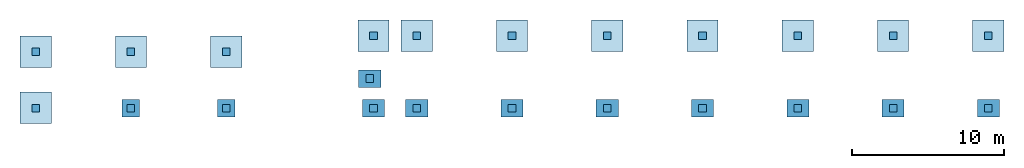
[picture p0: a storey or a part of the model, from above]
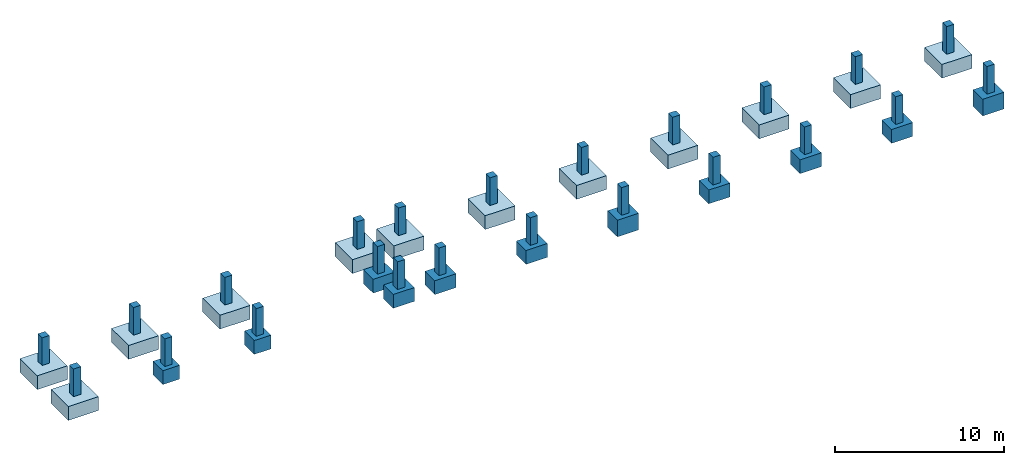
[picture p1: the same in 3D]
Properties of the parts of a building model (IFC2X3), part 1 of 25

# File
Description: ViewDefinition [CoordinationView_V2.0]
File name: SBW-VZ-II_STB_LP5_TWP.ifc
Time: 2026-07-09T14:06:45
Author: Karin Wasmer (STB)
Organization: STB Ingenieure
Written by: ODA SDAI 25.4
Authorization: wam

# IfcProject, 25693 25 - Vivantes Speiseverteilzentrum VZ II LP3
AllplanAttributes - Land: Deutschland; Leistungs-/Planungsphase: Entwurfsplanung; Bauherr: Vivantes Netzwerk für Gesundheit GmbH; Projektleiter: Hubig; Architekt: HPP Generalplanung GmbH; Statik: STB Ingenieure & Architekt PartGmbB; Projektvorlage: 0_STB Vorlage-Projekt Allplan 2022_Rev.09; Bauvorhaben: Speisenverteilzentrum VZ II; Bearbeiter: BIM Autor; Bauherr Anschrift: Aroser Allee 72-76, 13407 Berlin; Bauherr Straße: Aroser Allee 72-76; Bauherr Plz/Ort: 13407 Berlin; Architekt Anschrift: Neue Grünstraße 18, 10179 Berlin; Architekt Straße: Neue Grünstraße 18; Architekt Plz/Ort: 10179 Berlin; Bauvorhaben Straße: Seidelbastweg 145; Bauvorhaben Plz/Ort: 12357 Berlin; Projektnummer: 25693 25; Statiker Adresse: Karl-Liebknecht-Straße 11, 14482 Potsdam; Statiker Plz/Ort: 14482 Potsdam; Projektbeschreibung: Speiseverteilzentrum VZ II; Bauvorhaben Adresse: Seidelbastweg 145, 12357 Berlin; Homepage Statiker: www.stb-ingenieure.de

# IfcSite, TWP_Speiseverteilzentrum SBW VZ II
RefLatitude: 48, 8, 12, 480000; RefLongitude: 11, 34, 29, 161199
AllplanAttributes - Disziplin: Tragwerksplanung

# IfcBuildingStorey (5)
In: Speiseverteilzentrum SBW VZ II
Name | Elevation (m)
Geschossübergreifendes | -1.884
Grundleitungsebene | -1.884
EG_Technik_FFB | 0.6957
EG_Produktion_FFB | 1.7307
Wartung_FFB | 7.1307

# IfcBeam (2372)
Material: S235
AllplanAttributes - Gewerk: Stahlbauarbeiten; Material: S235; Attributset-Objekt: Beam
IFC_Pset_TWP - Material: Stahl; Kommentar: -; Phase erstellt: Neubau; statisch tragend: true
Pset_FM-Vivantes - FM_Klasse: -; FM_Bezeichnung: -; FM_AKS: -; FM_Anzahl: -; FM_Standort: -; FM_Hersteller: -; FM_Hersteller-Typ: -; FM_Seriennummer: -; FM_Baujahr: -; FM_Inbetriebnahme Datum: -; FM_Gewährleistungsende: -; FM_Gewährleistungsgeber: -; FM_Betriebsstatus: -; FM_Prüfpflicht: -; FM_Prüfintervall: -; FM_letzter Prüfungstermin: -; FM_Sammelobjekt: -; FM_rechn. Lebensdauer: -; FM_rechn. Lebensende: -; FM_technischer Zustand: -; FM_voraus. Lebensende: -; FM_Eigentümer: -; FM_Bemerkung: -; FM_Versorgungsbereich-Wirkbereich: -; FM_Zugänglichkeit: -
Name | In | Faktor | Bezeichnung = Name | Profilname | Mantelfläche/lfm | Ebene | Achsenstartpunkt (X) (m) | Achsenstartpunkt (Y) (m) | Achsenstartpunkt (Z) (m) | Achsenendpunkt (X) (m) | Achsenendpunkt (Y) (m) | Achsenendpunkt (Z) (m) | Objektdrehwinkel | Schwerpunkt X (m) | Schwerpunkt Y (m) | Allright_Bauteil_ID | Abrechnungsart | Positionsnummer | Außenbauteil | Reference | Drehwinkel = Slope (deg)
Rahmenriegel | EG_Technik_FFB | 1 | Rahmenriegel | HEA 300 | 1.763 | EG_Technik_FFB | 69.519 | 87.475 | 6.886 | 110.145 | 87.475 | 6.886 | 0 | 0.14 | 0.14 | 0103Tra0000000282 | m | AR01 | true | HA_UZV_HEA_300_STA_0,300_xxx
Rahmenriegel | EG_Technik_FFB | 1 | Rahmenriegel | HEA 300 | 1.763 | EG_Technik_FFB | 69.519 | 92.25 | 6.886 | 110.145 | 92.25 | 6.886 | 0 | 0.14 | 0.14 | 0103Tra0000001003 | m | AR01 | true | HA_UZV_HEA_300_STA_0,300_xxx
Zwischenriegel | EG_Technik_FFB | 1 | Zwischenriegel | HEA 100 | 0.582 | EG_Technik_FFB | 110 | 87.479 | 4.046 | 110 | 92.246 | 4.046 | 0 | 0.14 | 0.14 | 0103Tra0000001024 | m | AQV01.1 | true | HA_UZV_HEA_100_STA_0,100_xxx
Zwischenriegel | EG_Technik_FFB | 1 | Zwischenriegel | HEA 100 | 0.582 | EG_Technik_FFB | 103.75 | 87.479 | 4.046 | 103.75 | 92.246 | 4.046 | 0 | 0.14 | 0.14 | 0103Tra0000004011 | m | AQV01.1 | true | HA_UZV_HEA_100_STA_0,100_xxx
Zwischenriegel | EG_Technik_FFB | 1 | Zwischenriegel | HEA 100 | 0.582 | EG_Technik_FFB | 97.497 | 87.479 | 4.046 | 97.497 | 92.246 | 4.046 | 0 | 0.14 | 0.14 | 0103Tra0000004067 | m | AQV01.1 | true | HA_UZV_HEA_100_STA_0,100_xxx
Zwischenriegel | EG_Technik_FFB | 1 | Zwischenriegel | HEA 100 | 0.582 | EG_Technik_FFB | 91.247 | 87.479 | 4.046 | 91.247 | 92.246 | 4.046 | 0 | 0.14 | 0.14 | 0103Tra0000004109 | m | AQV01.1 | true | HA_UZV_HEA_100_STA_0,100_xxx
Zwischenriegel | EG_Technik_FFB | 1 | Zwischenriegel | HEA 100 | 0.582 | EG_Technik_FFB | 85.003 | 87.479 | 4.046 | 85.003 | 92.246 | 4.046 | 0 | 0.14 | 0.14 | 0103Tra0000004151 | m | AQV01.1 | true | HA_UZV_HEA_100_STA_0,100_xxx
Zwischenriegel | EG_Technik_FFB | 1 | Zwischenriegel | HEA 100 | 0.582 | EG_Technik_FFB | 78.75 | 87.479 | 4.046 | 78.75 | 92.246 | 4.046 | 0 | 0.14 | 0.14 | 0103Tra0000004193 | m | AQV01.1 | true | HA_UZV_HEA_100_STA_0,100_xxx
Zwischenriegel | EG_Technik_FFB | 1 | Zwischenriegel | HEA 100 | 0.582 | EG_Technik_FFB | 72.5 | 87.479 | 4.046 | 72.5 | 92.246 | 4.046 | 0 | 0.14 | 0.14 | 0103Tra0000004235 | m | AQV01.1 | true | HA_UZV_HEA_100_STA_0,100_xxx
Zwischenriegel | EG_Technik_FFB | 1 | Zwischenriegel | HEA 100 | 0.582 | EG_Technik_FFB | 69.664 | 87.479 | 4.046 | 69.664 | 92.246 | 4.046 | 0 | 0.14 | 0.14 | 0103Tra0000004277 | m | AQV01.2 | true | HA_UZV_HEA_100_STA_0,100_xxx
Rahmenriegel | EG_Technik_FFB | 1 | Rahmenriegel | HEA 200 | 1.167 | EG_Technik_FFB | 69.644 | 86.335 | 11.256 | 69.644 | 89.53 | 11.256 | 0 | 0.09 | 0.086 | 0103Tra0000002672 | m | AQV01.3 | true | HA_UZV_HEA_200_STA_0,200_xxx
Kragarm | EG_Technik_FFB | 1 | Kragarm | HEA 200 | 1.167 | EG_Technik_FFB | 72.5 | 86.725 | 6.936 | 72.5 | 87.295 | 6.936 | 0 | 0.09 | 0.086 | 0103Tra0000002187 | m | AT01.2 | true | HA_UZV_HEA_200_STA_0,200_xxx
Kragarm | EG_Technik_FFB | 1 | Kragarm | HEA 200 | 1.167 | EG_Technik_FFB | 78.75 | 86.725 | 6.936 | 78.75 | 87.295 | 6.936 | 0 | 0.09 | 0.086 | 0103Tra0000002197 | m | AT01.2 | true | HA_UZV_HEA_200_STA_0,200_xxx
Kragarm | EG_Technik_FFB | 1 | Kragarm | HEA 200 | 1.167 | EG_Technik_FFB | 85 | 86.725 | 6.936 | 85 | 87.295 | 6.936 | 0 | 0.09 | 0.086 | 0103Tra0000002202 | m | AT01.2 | true | HA_UZV_HEA_200_STA_0,200_xxx
Kragarm | EG_Technik_FFB | 1 | Kragarm | HEA 200 | 1.167 | EG_Technik_FFB | 91.25 | 86.725 | 6.936 | 91.25 | 87.295 | 6.936 | 0 | 0.09 | 0.086 | 0103Tra0000002207 | m | AT01.2 | true | HA_UZV_HEA_200_STA_0,200_xxx
Kragarm | EG_Technik_FFB | 1 | Kragarm | HEA 200 | 1.167 | EG_Technik_FFB | 97.5 | 86.725 | 6.936 | 97.5 | 87.295 | 6.936 | 0 | 0.09 | 0.086 | 0103Tra0000002212 | m | AT01.2 | true | HA_UZV_HEA_200_STA_0,200_xxx
Kragarm | EG_Technik_FFB | 1 | Kragarm | HEA 200 | 1.167 | EG_Technik_FFB | 103.75 | 86.725 | 6.936 | 103.75 | 87.295 | 6.936 | 0 | 0.09 | 0.086 | 0103Tra0000002217 | m | AT01.2 | true | HA_UZV_HEA_200_STA_0,200_xxx
Kragarm | EG_Technik_FFB | 1 | Kragarm | HEA 200 | 1.167 | EG_Technik_FFB | 110 | 86.725 | 6.936 | 110 | 87.295 | 6.936 | 0 | 0.09 | 0.086 | 0103Tra0000002222 | m | AT01.2 | true | HA_UZV_HEA_200_STA_0,200_xxx
Kragarm | EG_Technik_FFB | 1 | Kragarm | HEA 200 | 1.167 | EG_Technik_FFB | 69.664 | 86.725 | 6.936 | 69.664 | 87.295 | 6.936 | 0 | 0.09 | 0.086 | 0103Tra0000002227 | m | AT01.2 | true | HA_UZV_HEA_200_STA_0,200_xxx
Nebenträger | EG_Technik_FFB | 1 | Nebenträger | U 180 | 0.614476 | EG_Technik_FFB | 72.37 | 86.745 | 6.941 | 69.794 | 86.745 | 6.941 | 0 | 0.09 | 0.086 | 0103Tra0000002303 | m | AT01.1 | true | HA_UZV_U_180_STA_0,180_xxx
Nebenträger | EG_Technik_FFB | 1 | Nebenträger | U 180 | 0.614476 | EG_Technik_FFB | 78.62 | 86.745 | 6.941 | 72.63 | 86.745 | 6.941 | 0 | 0.09 | 0.086 | 0103Tra0000002313 | m | AT01.1 | true | HA_UZV_U_180_STA_0,180_xxx
Nebenträger | EG_Technik_FFB | 1 | Nebenträger | U 180 | 0.614476 | EG_Technik_FFB | 84.87 | 86.745 | 6.941 | 78.88 | 86.745 | 6.941 | 0 | 0.09 | 0.086 | 0103Tra0000002317 | m | AT01.1 | true | HA_UZV_U_180_STA_0,180_xxx
Nebenträger | EG_Technik_FFB | 1 | Nebenträger | U 180 | 0.614476 | EG_Technik_FFB | 91.12 | 86.745 | 6.941 | 85.13 | 86.745 | 6.941 | 0 | 0.09 | 0.086 | 0103Tra0000002320 | m | AT01.1 | true | HA_UZV_U_180_STA_0,180_xxx
Nebenträger | EG_Technik_FFB | 1 | Nebenträger | U 180 | 0.614476 | EG_Technik_FFB | 97.37 | 86.745 | 6.941 | 91.38 | 86.745 | 6.941 | 0 | 0.09 | 0.086 | 0103Tra0000002323 | m | AT01.1 | true | HA_UZV_U_180_STA_0,180_xxx
Nebenträger | EG_Technik_FFB | 1 | Nebenträger | U 180 | 0.614476 | EG_Technik_FFB | 103.62 | 86.745 | 6.941 | 97.63 | 86.745 | 6.941 | 0 | 0.09 | 0.086 | 0103Tra0000002326 | m | AT01.1 | true | HA_UZV_U_180_STA_0,180_xxx
Nebenträger | EG_Technik_FFB | 1 | Nebenträger | U 180 | 0.614476 | EG_Technik_FFB | 109.87 | 86.745 | 6.941 | 103.88 | 86.745 | 6.941 | 0 | 0.09 | 0.086 | 0103Tra0000002329 | m | AT01.1 | true | HA_UZV_U_180_STA_0,180_xxx
Nebenträger | EG_Technik_FFB | 1 | Nebenträger | HEA 200 | 1.167 | EG_Technik_FFB | 107.9 | 87.655 | 6.936 | 107.9 | 92.07 | 6.936 | 0 | 0.09 | 0.086 | 0103Tra0000001304 | m | AT01 | true | HA_UZV_HEA_200_STA_0,200_xxx
Nebenträger | EG_Technik_FFB | 1 | Nebenträger | HEA 200 | 1.167 | EG_Technik_FFB | 105.85 | 87.655 | 6.936 | 105.85 | 92.07 | 6.936 | 0 | 0.09 | 0.086 | 0103Tra0000000338 | m | AT01 | true | HA_UZV_HEA_200_STA_0,200_xxx
Nebenträger | EG_Technik_FFB | 1 | Nebenträger | HEA 200 | 1.167 | EG_Technik_FFB | 101.65 | 87.655 | 6.936 | 101.65 | 92.07 | 6.936 | 0 | 0.09 | 0.086 | 0103Tra0000002581 | m | AT01 | true | HA_UZV_HEA_200_STA_0,200_xxx
Nebenträger | EG_Technik_FFB | 1 | Nebenträger | HEA 200 | 1.167 | EG_Technik_FFB | 99.6 | 87.655 | 6.936 | 99.6 | 92.07 | 6.936 | 0 | 0.09 | 0.086 | 0103Tra0000002588 | m | AT01 | true | HA_UZV_HEA_200_STA_0,200_xxx
Nebenträger | EG_Technik_FFB | 1 | Nebenträger | HEA 200 | 1.167 | EG_Technik_FFB | 95.4 | 87.655 | 6.936 | 95.4 | 92.07 | 6.936 | 0 | 0.09 | 0.086 | 0103Tra0000002600 | m | AT01 | true | HA_UZV_HEA_200_STA_0,200_xxx
Nebenträger | EG_Technik_FFB | 1 | Nebenträger | HEA 200 | 1.167 | EG_Technik_FFB | 93.35 | 87.655 | 6.936 | 93.35 | 92.07 | 6.936 | 0 | 0.09 | 0.086 | 0103Tra0000002602 | m | AT01 | true | HA_UZV_HEA_200_STA_0,200_xxx
Nebenträger | EG_Technik_FFB | 1 | Nebenträger | HEA 200 | 1.167 | EG_Technik_FFB | 89.15 | 87.655 | 6.936 | 89.15 | 92.07 | 6.936 | 0 | 0.09 | 0.086 | 0103Tra0000002614 | m | AT01 | true | HA_UZV_HEA_200_STA_0,200_xxx
Nebenträger | EG_Technik_FFB | 1 | Nebenträger | HEA 200 | 1.167 | EG_Technik_FFB | 87.1 | 87.655 | 6.936 | 87.1 | 92.07 | 6.936 | 0 | 0.09 | 0.086 | 0103Tra0000002616 | m | AT01 | true | HA_UZV_HEA_200_STA_0,200_xxx
Nebenträger | EG_Technik_FFB | 1 | Nebenträger | HEA 200 | 1.167 | EG_Technik_FFB | 82.9 | 87.655 | 6.936 | 82.9 | 92.07 | 6.936 | 0 | 0.09 | 0.086 | 0103Tra0000002628 | m | AT01 | true | HA_UZV_HEA_200_STA_0,200_xxx
Nebenträger | EG_Technik_FFB | 1 | Nebenträger | HEA 200 | 1.167 | EG_Technik_FFB | 80.85 | 87.655 | 6.936 | 80.85 | 92.07 | 6.936 | 0 | 0.09 | 0.086 | 0103Tra0000002630 | m | AT01 | true | HA_UZV_HEA_200_STA_0,200_xxx
Nebenträger | EG_Technik_FFB | 1 | Nebenträger | HEA 200 | 1.167 | EG_Technik_FFB | 76.65 | 87.655 | 6.936 | 76.65 | 92.07 | 6.936 | 0 | 0.09 | 0.086 | 0103Tra0000002642 | m | AT01 | true | HA_UZV_HEA_200_STA_0,200_xxx
Nebenträger | EG_Technik_FFB | 1 | Nebenträger | HEA 200 | 1.167 | EG_Technik_FFB | 74.6 | 87.655 | 6.936 | 74.6 | 92.07 | 6.936 | 0 | 0.09 | 0.086 | 0103Tra0000002644 | m | AT01 | true | HA_UZV_HEA_200_STA_0,200_xxx
Nebenträger | EG_Technik_FFB | 1 | Nebenträger | HEA 200 | 1.167 | EG_Technik_FFB | 71.082 | 87.655 | 6.936 | 71.082 | 92.07 | 6.936 | 0 | 0.09 | 0.086 | 0103Tra0000002651 | m | AT01 | true | HA_UZV_HEA_200_STA_0,200_xxx
Nebenträger | EG_Technik_FFB | 1 | Nebenträger | HEA 200 | 1.167 | EG_Technik_FFB | 55.85 | 87.655 | 4.231 | 55.85 | 91.02 | 4.231 | 0 | 0.09 | 0.086 | 0103Tra0000001654 | m | AT02 | true | HA_UZV_HEA_200_STA_0,200_xxx
Nebenträger | EG_Technik_FFB | 1 | Nebenträger | HEA 200 | 1.167 | EG_Technik_FFB | 55.85 | 87.655 | 8.291 | 55.85 | 91.02 | 8.291 | 0 | 0.09 | 0.086 | 0103Tra0000001886 | m | AT02 | true | HA_UZV_HEA_200_STA_0,200_xxx
Nebenträger | EG_Technik_FFB | 1 | Nebenträger | HEA 200 | 1.167 | EG_Technik_FFB | 57.9 | 87.655 | 4.231 | 57.9 | 91.02 | 4.231 | 0 | 0.09 | 0.086 | 0103Tra0000002025 | m | AT02 | true | HA_UZV_HEA_200_STA_0,200_xxx
Nebenträger | EG_Technik_FFB | 1 | Nebenträger | HEA 200 | 1.167 | EG_Technik_FFB | 57.9 | 87.655 | 8.291 | 57.9 | 91.02 | 8.291 | 0 | 0.09 | 0.086 | 0103Tra0000002027 | m | AT02 | true | HA_UZV_HEA_200_STA_0,200_xxx
Nebenträger | EG_Technik_FFB | 1 | Nebenträger | HEA 200 | 1.167 | EG_Technik_FFB | 49.6 | 87.655 | 4.231 | 49.6 | 91.02 | 4.231 | 0 | 0.09 | 0.086 | 0103Tra0000002095 | m | AT02 | true | HA_UZV_HEA_200_STA_0,200_xxx
Nebenträger | EG_Technik_FFB | 1 | Nebenträger | HEA 200 | 1.167 | EG_Technik_FFB | 49.6 | 87.655 | 8.291 | 49.6 | 91.02 | 8.291 | 0 | 0.09 | 0.086 | 0103Tra0000002097 | m | AT02 | true | HA_UZV_HEA_200_STA_0,200_xxx
Nebenträger | EG_Technik_FFB | 1 | Nebenträger | HEA 200 | 1.167 | EG_Technik_FFB | 51.65 | 87.655 | 4.231 | 51.65 | 91.02 | 4.231 | 0 | 0.09 | 0.086 | 0103Tra0000002109 | m | AT02 | true | HA_UZV_HEA_200_STA_0,200_xxx
Nebenträger | EG_Technik_FFB | 1 | Nebenträger | HEA 200 | 1.167 | EG_Technik_FFB | 51.65 | 87.655 | 8.291 | 51.65 | 91.02 | 8.291 | 0 | 0.09 | 0.086 | 0103Tra0000002111 | m | AT02 | true | HA_UZV_HEA_200_STA_0,200_xxx
Kragarm | EG_Technik_FFB | 1 | Kragarm | HEA 200 | 1.167 | EG_Technik_FFB | 60 | 86.725 | 4.231 | 60 | 87.295 | 4.231 | 0 | 0.09 | 0.086 | 0103Tra0000002240 | m | AT01.2 | true | HA_UZV_HEA_200_STA_0,200_xxx
Kragarm | EG_Technik_FFB | 1 | Kragarm | HEA 200 | 1.167 | EG_Technik_FFB | 60 | 86.725 | 8.291 | 60 | 87.295 | 8.291 | 0 | 0.09 | 0.086 | 0103Tra0000002242 | m | AT01.2 | true | HA_UZV_HEA_200_STA_0,200_xxx
Kragarm | EG_Technik_FFB | 1 | Kragarm | HEA 200 | 1.167 | EG_Technik_FFB | 53.75 | 86.725 | 4.231 | 53.75 | 87.295 | 4.231 | 0 | 0.09 | 0.086 | 0103Tra0000002252 | m | AT01.2 | true | HA_UZV_HEA_200_STA_0,200_xxx
Kragarm | EG_Technik_FFB | 1 | Kragarm | HEA 200 | 1.167 | EG_Technik_FFB | 53.75 | 86.725 | 8.291 | 53.75 | 87.295 | 8.291 | 0 | 0.09 | 0.086 | 0103Tra0000002254 | m | AT01.2 | true | HA_UZV_HEA_200_STA_0,200_xxx
Kragarm | EG_Technik_FFB | 1 | Kragarm | HEA 200 | 1.167 | EG_Technik_FFB | 47.5 | 86.725 | 4.231 | 47.5 | 87.295 | 4.231 | 0 | 0.09 | 0.086 | 0103Tra0000002262 | m | AT01.2 | true | HA_UZV_HEA_200_STA_0,200_xxx
Kragarm | EG_Technik_FFB | 1 | Kragarm | HEA 200 | 1.167 | EG_Technik_FFB | 47.5 | 86.725 | 8.291 | 47.5 | 87.295 | 8.291 | 0 | 0.09 | 0.086 | 0103Tra0000002264 | m | AT01.2 | true | HA_UZV_HEA_200_STA_0,200_xxx
Nebenträger | EG_Technik_FFB | 1 | Nebenträger | U 180 | 0.614476 | EG_Technik_FFB | 53.62 | 86.745 | 8.296 | 47.63 | 86.745 | 8.296 | 0 | 0.09 | 0.086 | 0103Tra0000002335 | m | AT01.1 | true | HA_UZV_U_180_STA_0,180_xxx
Nebenträger | EG_Technik_FFB | 1 | Nebenträger | U 180 | 0.614476 | EG_Technik_FFB | 53.62 | 86.745 | 4.236 | 47.63 | 86.745 | 4.236 | 0 | 0.09 | 0.086 | 0103Tra0000002337 | m | AT01.1 | true | HA_UZV_U_180_STA_0,180_xxx
Nebenträger | EG_Technik_FFB | 1 | Nebenträger | U 180 | 0.614476 | EG_Technik_FFB | 59.87 | 86.745 | 8.296 | 53.88 | 86.745 | 8.296 | 0 | 0.09 | 0.086 | 0103Tra0000002351 | m | AT01.1 | true | HA_UZV_U_180_STA_0,180_xxx
Nebenträger | EG_Technik_FFB | 1 | Nebenträger | U 180 | 0.614476 | EG_Technik_FFB | 59.87 | 86.745 | 4.236 | 53.88 | 86.745 | 4.236 | 0 | 0.09 | 0.086 | 0103Tra0000002353 | m | AT01.1 | true | HA_UZV_U_180_STA_0,180_xxx
Rahmenriegel | EG_Technik_FFB | 1 | Rahmenriegel | HEA 300 | 1.763 | EG_Technik_FFB | 45.855 | 91.2 | 8.241 | 60.695 | 91.2 | 8.241 | 0 | 0.14 | 0.14 | 0103Tra0000001782 | m | AR02 | true | HA_UZV_HEA_300_STA_0,300_xxx
Rahmenriegel | EG_Technik_FFB | 1 | Rahmenriegel | HEA 300 | 1.763 | EG_Technik_FFB | 45.855 | 87.475 | 8.241 | 60.695 | 87.475 | 8.241 | 0 | 0.14 | 0.14 | 0103Tra0000001779 | m | AR02 | true | HA_UZV_HEA_300_STA_0,300_xxx
Rahmenriegel | EG_Technik_FFB | 1 | Rahmenriegel | HEA 300 | 1.763 | EG_Technik_FFB | 45.855 | 87.475 | 4.181 | 60.695 | 87.475 | 4.181 | 0 | 0.14 | 0.14 | 0103Tra0000001546 | m | AR02 | true | HA_UZV_HEA_300_STA_0,300_xxx
Rahmenriegel | EG_Technik_FFB | 1 | Rahmenriegel | HEA 300 | 1.763 | EG_Technik_FFB | 45.855 | 91.2 | 4.181 | 60.695 | 91.2 | 4.181 | 0 | 0.14 | 0.14 | 0103Tra0000001636 | m | AR02 | true | HA_UZV_HEA_300_STA_0,300_xxx
Rahmenriegel | EG_Technik_FFB | 1 | Rahmenriegel | HEA 200 | 1.167 | EG_Technik_FFB | 60 | 87.655 | 8.291 | 60 | 91.02 | 8.291 | 0 | 0.14 | 0.14 | 0103Tra0000001776 | m | AQV02.2 | true | HA_UZV_HEA_200_STA_0,200_xxx
Rahmenriegel | EG_Technik_FFB | 1 | Rahmenriegel | HEA 200 | 1.167 | EG_Technik_FFB | 60 | 87.655 | 4.181 | 60 | 91.02 | 4.181 | 0 | 0.14 | 0.14 | 0103Tra0000001632 | m | AQV02.1 | true | HA_UZV_HEA_200_STA_0,200_xxx
Rahmenriegel | EG_Technik_FFB | 1 | Rahmenriegel | HEA 200 | 1.167 | EG_Technik_FFB | 53.75 | 87.655 | 8.291 | 53.75 | 91.02 | 8.291 | 0 | 0.14 | 0.14 | 0103Tra0000004347 | m | AQV02.2 | true | HA_UZV_HEA_200_STA_0,200_xxx
Rahmenriegel | EG_Technik_FFB | 1 | Rahmenriegel | HEA 200 | 1.167 | EG_Technik_FFB | 53.75 | 87.655 | 4.181 | 53.75 | 91.02 | 4.181 | 0 | 0.14 | 0.14 | 0103Tra0000004361 | m | AQV02.1 | true | HA_UZV_HEA_200_STA_0,200_xxx
Rahmenriegel | EG_Technik_FFB | 1 | Rahmenriegel | HEA 200 | 1.167 | EG_Technik_FFB | 47.5 | 87.655 | 8.291 | 47.5 | 91.02 | 8.291 | 0 | 0.14 | 0.14 | 0103Tra0000004449 | m | AQV02.2 | true | HA_UZV_HEA_200_STA_0,200_xxx
Rahmenriegel | EG_Technik_FFB | 1 | Rahmenriegel | HEA 200 | 1.167 | EG_Technik_FFB | 47.5 | 87.655 | 4.181 | 47.5 | 91.02 | 4.181 | 0 | 0.14 | 0.14 | 0103Tra0000004451 | m | AQV02.1 | true | HA_UZV_HEA_200_STA_0,200_xxx
Nebenträger | EG_Technik_FFB | 1 | Nebenträger | HEA 200 | 1.167 | EG_Technik_FFB | 60.595 | 87.655 | 4.231 | 60.595 | 91.02 | 4.231 | 0 | 0.09 | 0.086 | 0103Tra0000004485 | m | AT02 | true | HA_UZV_HEA_200_STA_0,200_xxx
Nebenträger | EG_Technik_FFB | 1 | Nebenträger | HEA 200 | 1.167 | EG_Technik_FFB | 60.595 | 87.655 | 8.291 | 60.595 | 91.02 | 8.291 | 0 | 0.09 | 0.086 | 0103Tra0000004487 | m | AT02 | true | HA_UZV_HEA_200_STA_0,200_xxx
Kragarm | EG_Technik_FFB | 1 | Kragarm | HEA 200 | 1.167 | EG_Technik_FFB | 60.595 | 86.725 | 4.231 | 60.595 | 87.295 | 4.231 | 0 | 0.09 | 0.086 | 0103Tra0000002282 | m | AT01.2 | true | HA_UZV_HEA_200_STA_0,200_xxx
Kragarm | EG_Technik_FFB | 1 | Kragarm | HEA 200 | 1.167 | EG_Technik_FFB | 60.595 | 86.725 | 8.291 | 60.595 | 87.295 | 8.291 | 0 | 0.09 | 0.086 | 0103Tra0000002284 | m | AT01.2 | true | HA_UZV_HEA_200_STA_0,200_xxx
Nebenträger | EG_Technik_FFB | 1 | Nebenträger | HEA 200 | 1.167 | EG_Technik_FFB | 45.955 | 87.655 | 4.231 | 45.955 | 91.02 | 4.231 | 0 | 0.09 | 0.086 | 0103Tra0000004465 | m | AT02 | true | HA_UZV_HEA_200_STA_0,200_xxx
Nebenträger | EG_Technik_FFB | 1 | Nebenträger | HEA 200 | 1.167 | EG_Technik_FFB | 45.955 | 87.655 | 8.291 | 45.955 | 91.02 | 8.291 | 0 | 0.09 | 0.086 | 0103Tra0000004466 | m | AT02 | true | HA_UZV_HEA_200_STA_0,200_xxx
Kragarm | EG_Technik_FFB | 1 | Kragarm | HEA 200 | 1.167 | EG_Technik_FFB | 45.955 | 86.725 | 4.231 | 45.955 | 87.295 | 4.231 | 0 | 0.09 | 0.086 | 0103Tra0000002272 | m | AT01.2 | true | HA_UZV_HEA_200_STA_0,200_xxx
Kragarm | EG_Technik_FFB | 1 | Kragarm | HEA 200 | 1.167 | EG_Technik_FFB | 45.955 | 86.725 | 8.291 | 45.955 | 87.295 | 8.291 | 0 | 0.09 | 0.086 | 0103Tra0000002274 | m | AT01.2 | true | HA_UZV_HEA_200_STA_0,200_xxx
Nebenträger | EG_Technik_FFB | 1 | Nebenträger | U 180 | 0.614476 | EG_Technik_FFB | 47.37 | 86.745 | 8.296 | 46.085 | 86.745 | 8.296 | 0 | 0.09 | 0.086 | 0103Tra0000002290 | m | AT01.1 | true | HA_UZV_U_180_STA_0,180_xxx
Nebenträger | EG_Technik_FFB | 1 | Nebenträger | U 180 | 0.614476 | EG_Technik_FFB | 47.37 | 86.745 | 4.236 | 46.085 | 86.745 | 4.236 | 0 | 0.09 | 0.086 | 0103Tra0000002300 | m | AT01.1 | true | HA_UZV_U_180_STA_0,180_xxx
Nebenträger | EG_Technik_FFB | 1 | Nebenträger | U 180 | 0.614476 | EG_Technik_FFB | 60.465 | 86.745 | 8.296 | 60.13 | 86.745 | 8.296 | 0 | 0.09 | 0.086 | 0103Tra0000002341 | m | AT01.1 | true | HA_UZV_U_180_STA_0,180_xxx
Nebenträger | EG_Technik_FFB | 1 | Nebenträger | U 180 | 0.614476 | EG_Technik_FFB | 60.465 | 86.745 | 4.236 | 60.13 | 86.745 | 4.236 | 0 | 0.09 | 0.086 | 0103Tra0000002343 | m | AT01.1 | true | HA_UZV_U_180_STA_0,180_xxx
Rahmenriegel | EG_Technik_FFB | 1 | Rahmenriegel | HEA 200 | 1.167 | EG_Technik_FFB | 110 | 87.655 | 6.936 | 110 | 92.07 | 6.936 | 0 | 0.14 | 0.14 | 0103Tra0000001006 | m | AQV01.1 | true | HA_UZV_HEA_200_STA_0,200_xxx
Rahmenriegel | EG_Technik_FFB | 1 | Rahmenriegel | HEA 200 | 1.167 | EG_Technik_FFB | 103.75 | 87.655 | 6.936 | 103.75 | 92.07 | 6.936 | 0 | 0.14 | 0.14 | 0103Tra0000004012 | m | AQV01.1 | true | HA_UZV_HEA_200_STA_0,200_xxx
Rahmenriegel | EG_Technik_FFB | 1 | Rahmenriegel | HEA 200 | 1.167 | EG_Technik_FFB | 97.497 | 87.655 | 6.936 | 97.497 | 92.07 | 6.936 | 0 | 0.14 | 0.14 | 0103Tra0000004069 | m | AQV01.1 | true | HA_UZV_HEA_200_STA_0,200_xxx
Rahmenriegel | EG_Technik_FFB | 1 | Rahmenriegel | HEA 200 | 1.167 | EG_Technik_FFB | 91.247 | 87.655 | 6.936 | 91.247 | 92.07 | 6.936 | 0 | 0.14 | 0.14 | 0103Tra0000004111 | m | AQV01.1 | true | HA_UZV_HEA_200_STA_0,200_xxx
Rahmenriegel | EG_Technik_FFB | 1 | Rahmenriegel | HEA 200 | 1.167 | EG_Technik_FFB | 85.003 | 87.655 | 6.936 | 85.003 | 92.07 | 6.936 | 0 | 0.14 | 0.14 | 0103Tra0000004153 | m | AQV01.1 | true | HA_UZV_HEA_200_STA_0,200_xxx
Rahmenriegel | EG_Technik_FFB | 1 | Rahmenriegel | HEA 200 | 1.167 | EG_Technik_FFB | 78.75 | 87.655 | 6.936 | 78.75 | 92.07 | 6.936 | 0 | 0.14 | 0.14 | 0103Tra0000004195 | m | AQV01.1 | true | HA_UZV_HEA_200_STA_0,200_xxx
Rahmenriegel | EG_Technik_FFB | 1 | Rahmenriegel | HEA 200 | 1.167 | EG_Technik_FFB | 72.5 | 87.655 | 6.936 | 72.5 | 92.07 | 6.936 | 0 | 0.14 | 0.14 | 0103Tra0000004237 | m | AQV01.1 | true | HA_UZV_HEA_200_STA_0,200_xxx
Rahmenriegel | EG_Technik_FFB | 1 | Rahmenriegel | HEA 200 | 1.167 | EG_Technik_FFB | 69.664 | 87.655 | 6.936 | 69.664 | 92.07 | 6.936 | 0 | 0.14 | 0.14 | 0103Tra0000004279 | m | AQV01.2 | true | HA_UZV_HEA_200_STA_0,200_xxx
Nebenträger | EG_Technik_FFB | 1 | Nebenträger | U 120 | 0.438627 | Wartung_FFB | 60.645 | 86.276 | 10.807 | 62.405 | 86.276 | 10.807 | 90 | 0.06 | 0.057 | 0106Tra0000000654 | m | T110 | false | HI_UZV_HEA_STA_0,120_xxx | 0 | AllplanAttributes - Schema: B$; Startnummer: 1
Stahlträger | EG_Produktion_FFB | 1 | Stahlträger | HEM 360 | 1.98 | EG_Produktion_FFB | 9.964 | 30.535 | 6.543 | 9.964 | 10.658 | 6.543 | 0 | 0.15 | 0.32 | 0112Tra0000000523 | m | RA003 | false | HI_UZT_HEM_STA_0,360_xxx | 0
Fachwerkstütze | EG_Produktion_FFB | 1 | Fachwerkstütze | HEA 100 | 0.582 | EG_Produktion_FFB | 9.85 | 30.485 | 0.291 | 10.75 | 30.485 | 0.291 | 0 | 0.15 | 0.32 | 0112Tra0000002692 | m | RA004 | false | HI_UZT_HEA_STA_0,100_xxx | 0
Fachwerkstütze | EG_Produktion_FFB | 1 | Fachwerkstütze | HEA 100 | 0.582 | EG_Produktion_FFB | 9.85 | 10.708 | 0.291 | 10.75 | 10.708 | 0.291 | 0 | 0.15 | 0.32 | 0112Tra0000002805 | m | RA004 | false | HI_UZT_HEA_STA_0,100_xxx | 0
Fachwerkstütze | EG_Produktion_FFB | 1 | Fachwerkstütze | L 50 x 5 | 0.2 | EG_Produktion_FFB | 9.858 | 30.496 | 0.331 | 10.758 | 30.496 | 1.235 | 270 | 0.15 | 0.32 | 0112Tra0000002780 | m | RA004 | false | HI_UZT_L_STA_0,050_xxx | 0
Fachwerkstütze | EG_Produktion_FFB | 1 | Fachwerkstütze | L 50 x 5 | 0.2 | EG_Produktion_FFB | 9.858 | 10.719 | 0.331 | 10.758 | 10.719 | 1.235 | 270 | 0.15 | 0.32 | 0112Tra0000002820 | m | RA004 | false | HI_UZT_L_STA_0,050_xxx | 0
Fachwerkstütze | EG_Produktion_FFB | 1 | Fachwerkstütze | HEA 100 | 0.582 | EG_Produktion_FFB | 9.85 | 30.485 | 1.291 | 10.75 | 30.485 | 1.291 | 0 | 0.15 | 0.32 | 0112Tra0000002701 | m | RA004 | false | HI_UZT_HEA_STA_0,100_xxx | 0
Fachwerkstütze | EG_Produktion_FFB | 1 | Fachwerkstütze | HEA 100 | 0.582 | EG_Produktion_FFB | 9.85 | 10.708 | 1.291 | 10.75 | 10.708 | 1.291 | 0 | 0.15 | 0.32 | 0112Tra0000002803 | m | RA004 | false | HI_UZT_HEA_STA_0,100_xxx | 0
Fachwerkstütze | EG_Produktion_FFB | 1 | Fachwerkstütze | L 50 x 5 | 0.2 | EG_Produktion_FFB | 9.858 | 30.496 | 1.331 | 10.758 | 30.496 | 2.235 | 270 | 0.15 | 0.32 | 0112Tra0000002768 | m | RA004 | false | HI_UZT_L_STA_0,050_xxx | 0
Fachwerkstütze | EG_Produktion_FFB | 1 | Fachwerkstütze | L 50 x 5 | 0.2 | EG_Produktion_FFB | 9.858 | 10.719 | 1.331 | 10.758 | 10.719 | 2.235 | 270 | 0.15 | 0.32 | 0112Tra0000002818 | m | RA004 | false | HI_UZT_L_STA_0,050_xxx | 0
Fachwerkstütze | EG_Produktion_FFB | 1 | Fachwerkstütze | HEA 100 | 0.582 | EG_Produktion_FFB | 9.85 | 30.485 | 2.291 | 10.75 | 30.485 | 2.291 | 0 | 0.15 | 0.32 | 0112Tra0000002689 | m | RA004 | false | HI_UZT_HEA_STA_0,100_xxx | 0
Fachwerkstütze | EG_Produktion_FFB | 1 | Fachwerkstütze | HEA 100 | 0.582 | EG_Produktion_FFB | 9.85 | 10.708 | 2.291 | 10.75 | 10.708 | 2.291 | 0 | 0.15 | 0.32 | 0112Tra0000002801 | m | RA004 | false | HI_UZT_HEA_STA_0,100_xxx | 0
Fachwerkstütze | EG_Produktion_FFB | 1 | Fachwerkstütze | L 50 x 5 | 0.2 | EG_Produktion_FFB | 9.858 | 30.496 | 2.331 | 10.758 | 30.496 | 3.235 | 270 | 0.15 | 0.32 | 0112Tra0000002765 | m | RA004 | false | HI_UZT_L_STA_0,050_xxx | 0
Fachwerkstütze | EG_Produktion_FFB | 1 | Fachwerkstütze | L 50 x 5 | 0.2 | EG_Produktion_FFB | 9.858 | 10.719 | 2.331 | 10.758 | 10.719 | 3.235 | 270 | 0.15 | 0.32 | 0112Tra0000002816 | m | RA004 | false | HI_UZT_L_STA_0,050_xxx | 0
Fachwerkstütze | EG_Produktion_FFB | 1 | Fachwerkstütze | HEA 100 | 0.582 | EG_Produktion_FFB | 9.85 | 30.485 | 3.291 | 10.75 | 30.485 | 3.291 | 0 | 0.15 | 0.32 | 0112Tra0000002686 | m | RA004 | false | HI_UZT_HEA_STA_0,100_xxx | 0
Fachwerkstütze | EG_Produktion_FFB | 1 | Fachwerkstütze | HEA 100 | 0.582 | EG_Produktion_FFB | 9.85 | 10.708 | 3.291 | 10.75 | 10.708 | 3.291 | 0 | 0.15 | 0.32 | 0112Tra0000002799 | m | RA004 | false | HI_UZT_HEA_STA_0,100_xxx | 0
Fachwerkstütze | EG_Produktion_FFB | 1 | Fachwerkstütze | L 50 x 5 | 0.2 | EG_Produktion_FFB | 9.858 | 30.496 | 3.331 | 10.758 | 30.496 | 4.235 | 270 | 0.15 | 0.32 | 0112Tra0000002761 | m | RA004 | false | HI_UZT_L_STA_0,050_xxx | 0
Fachwerkstütze | EG_Produktion_FFB | 1 | Fachwerkstütze | L 50 x 5 | 0.2 | EG_Produktion_FFB | 9.858 | 10.719 | 3.331 | 10.758 | 10.719 | 4.235 | 270 | 0.15 | 0.32 | 0112Tra0000002814 | m | RA004 | false | HI_UZT_L_STA_0,050_xxx | 0
Fachwerkstütze | EG_Produktion_FFB | 1 | Fachwerkstütze | HEA 100 | 0.582 | EG_Produktion_FFB | 9.85 | 30.485 | 4.291 | 10.75 | 30.485 | 4.291 | 0 | 0.15 | 0.32 | 0112Tra0000002682 | m | RA004 | false | HI_UZT_HEA_STA_0,100_xxx | 0
Fachwerkstütze | EG_Produktion_FFB | 1 | Fachwerkstütze | HEA 100 | 0.582 | EG_Produktion_FFB | 9.85 | 10.708 | 4.291 | 10.75 | 10.708 | 4.291 | 0 | 0.15 | 0.32 | 0112Tra0000002797 | m | RA004 | false | HI_UZT_HEA_STA_0,100_xxx | 0
Fachwerkstütze | EG_Produktion_FFB | 1 | Fachwerkstütze | L 50 x 5 | 0.2 | EG_Produktion_FFB | 9.858 | 30.496 | 4.331 | 10.758 | 30.496 | 5.235 | 270 | 0.15 | 0.32 | 0112Tra0000002749 | m | RA004 | false | HI_UZT_L_STA_0,050_xxx | 0
Fachwerkstütze | EG_Produktion_FFB | 1 | Fachwerkstütze | L 50 x 5 | 0.2 | EG_Produktion_FFB | 9.858 | 10.719 | 4.331 | 10.758 | 10.719 | 5.235 | 270 | 0.15 | 0.32 | 0112Tra0000002812 | m | RA004 | false | HI_UZT_L_STA_0,050_xxx | 0
Fachwerkstütze | EG_Produktion_FFB | 1 | Fachwerkstütze | HEA 100 | 0.582 | EG_Produktion_FFB | 9.85 | 30.485 | 5.291 | 10.75 | 30.485 | 5.291 | 0 | 0.15 | 0.32 | 0112Tra0000002677 | m | RA004 | false | HI_UZT_HEA_STA_0,100_xxx | 0
Fachwerkstütze | EG_Produktion_FFB | 1 | Fachwerkstütze | HEA 100 | 0.582 | EG_Produktion_FFB | 9.85 | 10.708 | 5.291 | 10.75 | 10.708 | 5.291 | 0 | 0.15 | 0.32 | 0112Tra0000002795 | m | RA004 | false | HI_UZT_HEA_STA_0,100_xxx | 0
Fachwerkstütze | EG_Produktion_FFB | 1 | Fachwerkstütze | U 100 | 0.381241 | EG_Produktion_FFB | 9.838 | 30.485 | 6.328 | 10.788 | 30.485 | 5.328 | 90 | 0.15 | 0.32 | 0112Tra0000002734 | m | RA004 | false | HI_UZT_U_STA_0,100_xxx | 0
Fachwerkstütze | EG_Produktion_FFB | 1 | Fachwerkstütze | U 100 | 0.381241 | EG_Produktion_FFB | 9.838 | 10.708 | 6.328 | 10.788 | 10.708 | 5.328 | 90 | 0.15 | 0.32 | 0112Tra0000002788 | m | RA004 | false | HI_UZT_U_STA_0,100_xxx | 0
Obergurt | EG_Produktion_FFB | 1 | Obergurt | HEA 140 | 0.815 | EG_Produktion_FFB | 9.643 | 36.019 | 8.817 | 9.643 | 30.808 | 8.817 | 0 | 0.15 | 0.32 | 0112Tra0000003039 | m | FW001 | false | HI_UZT_HEA_STA_0,140_xxx | 0
Obergurt | EG_Produktion_FFB | 1 | Obergurt | HEA 140 | 0.815 | EG_Produktion_FFB | 9.643 | 41.194 | 8.817 | 9.643 | 36.031 | 8.817 | 0 | 0.15 | 0.32 | 0112Tra0000003027 | m | FW001 | false | HI_UZT_HEA_STA_0,140_xxx | 0
Obergurt | EG_Produktion_FFB | 1 | Obergurt | HEA 140 | 0.815 | EG_Produktion_FFB | 9.643 | 46.369 | 8.817 | 9.643 | 41.206 | 8.817 | 0 | 0.15 | 0.32 | 0112Tra0000003037 | m | FW001 | false | HI_UZT_HEA_STA_0,140_xxx | 0
Obergurt | EG_Produktion_FFB | 1 | Obergurt | HEA 140 | 0.815 | EG_Produktion_FFB | 9.643 | 51.597 | 8.817 | 9.643 | 46.381 | 8.817 | 0 | 0.15 | 0.32 | 0112Tra0000003043 | m | FW001 | false | HI_UZT_HEA_STA_0,140_xxx | 0
Obergurt | EG_Produktion_FFB | 1 | Obergurt | HEA 140 | 0.815 | EG_Produktion_FFB | 9.643 | 55.894 | 8.817 | 9.643 | 51.608 | 8.817 | 0 | 0.15 | 0.32 | 0112Tra0000003046 | m | FW001 | false | HI_UZT_HEA_STA_0,140_xxx | 0
Obergurt | EG_Produktion_FFB | 1 | Obergurt | HEA 140 | 0.815 | EG_Produktion_FFB | 9.643 | 60.994 | 8.817 | 9.643 | 55.906 | 8.817 | 0 | 0.15 | 0.32 | 0112Tra0000003052 | m | FW001 | false | HI_UZT_HEA_STA_0,140_xxx | 0
Obergurt | EG_Produktion_FFB | 1 | Obergurt | HEA 140 | 0.815 | EG_Produktion_FFB | 9.643 | 66.094 | 8.817 | 9.643 | 61.006 | 8.817 | 0 | 0.15 | 0.32 | 0112Tra0000003055 | m | FW001 | false | HI_UZT_HEA_STA_0,140_xxx | 0
Obergurt | EG_Produktion_FFB | 1 | Obergurt | HEA 140 | 0.815 | EG_Produktion_FFB | 9.643 | 70.397 | 8.817 | 9.643 | 66.106 | 8.817 | 0 | 0.15 | 0.32 | 0112Tra0000003058 | m | FW001 | false | HI_UZT_HEA_STA_0,140_xxx | 0
Diagonale | EG_Produktion_FFB | 1 | Diagonale | L 50 x 6 | 0.2 | EG_Produktion_FFB | 9.63 | 66.115 | 6.39 | 9.63 | 70.376 | 8.74 | 270 | 0.15 | 0.32 | 0112Tra0000003104 | m | FW001 | false | HI_UZT_L_STA_0,050_xxx | 0 | AllplanAttributes - Schema: B$; Startnummer: 1
Diagonale | EG_Produktion_FFB | 1 | Diagonale | L 50 x 6 | 0.2 | EG_Produktion_FFB | 9.63 | 61.019 | 6.39 | 9.63 | 66.078 | 8.74 | 270 | 0.15 | 0.32 | 0112Tra0000003096 | m | FW001 | false | HI_UZT_L_STA_0,050_xxx | 0 | AllplanAttributes - Schema: B$; Startnummer: 1
Diagonale | EG_Produktion_FFB | 1 | Diagonale | L 50 x 6 | 0.2 | EG_Produktion_FFB | 9.63 | 60.981 | 6.39 | 9.63 | 55.922 | 8.74 | 90 | 0.15 | 0.32 | 0112Tra0000003099 | m | FW001 | false | HI_UZT_L_STA_0,050_xxx | 0 | AllplanAttributes - Schema: B$; Startnummer: 1
Diagonale | EG_Produktion_FFB | 1 | Diagonale | L 50 x 6 | 0.2 | EG_Produktion_FFB | 9.63 | 55.885 | 6.39 | 9.63 | 51.628 | 8.74 | 90 | 0.15 | 0.32 | 0112Tra0000003107 | m | FW001 | false | HI_UZT_L_STA_0,050_xxx | 0 | AllplanAttributes - Schema: B$; Startnummer: 1
Diagonale | EG_Produktion_FFB | 1 | Diagonale | L 50 x 6 | 0.2 | EG_Produktion_FFB | 9.63 | 46.391 | 6.39 | 9.63 | 51.53 | 8.74 | 270 | 0.15 | 0.32 | 0112Tra0000003090 | m | FW001 | false | HI_UZT_L_STA_0,050_xxx | 0 | AllplanAttributes - Schema: B$; Startnummer: 1
Diagonale | EG_Produktion_FFB | 1 | Diagonale | L 50 x 6 | 0.2 | EG_Produktion_FFB | 9.63 | 41.219 | 6.39 | 9.63 | 46.358 | 8.74 | 270 | 0.15 | 0.32 | 0112Tra0000003082 | m | FW001 | false | HI_UZT_L_STA_0,050_xxx | 0 | AllplanAttributes - Schema: B$; Startnummer: 1
Diagonale | EG_Produktion_FFB | 1 | Diagonale | L 50 x 6 | 0.2 | EG_Produktion_FFB | 9.63 | 41.181 | 6.39 | 9.63 | 36.042 | 8.74 | 90 | 0.15 | 0.32 | 0112Tra0000003064 | m | FW001 | false | HI_UZT_L_STA_0,050_xxx | 0 | AllplanAttributes - Schema: B$; Startnummer: 1
Diagonale | EG_Produktion_FFB | 1 | Diagonale | L 50 x 6 | 0.2 | EG_Produktion_FFB | 9.63 | 36.009 | 6.39 | 9.63 | 30.87 | 8.74 | 90 | 0.15 | 0.32 | 0112Tra0000003093 | m | FW001 | false | HI_UZT_L_STA_0,050_xxx | 0 | AllplanAttributes - Schema: B$; Startnummer: 1
Stahlträger | Wartung_FFB | 1 | Stahlträger | HEA 500 | 2.156 | Wartung_FFB | 10.55 | 26.902 | 6.696 | 10.55 | 13.888 | 6.696 | 0 | 0.15 | 0.32 | 0121Tra0000013394 | m | T101a | false | HI_UZT_HEA_STA_0,500_xxx | 0
Stahlträger | Wartung_FFB | 1 | Stahlträger | HEA 500 | 2.156 | Wartung_FFB | 13.05 | 26.902 | 6.696 | 13.05 | 13.888 | 6.696 | 0 | 0.15 | 0.32 | 0121Tra0000013434 | m | T101a | false | HI_UZT_HEA_STA_0,500_xxx | 0
Stahlträger | Wartung_FFB | 1 | Stahlträger | HEA 650 | 2.453 | Wartung_FFB | 16.05 | 26.902 | 6.621 | 16.05 | 13.888 | 6.621 | 0 | 0.15 | 0.32 | 0121Tra0000015404 | m | T101&102 | false | HI_UZT_HEA_STA_0,650_xxx | 0
Stahlträger | Wartung_FFB | 1 | Stahlträger | HEA 650 | 2.453 | Wartung_FFB | 19.05 | 26.902 | 6.621 | 19.05 | 13.888 | 6.621 | 0 | 0.15 | 0.32 | 0121Tra0000013465 | m | T101&102 | false | HI_UZT_HEA_STA_0,650_xxx | 0
Stahlträger | Wartung_FFB | 1 | Stahlträger | HEA 550 | 2.255 | Wartung_FFB | 28.05 | 27.785 | 6.671 | 28.05 | 13.888 | 6.671 | 0 | 0.15 | 0.32 | 0121Tra0000013286 | m | T101b | false | HI_UZT_HEA_STA_0,550_xxx | 0
Stahlträger | Wartung_FFB | 1 | Stahlträger | HEA 550 | 2.255 | Wartung_FFB | 34.05 | 27.785 | 6.671 | 34.05 | 13.888 | 6.671 | 0 | 0.15 | 0.32 | 0121Tra0000013317 | m | T101b | false | HI_UZT_HEA_STA_0,550_xxx | 0
Stahlträger | Wartung_FFB | 1 | Stahlträger | HEA 550 | 2.255 | Wartung_FFB | 25.55 | 27.785 | 6.671 | 25.55 | 13.888 | 6.671 | 0 | 0.15 | 0.32 | 0121Tra0000013268 | m | T101b | false | HI_UZT_HEA_STA_0,550_xxx | 0
Stahlträger | Wartung_FFB | 1 | Stahlträger | HEA 550 | 2.255 | Wartung_FFB | 32.25 | 27.785 | 6.671 | 32.25 | 13.888 | 6.671 | 0 | 0.15 | 0.32 | 0121Tra0000013302 | m | T101b | false | HI_UZT_HEA_STA_0,550_xxx | 0
Stahlträger | Wartung_FFB | 1 | Stahlträger | HEA 550 | 2.255 | Wartung_FFB | 29.6 | 27.785 | 6.671 | 29.6 | 13.888 | 6.671 | 0 | 0.15 | 0.32 | 0121Tra0000014974 | m | T101b | false | HI_UZT_HEA_STA_0,550_xxx | 0
Stahlträger | Wartung_FFB | 1 | Stahlträger | HEA 550 | 2.255 | Wartung_FFB | 37.05 | 27.785 | 6.671 | 37.05 | 13.888 | 6.671 | 0 | 0.15 | 0.32 | 0121Tra0000015372 | m | T101b | false | HI_UZT_HEA_STA_0,550_xxx | 0
Stahlträger | Wartung_FFB | 1 | Stahlträger | HEA 550 | 2.255 | Wartung_FFB | 40.05 | 27.785 | 6.671 | 40.05 | 13.888 | 6.671 | 0 | 0.15 | 0.32 | 0121Tra0000015387 | m | T101b | false | HI_UZT_HEA_STA_0,550_xxx | 0
Stahlträger | Wartung_FFB | 1 | Stahlträger | HEA 550 | 2.255 | Wartung_FFB | 22.05 | 27.785 | 6.671 | 22.05 | 13.888 | 6.671 | 0 | 0.15 | 0.32 | 0121Tra0000019942 | m | T101b | false | HI_UZT_HEA_STA_0,550_xxx | 0
Stahlträger | Wartung_FFB | 1 | Stahlträger | HEA 650 | 2.453 | Wartung_FFB | 21.9 | 27.96 | 6.621 | 40.2 | 27.96 | 6.621 | 0 | 0.15 | 0.32 | 0121Tra0000011769 | m | T150 | false | HI_UZT_HEA_STA_0,650_xxx | 0
Stahlträger | Wartung_FFB | 1 | Stahlträger | HEA 340 | 1.841 | Wartung_FFB | 53.655 | 26.65 | 6.776 | 59.955 | 26.65 | 6.776 | 0 | 0.15 | 0.32 | 0121Tra0000011766 | m | T151 | false | HI_UZT_HEA_STA_0,340_xxx | 0
Stahlträger | Wartung_FFB | 1 | Stahlträger | HEA 450 | 2.057 | Wartung_FFB | 66.229 | 15.11 | 6.721 | 81.7 | 15.11 | 6.721 | 0 | 0.15 | 0.32 | 0121Tra0000011742 | m | T152 | false | HI_UZT_HEA_STA_0,450_xxx | 0
Stahlträger | Wartung_FFB | 1 | Stahlträger | HEA 650 | 2.453 | Wartung_FFB | 43.05 | 26.902 | 6.621 | 43.05 | 13.888 | 6.621 | 0 | 0.15 | 0.32 | 0121Tra0000019958 | m | T101&102 | false | HI_UZT_HEA_STA_0,650_xxx | 0
Stahlträger | Wartung_FFB | 1 | Stahlträger | HEA 650 | 2.453 | Wartung_FFB | 46.05 | 26.902 | 6.621 | 46.05 | 13.888 | 6.621 | 0 | 0.15 | 0.32 | 0121Tra0000019969 | m | T101&102 | false | HI_UZT_HEA_STA_0,650_xxx | 0
Stahlträger | Wartung_FFB | 1 | Stahlträger | HEA 650 | 2.453 | Wartung_FFB | 49.05 | 26.902 | 6.621 | 49.05 | 13.888 | 6.621 | 0 | 0.15 | 0.32 | 0121Tra0000019982 | m | T101&102 | false | HI_UZT_HEA_STA_0,650_xxx | 0
Stahlträger | Wartung_FFB | 1 | Stahlträger | HEA 650 | 2.453 | Wartung_FFB | 52.05 | 26.902 | 6.621 | 52.05 | 13.888 | 6.621 | 0 | 0.15 | 0.32 | 0121Tra0000019995 | m | T101&102 | false | HI_UZT_HEA_STA_0,650_xxx | 0
Stahlträger | Wartung_FFB | 1 | Stahlträger | HEA 650 | 2.453 | Wartung_FFB | 61.05 | 26.902 | 6.621 | 61.05 | 13.888 | 6.621 | 0 | 0.15 | 0.32 | 0121Tra0000020034 | m | T101&102 | false | HI_UZT_HEA_STA_0,650_xxx | 0
Stahlträger | Wartung_FFB | 1 | Stahlträger | HEA 650 | 2.453 | Wartung_FFB | 64.05 | 26.902 | 6.621 | 64.05 | 13.888 | 6.621 | 0 | 0.15 | 0.32 | 0121Tra0000020047 | m | T101&102 | false | HI_UZT_HEA_STA_0,650_xxx | 0
Stahlträger | Wartung_FFB | 1 | Stahlträger | HEA 550 | 2.255 | Wartung_FFB | 58.05 | 26.475 | 6.671 | 58.05 | 13.888 | 6.671 | 0 | 0.15 | 0.32 | 0121Tra0000013229 | m | T101c | false | HI_UZT_HEA_STA_0,550_xxx | 0
Stahlträger | Wartung_FFB | 1 | Stahlträger | HEA 550 | 2.255 | Wartung_FFB | 55.05 | 26.475 | 6.671 | 55.05 | 13.888 | 6.671 | 0 | 0.15 | 0.32 | 0121Tra0000013254 | m | T101c | false | HI_UZT_HEA_STA_0,550_xxx | 0
Stahlträger | Wartung_FFB | 1 | Stahlträger | HEA 500 | 2.156 | Wartung_FFB | 67.05 | 26.902 | 6.696 | 67.05 | 15.285 | 6.696 | 0 | 0.15 | 0.32 | 0121Tra0000013092 | m | T101d | false | HI_UZT_HEA_STA_0,500_xxx | 0
Stahlträger | Wartung_FFB | 1 | Stahlträger | HEA 500 | 2.156 | Wartung_FFB | 70.05 | 26.902 | 6.696 | 70.05 | 15.285 | 6.696 | 0 | 0.15 | 0.32 | 0121Tra0000013118 | m | T101d | false | HI_UZT_HEA_STA_0,500_xxx | 0
Stahlträger | Wartung_FFB | 1 | Stahlträger | HEA 500 | 2.156 | Wartung_FFB | 73.05 | 26.902 | 6.696 | 73.05 | 15.285 | 6.696 | 0 | 0.15 | 0.32 | 0121Tra0000013140 | m | T101e | false | HI_UZT_HEA_STA_0,500_xxx | 0
Stahlträger | Wartung_FFB | 1 | Stahlträger | HEA 500 | 2.156 | Wartung_FFB | 76.05 | 26.902 | 6.696 | 76.05 | 15.285 | 6.696 | 0 | 0.15 | 0.32 | 0121Tra0000013161 | m | T101e | false | HI_UZT_HEA_STA_0,500_xxx | 0
Stahlträger | Wartung_FFB | 1 | Stahlträger | HEA 500 | 2.156 | Wartung_FFB | 79.05 | 26.902 | 6.696 | 79.05 | 15.285 | 6.696 | 0 | 0.15 | 0.32 | 0121Tra0000013182 | m | T101e | false | HI_UZT_HEA_STA_0,500_xxx | 0
Stahlträger | Wartung_FFB | 1 | Stahlträger | HEA 500 | 2.156 | Wartung_FFB | 81.55 | 26.902 | 6.696 | 81.55 | 15.285 | 6.696 | 0 | 0.15 | 0.32 | 0121Tra0000020136 | m | T101e | false | HI_UZT_HEA_STA_0,500_xxx | 0
Stahlträger | Wartung_FFB | 1 | Stahlträger | HEA 650 | 2.453 | Wartung_FFB | 88.05 | 26.902 | 6.621 | 88.05 | 13.888 | 6.621 | 0 | 0.15 | 0.32 | 0121Tra0000020175 | m | T101&102 | false | HI_UZT_HEA_STA_0,650_xxx | 0
Stahlträger | Wartung_FFB | 1 | Stahlträger | HEA 650 | 2.453 | Wartung_FFB | 103.05 | 26.902 | 6.621 | 103.05 | 13.888 | 6.621 | 0 | 0.15 | 0.32 | 0121Tra0000020188 | m | T101&102 | false | HI_UZT_HEA_STA_0,650_xxx | 0
Stahlträger | Wartung_FFB | 1 | Stahlträger | HEA 650 | 2.453 | Wartung_FFB | 106.05 | 26.902 | 6.621 | 106.05 | 13.888 | 6.621 | 0 | 0.15 | 0.32 | 0121Tra0000020201 | m | T101&102 | false | HI_UZT_HEA_STA_0,650_xxx | 0
Stahlträger | Wartung_FFB | 1 | Stahlträger | HEA 650 | 2.453 | Wartung_FFB | 109.05 | 26.902 | 6.621 | 109.05 | 13.888 | 6.621 | 0 | 0.15 | 0.32 | 0121Tra0000020221 | m | T101&102 | false | HI_UZT_HEA_STA_0,650_xxx | 0
Stahlträger | Wartung_FFB | 1 | Stahlträger | HEA 650 | 2.453 | Wartung_FFB | 112.05 | 26.902 | 6.621 | 112.05 | 13.888 | 6.621 | 0 | 0.15 | 0.32 | 0121Tra0000020227 | m | T101&102 | false | HI_UZT_HEA_STA_0,650_xxx | 0
Stahlträger | Wartung_FFB | 1 | Stahlträger | HEA 650 | 2.453 | Wartung_FFB | 115.05 | 26.902 | 6.621 | 115.05 | 13.888 | 6.621 | 0 | 0.15 | 0.32 | 0121Tra0000020254 | m | T101&102 | false | HI_UZT_HEA_STA_0,650_xxx | 0
Stahlträger | Wartung_FFB | 1 | Stahlträger | HEA 650 | 2.453 | Wartung_FFB | 118.05 | 26.902 | 6.621 | 118.05 | 13.888 | 6.621 | 0 | 0.15 | 0.32 | 0121Tra0000020260 | m | T101&102 | false | HI_UZT_HEA_STA_0,650_xxx | 0
Stahlträger | Wartung_FFB | 1 | Stahlträger | HEA 650 | 2.453 | Wartung_FFB | 121.05 | 26.902 | 6.621 | 121.05 | 13.888 | 6.621 | 0 | 0.15 | 0.32 | 0121Tra0000020266 | m | T101&102 | false | HI_UZT_HEA_STA_0,650_xxx | 0
Stahlträger | Wartung_FFB | 1 | Stahlträger | HEA 650 | 2.453 | Wartung_FFB | 97.05 | 26.902 | 6.621 | 97.05 | 13.888 | 6.621 | 0 | 0.15 | 0.32 | 0121Tra0000020286 | m | T101&102 | false | HI_UZT_HEA_STA_0,650_xxx | 0
Stahlträger | Wartung_FFB | 1 | Stahlträger | HEA 650 | 2.453 | Wartung_FFB | 100.05 | 26.902 | 6.621 | 100.05 | 13.888 | 6.621 | 0 | 0.15 | 0.32 | 0121Tra0000020292 | m | T101&102 | false | HI_UZT_HEA_STA_0,650_xxx | 0
Stahlträger | Wartung_FFB | 1 | Stahlträger | HEA 650 | 2.453 | Wartung_FFB | 94.7 | 26.902 | 6.621 | 94.7 | 13.888 | 6.621 | 0 | 0.15 | 0.32 | 0121Tra0000020305 | m | T101&102 | false | HI_UZT_HEA_STA_0,650_xxx | 0
Stahlträger | Wartung_FFB | 1 | Stahlträger | HEA 650 | 2.453 | Wartung_FFB | 91.85 | 26.902 | 6.621 | 91.85 | 13.888 | 6.621 | 0 | 0.15 | 0.32 | 0121Tra0000020318 | m | T101&102 | false | HI_UZT_HEA_STA_0,650_xxx | 0
Stahlträger | Wartung_FFB | 1 | Stahlträger | HEA 650 | 2.453 | Wartung_FFB | 91.05 | 26.902 | 6.621 | 91.05 | 13.888 | 6.621 | 0 | 0.15 | 0.32 | 0121Tra0000020331 | m | T101&102 | false | HI_UZT_HEA_STA_0,650_xxx | 0
Stahlträger | Wartung_FFB | 1 | Stahlträger | HEA 650 | 2.453 | Wartung_FFB | 85.05 | 26.902 | 6.621 | 85.05 | 13.888 | 6.621 | 0 | 0.15 | 0.32 | 0121Tra0000020158 | m | T101f | false | HI_UZT_HEA_STA_0,650_xxx | 0
Stahlträger | Wartung_FFB | 1 | Stahlträger | HEA 400 | 1.958 | Wartung_FFB | 10.4 | 39.8 | 6.746 | 19.46 | 39.8 | 6.746 | 0 | 0.15 | 0.32 | 0121Tra0000013715 | m | T160 | false | HI_UZT_HEA_STA_0,400_xxx | 0
Stahlträger | Wartung_FFB | 1 | Stahlträger | HEA 300 | 1.763 | Wartung_FFB | 10.55 | 47.702 | 6.796 | 10.55 | 39.975 | 6.796 | 0 | 0.15 | 0.32 | 0121Tra0000014095 | m | T102a | false | HI_UZT_HEA_STA_0,300_xxx | 0
Stahlträger | Wartung_FFB | 1 | Stahlträger | HEA 300 | 1.763 | Wartung_FFB | 13.05 | 47.702 | 6.796 | 13.05 | 39.975 | 6.796 | 0 | 0.15 | 0.32 | 0121Tra0000020356 | m | T102a | false | HI_UZT_HEA_STA_0,300_xxx | 0
Stahlträger | Wartung_FFB | 1 | Stahlträger | HEA 360 | 1.88 | Wartung_FFB | 19.05 | 47.702 | 6.766 | 19.05 | 39.975 | 6.766 | 0 | 0.15 | 0.32 | 0121Tra0000014014 | m | T102b | false | HI_UZT_HEA_STA_0,360_xxx | 0
Stahlträger | Wartung_FFB | 1 | Stahlträger | HEA 360 | 1.88 | Wartung_FFB | 16.05 | 47.702 | 6.766 | 16.05 | 39.975 | 6.766 | 0 | 0.15 | 0.32 | 0121Tra0000014031 | m | T102b | false | HI_UZT_HEA_STA_0,360_xxx | 0
Stahlträger | Wartung_FFB | 1 | Stahlträger | HEA 650 | 2.453 | Wartung_FFB | 22.05 | 47.702 | 6.621 | 22.05 | 34.698 | 6.621 | 0 | 0.15 | 0.32 | 0121Tra0000020381 | m | T101&102 | false | HI_UZT_HEA_STA_0,650_xxx | 0
Stahlträger | Wartung_FFB | 1 | Stahlträger | HEA 650 | 2.453 | Wartung_FFB | 49.05 | 47.702 | 6.621 | 49.05 | 34.698 | 6.621 | 0 | 0.15 | 0.32 | 0121Tra0000020410 | m | T101&102 | false | HI_UZT_HEA_STA_0,650_xxx | 0
Stahlträger | Wartung_FFB | 1 | Stahlträger | HEA 650 | 2.453 | Wartung_FFB | 52.05 | 47.702 | 6.621 | 52.05 | 34.698 | 6.621 | 0 | 0.15 | 0.32 | 0121Tra0000020430 | m | T101&102 | false | HI_UZT_HEA_STA_0,650_xxx | 0
Stahlträger | Wartung_FFB | 1 | Stahlträger | HEA 650 | 2.453 | Wartung_FFB | 55.05 | 47.702 | 6.621 | 55.05 | 34.698 | 6.621 | 0 | 0.15 | 0.32 | 0121Tra0000020436 | m | T101&102 | false | HI_UZT_HEA_STA_0,650_xxx | 0
Stahlträger | Wartung_FFB | 1 | Stahlträger | HEA 650 | 2.453 | Wartung_FFB | 67.05 | 47.702 | 6.621 | 67.05 | 34.698 | 6.621 | 0 | 0.15 | 0.32 | 0121Tra0000020449 | m | T101&102 | false | HI_UZT_HEA_STA_0,650_xxx | 0
Stahlträger | Wartung_FFB | 1 | Stahlträger | HEA 500 | 2.156 | Wartung_FFB | 28.05 | 47.707 | 6.696 | 28.05 | 36.255 | 6.696 | 0 | 0.15 | 0.32 | 0121Tra0000013768 | m | T102c | false | HI_UZT_HEA_STA_0,500_xxx | 0
Stahlträger | Wartung_FFB | 1 | Stahlträger | HEA 500 | 2.156 | Wartung_FFB | 34.05 | 47.707 | 6.696 | 34.05 | 36.255 | 6.696 | 0 | 0.15 | 0.32 | 0121Tra0000013811 | m | T102c | false | HI_UZT_HEA_STA_0,500_xxx | 0
Stahlträger | Wartung_FFB | 1 | Stahlträger | HEA 500 | 2.156 | Wartung_FFB | 37.05 | 47.707 | 6.696 | 37.05 | 36.255 | 6.696 | 0 | 0.15 | 0.32 | 0121Tra0000013832 | m | T102c | false | HI_UZT_HEA_STA_0,500_xxx | 0
Stahlträger | Wartung_FFB | 1 | Stahlträger | HEA 500 | 2.156 | Wartung_FFB | 40.05 | 47.707 | 6.696 | 40.05 | 36.255 | 6.696 | 0 | 0.15 | 0.32 | 0121Tra0000013853 | m | T102c | false | HI_UZT_HEA_STA_0,500_xxx | 0
Stahlträger | Wartung_FFB | 1 | Stahlträger | HEA 500 | 2.156 | Wartung_FFB | 32.25 | 47.707 | 6.696 | 32.25 | 36.255 | 6.696 | 0 | 0.15 | 0.32 | 0121Tra0000013968 | m | T102c | false | HI_UZT_HEA_STA_0,500_xxx | 0
Stahlträger | Wartung_FFB | 1 | Stahlträger | HEA 500 | 2.156 | Wartung_FFB | 29.6 | 47.707 | 6.696 | 29.6 | 36.255 | 6.696 | 0 | 0.15 | 0.32 | 0121Tra0000013790 | m | T102c | false | HI_UZT_HEA_STA_0,500_xxx | 0
Stahlträger | Wartung_FFB | 1 | Stahlträger | HEA 500 | 2.156 | Wartung_FFB | 43.05 | 47.707 | 6.696 | 43.05 | 36.255 | 6.696 | 0 | 0.15 | 0.32 | 0121Tra0000015428 | m | T102c | false | HI_UZT_HEA_STA_0,500_xxx | 0
Stahlträger | Wartung_FFB | 1 | Stahlträger | HEA 600 | 2.354 | Wartung_FFB | 58.05 | 49.225 | 6.646 | 58.05 | 34.698 | 6.646 | 0 | 0.15 | 0.32 | 0121Tra0000014137 | m | T102d | false | HI_UZT_HEA_STA_0,600_xxx | 0
Stahlträger | Wartung_FFB | 1 | Stahlträger | HEA 600 | 2.354 | Wartung_FFB | 61.05 | 49.225 | 6.646 | 61.05 | 34.698 | 6.646 | 0 | 0.15 | 0.32 | 0121Tra0000014170 | m | T102d | false | HI_UZT_HEA_STA_0,600_xxx | 0
Stahlträger | Wartung_FFB | 1 | Stahlträger | HEA 600 | 2.354 | Wartung_FFB | 64.05 | 49.225 | 6.646 | 64.05 | 34.698 | 6.646 | 0 | 0.15 | 0.32 | 0121Tra0000014192 | m | T102d | false | HI_UZT_HEA_STA_0,600_xxx | 0
Stahlträger | Wartung_FFB | 1 | Stahlträger | HEA 500 | 2.156 | Wartung_FFB | 56.771 | 49.4 | 6.696 | 66.499 | 49.4 | 6.696 | 0 | 0.15 | 0.32 | 0121Tra0000011826 | m | T162 | false | HI_UZT_HEA_STA_0,500_xxx | 0
Stahlträger | Wartung_FFB | 1 | Stahlträger | HEA 450 | 2.057 | Wartung_FFB | 51.09 | 65.345 | 6.721 | 74.824 | 65.345 | 6.721 | 0 | 0.15 | 0.32 | 0121Tra0000014223 | m | T172 | false | HI_UZT_HEA_STA_0,450_xxx | 0
Stahlträger | Wartung_FFB | 1 | Stahlträger | HEA 280 | 1.644 | Wartung_FFB | 58.05 | 65.17 | 6.806 | 58.05 | 57.655 | 6.806 | 0 | 0.15 | 0.32 | 0121Tra0000014446 | m | T103g | false | HI_UZT_HEA_STA_0,280_xxx | 0
Stahlträger | Wartung_FFB | 1 | Stahlträger | HEA 280 | 1.644 | Wartung_FFB | 61.05 | 65.17 | 6.806 | 61.05 | 57.655 | 6.806 | 0 | 0.15 | 0.32 | 0121Tra0000020780 | m | T103g | false | HI_UZT_HEA_STA_0,280_xxx | 0
Stahlträger | Wartung_FFB | 1 | Stahlträger | HEA 280 | 1.644 | Wartung_FFB | 64.05 | 65.17 | 6.806 | 64.05 | 57.655 | 6.806 | 0 | 0.15 | 0.32 | 0121Tra0000020795 | m | T103h | false | HI_UZT_HEA_STA_0,280_xxx | 0
Stahlträger | Wartung_FFB | 1 | Stahlträger | HEA 450 | 2.057 | Wartung_FFB | 56.309 | 57.48 | 6.721 | 66.499 | 57.48 | 6.721 | 0 | 0.15 | 0.32 | 0121Tra0000014220 | m | T173 | false | HI_UZT_HEA_STA_0,450_xxx | 0
Stahlträger | Wartung_FFB | 1 | Stahlträger | HEA 300 | 1.763 | Wartung_FFB | 22.405 | 72.11 | 6.796 | 51.28 | 72.11 | 6.796 | 0 | 0.15 | 0.32 | 0121Tra0000014588 | m | T180 | false | HI_UZT_HEA_STA_0,300_xxx | 0
Stahlträger | Wartung_FFB | 1 | Stahlträger | HEA 320 | 1.802 | Wartung_FFB | 51.4 | 79.547 | 6.786 | 74.824 | 79.547 | 6.786 | 0 | 0.15 | 0.32 | 0121Tra0000014592 | m | T181 | false | HI_UZT_HEA_STA_0,320_xxx | 0
Stahlträger | Wartung_FFB | 1 | Stahlträger | HEA 320 | 1.802 | Wartung_FFB | 80.515 | 81.199 | 6.786 | 97.2 | 81.199 | 6.786 | 0 | 0.15 | 0.32 | 0121Tra0000014599 | m | T182 | false | HI_UZT_HEA_STA_0,320_xxx | 0
Stahlträger | Wartung_FFB | 1 | Stahlträger | HEA 500 | 2.156 | Wartung_FFB | 25.503 | 47.707 | 6.696 | 25.503 | 36.255 | 6.696 | 0 | 0.15 | 0.32 | 0121Tra0000013736 | m | T102c | false | HI_UZT_HEA_STA_0,500_xxx | 0
Stahlträger | Wartung_FFB | 1 | Stahlträger | HEA 650 | 2.453 | Wartung_FFB | 45.92 | 47.702 | 6.621 | 45.92 | 34.698 | 6.621 | 0 | 0.15 | 0.32 | 0121Tra0000020396 | m | T101&102 | false | HI_UZT_HEA_STA_0,650_xxx | 0
Stahlträger | Wartung_FFB | 1 | Stahlträger | HEA 240 | 1.405 | Wartung_FFB | 19.28 | 63.282 | 6.826 | 19.28 | 58.993 | 6.826 | 0 | 0.15 | 0.32 | 0121Tra0000020603 | m | T103b | false | HI_UZT_HEA_STA_0,240_xxx | 0
Stahlträger | Wartung_FFB | 1 | Stahlträger | HEA 340 | 1.841 | Wartung_FFB | 19.16 | 63.457 | 6.776 | 51.28 | 63.457 | 6.776 | 0 | 0.15 | 0.32 | 0121Tra0000014215 | m | T171 | false | HI_UZT_HEA_STA_0,340_xxx | 0
Stahlträger | Wartung_FFB | 1 | Stahlträger | HEA 400 | 1.958 | Wartung_FFB | 24.82 | 36.08 | 6.746 | 43.2 | 36.08 | 6.746 | 0 | 0.15 | 0.32 | 0121Tra0000011772 | m | T161 | false | HI_UZT_HEA_STA_0,400_xxx | 0
Stahlträger | Wartung_FFB | 1 | Stahlträger | HEA 320 | 1.802 | Wartung_FFB | 10.4 | 58.818 | 6.786 | 19.4 | 58.818 | 6.786 | 0 | 0.15 | 0.32 | 0121Tra0000020574 | m | T170 | false | HI_UZT_HEA_STA_0,320_xxx | 0
Stahlträger | Wartung_FFB | 1 | Stahlträger | HEA 400 | 1.958 | Wartung_FFB | 10.55 | 81.893 | 6.746 | 10.55 | 85.7 | 6.746 | 0 | 0.15 | 0.32 | 0121Tra0000015051 | m | T104a | false | HI_UZT_HEA_STA_0,400_xxx | 0
Stahlträger | Wartung_FFB | 1 | Stahlträger | HEA 400 | 1.958 | Wartung_FFB | 13.05 | 81.893 | 6.746 | 13.05 | 85.7 | 6.746 | 0 | 0.15 | 0.32 | 0121Tra0000015053 | m | T104a | false | HI_UZT_HEA_STA_0,400_xxx | 0
Stahlträger | Wartung_FFB | 1 | Stahlträger | HEA 400 | 1.958 | Wartung_FFB | 16.05 | 81.893 | 6.746 | 16.05 | 85.7 | 6.746 | 0 | 0.15 | 0.32 | 0121Tra0000015055 | m | T104a | false | HI_UZT_HEA_STA_0,400_xxx | 0
Stahlträger | Wartung_FFB | 1 | Stahlträger | HEA 400 | 1.958 | Wartung_FFB | 22.05 | 81.893 | 6.746 | 22.05 | 85.7 | 6.746 | 0 | 0.15 | 0.32 | 0121Tra0000020939 | m | T104a | false | HI_UZT_HEA_STA_0,400_xxx | 0
Stahlträger | Wartung_FFB | 1 | Stahlträger | HEA 400 | 1.958 | Wartung_FFB | 19.28 | 81.893 | 6.746 | 19.28 | 85.7 | 6.746 | 0 | 0.15 | 0.32 | 0121Tra0000020931 | m | T104a | false | HI_UZT_HEA_STA_0,400_xxx | 0
Stahlträger | Wartung_FFB | 1 | Stahlträger | HEA 450 | 2.057 | Wartung_FFB | 25.05 | 72.285 | 6.721 | 25.05 | 85.7 | 6.721 | 0 | 0.15 | 0.32 | 0121Tra0000014802 | m | T104b | false | HI_UZT_HEA_STA_0,450_xxx | 0
Stahlträger | Wartung_FFB | 1 | Stahlträger | HEA 450 | 2.057 | Wartung_FFB | 28.05 | 72.285 | 6.721 | 28.05 | 85.7 | 6.721 | 0 | 0.15 | 0.32 | 0121Tra0000014814 | m | T104b | false | HI_UZT_HEA_STA_0,450_xxx | 0
Stahlträger | Wartung_FFB | 1 | Stahlträger | HEA 450 | 2.057 | Wartung_FFB | 31.05 | 72.285 | 6.721 | 31.05 | 85.7 | 6.721 | 0 | 0.15 | 0.32 | 0121Tra0000014826 | m | T104b | false | HI_UZT_HEA_STA_0,450_xxx | 0
Stahlträger | Wartung_FFB | 1 | Stahlträger | HEA 450 | 2.057 | Wartung_FFB | 34.05 | 72.285 | 6.721 | 34.05 | 85.7 | 6.721 | 0 | 0.15 | 0.32 | 0121Tra0000014838 | m | T104b | false | HI_UZT_HEA_STA_0,450_xxx | 0
Stahlträger | Wartung_FFB | 1 | Stahlträger | HEA 450 | 2.057 | Wartung_FFB | 37.05 | 72.285 | 6.721 | 37.05 | 85.7 | 6.721 | 0 | 0.15 | 0.32 | 0121Tra0000014850 | m | T104b | false | HI_UZT_HEA_STA_0,450_xxx | 0
Stahlträger | Wartung_FFB | 1 | Stahlträger | HEA 450 | 2.057 | Wartung_FFB | 40.05 | 72.285 | 6.721 | 40.05 | 85.7 | 6.721 | 0 | 0.15 | 0.32 | 0121Tra0000014862 | m | T104b | false | HI_UZT_HEA_STA_0,450_xxx | 0
Stahlträger | Wartung_FFB | 1 | Stahlträger | HEA 450 | 2.057 | Wartung_FFB | 43.05 | 72.285 | 6.721 | 43.05 | 85.7 | 6.721 | 0 | 0.15 | 0.32 | 0121Tra0000014874 | m | T104b | false | HI_UZT_HEA_STA_0,450_xxx | 0
Stahlträger | Wartung_FFB | 1 | Stahlträger | HEA 450 | 2.057 | Wartung_FFB | 46.05 | 72.285 | 6.721 | 46.05 | 85.7 | 6.721 | 0 | 0.15 | 0.32 | 0121Tra0000014886 | m | T104b | false | HI_UZT_HEA_STA_0,450_xxx | 0
Stahlträger | Wartung_FFB | 1 | Stahlträger | HEA 450 | 2.057 | Wartung_FFB | 49.05 | 72.285 | 6.721 | 49.05 | 85.7 | 6.721 | 0 | 0.15 | 0.32 | 0121Tra0000014898 | m | T104b | false | HI_UZT_HEA_STA_0,450_xxx | 0
Stahlträger | Wartung_FFB | 1 | Stahlträger | HEA 280 | 1.644 | Wartung_FFB | 61.05 | 85.7 | 6.806 | 61.05 | 79.722 | 6.806 | 0 | 0.15 | 0.32 | 0121Tra0000021002 | m | T104c | false | HI_UZT_HEA_STA_0,280_xxx | 0
Stahlträger | Wartung_FFB | 1 | Stahlträger | HEA 280 | 1.644 | Wartung_FFB | 64.05 | 85.7 | 6.806 | 64.05 | 79.722 | 6.806 | 0 | 0.15 | 0.32 | 0121Tra0000021012 | m | T104c | false | HI_UZT_HEA_STA_0,280_xxx | 0
Stahlträger | Wartung_FFB | 1 | Stahlträger | HEA 280 | 1.644 | Wartung_FFB | 67.05 | 85.7 | 6.806 | 67.05 | 79.722 | 6.806 | 0 | 0.15 | 0.32 | 0121Tra0000021020 | m | T104c | false | HI_UZT_HEA_STA_0,280_xxx | 0
Stahlträger | Wartung_FFB | 1 | Stahlträger | HEA 280 | 1.644 | Wartung_FFB | 70.05 | 85.7 | 6.806 | 70.05 | 79.722 | 6.806 | 0 | 0.15 | 0.32 | 0121Tra0000021028 | m | T104c | false | HI_UZT_HEA_STA_0,280_xxx | 0
Stahlträger | Wartung_FFB | 1 | Stahlträger | HEA 280 | 1.644 | Wartung_FFB | 73.05 | 85.7 | 6.806 | 73.05 | 79.722 | 6.806 | 0 | 0.15 | 0.32 | 0121Tra0000021036 | m | T104c | false | HI_UZT_HEA_STA_0,280_xxx | 0
Stahlträger | Wartung_FFB | 1 | Stahlträger | HEA 280 | 1.644 | Wartung_FFB | 52.05 | 85.7 | 6.806 | 52.05 | 79.722 | 6.806 | 0 | 0.15 | 0.32 | 0121Tra0000021060 | m | T104c | false | HI_UZT_HEA_STA_0,280_xxx | 0
Stahlträger | Wartung_FFB | 1 | Stahlträger | HEA 280 | 1.644 | Wartung_FFB | 55.05 | 85.7 | 6.806 | 55.05 | 79.722 | 6.806 | 0 | 0.15 | 0.32 | 0121Tra0000021064 | m | T104c | false | HI_UZT_HEA_STA_0,280_xxx | 0
Stahlträger | Wartung_FFB | 1 | Stahlträger | HEA 280 | 1.644 | Wartung_FFB | 58.05 | 85.7 | 6.806 | 58.05 | 79.722 | 6.806 | 0 | 0.15 | 0.32 | 0121Tra0000021068 | m | T104c | false | HI_UZT_HEA_STA_0,280_xxx | 0
Stahlträger | Wartung_FFB | 1 | Stahlträger | HEA 500 | 2.156 | Wartung_FFB | 79.05 | 85.7 | 6.696 | 79.05 | 81.893 | 6.696 | 0 | 0.15 | 0.32 | 0121Tra0000015121 | m | T104d | false | HI_UZT_HEA_STA_0,500_xxx | 0
Stahlträger | Wartung_FFB | 1 | Stahlträger | HEA 500 | 2.156 | Wartung_FFB | 76.05 | 85.7 | 6.696 | 76.05 | 81.893 | 6.696 | 0 | 0.15 | 0.32 | 0121Tra0000015123 | m | T104d | false | HI_UZT_HEA_STA_0,500_xxx | 0
Stahlträger | Wartung_FFB | 1 | Stahlträger | HEA 360 | 1.88 | Wartung_FFB | 84.35 | 85.7 | 6.766 | 84.35 | 81.374 | 6.766 | 0 | 0.15 | 0.32 | 0121Tra0000021081 | m | T104e | false | HI_UZT_HEA_STA_0,360_xxx | 0
Stahlträger | Wartung_FFB | 1 | Stahlträger | HEA 360 | 1.88 | Wartung_FFB | 86.75 | 85.7 | 6.766 | 86.75 | 81.374 | 6.766 | 0 | 0.15 | 0.32 | 0121Tra0000021100 | m | T104e | false | HI_UZT_HEA_STA_0,360_xxx | 0
Stahlträger | Wartung_FFB | 1 | Stahlträger | HEA 360 | 1.88 | Wartung_FFB | 89.5 | 85.7 | 6.766 | 89.5 | 81.374 | 6.766 | 0 | 0.15 | 0.32 | 0121Tra0000021108 | m | T104e | false | HI_UZT_HEA_STA_0,360_xxx | 0
Stahlträger | Wartung_FFB | 1 | Stahlträger | HEA 360 | 1.88 | Wartung_FFB | 91.9 | 85.7 | 6.766 | 91.9 | 81.374 | 6.766 | 0 | 0.15 | 0.32 | 0121Tra0000021116 | m | T104e | false | HI_UZT_HEA_STA_0,360_xxx | 0
Stahlträger | Wartung_FFB | 1 | Stahlträger | HEA 320 | 1.802 | Wartung_FFB | 94.05 | 81.374 | 6.786 | 94.05 | 85.7 | 6.786 | 0 | 0.15 | 0.32 | 0121Tra0000021121 | m | T104f | false | HI_UZT_HEA_STA_0,320_xxx | 0
Stahlträger | Wartung_FFB | 1 | Stahlträger | HEA 320 | 1.802 | Wartung_FFB | 97.05 | 81.374 | 6.786 | 97.05 | 85.7 | 6.786 | 0 | 0.15 | 0.32 | 0121Tra0000021130 | m | T104f | false | HI_UZT_HEA_STA_0,320_xxx | 0
Stahlträger | Wartung_FFB | 1 | Stahlträger | HEA 450 | 2.057 | Wartung_FFB | 103.05 | 81.893 | 6.721 | 103.05 | 85.7 | 6.721 | 0 | 0.15 | 0.32 | 0121Tra0000021150 | m | T104 | false | HI_UZT_HEA_STA_0,450_xxx | 0
Stahlträger | Wartung_FFB | 1 | Stahlträger | HEA 450 | 2.057 | Wartung_FFB | 106.05 | 81.893 | 6.721 | 106.05 | 85.7 | 6.721 | 0 | 0.15 | 0.32 | 0121Tra0000021163 | m | T104 | false | HI_UZT_HEA_STA_0,450_xxx | 0
Stahlträger | Wartung_FFB | 1 | Stahlträger | HEA 450 | 2.057 | Wartung_FFB | 109.05 | 81.893 | 6.721 | 109.05 | 85.7 | 6.721 | 0 | 0.15 | 0.32 | 0121Tra0000021171 | m | T104 | false | HI_UZT_HEA_STA_0,450_xxx | 0
Stahlträger | Wartung_FFB | 1 | Stahlträger | HEA 450 | 2.057 | Wartung_FFB | 112.05 | 81.893 | 6.721 | 112.05 | 85.7 | 6.721 | 0 | 0.15 | 0.32 | 0121Tra0000021179 | m | T104 | false | HI_UZT_HEA_STA_0,450_xxx | 0
Stahlträger | Wartung_FFB | 1 | Stahlträger | HEA 450 | 2.057 | Wartung_FFB | 115.05 | 81.893 | 6.721 | 115.05 | 85.7 | 6.721 | 0 | 0.15 | 0.32 | 0121Tra0000021187 | m | T104 | false | HI_UZT_HEA_STA_0,450_xxx | 0
Stahlträger | Wartung_FFB | 1 | Stahlträger | HEA 450 | 2.057 | Wartung_FFB | 118.05 | 81.893 | 6.721 | 118.05 | 85.7 | 6.721 | 0 | 0.15 | 0.32 | 0121Tra0000021195 | m | T104 | false | HI_UZT_HEA_STA_0,450_xxx | 0
Stahlträger | Wartung_FFB | 1 | Stahlträger | HEA 450 | 2.057 | Wartung_FFB | 120.75 | 81.893 | 6.721 | 120.75 | 85.7 | 6.721 | 0 | 0.15 | 0.32 | 0121Tra0000021203 | m | T104 | false | HI_UZT_HEA_STA_0,450_xxx | 0
Stahlträger | Wartung_FFB | 1 | Stahlträger | HEA 360 | 1.88 | Wartung_FFB | 82.18 | 85.7 | 6.766 | 82.18 | 81.374 | 6.766 | 0 | 0.15 | 0.32 | 0121Tra0000021092 | m | T104e | false | HI_UZT_HEA_STA_0,360_xxx | 0
Stahlträger | Wartung_FFB | 1 | Stahlträger | HEA 500 | 2.156 | Wartung_FFB | 99.82 | 85.7 | 6.696 | 99.82 | 81.893 | 6.696 | 0 | 0.15 | 0.32 | 0121Tra0000021146 | m | T104d | false | HI_UZT_HEA_STA_0,500_xxx | 0
Stahlträger | Wartung_FFB | 1 | Stahlträger | HEA 400 | 1.958 | Wartung_FFB | 10.55 | 70.752 | 6.746 | 10.55 | 81.843 | 6.746 | 0 | 0.15 | 0.32 | 0121Tra0000014604 | m | T104a | false | HI_UZT_HEA_STA_0,400_xxx | 0
Stahlträger | Wartung_FFB | 1 | Stahlträger | HEA 400 | 1.958 | Wartung_FFB | 13.05 | 70.752 | 6.746 | 13.05 | 81.843 | 6.746 | 0 | 0.15 | 0.32 | 0121Tra0000014607 | m | T104a | false | HI_UZT_HEA_STA_0,400_xxx | 0
Stahlträger | Wartung_FFB | 1 | Stahlträger | HEA 400 | 1.958 | Wartung_FFB | 16.05 | 70.752 | 6.746 | 16.05 | 81.843 | 6.746 | 0 | 0.15 | 0.32 | 0121Tra0000014610 | m | T104a | false | HI_UZT_HEA_STA_0,400_xxx | 0
Stahlträger | Wartung_FFB | 1 | Stahlträger | HEA 400 | 1.958 | Wartung_FFB | 22.05 | 70.752 | 6.746 | 22.05 | 81.843 | 6.746 | 0 | 0.15 | 0.32 | 0121Tra0000020937 | m | T104a | false | HI_UZT_HEA_STA_0,400_xxx | 0
Stahlträger | Wartung_FFB | 1 | Stahlträger | HEA 450 | 2.057 | Wartung_FFB | 25.05 | 70.752 | 6.721 | 25.05 | 71.935 | 6.721 | 0 | 0.15 | 0.32 | 0121Tra0000014785 | m | T104b | false | HI_UZT_HEA_STA_0,450_xxx | 0
Stahlträger | Wartung_FFB | 1 | Stahlträger | HEA 450 | 2.057 | Wartung_FFB | 28.05 | 70.752 | 6.721 | 28.05 | 71.935 | 6.721 | 0 | 0.15 | 0.32 | 0121Tra0000014806 | m | T104b | false | HI_UZT_HEA_STA_0,450_xxx | 0
Stahlträger | Wartung_FFB | 1 | Stahlträger | HEA 450 | 2.057 | Wartung_FFB | 31.05 | 70.752 | 6.721 | 31.05 | 71.935 | 6.721 | 0 | 0.15 | 0.32 | 0121Tra0000014824 | m | T104b | false | HI_UZT_HEA_STA_0,450_xxx | 0
Stahlträger | Wartung_FFB | 1 | Stahlträger | HEA 450 | 2.057 | Wartung_FFB | 34.05 | 70.752 | 6.721 | 34.05 | 71.935 | 6.721 | 0 | 0.15 | 0.32 | 0121Tra0000014836 | m | T104b | false | HI_UZT_HEA_STA_0,450_xxx | 0
Stahlträger | Wartung_FFB | 1 | Stahlträger | HEA 450 | 2.057 | Wartung_FFB | 37.05 | 70.752 | 6.721 | 37.05 | 71.935 | 6.721 | 0 | 0.15 | 0.32 | 0121Tra0000014848 | m | T104b | false | HI_UZT_HEA_STA_0,450_xxx | 0
Stahlträger | Wartung_FFB | 1 | Stahlträger | HEA 450 | 2.057 | Wartung_FFB | 40.05 | 70.752 | 6.721 | 40.05 | 71.935 | 6.721 | 0 | 0.15 | 0.32 | 0121Tra0000014860 | m | T104b | false | HI_UZT_HEA_STA_0,450_xxx | 0
Stahlträger | Wartung_FFB | 1 | Stahlträger | HEA 450 | 2.057 | Wartung_FFB | 43.05 | 70.752 | 6.721 | 43.05 | 71.935 | 6.721 | 0 | 0.15 | 0.32 | 0121Tra0000014872 | m | T104b | false | HI_UZT_HEA_STA_0,450_xxx | 0
Stahlträger | Wartung_FFB | 1 | Stahlträger | HEA 450 | 2.057 | Wartung_FFB | 46.05 | 70.752 | 6.721 | 46.05 | 71.935 | 6.721 | 0 | 0.15 | 0.32 | 0121Tra0000014884 | m | T104b | false | HI_UZT_HEA_STA_0,450_xxx | 0
Stahlträger | Wartung_FFB | 1 | Stahlträger | HEA 450 | 2.057 | Wartung_FFB | 49.05 | 70.752 | 6.721 | 49.05 | 71.935 | 6.721 | 0 | 0.15 | 0.32 | 0121Tra0000014896 | m | T104b | false | HI_UZT_HEA_STA_0,450_xxx | 0
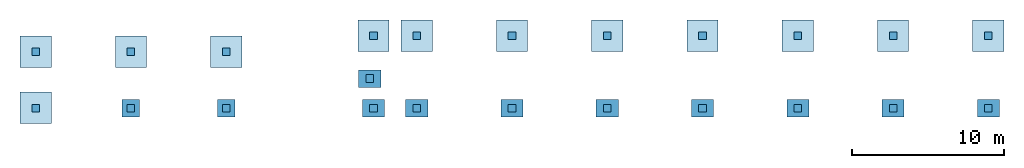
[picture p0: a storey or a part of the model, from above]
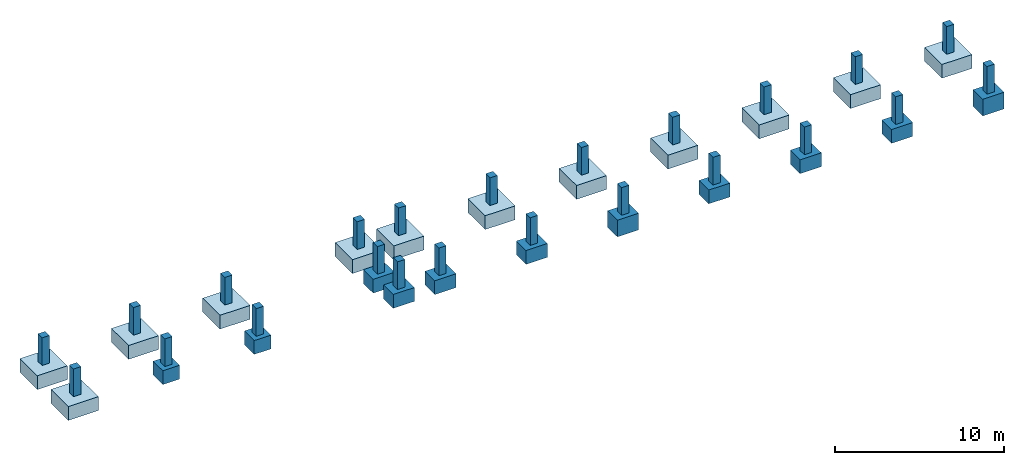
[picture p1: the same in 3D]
Properties of the parts of a building model (IFC2X3), part 2 of 25

# IfcBeam (2372)
Name | In | Faktor | Bezeichnung = Name | Profilname | Mantelfläche/lfm | Ebene | Achsenstartpunkt (X) (m) | Achsenstartpunkt (Y) (m) | Achsenstartpunkt (Z) (m) | Achsenendpunkt (X) (m) | Achsenendpunkt (Y) (m) | Achsenendpunkt (Z) (m) | Objektdrehwinkel | Schwerpunkt X (m) | Schwerpunkt Y (m) | Allright_Bauteil_ID | Abrechnungsart | Positionsnummer | Außenbauteil | Reference | Drehwinkel = Slope (deg)
Stahlträger | Wartung_FFB | 1 | Stahlträger | HEA 280 | 1.644 | Wartung_FFB | 61.05 | 79.372 | 6.806 | 61.05 | 70.752 | 6.806 | 0 | 0.15 | 0.32 | 0121Tra0000020996 | m | T104c | false | HI_UZT_HEA_STA_0,280_xxx | 0
Stahlträger | Wartung_FFB | 1 | Stahlträger | HEA 280 | 1.644 | Wartung_FFB | 64.05 | 79.372 | 6.806 | 64.05 | 70.752 | 6.806 | 0 | 0.15 | 0.32 | 0121Tra0000021010 | m | T104c | false | HI_UZT_HEA_STA_0,280_xxx | 0
Stahlträger | Wartung_FFB | 1 | Stahlträger | HEA 280 | 1.644 | Wartung_FFB | 67.05 | 79.372 | 6.806 | 67.05 | 70.752 | 6.806 | 0 | 0.15 | 0.32 | 0121Tra0000021018 | m | T104c | false | HI_UZT_HEA_STA_0,280_xxx | 0
Stahlträger | Wartung_FFB | 1 | Stahlträger | HEA 280 | 1.644 | Wartung_FFB | 70.05 | 79.372 | 6.806 | 70.05 | 70.752 | 6.806 | 0 | 0.15 | 0.32 | 0121Tra0000021026 | m | T104c | false | HI_UZT_HEA_STA_0,280_xxx | 0
Stahlträger | Wartung_FFB | 1 | Stahlträger | HEA 280 | 1.644 | Wartung_FFB | 73.05 | 79.372 | 6.806 | 73.05 | 70.752 | 6.806 | 0 | 0.15 | 0.32 | 0121Tra0000021034 | m | T104c | false | HI_UZT_HEA_STA_0,280_xxx | 0
Stahlträger | Wartung_FFB | 1 | Stahlträger | HEA 280 | 1.644 | Wartung_FFB | 52.05 | 79.372 | 6.806 | 52.05 | 70.752 | 6.806 | 0 | 0.15 | 0.32 | 0121Tra0000021058 | m | T104c | false | HI_UZT_HEA_STA_0,280_xxx | 0
Stahlträger | Wartung_FFB | 1 | Stahlträger | HEA 280 | 1.644 | Wartung_FFB | 55.05 | 79.372 | 6.806 | 55.05 | 70.752 | 6.806 | 0 | 0.15 | 0.32 | 0121Tra0000021062 | m | T104c | false | HI_UZT_HEA_STA_0,280_xxx | 0
Stahlträger | Wartung_FFB | 1 | Stahlträger | HEA 280 | 1.644 | Wartung_FFB | 58.05 | 79.372 | 6.806 | 58.05 | 70.752 | 6.806 | 0 | 0.15 | 0.32 | 0121Tra0000021066 | m | T104c | false | HI_UZT_HEA_STA_0,280_xxx | 0
Stahlträger | Wartung_FFB | 1 | Stahlträger | HEA 500 | 2.156 | Wartung_FFB | 79.05 | 81.843 | 6.696 | 79.05 | 70.752 | 6.696 | 0 | 0.15 | 0.32 | 0121Tra0000014909 | m | T104d | false | HI_UZT_HEA_STA_0,500_xxx | 0
Stahlträger | Wartung_FFB | 1 | Stahlträger | HEA 500 | 2.156 | Wartung_FFB | 76.05 | 81.843 | 6.696 | 76.05 | 70.752 | 6.696 | 0 | 0.15 | 0.32 | 0121Tra0000014912 | m | T104d | false | HI_UZT_HEA_STA_0,500_xxx | 0
Stahlträger | Wartung_FFB | 1 | Stahlträger | HEA 360 | 1.88 | Wartung_FFB | 84.35 | 81.024 | 6.766 | 84.35 | 70.752 | 6.766 | 0 | 0.15 | 0.32 | 0121Tra0000021086 | m | T104e | false | HI_UZT_HEA_STA_0,360_xxx | 0
Stahlträger | Wartung_FFB | 1 | Stahlträger | HEA 360 | 1.88 | Wartung_FFB | 86.75 | 81.024 | 6.766 | 86.75 | 70.752 | 6.766 | 0 | 0.15 | 0.32 | 0121Tra0000021102 | m | T104e | false | HI_UZT_HEA_STA_0,360_xxx | 0
Stahlträger | Wartung_FFB | 1 | Stahlträger | HEA 360 | 1.88 | Wartung_FFB | 89.5 | 81.024 | 6.766 | 89.5 | 70.752 | 6.766 | 0 | 0.15 | 0.32 | 0121Tra0000021110 | m | T104e | false | HI_UZT_HEA_STA_0,360_xxx | 0
Stahlträger | Wartung_FFB | 1 | Stahlträger | HEA 360 | 1.88 | Wartung_FFB | 91.9 | 81.024 | 6.766 | 91.9 | 70.752 | 6.766 | 0 | 0.15 | 0.32 | 0121Tra0000021118 | m | T104e | false | HI_UZT_HEA_STA_0,360_xxx | 0
Stahlträger | Wartung_FFB | 1 | Stahlträger | HEA 320 | 1.802 | Wartung_FFB | 94.05 | 70.752 | 6.786 | 94.05 | 81.024 | 6.786 | 0 | 0.15 | 0.32 | 0121Tra0000021126 | m | T104f | false | HI_UZT_HEA_STA_0,320_xxx | 0
Stahlträger | Wartung_FFB | 1 | Stahlträger | HEA 320 | 1.802 | Wartung_FFB | 97.05 | 70.752 | 6.786 | 97.05 | 81.024 | 6.786 | 0 | 0.15 | 0.32 | 0121Tra0000021133 | m | T104f | false | HI_UZT_HEA_STA_0,320_xxx | 0
Stahlträger | Wartung_FFB | 1 | Stahlträger | HEA 450 | 2.057 | Wartung_FFB | 103.05 | 70.752 | 6.721 | 103.05 | 81.843 | 6.721 | 0 | 0.15 | 0.32 | 0121Tra0000021157 | m | T104 | false | HI_UZT_HEA_STA_0,450_xxx | 0
Stahlträger | Wartung_FFB | 1 | Stahlträger | HEA 450 | 2.057 | Wartung_FFB | 106.05 | 70.752 | 6.721 | 106.05 | 81.843 | 6.721 | 0 | 0.15 | 0.32 | 0121Tra0000021165 | m | T104 | false | HI_UZT_HEA_STA_0,450_xxx | 0
Stahlträger | Wartung_FFB | 1 | Stahlträger | HEA 450 | 2.057 | Wartung_FFB | 109.05 | 70.752 | 6.721 | 109.05 | 81.843 | 6.721 | 0 | 0.15 | 0.32 | 0121Tra0000021173 | m | T104 | false | HI_UZT_HEA_STA_0,450_xxx | 0
Stahlträger | Wartung_FFB | 1 | Stahlträger | HEA 450 | 2.057 | Wartung_FFB | 112.05 | 70.752 | 6.721 | 112.05 | 81.843 | 6.721 | 0 | 0.15 | 0.32 | 0121Tra0000021181 | m | T104 | false | HI_UZT_HEA_STA_0,450_xxx | 0
Stahlträger | Wartung_FFB | 1 | Stahlträger | HEA 450 | 2.057 | Wartung_FFB | 115.05 | 70.752 | 6.721 | 115.05 | 81.843 | 6.721 | 0 | 0.15 | 0.32 | 0121Tra0000021189 | m | T104 | false | HI_UZT_HEA_STA_0,450_xxx | 0
Stahlträger | Wartung_FFB | 1 | Stahlträger | HEA 450 | 2.057 | Wartung_FFB | 118.05 | 70.752 | 6.721 | 118.05 | 81.843 | 6.721 | 0 | 0.15 | 0.32 | 0121Tra0000021197 | m | T104 | false | HI_UZT_HEA_STA_0,450_xxx | 0
Stahlträger | Wartung_FFB | 1 | Stahlträger | HEA 450 | 2.057 | Wartung_FFB | 120.75 | 70.752 | 6.721 | 120.75 | 81.843 | 6.721 | 0 | 0.15 | 0.32 | 0121Tra0000021205 | m | T104 | false | HI_UZT_HEA_STA_0,450_xxx | 0
Stahlträger | Wartung_FFB | 1 | Stahlträger | HEA 400 | 1.958 | Wartung_FFB | 19.28 | 70.752 | 6.746 | 19.28 | 81.843 | 6.746 | 0 | 0.15 | 0.32 | 0121Tra0000020929 | m | T104a | false | HI_UZT_HEA_STA_0,400_xxx | 0
Stahlträger | Wartung_FFB | 1 | Stahlträger | HEA 360 | 1.88 | Wartung_FFB | 82.18 | 81.024 | 6.766 | 82.18 | 70.752 | 6.766 | 0 | 0.15 | 0.32 | 0121Tra0000021094 | m | T104e | false | HI_UZT_HEA_STA_0,360_xxx | 0
Stahlträger | Wartung_FFB | 1 | Stahlträger | HEA 500 | 2.156 | Wartung_FFB | 99.82 | 81.843 | 6.696 | 99.82 | 70.752 | 6.696 | 0 | 0.15 | 0.32 | 0121Tra0000021144 | m | T104d | false | HI_UZT_HEA_STA_0,500_xxx | 0
Stahlträger | Wartung_FFB | 1 | Stahlträger | HEA 300 | 1.763 | Wartung_FFB | 13.05 | 70.052 | 6.796 | 13.05 | 58.993 | 6.796 | 0 | 0.15 | 0.32 | 0121Tra0000014237 | m | T103a | false | HI_UZT_HEA_STA_0,300_xxx | 0
Stahlträger | Wartung_FFB | 1 | Stahlträger | HEA 300 | 1.763 | Wartung_FFB | 10.55 | 70.052 | 6.796 | 10.55 | 58.993 | 6.796 | 0 | 0.15 | 0.32 | 0121Tra0000014247 | m | T103a | false | HI_UZT_HEA_STA_0,300_xxx | 0
Stahlträger | Wartung_FFB | 1 | Stahlträger | HEA 300 | 1.763 | Wartung_FFB | 16.05 | 70.052 | 6.796 | 16.05 | 58.993 | 6.796 | 0 | 0.15 | 0.32 | 0121Tra0000020591 | m | T103a | false | HI_UZT_HEA_STA_0,300_xxx | 0
Stahlträger | Wartung_FFB | 1 | Stahlträger | HEA 360 | 1.88 | Wartung_FFB | 22.05 | 70.052 | 6.766 | 22.05 | 63.632 | 6.766 | 0 | 0.15 | 0.32 | 0121Tra0000020615 | m | T103c | false | HI_UZT_HEA_STA_0,360_xxx | 0
Stahlträger | Wartung_FFB | 1 | Stahlträger | HEA 360 | 1.88 | Wartung_FFB | 32.25 | 70.052 | 6.766 | 32.25 | 63.632 | 6.766 | 0 | 0.15 | 0.32 | 0121Tra0000020657 | m | T103c | false | HI_UZT_HEA_STA_0,360_xxx | 0
Stahlträger | Wartung_FFB | 1 | Stahlträger | HEA 360 | 1.88 | Wartung_FFB | 34.05 | 70.052 | 6.766 | 34.05 | 63.632 | 6.766 | 0 | 0.15 | 0.32 | 0121Tra0000020665 | m | T103c | false | HI_UZT_HEA_STA_0,360_xxx | 0
Stahlträger | Wartung_FFB | 1 | Stahlträger | HEA 360 | 1.88 | Wartung_FFB | 37.05 | 70.052 | 6.766 | 37.05 | 63.632 | 6.766 | 0 | 0.15 | 0.32 | 0121Tra0000020673 | m | T103c | false | HI_UZT_HEA_STA_0,360_xxx | 0
Stahlträger | Wartung_FFB | 1 | Stahlträger | HEA 360 | 1.88 | Wartung_FFB | 40.05 | 70.052 | 6.766 | 40.05 | 63.632 | 6.766 | 0 | 0.15 | 0.32 | 0121Tra0000020685 | m | T103c | false | HI_UZT_HEA_STA_0,360_xxx | 0
Stahlträger | Wartung_FFB | 1 | Stahlträger | HEA 360 | 1.88 | Wartung_FFB | 43.05 | 70.052 | 6.766 | 43.05 | 63.632 | 6.766 | 0 | 0.15 | 0.32 | 0121Tra0000020689 | m | T103c | false | HI_UZT_HEA_STA_0,360_xxx | 0
Stahlträger | Wartung_FFB | 1 | Stahlträger | HEA 360 | 1.88 | Wartung_FFB | 28.05 | 70.052 | 6.766 | 28.05 | 63.632 | 6.766 | 0 | 0.15 | 0.32 | 0121Tra0000020641 | m | T103d | false | HI_UZT_HEA_STA_0,360_xxx | 0
Stahlträger | Wartung_FFB | 1 | Stahlträger | HEA 360 | 1.88 | Wartung_FFB | 29.6 | 70.052 | 6.766 | 29.6 | 63.632 | 6.766 | 0 | 0.15 | 0.32 | 0121Tra0000020649 | m | T103d | false | HI_UZT_HEA_STA_0,360_xxx | 0
Stahlträger | Wartung_FFB | 1 | Stahlträger | HEA 400 | 1.958 | Wartung_FFB | 49.05 | 63.632 | 6.746 | 49.05 | 70.052 | 6.746 | 0 | 0.15 | 0.32 | 0121Tra0000020708 | m | T103e | false | HI_UZT_HEA_STA_0,400_xxx | 0
Stahlträger | Wartung_FFB | 1 | Stahlträger | HEA 450 | 2.057 | Wartung_FFB | 52.05 | 65.52 | 6.721 | 52.05 | 70.052 | 6.721 | 0 | 0.15 | 0.32 | 0121Tra0000020720 | m | T103f | false | HI_UZT_HEA_STA_0,450_xxx | 0
Stahlträger | Wartung_FFB | 1 | Stahlträger | HEA 450 | 2.057 | Wartung_FFB | 55.05 | 65.52 | 6.721 | 55.05 | 70.052 | 6.721 | 0 | 0.15 | 0.32 | 0121Tra0000020727 | m | T103f | false | HI_UZT_HEA_STA_0,450_xxx | 0
Stahlträger | Wartung_FFB | 1 | Stahlträger | HEA 450 | 2.057 | Wartung_FFB | 67.05 | 65.52 | 6.721 | 67.05 | 70.052 | 6.721 | 0 | 0.15 | 0.32 | 0121Tra0000020743 | m | T103f | false | HI_UZT_HEA_STA_0,450_xxx | 0
Stahlträger | Wartung_FFB | 1 | Stahlträger | HEA 450 | 2.057 | Wartung_FFB | 70.05 | 65.52 | 6.721 | 70.05 | 70.052 | 6.721 | 0 | 0.15 | 0.32 | 0121Tra0000020747 | m | T103f | false | HI_UZT_HEA_STA_0,450_xxx | 0
Stahlträger | Wartung_FFB | 1 | Stahlträger | HEA 450 | 2.057 | Wartung_FFB | 73.05 | 65.52 | 6.721 | 73.05 | 70.052 | 6.721 | 0 | 0.15 | 0.32 | 0121Tra0000020755 | m | T103f | false | HI_UZT_HEA_STA_0,450_xxx | 0
Stahlträger | Wartung_FFB | 1 | Stahlträger | HEA 280 | 1.644 | Wartung_FFB | 58.05 | 70.052 | 6.806 | 58.05 | 65.52 | 6.806 | 0 | 0.15 | 0.32 | 0121Tra0000020772 | m | T103g | false | HI_UZT_HEA_STA_0,280_xxx | 0
Stahlträger | Wartung_FFB | 1 | Stahlträger | HEA 280 | 1.644 | Wartung_FFB | 61.05 | 70.052 | 6.806 | 61.05 | 65.52 | 6.806 | 0 | 0.15 | 0.32 | 0121Tra0000020786 | m | T103g | false | HI_UZT_HEA_STA_0,280_xxx | 0
Stahlträger | Wartung_FFB | 1 | Stahlträger | HEA 280 | 1.644 | Wartung_FFB | 64.05 | 70.052 | 6.806 | 64.05 | 65.52 | 6.806 | 0 | 0.15 | 0.32 | 0121Tra0000020799 | m | T103h | false | HI_UZT_HEA_STA_0,280_xxx | 0
Stahlträger | Wartung_FFB | 1 | Stahlträger | HEA 650 | 2.453 | Wartung_FFB | 81.55 | 70.052 | 6.621 | 81.55 | 66.235 | 6.621 | 0 | 0.15 | 0.32 | 0121Tra0000014546 | m | T103i | false | HI_UZT_HEA_STA_0,650_xxx | 0
Stahlträger | Wartung_FFB | 1 | Stahlträger | HEA 650 | 2.453 | Wartung_FFB | 84.35 | 70.052 | 6.621 | 84.35 | 66.235 | 6.621 | 0 | 0.15 | 0.32 | 0121Tra0000014555 | m | T103i | false | HI_UZT_HEA_STA_0,650_xxx | 0
Stahlträger | Wartung_FFB | 1 | Stahlträger | HEA 650 | 2.453 | Wartung_FFB | 91.9 | 70.052 | 6.621 | 91.9 | 66.235 | 6.621 | 0 | 0.15 | 0.32 | 0121Tra0000015001 | m | T103i | false | HI_UZT_HEA_STA_0,650_xxx | 0
Stahlträger | Wartung_FFB | 1 | Stahlträger | HEA 650 | 2.453 | Wartung_FFB | 86.75 | 70.052 | 6.621 | 86.75 | 66.235 | 6.621 | 0 | 0.15 | 0.32 | 0121Tra0000014552 | m | T103i | false | HI_UZT_HEA_STA_0,650_xxx | 0
Stahlträger | Wartung_FFB | 1 | Stahlträger | HEA 650 | 2.453 | Wartung_FFB | 89.5 | 70.052 | 6.621 | 89.5 | 66.235 | 6.621 | 0 | 0.15 | 0.32 | 0121Tra0000014549 | m | T103i | false | HI_UZT_HEA_STA_0,650_xxx | 0
Stahlträger | Wartung_FFB | 1 | Stahlträger | HEA 550 | 2.255 | Wartung_FFB | 94.7 | 70.052 | 6.671 | 94.7 | 66.235 | 6.671 | 0 | 0.15 | 0.32 | 0121Tra0000015467 | m | T103 | false | HI_UZT_HEA_STA_0,550_xxx | 0
Stahlträger | Wartung_FFB | 1 | Stahlträger | HEA 600 | 2.354 | Wartung_FFB | 97.05 | 70.052 | 6.646 | 97.05 | 66.235 | 6.646 | 0 | 0.15 | 0.32 | 0121Tra0000015563 | m | T103j | false | HI_UZT_HEA_STA_0,600_xxx | 0
Stahlträger | Wartung_FFB | 1 | Stahlträger | HEA 550 | 2.255 | Wartung_FFB | 103.05 | 70.052 | 6.671 | 103.05 | 66.235 | 6.671 | 0 | 0.15 | 0.32 | 0121Tra0000015482 | m | T103 | false | HI_UZT_HEA_STA_0,550_xxx | 0
Stahlträger | Wartung_FFB | 1 | Stahlträger | HEA 550 | 2.255 | Wartung_FFB | 106.05 | 70.052 | 6.671 | 106.05 | 66.235 | 6.671 | 0 | 0.15 | 0.32 | 0121Tra0000015494 | m | T103 | false | HI_UZT_HEA_STA_0,550_xxx | 0
Stahlträger | Wartung_FFB | 1 | Stahlträger | HEA 550 | 2.255 | Wartung_FFB | 109.05 | 70.052 | 6.671 | 109.05 | 66.235 | 6.671 | 0 | 0.15 | 0.32 | 0121Tra0000015506 | m | T103 | false | HI_UZT_HEA_STA_0,550_xxx | 0
Stahlträger | Wartung_FFB | 1 | Stahlträger | HEA 550 | 2.255 | Wartung_FFB | 112.05 | 70.052 | 6.671 | 112.05 | 66.235 | 6.671 | 0 | 0.15 | 0.32 | 0121Tra0000015518 | m | T103 | false | HI_UZT_HEA_STA_0,550_xxx | 0
Stahlträger | Wartung_FFB | 1 | Stahlträger | HEA 550 | 2.255 | Wartung_FFB | 115.05 | 70.052 | 6.671 | 115.05 | 66.235 | 6.671 | 0 | 0.15 | 0.32 | 0121Tra0000015530 | m | T103 | false | HI_UZT_HEA_STA_0,550_xxx | 0
Stahlträger | Wartung_FFB | 1 | Stahlträger | HEA 550 | 2.255 | Wartung_FFB | 118.05 | 70.052 | 6.671 | 118.05 | 66.235 | 6.671 | 0 | 0.15 | 0.32 | 0121Tra0000015542 | m | T103 | false | HI_UZT_HEA_STA_0,550_xxx | 0
Stahlträger | Wartung_FFB | 1 | Stahlträger | HEA 550 | 2.255 | Wartung_FFB | 120.75 | 70.052 | 6.671 | 120.75 | 66.235 | 6.671 | 0 | 0.15 | 0.32 | 0121Tra0000015554 | m | T103 | false | HI_UZT_HEA_STA_0,550_xxx | 0
Stahlträger | Wartung_FFB | 1 | Stahlträger | HEA 550 | 2.255 | Wartung_FFB | 76.05 | 70.052 | 6.671 | 76.05 | 66.235 | 6.671 | 0 | 0.15 | 0.32 | 0121Tra0000020903 | m | T103 | false | HI_UZT_HEA_STA_0,550_xxx | 0
Stahlträger | Wartung_FFB | 1 | Stahlträger | HEA 550 | 2.255 | Wartung_FFB | 79.05 | 70.052 | 6.671 | 79.05 | 66.235 | 6.671 | 0 | 0.15 | 0.32 | 0121Tra0000020905 | m | T103 | false | HI_UZT_HEA_STA_0,550_xxx | 0
Stahlträger | Wartung_FFB | 1 | Stahlträger | HEA 360 | 1.88 | Wartung_FFB | 25.503 | 70.052 | 6.766 | 25.503 | 63.632 | 6.766 | 0 | 0.15 | 0.32 | 0121Tra0000020632 | m | T103d | false | HI_UZT_HEA_STA_0,360_xxx | 0
Stahlträger | Wartung_FFB | 1 | Stahlträger | HEA 400 | 1.958 | Wartung_FFB | 45.92 | 63.632 | 6.746 | 45.92 | 70.052 | 6.746 | 0 | 0.15 | 0.32 | 0121Tra0000020701 | m | T103e | false | HI_UZT_HEA_STA_0,400_xxx | 0
Stahlträger | Wartung_FFB | 1 | Stahlträger | HEA 240 | 1.405 | Wartung_FFB | 19.28 | 70.052 | 6.826 | 19.28 | 63.632 | 6.826 | 0 | 0.15 | 0.32 | 0121Tra0000020611 | m | T103b | false | HI_UZT_HEA_STA_0,240_xxx | 0
Stahlträger | Wartung_FFB | 1 | Stahlträger | HEA 600 | 2.354 | Wartung_FFB | 99.82 | 70.052 | 6.646 | 99.82 | 66.235 | 6.646 | 0 | 0.15 | 0.32 | 0121Tra0000015580 | m | T103j | false | HI_UZT_HEA_STA_0,600_xxx | 0
Stahlträger | Wartung_FFB | 1 | Stahlträger | HEA 300 | 1.763 | Wartung_FFB | 13.05 | 58.643 | 6.796 | 13.05 | 52.15 | 6.796 | 0 | 0.15 | 0.32 | 0121Tra0000014230 | m | T103a | false | HI_UZT_HEA_STA_0,300_xxx | 0
Stahlträger | Wartung_FFB | 1 | Stahlträger | HEA 300 | 1.763 | Wartung_FFB | 10.55 | 58.643 | 6.796 | 10.55 | 52.15 | 6.796 | 0 | 0.15 | 0.32 | 0121Tra0000014243 | m | T103a | false | HI_UZT_HEA_STA_0,300_xxx | 0
Stahlträger | Wartung_FFB | 1 | Stahlträger | HEA 300 | 1.763 | Wartung_FFB | 16.05 | 58.643 | 6.796 | 16.05 | 52.15 | 6.796 | 0 | 0.15 | 0.32 | 0121Tra0000020589 | m | T103a | false | HI_UZT_HEA_STA_0,300_xxx | 0
Stahlträger | Wartung_FFB | 1 | Stahlträger | HEA 240 | 1.405 | Wartung_FFB | 19.05 | 58.643 | 6.826 | 19.05 | 52.15 | 6.826 | 0 | 0.15 | 0.32 | 0121Tra0000014285 | m | T103b | false | HI_UZT_HEA_STA_0,240_xxx | 0
Stahlträger | Wartung_FFB | 1 | Stahlträger | HEA 360 | 1.88 | Wartung_FFB | 22.05 | 63.282 | 6.766 | 22.05 | 52.15 | 6.766 | 0 | 0.15 | 0.32 | 0121Tra0000020626 | m | T103c | false | HI_UZT_HEA_STA_0,360_xxx | 0
Stahlträger | Wartung_FFB | 1 | Stahlträger | HEA 360 | 1.88 | Wartung_FFB | 32.25 | 63.282 | 6.766 | 32.25 | 52.15 | 6.766 | 0 | 0.15 | 0.32 | 0121Tra0000020659 | m | T103c | false | HI_UZT_HEA_STA_0,360_xxx | 0
Stahlträger | Wartung_FFB | 1 | Stahlträger | HEA 360 | 1.88 | Wartung_FFB | 34.05 | 63.282 | 6.766 | 34.05 | 52.15 | 6.766 | 0 | 0.15 | 0.32 | 0121Tra0000020667 | m | T103c | false | HI_UZT_HEA_STA_0,360_xxx | 0
Stahlträger | Wartung_FFB | 1 | Stahlträger | HEA 360 | 1.88 | Wartung_FFB | 37.05 | 63.282 | 6.766 | 37.05 | 52.15 | 6.766 | 0 | 0.15 | 0.32 | 0121Tra0000020675 | m | T103c | false | HI_UZT_HEA_STA_0,360_xxx | 0
Stahlträger | Wartung_FFB | 1 | Stahlträger | HEA 360 | 1.88 | Wartung_FFB | 40.05 | 63.282 | 6.766 | 40.05 | 52.15 | 6.766 | 0 | 0.15 | 0.32 | 0121Tra0000020687 | m | T103c | false | HI_UZT_HEA_STA_0,360_xxx | 0
Stahlträger | Wartung_FFB | 1 | Stahlträger | HEA 360 | 1.88 | Wartung_FFB | 43.05 | 63.282 | 6.766 | 43.05 | 52.15 | 6.766 | 0 | 0.15 | 0.32 | 0121Tra0000020691 | m | T103c | false | HI_UZT_HEA_STA_0,360_xxx | 0
Stahlträger | Wartung_FFB | 1 | Stahlträger | HEA 360 | 1.88 | Wartung_FFB | 28.05 | 63.282 | 6.766 | 28.05 | 52.15 | 6.766 | 0 | 0.15 | 0.32 | 0121Tra0000020643 | m | T103d | false | HI_UZT_HEA_STA_0,360_xxx | 0
Stahlträger | Wartung_FFB | 1 | Stahlträger | HEA 360 | 1.88 | Wartung_FFB | 29.6 | 63.282 | 6.766 | 29.6 | 52.15 | 6.766 | 0 | 0.15 | 0.32 | 0121Tra0000020651 | m | T103d | false | HI_UZT_HEA_STA_0,360_xxx | 0
Stahlträger | Wartung_FFB | 1 | Stahlträger | HEA 400 | 1.958 | Wartung_FFB | 49.05 | 52.15 | 6.746 | 49.05 | 63.282 | 6.746 | 0 | 0.15 | 0.32 | 0121Tra0000020705 | m | T103e | false | HI_UZT_HEA_STA_0,400_xxx | 0
Stahlträger | Wartung_FFB | 1 | Stahlträger | HEA 450 | 2.057 | Wartung_FFB | 52.05 | 52.15 | 6.721 | 52.05 | 65.17 | 6.721 | 0 | 0.15 | 0.32 | 0121Tra0000020715 | m | T103f | false | HI_UZT_HEA_STA_0,450_xxx | 0
Stahlträger | Wartung_FFB | 1 | Stahlträger | HEA 450 | 2.057 | Wartung_FFB | 55.05 | 52.15 | 6.721 | 55.05 | 65.17 | 6.721 | 0 | 0.15 | 0.32 | 0121Tra0000020724 | m | T103f | false | HI_UZT_HEA_STA_0,450_xxx | 0
Stahlträger | Wartung_FFB | 1 | Stahlträger | HEA 450 | 2.057 | Wartung_FFB | 67.05 | 52.15 | 6.721 | 67.05 | 65.17 | 6.721 | 0 | 0.15 | 0.32 | 0121Tra0000020741 | m | T103f | false | HI_UZT_HEA_STA_0,450_xxx | 0
Stahlträger | Wartung_FFB | 1 | Stahlträger | HEA 450 | 2.057 | Wartung_FFB | 70.05 | 52.15 | 6.721 | 70.05 | 65.17 | 6.721 | 0 | 0.15 | 0.32 | 0121Tra0000020745 | m | T103f | false | HI_UZT_HEA_STA_0,450_xxx | 0
Stahlträger | Wartung_FFB | 1 | Stahlträger | HEA 450 | 2.057 | Wartung_FFB | 73.05 | 52.15 | 6.721 | 73.05 | 65.17 | 6.721 | 0 | 0.15 | 0.32 | 0121Tra0000020753 | m | T103f | false | HI_UZT_HEA_STA_0,450_xxx | 0
Stahlträger | Wartung_FFB | 1 | Stahlträger | HEA 280 | 1.644 | Wartung_FFB | 58.05 | 57.305 | 6.806 | 58.05 | 52.15 | 6.806 | 0 | 0.15 | 0.32 | 0121Tra0000020768 | m | T103g | false | HI_UZT_HEA_STA_0,280_xxx | 0
Stahlträger | Wartung_FFB | 1 | Stahlträger | HEA 280 | 1.644 | Wartung_FFB | 61.05 | 57.305 | 6.806 | 61.05 | 52.15 | 6.806 | 0 | 0.15 | 0.32 | 0121Tra0000020783 | m | T103g | false | HI_UZT_HEA_STA_0,280_xxx | 0
Stahlträger | Wartung_FFB | 1 | Stahlträger | HEA 280 | 1.644 | Wartung_FFB | 64.05 | 57.305 | 6.806 | 64.05 | 52.15 | 6.806 | 0 | 0.15 | 0.32 | 0121Tra0000020797 | m | T103h | false | HI_UZT_HEA_STA_0,280_xxx | 0
Stahlträger | Wartung_FFB | 1 | Stahlträger | HEA 650 | 2.453 | Wartung_FFB | 81.55 | 66.185 | 6.621 | 81.55 | 52.15 | 6.621 | 0 | 0.15 | 0.32 | 0121Tra0000015286 | m | T103i | false | HI_UZT_HEA_STA_0,650_xxx | 0
Stahlträger | Wartung_FFB | 1 | Stahlträger | HEA 650 | 2.453 | Wartung_FFB | 84.35 | 66.185 | 6.621 | 84.35 | 52.15 | 6.621 | 0 | 0.15 | 0.32 | 0121Tra0000015290 | m | T103i | false | HI_UZT_HEA_STA_0,650_xxx | 0
Stahlträger | Wartung_FFB | 1 | Stahlträger | HEA 650 | 2.453 | Wartung_FFB | 91.9 | 66.185 | 6.621 | 91.9 | 52.15 | 6.621 | 0 | 0.15 | 0.32 | 0121Tra0000015292 | m | T103i | false | HI_UZT_HEA_STA_0,650_xxx | 0
Stahlträger | Wartung_FFB | 1 | Stahlträger | HEA 650 | 2.453 | Wartung_FFB | 86.75 | 66.185 | 6.621 | 86.75 | 52.15 | 6.621 | 0 | 0.15 | 0.32 | 0121Tra0000015294 | m | T103i | false | HI_UZT_HEA_STA_0,650_xxx | 0
Stahlträger | Wartung_FFB | 1 | Stahlträger | HEA 650 | 2.453 | Wartung_FFB | 89.5 | 66.185 | 6.621 | 89.5 | 52.15 | 6.621 | 0 | 0.15 | 0.32 | 0121Tra0000015296 | m | T103i | false | HI_UZT_HEA_STA_0,650_xxx | 0
Stahlträger | Wartung_FFB | 1 | Stahlträger | HEA 550 | 2.255 | Wartung_FFB | 94.7 | 66.185 | 6.671 | 94.7 | 52.15 | 6.671 | 0 | 0.15 | 0.32 | 0121Tra0000015459 | m | T103 | false | HI_UZT_HEA_STA_0,550_xxx | 0
Stahlträger | Wartung_FFB | 1 | Stahlträger | HEA 600 | 2.354 | Wartung_FFB | 97.05 | 66.185 | 6.646 | 97.05 | 52.15 | 6.646 | 0 | 0.15 | 0.32 | 0121Tra0000015561 | m | T103j | false | HI_UZT_HEA_STA_0,600_xxx | 0
Stahlträger | Wartung_FFB | 1 | Stahlträger | HEA 550 | 2.255 | Wartung_FFB | 103.05 | 66.185 | 6.671 | 103.05 | 52.15 | 6.671 | 0 | 0.15 | 0.32 | 0121Tra0000015480 | m | T103 | false | HI_UZT_HEA_STA_0,550_xxx | 0
Stahlträger | Wartung_FFB | 1 | Stahlträger | HEA 550 | 2.255 | Wartung_FFB | 106.05 | 66.185 | 6.671 | 106.05 | 52.15 | 6.671 | 0 | 0.15 | 0.32 | 0121Tra0000015492 | m | T103 | false | HI_UZT_HEA_STA_0,550_xxx | 0
Stahlträger | Wartung_FFB | 1 | Stahlträger | HEA 550 | 2.255 | Wartung_FFB | 109.05 | 66.185 | 6.671 | 109.05 | 52.15 | 6.671 | 0 | 0.15 | 0.32 | 0121Tra0000015504 | m | T103 | false | HI_UZT_HEA_STA_0,550_xxx | 0
Stahlträger | Wartung_FFB | 1 | Stahlträger | HEA 550 | 2.255 | Wartung_FFB | 112.05 | 66.185 | 6.671 | 112.05 | 52.15 | 6.671 | 0 | 0.15 | 0.32 | 0121Tra0000015516 | m | T103 | false | HI_UZT_HEA_STA_0,550_xxx | 0
Stahlträger | Wartung_FFB | 1 | Stahlträger | HEA 550 | 2.255 | Wartung_FFB | 115.05 | 66.185 | 6.671 | 115.05 | 52.15 | 6.671 | 0 | 0.15 | 0.32 | 0121Tra0000015528 | m | T103 | false | HI_UZT_HEA_STA_0,550_xxx | 0
Stahlträger | Wartung_FFB | 1 | Stahlträger | HEA 550 | 2.255 | Wartung_FFB | 118.05 | 66.185 | 6.671 | 118.05 | 52.15 | 6.671 | 0 | 0.15 | 0.32 | 0121Tra0000015540 | m | T103 | false | HI_UZT_HEA_STA_0,550_xxx | 0
Stahlträger | Wartung_FFB | 1 | Stahlträger | HEA 550 | 2.255 | Wartung_FFB | 120.75 | 66.185 | 6.671 | 120.75 | 52.15 | 6.671 | 0 | 0.15 | 0.32 | 0121Tra0000015552 | m | T103 | false | HI_UZT_HEA_STA_0,550_xxx | 0
Stahlträger | Wartung_FFB | 1 | Stahlträger | HEA 550 | 2.255 | Wartung_FFB | 76.05 | 66.185 | 6.671 | 76.05 | 52.15 | 6.671 | 0 | 0.15 | 0.32 | 0121Tra0000020899 | m | T103 | false | HI_UZT_HEA_STA_0,550_xxx | 0
Stahlträger | Wartung_FFB | 1 | Stahlträger | HEA 550 | 2.255 | Wartung_FFB | 79.05 | 66.185 | 6.671 | 79.05 | 52.15 | 6.671 | 0 | 0.15 | 0.32 | 0121Tra0000020901 | m | T103 | false | HI_UZT_HEA_STA_0,550_xxx | 0
Stahlträger | Wartung_FFB | 1 | Stahlträger | HEA 360 | 1.88 | Wartung_FFB | 25.503 | 63.282 | 6.766 | 25.503 | 52.15 | 6.766 | 0 | 0.15 | 0.32 | 0121Tra0000020635 | m | T103d | false | HI_UZT_HEA_STA_0,360_xxx | 0
Stahlträger | Wartung_FFB | 1 | Stahlträger | HEA 400 | 1.958 | Wartung_FFB | 45.92 | 52.15 | 6.746 | 45.92 | 63.282 | 6.746 | 0 | 0.15 | 0.32 | 0121Tra0000020694 | m | T103e | false | HI_UZT_HEA_STA_0,400_xxx | 0
Stahlträger | Wartung_FFB | 1 | Stahlträger | HEA 600 | 2.354 | Wartung_FFB | 99.82 | 66.185 | 6.646 | 99.82 | 52.15 | 6.646 | 0 | 0.15 | 0.32 | 0121Tra0000015577 | m | T103j | false | HI_UZT_HEA_STA_0,600_xxx | 0
Stahlträger | Wartung_FFB | 1 | Stahlträger | HEA 300 | 1.763 | Wartung_FFB | 10.55 | 51.05 | 6.796 | 10.55 | 47.752 | 6.796 | 0 | 0.15 | 0.32 | 0121Tra0000014102 | m | T102a | false | HI_UZT_HEA_STA_0,300_xxx | 0
Stahlträger | Wartung_FFB | 1 | Stahlträger | HEA 300 | 1.763 | Wartung_FFB | 13.05 | 51.05 | 6.796 | 13.05 | 47.752 | 6.796 | 0 | 0.15 | 0.32 | 0121Tra0000020359 | m | T102a | false | HI_UZT_HEA_STA_0,300_xxx | 0
Stahlträger | Wartung_FFB | 1 | Stahlträger | HEA 360 | 1.88 | Wartung_FFB | 19.05 | 51.05 | 6.766 | 19.05 | 47.752 | 6.766 | 0 | 0.15 | 0.32 | 0121Tra0000014017 | m | T102b | false | HI_UZT_HEA_STA_0,360_xxx | 0
Stahlträger | Wartung_FFB | 1 | Stahlträger | HEA 360 | 1.88 | Wartung_FFB | 16.05 | 51.05 | 6.766 | 16.05 | 47.752 | 6.766 | 0 | 0.15 | 0.32 | 0121Tra0000014028 | m | T102b | false | HI_UZT_HEA_STA_0,360_xxx | 0
Stahlträger | Wartung_FFB | 1 | Stahlträger | HEA 650 | 2.453 | Wartung_FFB | 22.05 | 51.05 | 6.621 | 22.05 | 47.752 | 6.621 | 0 | 0.15 | 0.32 | 0121Tra0000020383 | m | T101&102 | false | HI_UZT_HEA_STA_0,650_xxx | 0
Stahlträger | Wartung_FFB | 1 | Stahlträger | HEA 650 | 2.453 | Wartung_FFB | 49.05 | 51.05 | 6.621 | 49.05 | 47.752 | 6.621 | 0 | 0.15 | 0.32 | 0121Tra0000020412 | m | T101&102 | false | HI_UZT_HEA_STA_0,650_xxx | 0
Stahlträger | Wartung_FFB | 1 | Stahlträger | HEA 650 | 2.453 | Wartung_FFB | 52.05 | 51.05 | 6.621 | 52.05 | 47.752 | 6.621 | 0 | 0.15 | 0.32 | 0121Tra0000020432 | m | T101&102 | false | HI_UZT_HEA_STA_0,650_xxx | 0
Stahlträger | Wartung_FFB | 1 | Stahlträger | HEA 650 | 2.453 | Wartung_FFB | 55.05 | 51.05 | 6.621 | 55.05 | 47.752 | 6.621 | 0 | 0.15 | 0.32 | 0121Tra0000020438 | m | T101&102 | false | HI_UZT_HEA_STA_0,650_xxx | 0
Stahlträger | Wartung_FFB | 1 | Stahlträger | HEA 650 | 2.453 | Wartung_FFB | 67.05 | 51.05 | 6.621 | 67.05 | 47.752 | 6.621 | 0 | 0.15 | 0.32 | 0121Tra0000020451 | m | T101&102 | false | HI_UZT_HEA_STA_0,650_xxx | 0
Stahlträger | Wartung_FFB | 1 | Stahlträger | HEA 500 | 2.156 | Wartung_FFB | 28.05 | 51.05 | 6.696 | 28.05 | 47.757 | 6.696 | 0 | 0.15 | 0.32 | 0121Tra0000013764 | m | T102c | false | HI_UZT_HEA_STA_0,500_xxx | 0
Stahlträger | Wartung_FFB | 1 | Stahlträger | HEA 500 | 2.156 | Wartung_FFB | 34.05 | 51.05 | 6.696 | 34.05 | 47.757 | 6.696 | 0 | 0.15 | 0.32 | 0121Tra0000013807 | m | T102c | false | HI_UZT_HEA_STA_0,500_xxx | 0
Stahlträger | Wartung_FFB | 1 | Stahlträger | HEA 500 | 2.156 | Wartung_FFB | 37.05 | 51.05 | 6.696 | 37.05 | 47.757 | 6.696 | 0 | 0.15 | 0.32 | 0121Tra0000013828 | m | T102c | false | HI_UZT_HEA_STA_0,500_xxx | 0
Stahlträger | Wartung_FFB | 1 | Stahlträger | HEA 500 | 2.156 | Wartung_FFB | 40.05 | 51.05 | 6.696 | 40.05 | 47.757 | 6.696 | 0 | 0.15 | 0.32 | 0121Tra0000013849 | m | T102c | false | HI_UZT_HEA_STA_0,500_xxx | 0
Stahlträger | Wartung_FFB | 1 | Stahlträger | HEA 500 | 2.156 | Wartung_FFB | 32.25 | 51.05 | 6.696 | 32.25 | 47.757 | 6.696 | 0 | 0.15 | 0.32 | 0121Tra0000013964 | m | T102c | false | HI_UZT_HEA_STA_0,500_xxx | 0
Stahlträger | Wartung_FFB | 1 | Stahlträger | HEA 500 | 2.156 | Wartung_FFB | 29.6 | 51.05 | 6.696 | 29.6 | 47.757 | 6.696 | 0 | 0.15 | 0.32 | 0121Tra0000013786 | m | T102c | false | HI_UZT_HEA_STA_0,500_xxx | 0
Stahlträger | Wartung_FFB | 1 | Stahlträger | HEA 500 | 2.156 | Wartung_FFB | 43.05 | 51.05 | 6.696 | 43.05 | 47.757 | 6.696 | 0 | 0.15 | 0.32 | 0121Tra0000015426 | m | T102c | false | HI_UZT_HEA_STA_0,500_xxx | 0
Stahlträger | Wartung_FFB | 1 | Stahlträger | HEA 600 | 2.354 | Wartung_FFB | 58.05 | 51.05 | 6.646 | 58.05 | 49.575 | 6.646 | 0 | 0.15 | 0.32 | 0121Tra0000014110 | m | T102d | false | HI_UZT_HEA_STA_0,600_xxx | 0
Stahlträger | Wartung_FFB | 1 | Stahlträger | HEA 600 | 2.354 | Wartung_FFB | 61.05 | 51.05 | 6.646 | 61.05 | 49.575 | 6.646 | 0 | 0.15 | 0.32 | 0121Tra0000014156 | m | T102d | false | HI_UZT_HEA_STA_0,600_xxx | 0
Stahlträger | Wartung_FFB | 1 | Stahlträger | HEA 600 | 2.354 | Wartung_FFB | 64.05 | 51.05 | 6.646 | 64.05 | 49.575 | 6.646 | 0 | 0.15 | 0.32 | 0121Tra0000014190 | m | T102d | false | HI_UZT_HEA_STA_0,600_xxx | 0
Stahlträger | Wartung_FFB | 1 | Stahlträger | HEA 500 | 2.156 | Wartung_FFB | 25.503 | 51.05 | 6.696 | 25.503 | 47.757 | 6.696 | 0 | 0.15 | 0.32 | 0121Tra0000013732 | m | T102c | false | HI_UZT_HEA_STA_0,500_xxx | 0
Stahlträger | Wartung_FFB | 1 | Stahlträger | HEA 650 | 2.453 | Wartung_FFB | 45.92 | 51.05 | 6.621 | 45.92 | 47.752 | 6.621 | 0 | 0.15 | 0.32 | 0121Tra0000020399 | m | T101&102 | false | HI_UZT_HEA_STA_0,650_xxx | 0
Stahlträger | Wartung_FFB | 1 | Stahlträger | HEA 300 | 1.763 | Wartung_FFB | 10.55 | 39.625 | 6.796 | 10.55 | 31.35 | 6.796 | 0 | 0.15 | 0.32 | 0121Tra0000014093 | m | T102a | false | HI_UZT_HEA_STA_0,300_xxx | 0
Stahlträger | Wartung_FFB | 1 | Stahlträger | HEA 360 | 1.88 | Wartung_FFB | 19.05 | 39.625 | 6.766 | 19.05 | 31.35 | 6.766 | 0 | 0.15 | 0.32 | 0121Tra0000013986 | m | T102b | false | HI_UZT_HEA_STA_0,360_xxx | 0
Stahlträger | Wartung_FFB | 1 | Stahlträger | HEA 360 | 1.88 | Wartung_FFB | 16.05 | 39.625 | 6.766 | 16.05 | 31.35 | 6.766 | 0 | 0.15 | 0.32 | 0121Tra0000014034 | m | T102b | false | HI_UZT_HEA_STA_0,360_xxx | 0
Stahlträger | Wartung_FFB | 1 | Stahlträger | HEA 300 | 1.763 | Wartung_FFB | 13.05 | 39.625 | 6.796 | 13.05 | 31.35 | 6.796 | 0 | 0.15 | 0.32 | 0121Tra0000020353 | m | T102a | false | HI_UZT_HEA_STA_0,300_xxx | 0
Stahlträger | Wartung_FFB | 1 | Stahlträger | HEA 650 | 2.453 | Wartung_FFB | 22.05 | 34.648 | 6.621 | 22.05 | 31.35 | 6.621 | 0 | 0.15 | 0.32 | 0121Tra0000020379 | m | T101&102 | false | HI_UZT_HEA_STA_0,650_xxx | 0
Stahlträger | Wartung_FFB | 1 | Stahlträger | HEA 650 | 2.453 | Wartung_FFB | 49.05 | 34.648 | 6.621 | 49.05 | 31.35 | 6.621 | 0 | 0.15 | 0.32 | 0121Tra0000020408 | m | T101&102 | false | HI_UZT_HEA_STA_0,650_xxx | 0
Stahlträger | Wartung_FFB | 1 | Stahlträger | HEA 650 | 2.453 | Wartung_FFB | 52.05 | 34.648 | 6.621 | 52.05 | 31.35 | 6.621 | 0 | 0.15 | 0.32 | 0121Tra0000020428 | m | T101&102 | false | HI_UZT_HEA_STA_0,650_xxx | 0
Stahlträger | Wartung_FFB | 1 | Stahlträger | HEA 650 | 2.453 | Wartung_FFB | 55.05 | 34.648 | 6.621 | 55.05 | 31.35 | 6.621 | 0 | 0.15 | 0.32 | 0121Tra0000020434 | m | T101&102 | false | HI_UZT_HEA_STA_0,650_xxx | 0
Stahlträger | Wartung_FFB | 1 | Stahlträger | HEA 650 | 2.453 | Wartung_FFB | 67.05 | 34.648 | 6.621 | 67.05 | 31.35 | 6.621 | 0 | 0.15 | 0.32 | 0121Tra0000020447 | m | T101&102 | false | HI_UZT_HEA_STA_0,650_xxx | 0
Stahlträger | Wartung_FFB | 1 | Stahlträger | HEA 500 | 2.156 | Wartung_FFB | 28.05 | 35.905 | 6.696 | 28.05 | 31.35 | 6.696 | 0 | 0.15 | 0.32 | 0121Tra0000013766 | m | T102c | false | HI_UZT_HEA_STA_0,500_xxx | 0
Stahlträger | Wartung_FFB | 1 | Stahlträger | HEA 500 | 2.156 | Wartung_FFB | 34.05 | 35.905 | 6.696 | 34.05 | 31.35 | 6.696 | 0 | 0.15 | 0.32 | 0121Tra0000013809 | m | T102c | false | HI_UZT_HEA_STA_0,500_xxx | 0
Stahlträger | Wartung_FFB | 1 | Stahlträger | HEA 500 | 2.156 | Wartung_FFB | 37.05 | 35.905 | 6.696 | 37.05 | 31.35 | 6.696 | 0 | 0.15 | 0.32 | 0121Tra0000013830 | m | T102c | false | HI_UZT_HEA_STA_0,500_xxx | 0
Stahlträger | Wartung_FFB | 1 | Stahlträger | HEA 500 | 2.156 | Wartung_FFB | 40.05 | 35.905 | 6.696 | 40.05 | 31.35 | 6.696 | 0 | 0.15 | 0.32 | 0121Tra0000013851 | m | T102c | false | HI_UZT_HEA_STA_0,500_xxx | 0
Stahlträger | Wartung_FFB | 1 | Stahlträger | HEA 500 | 2.156 | Wartung_FFB | 32.25 | 35.905 | 6.696 | 32.25 | 31.35 | 6.696 | 0 | 0.15 | 0.32 | 0121Tra0000013966 | m | T102c | false | HI_UZT_HEA_STA_0,500_xxx | 0
Stahlträger | Wartung_FFB | 1 | Stahlträger | HEA 500 | 2.156 | Wartung_FFB | 29.6 | 35.905 | 6.696 | 29.6 | 31.35 | 6.696 | 0 | 0.15 | 0.32 | 0121Tra0000013788 | m | T102c | false | HI_UZT_HEA_STA_0,500_xxx | 0
Stahlträger | Wartung_FFB | 1 | Stahlträger | HEA 500 | 2.156 | Wartung_FFB | 43.05 | 35.905 | 6.696 | 43.05 | 31.35 | 6.696 | 0 | 0.15 | 0.32 | 0121Tra0000015427 | m | T102c | false | HI_UZT_HEA_STA_0,500_xxx | 0
Stahlträger | Wartung_FFB | 1 | Stahlträger | HEA 600 | 2.354 | Wartung_FFB | 58.05 | 34.648 | 6.646 | 58.05 | 31.35 | 6.646 | 0 | 0.15 | 0.32 | 0121Tra0000014139 | m | T102d | false | HI_UZT_HEA_STA_0,600_xxx | 0
Stahlträger | Wartung_FFB | 1 | Stahlträger | HEA 600 | 2.354 | Wartung_FFB | 61.05 | 34.648 | 6.646 | 61.05 | 31.35 | 6.646 | 0 | 0.15 | 0.32 | 0121Tra0000014173 | m | T102d | false | HI_UZT_HEA_STA_0,600_xxx | 0
Stahlträger | Wartung_FFB | 1 | Stahlträger | HEA 600 | 2.354 | Wartung_FFB | 64.05 | 34.648 | 6.646 | 64.05 | 31.35 | 6.646 | 0 | 0.15 | 0.32 | 0121Tra0000014194 | m | T102d | false | HI_UZT_HEA_STA_0,600_xxx | 0
Stahlträger | Wartung_FFB | 1 | Stahlträger | HEA 500 | 2.156 | Wartung_FFB | 25.503 | 35.905 | 6.696 | 25.503 | 31.35 | 6.696 | 0 | 0.15 | 0.32 | 0121Tra0000013734 | m | T102c | false | HI_UZT_HEA_STA_0,500_xxx | 0
Stahlträger | Wartung_FFB | 1 | Stahlträger | HEA 650 | 2.453 | Wartung_FFB | 45.92 | 34.648 | 6.621 | 45.92 | 31.35 | 6.621 | 0 | 0.15 | 0.32 | 0121Tra0000020394 | m | T101&102 | false | HI_UZT_HEA_STA_0,650_xxx | 0
Stahlträger | Wartung_FFB | 1 | Stahlträger | HEA 500 | 2.156 | Wartung_FFB | 10.55 | 30.25 | 6.696 | 10.55 | 26.952 | 6.696 | 0 | 0.15 | 0.32 | 0121Tra0000013396 | m | T101a | false | HI_UZT_HEA_STA_0,500_xxx | 0
Stahlträger | Wartung_FFB | 1 | Stahlträger | HEA 500 | 2.156 | Wartung_FFB | 13.05 | 30.25 | 6.696 | 13.05 | 26.952 | 6.696 | 0 | 0.15 | 0.32 | 0121Tra0000013422 | m | T101a | false | HI_UZT_HEA_STA_0,500_xxx | 0
Stahlträger | Wartung_FFB | 1 | Stahlträger | HEA 650 | 2.453 | Wartung_FFB | 16.05 | 30.25 | 6.621 | 16.05 | 26.952 | 6.621 | 0 | 0.15 | 0.32 | 0121Tra0000015405 | m | T101&102 | false | HI_UZT_HEA_STA_0,650_xxx | 0
Stahlträger | Wartung_FFB | 1 | Stahlträger | HEA 650 | 2.453 | Wartung_FFB | 19.05 | 30.25 | 6.621 | 19.05 | 26.952 | 6.621 | 0 | 0.15 | 0.32 | 0121Tra0000013468 | m | T101&102 | false | HI_UZT_HEA_STA_0,650_xxx | 0
Stahlträger | Wartung_FFB | 1 | Stahlträger | HEA 550 | 2.255 | Wartung_FFB | 28.05 | 30.25 | 6.671 | 28.05 | 28.135 | 6.671 | 0 | 0.15 | 0.32 | 0121Tra0000013289 | m | T101b | false | HI_UZT_HEA_STA_0,550_xxx | 0
Stahlträger | Wartung_FFB | 1 | Stahlträger | HEA 550 | 2.255 | Wartung_FFB | 34.05 | 30.25 | 6.671 | 34.05 | 28.135 | 6.671 | 0 | 0.15 | 0.32 | 0121Tra0000013319 | m | T101b | false | HI_UZT_HEA_STA_0,550_xxx | 0
Stahlträger | Wartung_FFB | 1 | Stahlträger | HEA 550 | 2.255 | Wartung_FFB | 25.55 | 30.25 | 6.671 | 25.55 | 28.135 | 6.671 | 0 | 0.15 | 0.32 | 0121Tra0000013273 | m | T101b | false | HI_UZT_HEA_STA_0,550_xxx | 0
Stahlträger | Wartung_FFB | 1 | Stahlträger | HEA 550 | 2.255 | Wartung_FFB | 32.25 | 30.25 | 6.671 | 32.25 | 28.135 | 6.671 | 0 | 0.15 | 0.32 | 0121Tra0000013304 | m | T101b | false | HI_UZT_HEA_STA_0,550_xxx | 0
Stahlträger | Wartung_FFB | 1 | Stahlträger | HEA 550 | 2.255 | Wartung_FFB | 29.6 | 30.25 | 6.671 | 29.6 | 28.135 | 6.671 | 0 | 0.15 | 0.32 | 0121Tra0000014976 | m | T101b | false | HI_UZT_HEA_STA_0,550_xxx | 0
Stahlträger | Wartung_FFB | 1 | Stahlträger | HEA 550 | 2.255 | Wartung_FFB | 37.05 | 30.25 | 6.671 | 37.05 | 28.135 | 6.671 | 0 | 0.15 | 0.32 | 0121Tra0000015373 | m | T101b | false | HI_UZT_HEA_STA_0,550_xxx | 0
Stahlträger | Wartung_FFB | 1 | Stahlträger | HEA 550 | 2.255 | Wartung_FFB | 40.05 | 30.25 | 6.671 | 40.05 | 28.135 | 6.671 | 0 | 0.15 | 0.32 | 0121Tra0000015389 | m | T101b | false | HI_UZT_HEA_STA_0,550_xxx | 0
Stahlträger | Wartung_FFB | 1 | Stahlträger | HEA 550 | 2.255 | Wartung_FFB | 22.05 | 30.25 | 6.671 | 22.05 | 28.135 | 6.671 | 0 | 0.15 | 0.32 | 0121Tra0000019945 | m | T101b | false | HI_UZT_HEA_STA_0,550_xxx | 0
Stahlträger | Wartung_FFB | 1 | Stahlträger | HEA 650 | 2.453 | Wartung_FFB | 43.05 | 30.25 | 6.621 | 43.05 | 26.952 | 6.621 | 0 | 0.15 | 0.32 | 0121Tra0000019959 | m | T101&102 | false | HI_UZT_HEA_STA_0,650_xxx | 0
Stahlträger | Wartung_FFB | 1 | Stahlträger | HEA 650 | 2.453 | Wartung_FFB | 46.05 | 30.25 | 6.621 | 46.05 | 26.952 | 6.621 | 0 | 0.15 | 0.32 | 0121Tra0000019971 | m | T101&102 | false | HI_UZT_HEA_STA_0,650_xxx | 0
Stahlträger | Wartung_FFB | 1 | Stahlträger | HEA 650 | 2.453 | Wartung_FFB | 49.05 | 30.25 | 6.621 | 49.05 | 26.952 | 6.621 | 0 | 0.15 | 0.32 | 0121Tra0000019984 | m | T101&102 | false | HI_UZT_HEA_STA_0,650_xxx | 0
Stahlträger | Wartung_FFB | 1 | Stahlträger | HEA 650 | 2.453 | Wartung_FFB | 52.05 | 30.25 | 6.621 | 52.05 | 26.952 | 6.621 | 0 | 0.15 | 0.32 | 0121Tra0000019997 | m | T101&102 | false | HI_UZT_HEA_STA_0,650_xxx | 0
Stahlträger | Wartung_FFB | 1 | Stahlträger | HEA 650 | 2.453 | Wartung_FFB | 61.05 | 30.25 | 6.621 | 61.05 | 26.952 | 6.621 | 0 | 0.15 | 0.32 | 0121Tra0000020036 | m | T101&102 | false | HI_UZT_HEA_STA_0,650_xxx | 0
Stahlträger | Wartung_FFB | 1 | Stahlträger | HEA 650 | 2.453 | Wartung_FFB | 64.05 | 30.25 | 6.621 | 64.05 | 26.952 | 6.621 | 0 | 0.15 | 0.32 | 0121Tra0000020049 | m | T101&102 | false | HI_UZT_HEA_STA_0,650_xxx | 0
Stahlträger | Wartung_FFB | 1 | Stahlträger | HEA 550 | 2.255 | Wartung_FFB | 58.05 | 30.25 | 6.671 | 58.05 | 26.825 | 6.671 | 0 | 0.15 | 0.32 | 0121Tra0000010079 | m | T101c | false | HI_UZT_HEA_STA_0,550_xxx | 0
Stahlträger | Wartung_FFB | 1 | Stahlträger | HEA 550 | 2.255 | Wartung_FFB | 55.05 | 30.25 | 6.671 | 55.05 | 26.825 | 6.671 | 0 | 0.15 | 0.32 | 0121Tra0000013249 | m | T101c | false | HI_UZT_HEA_STA_0,550_xxx | 0
Stahlträger | Wartung_FFB | 1 | Stahlträger | HEA 500 | 2.156 | Wartung_FFB | 67.05 | 30.25 | 6.696 | 67.05 | 26.952 | 6.696 | 0 | 0.15 | 0.32 | 0121Tra0000013096 | m | T101d | false | HI_UZT_HEA_STA_0,500_xxx | 0
Stahlträger | Wartung_FFB | 1 | Stahlträger | HEA 500 | 2.156 | Wartung_FFB | 70.05 | 30.25 | 6.696 | 70.05 | 26.952 | 6.696 | 0 | 0.15 | 0.32 | 0121Tra0000013121 | m | T101d | false | HI_UZT_HEA_STA_0,500_xxx | 0
Stahlträger | Wartung_FFB | 1 | Stahlträger | HEA 500 | 2.156 | Wartung_FFB | 73.05 | 30.25 | 6.696 | 73.05 | 26.952 | 6.696 | 0 | 0.15 | 0.32 | 0121Tra0000013142 | m | T101e | false | HI_UZT_HEA_STA_0,500_xxx | 0
Stahlträger | Wartung_FFB | 1 | Stahlträger | HEA 500 | 2.156 | Wartung_FFB | 76.05 | 30.25 | 6.696 | 76.05 | 26.952 | 6.696 | 0 | 0.15 | 0.32 | 0121Tra0000013163 | m | T101e | false | HI_UZT_HEA_STA_0,500_xxx | 0
Stahlträger | Wartung_FFB | 1 | Stahlträger | HEA 500 | 2.156 | Wartung_FFB | 79.05 | 30.25 | 6.696 | 79.05 | 26.952 | 6.696 | 0 | 0.15 | 0.32 | 0121Tra0000013184 | m | T101e | false | HI_UZT_HEA_STA_0,500_xxx | 0
Stahlträger | Wartung_FFB | 1 | Stahlträger | HEA 500 | 2.156 | Wartung_FFB | 81.55 | 30.25 | 6.696 | 81.55 | 26.952 | 6.696 | 0 | 0.15 | 0.32 | 0121Tra0000020128 | m | T101e | false | HI_UZT_HEA_STA_0,500_xxx | 0
Stahlträger | Wartung_FFB | 1 | Stahlträger | HEA 650 | 2.453 | Wartung_FFB | 88.05 | 30.25 | 6.621 | 88.05 | 26.952 | 6.621 | 0 | 0.15 | 0.32 | 0121Tra0000020177 | m | T101&102 | false | HI_UZT_HEA_STA_0,650_xxx | 0
Stahlträger | Wartung_FFB | 1 | Stahlträger | HEA 650 | 2.453 | Wartung_FFB | 103.05 | 30.25 | 6.621 | 103.05 | 26.952 | 6.621 | 0 | 0.15 | 0.32 | 0121Tra0000020190 | m | T101&102 | false | HI_UZT_HEA_STA_0,650_xxx | 0
Stahlträger | Wartung_FFB | 1 | Stahlträger | HEA 650 | 2.453 | Wartung_FFB | 106.05 | 30.25 | 6.621 | 106.05 | 26.952 | 6.621 | 0 | 0.15 | 0.32 | 0121Tra0000020203 | m | T101&102 | false | HI_UZT_HEA_STA_0,650_xxx | 0
Stahlträger | Wartung_FFB | 1 | Stahlträger | HEA 650 | 2.453 | Wartung_FFB | 109.05 | 30.25 | 6.621 | 109.05 | 26.952 | 6.621 | 0 | 0.15 | 0.32 | 0121Tra0000020223 | m | T101&102 | false | HI_UZT_HEA_STA_0,650_xxx | 0
Stahlträger | Wartung_FFB | 1 | Stahlträger | HEA 650 | 2.453 | Wartung_FFB | 112.05 | 30.25 | 6.621 | 112.05 | 26.952 | 6.621 | 0 | 0.15 | 0.32 | 0121Tra0000020229 | m | T101&102 | false | HI_UZT_HEA_STA_0,650_xxx | 0
Stahlträger | Wartung_FFB | 1 | Stahlträger | HEA 650 | 2.453 | Wartung_FFB | 115.05 | 30.25 | 6.621 | 115.05 | 26.952 | 6.621 | 0 | 0.15 | 0.32 | 0121Tra0000020256 | m | T101&102 | false | HI_UZT_HEA_STA_0,650_xxx | 0
Stahlträger | Wartung_FFB | 1 | Stahlträger | HEA 650 | 2.453 | Wartung_FFB | 118.05 | 30.25 | 6.621 | 118.05 | 26.952 | 6.621 | 0 | 0.15 | 0.32 | 0121Tra0000020262 | m | T101&102 | false | HI_UZT_HEA_STA_0,650_xxx | 0
Stahlträger | Wartung_FFB | 1 | Stahlträger | HEA 650 | 2.453 | Wartung_FFB | 121.05 | 30.25 | 6.621 | 121.05 | 26.952 | 6.621 | 0 | 0.15 | 0.32 | 0121Tra0000020268 | m | T101&102 | false | HI_UZT_HEA_STA_0,650_xxx | 0
Stahlträger | Wartung_FFB | 1 | Stahlträger | HEA 650 | 2.453 | Wartung_FFB | 97.05 | 30.25 | 6.621 | 97.05 | 26.952 | 6.621 | 0 | 0.15 | 0.32 | 0121Tra0000020288 | m | T101&102 | false | HI_UZT_HEA_STA_0,650_xxx | 0
Stahlträger | Wartung_FFB | 1 | Stahlträger | HEA 650 | 2.453 | Wartung_FFB | 100.05 | 30.25 | 6.621 | 100.05 | 26.952 | 6.621 | 0 | 0.15 | 0.32 | 0121Tra0000020294 | m | T101&102 | false | HI_UZT_HEA_STA_0,650_xxx | 0
Stahlträger | Wartung_FFB | 1 | Stahlträger | HEA 650 | 2.453 | Wartung_FFB | 94.7 | 30.25 | 6.621 | 94.7 | 26.952 | 6.621 | 0 | 0.15 | 0.32 | 0121Tra0000020307 | m | T101&102 | false | HI_UZT_HEA_STA_0,650_xxx | 0
Stahlträger | Wartung_FFB | 1 | Stahlträger | HEA 650 | 2.453 | Wartung_FFB | 91.85 | 30.25 | 6.621 | 91.85 | 26.952 | 6.621 | 0 | 0.15 | 0.32 | 0121Tra0000020320 | m | T101&102 | false | HI_UZT_HEA_STA_0,650_xxx | 0
Stahlträger | Wartung_FFB | 1 | Stahlträger | HEA 650 | 2.453 | Wartung_FFB | 91.05 | 30.25 | 6.621 | 91.05 | 26.952 | 6.621 | 0 | 0.15 | 0.32 | 0121Tra0000020333 | m | T101&102 | false | HI_UZT_HEA_STA_0,650_xxx | 0
Stahlträger | Wartung_FFB | 1 | Stahlträger | HEA 650 | 2.453 | Wartung_FFB | 85.05 | 30.25 | 6.621 | 85.05 | 26.952 | 6.621 | 0 | 0.15 | 0.32 | 0121Tra0000020160 | m | T101f | false | HI_UZT_HEA_STA_0,650_xxx | 0
Stahlträger | Wartung_FFB | 1 | Stahlträger | HEA 500 | 2.156 | Wartung_FFB | 10.55 | 13.838 | 6.696 | 10.55 | 10.54 | 6.696 | 0 | 0.15 | 0.32 | 0121Tra0000013411 | m | T101a | false | HI_UZT_HEA_STA_0,500_xxx | 0
Stahlträger | Wartung_FFB | 1 | Stahlträger | HEA 500 | 2.156 | Wartung_FFB | 13.05 | 13.838 | 6.696 | 13.05 | 10.54 | 6.696 | 0 | 0.15 | 0.32 | 0121Tra0000013431 | m | T101a | false | HI_UZT_HEA_STA_0,500_xxx | 0
Stahlträger | Wartung_FFB | 1 | Stahlträger | HEA 650 | 2.453 | Wartung_FFB | 16.05 | 13.838 | 6.621 | 16.05 | 10.54 | 6.621 | 0 | 0.15 | 0.32 | 0121Tra0000015403 | m | T101&102 | false | HI_UZT_HEA_STA_0,650_xxx | 0
Stahlträger | Wartung_FFB | 1 | Stahlträger | HEA 650 | 2.453 | Wartung_FFB | 19.05 | 13.838 | 6.621 | 19.05 | 10.54 | 6.621 | 0 | 0.15 | 0.32 | 0121Tra0000013462 | m | T101&102 | false | HI_UZT_HEA_STA_0,650_xxx | 0
Stahlträger | Wartung_FFB | 1 | Stahlträger | HEA 550 | 2.255 | Wartung_FFB | 28.05 | 13.838 | 6.671 | 28.05 | 10.54 | 6.671 | 0 | 0.15 | 0.32 | 0121Tra0000013283 | m | T101b | false | HI_UZT_HEA_STA_0,550_xxx | 0
Stahlträger | Wartung_FFB | 1 | Stahlträger | HEA 550 | 2.255 | Wartung_FFB | 34.05 | 13.838 | 6.671 | 34.05 | 10.54 | 6.671 | 0 | 0.15 | 0.32 | 0121Tra0000013315 | m | T101b | false | HI_UZT_HEA_STA_0,550_xxx | 0
Stahlträger | Wartung_FFB | 1 | Stahlträger | HEA 550 | 2.255 | Wartung_FFB | 25.55 | 13.838 | 6.671 | 25.55 | 10.54 | 6.671 | 0 | 0.15 | 0.32 | 0121Tra0000013266 | m | T101b | false | HI_UZT_HEA_STA_0,550_xxx | 0
Stahlträger | Wartung_FFB | 1 | Stahlträger | HEA 550 | 2.255 | Wartung_FFB | 32.25 | 13.838 | 6.671 | 32.25 | 10.54 | 6.671 | 0 | 0.15 | 0.32 | 0121Tra0000013300 | m | T101b | false | HI_UZT_HEA_STA_0,550_xxx | 0
Stahlträger | Wartung_FFB | 1 | Stahlträger | HEA 550 | 2.255 | Wartung_FFB | 29.6 | 13.838 | 6.671 | 29.6 | 10.54 | 6.671 | 0 | 0.15 | 0.32 | 0121Tra0000014972 | m | T101b | false | HI_UZT_HEA_STA_0,550_xxx | 0
Stahlträger | Wartung_FFB | 1 | Stahlträger | HEA 550 | 2.255 | Wartung_FFB | 37.05 | 13.838 | 6.671 | 37.05 | 10.54 | 6.671 | 0 | 0.15 | 0.32 | 0121Tra0000015371 | m | T101b | false | HI_UZT_HEA_STA_0,550_xxx | 0
Stahlträger | Wartung_FFB | 1 | Stahlträger | HEA 550 | 2.255 | Wartung_FFB | 40.05 | 13.838 | 6.671 | 40.05 | 10.54 | 6.671 | 0 | 0.15 | 0.32 | 0121Tra0000015385 | m | T101b | false | HI_UZT_HEA_STA_0,550_xxx | 0
Stahlträger | Wartung_FFB | 1 | Stahlträger | HEA 550 | 2.255 | Wartung_FFB | 22.05 | 13.838 | 6.671 | 22.05 | 10.54 | 6.671 | 0 | 0.15 | 0.32 | 0121Tra0000019935 | m | T101b | false | HI_UZT_HEA_STA_0,550_xxx | 0
Stahlträger | Wartung_FFB | 1 | Stahlträger | HEA 650 | 2.453 | Wartung_FFB | 43.05 | 13.838 | 6.621 | 43.05 | 10.54 | 6.621 | 0 | 0.15 | 0.32 | 0121Tra0000019957 | m | T101&102 | false | HI_UZT_HEA_STA_0,650_xxx | 0
Stahlträger | Wartung_FFB | 1 | Stahlträger | HEA 650 | 2.453 | Wartung_FFB | 46.05 | 13.838 | 6.621 | 46.05 | 10.54 | 6.621 | 0 | 0.15 | 0.32 | 0121Tra0000019967 | m | T101&102 | false | HI_UZT_HEA_STA_0,650_xxx | 0
Stahlträger | Wartung_FFB | 1 | Stahlträger | HEA 650 | 2.453 | Wartung_FFB | 49.05 | 13.838 | 6.621 | 49.05 | 10.54 | 6.621 | 0 | 0.15 | 0.32 | 0121Tra0000019980 | m | T101&102 | false | HI_UZT_HEA_STA_0,650_xxx | 0
Stahlträger | Wartung_FFB | 1 | Stahlträger | HEA 650 | 2.453 | Wartung_FFB | 52.05 | 13.838 | 6.621 | 52.05 | 10.54 | 6.621 | 0 | 0.15 | 0.32 | 0121Tra0000019993 | m | T101&102 | false | HI_UZT_HEA_STA_0,650_xxx | 0
Stahlträger | Wartung_FFB | 1 | Stahlträger | HEA 650 | 2.453 | Wartung_FFB | 61.05 | 13.838 | 6.621 | 61.05 | 10.54 | 6.621 | 0 | 0.15 | 0.32 | 0121Tra0000020032 | m | T101&102 | false | HI_UZT_HEA_STA_0,650_xxx | 0
Stahlträger | Wartung_FFB | 1 | Stahlträger | HEA 650 | 2.453 | Wartung_FFB | 64.05 | 13.838 | 6.621 | 64.05 | 10.54 | 6.621 | 0 | 0.15 | 0.32 | 0121Tra0000020045 | m | T101&102 | false | HI_UZT_HEA_STA_0,650_xxx | 0
Stahlträger | Wartung_FFB | 1 | Stahlträger | HEA 550 | 2.255 | Wartung_FFB | 58.05 | 13.838 | 6.671 | 58.05 | 10.54 | 6.671 | 0 | 0.15 | 0.32 | 0121Tra0000013231 | m | T101c | false | HI_UZT_HEA_STA_0,550_xxx | 0
Stahlträger | Wartung_FFB | 1 | Stahlträger | HEA 550 | 2.255 | Wartung_FFB | 55.05 | 13.838 | 6.671 | 55.05 | 10.54 | 6.671 | 0 | 0.15 | 0.32 | 0121Tra0000013251 | m | T101c | false | HI_UZT_HEA_STA_0,550_xxx | 0
Stahlträger | Wartung_FFB | 1 | Stahlträger | HEA 500 | 2.156 | Wartung_FFB | 67.05 | 14.935 | 6.696 | 67.05 | 10.54 | 6.696 | 0 | 0.15 | 0.32 | 0121Tra0000010695 | m | T101d | false | HI_UZT_HEA_STA_0,500_xxx | 0
Stahlträger | Wartung_FFB | 1 | Stahlträger | HEA 500 | 2.156 | Wartung_FFB | 70.05 | 14.935 | 6.696 | 70.05 | 10.54 | 6.696 | 0 | 0.15 | 0.32 | 0121Tra0000013102 | m | T101d | false | HI_UZT_HEA_STA_0,500_xxx | 0
Stahlträger | Wartung_FFB | 1 | Stahlträger | HEA 500 | 2.156 | Wartung_FFB | 73.05 | 14.935 | 6.696 | 73.05 | 10.54 | 6.696 | 0 | 0.15 | 0.32 | 0121Tra0000013138 | m | T101e | false | HI_UZT_HEA_STA_0,500_xxx | 0
Stahlträger | Wartung_FFB | 1 | Stahlträger | HEA 500 | 2.156 | Wartung_FFB | 76.05 | 14.935 | 6.696 | 76.05 | 10.54 | 6.696 | 0 | 0.15 | 0.32 | 0121Tra0000013159 | m | T101e | false | HI_UZT_HEA_STA_0,500_xxx | 0
Stahlträger | Wartung_FFB | 1 | Stahlträger | HEA 500 | 2.156 | Wartung_FFB | 79.05 | 14.935 | 6.696 | 79.05 | 10.54 | 6.696 | 0 | 0.15 | 0.32 | 0121Tra0000013180 | m | T101e | false | HI_UZT_HEA_STA_0,500_xxx | 0
Stahlträger | Wartung_FFB | 1 | Stahlträger | HEA 500 | 2.156 | Wartung_FFB | 81.55 | 14.935 | 6.696 | 81.55 | 10.54 | 6.696 | 0 | 0.15 | 0.32 | 0121Tra0000020133 | m | T101e | false | HI_UZT_HEA_STA_0,500_xxx | 0
Stahlträger | Wartung_FFB | 1 | Stahlträger | HEA 650 | 2.453 | Wartung_FFB | 88.05 | 13.838 | 6.621 | 88.05 | 10.54 | 6.621 | 0 | 0.15 | 0.32 | 0121Tra0000020173 | m | T101&102 | false | HI_UZT_HEA_STA_0,650_xxx | 0
Stahlträger | Wartung_FFB | 1 | Stahlträger | HEA 650 | 2.453 | Wartung_FFB | 103.05 | 13.838 | 6.621 | 103.05 | 10.54 | 6.621 | 0 | 0.15 | 0.32 | 0121Tra0000020186 | m | T101&102 | false | HI_UZT_HEA_STA_0,650_xxx | 0
Stahlträger | Wartung_FFB | 1 | Stahlträger | HEA 650 | 2.453 | Wartung_FFB | 106.05 | 13.838 | 6.621 | 106.05 | 10.54 | 6.621 | 0 | 0.15 | 0.32 | 0121Tra0000020199 | m | T101&102 | false | HI_UZT_HEA_STA_0,650_xxx | 0
Stahlträger | Wartung_FFB | 1 | Stahlträger | HEA 650 | 2.453 | Wartung_FFB | 109.05 | 13.838 | 6.621 | 109.05 | 10.54 | 6.621 | 0 | 0.15 | 0.32 | 0121Tra0000020219 | m | T101&102 | false | HI_UZT_HEA_STA_0,650_xxx | 0
Stahlträger | Wartung_FFB | 1 | Stahlträger | HEA 650 | 2.453 | Wartung_FFB | 112.05 | 13.838 | 6.621 | 112.05 | 10.54 | 6.621 | 0 | 0.15 | 0.32 | 0121Tra0000020225 | m | T101&102 | false | HI_UZT_HEA_STA_0,650_xxx | 0
Stahlträger | Wartung_FFB | 1 | Stahlträger | HEA 650 | 2.453 | Wartung_FFB | 115.05 | 13.838 | 6.621 | 115.05 | 10.54 | 6.621 | 0 | 0.15 | 0.32 | 0121Tra0000020252 | m | T101&102 | false | HI_UZT_HEA_STA_0,650_xxx | 0
Stahlträger | Wartung_FFB | 1 | Stahlträger | HEA 650 | 2.453 | Wartung_FFB | 118.05 | 13.838 | 6.621 | 118.05 | 10.54 | 6.621 | 0 | 0.15 | 0.32 | 0121Tra0000020258 | m | T101&102 | false | HI_UZT_HEA_STA_0,650_xxx | 0
Stahlträger | Wartung_FFB | 1 | Stahlträger | HEA 650 | 2.453 | Wartung_FFB | 121.05 | 13.838 | 6.621 | 121.05 | 10.54 | 6.621 | 0 | 0.15 | 0.32 | 0121Tra0000020264 | m | T101&102 | false | HI_UZT_HEA_STA_0,650_xxx | 0
Stahlträger | Wartung_FFB | 1 | Stahlträger | HEA 650 | 2.453 | Wartung_FFB | 97.05 | 13.838 | 6.621 | 97.05 | 10.54 | 6.621 | 0 | 0.15 | 0.32 | 0121Tra0000020284 | m | T101&102 | false | HI_UZT_HEA_STA_0,650_xxx | 0
Stahlträger | Wartung_FFB | 1 | Stahlträger | HEA 650 | 2.453 | Wartung_FFB | 100.05 | 13.838 | 6.621 | 100.05 | 10.54 | 6.621 | 0 | 0.15 | 0.32 | 0121Tra0000020290 | m | T101&102 | false | HI_UZT_HEA_STA_0,650_xxx | 0
Stahlträger | Wartung_FFB | 1 | Stahlträger | HEA 650 | 2.453 | Wartung_FFB | 94.7 | 13.838 | 6.621 | 94.7 | 10.54 | 6.621 | 0 | 0.15 | 0.32 | 0121Tra0000020303 | m | T101&102 | false | HI_UZT_HEA_STA_0,650_xxx | 0
Stahlträger | Wartung_FFB | 1 | Stahlträger | HEA 650 | 2.453 | Wartung_FFB | 91.85 | 13.838 | 6.621 | 91.85 | 10.54 | 6.621 | 0 | 0.15 | 0.32 | 0121Tra0000020316 | m | T101&102 | false | HI_UZT_HEA_STA_0,650_xxx | 0
Stahlträger | Wartung_FFB | 1 | Stahlträger | HEA 650 | 2.453 | Wartung_FFB | 91.05 | 13.838 | 6.621 | 91.05 | 10.54 | 6.621 | 0 | 0.15 | 0.32 | 0121Tra0000020329 | m | T101&102 | false | HI_UZT_HEA_STA_0,650_xxx | 0
Stahlträger | Wartung_FFB | 1 | Stahlträger | HEA 650 | 2.453 | Wartung_FFB | 85.05 | 13.838 | 6.621 | 85.05 | 10.54 | 6.621 | 0 | 0.15 | 0.32 | 0121Tra0000020156 | m | T101f | false | HI_UZT_HEA_STA_0,650_xxx | 0
Nebenträger | Wartung_FFB | 1 | Nebenträger | HEA 120 | 0.698 | Wartung_FFB | 64.06 | 84.226 | 6.998 | 67.04 | 84.226 | 6.998 | 0 | 0.06 | 0.057 | 0122Tra0000003564 | m | T110 | false | HI_UZV_HEA_STA_0,120_xxx | 0
Nebenträger | Wartung_FFB | 1 | Nebenträger | HEA 120 | 0.698 | Wartung_FFB | 67.06 | 84.226 | 6.998 | 70.04 | 84.226 | 6.998 | 0 | 0.06 | 0.057 | 0122Tra0000008269 | m | T110 | false | HI_UZV_HEA_STA_0,120_xxx | 0
Nebenträger | Wartung_FFB | 1 | Nebenträger | HEA 120 | 0.698 | Wartung_FFB | 70.06 | 84.226 | 6.998 | 73.04 | 84.226 | 6.998 | 0 | 0.06 | 0.057 | 0122Tra0000008273 | m | T110 | false | HI_UZV_HEA_STA_0,120_xxx | 0
Nebenträger | Wartung_FFB | 1 | Nebenträger | HEA 120 | 0.698 | Wartung_FFB | 73.06 | 84.226 | 6.998 | 76.04 | 84.226 | 6.998 | 0 | 0.06 | 0.057 | 0122Tra0000008276 | m | T110 | false | HI_UZV_HEA_STA_0,120_xxx | 0
Nebenträger | Wartung_FFB | 1 | Nebenträger | HEA 120 | 0.698 | Wartung_FFB | 76.06 | 84.226 | 6.998 | 79.04 | 84.226 | 6.998 | 0 | 0.06 | 0.057 | 0122Tra0000008279 | m | T110 | false | HI_UZV_HEA_STA_0,120_xxx | 0
Nebenträger | Wartung_FFB | 1 | Nebenträger | HEA 120 | 0.698 | Wartung_FFB | 94.06 | 84.226 | 6.998 | 97.04 | 84.226 | 6.998 | 0 | 0.06 | 0.057 | 0122Tra0000008297 | m | T110 | false | HI_UZV_HEA_STA_0,120_xxx | 0
Nebenträger | Wartung_FFB | 1 | Nebenträger | HEA 120 | 0.698 | Wartung_FFB | 103.06 | 84.226 | 6.998 | 106.04 | 84.226 | 6.998 | 0 | 0.06 | 0.057 | 0122Tra0000008306 | m | T110 | false | HI_UZV_HEA_STA_0,120_xxx | 0
Nebenträger | Wartung_FFB | 1 | Nebenträger | HEA 120 | 0.698 | Wartung_FFB | 106.06 | 84.226 | 6.998 | 109.04 | 84.226 | 6.998 | 0 | 0.06 | 0.057 | 0122Tra0000008309 | m | T110 | false | HI_UZV_HEA_STA_0,120_xxx | 0
Nebenträger | Wartung_FFB | 1 | Nebenträger | HEA 120 | 0.698 | Wartung_FFB | 109.06 | 84.226 | 6.998 | 112.04 | 84.226 | 6.998 | 0 | 0.06 | 0.057 | 0122Tra0000008312 | m | T110 | false | HI_UZV_HEA_STA_0,120_xxx | 0
Nebenträger | Wartung_FFB | 1 | Nebenträger | HEA 120 | 0.698 | Wartung_FFB | 112.06 | 84.226 | 6.998 | 115.04 | 84.226 | 6.998 | 0 | 0.06 | 0.057 | 0122Tra0000008315 | m | T110 | false | HI_UZV_HEA_STA_0,120_xxx | 0
Nebenträger | Wartung_FFB | 1 | Nebenträger | HEA 120 | 0.698 | Wartung_FFB | 115.06 | 84.226 | 6.998 | 118.04 | 84.226 | 6.998 | 0 | 0.06 | 0.057 | 0122Tra0000008318 | m | T110 | false | HI_UZV_HEA_STA_0,120_xxx | 0
Nebenträger | Wartung_FFB | 1 | Nebenträger | HEA 120 | 0.698 | Wartung_FFB | 13.06 | 84.226 | 6.998 | 16.04 | 84.226 | 6.998 | 0 | 0.06 | 0.057 | 0122Tra0000008349 | m | T110 | false | HI_UZV_HEA_STA_0,120_xxx | 0
Nebenträger | Wartung_FFB | 1 | Nebenträger | HEA 120 | 0.698 | Wartung_FFB | 22.06 | 84.226 | 6.998 | 25.04 | 84.226 | 6.998 | 0 | 0.06 | 0.057 | 0122Tra0000008355 | m | T110 | false | HI_UZV_HEA_STA_0,120_xxx | 0
Nebenträger | Wartung_FFB | 1 | Nebenträger | HEA 120 | 0.698 | Wartung_FFB | 25.06 | 84.226 | 6.998 | 28.04 | 84.226 | 6.998 | 0 | 0.06 | 0.057 | 0122Tra0000008357 | m | T110 | false | HI_UZV_HEA_STA_0,120_xxx | 0
Nebenträger | Wartung_FFB | 1 | Nebenträger | HEA 120 | 0.698 | Wartung_FFB | 28.06 | 84.226 | 6.998 | 31.04 | 84.226 | 6.998 | 0 | 0.06 | 0.057 | 0122Tra0000008359 | m | T110 | false | HI_UZV_HEA_STA_0,120_xxx | 0
Nebenträger | Wartung_FFB | 1 | Nebenträger | HEA 120 | 0.698 | Wartung_FFB | 31.06 | 84.226 | 6.998 | 34.04 | 84.226 | 6.998 | 0 | 0.06 | 0.057 | 0122Tra0000008361 | m | T110 | false | HI_UZV_HEA_STA_0,120_xxx | 0
Nebenträger | Wartung_FFB | 1 | Nebenträger | HEA 120 | 0.698 | Wartung_FFB | 34.06 | 84.226 | 6.998 | 37.04 | 84.226 | 6.998 | 0 | 0.06 | 0.057 | 0122Tra0000008363 | m | T110 | false | HI_UZV_HEA_STA_0,120_xxx | 0
Nebenträger | Wartung_FFB | 1 | Nebenträger | HEA 120 | 0.698 | Wartung_FFB | 37.06 | 84.226 | 6.998 | 40.04 | 84.226 | 6.998 | 0 | 0.06 | 0.057 | 0122Tra0000008365 | m | T110 | false | HI_UZV_HEA_STA_0,120_xxx | 0
Nebenträger | Wartung_FFB | 1 | Nebenträger | HEA 120 | 0.698 | Wartung_FFB | 40.06 | 84.226 | 6.998 | 43.04 | 84.226 | 6.998 | 0 | 0.06 | 0.057 | 0122Tra0000008367 | m | T110 | false | HI_UZV_HEA_STA_0,120_xxx | 0
Nebenträger | Wartung_FFB | 1 | Nebenträger | HEA 120 | 0.698 | Wartung_FFB | 43.06 | 84.226 | 6.998 | 46.04 | 84.226 | 6.998 | 0 | 0.06 | 0.057 | 0122Tra0000008369 | m | T110 | false | HI_UZV_HEA_STA_0,120_xxx | 0
Nebenträger | Wartung_FFB | 1 | Nebenträger | HEA 120 | 0.698 | Wartung_FFB | 46.06 | 84.226 | 6.998 | 49.04 | 84.226 | 6.998 | 0 | 0.06 | 0.057 | 0122Tra0000008371 | m | T110 | false | HI_UZV_HEA_STA_0,120_xxx | 0
Nebenträger | Wartung_FFB | 1 | Nebenträger | HEA 120 | 0.698 | Wartung_FFB | 49.06 | 84.226 | 6.998 | 52.04 | 84.226 | 6.998 | 0 | 0.06 | 0.057 | 0122Tra0000008373 | m | T110 | false | HI_UZV_HEA_STA_0,120_xxx | 0
Nebenträger | Wartung_FFB | 1 | Nebenträger | HEA 120 | 0.698 | Wartung_FFB | 52.06 | 84.226 | 6.998 | 55.04 | 84.226 | 6.998 | 0 | 0.06 | 0.057 | 0122Tra0000008375 | m | T110 | false | HI_UZV_HEA_STA_0,120_xxx | 0
Nebenträger | Wartung_FFB | 1 | Nebenträger | HEA 120 | 0.698 | Wartung_FFB | 55.06 | 84.226 | 6.998 | 58.04 | 84.226 | 6.998 | 0 | 0.06 | 0.057 | 0122Tra0000008377 | m | T110 | false | HI_UZV_HEA_STA_0,120_xxx | 0
Nebenträger | Wartung_FFB | 1 | Nebenträger | HEA 120 | 0.698 | Wartung_FFB | 58.06 | 84.226 | 6.998 | 61.04 | 84.226 | 6.998 | 0 | 0.06 | 0.057 | 0122Tra0000008379 | m | T110 | false | HI_UZV_HEA_STA_0,120_xxx | 0
Nebenträger | Wartung_FFB | 1 | Nebenträger | HEA 120 | 0.698 | Wartung_FFB | 61.06 | 84.226 | 6.998 | 64.04 | 84.226 | 6.998 | 0 | 0.06 | 0.057 | 0122Tra0000008381 | m | T110 | false | HI_UZV_HEA_STA_0,120_xxx | 0
Nebenträger | Wartung_FFB | 1 | Nebenträger | HEA 120 | 0.698 | Wartung_FFB | 10.56 | 84.226 | 6.998 | 13.04 | 84.226 | 6.998 | 0 | 0.06 | 0.057 | 0122Tra0000008329 | m | T110 | false | HI_UZV_HEA_STA_0,120_xxx | 0
Nebenträger | Wartung_FFB | 1 | Nebenträger | HEA 120 | 0.698 | Wartung_FFB | 64.06 | 82.726 | 6.998 | 67.04 | 82.726 | 6.998 | 0 | 0.06 | 0.057 | 0122Tra0000008384 | m | T110 | false | HI_UZV_HEA_STA_0,120_xxx | 0
Nebenträger | Wartung_FFB | 1 | Nebenträger | HEA 120 | 0.698 | Wartung_FFB | 67.06 | 82.726 | 6.998 | 70.04 | 82.726 | 6.998 | 0 | 0.06 | 0.057 | 0122Tra0000008405 | m | T110 | false | HI_UZV_HEA_STA_0,120_xxx | 0
Nebenträger | Wartung_FFB | 1 | Nebenträger | HEA 120 | 0.698 | Wartung_FFB | 70.06 | 82.726 | 6.998 | 73.04 | 82.726 | 6.998 | 0 | 0.06 | 0.057 | 0122Tra0000008407 | m | T110 | false | HI_UZV_HEA_STA_0,120_xxx | 0
Nebenträger | Wartung_FFB | 1 | Nebenträger | HEA 120 | 0.698 | Wartung_FFB | 73.06 | 82.726 | 6.998 | 76.04 | 82.726 | 6.998 | 0 | 0.06 | 0.057 | 0122Tra0000008409 | m | T110 | false | HI_UZV_HEA_STA_0,120_xxx | 0
Nebenträger | Wartung_FFB | 1 | Nebenträger | HEA 120 | 0.698 | Wartung_FFB | 76.06 | 82.726 | 6.998 | 79.04 | 82.726 | 6.998 | 0 | 0.06 | 0.057 | 0122Tra0000008411 | m | T110 | false | HI_UZV_HEA_STA_0,120_xxx | 0
Nebenträger | Wartung_FFB | 1 | Nebenträger | HEA 120 | 0.698 | Wartung_FFB | 94.06 | 82.726 | 6.998 | 97.04 | 82.726 | 6.998 | 0 | 0.06 | 0.057 | 0122Tra0000008423 | m | T110 | false | HI_UZV_HEA_STA_0,120_xxx | 0
Nebenträger | Wartung_FFB | 1 | Nebenträger | HEA 120 | 0.698 | Wartung_FFB | 103.06 | 82.726 | 6.998 | 106.04 | 82.726 | 6.998 | 0 | 0.06 | 0.057 | 0122Tra0000008429 | m | T110 | false | HI_UZV_HEA_STA_0,120_xxx | 0
Nebenträger | Wartung_FFB | 1 | Nebenträger | HEA 120 | 0.698 | Wartung_FFB | 106.06 | 82.726 | 6.998 | 109.04 | 82.726 | 6.998 | 0 | 0.06 | 0.057 | 0122Tra0000008431 | m | T110 | false | HI_UZV_HEA_STA_0,120_xxx | 0
Nebenträger | Wartung_FFB | 1 | Nebenträger | HEA 120 | 0.698 | Wartung_FFB | 109.06 | 82.726 | 6.998 | 112.04 | 82.726 | 6.998 | 0 | 0.06 | 0.057 | 0122Tra0000008433 | m | T110 | false | HI_UZV_HEA_STA_0,120_xxx | 0
Nebenträger | Wartung_FFB | 1 | Nebenträger | HEA 120 | 0.698 | Wartung_FFB | 112.06 | 82.726 | 6.998 | 115.04 | 82.726 | 6.998 | 0 | 0.06 | 0.057 | 0122Tra0000008435 | m | T110 | false | HI_UZV_HEA_STA_0,120_xxx | 0
Nebenträger | Wartung_FFB | 1 | Nebenträger | HEA 120 | 0.698 | Wartung_FFB | 115.06 | 82.726 | 6.998 | 118.04 | 82.726 | 6.998 | 0 | 0.06 | 0.057 | 0122Tra0000008437 | m | T110 | false | HI_UZV_HEA_STA_0,120_xxx | 0
Nebenträger | Wartung_FFB | 1 | Nebenträger | HEA 120 | 0.698 | Wartung_FFB | 13.06 | 82.726 | 6.998 | 16.04 | 82.726 | 6.998 | 0 | 0.06 | 0.057 | 0122Tra0000008458 | m | T110 | false | HI_UZV_HEA_STA_0,120_xxx | 0
Nebenträger | Wartung_FFB | 1 | Nebenträger | HEA 120 | 0.698 | Wartung_FFB | 22.06 | 82.726 | 6.998 | 25.04 | 82.726 | 6.998 | 0 | 0.06 | 0.057 | 0122Tra0000008464 | m | T110 | false | HI_UZV_HEA_STA_0,120_xxx | 0
Nebenträger | Wartung_FFB | 1 | Nebenträger | HEA 120 | 0.698 | Wartung_FFB | 25.06 | 82.726 | 6.998 | 28.04 | 82.726 | 6.998 | 0 | 0.06 | 0.057 | 0122Tra0000008466 | m | T110 | false | HI_UZV_HEA_STA_0,120_xxx | 0
Nebenträger | Wartung_FFB | 1 | Nebenträger | HEA 120 | 0.698 | Wartung_FFB | 28.06 | 82.726 | 6.998 | 31.04 | 82.726 | 6.998 | 0 | 0.06 | 0.057 | 0122Tra0000008468 | m | T110 | false | HI_UZV_HEA_STA_0,120_xxx | 0
Nebenträger | Wartung_FFB | 1 | Nebenträger | HEA 120 | 0.698 | Wartung_FFB | 31.06 | 82.726 | 6.998 | 34.04 | 82.726 | 6.998 | 0 | 0.06 | 0.057 | 0122Tra0000008470 | m | T110 | false | HI_UZV_HEA_STA_0,120_xxx | 0
Nebenträger | Wartung_FFB | 1 | Nebenträger | HEA 120 | 0.698 | Wartung_FFB | 34.06 | 82.726 | 6.998 | 37.04 | 82.726 | 6.998 | 0 | 0.06 | 0.057 | 0122Tra0000008472 | m | T110 | false | HI_UZV_HEA_STA_0,120_xxx | 0
Nebenträger | Wartung_FFB | 1 | Nebenträger | HEA 120 | 0.698 | Wartung_FFB | 37.06 | 82.726 | 6.998 | 40.04 | 82.726 | 6.998 | 0 | 0.06 | 0.057 | 0122Tra0000008474 | m | T110 | false | HI_UZV_HEA_STA_0,120_xxx | 0
Nebenträger | Wartung_FFB | 1 | Nebenträger | HEA 120 | 0.698 | Wartung_FFB | 40.06 | 82.726 | 6.998 | 43.04 | 82.726 | 6.998 | 0 | 0.06 | 0.057 | 0122Tra0000008476 | m | T110 | false | HI_UZV_HEA_STA_0,120_xxx | 0
Nebenträger | Wartung_FFB | 1 | Nebenträger | HEA 120 | 0.698 | Wartung_FFB | 43.06 | 82.726 | 6.998 | 46.04 | 82.726 | 6.998 | 0 | 0.06 | 0.057 | 0122Tra0000008478 | m | T110 | false | HI_UZV_HEA_STA_0,120_xxx | 0
Nebenträger | Wartung_FFB | 1 | Nebenträger | HEA 120 | 0.698 | Wartung_FFB | 46.06 | 82.726 | 6.998 | 49.04 | 82.726 | 6.998 | 0 | 0.06 | 0.057 | 0122Tra0000008480 | m | T110 | false | HI_UZV_HEA_STA_0,120_xxx | 0
Nebenträger | Wartung_FFB | 1 | Nebenträger | HEA 120 | 0.698 | Wartung_FFB | 49.06 | 82.726 | 6.998 | 52.04 | 82.726 | 6.998 | 0 | 0.06 | 0.057 | 0122Tra0000008482 | m | T110 | false | HI_UZV_HEA_STA_0,120_xxx | 0
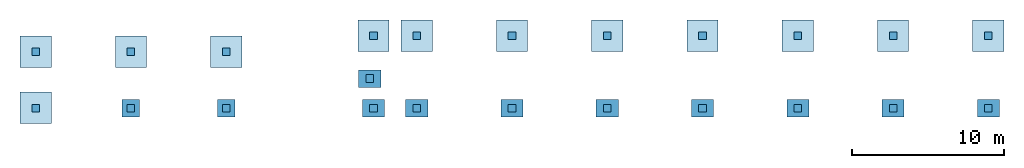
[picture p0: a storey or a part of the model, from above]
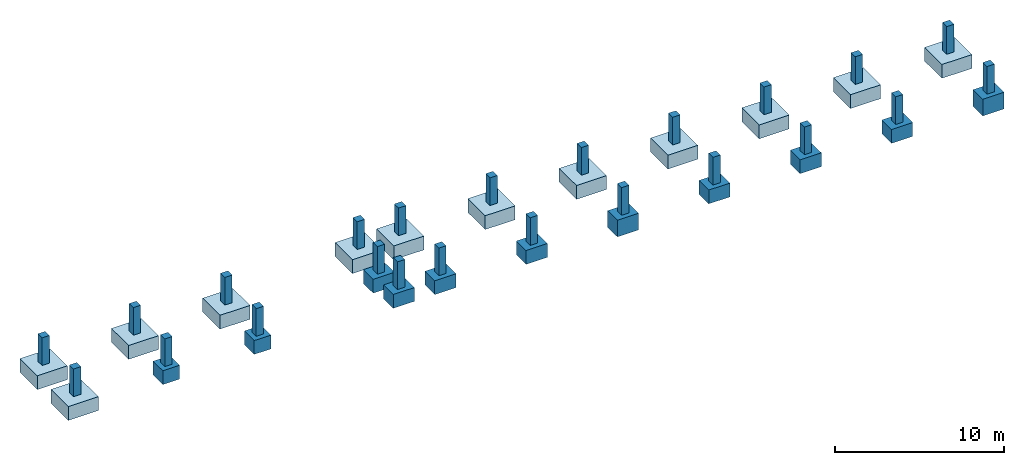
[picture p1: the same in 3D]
Properties of the parts of a building model (IFC2X3), part 3 of 25

# IfcBeam (2372)
Name | In | Faktor | Bezeichnung = Name | Profilname | Mantelfläche/lfm | Ebene | Achsenstartpunkt (X) (m) | Achsenstartpunkt (Y) (m) | Achsenstartpunkt (Z) (m) | Achsenendpunkt (X) (m) | Achsenendpunkt (Y) (m) | Achsenendpunkt (Z) (m) | Objektdrehwinkel | Schwerpunkt X (m) | Schwerpunkt Y (m) | Allright_Bauteil_ID | Abrechnungsart | Positionsnummer | Außenbauteil | Reference | Drehwinkel = Slope (deg)
Nebenträger | Wartung_FFB | 1 | Nebenträger | HEA 120 | 0.698 | Wartung_FFB | 52.06 | 82.726 | 6.998 | 55.04 | 82.726 | 6.998 | 0 | 0.06 | 0.057 | 0122Tra0000008484 | m | T110 | false | HI_UZV_HEA_STA_0,120_xxx | 0
Nebenträger | Wartung_FFB | 1 | Nebenträger | HEA 120 | 0.698 | Wartung_FFB | 55.06 | 82.726 | 6.998 | 58.04 | 82.726 | 6.998 | 0 | 0.06 | 0.057 | 0122Tra0000008486 | m | T110 | false | HI_UZV_HEA_STA_0,120_xxx | 0
Nebenträger | Wartung_FFB | 1 | Nebenträger | HEA 120 | 0.698 | Wartung_FFB | 58.06 | 82.726 | 6.998 | 61.04 | 82.726 | 6.998 | 0 | 0.06 | 0.057 | 0122Tra0000008488 | m | T110 | false | HI_UZV_HEA_STA_0,120_xxx | 0
Nebenträger | Wartung_FFB | 1 | Nebenträger | HEA 120 | 0.698 | Wartung_FFB | 61.06 | 82.726 | 6.998 | 64.04 | 82.726 | 6.998 | 0 | 0.06 | 0.057 | 0122Tra0000008490 | m | T110 | false | HI_UZV_HEA_STA_0,120_xxx | 0
Nebenträger | Wartung_FFB | 1 | Nebenträger | HEA 120 | 0.698 | Wartung_FFB | 10.56 | 82.726 | 6.998 | 13.04 | 82.726 | 6.998 | 0 | 0.06 | 0.057 | 0122Tra0000008493 | m | T110 | false | HI_UZV_HEA_STA_0,120_xxx | 0
Nebenträger | Wartung_FFB | 1 | Nebenträger | HEA 120 | 0.698 | Wartung_FFB | 64.06 | 81.226 | 6.998 | 67.04 | 81.226 | 6.998 | 0 | 0.06 | 0.057 | 0122Tra0000008532 | m | T110 | false | HI_UZV_HEA_STA_0,120_xxx | 0
Nebenträger | Wartung_FFB | 1 | Nebenträger | HEA 120 | 0.698 | Wartung_FFB | 67.06 | 81.226 | 6.998 | 70.04 | 81.226 | 6.998 | 0 | 0.06 | 0.057 | 0122Tra0000008534 | m | T110 | false | HI_UZV_HEA_STA_0,120_xxx | 0
Nebenträger | Wartung_FFB | 1 | Nebenträger | HEA 120 | 0.698 | Wartung_FFB | 70.06 | 81.226 | 6.998 | 73.04 | 81.226 | 6.998 | 0 | 0.06 | 0.057 | 0122Tra0000008536 | m | T110 | false | HI_UZV_HEA_STA_0,120_xxx | 0
Nebenträger | Wartung_FFB | 1 | Nebenträger | HEA 120 | 0.698 | Wartung_FFB | 73.06 | 81.226 | 6.998 | 76.04 | 81.226 | 6.998 | 0 | 0.06 | 0.057 | 0122Tra0000008538 | m | T110 | false | HI_UZV_HEA_STA_0,120_xxx | 0
Nebenträger | Wartung_FFB | 1 | Nebenträger | HEA 120 | 0.698 | Wartung_FFB | 76.06 | 81.226 | 6.998 | 79.04 | 81.226 | 6.998 | 0 | 0.06 | 0.057 | 0122Tra0000008540 | m | T110 | false | HI_UZV_HEA_STA_0,120_xxx | 0
Nebenträger | Wartung_FFB | 1 | Nebenträger | HEA 120 | 0.698 | Wartung_FFB | 94.06 | 81.226 | 6.998 | 97.04 | 81.226 | 6.998 | 0 | 0.06 | 0.057 | 0122Tra0000008552 | m | T110 | false | HI_UZV_HEA_STA_0,120_xxx | 0
Nebenträger | Wartung_FFB | 1 | Nebenträger | HEA 120 | 0.698 | Wartung_FFB | 103.06 | 81.226 | 6.998 | 106.04 | 81.226 | 6.998 | 0 | 0.06 | 0.057 | 0122Tra0000008558 | m | T110 | false | HI_UZV_HEA_STA_0,120_xxx | 0
Nebenträger | Wartung_FFB | 1 | Nebenträger | HEA 120 | 0.698 | Wartung_FFB | 106.06 | 81.226 | 6.998 | 109.04 | 81.226 | 6.998 | 0 | 0.06 | 0.057 | 0122Tra0000008560 | m | T110 | false | HI_UZV_HEA_STA_0,120_xxx | 0
Nebenträger | Wartung_FFB | 1 | Nebenträger | HEA 120 | 0.698 | Wartung_FFB | 109.06 | 81.226 | 6.998 | 112.04 | 81.226 | 6.998 | 0 | 0.06 | 0.057 | 0122Tra0000008562 | m | T110 | false | HI_UZV_HEA_STA_0,120_xxx | 0
Nebenträger | Wartung_FFB | 1 | Nebenträger | HEA 120 | 0.698 | Wartung_FFB | 112.06 | 81.226 | 6.998 | 115.04 | 81.226 | 6.998 | 0 | 0.06 | 0.057 | 0122Tra0000008564 | m | T110 | false | HI_UZV_HEA_STA_0,120_xxx | 0
Nebenträger | Wartung_FFB | 1 | Nebenträger | HEA 120 | 0.698 | Wartung_FFB | 115.06 | 81.226 | 6.998 | 118.04 | 81.226 | 6.998 | 0 | 0.06 | 0.057 | 0122Tra0000008566 | m | T110 | false | HI_UZV_HEA_STA_0,120_xxx | 0
Nebenträger | Wartung_FFB | 1 | Nebenträger | HEA 120 | 0.698 | Wartung_FFB | 13.06 | 81.226 | 6.998 | 16.04 | 81.226 | 6.998 | 0 | 0.06 | 0.057 | 0122Tra0000008570 | m | T110 | false | HI_UZV_HEA_STA_0,120_xxx | 0
Nebenträger | Wartung_FFB | 1 | Nebenträger | HEA 120 | 0.698 | Wartung_FFB | 22.06 | 81.226 | 6.998 | 25.04 | 81.226 | 6.998 | 0 | 0.06 | 0.057 | 0122Tra0000008576 | m | T110 | false | HI_UZV_HEA_STA_0,120_xxx | 0
Nebenträger | Wartung_FFB | 1 | Nebenträger | HEA 120 | 0.698 | Wartung_FFB | 25.06 | 81.226 | 6.998 | 28.04 | 81.226 | 6.998 | 0 | 0.06 | 0.057 | 0122Tra0000008578 | m | T110 | false | HI_UZV_HEA_STA_0,120_xxx | 0
Nebenträger | Wartung_FFB | 1 | Nebenträger | HEA 120 | 0.698 | Wartung_FFB | 28.06 | 81.226 | 6.998 | 31.04 | 81.226 | 6.998 | 0 | 0.06 | 0.057 | 0122Tra0000008580 | m | T110 | false | HI_UZV_HEA_STA_0,120_xxx | 0
Nebenträger | Wartung_FFB | 1 | Nebenträger | HEA 120 | 0.698 | Wartung_FFB | 31.06 | 81.226 | 6.998 | 34.04 | 81.226 | 6.998 | 0 | 0.06 | 0.057 | 0122Tra0000008582 | m | T110 | false | HI_UZV_HEA_STA_0,120_xxx | 0
Nebenträger | Wartung_FFB | 1 | Nebenträger | HEA 120 | 0.698 | Wartung_FFB | 34.06 | 81.226 | 6.998 | 37.04 | 81.226 | 6.998 | 0 | 0.06 | 0.057 | 0122Tra0000008584 | m | T110 | false | HI_UZV_HEA_STA_0,120_xxx | 0
Nebenträger | Wartung_FFB | 1 | Nebenträger | HEA 120 | 0.698 | Wartung_FFB | 37.06 | 81.226 | 6.998 | 40.04 | 81.226 | 6.998 | 0 | 0.06 | 0.057 | 0122Tra0000008586 | m | T110 | false | HI_UZV_HEA_STA_0,120_xxx | 0
Nebenträger | Wartung_FFB | 1 | Nebenträger | HEA 120 | 0.698 | Wartung_FFB | 40.06 | 81.226 | 6.998 | 43.04 | 81.226 | 6.998 | 0 | 0.06 | 0.057 | 0122Tra0000008588 | m | T110 | false | HI_UZV_HEA_STA_0,120_xxx | 0
Nebenträger | Wartung_FFB | 1 | Nebenträger | HEA 120 | 0.698 | Wartung_FFB | 43.06 | 81.226 | 6.998 | 46.04 | 81.226 | 6.998 | 0 | 0.06 | 0.057 | 0122Tra0000008590 | m | T110 | false | HI_UZV_HEA_STA_0,120_xxx | 0
Nebenträger | Wartung_FFB | 1 | Nebenträger | HEA 120 | 0.698 | Wartung_FFB | 46.06 | 81.226 | 6.998 | 49.04 | 81.226 | 6.998 | 0 | 0.06 | 0.057 | 0122Tra0000008592 | m | T110 | false | HI_UZV_HEA_STA_0,120_xxx | 0
Nebenträger | Wartung_FFB | 1 | Nebenträger | HEA 120 | 0.698 | Wartung_FFB | 49.06 | 81.226 | 6.998 | 52.04 | 81.226 | 6.998 | 0 | 0.06 | 0.057 | 0122Tra0000008594 | m | T110 | false | HI_UZV_HEA_STA_0,120_xxx | 0
Nebenträger | Wartung_FFB | 1 | Nebenträger | HEA 120 | 0.698 | Wartung_FFB | 52.06 | 81.226 | 6.998 | 55.04 | 81.226 | 6.998 | 0 | 0.06 | 0.057 | 0122Tra0000008596 | m | T110 | false | HI_UZV_HEA_STA_0,120_xxx | 0
Nebenträger | Wartung_FFB | 1 | Nebenträger | HEA 120 | 0.698 | Wartung_FFB | 55.06 | 81.226 | 6.998 | 58.04 | 81.226 | 6.998 | 0 | 0.06 | 0.057 | 0122Tra0000008598 | m | T110 | false | HI_UZV_HEA_STA_0,120_xxx | 0
Nebenträger | Wartung_FFB | 1 | Nebenträger | HEA 120 | 0.698 | Wartung_FFB | 58.06 | 81.226 | 6.998 | 61.04 | 81.226 | 6.998 | 0 | 0.06 | 0.057 | 0122Tra0000008600 | m | T110 | false | HI_UZV_HEA_STA_0,120_xxx | 0
Nebenträger | Wartung_FFB | 1 | Nebenträger | HEA 120 | 0.698 | Wartung_FFB | 61.06 | 81.226 | 6.998 | 64.04 | 81.226 | 6.998 | 0 | 0.06 | 0.057 | 0122Tra0000008602 | m | T110 | false | HI_UZV_HEA_STA_0,120_xxx | 0
Nebenträger | Wartung_FFB | 1 | Nebenträger | HEA 120 | 0.698 | Wartung_FFB | 10.56 | 81.226 | 6.998 | 13.04 | 81.226 | 6.998 | 0 | 0.06 | 0.057 | 0122Tra0000008604 | m | T110 | false | HI_UZV_HEA_STA_0,120_xxx | 0
Nebenträger | Wartung_FFB | 1 | Nebenträger | HEA 120 | 0.698 | Wartung_FFB | 64.06 | 79.726 | 6.998 | 67.04 | 79.726 | 6.998 | 0 | 0.06 | 0.057 | 0122Tra0000008643 | m | T110 | false | HI_UZV_HEA_STA_0,120_xxx | 0
Nebenträger | Wartung_FFB | 1 | Nebenträger | HEA 120 | 0.698 | Wartung_FFB | 67.06 | 79.726 | 6.998 | 70.04 | 79.726 | 6.998 | 0 | 0.06 | 0.057 | 0122Tra0000008645 | m | T110 | false | HI_UZV_HEA_STA_0,120_xxx | 0
Nebenträger | Wartung_FFB | 1 | Nebenträger | HEA 120 | 0.698 | Wartung_FFB | 70.06 | 79.726 | 6.998 | 73.04 | 79.726 | 6.998 | 0 | 0.06 | 0.057 | 0122Tra0000008647 | m | T110 | false | HI_UZV_HEA_STA_0,120_xxx | 0
Nebenträger | Wartung_FFB | 1 | Nebenträger | HEA 120 | 0.698 | Wartung_FFB | 73.06 | 79.726 | 6.998 | 76.04 | 79.726 | 6.998 | 0 | 0.06 | 0.057 | 0122Tra0000008649 | m | T110 | false | HI_UZV_HEA_STA_0,120_xxx | 0
Nebenträger | Wartung_FFB | 1 | Nebenträger | HEA 120 | 0.698 | Wartung_FFB | 76.06 | 79.726 | 6.998 | 79.04 | 79.726 | 6.998 | 0 | 0.06 | 0.057 | 0122Tra0000008651 | m | T110 | false | HI_UZV_HEA_STA_0,120_xxx | 0
Nebenträger | Wartung_FFB | 1 | Nebenträger | HEA 120 | 0.698 | Wartung_FFB | 94.06 | 79.726 | 6.998 | 97.04 | 79.726 | 6.998 | 0 | 0.06 | 0.057 | 0122Tra0000008663 | m | T110 | false | HI_UZV_HEA_STA_0,120_xxx | 0
Nebenträger | Wartung_FFB | 1 | Nebenträger | HEA 120 | 0.698 | Wartung_FFB | 103.06 | 79.726 | 6.998 | 106.04 | 79.726 | 6.998 | 0 | 0.06 | 0.057 | 0122Tra0000008669 | m | T110 | false | HI_UZV_HEA_STA_0,120_xxx | 0
Nebenträger | Wartung_FFB | 1 | Nebenträger | HEA 120 | 0.698 | Wartung_FFB | 106.06 | 79.726 | 6.998 | 109.04 | 79.726 | 6.998 | 0 | 0.06 | 0.057 | 0122Tra0000008671 | m | T110 | false | HI_UZV_HEA_STA_0,120_xxx | 0
Nebenträger | Wartung_FFB | 1 | Nebenträger | HEA 120 | 0.698 | Wartung_FFB | 109.06 | 79.726 | 6.998 | 112.04 | 79.726 | 6.998 | 0 | 0.06 | 0.057 | 0122Tra0000008673 | m | T110 | false | HI_UZV_HEA_STA_0,120_xxx | 0
Nebenträger | Wartung_FFB | 1 | Nebenträger | HEA 120 | 0.698 | Wartung_FFB | 112.06 | 79.726 | 6.998 | 115.04 | 79.726 | 6.998 | 0 | 0.06 | 0.057 | 0122Tra0000008675 | m | T110 | false | HI_UZV_HEA_STA_0,120_xxx | 0
Nebenträger | Wartung_FFB | 1 | Nebenträger | HEA 120 | 0.698 | Wartung_FFB | 115.06 | 79.726 | 6.998 | 118.04 | 79.726 | 6.998 | 0 | 0.06 | 0.057 | 0122Tra0000008677 | m | T110 | false | HI_UZV_HEA_STA_0,120_xxx | 0
Nebenträger | Wartung_FFB | 1 | Nebenträger | HEA 120 | 0.698 | Wartung_FFB | 13.06 | 79.726 | 6.998 | 16.04 | 79.726 | 6.998 | 0 | 0.06 | 0.057 | 0122Tra0000008681 | m | T110 | false | HI_UZV_HEA_STA_0,120_xxx | 0
Nebenträger | Wartung_FFB | 1 | Nebenträger | HEA 120 | 0.698 | Wartung_FFB | 22.06 | 79.726 | 6.998 | 25.04 | 79.726 | 6.998 | 0 | 0.06 | 0.057 | 0122Tra0000008687 | m | T110 | false | HI_UZV_HEA_STA_0,120_xxx | 0
Nebenträger | Wartung_FFB | 1 | Nebenträger | HEA 120 | 0.698 | Wartung_FFB | 25.06 | 79.726 | 6.998 | 28.04 | 79.726 | 6.998 | 0 | 0.06 | 0.057 | 0122Tra0000008689 | m | T110 | false | HI_UZV_HEA_STA_0,120_xxx | 0
Nebenträger | Wartung_FFB | 1 | Nebenträger | HEA 120 | 0.698 | Wartung_FFB | 28.06 | 79.726 | 6.998 | 31.04 | 79.726 | 6.998 | 0 | 0.06 | 0.057 | 0122Tra0000008691 | m | T110 | false | HI_UZV_HEA_STA_0,120_xxx | 0
Nebenträger | Wartung_FFB | 1 | Nebenträger | HEA 120 | 0.698 | Wartung_FFB | 31.06 | 79.726 | 6.998 | 34.04 | 79.726 | 6.998 | 0 | 0.06 | 0.057 | 0122Tra0000008693 | m | T110 | false | HI_UZV_HEA_STA_0,120_xxx | 0
Nebenträger | Wartung_FFB | 1 | Nebenträger | HEA 120 | 0.698 | Wartung_FFB | 34.06 | 79.726 | 6.998 | 37.04 | 79.726 | 6.998 | 0 | 0.06 | 0.057 | 0122Tra0000008695 | m | T110 | false | HI_UZV_HEA_STA_0,120_xxx | 0
Nebenträger | Wartung_FFB | 1 | Nebenträger | HEA 120 | 0.698 | Wartung_FFB | 37.06 | 79.726 | 6.998 | 40.04 | 79.726 | 6.998 | 0 | 0.06 | 0.057 | 0122Tra0000008697 | m | T110 | false | HI_UZV_HEA_STA_0,120_xxx | 0
Nebenträger | Wartung_FFB | 1 | Nebenträger | HEA 120 | 0.698 | Wartung_FFB | 40.06 | 79.726 | 6.998 | 43.04 | 79.726 | 6.998 | 0 | 0.06 | 0.057 | 0122Tra0000008699 | m | T110 | false | HI_UZV_HEA_STA_0,120_xxx | 0
Nebenträger | Wartung_FFB | 1 | Nebenträger | HEA 120 | 0.698 | Wartung_FFB | 43.06 | 79.726 | 6.998 | 46.04 | 79.726 | 6.998 | 0 | 0.06 | 0.057 | 0122Tra0000008701 | m | T110 | false | HI_UZV_HEA_STA_0,120_xxx | 0
Nebenträger | Wartung_FFB | 1 | Nebenträger | HEA 120 | 0.698 | Wartung_FFB | 46.06 | 79.726 | 6.998 | 49.04 | 79.726 | 6.998 | 0 | 0.06 | 0.057 | 0122Tra0000008703 | m | T110 | false | HI_UZV_HEA_STA_0,120_xxx | 0
Nebenträger | Wartung_FFB | 1 | Nebenträger | HEA 120 | 0.698 | Wartung_FFB | 49.06 | 79.726 | 6.998 | 52.04 | 79.726 | 6.998 | 0 | 0.06 | 0.057 | 0122Tra0000008705 | m | T110 | false | HI_UZV_HEA_STA_0,120_xxx | 0
Nebenträger | Wartung_FFB | 1 | Nebenträger | HEA 120 | 0.698 | Wartung_FFB | 52.06 | 79.726 | 6.998 | 55.04 | 79.726 | 6.998 | 0 | 0.06 | 0.057 | 0122Tra0000008707 | m | T110 | false | HI_UZV_HEA_STA_0,120_xxx | 0
Nebenträger | Wartung_FFB | 1 | Nebenträger | HEA 120 | 0.698 | Wartung_FFB | 55.06 | 79.726 | 6.998 | 58.04 | 79.726 | 6.998 | 0 | 0.06 | 0.057 | 0122Tra0000008709 | m | T110 | false | HI_UZV_HEA_STA_0,120_xxx | 0
Nebenträger | Wartung_FFB | 1 | Nebenträger | HEA 120 | 0.698 | Wartung_FFB | 58.06 | 79.726 | 6.998 | 61.04 | 79.726 | 6.998 | 0 | 0.06 | 0.057 | 0122Tra0000008711 | m | T110 | false | HI_UZV_HEA_STA_0,120_xxx | 0
Nebenträger | Wartung_FFB | 1 | Nebenträger | HEA 120 | 0.698 | Wartung_FFB | 61.06 | 79.726 | 6.998 | 64.04 | 79.726 | 6.998 | 0 | 0.06 | 0.057 | 0122Tra0000008713 | m | T110 | false | HI_UZV_HEA_STA_0,120_xxx | 0
Nebenträger | Wartung_FFB | 1 | Nebenträger | HEA 120 | 0.698 | Wartung_FFB | 10.56 | 79.726 | 6.998 | 13.04 | 79.726 | 6.998 | 0 | 0.06 | 0.057 | 0122Tra0000008715 | m | T110 | false | HI_UZV_HEA_STA_0,120_xxx | 0
Nebenträger | Wartung_FFB | 1 | Nebenträger | HEA 120 | 0.698 | Wartung_FFB | 64.06 | 78.226 | 6.998 | 67.04 | 78.226 | 6.998 | 0 | 0.06 | 0.057 | 0122Tra0000008754 | m | T110 | false | HI_UZV_HEA_STA_0,120_xxx | 0
Nebenträger | Wartung_FFB | 1 | Nebenträger | HEA 120 | 0.698 | Wartung_FFB | 67.06 | 78.226 | 6.998 | 70.04 | 78.226 | 6.998 | 0 | 0.06 | 0.057 | 0122Tra0000008756 | m | T110 | false | HI_UZV_HEA_STA_0,120_xxx | 0
Nebenträger | Wartung_FFB | 1 | Nebenträger | HEA 120 | 0.698 | Wartung_FFB | 70.06 | 78.226 | 6.998 | 73.04 | 78.226 | 6.998 | 0 | 0.06 | 0.057 | 0122Tra0000008758 | m | T110 | false | HI_UZV_HEA_STA_0,120_xxx | 0
Nebenträger | Wartung_FFB | 1 | Nebenträger | HEA 120 | 0.698 | Wartung_FFB | 73.06 | 78.226 | 6.998 | 76.04 | 78.226 | 6.998 | 0 | 0.06 | 0.057 | 0122Tra0000008760 | m | T110 | false | HI_UZV_HEA_STA_0,120_xxx | 0
Nebenträger | Wartung_FFB | 1 | Nebenträger | HEA 120 | 0.698 | Wartung_FFB | 76.06 | 78.226 | 6.998 | 79.04 | 78.226 | 6.998 | 0 | 0.06 | 0.057 | 0122Tra0000008762 | m | T110 | false | HI_UZV_HEA_STA_0,120_xxx | 0
Nebenträger | Wartung_FFB | 1 | Nebenträger | HEA 120 | 0.698 | Wartung_FFB | 94.06 | 78.226 | 6.998 | 97.04 | 78.226 | 6.998 | 0 | 0.06 | 0.057 | 0122Tra0000008774 | m | T110 | false | HI_UZV_HEA_STA_0,120_xxx | 0
Nebenträger | Wartung_FFB | 1 | Nebenträger | HEA 120 | 0.698 | Wartung_FFB | 103.06 | 78.226 | 6.998 | 106.04 | 78.226 | 6.998 | 0 | 0.06 | 0.057 | 0122Tra0000008780 | m | T110 | false | HI_UZV_HEA_STA_0,120_xxx | 0
Nebenträger | Wartung_FFB | 1 | Nebenträger | HEA 120 | 0.698 | Wartung_FFB | 106.06 | 78.226 | 6.998 | 109.04 | 78.226 | 6.998 | 0 | 0.06 | 0.057 | 0122Tra0000008782 | m | T110 | false | HI_UZV_HEA_STA_0,120_xxx | 0
Nebenträger | Wartung_FFB | 1 | Nebenträger | HEA 120 | 0.698 | Wartung_FFB | 109.06 | 78.226 | 6.998 | 112.04 | 78.226 | 6.998 | 0 | 0.06 | 0.057 | 0122Tra0000008784 | m | T110 | false | HI_UZV_HEA_STA_0,120_xxx | 0
Nebenträger | Wartung_FFB | 1 | Nebenträger | HEA 120 | 0.698 | Wartung_FFB | 112.06 | 78.226 | 6.998 | 115.04 | 78.226 | 6.998 | 0 | 0.06 | 0.057 | 0122Tra0000008786 | m | T110 | false | HI_UZV_HEA_STA_0,120_xxx | 0
Nebenträger | Wartung_FFB | 1 | Nebenträger | HEA 120 | 0.698 | Wartung_FFB | 115.06 | 78.226 | 6.998 | 118.04 | 78.226 | 6.998 | 0 | 0.06 | 0.057 | 0122Tra0000008788 | m | T110 | false | HI_UZV_HEA_STA_0,120_xxx | 0
Nebenträger | Wartung_FFB | 1 | Nebenträger | HEA 120 | 0.698 | Wartung_FFB | 13.06 | 78.226 | 6.998 | 16.04 | 78.226 | 6.998 | 0 | 0.06 | 0.057 | 0122Tra0000008792 | m | T110 | false | HI_UZV_HEA_STA_0,120_xxx | 0
Nebenträger | Wartung_FFB | 1 | Nebenträger | HEA 120 | 0.698 | Wartung_FFB | 22.06 | 78.226 | 6.998 | 25.04 | 78.226 | 6.998 | 0 | 0.06 | 0.057 | 0122Tra0000008798 | m | T110 | false | HI_UZV_HEA_STA_0,120_xxx | 0
Nebenträger | Wartung_FFB | 1 | Nebenträger | HEA 120 | 0.698 | Wartung_FFB | 25.06 | 78.226 | 6.998 | 28.04 | 78.226 | 6.998 | 0 | 0.06 | 0.057 | 0122Tra0000008800 | m | T110 | false | HI_UZV_HEA_STA_0,120_xxx | 0
Nebenträger | Wartung_FFB | 1 | Nebenträger | HEA 120 | 0.698 | Wartung_FFB | 28.06 | 78.226 | 6.998 | 31.04 | 78.226 | 6.998 | 0 | 0.06 | 0.057 | 0122Tra0000008802 | m | T110 | false | HI_UZV_HEA_STA_0,120_xxx | 0
Nebenträger | Wartung_FFB | 1 | Nebenträger | HEA 120 | 0.698 | Wartung_FFB | 31.06 | 78.226 | 6.998 | 34.04 | 78.226 | 6.998 | 0 | 0.06 | 0.057 | 0122Tra0000008804 | m | T110 | false | HI_UZV_HEA_STA_0,120_xxx | 0
Nebenträger | Wartung_FFB | 1 | Nebenträger | HEA 120 | 0.698 | Wartung_FFB | 34.06 | 78.226 | 6.998 | 37.04 | 78.226 | 6.998 | 0 | 0.06 | 0.057 | 0122Tra0000008806 | m | T110 | false | HI_UZV_HEA_STA_0,120_xxx | 0
Nebenträger | Wartung_FFB | 1 | Nebenträger | HEA 120 | 0.698 | Wartung_FFB | 37.06 | 78.226 | 6.998 | 40.04 | 78.226 | 6.998 | 0 | 0.06 | 0.057 | 0122Tra0000008808 | m | T110 | false | HI_UZV_HEA_STA_0,120_xxx | 0
Nebenträger | Wartung_FFB | 1 | Nebenträger | HEA 120 | 0.698 | Wartung_FFB | 40.06 | 78.226 | 6.998 | 43.04 | 78.226 | 6.998 | 0 | 0.06 | 0.057 | 0122Tra0000008810 | m | T110 | false | HI_UZV_HEA_STA_0,120_xxx | 0
Nebenträger | Wartung_FFB | 1 | Nebenträger | HEA 120 | 0.698 | Wartung_FFB | 43.06 | 78.226 | 6.998 | 46.04 | 78.226 | 6.998 | 0 | 0.06 | 0.057 | 0122Tra0000008812 | m | T110 | false | HI_UZV_HEA_STA_0,120_xxx | 0
Nebenträger | Wartung_FFB | 1 | Nebenträger | HEA 120 | 0.698 | Wartung_FFB | 46.06 | 78.226 | 6.998 | 49.04 | 78.226 | 6.998 | 0 | 0.06 | 0.057 | 0122Tra0000008814 | m | T110 | false | HI_UZV_HEA_STA_0,120_xxx | 0
Nebenträger | Wartung_FFB | 1 | Nebenträger | HEA 120 | 0.698 | Wartung_FFB | 49.06 | 78.226 | 6.998 | 52.04 | 78.226 | 6.998 | 0 | 0.06 | 0.057 | 0122Tra0000008816 | m | T110 | false | HI_UZV_HEA_STA_0,120_xxx | 0
Nebenträger | Wartung_FFB | 1 | Nebenträger | HEA 120 | 0.698 | Wartung_FFB | 52.06 | 78.226 | 6.998 | 55.04 | 78.226 | 6.998 | 0 | 0.06 | 0.057 | 0122Tra0000008818 | m | T110 | false | HI_UZV_HEA_STA_0,120_xxx | 0
Nebenträger | Wartung_FFB | 1 | Nebenträger | HEA 120 | 0.698 | Wartung_FFB | 55.06 | 78.226 | 6.998 | 58.04 | 78.226 | 6.998 | 0 | 0.06 | 0.057 | 0122Tra0000008820 | m | T110 | false | HI_UZV_HEA_STA_0,120_xxx | 0
Nebenträger | Wartung_FFB | 1 | Nebenträger | HEA 120 | 0.698 | Wartung_FFB | 58.06 | 78.226 | 6.998 | 61.04 | 78.226 | 6.998 | 0 | 0.06 | 0.057 | 0122Tra0000008822 | m | T110 | false | HI_UZV_HEA_STA_0,120_xxx | 0
Nebenträger | Wartung_FFB | 1 | Nebenträger | HEA 120 | 0.698 | Wartung_FFB | 61.06 | 78.226 | 6.998 | 64.04 | 78.226 | 6.998 | 0 | 0.06 | 0.057 | 0122Tra0000008824 | m | T110 | false | HI_UZV_HEA_STA_0,120_xxx | 0
Nebenträger | Wartung_FFB | 1 | Nebenträger | HEA 120 | 0.698 | Wartung_FFB | 10.56 | 78.226 | 6.998 | 13.04 | 78.226 | 6.998 | 0 | 0.06 | 0.057 | 0122Tra0000008826 | m | T110 | false | HI_UZV_HEA_STA_0,120_xxx | 0
Nebenträger | Wartung_FFB | 1 | Nebenträger | HEA 120 | 0.698 | Wartung_FFB | 64.06 | 76.726 | 6.998 | 67.04 | 76.726 | 6.998 | 0 | 0.06 | 0.057 | 0122Tra0000008865 | m | T110 | false | HI_UZV_HEA_STA_0,120_xxx | 0
Nebenträger | Wartung_FFB | 1 | Nebenträger | HEA 120 | 0.698 | Wartung_FFB | 67.06 | 76.726 | 6.998 | 70.04 | 76.726 | 6.998 | 0 | 0.06 | 0.057 | 0122Tra0000008867 | m | T110 | false | HI_UZV_HEA_STA_0,120_xxx | 0
Nebenträger | Wartung_FFB | 1 | Nebenträger | HEA 120 | 0.698 | Wartung_FFB | 70.06 | 76.726 | 6.998 | 73.04 | 76.726 | 6.998 | 0 | 0.06 | 0.057 | 0122Tra0000008869 | m | T110 | false | HI_UZV_HEA_STA_0,120_xxx | 0
Nebenträger | Wartung_FFB | 1 | Nebenträger | HEA 120 | 0.698 | Wartung_FFB | 73.06 | 76.726 | 6.998 | 76.04 | 76.726 | 6.998 | 0 | 0.06 | 0.057 | 0122Tra0000008871 | m | T110 | false | HI_UZV_HEA_STA_0,120_xxx | 0
Nebenträger | Wartung_FFB | 1 | Nebenträger | HEA 120 | 0.698 | Wartung_FFB | 76.06 | 76.726 | 6.998 | 79.04 | 76.726 | 6.998 | 0 | 0.06 | 0.057 | 0122Tra0000008873 | m | T110 | false | HI_UZV_HEA_STA_0,120_xxx | 0
Nebenträger | Wartung_FFB | 1 | Nebenträger | HEA 120 | 0.698 | Wartung_FFB | 94.06 | 76.726 | 6.998 | 97.04 | 76.726 | 6.998 | 0 | 0.06 | 0.057 | 0122Tra0000008885 | m | T110 | false | HI_UZV_HEA_STA_0,120_xxx | 0
Nebenträger | Wartung_FFB | 1 | Nebenträger | HEA 120 | 0.698 | Wartung_FFB | 103.06 | 76.726 | 6.998 | 106.04 | 76.726 | 6.998 | 0 | 0.06 | 0.057 | 0122Tra0000008891 | m | T110 | false | HI_UZV_HEA_STA_0,120_xxx | 0
Nebenträger | Wartung_FFB | 1 | Nebenträger | HEA 120 | 0.698 | Wartung_FFB | 106.06 | 76.726 | 6.998 | 109.04 | 76.726 | 6.998 | 0 | 0.06 | 0.057 | 0122Tra0000008893 | m | T110 | false | HI_UZV_HEA_STA_0,120_xxx | 0
Nebenträger | Wartung_FFB | 1 | Nebenträger | HEA 120 | 0.698 | Wartung_FFB | 109.06 | 76.726 | 6.998 | 112.04 | 76.726 | 6.998 | 0 | 0.06 | 0.057 | 0122Tra0000008895 | m | T110 | false | HI_UZV_HEA_STA_0,120_xxx | 0
Nebenträger | Wartung_FFB | 1 | Nebenträger | HEA 120 | 0.698 | Wartung_FFB | 112.06 | 76.726 | 6.998 | 115.04 | 76.726 | 6.998 | 0 | 0.06 | 0.057 | 0122Tra0000008897 | m | T110 | false | HI_UZV_HEA_STA_0,120_xxx | 0
Nebenträger | Wartung_FFB | 1 | Nebenträger | HEA 120 | 0.698 | Wartung_FFB | 115.06 | 76.726 | 6.998 | 118.04 | 76.726 | 6.998 | 0 | 0.06 | 0.057 | 0122Tra0000008899 | m | T110 | false | HI_UZV_HEA_STA_0,120_xxx | 0
Nebenträger | Wartung_FFB | 1 | Nebenträger | HEA 120 | 0.698 | Wartung_FFB | 13.06 | 76.726 | 6.998 | 16.04 | 76.726 | 6.998 | 0 | 0.06 | 0.057 | 0122Tra0000008903 | m | T110 | false | HI_UZV_HEA_STA_0,120_xxx | 0
Nebenträger | Wartung_FFB | 1 | Nebenträger | HEA 120 | 0.698 | Wartung_FFB | 22.06 | 76.726 | 6.998 | 25.04 | 76.726 | 6.998 | 0 | 0.06 | 0.057 | 0122Tra0000008909 | m | T110 | false | HI_UZV_HEA_STA_0,120_xxx | 0
Nebenträger | Wartung_FFB | 1 | Nebenträger | HEA 120 | 0.698 | Wartung_FFB | 25.06 | 76.726 | 6.998 | 28.04 | 76.726 | 6.998 | 0 | 0.06 | 0.057 | 0122Tra0000008911 | m | T110 | false | HI_UZV_HEA_STA_0,120_xxx | 0
Nebenträger | Wartung_FFB | 1 | Nebenträger | HEA 120 | 0.698 | Wartung_FFB | 28.06 | 76.726 | 6.998 | 31.04 | 76.726 | 6.998 | 0 | 0.06 | 0.057 | 0122Tra0000008913 | m | T110 | false | HI_UZV_HEA_STA_0,120_xxx | 0
Nebenträger | Wartung_FFB | 1 | Nebenträger | HEA 120 | 0.698 | Wartung_FFB | 31.06 | 76.726 | 6.998 | 34.04 | 76.726 | 6.998 | 0 | 0.06 | 0.057 | 0122Tra0000008915 | m | T110 | false | HI_UZV_HEA_STA_0,120_xxx | 0
Nebenträger | Wartung_FFB | 1 | Nebenträger | HEA 120 | 0.698 | Wartung_FFB | 34.06 | 76.726 | 6.998 | 37.04 | 76.726 | 6.998 | 0 | 0.06 | 0.057 | 0122Tra0000008917 | m | T110 | false | HI_UZV_HEA_STA_0,120_xxx | 0
Nebenträger | Wartung_FFB | 1 | Nebenträger | HEA 120 | 0.698 | Wartung_FFB | 37.06 | 76.726 | 6.998 | 40.04 | 76.726 | 6.998 | 0 | 0.06 | 0.057 | 0122Tra0000008919 | m | T110 | false | HI_UZV_HEA_STA_0,120_xxx | 0
Nebenträger | Wartung_FFB | 1 | Nebenträger | HEA 120 | 0.698 | Wartung_FFB | 40.06 | 76.726 | 6.998 | 43.04 | 76.726 | 6.998 | 0 | 0.06 | 0.057 | 0122Tra0000008921 | m | T110 | false | HI_UZV_HEA_STA_0,120_xxx | 0
Nebenträger | Wartung_FFB | 1 | Nebenträger | HEA 120 | 0.698 | Wartung_FFB | 43.06 | 76.726 | 6.998 | 46.04 | 76.726 | 6.998 | 0 | 0.06 | 0.057 | 0122Tra0000008923 | m | T110 | false | HI_UZV_HEA_STA_0,120_xxx | 0
Nebenträger | Wartung_FFB | 1 | Nebenträger | HEA 120 | 0.698 | Wartung_FFB | 46.06 | 76.726 | 6.998 | 49.04 | 76.726 | 6.998 | 0 | 0.06 | 0.057 | 0122Tra0000008925 | m | T110 | false | HI_UZV_HEA_STA_0,120_xxx | 0
Nebenträger | Wartung_FFB | 1 | Nebenträger | HEA 120 | 0.698 | Wartung_FFB | 49.06 | 76.726 | 6.998 | 52.04 | 76.726 | 6.998 | 0 | 0.06 | 0.057 | 0122Tra0000008927 | m | T110 | false | HI_UZV_HEA_STA_0,120_xxx | 0
Nebenträger | Wartung_FFB | 1 | Nebenträger | HEA 120 | 0.698 | Wartung_FFB | 52.06 | 76.726 | 6.998 | 55.04 | 76.726 | 6.998 | 0 | 0.06 | 0.057 | 0122Tra0000008929 | m | T110 | false | HI_UZV_HEA_STA_0,120_xxx | 0
Nebenträger | Wartung_FFB | 1 | Nebenträger | HEA 120 | 0.698 | Wartung_FFB | 55.06 | 76.726 | 6.998 | 58.04 | 76.726 | 6.998 | 0 | 0.06 | 0.057 | 0122Tra0000008931 | m | T110 | false | HI_UZV_HEA_STA_0,120_xxx | 0
Nebenträger | Wartung_FFB | 1 | Nebenträger | HEA 120 | 0.698 | Wartung_FFB | 58.06 | 76.726 | 6.998 | 61.04 | 76.726 | 6.998 | 0 | 0.06 | 0.057 | 0122Tra0000008933 | m | T110 | false | HI_UZV_HEA_STA_0,120_xxx | 0
Nebenträger | Wartung_FFB | 1 | Nebenträger | HEA 120 | 0.698 | Wartung_FFB | 61.06 | 76.726 | 6.998 | 64.04 | 76.726 | 6.998 | 0 | 0.06 | 0.057 | 0122Tra0000008935 | m | T110 | false | HI_UZV_HEA_STA_0,120_xxx | 0
Nebenträger | Wartung_FFB | 1 | Nebenträger | HEA 120 | 0.698 | Wartung_FFB | 10.56 | 76.726 | 6.998 | 13.04 | 76.726 | 6.998 | 0 | 0.06 | 0.057 | 0122Tra0000008937 | m | T110 | false | HI_UZV_HEA_STA_0,120_xxx | 0
Nebenträger | Wartung_FFB | 1 | Nebenträger | HEA 120 | 0.698 | Wartung_FFB | 64.06 | 75.226 | 6.998 | 67.04 | 75.226 | 6.998 | 0 | 0.06 | 0.057 | 0122Tra0000008976 | m | T110 | false | HI_UZV_HEA_STA_0,120_xxx | 0
Nebenträger | Wartung_FFB | 1 | Nebenträger | HEA 120 | 0.698 | Wartung_FFB | 67.06 | 75.226 | 6.998 | 70.04 | 75.226 | 6.998 | 0 | 0.06 | 0.057 | 0122Tra0000008978 | m | T110 | false | HI_UZV_HEA_STA_0,120_xxx | 0
Nebenträger | Wartung_FFB | 1 | Nebenträger | HEA 120 | 0.698 | Wartung_FFB | 70.06 | 75.226 | 6.998 | 73.04 | 75.226 | 6.998 | 0 | 0.06 | 0.057 | 0122Tra0000008980 | m | T110 | false | HI_UZV_HEA_STA_0,120_xxx | 0
Nebenträger | Wartung_FFB | 1 | Nebenträger | HEA 120 | 0.698 | Wartung_FFB | 73.06 | 75.226 | 6.998 | 76.04 | 75.226 | 6.998 | 0 | 0.06 | 0.057 | 0122Tra0000008982 | m | T110 | false | HI_UZV_HEA_STA_0,120_xxx | 0
Nebenträger | Wartung_FFB | 1 | Nebenträger | HEA 120 | 0.698 | Wartung_FFB | 76.06 | 75.226 | 6.998 | 79.04 | 75.226 | 6.998 | 0 | 0.06 | 0.057 | 0122Tra0000008984 | m | T110 | false | HI_UZV_HEA_STA_0,120_xxx | 0
Nebenträger | Wartung_FFB | 1 | Nebenträger | HEA 120 | 0.698 | Wartung_FFB | 94.06 | 75.226 | 6.998 | 97.04 | 75.226 | 6.998 | 0 | 0.06 | 0.057 | 0122Tra0000008996 | m | T110 | false | HI_UZV_HEA_STA_0,120_xxx | 0
Nebenträger | Wartung_FFB | 1 | Nebenträger | HEA 120 | 0.698 | Wartung_FFB | 103.06 | 75.226 | 6.998 | 106.04 | 75.226 | 6.998 | 0 | 0.06 | 0.057 | 0122Tra0000009002 | m | T110 | false | HI_UZV_HEA_STA_0,120_xxx | 0
Nebenträger | Wartung_FFB | 1 | Nebenträger | HEA 120 | 0.698 | Wartung_FFB | 106.06 | 75.226 | 6.998 | 109.04 | 75.226 | 6.998 | 0 | 0.06 | 0.057 | 0122Tra0000009004 | m | T110 | false | HI_UZV_HEA_STA_0,120_xxx | 0
Nebenträger | Wartung_FFB | 1 | Nebenträger | HEA 120 | 0.698 | Wartung_FFB | 109.06 | 75.226 | 6.998 | 112.04 | 75.226 | 6.998 | 0 | 0.06 | 0.057 | 0122Tra0000009006 | m | T110 | false | HI_UZV_HEA_STA_0,120_xxx | 0
Nebenträger | Wartung_FFB | 1 | Nebenträger | HEA 120 | 0.698 | Wartung_FFB | 112.06 | 75.226 | 6.998 | 115.04 | 75.226 | 6.998 | 0 | 0.06 | 0.057 | 0122Tra0000009008 | m | T110 | false | HI_UZV_HEA_STA_0,120_xxx | 0
Nebenträger | Wartung_FFB | 1 | Nebenträger | HEA 120 | 0.698 | Wartung_FFB | 115.06 | 75.226 | 6.998 | 118.04 | 75.226 | 6.998 | 0 | 0.06 | 0.057 | 0122Tra0000009010 | m | T110 | false | HI_UZV_HEA_STA_0,120_xxx | 0
Nebenträger | Wartung_FFB | 1 | Nebenträger | HEA 120 | 0.698 | Wartung_FFB | 13.06 | 75.226 | 6.998 | 16.04 | 75.226 | 6.998 | 0 | 0.06 | 0.057 | 0122Tra0000009014 | m | T110 | false | HI_UZV_HEA_STA_0,120_xxx | 0
Nebenträger | Wartung_FFB | 1 | Nebenträger | HEA 120 | 0.698 | Wartung_FFB | 22.06 | 75.226 | 6.998 | 25.04 | 75.226 | 6.998 | 0 | 0.06 | 0.057 | 0122Tra0000009020 | m | T110 | false | HI_UZV_HEA_STA_0,120_xxx | 0
Nebenträger | Wartung_FFB | 1 | Nebenträger | HEA 120 | 0.698 | Wartung_FFB | 25.06 | 75.226 | 6.998 | 28.04 | 75.226 | 6.998 | 0 | 0.06 | 0.057 | 0122Tra0000009022 | m | T110 | false | HI_UZV_HEA_STA_0,120_xxx | 0
Nebenträger | Wartung_FFB | 1 | Nebenträger | HEA 120 | 0.698 | Wartung_FFB | 28.06 | 75.226 | 6.998 | 31.04 | 75.226 | 6.998 | 0 | 0.06 | 0.057 | 0122Tra0000009024 | m | T110 | false | HI_UZV_HEA_STA_0,120_xxx | 0
Nebenträger | Wartung_FFB | 1 | Nebenträger | HEA 120 | 0.698 | Wartung_FFB | 31.06 | 75.226 | 6.998 | 34.04 | 75.226 | 6.998 | 0 | 0.06 | 0.057 | 0122Tra0000009026 | m | T110 | false | HI_UZV_HEA_STA_0,120_xxx | 0
Nebenträger | Wartung_FFB | 1 | Nebenträger | HEA 120 | 0.698 | Wartung_FFB | 34.06 | 75.226 | 6.998 | 37.04 | 75.226 | 6.998 | 0 | 0.06 | 0.057 | 0122Tra0000009028 | m | T110 | false | HI_UZV_HEA_STA_0,120_xxx | 0
Nebenträger | Wartung_FFB | 1 | Nebenträger | HEA 120 | 0.698 | Wartung_FFB | 37.06 | 75.226 | 6.998 | 40.04 | 75.226 | 6.998 | 0 | 0.06 | 0.057 | 0122Tra0000009030 | m | T110 | false | HI_UZV_HEA_STA_0,120_xxx | 0
Nebenträger | Wartung_FFB | 1 | Nebenträger | HEA 120 | 0.698 | Wartung_FFB | 40.06 | 75.226 | 6.998 | 43.04 | 75.226 | 6.998 | 0 | 0.06 | 0.057 | 0122Tra0000009032 | m | T110 | false | HI_UZV_HEA_STA_0,120_xxx | 0
Nebenträger | Wartung_FFB | 1 | Nebenträger | HEA 120 | 0.698 | Wartung_FFB | 43.06 | 75.226 | 6.998 | 46.04 | 75.226 | 6.998 | 0 | 0.06 | 0.057 | 0122Tra0000009034 | m | T110 | false | HI_UZV_HEA_STA_0,120_xxx | 0
Nebenträger | Wartung_FFB | 1 | Nebenträger | HEA 120 | 0.698 | Wartung_FFB | 46.06 | 75.226 | 6.998 | 49.04 | 75.226 | 6.998 | 0 | 0.06 | 0.057 | 0122Tra0000009036 | m | T110 | false | HI_UZV_HEA_STA_0,120_xxx | 0
Nebenträger | Wartung_FFB | 1 | Nebenträger | HEA 120 | 0.698 | Wartung_FFB | 49.06 | 75.226 | 6.998 | 52.04 | 75.226 | 6.998 | 0 | 0.06 | 0.057 | 0122Tra0000009038 | m | T110 | false | HI_UZV_HEA_STA_0,120_xxx | 0
Nebenträger | Wartung_FFB | 1 | Nebenträger | HEA 120 | 0.698 | Wartung_FFB | 52.06 | 75.226 | 6.998 | 55.04 | 75.226 | 6.998 | 0 | 0.06 | 0.057 | 0122Tra0000009040 | m | T110 | false | HI_UZV_HEA_STA_0,120_xxx | 0
Nebenträger | Wartung_FFB | 1 | Nebenträger | HEA 120 | 0.698 | Wartung_FFB | 55.06 | 75.226 | 6.998 | 58.04 | 75.226 | 6.998 | 0 | 0.06 | 0.057 | 0122Tra0000009042 | m | T110 | false | HI_UZV_HEA_STA_0,120_xxx | 0
Nebenträger | Wartung_FFB | 1 | Nebenträger | HEA 120 | 0.698 | Wartung_FFB | 58.06 | 75.226 | 6.998 | 61.04 | 75.226 | 6.998 | 0 | 0.06 | 0.057 | 0122Tra0000009044 | m | T110 | false | HI_UZV_HEA_STA_0,120_xxx | 0
Nebenträger | Wartung_FFB | 1 | Nebenträger | HEA 120 | 0.698 | Wartung_FFB | 61.06 | 75.226 | 6.998 | 64.04 | 75.226 | 6.998 | 0 | 0.06 | 0.057 | 0122Tra0000009046 | m | T110 | false | HI_UZV_HEA_STA_0,120_xxx | 0
Nebenträger | Wartung_FFB | 1 | Nebenträger | HEA 120 | 0.698 | Wartung_FFB | 10.56 | 75.226 | 6.998 | 13.04 | 75.226 | 6.998 | 0 | 0.06 | 0.057 | 0122Tra0000009048 | m | T110 | false | HI_UZV_HEA_STA_0,120_xxx | 0
Nebenträger | Wartung_FFB | 1 | Nebenträger | HEA 120 | 0.698 | Wartung_FFB | 64.06 | 73.726 | 6.998 | 67.04 | 73.726 | 6.998 | 0 | 0.06 | 0.057 | 0122Tra0000009087 | m | T110 | false | HI_UZV_HEA_STA_0,120_xxx | 0
Nebenträger | Wartung_FFB | 1 | Nebenträger | HEA 120 | 0.698 | Wartung_FFB | 67.06 | 73.726 | 6.998 | 70.04 | 73.726 | 6.998 | 0 | 0.06 | 0.057 | 0122Tra0000009089 | m | T110 | false | HI_UZV_HEA_STA_0,120_xxx | 0
Nebenträger | Wartung_FFB | 1 | Nebenträger | HEA 120 | 0.698 | Wartung_FFB | 70.06 | 73.726 | 6.998 | 73.04 | 73.726 | 6.998 | 0 | 0.06 | 0.057 | 0122Tra0000009091 | m | T110 | false | HI_UZV_HEA_STA_0,120_xxx | 0
Nebenträger | Wartung_FFB | 1 | Nebenträger | HEA 120 | 0.698 | Wartung_FFB | 73.06 | 73.726 | 6.998 | 76.04 | 73.726 | 6.998 | 0 | 0.06 | 0.057 | 0122Tra0000009093 | m | T110 | false | HI_UZV_HEA_STA_0,120_xxx | 0
Nebenträger | Wartung_FFB | 1 | Nebenträger | HEA 120 | 0.698 | Wartung_FFB | 76.06 | 73.726 | 6.998 | 79.04 | 73.726 | 6.998 | 0 | 0.06 | 0.057 | 0122Tra0000009095 | m | T110 | false | HI_UZV_HEA_STA_0,120_xxx | 0
Nebenträger | Wartung_FFB | 1 | Nebenträger | HEA 120 | 0.698 | Wartung_FFB | 94.06 | 73.726 | 6.998 | 97.04 | 73.726 | 6.998 | 0 | 0.06 | 0.057 | 0122Tra0000009107 | m | T110 | false | HI_UZV_HEA_STA_0,120_xxx | 0
Nebenträger | Wartung_FFB | 1 | Nebenträger | HEA 120 | 0.698 | Wartung_FFB | 103.06 | 73.726 | 6.998 | 106.04 | 73.726 | 6.998 | 0 | 0.06 | 0.057 | 0122Tra0000009113 | m | T110 | false | HI_UZV_HEA_STA_0,120_xxx | 0
Nebenträger | Wartung_FFB | 1 | Nebenträger | HEA 120 | 0.698 | Wartung_FFB | 106.06 | 73.726 | 6.998 | 109.04 | 73.726 | 6.998 | 0 | 0.06 | 0.057 | 0122Tra0000009115 | m | T110 | false | HI_UZV_HEA_STA_0,120_xxx | 0
Nebenträger | Wartung_FFB | 1 | Nebenträger | HEA 120 | 0.698 | Wartung_FFB | 109.06 | 73.726 | 6.998 | 112.04 | 73.726 | 6.998 | 0 | 0.06 | 0.057 | 0122Tra0000009117 | m | T110 | false | HI_UZV_HEA_STA_0,120_xxx | 0
Nebenträger | Wartung_FFB | 1 | Nebenträger | HEA 120 | 0.698 | Wartung_FFB | 112.06 | 73.726 | 6.998 | 115.04 | 73.726 | 6.998 | 0 | 0.06 | 0.057 | 0122Tra0000009119 | m | T110 | false | HI_UZV_HEA_STA_0,120_xxx | 0
Nebenträger | Wartung_FFB | 1 | Nebenträger | HEA 120 | 0.698 | Wartung_FFB | 115.06 | 73.726 | 6.998 | 118.04 | 73.726 | 6.998 | 0 | 0.06 | 0.057 | 0122Tra0000009121 | m | T110 | false | HI_UZV_HEA_STA_0,120_xxx | 0
Nebenträger | Wartung_FFB | 1 | Nebenträger | HEA 120 | 0.698 | Wartung_FFB | 13.06 | 73.726 | 6.998 | 16.04 | 73.726 | 6.998 | 0 | 0.06 | 0.057 | 0122Tra0000009125 | m | T110 | false | HI_UZV_HEA_STA_0,120_xxx | 0
Nebenträger | Wartung_FFB | 1 | Nebenträger | HEA 120 | 0.698 | Wartung_FFB | 22.06 | 73.726 | 6.998 | 25.04 | 73.726 | 6.998 | 0 | 0.06 | 0.057 | 0122Tra0000009131 | m | T110 | false | HI_UZV_HEA_STA_0,120_xxx | 0
Nebenträger | Wartung_FFB | 1 | Nebenträger | HEA 120 | 0.698 | Wartung_FFB | 25.06 | 73.726 | 6.998 | 28.04 | 73.726 | 6.998 | 0 | 0.06 | 0.057 | 0122Tra0000009133 | m | T110 | false | HI_UZV_HEA_STA_0,120_xxx | 0
Nebenträger | Wartung_FFB | 1 | Nebenträger | HEA 120 | 0.698 | Wartung_FFB | 28.06 | 73.726 | 6.998 | 31.04 | 73.726 | 6.998 | 0 | 0.06 | 0.057 | 0122Tra0000009135 | m | T110 | false | HI_UZV_HEA_STA_0,120_xxx | 0
Nebenträger | Wartung_FFB | 1 | Nebenträger | HEA 120 | 0.698 | Wartung_FFB | 31.06 | 73.726 | 6.998 | 34.04 | 73.726 | 6.998 | 0 | 0.06 | 0.057 | 0122Tra0000009137 | m | T110 | false | HI_UZV_HEA_STA_0,120_xxx | 0
Nebenträger | Wartung_FFB | 1 | Nebenträger | HEA 120 | 0.698 | Wartung_FFB | 34.06 | 73.726 | 6.998 | 37.04 | 73.726 | 6.998 | 0 | 0.06 | 0.057 | 0122Tra0000009139 | m | T110 | false | HI_UZV_HEA_STA_0,120_xxx | 0
Nebenträger | Wartung_FFB | 1 | Nebenträger | HEA 120 | 0.698 | Wartung_FFB | 37.06 | 73.726 | 6.998 | 40.04 | 73.726 | 6.998 | 0 | 0.06 | 0.057 | 0122Tra0000009141 | m | T110 | false | HI_UZV_HEA_STA_0,120_xxx | 0
Nebenträger | Wartung_FFB | 1 | Nebenträger | HEA 120 | 0.698 | Wartung_FFB | 40.06 | 73.726 | 6.998 | 43.04 | 73.726 | 6.998 | 0 | 0.06 | 0.057 | 0122Tra0000009143 | m | T110 | false | HI_UZV_HEA_STA_0,120_xxx | 0
Nebenträger | Wartung_FFB | 1 | Nebenträger | HEA 120 | 0.698 | Wartung_FFB | 43.06 | 73.726 | 6.998 | 46.04 | 73.726 | 6.998 | 0 | 0.06 | 0.057 | 0122Tra0000009145 | m | T110 | false | HI_UZV_HEA_STA_0,120_xxx | 0
Nebenträger | Wartung_FFB | 1 | Nebenträger | HEA 120 | 0.698 | Wartung_FFB | 46.06 | 73.726 | 6.998 | 49.04 | 73.726 | 6.998 | 0 | 0.06 | 0.057 | 0122Tra0000009147 | m | T110 | false | HI_UZV_HEA_STA_0,120_xxx | 0
Nebenträger | Wartung_FFB | 1 | Nebenträger | HEA 120 | 0.698 | Wartung_FFB | 49.06 | 73.726 | 6.998 | 52.04 | 73.726 | 6.998 | 0 | 0.06 | 0.057 | 0122Tra0000009149 | m | T110 | false | HI_UZV_HEA_STA_0,120_xxx | 0
Nebenträger | Wartung_FFB | 1 | Nebenträger | HEA 120 | 0.698 | Wartung_FFB | 52.06 | 73.726 | 6.998 | 55.04 | 73.726 | 6.998 | 0 | 0.06 | 0.057 | 0122Tra0000009151 | m | T110 | false | HI_UZV_HEA_STA_0,120_xxx | 0
Nebenträger | Wartung_FFB | 1 | Nebenträger | HEA 120 | 0.698 | Wartung_FFB | 55.06 | 73.726 | 6.998 | 58.04 | 73.726 | 6.998 | 0 | 0.06 | 0.057 | 0122Tra0000009153 | m | T110 | false | HI_UZV_HEA_STA_0,120_xxx | 0
Nebenträger | Wartung_FFB | 1 | Nebenträger | HEA 120 | 0.698 | Wartung_FFB | 58.06 | 73.726 | 6.998 | 61.04 | 73.726 | 6.998 | 0 | 0.06 | 0.057 | 0122Tra0000009155 | m | T110 | false | HI_UZV_HEA_STA_0,120_xxx | 0
Nebenträger | Wartung_FFB | 1 | Nebenträger | HEA 120 | 0.698 | Wartung_FFB | 61.06 | 73.726 | 6.998 | 64.04 | 73.726 | 6.998 | 0 | 0.06 | 0.057 | 0122Tra0000009157 | m | T110 | false | HI_UZV_HEA_STA_0,120_xxx | 0
Nebenträger | Wartung_FFB | 1 | Nebenträger | HEA 120 | 0.698 | Wartung_FFB | 10.56 | 73.726 | 6.998 | 13.04 | 73.726 | 6.998 | 0 | 0.06 | 0.057 | 0122Tra0000009159 | m | T110 | false | HI_UZV_HEA_STA_0,120_xxx | 0
Nebenträger | Wartung_FFB | 1 | Nebenträger | HEA 120 | 0.698 | Wartung_FFB | 64.06 | 72.226 | 6.998 | 67.04 | 72.226 | 6.998 | 0 | 0.06 | 0.057 | 0122Tra0000009198 | m | T110 | false | HI_UZV_HEA_STA_0,120_xxx | 0
Nebenträger | Wartung_FFB | 1 | Nebenträger | HEA 120 | 0.698 | Wartung_FFB | 67.06 | 72.226 | 6.998 | 70.04 | 72.226 | 6.998 | 0 | 0.06 | 0.057 | 0122Tra0000009200 | m | T110 | false | HI_UZV_HEA_STA_0,120_xxx | 0
Nebenträger | Wartung_FFB | 1 | Nebenträger | HEA 120 | 0.698 | Wartung_FFB | 70.06 | 72.226 | 6.998 | 73.04 | 72.226 | 6.998 | 0 | 0.06 | 0.057 | 0122Tra0000009202 | m | T110 | false | HI_UZV_HEA_STA_0,120_xxx | 0
Nebenträger | Wartung_FFB | 1 | Nebenträger | HEA 120 | 0.698 | Wartung_FFB | 73.06 | 72.226 | 6.998 | 76.04 | 72.226 | 6.998 | 0 | 0.06 | 0.057 | 0122Tra0000009204 | m | T110 | false | HI_UZV_HEA_STA_0,120_xxx | 0
Nebenträger | Wartung_FFB | 1 | Nebenträger | HEA 120 | 0.698 | Wartung_FFB | 76.06 | 72.226 | 6.998 | 79.04 | 72.226 | 6.998 | 0 | 0.06 | 0.057 | 0122Tra0000009206 | m | T110 | false | HI_UZV_HEA_STA_0,120_xxx | 0
Nebenträger | Wartung_FFB | 1 | Nebenträger | HEA 120 | 0.698 | Wartung_FFB | 94.06 | 72.226 | 6.998 | 97.04 | 72.226 | 6.998 | 0 | 0.06 | 0.057 | 0122Tra0000009218 | m | T110 | false | HI_UZV_HEA_STA_0,120_xxx | 0
Nebenträger | Wartung_FFB | 1 | Nebenträger | HEA 120 | 0.698 | Wartung_FFB | 103.06 | 72.226 | 6.998 | 106.04 | 72.226 | 6.998 | 0 | 0.06 | 0.057 | 0122Tra0000009224 | m | T110 | false | HI_UZV_HEA_STA_0,120_xxx | 0
Nebenträger | Wartung_FFB | 1 | Nebenträger | HEA 120 | 0.698 | Wartung_FFB | 106.06 | 72.226 | 6.998 | 109.04 | 72.226 | 6.998 | 0 | 0.06 | 0.057 | 0122Tra0000009226 | m | T110 | false | HI_UZV_HEA_STA_0,120_xxx | 0
Nebenträger | Wartung_FFB | 1 | Nebenträger | HEA 120 | 0.698 | Wartung_FFB | 109.06 | 72.226 | 6.998 | 112.04 | 72.226 | 6.998 | 0 | 0.06 | 0.057 | 0122Tra0000009228 | m | T110 | false | HI_UZV_HEA_STA_0,120_xxx | 0
Nebenträger | Wartung_FFB | 1 | Nebenträger | HEA 120 | 0.698 | Wartung_FFB | 112.06 | 72.226 | 6.998 | 115.04 | 72.226 | 6.998 | 0 | 0.06 | 0.057 | 0122Tra0000009230 | m | T110 | false | HI_UZV_HEA_STA_0,120_xxx | 0
Nebenträger | Wartung_FFB | 1 | Nebenträger | HEA 120 | 0.698 | Wartung_FFB | 115.06 | 72.226 | 6.998 | 118.04 | 72.226 | 6.998 | 0 | 0.06 | 0.057 | 0122Tra0000009232 | m | T110 | false | HI_UZV_HEA_STA_0,120_xxx | 0
Nebenträger | Wartung_FFB | 1 | Nebenträger | HEA 120 | 0.698 | Wartung_FFB | 13.06 | 72.226 | 6.998 | 16.04 | 72.226 | 6.998 | 0 | 0.06 | 0.057 | 0122Tra0000009236 | m | T110 | false | HI_UZV_HEA_STA_0,120_xxx | 0
Nebenträger | Wartung_FFB | 1 | Nebenträger | HEA 120 | 0.698 | Wartung_FFB | 22.06 | 72.226 | 6.998 | 25.04 | 72.226 | 6.998 | 0 | 0.06 | 0.057 | 0122Tra0000009242 | m | T110 | false | HI_UZV_HEA_STA_0,120_xxx | 0
Nebenträger | Wartung_FFB | 1 | Nebenträger | HEA 120 | 0.698 | Wartung_FFB | 25.06 | 72.226 | 6.998 | 28.04 | 72.226 | 6.998 | 0 | 0.06 | 0.057 | 0122Tra0000009244 | m | T110 | false | HI_UZV_HEA_STA_0,120_xxx | 0
Nebenträger | Wartung_FFB | 1 | Nebenträger | HEA 120 | 0.698 | Wartung_FFB | 28.06 | 72.226 | 6.998 | 31.04 | 72.226 | 6.998 | 0 | 0.06 | 0.057 | 0122Tra0000009246 | m | T110 | false | HI_UZV_HEA_STA_0,120_xxx | 0
Nebenträger | Wartung_FFB | 1 | Nebenträger | HEA 120 | 0.698 | Wartung_FFB | 31.06 | 72.226 | 6.998 | 34.04 | 72.226 | 6.998 | 0 | 0.06 | 0.057 | 0122Tra0000009248 | m | T110 | false | HI_UZV_HEA_STA_0,120_xxx | 0
Nebenträger | Wartung_FFB | 1 | Nebenträger | HEA 120 | 0.698 | Wartung_FFB | 34.06 | 72.226 | 6.998 | 37.04 | 72.226 | 6.998 | 0 | 0.06 | 0.057 | 0122Tra0000009250 | m | T110 | false | HI_UZV_HEA_STA_0,120_xxx | 0
Nebenträger | Wartung_FFB | 1 | Nebenträger | HEA 120 | 0.698 | Wartung_FFB | 37.06 | 72.226 | 6.998 | 40.04 | 72.226 | 6.998 | 0 | 0.06 | 0.057 | 0122Tra0000009252 | m | T110 | false | HI_UZV_HEA_STA_0,120_xxx | 0
Nebenträger | Wartung_FFB | 1 | Nebenträger | HEA 120 | 0.698 | Wartung_FFB | 40.06 | 72.226 | 6.998 | 43.04 | 72.226 | 6.998 | 0 | 0.06 | 0.057 | 0122Tra0000009254 | m | T110 | false | HI_UZV_HEA_STA_0,120_xxx | 0
Nebenträger | Wartung_FFB | 1 | Nebenträger | HEA 120 | 0.698 | Wartung_FFB | 43.06 | 72.226 | 6.998 | 46.04 | 72.226 | 6.998 | 0 | 0.06 | 0.057 | 0122Tra0000009256 | m | T110 | false | HI_UZV_HEA_STA_0,120_xxx | 0
Nebenträger | Wartung_FFB | 1 | Nebenträger | HEA 120 | 0.698 | Wartung_FFB | 46.06 | 72.226 | 6.998 | 49.04 | 72.226 | 6.998 | 0 | 0.06 | 0.057 | 0122Tra0000009258 | m | T110 | false | HI_UZV_HEA_STA_0,120_xxx | 0
Nebenträger | Wartung_FFB | 1 | Nebenträger | HEA 120 | 0.698 | Wartung_FFB | 49.06 | 72.226 | 6.998 | 52.04 | 72.226 | 6.998 | 0 | 0.06 | 0.057 | 0122Tra0000009260 | m | T110 | false | HI_UZV_HEA_STA_0,120_xxx | 0
Nebenträger | Wartung_FFB | 1 | Nebenträger | HEA 120 | 0.698 | Wartung_FFB | 52.06 | 72.226 | 6.998 | 55.04 | 72.226 | 6.998 | 0 | 0.06 | 0.057 | 0122Tra0000009262 | m | T110 | false | HI_UZV_HEA_STA_0,120_xxx | 0
Nebenträger | Wartung_FFB | 1 | Nebenträger | HEA 120 | 0.698 | Wartung_FFB | 55.06 | 72.226 | 6.998 | 58.04 | 72.226 | 6.998 | 0 | 0.06 | 0.057 | 0122Tra0000009264 | m | T110 | false | HI_UZV_HEA_STA_0,120_xxx | 0
Nebenträger | Wartung_FFB | 1 | Nebenträger | HEA 120 | 0.698 | Wartung_FFB | 58.06 | 72.226 | 6.998 | 61.04 | 72.226 | 6.998 | 0 | 0.06 | 0.057 | 0122Tra0000009266 | m | T110 | false | HI_UZV_HEA_STA_0,120_xxx | 0
Nebenträger | Wartung_FFB | 1 | Nebenträger | HEA 120 | 0.698 | Wartung_FFB | 61.06 | 72.226 | 6.998 | 64.04 | 72.226 | 6.998 | 0 | 0.06 | 0.057 | 0122Tra0000009268 | m | T110 | false | HI_UZV_HEA_STA_0,120_xxx | 0
Nebenträger | Wartung_FFB | 1 | Nebenträger | HEA 120 | 0.698 | Wartung_FFB | 10.56 | 72.226 | 6.998 | 13.04 | 72.226 | 6.998 | 0 | 0.06 | 0.057 | 0122Tra0000009270 | m | T110 | false | HI_UZV_HEA_STA_0,120_xxx | 0
Nebenträger | Wartung_FFB | 1 | Nebenträger | HEA 120 | 0.698 | Wartung_FFB | 64.06 | 68.601 | 6.998 | 67.04 | 68.601 | 6.998 | 0 | 0.06 | 0.057 | 0122Tra0000009272 | m | T110 | false | HI_UZV_HEA_STA_0,120_xxx | 0
Nebenträger | Wartung_FFB | 1 | Nebenträger | HEA 120 | 0.698 | Wartung_FFB | 67.06 | 68.601 | 6.998 | 70.04 | 68.601 | 6.998 | 0 | 0.06 | 0.057 | 0122Tra0000009293 | m | T110 | false | HI_UZV_HEA_STA_0,120_xxx | 0
Nebenträger | Wartung_FFB | 1 | Nebenträger | HEA 120 | 0.698 | Wartung_FFB | 70.06 | 68.601 | 6.998 | 73.04 | 68.601 | 6.998 | 0 | 0.06 | 0.057 | 0122Tra0000009295 | m | T110 | false | HI_UZV_HEA_STA_0,120_xxx | 0
Nebenträger | Wartung_FFB | 1 | Nebenträger | HEA 120 | 0.698 | Wartung_FFB | 73.06 | 68.601 | 6.998 | 76.04 | 68.601 | 6.998 | 0 | 0.06 | 0.057 | 0122Tra0000009297 | m | T110 | false | HI_UZV_HEA_STA_0,120_xxx | 0
Nebenträger | Wartung_FFB | 1 | Nebenträger | HEA 120 | 0.698 | Wartung_FFB | 76.06 | 68.601 | 6.998 | 79.04 | 68.601 | 6.998 | 0 | 0.06 | 0.057 | 0122Tra0000009299 | m | T110 | false | HI_UZV_HEA_STA_0,120_xxx | 0
Nebenträger | Wartung_FFB | 1 | Nebenträger | HEA 120 | 0.698 | Wartung_FFB | 103.06 | 68.601 | 6.998 | 106.04 | 68.601 | 6.998 | 0 | 0.06 | 0.057 | 0122Tra0000009317 | m | T110 | false | HI_UZV_HEA_STA_0,120_xxx | 0
Nebenträger | Wartung_FFB | 1 | Nebenträger | HEA 120 | 0.698 | Wartung_FFB | 106.06 | 68.601 | 6.998 | 109.04 | 68.601 | 6.998 | 0 | 0.06 | 0.057 | 0122Tra0000009319 | m | T110 | false | HI_UZV_HEA_STA_0,120_xxx | 0
Nebenträger | Wartung_FFB | 1 | Nebenträger | HEA 120 | 0.698 | Wartung_FFB | 109.06 | 68.601 | 6.998 | 112.04 | 68.601 | 6.998 | 0 | 0.06 | 0.057 | 0122Tra0000009321 | m | T110 | false | HI_UZV_HEA_STA_0,120_xxx | 0
Nebenträger | Wartung_FFB | 1 | Nebenträger | HEA 120 | 0.698 | Wartung_FFB | 112.06 | 68.601 | 6.998 | 115.04 | 68.601 | 6.998 | 0 | 0.06 | 0.057 | 0122Tra0000009323 | m | T110 | false | HI_UZV_HEA_STA_0,120_xxx | 0
Nebenträger | Wartung_FFB | 1 | Nebenträger | HEA 120 | 0.698 | Wartung_FFB | 115.06 | 68.601 | 6.998 | 118.04 | 68.601 | 6.998 | 0 | 0.06 | 0.057 | 0122Tra0000009325 | m | T110 | false | HI_UZV_HEA_STA_0,120_xxx | 0
Nebenträger | Wartung_FFB | 1 | Nebenträger | HEA 120 | 0.698 | Wartung_FFB | 13.06 | 68.601 | 6.998 | 16.04 | 68.601 | 6.998 | 0 | 0.06 | 0.057 | 0122Tra0000009346 | m | T110 | false | HI_UZV_HEA_STA_0,120_xxx | 0
Nebenträger | Wartung_FFB | 1 | Nebenträger | HEA 120 | 0.698 | Wartung_FFB | 34.06 | 68.601 | 6.998 | 37.04 | 68.601 | 6.998 | 0 | 0.06 | 0.057 | 0122Tra0000009360 | m | T110 | false | HI_UZV_HEA_STA_0,120_xxx | 0
Nebenträger | Wartung_FFB | 1 | Nebenträger | HEA 120 | 0.698 | Wartung_FFB | 37.06 | 68.601 | 6.998 | 40.04 | 68.601 | 6.998 | 0 | 0.06 | 0.057 | 0122Tra0000009362 | m | T110 | false | HI_UZV_HEA_STA_0,120_xxx | 0
Nebenträger | Wartung_FFB | 1 | Nebenträger | HEA 120 | 0.698 | Wartung_FFB | 40.06 | 68.601 | 6.998 | 43.04 | 68.601 | 6.998 | 0 | 0.06 | 0.057 | 0122Tra0000009364 | m | T110 | false | HI_UZV_HEA_STA_0,120_xxx | 0
Nebenträger | Wartung_FFB | 1 | Nebenträger | HEA 120 | 0.698 | Wartung_FFB | 49.06 | 68.601 | 6.998 | 52.04 | 68.601 | 6.998 | 0 | 0.06 | 0.057 | 0122Tra0000009370 | m | T110 | false | HI_UZV_HEA_STA_0,120_xxx | 0
Nebenträger | Wartung_FFB | 1 | Nebenträger | HEA 120 | 0.698 | Wartung_FFB | 52.06 | 68.601 | 6.998 | 55.04 | 68.601 | 6.998 | 0 | 0.06 | 0.057 | 0122Tra0000009372 | m | T110 | false | HI_UZV_HEA_STA_0,120_xxx | 0
Nebenträger | Wartung_FFB | 1 | Nebenträger | HEA 120 | 0.698 | Wartung_FFB | 55.06 | 68.601 | 6.998 | 58.04 | 68.601 | 6.998 | 0 | 0.06 | 0.057 | 0122Tra0000009374 | m | T110 | false | HI_UZV_HEA_STA_0,120_xxx | 0
Nebenträger | Wartung_FFB | 1 | Nebenträger | HEA 120 | 0.698 | Wartung_FFB | 58.06 | 68.601 | 6.998 | 61.04 | 68.601 | 6.998 | 0 | 0.06 | 0.057 | 0122Tra0000009376 | m | T110 | false | HI_UZV_HEA_STA_0,120_xxx | 0
Nebenträger | Wartung_FFB | 1 | Nebenträger | HEA 120 | 0.698 | Wartung_FFB | 61.06 | 68.601 | 6.998 | 64.04 | 68.601 | 6.998 | 0 | 0.06 | 0.057 | 0122Tra0000009378 | m | T110 | false | HI_UZV_HEA_STA_0,120_xxx | 0
Nebenträger | Wartung_FFB | 1 | Nebenträger | HEA 120 | 0.698 | Wartung_FFB | 10.56 | 68.601 | 6.998 | 13.04 | 68.601 | 6.998 | 0 | 0.06 | 0.057 | 0122Tra0000009381 | m | T110 | false | HI_UZV_HEA_STA_0,120_xxx | 0
Nebenträger | Wartung_FFB | 1 | Nebenträger | HEA 120 | 0.698 | Wartung_FFB | 64.06 | 67.101 | 6.998 | 67.04 | 67.101 | 6.998 | 0 | 0.06 | 0.057 | 0122Tra0000009420 | m | T110 | false | HI_UZV_HEA_STA_0,120_xxx | 0
Nebenträger | Wartung_FFB | 1 | Nebenträger | HEA 120 | 0.698 | Wartung_FFB | 67.06 | 67.101 | 6.998 | 70.04 | 67.101 | 6.998 | 0 | 0.06 | 0.057 | 0122Tra0000009422 | m | T110 | false | HI_UZV_HEA_STA_0,120_xxx | 0
Nebenträger | Wartung_FFB | 1 | Nebenträger | HEA 120 | 0.698 | Wartung_FFB | 70.06 | 67.101 | 6.998 | 73.04 | 67.101 | 6.998 | 0 | 0.06 | 0.057 | 0122Tra0000009424 | m | T110 | false | HI_UZV_HEA_STA_0,120_xxx | 0
Nebenträger | Wartung_FFB | 1 | Nebenträger | HEA 120 | 0.698 | Wartung_FFB | 73.06 | 67.101 | 6.998 | 76.04 | 67.101 | 6.998 | 0 | 0.06 | 0.057 | 0122Tra0000009426 | m | T110 | false | HI_UZV_HEA_STA_0,120_xxx | 0
Nebenträger | Wartung_FFB | 1 | Nebenträger | HEA 120 | 0.698 | Wartung_FFB | 76.06 | 67.101 | 6.998 | 79.04 | 67.101 | 6.998 | 0 | 0.06 | 0.057 | 0122Tra0000009428 | m | T110 | false | HI_UZV_HEA_STA_0,120_xxx | 0
Nebenträger | Wartung_FFB | 1 | Nebenträger | HEA 120 | 0.698 | Wartung_FFB | 103.06 | 67.101 | 6.998 | 106.04 | 67.101 | 6.998 | 0 | 0.06 | 0.057 | 0122Tra0000009446 | m | T110 | false | HI_UZV_HEA_STA_0,120_xxx | 0
Nebenträger | Wartung_FFB | 1 | Nebenträger | HEA 120 | 0.698 | Wartung_FFB | 106.06 | 67.101 | 6.998 | 109.04 | 67.101 | 6.998 | 0 | 0.06 | 0.057 | 0122Tra0000009448 | m | T110 | false | HI_UZV_HEA_STA_0,120_xxx | 0
Nebenträger | Wartung_FFB | 1 | Nebenträger | HEA 120 | 0.698 | Wartung_FFB | 109.06 | 67.101 | 6.998 | 112.04 | 67.101 | 6.998 | 0 | 0.06 | 0.057 | 0122Tra0000009450 | m | T110 | false | HI_UZV_HEA_STA_0,120_xxx | 0
Nebenträger | Wartung_FFB | 1 | Nebenträger | HEA 120 | 0.698 | Wartung_FFB | 112.06 | 67.101 | 6.998 | 115.04 | 67.101 | 6.998 | 0 | 0.06 | 0.057 | 0122Tra0000009452 | m | T110 | false | HI_UZV_HEA_STA_0,120_xxx | 0
Nebenträger | Wartung_FFB | 1 | Nebenträger | HEA 120 | 0.698 | Wartung_FFB | 115.06 | 67.101 | 6.998 | 118.04 | 67.101 | 6.998 | 0 | 0.06 | 0.057 | 0122Tra0000009454 | m | T110 | false | HI_UZV_HEA_STA_0,120_xxx | 0
Nebenträger | Wartung_FFB | 1 | Nebenträger | HEA 120 | 0.698 | Wartung_FFB | 13.06 | 67.101 | 6.998 | 16.04 | 67.101 | 6.998 | 0 | 0.06 | 0.057 | 0122Tra0000009458 | m | T110 | false | HI_UZV_HEA_STA_0,120_xxx | 0
Nebenträger | Wartung_FFB | 1 | Nebenträger | HEA 120 | 0.698 | Wartung_FFB | 34.06 | 67.101 | 6.998 | 37.04 | 67.101 | 6.998 | 0 | 0.06 | 0.057 | 0122Tra0000009472 | m | T110 | false | HI_UZV_HEA_STA_0,120_xxx | 0
Nebenträger | Wartung_FFB | 1 | Nebenträger | HEA 120 | 0.698 | Wartung_FFB | 37.06 | 67.101 | 6.998 | 40.04 | 67.101 | 6.998 | 0 | 0.06 | 0.057 | 0122Tra0000009474 | m | T110 | false | HI_UZV_HEA_STA_0,120_xxx | 0
Nebenträger | Wartung_FFB | 1 | Nebenträger | HEA 120 | 0.698 | Wartung_FFB | 40.06 | 67.101 | 6.998 | 43.04 | 67.101 | 6.998 | 0 | 0.06 | 0.057 | 0122Tra0000009476 | m | T110 | false | HI_UZV_HEA_STA_0,120_xxx | 0
Nebenträger | Wartung_FFB | 1 | Nebenträger | HEA 120 | 0.698 | Wartung_FFB | 49.06 | 67.101 | 6.998 | 52.04 | 67.101 | 6.998 | 0 | 0.06 | 0.057 | 0122Tra0000009482 | m | T110 | false | HI_UZV_HEA_STA_0,120_xxx | 0
Nebenträger | Wartung_FFB | 1 | Nebenträger | HEA 120 | 0.698 | Wartung_FFB | 52.06 | 67.101 | 6.998 | 55.04 | 67.101 | 6.998 | 0 | 0.06 | 0.057 | 0122Tra0000009484 | m | T110 | false | HI_UZV_HEA_STA_0,120_xxx | 0
Nebenträger | Wartung_FFB | 1 | Nebenträger | HEA 120 | 0.698 | Wartung_FFB | 55.06 | 67.101 | 6.998 | 58.04 | 67.101 | 6.998 | 0 | 0.06 | 0.057 | 0122Tra0000009486 | m | T110 | false | HI_UZV_HEA_STA_0,120_xxx | 0
Nebenträger | Wartung_FFB | 1 | Nebenträger | HEA 120 | 0.698 | Wartung_FFB | 58.06 | 67.101 | 6.998 | 61.04 | 67.101 | 6.998 | 0 | 0.06 | 0.057 | 0122Tra0000009488 | m | T110 | false | HI_UZV_HEA_STA_0,120_xxx | 0
Nebenträger | Wartung_FFB | 1 | Nebenträger | HEA 120 | 0.698 | Wartung_FFB | 61.06 | 67.101 | 6.998 | 64.04 | 67.101 | 6.998 | 0 | 0.06 | 0.057 | 0122Tra0000009490 | m | T110 | false | HI_UZV_HEA_STA_0,120_xxx | 0
Nebenträger | Wartung_FFB | 1 | Nebenträger | HEA 120 | 0.698 | Wartung_FFB | 10.56 | 67.101 | 6.998 | 13.04 | 67.101 | 6.998 | 0 | 0.06 | 0.057 | 0122Tra0000009492 | m | T110 | false | HI_UZV_HEA_STA_0,120_xxx | 0
Nebenträger | Wartung_FFB | 1 | Nebenträger | HEA 120 | 0.698 | Wartung_FFB | 64.06 | 65.601 | 6.998 | 67.04 | 65.601 | 6.998 | 0 | 0.06 | 0.057 | 0122Tra0000009531 | m | T110 | false | HI_UZV_HEA_STA_0,120_xxx | 0
Nebenträger | Wartung_FFB | 1 | Nebenträger | HEA 120 | 0.698 | Wartung_FFB | 67.06 | 65.601 | 6.998 | 70.04 | 65.601 | 6.998 | 0 | 0.06 | 0.057 | 0122Tra0000009533 | m | T110 | false | HI_UZV_HEA_STA_0,120_xxx | 0
Nebenträger | Wartung_FFB | 1 | Nebenträger | HEA 120 | 0.698 | Wartung_FFB | 70.06 | 65.601 | 6.998 | 73.04 | 65.601 | 6.998 | 0 | 0.06 | 0.057 | 0122Tra0000009535 | m | T110 | false | HI_UZV_HEA_STA_0,120_xxx | 0
Nebenträger | Wartung_FFB | 1 | Nebenträger | HEA 120 | 0.698 | Wartung_FFB | 73.06 | 65.601 | 6.998 | 76.04 | 65.601 | 6.998 | 0 | 0.06 | 0.057 | 0122Tra0000009537 | m | T110 | false | HI_UZV_HEA_STA_0,120_xxx | 0
Nebenträger | Wartung_FFB | 1 | Nebenträger | HEA 120 | 0.698 | Wartung_FFB | 76.06 | 65.601 | 6.998 | 79.04 | 65.601 | 6.998 | 0 | 0.06 | 0.057 | 0122Tra0000009539 | m | T110 | false | HI_UZV_HEA_STA_0,120_xxx | 0
Nebenträger | Wartung_FFB | 1 | Nebenträger | HEA 120 | 0.698 | Wartung_FFB | 103.06 | 65.601 | 6.998 | 106.04 | 65.601 | 6.998 | 0 | 0.06 | 0.057 | 0122Tra0000009557 | m | T110 | false | HI_UZV_HEA_STA_0,120_xxx | 0
Nebenträger | Wartung_FFB | 1 | Nebenträger | HEA 120 | 0.698 | Wartung_FFB | 106.06 | 65.601 | 6.998 | 109.04 | 65.601 | 6.998 | 0 | 0.06 | 0.057 | 0122Tra0000009559 | m | T110 | false | HI_UZV_HEA_STA_0,120_xxx | 0
Nebenträger | Wartung_FFB | 1 | Nebenträger | HEA 120 | 0.698 | Wartung_FFB | 109.06 | 65.601 | 6.998 | 112.04 | 65.601 | 6.998 | 0 | 0.06 | 0.057 | 0122Tra0000009561 | m | T110 | false | HI_UZV_HEA_STA_0,120_xxx | 0
Nebenträger | Wartung_FFB | 1 | Nebenträger | HEA 120 | 0.698 | Wartung_FFB | 112.06 | 65.601 | 6.998 | 115.04 | 65.601 | 6.998 | 0 | 0.06 | 0.057 | 0122Tra0000009563 | m | T110 | false | HI_UZV_HEA_STA_0,120_xxx | 0
Nebenträger | Wartung_FFB | 1 | Nebenträger | HEA 120 | 0.698 | Wartung_FFB | 115.06 | 65.601 | 6.998 | 118.04 | 65.601 | 6.998 | 0 | 0.06 | 0.057 | 0122Tra0000009565 | m | T110 | false | HI_UZV_HEA_STA_0,120_xxx | 0
Nebenträger | Wartung_FFB | 1 | Nebenträger | HEA 120 | 0.698 | Wartung_FFB | 13.06 | 65.601 | 6.998 | 16.04 | 65.601 | 6.998 | 0 | 0.06 | 0.057 | 0122Tra0000009569 | m | T110 | false | HI_UZV_HEA_STA_0,120_xxx | 0
Nebenträger | Wartung_FFB | 1 | Nebenträger | HEA 120 | 0.698 | Wartung_FFB | 34.06 | 65.601 | 6.998 | 37.04 | 65.601 | 6.998 | 0 | 0.06 | 0.057 | 0122Tra0000009583 | m | T110 | false | HI_UZV_HEA_STA_0,120_xxx | 0
Nebenträger | Wartung_FFB | 1 | Nebenträger | HEA 120 | 0.698 | Wartung_FFB | 37.06 | 65.601 | 6.998 | 40.04 | 65.601 | 6.998 | 0 | 0.06 | 0.057 | 0122Tra0000009585 | m | T110 | false | HI_UZV_HEA_STA_0,120_xxx | 0
Nebenträger | Wartung_FFB | 1 | Nebenträger | HEA 120 | 0.698 | Wartung_FFB | 40.06 | 65.601 | 6.998 | 43.04 | 65.601 | 6.998 | 0 | 0.06 | 0.057 | 0122Tra0000009587 | m | T110 | false | HI_UZV_HEA_STA_0,120_xxx | 0
Nebenträger | Wartung_FFB | 1 | Nebenträger | HEA 120 | 0.698 | Wartung_FFB | 49.06 | 65.601 | 6.998 | 52.04 | 65.601 | 6.998 | 0 | 0.06 | 0.057 | 0122Tra0000009593 | m | T110 | false | HI_UZV_HEA_STA_0,120_xxx | 0
Nebenträger | Wartung_FFB | 1 | Nebenträger | HEA 120 | 0.698 | Wartung_FFB | 52.06 | 65.601 | 6.998 | 55.04 | 65.601 | 6.998 | 0 | 0.06 | 0.057 | 0122Tra0000009595 | m | T110 | false | HI_UZV_HEA_STA_0,120_xxx | 0
Nebenträger | Wartung_FFB | 1 | Nebenträger | HEA 120 | 0.698 | Wartung_FFB | 55.06 | 65.601 | 6.998 | 58.04 | 65.601 | 6.998 | 0 | 0.06 | 0.057 | 0122Tra0000009597 | m | T110 | false | HI_UZV_HEA_STA_0,120_xxx | 0
Nebenträger | Wartung_FFB | 1 | Nebenträger | HEA 120 | 0.698 | Wartung_FFB | 58.06 | 65.601 | 6.998 | 61.04 | 65.601 | 6.998 | 0 | 0.06 | 0.057 | 0122Tra0000009599 | m | T110 | false | HI_UZV_HEA_STA_0,120_xxx | 0
Nebenträger | Wartung_FFB | 1 | Nebenträger | HEA 120 | 0.698 | Wartung_FFB | 61.06 | 65.601 | 6.998 | 64.04 | 65.601 | 6.998 | 0 | 0.06 | 0.057 | 0122Tra0000009601 | m | T110 | false | HI_UZV_HEA_STA_0,120_xxx | 0
Nebenträger | Wartung_FFB | 1 | Nebenträger | HEA 120 | 0.698 | Wartung_FFB | 10.56 | 65.601 | 6.998 | 13.04 | 65.601 | 6.998 | 0 | 0.06 | 0.057 | 0122Tra0000009603 | m | T110 | false | HI_UZV_HEA_STA_0,120_xxx | 0
Nebenträger | Wartung_FFB | 1 | Nebenträger | HEA 120 | 0.698 | Wartung_FFB | 64.06 | 64.101 | 6.998 | 67.04 | 64.101 | 6.998 | 0 | 0.06 | 0.057 | 0122Tra0000009642 | m | T110 | false | HI_UZV_HEA_STA_0,120_xxx | 0
Nebenträger | Wartung_FFB | 1 | Nebenträger | HEA 120 | 0.698 | Wartung_FFB | 67.06 | 64.101 | 6.998 | 70.04 | 64.101 | 6.998 | 0 | 0.06 | 0.057 | 0122Tra0000009644 | m | T110 | false | HI_UZV_HEA_STA_0,120_xxx | 0
Nebenträger | Wartung_FFB | 1 | Nebenträger | HEA 120 | 0.698 | Wartung_FFB | 70.06 | 64.101 | 6.998 | 73.04 | 64.101 | 6.998 | 0 | 0.06 | 0.057 | 0122Tra0000009646 | m | T110 | false | HI_UZV_HEA_STA_0,120_xxx | 0
Nebenträger | Wartung_FFB | 1 | Nebenträger | HEA 120 | 0.698 | Wartung_FFB | 73.06 | 64.101 | 6.998 | 76.04 | 64.101 | 6.998 | 0 | 0.06 | 0.057 | 0122Tra0000009648 | m | T110 | false | HI_UZV_HEA_STA_0,120_xxx | 0
Nebenträger | Wartung_FFB | 1 | Nebenträger | HEA 120 | 0.698 | Wartung_FFB | 76.06 | 64.101 | 6.998 | 79.04 | 64.101 | 6.998 | 0 | 0.06 | 0.057 | 0122Tra0000009650 | m | T110 | false | HI_UZV_HEA_STA_0,120_xxx | 0
Nebenträger | Wartung_FFB | 1 | Nebenträger | HEA 120 | 0.698 | Wartung_FFB | 103.06 | 64.101 | 6.998 | 106.04 | 64.101 | 6.998 | 0 | 0.06 | 0.057 | 0122Tra0000009668 | m | T110 | false | HI_UZV_HEA_STA_0,120_xxx | 0
Nebenträger | Wartung_FFB | 1 | Nebenträger | HEA 120 | 0.698 | Wartung_FFB | 106.06 | 64.101 | 6.998 | 109.04 | 64.101 | 6.998 | 0 | 0.06 | 0.057 | 0122Tra0000009670 | m | T110 | false | HI_UZV_HEA_STA_0,120_xxx | 0
Nebenträger | Wartung_FFB | 1 | Nebenträger | HEA 120 | 0.698 | Wartung_FFB | 109.06 | 64.101 | 6.998 | 112.04 | 64.101 | 6.998 | 0 | 0.06 | 0.057 | 0122Tra0000009672 | m | T110 | false | HI_UZV_HEA_STA_0,120_xxx | 0
Nebenträger | Wartung_FFB | 1 | Nebenträger | HEA 120 | 0.698 | Wartung_FFB | 112.06 | 64.101 | 6.998 | 115.04 | 64.101 | 6.998 | 0 | 0.06 | 0.057 | 0122Tra0000009674 | m | T110 | false | HI_UZV_HEA_STA_0,120_xxx | 0
Nebenträger | Wartung_FFB | 1 | Nebenträger | HEA 120 | 0.698 | Wartung_FFB | 115.06 | 64.101 | 6.998 | 118.04 | 64.101 | 6.998 | 0 | 0.06 | 0.057 | 0122Tra0000009676 | m | T110 | false | HI_UZV_HEA_STA_0,120_xxx | 0
Nebenträger | Wartung_FFB | 1 | Nebenträger | HEA 120 | 0.698 | Wartung_FFB | 13.06 | 64.101 | 6.998 | 16.04 | 64.101 | 6.998 | 0 | 0.06 | 0.057 | 0122Tra0000009680 | m | T110 | false | HI_UZV_HEA_STA_0,120_xxx | 0
Nebenträger | Wartung_FFB | 1 | Nebenträger | HEA 120 | 0.698 | Wartung_FFB | 34.06 | 64.101 | 6.998 | 37.04 | 64.101 | 6.998 | 0 | 0.06 | 0.057 | 0122Tra0000009694 | m | T110 | false | HI_UZV_HEA_STA_0,120_xxx | 0
Nebenträger | Wartung_FFB | 1 | Nebenträger | HEA 120 | 0.698 | Wartung_FFB | 37.06 | 64.101 | 6.998 | 40.04 | 64.101 | 6.998 | 0 | 0.06 | 0.057 | 0122Tra0000009696 | m | T110 | false | HI_UZV_HEA_STA_0,120_xxx | 0
Nebenträger | Wartung_FFB | 1 | Nebenträger | HEA 120 | 0.698 | Wartung_FFB | 40.06 | 64.101 | 6.998 | 43.04 | 64.101 | 6.998 | 0 | 0.06 | 0.057 | 0122Tra0000009698 | m | T110 | false | HI_UZV_HEA_STA_0,120_xxx | 0
Nebenträger | Wartung_FFB | 1 | Nebenträger | HEA 120 | 0.698 | Wartung_FFB | 49.06 | 64.101 | 6.998 | 52.04 | 64.101 | 6.998 | 0 | 0.06 | 0.057 | 0122Tra0000009704 | m | T110 | false | HI_UZV_HEA_STA_0,120_xxx | 0
Nebenträger | Wartung_FFB | 1 | Nebenträger | HEA 120 | 0.698 | Wartung_FFB | 52.06 | 64.101 | 6.998 | 55.04 | 64.101 | 6.998 | 0 | 0.06 | 0.057 | 0122Tra0000009706 | m | T110 | false | HI_UZV_HEA_STA_0,120_xxx | 0
Nebenträger | Wartung_FFB | 1 | Nebenträger | HEA 120 | 0.698 | Wartung_FFB | 55.06 | 64.101 | 6.998 | 58.04 | 64.101 | 6.998 | 0 | 0.06 | 0.057 | 0122Tra0000009708 | m | T110 | false | HI_UZV_HEA_STA_0,120_xxx | 0
Nebenträger | Wartung_FFB | 1 | Nebenträger | HEA 120 | 0.698 | Wartung_FFB | 58.06 | 64.101 | 6.998 | 61.04 | 64.101 | 6.998 | 0 | 0.06 | 0.057 | 0122Tra0000009710 | m | T110 | false | HI_UZV_HEA_STA_0,120_xxx | 0
Nebenträger | Wartung_FFB | 1 | Nebenträger | HEA 120 | 0.698 | Wartung_FFB | 61.06 | 64.101 | 6.998 | 64.04 | 64.101 | 6.998 | 0 | 0.06 | 0.057 | 0122Tra0000009712 | m | T110 | false | HI_UZV_HEA_STA_0,120_xxx | 0
Nebenträger | Wartung_FFB | 1 | Nebenträger | HEA 120 | 0.698 | Wartung_FFB | 10.56 | 64.101 | 6.998 | 13.04 | 64.101 | 6.998 | 0 | 0.06 | 0.057 | 0122Tra0000009714 | m | T110 | false | HI_UZV_HEA_STA_0,120_xxx | 0
Nebenträger | Wartung_FFB | 1 | Nebenträger | HEA 120 | 0.698 | Wartung_FFB | 64.06 | 62.601 | 6.998 | 67.04 | 62.601 | 6.998 | 0 | 0.06 | 0.057 | 0122Tra0000009753 | m | T110 | false | HI_UZV_HEA_STA_0,120_xxx | 0
Nebenträger | Wartung_FFB | 1 | Nebenträger | HEA 120 | 0.698 | Wartung_FFB | 67.06 | 62.601 | 6.998 | 70.04 | 62.601 | 6.998 | 0 | 0.06 | 0.057 | 0122Tra0000009755 | m | T110 | false | HI_UZV_HEA_STA_0,120_xxx | 0
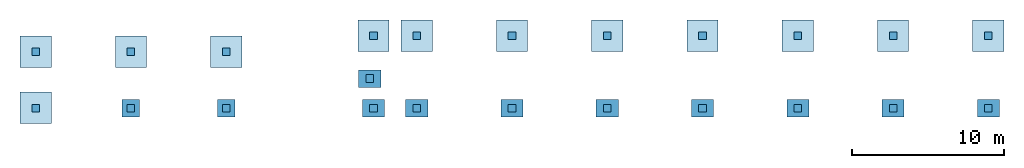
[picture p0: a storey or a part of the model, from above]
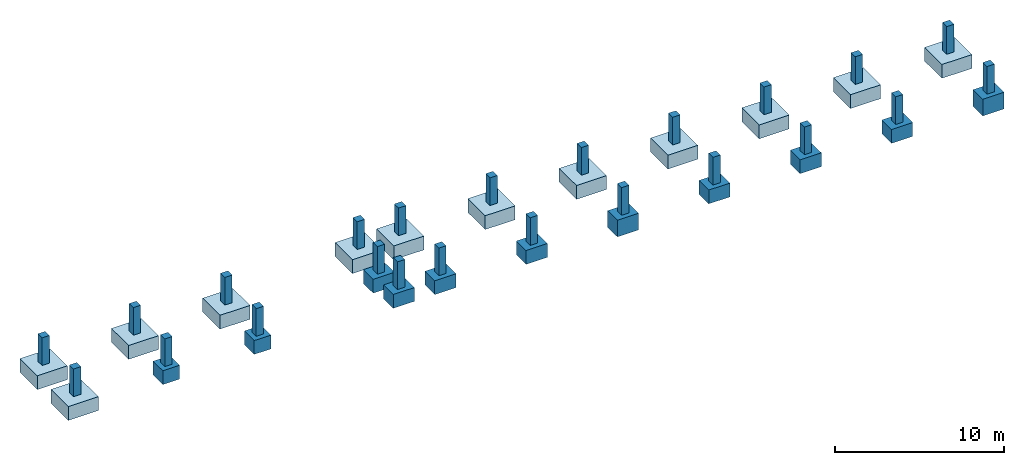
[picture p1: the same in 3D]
Properties of the parts of a building model (IFC2X3), part 4 of 25

# IfcBeam (2372)
Name | In | Faktor | Bezeichnung = Name | Profilname | Mantelfläche/lfm | Ebene | Achsenstartpunkt (X) (m) | Achsenstartpunkt (Y) (m) | Achsenstartpunkt (Z) (m) | Achsenendpunkt (X) (m) | Achsenendpunkt (Y) (m) | Achsenendpunkt (Z) (m) | Objektdrehwinkel | Schwerpunkt X (m) | Schwerpunkt Y (m) | Allright_Bauteil_ID | Abrechnungsart | Positionsnummer | Außenbauteil | Reference | Drehwinkel = Slope (deg)
Nebenträger | Wartung_FFB | 1 | Nebenträger | HEA 120 | 0.698 | Wartung_FFB | 70.06 | 62.601 | 6.998 | 73.04 | 62.601 | 6.998 | 0 | 0.06 | 0.057 | 0122Tra0000009757 | m | T110 | false | HI_UZV_HEA_STA_0,120_xxx | 0
Nebenträger | Wartung_FFB | 1 | Nebenträger | HEA 120 | 0.698 | Wartung_FFB | 73.06 | 62.601 | 6.998 | 76.04 | 62.601 | 6.998 | 0 | 0.06 | 0.057 | 0122Tra0000009759 | m | T110 | false | HI_UZV_HEA_STA_0,120_xxx | 0
Nebenträger | Wartung_FFB | 1 | Nebenträger | HEA 120 | 0.698 | Wartung_FFB | 76.06 | 62.601 | 6.998 | 79.04 | 62.601 | 6.998 | 0 | 0.06 | 0.057 | 0122Tra0000009761 | m | T110 | false | HI_UZV_HEA_STA_0,120_xxx | 0
Nebenträger | Wartung_FFB | 1 | Nebenträger | HEA 120 | 0.698 | Wartung_FFB | 103.06 | 62.601 | 6.998 | 106.04 | 62.601 | 6.998 | 0 | 0.06 | 0.057 | 0122Tra0000009779 | m | T110 | false | HI_UZV_HEA_STA_0,120_xxx | 0
Nebenträger | Wartung_FFB | 1 | Nebenträger | HEA 120 | 0.698 | Wartung_FFB | 106.06 | 62.601 | 6.998 | 109.04 | 62.601 | 6.998 | 0 | 0.06 | 0.057 | 0122Tra0000009781 | m | T110 | false | HI_UZV_HEA_STA_0,120_xxx | 0
Nebenträger | Wartung_FFB | 1 | Nebenträger | HEA 120 | 0.698 | Wartung_FFB | 109.06 | 62.601 | 6.998 | 112.04 | 62.601 | 6.998 | 0 | 0.06 | 0.057 | 0122Tra0000009783 | m | T110 | false | HI_UZV_HEA_STA_0,120_xxx | 0
Nebenträger | Wartung_FFB | 1 | Nebenträger | HEA 120 | 0.698 | Wartung_FFB | 112.06 | 62.601 | 6.998 | 115.04 | 62.601 | 6.998 | 0 | 0.06 | 0.057 | 0122Tra0000009785 | m | T110 | false | HI_UZV_HEA_STA_0,120_xxx | 0
Nebenträger | Wartung_FFB | 1 | Nebenträger | HEA 120 | 0.698 | Wartung_FFB | 115.06 | 62.601 | 6.998 | 118.04 | 62.601 | 6.998 | 0 | 0.06 | 0.057 | 0122Tra0000009787 | m | T110 | false | HI_UZV_HEA_STA_0,120_xxx | 0
Nebenträger | Wartung_FFB | 1 | Nebenträger | HEA 120 | 0.698 | Wartung_FFB | 13.06 | 62.601 | 6.998 | 16.04 | 62.601 | 6.998 | 0 | 0.06 | 0.057 | 0122Tra0000009791 | m | T110 | false | HI_UZV_HEA_STA_0,120_xxx | 0
Nebenträger | Wartung_FFB | 1 | Nebenträger | HEA 120 | 0.698 | Wartung_FFB | 34.06 | 62.601 | 6.998 | 37.04 | 62.601 | 6.998 | 0 | 0.06 | 0.057 | 0122Tra0000009805 | m | T110 | false | HI_UZV_HEA_STA_0,120_xxx | 0
Nebenträger | Wartung_FFB | 1 | Nebenträger | HEA 120 | 0.698 | Wartung_FFB | 37.06 | 62.601 | 6.998 | 40.04 | 62.601 | 6.998 | 0 | 0.06 | 0.057 | 0122Tra0000009807 | m | T110 | false | HI_UZV_HEA_STA_0,120_xxx | 0
Nebenträger | Wartung_FFB | 1 | Nebenträger | HEA 120 | 0.698 | Wartung_FFB | 40.06 | 62.601 | 6.998 | 43.04 | 62.601 | 6.998 | 0 | 0.06 | 0.057 | 0122Tra0000009809 | m | T110 | false | HI_UZV_HEA_STA_0,120_xxx | 0
Nebenträger | Wartung_FFB | 1 | Nebenträger | HEA 120 | 0.698 | Wartung_FFB | 49.06 | 62.601 | 6.998 | 52.04 | 62.601 | 6.998 | 0 | 0.06 | 0.057 | 0122Tra0000009815 | m | T110 | false | HI_UZV_HEA_STA_0,120_xxx | 0
Nebenträger | Wartung_FFB | 1 | Nebenträger | HEA 120 | 0.698 | Wartung_FFB | 52.06 | 62.601 | 6.998 | 55.04 | 62.601 | 6.998 | 0 | 0.06 | 0.057 | 0122Tra0000009817 | m | T110 | false | HI_UZV_HEA_STA_0,120_xxx | 0
Nebenträger | Wartung_FFB | 1 | Nebenträger | HEA 120 | 0.698 | Wartung_FFB | 55.06 | 62.601 | 6.998 | 58.04 | 62.601 | 6.998 | 0 | 0.06 | 0.057 | 0122Tra0000009819 | m | T110 | false | HI_UZV_HEA_STA_0,120_xxx | 0
Nebenträger | Wartung_FFB | 1 | Nebenträger | HEA 120 | 0.698 | Wartung_FFB | 58.06 | 62.601 | 6.998 | 61.04 | 62.601 | 6.998 | 0 | 0.06 | 0.057 | 0122Tra0000009821 | m | T110 | false | HI_UZV_HEA_STA_0,120_xxx | 0
Nebenträger | Wartung_FFB | 1 | Nebenträger | HEA 120 | 0.698 | Wartung_FFB | 61.06 | 62.601 | 6.998 | 64.04 | 62.601 | 6.998 | 0 | 0.06 | 0.057 | 0122Tra0000009823 | m | T110 | false | HI_UZV_HEA_STA_0,120_xxx | 0
Nebenträger | Wartung_FFB | 1 | Nebenträger | HEA 120 | 0.698 | Wartung_FFB | 10.56 | 62.601 | 6.998 | 13.04 | 62.601 | 6.998 | 0 | 0.06 | 0.057 | 0122Tra0000009825 | m | T110 | false | HI_UZV_HEA_STA_0,120_xxx | 0
Nebenträger | Wartung_FFB | 1 | Nebenträger | HEA 120 | 0.698 | Wartung_FFB | 64.06 | 61.101 | 6.998 | 67.04 | 61.101 | 6.998 | 0 | 0.06 | 0.057 | 0122Tra0000009864 | m | T110 | false | HI_UZV_HEA_STA_0,120_xxx | 0
Nebenträger | Wartung_FFB | 1 | Nebenträger | HEA 120 | 0.698 | Wartung_FFB | 67.06 | 61.101 | 6.998 | 70.04 | 61.101 | 6.998 | 0 | 0.06 | 0.057 | 0122Tra0000009866 | m | T110 | false | HI_UZV_HEA_STA_0,120_xxx | 0
Nebenträger | Wartung_FFB | 1 | Nebenträger | HEA 120 | 0.698 | Wartung_FFB | 70.06 | 61.101 | 6.998 | 73.04 | 61.101 | 6.998 | 0 | 0.06 | 0.057 | 0122Tra0000009868 | m | T110 | false | HI_UZV_HEA_STA_0,120_xxx | 0
Nebenträger | Wartung_FFB | 1 | Nebenträger | HEA 120 | 0.698 | Wartung_FFB | 73.06 | 61.101 | 6.998 | 76.04 | 61.101 | 6.998 | 0 | 0.06 | 0.057 | 0122Tra0000009870 | m | T110 | false | HI_UZV_HEA_STA_0,120_xxx | 0
Nebenträger | Wartung_FFB | 1 | Nebenträger | HEA 120 | 0.698 | Wartung_FFB | 76.06 | 61.101 | 6.998 | 79.04 | 61.101 | 6.998 | 0 | 0.06 | 0.057 | 0122Tra0000009872 | m | T110 | false | HI_UZV_HEA_STA_0,120_xxx | 0
Nebenträger | Wartung_FFB | 1 | Nebenträger | HEA 120 | 0.698 | Wartung_FFB | 103.06 | 61.101 | 6.998 | 106.04 | 61.101 | 6.998 | 0 | 0.06 | 0.057 | 0122Tra0000009890 | m | T110 | false | HI_UZV_HEA_STA_0,120_xxx | 0
Nebenträger | Wartung_FFB | 1 | Nebenträger | HEA 120 | 0.698 | Wartung_FFB | 106.06 | 61.101 | 6.998 | 109.04 | 61.101 | 6.998 | 0 | 0.06 | 0.057 | 0122Tra0000009892 | m | T110 | false | HI_UZV_HEA_STA_0,120_xxx | 0
Nebenträger | Wartung_FFB | 1 | Nebenträger | HEA 120 | 0.698 | Wartung_FFB | 109.06 | 61.101 | 6.998 | 112.04 | 61.101 | 6.998 | 0 | 0.06 | 0.057 | 0122Tra0000009894 | m | T110 | false | HI_UZV_HEA_STA_0,120_xxx | 0
Nebenträger | Wartung_FFB | 1 | Nebenträger | HEA 120 | 0.698 | Wartung_FFB | 112.06 | 61.101 | 6.998 | 115.04 | 61.101 | 6.998 | 0 | 0.06 | 0.057 | 0122Tra0000009896 | m | T110 | false | HI_UZV_HEA_STA_0,120_xxx | 0
Nebenträger | Wartung_FFB | 1 | Nebenträger | HEA 120 | 0.698 | Wartung_FFB | 115.06 | 61.101 | 6.998 | 118.04 | 61.101 | 6.998 | 0 | 0.06 | 0.057 | 0122Tra0000009898 | m | T110 | false | HI_UZV_HEA_STA_0,120_xxx | 0
Nebenträger | Wartung_FFB | 1 | Nebenträger | HEA 120 | 0.698 | Wartung_FFB | 13.06 | 61.101 | 6.998 | 16.04 | 61.101 | 6.998 | 0 | 0.06 | 0.057 | 0122Tra0000009902 | m | T110 | false | HI_UZV_HEA_STA_0,120_xxx | 0
Nebenträger | Wartung_FFB | 1 | Nebenträger | HEA 120 | 0.698 | Wartung_FFB | 34.06 | 61.101 | 6.998 | 37.04 | 61.101 | 6.998 | 0 | 0.06 | 0.057 | 0122Tra0000009916 | m | T110 | false | HI_UZV_HEA_STA_0,120_xxx | 0
Nebenträger | Wartung_FFB | 1 | Nebenträger | HEA 120 | 0.698 | Wartung_FFB | 37.06 | 61.101 | 6.998 | 40.04 | 61.101 | 6.998 | 0 | 0.06 | 0.057 | 0122Tra0000009918 | m | T110 | false | HI_UZV_HEA_STA_0,120_xxx | 0
Nebenträger | Wartung_FFB | 1 | Nebenträger | HEA 120 | 0.698 | Wartung_FFB | 40.06 | 61.101 | 6.998 | 43.04 | 61.101 | 6.998 | 0 | 0.06 | 0.057 | 0122Tra0000009920 | m | T110 | false | HI_UZV_HEA_STA_0,120_xxx | 0
Nebenträger | Wartung_FFB | 1 | Nebenträger | HEA 120 | 0.698 | Wartung_FFB | 49.06 | 61.101 | 6.998 | 52.04 | 61.101 | 6.998 | 0 | 0.06 | 0.057 | 0122Tra0000009926 | m | T110 | false | HI_UZV_HEA_STA_0,120_xxx | 0
Nebenträger | Wartung_FFB | 1 | Nebenträger | HEA 120 | 0.698 | Wartung_FFB | 52.06 | 61.101 | 6.998 | 55.04 | 61.101 | 6.998 | 0 | 0.06 | 0.057 | 0122Tra0000009928 | m | T110 | false | HI_UZV_HEA_STA_0,120_xxx | 0
Nebenträger | Wartung_FFB | 1 | Nebenträger | HEA 120 | 0.698 | Wartung_FFB | 55.06 | 61.101 | 6.998 | 58.04 | 61.101 | 6.998 | 0 | 0.06 | 0.057 | 0122Tra0000009930 | m | T110 | false | HI_UZV_HEA_STA_0,120_xxx | 0
Nebenträger | Wartung_FFB | 1 | Nebenträger | HEA 120 | 0.698 | Wartung_FFB | 58.06 | 61.101 | 6.998 | 61.04 | 61.101 | 6.998 | 0 | 0.06 | 0.057 | 0122Tra0000009932 | m | T110 | false | HI_UZV_HEA_STA_0,120_xxx | 0
Nebenträger | Wartung_FFB | 1 | Nebenträger | HEA 120 | 0.698 | Wartung_FFB | 61.06 | 61.101 | 6.998 | 64.04 | 61.101 | 6.998 | 0 | 0.06 | 0.057 | 0122Tra0000009934 | m | T110 | false | HI_UZV_HEA_STA_0,120_xxx | 0
Nebenträger | Wartung_FFB | 1 | Nebenträger | HEA 120 | 0.698 | Wartung_FFB | 10.56 | 61.101 | 6.998 | 13.04 | 61.101 | 6.998 | 0 | 0.06 | 0.057 | 0122Tra0000009936 | m | T110 | false | HI_UZV_HEA_STA_0,120_xxx | 0
Nebenträger | Wartung_FFB | 1 | Nebenträger | HEA 120 | 0.698 | Wartung_FFB | 64.06 | 59.601 | 6.998 | 67.04 | 59.601 | 6.998 | 0 | 0.06 | 0.057 | 0122Tra0000009975 | m | T110 | false | HI_UZV_HEA_STA_0,120_xxx | 0
Nebenträger | Wartung_FFB | 1 | Nebenträger | HEA 120 | 0.698 | Wartung_FFB | 67.06 | 59.601 | 6.998 | 70.04 | 59.601 | 6.998 | 0 | 0.06 | 0.057 | 0122Tra0000009977 | m | T110 | false | HI_UZV_HEA_STA_0,120_xxx | 0
Nebenträger | Wartung_FFB | 1 | Nebenträger | HEA 120 | 0.698 | Wartung_FFB | 70.06 | 59.601 | 6.998 | 73.04 | 59.601 | 6.998 | 0 | 0.06 | 0.057 | 0122Tra0000009979 | m | T110 | false | HI_UZV_HEA_STA_0,120_xxx | 0
Nebenträger | Wartung_FFB | 1 | Nebenträger | HEA 120 | 0.698 | Wartung_FFB | 73.06 | 59.601 | 6.998 | 76.04 | 59.601 | 6.998 | 0 | 0.06 | 0.057 | 0122Tra0000009981 | m | T110 | false | HI_UZV_HEA_STA_0,120_xxx | 0
Nebenträger | Wartung_FFB | 1 | Nebenträger | HEA 120 | 0.698 | Wartung_FFB | 76.06 | 59.601 | 6.998 | 79.04 | 59.601 | 6.998 | 0 | 0.06 | 0.057 | 0122Tra0000009983 | m | T110 | false | HI_UZV_HEA_STA_0,120_xxx | 0
Nebenträger | Wartung_FFB | 1 | Nebenträger | HEA 120 | 0.698 | Wartung_FFB | 103.06 | 59.601 | 6.998 | 106.04 | 59.601 | 6.998 | 0 | 0.06 | 0.057 | 0122Tra0000010001 | m | T110 | false | HI_UZV_HEA_STA_0,120_xxx | 0
Nebenträger | Wartung_FFB | 1 | Nebenträger | HEA 120 | 0.698 | Wartung_FFB | 106.06 | 59.601 | 6.998 | 109.04 | 59.601 | 6.998 | 0 | 0.06 | 0.057 | 0122Tra0000010003 | m | T110 | false | HI_UZV_HEA_STA_0,120_xxx | 0
Nebenträger | Wartung_FFB | 1 | Nebenträger | HEA 120 | 0.698 | Wartung_FFB | 109.06 | 59.601 | 6.998 | 112.04 | 59.601 | 6.998 | 0 | 0.06 | 0.057 | 0122Tra0000010005 | m | T110 | false | HI_UZV_HEA_STA_0,120_xxx | 0
Nebenträger | Wartung_FFB | 1 | Nebenträger | HEA 120 | 0.698 | Wartung_FFB | 112.06 | 59.601 | 6.998 | 115.04 | 59.601 | 6.998 | 0 | 0.06 | 0.057 | 0122Tra0000010007 | m | T110 | false | HI_UZV_HEA_STA_0,120_xxx | 0
Nebenträger | Wartung_FFB | 1 | Nebenträger | HEA 120 | 0.698 | Wartung_FFB | 115.06 | 59.601 | 6.998 | 118.04 | 59.601 | 6.998 | 0 | 0.06 | 0.057 | 0122Tra0000010009 | m | T110 | false | HI_UZV_HEA_STA_0,120_xxx | 0
Nebenträger | Wartung_FFB | 1 | Nebenträger | HEA 120 | 0.698 | Wartung_FFB | 13.06 | 59.601 | 6.998 | 16.04 | 59.601 | 6.998 | 0 | 0.06 | 0.057 | 0122Tra0000010013 | m | T110 | false | HI_UZV_HEA_STA_0,120_xxx | 0
Nebenträger | Wartung_FFB | 1 | Nebenträger | HEA 120 | 0.698 | Wartung_FFB | 34.06 | 59.601 | 6.998 | 37.04 | 59.601 | 6.998 | 0 | 0.06 | 0.057 | 0122Tra0000010027 | m | T110 | false | HI_UZV_HEA_STA_0,120_xxx | 0
Nebenträger | Wartung_FFB | 1 | Nebenträger | HEA 120 | 0.698 | Wartung_FFB | 37.06 | 59.601 | 6.998 | 40.04 | 59.601 | 6.998 | 0 | 0.06 | 0.057 | 0122Tra0000010029 | m | T110 | false | HI_UZV_HEA_STA_0,120_xxx | 0
Nebenträger | Wartung_FFB | 1 | Nebenträger | HEA 120 | 0.698 | Wartung_FFB | 40.06 | 59.601 | 6.998 | 43.04 | 59.601 | 6.998 | 0 | 0.06 | 0.057 | 0122Tra0000010031 | m | T110 | false | HI_UZV_HEA_STA_0,120_xxx | 0
Nebenträger | Wartung_FFB | 1 | Nebenträger | HEA 120 | 0.698 | Wartung_FFB | 49.06 | 59.601 | 6.998 | 52.04 | 59.601 | 6.998 | 0 | 0.06 | 0.057 | 0122Tra0000010037 | m | T110 | false | HI_UZV_HEA_STA_0,120_xxx | 0
Nebenträger | Wartung_FFB | 1 | Nebenträger | HEA 120 | 0.698 | Wartung_FFB | 52.06 | 59.601 | 6.998 | 55.04 | 59.601 | 6.998 | 0 | 0.06 | 0.057 | 0122Tra0000010039 | m | T110 | false | HI_UZV_HEA_STA_0,120_xxx | 0
Nebenträger | Wartung_FFB | 1 | Nebenträger | HEA 120 | 0.698 | Wartung_FFB | 55.06 | 59.601 | 6.998 | 58.04 | 59.601 | 6.998 | 0 | 0.06 | 0.057 | 0122Tra0000010041 | m | T110 | false | HI_UZV_HEA_STA_0,120_xxx | 0
Nebenträger | Wartung_FFB | 1 | Nebenträger | HEA 120 | 0.698 | Wartung_FFB | 58.06 | 59.601 | 6.998 | 61.04 | 59.601 | 6.998 | 0 | 0.06 | 0.057 | 0122Tra0000010043 | m | T110 | false | HI_UZV_HEA_STA_0,120_xxx | 0
Nebenträger | Wartung_FFB | 1 | Nebenträger | HEA 120 | 0.698 | Wartung_FFB | 61.06 | 59.601 | 6.998 | 64.04 | 59.601 | 6.998 | 0 | 0.06 | 0.057 | 0122Tra0000010045 | m | T110 | false | HI_UZV_HEA_STA_0,120_xxx | 0
Nebenträger | Wartung_FFB | 1 | Nebenträger | HEA 120 | 0.698 | Wartung_FFB | 10.56 | 59.601 | 6.998 | 13.04 | 59.601 | 6.998 | 0 | 0.06 | 0.057 | 0122Tra0000010047 | m | T110 | false | HI_UZV_HEA_STA_0,120_xxx | 0
Nebenträger | Wartung_FFB | 1 | Nebenträger | HEA 120 | 0.698 | Wartung_FFB | 64.06 | 58.101 | 6.998 | 67.04 | 58.101 | 6.998 | 0 | 0.06 | 0.057 | 0122Tra0000010086 | m | T110 | false | HI_UZV_HEA_STA_0,120_xxx | 0
Nebenträger | Wartung_FFB | 1 | Nebenträger | HEA 120 | 0.698 | Wartung_FFB | 67.06 | 58.101 | 6.998 | 70.04 | 58.101 | 6.998 | 0 | 0.06 | 0.057 | 0122Tra0000010088 | m | T110 | false | HI_UZV_HEA_STA_0,120_xxx | 0
Nebenträger | Wartung_FFB | 1 | Nebenträger | HEA 120 | 0.698 | Wartung_FFB | 70.06 | 58.101 | 6.998 | 73.04 | 58.101 | 6.998 | 0 | 0.06 | 0.057 | 0122Tra0000010090 | m | T110 | false | HI_UZV_HEA_STA_0,120_xxx | 0
Nebenträger | Wartung_FFB | 1 | Nebenträger | HEA 120 | 0.698 | Wartung_FFB | 73.06 | 58.101 | 6.998 | 76.04 | 58.101 | 6.998 | 0 | 0.06 | 0.057 | 0122Tra0000010092 | m | T110 | false | HI_UZV_HEA_STA_0,120_xxx | 0
Nebenträger | Wartung_FFB | 1 | Nebenträger | HEA 120 | 0.698 | Wartung_FFB | 76.06 | 58.101 | 6.998 | 79.04 | 58.101 | 6.998 | 0 | 0.06 | 0.057 | 0122Tra0000010094 | m | T110 | false | HI_UZV_HEA_STA_0,120_xxx | 0
Nebenträger | Wartung_FFB | 1 | Nebenträger | HEA 120 | 0.698 | Wartung_FFB | 103.06 | 58.101 | 6.998 | 106.04 | 58.101 | 6.998 | 0 | 0.06 | 0.057 | 0122Tra0000010112 | m | T110 | false | HI_UZV_HEA_STA_0,120_xxx | 0
Nebenträger | Wartung_FFB | 1 | Nebenträger | HEA 120 | 0.698 | Wartung_FFB | 106.06 | 58.101 | 6.998 | 109.04 | 58.101 | 6.998 | 0 | 0.06 | 0.057 | 0122Tra0000010114 | m | T110 | false | HI_UZV_HEA_STA_0,120_xxx | 0
Nebenträger | Wartung_FFB | 1 | Nebenträger | HEA 120 | 0.698 | Wartung_FFB | 109.06 | 58.101 | 6.998 | 112.04 | 58.101 | 6.998 | 0 | 0.06 | 0.057 | 0122Tra0000010116 | m | T110 | false | HI_UZV_HEA_STA_0,120_xxx | 0
Nebenträger | Wartung_FFB | 1 | Nebenträger | HEA 120 | 0.698 | Wartung_FFB | 112.06 | 58.101 | 6.998 | 115.04 | 58.101 | 6.998 | 0 | 0.06 | 0.057 | 0122Tra0000010118 | m | T110 | false | HI_UZV_HEA_STA_0,120_xxx | 0
Nebenträger | Wartung_FFB | 1 | Nebenträger | HEA 120 | 0.698 | Wartung_FFB | 115.06 | 58.101 | 6.998 | 118.04 | 58.101 | 6.998 | 0 | 0.06 | 0.057 | 0122Tra0000010120 | m | T110 | false | HI_UZV_HEA_STA_0,120_xxx | 0
Nebenträger | Wartung_FFB | 1 | Nebenträger | HEA 120 | 0.698 | Wartung_FFB | 13.06 | 58.101 | 6.998 | 16.04 | 58.101 | 6.998 | 0 | 0.06 | 0.057 | 0122Tra0000010124 | m | T110 | false | HI_UZV_HEA_STA_0,120_xxx | 0
Nebenträger | Wartung_FFB | 1 | Nebenträger | HEA 120 | 0.698 | Wartung_FFB | 16.06 | 58.101 | 6.998 | 19.04 | 58.101 | 6.998 | 0 | 0.06 | 0.057 | 0122Tra0000010126 | m | T110 | false | HI_UZV_HEA_STA_0,120_xxx | 0
Nebenträger | Wartung_FFB | 1 | Nebenträger | HEA 120 | 0.698 | Wartung_FFB | 19.06 | 58.101 | 6.998 | 22.04 | 58.101 | 6.998 | 0 | 0.06 | 0.057 | 0122Tra0000010128 | m | T110 | false | HI_UZV_HEA_STA_0,120_xxx | 0
Nebenträger | Wartung_FFB | 1 | Nebenträger | HEA 120 | 0.698 | Wartung_FFB | 34.06 | 58.101 | 6.998 | 37.04 | 58.101 | 6.998 | 0 | 0.06 | 0.057 | 0122Tra0000010138 | m | T110 | false | HI_UZV_HEA_STA_0,120_xxx | 0
Nebenträger | Wartung_FFB | 1 | Nebenträger | HEA 120 | 0.698 | Wartung_FFB | 37.06 | 58.101 | 6.998 | 40.04 | 58.101 | 6.998 | 0 | 0.06 | 0.057 | 0122Tra0000010140 | m | T110 | false | HI_UZV_HEA_STA_0,120_xxx | 0
Nebenträger | Wartung_FFB | 1 | Nebenträger | HEA 120 | 0.698 | Wartung_FFB | 40.06 | 58.101 | 6.998 | 43.04 | 58.101 | 6.998 | 0 | 0.06 | 0.057 | 0122Tra0000010142 | m | T110 | false | HI_UZV_HEA_STA_0,120_xxx | 0
Nebenträger | Wartung_FFB | 1 | Nebenträger | HEA 120 | 0.698 | Wartung_FFB | 49.06 | 58.101 | 6.998 | 52.04 | 58.101 | 6.998 | 0 | 0.06 | 0.057 | 0122Tra0000010148 | m | T110 | false | HI_UZV_HEA_STA_0,120_xxx | 0
Nebenträger | Wartung_FFB | 1 | Nebenträger | HEA 120 | 0.698 | Wartung_FFB | 52.06 | 58.101 | 6.998 | 55.04 | 58.101 | 6.998 | 0 | 0.06 | 0.057 | 0122Tra0000010150 | m | T110 | false | HI_UZV_HEA_STA_0,120_xxx | 0
Nebenträger | Wartung_FFB | 1 | Nebenträger | HEA 120 | 0.698 | Wartung_FFB | 55.06 | 58.101 | 6.998 | 58.04 | 58.101 | 6.998 | 0 | 0.06 | 0.057 | 0122Tra0000010152 | m | T110 | false | HI_UZV_HEA_STA_0,120_xxx | 0
Nebenträger | Wartung_FFB | 1 | Nebenträger | HEA 120 | 0.698 | Wartung_FFB | 58.06 | 58.101 | 6.998 | 61.04 | 58.101 | 6.998 | 0 | 0.06 | 0.057 | 0122Tra0000010154 | m | T110 | false | HI_UZV_HEA_STA_0,120_xxx | 0
Nebenträger | Wartung_FFB | 1 | Nebenträger | HEA 120 | 0.698 | Wartung_FFB | 61.06 | 58.101 | 6.998 | 64.04 | 58.101 | 6.998 | 0 | 0.06 | 0.057 | 0122Tra0000010156 | m | T110 | false | HI_UZV_HEA_STA_0,120_xxx | 0
Nebenträger | Wartung_FFB | 1 | Nebenträger | HEA 120 | 0.698 | Wartung_FFB | 10.56 | 58.101 | 6.998 | 13.04 | 58.101 | 6.998 | 0 | 0.06 | 0.057 | 0122Tra0000010158 | m | T110 | false | HI_UZV_HEA_STA_0,120_xxx | 0
Nebenträger | Wartung_FFB | 1 | Nebenträger | HEA 120 | 0.698 | Wartung_FFB | 64.06 | 56.601 | 6.998 | 67.04 | 56.601 | 6.998 | 0 | 0.06 | 0.057 | 0122Tra0000010197 | m | T110 | false | HI_UZV_HEA_STA_0,120_xxx | 0
Nebenträger | Wartung_FFB | 1 | Nebenträger | HEA 120 | 0.698 | Wartung_FFB | 67.06 | 56.601 | 6.998 | 70.04 | 56.601 | 6.998 | 0 | 0.06 | 0.057 | 0122Tra0000010199 | m | T110 | false | HI_UZV_HEA_STA_0,120_xxx | 0
Nebenträger | Wartung_FFB | 1 | Nebenträger | HEA 120 | 0.698 | Wartung_FFB | 70.06 | 56.601 | 6.998 | 73.04 | 56.601 | 6.998 | 0 | 0.06 | 0.057 | 0122Tra0000010201 | m | T110 | false | HI_UZV_HEA_STA_0,120_xxx | 0
Nebenträger | Wartung_FFB | 1 | Nebenträger | HEA 120 | 0.698 | Wartung_FFB | 73.06 | 56.601 | 6.998 | 76.04 | 56.601 | 6.998 | 0 | 0.06 | 0.057 | 0122Tra0000010203 | m | T110 | false | HI_UZV_HEA_STA_0,120_xxx | 0
Nebenträger | Wartung_FFB | 1 | Nebenträger | HEA 120 | 0.698 | Wartung_FFB | 76.06 | 56.601 | 6.998 | 79.04 | 56.601 | 6.998 | 0 | 0.06 | 0.057 | 0122Tra0000010205 | m | T110 | false | HI_UZV_HEA_STA_0,120_xxx | 0
Nebenträger | Wartung_FFB | 1 | Nebenträger | HEA 120 | 0.698 | Wartung_FFB | 103.06 | 56.601 | 6.998 | 106.04 | 56.601 | 6.998 | 0 | 0.06 | 0.057 | 0122Tra0000010223 | m | T110 | false | HI_UZV_HEA_STA_0,120_xxx | 0
Nebenträger | Wartung_FFB | 1 | Nebenträger | HEA 120 | 0.698 | Wartung_FFB | 106.06 | 56.601 | 6.998 | 109.04 | 56.601 | 6.998 | 0 | 0.06 | 0.057 | 0122Tra0000010225 | m | T110 | false | HI_UZV_HEA_STA_0,120_xxx | 0
Nebenträger | Wartung_FFB | 1 | Nebenträger | HEA 120 | 0.698 | Wartung_FFB | 109.06 | 56.601 | 6.998 | 112.04 | 56.601 | 6.998 | 0 | 0.06 | 0.057 | 0122Tra0000010227 | m | T110 | false | HI_UZV_HEA_STA_0,120_xxx | 0
Nebenträger | Wartung_FFB | 1 | Nebenträger | HEA 120 | 0.698 | Wartung_FFB | 112.06 | 56.601 | 6.998 | 115.04 | 56.601 | 6.998 | 0 | 0.06 | 0.057 | 0122Tra0000010229 | m | T110 | false | HI_UZV_HEA_STA_0,120_xxx | 0
Nebenträger | Wartung_FFB | 1 | Nebenträger | HEA 120 | 0.698 | Wartung_FFB | 115.06 | 56.601 | 6.998 | 118.04 | 56.601 | 6.998 | 0 | 0.06 | 0.057 | 0122Tra0000010231 | m | T110 | false | HI_UZV_HEA_STA_0,120_xxx | 0
Nebenträger | Wartung_FFB | 1 | Nebenträger | HEA 120 | 0.698 | Wartung_FFB | 13.06 | 56.601 | 6.998 | 16.04 | 56.601 | 6.998 | 0 | 0.06 | 0.057 | 0122Tra0000010235 | m | T110 | false | HI_UZV_HEA_STA_0,120_xxx | 0
Nebenträger | Wartung_FFB | 1 | Nebenträger | HEA 120 | 0.698 | Wartung_FFB | 16.06 | 56.601 | 6.998 | 19.04 | 56.601 | 6.998 | 0 | 0.06 | 0.057 | 0122Tra0000010237 | m | T110 | false | HI_UZV_HEA_STA_0,120_xxx | 0
Nebenträger | Wartung_FFB | 1 | Nebenträger | HEA 120 | 0.698 | Wartung_FFB | 19.06 | 56.601 | 6.998 | 22.04 | 56.601 | 6.998 | 0 | 0.06 | 0.057 | 0122Tra0000010239 | m | T110 | false | HI_UZV_HEA_STA_0,120_xxx | 0
Nebenträger | Wartung_FFB | 1 | Nebenträger | HEA 120 | 0.698 | Wartung_FFB | 34.06 | 56.601 | 6.998 | 37.04 | 56.601 | 6.998 | 0 | 0.06 | 0.057 | 0122Tra0000010249 | m | T110 | false | HI_UZV_HEA_STA_0,120_xxx | 0
Nebenträger | Wartung_FFB | 1 | Nebenträger | HEA 120 | 0.698 | Wartung_FFB | 37.06 | 56.601 | 6.998 | 40.04 | 56.601 | 6.998 | 0 | 0.06 | 0.057 | 0122Tra0000010251 | m | T110 | false | HI_UZV_HEA_STA_0,120_xxx | 0
Nebenträger | Wartung_FFB | 1 | Nebenträger | HEA 120 | 0.698 | Wartung_FFB | 40.06 | 56.601 | 6.998 | 43.04 | 56.601 | 6.998 | 0 | 0.06 | 0.057 | 0122Tra0000010253 | m | T110 | false | HI_UZV_HEA_STA_0,120_xxx | 0
Nebenträger | Wartung_FFB | 1 | Nebenträger | HEA 120 | 0.698 | Wartung_FFB | 49.06 | 56.601 | 6.998 | 52.04 | 56.601 | 6.998 | 0 | 0.06 | 0.057 | 0122Tra0000010259 | m | T110 | false | HI_UZV_HEA_STA_0,120_xxx | 0
Nebenträger | Wartung_FFB | 1 | Nebenträger | HEA 120 | 0.698 | Wartung_FFB | 52.06 | 56.601 | 6.998 | 55.04 | 56.601 | 6.998 | 0 | 0.06 | 0.057 | 0122Tra0000010261 | m | T110 | false | HI_UZV_HEA_STA_0,120_xxx | 0
Nebenträger | Wartung_FFB | 1 | Nebenträger | HEA 120 | 0.698 | Wartung_FFB | 55.06 | 56.601 | 6.998 | 58.04 | 56.601 | 6.998 | 0 | 0.06 | 0.057 | 0122Tra0000010263 | m | T110 | false | HI_UZV_HEA_STA_0,120_xxx | 0
Nebenträger | Wartung_FFB | 1 | Nebenträger | HEA 120 | 0.698 | Wartung_FFB | 58.06 | 56.601 | 6.998 | 61.04 | 56.601 | 6.998 | 0 | 0.06 | 0.057 | 0122Tra0000010265 | m | T110 | false | HI_UZV_HEA_STA_0,120_xxx | 0
Nebenträger | Wartung_FFB | 1 | Nebenträger | HEA 120 | 0.698 | Wartung_FFB | 61.06 | 56.601 | 6.998 | 64.04 | 56.601 | 6.998 | 0 | 0.06 | 0.057 | 0122Tra0000010267 | m | T110 | false | HI_UZV_HEA_STA_0,120_xxx | 0
Nebenträger | Wartung_FFB | 1 | Nebenträger | HEA 120 | 0.698 | Wartung_FFB | 10.56 | 56.601 | 6.998 | 13.04 | 56.601 | 6.998 | 0 | 0.06 | 0.057 | 0122Tra0000010269 | m | T110 | false | HI_UZV_HEA_STA_0,120_xxx | 0
Nebenträger | Wartung_FFB | 1 | Nebenträger | HEA 120 | 0.698 | Wartung_FFB | 64.06 | 55.101 | 6.998 | 67.04 | 55.101 | 6.998 | 0 | 0.06 | 0.057 | 0122Tra0000010345 | m | T110 | false | HI_UZV_HEA_STA_0,120_xxx | 0
Nebenträger | Wartung_FFB | 1 | Nebenträger | HEA 120 | 0.698 | Wartung_FFB | 67.06 | 55.101 | 6.998 | 70.04 | 55.101 | 6.998 | 0 | 0.06 | 0.057 | 0122Tra0000010347 | m | T110 | false | HI_UZV_HEA_STA_0,120_xxx | 0
Nebenträger | Wartung_FFB | 1 | Nebenträger | HEA 120 | 0.698 | Wartung_FFB | 70.06 | 55.101 | 6.998 | 73.04 | 55.101 | 6.998 | 0 | 0.06 | 0.057 | 0122Tra0000010349 | m | T110 | false | HI_UZV_HEA_STA_0,120_xxx | 0
Nebenträger | Wartung_FFB | 1 | Nebenträger | HEA 120 | 0.698 | Wartung_FFB | 73.06 | 55.101 | 6.998 | 76.04 | 55.101 | 6.998 | 0 | 0.06 | 0.057 | 0122Tra0000010351 | m | T110 | false | HI_UZV_HEA_STA_0,120_xxx | 0
Nebenträger | Wartung_FFB | 1 | Nebenträger | HEA 120 | 0.698 | Wartung_FFB | 76.06 | 55.101 | 6.998 | 79.04 | 55.101 | 6.998 | 0 | 0.06 | 0.057 | 0122Tra0000010353 | m | T110 | false | HI_UZV_HEA_STA_0,120_xxx | 0
Nebenträger | Wartung_FFB | 1 | Nebenträger | HEA 120 | 0.698 | Wartung_FFB | 103.06 | 55.101 | 6.998 | 106.04 | 55.101 | 6.998 | 0 | 0.06 | 0.057 | 0122Tra0000010371 | m | T110 | false | HI_UZV_HEA_STA_0,120_xxx | 0
Nebenträger | Wartung_FFB | 1 | Nebenträger | HEA 120 | 0.698 | Wartung_FFB | 106.06 | 55.101 | 6.998 | 109.04 | 55.101 | 6.998 | 0 | 0.06 | 0.057 | 0122Tra0000010373 | m | T110 | false | HI_UZV_HEA_STA_0,120_xxx | 0
Nebenträger | Wartung_FFB | 1 | Nebenträger | HEA 120 | 0.698 | Wartung_FFB | 109.06 | 55.101 | 6.998 | 112.04 | 55.101 | 6.998 | 0 | 0.06 | 0.057 | 0122Tra0000010375 | m | T110 | false | HI_UZV_HEA_STA_0,120_xxx | 0
Nebenträger | Wartung_FFB | 1 | Nebenträger | HEA 120 | 0.698 | Wartung_FFB | 112.06 | 55.101 | 6.998 | 115.04 | 55.101 | 6.998 | 0 | 0.06 | 0.057 | 0122Tra0000010377 | m | T110 | false | HI_UZV_HEA_STA_0,120_xxx | 0
Nebenträger | Wartung_FFB | 1 | Nebenträger | HEA 120 | 0.698 | Wartung_FFB | 115.06 | 55.101 | 6.998 | 118.04 | 55.101 | 6.998 | 0 | 0.06 | 0.057 | 0122Tra0000010379 | m | T110 | false | HI_UZV_HEA_STA_0,120_xxx | 0
Nebenträger | Wartung_FFB | 1 | Nebenträger | HEA 120 | 0.698 | Wartung_FFB | 13.06 | 55.101 | 6.998 | 16.04 | 55.101 | 6.998 | 0 | 0.06 | 0.057 | 0122Tra0000010383 | m | T110 | false | HI_UZV_HEA_STA_0,120_xxx | 0
Nebenträger | Wartung_FFB | 1 | Nebenträger | HEA 120 | 0.698 | Wartung_FFB | 16.06 | 55.101 | 6.998 | 19.04 | 55.101 | 6.998 | 0 | 0.06 | 0.057 | 0122Tra0000010385 | m | T110 | false | HI_UZV_HEA_STA_0,120_xxx | 0
Nebenträger | Wartung_FFB | 1 | Nebenträger | HEA 120 | 0.698 | Wartung_FFB | 19.06 | 55.101 | 6.998 | 22.04 | 55.101 | 6.998 | 0 | 0.06 | 0.057 | 0122Tra0000010387 | m | T110 | false | HI_UZV_HEA_STA_0,120_xxx | 0
Nebenträger | Wartung_FFB | 1 | Nebenträger | HEA 120 | 0.698 | Wartung_FFB | 34.06 | 55.101 | 6.998 | 37.04 | 55.101 | 6.998 | 0 | 0.06 | 0.057 | 0122Tra0000010397 | m | T110 | false | HI_UZV_HEA_STA_0,120_xxx | 0
Nebenträger | Wartung_FFB | 1 | Nebenträger | HEA 120 | 0.698 | Wartung_FFB | 37.06 | 55.101 | 6.998 | 40.04 | 55.101 | 6.998 | 0 | 0.06 | 0.057 | 0122Tra0000010399 | m | T110 | false | HI_UZV_HEA_STA_0,120_xxx | 0
Nebenträger | Wartung_FFB | 1 | Nebenträger | HEA 120 | 0.698 | Wartung_FFB | 40.06 | 55.101 | 6.998 | 43.04 | 55.101 | 6.998 | 0 | 0.06 | 0.057 | 0122Tra0000010401 | m | T110 | false | HI_UZV_HEA_STA_0,120_xxx | 0
Nebenträger | Wartung_FFB | 1 | Nebenträger | HEA 120 | 0.698 | Wartung_FFB | 49.06 | 55.101 | 6.998 | 52.04 | 55.101 | 6.998 | 0 | 0.06 | 0.057 | 0122Tra0000010407 | m | T110 | false | HI_UZV_HEA_STA_0,120_xxx | 0
Nebenträger | Wartung_FFB | 1 | Nebenträger | HEA 120 | 0.698 | Wartung_FFB | 52.06 | 55.101 | 6.998 | 55.04 | 55.101 | 6.998 | 0 | 0.06 | 0.057 | 0122Tra0000010409 | m | T110 | false | HI_UZV_HEA_STA_0,120_xxx | 0
Nebenträger | Wartung_FFB | 1 | Nebenträger | HEA 120 | 0.698 | Wartung_FFB | 55.06 | 55.101 | 6.998 | 58.04 | 55.101 | 6.998 | 0 | 0.06 | 0.057 | 0122Tra0000010411 | m | T110 | false | HI_UZV_HEA_STA_0,120_xxx | 0
Nebenträger | Wartung_FFB | 1 | Nebenträger | HEA 120 | 0.698 | Wartung_FFB | 58.06 | 55.101 | 6.998 | 61.04 | 55.101 | 6.998 | 0 | 0.06 | 0.057 | 0122Tra0000010413 | m | T110 | false | HI_UZV_HEA_STA_0,120_xxx | 0
Nebenträger | Wartung_FFB | 1 | Nebenträger | HEA 120 | 0.698 | Wartung_FFB | 61.06 | 55.101 | 6.998 | 64.04 | 55.101 | 6.998 | 0 | 0.06 | 0.057 | 0122Tra0000010415 | m | T110 | false | HI_UZV_HEA_STA_0,120_xxx | 0
Nebenträger | Wartung_FFB | 1 | Nebenträger | HEA 120 | 0.698 | Wartung_FFB | 10.56 | 55.101 | 6.998 | 13.04 | 55.101 | 6.998 | 0 | 0.06 | 0.057 | 0122Tra0000010417 | m | T110 | false | HI_UZV_HEA_STA_0,120_xxx | 0
Nebenträger | Wartung_FFB | 1 | Nebenträger | HEA 120 | 0.698 | Wartung_FFB | 64.06 | 53.601 | 6.998 | 67.04 | 53.601 | 6.998 | 0 | 0.06 | 0.057 | 0122Tra0000010419 | m | T110 | false | HI_UZV_HEA_STA_0,120_xxx | 0
Nebenträger | Wartung_FFB | 1 | Nebenträger | HEA 120 | 0.698 | Wartung_FFB | 67.06 | 53.601 | 6.998 | 70.04 | 53.601 | 6.998 | 0 | 0.06 | 0.057 | 0122Tra0000010421 | m | T110 | false | HI_UZV_HEA_STA_0,120_xxx | 0
Nebenträger | Wartung_FFB | 1 | Nebenträger | HEA 120 | 0.698 | Wartung_FFB | 70.06 | 53.601 | 6.998 | 73.04 | 53.601 | 6.998 | 0 | 0.06 | 0.057 | 0122Tra0000010423 | m | T110 | false | HI_UZV_HEA_STA_0,120_xxx | 0
Nebenträger | Wartung_FFB | 1 | Nebenträger | HEA 120 | 0.698 | Wartung_FFB | 73.06 | 53.601 | 6.998 | 76.04 | 53.601 | 6.998 | 0 | 0.06 | 0.057 | 0122Tra0000010425 | m | T110 | false | HI_UZV_HEA_STA_0,120_xxx | 0
Nebenträger | Wartung_FFB | 1 | Nebenträger | HEA 120 | 0.698 | Wartung_FFB | 76.06 | 53.601 | 6.998 | 79.04 | 53.601 | 6.998 | 0 | 0.06 | 0.057 | 0122Tra0000010427 | m | T110 | false | HI_UZV_HEA_STA_0,120_xxx | 0
Nebenträger | Wartung_FFB | 1 | Nebenträger | HEA 120 | 0.698 | Wartung_FFB | 103.06 | 53.601 | 6.998 | 106.04 | 53.601 | 6.998 | 0 | 0.06 | 0.057 | 0122Tra0000010445 | m | T110 | false | HI_UZV_HEA_STA_0,120_xxx | 0
Nebenträger | Wartung_FFB | 1 | Nebenträger | HEA 120 | 0.698 | Wartung_FFB | 106.06 | 53.601 | 6.998 | 109.04 | 53.601 | 6.998 | 0 | 0.06 | 0.057 | 0122Tra0000010447 | m | T110 | false | HI_UZV_HEA_STA_0,120_xxx | 0
Nebenträger | Wartung_FFB | 1 | Nebenträger | HEA 120 | 0.698 | Wartung_FFB | 109.06 | 53.601 | 6.998 | 112.04 | 53.601 | 6.998 | 0 | 0.06 | 0.057 | 0122Tra0000010449 | m | T110 | false | HI_UZV_HEA_STA_0,120_xxx | 0
Nebenträger | Wartung_FFB | 1 | Nebenträger | HEA 120 | 0.698 | Wartung_FFB | 112.06 | 53.601 | 6.998 | 115.04 | 53.601 | 6.998 | 0 | 0.06 | 0.057 | 0122Tra0000010451 | m | T110 | false | HI_UZV_HEA_STA_0,120_xxx | 0
Nebenträger | Wartung_FFB | 1 | Nebenträger | HEA 120 | 0.698 | Wartung_FFB | 115.06 | 53.601 | 6.998 | 118.04 | 53.601 | 6.998 | 0 | 0.06 | 0.057 | 0122Tra0000010453 | m | T110 | false | HI_UZV_HEA_STA_0,120_xxx | 0
Nebenträger | Wartung_FFB | 1 | Nebenträger | HEA 120 | 0.698 | Wartung_FFB | 13.06 | 53.601 | 6.998 | 16.04 | 53.601 | 6.998 | 0 | 0.06 | 0.057 | 0122Tra0000010457 | m | T110 | false | HI_UZV_HEA_STA_0,120_xxx | 0
Nebenträger | Wartung_FFB | 1 | Nebenträger | HEA 120 | 0.698 | Wartung_FFB | 16.06 | 53.601 | 6.998 | 19.04 | 53.601 | 6.998 | 0 | 0.06 | 0.057 | 0122Tra0000010459 | m | T110 | false | HI_UZV_HEA_STA_0,120_xxx | 0
Nebenträger | Wartung_FFB | 1 | Nebenträger | HEA 120 | 0.698 | Wartung_FFB | 19.06 | 53.601 | 6.998 | 22.04 | 53.601 | 6.998 | 0 | 0.06 | 0.057 | 0122Tra0000010461 | m | T110 | false | HI_UZV_HEA_STA_0,120_xxx | 0
Nebenträger | Wartung_FFB | 1 | Nebenträger | HEA 120 | 0.698 | Wartung_FFB | 34.06 | 53.601 | 6.998 | 37.04 | 53.601 | 6.998 | 0 | 0.06 | 0.057 | 0122Tra0000010471 | m | T110 | false | HI_UZV_HEA_STA_0,120_xxx | 0
Nebenträger | Wartung_FFB | 1 | Nebenträger | HEA 120 | 0.698 | Wartung_FFB | 37.06 | 53.601 | 6.998 | 40.04 | 53.601 | 6.998 | 0 | 0.06 | 0.057 | 0122Tra0000010473 | m | T110 | false | HI_UZV_HEA_STA_0,120_xxx | 0
Nebenträger | Wartung_FFB | 1 | Nebenträger | HEA 120 | 0.698 | Wartung_FFB | 40.06 | 53.601 | 6.998 | 43.04 | 53.601 | 6.998 | 0 | 0.06 | 0.057 | 0122Tra0000010475 | m | T110 | false | HI_UZV_HEA_STA_0,120_xxx | 0
Nebenträger | Wartung_FFB | 1 | Nebenträger | HEA 120 | 0.698 | Wartung_FFB | 49.06 | 53.601 | 6.998 | 52.04 | 53.601 | 6.998 | 0 | 0.06 | 0.057 | 0122Tra0000010481 | m | T110 | false | HI_UZV_HEA_STA_0,120_xxx | 0
Nebenträger | Wartung_FFB | 1 | Nebenträger | HEA 120 | 0.698 | Wartung_FFB | 52.06 | 53.601 | 6.998 | 55.04 | 53.601 | 6.998 | 0 | 0.06 | 0.057 | 0122Tra0000010483 | m | T110 | false | HI_UZV_HEA_STA_0,120_xxx | 0
Nebenträger | Wartung_FFB | 1 | Nebenträger | HEA 120 | 0.698 | Wartung_FFB | 55.06 | 53.601 | 6.998 | 58.04 | 53.601 | 6.998 | 0 | 0.06 | 0.057 | 0122Tra0000010485 | m | T110 | false | HI_UZV_HEA_STA_0,120_xxx | 0
Nebenträger | Wartung_FFB | 1 | Nebenträger | HEA 120 | 0.698 | Wartung_FFB | 58.06 | 53.601 | 6.998 | 61.04 | 53.601 | 6.998 | 0 | 0.06 | 0.057 | 0122Tra0000010487 | m | T110 | false | HI_UZV_HEA_STA_0,120_xxx | 0
Nebenträger | Wartung_FFB | 1 | Nebenträger | HEA 120 | 0.698 | Wartung_FFB | 61.06 | 53.601 | 6.998 | 64.04 | 53.601 | 6.998 | 0 | 0.06 | 0.057 | 0122Tra0000010489 | m | T110 | false | HI_UZV_HEA_STA_0,120_xxx | 0
Nebenträger | Wartung_FFB | 1 | Nebenträger | HEA 120 | 0.698 | Wartung_FFB | 10.56 | 53.601 | 6.998 | 13.04 | 53.601 | 6.998 | 0 | 0.06 | 0.057 | 0122Tra0000010491 | m | T110 | false | HI_UZV_HEA_STA_0,120_xxx | 0
Nebenträger | Wartung_FFB | 1 | Nebenträger | HEA 120 | 0.698 | Wartung_FFB | 64.06 | 49.45 | 6.998 | 67.04 | 49.45 | 6.998 | 0 | 0.06 | 0.057 | 0122Tra0000010826 | m | T110 | false | HI_UZV_HEA_STA_0,120_xxx | 0
Nebenträger | Wartung_FFB | 1 | Nebenträger | HEA 120 | 0.698 | Wartung_FFB | 13.06 | 49.45 | 6.998 | 16.04 | 49.45 | 6.998 | 0 | 0.06 | 0.057 | 0122Tra0000010864 | m | T110 | false | HI_UZV_HEA_STA_0,120_xxx | 0
Nebenträger | Wartung_FFB | 1 | Nebenträger | HEA 120 | 0.698 | Wartung_FFB | 16.06 | 49.45 | 6.998 | 19.04 | 49.45 | 6.998 | 0 | 0.06 | 0.057 | 0122Tra0000010866 | m | T110 | false | HI_UZV_HEA_STA_0,120_xxx | 0
Nebenträger | Wartung_FFB | 1 | Nebenträger | HEA 120 | 0.698 | Wartung_FFB | 19.06 | 49.45 | 6.998 | 22.04 | 49.45 | 6.998 | 0 | 0.06 | 0.057 | 0122Tra0000010868 | m | T110 | false | HI_UZV_HEA_STA_0,120_xxx | 0
Nebenträger | Wartung_FFB | 1 | Nebenträger | HEA 120 | 0.698 | Wartung_FFB | 34.06 | 49.45 | 6.998 | 37.04 | 49.45 | 6.998 | 0 | 0.06 | 0.057 | 0122Tra0000010878 | m | T110 | false | HI_UZV_HEA_STA_0,120_xxx | 0
Nebenträger | Wartung_FFB | 1 | Nebenträger | HEA 120 | 0.698 | Wartung_FFB | 37.06 | 49.45 | 6.998 | 40.04 | 49.45 | 6.998 | 0 | 0.06 | 0.057 | 0122Tra0000010880 | m | T110 | false | HI_UZV_HEA_STA_0,120_xxx | 0
Nebenträger | Wartung_FFB | 1 | Nebenträger | HEA 120 | 0.698 | Wartung_FFB | 40.06 | 49.45 | 6.998 | 43.04 | 49.45 | 6.998 | 0 | 0.06 | 0.057 | 0122Tra0000010882 | m | T110 | false | HI_UZV_HEA_STA_0,120_xxx | 0
Nebenträger | Wartung_FFB | 1 | Nebenträger | HEA 120 | 0.698 | Wartung_FFB | 49.06 | 49.45 | 6.998 | 52.04 | 49.45 | 6.998 | 0 | 0.06 | 0.057 | 0122Tra0000010888 | m | T110 | false | HI_UZV_HEA_STA_0,120_xxx | 0
Nebenträger | Wartung_FFB | 1 | Nebenträger | HEA 120 | 0.698 | Wartung_FFB | 52.06 | 49.45 | 6.998 | 55.04 | 49.45 | 6.998 | 0 | 0.06 | 0.057 | 0122Tra0000010890 | m | T110 | false | HI_UZV_HEA_STA_0,120_xxx | 0
Nebenträger | Wartung_FFB | 1 | Nebenträger | HEA 120 | 0.698 | Wartung_FFB | 55.06 | 49.45 | 6.998 | 58.04 | 49.45 | 6.998 | 0 | 0.06 | 0.057 | 0122Tra0000010892 | m | T110 | false | HI_UZV_HEA_STA_0,120_xxx | 0
Nebenträger | Wartung_FFB | 1 | Nebenträger | HEA 120 | 0.698 | Wartung_FFB | 58.06 | 49.45 | 6.998 | 61.04 | 49.45 | 6.998 | 0 | 0.06 | 0.057 | 0122Tra0000010894 | m | T110 | false | HI_UZV_HEA_STA_0,120_xxx | 0
Nebenträger | Wartung_FFB | 1 | Nebenträger | HEA 120 | 0.698 | Wartung_FFB | 61.06 | 49.45 | 6.998 | 64.04 | 49.45 | 6.998 | 0 | 0.06 | 0.057 | 0122Tra0000010896 | m | T110 | false | HI_UZV_HEA_STA_0,120_xxx | 0
Nebenträger | Wartung_FFB | 1 | Nebenträger | HEA 120 | 0.698 | Wartung_FFB | 10.56 | 49.45 | 6.998 | 13.04 | 49.45 | 6.998 | 0 | 0.06 | 0.057 | 0122Tra0000010898 | m | T110 | false | HI_UZV_HEA_STA_0,120_xxx | 0
Nebenträger | Wartung_FFB | 1 | Nebenträger | HEA 120 | 0.698 | Wartung_FFB | 64.06 | 47.95 | 6.998 | 67.04 | 47.95 | 6.998 | 0 | 0.06 | 0.057 | 0122Tra0000010900 | m | T110 | false | HI_UZV_HEA_STA_0,120_xxx | 0
Nebenträger | Wartung_FFB | 1 | Nebenträger | HEA 120 | 0.698 | Wartung_FFB | 13.06 | 47.95 | 6.998 | 16.04 | 47.95 | 6.998 | 0 | 0.06 | 0.057 | 0122Tra0000010938 | m | T110 | false | HI_UZV_HEA_STA_0,120_xxx | 0
Nebenträger | Wartung_FFB | 1 | Nebenträger | HEA 120 | 0.698 | Wartung_FFB | 16.06 | 47.95 | 6.998 | 19.04 | 47.95 | 6.998 | 0 | 0.06 | 0.057 | 0122Tra0000010940 | m | T110 | false | HI_UZV_HEA_STA_0,120_xxx | 0
Nebenträger | Wartung_FFB | 1 | Nebenträger | HEA 120 | 0.698 | Wartung_FFB | 19.06 | 47.95 | 6.998 | 22.04 | 47.95 | 6.998 | 0 | 0.06 | 0.057 | 0122Tra0000010942 | m | T110 | false | HI_UZV_HEA_STA_0,120_xxx | 0
Nebenträger | Wartung_FFB | 1 | Nebenträger | HEA 120 | 0.698 | Wartung_FFB | 34.06 | 47.95 | 6.998 | 37.04 | 47.95 | 6.998 | 0 | 0.06 | 0.057 | 0122Tra0000010952 | m | T110 | false | HI_UZV_HEA_STA_0,120_xxx | 0
Nebenträger | Wartung_FFB | 1 | Nebenträger | HEA 120 | 0.698 | Wartung_FFB | 37.06 | 47.95 | 6.998 | 40.04 | 47.95 | 6.998 | 0 | 0.06 | 0.057 | 0122Tra0000010954 | m | T110 | false | HI_UZV_HEA_STA_0,120_xxx | 0
Nebenträger | Wartung_FFB | 1 | Nebenträger | HEA 120 | 0.698 | Wartung_FFB | 40.06 | 47.95 | 6.998 | 43.04 | 47.95 | 6.998 | 0 | 0.06 | 0.057 | 0122Tra0000010956 | m | T110 | false | HI_UZV_HEA_STA_0,120_xxx | 0
Nebenträger | Wartung_FFB | 1 | Nebenträger | HEA 120 | 0.698 | Wartung_FFB | 49.06 | 47.95 | 6.998 | 52.04 | 47.95 | 6.998 | 0 | 0.06 | 0.057 | 0122Tra0000010962 | m | T110 | false | HI_UZV_HEA_STA_0,120_xxx | 0
Nebenträger | Wartung_FFB | 1 | Nebenträger | HEA 120 | 0.698 | Wartung_FFB | 52.06 | 47.95 | 6.998 | 55.04 | 47.95 | 6.998 | 0 | 0.06 | 0.057 | 0122Tra0000010964 | m | T110 | false | HI_UZV_HEA_STA_0,120_xxx | 0
Nebenträger | Wartung_FFB | 1 | Nebenträger | HEA 120 | 0.698 | Wartung_FFB | 55.06 | 47.95 | 6.998 | 58.04 | 47.95 | 6.998 | 0 | 0.06 | 0.057 | 0122Tra0000010966 | m | T110 | false | HI_UZV_HEA_STA_0,120_xxx | 0
Nebenträger | Wartung_FFB | 1 | Nebenträger | HEA 120 | 0.698 | Wartung_FFB | 58.06 | 47.95 | 6.998 | 61.04 | 47.95 | 6.998 | 0 | 0.06 | 0.057 | 0122Tra0000010968 | m | T110 | false | HI_UZV_HEA_STA_0,120_xxx | 0
Nebenträger | Wartung_FFB | 1 | Nebenträger | HEA 120 | 0.698 | Wartung_FFB | 61.06 | 47.95 | 6.998 | 64.04 | 47.95 | 6.998 | 0 | 0.06 | 0.057 | 0122Tra0000010970 | m | T110 | false | HI_UZV_HEA_STA_0,120_xxx | 0
Nebenträger | Wartung_FFB | 1 | Nebenträger | HEA 120 | 0.698 | Wartung_FFB | 10.56 | 47.95 | 6.998 | 13.04 | 47.95 | 6.998 | 0 | 0.06 | 0.057 | 0122Tra0000010972 | m | T110 | false | HI_UZV_HEA_STA_0,120_xxx | 0
Nebenträger | Wartung_FFB | 1 | Nebenträger | HEA 120 | 0.698 | Wartung_FFB | 64.06 | 46.45 | 6.998 | 67.04 | 46.45 | 6.998 | 0 | 0.06 | 0.057 | 0122Tra0000010974 | m | T110 | false | HI_UZV_HEA_STA_0,120_xxx | 0
Nebenträger | Wartung_FFB | 1 | Nebenträger | HEA 120 | 0.698 | Wartung_FFB | 13.06 | 46.45 | 6.998 | 16.04 | 46.45 | 6.998 | 0 | 0.06 | 0.057 | 0122Tra0000011012 | m | T110 | false | HI_UZV_HEA_STA_0,120_xxx | 0
Nebenträger | Wartung_FFB | 1 | Nebenträger | HEA 120 | 0.698 | Wartung_FFB | 16.06 | 46.45 | 6.998 | 19.04 | 46.45 | 6.998 | 0 | 0.06 | 0.057 | 0122Tra0000011014 | m | T110 | false | HI_UZV_HEA_STA_0,120_xxx | 0
Nebenträger | Wartung_FFB | 1 | Nebenträger | HEA 120 | 0.698 | Wartung_FFB | 19.06 | 46.45 | 6.998 | 22.04 | 46.45 | 6.998 | 0 | 0.06 | 0.057 | 0122Tra0000011016 | m | T110 | false | HI_UZV_HEA_STA_0,120_xxx | 0
Nebenträger | Wartung_FFB | 1 | Nebenträger | HEA 120 | 0.698 | Wartung_FFB | 34.06 | 46.45 | 6.998 | 37.04 | 46.45 | 6.998 | 0 | 0.06 | 0.057 | 0122Tra0000011026 | m | T110 | false | HI_UZV_HEA_STA_0,120_xxx | 0
Nebenträger | Wartung_FFB | 1 | Nebenträger | HEA 120 | 0.698 | Wartung_FFB | 37.06 | 46.45 | 6.998 | 40.04 | 46.45 | 6.998 | 0 | 0.06 | 0.057 | 0122Tra0000011028 | m | T110 | false | HI_UZV_HEA_STA_0,120_xxx | 0
Nebenträger | Wartung_FFB | 1 | Nebenträger | HEA 120 | 0.698 | Wartung_FFB | 40.06 | 46.45 | 6.998 | 43.04 | 46.45 | 6.998 | 0 | 0.06 | 0.057 | 0122Tra0000011030 | m | T110 | false | HI_UZV_HEA_STA_0,120_xxx | 0
Nebenträger | Wartung_FFB | 1 | Nebenträger | HEA 120 | 0.698 | Wartung_FFB | 49.06 | 46.45 | 6.998 | 52.04 | 46.45 | 6.998 | 0 | 0.06 | 0.057 | 0122Tra0000011036 | m | T110 | false | HI_UZV_HEA_STA_0,120_xxx | 0
Nebenträger | Wartung_FFB | 1 | Nebenträger | HEA 120 | 0.698 | Wartung_FFB | 52.06 | 46.45 | 6.998 | 55.04 | 46.45 | 6.998 | 0 | 0.06 | 0.057 | 0122Tra0000011038 | m | T110 | false | HI_UZV_HEA_STA_0,120_xxx | 0
Nebenträger | Wartung_FFB | 1 | Nebenträger | HEA 120 | 0.698 | Wartung_FFB | 55.06 | 46.45 | 6.998 | 58.04 | 46.45 | 6.998 | 0 | 0.06 | 0.057 | 0122Tra0000011040 | m | T110 | false | HI_UZV_HEA_STA_0,120_xxx | 0
Nebenträger | Wartung_FFB | 1 | Nebenträger | HEA 120 | 0.698 | Wartung_FFB | 58.06 | 46.45 | 6.998 | 61.04 | 46.45 | 6.998 | 0 | 0.06 | 0.057 | 0122Tra0000011042 | m | T110 | false | HI_UZV_HEA_STA_0,120_xxx | 0
Nebenträger | Wartung_FFB | 1 | Nebenträger | HEA 120 | 0.698 | Wartung_FFB | 61.06 | 46.45 | 6.998 | 64.04 | 46.45 | 6.998 | 0 | 0.06 | 0.057 | 0122Tra0000011044 | m | T110 | false | HI_UZV_HEA_STA_0,120_xxx | 0
Nebenträger | Wartung_FFB | 1 | Nebenträger | HEA 120 | 0.698 | Wartung_FFB | 10.56 | 46.45 | 6.998 | 13.04 | 46.45 | 6.998 | 0 | 0.06 | 0.057 | 0122Tra0000011046 | m | T110 | false | HI_UZV_HEA_STA_0,120_xxx | 0
Nebenträger | Wartung_FFB | 1 | Nebenträger | HEA 120 | 0.698 | Wartung_FFB | 64.06 | 44.95 | 6.998 | 67.04 | 44.95 | 6.998 | 0 | 0.06 | 0.057 | 0122Tra0000011048 | m | T110 | false | HI_UZV_HEA_STA_0,120_xxx | 0
Nebenträger | Wartung_FFB | 1 | Nebenträger | HEA 120 | 0.698 | Wartung_FFB | 13.06 | 44.95 | 6.998 | 16.04 | 44.95 | 6.998 | 0 | 0.06 | 0.057 | 0122Tra0000011086 | m | T110 | false | HI_UZV_HEA_STA_0,120_xxx | 0
Nebenträger | Wartung_FFB | 1 | Nebenträger | HEA 120 | 0.698 | Wartung_FFB | 16.06 | 44.95 | 6.998 | 19.04 | 44.95 | 6.998 | 0 | 0.06 | 0.057 | 0122Tra0000011088 | m | T110 | false | HI_UZV_HEA_STA_0,120_xxx | 0
Nebenträger | Wartung_FFB | 1 | Nebenträger | HEA 120 | 0.698 | Wartung_FFB | 19.06 | 44.95 | 6.998 | 22.04 | 44.95 | 6.998 | 0 | 0.06 | 0.057 | 0122Tra0000011090 | m | T110 | false | HI_UZV_HEA_STA_0,120_xxx | 0
Nebenträger | Wartung_FFB | 1 | Nebenträger | HEA 120 | 0.698 | Wartung_FFB | 34.06 | 44.95 | 6.998 | 37.04 | 44.95 | 6.998 | 0 | 0.06 | 0.057 | 0122Tra0000011100 | m | T110 | false | HI_UZV_HEA_STA_0,120_xxx | 0
Nebenträger | Wartung_FFB | 1 | Nebenträger | HEA 120 | 0.698 | Wartung_FFB | 37.06 | 44.95 | 6.998 | 40.04 | 44.95 | 6.998 | 0 | 0.06 | 0.057 | 0122Tra0000011102 | m | T110 | false | HI_UZV_HEA_STA_0,120_xxx | 0
Nebenträger | Wartung_FFB | 1 | Nebenträger | HEA 120 | 0.698 | Wartung_FFB | 40.06 | 44.95 | 6.998 | 43.04 | 44.95 | 6.998 | 0 | 0.06 | 0.057 | 0122Tra0000011104 | m | T110 | false | HI_UZV_HEA_STA_0,120_xxx | 0
Nebenträger | Wartung_FFB | 1 | Nebenträger | HEA 120 | 0.698 | Wartung_FFB | 49.06 | 44.95 | 6.998 | 52.04 | 44.95 | 6.998 | 0 | 0.06 | 0.057 | 0122Tra0000011110 | m | T110 | false | HI_UZV_HEA_STA_0,120_xxx | 0
Nebenträger | Wartung_FFB | 1 | Nebenträger | HEA 120 | 0.698 | Wartung_FFB | 52.06 | 44.95 | 6.998 | 55.04 | 44.95 | 6.998 | 0 | 0.06 | 0.057 | 0122Tra0000011112 | m | T110 | false | HI_UZV_HEA_STA_0,120_xxx | 0
Nebenträger | Wartung_FFB | 1 | Nebenträger | HEA 120 | 0.698 | Wartung_FFB | 55.06 | 44.95 | 6.998 | 58.04 | 44.95 | 6.998 | 0 | 0.06 | 0.057 | 0122Tra0000011114 | m | T110 | false | HI_UZV_HEA_STA_0,120_xxx | 0
Nebenträger | Wartung_FFB | 1 | Nebenträger | HEA 120 | 0.698 | Wartung_FFB | 58.06 | 44.95 | 6.998 | 61.04 | 44.95 | 6.998 | 0 | 0.06 | 0.057 | 0122Tra0000011116 | m | T110 | false | HI_UZV_HEA_STA_0,120_xxx | 0
Nebenträger | Wartung_FFB | 1 | Nebenträger | HEA 120 | 0.698 | Wartung_FFB | 61.06 | 44.95 | 6.998 | 64.04 | 44.95 | 6.998 | 0 | 0.06 | 0.057 | 0122Tra0000011118 | m | T110 | false | HI_UZV_HEA_STA_0,120_xxx | 0
Nebenträger | Wartung_FFB | 1 | Nebenträger | HEA 120 | 0.698 | Wartung_FFB | 10.56 | 44.95 | 6.998 | 13.04 | 44.95 | 6.998 | 0 | 0.06 | 0.057 | 0122Tra0000011120 | m | T110 | false | HI_UZV_HEA_STA_0,120_xxx | 0
Nebenträger | Wartung_FFB | 1 | Nebenträger | HEA 120 | 0.698 | Wartung_FFB | 64.06 | 43.45 | 6.998 | 67.04 | 43.45 | 6.998 | 0 | 0.06 | 0.057 | 0122Tra0000011122 | m | T110 | false | HI_UZV_HEA_STA_0,120_xxx | 0
Nebenträger | Wartung_FFB | 1 | Nebenträger | HEA 120 | 0.698 | Wartung_FFB | 13.06 | 43.45 | 6.998 | 16.04 | 43.45 | 6.998 | 0 | 0.06 | 0.057 | 0122Tra0000011160 | m | T110 | false | HI_UZV_HEA_STA_0,120_xxx | 0
Nebenträger | Wartung_FFB | 1 | Nebenträger | HEA 120 | 0.698 | Wartung_FFB | 16.06 | 43.45 | 6.998 | 19.04 | 43.45 | 6.998 | 0 | 0.06 | 0.057 | 0122Tra0000011162 | m | T110 | false | HI_UZV_HEA_STA_0,120_xxx | 0
Nebenträger | Wartung_FFB | 1 | Nebenträger | HEA 120 | 0.698 | Wartung_FFB | 19.06 | 43.45 | 6.998 | 22.04 | 43.45 | 6.998 | 0 | 0.06 | 0.057 | 0122Tra0000011164 | m | T110 | false | HI_UZV_HEA_STA_0,120_xxx | 0
Nebenträger | Wartung_FFB | 1 | Nebenträger | HEA 120 | 0.698 | Wartung_FFB | 34.06 | 43.45 | 6.998 | 37.04 | 43.45 | 6.998 | 0 | 0.06 | 0.057 | 0122Tra0000011174 | m | T110 | false | HI_UZV_HEA_STA_0,120_xxx | 0
Nebenträger | Wartung_FFB | 1 | Nebenträger | HEA 120 | 0.698 | Wartung_FFB | 37.06 | 43.45 | 6.998 | 40.04 | 43.45 | 6.998 | 0 | 0.06 | 0.057 | 0122Tra0000011176 | m | T110 | false | HI_UZV_HEA_STA_0,120_xxx | 0
Nebenträger | Wartung_FFB | 1 | Nebenträger | HEA 120 | 0.698 | Wartung_FFB | 40.06 | 43.45 | 6.998 | 43.04 | 43.45 | 6.998 | 0 | 0.06 | 0.057 | 0122Tra0000011178 | m | T110 | false | HI_UZV_HEA_STA_0,120_xxx | 0
Nebenträger | Wartung_FFB | 1 | Nebenträger | HEA 120 | 0.698 | Wartung_FFB | 49.06 | 43.45 | 6.998 | 52.04 | 43.45 | 6.998 | 0 | 0.06 | 0.057 | 0122Tra0000011184 | m | T110 | false | HI_UZV_HEA_STA_0,120_xxx | 0
Nebenträger | Wartung_FFB | 1 | Nebenträger | HEA 120 | 0.698 | Wartung_FFB | 52.06 | 43.45 | 6.998 | 55.04 | 43.45 | 6.998 | 0 | 0.06 | 0.057 | 0122Tra0000011186 | m | T110 | false | HI_UZV_HEA_STA_0,120_xxx | 0
Nebenträger | Wartung_FFB | 1 | Nebenträger | HEA 120 | 0.698 | Wartung_FFB | 55.06 | 43.45 | 6.998 | 58.04 | 43.45 | 6.998 | 0 | 0.06 | 0.057 | 0122Tra0000011188 | m | T110 | false | HI_UZV_HEA_STA_0,120_xxx | 0
Nebenträger | Wartung_FFB | 1 | Nebenträger | HEA 120 | 0.698 | Wartung_FFB | 58.06 | 43.45 | 6.998 | 61.04 | 43.45 | 6.998 | 0 | 0.06 | 0.057 | 0122Tra0000011190 | m | T110 | false | HI_UZV_HEA_STA_0,120_xxx | 0
Nebenträger | Wartung_FFB | 1 | Nebenträger | HEA 120 | 0.698 | Wartung_FFB | 61.06 | 43.45 | 6.998 | 64.04 | 43.45 | 6.998 | 0 | 0.06 | 0.057 | 0122Tra0000011192 | m | T110 | false | HI_UZV_HEA_STA_0,120_xxx | 0
Nebenträger | Wartung_FFB | 1 | Nebenträger | HEA 120 | 0.698 | Wartung_FFB | 10.56 | 43.45 | 6.998 | 13.04 | 43.45 | 6.998 | 0 | 0.06 | 0.057 | 0122Tra0000011194 | m | T110 | false | HI_UZV_HEA_STA_0,120_xxx | 0
Nebenträger | Wartung_FFB | 1 | Nebenträger | HEA 120 | 0.698 | Wartung_FFB | 64.06 | 41.95 | 6.998 | 67.04 | 41.95 | 6.998 | 0 | 0.06 | 0.057 | 0122Tra0000011196 | m | T110 | false | HI_UZV_HEA_STA_0,120_xxx | 0
Nebenträger | Wartung_FFB | 1 | Nebenträger | HEA 120 | 0.698 | Wartung_FFB | 13.06 | 41.95 | 6.998 | 16.04 | 41.95 | 6.998 | 0 | 0.06 | 0.057 | 0122Tra0000011234 | m | T110 | false | HI_UZV_HEA_STA_0,120_xxx | 0
Nebenträger | Wartung_FFB | 1 | Nebenträger | HEA 120 | 0.698 | Wartung_FFB | 16.06 | 41.95 | 6.998 | 19.04 | 41.95 | 6.998 | 0 | 0.06 | 0.057 | 0122Tra0000011236 | m | T110 | false | HI_UZV_HEA_STA_0,120_xxx | 0
Nebenträger | Wartung_FFB | 1 | Nebenträger | HEA 120 | 0.698 | Wartung_FFB | 19.06 | 41.95 | 6.998 | 22.04 | 41.95 | 6.998 | 0 | 0.06 | 0.057 | 0122Tra0000011238 | m | T110 | false | HI_UZV_HEA_STA_0,120_xxx | 0
Nebenträger | Wartung_FFB | 1 | Nebenträger | HEA 120 | 0.698 | Wartung_FFB | 34.06 | 41.95 | 6.998 | 37.04 | 41.95 | 6.998 | 0 | 0.06 | 0.057 | 0122Tra0000011248 | m | T110 | false | HI_UZV_HEA_STA_0,120_xxx | 0
Nebenträger | Wartung_FFB | 1 | Nebenträger | HEA 120 | 0.698 | Wartung_FFB | 37.06 | 41.95 | 6.998 | 40.04 | 41.95 | 6.998 | 0 | 0.06 | 0.057 | 0122Tra0000011250 | m | T110 | false | HI_UZV_HEA_STA_0,120_xxx | 0
Nebenträger | Wartung_FFB | 1 | Nebenträger | HEA 120 | 0.698 | Wartung_FFB | 40.06 | 41.95 | 6.998 | 43.04 | 41.95 | 6.998 | 0 | 0.06 | 0.057 | 0122Tra0000011252 | m | T110 | false | HI_UZV_HEA_STA_0,120_xxx | 0
Nebenträger | Wartung_FFB | 1 | Nebenträger | HEA 120 | 0.698 | Wartung_FFB | 49.06 | 41.95 | 6.998 | 52.04 | 41.95 | 6.998 | 0 | 0.06 | 0.057 | 0122Tra0000011258 | m | T110 | false | HI_UZV_HEA_STA_0,120_xxx | 0
Nebenträger | Wartung_FFB | 1 | Nebenträger | HEA 120 | 0.698 | Wartung_FFB | 52.06 | 41.95 | 6.998 | 55.04 | 41.95 | 6.998 | 0 | 0.06 | 0.057 | 0122Tra0000011260 | m | T110 | false | HI_UZV_HEA_STA_0,120_xxx | 0
Nebenträger | Wartung_FFB | 1 | Nebenträger | HEA 120 | 0.698 | Wartung_FFB | 55.06 | 41.95 | 6.998 | 58.04 | 41.95 | 6.998 | 0 | 0.06 | 0.057 | 0122Tra0000011262 | m | T110 | false | HI_UZV_HEA_STA_0,120_xxx | 0
Nebenträger | Wartung_FFB | 1 | Nebenträger | HEA 120 | 0.698 | Wartung_FFB | 58.06 | 41.95 | 6.998 | 61.04 | 41.95 | 6.998 | 0 | 0.06 | 0.057 | 0122Tra0000011264 | m | T110 | false | HI_UZV_HEA_STA_0,120_xxx | 0
Nebenträger | Wartung_FFB | 1 | Nebenträger | HEA 120 | 0.698 | Wartung_FFB | 61.06 | 41.95 | 6.998 | 64.04 | 41.95 | 6.998 | 0 | 0.06 | 0.057 | 0122Tra0000011266 | m | T110 | false | HI_UZV_HEA_STA_0,120_xxx | 0
Nebenträger | Wartung_FFB | 1 | Nebenträger | HEA 120 | 0.698 | Wartung_FFB | 10.56 | 41.95 | 6.998 | 13.04 | 41.95 | 6.998 | 0 | 0.06 | 0.057 | 0122Tra0000011268 | m | T110 | false | HI_UZV_HEA_STA_0,120_xxx | 0
Nebenträger | Wartung_FFB | 1 | Nebenträger | HEA 120 | 0.698 | Wartung_FFB | 64.06 | 40.45 | 6.998 | 67.04 | 40.45 | 6.998 | 0 | 0.06 | 0.057 | 0122Tra0000011270 | m | T110 | false | HI_UZV_HEA_STA_0,120_xxx | 0
Nebenträger | Wartung_FFB | 1 | Nebenträger | HEA 120 | 0.698 | Wartung_FFB | 13.06 | 40.45 | 6.998 | 16.04 | 40.45 | 6.998 | 0 | 0.06 | 0.057 | 0122Tra0000011308 | m | T110 | false | HI_UZV_HEA_STA_0,120_xxx | 0
Nebenträger | Wartung_FFB | 1 | Nebenträger | HEA 120 | 0.698 | Wartung_FFB | 16.06 | 40.45 | 6.998 | 19.04 | 40.45 | 6.998 | 0 | 0.06 | 0.057 | 0122Tra0000011310 | m | T110 | false | HI_UZV_HEA_STA_0,120_xxx | 0
Nebenträger | Wartung_FFB | 1 | Nebenträger | HEA 120 | 0.698 | Wartung_FFB | 19.06 | 40.45 | 6.998 | 22.04 | 40.45 | 6.998 | 0 | 0.06 | 0.057 | 0122Tra0000011312 | m | T110 | false | HI_UZV_HEA_STA_0,120_xxx | 0
Nebenträger | Wartung_FFB | 1 | Nebenträger | HEA 120 | 0.698 | Wartung_FFB | 34.06 | 40.45 | 6.998 | 37.04 | 40.45 | 6.998 | 0 | 0.06 | 0.057 | 0122Tra0000011322 | m | T110 | false | HI_UZV_HEA_STA_0,120_xxx | 0
Nebenträger | Wartung_FFB | 1 | Nebenträger | HEA 120 | 0.698 | Wartung_FFB | 37.06 | 40.45 | 6.998 | 40.04 | 40.45 | 6.998 | 0 | 0.06 | 0.057 | 0122Tra0000011324 | m | T110 | false | HI_UZV_HEA_STA_0,120_xxx | 0
Nebenträger | Wartung_FFB | 1 | Nebenträger | HEA 120 | 0.698 | Wartung_FFB | 40.06 | 40.45 | 6.998 | 43.04 | 40.45 | 6.998 | 0 | 0.06 | 0.057 | 0122Tra0000011326 | m | T110 | false | HI_UZV_HEA_STA_0,120_xxx | 0
Nebenträger | Wartung_FFB | 1 | Nebenträger | HEA 120 | 0.698 | Wartung_FFB | 49.06 | 40.45 | 6.998 | 52.04 | 40.45 | 6.998 | 0 | 0.06 | 0.057 | 0122Tra0000011332 | m | T110 | false | HI_UZV_HEA_STA_0,120_xxx | 0
Nebenträger | Wartung_FFB | 1 | Nebenträger | HEA 120 | 0.698 | Wartung_FFB | 52.06 | 40.45 | 6.998 | 55.04 | 40.45 | 6.998 | 0 | 0.06 | 0.057 | 0122Tra0000011334 | m | T110 | false | HI_UZV_HEA_STA_0,120_xxx | 0
Nebenträger | Wartung_FFB | 1 | Nebenträger | HEA 120 | 0.698 | Wartung_FFB | 55.06 | 40.45 | 6.998 | 58.04 | 40.45 | 6.998 | 0 | 0.06 | 0.057 | 0122Tra0000011336 | m | T110 | false | HI_UZV_HEA_STA_0,120_xxx | 0
Nebenträger | Wartung_FFB | 1 | Nebenträger | HEA 120 | 0.698 | Wartung_FFB | 58.06 | 40.45 | 6.998 | 61.04 | 40.45 | 6.998 | 0 | 0.06 | 0.057 | 0122Tra0000011338 | m | T110 | false | HI_UZV_HEA_STA_0,120_xxx | 0
Nebenträger | Wartung_FFB | 1 | Nebenträger | HEA 120 | 0.698 | Wartung_FFB | 61.06 | 40.45 | 6.998 | 64.04 | 40.45 | 6.998 | 0 | 0.06 | 0.057 | 0122Tra0000011340 | m | T110 | false | HI_UZV_HEA_STA_0,120_xxx | 0
Nebenträger | Wartung_FFB | 1 | Nebenträger | HEA 120 | 0.698 | Wartung_FFB | 10.56 | 40.45 | 6.998 | 13.04 | 40.45 | 6.998 | 0 | 0.06 | 0.057 | 0122Tra0000011342 | m | T110 | false | HI_UZV_HEA_STA_0,120_xxx | 0
Nebenträger | Wartung_FFB | 1 | Nebenträger | HEA 120 | 0.698 | Wartung_FFB | 64.06 | 38.95 | 6.998 | 67.04 | 38.95 | 6.998 | 0 | 0.06 | 0.057 | 0122Tra0000011344 | m | T110 | false | HI_UZV_HEA_STA_0,120_xxx | 0
Nebenträger | Wartung_FFB | 1 | Nebenträger | HEA 120 | 0.698 | Wartung_FFB | 13.06 | 38.95 | 6.998 | 16.04 | 38.95 | 6.998 | 0 | 0.06 | 0.057 | 0122Tra0000011382 | m | T110 | false | HI_UZV_HEA_STA_0,120_xxx | 0
Nebenträger | Wartung_FFB | 1 | Nebenträger | HEA 120 | 0.698 | Wartung_FFB | 16.06 | 38.95 | 6.998 | 19.04 | 38.95 | 6.998 | 0 | 0.06 | 0.057 | 0122Tra0000011384 | m | T110 | false | HI_UZV_HEA_STA_0,120_xxx | 0
Nebenträger | Wartung_FFB | 1 | Nebenträger | HEA 120 | 0.698 | Wartung_FFB | 19.06 | 38.95 | 6.998 | 22.04 | 38.95 | 6.998 | 0 | 0.06 | 0.057 | 0122Tra0000011386 | m | T110 | false | HI_UZV_HEA_STA_0,120_xxx | 0
Nebenträger | Wartung_FFB | 1 | Nebenträger | HEA 120 | 0.698 | Wartung_FFB | 34.06 | 38.95 | 6.998 | 37.04 | 38.95 | 6.998 | 0 | 0.06 | 0.057 | 0122Tra0000011396 | m | T110 | false | HI_UZV_HEA_STA_0,120_xxx | 0
Nebenträger | Wartung_FFB | 1 | Nebenträger | HEA 120 | 0.698 | Wartung_FFB | 37.06 | 38.95 | 6.998 | 40.04 | 38.95 | 6.998 | 0 | 0.06 | 0.057 | 0122Tra0000011398 | m | T110 | false | HI_UZV_HEA_STA_0,120_xxx | 0
Nebenträger | Wartung_FFB | 1 | Nebenträger | HEA 120 | 0.698 | Wartung_FFB | 40.06 | 38.95 | 6.998 | 43.04 | 38.95 | 6.998 | 0 | 0.06 | 0.057 | 0122Tra0000011400 | m | T110 | false | HI_UZV_HEA_STA_0,120_xxx | 0
Nebenträger | Wartung_FFB | 1 | Nebenträger | HEA 120 | 0.698 | Wartung_FFB | 49.06 | 38.95 | 6.998 | 52.04 | 38.95 | 6.998 | 0 | 0.06 | 0.057 | 0122Tra0000011406 | m | T110 | false | HI_UZV_HEA_STA_0,120_xxx | 0
Nebenträger | Wartung_FFB | 1 | Nebenträger | HEA 120 | 0.698 | Wartung_FFB | 52.06 | 38.95 | 6.998 | 55.04 | 38.95 | 6.998 | 0 | 0.06 | 0.057 | 0122Tra0000011408 | m | T110 | false | HI_UZV_HEA_STA_0,120_xxx | 0
Nebenträger | Wartung_FFB | 1 | Nebenträger | HEA 120 | 0.698 | Wartung_FFB | 55.06 | 38.95 | 6.998 | 58.04 | 38.95 | 6.998 | 0 | 0.06 | 0.057 | 0122Tra0000011410 | m | T110 | false | HI_UZV_HEA_STA_0,120_xxx | 0
Nebenträger | Wartung_FFB | 1 | Nebenträger | HEA 120 | 0.698 | Wartung_FFB | 58.06 | 38.95 | 6.998 | 61.04 | 38.95 | 6.998 | 0 | 0.06 | 0.057 | 0122Tra0000011412 | m | T110 | false | HI_UZV_HEA_STA_0,120_xxx | 0
Nebenträger | Wartung_FFB | 1 | Nebenträger | HEA 120 | 0.698 | Wartung_FFB | 61.06 | 38.95 | 6.998 | 64.04 | 38.95 | 6.998 | 0 | 0.06 | 0.057 | 0122Tra0000011414 | m | T110 | false | HI_UZV_HEA_STA_0,120_xxx | 0
Nebenträger | Wartung_FFB | 1 | Nebenträger | HEA 120 | 0.698 | Wartung_FFB | 10.56 | 38.95 | 6.998 | 13.04 | 38.95 | 6.998 | 0 | 0.06 | 0.057 | 0122Tra0000011416 | m | T110 | false | HI_UZV_HEA_STA_0,120_xxx | 0
Nebenträger | Wartung_FFB | 1 | Nebenträger | HEA 120 | 0.698 | Wartung_FFB | 64.06 | 37.45 | 6.998 | 67.04 | 37.45 | 6.998 | 0 | 0.06 | 0.057 | 0122Tra0000011418 | m | T110 | false | HI_UZV_HEA_STA_0,120_xxx | 0
Nebenträger | Wartung_FFB | 1 | Nebenträger | HEA 120 | 0.698 | Wartung_FFB | 13.06 | 37.45 | 6.998 | 16.04 | 37.45 | 6.998 | 0 | 0.06 | 0.057 | 0122Tra0000011456 | m | T110 | false | HI_UZV_HEA_STA_0,120_xxx | 0
Nebenträger | Wartung_FFB | 1 | Nebenträger | HEA 120 | 0.698 | Wartung_FFB | 16.06 | 37.45 | 6.998 | 19.04 | 37.45 | 6.998 | 0 | 0.06 | 0.057 | 0122Tra0000011458 | m | T110 | false | HI_UZV_HEA_STA_0,120_xxx | 0
Nebenträger | Wartung_FFB | 1 | Nebenträger | HEA 120 | 0.698 | Wartung_FFB | 19.06 | 37.45 | 6.998 | 22.04 | 37.45 | 6.998 | 0 | 0.06 | 0.057 | 0122Tra0000011460 | m | T110 | false | HI_UZV_HEA_STA_0,120_xxx | 0
Nebenträger | Wartung_FFB | 1 | Nebenträger | HEA 120 | 0.698 | Wartung_FFB | 34.06 | 37.45 | 6.998 | 37.04 | 37.45 | 6.998 | 0 | 0.06 | 0.057 | 0122Tra0000011470 | m | T110 | false | HI_UZV_HEA_STA_0,120_xxx | 0
Nebenträger | Wartung_FFB | 1 | Nebenträger | HEA 120 | 0.698 | Wartung_FFB | 37.06 | 37.45 | 6.998 | 40.04 | 37.45 | 6.998 | 0 | 0.06 | 0.057 | 0122Tra0000011472 | m | T110 | false | HI_UZV_HEA_STA_0,120_xxx | 0
Nebenträger | Wartung_FFB | 1 | Nebenträger | HEA 120 | 0.698 | Wartung_FFB | 40.06 | 37.45 | 6.998 | 43.04 | 37.45 | 6.998 | 0 | 0.06 | 0.057 | 0122Tra0000011474 | m | T110 | false | HI_UZV_HEA_STA_0,120_xxx | 0
Nebenträger | Wartung_FFB | 1 | Nebenträger | HEA 120 | 0.698 | Wartung_FFB | 49.06 | 37.45 | 6.998 | 52.04 | 37.45 | 6.998 | 0 | 0.06 | 0.057 | 0122Tra0000011480 | m | T110 | false | HI_UZV_HEA_STA_0,120_xxx | 0
Nebenträger | Wartung_FFB | 1 | Nebenträger | HEA 120 | 0.698 | Wartung_FFB | 52.06 | 37.45 | 6.998 | 55.04 | 37.45 | 6.998 | 0 | 0.06 | 0.057 | 0122Tra0000011482 | m | T110 | false | HI_UZV_HEA_STA_0,120_xxx | 0
Nebenträger | Wartung_FFB | 1 | Nebenträger | HEA 120 | 0.698 | Wartung_FFB | 55.06 | 37.45 | 6.998 | 58.04 | 37.45 | 6.998 | 0 | 0.06 | 0.057 | 0122Tra0000011484 | m | T110 | false | HI_UZV_HEA_STA_0,120_xxx | 0
Nebenträger | Wartung_FFB | 1 | Nebenträger | HEA 120 | 0.698 | Wartung_FFB | 58.06 | 37.45 | 6.998 | 61.04 | 37.45 | 6.998 | 0 | 0.06 | 0.057 | 0122Tra0000011486 | m | T110 | false | HI_UZV_HEA_STA_0,120_xxx | 0
Nebenträger | Wartung_FFB | 1 | Nebenträger | HEA 120 | 0.698 | Wartung_FFB | 61.06 | 37.45 | 6.998 | 64.04 | 37.45 | 6.998 | 0 | 0.06 | 0.057 | 0122Tra0000011488 | m | T110 | false | HI_UZV_HEA_STA_0,120_xxx | 0
Nebenträger | Wartung_FFB | 1 | Nebenträger | HEA 120 | 0.698 | Wartung_FFB | 10.56 | 37.45 | 6.998 | 13.04 | 37.45 | 6.998 | 0 | 0.06 | 0.057 | 0122Tra0000011490 | m | T110 | false | HI_UZV_HEA_STA_0,120_xxx | 0
Nebenträger | Wartung_FFB | 1 | Nebenträger | HEA 120 | 0.698 | Wartung_FFB | 64.06 | 35.95 | 6.998 | 67.04 | 35.95 | 6.998 | 0 | 0.06 | 0.057 | 0122Tra0000011566 | m | T110 | false | HI_UZV_HEA_STA_0,120_xxx | 0
Nebenträger | Wartung_FFB | 1 | Nebenträger | HEA 120 | 0.698 | Wartung_FFB | 13.06 | 35.95 | 6.998 | 16.04 | 35.95 | 6.998 | 0 | 0.06 | 0.057 | 0122Tra0000011604 | m | T110 | false | HI_UZV_HEA_STA_0,120_xxx | 0
Nebenträger | Wartung_FFB | 1 | Nebenträger | HEA 120 | 0.698 | Wartung_FFB | 16.06 | 35.95 | 6.998 | 19.04 | 35.95 | 6.998 | 0 | 0.06 | 0.057 | 0122Tra0000011606 | m | T110 | false | HI_UZV_HEA_STA_0,120_xxx | 0
Nebenträger | Wartung_FFB | 1 | Nebenträger | HEA 120 | 0.698 | Wartung_FFB | 19.06 | 35.95 | 6.998 | 22.04 | 35.95 | 6.998 | 0 | 0.06 | 0.057 | 0122Tra0000011608 | m | T110 | false | HI_UZV_HEA_STA_0,120_xxx | 0
Nebenträger | Wartung_FFB | 1 | Nebenträger | HEA 120 | 0.698 | Wartung_FFB | 34.06 | 35.95 | 6.998 | 37.04 | 35.95 | 6.998 | 0 | 0.06 | 0.057 | 0122Tra0000011618 | m | T110 | false | HI_UZV_HEA_STA_0,120_xxx | 0
Nebenträger | Wartung_FFB | 1 | Nebenträger | HEA 120 | 0.698 | Wartung_FFB | 37.06 | 35.95 | 6.998 | 40.04 | 35.95 | 6.998 | 0 | 0.06 | 0.057 | 0122Tra0000011620 | m | T110 | false | HI_UZV_HEA_STA_0,120_xxx | 0
Nebenträger | Wartung_FFB | 1 | Nebenträger | HEA 120 | 0.698 | Wartung_FFB | 40.06 | 35.95 | 6.998 | 43.04 | 35.95 | 6.998 | 0 | 0.06 | 0.057 | 0122Tra0000011622 | m | T110 | false | HI_UZV_HEA_STA_0,120_xxx | 0
Nebenträger | Wartung_FFB | 1 | Nebenträger | HEA 120 | 0.698 | Wartung_FFB | 49.06 | 35.95 | 6.998 | 52.04 | 35.95 | 6.998 | 0 | 0.06 | 0.057 | 0122Tra0000011628 | m | T110 | false | HI_UZV_HEA_STA_0,120_xxx | 0
Nebenträger | Wartung_FFB | 1 | Nebenträger | HEA 120 | 0.698 | Wartung_FFB | 52.06 | 35.95 | 6.998 | 55.04 | 35.95 | 6.998 | 0 | 0.06 | 0.057 | 0122Tra0000011630 | m | T110 | false | HI_UZV_HEA_STA_0,120_xxx | 0
Nebenträger | Wartung_FFB | 1 | Nebenträger | HEA 120 | 0.698 | Wartung_FFB | 55.06 | 35.95 | 6.998 | 58.04 | 35.95 | 6.998 | 0 | 0.06 | 0.057 | 0122Tra0000011632 | m | T110 | false | HI_UZV_HEA_STA_0,120_xxx | 0
Nebenträger | Wartung_FFB | 1 | Nebenträger | HEA 120 | 0.698 | Wartung_FFB | 58.06 | 35.95 | 6.998 | 61.04 | 35.95 | 6.998 | 0 | 0.06 | 0.057 | 0122Tra0000011634 | m | T110 | false | HI_UZV_HEA_STA_0,120_xxx | 0
Nebenträger | Wartung_FFB | 1 | Nebenträger | HEA 120 | 0.698 | Wartung_FFB | 61.06 | 35.95 | 6.998 | 64.04 | 35.95 | 6.998 | 0 | 0.06 | 0.057 | 0122Tra0000011636 | m | T110 | false | HI_UZV_HEA_STA_0,120_xxx | 0
Nebenträger | Wartung_FFB | 1 | Nebenträger | HEA 120 | 0.698 | Wartung_FFB | 10.56 | 35.95 | 6.998 | 13.04 | 35.95 | 6.998 | 0 | 0.06 | 0.057 | 0122Tra0000011638 | m | T110 | false | HI_UZV_HEA_STA_0,120_xxx | 0
Nebenträger | Wartung_FFB | 1 | Nebenträger | HEA 120 | 0.698 | Wartung_FFB | 64.06 | 34.45 | 6.998 | 67.04 | 34.45 | 6.998 | 0 | 0.06 | 0.057 | 0122Tra0000011640 | m | T110 | false | HI_UZV_HEA_STA_0,120_xxx | 0
Nebenträger | Wartung_FFB | 1 | Nebenträger | HEA 120 | 0.698 | Wartung_FFB | 13.06 | 34.45 | 6.998 | 16.04 | 34.45 | 6.998 | 0 | 0.06 | 0.057 | 0122Tra0000011678 | m | T110 | false | HI_UZV_HEA_STA_0,120_xxx | 0
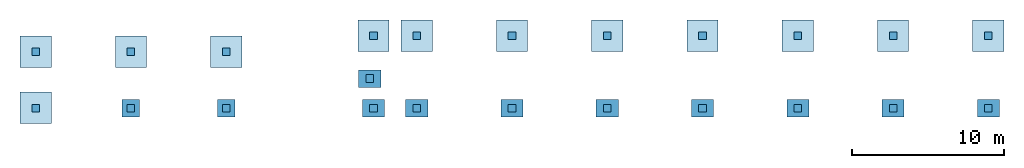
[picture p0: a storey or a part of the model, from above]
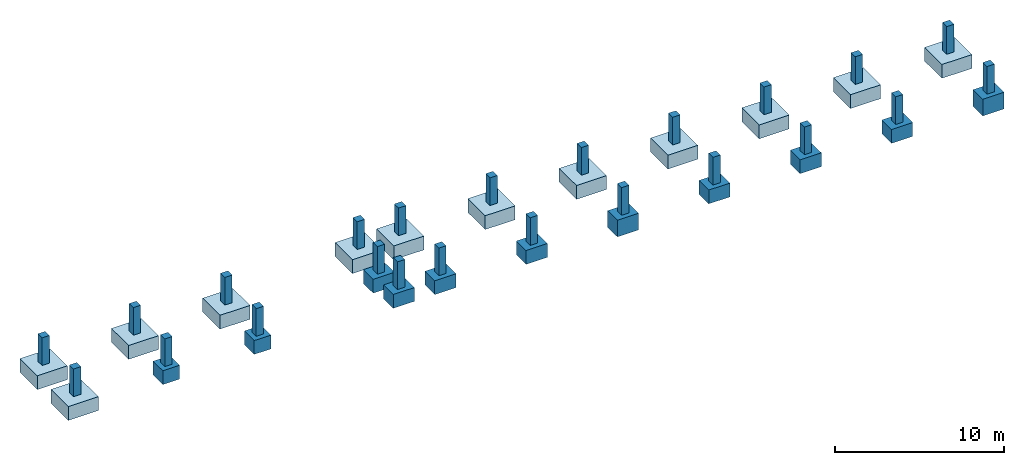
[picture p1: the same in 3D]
Properties of the parts of a building model (IFC2X3), part 5 of 25

# IfcBeam (2372)
Name | In | Faktor | Bezeichnung = Name | Profilname | Mantelfläche/lfm | Ebene | Achsenstartpunkt (X) (m) | Achsenstartpunkt (Y) (m) | Achsenstartpunkt (Z) (m) | Achsenendpunkt (X) (m) | Achsenendpunkt (Y) (m) | Achsenendpunkt (Z) (m) | Objektdrehwinkel | Schwerpunkt X (m) | Schwerpunkt Y (m) | Allright_Bauteil_ID | Abrechnungsart | Positionsnummer | Außenbauteil | Reference | Drehwinkel = Slope (deg)
Nebenträger | Wartung_FFB | 1 | Nebenträger | HEA 120 | 0.698 | Wartung_FFB | 16.06 | 34.45 | 6.998 | 19.04 | 34.45 | 6.998 | 0 | 0.06 | 0.057 | 0122Tra0000011680 | m | T110 | false | HI_UZV_HEA_STA_0,120_xxx | 0
Nebenträger | Wartung_FFB | 1 | Nebenträger | HEA 120 | 0.698 | Wartung_FFB | 19.06 | 34.45 | 6.998 | 22.04 | 34.45 | 6.998 | 0 | 0.06 | 0.057 | 0122Tra0000011682 | m | T110 | false | HI_UZV_HEA_STA_0,120_xxx | 0
Nebenträger | Wartung_FFB | 1 | Nebenträger | HEA 120 | 0.698 | Wartung_FFB | 34.06 | 34.45 | 6.998 | 37.04 | 34.45 | 6.998 | 0 | 0.06 | 0.057 | 0122Tra0000011692 | m | T110 | false | HI_UZV_HEA_STA_0,120_xxx | 0
Nebenträger | Wartung_FFB | 1 | Nebenträger | HEA 120 | 0.698 | Wartung_FFB | 37.06 | 34.45 | 6.998 | 40.04 | 34.45 | 6.998 | 0 | 0.06 | 0.057 | 0122Tra0000011694 | m | T110 | false | HI_UZV_HEA_STA_0,120_xxx | 0
Nebenträger | Wartung_FFB | 1 | Nebenträger | HEA 120 | 0.698 | Wartung_FFB | 40.06 | 34.45 | 6.998 | 43.04 | 34.45 | 6.998 | 0 | 0.06 | 0.057 | 0122Tra0000011696 | m | T110 | false | HI_UZV_HEA_STA_0,120_xxx | 0
Nebenträger | Wartung_FFB | 1 | Nebenträger | HEA 120 | 0.698 | Wartung_FFB | 49.06 | 34.45 | 6.998 | 52.04 | 34.45 | 6.998 | 0 | 0.06 | 0.057 | 0122Tra0000011702 | m | T110 | false | HI_UZV_HEA_STA_0,120_xxx | 0
Nebenträger | Wartung_FFB | 1 | Nebenträger | HEA 120 | 0.698 | Wartung_FFB | 52.06 | 34.45 | 6.998 | 55.04 | 34.45 | 6.998 | 0 | 0.06 | 0.057 | 0122Tra0000011704 | m | T110 | false | HI_UZV_HEA_STA_0,120_xxx | 0
Nebenträger | Wartung_FFB | 1 | Nebenträger | HEA 120 | 0.698 | Wartung_FFB | 55.06 | 34.45 | 6.998 | 58.04 | 34.45 | 6.998 | 0 | 0.06 | 0.057 | 0122Tra0000011706 | m | T110 | false | HI_UZV_HEA_STA_0,120_xxx | 0
Nebenträger | Wartung_FFB | 1 | Nebenträger | HEA 120 | 0.698 | Wartung_FFB | 58.06 | 34.45 | 6.998 | 61.04 | 34.45 | 6.998 | 0 | 0.06 | 0.057 | 0122Tra0000011708 | m | T110 | false | HI_UZV_HEA_STA_0,120_xxx | 0
Nebenträger | Wartung_FFB | 1 | Nebenträger | HEA 120 | 0.698 | Wartung_FFB | 61.06 | 34.45 | 6.998 | 64.04 | 34.45 | 6.998 | 0 | 0.06 | 0.057 | 0122Tra0000011710 | m | T110 | false | HI_UZV_HEA_STA_0,120_xxx | 0
Nebenträger | Wartung_FFB | 1 | Nebenträger | HEA 120 | 0.698 | Wartung_FFB | 10.56 | 34.45 | 6.998 | 13.04 | 34.45 | 6.998 | 0 | 0.06 | 0.057 | 0122Tra0000011712 | m | T110 | false | HI_UZV_HEA_STA_0,120_xxx | 0
Nebenträger | Wartung_FFB | 1 | Nebenträger | HEA 120 | 0.698 | Wartung_FFB | 64.06 | 32.95 | 6.998 | 67.04 | 32.95 | 6.998 | 0 | 0.06 | 0.057 | 0122Tra0000011751 | m | T110 | false | HI_UZV_HEA_STA_0,120_xxx | 0
Nebenträger | Wartung_FFB | 1 | Nebenträger | HEA 120 | 0.698 | Wartung_FFB | 13.06 | 32.95 | 6.998 | 16.04 | 32.95 | 6.998 | 0 | 0.06 | 0.057 | 0122Tra0000011789 | m | T110 | false | HI_UZV_HEA_STA_0,120_xxx | 0
Nebenträger | Wartung_FFB | 1 | Nebenträger | HEA 120 | 0.698 | Wartung_FFB | 16.06 | 32.95 | 6.998 | 19.04 | 32.95 | 6.998 | 0 | 0.06 | 0.057 | 0122Tra0000011791 | m | T110 | false | HI_UZV_HEA_STA_0,120_xxx | 0
Nebenträger | Wartung_FFB | 1 | Nebenträger | HEA 120 | 0.698 | Wartung_FFB | 19.06 | 32.95 | 6.998 | 22.04 | 32.95 | 6.998 | 0 | 0.06 | 0.057 | 0122Tra0000011793 | m | T110 | false | HI_UZV_HEA_STA_0,120_xxx | 0
Nebenträger | Wartung_FFB | 1 | Nebenträger | HEA 120 | 0.698 | Wartung_FFB | 34.06 | 32.95 | 6.998 | 37.04 | 32.95 | 6.998 | 0 | 0.06 | 0.057 | 0122Tra0000011803 | m | T110 | false | HI_UZV_HEA_STA_0,120_xxx | 0
Nebenträger | Wartung_FFB | 1 | Nebenträger | HEA 120 | 0.698 | Wartung_FFB | 37.06 | 32.95 | 6.998 | 40.04 | 32.95 | 6.998 | 0 | 0.06 | 0.057 | 0122Tra0000011805 | m | T110 | false | HI_UZV_HEA_STA_0,120_xxx | 0
Nebenträger | Wartung_FFB | 1 | Nebenträger | HEA 120 | 0.698 | Wartung_FFB | 40.06 | 32.95 | 6.998 | 43.04 | 32.95 | 6.998 | 0 | 0.06 | 0.057 | 0122Tra0000011807 | m | T110 | false | HI_UZV_HEA_STA_0,120_xxx | 0
Nebenträger | Wartung_FFB | 1 | Nebenträger | HEA 120 | 0.698 | Wartung_FFB | 49.06 | 32.95 | 6.998 | 52.04 | 32.95 | 6.998 | 0 | 0.06 | 0.057 | 0122Tra0000011813 | m | T110 | false | HI_UZV_HEA_STA_0,120_xxx | 0
Nebenträger | Wartung_FFB | 1 | Nebenträger | HEA 120 | 0.698 | Wartung_FFB | 52.06 | 32.95 | 6.998 | 55.04 | 32.95 | 6.998 | 0 | 0.06 | 0.057 | 0122Tra0000011815 | m | T110 | false | HI_UZV_HEA_STA_0,120_xxx | 0
Nebenträger | Wartung_FFB | 1 | Nebenträger | HEA 120 | 0.698 | Wartung_FFB | 55.06 | 32.95 | 6.998 | 58.04 | 32.95 | 6.998 | 0 | 0.06 | 0.057 | 0122Tra0000011817 | m | T110 | false | HI_UZV_HEA_STA_0,120_xxx | 0
Nebenträger | Wartung_FFB | 1 | Nebenträger | HEA 120 | 0.698 | Wartung_FFB | 58.06 | 32.95 | 6.998 | 61.04 | 32.95 | 6.998 | 0 | 0.06 | 0.057 | 0122Tra0000011819 | m | T110 | false | HI_UZV_HEA_STA_0,120_xxx | 0
Nebenträger | Wartung_FFB | 1 | Nebenträger | HEA 120 | 0.698 | Wartung_FFB | 61.06 | 32.95 | 6.998 | 64.04 | 32.95 | 6.998 | 0 | 0.06 | 0.057 | 0122Tra0000011821 | m | T110 | false | HI_UZV_HEA_STA_0,120_xxx | 0
Nebenträger | Wartung_FFB | 1 | Nebenträger | HEA 120 | 0.698 | Wartung_FFB | 10.56 | 32.95 | 6.998 | 13.04 | 32.95 | 6.998 | 0 | 0.06 | 0.057 | 0122Tra0000011823 | m | T110 | false | HI_UZV_HEA_STA_0,120_xxx | 0
Nebenträger | Wartung_FFB | 1 | Nebenträger | HEA 120 | 0.698 | Wartung_FFB | 64.06 | 28.645 | 6.998 | 67.04 | 28.645 | 6.998 | 0 | 0.06 | 0.057 | 0122Tra0000012232 | m | T110 | false | HI_UZV_HEA_STA_0,120_xxx | 0
Nebenträger | Wartung_FFB | 1 | Nebenträger | HEA 120 | 0.698 | Wartung_FFB | 67.06 | 28.645 | 6.998 | 70.04 | 28.645 | 6.998 | 0 | 0.06 | 0.057 | 0122Tra0000012234 | m | T110 | false | HI_UZV_HEA_STA_0,120_xxx | 0
Nebenträger | Wartung_FFB | 1 | Nebenträger | HEA 120 | 0.698 | Wartung_FFB | 70.06 | 28.645 | 6.998 | 73.04 | 28.645 | 6.998 | 0 | 0.06 | 0.057 | 0122Tra0000012236 | m | T110 | false | HI_UZV_HEA_STA_0,120_xxx | 0
Nebenträger | Wartung_FFB | 1 | Nebenträger | HEA 120 | 0.698 | Wartung_FFB | 73.06 | 28.645 | 6.998 | 76.04 | 28.645 | 6.998 | 0 | 0.06 | 0.057 | 0122Tra0000012238 | m | T110 | false | HI_UZV_HEA_STA_0,120_xxx | 0
Nebenträger | Wartung_FFB | 1 | Nebenträger | HEA 120 | 0.698 | Wartung_FFB | 76.06 | 28.645 | 6.998 | 79.04 | 28.645 | 6.998 | 0 | 0.06 | 0.057 | 0122Tra0000012240 | m | T110 | false | HI_UZV_HEA_STA_0,120_xxx | 0
Nebenträger | Wartung_FFB | 1 | Nebenträger | HEA 120 | 0.698 | Wartung_FFB | 85.06 | 28.645 | 6.998 | 88.04 | 28.645 | 6.998 | 0 | 0.06 | 0.057 | 0122Tra0000012246 | m | T110 | false | HI_UZV_HEA_STA_0,120_xxx | 0
Nebenträger | Wartung_FFB | 1 | Nebenträger | HEA 120 | 0.698 | Wartung_FFB | 88.06 | 28.645 | 6.998 | 91.04 | 28.645 | 6.998 | 0 | 0.06 | 0.057 | 0122Tra0000012248 | m | T110 | false | HI_UZV_HEA_STA_0,120_xxx | 0
Nebenträger | Wartung_FFB | 1 | Nebenträger | HEA 120 | 0.698 | Wartung_FFB | 97.06 | 28.645 | 6.998 | 100.04 | 28.645 | 6.998 | 0 | 0.06 | 0.057 | 0122Tra0000012254 | m | T110 | false | HI_UZV_HEA_STA_0,120_xxx | 0
Nebenträger | Wartung_FFB | 1 | Nebenträger | HEA 120 | 0.698 | Wartung_FFB | 100.06 | 28.645 | 6.998 | 103.04 | 28.645 | 6.998 | 0 | 0.06 | 0.057 | 0122Tra0000012256 | m | T110 | false | HI_UZV_HEA_STA_0,120_xxx | 0
Nebenträger | Wartung_FFB | 1 | Nebenträger | HEA 120 | 0.698 | Wartung_FFB | 103.06 | 28.645 | 6.998 | 106.04 | 28.645 | 6.998 | 0 | 0.06 | 0.057 | 0122Tra0000012258 | m | T110 | false | HI_UZV_HEA_STA_0,120_xxx | 0
Nebenträger | Wartung_FFB | 1 | Nebenträger | HEA 120 | 0.698 | Wartung_FFB | 106.06 | 28.645 | 6.998 | 109.04 | 28.645 | 6.998 | 0 | 0.06 | 0.057 | 0122Tra0000012260 | m | T110 | false | HI_UZV_HEA_STA_0,120_xxx | 0
Nebenträger | Wartung_FFB | 1 | Nebenträger | HEA 120 | 0.698 | Wartung_FFB | 109.06 | 28.645 | 6.998 | 112.04 | 28.645 | 6.998 | 0 | 0.06 | 0.057 | 0122Tra0000012262 | m | T110 | false | HI_UZV_HEA_STA_0,120_xxx | 0
Nebenträger | Wartung_FFB | 1 | Nebenträger | HEA 120 | 0.698 | Wartung_FFB | 112.06 | 28.645 | 6.998 | 115.04 | 28.645 | 6.998 | 0 | 0.06 | 0.057 | 0122Tra0000012264 | m | T110 | false | HI_UZV_HEA_STA_0,120_xxx | 0
Nebenträger | Wartung_FFB | 1 | Nebenträger | HEA 120 | 0.698 | Wartung_FFB | 115.06 | 28.645 | 6.998 | 118.04 | 28.645 | 6.998 | 0 | 0.06 | 0.057 | 0122Tra0000012266 | m | T110 | false | HI_UZV_HEA_STA_0,120_xxx | 0
Nebenträger | Wartung_FFB | 1 | Nebenträger | HEA 120 | 0.698 | Wartung_FFB | 118.06 | 28.645 | 6.998 | 121.04 | 28.645 | 6.998 | 0 | 0.06 | 0.057 | 0122Tra0000012268 | m | T110 | false | HI_UZV_HEA_STA_0,120_xxx | 0
Nebenträger | Wartung_FFB | 1 | Nebenträger | HEA 120 | 0.698 | Wartung_FFB | 13.06 | 28.645 | 6.998 | 16.04 | 28.645 | 6.998 | 0 | 0.06 | 0.057 | 0122Tra0000012270 | m | T110 | false | HI_UZV_HEA_STA_0,120_xxx | 0
Nebenträger | Wartung_FFB | 1 | Nebenträger | HEA 120 | 0.698 | Wartung_FFB | 16.06 | 28.645 | 6.998 | 19.04 | 28.645 | 6.998 | 0 | 0.06 | 0.057 | 0122Tra0000012272 | m | T110 | false | HI_UZV_HEA_STA_0,120_xxx | 0
Nebenträger | Wartung_FFB | 1 | Nebenträger | HEA 120 | 0.698 | Wartung_FFB | 19.06 | 28.645 | 6.998 | 22.04 | 28.645 | 6.998 | 0 | 0.06 | 0.057 | 0122Tra0000012274 | m | T110 | false | HI_UZV_HEA_STA_0,120_xxx | 0
Nebenträger | Wartung_FFB | 1 | Nebenträger | HEA 120 | 0.698 | Wartung_FFB | 34.06 | 28.645 | 6.998 | 37.04 | 28.645 | 6.998 | 0 | 0.06 | 0.057 | 0122Tra0000012284 | m | T110 | false | HI_UZV_HEA_STA_0,120_xxx | 0
Nebenträger | Wartung_FFB | 1 | Nebenträger | HEA 120 | 0.698 | Wartung_FFB | 37.06 | 28.645 | 6.998 | 40.04 | 28.645 | 6.998 | 0 | 0.06 | 0.057 | 0122Tra0000012286 | m | T110 | false | HI_UZV_HEA_STA_0,120_xxx | 0
Nebenträger | Wartung_FFB | 1 | Nebenträger | HEA 120 | 0.698 | Wartung_FFB | 40.06 | 28.645 | 6.998 | 43.04 | 28.645 | 6.998 | 0 | 0.06 | 0.057 | 0122Tra0000012288 | m | T110 | false | HI_UZV_HEA_STA_0,120_xxx | 0
Nebenträger | Wartung_FFB | 1 | Nebenträger | HEA 120 | 0.698 | Wartung_FFB | 43.06 | 28.645 | 6.998 | 46.04 | 28.645 | 6.998 | 0 | 0.06 | 0.057 | 0122Tra0000012290 | m | T110 | false | HI_UZV_HEA_STA_0,120_xxx | 0
Nebenträger | Wartung_FFB | 1 | Nebenträger | HEA 120 | 0.698 | Wartung_FFB | 46.06 | 28.645 | 6.998 | 49.04 | 28.645 | 6.998 | 0 | 0.06 | 0.057 | 0122Tra0000012292 | m | T110 | false | HI_UZV_HEA_STA_0,120_xxx | 0
Nebenträger | Wartung_FFB | 1 | Nebenträger | HEA 120 | 0.698 | Wartung_FFB | 49.06 | 28.645 | 6.998 | 52.04 | 28.645 | 6.998 | 0 | 0.06 | 0.057 | 0122Tra0000012294 | m | T110 | false | HI_UZV_HEA_STA_0,120_xxx | 0
Nebenträger | Wartung_FFB | 1 | Nebenträger | HEA 120 | 0.698 | Wartung_FFB | 52.06 | 28.645 | 6.998 | 55.04 | 28.645 | 6.998 | 0 | 0.06 | 0.057 | 0122Tra0000012296 | m | T110 | false | HI_UZV_HEA_STA_0,120_xxx | 0
Nebenträger | Wartung_FFB | 1 | Nebenträger | HEA 120 | 0.698 | Wartung_FFB | 55.06 | 28.645 | 6.998 | 58.04 | 28.645 | 6.998 | 0 | 0.06 | 0.057 | 0122Tra0000012298 | m | T110 | false | HI_UZV_HEA_STA_0,120_xxx | 0
Nebenträger | Wartung_FFB | 1 | Nebenträger | HEA 120 | 0.698 | Wartung_FFB | 58.06 | 28.645 | 6.998 | 61.04 | 28.645 | 6.998 | 0 | 0.06 | 0.057 | 0122Tra0000012300 | m | T110 | false | HI_UZV_HEA_STA_0,120_xxx | 0
Nebenträger | Wartung_FFB | 1 | Nebenträger | HEA 120 | 0.698 | Wartung_FFB | 61.06 | 28.645 | 6.998 | 64.04 | 28.645 | 6.998 | 0 | 0.06 | 0.057 | 0122Tra0000012302 | m | T110 | false | HI_UZV_HEA_STA_0,120_xxx | 0
Nebenträger | Wartung_FFB | 1 | Nebenträger | HEA 120 | 0.698 | Wartung_FFB | 10.56 | 28.645 | 6.998 | 13.04 | 28.645 | 6.998 | 0 | 0.06 | 0.057 | 0122Tra0000012304 | m | T110 | false | HI_UZV_HEA_STA_0,120_xxx | 0
Nebenträger | Wartung_FFB | 1 | Nebenträger | HEA 120 | 0.698 | Wartung_FFB | 64.06 | 27.145 | 6.998 | 67.04 | 27.145 | 6.998 | 0 | 0.06 | 0.057 | 0122Tra0000012306 | m | T110 | false | HI_UZV_HEA_STA_0,120_xxx | 0
Nebenträger | Wartung_FFB | 1 | Nebenträger | HEA 120 | 0.698 | Wartung_FFB | 67.06 | 27.145 | 6.998 | 70.04 | 27.145 | 6.998 | 0 | 0.06 | 0.057 | 0122Tra0000012308 | m | T110 | false | HI_UZV_HEA_STA_0,120_xxx | 0
Nebenträger | Wartung_FFB | 1 | Nebenträger | HEA 120 | 0.698 | Wartung_FFB | 70.06 | 27.145 | 6.998 | 73.04 | 27.145 | 6.998 | 0 | 0.06 | 0.057 | 0122Tra0000012310 | m | T110 | false | HI_UZV_HEA_STA_0,120_xxx | 0
Nebenträger | Wartung_FFB | 1 | Nebenträger | HEA 120 | 0.698 | Wartung_FFB | 73.06 | 27.145 | 6.998 | 76.04 | 27.145 | 6.998 | 0 | 0.06 | 0.057 | 0122Tra0000012312 | m | T110 | false | HI_UZV_HEA_STA_0,120_xxx | 0
Nebenträger | Wartung_FFB | 1 | Nebenträger | HEA 120 | 0.698 | Wartung_FFB | 76.06 | 27.145 | 6.998 | 79.04 | 27.145 | 6.998 | 0 | 0.06 | 0.057 | 0122Tra0000012314 | m | T110 | false | HI_UZV_HEA_STA_0,120_xxx | 0
Nebenträger | Wartung_FFB | 1 | Nebenträger | HEA 120 | 0.698 | Wartung_FFB | 85.06 | 27.145 | 6.998 | 88.04 | 27.145 | 6.998 | 0 | 0.06 | 0.057 | 0122Tra0000012320 | m | T110 | false | HI_UZV_HEA_STA_0,120_xxx | 0
Nebenträger | Wartung_FFB | 1 | Nebenträger | HEA 120 | 0.698 | Wartung_FFB | 88.06 | 27.145 | 6.998 | 91.04 | 27.145 | 6.998 | 0 | 0.06 | 0.057 | 0122Tra0000012322 | m | T110 | false | HI_UZV_HEA_STA_0,120_xxx | 0
Nebenträger | Wartung_FFB | 1 | Nebenträger | HEA 120 | 0.698 | Wartung_FFB | 97.06 | 27.145 | 6.998 | 100.04 | 27.145 | 6.998 | 0 | 0.06 | 0.057 | 0122Tra0000012328 | m | T110 | false | HI_UZV_HEA_STA_0,120_xxx | 0
Nebenträger | Wartung_FFB | 1 | Nebenträger | HEA 120 | 0.698 | Wartung_FFB | 100.06 | 27.145 | 6.998 | 103.04 | 27.145 | 6.998 | 0 | 0.06 | 0.057 | 0122Tra0000012330 | m | T110 | false | HI_UZV_HEA_STA_0,120_xxx | 0
Nebenträger | Wartung_FFB | 1 | Nebenträger | HEA 120 | 0.698 | Wartung_FFB | 103.06 | 27.145 | 6.998 | 106.04 | 27.145 | 6.998 | 0 | 0.06 | 0.057 | 0122Tra0000012332 | m | T110 | false | HI_UZV_HEA_STA_0,120_xxx | 0
Nebenträger | Wartung_FFB | 1 | Nebenträger | HEA 120 | 0.698 | Wartung_FFB | 106.06 | 27.145 | 6.998 | 109.04 | 27.145 | 6.998 | 0 | 0.06 | 0.057 | 0122Tra0000012334 | m | T110 | false | HI_UZV_HEA_STA_0,120_xxx | 0
Nebenträger | Wartung_FFB | 1 | Nebenträger | HEA 120 | 0.698 | Wartung_FFB | 109.06 | 27.145 | 6.998 | 112.04 | 27.145 | 6.998 | 0 | 0.06 | 0.057 | 0122Tra0000012336 | m | T110 | false | HI_UZV_HEA_STA_0,120_xxx | 0
Nebenträger | Wartung_FFB | 1 | Nebenträger | HEA 120 | 0.698 | Wartung_FFB | 112.06 | 27.145 | 6.998 | 115.04 | 27.145 | 6.998 | 0 | 0.06 | 0.057 | 0122Tra0000012338 | m | T110 | false | HI_UZV_HEA_STA_0,120_xxx | 0
Nebenträger | Wartung_FFB | 1 | Nebenträger | HEA 120 | 0.698 | Wartung_FFB | 115.06 | 27.145 | 6.998 | 118.04 | 27.145 | 6.998 | 0 | 0.06 | 0.057 | 0122Tra0000012340 | m | T110 | false | HI_UZV_HEA_STA_0,120_xxx | 0
Nebenträger | Wartung_FFB | 1 | Nebenträger | HEA 120 | 0.698 | Wartung_FFB | 118.06 | 27.145 | 6.998 | 121.04 | 27.145 | 6.998 | 0 | 0.06 | 0.057 | 0122Tra0000012342 | m | T110 | false | HI_UZV_HEA_STA_0,120_xxx | 0
Nebenträger | Wartung_FFB | 1 | Nebenträger | HEA 120 | 0.698 | Wartung_FFB | 13.06 | 27.145 | 6.998 | 16.04 | 27.145 | 6.998 | 0 | 0.06 | 0.057 | 0122Tra0000012344 | m | T110 | false | HI_UZV_HEA_STA_0,120_xxx | 0
Nebenträger | Wartung_FFB | 1 | Nebenträger | HEA 120 | 0.698 | Wartung_FFB | 16.06 | 27.145 | 6.998 | 19.04 | 27.145 | 6.998 | 0 | 0.06 | 0.057 | 0122Tra0000012346 | m | T110 | false | HI_UZV_HEA_STA_0,120_xxx | 0
Nebenträger | Wartung_FFB | 1 | Nebenträger | HEA 120 | 0.698 | Wartung_FFB | 19.06 | 27.145 | 6.998 | 22.04 | 27.145 | 6.998 | 0 | 0.06 | 0.057 | 0122Tra0000012348 | m | T110 | false | HI_UZV_HEA_STA_0,120_xxx | 0
Nebenträger | Wartung_FFB | 1 | Nebenträger | HEA 120 | 0.698 | Wartung_FFB | 34.06 | 27.145 | 6.998 | 37.04 | 27.145 | 6.998 | 0 | 0.06 | 0.057 | 0122Tra0000012358 | m | T110 | false | HI_UZV_HEA_STA_0,120_xxx | 0
Nebenträger | Wartung_FFB | 1 | Nebenträger | HEA 120 | 0.698 | Wartung_FFB | 37.06 | 27.145 | 6.998 | 40.04 | 27.145 | 6.998 | 0 | 0.06 | 0.057 | 0122Tra0000012360 | m | T110 | false | HI_UZV_HEA_STA_0,120_xxx | 0
Nebenträger | Wartung_FFB | 1 | Nebenträger | HEA 120 | 0.698 | Wartung_FFB | 40.06 | 27.145 | 6.998 | 43.04 | 27.145 | 6.998 | 0 | 0.06 | 0.057 | 0122Tra0000012362 | m | T110 | false | HI_UZV_HEA_STA_0,120_xxx | 0
Nebenträger | Wartung_FFB | 1 | Nebenträger | HEA 120 | 0.698 | Wartung_FFB | 43.06 | 27.145 | 6.998 | 46.04 | 27.145 | 6.998 | 0 | 0.06 | 0.057 | 0122Tra0000012364 | m | T110 | false | HI_UZV_HEA_STA_0,120_xxx | 0
Nebenträger | Wartung_FFB | 1 | Nebenträger | HEA 120 | 0.698 | Wartung_FFB | 46.06 | 27.145 | 6.998 | 49.04 | 27.145 | 6.998 | 0 | 0.06 | 0.057 | 0122Tra0000012366 | m | T110 | false | HI_UZV_HEA_STA_0,120_xxx | 0
Nebenträger | Wartung_FFB | 1 | Nebenträger | HEA 120 | 0.698 | Wartung_FFB | 49.06 | 27.145 | 6.998 | 52.04 | 27.145 | 6.998 | 0 | 0.06 | 0.057 | 0122Tra0000012368 | m | T110 | false | HI_UZV_HEA_STA_0,120_xxx | 0
Nebenträger | Wartung_FFB | 1 | Nebenträger | HEA 120 | 0.698 | Wartung_FFB | 52.06 | 27.145 | 6.998 | 55.04 | 27.145 | 6.998 | 0 | 0.06 | 0.057 | 0122Tra0000012370 | m | T110 | false | HI_UZV_HEA_STA_0,120_xxx | 0
Nebenträger | Wartung_FFB | 1 | Nebenträger | HEA 120 | 0.698 | Wartung_FFB | 55.06 | 27.145 | 6.998 | 58.04 | 27.145 | 6.998 | 0 | 0.06 | 0.057 | 0122Tra0000012372 | m | T110 | false | HI_UZV_HEA_STA_0,120_xxx | 0
Nebenträger | Wartung_FFB | 1 | Nebenträger | HEA 120 | 0.698 | Wartung_FFB | 58.06 | 27.145 | 6.998 | 61.04 | 27.145 | 6.998 | 0 | 0.06 | 0.057 | 0122Tra0000012374 | m | T110 | false | HI_UZV_HEA_STA_0,120_xxx | 0
Nebenträger | Wartung_FFB | 1 | Nebenträger | HEA 120 | 0.698 | Wartung_FFB | 61.06 | 27.145 | 6.998 | 64.04 | 27.145 | 6.998 | 0 | 0.06 | 0.057 | 0122Tra0000012376 | m | T110 | false | HI_UZV_HEA_STA_0,120_xxx | 0
Nebenträger | Wartung_FFB | 1 | Nebenträger | HEA 120 | 0.698 | Wartung_FFB | 10.56 | 27.145 | 6.998 | 13.04 | 27.145 | 6.998 | 0 | 0.06 | 0.057 | 0122Tra0000012378 | m | T110 | false | HI_UZV_HEA_STA_0,120_xxx | 0
Nebenträger | Wartung_FFB | 1 | Nebenträger | HEA 120 | 0.698 | Wartung_FFB | 64.06 | 25.645 | 6.998 | 67.04 | 25.645 | 6.998 | 0 | 0.06 | 0.057 | 0122Tra0000012380 | m | T110 | false | HI_UZV_HEA_STA_0,120_xxx | 0
Nebenträger | Wartung_FFB | 1 | Nebenträger | HEA 120 | 0.698 | Wartung_FFB | 67.06 | 25.645 | 6.998 | 70.04 | 25.645 | 6.998 | 0 | 0.06 | 0.057 | 0122Tra0000012382 | m | T110 | false | HI_UZV_HEA_STA_0,120_xxx | 0
Nebenträger | Wartung_FFB | 1 | Nebenträger | HEA 120 | 0.698 | Wartung_FFB | 70.06 | 25.645 | 6.998 | 73.04 | 25.645 | 6.998 | 0 | 0.06 | 0.057 | 0122Tra0000012384 | m | T110 | false | HI_UZV_HEA_STA_0,120_xxx | 0
Nebenträger | Wartung_FFB | 1 | Nebenträger | HEA 120 | 0.698 | Wartung_FFB | 73.06 | 25.645 | 6.998 | 76.04 | 25.645 | 6.998 | 0 | 0.06 | 0.057 | 0122Tra0000012386 | m | T110 | false | HI_UZV_HEA_STA_0,120_xxx | 0
Nebenträger | Wartung_FFB | 1 | Nebenträger | HEA 120 | 0.698 | Wartung_FFB | 76.06 | 25.645 | 6.998 | 79.04 | 25.645 | 6.998 | 0 | 0.06 | 0.057 | 0122Tra0000012388 | m | T110 | false | HI_UZV_HEA_STA_0,120_xxx | 0
Nebenträger | Wartung_FFB | 1 | Nebenträger | HEA 120 | 0.698 | Wartung_FFB | 85.06 | 25.645 | 6.998 | 88.04 | 25.645 | 6.998 | 0 | 0.06 | 0.057 | 0122Tra0000012394 | m | T110 | false | HI_UZV_HEA_STA_0,120_xxx | 0
Nebenträger | Wartung_FFB | 1 | Nebenträger | HEA 120 | 0.698 | Wartung_FFB | 88.06 | 25.645 | 6.998 | 91.04 | 25.645 | 6.998 | 0 | 0.06 | 0.057 | 0122Tra0000012396 | m | T110 | false | HI_UZV_HEA_STA_0,120_xxx | 0
Nebenträger | Wartung_FFB | 1 | Nebenträger | HEA 120 | 0.698 | Wartung_FFB | 97.06 | 25.645 | 6.998 | 100.04 | 25.645 | 6.998 | 0 | 0.06 | 0.057 | 0122Tra0000012402 | m | T110 | false | HI_UZV_HEA_STA_0,120_xxx | 0
Nebenträger | Wartung_FFB | 1 | Nebenträger | HEA 120 | 0.698 | Wartung_FFB | 100.06 | 25.645 | 6.998 | 103.04 | 25.645 | 6.998 | 0 | 0.06 | 0.057 | 0122Tra0000012404 | m | T110 | false | HI_UZV_HEA_STA_0,120_xxx | 0
Nebenträger | Wartung_FFB | 1 | Nebenträger | HEA 120 | 0.698 | Wartung_FFB | 103.06 | 25.645 | 6.998 | 106.04 | 25.645 | 6.998 | 0 | 0.06 | 0.057 | 0122Tra0000012406 | m | T110 | false | HI_UZV_HEA_STA_0,120_xxx | 0
Nebenträger | Wartung_FFB | 1 | Nebenträger | HEA 120 | 0.698 | Wartung_FFB | 106.06 | 25.645 | 6.998 | 109.04 | 25.645 | 6.998 | 0 | 0.06 | 0.057 | 0122Tra0000012408 | m | T110 | false | HI_UZV_HEA_STA_0,120_xxx | 0
Nebenträger | Wartung_FFB | 1 | Nebenträger | HEA 120 | 0.698 | Wartung_FFB | 109.06 | 25.645 | 6.998 | 112.04 | 25.645 | 6.998 | 0 | 0.06 | 0.057 | 0122Tra0000012410 | m | T110 | false | HI_UZV_HEA_STA_0,120_xxx | 0
Nebenträger | Wartung_FFB | 1 | Nebenträger | HEA 120 | 0.698 | Wartung_FFB | 112.06 | 25.645 | 6.998 | 115.04 | 25.645 | 6.998 | 0 | 0.06 | 0.057 | 0122Tra0000012412 | m | T110 | false | HI_UZV_HEA_STA_0,120_xxx | 0
Nebenträger | Wartung_FFB | 1 | Nebenträger | HEA 120 | 0.698 | Wartung_FFB | 115.06 | 25.645 | 6.998 | 118.04 | 25.645 | 6.998 | 0 | 0.06 | 0.057 | 0122Tra0000012414 | m | T110 | false | HI_UZV_HEA_STA_0,120_xxx | 0
Nebenträger | Wartung_FFB | 1 | Nebenträger | HEA 120 | 0.698 | Wartung_FFB | 118.06 | 25.645 | 6.998 | 121.04 | 25.645 | 6.998 | 0 | 0.06 | 0.057 | 0122Tra0000012416 | m | T110 | false | HI_UZV_HEA_STA_0,120_xxx | 0
Nebenträger | Wartung_FFB | 1 | Nebenträger | HEA 120 | 0.698 | Wartung_FFB | 13.06 | 25.645 | 6.998 | 16.04 | 25.645 | 6.998 | 0 | 0.06 | 0.057 | 0122Tra0000012418 | m | T110 | false | HI_UZV_HEA_STA_0,120_xxx | 0
Nebenträger | Wartung_FFB | 1 | Nebenträger | HEA 120 | 0.698 | Wartung_FFB | 16.06 | 25.645 | 6.998 | 19.04 | 25.645 | 6.998 | 0 | 0.06 | 0.057 | 0122Tra0000012420 | m | T110 | false | HI_UZV_HEA_STA_0,120_xxx | 0
Nebenträger | Wartung_FFB | 1 | Nebenträger | HEA 120 | 0.698 | Wartung_FFB | 19.06 | 25.645 | 6.998 | 22.04 | 25.645 | 6.998 | 0 | 0.06 | 0.057 | 0122Tra0000012422 | m | T110 | false | HI_UZV_HEA_STA_0,120_xxx | 0
Nebenträger | Wartung_FFB | 1 | Nebenträger | HEA 120 | 0.698 | Wartung_FFB | 34.06 | 25.645 | 6.998 | 37.04 | 25.645 | 6.998 | 0 | 0.06 | 0.057 | 0122Tra0000012432 | m | T110 | false | HI_UZV_HEA_STA_0,120_xxx | 0
Nebenträger | Wartung_FFB | 1 | Nebenträger | HEA 120 | 0.698 | Wartung_FFB | 37.06 | 25.645 | 6.998 | 40.04 | 25.645 | 6.998 | 0 | 0.06 | 0.057 | 0122Tra0000012434 | m | T110 | false | HI_UZV_HEA_STA_0,120_xxx | 0
Nebenträger | Wartung_FFB | 1 | Nebenträger | HEA 120 | 0.698 | Wartung_FFB | 40.06 | 25.645 | 6.998 | 43.04 | 25.645 | 6.998 | 0 | 0.06 | 0.057 | 0122Tra0000012436 | m | T110 | false | HI_UZV_HEA_STA_0,120_xxx | 0
Nebenträger | Wartung_FFB | 1 | Nebenträger | HEA 120 | 0.698 | Wartung_FFB | 43.06 | 25.645 | 6.998 | 46.04 | 25.645 | 6.998 | 0 | 0.06 | 0.057 | 0122Tra0000012438 | m | T110 | false | HI_UZV_HEA_STA_0,120_xxx | 0
Nebenträger | Wartung_FFB | 1 | Nebenträger | HEA 120 | 0.698 | Wartung_FFB | 46.06 | 25.645 | 6.998 | 49.04 | 25.645 | 6.998 | 0 | 0.06 | 0.057 | 0122Tra0000012440 | m | T110 | false | HI_UZV_HEA_STA_0,120_xxx | 0
Nebenträger | Wartung_FFB | 1 | Nebenträger | HEA 120 | 0.698 | Wartung_FFB | 49.06 | 25.645 | 6.998 | 52.04 | 25.645 | 6.998 | 0 | 0.06 | 0.057 | 0122Tra0000012442 | m | T110 | false | HI_UZV_HEA_STA_0,120_xxx | 0
Nebenträger | Wartung_FFB | 1 | Nebenträger | HEA 120 | 0.698 | Wartung_FFB | 52.06 | 25.645 | 6.998 | 55.04 | 25.645 | 6.998 | 0 | 0.06 | 0.057 | 0122Tra0000012444 | m | T110 | false | HI_UZV_HEA_STA_0,120_xxx | 0
Nebenträger | Wartung_FFB | 1 | Nebenträger | HEA 120 | 0.698 | Wartung_FFB | 55.06 | 25.645 | 6.998 | 58.04 | 25.645 | 6.998 | 0 | 0.06 | 0.057 | 0122Tra0000012446 | m | T110 | false | HI_UZV_HEA_STA_0,120_xxx | 0
Nebenträger | Wartung_FFB | 1 | Nebenträger | HEA 120 | 0.698 | Wartung_FFB | 58.06 | 25.645 | 6.998 | 61.04 | 25.645 | 6.998 | 0 | 0.06 | 0.057 | 0122Tra0000012448 | m | T110 | false | HI_UZV_HEA_STA_0,120_xxx | 0
Nebenträger | Wartung_FFB | 1 | Nebenträger | HEA 120 | 0.698 | Wartung_FFB | 61.06 | 25.645 | 6.998 | 64.04 | 25.645 | 6.998 | 0 | 0.06 | 0.057 | 0122Tra0000012450 | m | T110 | false | HI_UZV_HEA_STA_0,120_xxx | 0
Nebenträger | Wartung_FFB | 1 | Nebenträger | HEA 120 | 0.698 | Wartung_FFB | 10.56 | 25.645 | 6.998 | 13.04 | 25.645 | 6.998 | 0 | 0.06 | 0.057 | 0122Tra0000012452 | m | T110 | false | HI_UZV_HEA_STA_0,120_xxx | 0
Nebenträger | Wartung_FFB | 1 | Nebenträger | HEA 120 | 0.698 | Wartung_FFB | 64.06 | 24.145 | 6.998 | 67.04 | 24.145 | 6.998 | 0 | 0.06 | 0.057 | 0122Tra0000012454 | m | T110 | false | HI_UZV_HEA_STA_0,120_xxx | 0
Nebenträger | Wartung_FFB | 1 | Nebenträger | HEA 120 | 0.698 | Wartung_FFB | 67.06 | 24.145 | 6.998 | 70.04 | 24.145 | 6.998 | 0 | 0.06 | 0.057 | 0122Tra0000012456 | m | T110 | false | HI_UZV_HEA_STA_0,120_xxx | 0
Nebenträger | Wartung_FFB | 1 | Nebenträger | HEA 120 | 0.698 | Wartung_FFB | 70.06 | 24.145 | 6.998 | 73.04 | 24.145 | 6.998 | 0 | 0.06 | 0.057 | 0122Tra0000012458 | m | T110 | false | HI_UZV_HEA_STA_0,120_xxx | 0
Nebenträger | Wartung_FFB | 1 | Nebenträger | HEA 120 | 0.698 | Wartung_FFB | 73.06 | 24.145 | 6.998 | 76.04 | 24.145 | 6.998 | 0 | 0.06 | 0.057 | 0122Tra0000012460 | m | T110 | false | HI_UZV_HEA_STA_0,120_xxx | 0
Nebenträger | Wartung_FFB | 1 | Nebenträger | HEA 120 | 0.698 | Wartung_FFB | 76.06 | 24.145 | 6.998 | 79.04 | 24.145 | 6.998 | 0 | 0.06 | 0.057 | 0122Tra0000012462 | m | T110 | false | HI_UZV_HEA_STA_0,120_xxx | 0
Nebenträger | Wartung_FFB | 1 | Nebenträger | HEA 120 | 0.698 | Wartung_FFB | 85.06 | 24.145 | 6.998 | 88.04 | 24.145 | 6.998 | 0 | 0.06 | 0.057 | 0122Tra0000012468 | m | T110 | false | HI_UZV_HEA_STA_0,120_xxx | 0
Nebenträger | Wartung_FFB | 1 | Nebenträger | HEA 120 | 0.698 | Wartung_FFB | 88.06 | 24.145 | 6.998 | 91.04 | 24.145 | 6.998 | 0 | 0.06 | 0.057 | 0122Tra0000012470 | m | T110 | false | HI_UZV_HEA_STA_0,120_xxx | 0
Nebenträger | Wartung_FFB | 1 | Nebenträger | HEA 120 | 0.698 | Wartung_FFB | 97.06 | 24.145 | 6.998 | 100.04 | 24.145 | 6.998 | 0 | 0.06 | 0.057 | 0122Tra0000012476 | m | T110 | false | HI_UZV_HEA_STA_0,120_xxx | 0
Nebenträger | Wartung_FFB | 1 | Nebenträger | HEA 120 | 0.698 | Wartung_FFB | 100.06 | 24.145 | 6.998 | 103.04 | 24.145 | 6.998 | 0 | 0.06 | 0.057 | 0122Tra0000012478 | m | T110 | false | HI_UZV_HEA_STA_0,120_xxx | 0
Nebenträger | Wartung_FFB | 1 | Nebenträger | HEA 120 | 0.698 | Wartung_FFB | 103.06 | 24.145 | 6.998 | 106.04 | 24.145 | 6.998 | 0 | 0.06 | 0.057 | 0122Tra0000012480 | m | T110 | false | HI_UZV_HEA_STA_0,120_xxx | 0
Nebenträger | Wartung_FFB | 1 | Nebenträger | HEA 120 | 0.698 | Wartung_FFB | 106.06 | 24.145 | 6.998 | 109.04 | 24.145 | 6.998 | 0 | 0.06 | 0.057 | 0122Tra0000012482 | m | T110 | false | HI_UZV_HEA_STA_0,120_xxx | 0
Nebenträger | Wartung_FFB | 1 | Nebenträger | HEA 120 | 0.698 | Wartung_FFB | 109.06 | 24.145 | 6.998 | 112.04 | 24.145 | 6.998 | 0 | 0.06 | 0.057 | 0122Tra0000012484 | m | T110 | false | HI_UZV_HEA_STA_0,120_xxx | 0
Nebenträger | Wartung_FFB | 1 | Nebenträger | HEA 120 | 0.698 | Wartung_FFB | 112.06 | 24.145 | 6.998 | 115.04 | 24.145 | 6.998 | 0 | 0.06 | 0.057 | 0122Tra0000012486 | m | T110 | false | HI_UZV_HEA_STA_0,120_xxx | 0
Nebenträger | Wartung_FFB | 1 | Nebenträger | HEA 120 | 0.698 | Wartung_FFB | 115.06 | 24.145 | 6.998 | 118.04 | 24.145 | 6.998 | 0 | 0.06 | 0.057 | 0122Tra0000012488 | m | T110 | false | HI_UZV_HEA_STA_0,120_xxx | 0
Nebenträger | Wartung_FFB | 1 | Nebenträger | HEA 120 | 0.698 | Wartung_FFB | 118.06 | 24.145 | 6.998 | 121.04 | 24.145 | 6.998 | 0 | 0.06 | 0.057 | 0122Tra0000012490 | m | T110 | false | HI_UZV_HEA_STA_0,120_xxx | 0
Nebenträger | Wartung_FFB | 1 | Nebenträger | HEA 120 | 0.698 | Wartung_FFB | 13.06 | 24.145 | 6.998 | 16.04 | 24.145 | 6.998 | 0 | 0.06 | 0.057 | 0122Tra0000012492 | m | T110 | false | HI_UZV_HEA_STA_0,120_xxx | 0
Nebenträger | Wartung_FFB | 1 | Nebenträger | HEA 120 | 0.698 | Wartung_FFB | 16.06 | 24.145 | 6.998 | 19.04 | 24.145 | 6.998 | 0 | 0.06 | 0.057 | 0122Tra0000012494 | m | T110 | false | HI_UZV_HEA_STA_0,120_xxx | 0
Nebenträger | Wartung_FFB | 1 | Nebenträger | HEA 120 | 0.698 | Wartung_FFB | 19.06 | 24.145 | 6.998 | 22.04 | 24.145 | 6.998 | 0 | 0.06 | 0.057 | 0122Tra0000012496 | m | T110 | false | HI_UZV_HEA_STA_0,120_xxx | 0
Nebenträger | Wartung_FFB | 1 | Nebenträger | HEA 120 | 0.698 | Wartung_FFB | 34.06 | 24.145 | 6.998 | 37.04 | 24.145 | 6.998 | 0 | 0.06 | 0.057 | 0122Tra0000012506 | m | T110 | false | HI_UZV_HEA_STA_0,120_xxx | 0
Nebenträger | Wartung_FFB | 1 | Nebenträger | HEA 120 | 0.698 | Wartung_FFB | 37.06 | 24.145 | 6.998 | 40.04 | 24.145 | 6.998 | 0 | 0.06 | 0.057 | 0122Tra0000012508 | m | T110 | false | HI_UZV_HEA_STA_0,120_xxx | 0
Nebenträger | Wartung_FFB | 1 | Nebenträger | HEA 120 | 0.698 | Wartung_FFB | 40.06 | 24.145 | 6.998 | 43.04 | 24.145 | 6.998 | 0 | 0.06 | 0.057 | 0122Tra0000012510 | m | T110 | false | HI_UZV_HEA_STA_0,120_xxx | 0
Nebenträger | Wartung_FFB | 1 | Nebenträger | HEA 120 | 0.698 | Wartung_FFB | 43.06 | 24.145 | 6.998 | 46.04 | 24.145 | 6.998 | 0 | 0.06 | 0.057 | 0122Tra0000012512 | m | T110 | false | HI_UZV_HEA_STA_0,120_xxx | 0
Nebenträger | Wartung_FFB | 1 | Nebenträger | HEA 120 | 0.698 | Wartung_FFB | 46.06 | 24.145 | 6.998 | 49.04 | 24.145 | 6.998 | 0 | 0.06 | 0.057 | 0122Tra0000012514 | m | T110 | false | HI_UZV_HEA_STA_0,120_xxx | 0
Nebenträger | Wartung_FFB | 1 | Nebenträger | HEA 120 | 0.698 | Wartung_FFB | 49.06 | 24.145 | 6.998 | 52.04 | 24.145 | 6.998 | 0 | 0.06 | 0.057 | 0122Tra0000012516 | m | T110 | false | HI_UZV_HEA_STA_0,120_xxx | 0
Nebenträger | Wartung_FFB | 1 | Nebenträger | HEA 120 | 0.698 | Wartung_FFB | 52.06 | 24.145 | 6.998 | 55.04 | 24.145 | 6.998 | 0 | 0.06 | 0.057 | 0122Tra0000012518 | m | T110 | false | HI_UZV_HEA_STA_0,120_xxx | 0
Nebenträger | Wartung_FFB | 1 | Nebenträger | HEA 120 | 0.698 | Wartung_FFB | 55.06 | 24.145 | 6.998 | 58.04 | 24.145 | 6.998 | 0 | 0.06 | 0.057 | 0122Tra0000012520 | m | T110 | false | HI_UZV_HEA_STA_0,120_xxx | 0
Nebenträger | Wartung_FFB | 1 | Nebenträger | HEA 120 | 0.698 | Wartung_FFB | 58.06 | 24.145 | 6.998 | 61.04 | 24.145 | 6.998 | 0 | 0.06 | 0.057 | 0122Tra0000012522 | m | T110 | false | HI_UZV_HEA_STA_0,120_xxx | 0
Nebenträger | Wartung_FFB | 1 | Nebenträger | HEA 120 | 0.698 | Wartung_FFB | 61.06 | 24.145 | 6.998 | 64.04 | 24.145 | 6.998 | 0 | 0.06 | 0.057 | 0122Tra0000012524 | m | T110 | false | HI_UZV_HEA_STA_0,120_xxx | 0
Nebenträger | Wartung_FFB | 1 | Nebenträger | HEA 120 | 0.698 | Wartung_FFB | 10.56 | 24.145 | 6.998 | 13.04 | 24.145 | 6.998 | 0 | 0.06 | 0.057 | 0122Tra0000012526 | m | T110 | false | HI_UZV_HEA_STA_0,120_xxx | 0
Nebenträger | Wartung_FFB | 1 | Nebenträger | HEA 120 | 0.698 | Wartung_FFB | 64.06 | 22.645 | 6.998 | 67.04 | 22.645 | 6.998 | 0 | 0.06 | 0.057 | 0122Tra0000012528 | m | T110 | false | HI_UZV_HEA_STA_0,120_xxx | 0
Nebenträger | Wartung_FFB | 1 | Nebenträger | HEA 120 | 0.698 | Wartung_FFB | 67.06 | 22.645 | 6.998 | 70.04 | 22.645 | 6.998 | 0 | 0.06 | 0.057 | 0122Tra0000012530 | m | T110 | false | HI_UZV_HEA_STA_0,120_xxx | 0
Nebenträger | Wartung_FFB | 1 | Nebenträger | HEA 120 | 0.698 | Wartung_FFB | 70.06 | 22.645 | 6.998 | 73.04 | 22.645 | 6.998 | 0 | 0.06 | 0.057 | 0122Tra0000012532 | m | T110 | false | HI_UZV_HEA_STA_0,120_xxx | 0
Nebenträger | Wartung_FFB | 1 | Nebenträger | HEA 120 | 0.698 | Wartung_FFB | 73.06 | 22.645 | 6.998 | 76.04 | 22.645 | 6.998 | 0 | 0.06 | 0.057 | 0122Tra0000012534 | m | T110 | false | HI_UZV_HEA_STA_0,120_xxx | 0
Nebenträger | Wartung_FFB | 1 | Nebenträger | HEA 120 | 0.698 | Wartung_FFB | 76.06 | 22.645 | 6.998 | 79.04 | 22.645 | 6.998 | 0 | 0.06 | 0.057 | 0122Tra0000012536 | m | T110 | false | HI_UZV_HEA_STA_0,120_xxx | 0
Nebenträger | Wartung_FFB | 1 | Nebenträger | HEA 120 | 0.698 | Wartung_FFB | 85.06 | 22.645 | 6.998 | 88.04 | 22.645 | 6.998 | 0 | 0.06 | 0.057 | 0122Tra0000012542 | m | T110 | false | HI_UZV_HEA_STA_0,120_xxx | 0
Nebenträger | Wartung_FFB | 1 | Nebenträger | HEA 120 | 0.698 | Wartung_FFB | 88.06 | 22.645 | 6.998 | 91.04 | 22.645 | 6.998 | 0 | 0.06 | 0.057 | 0122Tra0000012544 | m | T110 | false | HI_UZV_HEA_STA_0,120_xxx | 0
Nebenträger | Wartung_FFB | 1 | Nebenträger | HEA 120 | 0.698 | Wartung_FFB | 97.06 | 22.645 | 6.998 | 100.04 | 22.645 | 6.998 | 0 | 0.06 | 0.057 | 0122Tra0000012550 | m | T110 | false | HI_UZV_HEA_STA_0,120_xxx | 0
Nebenträger | Wartung_FFB | 1 | Nebenträger | HEA 120 | 0.698 | Wartung_FFB | 100.06 | 22.645 | 6.998 | 103.04 | 22.645 | 6.998 | 0 | 0.06 | 0.057 | 0122Tra0000012552 | m | T110 | false | HI_UZV_HEA_STA_0,120_xxx | 0
Nebenträger | Wartung_FFB | 1 | Nebenträger | HEA 120 | 0.698 | Wartung_FFB | 103.06 | 22.645 | 6.998 | 106.04 | 22.645 | 6.998 | 0 | 0.06 | 0.057 | 0122Tra0000012554 | m | T110 | false | HI_UZV_HEA_STA_0,120_xxx | 0
Nebenträger | Wartung_FFB | 1 | Nebenträger | HEA 120 | 0.698 | Wartung_FFB | 106.06 | 22.645 | 6.998 | 109.04 | 22.645 | 6.998 | 0 | 0.06 | 0.057 | 0122Tra0000012556 | m | T110 | false | HI_UZV_HEA_STA_0,120_xxx | 0
Nebenträger | Wartung_FFB | 1 | Nebenträger | HEA 120 | 0.698 | Wartung_FFB | 109.06 | 22.645 | 6.998 | 112.04 | 22.645 | 6.998 | 0 | 0.06 | 0.057 | 0122Tra0000012558 | m | T110 | false | HI_UZV_HEA_STA_0,120_xxx | 0
Nebenträger | Wartung_FFB | 1 | Nebenträger | HEA 120 | 0.698 | Wartung_FFB | 112.06 | 22.645 | 6.998 | 115.04 | 22.645 | 6.998 | 0 | 0.06 | 0.057 | 0122Tra0000012560 | m | T110 | false | HI_UZV_HEA_STA_0,120_xxx | 0
Nebenträger | Wartung_FFB | 1 | Nebenträger | HEA 120 | 0.698 | Wartung_FFB | 115.06 | 22.645 | 6.998 | 118.04 | 22.645 | 6.998 | 0 | 0.06 | 0.057 | 0122Tra0000012562 | m | T110 | false | HI_UZV_HEA_STA_0,120_xxx | 0
Nebenträger | Wartung_FFB | 1 | Nebenträger | HEA 120 | 0.698 | Wartung_FFB | 118.06 | 22.645 | 6.998 | 121.04 | 22.645 | 6.998 | 0 | 0.06 | 0.057 | 0122Tra0000012564 | m | T110 | false | HI_UZV_HEA_STA_0,120_xxx | 0
Nebenträger | Wartung_FFB | 1 | Nebenträger | HEA 120 | 0.698 | Wartung_FFB | 13.06 | 22.645 | 6.998 | 16.04 | 22.645 | 6.998 | 0 | 0.06 | 0.057 | 0122Tra0000012566 | m | T110 | false | HI_UZV_HEA_STA_0,120_xxx | 0
Nebenträger | Wartung_FFB | 1 | Nebenträger | HEA 120 | 0.698 | Wartung_FFB | 16.06 | 22.645 | 6.998 | 19.04 | 22.645 | 6.998 | 0 | 0.06 | 0.057 | 0122Tra0000012568 | m | T110 | false | HI_UZV_HEA_STA_0,120_xxx | 0
Nebenträger | Wartung_FFB | 1 | Nebenträger | HEA 120 | 0.698 | Wartung_FFB | 19.06 | 22.645 | 6.998 | 22.04 | 22.645 | 6.998 | 0 | 0.06 | 0.057 | 0122Tra0000012570 | m | T110 | false | HI_UZV_HEA_STA_0,120_xxx | 0
Nebenträger | Wartung_FFB | 1 | Nebenträger | HEA 120 | 0.698 | Wartung_FFB | 34.06 | 22.645 | 6.998 | 37.04 | 22.645 | 6.998 | 0 | 0.06 | 0.057 | 0122Tra0000012580 | m | T110 | false | HI_UZV_HEA_STA_0,120_xxx | 0
Nebenträger | Wartung_FFB | 1 | Nebenträger | HEA 120 | 0.698 | Wartung_FFB | 37.06 | 22.645 | 6.998 | 40.04 | 22.645 | 6.998 | 0 | 0.06 | 0.057 | 0122Tra0000012582 | m | T110 | false | HI_UZV_HEA_STA_0,120_xxx | 0
Nebenträger | Wartung_FFB | 1 | Nebenträger | HEA 120 | 0.698 | Wartung_FFB | 40.06 | 22.645 | 6.998 | 43.04 | 22.645 | 6.998 | 0 | 0.06 | 0.057 | 0122Tra0000012584 | m | T110 | false | HI_UZV_HEA_STA_0,120_xxx | 0
Nebenträger | Wartung_FFB | 1 | Nebenträger | HEA 120 | 0.698 | Wartung_FFB | 43.06 | 22.645 | 6.998 | 46.04 | 22.645 | 6.998 | 0 | 0.06 | 0.057 | 0122Tra0000012586 | m | T110 | false | HI_UZV_HEA_STA_0,120_xxx | 0
Nebenträger | Wartung_FFB | 1 | Nebenträger | HEA 120 | 0.698 | Wartung_FFB | 46.06 | 22.645 | 6.998 | 49.04 | 22.645 | 6.998 | 0 | 0.06 | 0.057 | 0122Tra0000012588 | m | T110 | false | HI_UZV_HEA_STA_0,120_xxx | 0
Nebenträger | Wartung_FFB | 1 | Nebenträger | HEA 120 | 0.698 | Wartung_FFB | 49.06 | 22.645 | 6.998 | 52.04 | 22.645 | 6.998 | 0 | 0.06 | 0.057 | 0122Tra0000012590 | m | T110 | false | HI_UZV_HEA_STA_0,120_xxx | 0
Nebenträger | Wartung_FFB | 1 | Nebenträger | HEA 120 | 0.698 | Wartung_FFB | 52.06 | 22.645 | 6.998 | 55.04 | 22.645 | 6.998 | 0 | 0.06 | 0.057 | 0122Tra0000012592 | m | T110 | false | HI_UZV_HEA_STA_0,120_xxx | 0
Nebenträger | Wartung_FFB | 1 | Nebenträger | HEA 120 | 0.698 | Wartung_FFB | 55.06 | 22.645 | 6.998 | 58.04 | 22.645 | 6.998 | 0 | 0.06 | 0.057 | 0122Tra0000012594 | m | T110 | false | HI_UZV_HEA_STA_0,120_xxx | 0
Nebenträger | Wartung_FFB | 1 | Nebenträger | HEA 120 | 0.698 | Wartung_FFB | 58.06 | 22.645 | 6.998 | 61.04 | 22.645 | 6.998 | 0 | 0.06 | 0.057 | 0122Tra0000012596 | m | T110 | false | HI_UZV_HEA_STA_0,120_xxx | 0
Nebenträger | Wartung_FFB | 1 | Nebenträger | HEA 120 | 0.698 | Wartung_FFB | 61.06 | 22.645 | 6.998 | 64.04 | 22.645 | 6.998 | 0 | 0.06 | 0.057 | 0122Tra0000012598 | m | T110 | false | HI_UZV_HEA_STA_0,120_xxx | 0
Nebenträger | Wartung_FFB | 1 | Nebenträger | HEA 120 | 0.698 | Wartung_FFB | 10.56 | 22.645 | 6.998 | 13.04 | 22.645 | 6.998 | 0 | 0.06 | 0.057 | 0122Tra0000012600 | m | T110 | false | HI_UZV_HEA_STA_0,120_xxx | 0
Nebenträger | Wartung_FFB | 1 | Nebenträger | HEA 120 | 0.698 | Wartung_FFB | 64.06 | 21.145 | 6.998 | 67.04 | 21.145 | 6.998 | 0 | 0.06 | 0.057 | 0122Tra0000012602 | m | T110 | false | HI_UZV_HEA_STA_0,120_xxx | 0
Nebenträger | Wartung_FFB | 1 | Nebenträger | HEA 120 | 0.698 | Wartung_FFB | 67.06 | 21.145 | 6.998 | 70.04 | 21.145 | 6.998 | 0 | 0.06 | 0.057 | 0122Tra0000012604 | m | T110 | false | HI_UZV_HEA_STA_0,120_xxx | 0
Nebenträger | Wartung_FFB | 1 | Nebenträger | HEA 120 | 0.698 | Wartung_FFB | 70.06 | 21.145 | 6.998 | 73.04 | 21.145 | 6.998 | 0 | 0.06 | 0.057 | 0122Tra0000012606 | m | T110 | false | HI_UZV_HEA_STA_0,120_xxx | 0
Nebenträger | Wartung_FFB | 1 | Nebenträger | HEA 120 | 0.698 | Wartung_FFB | 73.06 | 21.145 | 6.998 | 76.04 | 21.145 | 6.998 | 0 | 0.06 | 0.057 | 0122Tra0000012608 | m | T110 | false | HI_UZV_HEA_STA_0,120_xxx | 0
Nebenträger | Wartung_FFB | 1 | Nebenträger | HEA 120 | 0.698 | Wartung_FFB | 76.06 | 21.145 | 6.998 | 79.04 | 21.145 | 6.998 | 0 | 0.06 | 0.057 | 0122Tra0000012610 | m | T110 | false | HI_UZV_HEA_STA_0,120_xxx | 0
Nebenträger | Wartung_FFB | 1 | Nebenträger | HEA 120 | 0.698 | Wartung_FFB | 85.06 | 21.145 | 6.998 | 88.04 | 21.145 | 6.998 | 0 | 0.06 | 0.057 | 0122Tra0000012616 | m | T110 | false | HI_UZV_HEA_STA_0,120_xxx | 0
Nebenträger | Wartung_FFB | 1 | Nebenträger | HEA 120 | 0.698 | Wartung_FFB | 88.06 | 21.145 | 6.998 | 91.04 | 21.145 | 6.998 | 0 | 0.06 | 0.057 | 0122Tra0000012618 | m | T110 | false | HI_UZV_HEA_STA_0,120_xxx | 0
Nebenträger | Wartung_FFB | 1 | Nebenträger | HEA 120 | 0.698 | Wartung_FFB | 97.06 | 21.145 | 6.998 | 100.04 | 21.145 | 6.998 | 0 | 0.06 | 0.057 | 0122Tra0000012624 | m | T110 | false | HI_UZV_HEA_STA_0,120_xxx | 0
Nebenträger | Wartung_FFB | 1 | Nebenträger | HEA 120 | 0.698 | Wartung_FFB | 100.06 | 21.145 | 6.998 | 103.04 | 21.145 | 6.998 | 0 | 0.06 | 0.057 | 0122Tra0000012626 | m | T110 | false | HI_UZV_HEA_STA_0,120_xxx | 0
Nebenträger | Wartung_FFB | 1 | Nebenträger | HEA 120 | 0.698 | Wartung_FFB | 103.06 | 21.145 | 6.998 | 106.04 | 21.145 | 6.998 | 0 | 0.06 | 0.057 | 0122Tra0000012628 | m | T110 | false | HI_UZV_HEA_STA_0,120_xxx | 0
Nebenträger | Wartung_FFB | 1 | Nebenträger | HEA 120 | 0.698 | Wartung_FFB | 106.06 | 21.145 | 6.998 | 109.04 | 21.145 | 6.998 | 0 | 0.06 | 0.057 | 0122Tra0000012630 | m | T110 | false | HI_UZV_HEA_STA_0,120_xxx | 0
Nebenträger | Wartung_FFB | 1 | Nebenträger | HEA 120 | 0.698 | Wartung_FFB | 109.06 | 21.145 | 6.998 | 112.04 | 21.145 | 6.998 | 0 | 0.06 | 0.057 | 0122Tra0000012632 | m | T110 | false | HI_UZV_HEA_STA_0,120_xxx | 0
Nebenträger | Wartung_FFB | 1 | Nebenträger | HEA 120 | 0.698 | Wartung_FFB | 112.06 | 21.145 | 6.998 | 115.04 | 21.145 | 6.998 | 0 | 0.06 | 0.057 | 0122Tra0000012634 | m | T110 | false | HI_UZV_HEA_STA_0,120_xxx | 0
Nebenträger | Wartung_FFB | 1 | Nebenträger | HEA 120 | 0.698 | Wartung_FFB | 115.06 | 21.145 | 6.998 | 118.04 | 21.145 | 6.998 | 0 | 0.06 | 0.057 | 0122Tra0000012636 | m | T110 | false | HI_UZV_HEA_STA_0,120_xxx | 0
Nebenträger | Wartung_FFB | 1 | Nebenträger | HEA 120 | 0.698 | Wartung_FFB | 118.06 | 21.145 | 6.998 | 121.04 | 21.145 | 6.998 | 0 | 0.06 | 0.057 | 0122Tra0000012638 | m | T110 | false | HI_UZV_HEA_STA_0,120_xxx | 0
Nebenträger | Wartung_FFB | 1 | Nebenträger | HEA 120 | 0.698 | Wartung_FFB | 13.06 | 21.145 | 6.998 | 16.04 | 21.145 | 6.998 | 0 | 0.06 | 0.057 | 0122Tra0000012640 | m | T110 | false | HI_UZV_HEA_STA_0,120_xxx | 0
Nebenträger | Wartung_FFB | 1 | Nebenträger | HEA 120 | 0.698 | Wartung_FFB | 16.06 | 21.145 | 6.998 | 19.04 | 21.145 | 6.998 | 0 | 0.06 | 0.057 | 0122Tra0000012642 | m | T110 | false | HI_UZV_HEA_STA_0,120_xxx | 0
Nebenträger | Wartung_FFB | 1 | Nebenträger | HEA 120 | 0.698 | Wartung_FFB | 19.06 | 21.145 | 6.998 | 22.04 | 21.145 | 6.998 | 0 | 0.06 | 0.057 | 0122Tra0000012644 | m | T110 | false | HI_UZV_HEA_STA_0,120_xxx | 0
Nebenträger | Wartung_FFB | 1 | Nebenträger | HEA 120 | 0.698 | Wartung_FFB | 34.06 | 21.145 | 6.998 | 37.04 | 21.145 | 6.998 | 0 | 0.06 | 0.057 | 0122Tra0000012654 | m | T110 | false | HI_UZV_HEA_STA_0,120_xxx | 0
Nebenträger | Wartung_FFB | 1 | Nebenträger | HEA 120 | 0.698 | Wartung_FFB | 37.06 | 21.145 | 6.998 | 40.04 | 21.145 | 6.998 | 0 | 0.06 | 0.057 | 0122Tra0000012656 | m | T110 | false | HI_UZV_HEA_STA_0,120_xxx | 0
Nebenträger | Wartung_FFB | 1 | Nebenträger | HEA 120 | 0.698 | Wartung_FFB | 40.06 | 21.145 | 6.998 | 43.04 | 21.145 | 6.998 | 0 | 0.06 | 0.057 | 0122Tra0000012658 | m | T110 | false | HI_UZV_HEA_STA_0,120_xxx | 0
Nebenträger | Wartung_FFB | 1 | Nebenträger | HEA 120 | 0.698 | Wartung_FFB | 43.06 | 21.145 | 6.998 | 46.04 | 21.145 | 6.998 | 0 | 0.06 | 0.057 | 0122Tra0000012660 | m | T110 | false | HI_UZV_HEA_STA_0,120_xxx | 0
Nebenträger | Wartung_FFB | 1 | Nebenträger | HEA 120 | 0.698 | Wartung_FFB | 46.06 | 21.145 | 6.998 | 49.04 | 21.145 | 6.998 | 0 | 0.06 | 0.057 | 0122Tra0000012662 | m | T110 | false | HI_UZV_HEA_STA_0,120_xxx | 0
Nebenträger | Wartung_FFB | 1 | Nebenträger | HEA 120 | 0.698 | Wartung_FFB | 49.06 | 21.145 | 6.998 | 52.04 | 21.145 | 6.998 | 0 | 0.06 | 0.057 | 0122Tra0000012664 | m | T110 | false | HI_UZV_HEA_STA_0,120_xxx | 0
Nebenträger | Wartung_FFB | 1 | Nebenträger | HEA 120 | 0.698 | Wartung_FFB | 52.06 | 21.145 | 6.998 | 55.04 | 21.145 | 6.998 | 0 | 0.06 | 0.057 | 0122Tra0000012666 | m | T110 | false | HI_UZV_HEA_STA_0,120_xxx | 0
Nebenträger | Wartung_FFB | 1 | Nebenträger | HEA 120 | 0.698 | Wartung_FFB | 55.06 | 21.145 | 6.998 | 58.04 | 21.145 | 6.998 | 0 | 0.06 | 0.057 | 0122Tra0000012668 | m | T110 | false | HI_UZV_HEA_STA_0,120_xxx | 0
Nebenträger | Wartung_FFB | 1 | Nebenträger | HEA 120 | 0.698 | Wartung_FFB | 58.06 | 21.145 | 6.998 | 61.04 | 21.145 | 6.998 | 0 | 0.06 | 0.057 | 0122Tra0000012670 | m | T110 | false | HI_UZV_HEA_STA_0,120_xxx | 0
Nebenträger | Wartung_FFB | 1 | Nebenträger | HEA 120 | 0.698 | Wartung_FFB | 61.06 | 21.145 | 6.998 | 64.04 | 21.145 | 6.998 | 0 | 0.06 | 0.057 | 0122Tra0000012672 | m | T110 | false | HI_UZV_HEA_STA_0,120_xxx | 0
Nebenträger | Wartung_FFB | 1 | Nebenträger | HEA 120 | 0.698 | Wartung_FFB | 10.56 | 21.145 | 6.998 | 13.04 | 21.145 | 6.998 | 0 | 0.06 | 0.057 | 0122Tra0000012674 | m | T110 | false | HI_UZV_HEA_STA_0,120_xxx | 0
Nebenträger | Wartung_FFB | 1 | Nebenträger | HEA 120 | 0.698 | Wartung_FFB | 64.06 | 19.645 | 6.998 | 67.04 | 19.645 | 6.998 | 0 | 0.06 | 0.057 | 0122Tra0000012676 | m | T110 | false | HI_UZV_HEA_STA_0,120_xxx | 0
Nebenträger | Wartung_FFB | 1 | Nebenträger | HEA 120 | 0.698 | Wartung_FFB | 67.06 | 19.645 | 6.998 | 70.04 | 19.645 | 6.998 | 0 | 0.06 | 0.057 | 0122Tra0000012678 | m | T110 | false | HI_UZV_HEA_STA_0,120_xxx | 0
Nebenträger | Wartung_FFB | 1 | Nebenträger | HEA 120 | 0.698 | Wartung_FFB | 70.06 | 19.645 | 6.998 | 73.04 | 19.645 | 6.998 | 0 | 0.06 | 0.057 | 0122Tra0000012680 | m | T110 | false | HI_UZV_HEA_STA_0,120_xxx | 0
Nebenträger | Wartung_FFB | 1 | Nebenträger | HEA 120 | 0.698 | Wartung_FFB | 73.06 | 19.645 | 6.998 | 76.04 | 19.645 | 6.998 | 0 | 0.06 | 0.057 | 0122Tra0000012682 | m | T110 | false | HI_UZV_HEA_STA_0,120_xxx | 0
Nebenträger | Wartung_FFB | 1 | Nebenträger | HEA 120 | 0.698 | Wartung_FFB | 76.06 | 19.645 | 6.998 | 79.04 | 19.645 | 6.998 | 0 | 0.06 | 0.057 | 0122Tra0000012684 | m | T110 | false | HI_UZV_HEA_STA_0,120_xxx | 0
Nebenträger | Wartung_FFB | 1 | Nebenträger | HEA 120 | 0.698 | Wartung_FFB | 85.06 | 19.645 | 6.998 | 88.04 | 19.645 | 6.998 | 0 | 0.06 | 0.057 | 0122Tra0000012690 | m | T110 | false | HI_UZV_HEA_STA_0,120_xxx | 0
Nebenträger | Wartung_FFB | 1 | Nebenträger | HEA 120 | 0.698 | Wartung_FFB | 88.06 | 19.645 | 6.998 | 91.04 | 19.645 | 6.998 | 0 | 0.06 | 0.057 | 0122Tra0000012692 | m | T110 | false | HI_UZV_HEA_STA_0,120_xxx | 0
Nebenträger | Wartung_FFB | 1 | Nebenträger | HEA 120 | 0.698 | Wartung_FFB | 97.06 | 19.645 | 6.998 | 100.04 | 19.645 | 6.998 | 0 | 0.06 | 0.057 | 0122Tra0000012698 | m | T110 | false | HI_UZV_HEA_STA_0,120_xxx | 0
Nebenträger | Wartung_FFB | 1 | Nebenträger | HEA 120 | 0.698 | Wartung_FFB | 100.06 | 19.645 | 6.998 | 103.04 | 19.645 | 6.998 | 0 | 0.06 | 0.057 | 0122Tra0000012700 | m | T110 | false | HI_UZV_HEA_STA_0,120_xxx | 0
Nebenträger | Wartung_FFB | 1 | Nebenträger | HEA 120 | 0.698 | Wartung_FFB | 103.06 | 19.645 | 6.998 | 106.04 | 19.645 | 6.998 | 0 | 0.06 | 0.057 | 0122Tra0000012702 | m | T110 | false | HI_UZV_HEA_STA_0,120_xxx | 0
Nebenträger | Wartung_FFB | 1 | Nebenträger | HEA 120 | 0.698 | Wartung_FFB | 106.06 | 19.645 | 6.998 | 109.04 | 19.645 | 6.998 | 0 | 0.06 | 0.057 | 0122Tra0000012704 | m | T110 | false | HI_UZV_HEA_STA_0,120_xxx | 0
Nebenträger | Wartung_FFB | 1 | Nebenträger | HEA 120 | 0.698 | Wartung_FFB | 109.06 | 19.645 | 6.998 | 112.04 | 19.645 | 6.998 | 0 | 0.06 | 0.057 | 0122Tra0000012706 | m | T110 | false | HI_UZV_HEA_STA_0,120_xxx | 0
Nebenträger | Wartung_FFB | 1 | Nebenträger | HEA 120 | 0.698 | Wartung_FFB | 112.06 | 19.645 | 6.998 | 115.04 | 19.645 | 6.998 | 0 | 0.06 | 0.057 | 0122Tra0000012708 | m | T110 | false | HI_UZV_HEA_STA_0,120_xxx | 0
Nebenträger | Wartung_FFB | 1 | Nebenträger | HEA 120 | 0.698 | Wartung_FFB | 115.06 | 19.645 | 6.998 | 118.04 | 19.645 | 6.998 | 0 | 0.06 | 0.057 | 0122Tra0000012710 | m | T110 | false | HI_UZV_HEA_STA_0,120_xxx | 0
Nebenträger | Wartung_FFB | 1 | Nebenträger | HEA 120 | 0.698 | Wartung_FFB | 118.06 | 19.645 | 6.998 | 121.04 | 19.645 | 6.998 | 0 | 0.06 | 0.057 | 0122Tra0000012712 | m | T110 | false | HI_UZV_HEA_STA_0,120_xxx | 0
Nebenträger | Wartung_FFB | 1 | Nebenträger | HEA 120 | 0.698 | Wartung_FFB | 13.06 | 19.645 | 6.998 | 16.04 | 19.645 | 6.998 | 0 | 0.06 | 0.057 | 0122Tra0000012714 | m | T110 | false | HI_UZV_HEA_STA_0,120_xxx | 0
Nebenträger | Wartung_FFB | 1 | Nebenträger | HEA 120 | 0.698 | Wartung_FFB | 16.06 | 19.645 | 6.998 | 19.04 | 19.645 | 6.998 | 0 | 0.06 | 0.057 | 0122Tra0000012716 | m | T110 | false | HI_UZV_HEA_STA_0,120_xxx | 0
Nebenträger | Wartung_FFB | 1 | Nebenträger | HEA 120 | 0.698 | Wartung_FFB | 19.06 | 19.645 | 6.998 | 22.04 | 19.645 | 6.998 | 0 | 0.06 | 0.057 | 0122Tra0000012718 | m | T110 | false | HI_UZV_HEA_STA_0,120_xxx | 0
Nebenträger | Wartung_FFB | 1 | Nebenträger | HEA 120 | 0.698 | Wartung_FFB | 34.06 | 19.645 | 6.998 | 37.04 | 19.645 | 6.998 | 0 | 0.06 | 0.057 | 0122Tra0000012728 | m | T110 | false | HI_UZV_HEA_STA_0,120_xxx | 0
Nebenträger | Wartung_FFB | 1 | Nebenträger | HEA 120 | 0.698 | Wartung_FFB | 37.06 | 19.645 | 6.998 | 40.04 | 19.645 | 6.998 | 0 | 0.06 | 0.057 | 0122Tra0000012730 | m | T110 | false | HI_UZV_HEA_STA_0,120_xxx | 0
Nebenträger | Wartung_FFB | 1 | Nebenträger | HEA 120 | 0.698 | Wartung_FFB | 40.06 | 19.645 | 6.998 | 43.04 | 19.645 | 6.998 | 0 | 0.06 | 0.057 | 0122Tra0000012732 | m | T110 | false | HI_UZV_HEA_STA_0,120_xxx | 0
Nebenträger | Wartung_FFB | 1 | Nebenträger | HEA 120 | 0.698 | Wartung_FFB | 43.06 | 19.645 | 6.998 | 46.04 | 19.645 | 6.998 | 0 | 0.06 | 0.057 | 0122Tra0000012734 | m | T110 | false | HI_UZV_HEA_STA_0,120_xxx | 0
Nebenträger | Wartung_FFB | 1 | Nebenträger | HEA 120 | 0.698 | Wartung_FFB | 46.06 | 19.645 | 6.998 | 49.04 | 19.645 | 6.998 | 0 | 0.06 | 0.057 | 0122Tra0000012736 | m | T110 | false | HI_UZV_HEA_STA_0,120_xxx | 0
Nebenträger | Wartung_FFB | 1 | Nebenträger | HEA 120 | 0.698 | Wartung_FFB | 49.06 | 19.645 | 6.998 | 52.04 | 19.645 | 6.998 | 0 | 0.06 | 0.057 | 0122Tra0000012738 | m | T110 | false | HI_UZV_HEA_STA_0,120_xxx | 0
Nebenträger | Wartung_FFB | 1 | Nebenträger | HEA 120 | 0.698 | Wartung_FFB | 52.06 | 19.645 | 6.998 | 55.04 | 19.645 | 6.998 | 0 | 0.06 | 0.057 | 0122Tra0000012740 | m | T110 | false | HI_UZV_HEA_STA_0,120_xxx | 0
Nebenträger | Wartung_FFB | 1 | Nebenträger | HEA 120 | 0.698 | Wartung_FFB | 55.06 | 19.645 | 6.998 | 58.04 | 19.645 | 6.998 | 0 | 0.06 | 0.057 | 0122Tra0000012742 | m | T110 | false | HI_UZV_HEA_STA_0,120_xxx | 0
Nebenträger | Wartung_FFB | 1 | Nebenträger | HEA 120 | 0.698 | Wartung_FFB | 58.06 | 19.645 | 6.998 | 61.04 | 19.645 | 6.998 | 0 | 0.06 | 0.057 | 0122Tra0000012744 | m | T110 | false | HI_UZV_HEA_STA_0,120_xxx | 0
Nebenträger | Wartung_FFB | 1 | Nebenträger | HEA 120 | 0.698 | Wartung_FFB | 61.06 | 19.645 | 6.998 | 64.04 | 19.645 | 6.998 | 0 | 0.06 | 0.057 | 0122Tra0000012746 | m | T110 | false | HI_UZV_HEA_STA_0,120_xxx | 0
Nebenträger | Wartung_FFB | 1 | Nebenträger | HEA 120 | 0.698 | Wartung_FFB | 10.56 | 19.645 | 6.998 | 13.04 | 19.645 | 6.998 | 0 | 0.06 | 0.057 | 0122Tra0000012748 | m | T110 | false | HI_UZV_HEA_STA_0,120_xxx | 0
Nebenträger | Wartung_FFB | 1 | Nebenträger | HEA 120 | 0.698 | Wartung_FFB | 64.06 | 18.145 | 6.998 | 67.04 | 18.145 | 6.998 | 0 | 0.06 | 0.057 | 0122Tra0000012750 | m | T110 | false | HI_UZV_HEA_STA_0,120_xxx | 0
Nebenträger | Wartung_FFB | 1 | Nebenträger | HEA 120 | 0.698 | Wartung_FFB | 67.06 | 18.145 | 6.998 | 70.04 | 18.145 | 6.998 | 0 | 0.06 | 0.057 | 0122Tra0000012752 | m | T110 | false | HI_UZV_HEA_STA_0,120_xxx | 0
Nebenträger | Wartung_FFB | 1 | Nebenträger | HEA 120 | 0.698 | Wartung_FFB | 70.06 | 18.145 | 6.998 | 73.04 | 18.145 | 6.998 | 0 | 0.06 | 0.057 | 0122Tra0000012754 | m | T110 | false | HI_UZV_HEA_STA_0,120_xxx | 0
Nebenträger | Wartung_FFB | 1 | Nebenträger | HEA 120 | 0.698 | Wartung_FFB | 73.06 | 18.145 | 6.998 | 76.04 | 18.145 | 6.998 | 0 | 0.06 | 0.057 | 0122Tra0000012756 | m | T110 | false | HI_UZV_HEA_STA_0,120_xxx | 0
Nebenträger | Wartung_FFB | 1 | Nebenträger | HEA 120 | 0.698 | Wartung_FFB | 76.06 | 18.145 | 6.998 | 79.04 | 18.145 | 6.998 | 0 | 0.06 | 0.057 | 0122Tra0000012758 | m | T110 | false | HI_UZV_HEA_STA_0,120_xxx | 0
Nebenträger | Wartung_FFB | 1 | Nebenträger | HEA 120 | 0.698 | Wartung_FFB | 85.06 | 18.145 | 6.998 | 88.04 | 18.145 | 6.998 | 0 | 0.06 | 0.057 | 0122Tra0000012764 | m | T110 | false | HI_UZV_HEA_STA_0,120_xxx | 0
Nebenträger | Wartung_FFB | 1 | Nebenträger | HEA 120 | 0.698 | Wartung_FFB | 88.06 | 18.145 | 6.998 | 91.04 | 18.145 | 6.998 | 0 | 0.06 | 0.057 | 0122Tra0000012766 | m | T110 | false | HI_UZV_HEA_STA_0,120_xxx | 0
Nebenträger | Wartung_FFB | 1 | Nebenträger | HEA 120 | 0.698 | Wartung_FFB | 97.06 | 18.145 | 6.998 | 100.04 | 18.145 | 6.998 | 0 | 0.06 | 0.057 | 0122Tra0000012772 | m | T110 | false | HI_UZV_HEA_STA_0,120_xxx | 0
Nebenträger | Wartung_FFB | 1 | Nebenträger | HEA 120 | 0.698 | Wartung_FFB | 100.06 | 18.145 | 6.998 | 103.04 | 18.145 | 6.998 | 0 | 0.06 | 0.057 | 0122Tra0000012774 | m | T110 | false | HI_UZV_HEA_STA_0,120_xxx | 0
Nebenträger | Wartung_FFB | 1 | Nebenträger | HEA 120 | 0.698 | Wartung_FFB | 103.06 | 18.145 | 6.998 | 106.04 | 18.145 | 6.998 | 0 | 0.06 | 0.057 | 0122Tra0000012776 | m | T110 | false | HI_UZV_HEA_STA_0,120_xxx | 0
Nebenträger | Wartung_FFB | 1 | Nebenträger | HEA 120 | 0.698 | Wartung_FFB | 106.06 | 18.145 | 6.998 | 109.04 | 18.145 | 6.998 | 0 | 0.06 | 0.057 | 0122Tra0000012778 | m | T110 | false | HI_UZV_HEA_STA_0,120_xxx | 0
Nebenträger | Wartung_FFB | 1 | Nebenträger | HEA 120 | 0.698 | Wartung_FFB | 109.06 | 18.145 | 6.998 | 112.04 | 18.145 | 6.998 | 0 | 0.06 | 0.057 | 0122Tra0000012780 | m | T110 | false | HI_UZV_HEA_STA_0,120_xxx | 0
Nebenträger | Wartung_FFB | 1 | Nebenträger | HEA 120 | 0.698 | Wartung_FFB | 112.06 | 18.145 | 6.998 | 115.04 | 18.145 | 6.998 | 0 | 0.06 | 0.057 | 0122Tra0000012782 | m | T110 | false | HI_UZV_HEA_STA_0,120_xxx | 0
Nebenträger | Wartung_FFB | 1 | Nebenträger | HEA 120 | 0.698 | Wartung_FFB | 115.06 | 18.145 | 6.998 | 118.04 | 18.145 | 6.998 | 0 | 0.06 | 0.057 | 0122Tra0000012784 | m | T110 | false | HI_UZV_HEA_STA_0,120_xxx | 0
Nebenträger | Wartung_FFB | 1 | Nebenträger | HEA 120 | 0.698 | Wartung_FFB | 118.06 | 18.145 | 6.998 | 121.04 | 18.145 | 6.998 | 0 | 0.06 | 0.057 | 0122Tra0000012786 | m | T110 | false | HI_UZV_HEA_STA_0,120_xxx | 0
Nebenträger | Wartung_FFB | 1 | Nebenträger | HEA 120 | 0.698 | Wartung_FFB | 13.06 | 18.145 | 6.998 | 16.04 | 18.145 | 6.998 | 0 | 0.06 | 0.057 | 0122Tra0000012788 | m | T110 | false | HI_UZV_HEA_STA_0,120_xxx | 0
Nebenträger | Wartung_FFB | 1 | Nebenträger | HEA 120 | 0.698 | Wartung_FFB | 16.06 | 18.145 | 6.998 | 19.04 | 18.145 | 6.998 | 0 | 0.06 | 0.057 | 0122Tra0000012790 | m | T110 | false | HI_UZV_HEA_STA_0,120_xxx | 0
Nebenträger | Wartung_FFB | 1 | Nebenträger | HEA 120 | 0.698 | Wartung_FFB | 19.06 | 18.145 | 6.998 | 22.04 | 18.145 | 6.998 | 0 | 0.06 | 0.057 | 0122Tra0000012792 | m | T110 | false | HI_UZV_HEA_STA_0,120_xxx | 0
Nebenträger | Wartung_FFB | 1 | Nebenträger | HEA 120 | 0.698 | Wartung_FFB | 34.06 | 18.145 | 6.998 | 37.04 | 18.145 | 6.998 | 0 | 0.06 | 0.057 | 0122Tra0000012802 | m | T110 | false | HI_UZV_HEA_STA_0,120_xxx | 0
Nebenträger | Wartung_FFB | 1 | Nebenträger | HEA 120 | 0.698 | Wartung_FFB | 37.06 | 18.145 | 6.998 | 40.04 | 18.145 | 6.998 | 0 | 0.06 | 0.057 | 0122Tra0000012804 | m | T110 | false | HI_UZV_HEA_STA_0,120_xxx | 0
Nebenträger | Wartung_FFB | 1 | Nebenträger | HEA 120 | 0.698 | Wartung_FFB | 40.06 | 18.145 | 6.998 | 43.04 | 18.145 | 6.998 | 0 | 0.06 | 0.057 | 0122Tra0000012806 | m | T110 | false | HI_UZV_HEA_STA_0,120_xxx | 0
Nebenträger | Wartung_FFB | 1 | Nebenträger | HEA 120 | 0.698 | Wartung_FFB | 43.06 | 18.145 | 6.998 | 46.04 | 18.145 | 6.998 | 0 | 0.06 | 0.057 | 0122Tra0000012808 | m | T110 | false | HI_UZV_HEA_STA_0,120_xxx | 0
Nebenträger | Wartung_FFB | 1 | Nebenträger | HEA 120 | 0.698 | Wartung_FFB | 46.06 | 18.145 | 6.998 | 49.04 | 18.145 | 6.998 | 0 | 0.06 | 0.057 | 0122Tra0000012810 | m | T110 | false | HI_UZV_HEA_STA_0,120_xxx | 0
Nebenträger | Wartung_FFB | 1 | Nebenträger | HEA 120 | 0.698 | Wartung_FFB | 49.06 | 18.145 | 6.998 | 52.04 | 18.145 | 6.998 | 0 | 0.06 | 0.057 | 0122Tra0000012812 | m | T110 | false | HI_UZV_HEA_STA_0,120_xxx | 0
Nebenträger | Wartung_FFB | 1 | Nebenträger | HEA 120 | 0.698 | Wartung_FFB | 52.06 | 18.145 | 6.998 | 55.04 | 18.145 | 6.998 | 0 | 0.06 | 0.057 | 0122Tra0000012814 | m | T110 | false | HI_UZV_HEA_STA_0,120_xxx | 0
Nebenträger | Wartung_FFB | 1 | Nebenträger | HEA 120 | 0.698 | Wartung_FFB | 55.06 | 18.145 | 6.998 | 58.04 | 18.145 | 6.998 | 0 | 0.06 | 0.057 | 0122Tra0000012816 | m | T110 | false | HI_UZV_HEA_STA_0,120_xxx | 0
Nebenträger | Wartung_FFB | 1 | Nebenträger | HEA 120 | 0.698 | Wartung_FFB | 58.06 | 18.145 | 6.998 | 61.04 | 18.145 | 6.998 | 0 | 0.06 | 0.057 | 0122Tra0000012818 | m | T110 | false | HI_UZV_HEA_STA_0,120_xxx | 0
Nebenträger | Wartung_FFB | 1 | Nebenträger | HEA 120 | 0.698 | Wartung_FFB | 61.06 | 18.145 | 6.998 | 64.04 | 18.145 | 6.998 | 0 | 0.06 | 0.057 | 0122Tra0000012820 | m | T110 | false | HI_UZV_HEA_STA_0,120_xxx | 0
Nebenträger | Wartung_FFB | 1 | Nebenträger | HEA 120 | 0.698 | Wartung_FFB | 10.56 | 18.145 | 6.998 | 13.04 | 18.145 | 6.998 | 0 | 0.06 | 0.057 | 0122Tra0000012822 | m | T110 | false | HI_UZV_HEA_STA_0,120_xxx | 0
Nebenträger | Wartung_FFB | 1 | Nebenträger | HEA 120 | 0.698 | Wartung_FFB | 64.06 | 16.645 | 6.998 | 67.04 | 16.645 | 6.998 | 0 | 0.06 | 0.057 | 0122Tra0000012824 | m | T110 | false | HI_UZV_HEA_STA_0,120_xxx | 0
Nebenträger | Wartung_FFB | 1 | Nebenträger | HEA 120 | 0.698 | Wartung_FFB | 67.06 | 16.645 | 6.998 | 70.04 | 16.645 | 6.998 | 0 | 0.06 | 0.057 | 0122Tra0000012826 | m | T110 | false | HI_UZV_HEA_STA_0,120_xxx | 0
Nebenträger | Wartung_FFB | 1 | Nebenträger | HEA 120 | 0.698 | Wartung_FFB | 70.06 | 16.645 | 6.998 | 73.04 | 16.645 | 6.998 | 0 | 0.06 | 0.057 | 0122Tra0000012828 | m | T110 | false | HI_UZV_HEA_STA_0,120_xxx | 0
Nebenträger | Wartung_FFB | 1 | Nebenträger | HEA 120 | 0.698 | Wartung_FFB | 73.06 | 16.645 | 6.998 | 76.04 | 16.645 | 6.998 | 0 | 0.06 | 0.057 | 0122Tra0000012830 | m | T110 | false | HI_UZV_HEA_STA_0,120_xxx | 0
Nebenträger | Wartung_FFB | 1 | Nebenträger | HEA 120 | 0.698 | Wartung_FFB | 76.06 | 16.645 | 6.998 | 79.04 | 16.645 | 6.998 | 0 | 0.06 | 0.057 | 0122Tra0000012832 | m | T110 | false | HI_UZV_HEA_STA_0,120_xxx | 0
Nebenträger | Wartung_FFB | 1 | Nebenträger | HEA 120 | 0.698 | Wartung_FFB | 85.06 | 16.645 | 6.998 | 88.04 | 16.645 | 6.998 | 0 | 0.06 | 0.057 | 0122Tra0000012838 | m | T110 | false | HI_UZV_HEA_STA_0,120_xxx | 0
Nebenträger | Wartung_FFB | 1 | Nebenträger | HEA 120 | 0.698 | Wartung_FFB | 88.06 | 16.645 | 6.998 | 91.04 | 16.645 | 6.998 | 0 | 0.06 | 0.057 | 0122Tra0000012840 | m | T110 | false | HI_UZV_HEA_STA_0,120_xxx | 0
Nebenträger | Wartung_FFB | 1 | Nebenträger | HEA 120 | 0.698 | Wartung_FFB | 97.06 | 16.645 | 6.998 | 100.04 | 16.645 | 6.998 | 0 | 0.06 | 0.057 | 0122Tra0000012846 | m | T110 | false | HI_UZV_HEA_STA_0,120_xxx | 0
Nebenträger | Wartung_FFB | 1 | Nebenträger | HEA 120 | 0.698 | Wartung_FFB | 100.06 | 16.645 | 6.998 | 103.04 | 16.645 | 6.998 | 0 | 0.06 | 0.057 | 0122Tra0000012848 | m | T110 | false | HI_UZV_HEA_STA_0,120_xxx | 0
Nebenträger | Wartung_FFB | 1 | Nebenträger | HEA 120 | 0.698 | Wartung_FFB | 103.06 | 16.645 | 6.998 | 106.04 | 16.645 | 6.998 | 0 | 0.06 | 0.057 | 0122Tra0000012850 | m | T110 | false | HI_UZV_HEA_STA_0,120_xxx | 0
Nebenträger | Wartung_FFB | 1 | Nebenträger | HEA 120 | 0.698 | Wartung_FFB | 106.06 | 16.645 | 6.998 | 109.04 | 16.645 | 6.998 | 0 | 0.06 | 0.057 | 0122Tra0000012852 | m | T110 | false | HI_UZV_HEA_STA_0,120_xxx | 0
Nebenträger | Wartung_FFB | 1 | Nebenträger | HEA 120 | 0.698 | Wartung_FFB | 109.06 | 16.645 | 6.998 | 112.04 | 16.645 | 6.998 | 0 | 0.06 | 0.057 | 0122Tra0000012854 | m | T110 | false | HI_UZV_HEA_STA_0,120_xxx | 0
Nebenträger | Wartung_FFB | 1 | Nebenträger | HEA 120 | 0.698 | Wartung_FFB | 112.06 | 16.645 | 6.998 | 115.04 | 16.645 | 6.998 | 0 | 0.06 | 0.057 | 0122Tra0000012856 | m | T110 | false | HI_UZV_HEA_STA_0,120_xxx | 0
Nebenträger | Wartung_FFB | 1 | Nebenträger | HEA 120 | 0.698 | Wartung_FFB | 115.06 | 16.645 | 6.998 | 118.04 | 16.645 | 6.998 | 0 | 0.06 | 0.057 | 0122Tra0000012858 | m | T110 | false | HI_UZV_HEA_STA_0,120_xxx | 0
Nebenträger | Wartung_FFB | 1 | Nebenträger | HEA 120 | 0.698 | Wartung_FFB | 118.06 | 16.645 | 6.998 | 121.04 | 16.645 | 6.998 | 0 | 0.06 | 0.057 | 0122Tra0000012860 | m | T110 | false | HI_UZV_HEA_STA_0,120_xxx | 0
Nebenträger | Wartung_FFB | 1 | Nebenträger | HEA 120 | 0.698 | Wartung_FFB | 13.06 | 16.645 | 6.998 | 16.04 | 16.645 | 6.998 | 0 | 0.06 | 0.057 | 0122Tra0000012862 | m | T110 | false | HI_UZV_HEA_STA_0,120_xxx | 0
Nebenträger | Wartung_FFB | 1 | Nebenträger | HEA 120 | 0.698 | Wartung_FFB | 16.06 | 16.645 | 6.998 | 19.04 | 16.645 | 6.998 | 0 | 0.06 | 0.057 | 0122Tra0000012864 | m | T110 | false | HI_UZV_HEA_STA_0,120_xxx | 0
Nebenträger | Wartung_FFB | 1 | Nebenträger | HEA 120 | 0.698 | Wartung_FFB | 19.06 | 16.645 | 6.998 | 22.04 | 16.645 | 6.998 | 0 | 0.06 | 0.057 | 0122Tra0000012866 | m | T110 | false | HI_UZV_HEA_STA_0,120_xxx | 0
Nebenträger | Wartung_FFB | 1 | Nebenträger | HEA 120 | 0.698 | Wartung_FFB | 34.06 | 16.645 | 6.998 | 37.04 | 16.645 | 6.998 | 0 | 0.06 | 0.057 | 0122Tra0000012876 | m | T110 | false | HI_UZV_HEA_STA_0,120_xxx | 0
Nebenträger | Wartung_FFB | 1 | Nebenträger | HEA 120 | 0.698 | Wartung_FFB | 37.06 | 16.645 | 6.998 | 40.04 | 16.645 | 6.998 | 0 | 0.06 | 0.057 | 0122Tra0000012878 | m | T110 | false | HI_UZV_HEA_STA_0,120_xxx | 0
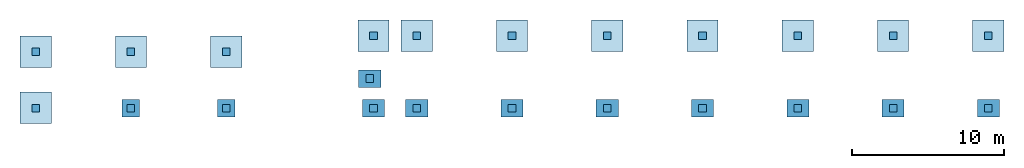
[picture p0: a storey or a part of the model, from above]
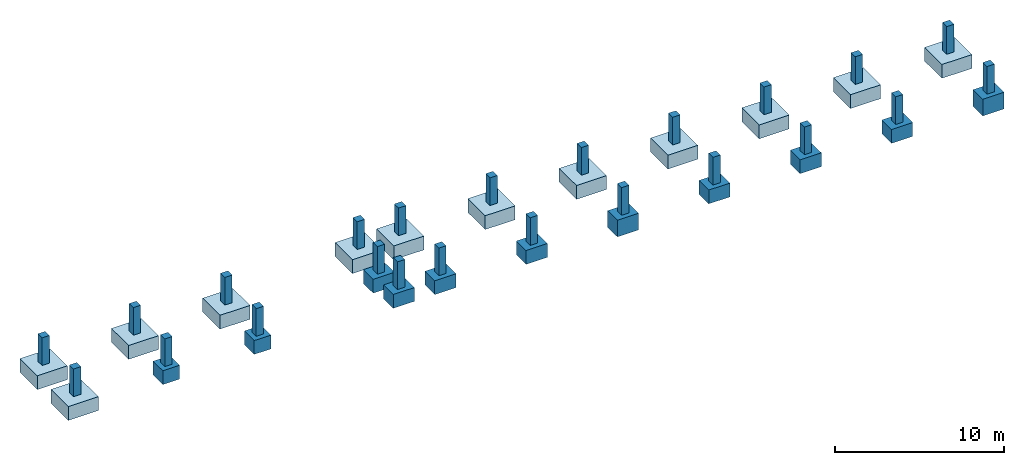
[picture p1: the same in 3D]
Properties of the parts of a building model (IFC2X3), part 6 of 25

# IfcBeam (2372)
Name | In | Faktor | Bezeichnung = Name | Profilname | Mantelfläche/lfm | Ebene | Achsenstartpunkt (X) (m) | Achsenstartpunkt (Y) (m) | Achsenstartpunkt (Z) (m) | Achsenendpunkt (X) (m) | Achsenendpunkt (Y) (m) | Achsenendpunkt (Z) (m) | Objektdrehwinkel | Schwerpunkt X (m) | Schwerpunkt Y (m) | Allright_Bauteil_ID | Abrechnungsart | Positionsnummer | Außenbauteil | Reference | Drehwinkel = Slope (deg)
Nebenträger | Wartung_FFB | 1 | Nebenträger | HEA 120 | 0.698 | Wartung_FFB | 40.06 | 16.645 | 6.998 | 43.04 | 16.645 | 6.998 | 0 | 0.06 | 0.057 | 0122Tra0000012880 | m | T110 | false | HI_UZV_HEA_STA_0,120_xxx | 0
Nebenträger | Wartung_FFB | 1 | Nebenträger | HEA 120 | 0.698 | Wartung_FFB | 43.06 | 16.645 | 6.998 | 46.04 | 16.645 | 6.998 | 0 | 0.06 | 0.057 | 0122Tra0000012882 | m | T110 | false | HI_UZV_HEA_STA_0,120_xxx | 0
Nebenträger | Wartung_FFB | 1 | Nebenträger | HEA 120 | 0.698 | Wartung_FFB | 46.06 | 16.645 | 6.998 | 49.04 | 16.645 | 6.998 | 0 | 0.06 | 0.057 | 0122Tra0000012884 | m | T110 | false | HI_UZV_HEA_STA_0,120_xxx | 0
Nebenträger | Wartung_FFB | 1 | Nebenträger | HEA 120 | 0.698 | Wartung_FFB | 49.06 | 16.645 | 6.998 | 52.04 | 16.645 | 6.998 | 0 | 0.06 | 0.057 | 0122Tra0000012886 | m | T110 | false | HI_UZV_HEA_STA_0,120_xxx | 0
Nebenträger | Wartung_FFB | 1 | Nebenträger | HEA 120 | 0.698 | Wartung_FFB | 52.06 | 16.645 | 6.998 | 55.04 | 16.645 | 6.998 | 0 | 0.06 | 0.057 | 0122Tra0000012888 | m | T110 | false | HI_UZV_HEA_STA_0,120_xxx | 0
Nebenträger | Wartung_FFB | 1 | Nebenträger | HEA 120 | 0.698 | Wartung_FFB | 55.06 | 16.645 | 6.998 | 58.04 | 16.645 | 6.998 | 0 | 0.06 | 0.057 | 0122Tra0000012890 | m | T110 | false | HI_UZV_HEA_STA_0,120_xxx | 0
Nebenträger | Wartung_FFB | 1 | Nebenträger | HEA 120 | 0.698 | Wartung_FFB | 58.06 | 16.645 | 6.998 | 61.04 | 16.645 | 6.998 | 0 | 0.06 | 0.057 | 0122Tra0000012892 | m | T110 | false | HI_UZV_HEA_STA_0,120_xxx | 0
Nebenträger | Wartung_FFB | 1 | Nebenträger | HEA 120 | 0.698 | Wartung_FFB | 61.06 | 16.645 | 6.998 | 64.04 | 16.645 | 6.998 | 0 | 0.06 | 0.057 | 0122Tra0000012894 | m | T110 | false | HI_UZV_HEA_STA_0,120_xxx | 0
Nebenträger | Wartung_FFB | 1 | Nebenträger | HEA 120 | 0.698 | Wartung_FFB | 10.56 | 16.645 | 6.998 | 13.04 | 16.645 | 6.998 | 0 | 0.06 | 0.057 | 0122Tra0000012896 | m | T110 | false | HI_UZV_HEA_STA_0,120_xxx | 0
Nebenträger | Wartung_FFB | 1 | Nebenträger | HEA 120 | 0.698 | Wartung_FFB | 64.06 | 15.145 | 6.998 | 67.04 | 15.145 | 6.998 | 0 | 0.06 | 0.057 | 0122Tra0000012898 | m | T110 | false | HI_UZV_HEA_STA_0,120_xxx | 0
Nebenträger | Wartung_FFB | 1 | Nebenträger | HEA 120 | 0.698 | Wartung_FFB | 67.06 | 15.145 | 6.998 | 70.04 | 15.145 | 6.998 | 0 | 0.06 | 0.057 | 0122Tra0000012900 | m | T110 | false | HI_UZV_HEA_STA_0,120_xxx | 0
Nebenträger | Wartung_FFB | 1 | Nebenträger | HEA 120 | 0.698 | Wartung_FFB | 70.06 | 15.145 | 6.998 | 73.04 | 15.145 | 6.998 | 0 | 0.06 | 0.057 | 0122Tra0000012902 | m | T110 | false | HI_UZV_HEA_STA_0,120_xxx | 0
Nebenträger | Wartung_FFB | 1 | Nebenträger | HEA 120 | 0.698 | Wartung_FFB | 73.06 | 15.145 | 6.998 | 76.04 | 15.145 | 6.998 | 0 | 0.06 | 0.057 | 0122Tra0000012904 | m | T110 | false | HI_UZV_HEA_STA_0,120_xxx | 0
Nebenträger | Wartung_FFB | 1 | Nebenträger | HEA 120 | 0.698 | Wartung_FFB | 76.06 | 15.145 | 6.998 | 79.04 | 15.145 | 6.998 | 0 | 0.06 | 0.057 | 0122Tra0000012906 | m | T110 | false | HI_UZV_HEA_STA_0,120_xxx | 0
Nebenträger | Wartung_FFB | 1 | Nebenträger | HEA 120 | 0.698 | Wartung_FFB | 85.06 | 15.145 | 6.998 | 88.04 | 15.145 | 6.998 | 0 | 0.06 | 0.057 | 0122Tra0000012912 | m | T110 | false | HI_UZV_HEA_STA_0,120_xxx | 0
Nebenträger | Wartung_FFB | 1 | Nebenträger | HEA 120 | 0.698 | Wartung_FFB | 88.06 | 15.145 | 6.998 | 91.04 | 15.145 | 6.998 | 0 | 0.06 | 0.057 | 0122Tra0000012914 | m | T110 | false | HI_UZV_HEA_STA_0,120_xxx | 0
Nebenträger | Wartung_FFB | 1 | Nebenträger | HEA 120 | 0.698 | Wartung_FFB | 97.06 | 15.145 | 6.998 | 100.04 | 15.145 | 6.998 | 0 | 0.06 | 0.057 | 0122Tra0000012920 | m | T110 | false | HI_UZV_HEA_STA_0,120_xxx | 0
Nebenträger | Wartung_FFB | 1 | Nebenträger | HEA 120 | 0.698 | Wartung_FFB | 100.06 | 15.145 | 6.998 | 103.04 | 15.145 | 6.998 | 0 | 0.06 | 0.057 | 0122Tra0000012922 | m | T110 | false | HI_UZV_HEA_STA_0,120_xxx | 0
Nebenträger | Wartung_FFB | 1 | Nebenträger | HEA 120 | 0.698 | Wartung_FFB | 103.06 | 15.145 | 6.998 | 106.04 | 15.145 | 6.998 | 0 | 0.06 | 0.057 | 0122Tra0000012924 | m | T110 | false | HI_UZV_HEA_STA_0,120_xxx | 0
Nebenträger | Wartung_FFB | 1 | Nebenträger | HEA 120 | 0.698 | Wartung_FFB | 106.06 | 15.145 | 6.998 | 109.04 | 15.145 | 6.998 | 0 | 0.06 | 0.057 | 0122Tra0000012926 | m | T110 | false | HI_UZV_HEA_STA_0,120_xxx | 0
Nebenträger | Wartung_FFB | 1 | Nebenträger | HEA 120 | 0.698 | Wartung_FFB | 109.06 | 15.145 | 6.998 | 112.04 | 15.145 | 6.998 | 0 | 0.06 | 0.057 | 0122Tra0000012928 | m | T110 | false | HI_UZV_HEA_STA_0,120_xxx | 0
Nebenträger | Wartung_FFB | 1 | Nebenträger | HEA 120 | 0.698 | Wartung_FFB | 112.06 | 15.145 | 6.998 | 115.04 | 15.145 | 6.998 | 0 | 0.06 | 0.057 | 0122Tra0000012930 | m | T110 | false | HI_UZV_HEA_STA_0,120_xxx | 0
Nebenträger | Wartung_FFB | 1 | Nebenträger | HEA 120 | 0.698 | Wartung_FFB | 115.06 | 15.145 | 6.998 | 118.04 | 15.145 | 6.998 | 0 | 0.06 | 0.057 | 0122Tra0000012932 | m | T110 | false | HI_UZV_HEA_STA_0,120_xxx | 0
Nebenträger | Wartung_FFB | 1 | Nebenträger | HEA 120 | 0.698 | Wartung_FFB | 118.06 | 15.145 | 6.998 | 121.04 | 15.145 | 6.998 | 0 | 0.06 | 0.057 | 0122Tra0000012934 | m | T110 | false | HI_UZV_HEA_STA_0,120_xxx | 0
Nebenträger | Wartung_FFB | 1 | Nebenträger | HEA 120 | 0.698 | Wartung_FFB | 13.06 | 15.145 | 6.998 | 16.04 | 15.145 | 6.998 | 0 | 0.06 | 0.057 | 0122Tra0000012936 | m | T110 | false | HI_UZV_HEA_STA_0,120_xxx | 0
Nebenträger | Wartung_FFB | 1 | Nebenträger | HEA 120 | 0.698 | Wartung_FFB | 16.06 | 15.145 | 6.998 | 19.04 | 15.145 | 6.998 | 0 | 0.06 | 0.057 | 0122Tra0000012938 | m | T110 | false | HI_UZV_HEA_STA_0,120_xxx | 0
Nebenträger | Wartung_FFB | 1 | Nebenträger | HEA 120 | 0.698 | Wartung_FFB | 19.06 | 15.145 | 6.998 | 22.04 | 15.145 | 6.998 | 0 | 0.06 | 0.057 | 0122Tra0000012940 | m | T110 | false | HI_UZV_HEA_STA_0,120_xxx | 0
Nebenträger | Wartung_FFB | 1 | Nebenträger | HEA 120 | 0.698 | Wartung_FFB | 34.06 | 15.145 | 6.998 | 37.04 | 15.145 | 6.998 | 0 | 0.06 | 0.057 | 0122Tra0000012950 | m | T110 | false | HI_UZV_HEA_STA_0,120_xxx | 0
Nebenträger | Wartung_FFB | 1 | Nebenträger | HEA 120 | 0.698 | Wartung_FFB | 37.06 | 15.145 | 6.998 | 40.04 | 15.145 | 6.998 | 0 | 0.06 | 0.057 | 0122Tra0000012952 | m | T110 | false | HI_UZV_HEA_STA_0,120_xxx | 0
Nebenträger | Wartung_FFB | 1 | Nebenträger | HEA 120 | 0.698 | Wartung_FFB | 40.06 | 15.145 | 6.998 | 43.04 | 15.145 | 6.998 | 0 | 0.06 | 0.057 | 0122Tra0000012954 | m | T110 | false | HI_UZV_HEA_STA_0,120_xxx | 0
Nebenträger | Wartung_FFB | 1 | Nebenträger | HEA 120 | 0.698 | Wartung_FFB | 43.06 | 15.145 | 6.998 | 46.04 | 15.145 | 6.998 | 0 | 0.06 | 0.057 | 0122Tra0000012956 | m | T110 | false | HI_UZV_HEA_STA_0,120_xxx | 0
Nebenträger | Wartung_FFB | 1 | Nebenträger | HEA 120 | 0.698 | Wartung_FFB | 46.06 | 15.145 | 6.998 | 49.04 | 15.145 | 6.998 | 0 | 0.06 | 0.057 | 0122Tra0000012958 | m | T110 | false | HI_UZV_HEA_STA_0,120_xxx | 0
Nebenträger | Wartung_FFB | 1 | Nebenträger | HEA 120 | 0.698 | Wartung_FFB | 49.06 | 15.145 | 6.998 | 52.04 | 15.145 | 6.998 | 0 | 0.06 | 0.057 | 0122Tra0000012960 | m | T110 | false | HI_UZV_HEA_STA_0,120_xxx | 0
Nebenträger | Wartung_FFB | 1 | Nebenträger | HEA 120 | 0.698 | Wartung_FFB | 52.06 | 15.145 | 6.998 | 55.04 | 15.145 | 6.998 | 0 | 0.06 | 0.057 | 0122Tra0000012962 | m | T110 | false | HI_UZV_HEA_STA_0,120_xxx | 0
Nebenträger | Wartung_FFB | 1 | Nebenträger | HEA 120 | 0.698 | Wartung_FFB | 55.06 | 15.145 | 6.998 | 58.04 | 15.145 | 6.998 | 0 | 0.06 | 0.057 | 0122Tra0000012964 | m | T110 | false | HI_UZV_HEA_STA_0,120_xxx | 0
Nebenträger | Wartung_FFB | 1 | Nebenträger | HEA 120 | 0.698 | Wartung_FFB | 58.06 | 15.145 | 6.998 | 61.04 | 15.145 | 6.998 | 0 | 0.06 | 0.057 | 0122Tra0000012966 | m | T110 | false | HI_UZV_HEA_STA_0,120_xxx | 0
Nebenträger | Wartung_FFB | 1 | Nebenträger | HEA 120 | 0.698 | Wartung_FFB | 61.06 | 15.145 | 6.998 | 64.04 | 15.145 | 6.998 | 0 | 0.06 | 0.057 | 0122Tra0000012968 | m | T110 | false | HI_UZV_HEA_STA_0,120_xxx | 0
Nebenträger | Wartung_FFB | 1 | Nebenträger | HEA 120 | 0.698 | Wartung_FFB | 10.56 | 15.145 | 6.998 | 13.04 | 15.145 | 6.998 | 0 | 0.06 | 0.057 | 0122Tra0000012970 | m | T110 | false | HI_UZV_HEA_STA_0,120_xxx | 0
Nebenträger | Wartung_FFB | 1 | Nebenträger | HEA 120 | 0.698 | Wartung_FFB | 64.06 | 13.645 | 6.998 | 67.04 | 13.645 | 6.998 | 0 | 0.06 | 0.057 | 0122Tra0000012972 | m | T110 | false | HI_UZV_HEA_STA_0,120_xxx | 0
Nebenträger | Wartung_FFB | 1 | Nebenträger | HEA 120 | 0.698 | Wartung_FFB | 67.06 | 13.645 | 6.998 | 70.04 | 13.645 | 6.998 | 0 | 0.06 | 0.057 | 0122Tra0000012974 | m | T110 | false | HI_UZV_HEA_STA_0,120_xxx | 0
Nebenträger | Wartung_FFB | 1 | Nebenträger | HEA 120 | 0.698 | Wartung_FFB | 70.06 | 13.645 | 6.998 | 73.04 | 13.645 | 6.998 | 0 | 0.06 | 0.057 | 0122Tra0000012976 | m | T110 | false | HI_UZV_HEA_STA_0,120_xxx | 0
Nebenträger | Wartung_FFB | 1 | Nebenträger | HEA 120 | 0.698 | Wartung_FFB | 73.06 | 13.645 | 6.998 | 76.04 | 13.645 | 6.998 | 0 | 0.06 | 0.057 | 0122Tra0000012978 | m | T110 | false | HI_UZV_HEA_STA_0,120_xxx | 0
Nebenträger | Wartung_FFB | 1 | Nebenträger | HEA 120 | 0.698 | Wartung_FFB | 76.06 | 13.645 | 6.998 | 79.04 | 13.645 | 6.998 | 0 | 0.06 | 0.057 | 0122Tra0000012980 | m | T110 | false | HI_UZV_HEA_STA_0,120_xxx | 0
Nebenträger | Wartung_FFB | 1 | Nebenträger | HEA 120 | 0.698 | Wartung_FFB | 85.06 | 13.645 | 6.998 | 88.04 | 13.645 | 6.998 | 0 | 0.06 | 0.057 | 0122Tra0000012986 | m | T110 | false | HI_UZV_HEA_STA_0,120_xxx | 0
Nebenträger | Wartung_FFB | 1 | Nebenträger | HEA 120 | 0.698 | Wartung_FFB | 88.06 | 13.645 | 6.998 | 91.04 | 13.645 | 6.998 | 0 | 0.06 | 0.057 | 0122Tra0000012988 | m | T110 | false | HI_UZV_HEA_STA_0,120_xxx | 0
Nebenträger | Wartung_FFB | 1 | Nebenträger | HEA 120 | 0.698 | Wartung_FFB | 97.06 | 13.645 | 6.998 | 100.04 | 13.645 | 6.998 | 0 | 0.06 | 0.057 | 0122Tra0000012994 | m | T110 | false | HI_UZV_HEA_STA_0,120_xxx | 0
Nebenträger | Wartung_FFB | 1 | Nebenträger | HEA 120 | 0.698 | Wartung_FFB | 100.06 | 13.645 | 6.998 | 103.04 | 13.645 | 6.998 | 0 | 0.06 | 0.057 | 0122Tra0000012996 | m | T110 | false | HI_UZV_HEA_STA_0,120_xxx | 0
Nebenträger | Wartung_FFB | 1 | Nebenträger | HEA 120 | 0.698 | Wartung_FFB | 103.06 | 13.645 | 6.998 | 106.04 | 13.645 | 6.998 | 0 | 0.06 | 0.057 | 0122Tra0000012998 | m | T110 | false | HI_UZV_HEA_STA_0,120_xxx | 0
Nebenträger | Wartung_FFB | 1 | Nebenträger | HEA 120 | 0.698 | Wartung_FFB | 106.06 | 13.645 | 6.998 | 109.04 | 13.645 | 6.998 | 0 | 0.06 | 0.057 | 0122Tra0000013000 | m | T110 | false | HI_UZV_HEA_STA_0,120_xxx | 0
Nebenträger | Wartung_FFB | 1 | Nebenträger | HEA 120 | 0.698 | Wartung_FFB | 109.06 | 13.645 | 6.998 | 112.04 | 13.645 | 6.998 | 0 | 0.06 | 0.057 | 0122Tra0000013002 | m | T110 | false | HI_UZV_HEA_STA_0,120_xxx | 0
Nebenträger | Wartung_FFB | 1 | Nebenträger | HEA 120 | 0.698 | Wartung_FFB | 112.06 | 13.645 | 6.998 | 115.04 | 13.645 | 6.998 | 0 | 0.06 | 0.057 | 0122Tra0000013004 | m | T110 | false | HI_UZV_HEA_STA_0,120_xxx | 0
Nebenträger | Wartung_FFB | 1 | Nebenträger | HEA 120 | 0.698 | Wartung_FFB | 115.06 | 13.645 | 6.998 | 118.04 | 13.645 | 6.998 | 0 | 0.06 | 0.057 | 0122Tra0000013006 | m | T110 | false | HI_UZV_HEA_STA_0,120_xxx | 0
Nebenträger | Wartung_FFB | 1 | Nebenträger | HEA 120 | 0.698 | Wartung_FFB | 118.06 | 13.645 | 6.998 | 121.04 | 13.645 | 6.998 | 0 | 0.06 | 0.057 | 0122Tra0000013008 | m | T110 | false | HI_UZV_HEA_STA_0,120_xxx | 0
Nebenträger | Wartung_FFB | 1 | Nebenträger | HEA 120 | 0.698 | Wartung_FFB | 13.06 | 13.645 | 6.998 | 16.04 | 13.645 | 6.998 | 0 | 0.06 | 0.057 | 0122Tra0000013010 | m | T110 | false | HI_UZV_HEA_STA_0,120_xxx | 0
Nebenträger | Wartung_FFB | 1 | Nebenträger | HEA 120 | 0.698 | Wartung_FFB | 16.06 | 13.645 | 6.998 | 19.04 | 13.645 | 6.998 | 0 | 0.06 | 0.057 | 0122Tra0000013012 | m | T110 | false | HI_UZV_HEA_STA_0,120_xxx | 0
Nebenträger | Wartung_FFB | 1 | Nebenträger | HEA 120 | 0.698 | Wartung_FFB | 19.06 | 13.645 | 6.998 | 22.04 | 13.645 | 6.998 | 0 | 0.06 | 0.057 | 0122Tra0000013014 | m | T110 | false | HI_UZV_HEA_STA_0,120_xxx | 0
Nebenträger | Wartung_FFB | 1 | Nebenträger | HEA 120 | 0.698 | Wartung_FFB | 34.06 | 13.645 | 6.998 | 37.04 | 13.645 | 6.998 | 0 | 0.06 | 0.057 | 0122Tra0000013024 | m | T110 | false | HI_UZV_HEA_STA_0,120_xxx | 0
Nebenträger | Wartung_FFB | 1 | Nebenträger | HEA 120 | 0.698 | Wartung_FFB | 37.06 | 13.645 | 6.998 | 40.04 | 13.645 | 6.998 | 0 | 0.06 | 0.057 | 0122Tra0000013026 | m | T110 | false | HI_UZV_HEA_STA_0,120_xxx | 0
Nebenträger | Wartung_FFB | 1 | Nebenträger | HEA 120 | 0.698 | Wartung_FFB | 40.06 | 13.645 | 6.998 | 43.04 | 13.645 | 6.998 | 0 | 0.06 | 0.057 | 0122Tra0000013028 | m | T110 | false | HI_UZV_HEA_STA_0,120_xxx | 0
Nebenträger | Wartung_FFB | 1 | Nebenträger | HEA 120 | 0.698 | Wartung_FFB | 43.06 | 13.645 | 6.998 | 46.04 | 13.645 | 6.998 | 0 | 0.06 | 0.057 | 0122Tra0000013030 | m | T110 | false | HI_UZV_HEA_STA_0,120_xxx | 0
Nebenträger | Wartung_FFB | 1 | Nebenträger | HEA 120 | 0.698 | Wartung_FFB | 46.06 | 13.645 | 6.998 | 49.04 | 13.645 | 6.998 | 0 | 0.06 | 0.057 | 0122Tra0000013032 | m | T110 | false | HI_UZV_HEA_STA_0,120_xxx | 0
Nebenträger | Wartung_FFB | 1 | Nebenträger | HEA 120 | 0.698 | Wartung_FFB | 49.06 | 13.645 | 6.998 | 52.04 | 13.645 | 6.998 | 0 | 0.06 | 0.057 | 0122Tra0000013034 | m | T110 | false | HI_UZV_HEA_STA_0,120_xxx | 0
Nebenträger | Wartung_FFB | 1 | Nebenträger | HEA 120 | 0.698 | Wartung_FFB | 52.06 | 13.645 | 6.998 | 55.04 | 13.645 | 6.998 | 0 | 0.06 | 0.057 | 0122Tra0000013036 | m | T110 | false | HI_UZV_HEA_STA_0,120_xxx | 0
Nebenträger | Wartung_FFB | 1 | Nebenträger | HEA 120 | 0.698 | Wartung_FFB | 55.06 | 13.645 | 6.998 | 58.04 | 13.645 | 6.998 | 0 | 0.06 | 0.057 | 0122Tra0000013038 | m | T110 | false | HI_UZV_HEA_STA_0,120_xxx | 0
Nebenträger | Wartung_FFB | 1 | Nebenträger | HEA 120 | 0.698 | Wartung_FFB | 58.06 | 13.645 | 6.998 | 61.04 | 13.645 | 6.998 | 0 | 0.06 | 0.057 | 0122Tra0000013040 | m | T110 | false | HI_UZV_HEA_STA_0,120_xxx | 0
Nebenträger | Wartung_FFB | 1 | Nebenträger | HEA 120 | 0.698 | Wartung_FFB | 61.06 | 13.645 | 6.998 | 64.04 | 13.645 | 6.998 | 0 | 0.06 | 0.057 | 0122Tra0000013042 | m | T110 | false | HI_UZV_HEA_STA_0,120_xxx | 0
Nebenträger | Wartung_FFB | 1 | Nebenträger | HEA 120 | 0.698 | Wartung_FFB | 10.56 | 13.645 | 6.998 | 13.04 | 13.645 | 6.998 | 0 | 0.06 | 0.057 | 0122Tra0000013044 | m | T110 | false | HI_UZV_HEA_STA_0,120_xxx | 0
Nebenträger | Wartung_FFB | 1 | Nebenträger | HEA 120 | 0.698 | Wartung_FFB | 64.06 | 12.145 | 6.998 | 67.04 | 12.145 | 6.998 | 0 | 0.06 | 0.057 | 0122Tra0000013083 | m | T110 | false | HI_UZV_HEA_STA_0,120_xxx | 0
Nebenträger | Wartung_FFB | 1 | Nebenträger | HEA 120 | 0.698 | Wartung_FFB | 67.06 | 12.145 | 6.998 | 70.04 | 12.145 | 6.998 | 0 | 0.06 | 0.057 | 0122Tra0000013085 | m | T110 | false | HI_UZV_HEA_STA_0,120_xxx | 0
Nebenträger | Wartung_FFB | 1 | Nebenträger | HEA 120 | 0.698 | Wartung_FFB | 70.06 | 12.145 | 6.998 | 73.04 | 12.145 | 6.998 | 0 | 0.06 | 0.057 | 0122Tra0000013087 | m | T110 | false | HI_UZV_HEA_STA_0,120_xxx | 0
Nebenträger | Wartung_FFB | 1 | Nebenträger | HEA 120 | 0.698 | Wartung_FFB | 73.06 | 12.145 | 6.998 | 76.04 | 12.145 | 6.998 | 0 | 0.06 | 0.057 | 0122Tra0000013089 | m | T110 | false | HI_UZV_HEA_STA_0,120_xxx | 0
Nebenträger | Wartung_FFB | 1 | Nebenträger | HEA 120 | 0.698 | Wartung_FFB | 76.06 | 12.145 | 6.998 | 79.04 | 12.145 | 6.998 | 0 | 0.06 | 0.057 | 0122Tra0000013091 | m | T110 | false | HI_UZV_HEA_STA_0,120_xxx | 0
Nebenträger | Wartung_FFB | 1 | Nebenträger | HEA 120 | 0.698 | Wartung_FFB | 85.06 | 12.145 | 6.998 | 88.04 | 12.145 | 6.998 | 0 | 0.06 | 0.057 | 0122Tra0000013097 | m | T110 | false | HI_UZV_HEA_STA_0,120_xxx | 0
Nebenträger | Wartung_FFB | 1 | Nebenträger | HEA 120 | 0.698 | Wartung_FFB | 88.06 | 12.145 | 6.998 | 91.04 | 12.145 | 6.998 | 0 | 0.06 | 0.057 | 0122Tra0000013099 | m | T110 | false | HI_UZV_HEA_STA_0,120_xxx | 0
Nebenträger | Wartung_FFB | 1 | Nebenträger | HEA 120 | 0.698 | Wartung_FFB | 97.06 | 12.145 | 6.998 | 100.04 | 12.145 | 6.998 | 0 | 0.06 | 0.057 | 0122Tra0000013105 | m | T110 | false | HI_UZV_HEA_STA_0,120_xxx | 0
Nebenträger | Wartung_FFB | 1 | Nebenträger | HEA 120 | 0.698 | Wartung_FFB | 100.06 | 12.145 | 6.998 | 103.04 | 12.145 | 6.998 | 0 | 0.06 | 0.057 | 0122Tra0000013107 | m | T110 | false | HI_UZV_HEA_STA_0,120_xxx | 0
Nebenträger | Wartung_FFB | 1 | Nebenträger | HEA 120 | 0.698 | Wartung_FFB | 103.06 | 12.145 | 6.998 | 106.04 | 12.145 | 6.998 | 0 | 0.06 | 0.057 | 0122Tra0000013109 | m | T110 | false | HI_UZV_HEA_STA_0,120_xxx | 0
Nebenträger | Wartung_FFB | 1 | Nebenträger | HEA 120 | 0.698 | Wartung_FFB | 106.06 | 12.145 | 6.998 | 109.04 | 12.145 | 6.998 | 0 | 0.06 | 0.057 | 0122Tra0000013111 | m | T110 | false | HI_UZV_HEA_STA_0,120_xxx | 0
Nebenträger | Wartung_FFB | 1 | Nebenträger | HEA 120 | 0.698 | Wartung_FFB | 109.06 | 12.145 | 6.998 | 112.04 | 12.145 | 6.998 | 0 | 0.06 | 0.057 | 0122Tra0000013113 | m | T110 | false | HI_UZV_HEA_STA_0,120_xxx | 0
Nebenträger | Wartung_FFB | 1 | Nebenträger | HEA 120 | 0.698 | Wartung_FFB | 112.06 | 12.145 | 6.998 | 115.04 | 12.145 | 6.998 | 0 | 0.06 | 0.057 | 0122Tra0000013115 | m | T110 | false | HI_UZV_HEA_STA_0,120_xxx | 0
Nebenträger | Wartung_FFB | 1 | Nebenträger | HEA 120 | 0.698 | Wartung_FFB | 115.06 | 12.145 | 6.998 | 118.04 | 12.145 | 6.998 | 0 | 0.06 | 0.057 | 0122Tra0000013117 | m | T110 | false | HI_UZV_HEA_STA_0,120_xxx | 0
Nebenträger | Wartung_FFB | 1 | Nebenträger | HEA 120 | 0.698 | Wartung_FFB | 118.06 | 12.145 | 6.998 | 121.04 | 12.145 | 6.998 | 0 | 0.06 | 0.057 | 0122Tra0000013119 | m | T110 | false | HI_UZV_HEA_STA_0,120_xxx | 0
Nebenträger | Wartung_FFB | 1 | Nebenträger | HEA 120 | 0.698 | Wartung_FFB | 13.06 | 12.145 | 6.998 | 16.04 | 12.145 | 6.998 | 0 | 0.06 | 0.057 | 0122Tra0000013121 | m | T110 | false | HI_UZV_HEA_STA_0,120_xxx | 0
Nebenträger | Wartung_FFB | 1 | Nebenträger | HEA 120 | 0.698 | Wartung_FFB | 16.06 | 12.145 | 6.998 | 19.04 | 12.145 | 6.998 | 0 | 0.06 | 0.057 | 0122Tra0000013123 | m | T110 | false | HI_UZV_HEA_STA_0,120_xxx | 0
Nebenträger | Wartung_FFB | 1 | Nebenträger | HEA 120 | 0.698 | Wartung_FFB | 19.06 | 12.145 | 6.998 | 22.04 | 12.145 | 6.998 | 0 | 0.06 | 0.057 | 0122Tra0000013125 | m | T110 | false | HI_UZV_HEA_STA_0,120_xxx | 0
Nebenträger | Wartung_FFB | 1 | Nebenträger | HEA 120 | 0.698 | Wartung_FFB | 34.06 | 12.145 | 6.998 | 37.04 | 12.145 | 6.998 | 0 | 0.06 | 0.057 | 0122Tra0000013135 | m | T110 | false | HI_UZV_HEA_STA_0,120_xxx | 0
Nebenträger | Wartung_FFB | 1 | Nebenträger | HEA 120 | 0.698 | Wartung_FFB | 37.06 | 12.145 | 6.998 | 40.04 | 12.145 | 6.998 | 0 | 0.06 | 0.057 | 0122Tra0000013137 | m | T110 | false | HI_UZV_HEA_STA_0,120_xxx | 0
Nebenträger | Wartung_FFB | 1 | Nebenträger | HEA 120 | 0.698 | Wartung_FFB | 40.06 | 12.145 | 6.998 | 43.04 | 12.145 | 6.998 | 0 | 0.06 | 0.057 | 0122Tra0000013139 | m | T110 | false | HI_UZV_HEA_STA_0,120_xxx | 0
Nebenträger | Wartung_FFB | 1 | Nebenträger | HEA 120 | 0.698 | Wartung_FFB | 43.06 | 12.145 | 6.998 | 46.04 | 12.145 | 6.998 | 0 | 0.06 | 0.057 | 0122Tra0000013141 | m | T110 | false | HI_UZV_HEA_STA_0,120_xxx | 0
Nebenträger | Wartung_FFB | 1 | Nebenträger | HEA 120 | 0.698 | Wartung_FFB | 46.06 | 12.145 | 6.998 | 49.04 | 12.145 | 6.998 | 0 | 0.06 | 0.057 | 0122Tra0000013143 | m | T110 | false | HI_UZV_HEA_STA_0,120_xxx | 0
Nebenträger | Wartung_FFB | 1 | Nebenträger | HEA 120 | 0.698 | Wartung_FFB | 49.06 | 12.145 | 6.998 | 52.04 | 12.145 | 6.998 | 0 | 0.06 | 0.057 | 0122Tra0000013145 | m | T110 | false | HI_UZV_HEA_STA_0,120_xxx | 0
Nebenträger | Wartung_FFB | 1 | Nebenträger | HEA 120 | 0.698 | Wartung_FFB | 52.06 | 12.145 | 6.998 | 55.04 | 12.145 | 6.998 | 0 | 0.06 | 0.057 | 0122Tra0000013147 | m | T110 | false | HI_UZV_HEA_STA_0,120_xxx | 0
Nebenträger | Wartung_FFB | 1 | Nebenträger | HEA 120 | 0.698 | Wartung_FFB | 55.06 | 12.145 | 6.998 | 58.04 | 12.145 | 6.998 | 0 | 0.06 | 0.057 | 0122Tra0000013149 | m | T110 | false | HI_UZV_HEA_STA_0,120_xxx | 0
Nebenträger | Wartung_FFB | 1 | Nebenträger | HEA 120 | 0.698 | Wartung_FFB | 58.06 | 12.145 | 6.998 | 61.04 | 12.145 | 6.998 | 0 | 0.06 | 0.057 | 0122Tra0000013151 | m | T110 | false | HI_UZV_HEA_STA_0,120_xxx | 0
Nebenträger | Wartung_FFB | 1 | Nebenträger | HEA 120 | 0.698 | Wartung_FFB | 61.06 | 12.145 | 6.998 | 64.04 | 12.145 | 6.998 | 0 | 0.06 | 0.057 | 0122Tra0000013153 | m | T110 | false | HI_UZV_HEA_STA_0,120_xxx | 0
Nebenträger | Wartung_FFB | 1 | Nebenträger | HEA 120 | 0.698 | Wartung_FFB | 10.56 | 12.145 | 6.998 | 13.04 | 12.145 | 6.998 | 0 | 0.06 | 0.057 | 0122Tra0000013155 | m | T110 | false | HI_UZV_HEA_STA_0,120_xxx | 0
Nebenträger | Wartung_FFB | 1 | Nebenträger | HEA 120 | 0.698 | Wartung_FFB | 22.06 | 28.645 | 6.998 | 25.546 | 28.645 | 6.998 | 0 | 0.06 | 0.057 | 0122Tra0000012276 | m | T110 | false | HI_UZV_HEA_STA_0,120_xxx | 0
Nebenträger | Wartung_FFB | 1 | Nebenträger | HEA 120 | 0.698 | Wartung_FFB | 25.566 | 28.645 | 6.998 | 28.04 | 28.645 | 6.998 | 0 | 0.06 | 0.057 | 0122Tra0000012278 | m | T110 | false | HI_UZV_HEA_STA_0,120_xxx | 0
Nebenträger | Wartung_FFB | 1 | Nebenträger | HEA 120 | 0.698 | Wartung_FFB | 22.06 | 27.145 | 6.998 | 25.546 | 27.145 | 6.998 | 0 | 0.06 | 0.057 | 0122Tra0000012350 | m | T110 | false | HI_UZV_HEA_STA_0,120_xxx | 0
Nebenträger | Wartung_FFB | 1 | Nebenträger | HEA 120 | 0.698 | Wartung_FFB | 25.566 | 27.145 | 6.998 | 28.04 | 27.145 | 6.998 | 0 | 0.06 | 0.057 | 0122Tra0000012352 | m | T110 | false | HI_UZV_HEA_STA_0,120_xxx | 0
Nebenträger | Wartung_FFB | 1 | Nebenträger | HEA 120 | 0.698 | Wartung_FFB | 22.06 | 25.645 | 6.998 | 25.546 | 25.645 | 6.998 | 0 | 0.06 | 0.057 | 0122Tra0000012424 | m | T110 | false | HI_UZV_HEA_STA_0,120_xxx | 0
Nebenträger | Wartung_FFB | 1 | Nebenträger | HEA 120 | 0.698 | Wartung_FFB | 25.566 | 25.645 | 6.998 | 28.04 | 25.645 | 6.998 | 0 | 0.06 | 0.057 | 0122Tra0000012426 | m | T110 | false | HI_UZV_HEA_STA_0,120_xxx | 0
Nebenträger | Wartung_FFB | 1 | Nebenträger | HEA 120 | 0.698 | Wartung_FFB | 22.06 | 24.145 | 6.998 | 25.546 | 24.145 | 6.998 | 0 | 0.06 | 0.057 | 0122Tra0000012498 | m | T110 | false | HI_UZV_HEA_STA_0,120_xxx | 0
Nebenträger | Wartung_FFB | 1 | Nebenträger | HEA 120 | 0.698 | Wartung_FFB | 25.566 | 24.145 | 6.998 | 28.04 | 24.145 | 6.998 | 0 | 0.06 | 0.057 | 0122Tra0000012500 | m | T110 | false | HI_UZV_HEA_STA_0,120_xxx | 0
Nebenträger | Wartung_FFB | 1 | Nebenträger | HEA 120 | 0.698 | Wartung_FFB | 22.06 | 22.645 | 6.998 | 25.546 | 22.645 | 6.998 | 0 | 0.06 | 0.057 | 0122Tra0000012572 | m | T110 | false | HI_UZV_HEA_STA_0,120_xxx | 0
Nebenträger | Wartung_FFB | 1 | Nebenträger | HEA 120 | 0.698 | Wartung_FFB | 25.566 | 22.645 | 6.998 | 28.04 | 22.645 | 6.998 | 0 | 0.06 | 0.057 | 0122Tra0000012574 | m | T110 | false | HI_UZV_HEA_STA_0,120_xxx | 0
Nebenträger | Wartung_FFB | 1 | Nebenträger | HEA 120 | 0.698 | Wartung_FFB | 22.06 | 21.145 | 6.998 | 25.546 | 21.145 | 6.998 | 0 | 0.06 | 0.057 | 0122Tra0000012646 | m | T110 | false | HI_UZV_HEA_STA_0,120_xxx | 0
Nebenträger | Wartung_FFB | 1 | Nebenträger | HEA 120 | 0.698 | Wartung_FFB | 25.566 | 21.145 | 6.998 | 28.04 | 21.145 | 6.998 | 0 | 0.06 | 0.057 | 0122Tra0000012648 | m | T110 | false | HI_UZV_HEA_STA_0,120_xxx | 0
Nebenträger | Wartung_FFB | 1 | Nebenträger | HEA 120 | 0.698 | Wartung_FFB | 22.06 | 19.645 | 6.998 | 25.546 | 19.645 | 6.998 | 0 | 0.06 | 0.057 | 0122Tra0000012720 | m | T110 | false | HI_UZV_HEA_STA_0,120_xxx | 0
Nebenträger | Wartung_FFB | 1 | Nebenträger | HEA 120 | 0.698 | Wartung_FFB | 25.566 | 19.645 | 6.998 | 28.04 | 19.645 | 6.998 | 0 | 0.06 | 0.057 | 0122Tra0000012722 | m | T110 | false | HI_UZV_HEA_STA_0,120_xxx | 0
Nebenträger | Wartung_FFB | 1 | Nebenträger | HEA 120 | 0.698 | Wartung_FFB | 22.06 | 18.145 | 6.998 | 25.546 | 18.145 | 6.998 | 0 | 0.06 | 0.057 | 0122Tra0000012794 | m | T110 | false | HI_UZV_HEA_STA_0,120_xxx | 0
Nebenträger | Wartung_FFB | 1 | Nebenträger | HEA 120 | 0.698 | Wartung_FFB | 25.566 | 18.145 | 6.998 | 28.04 | 18.145 | 6.998 | 0 | 0.06 | 0.057 | 0122Tra0000012796 | m | T110 | false | HI_UZV_HEA_STA_0,120_xxx | 0
Nebenträger | Wartung_FFB | 1 | Nebenträger | HEA 120 | 0.698 | Wartung_FFB | 22.06 | 16.645 | 6.998 | 25.546 | 16.645 | 6.998 | 0 | 0.06 | 0.057 | 0122Tra0000012868 | m | T110 | false | HI_UZV_HEA_STA_0,120_xxx | 0
Nebenträger | Wartung_FFB | 1 | Nebenträger | HEA 120 | 0.698 | Wartung_FFB | 25.566 | 16.645 | 6.998 | 28.04 | 16.645 | 6.998 | 0 | 0.06 | 0.057 | 0122Tra0000012870 | m | T110 | false | HI_UZV_HEA_STA_0,120_xxx | 0
Nebenträger | Wartung_FFB | 1 | Nebenträger | HEA 120 | 0.698 | Wartung_FFB | 22.06 | 15.145 | 6.998 | 25.546 | 15.145 | 6.998 | 0 | 0.06 | 0.057 | 0122Tra0000012942 | m | T110 | false | HI_UZV_HEA_STA_0,120_xxx | 0
Nebenträger | Wartung_FFB | 1 | Nebenträger | HEA 120 | 0.698 | Wartung_FFB | 25.566 | 15.145 | 6.998 | 28.04 | 15.145 | 6.998 | 0 | 0.06 | 0.057 | 0122Tra0000012944 | m | T110 | false | HI_UZV_HEA_STA_0,120_xxx | 0
Nebenträger | Wartung_FFB | 1 | Nebenträger | HEA 120 | 0.698 | Wartung_FFB | 22.06 | 13.645 | 6.998 | 25.546 | 13.645 | 6.998 | 0 | 0.06 | 0.057 | 0122Tra0000013016 | m | T110 | false | HI_UZV_HEA_STA_0,120_xxx | 0
Nebenträger | Wartung_FFB | 1 | Nebenträger | HEA 120 | 0.698 | Wartung_FFB | 25.566 | 13.645 | 6.998 | 28.04 | 13.645 | 6.998 | 0 | 0.06 | 0.057 | 0122Tra0000013018 | m | T110 | false | HI_UZV_HEA_STA_0,120_xxx | 0
Nebenträger | Wartung_FFB | 1 | Nebenträger | HEA 120 | 0.698 | Wartung_FFB | 22.06 | 12.145 | 6.998 | 25.546 | 12.145 | 6.998 | 0 | 0.06 | 0.057 | 0122Tra0000013127 | m | T110 | false | HI_UZV_HEA_STA_0,120_xxx | 0
Nebenträger | Wartung_FFB | 1 | Nebenträger | HEA 120 | 0.698 | Wartung_FFB | 25.566 | 12.145 | 6.998 | 28.04 | 12.145 | 6.998 | 0 | 0.06 | 0.057 | 0122Tra0000013129 | m | T110 | false | HI_UZV_HEA_STA_0,120_xxx | 0
Nebenträger | Wartung_FFB | 1 | Nebenträger | HEA 120 | 0.698 | Wartung_FFB | 28.06 | 28.645 | 6.998 | 29.59 | 28.645 | 6.998 | 0 | 0.06 | 0.057 | 0122Tra0000012280 | m | T110 | false | HI_UZV_HEA_STA_0,120_xxx | 0
Nebenträger | Wartung_FFB | 1 | Nebenträger | HEA 120 | 0.698 | Wartung_FFB | 28.06 | 27.145 | 6.998 | 29.59 | 27.145 | 6.998 | 0 | 0.06 | 0.057 | 0122Tra0000012354 | m | T110 | false | HI_UZV_HEA_STA_0,120_xxx | 0
Nebenträger | Wartung_FFB | 1 | Nebenträger | HEA 120 | 0.698 | Wartung_FFB | 28.06 | 25.645 | 6.998 | 29.59 | 25.645 | 6.998 | 0 | 0.06 | 0.057 | 0122Tra0000012428 | m | T110 | false | HI_UZV_HEA_STA_0,120_xxx | 0
Nebenträger | Wartung_FFB | 1 | Nebenträger | HEA 120 | 0.698 | Wartung_FFB | 28.06 | 24.145 | 6.998 | 29.59 | 24.145 | 6.998 | 0 | 0.06 | 0.057 | 0122Tra0000012502 | m | T110 | false | HI_UZV_HEA_STA_0,120_xxx | 0
Nebenträger | Wartung_FFB | 1 | Nebenträger | HEA 120 | 0.698 | Wartung_FFB | 28.06 | 22.645 | 6.998 | 29.59 | 22.645 | 6.998 | 0 | 0.06 | 0.057 | 0122Tra0000012576 | m | T110 | false | HI_UZV_HEA_STA_0,120_xxx | 0
Nebenträger | Wartung_FFB | 1 | Nebenträger | HEA 120 | 0.698 | Wartung_FFB | 28.06 | 21.145 | 6.998 | 29.59 | 21.145 | 6.998 | 0 | 0.06 | 0.057 | 0122Tra0000012650 | m | T110 | false | HI_UZV_HEA_STA_0,120_xxx | 0
Nebenträger | Wartung_FFB | 1 | Nebenträger | HEA 120 | 0.698 | Wartung_FFB | 28.06 | 19.645 | 6.998 | 29.59 | 19.645 | 6.998 | 0 | 0.06 | 0.057 | 0122Tra0000012724 | m | T110 | false | HI_UZV_HEA_STA_0,120_xxx | 0
Nebenträger | Wartung_FFB | 1 | Nebenträger | HEA 120 | 0.698 | Wartung_FFB | 28.06 | 18.145 | 6.998 | 29.59 | 18.145 | 6.998 | 0 | 0.06 | 0.057 | 0122Tra0000012798 | m | T110 | false | HI_UZV_HEA_STA_0,120_xxx | 0
Nebenträger | Wartung_FFB | 1 | Nebenträger | HEA 120 | 0.698 | Wartung_FFB | 28.06 | 16.645 | 6.998 | 29.59 | 16.645 | 6.998 | 0 | 0.06 | 0.057 | 0122Tra0000012872 | m | T110 | false | HI_UZV_HEA_STA_0,120_xxx | 0
Nebenträger | Wartung_FFB | 1 | Nebenträger | HEA 120 | 0.698 | Wartung_FFB | 28.06 | 15.145 | 6.998 | 29.59 | 15.145 | 6.998 | 0 | 0.06 | 0.057 | 0122Tra0000012946 | m | T110 | false | HI_UZV_HEA_STA_0,120_xxx | 0
Nebenträger | Wartung_FFB | 1 | Nebenträger | HEA 120 | 0.698 | Wartung_FFB | 28.06 | 13.645 | 6.998 | 29.59 | 13.645 | 6.998 | 0 | 0.06 | 0.057 | 0122Tra0000013020 | m | T110 | false | HI_UZV_HEA_STA_0,120_xxx | 0
Nebenträger | Wartung_FFB | 1 | Nebenträger | HEA 120 | 0.698 | Wartung_FFB | 28.06 | 12.145 | 6.998 | 29.59 | 12.145 | 6.998 | 0 | 0.06 | 0.057 | 0122Tra0000013131 | m | T110 | false | HI_UZV_HEA_STA_0,120_xxx | 0
Nebenträger | Wartung_FFB | 1 | Nebenträger | HEA 120 | 0.698 | Wartung_FFB | 29.61 | 28.645 | 6.998 | 32.24 | 28.645 | 6.998 | 0 | 0.06 | 0.057 | 0122Tra0000012282 | m | T110 | false | HI_UZV_HEA_STA_0,120_xxx | 0
Nebenträger | Wartung_FFB | 1 | Nebenträger | HEA 120 | 0.698 | Wartung_FFB | 29.61 | 27.145 | 6.998 | 32.24 | 27.145 | 6.998 | 0 | 0.06 | 0.057 | 0122Tra0000012356 | m | T110 | false | HI_UZV_HEA_STA_0,120_xxx | 0
Nebenträger | Wartung_FFB | 1 | Nebenträger | HEA 120 | 0.698 | Wartung_FFB | 29.61 | 25.645 | 6.998 | 32.24 | 25.645 | 6.998 | 0 | 0.06 | 0.057 | 0122Tra0000012430 | m | T110 | false | HI_UZV_HEA_STA_0,120_xxx | 0
Nebenträger | Wartung_FFB | 1 | Nebenträger | HEA 120 | 0.698 | Wartung_FFB | 29.61 | 24.145 | 6.998 | 32.24 | 24.145 | 6.998 | 0 | 0.06 | 0.057 | 0122Tra0000012504 | m | T110 | false | HI_UZV_HEA_STA_0,120_xxx | 0
Nebenträger | Wartung_FFB | 1 | Nebenträger | HEA 120 | 0.698 | Wartung_FFB | 29.61 | 22.645 | 6.998 | 32.24 | 22.645 | 6.998 | 0 | 0.06 | 0.057 | 0122Tra0000012578 | m | T110 | false | HI_UZV_HEA_STA_0,120_xxx | 0
Nebenträger | Wartung_FFB | 1 | Nebenträger | HEA 120 | 0.698 | Wartung_FFB | 29.61 | 21.145 | 6.998 | 32.24 | 21.145 | 6.998 | 0 | 0.06 | 0.057 | 0122Tra0000012652 | m | T110 | false | HI_UZV_HEA_STA_0,120_xxx | 0
Nebenträger | Wartung_FFB | 1 | Nebenträger | HEA 120 | 0.698 | Wartung_FFB | 29.61 | 19.645 | 6.998 | 32.24 | 19.645 | 6.998 | 0 | 0.06 | 0.057 | 0122Tra0000012726 | m | T110 | false | HI_UZV_HEA_STA_0,120_xxx | 0
Nebenträger | Wartung_FFB | 1 | Nebenträger | HEA 120 | 0.698 | Wartung_FFB | 29.61 | 18.145 | 6.998 | 32.24 | 18.145 | 6.998 | 0 | 0.06 | 0.057 | 0122Tra0000012800 | m | T110 | false | HI_UZV_HEA_STA_0,120_xxx | 0
Nebenträger | Wartung_FFB | 1 | Nebenträger | HEA 120 | 0.698 | Wartung_FFB | 29.61 | 16.645 | 6.998 | 32.24 | 16.645 | 6.998 | 0 | 0.06 | 0.057 | 0122Tra0000012874 | m | T110 | false | HI_UZV_HEA_STA_0,120_xxx | 0
Nebenträger | Wartung_FFB | 1 | Nebenträger | HEA 120 | 0.698 | Wartung_FFB | 29.61 | 15.145 | 6.998 | 32.24 | 15.145 | 6.998 | 0 | 0.06 | 0.057 | 0122Tra0000012948 | m | T110 | false | HI_UZV_HEA_STA_0,120_xxx | 0
Nebenträger | Wartung_FFB | 1 | Nebenträger | HEA 120 | 0.698 | Wartung_FFB | 29.61 | 13.645 | 6.998 | 32.24 | 13.645 | 6.998 | 0 | 0.06 | 0.057 | 0122Tra0000013022 | m | T110 | false | HI_UZV_HEA_STA_0,120_xxx | 0
Nebenträger | Wartung_FFB | 1 | Nebenträger | HEA 120 | 0.698 | Wartung_FFB | 29.61 | 12.145 | 6.998 | 32.24 | 12.145 | 6.998 | 0 | 0.06 | 0.057 | 0122Tra0000013133 | m | T110 | false | HI_UZV_HEA_STA_0,120_xxx | 0
Nebenträger | Wartung_FFB | 1 | Nebenträger | HEA 120 | 0.698 | Wartung_FFB | 32.26 | 27.145 | 6.998 | 34.04 | 27.145 | 6.998 | 0 | 0.06 | 0.057 | 0122Tra0000013292 | m | T110 | false | HI_UZV_HEA_STA_0,120_xxx | 0
Nebenträger | Wartung_FFB | 1 | Nebenträger | HEA 120 | 0.698 | Wartung_FFB | 32.26 | 25.645 | 6.998 | 34.04 | 25.645 | 6.998 | 0 | 0.06 | 0.057 | 0122Tra0000013294 | m | T110 | false | HI_UZV_HEA_STA_0,120_xxx | 0
Nebenträger | Wartung_FFB | 1 | Nebenträger | HEA 120 | 0.698 | Wartung_FFB | 32.26 | 24.145 | 6.998 | 34.04 | 24.145 | 6.998 | 0 | 0.06 | 0.057 | 0122Tra0000013296 | m | T110 | false | HI_UZV_HEA_STA_0,120_xxx | 0
Nebenträger | Wartung_FFB | 1 | Nebenträger | HEA 120 | 0.698 | Wartung_FFB | 32.26 | 22.645 | 6.998 | 34.04 | 22.645 | 6.998 | 0 | 0.06 | 0.057 | 0122Tra0000013298 | m | T110 | false | HI_UZV_HEA_STA_0,120_xxx | 0
Nebenträger | Wartung_FFB | 1 | Nebenträger | HEA 120 | 0.698 | Wartung_FFB | 32.26 | 21.145 | 6.998 | 34.04 | 21.145 | 6.998 | 0 | 0.06 | 0.057 | 0122Tra0000013300 | m | T110 | false | HI_UZV_HEA_STA_0,120_xxx | 0
Nebenträger | Wartung_FFB | 1 | Nebenträger | HEA 120 | 0.698 | Wartung_FFB | 32.26 | 19.645 | 6.998 | 34.04 | 19.645 | 6.998 | 0 | 0.06 | 0.057 | 0122Tra0000013302 | m | T110 | false | HI_UZV_HEA_STA_0,120_xxx | 0
Nebenträger | Wartung_FFB | 1 | Nebenträger | HEA 120 | 0.698 | Wartung_FFB | 32.26 | 18.145 | 6.998 | 34.04 | 18.145 | 6.998 | 0 | 0.06 | 0.057 | 0122Tra0000013304 | m | T110 | false | HI_UZV_HEA_STA_0,120_xxx | 0
Nebenträger | Wartung_FFB | 1 | Nebenträger | HEA 120 | 0.698 | Wartung_FFB | 32.26 | 16.645 | 6.998 | 34.04 | 16.645 | 6.998 | 0 | 0.06 | 0.057 | 0122Tra0000013306 | m | T110 | false | HI_UZV_HEA_STA_0,120_xxx | 0
Nebenträger | Wartung_FFB | 1 | Nebenträger | HEA 120 | 0.698 | Wartung_FFB | 32.26 | 15.145 | 6.998 | 34.04 | 15.145 | 6.998 | 0 | 0.06 | 0.057 | 0122Tra0000013308 | m | T110 | false | HI_UZV_HEA_STA_0,120_xxx | 0
Nebenträger | Wartung_FFB | 1 | Nebenträger | HEA 120 | 0.698 | Wartung_FFB | 32.26 | 13.645 | 6.998 | 34.04 | 13.645 | 6.998 | 0 | 0.06 | 0.057 | 0122Tra0000013310 | m | T110 | false | HI_UZV_HEA_STA_0,120_xxx | 0
Nebenträger | Wartung_FFB | 1 | Nebenträger | HEA 120 | 0.698 | Wartung_FFB | 32.26 | 12.145 | 6.998 | 34.04 | 12.145 | 6.998 | 0 | 0.06 | 0.057 | 0122Tra0000013312 | m | T110 | false | HI_UZV_HEA_STA_0,120_xxx | 0
Nebenträger | Wartung_FFB | 1 | Nebenträger | HEA 120 | 0.698 | Wartung_FFB | 32.26 | 28.645 | 6.998 | 34.04 | 28.645 | 6.998 | 0 | 0.06 | 0.057 | 0122Tra0000013290 | m | T110 | false | HI_UZV_HEA_STA_0,120_xxx | 0
Nebenträger | Wartung_FFB | 1 | Nebenträger | HEA 120 | 0.698 | Wartung_FFB | 79.06 | 28.645 | 6.998 | 81.54 | 28.645 | 6.998 | 0 | 0.06 | 0.057 | 0122Tra0000012242 | m | T110 | false | HI_UZV_HEA_STA_0,120_xxx | 0
Nebenträger | Wartung_FFB | 1 | Nebenträger | HEA 120 | 0.698 | Wartung_FFB | 81.56 | 28.645 | 6.998 | 85.04 | 28.645 | 6.998 | 0 | 0.06 | 0.057 | 0122Tra0000012244 | m | T110 | false | HI_UZV_HEA_STA_0,120_xxx | 0
Nebenträger | Wartung_FFB | 1 | Nebenträger | HEA 120 | 0.698 | Wartung_FFB | 79.06 | 27.145 | 6.998 | 81.54 | 27.145 | 6.998 | 0 | 0.06 | 0.057 | 0122Tra0000012316 | m | T110 | false | HI_UZV_HEA_STA_0,120_xxx | 0
Nebenträger | Wartung_FFB | 1 | Nebenträger | HEA 120 | 0.698 | Wartung_FFB | 81.56 | 27.145 | 6.998 | 85.04 | 27.145 | 6.998 | 0 | 0.06 | 0.057 | 0122Tra0000012318 | m | T110 | false | HI_UZV_HEA_STA_0,120_xxx | 0
Nebenträger | Wartung_FFB | 1 | Nebenträger | HEA 120 | 0.698 | Wartung_FFB | 79.06 | 25.645 | 6.998 | 81.54 | 25.645 | 6.998 | 0 | 0.06 | 0.057 | 0122Tra0000012390 | m | T110 | false | HI_UZV_HEA_STA_0,120_xxx | 0
Nebenträger | Wartung_FFB | 1 | Nebenträger | HEA 120 | 0.698 | Wartung_FFB | 81.56 | 25.645 | 6.998 | 85.04 | 25.645 | 6.998 | 0 | 0.06 | 0.057 | 0122Tra0000012392 | m | T110 | false | HI_UZV_HEA_STA_0,120_xxx | 0
Nebenträger | Wartung_FFB | 1 | Nebenträger | HEA 120 | 0.698 | Wartung_FFB | 79.06 | 24.145 | 6.998 | 81.54 | 24.145 | 6.998 | 0 | 0.06 | 0.057 | 0122Tra0000012464 | m | T110 | false | HI_UZV_HEA_STA_0,120_xxx | 0
Nebenträger | Wartung_FFB | 1 | Nebenträger | HEA 120 | 0.698 | Wartung_FFB | 81.56 | 24.145 | 6.998 | 85.04 | 24.145 | 6.998 | 0 | 0.06 | 0.057 | 0122Tra0000012466 | m | T110 | false | HI_UZV_HEA_STA_0,120_xxx | 0
Nebenträger | Wartung_FFB | 1 | Nebenträger | HEA 120 | 0.698 | Wartung_FFB | 79.06 | 22.645 | 6.998 | 81.54 | 22.645 | 6.998 | 0 | 0.06 | 0.057 | 0122Tra0000012538 | m | T110 | false | HI_UZV_HEA_STA_0,120_xxx | 0
Nebenträger | Wartung_FFB | 1 | Nebenträger | HEA 120 | 0.698 | Wartung_FFB | 81.56 | 22.645 | 6.998 | 85.04 | 22.645 | 6.998 | 0 | 0.06 | 0.057 | 0122Tra0000012540 | m | T110 | false | HI_UZV_HEA_STA_0,120_xxx | 0
Nebenträger | Wartung_FFB | 1 | Nebenträger | HEA 120 | 0.698 | Wartung_FFB | 79.06 | 21.145 | 6.998 | 81.54 | 21.145 | 6.998 | 0 | 0.06 | 0.057 | 0122Tra0000012612 | m | T110 | false | HI_UZV_HEA_STA_0,120_xxx | 0
Nebenträger | Wartung_FFB | 1 | Nebenträger | HEA 120 | 0.698 | Wartung_FFB | 81.56 | 21.145 | 6.998 | 85.04 | 21.145 | 6.998 | 0 | 0.06 | 0.057 | 0122Tra0000012614 | m | T110 | false | HI_UZV_HEA_STA_0,120_xxx | 0
Nebenträger | Wartung_FFB | 1 | Nebenträger | HEA 120 | 0.698 | Wartung_FFB | 79.06 | 19.645 | 6.998 | 81.54 | 19.645 | 6.998 | 0 | 0.06 | 0.057 | 0122Tra0000012686 | m | T110 | false | HI_UZV_HEA_STA_0,120_xxx | 0
Nebenträger | Wartung_FFB | 1 | Nebenträger | HEA 120 | 0.698 | Wartung_FFB | 81.56 | 19.645 | 6.998 | 85.04 | 19.645 | 6.998 | 0 | 0.06 | 0.057 | 0122Tra0000012688 | m | T110 | false | HI_UZV_HEA_STA_0,120_xxx | 0
Nebenträger | Wartung_FFB | 1 | Nebenträger | HEA 120 | 0.698 | Wartung_FFB | 79.06 | 18.145 | 6.998 | 81.54 | 18.145 | 6.998 | 0 | 0.06 | 0.057 | 0122Tra0000012760 | m | T110 | false | HI_UZV_HEA_STA_0,120_xxx | 0
Nebenträger | Wartung_FFB | 1 | Nebenträger | HEA 120 | 0.698 | Wartung_FFB | 81.56 | 18.145 | 6.998 | 85.04 | 18.145 | 6.998 | 0 | 0.06 | 0.057 | 0122Tra0000012762 | m | T110 | false | HI_UZV_HEA_STA_0,120_xxx | 0
Nebenträger | Wartung_FFB | 1 | Nebenträger | HEA 120 | 0.698 | Wartung_FFB | 79.06 | 16.645 | 6.998 | 81.54 | 16.645 | 6.998 | 0 | 0.06 | 0.057 | 0122Tra0000012834 | m | T110 | false | HI_UZV_HEA_STA_0,120_xxx | 0
Nebenträger | Wartung_FFB | 1 | Nebenträger | HEA 120 | 0.698 | Wartung_FFB | 81.56 | 16.645 | 6.998 | 85.04 | 16.645 | 6.998 | 0 | 0.06 | 0.057 | 0122Tra0000012836 | m | T110 | false | HI_UZV_HEA_STA_0,120_xxx | 0
Nebenträger | Wartung_FFB | 1 | Nebenträger | HEA 120 | 0.698 | Wartung_FFB | 79.06 | 15.145 | 6.998 | 81.54 | 15.145 | 6.998 | 0 | 0.06 | 0.057 | 0122Tra0000012908 | m | T110 | false | HI_UZV_HEA_STA_0,120_xxx | 0
Nebenträger | Wartung_FFB | 1 | Nebenträger | HEA 120 | 0.698 | Wartung_FFB | 81.56 | 15.145 | 6.998 | 85.04 | 15.145 | 6.998 | 0 | 0.06 | 0.057 | 0122Tra0000012910 | m | T110 | false | HI_UZV_HEA_STA_0,120_xxx | 0
Nebenträger | Wartung_FFB | 1 | Nebenträger | HEA 120 | 0.698 | Wartung_FFB | 79.06 | 13.645 | 6.998 | 81.54 | 13.645 | 6.998 | 0 | 0.06 | 0.057 | 0122Tra0000012982 | m | T110 | false | HI_UZV_HEA_STA_0,120_xxx | 0
Nebenträger | Wartung_FFB | 1 | Nebenträger | HEA 120 | 0.698 | Wartung_FFB | 81.56 | 13.645 | 6.998 | 85.04 | 13.645 | 6.998 | 0 | 0.06 | 0.057 | 0122Tra0000012984 | m | T110 | false | HI_UZV_HEA_STA_0,120_xxx | 0
Nebenträger | Wartung_FFB | 1 | Nebenträger | HEA 120 | 0.698 | Wartung_FFB | 79.06 | 12.145 | 6.998 | 81.54 | 12.145 | 6.998 | 0 | 0.06 | 0.057 | 0122Tra0000013093 | m | T110 | false | HI_UZV_HEA_STA_0,120_xxx | 0
Nebenträger | Wartung_FFB | 1 | Nebenträger | HEA 120 | 0.698 | Wartung_FFB | 81.56 | 12.145 | 6.998 | 85.04 | 12.145 | 6.998 | 0 | 0.06 | 0.057 | 0122Tra0000013095 | m | T110 | false | HI_UZV_HEA_STA_0,120_xxx | 0
Nebenträger | Wartung_FFB | 1 | Nebenträger | HEA 120 | 0.698 | Wartung_FFB | 94.71 | 28.645 | 6.998 | 97.04 | 28.645 | 6.998 | 0 | 0.06 | 0.057 | 0122Tra0000012252 | m | T110 | false | HI_UZV_HEA_STA_0,120_xxx | 0
Nebenträger | Wartung_FFB | 1 | Nebenträger | HEA 120 | 0.698 | Wartung_FFB | 94.71 | 27.145 | 6.998 | 97.04 | 27.145 | 6.998 | 0 | 0.06 | 0.057 | 0122Tra0000012326 | m | T110 | false | HI_UZV_HEA_STA_0,120_xxx | 0
Nebenträger | Wartung_FFB | 1 | Nebenträger | HEA 120 | 0.698 | Wartung_FFB | 94.71 | 25.645 | 6.998 | 97.04 | 25.645 | 6.998 | 0 | 0.06 | 0.057 | 0122Tra0000012400 | m | T110 | false | HI_UZV_HEA_STA_0,120_xxx | 0
Nebenträger | Wartung_FFB | 1 | Nebenträger | HEA 120 | 0.698 | Wartung_FFB | 94.71 | 24.145 | 6.998 | 97.04 | 24.145 | 6.998 | 0 | 0.06 | 0.057 | 0122Tra0000012474 | m | T110 | false | HI_UZV_HEA_STA_0,120_xxx | 0
Nebenträger | Wartung_FFB | 1 | Nebenträger | HEA 120 | 0.698 | Wartung_FFB | 94.71 | 22.645 | 6.998 | 97.04 | 22.645 | 6.998 | 0 | 0.06 | 0.057 | 0122Tra0000012548 | m | T110 | false | HI_UZV_HEA_STA_0,120_xxx | 0
Nebenträger | Wartung_FFB | 1 | Nebenträger | HEA 120 | 0.698 | Wartung_FFB | 94.71 | 21.145 | 6.998 | 97.04 | 21.145 | 6.998 | 0 | 0.06 | 0.057 | 0122Tra0000012622 | m | T110 | false | HI_UZV_HEA_STA_0,120_xxx | 0
Nebenträger | Wartung_FFB | 1 | Nebenträger | HEA 120 | 0.698 | Wartung_FFB | 94.71 | 19.645 | 6.998 | 97.04 | 19.645 | 6.998 | 0 | 0.06 | 0.057 | 0122Tra0000012696 | m | T110 | false | HI_UZV_HEA_STA_0,120_xxx | 0
Nebenträger | Wartung_FFB | 1 | Nebenträger | HEA 120 | 0.698 | Wartung_FFB | 94.71 | 18.145 | 6.998 | 97.04 | 18.145 | 6.998 | 0 | 0.06 | 0.057 | 0122Tra0000012770 | m | T110 | false | HI_UZV_HEA_STA_0,120_xxx | 0
Nebenträger | Wartung_FFB | 1 | Nebenträger | HEA 120 | 0.698 | Wartung_FFB | 94.71 | 16.645 | 6.998 | 97.04 | 16.645 | 6.998 | 0 | 0.06 | 0.057 | 0122Tra0000012844 | m | T110 | false | HI_UZV_HEA_STA_0,120_xxx | 0
Nebenträger | Wartung_FFB | 1 | Nebenträger | HEA 120 | 0.698 | Wartung_FFB | 94.71 | 15.145 | 6.998 | 97.04 | 15.145 | 6.998 | 0 | 0.06 | 0.057 | 0122Tra0000012918 | m | T110 | false | HI_UZV_HEA_STA_0,120_xxx | 0
Nebenträger | Wartung_FFB | 1 | Nebenträger | HEA 120 | 0.698 | Wartung_FFB | 94.71 | 13.645 | 6.998 | 97.04 | 13.645 | 6.998 | 0 | 0.06 | 0.057 | 0122Tra0000012992 | m | T110 | false | HI_UZV_HEA_STA_0,120_xxx | 0
Nebenträger | Wartung_FFB | 1 | Nebenträger | HEA 120 | 0.698 | Wartung_FFB | 94.71 | 12.145 | 6.998 | 97.04 | 12.145 | 6.998 | 0 | 0.06 | 0.057 | 0122Tra0000013103 | m | T110 | false | HI_UZV_HEA_STA_0,120_xxx | 0
Nebenträger | Wartung_FFB | 1 | Nebenträger | HEA 120 | 0.698 | Wartung_FFB | 32.26 | 49.45 | 6.998 | 34.04 | 49.45 | 6.998 | 0 | 0.06 | 0.057 | 0122Tra0000010876 | m | T110 | false | HI_UZV_HEA_STA_0,120_xxx | 0
Nebenträger | Wartung_FFB | 1 | Nebenträger | HEA 120 | 0.698 | Wartung_FFB | 32.26 | 47.95 | 6.998 | 34.04 | 47.95 | 6.998 | 0 | 0.06 | 0.057 | 0122Tra0000010950 | m | T110 | false | HI_UZV_HEA_STA_0,120_xxx | 0
Nebenträger | Wartung_FFB | 1 | Nebenträger | HEA 120 | 0.698 | Wartung_FFB | 32.26 | 46.45 | 6.998 | 34.04 | 46.45 | 6.998 | 0 | 0.06 | 0.057 | 0122Tra0000011024 | m | T110 | false | HI_UZV_HEA_STA_0,120_xxx | 0
Nebenträger | Wartung_FFB | 1 | Nebenträger | HEA 120 | 0.698 | Wartung_FFB | 32.26 | 44.95 | 6.998 | 34.04 | 44.95 | 6.998 | 0 | 0.06 | 0.057 | 0122Tra0000011098 | m | T110 | false | HI_UZV_HEA_STA_0,120_xxx | 0
Nebenträger | Wartung_FFB | 1 | Nebenträger | HEA 120 | 0.698 | Wartung_FFB | 32.26 | 43.45 | 6.998 | 34.04 | 43.45 | 6.998 | 0 | 0.06 | 0.057 | 0122Tra0000011172 | m | T110 | false | HI_UZV_HEA_STA_0,120_xxx | 0
Nebenträger | Wartung_FFB | 1 | Nebenträger | HEA 120 | 0.698 | Wartung_FFB | 32.26 | 41.95 | 6.998 | 34.04 | 41.95 | 6.998 | 0 | 0.06 | 0.057 | 0122Tra0000011246 | m | T110 | false | HI_UZV_HEA_STA_0,120_xxx | 0
Nebenträger | Wartung_FFB | 1 | Nebenträger | HEA 120 | 0.698 | Wartung_FFB | 32.26 | 40.45 | 6.998 | 34.04 | 40.45 | 6.998 | 0 | 0.06 | 0.057 | 0122Tra0000011320 | m | T110 | false | HI_UZV_HEA_STA_0,120_xxx | 0
Nebenträger | Wartung_FFB | 1 | Nebenträger | HEA 120 | 0.698 | Wartung_FFB | 32.26 | 38.95 | 6.998 | 34.04 | 38.95 | 6.998 | 0 | 0.06 | 0.057 | 0122Tra0000011394 | m | T110 | false | HI_UZV_HEA_STA_0,120_xxx | 0
Nebenträger | Wartung_FFB | 1 | Nebenträger | HEA 120 | 0.698 | Wartung_FFB | 32.26 | 37.45 | 6.998 | 34.04 | 37.45 | 6.998 | 0 | 0.06 | 0.057 | 0122Tra0000011468 | m | T110 | false | HI_UZV_HEA_STA_0,120_xxx | 0
Nebenträger | Wartung_FFB | 1 | Nebenträger | HEA 120 | 0.698 | Wartung_FFB | 28.06 | 49.45 | 6.998 | 29.59 | 49.45 | 6.998 | 0 | 0.06 | 0.057 | 0122Tra0000010874 | m | T110 | false | HI_UZV_HEA_STA_0,120_xxx | 0
Nebenträger | Wartung_FFB | 1 | Nebenträger | HEA 120 | 0.698 | Wartung_FFB | 28.06 | 47.95 | 6.998 | 29.59 | 47.95 | 6.998 | 0 | 0.06 | 0.057 | 0122Tra0000010948 | m | T110 | false | HI_UZV_HEA_STA_0,120_xxx | 0
Nebenträger | Wartung_FFB | 1 | Nebenträger | HEA 120 | 0.698 | Wartung_FFB | 28.06 | 46.45 | 6.998 | 29.59 | 46.45 | 6.998 | 0 | 0.06 | 0.057 | 0122Tra0000011022 | m | T110 | false | HI_UZV_HEA_STA_0,120_xxx | 0
Nebenträger | Wartung_FFB | 1 | Nebenträger | HEA 120 | 0.698 | Wartung_FFB | 28.06 | 44.95 | 6.998 | 29.59 | 44.95 | 6.998 | 0 | 0.06 | 0.057 | 0122Tra0000011096 | m | T110 | false | HI_UZV_HEA_STA_0,120_xxx | 0
Nebenträger | Wartung_FFB | 1 | Nebenträger | HEA 120 | 0.698 | Wartung_FFB | 28.06 | 43.45 | 6.998 | 29.59 | 43.45 | 6.998 | 0 | 0.06 | 0.057 | 0122Tra0000011170 | m | T110 | false | HI_UZV_HEA_STA_0,120_xxx | 0
Nebenträger | Wartung_FFB | 1 | Nebenträger | HEA 120 | 0.698 | Wartung_FFB | 28.06 | 41.95 | 6.998 | 29.59 | 41.95 | 6.998 | 0 | 0.06 | 0.057 | 0122Tra0000011244 | m | T110 | false | HI_UZV_HEA_STA_0,120_xxx | 0
Nebenträger | Wartung_FFB | 1 | Nebenträger | HEA 120 | 0.698 | Wartung_FFB | 28.06 | 40.45 | 6.998 | 29.59 | 40.45 | 6.998 | 0 | 0.06 | 0.057 | 0122Tra0000011318 | m | T110 | false | HI_UZV_HEA_STA_0,120_xxx | 0
Nebenträger | Wartung_FFB | 1 | Nebenträger | HEA 120 | 0.698 | Wartung_FFB | 28.06 | 38.95 | 6.998 | 29.59 | 38.95 | 6.998 | 0 | 0.06 | 0.057 | 0122Tra0000011392 | m | T110 | false | HI_UZV_HEA_STA_0,120_xxx | 0
Nebenträger | Wartung_FFB | 1 | Nebenträger | HEA 120 | 0.698 | Wartung_FFB | 28.06 | 37.45 | 6.998 | 29.59 | 37.45 | 6.998 | 0 | 0.06 | 0.057 | 0122Tra0000011466 | m | T110 | false | HI_UZV_HEA_STA_0,120_xxx | 0
Nebenträger | Wartung_FFB | 1 | Nebenträger | HEA 120 | 0.698 | Wartung_FFB | 29.61 | 49.45 | 6.998 | 32.24 | 49.45 | 6.998 | 0 | 0.06 | 0.057 | 0122Tra0000013497 | m | T110 | false | HI_UZV_HEA_STA_0,120_xxx | 0
Nebenträger | Wartung_FFB | 1 | Nebenträger | HEA 120 | 0.698 | Wartung_FFB | 29.61 | 47.95 | 6.998 | 32.24 | 47.95 | 6.998 | 0 | 0.06 | 0.057 | 0122Tra0000013499 | m | T110 | false | HI_UZV_HEA_STA_0,120_xxx | 0
Nebenträger | Wartung_FFB | 1 | Nebenträger | HEA 120 | 0.698 | Wartung_FFB | 29.61 | 46.45 | 6.998 | 32.24 | 46.45 | 6.998 | 0 | 0.06 | 0.057 | 0122Tra0000013501 | m | T110 | false | HI_UZV_HEA_STA_0,120_xxx | 0
Nebenträger | Wartung_FFB | 1 | Nebenträger | HEA 120 | 0.698 | Wartung_FFB | 29.61 | 44.95 | 6.998 | 32.24 | 44.95 | 6.998 | 0 | 0.06 | 0.057 | 0122Tra0000013503 | m | T110 | false | HI_UZV_HEA_STA_0,120_xxx | 0
Nebenträger | Wartung_FFB | 1 | Nebenträger | HEA 120 | 0.698 | Wartung_FFB | 29.61 | 43.45 | 6.998 | 32.24 | 43.45 | 6.998 | 0 | 0.06 | 0.057 | 0122Tra0000013505 | m | T110 | false | HI_UZV_HEA_STA_0,120_xxx | 0
Nebenträger | Wartung_FFB | 1 | Nebenträger | HEA 120 | 0.698 | Wartung_FFB | 29.61 | 41.95 | 6.998 | 32.24 | 41.95 | 6.998 | 0 | 0.06 | 0.057 | 0122Tra0000013507 | m | T110 | false | HI_UZV_HEA_STA_0,120_xxx | 0
Nebenträger | Wartung_FFB | 1 | Nebenträger | HEA 120 | 0.698 | Wartung_FFB | 29.61 | 40.45 | 6.998 | 32.24 | 40.45 | 6.998 | 0 | 0.06 | 0.057 | 0122Tra0000013509 | m | T110 | false | HI_UZV_HEA_STA_0,120_xxx | 0
Nebenträger | Wartung_FFB | 1 | Nebenträger | HEA 120 | 0.698 | Wartung_FFB | 29.61 | 38.95 | 6.998 | 32.24 | 38.95 | 6.998 | 0 | 0.06 | 0.057 | 0122Tra0000013511 | m | T110 | false | HI_UZV_HEA_STA_0,120_xxx | 0
Nebenträger | Wartung_FFB | 1 | Nebenträger | HEA 120 | 0.698 | Wartung_FFB | 29.61 | 37.45 | 6.998 | 32.24 | 37.45 | 6.998 | 0 | 0.06 | 0.057 | 0122Tra0000013513 | m | T110 | false | HI_UZV_HEA_STA_0,120_xxx | 0
Nebenträger | Wartung_FFB | 1 | Nebenträger | HEA 120 | 0.698 | Wartung_FFB | 22.06 | 68.601 | 6.998 | 25.54 | 68.601 | 6.998 | 0 | 0.06 | 0.057 | 0122Tra0000009352 | m | T110 | false | HI_UZV_HEA_STA_0,120_xxx | 0
Nebenträger | Wartung_FFB | 1 | Nebenträger | HEA 120 | 0.698 | Wartung_FFB | 25.56 | 68.601 | 6.998 | 28.04 | 68.601 | 6.998 | 0 | 0.06 | 0.057 | 0122Tra0000009354 | m | T110 | false | HI_UZV_HEA_STA_0,120_xxx | 0
Nebenträger | Wartung_FFB | 1 | Nebenträger | HEA 120 | 0.698 | Wartung_FFB | 22.06 | 67.101 | 6.998 | 25.54 | 67.101 | 6.998 | 0 | 0.06 | 0.057 | 0122Tra0000009464 | m | T110 | false | HI_UZV_HEA_STA_0,120_xxx | 0
Nebenträger | Wartung_FFB | 1 | Nebenträger | HEA 120 | 0.698 | Wartung_FFB | 25.56 | 67.101 | 6.998 | 28.04 | 67.101 | 6.998 | 0 | 0.06 | 0.057 | 0122Tra0000009466 | m | T110 | false | HI_UZV_HEA_STA_0,120_xxx | 0
Nebenträger | Wartung_FFB | 1 | Nebenträger | HEA 120 | 0.698 | Wartung_FFB | 22.06 | 65.601 | 6.998 | 25.54 | 65.601 | 6.998 | 0 | 0.06 | 0.057 | 0122Tra0000009575 | m | T110 | false | HI_UZV_HEA_STA_0,120_xxx | 0
Nebenträger | Wartung_FFB | 1 | Nebenträger | HEA 120 | 0.698 | Wartung_FFB | 25.56 | 65.601 | 6.998 | 28.04 | 65.601 | 6.998 | 0 | 0.06 | 0.057 | 0122Tra0000009577 | m | T110 | false | HI_UZV_HEA_STA_0,120_xxx | 0
Nebenträger | Wartung_FFB | 1 | Nebenträger | HEA 120 | 0.698 | Wartung_FFB | 22.06 | 64.101 | 6.998 | 25.54 | 64.101 | 6.998 | 0 | 0.06 | 0.057 | 0122Tra0000009686 | m | T110 | false | HI_UZV_HEA_STA_0,120_xxx | 0
Nebenträger | Wartung_FFB | 1 | Nebenträger | HEA 120 | 0.698 | Wartung_FFB | 25.56 | 64.101 | 6.998 | 28.04 | 64.101 | 6.998 | 0 | 0.06 | 0.057 | 0122Tra0000009688 | m | T110 | false | HI_UZV_HEA_STA_0,120_xxx | 0
Nebenträger | Wartung_FFB | 1 | Nebenträger | HEA 120 | 0.698 | Wartung_FFB | 22.06 | 62.601 | 6.998 | 25.54 | 62.601 | 6.998 | 0 | 0.06 | 0.057 | 0122Tra0000009797 | m | T110 | false | HI_UZV_HEA_STA_0,120_xxx | 0
Nebenträger | Wartung_FFB | 1 | Nebenträger | HEA 120 | 0.698 | Wartung_FFB | 25.56 | 62.601 | 6.998 | 28.04 | 62.601 | 6.998 | 0 | 0.06 | 0.057 | 0122Tra0000009799 | m | T110 | false | HI_UZV_HEA_STA_0,120_xxx | 0
Nebenträger | Wartung_FFB | 1 | Nebenträger | HEA 120 | 0.698 | Wartung_FFB | 22.06 | 61.101 | 6.998 | 25.54 | 61.101 | 6.998 | 0 | 0.06 | 0.057 | 0122Tra0000009908 | m | T110 | false | HI_UZV_HEA_STA_0,120_xxx | 0
Nebenträger | Wartung_FFB | 1 | Nebenträger | HEA 120 | 0.698 | Wartung_FFB | 25.56 | 61.101 | 6.998 | 28.04 | 61.101 | 6.998 | 0 | 0.06 | 0.057 | 0122Tra0000009910 | m | T110 | false | HI_UZV_HEA_STA_0,120_xxx | 0
Nebenträger | Wartung_FFB | 1 | Nebenträger | HEA 120 | 0.698 | Wartung_FFB | 22.06 | 59.601 | 6.998 | 25.54 | 59.601 | 6.998 | 0 | 0.06 | 0.057 | 0122Tra0000010019 | m | T110 | false | HI_UZV_HEA_STA_0,120_xxx | 0
Nebenträger | Wartung_FFB | 1 | Nebenträger | HEA 120 | 0.698 | Wartung_FFB | 25.56 | 59.601 | 6.998 | 28.04 | 59.601 | 6.998 | 0 | 0.06 | 0.057 | 0122Tra0000010021 | m | T110 | false | HI_UZV_HEA_STA_0,120_xxx | 0
Nebenträger | Wartung_FFB | 1 | Nebenträger | HEA 120 | 0.698 | Wartung_FFB | 22.06 | 58.101 | 6.998 | 25.54 | 58.101 | 6.998 | 0 | 0.06 | 0.057 | 0122Tra0000010130 | m | T110 | false | HI_UZV_HEA_STA_0,120_xxx | 0
Nebenträger | Wartung_FFB | 1 | Nebenträger | HEA 120 | 0.698 | Wartung_FFB | 25.56 | 58.101 | 6.998 | 28.04 | 58.101 | 6.998 | 0 | 0.06 | 0.057 | 0122Tra0000010132 | m | T110 | false | HI_UZV_HEA_STA_0,120_xxx | 0
Nebenträger | Wartung_FFB | 1 | Nebenträger | HEA 120 | 0.698 | Wartung_FFB | 22.06 | 56.601 | 6.998 | 25.54 | 56.601 | 6.998 | 0 | 0.06 | 0.057 | 0122Tra0000010241 | m | T110 | false | HI_UZV_HEA_STA_0,120_xxx | 0
Nebenträger | Wartung_FFB | 1 | Nebenträger | HEA 120 | 0.698 | Wartung_FFB | 25.56 | 56.601 | 6.998 | 28.04 | 56.601 | 6.998 | 0 | 0.06 | 0.057 | 0122Tra0000010243 | m | T110 | false | HI_UZV_HEA_STA_0,120_xxx | 0
Nebenträger | Wartung_FFB | 1 | Nebenträger | HEA 120 | 0.698 | Wartung_FFB | 22.06 | 55.101 | 6.998 | 25.54 | 55.101 | 6.998 | 0 | 0.06 | 0.057 | 0122Tra0000010389 | m | T110 | false | HI_UZV_HEA_STA_0,120_xxx | 0
Nebenträger | Wartung_FFB | 1 | Nebenträger | HEA 120 | 0.698 | Wartung_FFB | 25.56 | 55.101 | 6.998 | 28.04 | 55.101 | 6.998 | 0 | 0.06 | 0.057 | 0122Tra0000010391 | m | T110 | false | HI_UZV_HEA_STA_0,120_xxx | 0
Nebenträger | Wartung_FFB | 1 | Nebenträger | HEA 120 | 0.698 | Wartung_FFB | 22.06 | 53.601 | 6.998 | 25.54 | 53.601 | 6.998 | 0 | 0.06 | 0.057 | 0122Tra0000010463 | m | T110 | false | HI_UZV_HEA_STA_0,120_xxx | 0
Nebenträger | Wartung_FFB | 1 | Nebenträger | HEA 120 | 0.698 | Wartung_FFB | 25.56 | 53.601 | 6.998 | 28.04 | 53.601 | 6.998 | 0 | 0.06 | 0.057 | 0122Tra0000010465 | m | T110 | false | HI_UZV_HEA_STA_0,120_xxx | 0
Nebenträger | Wartung_FFB | 1 | Nebenträger | HEA 120 | 0.698 | Wartung_FFB | 28.06 | 68.601 | 6.998 | 29.59 | 68.601 | 6.998 | 0 | 0.06 | 0.057 | 0122Tra0000009356 | m | T110 | false | HI_UZV_HEA_STA_0,120_xxx | 0
Nebenträger | Wartung_FFB | 1 | Nebenträger | HEA 120 | 0.698 | Wartung_FFB | 28.06 | 67.101 | 6.998 | 29.59 | 67.101 | 6.998 | 0 | 0.06 | 0.057 | 0122Tra0000009468 | m | T110 | false | HI_UZV_HEA_STA_0,120_xxx | 0
Nebenträger | Wartung_FFB | 1 | Nebenträger | HEA 120 | 0.698 | Wartung_FFB | 28.06 | 65.601 | 6.998 | 29.59 | 65.601 | 6.998 | 0 | 0.06 | 0.057 | 0122Tra0000009579 | m | T110 | false | HI_UZV_HEA_STA_0,120_xxx | 0
Nebenträger | Wartung_FFB | 1 | Nebenträger | HEA 120 | 0.698 | Wartung_FFB | 28.06 | 64.101 | 6.998 | 29.59 | 64.101 | 6.998 | 0 | 0.06 | 0.057 | 0122Tra0000009690 | m | T110 | false | HI_UZV_HEA_STA_0,120_xxx | 0
Nebenträger | Wartung_FFB | 1 | Nebenträger | HEA 120 | 0.698 | Wartung_FFB | 28.06 | 62.601 | 6.998 | 29.59 | 62.601 | 6.998 | 0 | 0.06 | 0.057 | 0122Tra0000009801 | m | T110 | false | HI_UZV_HEA_STA_0,120_xxx | 0
Nebenträger | Wartung_FFB | 1 | Nebenträger | HEA 120 | 0.698 | Wartung_FFB | 28.06 | 61.101 | 6.998 | 29.59 | 61.101 | 6.998 | 0 | 0.06 | 0.057 | 0122Tra0000009912 | m | T110 | false | HI_UZV_HEA_STA_0,120_xxx | 0
Nebenträger | Wartung_FFB | 1 | Nebenträger | HEA 120 | 0.698 | Wartung_FFB | 28.06 | 59.601 | 6.998 | 29.59 | 59.601 | 6.998 | 0 | 0.06 | 0.057 | 0122Tra0000010023 | m | T110 | false | HI_UZV_HEA_STA_0,120_xxx | 0
Nebenträger | Wartung_FFB | 1 | Nebenträger | HEA 120 | 0.698 | Wartung_FFB | 28.06 | 58.101 | 6.998 | 29.59 | 58.101 | 6.998 | 0 | 0.06 | 0.057 | 0122Tra0000010134 | m | T110 | false | HI_UZV_HEA_STA_0,120_xxx | 0
Nebenträger | Wartung_FFB | 1 | Nebenträger | HEA 120 | 0.698 | Wartung_FFB | 28.06 | 56.601 | 6.998 | 29.59 | 56.601 | 6.998 | 0 | 0.06 | 0.057 | 0122Tra0000010245 | m | T110 | false | HI_UZV_HEA_STA_0,120_xxx | 0
Nebenträger | Wartung_FFB | 1 | Nebenträger | HEA 120 | 0.698 | Wartung_FFB | 28.06 | 55.101 | 6.998 | 29.59 | 55.101 | 6.998 | 0 | 0.06 | 0.057 | 0122Tra0000010393 | m | T110 | false | HI_UZV_HEA_STA_0,120_xxx | 0
Nebenträger | Wartung_FFB | 1 | Nebenträger | HEA 120 | 0.698 | Wartung_FFB | 28.06 | 53.601 | 6.998 | 29.59 | 53.601 | 6.998 | 0 | 0.06 | 0.057 | 0122Tra0000010467 | m | T110 | false | HI_UZV_HEA_STA_0,120_xxx | 0
Nebenträger | Wartung_FFB | 1 | Nebenträger | HEA 120 | 0.698 | Wartung_FFB | 29.61 | 68.601 | 6.998 | 32.24 | 68.601 | 6.998 | 0 | 0.06 | 0.057 | 0122Tra0000009358 | m | T110 | false | HI_UZV_HEA_STA_0,120_xxx | 0
Nebenträger | Wartung_FFB | 1 | Nebenträger | HEA 120 | 0.698 | Wartung_FFB | 29.61 | 67.101 | 6.998 | 32.24 | 67.101 | 6.998 | 0 | 0.06 | 0.057 | 0122Tra0000009470 | m | T110 | false | HI_UZV_HEA_STA_0,120_xxx | 0
Nebenträger | Wartung_FFB | 1 | Nebenträger | HEA 120 | 0.698 | Wartung_FFB | 29.61 | 65.601 | 6.998 | 32.24 | 65.601 | 6.998 | 0 | 0.06 | 0.057 | 0122Tra0000009581 | m | T110 | false | HI_UZV_HEA_STA_0,120_xxx | 0
Nebenträger | Wartung_FFB | 1 | Nebenträger | HEA 120 | 0.698 | Wartung_FFB | 29.61 | 64.101 | 6.998 | 32.24 | 64.101 | 6.998 | 0 | 0.06 | 0.057 | 0122Tra0000009692 | m | T110 | false | HI_UZV_HEA_STA_0,120_xxx | 0
Nebenträger | Wartung_FFB | 1 | Nebenträger | HEA 120 | 0.698 | Wartung_FFB | 29.61 | 62.601 | 6.998 | 32.24 | 62.601 | 6.998 | 0 | 0.06 | 0.057 | 0122Tra0000009803 | m | T110 | false | HI_UZV_HEA_STA_0,120_xxx | 0
Nebenträger | Wartung_FFB | 1 | Nebenträger | HEA 120 | 0.698 | Wartung_FFB | 29.61 | 61.101 | 6.998 | 32.24 | 61.101 | 6.998 | 0 | 0.06 | 0.057 | 0122Tra0000009914 | m | T110 | false | HI_UZV_HEA_STA_0,120_xxx | 0
Nebenträger | Wartung_FFB | 1 | Nebenträger | HEA 120 | 0.698 | Wartung_FFB | 29.61 | 59.601 | 6.998 | 32.24 | 59.601 | 6.998 | 0 | 0.06 | 0.057 | 0122Tra0000010025 | m | T110 | false | HI_UZV_HEA_STA_0,120_xxx | 0
Nebenträger | Wartung_FFB | 1 | Nebenträger | HEA 120 | 0.698 | Wartung_FFB | 29.61 | 58.101 | 6.998 | 32.24 | 58.101 | 6.998 | 0 | 0.06 | 0.057 | 0122Tra0000010136 | m | T110 | false | HI_UZV_HEA_STA_0,120_xxx | 0
Nebenträger | Wartung_FFB | 1 | Nebenträger | HEA 120 | 0.698 | Wartung_FFB | 29.61 | 56.601 | 6.998 | 32.24 | 56.601 | 6.998 | 0 | 0.06 | 0.057 | 0122Tra0000010247 | m | T110 | false | HI_UZV_HEA_STA_0,120_xxx | 0
Nebenträger | Wartung_FFB | 1 | Nebenträger | HEA 120 | 0.698 | Wartung_FFB | 29.61 | 55.101 | 6.998 | 32.24 | 55.101 | 6.998 | 0 | 0.06 | 0.057 | 0122Tra0000010395 | m | T110 | false | HI_UZV_HEA_STA_0,120_xxx | 0
Nebenträger | Wartung_FFB | 1 | Nebenträger | HEA 120 | 0.698 | Wartung_FFB | 29.61 | 53.601 | 6.998 | 32.24 | 53.601 | 6.998 | 0 | 0.06 | 0.057 | 0122Tra0000010469 | m | T110 | false | HI_UZV_HEA_STA_0,120_xxx | 0
Nebenträger | Wartung_FFB | 1 | Nebenträger | HEA 120 | 0.698 | Wartung_FFB | 32.26 | 68.601 | 6.998 | 34.04 | 68.601 | 6.998 | 0 | 0.06 | 0.057 | 0122Tra0000013690 | m | T110 | false | HI_UZV_HEA_STA_0,120_xxx | 0
Nebenträger | Wartung_FFB | 1 | Nebenträger | HEA 120 | 0.698 | Wartung_FFB | 32.26 | 67.101 | 6.998 | 34.04 | 67.101 | 6.998 | 0 | 0.06 | 0.057 | 0122Tra0000013692 | m | T110 | false | HI_UZV_HEA_STA_0,120_xxx | 0
Nebenträger | Wartung_FFB | 1 | Nebenträger | HEA 120 | 0.698 | Wartung_FFB | 32.26 | 65.601 | 6.998 | 34.04 | 65.601 | 6.998 | 0 | 0.06 | 0.057 | 0122Tra0000013694 | m | T110 | false | HI_UZV_HEA_STA_0,120_xxx | 0
Nebenträger | Wartung_FFB | 1 | Nebenträger | HEA 120 | 0.698 | Wartung_FFB | 32.26 | 64.101 | 6.998 | 34.04 | 64.101 | 6.998 | 0 | 0.06 | 0.057 | 0122Tra0000013696 | m | T110 | false | HI_UZV_HEA_STA_0,120_xxx | 0
Nebenträger | Wartung_FFB | 1 | Nebenträger | HEA 120 | 0.698 | Wartung_FFB | 32.26 | 62.601 | 6.998 | 34.04 | 62.601 | 6.998 | 0 | 0.06 | 0.057 | 0122Tra0000013698 | m | T110 | false | HI_UZV_HEA_STA_0,120_xxx | 0
Nebenträger | Wartung_FFB | 1 | Nebenträger | HEA 120 | 0.698 | Wartung_FFB | 32.26 | 61.101 | 6.998 | 34.04 | 61.101 | 6.998 | 0 | 0.06 | 0.057 | 0122Tra0000013700 | m | T110 | false | HI_UZV_HEA_STA_0,120_xxx | 0
Nebenträger | Wartung_FFB | 1 | Nebenträger | HEA 120 | 0.698 | Wartung_FFB | 32.26 | 59.601 | 6.998 | 34.04 | 59.601 | 6.998 | 0 | 0.06 | 0.057 | 0122Tra0000013702 | m | T110 | false | HI_UZV_HEA_STA_0,120_xxx | 0
Nebenträger | Wartung_FFB | 1 | Nebenträger | HEA 120 | 0.698 | Wartung_FFB | 32.26 | 58.101 | 6.998 | 34.04 | 58.101 | 6.998 | 0 | 0.06 | 0.057 | 0122Tra0000013704 | m | T110 | false | HI_UZV_HEA_STA_0,120_xxx | 0
Nebenträger | Wartung_FFB | 1 | Nebenträger | HEA 120 | 0.698 | Wartung_FFB | 32.26 | 56.601 | 6.998 | 34.04 | 56.601 | 6.998 | 0 | 0.06 | 0.057 | 0122Tra0000013706 | m | T110 | false | HI_UZV_HEA_STA_0,120_xxx | 0
Nebenträger | Wartung_FFB | 1 | Nebenträger | HEA 120 | 0.698 | Wartung_FFB | 32.26 | 55.101 | 6.998 | 34.04 | 55.101 | 6.998 | 0 | 0.06 | 0.057 | 0122Tra0000013708 | m | T110 | false | HI_UZV_HEA_STA_0,120_xxx | 0
Nebenträger | Wartung_FFB | 1 | Nebenträger | HEA 120 | 0.698 | Wartung_FFB | 32.26 | 53.601 | 6.998 | 34.04 | 53.601 | 6.998 | 0 | 0.06 | 0.057 | 0122Tra0000013710 | m | T110 | false | HI_UZV_HEA_STA_0,120_xxx | 0
Nebenträger | Wartung_FFB | 1 | Nebenträger | HEA 120 | 0.698 | Wartung_FFB | 79.06 | 68.601 | 6.998 | 81.54 | 68.601 | 6.998 | 0 | 0.06 | 0.057 | 0122Tra0000009301 | m | T110 | false | HI_UZV_HEA_STA_0,120_xxx | 0
Nebenträger | Wartung_FFB | 1 | Nebenträger | HEA 120 | 0.698 | Wartung_FFB | 79.06 | 67.101 | 6.998 | 81.54 | 67.101 | 6.998 | 0 | 0.06 | 0.057 | 0122Tra0000009430 | m | T110 | false | HI_UZV_HEA_STA_0,120_xxx | 0
Nebenträger | Wartung_FFB | 1 | Nebenträger | HEA 120 | 0.698 | Wartung_FFB | 79.06 | 65.601 | 6.998 | 81.54 | 65.601 | 6.998 | 0 | 0.06 | 0.057 | 0122Tra0000009541 | m | T110 | false | HI_UZV_HEA_STA_0,120_xxx | 0
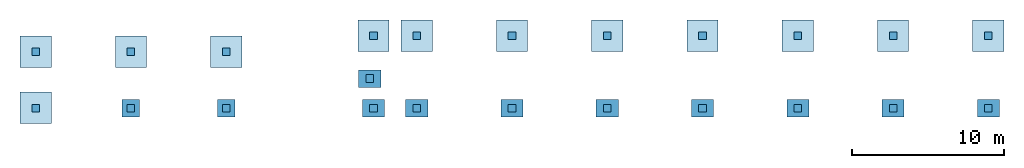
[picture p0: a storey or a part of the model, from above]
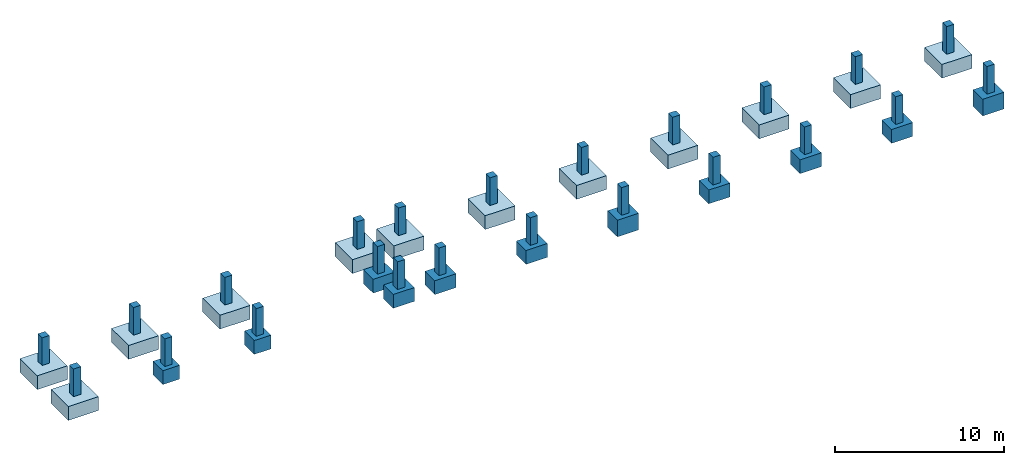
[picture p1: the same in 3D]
Properties of the parts of a building model (IFC2X3), part 7 of 25

# IfcBeam (2372)
Name | In | Faktor | Bezeichnung = Name | Profilname | Mantelfläche/lfm | Ebene | Achsenstartpunkt (X) (m) | Achsenstartpunkt (Y) (m) | Achsenstartpunkt (Z) (m) | Achsenendpunkt (X) (m) | Achsenendpunkt (Y) (m) | Achsenendpunkt (Z) (m) | Objektdrehwinkel | Schwerpunkt X (m) | Schwerpunkt Y (m) | Allright_Bauteil_ID | Abrechnungsart | Positionsnummer | Außenbauteil | Reference | Drehwinkel = Slope (deg)
Nebenträger | Wartung_FFB | 1 | Nebenträger | HEA 120 | 0.698 | Wartung_FFB | 79.06 | 64.101 | 6.998 | 81.54 | 64.101 | 6.998 | 0 | 0.06 | 0.057 | 0122Tra0000009652 | m | T110 | false | HI_UZV_HEA_STA_0,120_xxx | 0
Nebenträger | Wartung_FFB | 1 | Nebenträger | HEA 120 | 0.698 | Wartung_FFB | 79.06 | 62.601 | 6.998 | 81.54 | 62.601 | 6.998 | 0 | 0.06 | 0.057 | 0122Tra0000009763 | m | T110 | false | HI_UZV_HEA_STA_0,120_xxx | 0
Nebenträger | Wartung_FFB | 1 | Nebenträger | HEA 120 | 0.698 | Wartung_FFB | 79.06 | 61.101 | 6.998 | 81.54 | 61.101 | 6.998 | 0 | 0.06 | 0.057 | 0122Tra0000009874 | m | T110 | false | HI_UZV_HEA_STA_0,120_xxx | 0
Nebenträger | Wartung_FFB | 1 | Nebenträger | HEA 120 | 0.698 | Wartung_FFB | 79.06 | 59.601 | 6.998 | 81.54 | 59.601 | 6.998 | 0 | 0.06 | 0.057 | 0122Tra0000009985 | m | T110 | false | HI_UZV_HEA_STA_0,120_xxx | 0
Nebenträger | Wartung_FFB | 1 | Nebenträger | HEA 120 | 0.698 | Wartung_FFB | 79.06 | 58.101 | 6.998 | 81.54 | 58.101 | 6.998 | 0 | 0.06 | 0.057 | 0122Tra0000010096 | m | T110 | false | HI_UZV_HEA_STA_0,120_xxx | 0
Nebenträger | Wartung_FFB | 1 | Nebenträger | HEA 120 | 0.698 | Wartung_FFB | 79.06 | 56.601 | 6.998 | 81.54 | 56.601 | 6.998 | 0 | 0.06 | 0.057 | 0122Tra0000010207 | m | T110 | false | HI_UZV_HEA_STA_0,120_xxx | 0
Nebenträger | Wartung_FFB | 1 | Nebenträger | HEA 120 | 0.698 | Wartung_FFB | 79.06 | 55.101 | 6.998 | 81.54 | 55.101 | 6.998 | 0 | 0.06 | 0.057 | 0122Tra0000010355 | m | T110 | false | HI_UZV_HEA_STA_0,120_xxx | 0
Nebenträger | Wartung_FFB | 1 | Nebenträger | HEA 120 | 0.698 | Wartung_FFB | 79.06 | 53.601 | 6.998 | 81.54 | 53.601 | 6.998 | 0 | 0.06 | 0.057 | 0122Tra0000010429 | m | T110 | false | HI_UZV_HEA_STA_0,120_xxx | 0
Nebenträger | Wartung_FFB | 1 | Nebenträger | HEA 120 | 0.698 | Wartung_FFB | 81.56 | 68.601 | 6.998 | 84.34 | 68.601 | 6.998 | 0 | 0.06 | 0.057 | 0122Tra0000009303 | m | T110 | false | HI_UZV_HEA_STA_0,120_xxx | 0
Nebenträger | Wartung_FFB | 1 | Nebenträger | HEA 120 | 0.698 | Wartung_FFB | 81.56 | 67.101 | 6.998 | 84.34 | 67.101 | 6.998 | 0 | 0.06 | 0.057 | 0122Tra0000009432 | m | T110 | false | HI_UZV_HEA_STA_0,120_xxx | 0
Nebenträger | Wartung_FFB | 1 | Nebenträger | HEA 120 | 0.698 | Wartung_FFB | 81.56 | 65.601 | 6.998 | 84.34 | 65.601 | 6.998 | 0 | 0.06 | 0.057 | 0122Tra0000009543 | m | T110 | false | HI_UZV_HEA_STA_0,120_xxx | 0
Nebenträger | Wartung_FFB | 1 | Nebenträger | HEA 120 | 0.698 | Wartung_FFB | 81.56 | 64.101 | 6.998 | 84.34 | 64.101 | 6.998 | 0 | 0.06 | 0.057 | 0122Tra0000009654 | m | T110 | false | HI_UZV_HEA_STA_0,120_xxx | 0
Nebenträger | Wartung_FFB | 1 | Nebenträger | HEA 120 | 0.698 | Wartung_FFB | 81.56 | 62.601 | 6.998 | 84.34 | 62.601 | 6.998 | 0 | 0.06 | 0.057 | 0122Tra0000009765 | m | T110 | false | HI_UZV_HEA_STA_0,120_xxx | 0
Nebenträger | Wartung_FFB | 1 | Nebenträger | HEA 120 | 0.698 | Wartung_FFB | 81.56 | 61.101 | 6.998 | 84.34 | 61.101 | 6.998 | 0 | 0.06 | 0.057 | 0122Tra0000009876 | m | T110 | false | HI_UZV_HEA_STA_0,120_xxx | 0
Nebenträger | Wartung_FFB | 1 | Nebenträger | HEA 120 | 0.698 | Wartung_FFB | 81.56 | 59.601 | 6.998 | 84.34 | 59.601 | 6.998 | 0 | 0.06 | 0.057 | 0122Tra0000009987 | m | T110 | false | HI_UZV_HEA_STA_0,120_xxx | 0
Nebenträger | Wartung_FFB | 1 | Nebenträger | HEA 120 | 0.698 | Wartung_FFB | 81.56 | 58.101 | 6.998 | 84.34 | 58.101 | 6.998 | 0 | 0.06 | 0.057 | 0122Tra0000010098 | m | T110 | false | HI_UZV_HEA_STA_0,120_xxx | 0
Nebenträger | Wartung_FFB | 1 | Nebenträger | HEA 120 | 0.698 | Wartung_FFB | 81.56 | 56.601 | 6.998 | 84.34 | 56.601 | 6.998 | 0 | 0.06 | 0.057 | 0122Tra0000010209 | m | T110 | false | HI_UZV_HEA_STA_0,120_xxx | 0
Nebenträger | Wartung_FFB | 1 | Nebenträger | HEA 120 | 0.698 | Wartung_FFB | 81.56 | 55.101 | 6.998 | 84.34 | 55.101 | 6.998 | 0 | 0.06 | 0.057 | 0122Tra0000010357 | m | T110 | false | HI_UZV_HEA_STA_0,120_xxx | 0
Nebenträger | Wartung_FFB | 1 | Nebenträger | HEA 120 | 0.698 | Wartung_FFB | 81.56 | 53.601 | 6.998 | 84.34 | 53.601 | 6.998 | 0 | 0.06 | 0.057 | 0122Tra0000010431 | m | T110 | false | HI_UZV_HEA_STA_0,120_xxx | 0
Nebenträger | Wartung_FFB | 1 | Nebenträger | HEA 120 | 0.698 | Wartung_FFB | 84.36 | 68.601 | 6.998 | 86.74 | 68.601 | 6.998 | 0 | 0.06 | 0.057 | 0122Tra0000009305 | m | T110 | false | HI_UZV_HEA_STA_0,120_xxx | 0
Nebenträger | Wartung_FFB | 1 | Nebenträger | HEA 120 | 0.698 | Wartung_FFB | 84.36 | 67.101 | 6.998 | 86.74 | 67.101 | 6.998 | 0 | 0.06 | 0.057 | 0122Tra0000009434 | m | T110 | false | HI_UZV_HEA_STA_0,120_xxx | 0
Nebenträger | Wartung_FFB | 1 | Nebenträger | HEA 120 | 0.698 | Wartung_FFB | 84.36 | 65.601 | 6.998 | 86.74 | 65.601 | 6.998 | 0 | 0.06 | 0.057 | 0122Tra0000009545 | m | T110 | false | HI_UZV_HEA_STA_0,120_xxx | 0
Nebenträger | Wartung_FFB | 1 | Nebenträger | HEA 120 | 0.698 | Wartung_FFB | 84.36 | 64.101 | 6.998 | 86.74 | 64.101 | 6.998 | 0 | 0.06 | 0.057 | 0122Tra0000009656 | m | T110 | false | HI_UZV_HEA_STA_0,120_xxx | 0
Nebenträger | Wartung_FFB | 1 | Nebenträger | HEA 120 | 0.698 | Wartung_FFB | 84.36 | 62.601 | 6.998 | 86.74 | 62.601 | 6.998 | 0 | 0.06 | 0.057 | 0122Tra0000009767 | m | T110 | false | HI_UZV_HEA_STA_0,120_xxx | 0
Nebenträger | Wartung_FFB | 1 | Nebenträger | HEA 120 | 0.698 | Wartung_FFB | 84.36 | 61.101 | 6.998 | 86.74 | 61.101 | 6.998 | 0 | 0.06 | 0.057 | 0122Tra0000009878 | m | T110 | false | HI_UZV_HEA_STA_0,120_xxx | 0
Nebenträger | Wartung_FFB | 1 | Nebenträger | HEA 120 | 0.698 | Wartung_FFB | 84.36 | 59.601 | 6.998 | 86.74 | 59.601 | 6.998 | 0 | 0.06 | 0.057 | 0122Tra0000009989 | m | T110 | false | HI_UZV_HEA_STA_0,120_xxx | 0
Nebenträger | Wartung_FFB | 1 | Nebenträger | HEA 120 | 0.698 | Wartung_FFB | 84.36 | 58.101 | 6.998 | 86.74 | 58.101 | 6.998 | 0 | 0.06 | 0.057 | 0122Tra0000010100 | m | T110 | false | HI_UZV_HEA_STA_0,120_xxx | 0
Nebenträger | Wartung_FFB | 1 | Nebenträger | HEA 120 | 0.698 | Wartung_FFB | 84.36 | 56.601 | 6.998 | 86.74 | 56.601 | 6.998 | 0 | 0.06 | 0.057 | 0122Tra0000010211 | m | T110 | false | HI_UZV_HEA_STA_0,120_xxx | 0
Nebenträger | Wartung_FFB | 1 | Nebenträger | HEA 120 | 0.698 | Wartung_FFB | 84.36 | 55.101 | 6.998 | 86.74 | 55.101 | 6.998 | 0 | 0.06 | 0.057 | 0122Tra0000010359 | m | T110 | false | HI_UZV_HEA_STA_0,120_xxx | 0
Nebenträger | Wartung_FFB | 1 | Nebenträger | HEA 120 | 0.698 | Wartung_FFB | 84.36 | 53.601 | 6.998 | 86.74 | 53.601 | 6.998 | 0 | 0.06 | 0.057 | 0122Tra0000010433 | m | T110 | false | HI_UZV_HEA_STA_0,120_xxx | 0
Nebenträger | Wartung_FFB | 1 | Nebenträger | HEA 120 | 0.698 | Wartung_FFB | 86.76 | 68.601 | 6.998 | 89.49 | 68.601 | 6.998 | 0 | 0.06 | 0.057 | 0122Tra0000009307 | m | T110 | false | HI_UZV_HEA_STA_0,120_xxx | 0
Nebenträger | Wartung_FFB | 1 | Nebenträger | HEA 120 | 0.698 | Wartung_FFB | 86.76 | 67.101 | 6.998 | 89.49 | 67.101 | 6.998 | 0 | 0.06 | 0.057 | 0122Tra0000009436 | m | T110 | false | HI_UZV_HEA_STA_0,120_xxx | 0
Nebenträger | Wartung_FFB | 1 | Nebenträger | HEA 120 | 0.698 | Wartung_FFB | 86.76 | 65.601 | 6.998 | 89.49 | 65.601 | 6.998 | 0 | 0.06 | 0.057 | 0122Tra0000009547 | m | T110 | false | HI_UZV_HEA_STA_0,120_xxx | 0
Nebenträger | Wartung_FFB | 1 | Nebenträger | HEA 120 | 0.698 | Wartung_FFB | 86.76 | 64.101 | 6.998 | 89.49 | 64.101 | 6.998 | 0 | 0.06 | 0.057 | 0122Tra0000009658 | m | T110 | false | HI_UZV_HEA_STA_0,120_xxx | 0
Nebenträger | Wartung_FFB | 1 | Nebenträger | HEA 120 | 0.698 | Wartung_FFB | 86.76 | 62.601 | 6.998 | 89.49 | 62.601 | 6.998 | 0 | 0.06 | 0.057 | 0122Tra0000009769 | m | T110 | false | HI_UZV_HEA_STA_0,120_xxx | 0
Nebenträger | Wartung_FFB | 1 | Nebenträger | HEA 120 | 0.698 | Wartung_FFB | 86.76 | 61.101 | 6.998 | 89.49 | 61.101 | 6.998 | 0 | 0.06 | 0.057 | 0122Tra0000009880 | m | T110 | false | HI_UZV_HEA_STA_0,120_xxx | 0
Nebenträger | Wartung_FFB | 1 | Nebenträger | HEA 120 | 0.698 | Wartung_FFB | 86.76 | 59.601 | 6.998 | 89.49 | 59.601 | 6.998 | 0 | 0.06 | 0.057 | 0122Tra0000009991 | m | T110 | false | HI_UZV_HEA_STA_0,120_xxx | 0
Nebenträger | Wartung_FFB | 1 | Nebenträger | HEA 120 | 0.698 | Wartung_FFB | 86.76 | 58.101 | 6.998 | 89.49 | 58.101 | 6.998 | 0 | 0.06 | 0.057 | 0122Tra0000010102 | m | T110 | false | HI_UZV_HEA_STA_0,120_xxx | 0
Nebenträger | Wartung_FFB | 1 | Nebenträger | HEA 120 | 0.698 | Wartung_FFB | 86.76 | 56.601 | 6.998 | 89.49 | 56.601 | 6.998 | 0 | 0.06 | 0.057 | 0122Tra0000010213 | m | T110 | false | HI_UZV_HEA_STA_0,120_xxx | 0
Nebenträger | Wartung_FFB | 1 | Nebenträger | HEA 120 | 0.698 | Wartung_FFB | 86.76 | 55.101 | 6.998 | 89.49 | 55.101 | 6.998 | 0 | 0.06 | 0.057 | 0122Tra0000010361 | m | T110 | false | HI_UZV_HEA_STA_0,120_xxx | 0
Nebenträger | Wartung_FFB | 1 | Nebenträger | HEA 120 | 0.698 | Wartung_FFB | 86.76 | 53.601 | 6.998 | 89.49 | 53.601 | 6.998 | 0 | 0.06 | 0.057 | 0122Tra0000010435 | m | T110 | false | HI_UZV_HEA_STA_0,120_xxx | 0
Nebenträger | Wartung_FFB | 1 | Nebenträger | HEA 120 | 0.698 | Wartung_FFB | 89.51 | 68.601 | 6.998 | 91.89 | 68.601 | 6.998 | 0 | 0.06 | 0.057 | 0122Tra0000009309 | m | T110 | false | HI_UZV_HEA_STA_0,120_xxx | 0
Nebenträger | Wartung_FFB | 1 | Nebenträger | HEA 120 | 0.698 | Wartung_FFB | 89.51 | 67.101 | 6.998 | 91.89 | 67.101 | 6.998 | 0 | 0.06 | 0.057 | 0122Tra0000009438 | m | T110 | false | HI_UZV_HEA_STA_0,120_xxx | 0
Nebenträger | Wartung_FFB | 1 | Nebenträger | HEA 120 | 0.698 | Wartung_FFB | 89.51 | 65.601 | 6.998 | 91.89 | 65.601 | 6.998 | 0 | 0.06 | 0.057 | 0122Tra0000009549 | m | T110 | false | HI_UZV_HEA_STA_0,120_xxx | 0
Nebenträger | Wartung_FFB | 1 | Nebenträger | HEA 120 | 0.698 | Wartung_FFB | 89.51 | 64.101 | 6.998 | 91.89 | 64.101 | 6.998 | 0 | 0.06 | 0.057 | 0122Tra0000009660 | m | T110 | false | HI_UZV_HEA_STA_0,120_xxx | 0
Nebenträger | Wartung_FFB | 1 | Nebenträger | HEA 120 | 0.698 | Wartung_FFB | 89.51 | 62.601 | 6.998 | 91.89 | 62.601 | 6.998 | 0 | 0.06 | 0.057 | 0122Tra0000009771 | m | T110 | false | HI_UZV_HEA_STA_0,120_xxx | 0
Nebenträger | Wartung_FFB | 1 | Nebenträger | HEA 120 | 0.698 | Wartung_FFB | 89.51 | 61.101 | 6.998 | 91.89 | 61.101 | 6.998 | 0 | 0.06 | 0.057 | 0122Tra0000009882 | m | T110 | false | HI_UZV_HEA_STA_0,120_xxx | 0
Nebenträger | Wartung_FFB | 1 | Nebenträger | HEA 120 | 0.698 | Wartung_FFB | 89.51 | 59.601 | 6.998 | 91.89 | 59.601 | 6.998 | 0 | 0.06 | 0.057 | 0122Tra0000009993 | m | T110 | false | HI_UZV_HEA_STA_0,120_xxx | 0
Nebenträger | Wartung_FFB | 1 | Nebenträger | HEA 120 | 0.698 | Wartung_FFB | 89.51 | 58.101 | 6.998 | 91.89 | 58.101 | 6.998 | 0 | 0.06 | 0.057 | 0122Tra0000010104 | m | T110 | false | HI_UZV_HEA_STA_0,120_xxx | 0
Nebenträger | Wartung_FFB | 1 | Nebenträger | HEA 120 | 0.698 | Wartung_FFB | 89.51 | 56.601 | 6.998 | 91.89 | 56.601 | 6.998 | 0 | 0.06 | 0.057 | 0122Tra0000010215 | m | T110 | false | HI_UZV_HEA_STA_0,120_xxx | 0
Nebenträger | Wartung_FFB | 1 | Nebenträger | HEA 120 | 0.698 | Wartung_FFB | 89.51 | 55.101 | 6.998 | 91.89 | 55.101 | 6.998 | 0 | 0.06 | 0.057 | 0122Tra0000010363 | m | T110 | false | HI_UZV_HEA_STA_0,120_xxx | 0
Nebenträger | Wartung_FFB | 1 | Nebenträger | HEA 120 | 0.698 | Wartung_FFB | 89.51 | 53.601 | 6.998 | 91.89 | 53.601 | 6.998 | 0 | 0.06 | 0.057 | 0122Tra0000010437 | m | T110 | false | HI_UZV_HEA_STA_0,120_xxx | 0
Nebenträger | Wartung_FFB | 1 | Nebenträger | HEA 120 | 0.698 | Wartung_FFB | 94.71 | 68.601 | 6.998 | 97.04 | 68.601 | 6.998 | 0 | 0.06 | 0.057 | 0122Tra0000009311 | m | T110 | false | HI_UZV_HEA_STA_0,120_xxx | 0
Nebenträger | Wartung_FFB | 1 | Nebenträger | HEA 120 | 0.698 | Wartung_FFB | 94.71 | 67.101 | 6.998 | 97.04 | 67.101 | 6.998 | 0 | 0.06 | 0.057 | 0122Tra0000009440 | m | T110 | false | HI_UZV_HEA_STA_0,120_xxx | 0
Nebenträger | Wartung_FFB | 1 | Nebenträger | HEA 120 | 0.698 | Wartung_FFB | 94.71 | 65.601 | 6.998 | 97.04 | 65.601 | 6.998 | 0 | 0.06 | 0.057 | 0122Tra0000009551 | m | T110 | false | HI_UZV_HEA_STA_0,120_xxx | 0
Nebenträger | Wartung_FFB | 1 | Nebenträger | HEA 120 | 0.698 | Wartung_FFB | 94.71 | 64.101 | 6.998 | 97.04 | 64.101 | 6.998 | 0 | 0.06 | 0.057 | 0122Tra0000009662 | m | T110 | false | HI_UZV_HEA_STA_0,120_xxx | 0
Nebenträger | Wartung_FFB | 1 | Nebenträger | HEA 120 | 0.698 | Wartung_FFB | 94.71 | 62.601 | 6.998 | 97.04 | 62.601 | 6.998 | 0 | 0.06 | 0.057 | 0122Tra0000009773 | m | T110 | false | HI_UZV_HEA_STA_0,120_xxx | 0
Nebenträger | Wartung_FFB | 1 | Nebenträger | HEA 120 | 0.698 | Wartung_FFB | 94.71 | 61.101 | 6.998 | 97.04 | 61.101 | 6.998 | 0 | 0.06 | 0.057 | 0122Tra0000009884 | m | T110 | false | HI_UZV_HEA_STA_0,120_xxx | 0
Nebenträger | Wartung_FFB | 1 | Nebenträger | HEA 120 | 0.698 | Wartung_FFB | 94.71 | 59.601 | 6.998 | 97.04 | 59.601 | 6.998 | 0 | 0.06 | 0.057 | 0122Tra0000009995 | m | T110 | false | HI_UZV_HEA_STA_0,120_xxx | 0
Nebenträger | Wartung_FFB | 1 | Nebenträger | HEA 120 | 0.698 | Wartung_FFB | 94.71 | 58.101 | 6.998 | 97.04 | 58.101 | 6.998 | 0 | 0.06 | 0.057 | 0122Tra0000010106 | m | T110 | false | HI_UZV_HEA_STA_0,120_xxx | 0
Nebenträger | Wartung_FFB | 1 | Nebenträger | HEA 120 | 0.698 | Wartung_FFB | 94.71 | 56.601 | 6.998 | 97.04 | 56.601 | 6.998 | 0 | 0.06 | 0.057 | 0122Tra0000010217 | m | T110 | false | HI_UZV_HEA_STA_0,120_xxx | 0
Nebenträger | Wartung_FFB | 1 | Nebenträger | HEA 120 | 0.698 | Wartung_FFB | 94.71 | 55.101 | 6.998 | 97.04 | 55.101 | 6.998 | 0 | 0.06 | 0.057 | 0122Tra0000010365 | m | T110 | false | HI_UZV_HEA_STA_0,120_xxx | 0
Nebenträger | Wartung_FFB | 1 | Nebenträger | HEA 120 | 0.698 | Wartung_FFB | 94.71 | 53.601 | 6.998 | 97.04 | 53.601 | 6.998 | 0 | 0.06 | 0.057 | 0122Tra0000010439 | m | T110 | false | HI_UZV_HEA_STA_0,120_xxx | 0
Nebenträger | Wartung_FFB | 1 | Nebenträger | HEA 120 | 0.698 | Wartung_FFB | 91.91 | 68.601 | 6.998 | 94.69 | 68.601 | 6.998 | 0 | 0.06 | 0.057 | 0122Tra0000013965 | m | T110 | false | HI_UZV_HEA_STA_0,120_xxx | 0
Nebenträger | Wartung_FFB | 1 | Nebenträger | HEA 120 | 0.698 | Wartung_FFB | 91.91 | 67.101 | 6.998 | 94.69 | 67.101 | 6.998 | 0 | 0.06 | 0.057 | 0122Tra0000013967 | m | T110 | false | HI_UZV_HEA_STA_0,120_xxx | 0
Nebenträger | Wartung_FFB | 1 | Nebenträger | HEA 120 | 0.698 | Wartung_FFB | 91.91 | 65.601 | 6.998 | 94.69 | 65.601 | 6.998 | 0 | 0.06 | 0.057 | 0122Tra0000013969 | m | T110 | false | HI_UZV_HEA_STA_0,120_xxx | 0
Nebenträger | Wartung_FFB | 1 | Nebenträger | HEA 120 | 0.698 | Wartung_FFB | 91.91 | 64.101 | 6.998 | 94.69 | 64.101 | 6.998 | 0 | 0.06 | 0.057 | 0122Tra0000013971 | m | T110 | false | HI_UZV_HEA_STA_0,120_xxx | 0
Nebenträger | Wartung_FFB | 1 | Nebenträger | HEA 120 | 0.698 | Wartung_FFB | 91.91 | 62.601 | 6.998 | 94.69 | 62.601 | 6.998 | 0 | 0.06 | 0.057 | 0122Tra0000013973 | m | T110 | false | HI_UZV_HEA_STA_0,120_xxx | 0
Nebenträger | Wartung_FFB | 1 | Nebenträger | HEA 120 | 0.698 | Wartung_FFB | 91.91 | 61.101 | 6.998 | 94.69 | 61.101 | 6.998 | 0 | 0.06 | 0.057 | 0122Tra0000013975 | m | T110 | false | HI_UZV_HEA_STA_0,120_xxx | 0
Nebenträger | Wartung_FFB | 1 | Nebenträger | HEA 120 | 0.698 | Wartung_FFB | 91.91 | 59.601 | 6.998 | 94.69 | 59.601 | 6.998 | 0 | 0.06 | 0.057 | 0122Tra0000013977 | m | T110 | false | HI_UZV_HEA_STA_0,120_xxx | 0
Nebenträger | Wartung_FFB | 1 | Nebenträger | HEA 120 | 0.698 | Wartung_FFB | 91.91 | 58.101 | 6.998 | 94.69 | 58.101 | 6.998 | 0 | 0.06 | 0.057 | 0122Tra0000013979 | m | T110 | false | HI_UZV_HEA_STA_0,120_xxx | 0
Nebenträger | Wartung_FFB | 1 | Nebenträger | HEA 120 | 0.698 | Wartung_FFB | 91.91 | 56.601 | 6.998 | 94.69 | 56.601 | 6.998 | 0 | 0.06 | 0.057 | 0122Tra0000013981 | m | T110 | false | HI_UZV_HEA_STA_0,120_xxx | 0
Nebenträger | Wartung_FFB | 1 | Nebenträger | HEA 120 | 0.698 | Wartung_FFB | 91.91 | 55.101 | 6.998 | 94.69 | 55.101 | 6.998 | 0 | 0.06 | 0.057 | 0122Tra0000013983 | m | T110 | false | HI_UZV_HEA_STA_0,120_xxx | 0
Nebenträger | Wartung_FFB | 1 | Nebenträger | HEA 120 | 0.698 | Wartung_FFB | 91.91 | 53.601 | 6.998 | 94.69 | 53.601 | 6.998 | 0 | 0.06 | 0.057 | 0122Tra0000013985 | m | T110 | false | HI_UZV_HEA_STA_0,120_xxx | 0
Nebenträger | Wartung_FFB | 1 | Nebenträger | HEA 120 | 0.698 | Wartung_FFB | 91.91 | 84.226 | 6.998 | 94.04 | 84.226 | 6.998 | 0 | 0.06 | 0.057 | 0122Tra0000008294 | m | T110 | false | HI_UZV_HEA_STA_0,120_xxx | 0
Nebenträger | Wartung_FFB | 1 | Nebenträger | HEA 120 | 0.698 | Wartung_FFB | 91.91 | 82.726 | 6.998 | 94.04 | 82.726 | 6.998 | 0 | 0.06 | 0.057 | 0122Tra0000008421 | m | T110 | false | HI_UZV_HEA_STA_0,120_xxx | 0
Nebenträger | Wartung_FFB | 1 | Nebenträger | HEA 120 | 0.698 | Wartung_FFB | 91.91 | 81.226 | 6.998 | 94.04 | 81.226 | 6.998 | 0 | 0.06 | 0.057 | 0122Tra0000008550 | m | T110 | false | HI_UZV_HEA_STA_0,120_xxx | 0
Nebenträger | Wartung_FFB | 1 | Nebenträger | HEA 120 | 0.698 | Wartung_FFB | 91.91 | 79.726 | 6.998 | 94.04 | 79.726 | 6.998 | 0 | 0.06 | 0.057 | 0122Tra0000008661 | m | T110 | false | HI_UZV_HEA_STA_0,120_xxx | 0
Nebenträger | Wartung_FFB | 1 | Nebenträger | HEA 120 | 0.698 | Wartung_FFB | 91.91 | 78.226 | 6.998 | 94.04 | 78.226 | 6.998 | 0 | 0.06 | 0.057 | 0122Tra0000008772 | m | T110 | false | HI_UZV_HEA_STA_0,120_xxx | 0
Nebenträger | Wartung_FFB | 1 | Nebenträger | HEA 120 | 0.698 | Wartung_FFB | 91.91 | 76.726 | 6.998 | 94.04 | 76.726 | 6.998 | 0 | 0.06 | 0.057 | 0122Tra0000008883 | m | T110 | false | HI_UZV_HEA_STA_0,120_xxx | 0
Nebenträger | Wartung_FFB | 1 | Nebenträger | HEA 120 | 0.698 | Wartung_FFB | 91.91 | 75.226 | 6.998 | 94.04 | 75.226 | 6.998 | 0 | 0.06 | 0.057 | 0122Tra0000008994 | m | T110 | false | HI_UZV_HEA_STA_0,120_xxx | 0
Nebenträger | Wartung_FFB | 1 | Nebenträger | HEA 120 | 0.698 | Wartung_FFB | 91.91 | 73.726 | 6.998 | 94.04 | 73.726 | 6.998 | 0 | 0.06 | 0.057 | 0122Tra0000009105 | m | T110 | false | HI_UZV_HEA_STA_0,120_xxx | 0
Nebenträger | Wartung_FFB | 1 | Nebenträger | HEA 120 | 0.698 | Wartung_FFB | 91.91 | 72.226 | 6.998 | 94.04 | 72.226 | 6.998 | 0 | 0.06 | 0.057 | 0122Tra0000009216 | m | T110 | false | HI_UZV_HEA_STA_0,120_xxx | 0
Nebenträger | Wartung_FFB | 1 | Nebenträger | HEA 120 | 0.698 | Wartung_FFB | 89.51 | 84.226 | 6.998 | 91.89 | 84.226 | 6.998 | 0 | 0.06 | 0.057 | 0122Tra0000008291 | m | T110 | false | HI_UZV_HEA_STA_0,120_xxx | 0
Nebenträger | Wartung_FFB | 1 | Nebenträger | HEA 120 | 0.698 | Wartung_FFB | 89.51 | 82.726 | 6.998 | 91.89 | 82.726 | 6.998 | 0 | 0.06 | 0.057 | 0122Tra0000008419 | m | T110 | false | HI_UZV_HEA_STA_0,120_xxx | 0
Nebenträger | Wartung_FFB | 1 | Nebenträger | HEA 120 | 0.698 | Wartung_FFB | 89.51 | 81.226 | 6.998 | 91.89 | 81.226 | 6.998 | 0 | 0.06 | 0.057 | 0122Tra0000008548 | m | T110 | false | HI_UZV_HEA_STA_0,120_xxx | 0
Nebenträger | Wartung_FFB | 1 | Nebenträger | HEA 120 | 0.698 | Wartung_FFB | 89.51 | 79.726 | 6.998 | 91.89 | 79.726 | 6.998 | 0 | 0.06 | 0.057 | 0122Tra0000008659 | m | T110 | false | HI_UZV_HEA_STA_0,120_xxx | 0
Nebenträger | Wartung_FFB | 1 | Nebenträger | HEA 120 | 0.698 | Wartung_FFB | 89.51 | 78.226 | 6.998 | 91.89 | 78.226 | 6.998 | 0 | 0.06 | 0.057 | 0122Tra0000008770 | m | T110 | false | HI_UZV_HEA_STA_0,120_xxx | 0
Nebenträger | Wartung_FFB | 1 | Nebenträger | HEA 120 | 0.698 | Wartung_FFB | 89.51 | 76.726 | 6.998 | 91.89 | 76.726 | 6.998 | 0 | 0.06 | 0.057 | 0122Tra0000008881 | m | T110 | false | HI_UZV_HEA_STA_0,120_xxx | 0
Nebenträger | Wartung_FFB | 1 | Nebenträger | HEA 120 | 0.698 | Wartung_FFB | 89.51 | 75.226 | 6.998 | 91.89 | 75.226 | 6.998 | 0 | 0.06 | 0.057 | 0122Tra0000008992 | m | T110 | false | HI_UZV_HEA_STA_0,120_xxx | 0
Nebenträger | Wartung_FFB | 1 | Nebenträger | HEA 120 | 0.698 | Wartung_FFB | 89.51 | 73.726 | 6.998 | 91.89 | 73.726 | 6.998 | 0 | 0.06 | 0.057 | 0122Tra0000009103 | m | T110 | false | HI_UZV_HEA_STA_0,120_xxx | 0
Nebenträger | Wartung_FFB | 1 | Nebenträger | HEA 120 | 0.698 | Wartung_FFB | 89.51 | 72.226 | 6.998 | 91.89 | 72.226 | 6.998 | 0 | 0.06 | 0.057 | 0122Tra0000009214 | m | T110 | false | HI_UZV_HEA_STA_0,120_xxx | 0
Nebenträger | Wartung_FFB | 1 | Nebenträger | HEA 120 | 0.698 | Wartung_FFB | 86.76 | 84.226 | 6.998 | 89.49 | 84.226 | 6.998 | 0 | 0.06 | 0.057 | 0122Tra0000008288 | m | T110 | false | HI_UZV_HEA_STA_0,120_xxx | 0
Nebenträger | Wartung_FFB | 1 | Nebenträger | HEA 120 | 0.698 | Wartung_FFB | 86.76 | 82.726 | 6.998 | 89.49 | 82.726 | 6.998 | 0 | 0.06 | 0.057 | 0122Tra0000008417 | m | T110 | false | HI_UZV_HEA_STA_0,120_xxx | 0
Nebenträger | Wartung_FFB | 1 | Nebenträger | HEA 120 | 0.698 | Wartung_FFB | 86.76 | 81.226 | 6.998 | 89.49 | 81.226 | 6.998 | 0 | 0.06 | 0.057 | 0122Tra0000008546 | m | T110 | false | HI_UZV_HEA_STA_0,120_xxx | 0
Nebenträger | Wartung_FFB | 1 | Nebenträger | HEA 120 | 0.698 | Wartung_FFB | 86.76 | 79.726 | 6.998 | 89.49 | 79.726 | 6.998 | 0 | 0.06 | 0.057 | 0122Tra0000008657 | m | T110 | false | HI_UZV_HEA_STA_0,120_xxx | 0
Nebenträger | Wartung_FFB | 1 | Nebenträger | HEA 120 | 0.698 | Wartung_FFB | 86.76 | 78.226 | 6.998 | 89.49 | 78.226 | 6.998 | 0 | 0.06 | 0.057 | 0122Tra0000008768 | m | T110 | false | HI_UZV_HEA_STA_0,120_xxx | 0
Nebenträger | Wartung_FFB | 1 | Nebenträger | HEA 120 | 0.698 | Wartung_FFB | 86.76 | 76.726 | 6.998 | 89.49 | 76.726 | 6.998 | 0 | 0.06 | 0.057 | 0122Tra0000008879 | m | T110 | false | HI_UZV_HEA_STA_0,120_xxx | 0
Nebenträger | Wartung_FFB | 1 | Nebenträger | HEA 120 | 0.698 | Wartung_FFB | 86.76 | 75.226 | 6.998 | 89.49 | 75.226 | 6.998 | 0 | 0.06 | 0.057 | 0122Tra0000008990 | m | T110 | false | HI_UZV_HEA_STA_0,120_xxx | 0
Nebenträger | Wartung_FFB | 1 | Nebenträger | HEA 120 | 0.698 | Wartung_FFB | 86.76 | 73.726 | 6.998 | 89.49 | 73.726 | 6.998 | 0 | 0.06 | 0.057 | 0122Tra0000009101 | m | T110 | false | HI_UZV_HEA_STA_0,120_xxx | 0
Nebenträger | Wartung_FFB | 1 | Nebenträger | HEA 120 | 0.698 | Wartung_FFB | 86.76 | 72.226 | 6.998 | 89.49 | 72.226 | 6.998 | 0 | 0.06 | 0.057 | 0122Tra0000009212 | m | T110 | false | HI_UZV_HEA_STA_0,120_xxx | 0
Nebenträger | Wartung_FFB | 1 | Nebenträger | HEA 120 | 0.698 | Wartung_FFB | 84.36 | 84.226 | 6.998 | 86.74 | 84.226 | 6.998 | 0 | 0.06 | 0.057 | 0122Tra0000014126 | m | T110 | false | HI_UZV_HEA_STA_0,120_xxx | 0
Nebenträger | Wartung_FFB | 1 | Nebenträger | HEA 120 | 0.698 | Wartung_FFB | 84.36 | 82.726 | 6.998 | 86.74 | 82.726 | 6.998 | 0 | 0.06 | 0.057 | 0122Tra0000014128 | m | T110 | false | HI_UZV_HEA_STA_0,120_xxx | 0
Nebenträger | Wartung_FFB | 1 | Nebenträger | HEA 120 | 0.698 | Wartung_FFB | 84.36 | 81.226 | 6.998 | 86.74 | 81.226 | 6.998 | 0 | 0.06 | 0.057 | 0122Tra0000014130 | m | T110 | false | HI_UZV_HEA_STA_0,120_xxx | 0
Nebenträger | Wartung_FFB | 1 | Nebenträger | HEA 120 | 0.698 | Wartung_FFB | 84.36 | 79.726 | 6.998 | 86.74 | 79.726 | 6.998 | 0 | 0.06 | 0.057 | 0122Tra0000014132 | m | T110 | false | HI_UZV_HEA_STA_0,120_xxx | 0
Nebenträger | Wartung_FFB | 1 | Nebenträger | HEA 120 | 0.698 | Wartung_FFB | 84.36 | 78.226 | 6.998 | 86.74 | 78.226 | 6.998 | 0 | 0.06 | 0.057 | 0122Tra0000014134 | m | T110 | false | HI_UZV_HEA_STA_0,120_xxx | 0
Nebenträger | Wartung_FFB | 1 | Nebenträger | HEA 120 | 0.698 | Wartung_FFB | 84.36 | 76.726 | 6.998 | 86.74 | 76.726 | 6.998 | 0 | 0.06 | 0.057 | 0122Tra0000014136 | m | T110 | false | HI_UZV_HEA_STA_0,120_xxx | 0
Nebenträger | Wartung_FFB | 1 | Nebenträger | HEA 120 | 0.698 | Wartung_FFB | 84.36 | 75.226 | 6.998 | 86.74 | 75.226 | 6.998 | 0 | 0.06 | 0.057 | 0122Tra0000014138 | m | T110 | false | HI_UZV_HEA_STA_0,120_xxx | 0
Nebenträger | Wartung_FFB | 1 | Nebenträger | HEA 120 | 0.698 | Wartung_FFB | 84.36 | 73.726 | 6.998 | 86.74 | 73.726 | 6.998 | 0 | 0.06 | 0.057 | 0122Tra0000014140 | m | T110 | false | HI_UZV_HEA_STA_0,120_xxx | 0
Nebenträger | Wartung_FFB | 1 | Nebenträger | HEA 120 | 0.698 | Wartung_FFB | 84.36 | 72.226 | 6.998 | 86.74 | 72.226 | 6.998 | 0 | 0.06 | 0.057 | 0122Tra0000014142 | m | T110 | false | HI_UZV_HEA_STA_0,120_xxx | 0
Nebenträger | Wartung_FFB | 1 | Nebenträger | HEA 120 | 0.698 | Wartung_FFB | 118.06 | 84.226 | 6.998 | 120.75 | 84.226 | 6.998 | 0 | 0.06 | 0.057 | 0122Tra0000008321 | m | T110 | false | HI_UZV_HEA_STA_0,120_xxx | 0
Nebenträger | Wartung_FFB | 1 | Nebenträger | HEA 120 | 0.698 | Wartung_FFB | 118.06 | 82.726 | 6.998 | 120.75 | 82.726 | 6.998 | 0 | 0.06 | 0.057 | 0122Tra0000008439 | m | T110 | false | HI_UZV_HEA_STA_0,120_xxx | 0
Nebenträger | Wartung_FFB | 1 | Nebenträger | HEA 120 | 0.698 | Wartung_FFB | 118.06 | 81.226 | 6.998 | 120.75 | 81.226 | 6.998 | 0 | 0.06 | 0.057 | 0122Tra0000008568 | m | T110 | false | HI_UZV_HEA_STA_0,120_xxx | 0
Nebenträger | Wartung_FFB | 1 | Nebenträger | HEA 120 | 0.698 | Wartung_FFB | 118.06 | 79.726 | 6.998 | 120.75 | 79.726 | 6.998 | 0 | 0.06 | 0.057 | 0122Tra0000008679 | m | T110 | false | HI_UZV_HEA_STA_0,120_xxx | 0
Nebenträger | Wartung_FFB | 1 | Nebenträger | HEA 120 | 0.698 | Wartung_FFB | 118.06 | 78.226 | 6.998 | 120.75 | 78.226 | 6.998 | 0 | 0.06 | 0.057 | 0122Tra0000008790 | m | T110 | false | HI_UZV_HEA_STA_0,120_xxx | 0
Nebenträger | Wartung_FFB | 1 | Nebenträger | HEA 120 | 0.698 | Wartung_FFB | 118.06 | 76.726 | 6.998 | 120.75 | 76.726 | 6.998 | 0 | 0.06 | 0.057 | 0122Tra0000008901 | m | T110 | false | HI_UZV_HEA_STA_0,120_xxx | 0
Nebenträger | Wartung_FFB | 1 | Nebenträger | HEA 120 | 0.698 | Wartung_FFB | 118.06 | 75.226 | 6.998 | 120.75 | 75.226 | 6.998 | 0 | 0.06 | 0.057 | 0122Tra0000009012 | m | T110 | false | HI_UZV_HEA_STA_0,120_xxx | 0
Nebenträger | Wartung_FFB | 1 | Nebenträger | HEA 120 | 0.698 | Wartung_FFB | 118.06 | 73.726 | 6.998 | 120.75 | 73.726 | 6.998 | 0 | 0.06 | 0.057 | 0122Tra0000009123 | m | T110 | false | HI_UZV_HEA_STA_0,120_xxx | 0
Nebenträger | Wartung_FFB | 1 | Nebenträger | HEA 120 | 0.698 | Wartung_FFB | 118.06 | 72.226 | 6.998 | 120.75 | 72.226 | 6.998 | 0 | 0.06 | 0.057 | 0122Tra0000009234 | m | T110 | false | HI_UZV_HEA_STA_0,120_xxx | 0
Nebenträger | Wartung_FFB | 1 | Nebenträger | HEA 120 | 0.698 | Wartung_FFB | 118.06 | 68.601 | 6.998 | 120.75 | 68.601 | 6.998 | 0 | 0.06 | 0.057 | 0122Tra0000009327 | m | T110 | false | HI_UZV_HEA_STA_0,120_xxx | 0
Nebenträger | Wartung_FFB | 1 | Nebenträger | HEA 120 | 0.698 | Wartung_FFB | 118.06 | 67.101 | 6.998 | 120.75 | 67.101 | 6.998 | 0 | 0.06 | 0.057 | 0122Tra0000009456 | m | T110 | false | HI_UZV_HEA_STA_0,120_xxx | 0
Nebenträger | Wartung_FFB | 1 | Nebenträger | HEA 120 | 0.698 | Wartung_FFB | 118.06 | 65.601 | 6.998 | 120.75 | 65.601 | 6.998 | 0 | 0.06 | 0.057 | 0122Tra0000009567 | m | T110 | false | HI_UZV_HEA_STA_0,120_xxx | 0
Nebenträger | Wartung_FFB | 1 | Nebenträger | HEA 120 | 0.698 | Wartung_FFB | 118.06 | 64.101 | 6.998 | 120.75 | 64.101 | 6.998 | 0 | 0.06 | 0.057 | 0122Tra0000009678 | m | T110 | false | HI_UZV_HEA_STA_0,120_xxx | 0
Nebenträger | Wartung_FFB | 1 | Nebenträger | HEA 120 | 0.698 | Wartung_FFB | 118.06 | 62.601 | 6.998 | 120.75 | 62.601 | 6.998 | 0 | 0.06 | 0.057 | 0122Tra0000009789 | m | T110 | false | HI_UZV_HEA_STA_0,120_xxx | 0
Nebenträger | Wartung_FFB | 1 | Nebenträger | HEA 120 | 0.698 | Wartung_FFB | 118.06 | 61.101 | 6.998 | 120.75 | 61.101 | 6.998 | 0 | 0.06 | 0.057 | 0122Tra0000009900 | m | T110 | false | HI_UZV_HEA_STA_0,120_xxx | 0
Nebenträger | Wartung_FFB | 1 | Nebenträger | HEA 120 | 0.698 | Wartung_FFB | 118.06 | 59.601 | 6.998 | 120.75 | 59.601 | 6.998 | 0 | 0.06 | 0.057 | 0122Tra0000010011 | m | T110 | false | HI_UZV_HEA_STA_0,120_xxx | 0
Nebenträger | Wartung_FFB | 1 | Nebenträger | HEA 120 | 0.698 | Wartung_FFB | 118.06 | 58.101 | 6.998 | 120.75 | 58.101 | 6.998 | 0 | 0.06 | 0.057 | 0122Tra0000010122 | m | T110 | false | HI_UZV_HEA_STA_0,120_xxx | 0
Nebenträger | Wartung_FFB | 1 | Nebenträger | HEA 120 | 0.698 | Wartung_FFB | 118.06 | 56.601 | 6.998 | 120.75 | 56.601 | 6.998 | 0 | 0.06 | 0.057 | 0122Tra0000010233 | m | T110 | false | HI_UZV_HEA_STA_0,120_xxx | 0
Nebenträger | Wartung_FFB | 1 | Nebenträger | HEA 120 | 0.698 | Wartung_FFB | 118.06 | 55.101 | 6.998 | 120.75 | 55.101 | 6.998 | 0 | 0.06 | 0.057 | 0122Tra0000010381 | m | T110 | false | HI_UZV_HEA_STA_0,120_xxx | 0
Nebenträger | Wartung_FFB | 1 | Nebenträger | HEA 120 | 0.698 | Wartung_FFB | 118.06 | 53.601 | 6.998 | 120.75 | 53.601 | 6.998 | 0 | 0.06 | 0.057 | 0122Tra0000010455 | m | T110 | false | HI_UZV_HEA_STA_0,120_xxx | 0
Nebenträger | Wartung_FFB | 1 | Nebenträger | HEA 120 | 0.698 | Wartung_FFB | 16.06 | 84.226 | 6.998 | 19.27 | 84.226 | 6.998 | 0 | 0.06 | 0.057 | 0122Tra0000008351 | m | T110 | false | HI_UZV_HEA_STA_0,120_xxx | 0
Nebenträger | Wartung_FFB | 1 | Nebenträger | HEA 120 | 0.698 | Wartung_FFB | 19.29 | 84.226 | 6.998 | 22.04 | 84.226 | 6.998 | 0 | 0.06 | 0.057 | 0122Tra0000008353 | m | T110 | false | HI_UZV_HEA_STA_0,120_xxx | 0
Nebenträger | Wartung_FFB | 1 | Nebenträger | HEA 120 | 0.698 | Wartung_FFB | 16.06 | 82.726 | 6.998 | 19.27 | 82.726 | 6.998 | 0 | 0.06 | 0.057 | 0122Tra0000008460 | m | T110 | false | HI_UZV_HEA_STA_0,120_xxx | 0
Nebenträger | Wartung_FFB | 1 | Nebenträger | HEA 120 | 0.698 | Wartung_FFB | 19.29 | 82.726 | 6.998 | 22.04 | 82.726 | 6.998 | 0 | 0.06 | 0.057 | 0122Tra0000008462 | m | T110 | false | HI_UZV_HEA_STA_0,120_xxx | 0
Nebenträger | Wartung_FFB | 1 | Nebenträger | HEA 120 | 0.698 | Wartung_FFB | 16.06 | 81.226 | 6.998 | 19.27 | 81.226 | 6.998 | 0 | 0.06 | 0.057 | 0122Tra0000008572 | m | T110 | false | HI_UZV_HEA_STA_0,120_xxx | 0
Nebenträger | Wartung_FFB | 1 | Nebenträger | HEA 120 | 0.698 | Wartung_FFB | 19.29 | 81.226 | 6.998 | 22.04 | 81.226 | 6.998 | 0 | 0.06 | 0.057 | 0122Tra0000008574 | m | T110 | false | HI_UZV_HEA_STA_0,120_xxx | 0
Nebenträger | Wartung_FFB | 1 | Nebenträger | HEA 120 | 0.698 | Wartung_FFB | 16.06 | 79.726 | 6.998 | 19.27 | 79.726 | 6.998 | 0 | 0.06 | 0.057 | 0122Tra0000008683 | m | T110 | false | HI_UZV_HEA_STA_0,120_xxx | 0
Nebenträger | Wartung_FFB | 1 | Nebenträger | HEA 120 | 0.698 | Wartung_FFB | 19.29 | 79.726 | 6.998 | 22.04 | 79.726 | 6.998 | 0 | 0.06 | 0.057 | 0122Tra0000008685 | m | T110 | false | HI_UZV_HEA_STA_0,120_xxx | 0
Nebenträger | Wartung_FFB | 1 | Nebenträger | HEA 120 | 0.698 | Wartung_FFB | 16.06 | 78.226 | 6.998 | 19.27 | 78.226 | 6.998 | 0 | 0.06 | 0.057 | 0122Tra0000008794 | m | T110 | false | HI_UZV_HEA_STA_0,120_xxx | 0
Nebenträger | Wartung_FFB | 1 | Nebenträger | HEA 120 | 0.698 | Wartung_FFB | 19.29 | 78.226 | 6.998 | 22.04 | 78.226 | 6.998 | 0 | 0.06 | 0.057 | 0122Tra0000008796 | m | T110 | false | HI_UZV_HEA_STA_0,120_xxx | 0
Nebenträger | Wartung_FFB | 1 | Nebenträger | HEA 120 | 0.698 | Wartung_FFB | 16.06 | 76.726 | 6.998 | 19.27 | 76.726 | 6.998 | 0 | 0.06 | 0.057 | 0122Tra0000008905 | m | T110 | false | HI_UZV_HEA_STA_0,120_xxx | 0
Nebenträger | Wartung_FFB | 1 | Nebenträger | HEA 120 | 0.698 | Wartung_FFB | 19.29 | 76.726 | 6.998 | 22.04 | 76.726 | 6.998 | 0 | 0.06 | 0.057 | 0122Tra0000008907 | m | T110 | false | HI_UZV_HEA_STA_0,120_xxx | 0
Nebenträger | Wartung_FFB | 1 | Nebenträger | HEA 120 | 0.698 | Wartung_FFB | 16.06 | 75.226 | 6.998 | 19.27 | 75.226 | 6.998 | 0 | 0.06 | 0.057 | 0122Tra0000009016 | m | T110 | false | HI_UZV_HEA_STA_0,120_xxx | 0
Nebenträger | Wartung_FFB | 1 | Nebenträger | HEA 120 | 0.698 | Wartung_FFB | 19.29 | 75.226 | 6.998 | 22.04 | 75.226 | 6.998 | 0 | 0.06 | 0.057 | 0122Tra0000009018 | m | T110 | false | HI_UZV_HEA_STA_0,120_xxx | 0
Nebenträger | Wartung_FFB | 1 | Nebenträger | HEA 120 | 0.698 | Wartung_FFB | 16.06 | 73.726 | 6.998 | 19.27 | 73.726 | 6.998 | 0 | 0.06 | 0.057 | 0122Tra0000009127 | m | T110 | false | HI_UZV_HEA_STA_0,120_xxx | 0
Nebenträger | Wartung_FFB | 1 | Nebenträger | HEA 120 | 0.698 | Wartung_FFB | 19.29 | 73.726 | 6.998 | 22.04 | 73.726 | 6.998 | 0 | 0.06 | 0.057 | 0122Tra0000009129 | m | T110 | false | HI_UZV_HEA_STA_0,120_xxx | 0
Nebenträger | Wartung_FFB | 1 | Nebenträger | HEA 120 | 0.698 | Wartung_FFB | 16.06 | 72.226 | 6.998 | 19.27 | 72.226 | 6.998 | 0 | 0.06 | 0.057 | 0122Tra0000009238 | m | T110 | false | HI_UZV_HEA_STA_0,120_xxx | 0
Nebenträger | Wartung_FFB | 1 | Nebenträger | HEA 120 | 0.698 | Wartung_FFB | 19.29 | 72.226 | 6.998 | 22.04 | 72.226 | 6.998 | 0 | 0.06 | 0.057 | 0122Tra0000009240 | m | T110 | false | HI_UZV_HEA_STA_0,120_xxx | 0
Nebenträger | Wartung_FFB | 1 | Nebenträger | HEA 120 | 0.698 | Wartung_FFB | 79.06 | 84.226 | 6.998 | 82.17 | 84.226 | 6.998 | 0 | 0.06 | 0.057 | 0122Tra0000008282 | m | T110 | false | HI_UZV_HEA_STA_0,120_xxx | 0
Nebenträger | Wartung_FFB | 1 | Nebenträger | HEA 120 | 0.698 | Wartung_FFB | 79.06 | 82.726 | 6.998 | 82.17 | 82.726 | 6.998 | 0 | 0.06 | 0.057 | 0122Tra0000008413 | m | T110 | false | HI_UZV_HEA_STA_0,120_xxx | 0
Nebenträger | Wartung_FFB | 1 | Nebenträger | HEA 120 | 0.698 | Wartung_FFB | 79.06 | 81.226 | 6.998 | 82.17 | 81.226 | 6.998 | 0 | 0.06 | 0.057 | 0122Tra0000008542 | m | T110 | false | HI_UZV_HEA_STA_0,120_xxx | 0
Nebenträger | Wartung_FFB | 1 | Nebenträger | HEA 120 | 0.698 | Wartung_FFB | 79.06 | 79.726 | 6.998 | 82.17 | 79.726 | 6.998 | 0 | 0.06 | 0.057 | 0122Tra0000008653 | m | T110 | false | HI_UZV_HEA_STA_0,120_xxx | 0
Nebenträger | Wartung_FFB | 1 | Nebenträger | HEA 120 | 0.698 | Wartung_FFB | 79.06 | 78.226 | 6.998 | 82.17 | 78.226 | 6.998 | 0 | 0.06 | 0.057 | 0122Tra0000008764 | m | T110 | false | HI_UZV_HEA_STA_0,120_xxx | 0
Nebenträger | Wartung_FFB | 1 | Nebenträger | HEA 120 | 0.698 | Wartung_FFB | 79.06 | 76.726 | 6.998 | 82.17 | 76.726 | 6.998 | 0 | 0.06 | 0.057 | 0122Tra0000008875 | m | T110 | false | HI_UZV_HEA_STA_0,120_xxx | 0
Nebenträger | Wartung_FFB | 1 | Nebenträger | HEA 120 | 0.698 | Wartung_FFB | 79.06 | 75.226 | 6.998 | 82.17 | 75.226 | 6.998 | 0 | 0.06 | 0.057 | 0122Tra0000008986 | m | T110 | false | HI_UZV_HEA_STA_0,120_xxx | 0
Nebenträger | Wartung_FFB | 1 | Nebenträger | HEA 120 | 0.698 | Wartung_FFB | 79.06 | 73.726 | 6.998 | 82.17 | 73.726 | 6.998 | 0 | 0.06 | 0.057 | 0122Tra0000009097 | m | T110 | false | HI_UZV_HEA_STA_0,120_xxx | 0
Nebenträger | Wartung_FFB | 1 | Nebenträger | HEA 120 | 0.698 | Wartung_FFB | 79.06 | 72.226 | 6.998 | 82.17 | 72.226 | 6.998 | 0 | 0.06 | 0.057 | 0122Tra0000009208 | m | T110 | false | HI_UZV_HEA_STA_0,120_xxx | 0
Nebenträger | Wartung_FFB | 1 | Nebenträger | HEA 120 | 0.698 | Wartung_FFB | 82.19 | 84.226 | 6.998 | 84.34 | 84.226 | 6.998 | 0 | 0.06 | 0.057 | 0122Tra0000008285 | m | T110 | false | HI_UZV_HEA_STA_0,120_xxx | 0
Nebenträger | Wartung_FFB | 1 | Nebenträger | HEA 120 | 0.698 | Wartung_FFB | 82.19 | 82.726 | 6.998 | 84.34 | 82.726 | 6.998 | 0 | 0.06 | 0.057 | 0122Tra0000008415 | m | T110 | false | HI_UZV_HEA_STA_0,120_xxx | 0
Nebenträger | Wartung_FFB | 1 | Nebenträger | HEA 120 | 0.698 | Wartung_FFB | 82.19 | 81.226 | 6.998 | 84.34 | 81.226 | 6.998 | 0 | 0.06 | 0.057 | 0122Tra0000008544 | m | T110 | false | HI_UZV_HEA_STA_0,120_xxx | 0
Nebenträger | Wartung_FFB | 1 | Nebenträger | HEA 120 | 0.698 | Wartung_FFB | 82.19 | 79.726 | 6.998 | 84.34 | 79.726 | 6.998 | 0 | 0.06 | 0.057 | 0122Tra0000008655 | m | T110 | false | HI_UZV_HEA_STA_0,120_xxx | 0
Nebenträger | Wartung_FFB | 1 | Nebenträger | HEA 120 | 0.698 | Wartung_FFB | 82.19 | 78.226 | 6.998 | 84.34 | 78.226 | 6.998 | 0 | 0.06 | 0.057 | 0122Tra0000008766 | m | T110 | false | HI_UZV_HEA_STA_0,120_xxx | 0
Nebenträger | Wartung_FFB | 1 | Nebenträger | HEA 120 | 0.698 | Wartung_FFB | 82.19 | 76.726 | 6.998 | 84.34 | 76.726 | 6.998 | 0 | 0.06 | 0.057 | 0122Tra0000008877 | m | T110 | false | HI_UZV_HEA_STA_0,120_xxx | 0
Nebenträger | Wartung_FFB | 1 | Nebenträger | HEA 120 | 0.698 | Wartung_FFB | 82.19 | 75.226 | 6.998 | 84.34 | 75.226 | 6.998 | 0 | 0.06 | 0.057 | 0122Tra0000008988 | m | T110 | false | HI_UZV_HEA_STA_0,120_xxx | 0
Nebenträger | Wartung_FFB | 1 | Nebenträger | HEA 120 | 0.698 | Wartung_FFB | 82.19 | 73.726 | 6.998 | 84.34 | 73.726 | 6.998 | 0 | 0.06 | 0.057 | 0122Tra0000009099 | m | T110 | false | HI_UZV_HEA_STA_0,120_xxx | 0
Nebenträger | Wartung_FFB | 1 | Nebenträger | HEA 120 | 0.698 | Wartung_FFB | 82.19 | 72.226 | 6.998 | 84.34 | 72.226 | 6.998 | 0 | 0.06 | 0.057 | 0122Tra0000009210 | m | T110 | false | HI_UZV_HEA_STA_0,120_xxx | 0
Nebenträger | Wartung_FFB | 1 | Nebenträger | HEA 120 | 0.698 | Wartung_FFB | 97.06 | 84.226 | 6.998 | 99.81 | 84.226 | 6.998 | 0 | 0.06 | 0.057 | 0122Tra0000008300 | m | T110 | false | HI_UZV_HEA_STA_0,120_xxx | 0
Nebenträger | Wartung_FFB | 1 | Nebenträger | HEA 120 | 0.698 | Wartung_FFB | 99.83 | 84.226 | 6.998 | 103.04 | 84.226 | 6.998 | 0 | 0.06 | 0.057 | 0122Tra0000008303 | m | T110 | false | HI_UZV_HEA_STA_0,120_xxx | 0
Nebenträger | Wartung_FFB | 1 | Nebenträger | HEA 120 | 0.698 | Wartung_FFB | 97.06 | 82.726 | 6.998 | 99.81 | 82.726 | 6.998 | 0 | 0.06 | 0.057 | 0122Tra0000008425 | m | T110 | false | HI_UZV_HEA_STA_0,120_xxx | 0
Nebenträger | Wartung_FFB | 1 | Nebenträger | HEA 120 | 0.698 | Wartung_FFB | 99.83 | 82.726 | 6.998 | 103.04 | 82.726 | 6.998 | 0 | 0.06 | 0.057 | 0122Tra0000008427 | m | T110 | false | HI_UZV_HEA_STA_0,120_xxx | 0
Nebenträger | Wartung_FFB | 1 | Nebenträger | HEA 120 | 0.698 | Wartung_FFB | 97.06 | 81.226 | 6.998 | 99.81 | 81.226 | 6.998 | 0 | 0.06 | 0.057 | 0122Tra0000008554 | m | T110 | false | HI_UZV_HEA_STA_0,120_xxx | 0
Nebenträger | Wartung_FFB | 1 | Nebenträger | HEA 120 | 0.698 | Wartung_FFB | 99.83 | 81.226 | 6.998 | 103.04 | 81.226 | 6.998 | 0 | 0.06 | 0.057 | 0122Tra0000008556 | m | T110 | false | HI_UZV_HEA_STA_0,120_xxx | 0
Nebenträger | Wartung_FFB | 1 | Nebenträger | HEA 120 | 0.698 | Wartung_FFB | 97.06 | 79.726 | 6.998 | 99.81 | 79.726 | 6.998 | 0 | 0.06 | 0.057 | 0122Tra0000008665 | m | T110 | false | HI_UZV_HEA_STA_0,120_xxx | 0
Nebenträger | Wartung_FFB | 1 | Nebenträger | HEA 120 | 0.698 | Wartung_FFB | 99.83 | 79.726 | 6.998 | 103.04 | 79.726 | 6.998 | 0 | 0.06 | 0.057 | 0122Tra0000008667 | m | T110 | false | HI_UZV_HEA_STA_0,120_xxx | 0
Nebenträger | Wartung_FFB | 1 | Nebenträger | HEA 120 | 0.698 | Wartung_FFB | 97.06 | 78.226 | 6.998 | 99.81 | 78.226 | 6.998 | 0 | 0.06 | 0.057 | 0122Tra0000008776 | m | T110 | false | HI_UZV_HEA_STA_0,120_xxx | 0
Nebenträger | Wartung_FFB | 1 | Nebenträger | HEA 120 | 0.698 | Wartung_FFB | 99.83 | 78.226 | 6.998 | 103.04 | 78.226 | 6.998 | 0 | 0.06 | 0.057 | 0122Tra0000008778 | m | T110 | false | HI_UZV_HEA_STA_0,120_xxx | 0
Nebenträger | Wartung_FFB | 1 | Nebenträger | HEA 120 | 0.698 | Wartung_FFB | 97.06 | 76.726 | 6.998 | 99.81 | 76.726 | 6.998 | 0 | 0.06 | 0.057 | 0122Tra0000008887 | m | T110 | false | HI_UZV_HEA_STA_0,120_xxx | 0
Nebenträger | Wartung_FFB | 1 | Nebenträger | HEA 120 | 0.698 | Wartung_FFB | 99.83 | 76.726 | 6.998 | 103.04 | 76.726 | 6.998 | 0 | 0.06 | 0.057 | 0122Tra0000008889 | m | T110 | false | HI_UZV_HEA_STA_0,120_xxx | 0
Nebenträger | Wartung_FFB | 1 | Nebenträger | HEA 120 | 0.698 | Wartung_FFB | 97.06 | 75.226 | 6.998 | 99.81 | 75.226 | 6.998 | 0 | 0.06 | 0.057 | 0122Tra0000008998 | m | T110 | false | HI_UZV_HEA_STA_0,120_xxx | 0
Nebenträger | Wartung_FFB | 1 | Nebenträger | HEA 120 | 0.698 | Wartung_FFB | 99.83 | 75.226 | 6.998 | 103.04 | 75.226 | 6.998 | 0 | 0.06 | 0.057 | 0122Tra0000009000 | m | T110 | false | HI_UZV_HEA_STA_0,120_xxx | 0
Nebenträger | Wartung_FFB | 1 | Nebenträger | HEA 120 | 0.698 | Wartung_FFB | 97.06 | 73.726 | 6.998 | 99.81 | 73.726 | 6.998 | 0 | 0.06 | 0.057 | 0122Tra0000009109 | m | T110 | false | HI_UZV_HEA_STA_0,120_xxx | 0
Nebenträger | Wartung_FFB | 1 | Nebenträger | HEA 120 | 0.698 | Wartung_FFB | 99.83 | 73.726 | 6.998 | 103.04 | 73.726 | 6.998 | 0 | 0.06 | 0.057 | 0122Tra0000009111 | m | T110 | false | HI_UZV_HEA_STA_0,120_xxx | 0
Nebenträger | Wartung_FFB | 1 | Nebenträger | HEA 120 | 0.698 | Wartung_FFB | 97.06 | 72.226 | 6.998 | 99.81 | 72.226 | 6.998 | 0 | 0.06 | 0.057 | 0122Tra0000009220 | m | T110 | false | HI_UZV_HEA_STA_0,120_xxx | 0
Nebenträger | Wartung_FFB | 1 | Nebenträger | HEA 120 | 0.698 | Wartung_FFB | 99.83 | 72.226 | 6.998 | 103.04 | 72.226 | 6.998 | 0 | 0.06 | 0.057 | 0122Tra0000009222 | m | T110 | false | HI_UZV_HEA_STA_0,120_xxx | 0
Nebenträger | Wartung_FFB | 1 | Nebenträger | HEA 120 | 0.698 | Wartung_FFB | 97.06 | 68.601 | 6.998 | 99.81 | 68.601 | 6.998 | 0 | 0.06 | 0.057 | 0122Tra0000009313 | m | T110 | false | HI_UZV_HEA_STA_0,120_xxx | 0
Nebenträger | Wartung_FFB | 1 | Nebenträger | HEA 120 | 0.698 | Wartung_FFB | 99.83 | 68.601 | 6.998 | 103.04 | 68.601 | 6.998 | 0 | 0.06 | 0.057 | 0122Tra0000009315 | m | T110 | false | HI_UZV_HEA_STA_0,120_xxx | 0
Nebenträger | Wartung_FFB | 1 | Nebenträger | HEA 120 | 0.698 | Wartung_FFB | 97.06 | 67.101 | 6.998 | 99.81 | 67.101 | 6.998 | 0 | 0.06 | 0.057 | 0122Tra0000009442 | m | T110 | false | HI_UZV_HEA_STA_0,120_xxx | 0
Nebenträger | Wartung_FFB | 1 | Nebenträger | HEA 120 | 0.698 | Wartung_FFB | 99.83 | 67.101 | 6.998 | 103.04 | 67.101 | 6.998 | 0 | 0.06 | 0.057 | 0122Tra0000009444 | m | T110 | false | HI_UZV_HEA_STA_0,120_xxx | 0
Nebenträger | Wartung_FFB | 1 | Nebenträger | HEA 120 | 0.698 | Wartung_FFB | 97.06 | 65.601 | 6.998 | 99.81 | 65.601 | 6.998 | 0 | 0.06 | 0.057 | 0122Tra0000009553 | m | T110 | false | HI_UZV_HEA_STA_0,120_xxx | 0
Nebenträger | Wartung_FFB | 1 | Nebenträger | HEA 120 | 0.698 | Wartung_FFB | 99.83 | 65.601 | 6.998 | 103.04 | 65.601 | 6.998 | 0 | 0.06 | 0.057 | 0122Tra0000009555 | m | T110 | false | HI_UZV_HEA_STA_0,120_xxx | 0
Nebenträger | Wartung_FFB | 1 | Nebenträger | HEA 120 | 0.698 | Wartung_FFB | 97.06 | 64.101 | 6.998 | 99.81 | 64.101 | 6.998 | 0 | 0.06 | 0.057 | 0122Tra0000009664 | m | T110 | false | HI_UZV_HEA_STA_0,120_xxx | 0
Nebenträger | Wartung_FFB | 1 | Nebenträger | HEA 120 | 0.698 | Wartung_FFB | 99.83 | 64.101 | 6.998 | 103.04 | 64.101 | 6.998 | 0 | 0.06 | 0.057 | 0122Tra0000009666 | m | T110 | false | HI_UZV_HEA_STA_0,120_xxx | 0
Nebenträger | Wartung_FFB | 1 | Nebenträger | HEA 120 | 0.698 | Wartung_FFB | 97.06 | 62.601 | 6.998 | 99.81 | 62.601 | 6.998 | 0 | 0.06 | 0.057 | 0122Tra0000009775 | m | T110 | false | HI_UZV_HEA_STA_0,120_xxx | 0
Nebenträger | Wartung_FFB | 1 | Nebenträger | HEA 120 | 0.698 | Wartung_FFB | 99.83 | 62.601 | 6.998 | 103.04 | 62.601 | 6.998 | 0 | 0.06 | 0.057 | 0122Tra0000009777 | m | T110 | false | HI_UZV_HEA_STA_0,120_xxx | 0
Nebenträger | Wartung_FFB | 1 | Nebenträger | HEA 120 | 0.698 | Wartung_FFB | 97.06 | 61.101 | 6.998 | 99.81 | 61.101 | 6.998 | 0 | 0.06 | 0.057 | 0122Tra0000009886 | m | T110 | false | HI_UZV_HEA_STA_0,120_xxx | 0
Nebenträger | Wartung_FFB | 1 | Nebenträger | HEA 120 | 0.698 | Wartung_FFB | 99.83 | 61.101 | 6.998 | 103.04 | 61.101 | 6.998 | 0 | 0.06 | 0.057 | 0122Tra0000009888 | m | T110 | false | HI_UZV_HEA_STA_0,120_xxx | 0
Nebenträger | Wartung_FFB | 1 | Nebenträger | HEA 120 | 0.698 | Wartung_FFB | 97.06 | 59.601 | 6.998 | 99.81 | 59.601 | 6.998 | 0 | 0.06 | 0.057 | 0122Tra0000009997 | m | T110 | false | HI_UZV_HEA_STA_0,120_xxx | 0
Nebenträger | Wartung_FFB | 1 | Nebenträger | HEA 120 | 0.698 | Wartung_FFB | 99.83 | 59.601 | 6.998 | 103.04 | 59.601 | 6.998 | 0 | 0.06 | 0.057 | 0122Tra0000009999 | m | T110 | false | HI_UZV_HEA_STA_0,120_xxx | 0
Nebenträger | Wartung_FFB | 1 | Nebenträger | HEA 120 | 0.698 | Wartung_FFB | 97.06 | 58.101 | 6.998 | 99.81 | 58.101 | 6.998 | 0 | 0.06 | 0.057 | 0122Tra0000010108 | m | T110 | false | HI_UZV_HEA_STA_0,120_xxx | 0
Nebenträger | Wartung_FFB | 1 | Nebenträger | HEA 120 | 0.698 | Wartung_FFB | 99.83 | 58.101 | 6.998 | 103.04 | 58.101 | 6.998 | 0 | 0.06 | 0.057 | 0122Tra0000010110 | m | T110 | false | HI_UZV_HEA_STA_0,120_xxx | 0
Nebenträger | Wartung_FFB | 1 | Nebenträger | HEA 120 | 0.698 | Wartung_FFB | 97.06 | 56.601 | 6.998 | 99.81 | 56.601 | 6.998 | 0 | 0.06 | 0.057 | 0122Tra0000010219 | m | T110 | false | HI_UZV_HEA_STA_0,120_xxx | 0
Nebenträger | Wartung_FFB | 1 | Nebenträger | HEA 120 | 0.698 | Wartung_FFB | 99.83 | 56.601 | 6.998 | 103.04 | 56.601 | 6.998 | 0 | 0.06 | 0.057 | 0122Tra0000010221 | m | T110 | false | HI_UZV_HEA_STA_0,120_xxx | 0
Nebenträger | Wartung_FFB | 1 | Nebenträger | HEA 120 | 0.698 | Wartung_FFB | 97.06 | 55.101 | 6.998 | 99.81 | 55.101 | 6.998 | 0 | 0.06 | 0.057 | 0122Tra0000010367 | m | T110 | false | HI_UZV_HEA_STA_0,120_xxx | 0
Nebenträger | Wartung_FFB | 1 | Nebenträger | HEA 120 | 0.698 | Wartung_FFB | 99.83 | 55.101 | 6.998 | 103.04 | 55.101 | 6.998 | 0 | 0.06 | 0.057 | 0122Tra0000010369 | m | T110 | false | HI_UZV_HEA_STA_0,120_xxx | 0
Nebenträger | Wartung_FFB | 1 | Nebenträger | HEA 120 | 0.698 | Wartung_FFB | 97.06 | 53.601 | 6.998 | 99.81 | 53.601 | 6.998 | 0 | 0.06 | 0.057 | 0122Tra0000010441 | m | T110 | false | HI_UZV_HEA_STA_0,120_xxx | 0
Nebenträger | Wartung_FFB | 1 | Nebenträger | HEA 120 | 0.698 | Wartung_FFB | 99.83 | 53.601 | 6.998 | 103.04 | 53.601 | 6.998 | 0 | 0.06 | 0.057 | 0122Tra0000010443 | m | T110 | false | HI_UZV_HEA_STA_0,120_xxx | 0
Nebenträger | Wartung_FFB | 1 | Nebenträger | HEA 120 | 0.698 | Wartung_FFB | 16.06 | 68.601 | 6.998 | 19.27 | 68.601 | 6.998 | 0 | 0.06 | 0.057 | 0122Tra0000009348 | m | T110 | false | HI_UZV_HEA_STA_0,120_xxx | 0
Nebenträger | Wartung_FFB | 1 | Nebenträger | HEA 120 | 0.698 | Wartung_FFB | 19.29 | 68.601 | 6.998 | 22.04 | 68.601 | 6.998 | 0 | 0.06 | 0.057 | 0122Tra0000009350 | m | T110 | false | HI_UZV_HEA_STA_0,120_xxx | 0
Nebenträger | Wartung_FFB | 1 | Nebenträger | HEA 120 | 0.698 | Wartung_FFB | 16.06 | 67.101 | 6.998 | 19.27 | 67.101 | 6.998 | 0 | 0.06 | 0.057 | 0122Tra0000009460 | m | T110 | false | HI_UZV_HEA_STA_0,120_xxx | 0
Nebenträger | Wartung_FFB | 1 | Nebenträger | HEA 120 | 0.698 | Wartung_FFB | 19.29 | 67.101 | 6.998 | 22.04 | 67.101 | 6.998 | 0 | 0.06 | 0.057 | 0122Tra0000009462 | m | T110 | false | HI_UZV_HEA_STA_0,120_xxx | 0
Nebenträger | Wartung_FFB | 1 | Nebenträger | HEA 120 | 0.698 | Wartung_FFB | 16.06 | 65.601 | 6.998 | 19.27 | 65.601 | 6.998 | 0 | 0.06 | 0.057 | 0122Tra0000009571 | m | T110 | false | HI_UZV_HEA_STA_0,120_xxx | 0
Nebenträger | Wartung_FFB | 1 | Nebenträger | HEA 120 | 0.698 | Wartung_FFB | 19.29 | 65.601 | 6.998 | 22.04 | 65.601 | 6.998 | 0 | 0.06 | 0.057 | 0122Tra0000009573 | m | T110 | false | HI_UZV_HEA_STA_0,120_xxx | 0
Nebenträger | Wartung_FFB | 1 | Nebenträger | HEA 120 | 0.698 | Wartung_FFB | 16.06 | 64.101 | 6.998 | 19.27 | 64.101 | 6.998 | 0 | 0.06 | 0.057 | 0122Tra0000009682 | m | T110 | false | HI_UZV_HEA_STA_0,120_xxx | 0
Nebenträger | Wartung_FFB | 1 | Nebenträger | HEA 120 | 0.698 | Wartung_FFB | 19.29 | 64.101 | 6.998 | 22.04 | 64.101 | 6.998 | 0 | 0.06 | 0.057 | 0122Tra0000009684 | m | T110 | false | HI_UZV_HEA_STA_0,120_xxx | 0
Nebenträger | Wartung_FFB | 1 | Nebenträger | HEA 120 | 0.698 | Wartung_FFB | 16.06 | 62.601 | 6.998 | 19.27 | 62.601 | 6.998 | 0 | 0.06 | 0.057 | 0122Tra0000009793 | m | T110 | false | HI_UZV_HEA_STA_0,120_xxx | 0
Nebenträger | Wartung_FFB | 1 | Nebenträger | HEA 120 | 0.698 | Wartung_FFB | 19.29 | 62.601 | 6.998 | 22.04 | 62.601 | 6.998 | 0 | 0.06 | 0.057 | 0122Tra0000009795 | m | T110 | false | HI_UZV_HEA_STA_0,120_xxx | 0
Nebenträger | Wartung_FFB | 1 | Nebenträger | HEA 120 | 0.698 | Wartung_FFB | 16.06 | 61.101 | 6.998 | 19.27 | 61.101 | 6.998 | 0 | 0.06 | 0.057 | 0122Tra0000009904 | m | T110 | false | HI_UZV_HEA_STA_0,120_xxx | 0
Nebenträger | Wartung_FFB | 1 | Nebenträger | HEA 120 | 0.698 | Wartung_FFB | 19.29 | 61.101 | 6.998 | 22.04 | 61.101 | 6.998 | 0 | 0.06 | 0.057 | 0122Tra0000009906 | m | T110 | false | HI_UZV_HEA_STA_0,120_xxx | 0
Nebenträger | Wartung_FFB | 1 | Nebenträger | HEA 120 | 0.698 | Wartung_FFB | 16.06 | 59.601 | 6.998 | 19.27 | 59.601 | 6.998 | 0 | 0.06 | 0.057 | 0122Tra0000010015 | m | T110 | false | HI_UZV_HEA_STA_0,120_xxx | 0
Nebenträger | Wartung_FFB | 1 | Nebenträger | HEA 120 | 0.698 | Wartung_FFB | 19.29 | 59.601 | 6.998 | 22.04 | 59.601 | 6.998 | 0 | 0.06 | 0.057 | 0122Tra0000010017 | m | T110 | false | HI_UZV_HEA_STA_0,120_xxx | 0
Nebenträger | Wartung_FFB | 1 | Nebenträger | HEA 120 | 0.698 | Wartung_FFB | 22.06 | 49.45 | 6.998 | 25.493 | 49.45 | 6.998 | 0 | 0.06 | 0.057 | 0122Tra0000010870 | m | T110 | false | HI_UZV_HEA_STA_0,120_xxx | 0
Nebenträger | Wartung_FFB | 1 | Nebenträger | HEA 120 | 0.698 | Wartung_FFB | 25.513 | 49.45 | 6.998 | 28.04 | 49.45 | 6.998 | 0 | 0.06 | 0.057 | 0122Tra0000010872 | m | T110 | false | HI_UZV_HEA_STA_0,120_xxx | 0
Nebenträger | Wartung_FFB | 1 | Nebenträger | HEA 120 | 0.698 | Wartung_FFB | 22.06 | 47.95 | 6.998 | 25.493 | 47.95 | 6.998 | 0 | 0.06 | 0.057 | 0122Tra0000010944 | m | T110 | false | HI_UZV_HEA_STA_0,120_xxx | 0
Nebenträger | Wartung_FFB | 1 | Nebenträger | HEA 120 | 0.698 | Wartung_FFB | 25.513 | 47.95 | 6.998 | 28.04 | 47.95 | 6.998 | 0 | 0.06 | 0.057 | 0122Tra0000010946 | m | T110 | false | HI_UZV_HEA_STA_0,120_xxx | 0
Nebenträger | Wartung_FFB | 1 | Nebenträger | HEA 120 | 0.698 | Wartung_FFB | 22.06 | 46.45 | 6.998 | 25.493 | 46.45 | 6.998 | 0 | 0.06 | 0.057 | 0122Tra0000011018 | m | T110 | false | HI_UZV_HEA_STA_0,120_xxx | 0
Nebenträger | Wartung_FFB | 1 | Nebenträger | HEA 120 | 0.698 | Wartung_FFB | 25.513 | 46.45 | 6.998 | 28.04 | 46.45 | 6.998 | 0 | 0.06 | 0.057 | 0122Tra0000011020 | m | T110 | false | HI_UZV_HEA_STA_0,120_xxx | 0
Nebenträger | Wartung_FFB | 1 | Nebenträger | HEA 120 | 0.698 | Wartung_FFB | 22.06 | 44.95 | 6.998 | 25.493 | 44.95 | 6.998 | 0 | 0.06 | 0.057 | 0122Tra0000011092 | m | T110 | false | HI_UZV_HEA_STA_0,120_xxx | 0
Nebenträger | Wartung_FFB | 1 | Nebenträger | HEA 120 | 0.698 | Wartung_FFB | 25.513 | 44.95 | 6.998 | 28.04 | 44.95 | 6.998 | 0 | 0.06 | 0.057 | 0122Tra0000011094 | m | T110 | false | HI_UZV_HEA_STA_0,120_xxx | 0
Nebenträger | Wartung_FFB | 1 | Nebenträger | HEA 120 | 0.698 | Wartung_FFB | 22.06 | 43.45 | 6.998 | 25.493 | 43.45 | 6.998 | 0 | 0.06 | 0.057 | 0122Tra0000011166 | m | T110 | false | HI_UZV_HEA_STA_0,120_xxx | 0
Nebenträger | Wartung_FFB | 1 | Nebenträger | HEA 120 | 0.698 | Wartung_FFB | 25.513 | 43.45 | 6.998 | 28.04 | 43.45 | 6.998 | 0 | 0.06 | 0.057 | 0122Tra0000011168 | m | T110 | false | HI_UZV_HEA_STA_0,120_xxx | 0
Nebenträger | Wartung_FFB | 1 | Nebenträger | HEA 120 | 0.698 | Wartung_FFB | 22.06 | 41.95 | 6.998 | 25.493 | 41.95 | 6.998 | 0 | 0.06 | 0.057 | 0122Tra0000011240 | m | T110 | false | HI_UZV_HEA_STA_0,120_xxx | 0
Nebenträger | Wartung_FFB | 1 | Nebenträger | HEA 120 | 0.698 | Wartung_FFB | 25.513 | 41.95 | 6.998 | 28.04 | 41.95 | 6.998 | 0 | 0.06 | 0.057 | 0122Tra0000011242 | m | T110 | false | HI_UZV_HEA_STA_0,120_xxx | 0
Nebenträger | Wartung_FFB | 1 | Nebenträger | HEA 120 | 0.698 | Wartung_FFB | 22.06 | 40.45 | 6.998 | 25.493 | 40.45 | 6.998 | 0 | 0.06 | 0.057 | 0122Tra0000011314 | m | T110 | false | HI_UZV_HEA_STA_0,120_xxx | 0
Nebenträger | Wartung_FFB | 1 | Nebenträger | HEA 120 | 0.698 | Wartung_FFB | 25.513 | 40.45 | 6.998 | 28.04 | 40.45 | 6.998 | 0 | 0.06 | 0.057 | 0122Tra0000011316 | m | T110 | false | HI_UZV_HEA_STA_0,120_xxx | 0
Nebenträger | Wartung_FFB | 1 | Nebenträger | HEA 120 | 0.698 | Wartung_FFB | 22.06 | 38.95 | 6.998 | 25.493 | 38.95 | 6.998 | 0 | 0.06 | 0.057 | 0122Tra0000011388 | m | T110 | false | HI_UZV_HEA_STA_0,120_xxx | 0
Nebenträger | Wartung_FFB | 1 | Nebenträger | HEA 120 | 0.698 | Wartung_FFB | 25.513 | 38.95 | 6.998 | 28.04 | 38.95 | 6.998 | 0 | 0.06 | 0.057 | 0122Tra0000011390 | m | T110 | false | HI_UZV_HEA_STA_0,120_xxx | 0
Nebenträger | Wartung_FFB | 1 | Nebenträger | HEA 120 | 0.698 | Wartung_FFB | 22.06 | 37.45 | 6.998 | 25.493 | 37.45 | 6.998 | 0 | 0.06 | 0.057 | 0122Tra0000011462 | m | T110 | false | HI_UZV_HEA_STA_0,120_xxx | 0
Nebenträger | Wartung_FFB | 1 | Nebenträger | HEA 120 | 0.698 | Wartung_FFB | 25.513 | 37.45 | 6.998 | 28.04 | 37.45 | 6.998 | 0 | 0.06 | 0.057 | 0122Tra0000011464 | m | T110 | false | HI_UZV_HEA_STA_0,120_xxx | 0
Nebenträger | Wartung_FFB | 1 | Nebenträger | HEA 120 | 0.698 | Wartung_FFB | 22.06 | 35.95 | 6.998 | 25.493 | 35.95 | 6.998 | 0 | 0.06 | 0.057 | 0122Tra0000011610 | m | T110 | false | HI_UZV_HEA_STA_0,120_xxx | 0
Nebenträger | Wartung_FFB | 1 | Nebenträger | HEA 120 | 0.698 | Wartung_FFB | 25.513 | 35.95 | 6.998 | 28.04 | 35.95 | 6.998 | 0 | 0.06 | 0.057 | 0122Tra0000011612 | m | T110 | false | HI_UZV_HEA_STA_0,120_xxx | 0
Nebenträger | Wartung_FFB | 1 | Nebenträger | HEA 120 | 0.698 | Wartung_FFB | 22.06 | 34.45 | 6.998 | 25.493 | 34.45 | 6.998 | 0 | 0.06 | 0.057 | 0122Tra0000011684 | m | T110 | false | HI_UZV_HEA_STA_0,120_xxx | 0
Nebenträger | Wartung_FFB | 1 | Nebenträger | HEA 120 | 0.698 | Wartung_FFB | 25.513 | 34.45 | 6.998 | 28.04 | 34.45 | 6.998 | 0 | 0.06 | 0.057 | 0122Tra0000011686 | m | T110 | false | HI_UZV_HEA_STA_0,120_xxx | 0
Nebenträger | Wartung_FFB | 1 | Nebenträger | HEA 120 | 0.698 | Wartung_FFB | 22.06 | 32.95 | 6.998 | 25.493 | 32.95 | 6.998 | 0 | 0.06 | 0.057 | 0122Tra0000011795 | m | T110 | false | HI_UZV_HEA_STA_0,120_xxx | 0
Nebenträger | Wartung_FFB | 1 | Nebenträger | HEA 120 | 0.698 | Wartung_FFB | 25.513 | 32.95 | 6.998 | 28.04 | 32.95 | 6.998 | 0 | 0.06 | 0.057 | 0122Tra0000011797 | m | T110 | false | HI_UZV_HEA_STA_0,120_xxx | 0
Nebenträger | Wartung_FFB | 1 | Nebenträger | HEA 120 | 0.698 | Wartung_FFB | 32.26 | 35.95 | 6.998 | 34.04 | 35.95 | 6.998 | 0 | 0.06 | 0.057 | 0122Tra0000011616 | m | T110 | false | HI_UZV_HEA_STA_0,120_xxx | 0
Nebenträger | Wartung_FFB | 1 | Nebenträger | HEA 120 | 0.698 | Wartung_FFB | 32.26 | 34.45 | 6.998 | 34.04 | 34.45 | 6.998 | 0 | 0.06 | 0.057 | 0122Tra0000011690 | m | T110 | false | HI_UZV_HEA_STA_0,120_xxx | 0
Nebenträger | Wartung_FFB | 1 | Nebenträger | HEA 120 | 0.698 | Wartung_FFB | 32.26 | 32.95 | 6.998 | 34.04 | 32.95 | 6.998 | 0 | 0.06 | 0.057 | 0122Tra0000011801 | m | T110 | false | HI_UZV_HEA_STA_0,120_xxx | 0
Nebenträger | Wartung_FFB | 1 | Nebenträger | HEA 120 | 0.698 | Wartung_FFB | 29.61 | 35.95 | 6.998 | 32.24 | 35.95 | 6.998 | 0 | 0.06 | 0.057 | 0122Tra0000011614 | m | T110 | false | HI_UZV_HEA_STA_0,120_xxx | 0
Nebenträger | Wartung_FFB | 1 | Nebenträger | HEA 120 | 0.698 | Wartung_FFB | 29.61 | 34.45 | 6.998 | 32.24 | 34.45 | 6.998 | 0 | 0.06 | 0.057 | 0122Tra0000011688 | m | T110 | false | HI_UZV_HEA_STA_0,120_xxx | 0
Nebenträger | Wartung_FFB | 1 | Nebenträger | HEA 120 | 0.698 | Wartung_FFB | 29.61 | 32.95 | 6.998 | 32.24 | 32.95 | 6.998 | 0 | 0.06 | 0.057 | 0122Tra0000011799 | m | T110 | false | HI_UZV_HEA_STA_0,120_xxx | 0
Nebenträger | Wartung_FFB | 1 | Nebenträger | HEA 120 | 0.698 | Wartung_FFB | 28.06 | 35.95 | 6.998 | 29.59 | 35.95 | 6.998 | 0 | 0.06 | 0.057 | 0122Tra0000020306 | m | T110 | false | HI_UZV_HEA_STA_0,120_xxx | 0
Nebenträger | Wartung_FFB | 1 | Nebenträger | HEA 120 | 0.698 | Wartung_FFB | 28.06 | 34.45 | 6.998 | 29.59 | 34.45 | 6.998 | 0 | 0.06 | 0.057 | 0122Tra0000020308 | m | T110 | false | HI_UZV_HEA_STA_0,120_xxx | 0
Nebenträger | Wartung_FFB | 1 | Nebenträger | HEA 120 | 0.698 | Wartung_FFB | 28.06 | 32.95 | 6.998 | 29.59 | 32.95 | 6.998 | 0 | 0.06 | 0.057 | 0122Tra0000020311 | m | T110 | false | HI_UZV_HEA_STA_0,120_xxx | 0
Nebenträger | Wartung_FFB | 1 | Nebenträger | HEA 120 | 0.698 | Wartung_FFB | 43.06 | 49.45 | 6.998 | 45.91 | 49.45 | 6.998 | 0 | 0.06 | 0.057 | 0122Tra0000010884 | m | T110 | false | HI_UZV_HEA_STA_0,120_xxx | 0
Nebenträger | Wartung_FFB | 1 | Nebenträger | HEA 120 | 0.698 | Wartung_FFB | 45.93 | 49.45 | 6.998 | 49.04 | 49.45 | 6.998 | 0 | 0.06 | 0.057 | 0122Tra0000010886 | m | T110 | false | HI_UZV_HEA_STA_0,120_xxx | 0
Nebenträger | Wartung_FFB | 1 | Nebenträger | HEA 120 | 0.698 | Wartung_FFB | 43.06 | 47.95 | 6.998 | 45.91 | 47.95 | 6.998 | 0 | 0.06 | 0.057 | 0122Tra0000010958 | m | T110 | false | HI_UZV_HEA_STA_0,120_xxx | 0
Nebenträger | Wartung_FFB | 1 | Nebenträger | HEA 120 | 0.698 | Wartung_FFB | 45.93 | 47.95 | 6.998 | 49.04 | 47.95 | 6.998 | 0 | 0.06 | 0.057 | 0122Tra0000010960 | m | T110 | false | HI_UZV_HEA_STA_0,120_xxx | 0
Nebenträger | Wartung_FFB | 1 | Nebenträger | HEA 120 | 0.698 | Wartung_FFB | 43.06 | 46.45 | 6.998 | 45.91 | 46.45 | 6.998 | 0 | 0.06 | 0.057 | 0122Tra0000011032 | m | T110 | false | HI_UZV_HEA_STA_0,120_xxx | 0
Nebenträger | Wartung_FFB | 1 | Nebenträger | HEA 120 | 0.698 | Wartung_FFB | 45.93 | 46.45 | 6.998 | 49.04 | 46.45 | 6.998 | 0 | 0.06 | 0.057 | 0122Tra0000011034 | m | T110 | false | HI_UZV_HEA_STA_0,120_xxx | 0
Nebenträger | Wartung_FFB | 1 | Nebenträger | HEA 120 | 0.698 | Wartung_FFB | 43.06 | 44.95 | 6.998 | 45.91 | 44.95 | 6.998 | 0 | 0.06 | 0.057 | 0122Tra0000011106 | m | T110 | false | HI_UZV_HEA_STA_0,120_xxx | 0
Nebenträger | Wartung_FFB | 1 | Nebenträger | HEA 120 | 0.698 | Wartung_FFB | 45.93 | 44.95 | 6.998 | 49.04 | 44.95 | 6.998 | 0 | 0.06 | 0.057 | 0122Tra0000011108 | m | T110 | false | HI_UZV_HEA_STA_0,120_xxx | 0
Nebenträger | Wartung_FFB | 1 | Nebenträger | HEA 120 | 0.698 | Wartung_FFB | 43.06 | 43.45 | 6.998 | 45.91 | 43.45 | 6.998 | 0 | 0.06 | 0.057 | 0122Tra0000011180 | m | T110 | false | HI_UZV_HEA_STA_0,120_xxx | 0
Nebenträger | Wartung_FFB | 1 | Nebenträger | HEA 120 | 0.698 | Wartung_FFB | 45.93 | 43.45 | 6.998 | 49.04 | 43.45 | 6.998 | 0 | 0.06 | 0.057 | 0122Tra0000011182 | m | T110 | false | HI_UZV_HEA_STA_0,120_xxx | 0
Nebenträger | Wartung_FFB | 1 | Nebenträger | HEA 120 | 0.698 | Wartung_FFB | 43.06 | 41.95 | 6.998 | 45.91 | 41.95 | 6.998 | 0 | 0.06 | 0.057 | 0122Tra0000011254 | m | T110 | false | HI_UZV_HEA_STA_0,120_xxx | 0
Nebenträger | Wartung_FFB | 1 | Nebenträger | HEA 120 | 0.698 | Wartung_FFB | 45.93 | 41.95 | 6.998 | 49.04 | 41.95 | 6.998 | 0 | 0.06 | 0.057 | 0122Tra0000011256 | m | T110 | false | HI_UZV_HEA_STA_0,120_xxx | 0
Nebenträger | Wartung_FFB | 1 | Nebenträger | HEA 120 | 0.698 | Wartung_FFB | 43.06 | 40.45 | 6.998 | 45.91 | 40.45 | 6.998 | 0 | 0.06 | 0.057 | 0122Tra0000011328 | m | T110 | false | HI_UZV_HEA_STA_0,120_xxx | 0
Nebenträger | Wartung_FFB | 1 | Nebenträger | HEA 120 | 0.698 | Wartung_FFB | 45.93 | 40.45 | 6.998 | 49.04 | 40.45 | 6.998 | 0 | 0.06 | 0.057 | 0122Tra0000011330 | m | T110 | false | HI_UZV_HEA_STA_0,120_xxx | 0
Nebenträger | Wartung_FFB | 1 | Nebenträger | HEA 120 | 0.698 | Wartung_FFB | 43.06 | 38.95 | 6.998 | 45.91 | 38.95 | 6.998 | 0 | 0.06 | 0.057 | 0122Tra0000011402 | m | T110 | false | HI_UZV_HEA_STA_0,120_xxx | 0
Nebenträger | Wartung_FFB | 1 | Nebenträger | HEA 120 | 0.698 | Wartung_FFB | 45.93 | 38.95 | 6.998 | 49.04 | 38.95 | 6.998 | 0 | 0.06 | 0.057 | 0122Tra0000011404 | m | T110 | false | HI_UZV_HEA_STA_0,120_xxx | 0
Nebenträger | Wartung_FFB | 1 | Nebenträger | HEA 120 | 0.698 | Wartung_FFB | 43.06 | 37.45 | 6.998 | 45.91 | 37.45 | 6.998 | 0 | 0.06 | 0.057 | 0122Tra0000011476 | m | T110 | false | HI_UZV_HEA_STA_0,120_xxx | 0
Nebenträger | Wartung_FFB | 1 | Nebenträger | HEA 120 | 0.698 | Wartung_FFB | 45.93 | 37.45 | 6.998 | 49.04 | 37.45 | 6.998 | 0 | 0.06 | 0.057 | 0122Tra0000011478 | m | T110 | false | HI_UZV_HEA_STA_0,120_xxx | 0
Nebenträger | Wartung_FFB | 1 | Nebenträger | HEA 120 | 0.698 | Wartung_FFB | 43.06 | 35.95 | 6.998 | 45.91 | 35.95 | 6.998 | 0 | 0.06 | 0.057 | 0122Tra0000011624 | m | T110 | false | HI_UZV_HEA_STA_0,120_xxx | 0
Nebenträger | Wartung_FFB | 1 | Nebenträger | HEA 120 | 0.698 | Wartung_FFB | 45.93 | 35.95 | 6.998 | 49.04 | 35.95 | 6.998 | 0 | 0.06 | 0.057 | 0122Tra0000011626 | m | T110 | false | HI_UZV_HEA_STA_0,120_xxx | 0
Nebenträger | Wartung_FFB | 1 | Nebenträger | HEA 120 | 0.698 | Wartung_FFB | 43.06 | 34.45 | 6.998 | 45.91 | 34.45 | 6.998 | 0 | 0.06 | 0.057 | 0122Tra0000011698 | m | T110 | false | HI_UZV_HEA_STA_0,120_xxx | 0
Nebenträger | Wartung_FFB | 1 | Nebenträger | HEA 120 | 0.698 | Wartung_FFB | 45.93 | 34.45 | 6.998 | 49.04 | 34.45 | 6.998 | 0 | 0.06 | 0.057 | 0122Tra0000011700 | m | T110 | false | HI_UZV_HEA_STA_0,120_xxx | 0
Nebenträger | Wartung_FFB | 1 | Nebenträger | HEA 120 | 0.698 | Wartung_FFB | 43.06 | 32.95 | 6.998 | 45.91 | 32.95 | 6.998 | 0 | 0.06 | 0.057 | 0122Tra0000011809 | m | T110 | false | HI_UZV_HEA_STA_0,120_xxx | 0
Nebenträger | Wartung_FFB | 1 | Nebenträger | HEA 120 | 0.698 | Wartung_FFB | 45.93 | 32.95 | 6.998 | 49.04 | 32.95 | 6.998 | 0 | 0.06 | 0.057 | 0122Tra0000011811 | m | T110 | false | HI_UZV_HEA_STA_0,120_xxx | 0
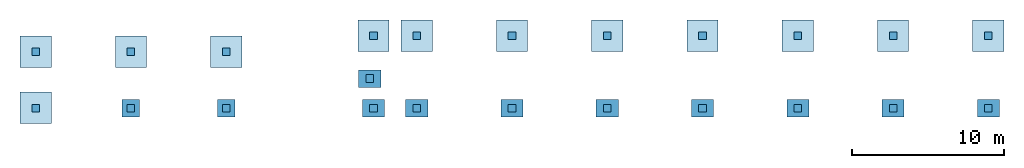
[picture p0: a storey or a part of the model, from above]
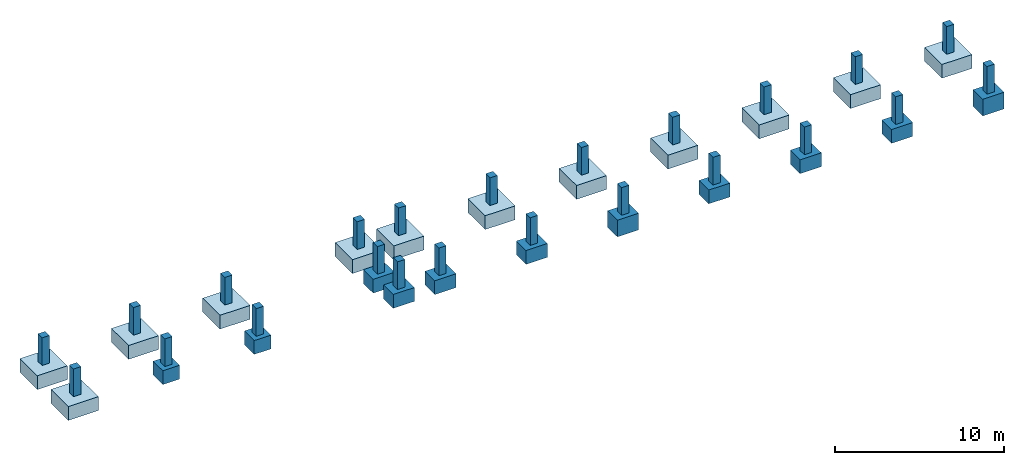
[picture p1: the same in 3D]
Properties of the parts of a building model (IFC2X3), part 8 of 25

# IfcBeam (2372)
Name | In | Faktor | Bezeichnung = Name | Profilname | Mantelfläche/lfm | Ebene | Achsenstartpunkt (X) (m) | Achsenstartpunkt (Y) (m) | Achsenstartpunkt (Z) (m) | Achsenendpunkt (X) (m) | Achsenendpunkt (Y) (m) | Achsenendpunkt (Z) (m) | Objektdrehwinkel | Schwerpunkt X (m) | Schwerpunkt Y (m) | Allright_Bauteil_ID | Abrechnungsart | Positionsnummer | Außenbauteil | Reference | Drehwinkel = Slope (deg)
Nebenträger | Wartung_FFB | 1 | Nebenträger | HEA 120 | 0.698 | Wartung_FFB | 91.06 | 28.645 | 6.998 | 91.84 | 28.645 | 6.998 | 0 | 0.06 | 0.057 | 0122Tra0000012250 | m | T110 | false | HI_UZV_HEA_STA_0,120_xxx | 0
Nebenträger | Wartung_FFB | 1 | Nebenträger | HEA 120 | 0.698 | Wartung_FFB | 91.06 | 27.145 | 6.998 | 91.84 | 27.145 | 6.998 | 0 | 0.06 | 0.057 | 0122Tra0000012324 | m | T110 | false | HI_UZV_HEA_STA_0,120_xxx | 0
Nebenträger | Wartung_FFB | 1 | Nebenträger | HEA 120 | 0.698 | Wartung_FFB | 91.06 | 25.645 | 6.998 | 91.84 | 25.645 | 6.998 | 0 | 0.06 | 0.057 | 0122Tra0000012398 | m | T110 | false | HI_UZV_HEA_STA_0,120_xxx | 0
Nebenträger | Wartung_FFB | 1 | Nebenträger | HEA 120 | 0.698 | Wartung_FFB | 91.06 | 24.145 | 6.998 | 91.84 | 24.145 | 6.998 | 0 | 0.06 | 0.057 | 0122Tra0000012472 | m | T110 | false | HI_UZV_HEA_STA_0,120_xxx | 0
Nebenträger | Wartung_FFB | 1 | Nebenträger | HEA 120 | 0.698 | Wartung_FFB | 91.06 | 22.645 | 6.998 | 91.84 | 22.645 | 6.998 | 0 | 0.06 | 0.057 | 0122Tra0000012546 | m | T110 | false | HI_UZV_HEA_STA_0,120_xxx | 0
Nebenträger | Wartung_FFB | 1 | Nebenträger | HEA 120 | 0.698 | Wartung_FFB | 91.06 | 21.145 | 6.998 | 91.84 | 21.145 | 6.998 | 0 | 0.06 | 0.057 | 0122Tra0000012620 | m | T110 | false | HI_UZV_HEA_STA_0,120_xxx | 0
Nebenträger | Wartung_FFB | 1 | Nebenträger | HEA 120 | 0.698 | Wartung_FFB | 91.06 | 19.645 | 6.998 | 91.84 | 19.645 | 6.998 | 0 | 0.06 | 0.057 | 0122Tra0000012694 | m | T110 | false | HI_UZV_HEA_STA_0,120_xxx | 0
Nebenträger | Wartung_FFB | 1 | Nebenträger | HEA 120 | 0.698 | Wartung_FFB | 91.06 | 18.145 | 6.998 | 91.84 | 18.145 | 6.998 | 0 | 0.06 | 0.057 | 0122Tra0000012768 | m | T110 | false | HI_UZV_HEA_STA_0,120_xxx | 0
Nebenträger | Wartung_FFB | 1 | Nebenträger | HEA 120 | 0.698 | Wartung_FFB | 91.06 | 16.645 | 6.998 | 91.84 | 16.645 | 6.998 | 0 | 0.06 | 0.057 | 0122Tra0000012842 | m | T110 | false | HI_UZV_HEA_STA_0,120_xxx | 0
Nebenträger | Wartung_FFB | 1 | Nebenträger | HEA 120 | 0.698 | Wartung_FFB | 91.06 | 15.145 | 6.998 | 91.84 | 15.145 | 6.998 | 0 | 0.06 | 0.057 | 0122Tra0000012916 | m | T110 | false | HI_UZV_HEA_STA_0,120_xxx | 0
Nebenträger | Wartung_FFB | 1 | Nebenträger | HEA 120 | 0.698 | Wartung_FFB | 91.06 | 13.645 | 6.998 | 91.84 | 13.645 | 6.998 | 0 | 0.06 | 0.057 | 0122Tra0000012990 | m | T110 | false | HI_UZV_HEA_STA_0,120_xxx | 0
Nebenträger | Wartung_FFB | 1 | Nebenträger | HEA 120 | 0.698 | Wartung_FFB | 91.06 | 12.145 | 6.998 | 91.84 | 12.145 | 6.998 | 0 | 0.06 | 0.057 | 0122Tra0000013101 | m | T110 | false | HI_UZV_HEA_STA_0,120_xxx | 0
Nebenträger | Wartung_FFB | 1 | Nebenträger | HEA 120 | 0.698 | Wartung_FFB | 91.86 | 28.645 | 6.998 | 94.693 | 28.645 | 6.998 | 0 | 0.06 | 0.057 | 0122Tra0000020397 | m | T110 | false | HI_UZV_HEA_STA_0,120_xxx | 0
Nebenträger | Wartung_FFB | 1 | Nebenträger | HEA 120 | 0.698 | Wartung_FFB | 91.86 | 27.145 | 6.998 | 94.693 | 27.145 | 6.998 | 0 | 0.06 | 0.057 | 0122Tra0000020399 | m | T110 | false | HI_UZV_HEA_STA_0,120_xxx | 0
Nebenträger | Wartung_FFB | 1 | Nebenträger | HEA 120 | 0.698 | Wartung_FFB | 91.86 | 25.645 | 6.998 | 94.693 | 25.645 | 6.998 | 0 | 0.06 | 0.057 | 0122Tra0000020401 | m | T110 | false | HI_UZV_HEA_STA_0,120_xxx | 0
Nebenträger | Wartung_FFB | 1 | Nebenträger | HEA 120 | 0.698 | Wartung_FFB | 91.86 | 24.145 | 6.998 | 94.693 | 24.145 | 6.998 | 0 | 0.06 | 0.057 | 0122Tra0000020403 | m | T110 | false | HI_UZV_HEA_STA_0,120_xxx | 0
Nebenträger | Wartung_FFB | 1 | Nebenträger | HEA 120 | 0.698 | Wartung_FFB | 91.86 | 22.645 | 6.998 | 94.693 | 22.645 | 6.998 | 0 | 0.06 | 0.057 | 0122Tra0000020405 | m | T110 | false | HI_UZV_HEA_STA_0,120_xxx | 0
Nebenträger | Wartung_FFB | 1 | Nebenträger | HEA 120 | 0.698 | Wartung_FFB | 91.86 | 21.145 | 6.998 | 94.693 | 21.145 | 6.998 | 0 | 0.06 | 0.057 | 0122Tra0000020407 | m | T110 | false | HI_UZV_HEA_STA_0,120_xxx | 0
Nebenträger | Wartung_FFB | 1 | Nebenträger | HEA 120 | 0.698 | Wartung_FFB | 91.86 | 19.645 | 6.998 | 94.693 | 19.645 | 6.998 | 0 | 0.06 | 0.057 | 0122Tra0000020409 | m | T110 | false | HI_UZV_HEA_STA_0,120_xxx | 0
Nebenträger | Wartung_FFB | 1 | Nebenträger | HEA 120 | 0.698 | Wartung_FFB | 91.86 | 18.145 | 6.998 | 94.693 | 18.145 | 6.998 | 0 | 0.06 | 0.057 | 0122Tra0000020411 | m | T110 | false | HI_UZV_HEA_STA_0,120_xxx | 0
Nebenträger | Wartung_FFB | 1 | Nebenträger | HEA 120 | 0.698 | Wartung_FFB | 91.86 | 16.645 | 6.998 | 94.693 | 16.645 | 6.998 | 0 | 0.06 | 0.057 | 0122Tra0000020413 | m | T110 | false | HI_UZV_HEA_STA_0,120_xxx | 0
Nebenträger | Wartung_FFB | 1 | Nebenträger | HEA 120 | 0.698 | Wartung_FFB | 91.86 | 15.145 | 6.998 | 94.693 | 15.145 | 6.998 | 0 | 0.06 | 0.057 | 0122Tra0000020415 | m | T110 | false | HI_UZV_HEA_STA_0,120_xxx | 0
Nebenträger | Wartung_FFB | 1 | Nebenträger | HEA 120 | 0.698 | Wartung_FFB | 91.86 | 13.645 | 6.998 | 94.693 | 13.645 | 6.998 | 0 | 0.06 | 0.057 | 0122Tra0000020417 | m | T110 | false | HI_UZV_HEA_STA_0,120_xxx | 0
Nebenträger | Wartung_FFB | 1 | Nebenträger | HEA 120 | 0.698 | Wartung_FFB | 91.86 | 12.145 | 6.998 | 94.693 | 12.145 | 6.998 | 0 | 0.06 | 0.057 | 0122Tra0000020419 | m | T110 | false | HI_UZV_HEA_STA_0,120_xxx | 0
Kreuzverband | Wartung_FFB | 1 | Kreuzverband | L 80 x 8 | 0.32 | Wartung_FFB | 10.537 | 82.843 | 6.964 | 13.039 | 84.144 | 6.964 | 0 | 0.06 | 0.057 | 0122Tra0000020454 | m | - | false | HI_UZV_L_STA_0,080_xxx | 0
Kreuzverband | Wartung_FFB | 1 | Kreuzverband | L 80 x 8 | 0.32 | Wartung_FFB | 10.537 | 82.609 | 6.964 | 13.039 | 81.309 | 6.964 | 0 | 0.06 | 0.057 | 0122Tra0000020458 | m | - | false | HI_UZV_L_STA_0,080_xxx | 0
Kreuzverband | Wartung_FFB | 1 | Kreuzverband | L 80 x 8 | 0.32 | Wartung_FFB | 10.537 | 79.843 | 6.964 | 13.039 | 81.144 | 6.964 | 0 | 0.06 | 0.057 | 0122Tra0000020462 | m | - | false | HI_UZV_L_STA_0,080_xxx | 0
Kreuzverband | Wartung_FFB | 1 | Kreuzverband | L 80 x 8 | 0.32 | Wartung_FFB | 10.537 | 79.609 | 6.964 | 13.039 | 78.309 | 6.964 | 0 | 0.06 | 0.057 | 0122Tra0000020465 | m | - | false | HI_UZV_L_STA_0,080_xxx | 0
Kreuzverband | Wartung_FFB | 1 | Kreuzverband | L 80 x 8 | 0.32 | Wartung_FFB | 10.537 | 76.843 | 6.964 | 13.039 | 78.144 | 6.964 | 0 | 0.06 | 0.057 | 0122Tra0000020469 | m | - | false | HI_UZV_L_STA_0,080_xxx | 0
Kreuzverband | Wartung_FFB | 1 | Kreuzverband | L 80 x 8 | 0.32 | Wartung_FFB | 10.537 | 76.609 | 6.964 | 13.039 | 75.309 | 6.964 | 0 | 0.06 | 0.057 | 0122Tra0000020471 | m | - | false | HI_UZV_L_STA_0,080_xxx | 0
Kreuzverband | Wartung_FFB | 1 | Kreuzverband | L 80 x 8 | 0.32 | Wartung_FFB | 10.537 | 73.843 | 6.964 | 13.039 | 75.144 | 6.964 | 0 | 0.06 | 0.057 | 0122Tra0000020475 | m | - | false | HI_UZV_L_STA_0,080_xxx | 0
Kreuzverband | Wartung_FFB | 1 | Kreuzverband | L 80 x 8 | 0.32 | Wartung_FFB | 10.537 | 67.218 | 6.964 | 13.039 | 68.519 | 6.964 | 0 | 0.06 | 0.057 | 0122Tra0000020483 | m | - | false | HI_UZV_L_STA_0,080_xxx | 0
Kreuzverband | Wartung_FFB | 1 | Kreuzverband | L 80 x 8 | 0.32 | Wartung_FFB | 10.537 | 66.984 | 6.964 | 13.039 | 65.684 | 6.964 | 0 | 0.06 | 0.057 | 0122Tra0000020486 | m | - | false | HI_UZV_L_STA_0,080_xxx | 0
Kreuzverband | Wartung_FFB | 1 | Kreuzverband | L 80 x 8 | 0.32 | Wartung_FFB | 10.537 | 64.218 | 6.964 | 13.039 | 65.519 | 6.964 | 0 | 0.06 | 0.057 | 0122Tra0000020490 | m | - | false | HI_UZV_L_STA_0,080_xxx | 0
Kreuzverband | Wartung_FFB | 1 | Kreuzverband | L 80 x 8 | 0.32 | Wartung_FFB | 10.537 | 63.984 | 6.964 | 13.039 | 62.684 | 6.964 | 0 | 0.06 | 0.057 | 0122Tra0000020492 | m | - | false | HI_UZV_L_STA_0,080_xxx | 0
Kreuzverband | Wartung_FFB | 1 | Kreuzverband | L 80 x 8 | 0.32 | Wartung_FFB | 10.537 | 61.218 | 6.964 | 13.039 | 62.519 | 6.964 | 0 | 0.06 | 0.057 | 0122Tra0000020496 | m | - | false | HI_UZV_L_STA_0,080_xxx | 0
Kreuzverband | Wartung_FFB | 1 | Kreuzverband | L 80 x 8 | 0.32 | Wartung_FFB | 10.537 | 60.984 | 6.964 | 13.039 | 59.684 | 6.964 | 0 | 0.06 | 0.057 | 0122Tra0000020498 | m | - | false | HI_UZV_L_STA_0,080_xxx | 0
Kreuzverband | Wartung_FFB | 1 | Kreuzverband | L 80 x 8 | 0.32 | Wartung_FFB | 10.537 | 58.218 | 6.964 | 13.039 | 59.519 | 6.964 | 0 | 0.06 | 0.057 | 0122Tra0000020501 | m | - | false | HI_UZV_L_STA_0,080_xxx | 0
Kreuzverband | Wartung_FFB | 1 | Kreuzverband | L 80 x 8 | 0.32 | Wartung_FFB | 10.537 | 57.984 | 6.964 | 13.039 | 56.684 | 6.964 | 0 | 0.06 | 0.057 | 0122Tra0000020505 | m | - | false | HI_UZV_L_STA_0,080_xxx | 0
Kreuzverband | Wartung_FFB | 1 | Kreuzverband | L 80 x 8 | 0.32 | Wartung_FFB | 10.537 | 55.218 | 6.964 | 13.039 | 56.519 | 6.964 | 0 | 0.06 | 0.057 | 0122Tra0000020507 | m | - | false | HI_UZV_L_STA_0,080_xxx | 0
Kreuzverband | Wartung_FFB | 1 | Kreuzverband | L 80 x 8 | 0.32 | Wartung_FFB | 10.537 | 48.067 | 6.964 | 13.039 | 49.368 | 6.964 | 0 | 0.06 | 0.057 | 0122Tra0000020513 | m | - | false | HI_UZV_L_STA_0,080_xxx | 0
Kreuzverband | Wartung_FFB | 1 | Kreuzverband | L 80 x 8 | 0.32 | Wartung_FFB | 10.537 | 47.833 | 6.964 | 13.039 | 46.532 | 6.964 | 0 | 0.06 | 0.057 | 0122Tra0000020517 | m | - | false | HI_UZV_L_STA_0,080_xxx | 0
Kreuzverband | Wartung_FFB | 1 | Kreuzverband | L 80 x 8 | 0.32 | Wartung_FFB | 10.537 | 45.067 | 6.964 | 13.039 | 46.368 | 6.964 | 0 | 0.06 | 0.057 | 0122Tra0000020519 | m | - | false | HI_UZV_L_STA_0,080_xxx | 0
Kreuzverband | Wartung_FFB | 1 | Kreuzverband | L 80 x 8 | 0.32 | Wartung_FFB | 10.537 | 44.833 | 6.964 | 13.039 | 43.532 | 6.964 | 0 | 0.06 | 0.057 | 0122Tra0000020523 | m | - | false | HI_UZV_L_STA_0,080_xxx | 0
Kreuzverband | Wartung_FFB | 1 | Kreuzverband | L 80 x 8 | 0.32 | Wartung_FFB | 10.537 | 42.067 | 6.964 | 13.039 | 43.368 | 6.964 | 0 | 0.06 | 0.057 | 0122Tra0000020525 | m | - | false | HI_UZV_L_STA_0,080_xxx | 0
Kreuzverband | Wartung_FFB | 1 | Kreuzverband | L 80 x 8 | 0.32 | Wartung_FFB | 10.537 | 41.833 | 6.964 | 13.039 | 40.532 | 6.964 | 0 | 0.06 | 0.057 | 0122Tra0000020529 | m | - | false | HI_UZV_L_STA_0,080_xxx | 0
Kreuzverband | Wartung_FFB | 1 | Kreuzverband | L 80 x 8 | 0.32 | Wartung_FFB | 10.537 | 39.067 | 6.964 | 13.039 | 40.368 | 6.964 | 0 | 0.06 | 0.057 | 0122Tra0000020531 | m | - | false | HI_UZV_L_STA_0,080_xxx | 0
Kreuzverband | Wartung_FFB | 1 | Kreuzverband | L 80 x 8 | 0.32 | Wartung_FFB | 10.537 | 38.833 | 6.964 | 13.039 | 37.532 | 6.964 | 0 | 0.06 | 0.057 | 0122Tra0000020535 | m | - | false | HI_UZV_L_STA_0,080_xxx | 0
Kreuzverband | Wartung_FFB | 1 | Kreuzverband | L 80 x 8 | 0.32 | Wartung_FFB | 10.537 | 36.067 | 6.964 | 13.039 | 37.368 | 6.964 | 0 | 0.06 | 0.057 | 0122Tra0000020537 | m | - | false | HI_UZV_L_STA_0,080_xxx | 0
Kreuzverband | Wartung_FFB | 1 | Kreuzverband | L 80 x 8 | 0.32 | Wartung_FFB | 10.537 | 35.833 | 6.964 | 13.039 | 34.532 | 6.964 | 0 | 0.06 | 0.057 | 0122Tra0000020541 | m | - | false | HI_UZV_L_STA_0,080_xxx | 0
Kreuzverband | Wartung_FFB | 1 | Kreuzverband | L 80 x 8 | 0.32 | Wartung_FFB | 10.537 | 27.262 | 6.964 | 13.039 | 28.563 | 6.964 | 0 | 0.06 | 0.057 | 0122Tra0000020549 | m | - | false | HI_UZV_L_STA_0,080_xxx | 0
Kreuzverband | Wartung_FFB | 1 | Kreuzverband | L 80 x 8 | 0.32 | Wartung_FFB | 10.537 | 27.028 | 6.964 | 13.039 | 25.727 | 6.964 | 0 | 0.06 | 0.057 | 0122Tra0000020553 | m | - | false | HI_UZV_L_STA_0,080_xxx | 0
Kreuzverband | Wartung_FFB | 1 | Kreuzverband | L 80 x 8 | 0.32 | Wartung_FFB | 10.537 | 24.262 | 6.964 | 13.039 | 25.563 | 6.964 | 0 | 0.06 | 0.057 | 0122Tra0000020555 | m | - | false | HI_UZV_L_STA_0,080_xxx | 0
Kreuzverband | Wartung_FFB | 1 | Kreuzverband | L 80 x 8 | 0.32 | Wartung_FFB | 10.537 | 24.028 | 6.964 | 13.039 | 22.727 | 6.964 | 0 | 0.06 | 0.057 | 0122Tra0000020559 | m | - | false | HI_UZV_L_STA_0,080_xxx | 0
Kreuzverband | Wartung_FFB | 1 | Kreuzverband | L 80 x 8 | 0.32 | Wartung_FFB | 10.537 | 21.262 | 6.964 | 13.039 | 22.563 | 6.964 | 0 | 0.06 | 0.057 | 0122Tra0000020561 | m | - | false | HI_UZV_L_STA_0,080_xxx | 0
Kreuzverband | Wartung_FFB | 1 | Kreuzverband | L 80 x 8 | 0.32 | Wartung_FFB | 10.537 | 21.028 | 6.964 | 13.039 | 19.727 | 6.964 | 0 | 0.06 | 0.057 | 0122Tra0000020565 | m | - | false | HI_UZV_L_STA_0,080_xxx | 0
Kreuzverband | Wartung_FFB | 1 | Kreuzverband | L 80 x 8 | 0.32 | Wartung_FFB | 10.537 | 18.262 | 6.964 | 13.039 | 19.563 | 6.964 | 0 | 0.06 | 0.057 | 0122Tra0000020567 | m | - | false | HI_UZV_L_STA_0,080_xxx | 0
Kreuzverband | Wartung_FFB | 1 | Kreuzverband | L 80 x 8 | 0.32 | Wartung_FFB | 10.537 | 18.028 | 6.964 | 13.039 | 16.727 | 6.964 | 0 | 0.06 | 0.057 | 0122Tra0000020571 | m | - | false | HI_UZV_L_STA_0,080_xxx | 0
Kreuzverband | Wartung_FFB | 1 | Kreuzverband | L 80 x 8 | 0.32 | Wartung_FFB | 10.537 | 15.262 | 6.964 | 13.039 | 16.563 | 6.964 | 0 | 0.06 | 0.057 | 0122Tra0000020573 | m | - | false | HI_UZV_L_STA_0,080_xxx | 0
Kreuzverband | Wartung_FFB | 1 | Kreuzverband | L 80 x 8 | 0.32 | Wartung_FFB | 10.537 | 15.028 | 6.964 | 13.039 | 13.727 | 6.964 | 0 | 0.06 | 0.057 | 0122Tra0000020577 | m | - | false | HI_UZV_L_STA_0,080_xxx | 0
Kreuzverband | Wartung_FFB | 1 | Kreuzverband | L 80 x 8 | 0.32 | Wartung_FFB | 46.041 | 15.027 | 6.964 | 49.043 | 13.732 | 6.964 | 0 | 0.06 | 0.057 | 0122Tra0000020582 | m | - | false | HI_UZV_L_STA_0,080_xxx | 0
Kreuzverband | Wartung_FFB | 1 | Kreuzverband | L 80 x 8 | 0.32 | Wartung_FFB | 46.041 | 15.263 | 6.964 | 49.043 | 16.558 | 6.964 | 0 | 0.06 | 0.057 | 0122Tra0000020586 | m | - | false | HI_UZV_L_STA_0,080_xxx | 0
Kreuzverband | Wartung_FFB | 1 | Kreuzverband | L 80 x 8 | 0.32 | Wartung_FFB | 46.041 | 18.027 | 6.964 | 49.043 | 16.732 | 6.964 | 0 | 0.06 | 0.057 | 0122Tra0000020590 | m | - | false | HI_UZV_L_STA_0,080_xxx | 0
Kreuzverband | Wartung_FFB | 1 | Kreuzverband | L 80 x 8 | 0.32 | Wartung_FFB | 46.041 | 18.263 | 6.964 | 49.043 | 19.558 | 6.964 | 0 | 0.06 | 0.057 | 0122Tra0000020593 | m | - | false | HI_UZV_L_STA_0,080_xxx | 0
Kreuzverband | Wartung_FFB | 1 | Kreuzverband | L 80 x 8 | 0.32 | Wartung_FFB | 46.041 | 21.027 | 6.964 | 49.043 | 19.732 | 6.964 | 0 | 0.06 | 0.057 | 0122Tra0000020596 | m | - | false | HI_UZV_L_STA_0,080_xxx | 0
Kreuzverband | Wartung_FFB | 1 | Kreuzverband | L 80 x 8 | 0.32 | Wartung_FFB | 46.041 | 21.263 | 6.964 | 49.043 | 22.558 | 6.964 | 0 | 0.06 | 0.057 | 0122Tra0000020600 | m | - | false | HI_UZV_L_STA_0,080_xxx | 0
Kreuzverband | Wartung_FFB | 1 | Kreuzverband | L 80 x 8 | 0.32 | Wartung_FFB | 46.041 | 24.027 | 6.964 | 49.043 | 22.732 | 6.964 | 0 | 0.06 | 0.057 | 0122Tra0000020602 | m | - | false | HI_UZV_L_STA_0,080_xxx | 0
Kreuzverband | Wartung_FFB | 1 | Kreuzverband | L 80 x 8 | 0.32 | Wartung_FFB | 46.041 | 24.263 | 6.964 | 49.043 | 25.558 | 6.964 | 0 | 0.06 | 0.057 | 0122Tra0000020606 | m | - | false | HI_UZV_L_STA_0,080_xxx | 0
Kreuzverband | Wartung_FFB | 1 | Kreuzverband | L 80 x 8 | 0.32 | Wartung_FFB | 46.041 | 27.027 | 6.964 | 49.043 | 25.732 | 6.964 | 0 | 0.06 | 0.057 | 0122Tra0000020608 | m | - | false | HI_UZV_L_STA_0,080_xxx | 0
Kreuzverband | Wartung_FFB | 1 | Kreuzverband | L 80 x 8 | 0.32 | Wartung_FFB | 46.041 | 27.263 | 6.964 | 49.043 | 28.558 | 6.964 | 0 | 0.06 | 0.057 | 0122Tra0000020612 | m | - | false | HI_UZV_L_STA_0,080_xxx | 0
Kreuzverband | Wartung_FFB | 1 | Kreuzverband | L 80 x 8 | 0.32 | Wartung_FFB | 45.976 | 36.068 | 6.964 | 48.978 | 37.363 | 6.964 | 0 | 0.06 | 0.057 | 0122Tra0000020618 | m | - | false | HI_UZV_L_STA_0,080_xxx | 0
Kreuzverband | Wartung_FFB | 1 | Kreuzverband | L 80 x 8 | 0.32 | Wartung_FFB | 45.976 | 38.832 | 6.964 | 48.978 | 37.537 | 6.964 | 0 | 0.06 | 0.057 | 0122Tra0000020620 | m | - | false | HI_UZV_L_STA_0,080_xxx | 0
Kreuzverband | Wartung_FFB | 1 | Kreuzverband | L 80 x 8 | 0.32 | Wartung_FFB | 45.976 | 39.068 | 6.964 | 48.978 | 40.363 | 6.964 | 0 | 0.06 | 0.057 | 0122Tra0000020624 | m | - | false | HI_UZV_L_STA_0,080_xxx | 0
Kreuzverband | Wartung_FFB | 1 | Kreuzverband | L 80 x 8 | 0.32 | Wartung_FFB | 45.976 | 41.832 | 6.964 | 48.978 | 40.537 | 6.964 | 0 | 0.06 | 0.057 | 0122Tra0000020626 | m | - | false | HI_UZV_L_STA_0,080_xxx | 0
Kreuzverband | Wartung_FFB | 1 | Kreuzverband | L 80 x 8 | 0.32 | Wartung_FFB | 45.976 | 42.068 | 6.964 | 48.978 | 43.363 | 6.964 | 0 | 0.06 | 0.057 | 0122Tra0000020630 | m | - | false | HI_UZV_L_STA_0,080_xxx | 0
Kreuzverband | Wartung_FFB | 1 | Kreuzverband | L 80 x 8 | 0.32 | Wartung_FFB | 45.976 | 44.832 | 6.964 | 48.978 | 43.537 | 6.964 | 0 | 0.06 | 0.057 | 0122Tra0000020632 | m | - | false | HI_UZV_L_STA_0,080_xxx | 0
Kreuzverband | Wartung_FFB | 1 | Kreuzverband | L 80 x 8 | 0.32 | Wartung_FFB | 45.976 | 45.068 | 6.964 | 48.978 | 46.363 | 6.964 | 0 | 0.06 | 0.057 | 0122Tra0000020636 | m | - | false | HI_UZV_L_STA_0,080_xxx | 0
Kreuzverband | Wartung_FFB | 1 | Kreuzverband | L 80 x 8 | 0.32 | Wartung_FFB | 45.976 | 47.832 | 6.964 | 48.978 | 46.537 | 6.964 | 0 | 0.06 | 0.057 | 0122Tra0000020638 | m | - | false | HI_UZV_L_STA_0,080_xxx | 0
Kreuzverband | Wartung_FFB | 1 | Kreuzverband | L 80 x 8 | 0.32 | Wartung_FFB | 45.976 | 48.068 | 6.964 | 48.978 | 49.363 | 6.964 | 0 | 0.06 | 0.057 | 0122Tra0000020642 | m | - | false | HI_UZV_L_STA_0,080_xxx | 0
Kreuzverband | Wartung_FFB | 1 | Kreuzverband | L 80 x 8 | 0.32 | Wartung_FFB | 84.336 | 67.217 | 6.964 | 86.739 | 68.514 | 6.964 | 0 | 0.06 | 0.057 | 0122Tra0000020831 | m | - | false | HI_UZV_L_STA_0,080_xxx | 0
Kreuzverband | Wartung_FFB | 1 | Kreuzverband | L 80 x 8 | 0.32 | Wartung_FFB | 84.336 | 66.985 | 6.964 | 86.739 | 65.689 | 6.964 | 0 | 0.06 | 0.057 | 0122Tra0000020837 | m | - | false | HI_UZV_L_STA_0,080_xxx | 0
Kreuzverband | Wartung_FFB | 1 | Kreuzverband | L 80 x 8 | 0.32 | Wartung_FFB | 84.336 | 64.217 | 6.964 | 86.739 | 65.514 | 6.964 | 0 | 0.06 | 0.057 | 0122Tra0000020843 | m | - | false | HI_UZV_L_STA_0,080_xxx | 0
Kreuzverband | Wartung_FFB | 1 | Kreuzverband | L 80 x 8 | 0.32 | Wartung_FFB | 84.336 | 63.985 | 6.964 | 86.739 | 62.689 | 6.964 | 0 | 0.06 | 0.057 | 0122Tra0000020853 | m | - | false | HI_UZV_L_STA_0,080_xxx | 0
Kreuzverband | Wartung_FFB | 1 | Kreuzverband | L 80 x 8 | 0.32 | Wartung_FFB | 84.336 | 61.217 | 6.964 | 86.739 | 62.514 | 6.964 | 0 | 0.06 | 0.057 | 0122Tra0000020859 | m | - | false | HI_UZV_L_STA_0,080_xxx | 0
Kreuzverband | Wartung_FFB | 1 | Kreuzverband | L 80 x 8 | 0.32 | Wartung_FFB | 84.336 | 60.985 | 6.964 | 86.739 | 59.689 | 6.964 | 0 | 0.06 | 0.057 | 0122Tra0000020861 | m | - | false | HI_UZV_L_STA_0,080_xxx | 0
Kreuzverband | Wartung_FFB | 1 | Kreuzverband | L 80 x 8 | 0.32 | Wartung_FFB | 84.336 | 58.217 | 6.964 | 86.739 | 59.514 | 6.964 | 0 | 0.06 | 0.057 | 0122Tra0000020867 | m | - | false | HI_UZV_L_STA_0,080_xxx | 0
Kreuzverband | Wartung_FFB | 1 | Kreuzverband | L 80 x 8 | 0.32 | Wartung_FFB | 84.336 | 57.985 | 6.964 | 86.739 | 56.689 | 6.964 | 0 | 0.06 | 0.057 | 0122Tra0000020877 | m | - | false | HI_UZV_L_STA_0,080_xxx | 0
Kreuzverband | Wartung_FFB | 1 | Kreuzverband | L 80 x 8 | 0.32 | Wartung_FFB | 84.336 | 55.217 | 6.964 | 86.739 | 56.514 | 6.964 | 0 | 0.06 | 0.057 | 0122Tra0000020883 | m | - | false | HI_UZV_L_STA_0,080_xxx | 0
Kreuzverband | Wartung_FFB | 1 | Kreuzverband | L 80 x 8 | 0.32 | Wartung_FFB | 46.041 | 73.845 | 6.964 | 49.043 | 75.139 | 6.964 | 0 | 0.06 | 0.057 | 0122Tra0000020678 | m | - | false | HI_UZV_L_STA_0,080_xxx | 0
Kreuzverband | Wartung_FFB | 1 | Kreuzverband | L 80 x 8 | 0.32 | Wartung_FFB | 46.041 | 76.608 | 6.964 | 49.043 | 75.313 | 6.964 | 0 | 0.06 | 0.057 | 0122Tra0000020680 | m | - | false | HI_UZV_L_STA_0,080_xxx | 0
Kreuzverband | Wartung_FFB | 1 | Kreuzverband | L 80 x 8 | 0.32 | Wartung_FFB | 46.041 | 76.845 | 6.964 | 49.043 | 78.139 | 6.964 | 0 | 0.06 | 0.057 | 0122Tra0000020684 | m | - | false | HI_UZV_L_STA_0,080_xxx | 0
Kreuzverband | Wartung_FFB | 1 | Kreuzverband | L 80 x 8 | 0.32 | Wartung_FFB | 46.041 | 79.608 | 6.964 | 49.043 | 78.313 | 6.964 | 0 | 0.06 | 0.057 | 0122Tra0000020686 | m | - | false | HI_UZV_L_STA_0,080_xxx | 0
Kreuzverband | Wartung_FFB | 1 | Kreuzverband | L 80 x 8 | 0.32 | Wartung_FFB | 46.041 | 79.845 | 6.964 | 49.043 | 81.139 | 6.964 | 0 | 0.06 | 0.057 | 0122Tra0000020690 | m | - | false | HI_UZV_L_STA_0,080_xxx | 0
Kreuzverband | Wartung_FFB | 1 | Kreuzverband | L 80 x 8 | 0.32 | Wartung_FFB | 46.041 | 82.608 | 6.964 | 49.043 | 81.313 | 6.964 | 0 | 0.06 | 0.057 | 0122Tra0000020692 | m | - | false | HI_UZV_L_STA_0,080_xxx | 0
Kreuzverband | Wartung_FFB | 1 | Kreuzverband | L 80 x 8 | 0.32 | Wartung_FFB | 46.041 | 82.845 | 6.964 | 49.043 | 84.139 | 6.964 | 0 | 0.06 | 0.057 | 0122Tra0000020696 | m | - | false | HI_UZV_L_STA_0,080_xxx | 0
Kreuzverband | Wartung_FFB | 1 | Kreuzverband | L 80 x 8 | 0.32 | Wartung_FFB | 84.336 | 82.842 | 6.964 | 86.739 | 84.139 | 6.964 | 0 | 0.06 | 0.057 | 0122Tra0000020782 | m | - | false | HI_UZV_L_STA_0,080_xxx | 0
Kreuzverband | Wartung_FFB | 1 | Kreuzverband | L 80 x 8 | 0.32 | Wartung_FFB | 84.336 | 82.61 | 6.964 | 86.739 | 81.314 | 6.964 | 0 | 0.06 | 0.057 | 0122Tra0000020786 | m | - | false | HI_UZV_L_STA_0,080_xxx | 0
Kreuzverband | Wartung_FFB | 1 | Kreuzverband | L 80 x 8 | 0.32 | Wartung_FFB | 84.336 | 79.842 | 6.964 | 86.739 | 81.139 | 6.964 | 0 | 0.06 | 0.057 | 0122Tra0000020795 | m | - | false | HI_UZV_L_STA_0,080_xxx | 0
Kreuzverband | Wartung_FFB | 1 | Kreuzverband | L 80 x 8 | 0.32 | Wartung_FFB | 84.336 | 79.61 | 6.964 | 86.739 | 78.314 | 6.964 | 0 | 0.06 | 0.057 | 0122Tra0000020801 | m | - | false | HI_UZV_L_STA_0,080_xxx | 0
Kreuzverband | Wartung_FFB | 1 | Kreuzverband | L 80 x 8 | 0.32 | Wartung_FFB | 84.336 | 76.842 | 6.964 | 86.739 | 78.139 | 6.964 | 0 | 0.06 | 0.057 | 0122Tra0000020807 | m | - | false | HI_UZV_L_STA_0,080_xxx | 0
Kreuzverband | Wartung_FFB | 1 | Kreuzverband | L 80 x 8 | 0.32 | Wartung_FFB | 84.336 | 76.61 | 6.964 | 86.739 | 75.314 | 6.964 | 0 | 0.06 | 0.057 | 0122Tra0000020813 | m | - | false | HI_UZV_L_STA_0,080_xxx | 0
Kreuzverband | Wartung_FFB | 1 | Kreuzverband | L 80 x 8 | 0.32 | Wartung_FFB | 84.336 | 73.842 | 6.964 | 86.739 | 75.139 | 6.964 | 0 | 0.06 | 0.057 | 0122Tra0000020819 | m | - | false | HI_UZV_L_STA_0,080_xxx | 0
Kreuzverband | Wartung_FFB | 1 | Kreuzverband | L 80 x 8 | 0.32 | Wartung_FFB | 118.039 | 67.219 | 6.964 | 120.725 | 68.513 | 6.964 | 0 | 0.06 | 0.057 | 0122Tra0000020828 | m | - | false | HI_UZV_L_STA_0,080_xxx | 0
Kreuzverband | Wartung_FFB | 1 | Kreuzverband | L 80 x 8 | 0.32 | Wartung_FFB | 118.039 | 66.984 | 6.964 | 120.725 | 65.689 | 6.964 | 0 | 0.06 | 0.057 | 0122Tra0000020839 | m | - | false | HI_UZV_L_STA_0,080_xxx | 0
Kreuzverband | Wartung_FFB | 1 | Kreuzverband | L 80 x 8 | 0.32 | Wartung_FFB | 118.039 | 64.219 | 6.964 | 120.725 | 65.513 | 6.964 | 0 | 0.06 | 0.057 | 0122Tra0000020841 | m | - | false | HI_UZV_L_STA_0,080_xxx | 0
Kreuzverband | Wartung_FFB | 1 | Kreuzverband | L 80 x 8 | 0.32 | Wartung_FFB | 118.039 | 63.984 | 6.964 | 120.725 | 62.689 | 6.964 | 0 | 0.06 | 0.057 | 0122Tra0000020855 | m | - | false | HI_UZV_L_STA_0,080_xxx | 0
Kreuzverband | Wartung_FFB | 1 | Kreuzverband | L 80 x 8 | 0.32 | Wartung_FFB | 118.039 | 61.219 | 6.964 | 120.725 | 62.513 | 6.964 | 0 | 0.06 | 0.057 | 0122Tra0000020857 | m | - | false | HI_UZV_L_STA_0,080_xxx | 0
Kreuzverband | Wartung_FFB | 1 | Kreuzverband | L 80 x 8 | 0.32 | Wartung_FFB | 118.039 | 60.984 | 6.964 | 120.725 | 59.689 | 6.964 | 0 | 0.06 | 0.057 | 0122Tra0000020863 | m | - | false | HI_UZV_L_STA_0,080_xxx | 0
Kreuzverband | Wartung_FFB | 1 | Kreuzverband | L 80 x 8 | 0.32 | Wartung_FFB | 118.039 | 58.219 | 6.964 | 120.725 | 59.513 | 6.964 | 0 | 0.06 | 0.057 | 0122Tra0000020865 | m | - | false | HI_UZV_L_STA_0,080_xxx | 0
Kreuzverband | Wartung_FFB | 1 | Kreuzverband | L 80 x 8 | 0.32 | Wartung_FFB | 118.039 | 57.984 | 6.964 | 120.725 | 56.689 | 6.964 | 0 | 0.06 | 0.057 | 0122Tra0000020879 | m | - | false | HI_UZV_L_STA_0,080_xxx | 0
Kreuzverband | Wartung_FFB | 1 | Kreuzverband | L 80 x 8 | 0.32 | Wartung_FFB | 118.039 | 55.219 | 6.964 | 120.725 | 56.513 | 6.964 | 0 | 0.06 | 0.057 | 0122Tra0000020881 | m | - | false | HI_UZV_L_STA_0,080_xxx | 0
Kreuzverband | Wartung_FFB | 1 | Kreuzverband | L 80 x 8 | 0.32 | Wartung_FFB | 118.039 | 82.844 | 6.964 | 120.725 | 84.138 | 6.964 | 0 | 0.06 | 0.057 | 0122Tra0000020778 | m | - | false | HI_UZV_L_STA_0,080_xxx | 0
Kreuzverband | Wartung_FFB | 1 | Kreuzverband | L 80 x 8 | 0.32 | Wartung_FFB | 118.039 | 82.609 | 6.964 | 120.725 | 81.314 | 6.964 | 0 | 0.06 | 0.057 | 0122Tra0000020789 | m | - | false | HI_UZV_L_STA_0,080_xxx | 0
Kreuzverband | Wartung_FFB | 1 | Kreuzverband | L 80 x 8 | 0.32 | Wartung_FFB | 118.039 | 79.844 | 6.964 | 120.725 | 81.138 | 6.964 | 0 | 0.06 | 0.057 | 0122Tra0000020792 | m | - | false | HI_UZV_L_STA_0,080_xxx | 0
Kreuzverband | Wartung_FFB | 1 | Kreuzverband | L 80 x 8 | 0.32 | Wartung_FFB | 118.039 | 79.609 | 6.964 | 120.725 | 78.314 | 6.964 | 0 | 0.06 | 0.057 | 0122Tra0000020803 | m | - | false | HI_UZV_L_STA_0,080_xxx | 0
Kreuzverband | Wartung_FFB | 1 | Kreuzverband | L 80 x 8 | 0.32 | Wartung_FFB | 118.039 | 76.844 | 6.964 | 120.725 | 78.138 | 6.964 | 0 | 0.06 | 0.057 | 0122Tra0000020805 | m | - | false | HI_UZV_L_STA_0,080_xxx | 0
Kreuzverband | Wartung_FFB | 1 | Kreuzverband | L 80 x 8 | 0.32 | Wartung_FFB | 118.039 | 76.609 | 6.964 | 120.725 | 75.314 | 6.964 | 0 | 0.06 | 0.057 | 0122Tra0000020815 | m | - | false | HI_UZV_L_STA_0,080_xxx | 0
Kreuzverband | Wartung_FFB | 1 | Kreuzverband | L 80 x 8 | 0.32 | Wartung_FFB | 118.039 | 73.844 | 6.964 | 120.725 | 75.138 | 6.964 | 0 | 0.06 | 0.057 | 0122Tra0000020817 | m | - | false | HI_UZV_L_STA_0,080_xxx | 0
Kreuzverband | Wartung_FFB | 1 | Kreuzverband | L 80 x 8 | 0.32 | Wartung_FFB | 85.041 | 27.263 | 6.964 | 88.043 | 28.558 | 6.964 | 0 | 0.06 | 0.057 | 0122Tra0000020702 | m | - | false | HI_UZV_L_STA_0,080_xxx | 0
Kreuzverband | Wartung_FFB | 1 | Kreuzverband | L 80 x 8 | 0.32 | Wartung_FFB | 85.041 | 24.263 | 6.964 | 88.043 | 25.558 | 6.964 | 0 | 0.06 | 0.057 | 0122Tra0000020708 | m | - | false | HI_UZV_L_STA_0,080_xxx | 0
Kreuzverband | Wartung_FFB | 1 | Kreuzverband | L 80 x 8 | 0.32 | Wartung_FFB | 85.041 | 27.027 | 6.964 | 88.043 | 25.732 | 6.964 | 0 | 0.06 | 0.057 | 0122Tra0000020710 | m | - | false | HI_UZV_L_STA_0,080_xxx | 0
Kreuzverband | Wartung_FFB | 1 | Kreuzverband | L 80 x 8 | 0.32 | Wartung_FFB | 85.041 | 21.263 | 6.964 | 88.043 | 22.558 | 6.964 | 0 | 0.06 | 0.057 | 0122Tra0000020714 | m | - | false | HI_UZV_L_STA_0,080_xxx | 0
Kreuzverband | Wartung_FFB | 1 | Kreuzverband | L 80 x 8 | 0.32 | Wartung_FFB | 85.041 | 24.027 | 6.964 | 88.043 | 22.732 | 6.964 | 0 | 0.06 | 0.057 | 0122Tra0000020716 | m | - | false | HI_UZV_L_STA_0,080_xxx | 0
Kreuzverband | Wartung_FFB | 1 | Kreuzverband | L 80 x 8 | 0.32 | Wartung_FFB | 85.041 | 18.263 | 6.964 | 88.043 | 19.558 | 6.964 | 0 | 0.06 | 0.057 | 0122Tra0000020720 | m | - | false | HI_UZV_L_STA_0,080_xxx | 0
Kreuzverband | Wartung_FFB | 1 | Kreuzverband | L 80 x 8 | 0.32 | Wartung_FFB | 85.041 | 21.027 | 6.964 | 88.043 | 19.732 | 6.964 | 0 | 0.06 | 0.057 | 0122Tra0000020722 | m | - | false | HI_UZV_L_STA_0,080_xxx | 0
Kreuzverband | Wartung_FFB | 1 | Kreuzverband | L 80 x 8 | 0.32 | Wartung_FFB | 85.041 | 15.263 | 6.964 | 88.043 | 16.558 | 6.964 | 0 | 0.06 | 0.057 | 0122Tra0000020726 | m | - | false | HI_UZV_L_STA_0,080_xxx | 0
Kreuzverband | Wartung_FFB | 1 | Kreuzverband | L 80 x 8 | 0.32 | Wartung_FFB | 85.041 | 18.027 | 6.964 | 88.043 | 16.732 | 6.964 | 0 | 0.06 | 0.057 | 0122Tra0000020728 | m | - | false | HI_UZV_L_STA_0,080_xxx | 0
Kreuzverband | Wartung_FFB | 1 | Kreuzverband | L 80 x 8 | 0.32 | Wartung_FFB | 85.041 | 15.027 | 6.964 | 88.043 | 13.732 | 6.964 | 0 | 0.06 | 0.057 | 0122Tra0000020734 | m | - | false | HI_UZV_L_STA_0,080_xxx | 0
Kreuzverband | Wartung_FFB | 1 | Kreuzverband | L 80 x 8 | 0.32 | Wartung_FFB | 118.041 | 27.263 | 6.964 | 121.043 | 28.558 | 6.964 | 0 | 0.06 | 0.057 | 0122Tra0000020738 | m | - | false | HI_UZV_L_STA_0,080_xxx | 0
Kreuzverband | Wartung_FFB | 1 | Kreuzverband | L 80 x 8 | 0.32 | Wartung_FFB | 118.041 | 24.263 | 6.964 | 121.043 | 25.558 | 6.964 | 0 | 0.06 | 0.057 | 0122Tra0000020744 | m | - | false | HI_UZV_L_STA_0,080_xxx | 0
Kreuzverband | Wartung_FFB | 1 | Kreuzverband | L 80 x 8 | 0.32 | Wartung_FFB | 118.041 | 27.027 | 6.964 | 121.043 | 25.732 | 6.964 | 0 | 0.06 | 0.057 | 0122Tra0000020746 | m | - | false | HI_UZV_L_STA_0,080_xxx | 0
Kreuzverband | Wartung_FFB | 1 | Kreuzverband | L 80 x 8 | 0.32 | Wartung_FFB | 118.041 | 21.263 | 6.964 | 121.043 | 22.558 | 6.964 | 0 | 0.06 | 0.057 | 0122Tra0000020750 | m | - | false | HI_UZV_L_STA_0,080_xxx | 0
Kreuzverband | Wartung_FFB | 1 | Kreuzverband | L 80 x 8 | 0.32 | Wartung_FFB | 118.041 | 24.027 | 6.964 | 121.043 | 22.732 | 6.964 | 0 | 0.06 | 0.057 | 0122Tra0000020752 | m | - | false | HI_UZV_L_STA_0,080_xxx | 0
Kreuzverband | Wartung_FFB | 1 | Kreuzverband | L 80 x 8 | 0.32 | Wartung_FFB | 118.041 | 18.263 | 6.964 | 121.043 | 19.558 | 6.964 | 0 | 0.06 | 0.057 | 0122Tra0000020756 | m | - | false | HI_UZV_L_STA_0,080_xxx | 0
Kreuzverband | Wartung_FFB | 1 | Kreuzverband | L 80 x 8 | 0.32 | Wartung_FFB | 118.041 | 21.027 | 6.964 | 121.043 | 19.732 | 6.964 | 0 | 0.06 | 0.057 | 0122Tra0000020758 | m | - | false | HI_UZV_L_STA_0,080_xxx | 0
Kreuzverband | Wartung_FFB | 1 | Kreuzverband | L 80 x 8 | 0.32 | Wartung_FFB | 118.041 | 15.263 | 6.964 | 121.043 | 16.558 | 6.964 | 0 | 0.06 | 0.057 | 0122Tra0000020762 | m | - | false | HI_UZV_L_STA_0,080_xxx | 0
Kreuzverband | Wartung_FFB | 1 | Kreuzverband | L 80 x 8 | 0.32 | Wartung_FFB | 118.041 | 18.027 | 6.964 | 121.043 | 16.732 | 6.964 | 0 | 0.06 | 0.057 | 0122Tra0000020764 | m | - | false | HI_UZV_L_STA_0,080_xxx | 0
Kreuzverband | Wartung_FFB | 1 | Kreuzverband | L 80 x 8 | 0.32 | Wartung_FFB | 118.041 | 15.027 | 6.964 | 121.043 | 13.732 | 6.964 | 0 | 0.06 | 0.057 | 0122Tra0000020767 | m | - | false | HI_UZV_L_STA_0,080_xxx | 0
Kreuzverband | Wartung_FFB | 1 | Kreuzverband | L 80 x 8 | 0.32 | Wartung_FFB | 10.537 | 73.609 | 6.964 | 13.039 | 72.309 | 6.964 | 0 | 0.06 | 0.057 | 0122Tra0000020895 | m | - | false | HI_UZV_L_STA_0,080_xxx | 0
Kreuzverband | Wartung_FFB | 1 | Kreuzverband | L 80 x 8 | 0.32 | Wartung_FFB | 10.537 | 54.984 | 6.964 | 13.039 | 53.684 | 6.964 | 0 | 0.06 | 0.057 | 0122Tra0000020903 | m | - | false | HI_UZV_L_STA_0,080_xxx | 0
Kreuzverband | Wartung_FFB | 1 | Kreuzverband | L 80 x 8 | 0.32 | Wartung_FFB | 10.537 | 33.067 | 6.964 | 13.039 | 34.368 | 6.964 | 0 | 0.06 | 0.057 | 0122Tra0000020907 | m | - | false | HI_UZV_L_STA_0,080_xxx | 0
Kreuzverband | Wartung_FFB | 1 | Kreuzverband | L 80 x 8 | 0.32 | Wartung_FFB | 10.537 | 12.262 | 6.964 | 13.039 | 13.563 | 6.964 | 0 | 0.06 | 0.057 | 0122Tra0000020921 | m | - | false | HI_UZV_L_STA_0,080_xxx | 0
Kreuzverband | Wartung_FFB | 1 | Kreuzverband | L 80 x 8 | 0.32 | Wartung_FFB | 46.041 | 12.263 | 6.964 | 49.043 | 13.558 | 6.964 | 0 | 0.06 | 0.057 | 0122Tra0000020927 | m | - | false | HI_UZV_L_STA_0,080_xxx | 0
Kreuzverband | Wartung_FFB | 1 | Kreuzverband | L 80 x 8 | 0.32 | Wartung_FFB | 45.976 | 33.068 | 6.964 | 48.978 | 34.363 | 6.964 | 0 | 0.06 | 0.057 | 0122Tra0000020929 | m | - | false | HI_UZV_L_STA_0,080_xxx | 0
Kreuzverband | Wartung_FFB | 1 | Kreuzverband | L 80 x 8 | 0.32 | Wartung_FFB | 45.976 | 35.832 | 6.964 | 48.978 | 34.537 | 6.964 | 0 | 0.06 | 0.057 | 0122Tra0000020931 | m | - | false | HI_UZV_L_STA_0,080_xxx | 0
Kreuzverband | Wartung_FFB | 1 | Kreuzverband | L 80 x 8 | 0.32 | Wartung_FFB | 84.336 | 54.985 | 6.964 | 86.739 | 53.689 | 6.964 | 0 | 0.06 | 0.057 | 0122Tra0000020937 | m | - | false | HI_UZV_L_STA_0,080_xxx | 0
Kreuzverband | Wartung_FFB | 1 | Kreuzverband | L 80 x 8 | 0.32 | Wartung_FFB | 46.041 | 73.608 | 6.964 | 49.043 | 72.313 | 6.964 | 0 | 0.06 | 0.057 | 0122Tra0000020945 | m | - | false | HI_UZV_L_STA_0,080_xxx | 0
Kreuzverband | Wartung_FFB | 1 | Kreuzverband | L 80 x 8 | 0.32 | Wartung_FFB | 84.336 | 73.61 | 6.964 | 86.739 | 72.314 | 6.964 | 0 | 0.06 | 0.057 | 0122Tra0000020949 | m | - | false | HI_UZV_L_STA_0,080_xxx | 0
Kreuzverband | Wartung_FFB | 1 | Kreuzverband | L 80 x 8 | 0.32 | Wartung_FFB | 118.039 | 54.984 | 6.964 | 120.725 | 53.689 | 6.964 | 0 | 0.06 | 0.057 | 0122Tra0000020955 | m | - | false | HI_UZV_L_STA_0,080_xxx | 0
Kreuzverband | Wartung_FFB | 1 | Kreuzverband | L 80 x 8 | 0.32 | Wartung_FFB | 118.039 | 73.609 | 6.964 | 120.725 | 72.314 | 6.964 | 0 | 0.06 | 0.057 | 0122Tra0000020961 | m | - | false | HI_UZV_L_STA_0,080_xxx | 0
Kreuzverband | Wartung_FFB | 1 | Kreuzverband | L 80 x 8 | 0.32 | Wartung_FFB | 85.041 | 12.263 | 6.964 | 88.043 | 13.558 | 6.964 | 0 | 0.06 | 0.057 | 0122Tra0000020969 | m | - | false | HI_UZV_L_STA_0,080_xxx | 0
Kreuzverband | Wartung_FFB | 1 | Kreuzverband | L 80 x 8 | 0.32 | Wartung_FFB | 118.041 | 12.263 | 6.964 | 121.043 | 13.558 | 6.964 | 0 | 0.06 | 0.057 | 0122Tra0000020973 | m | - | false | HI_UZV_L_STA_0,080_xxx | 0
Nebenträger | Wartung_FFB | 1 | Nebenträger | HEA 120 | 0.698 | Wartung_FFB | 43.06 | 68.601 | 6.998 | 45.91 | 68.601 | 6.998 | 0 | 0.06 | 0.057 | 0122Tra0000009366 | m | T110 | false | HI_UZV_HEA_STA_0,120_xxx | 0
Nebenträger | Wartung_FFB | 1 | Nebenträger | HEA 120 | 0.698 | Wartung_FFB | 45.93 | 68.601 | 6.998 | 49.04 | 68.601 | 6.998 | 0 | 0.06 | 0.057 | 0122Tra0000009368 | m | T110 | false | HI_UZV_HEA_STA_0,120_xxx | 0
Nebenträger | Wartung_FFB | 1 | Nebenträger | HEA 120 | 0.698 | Wartung_FFB | 43.06 | 67.101 | 6.998 | 45.91 | 67.101 | 6.998 | 0 | 0.06 | 0.057 | 0122Tra0000009478 | m | T110 | false | HI_UZV_HEA_STA_0,120_xxx | 0
Nebenträger | Wartung_FFB | 1 | Nebenträger | HEA 120 | 0.698 | Wartung_FFB | 45.93 | 67.101 | 6.998 | 49.04 | 67.101 | 6.998 | 0 | 0.06 | 0.057 | 0122Tra0000009480 | m | T110 | false | HI_UZV_HEA_STA_0,120_xxx | 0
Nebenträger | Wartung_FFB | 1 | Nebenträger | HEA 120 | 0.698 | Wartung_FFB | 43.06 | 65.601 | 6.998 | 45.91 | 65.601 | 6.998 | 0 | 0.06 | 0.057 | 0122Tra0000009589 | m | T110 | false | HI_UZV_HEA_STA_0,120_xxx | 0
Nebenträger | Wartung_FFB | 1 | Nebenträger | HEA 120 | 0.698 | Wartung_FFB | 45.93 | 65.601 | 6.998 | 49.04 | 65.601 | 6.998 | 0 | 0.06 | 0.057 | 0122Tra0000009591 | m | T110 | false | HI_UZV_HEA_STA_0,120_xxx | 0
Nebenträger | Wartung_FFB | 1 | Nebenträger | HEA 120 | 0.698 | Wartung_FFB | 43.06 | 64.101 | 6.998 | 45.91 | 64.101 | 6.998 | 0 | 0.06 | 0.057 | 0122Tra0000009700 | m | T110 | false | HI_UZV_HEA_STA_0,120_xxx | 0
Nebenträger | Wartung_FFB | 1 | Nebenträger | HEA 120 | 0.698 | Wartung_FFB | 45.93 | 64.101 | 6.998 | 49.04 | 64.101 | 6.998 | 0 | 0.06 | 0.057 | 0122Tra0000009702 | m | T110 | false | HI_UZV_HEA_STA_0,120_xxx | 0
Nebenträger | Wartung_FFB | 1 | Nebenträger | HEA 120 | 0.698 | Wartung_FFB | 43.06 | 62.601 | 6.998 | 45.91 | 62.601 | 6.998 | 0 | 0.06 | 0.057 | 0122Tra0000009811 | m | T110 | false | HI_UZV_HEA_STA_0,120_xxx | 0
Nebenträger | Wartung_FFB | 1 | Nebenträger | HEA 120 | 0.698 | Wartung_FFB | 45.93 | 62.601 | 6.998 | 49.04 | 62.601 | 6.998 | 0 | 0.06 | 0.057 | 0122Tra0000009813 | m | T110 | false | HI_UZV_HEA_STA_0,120_xxx | 0
Nebenträger | Wartung_FFB | 1 | Nebenträger | HEA 120 | 0.698 | Wartung_FFB | 43.06 | 61.101 | 6.998 | 45.91 | 61.101 | 6.998 | 0 | 0.06 | 0.057 | 0122Tra0000009922 | m | T110 | false | HI_UZV_HEA_STA_0,120_xxx | 0
Nebenträger | Wartung_FFB | 1 | Nebenträger | HEA 120 | 0.698 | Wartung_FFB | 45.93 | 61.101 | 6.998 | 49.04 | 61.101 | 6.998 | 0 | 0.06 | 0.057 | 0122Tra0000009924 | m | T110 | false | HI_UZV_HEA_STA_0,120_xxx | 0
Nebenträger | Wartung_FFB | 1 | Nebenträger | HEA 120 | 0.698 | Wartung_FFB | 43.06 | 59.601 | 6.998 | 45.91 | 59.601 | 6.998 | 0 | 0.06 | 0.057 | 0122Tra0000010033 | m | T110 | false | HI_UZV_HEA_STA_0,120_xxx | 0
Nebenträger | Wartung_FFB | 1 | Nebenträger | HEA 120 | 0.698 | Wartung_FFB | 45.93 | 59.601 | 6.998 | 49.04 | 59.601 | 6.998 | 0 | 0.06 | 0.057 | 0122Tra0000010035 | m | T110 | false | HI_UZV_HEA_STA_0,120_xxx | 0
Nebenträger | Wartung_FFB | 1 | Nebenträger | HEA 120 | 0.698 | Wartung_FFB | 43.06 | 58.101 | 6.998 | 45.91 | 58.101 | 6.998 | 0 | 0.06 | 0.057 | 0122Tra0000010144 | m | T110 | false | HI_UZV_HEA_STA_0,120_xxx | 0
Nebenträger | Wartung_FFB | 1 | Nebenträger | HEA 120 | 0.698 | Wartung_FFB | 45.93 | 58.101 | 6.998 | 49.04 | 58.101 | 6.998 | 0 | 0.06 | 0.057 | 0122Tra0000010146 | m | T110 | false | HI_UZV_HEA_STA_0,120_xxx | 0
Nebenträger | Wartung_FFB | 1 | Nebenträger | HEA 120 | 0.698 | Wartung_FFB | 43.06 | 56.601 | 6.998 | 45.91 | 56.601 | 6.998 | 0 | 0.06 | 0.057 | 0122Tra0000010255 | m | T110 | false | HI_UZV_HEA_STA_0,120_xxx | 0
Nebenträger | Wartung_FFB | 1 | Nebenträger | HEA 120 | 0.698 | Wartung_FFB | 45.93 | 56.601 | 6.998 | 49.04 | 56.601 | 6.998 | 0 | 0.06 | 0.057 | 0122Tra0000010257 | m | T110 | false | HI_UZV_HEA_STA_0,120_xxx | 0
Nebenträger | Wartung_FFB | 1 | Nebenträger | HEA 120 | 0.698 | Wartung_FFB | 43.06 | 55.101 | 6.998 | 45.91 | 55.101 | 6.998 | 0 | 0.06 | 0.057 | 0122Tra0000010403 | m | T110 | false | HI_UZV_HEA_STA_0,120_xxx | 0
Nebenträger | Wartung_FFB | 1 | Nebenträger | HEA 120 | 0.698 | Wartung_FFB | 45.93 | 55.101 | 6.998 | 49.04 | 55.101 | 6.998 | 0 | 0.06 | 0.057 | 0122Tra0000010405 | m | T110 | false | HI_UZV_HEA_STA_0,120_xxx | 0
Nebenträger | Wartung_FFB | 1 | Nebenträger | HEA 120 | 0.698 | Wartung_FFB | 43.06 | 53.601 | 6.998 | 45.91 | 53.601 | 6.998 | 0 | 0.06 | 0.057 | 0122Tra0000010477 | m | T110 | false | HI_UZV_HEA_STA_0,120_xxx | 0
Nebenträger | Wartung_FFB | 1 | Nebenträger | HEA 120 | 0.698 | Wartung_FFB | 45.93 | 53.601 | 6.998 | 49.04 | 53.601 | 6.998 | 0 | 0.06 | 0.057 | 0122Tra0000010479 | m | T110 | false | HI_UZV_HEA_STA_0,120_xxx | 0
Kreuzverband | Wartung_FFB | 1 | Kreuzverband | L 80 x 8 | 0.32 | Wartung_FFB | 45.917 | 67.229 | 6.964 | 49.043 | 68.514 | 6.964 | 0 | 0.06 | 0.057 | 0122Tra0000020672 | m | - | false | HI_UZV_L_STA_0,080_xxx | 0
Kreuzverband | Wartung_FFB | 1 | Kreuzverband | L 80 x 8 | 0.32 | Wartung_FFB | 45.917 | 66.973 | 6.964 | 49.043 | 65.688 | 6.964 | 0 | 0.06 | 0.057 | 0122Tra0000021038 | m | - | false | HI_UZV_L_STA_0,080_xxx | 0
Kreuzverband | Wartung_FFB | 1 | Kreuzverband | L 80 x 8 | 0.32 | Wartung_FFB | 45.917 | 64.229 | 6.964 | 49.043 | 65.514 | 6.964 | 0 | 0.06 | 0.057 | 0122Tra0000021043 | m | - | false | HI_UZV_L_STA_0,080_xxx | 0
Kreuzverband | Wartung_FFB | 1 | Kreuzverband | L 80 x 8 | 0.32 | Wartung_FFB | 45.917 | 63.973 | 6.964 | 49.043 | 62.688 | 6.964 | 0 | 0.06 | 0.057 | 0122Tra0000021046 | m | - | false | HI_UZV_L_STA_0,080_xxx | 0
Kreuzverband | Wartung_FFB | 1 | Kreuzverband | L 80 x 8 | 0.32 | Wartung_FFB | 45.917 | 61.229 | 6.964 | 49.043 | 62.514 | 6.964 | 0 | 0.06 | 0.057 | 0122Tra0000021050 | m | - | false | HI_UZV_L_STA_0,080_xxx | 0
Kreuzverband | Wartung_FFB | 1 | Kreuzverband | L 80 x 8 | 0.32 | Wartung_FFB | 45.917 | 60.973 | 6.964 | 49.043 | 59.688 | 6.964 | 0 | 0.06 | 0.057 | 0122Tra0000021052 | m | - | false | HI_UZV_L_STA_0,080_xxx | 0
Kreuzverband | Wartung_FFB | 1 | Kreuzverband | L 80 x 8 | 0.32 | Wartung_FFB | 45.917 | 58.229 | 6.964 | 49.043 | 59.514 | 6.964 | 0 | 0.06 | 0.057 | 0122Tra0000021056 | m | - | false | HI_UZV_L_STA_0,080_xxx | 0
Kreuzverband | Wartung_FFB | 1 | Kreuzverband | L 80 x 8 | 0.32 | Wartung_FFB | 45.917 | 57.973 | 6.964 | 49.043 | 56.688 | 6.964 | 0 | 0.06 | 0.057 | 0122Tra0000021058 | m | - | false | HI_UZV_L_STA_0,080_xxx | 0
Kreuzverband | Wartung_FFB | 1 | Kreuzverband | L 80 x 8 | 0.32 | Wartung_FFB | 45.917 | 55.229 | 6.964 | 49.043 | 56.514 | 6.964 | 0 | 0.06 | 0.057 | 0122Tra0000021062 | m | - | false | HI_UZV_L_STA_0,080_xxx | 0
Kreuzverband | Wartung_FFB | 1 | Kreuzverband | L 80 x 8 | 0.32 | Wartung_FFB | 45.917 | 54.973 | 6.964 | 49.043 | 53.688 | 6.964 | 0 | 0.06 | 0.057 | 0122Tra0000021064 | m | - | false | HI_UZV_L_STA_0,080_xxx | 0
Kreuzverband | Wartung_FFB | 1 | Kreuzverband | L 80 x 8 | 0.32 | Wartung_FFB | 10.488 | 69.694 | 6.964 | 13.036 | 68.688 | 6.964 | 0 | 0.06 | 0.057 | 0122Tra0000020480 | m | - | false | HI_UZV_L_STA_0,080_xxx | 0
Kreuzverband | Wartung_FFB | 1 | Kreuzverband | L 80 x 8 | 0.32 | Wartung_FFB | 10.513 | 52.506 | 6.964 | 13.037 | 53.518 | 6.964 | 0 | 0.06 | 0.057 | 0122Tra0000020905 | m | - | false | HI_UZV_L_STA_0,080_xxx | 0
Kreuzverband | Wartung_FFB | 1 | Kreuzverband | L 80 x 8 | 0.32 | Wartung_FFB | 10.523 | 85.342 | 6.964 | 13.037 | 84.313 | 6.964 | 0 | 0.06 | 0.057 | 0122Tra0000020447 | m | - | false | HI_UZV_L_STA_0,080_xxx | 0
Kreuzverband | Wartung_FFB | 1 | Kreuzverband | L 80 x 8 | 0.32 | Wartung_FFB | 10.543 | 71.109 | 6.964 | 13.037 | 72.143 | 6.964 | 0 | 0.06 | 0.057 | 0122Tra0000020897 | m | - | false | HI_UZV_L_STA_0,080_xxx | 0
Kreuzverband | Wartung_FFB | 1 | Kreuzverband | L 80 x 8 | 0.32 | Wartung_FFB | 10.504 | 50.695 | 6.964 | 13.038 | 49.533 | 6.964 | 0 | 0.06 | 0.057 | 0122Tra0000020511 | m | - | false | HI_UZV_L_STA_0,080_xxx | 0
Kreuzverband | Wartung_FFB | 1 | Kreuzverband | L 80 x 8 | 0.32 | Wartung_FFB | 10.539 | 32.832 | 6.964 | 13.044 | 31.674 | 6.964 | 0 | 0.06 | 0.057 | 0122Tra0000020909 | m | - | false | HI_UZV_L_STA_0,080_xxx | 0
Kreuzverband | Wartung_FFB | 1 | Kreuzverband | L 80 x 8 | 0.32 | Wartung_FFB | 10.547 | 29.894 | 6.964 | 13.038 | 28.728 | 6.964 | 0 | 0.06 | 0.057 | 0122Tra0000020547 | m | - | false | HI_UZV_L_STA_0,080_xxx | 0
Kreuzverband | Wartung_FFB | 1 | Kreuzverband | L 80 x 8 | 0.32 | Wartung_FFB | 10.539 | 12.027 | 6.964 | 13.043 | 10.866 | 6.964 | 0 | 0.06 | 0.057 | 0122Tra0000020923 | m | - | false | HI_UZV_L_STA_0,080_xxx | 0
Kreuzverband | Wartung_FFB | 1 | Kreuzverband | L 80 x 8 | 0.32 | Wartung_FFB | 46.03 | 85.342 | 6.964 | 49.042 | 84.314 | 6.964 | 0 | 0.06 | 0.057 | 0122Tra0000020698 | m | - | false | HI_UZV_L_STA_0,080_xxx | 0
Kreuzverband | Wartung_FFB | 1 | Kreuzverband | L 80 x 8 | 0.32 | Wartung_FFB | 46.038 | 71.109 | 6.964 | 49.042 | 72.139 | 6.964 | 0 | 0.06 | 0.057 | 0122Tra0000020943 | m | - | false | HI_UZV_L_STA_0,080_xxx | 0
Kreuzverband | Wartung_FFB | 1 | Kreuzverband | L 80 x 8 | 0.32 | Wartung_FFB | 45.898 | 69.694 | 6.964 | 49.041 | 68.689 | 6.964 | 0 | 0.06 | 0.057 | 0122Tra0000020674 | m | - | false | HI_UZV_L_STA_0,080_xxx | 0
Kreuzverband | Wartung_FFB | 1 | Kreuzverband | L 80 x 8 | 0.32 | Wartung_FFB | 45.93 | 52.506 | 6.964 | 49.041 | 53.513 | 6.964 | 0 | 0.06 | 0.057 | 0122Tra0000021068 | m | - | false | HI_UZV_L_STA_0,080_xxx | 0
Kreuzverband | Wartung_FFB | 1 | Kreuzverband | L 80 x 8 | 0.32 | Wartung_FFB | 45.907 | 50.691 | 6.964 | 48.977 | 49.537 | 6.964 | 0 | 0.06 | 0.057 | 0122Tra0000020644 | m | - | false | HI_UZV_L_STA_0,080_xxx | 0
Kreuzverband | Wartung_FFB | 1 | Kreuzverband | L 80 x 8 | 0.32 | Wartung_FFB | 45.978 | 32.831 | 6.964 | 49.07 | 31.676 | 6.964 | 0 | 0.06 | 0.057 | 0122Tra0000021079 | m | - | false | HI_UZV_L_STA_0,080_xxx | 0
Kreuzverband | Wartung_FFB | 1 | Kreuzverband | L 80 x 8 | 0.32 | Wartung_FFB | 46.028 | 29.892 | 6.964 | 49.043 | 28.732 | 6.964 | 0 | 0.06 | 0.057 | 0122Tra0000020614 | m | - | false | HI_UZV_L_STA_0,080_xxx | 0
Kreuzverband | Wartung_FFB | 1 | Kreuzverband | L 80 x 8 | 0.32 | Wartung_FFB | 46.043 | 12.026 | 6.964 | 49.057 | 10.865 | 6.964 | 0 | 0.06 | 0.057 | 0122Tra0000020925 | m | - | false | HI_UZV_L_STA_0,080_xxx | 0
Kreuzverband | Wartung_FFB | 1 | Kreuzverband | L 80 x 8 | 0.32 | Wartung_FFB | 84.349 | 85.343 | 6.964 | 86.737 | 84.315 | 6.964 | 0 | 0.06 | 0.057 | 0122Tra0000020770 | m | - | false | HI_UZV_L_STA_0,080_xxx | 0
Kreuzverband | Wartung_FFB | 1 | Kreuzverband | L 80 x 8 | 0.32 | Wartung_FFB | 84.338 | 71.109 | 6.964 | 86.737 | 72.138 | 6.964 | 0 | 0.06 | 0.057 | 0122Tra0000020951 | m | - | false | HI_UZV_L_STA_0,080_xxx | 0
Kreuzverband | Wartung_FFB | 1 | Kreuzverband | L 80 x 8 | 0.32 | Wartung_FFB | 84.339 | 69.696 | 6.964 | 86.737 | 68.69 | 6.964 | 0 | 0.06 | 0.057 | 0122Tra0000020822 | m | - | false | HI_UZV_L_STA_0,080_xxx | 0
Kreuzverband | Wartung_FFB | 1 | Kreuzverband | L 80 x 8 | 0.32 | Wartung_FFB | 84.343 | 52.504 | 6.964 | 86.737 | 53.513 | 6.964 | 0 | 0.06 | 0.057 | 0122Tra0000020939 | m | - | false | HI_UZV_L_STA_0,080_xxx | 0
Kreuzverband | Wartung_FFB | 1 | Kreuzverband | L 80 x 8 | 0.32 | Wartung_FFB | 118.035 | 85.342 | 6.964 | 120.723 | 84.315 | 6.964 | 0 | 0.06 | 0.057 | 0122Tra0000020773 | m | - | false | HI_UZV_L_STA_0,080_xxx | 0
Kreuzverband | Wartung_FFB | 1 | Kreuzverband | L 80 x 8 | 0.32 | Wartung_FFB | 118.042 | 71.107 | 6.964 | 120.723 | 72.137 | 6.964 | 0 | 0.06 | 0.057 | 0122Tra0000020963 | m | - | false | HI_UZV_L_STA_0,080_xxx | 0
Kreuzverband | Wartung_FFB | 1 | Kreuzverband | L 80 x 8 | 0.32 | Wartung_FFB | 118.044 | 69.697 | 6.964 | 120.723 | 68.69 | 6.964 | 0 | 0.06 | 0.057 | 0122Tra0000020825 | m | - | false | HI_UZV_L_STA_0,080_xxx | 0
Kreuzverband | Wartung_FFB | 1 | Kreuzverband | L 80 x 8 | 0.32 | Wartung_FFB | 118.044 | 52.505 | 6.964 | 120.723 | 53.512 | 6.964 | 0 | 0.06 | 0.057 | 0122Tra0000020957 | m | - | false | HI_UZV_L_STA_0,080_xxx | 0
Kreuzverband | Wartung_FFB | 1 | Kreuzverband | L 80 x 8 | 0.32 | Wartung_FFB | 85.036 | 29.892 | 6.964 | 88.043 | 28.732 | 6.964 | 0 | 0.06 | 0.057 | 0122Tra0000020704 | m | - | false | HI_UZV_L_STA_0,080_xxx | 0
Kreuzverband | Wartung_FFB | 1 | Kreuzverband | L 80 x 8 | 0.32 | Wartung_FFB | 85.043 | 12.026 | 6.964 | 88.065 | 10.865 | 6.964 | 0 | 0.06 | 0.057 | 0122Tra0000020971 | m | - | false | HI_UZV_L_STA_0,080_xxx | 0
Kreuzverband | Wartung_FFB | 1 | Kreuzverband | L 80 x 8 | 0.32 | Wartung_FFB | 118.023 | 29.894 | 6.964 | 121.043 | 28.732 | 6.964 | 0 | 0.06 | 0.057 | 0122Tra0000020740 | m | - | false | HI_UZV_L_STA_0,080_xxx | 0
Kreuzverband | Wartung_FFB | 1 | Kreuzverband | L 80 x 8 | 0.32 | Wartung_FFB | 118.043 | 12.026 | 6.964 | 121.065 | 10.863 | 6.964 | 0 | 0.06 | 0.057 | 0122Tra0000020975 | m | - | false | HI_UZV_L_STA_0,080_xxx | 0
RWA-Wechsel | Wartung_FFB |  | RWA-Wechsel |  | 0.3998 | Wartung_FFB |  |  |  |  |  |  |  |  |  | 0123ErE0000000161 | kg | T105 | true | HA_UZV_IPE_STA_0,100_xxx | AllplanAttributes - Querschnittsfläche: 0.001 m2; Charakteristischer Wert der Eigenlast: 0.081
RWA-Wechsel | Wartung_FFB |  | RWA-Wechsel |  | 0.3998 | Wartung_FFB |  |  |  |  |  |  |  |  |  | 0123ErE0000000170 | kg | T105 | true | HA_UZV_IPE_STA_0,100_xxx | AllplanAttributes - Querschnittsfläche: 0.001 m2; Charakteristischer Wert der Eigenlast: 0.081
RWA-Wechsel | Wartung_FFB |  | RWA-Wechsel |  | 0.3998 | Wartung_FFB |  |  |  |  |  |  |  |  |  | 0123ErE0000000171 | kg | T105 | true | HA_UZV_IPE_STA_0,100_xxx | AllplanAttributes - Querschnittsfläche: 0.001 m2; Charakteristischer Wert der Eigenlast: 0.081
RWA-Wechsel | Wartung_FFB |  | RWA-Wechsel |  | 0.3998 | Wartung_FFB |  |  |  |  |  |  |  |  |  | 0123ErE0000000172 | kg | T105 | true | HA_UZV_IPE_STA_0,100_xxx | AllplanAttributes - Querschnittsfläche: 0.001 m2; Charakteristischer Wert der Eigenlast: 0.081
RWA-Wechsel | Wartung_FFB |  | RWA-Wechsel |  | 0.3998 | Wartung_FFB |  |  |  |  |  |  |  |  |  | 0123ErE0000000183 | kg | T105 | true | HA_UZV_IPE_STA_0,100_xxx | AllplanAttributes - Querschnittsfläche: 0.001 m2; Charakteristischer Wert der Eigenlast: 0.081
RWA-Wechsel | Wartung_FFB |  | RWA-Wechsel |  | 0.3998 | Wartung_FFB |  |  |  |  |  |  |  |  |  | 0123ErE0000000184 | kg | T105 | true | HA_UZV_IPE_STA_0,100_xxx | AllplanAttributes - Querschnittsfläche: 0.001 m2; Charakteristischer Wert der Eigenlast: 0.081
RWA-Wechsel | Wartung_FFB |  | RWA-Wechsel |  | 0.3998 | Wartung_FFB |  |  |  |  |  |  |  |  |  | 0123ErE0000000185 | kg | T105 | true | HA_UZV_IPE_STA_0,100_xxx | AllplanAttributes - Querschnittsfläche: 0.001 m2; Charakteristischer Wert der Eigenlast: 0.081
RWA-Wechsel | Wartung_FFB |  | RWA-Wechsel |  | 0.3998 | Wartung_FFB |  |  |  |  |  |  |  |  |  | 0123ErE0000000186 | kg | T105 | true | HA_UZV_IPE_STA_0,100_xxx | AllplanAttributes - Querschnittsfläche: 0.001 m2; Charakteristischer Wert der Eigenlast: 0.081
RWA-Wechsel | Wartung_FFB |  | RWA-Wechsel |  | 0.3998 | Wartung_FFB |  |  |  |  |  |  |  |  |  | 0123ErE0000000193 | kg | T105 | true | HA_UZV_IPE_STA_0,100_xxx | AllplanAttributes - Querschnittsfläche: 0.001 m2; Charakteristischer Wert der Eigenlast: 0.081
RWA-Wechsel | Wartung_FFB |  | RWA-Wechsel |  | 0.3998 | Wartung_FFB |  |  |  |  |  |  |  |  |  | 0123ErE0000000194 | kg | T105 | true | HA_UZV_IPE_STA_0,100_xxx | AllplanAttributes - Querschnittsfläche: 0.001 m2; Charakteristischer Wert der Eigenlast: 0.081
RWA-Wechsel | Wartung_FFB |  | RWA-Wechsel |  | 0.3998 | Wartung_FFB |  |  |  |  |  |  |  |  |  | 0123ErE0000000195 | kg | T105 | true | HA_UZV_IPE_STA_0,100_xxx | AllplanAttributes - Querschnittsfläche: 0.001 m2; Charakteristischer Wert der Eigenlast: 0.081
RWA-Wechsel | Wartung_FFB |  | RWA-Wechsel |  | 0.3998 | Wartung_FFB |  |  |  |  |  |  |  |  |  | 0123ErE0000000196 | kg | T105 | true | HA_UZV_IPE_STA_0,100_xxx | AllplanAttributes - Querschnittsfläche: 0.001 m2; Charakteristischer Wert der Eigenlast: 0.081
RWA-Wechsel | Wartung_FFB |  | RWA-Wechsel |  | 0.3998 | Wartung_FFB |  |  |  |  |  |  |  |  |  | 0123ErE0000000203 | kg | T105 | true | HA_UZV_IPE_STA_0,100_xxx | AllplanAttributes - Querschnittsfläche: 0.001 m2; Charakteristischer Wert der Eigenlast: 0.081
RWA-Wechsel | Wartung_FFB |  | RWA-Wechsel |  | 0.3998 | Wartung_FFB |  |  |  |  |  |  |  |  |  | 0123ErE0000000204 | kg | T105 | true | HA_UZV_IPE_STA_0,100_xxx | AllplanAttributes - Querschnittsfläche: 0.001 m2; Charakteristischer Wert der Eigenlast: 0.081
RWA-Wechsel | Wartung_FFB |  | RWA-Wechsel |  | 0.3998 | Wartung_FFB |  |  |  |  |  |  |  |  |  | 0123ErE0000000205 | kg | T105 | true | HA_UZV_IPE_STA_0,100_xxx | AllplanAttributes - Querschnittsfläche: 0.001 m2; Charakteristischer Wert der Eigenlast: 0.081
RWA-Wechsel | Wartung_FFB |  | RWA-Wechsel |  | 0.3998 | Wartung_FFB |  |  |  |  |  |  |  |  |  | 0123ErE0000000206 | kg | T105 | true | HA_UZV_IPE_STA_0,100_xxx | AllplanAttributes - Querschnittsfläche: 0.001 m2; Charakteristischer Wert der Eigenlast: 0.081
RWA-Wechsel | Wartung_FFB |  | RWA-Wechsel |  | 0.3998 | Wartung_FFB |  |  |  |  |  |  |  |  |  | 0123ErE0000000213 | kg | T105 | true | HA_UZV_IPE_STA_0,100_xxx | AllplanAttributes - Querschnittsfläche: 0.001 m2; Charakteristischer Wert der Eigenlast: 0.081
RWA-Wechsel | Wartung_FFB |  | RWA-Wechsel |  | 0.3998 | Wartung_FFB |  |  |  |  |  |  |  |  |  | 0123ErE0000000214 | kg | T105 | true | HA_UZV_IPE_STA_0,100_xxx | AllplanAttributes - Querschnittsfläche: 0.001 m2; Charakteristischer Wert der Eigenlast: 0.081
RWA-Wechsel | Wartung_FFB |  | RWA-Wechsel |  | 0.3998 | Wartung_FFB |  |  |  |  |  |  |  |  |  | 0123ErE0000000215 | kg | T105 | true | HA_UZV_IPE_STA_0,100_xxx | AllplanAttributes - Querschnittsfläche: 0.001 m2; Charakteristischer Wert der Eigenlast: 0.081
RWA-Wechsel | Wartung_FFB |  | RWA-Wechsel |  | 0.3998 | Wartung_FFB |  |  |  |  |  |  |  |  |  | 0123ErE0000000216 | kg | T105 | true | HA_UZV_IPE_STA_0,100_xxx | AllplanAttributes - Querschnittsfläche: 0.001 m2; Charakteristischer Wert der Eigenlast: 0.081
RWA-Wechsel | Wartung_FFB |  | RWA-Wechsel |  | 0.3998 | Wartung_FFB |  |  |  |  |  |  |  |  |  | 0123ErE0000000223 | kg | T105 | true | HA_UZV_IPE_STA_0,100_xxx | AllplanAttributes - Querschnittsfläche: 0.001 m2; Charakteristischer Wert der Eigenlast: 0.081
RWA-Wechsel | Wartung_FFB |  | RWA-Wechsel |  | 0.3998 | Wartung_FFB |  |  |  |  |  |  |  |  |  | 0123ErE0000000224 | kg | T105 | true | HA_UZV_IPE_STA_0,100_xxx | AllplanAttributes - Querschnittsfläche: 0.001 m2; Charakteristischer Wert der Eigenlast: 0.081
RWA-Wechsel | Wartung_FFB |  | RWA-Wechsel |  | 0.3998 | Wartung_FFB |  |  |  |  |  |  |  |  |  | 0123ErE0000000225 | kg | T105 | true | HA_UZV_IPE_STA_0,100_xxx | AllplanAttributes - Querschnittsfläche: 0.001 m2; Charakteristischer Wert der Eigenlast: 0.081
RWA-Wechsel | Wartung_FFB |  | RWA-Wechsel |  | 0.3998 | Wartung_FFB |  |  |  |  |  |  |  |  |  | 0123ErE0000000226 | kg | T105 | true | HA_UZV_IPE_STA_0,100_xxx | AllplanAttributes - Querschnittsfläche: 0.001 m2; Charakteristischer Wert der Eigenlast: 0.081
RWA-Wechsel | Wartung_FFB |  | RWA-Wechsel |  | 0.3998 | Wartung_FFB |  |  |  |  |  |  |  |  |  | 0123ErE0000000480 | kg | T105 | true | HA_UZV_IPE_STA_0,100_xxx | AllplanAttributes - Querschnittsfläche: 0.001 m2; Charakteristischer Wert der Eigenlast: 0.081
RWA-Wechsel | Wartung_FFB |  | RWA-Wechsel |  | 0.3998 | Wartung_FFB |  |  |  |  |  |  |  |  |  | 0123ErE0000000484 | kg | T105 | true | HA_UZV_IPE_STA_0,100_xxx | AllplanAttributes - Querschnittsfläche: 0.001 m2; Charakteristischer Wert der Eigenlast: 0.081
RWA-Wechsel | Wartung_FFB |  | RWA-Wechsel |  | 0.3998 | Wartung_FFB |  |  |  |  |  |  |  |  |  | 0123ErE0000000485 | kg | T105 | true | HA_UZV_IPE_STA_0,100_xxx | AllplanAttributes - Querschnittsfläche: 0.001 m2; Charakteristischer Wert der Eigenlast: 0.081
RWA-Wechsel | Wartung_FFB |  | RWA-Wechsel |  | 0.3998 | Wartung_FFB |  |  |  |  |  |  |  |  |  | 0123ErE0000000486 | kg | T105 | true | HA_UZV_IPE_STA_0,100_xxx | AllplanAttributes - Querschnittsfläche: 0.001 m2; Charakteristischer Wert der Eigenlast: 0.081
RWA-Wechsel | Wartung_FFB |  | RWA-Wechsel |  | 0.3998 | Wartung_FFB |  |  |  |  |  |  |  |  |  | 0123ErE0000000487 | kg | T105 | true | HA_UZV_IPE_STA_0,100_xxx | AllplanAttributes - Querschnittsfläche: 0.001 m2; Charakteristischer Wert der Eigenlast: 0.081
RWA-Wechsel | Wartung_FFB |  | RWA-Wechsel |  | 0.3998 | Wartung_FFB |  |  |  |  |  |  |  |  |  | 0123ErE0000000488 | kg | T105 | true | HA_UZV_IPE_STA_0,100_xxx | AllplanAttributes - Querschnittsfläche: 0.001 m2; Charakteristischer Wert der Eigenlast: 0.081
RWA-Wechsel | Wartung_FFB |  | RWA-Wechsel |  | 0.3998 | Wartung_FFB |  |  |  |  |  |  |  |  |  | 0123ErE0000000489 | kg | T105 | true | HA_UZV_IPE_STA_0,100_xxx | AllplanAttributes - Querschnittsfläche: 0.001 m2; Charakteristischer Wert der Eigenlast: 0.081
RWA-Wechsel | Wartung_FFB |  | RWA-Wechsel |  | 0.3998 | Wartung_FFB |  |  |  |  |  |  |  |  |  | 0123ErE0000000490 | kg | T105 | true | HA_UZV_IPE_STA_0,100_xxx | AllplanAttributes - Querschnittsfläche: 0.001 m2; Charakteristischer Wert der Eigenlast: 0.081
RWA-Wechsel | Wartung_FFB |  | RWA-Wechsel |  | 0.3998 | Wartung_FFB |  |  |  |  |  |  |  |  |  | 0123ErE0000000491 | kg | T105 | true | HA_UZV_IPE_STA_0,100_xxx | AllplanAttributes - Querschnittsfläche: 0.001 m2; Charakteristischer Wert der Eigenlast: 0.081
RWA-Wechsel | Wartung_FFB |  | RWA-Wechsel |  | 0.3998 | Wartung_FFB |  |  |  |  |  |  |  |  |  | 0123ErE0000000492 | kg | T105 | true | HA_UZV_IPE_STA_0,100_xxx | AllplanAttributes - Querschnittsfläche: 0.001 m2; Charakteristischer Wert der Eigenlast: 0.081
RWA-Wechsel | Wartung_FFB |  | RWA-Wechsel |  | 0.3998 | Wartung_FFB |  |  |  |  |  |  |  |  |  | 0123ErE0000000493 | kg | T105 | true | HA_UZV_IPE_STA_0,100_xxx | AllplanAttributes - Querschnittsfläche: 0.001 m2; Charakteristischer Wert der Eigenlast: 0.081
RWA-Wechsel | Wartung_FFB |  | RWA-Wechsel |  | 0.3998 | Wartung_FFB |  |  |  |  |  |  |  |  |  | 0123ErE0000000494 | kg | T105 | true | HA_UZV_IPE_STA_0,100_xxx | AllplanAttributes - Querschnittsfläche: 0.001 m2; Charakteristischer Wert der Eigenlast: 0.081
RWA-Wechsel | Wartung_FFB |  | RWA-Wechsel |  | 0.3998 | Wartung_FFB |  |  |  |  |  |  |  |  |  | 0123ErE0000000495 | kg | T105 | true | HA_UZV_IPE_STA_0,100_xxx | AllplanAttributes - Querschnittsfläche: 0.001 m2; Charakteristischer Wert der Eigenlast: 0.081
RWA-Wechsel | Wartung_FFB |  | RWA-Wechsel |  | 0.3998 | Wartung_FFB |  |  |  |  |  |  |  |  |  | 0123ErE0000000496 | kg | T105 | true | HA_UZV_IPE_STA_0,100_xxx | AllplanAttributes - Querschnittsfläche: 0.001 m2; Charakteristischer Wert der Eigenlast: 0.081
RWA-Wechsel | Wartung_FFB |  | RWA-Wechsel |  | 0.3998 | Wartung_FFB |  |  |  |  |  |  |  |  |  | 0123ErE0000000497 | kg | T105 | true | HA_UZV_IPE_STA_0,100_xxx | AllplanAttributes - Querschnittsfläche: 0.001 m2; Charakteristischer Wert der Eigenlast: 0.081
RWA-Wechsel | Wartung_FFB |  | RWA-Wechsel |  | 0.3998 | Wartung_FFB |  |  |  |  |  |  |  |  |  | 0123ErE0000000498 | kg | T105 | true | HA_UZV_IPE_STA_0,100_xxx | AllplanAttributes - Querschnittsfläche: 0.001 m2; Charakteristischer Wert der Eigenlast: 0.081
RWA-Wechsel | Wartung_FFB |  | RWA-Wechsel |  | 0.3998 | Wartung_FFB |  |  |  |  |  |  |  |  |  | 0123ErE0000000499 | kg | T105 | true | HA_UZV_IPE_STA_0,100_xxx | AllplanAttributes - Querschnittsfläche: 0.001 m2; Charakteristischer Wert der Eigenlast: 0.081
RWA-Wechsel | Wartung_FFB |  | RWA-Wechsel |  | 0.3998 | Wartung_FFB |  |  |  |  |  |  |  |  |  | 0123ErE0000000500 | kg | T105 | true | HA_UZV_IPE_STA_0,100_xxx | AllplanAttributes - Querschnittsfläche: 0.001 m2; Charakteristischer Wert der Eigenlast: 0.081
RWA-Wechsel | Wartung_FFB |  | RWA-Wechsel |  | 0.3998 | Wartung_FFB |  |  |  |  |  |  |  |  |  | 0123ErE0000000501 | kg | T105 | true | HA_UZV_IPE_STA_0,100_xxx | AllplanAttributes - Querschnittsfläche: 0.001 m2; Charakteristischer Wert der Eigenlast: 0.081
RWA-Wechsel | Wartung_FFB |  | RWA-Wechsel |  | 0.3998 | Wartung_FFB |  |  |  |  |  |  |  |  |  | 0123ErE0000000502 | kg | T105 | true | HA_UZV_IPE_STA_0,100_xxx | AllplanAttributes - Querschnittsfläche: 0.001 m2; Charakteristischer Wert der Eigenlast: 0.081
RWA-Wechsel | Wartung_FFB |  | RWA-Wechsel |  | 0.3998 | Wartung_FFB |  |  |  |  |  |  |  |  |  | 0123ErE0000000503 | kg | T105 | true | HA_UZV_IPE_STA_0,100_xxx | AllplanAttributes - Querschnittsfläche: 0.001 m2; Charakteristischer Wert der Eigenlast: 0.081
RWA-Wechsel | Wartung_FFB |  | RWA-Wechsel |  | 0.3998 | Wartung_FFB |  |  |  |  |  |  |  |  |  | 0123ErE0000000504 | kg | T105 | true | HA_UZV_IPE_STA_0,100_xxx | AllplanAttributes - Querschnittsfläche: 0.001 m2; Charakteristischer Wert der Eigenlast: 0.081
RWA-Wechsel | Wartung_FFB |  | RWA-Wechsel |  | 0.3998 | Wartung_FFB |  |  |  |  |  |  |  |  |  | 0123ErE0000000505 | kg | T105 | true | HA_UZV_IPE_STA_0,100_xxx | AllplanAttributes - Querschnittsfläche: 0.001 m2; Charakteristischer Wert der Eigenlast: 0.081
RWA-Wechsel | Wartung_FFB |  | RWA-Wechsel |  | 0.3998 | Wartung_FFB |  |  |  |  |  |  |  |  |  | 0123ErE0000000506 | kg | T105 | true | HA_UZV_IPE_STA_0,100_xxx | AllplanAttributes - Querschnittsfläche: 0.001 m2; Charakteristischer Wert der Eigenlast: 0.081
RWA-Wechsel | Wartung_FFB |  | RWA-Wechsel |  | 0.3998 | Wartung_FFB |  |  |  |  |  |  |  |  |  | 0123ErE0000000546 | kg | T105 | true | HA_UZV_IPE_STA_0,100_xxx | AllplanAttributes - Querschnittsfläche: 0.001 m2; Charakteristischer Wert der Eigenlast: 0.081
RWA-Wechsel | Wartung_FFB |  | RWA-Wechsel |  | 0.3998 | Wartung_FFB |  |  |  |  |  |  |  |  |  | 0123ErE0000000547 | kg | T105 | true | HA_UZV_IPE_STA_0,100_xxx | AllplanAttributes - Querschnittsfläche: 0.001 m2; Charakteristischer Wert der Eigenlast: 0.081
RWA-Wechsel | Wartung_FFB |  | RWA-Wechsel |  | 0.3998 | Wartung_FFB |  |  |  |  |  |  |  |  |  | 0123ErE0000000548 | kg | T105 | true | HA_UZV_IPE_STA_0,100_xxx | AllplanAttributes - Querschnittsfläche: 0.001 m2; Charakteristischer Wert der Eigenlast: 0.081
RWA-Wechsel | Wartung_FFB |  | RWA-Wechsel |  | 0.3998 | Wartung_FFB |  |  |  |  |  |  |  |  |  | 0123ErE0000000549 | kg | T105 | true | HA_UZV_IPE_STA_0,100_xxx | AllplanAttributes - Querschnittsfläche: 0.001 m2; Charakteristischer Wert der Eigenlast: 0.081
RWA-Wechsel | Wartung_FFB |  | RWA-Wechsel |  | 0.3998 | Wartung_FFB |  |  |  |  |  |  |  |  |  | 0123ErE0000000550 | kg | T105 | true | HA_UZV_IPE_STA_0,100_xxx | AllplanAttributes - Querschnittsfläche: 0.001 m2; Charakteristischer Wert der Eigenlast: 0.081
RWA-Wechsel | Wartung_FFB |  | RWA-Wechsel |  | 0.3998 | Wartung_FFB |  |  |  |  |  |  |  |  |  | 0123ErE0000000551 | kg | T105 | true | HA_UZV_IPE_STA_0,100_xxx | AllplanAttributes - Querschnittsfläche: 0.001 m2; Charakteristischer Wert der Eigenlast: 0.081
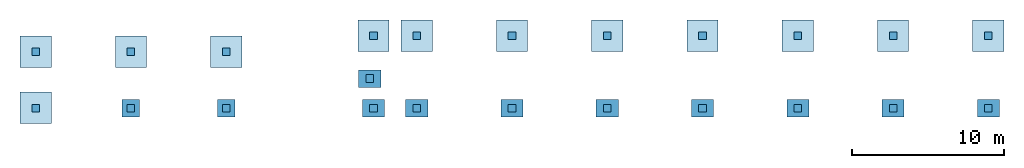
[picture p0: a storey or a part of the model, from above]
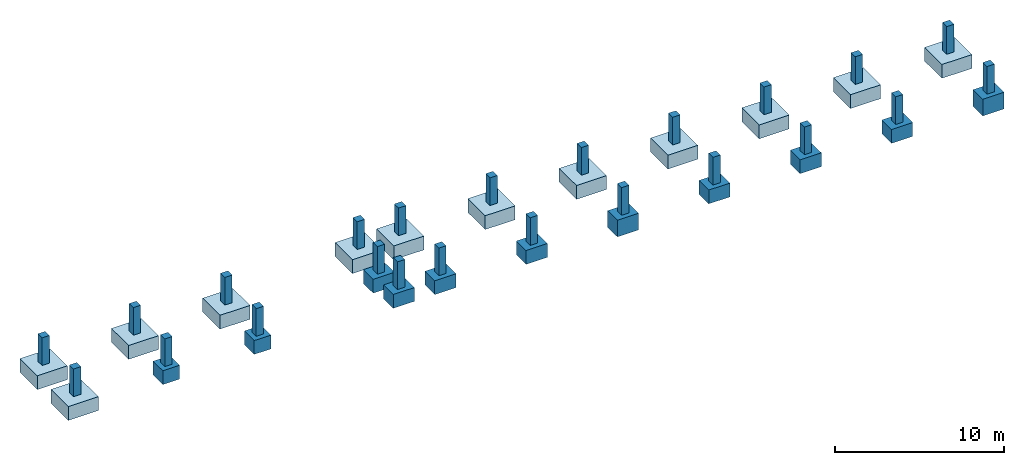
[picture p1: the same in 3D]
Properties of the parts of a building model (IFC2X3), part 9 of 25

# IfcBeam (2372)
Name | In | Faktor | Bezeichnung = Name | Profilname | Mantelfläche/lfm | Ebene | Achsenstartpunkt (X) (m) | Achsenstartpunkt (Y) (m) | Achsenstartpunkt (Z) (m) | Achsenendpunkt (X) (m) | Achsenendpunkt (Y) (m) | Achsenendpunkt (Z) (m) | Objektdrehwinkel | Schwerpunkt X (m) | Schwerpunkt Y (m) | Allright_Bauteil_ID | Abrechnungsart | Positionsnummer | Außenbauteil | Reference | Drehwinkel = Slope (deg)
RWA-Wechsel | Wartung_FFB |  | RWA-Wechsel |  | 0.3998 | Wartung_FFB |  |  |  |  |  |  |  |  |  | 0123ErE0000000552 | kg | T105 | true | HA_UZV_IPE_STA_0,100_xxx | AllplanAttributes - Querschnittsfläche: 0.001 m2; Charakteristischer Wert der Eigenlast: 0.081
RWA-Wechsel | Wartung_FFB |  | RWA-Wechsel |  | 0.3998 | Wartung_FFB |  |  |  |  |  |  |  |  |  | 0123ErE0000000553 | kg | T105 | true | HA_UZV_IPE_STA_0,100_xxx | AllplanAttributes - Querschnittsfläche: 0.001 m2; Charakteristischer Wert der Eigenlast: 0.081
RWA-Wechsel | Wartung_FFB |  | RWA-Wechsel |  | 0.3998 | Wartung_FFB |  |  |  |  |  |  |  |  |  | 0123ErE0000000554 | kg | T105 | true | HA_UZV_IPE_STA_0,100_xxx | AllplanAttributes - Querschnittsfläche: 0.001 m2; Charakteristischer Wert der Eigenlast: 0.081
RWA-Wechsel | Wartung_FFB |  | RWA-Wechsel |  | 0.3998 | Wartung_FFB |  |  |  |  |  |  |  |  |  | 0123ErE0000000555 | kg | T105 | true | HA_UZV_IPE_STA_0,100_xxx | AllplanAttributes - Querschnittsfläche: 0.001 m2; Charakteristischer Wert der Eigenlast: 0.081
RWA-Wechsel | Wartung_FFB |  | RWA-Wechsel |  | 0.3998 | Wartung_FFB |  |  |  |  |  |  |  |  |  | 0123ErE0000000556 | kg | T105 | true | HA_UZV_IPE_STA_0,100_xxx | AllplanAttributes - Querschnittsfläche: 0.001 m2; Charakteristischer Wert der Eigenlast: 0.081
RWA-Wechsel | Wartung_FFB |  | RWA-Wechsel |  | 0.3998 | Wartung_FFB |  |  |  |  |  |  |  |  |  | 0123ErE0000000557 | kg | T105 | true | HA_UZV_IPE_STA_0,100_xxx | AllplanAttributes - Querschnittsfläche: 0.001 m2; Charakteristischer Wert der Eigenlast: 0.081
RWA-Wechsel | Wartung_FFB |  | RWA-Wechsel |  | 0.3998 | Wartung_FFB |  |  |  |  |  |  |  |  |  | 0123ErE0000000558 | kg | T105 | true | HA_UZV_IPE_STA_0,100_xxx | AllplanAttributes - Querschnittsfläche: 0.001 m2; Charakteristischer Wert der Eigenlast: 0.081
RWA-Wechsel | Wartung_FFB |  | RWA-Wechsel |  | 0.3998 | Wartung_FFB |  |  |  |  |  |  |  |  |  | 0123ErE0000000559 | kg | T105 | true | HA_UZV_IPE_STA_0,100_xxx | AllplanAttributes - Querschnittsfläche: 0.001 m2; Charakteristischer Wert der Eigenlast: 0.081
RWA-Wechsel | Wartung_FFB |  | RWA-Wechsel |  | 0.3998 | Wartung_FFB |  |  |  |  |  |  |  |  |  | 0123ErE0000000560 | kg | T105 | true | HA_UZV_IPE_STA_0,100_xxx | AllplanAttributes - Querschnittsfläche: 0.001 m2; Charakteristischer Wert der Eigenlast: 0.081
RWA-Wechsel | Wartung_FFB |  | RWA-Wechsel |  | 0.3998 | Wartung_FFB |  |  |  |  |  |  |  |  |  | 0123ErE0000000561 | kg | T105 | true | HA_UZV_IPE_STA_0,100_xxx | AllplanAttributes - Querschnittsfläche: 0.001 m2; Charakteristischer Wert der Eigenlast: 0.081
RWA-Wechsel | Wartung_FFB |  | RWA-Wechsel |  | 0.3998 | Wartung_FFB |  |  |  |  |  |  |  |  |  | 0123ErE0000000562 | kg | T105 | true | HA_UZV_IPE_STA_0,100_xxx | AllplanAttributes - Querschnittsfläche: 0.001 m2; Charakteristischer Wert der Eigenlast: 0.081
RWA-Wechsel | Wartung_FFB |  | RWA-Wechsel |  | 0.3998 | Wartung_FFB |  |  |  |  |  |  |  |  |  | 0123ErE0000000563 | kg | T105 | true | HA_UZV_IPE_STA_0,100_xxx | AllplanAttributes - Querschnittsfläche: 0.001 m2; Charakteristischer Wert der Eigenlast: 0.081
RWA-Wechsel | Wartung_FFB |  | RWA-Wechsel |  | 0.3998 | Wartung_FFB |  |  |  |  |  |  |  |  |  | 0123ErE0000000564 | kg | T105 | true | HA_UZV_IPE_STA_0,100_xxx | AllplanAttributes - Querschnittsfläche: 0.001 m2; Charakteristischer Wert der Eigenlast: 0.081
RWA-Wechsel | Wartung_FFB |  | RWA-Wechsel |  | 0.3998 | Wartung_FFB |  |  |  |  |  |  |  |  |  | 0123ErE0000000565 | kg | T105 | true | HA_UZV_IPE_STA_0,100_xxx | AllplanAttributes - Querschnittsfläche: 0.001 m2; Charakteristischer Wert der Eigenlast: 0.081
RWA-Wechsel | Wartung_FFB |  | RWA-Wechsel |  | 0.3998 | Wartung_FFB |  |  |  |  |  |  |  |  |  | 0123ErE0000000566 | kg | T105 | true | HA_UZV_IPE_STA_0,100_xxx | AllplanAttributes - Querschnittsfläche: 0.001 m2; Charakteristischer Wert der Eigenlast: 0.081
RWA-Wechsel | Wartung_FFB |  | RWA-Wechsel |  | 0.3998 | Wartung_FFB |  |  |  |  |  |  |  |  |  | 0123ErE0000000567 | kg | T105 | true | HA_UZV_IPE_STA_0,100_xxx | AllplanAttributes - Querschnittsfläche: 0.001 m2; Charakteristischer Wert der Eigenlast: 0.081
RWA-Wechsel | Wartung_FFB |  | RWA-Wechsel |  | 0.3998 | Wartung_FFB |  |  |  |  |  |  |  |  |  | 0123ErE0000000568 | kg | T105 | true | HA_UZV_IPE_STA_0,100_xxx | AllplanAttributes - Querschnittsfläche: 0.001 m2; Charakteristischer Wert der Eigenlast: 0.081
RWA-Wechsel | Wartung_FFB |  | RWA-Wechsel |  | 0.3998 | Wartung_FFB |  |  |  |  |  |  |  |  |  | 0123ErE0000000569 | kg | T105 | true | HA_UZV_IPE_STA_0,100_xxx | AllplanAttributes - Querschnittsfläche: 0.001 m2; Charakteristischer Wert der Eigenlast: 0.081
RWA-Wechsel | Wartung_FFB |  | RWA-Wechsel |  | 0.3998 | Wartung_FFB |  |  |  |  |  |  |  |  |  | 0123ErE0000000572 | kg | T105 | true | HA_UZV_IPE_STA_0,100_xxx | AllplanAttributes - Querschnittsfläche: 0.001 m2; Charakteristischer Wert der Eigenlast: 0.081
RWA-Wechsel | Wartung_FFB |  | RWA-Wechsel |  | 0.3998 | Wartung_FFB |  |  |  |  |  |  |  |  |  | 0123ErE0000000575 | kg | T105 | true | HA_UZV_IPE_STA_0,100_xxx | AllplanAttributes - Querschnittsfläche: 0.001 m2; Charakteristischer Wert der Eigenlast: 0.081
RWA-Wechsel | Wartung_FFB |  | RWA-Wechsel |  | 0.3998 | Wartung_FFB |  |  |  |  |  |  |  |  |  | 0123ErE0000000576 | kg | T105 | true | HA_UZV_IPE_STA_0,100_xxx | AllplanAttributes - Querschnittsfläche: 0.001 m2; Charakteristischer Wert der Eigenlast: 0.081
RWA-Wechsel | Wartung_FFB |  | RWA-Wechsel |  | 0.3998 | Wartung_FFB |  |  |  |  |  |  |  |  |  | 0123ErE0000000577 | kg | T105 | true | HA_UZV_IPE_STA_0,100_xxx | AllplanAttributes - Querschnittsfläche: 0.001 m2; Charakteristischer Wert der Eigenlast: 0.081
RWA-Wechsel | Wartung_FFB |  | RWA-Wechsel |  | 0.3998 | Wartung_FFB |  |  |  |  |  |  |  |  |  | 0123ErE0000000578 | kg | T105 | true | HA_UZV_IPE_STA_0,100_xxx | AllplanAttributes - Querschnittsfläche: 0.001 m2; Charakteristischer Wert der Eigenlast: 0.081
RWA-Wechsel | Wartung_FFB |  | RWA-Wechsel |  | 0.3998 | Wartung_FFB |  |  |  |  |  |  |  |  |  | 0123ErE0000000579 | kg | T105 | true | HA_UZV_IPE_STA_0,100_xxx | AllplanAttributes - Querschnittsfläche: 0.001 m2; Charakteristischer Wert der Eigenlast: 0.081
RWA-Wechsel | Wartung_FFB |  | RWA-Wechsel |  | 0.3998 | Wartung_FFB |  |  |  |  |  |  |  |  |  | 0123ErE0000000580 | kg | T105 | true | HA_UZV_IPE_STA_0,100_xxx | AllplanAttributes - Querschnittsfläche: 0.001 m2; Charakteristischer Wert der Eigenlast: 0.081
RWA-Wechsel | Wartung_FFB |  | RWA-Wechsel |  | 0.3998 | Wartung_FFB |  |  |  |  |  |  |  |  |  | 0123ErE0000000581 | kg | T105 | true | HA_UZV_IPE_STA_0,100_xxx | AllplanAttributes - Querschnittsfläche: 0.001 m2; Charakteristischer Wert der Eigenlast: 0.081
RWA-Wechsel | Wartung_FFB |  | RWA-Wechsel |  | 0.3998 | Wartung_FFB |  |  |  |  |  |  |  |  |  | 0123ErE0000000582 | kg | T105 | true | HA_UZV_IPE_STA_0,100_xxx | AllplanAttributes - Querschnittsfläche: 0.001 m2; Charakteristischer Wert der Eigenlast: 0.081
RWA-Wechsel | Wartung_FFB |  | RWA-Wechsel |  | 0.3998 | Wartung_FFB |  |  |  |  |  |  |  |  |  | 0123ErE0000000583 | kg | T105 | true | HA_UZV_IPE_STA_0,100_xxx | AllplanAttributes - Querschnittsfläche: 0.001 m2; Charakteristischer Wert der Eigenlast: 0.081
RWA-Wechsel | Wartung_FFB |  | RWA-Wechsel |  | 0.3998 | Wartung_FFB |  |  |  |  |  |  |  |  |  | 0123ErE0000000584 | kg | T105 | true | HA_UZV_IPE_STA_0,100_xxx | AllplanAttributes - Querschnittsfläche: 0.001 m2; Charakteristischer Wert der Eigenlast: 0.081
RWA-Wechsel | Wartung_FFB |  | RWA-Wechsel |  | 0.3998 | Wartung_FFB |  |  |  |  |  |  |  |  |  | 0123ErE0000000585 | kg | T105 | true | HA_UZV_IPE_STA_0,100_xxx | AllplanAttributes - Querschnittsfläche: 0.001 m2; Charakteristischer Wert der Eigenlast: 0.081
RWA-Wechsel | Wartung_FFB |  | RWA-Wechsel |  | 0.3998 | Wartung_FFB |  |  |  |  |  |  |  |  |  | 0123ErE0000000586 | kg | T105 | true | HA_UZV_IPE_STA_0,100_xxx | AllplanAttributes - Querschnittsfläche: 0.001 m2; Charakteristischer Wert der Eigenlast: 0.081
RWA-Wechsel | Wartung_FFB |  | RWA-Wechsel |  | 0.3998 | Wartung_FFB |  |  |  |  |  |  |  |  |  | 0123ErE0000000587 | kg | T105 | true | HA_UZV_IPE_STA_0,100_xxx | AllplanAttributes - Querschnittsfläche: 0.001 m2; Charakteristischer Wert der Eigenlast: 0.081
RWA-Wechsel | Wartung_FFB |  | RWA-Wechsel |  | 0.3998 | Wartung_FFB |  |  |  |  |  |  |  |  |  | 0123ErE0000000588 | kg | T105 | true | HA_UZV_IPE_STA_0,100_xxx | AllplanAttributes - Querschnittsfläche: 0.001 m2; Charakteristischer Wert der Eigenlast: 0.081
RWA-Wechsel | Wartung_FFB |  | RWA-Wechsel |  | 0.3998 | Wartung_FFB |  |  |  |  |  |  |  |  |  | 0123ErE0000000589 | kg | T105 | true | HA_UZV_IPE_STA_0,100_xxx | AllplanAttributes - Querschnittsfläche: 0.001 m2; Charakteristischer Wert der Eigenlast: 0.081
RWA-Wechsel | Wartung_FFB |  | RWA-Wechsel |  | 0.3998 | Wartung_FFB |  |  |  |  |  |  |  |  |  | 0123ErE0000000590 | kg | T105 | true | HA_UZV_IPE_STA_0,100_xxx | AllplanAttributes - Querschnittsfläche: 0.001 m2; Charakteristischer Wert der Eigenlast: 0.081
RWA-Wechsel | Wartung_FFB |  | RWA-Wechsel |  | 0.3998 | Wartung_FFB |  |  |  |  |  |  |  |  |  | 0123ErE0000000591 | kg | T105 | true | HA_UZV_IPE_STA_0,100_xxx | AllplanAttributes - Querschnittsfläche: 0.001 m2; Charakteristischer Wert der Eigenlast: 0.081
RWA-Wechsel | Wartung_FFB |  | RWA-Wechsel |  | 0.3998 | Wartung_FFB |  |  |  |  |  |  |  |  |  | 0123ErE0000000592 | kg | T105 | true | HA_UZV_IPE_STA_0,100_xxx | AllplanAttributes - Querschnittsfläche: 0.001 m2; Charakteristischer Wert der Eigenlast: 0.081
RWA-Wechsel | Wartung_FFB |  | RWA-Wechsel |  | 0.3998 | Wartung_FFB |  |  |  |  |  |  |  |  |  | 0123ErE0000000593 | kg | T105 | true | HA_UZV_IPE_STA_0,100_xxx | AllplanAttributes - Querschnittsfläche: 0.001 m2; Charakteristischer Wert der Eigenlast: 0.081
RWA-Wechsel | Wartung_FFB |  | RWA-Wechsel |  | 0.3998 | Wartung_FFB |  |  |  |  |  |  |  |  |  | 0123ErE0000000594 | kg | T105 | true | HA_UZV_IPE_STA_0,100_xxx | AllplanAttributes - Querschnittsfläche: 0.001 m2; Charakteristischer Wert der Eigenlast: 0.081
RWA-Wechsel | Wartung_FFB |  | RWA-Wechsel |  | 0.3998 | Wartung_FFB |  |  |  |  |  |  |  |  |  | 0123ErE0000000595 | kg | T105 | true | HA_UZV_IPE_STA_0,100_xxx | AllplanAttributes - Querschnittsfläche: 0.001 m2; Charakteristischer Wert der Eigenlast: 0.081
RWA-Wechsel | Wartung_FFB |  | RWA-Wechsel |  | 0.3998 | Wartung_FFB |  |  |  |  |  |  |  |  |  | 0123ErE0000000596 | kg | T105 | true | HA_UZV_IPE_STA_0,100_xxx | AllplanAttributes - Querschnittsfläche: 0.001 m2; Charakteristischer Wert der Eigenlast: 0.081
RWA-Wechsel | Wartung_FFB |  | RWA-Wechsel |  | 0.3998 | Wartung_FFB |  |  |  |  |  |  |  |  |  | 0123ErE0000000597 | kg | T105 | true | HA_UZV_IPE_STA_0,100_xxx | AllplanAttributes - Querschnittsfläche: 0.001 m2; Charakteristischer Wert der Eigenlast: 0.081
RWA-Wechsel | Wartung_FFB |  | RWA-Wechsel |  | 0.3998 | Wartung_FFB |  |  |  |  |  |  |  |  |  | 0123ErE0000000088 | kg | T105 | true | HA_UZV_IPE_STA_0,100_xxx | AllplanAttributes - Querschnittsfläche: 0.001 m2; Charakteristischer Wert der Eigenlast: 0.081
RWA-Wechsel | Wartung_FFB |  | RWA-Wechsel |  | 0.3998 | Wartung_FFB |  |  |  |  |  |  |  |  |  | 0123ErE0000000089 | kg | T105 | true | HA_UZV_IPE_STA_0,100_xxx | AllplanAttributes - Querschnittsfläche: 0.001 m2; Charakteristischer Wert der Eigenlast: 0.081
RWA-Wechsel | Wartung_FFB |  | RWA-Wechsel |  | 0.3998 | Wartung_FFB |  |  |  |  |  |  |  |  |  | 0123ErE0000000090 | kg | T105 | true | HA_UZV_IPE_STA_0,100_xxx | AllplanAttributes - Querschnittsfläche: 0.001 m2; Charakteristischer Wert der Eigenlast: 0.081
RWA-Wechsel | Wartung_FFB |  | RWA-Wechsel |  | 0.3998 | Wartung_FFB |  |  |  |  |  |  |  |  |  | 0123ErE0000000177 | kg | T105 | true | HA_UZV_IPE_STA_0,100_xxx | AllplanAttributes - Querschnittsfläche: 0.001 m2; Charakteristischer Wert der Eigenlast: 0.081
RWA-Wechsel | Wartung_FFB |  | RWA-Wechsel |  | 0.3998 | Wartung_FFB |  |  |  |  |  |  |  |  |  | 0123ErE0000000178 | kg | T105 | true | HA_UZV_IPE_STA_0,100_xxx | AllplanAttributes - Querschnittsfläche: 0.001 m2; Charakteristischer Wert der Eigenlast: 0.081
RWA-Wechsel | Wartung_FFB |  | RWA-Wechsel |  | 0.3998 | Wartung_FFB |  |  |  |  |  |  |  |  |  | 0123ErE0000000179 | kg | T105 | true | HA_UZV_IPE_STA_0,100_xxx | AllplanAttributes - Querschnittsfläche: 0.001 m2; Charakteristischer Wert der Eigenlast: 0.081
RWA-Wechsel | Wartung_FFB |  | RWA-Wechsel |  | 0.3998 | Wartung_FFB |  |  |  |  |  |  |  |  |  | 0123ErE0000000187 | kg | T105 | true | HA_UZV_IPE_STA_0,100_xxx | AllplanAttributes - Querschnittsfläche: 0.001 m2; Charakteristischer Wert der Eigenlast: 0.081
RWA-Wechsel | Wartung_FFB |  | RWA-Wechsel |  | 0.3998 | Wartung_FFB |  |  |  |  |  |  |  |  |  | 0123ErE0000000188 | kg | T105 | true | HA_UZV_IPE_STA_0,100_xxx | AllplanAttributes - Querschnittsfläche: 0.001 m2; Charakteristischer Wert der Eigenlast: 0.081
RWA-Wechsel | Wartung_FFB |  | RWA-Wechsel |  | 0.3998 | Wartung_FFB |  |  |  |  |  |  |  |  |  | 0123ErE0000000189 | kg | T105 | true | HA_UZV_IPE_STA_0,100_xxx | AllplanAttributes - Querschnittsfläche: 0.001 m2; Charakteristischer Wert der Eigenlast: 0.081
RWA-Wechsel | Wartung_FFB |  | RWA-Wechsel |  | 0.3998 | Wartung_FFB |  |  |  |  |  |  |  |  |  | 0123ErE0000000197 | kg | T105 | true | HA_UZV_IPE_STA_0,100_xxx | AllplanAttributes - Querschnittsfläche: 0.001 m2; Charakteristischer Wert der Eigenlast: 0.081
RWA-Wechsel | Wartung_FFB |  | RWA-Wechsel |  | 0.3998 | Wartung_FFB |  |  |  |  |  |  |  |  |  | 0123ErE0000000198 | kg | T105 | true | HA_UZV_IPE_STA_0,100_xxx | AllplanAttributes - Querschnittsfläche: 0.001 m2; Charakteristischer Wert der Eigenlast: 0.081
RWA-Wechsel | Wartung_FFB |  | RWA-Wechsel |  | 0.3998 | Wartung_FFB |  |  |  |  |  |  |  |  |  | 0123ErE0000000199 | kg | T105 | true | HA_UZV_IPE_STA_0,100_xxx | AllplanAttributes - Querschnittsfläche: 0.001 m2; Charakteristischer Wert der Eigenlast: 0.081
RWA-Wechsel | Wartung_FFB |  | RWA-Wechsel |  | 0.3998 | Wartung_FFB |  |  |  |  |  |  |  |  |  | 0123ErE0000000207 | kg | T105 | true | HA_UZV_IPE_STA_0,100_xxx | AllplanAttributes - Querschnittsfläche: 0.001 m2; Charakteristischer Wert der Eigenlast: 0.081
RWA-Wechsel | Wartung_FFB |  | RWA-Wechsel |  | 0.3998 | Wartung_FFB |  |  |  |  |  |  |  |  |  | 0123ErE0000000208 | kg | T105 | true | HA_UZV_IPE_STA_0,100_xxx | AllplanAttributes - Querschnittsfläche: 0.001 m2; Charakteristischer Wert der Eigenlast: 0.081
RWA-Wechsel | Wartung_FFB |  | RWA-Wechsel |  | 0.3998 | Wartung_FFB |  |  |  |  |  |  |  |  |  | 0123ErE0000000209 | kg | T105 | true | HA_UZV_IPE_STA_0,100_xxx | AllplanAttributes - Querschnittsfläche: 0.001 m2; Charakteristischer Wert der Eigenlast: 0.081
RWA-Wechsel | Wartung_FFB |  | RWA-Wechsel |  | 0.3998 | Wartung_FFB |  |  |  |  |  |  |  |  |  | 0123ErE0000000217 | kg | T105 | true | HA_UZV_IPE_STA_0,100_xxx | AllplanAttributes - Querschnittsfläche: 0.001 m2; Charakteristischer Wert der Eigenlast: 0.081
RWA-Wechsel | Wartung_FFB |  | RWA-Wechsel |  | 0.3998 | Wartung_FFB |  |  |  |  |  |  |  |  |  | 0123ErE0000000218 | kg | T105 | true | HA_UZV_IPE_STA_0,100_xxx | AllplanAttributes - Querschnittsfläche: 0.001 m2; Charakteristischer Wert der Eigenlast: 0.081
RWA-Wechsel | Wartung_FFB |  | RWA-Wechsel |  | 0.3998 | Wartung_FFB |  |  |  |  |  |  |  |  |  | 0123ErE0000000219 | kg | T105 | true | HA_UZV_IPE_STA_0,100_xxx | AllplanAttributes - Querschnittsfläche: 0.001 m2; Charakteristischer Wert der Eigenlast: 0.081
RWA-Wechsel | Wartung_FFB |  | RWA-Wechsel |  | 0.3998 | Wartung_FFB |  |  |  |  |  |  |  |  |  | 0123ErE0000000084 | kg | T105 | true | HA_UZV_IPE_STA_0,100_xxx | AllplanAttributes - Querschnittsfläche: 0.001 m2; Charakteristischer Wert der Eigenlast: 0.081
RWA-Wechsel | Wartung_FFB |  | RWA-Wechsel |  | 0.3998 | Wartung_FFB |  |  |  |  |  |  |  |  |  | 0123ErE0000000085 | kg | T105 | true | HA_UZV_IPE_STA_0,100_xxx | AllplanAttributes - Querschnittsfläche: 0.001 m2; Charakteristischer Wert der Eigenlast: 0.081
RWA-Wechsel | Wartung_FFB |  | RWA-Wechsel |  | 0.3998 | Wartung_FFB |  |  |  |  |  |  |  |  |  | 0123ErE0000000086 | kg | T105 | true | HA_UZV_IPE_STA_0,100_xxx | AllplanAttributes - Querschnittsfläche: 0.001 m2; Charakteristischer Wert der Eigenlast: 0.081
RWA-Wechsel | Wartung_FFB |  | RWA-Wechsel |  | 0.3998 | Wartung_FFB |  |  |  |  |  |  |  |  |  | 0123ErE0000000180 | kg | T105 | true | HA_UZV_IPE_STA_0,100_xxx | AllplanAttributes - Querschnittsfläche: 0.001 m2; Charakteristischer Wert der Eigenlast: 0.081
RWA-Wechsel | Wartung_FFB |  | RWA-Wechsel |  | 0.3998 | Wartung_FFB |  |  |  |  |  |  |  |  |  | 0123ErE0000000181 | kg | T105 | true | HA_UZV_IPE_STA_0,100_xxx | AllplanAttributes - Querschnittsfläche: 0.001 m2; Charakteristischer Wert der Eigenlast: 0.081
RWA-Wechsel | Wartung_FFB |  | RWA-Wechsel |  | 0.3998 | Wartung_FFB |  |  |  |  |  |  |  |  |  | 0123ErE0000000182 | kg | T105 | true | HA_UZV_IPE_STA_0,100_xxx | AllplanAttributes - Querschnittsfläche: 0.001 m2; Charakteristischer Wert der Eigenlast: 0.081
RWA-Wechsel | Wartung_FFB |  | RWA-Wechsel |  | 0.3998 | Wartung_FFB |  |  |  |  |  |  |  |  |  | 0123ErE0000000190 | kg | T105 | true | HA_UZV_IPE_STA_0,100_xxx | AllplanAttributes - Querschnittsfläche: 0.001 m2; Charakteristischer Wert der Eigenlast: 0.081
RWA-Wechsel | Wartung_FFB |  | RWA-Wechsel |  | 0.3998 | Wartung_FFB |  |  |  |  |  |  |  |  |  | 0123ErE0000000191 | kg | T105 | true | HA_UZV_IPE_STA_0,100_xxx | AllplanAttributes - Querschnittsfläche: 0.001 m2; Charakteristischer Wert der Eigenlast: 0.081
RWA-Wechsel | Wartung_FFB |  | RWA-Wechsel |  | 0.3998 | Wartung_FFB |  |  |  |  |  |  |  |  |  | 0123ErE0000000192 | kg | T105 | true | HA_UZV_IPE_STA_0,100_xxx | AllplanAttributes - Querschnittsfläche: 0.001 m2; Charakteristischer Wert der Eigenlast: 0.081
RWA-Wechsel | Wartung_FFB |  | RWA-Wechsel |  | 0.3998 | Wartung_FFB |  |  |  |  |  |  |  |  |  | 0123ErE0000000200 | kg | T105 | true | HA_UZV_IPE_STA_0,100_xxx | AllplanAttributes - Querschnittsfläche: 0.001 m2; Charakteristischer Wert der Eigenlast: 0.081
RWA-Wechsel | Wartung_FFB |  | RWA-Wechsel |  | 0.3998 | Wartung_FFB |  |  |  |  |  |  |  |  |  | 0123ErE0000000201 | kg | T105 | true | HA_UZV_IPE_STA_0,100_xxx | AllplanAttributes - Querschnittsfläche: 0.001 m2; Charakteristischer Wert der Eigenlast: 0.081
RWA-Wechsel | Wartung_FFB |  | RWA-Wechsel |  | 0.3998 | Wartung_FFB |  |  |  |  |  |  |  |  |  | 0123ErE0000000202 | kg | T105 | true | HA_UZV_IPE_STA_0,100_xxx | AllplanAttributes - Querschnittsfläche: 0.001 m2; Charakteristischer Wert der Eigenlast: 0.081
RWA-Wechsel | Wartung_FFB |  | RWA-Wechsel |  | 0.3998 | Wartung_FFB |  |  |  |  |  |  |  |  |  | 0123ErE0000000210 | kg | T105 | true | HA_UZV_IPE_STA_0,100_xxx | AllplanAttributes - Querschnittsfläche: 0.001 m2; Charakteristischer Wert der Eigenlast: 0.081
RWA-Wechsel | Wartung_FFB |  | RWA-Wechsel |  | 0.3998 | Wartung_FFB |  |  |  |  |  |  |  |  |  | 0123ErE0000000211 | kg | T105 | true | HA_UZV_IPE_STA_0,100_xxx | AllplanAttributes - Querschnittsfläche: 0.001 m2; Charakteristischer Wert der Eigenlast: 0.081
RWA-Wechsel | Wartung_FFB |  | RWA-Wechsel |  | 0.3998 | Wartung_FFB |  |  |  |  |  |  |  |  |  | 0123ErE0000000212 | kg | T105 | true | HA_UZV_IPE_STA_0,100_xxx | AllplanAttributes - Querschnittsfläche: 0.001 m2; Charakteristischer Wert der Eigenlast: 0.081
RWA-Wechsel | Wartung_FFB |  | RWA-Wechsel |  | 0.3998 | Wartung_FFB |  |  |  |  |  |  |  |  |  | 0123ErE0000000220 | kg | T105 | true | HA_UZV_IPE_STA_0,100_xxx | AllplanAttributes - Querschnittsfläche: 0.001 m2; Charakteristischer Wert der Eigenlast: 0.081
RWA-Wechsel | Wartung_FFB |  | RWA-Wechsel |  | 0.3998 | Wartung_FFB |  |  |  |  |  |  |  |  |  | 0123ErE0000000221 | kg | T105 | true | HA_UZV_IPE_STA_0,100_xxx | AllplanAttributes - Querschnittsfläche: 0.001 m2; Charakteristischer Wert der Eigenlast: 0.081
RWA-Wechsel | Wartung_FFB |  | RWA-Wechsel |  | 0.3998 | Wartung_FFB |  |  |  |  |  |  |  |  |  | 0123ErE0000000222 | kg | T105 | true | HA_UZV_IPE_STA_0,100_xxx | AllplanAttributes - Querschnittsfläche: 0.001 m2; Charakteristischer Wert der Eigenlast: 0.081
RWA-Wechsel | Wartung_FFB |  | RWA-Wechsel |  | 0.3998 | Wartung_FFB |  |  |  |  |  |  |  |  |  | 0123ErE0000000228 | kg | T105 | true | HA_UZV_IPE_STA_0,100_xxx | AllplanAttributes - Querschnittsfläche: 0.001 m2; Charakteristischer Wert der Eigenlast: 0.081
RWA-Wechsel | Wartung_FFB |  | RWA-Wechsel |  | 0.3998 | Wartung_FFB |  |  |  |  |  |  |  |  |  | 0123ErE0000000229 | kg | T105 | true | HA_UZV_IPE_STA_0,100_xxx | AllplanAttributes - Querschnittsfläche: 0.001 m2; Charakteristischer Wert der Eigenlast: 0.081
RWA-Wechsel | Wartung_FFB |  | RWA-Wechsel |  | 0.3998 | Wartung_FFB |  |  |  |  |  |  |  |  |  | 0123ErE0000000230 | kg | T105 | true | HA_UZV_IPE_STA_0,100_xxx | AllplanAttributes - Querschnittsfläche: 0.001 m2; Charakteristischer Wert der Eigenlast: 0.081
RWA-Wechsel | Wartung_FFB |  | RWA-Wechsel |  | 0.3998 | Wartung_FFB |  |  |  |  |  |  |  |  |  | 0123ErE0000000238 | kg | T105 | true | HA_UZV_IPE_STA_0,100_xxx | AllplanAttributes - Querschnittsfläche: 0.001 m2; Charakteristischer Wert der Eigenlast: 0.081
RWA-Wechsel | Wartung_FFB |  | RWA-Wechsel |  | 0.3998 | Wartung_FFB |  |  |  |  |  |  |  |  |  | 0123ErE0000000239 | kg | T105 | true | HA_UZV_IPE_STA_0,100_xxx | AllplanAttributes - Querschnittsfläche: 0.001 m2; Charakteristischer Wert der Eigenlast: 0.081
RWA-Wechsel | Wartung_FFB |  | RWA-Wechsel |  | 0.3998 | Wartung_FFB |  |  |  |  |  |  |  |  |  | 0123ErE0000000240 | kg | T105 | true | HA_UZV_IPE_STA_0,100_xxx | AllplanAttributes - Querschnittsfläche: 0.001 m2; Charakteristischer Wert der Eigenlast: 0.081
RWA-Wechsel | Wartung_FFB |  | RWA-Wechsel |  | 0.3998 | Wartung_FFB |  |  |  |  |  |  |  |  |  | 0123ErE0000000248 | kg | T105 | true | HA_UZV_IPE_STA_0,100_xxx | AllplanAttributes - Querschnittsfläche: 0.001 m2; Charakteristischer Wert der Eigenlast: 0.081
RWA-Wechsel | Wartung_FFB |  | RWA-Wechsel |  | 0.3998 | Wartung_FFB |  |  |  |  |  |  |  |  |  | 0123ErE0000000249 | kg | T105 | true | HA_UZV_IPE_STA_0,100_xxx | AllplanAttributes - Querschnittsfläche: 0.001 m2; Charakteristischer Wert der Eigenlast: 0.081
RWA-Wechsel | Wartung_FFB |  | RWA-Wechsel |  | 0.3998 | Wartung_FFB |  |  |  |  |  |  |  |  |  | 0123ErE0000000250 | kg | T105 | true | HA_UZV_IPE_STA_0,100_xxx | AllplanAttributes - Querschnittsfläche: 0.001 m2; Charakteristischer Wert der Eigenlast: 0.081
RWA-Wechsel | Wartung_FFB |  | RWA-Wechsel |  | 0.3998 | Wartung_FFB |  |  |  |  |  |  |  |  |  | 0123ErE0000000258 | kg | T105 | true | HA_UZV_IPE_STA_0,100_xxx | AllplanAttributes - Querschnittsfläche: 0.001 m2; Charakteristischer Wert der Eigenlast: 0.081
RWA-Wechsel | Wartung_FFB |  | RWA-Wechsel |  | 0.3998 | Wartung_FFB |  |  |  |  |  |  |  |  |  | 0123ErE0000000259 | kg | T105 | true | HA_UZV_IPE_STA_0,100_xxx | AllplanAttributes - Querschnittsfläche: 0.001 m2; Charakteristischer Wert der Eigenlast: 0.081
RWA-Wechsel | Wartung_FFB |  | RWA-Wechsel |  | 0.3998 | Wartung_FFB |  |  |  |  |  |  |  |  |  | 0123ErE0000000260 | kg | T105 | true | HA_UZV_IPE_STA_0,100_xxx | AllplanAttributes - Querschnittsfläche: 0.001 m2; Charakteristischer Wert der Eigenlast: 0.081
RWA-Wechsel | Wartung_FFB |  | RWA-Wechsel |  | 0.3998 | Wartung_FFB |  |  |  |  |  |  |  |  |  | 0123ErE0000000268 | kg | T105 | true | HA_UZV_IPE_STA_0,100_xxx | AllplanAttributes - Querschnittsfläche: 0.001 m2; Charakteristischer Wert der Eigenlast: 0.081
RWA-Wechsel | Wartung_FFB |  | RWA-Wechsel |  | 0.3998 | Wartung_FFB |  |  |  |  |  |  |  |  |  | 0123ErE0000000269 | kg | T105 | true | HA_UZV_IPE_STA_0,100_xxx | AllplanAttributes - Querschnittsfläche: 0.001 m2; Charakteristischer Wert der Eigenlast: 0.081
RWA-Wechsel | Wartung_FFB |  | RWA-Wechsel |  | 0.3998 | Wartung_FFB |  |  |  |  |  |  |  |  |  | 0123ErE0000000270 | kg | T105 | true | HA_UZV_IPE_STA_0,100_xxx | AllplanAttributes - Querschnittsfläche: 0.001 m2; Charakteristischer Wert der Eigenlast: 0.081
RWA-Wechsel | Wartung_FFB |  | RWA-Wechsel |  | 0.3998 | Wartung_FFB |  |  |  |  |  |  |  |  |  | 0123ErE0000000278 | kg | T105 | true | HA_UZV_IPE_STA_0,100_xxx | AllplanAttributes - Querschnittsfläche: 0.001 m2; Charakteristischer Wert der Eigenlast: 0.081
RWA-Wechsel | Wartung_FFB |  | RWA-Wechsel |  | 0.3998 | Wartung_FFB |  |  |  |  |  |  |  |  |  | 0123ErE0000000279 | kg | T105 | true | HA_UZV_IPE_STA_0,100_xxx | AllplanAttributes - Querschnittsfläche: 0.001 m2; Charakteristischer Wert der Eigenlast: 0.081
RWA-Wechsel | Wartung_FFB |  | RWA-Wechsel |  | 0.3998 | Wartung_FFB |  |  |  |  |  |  |  |  |  | 0123ErE0000000280 | kg | T105 | true | HA_UZV_IPE_STA_0,100_xxx | AllplanAttributes - Querschnittsfläche: 0.001 m2; Charakteristischer Wert der Eigenlast: 0.081
RWA-Wechsel | Wartung_FFB |  | RWA-Wechsel |  | 0.3998 | Wartung_FFB |  |  |  |  |  |  |  |  |  | 0123ErE0000000231 | kg | T105 | true | HA_UZV_IPE_STA_0,100_xxx | AllplanAttributes - Querschnittsfläche: 0.001 m2; Charakteristischer Wert der Eigenlast: 0.081
RWA-Wechsel | Wartung_FFB |  | RWA-Wechsel |  | 0.3998 | Wartung_FFB |  |  |  |  |  |  |  |  |  | 0123ErE0000000232 | kg | T105 | true | HA_UZV_IPE_STA_0,100_xxx | AllplanAttributes - Querschnittsfläche: 0.001 m2; Charakteristischer Wert der Eigenlast: 0.081
RWA-Wechsel | Wartung_FFB |  | RWA-Wechsel |  | 0.3998 | Wartung_FFB |  |  |  |  |  |  |  |  |  | 0123ErE0000000233 | kg | T105 | true | HA_UZV_IPE_STA_0,100_xxx | AllplanAttributes - Querschnittsfläche: 0.001 m2; Charakteristischer Wert der Eigenlast: 0.081
RWA-Wechsel | Wartung_FFB |  | RWA-Wechsel |  | 0.3998 | Wartung_FFB |  |  |  |  |  |  |  |  |  | 0123ErE0000000241 | kg | T105 | true | HA_UZV_IPE_STA_0,100_xxx | AllplanAttributes - Querschnittsfläche: 0.001 m2; Charakteristischer Wert der Eigenlast: 0.081
RWA-Wechsel | Wartung_FFB |  | RWA-Wechsel |  | 0.3998 | Wartung_FFB |  |  |  |  |  |  |  |  |  | 0123ErE0000000242 | kg | T105 | true | HA_UZV_IPE_STA_0,100_xxx | AllplanAttributes - Querschnittsfläche: 0.001 m2; Charakteristischer Wert der Eigenlast: 0.081
RWA-Wechsel | Wartung_FFB |  | RWA-Wechsel |  | 0.3998 | Wartung_FFB |  |  |  |  |  |  |  |  |  | 0123ErE0000000243 | kg | T105 | true | HA_UZV_IPE_STA_0,100_xxx | AllplanAttributes - Querschnittsfläche: 0.001 m2; Charakteristischer Wert der Eigenlast: 0.081
RWA-Wechsel | Wartung_FFB |  | RWA-Wechsel |  | 0.3998 | Wartung_FFB |  |  |  |  |  |  |  |  |  | 0123ErE0000000251 | kg | T105 | true | HA_UZV_IPE_STA_0,100_xxx | AllplanAttributes - Querschnittsfläche: 0.001 m2; Charakteristischer Wert der Eigenlast: 0.081
RWA-Wechsel | Wartung_FFB |  | RWA-Wechsel |  | 0.3998 | Wartung_FFB |  |  |  |  |  |  |  |  |  | 0123ErE0000000252 | kg | T105 | true | HA_UZV_IPE_STA_0,100_xxx | AllplanAttributes - Querschnittsfläche: 0.001 m2; Charakteristischer Wert der Eigenlast: 0.081
RWA-Wechsel | Wartung_FFB |  | RWA-Wechsel |  | 0.3998 | Wartung_FFB |  |  |  |  |  |  |  |  |  | 0123ErE0000000253 | kg | T105 | true | HA_UZV_IPE_STA_0,100_xxx | AllplanAttributes - Querschnittsfläche: 0.001 m2; Charakteristischer Wert der Eigenlast: 0.081
RWA-Wechsel | Wartung_FFB |  | RWA-Wechsel |  | 0.3998 | Wartung_FFB |  |  |  |  |  |  |  |  |  | 0123ErE0000000261 | kg | T105 | true | HA_UZV_IPE_STA_0,100_xxx | AllplanAttributes - Querschnittsfläche: 0.001 m2; Charakteristischer Wert der Eigenlast: 0.081
RWA-Wechsel | Wartung_FFB |  | RWA-Wechsel |  | 0.3998 | Wartung_FFB |  |  |  |  |  |  |  |  |  | 0123ErE0000000262 | kg | T105 | true | HA_UZV_IPE_STA_0,100_xxx | AllplanAttributes - Querschnittsfläche: 0.001 m2; Charakteristischer Wert der Eigenlast: 0.081
RWA-Wechsel | Wartung_FFB |  | RWA-Wechsel |  | 0.3998 | Wartung_FFB |  |  |  |  |  |  |  |  |  | 0123ErE0000000263 | kg | T105 | true | HA_UZV_IPE_STA_0,100_xxx | AllplanAttributes - Querschnittsfläche: 0.001 m2; Charakteristischer Wert der Eigenlast: 0.081
RWA-Wechsel | Wartung_FFB |  | RWA-Wechsel |  | 0.3998 | Wartung_FFB |  |  |  |  |  |  |  |  |  | 0123ErE0000000271 | kg | T105 | true | HA_UZV_IPE_STA_0,100_xxx | AllplanAttributes - Querschnittsfläche: 0.001 m2; Charakteristischer Wert der Eigenlast: 0.081
RWA-Wechsel | Wartung_FFB |  | RWA-Wechsel |  | 0.3998 | Wartung_FFB |  |  |  |  |  |  |  |  |  | 0123ErE0000000272 | kg | T105 | true | HA_UZV_IPE_STA_0,100_xxx | AllplanAttributes - Querschnittsfläche: 0.001 m2; Charakteristischer Wert der Eigenlast: 0.081
RWA-Wechsel | Wartung_FFB |  | RWA-Wechsel |  | 0.3998 | Wartung_FFB |  |  |  |  |  |  |  |  |  | 0123ErE0000000273 | kg | T105 | true | HA_UZV_IPE_STA_0,100_xxx | AllplanAttributes - Querschnittsfläche: 0.001 m2; Charakteristischer Wert der Eigenlast: 0.081
RWA-Wechsel | Wartung_FFB |  | RWA-Wechsel |  | 0.3998 | Wartung_FFB |  |  |  |  |  |  |  |  |  | 0123ErE0000000281 | kg | T105 | true | HA_UZV_IPE_STA_0,100_xxx | AllplanAttributes - Querschnittsfläche: 0.001 m2; Charakteristischer Wert der Eigenlast: 0.081
RWA-Wechsel | Wartung_FFB |  | RWA-Wechsel |  | 0.3998 | Wartung_FFB |  |  |  |  |  |  |  |  |  | 0123ErE0000000282 | kg | T105 | true | HA_UZV_IPE_STA_0,100_xxx | AllplanAttributes - Querschnittsfläche: 0.001 m2; Charakteristischer Wert der Eigenlast: 0.081
RWA-Wechsel | Wartung_FFB |  | RWA-Wechsel |  | 0.3998 | Wartung_FFB |  |  |  |  |  |  |  |  |  | 0123ErE0000000283 | kg | T105 | true | HA_UZV_IPE_STA_0,100_xxx | AllplanAttributes - Querschnittsfläche: 0.001 m2; Charakteristischer Wert der Eigenlast: 0.081
RWA-Wechsel | Wartung_FFB |  | RWA-Wechsel |  | 0.3998 | Wartung_FFB |  |  |  |  |  |  |  |  |  | 0123ErE0000000509 | kg | T105 | true | HA_UZV_IPE_STA_0,100_xxx | AllplanAttributes - Querschnittsfläche: 0.001 m2; Charakteristischer Wert der Eigenlast: 0.081
RWA-Wechsel | Wartung_FFB |  | RWA-Wechsel |  | 0.3998 | Wartung_FFB |  |  |  |  |  |  |  |  |  | 0123ErE0000000510 | kg | T105 | true | HA_UZV_IPE_STA_0,100_xxx | AllplanAttributes - Querschnittsfläche: 0.001 m2; Charakteristischer Wert der Eigenlast: 0.081
RWA-Wechsel | Wartung_FFB |  | RWA-Wechsel |  | 0.3998 | Wartung_FFB |  |  |  |  |  |  |  |  |  | 0123ErE0000000511 | kg | T105 | true | HA_UZV_IPE_STA_0,100_xxx | AllplanAttributes - Querschnittsfläche: 0.001 m2; Charakteristischer Wert der Eigenlast: 0.081
RWA-Wechsel | Wartung_FFB |  | RWA-Wechsel |  | 0.3998 | Wartung_FFB |  |  |  |  |  |  |  |  |  | 0123ErE0000000515 | kg | T105 | true | HA_UZV_IPE_STA_0,100_xxx | AllplanAttributes - Querschnittsfläche: 0.001 m2; Charakteristischer Wert der Eigenlast: 0.081
RWA-Wechsel | Wartung_FFB |  | RWA-Wechsel |  | 0.3998 | Wartung_FFB |  |  |  |  |  |  |  |  |  | 0123ErE0000000516 | kg | T105 | true | HA_UZV_IPE_STA_0,100_xxx | AllplanAttributes - Querschnittsfläche: 0.001 m2; Charakteristischer Wert der Eigenlast: 0.081
RWA-Wechsel | Wartung_FFB |  | RWA-Wechsel |  | 0.3998 | Wartung_FFB |  |  |  |  |  |  |  |  |  | 0123ErE0000000517 | kg | T105 | true | HA_UZV_IPE_STA_0,100_xxx | AllplanAttributes - Querschnittsfläche: 0.001 m2; Charakteristischer Wert der Eigenlast: 0.081
RWA-Wechsel | Wartung_FFB |  | RWA-Wechsel |  | 0.3998 | Wartung_FFB |  |  |  |  |  |  |  |  |  | 0123ErE0000000521 | kg | T105 | true | HA_UZV_IPE_STA_0,100_xxx | AllplanAttributes - Querschnittsfläche: 0.001 m2; Charakteristischer Wert der Eigenlast: 0.081
RWA-Wechsel | Wartung_FFB |  | RWA-Wechsel |  | 0.3998 | Wartung_FFB |  |  |  |  |  |  |  |  |  | 0123ErE0000000522 | kg | T105 | true | HA_UZV_IPE_STA_0,100_xxx | AllplanAttributes - Querschnittsfläche: 0.001 m2; Charakteristischer Wert der Eigenlast: 0.081
RWA-Wechsel | Wartung_FFB |  | RWA-Wechsel |  | 0.3998 | Wartung_FFB |  |  |  |  |  |  |  |  |  | 0123ErE0000000523 | kg | T105 | true | HA_UZV_IPE_STA_0,100_xxx | AllplanAttributes - Querschnittsfläche: 0.001 m2; Charakteristischer Wert der Eigenlast: 0.081
RWA-Wechsel | Wartung_FFB |  | RWA-Wechsel |  | 0.3998 | Wartung_FFB |  |  |  |  |  |  |  |  |  | 0123ErE0000000527 | kg | T105 | true | HA_UZV_IPE_STA_0,100_xxx | AllplanAttributes - Querschnittsfläche: 0.001 m2; Charakteristischer Wert der Eigenlast: 0.081
RWA-Wechsel | Wartung_FFB |  | RWA-Wechsel |  | 0.3998 | Wartung_FFB |  |  |  |  |  |  |  |  |  | 0123ErE0000000528 | kg | T105 | true | HA_UZV_IPE_STA_0,100_xxx | AllplanAttributes - Querschnittsfläche: 0.001 m2; Charakteristischer Wert der Eigenlast: 0.081
RWA-Wechsel | Wartung_FFB |  | RWA-Wechsel |  | 0.3998 | Wartung_FFB |  |  |  |  |  |  |  |  |  | 0123ErE0000000529 | kg | T105 | true | HA_UZV_IPE_STA_0,100_xxx | AllplanAttributes - Querschnittsfläche: 0.001 m2; Charakteristischer Wert der Eigenlast: 0.081
RWA-Wechsel | Wartung_FFB |  | RWA-Wechsel |  | 0.3998 | Wartung_FFB |  |  |  |  |  |  |  |  |  | 0123ErE0000000533 | kg | T105 | true | HA_UZV_IPE_STA_0,100_xxx | AllplanAttributes - Querschnittsfläche: 0.001 m2; Charakteristischer Wert der Eigenlast: 0.081
RWA-Wechsel | Wartung_FFB |  | RWA-Wechsel |  | 0.3998 | Wartung_FFB |  |  |  |  |  |  |  |  |  | 0123ErE0000000534 | kg | T105 | true | HA_UZV_IPE_STA_0,100_xxx | AllplanAttributes - Querschnittsfläche: 0.001 m2; Charakteristischer Wert der Eigenlast: 0.081
RWA-Wechsel | Wartung_FFB |  | RWA-Wechsel |  | 0.3998 | Wartung_FFB |  |  |  |  |  |  |  |  |  | 0123ErE0000000535 | kg | T105 | true | HA_UZV_IPE_STA_0,100_xxx | AllplanAttributes - Querschnittsfläche: 0.001 m2; Charakteristischer Wert der Eigenlast: 0.081
RWA-Wechsel | Wartung_FFB |  | RWA-Wechsel |  | 0.3998 | Wartung_FFB |  |  |  |  |  |  |  |  |  | 0123ErE0000000539 | kg | T105 | true | HA_UZV_IPE_STA_0,100_xxx | AllplanAttributes - Querschnittsfläche: 0.001 m2; Charakteristischer Wert der Eigenlast: 0.081
RWA-Wechsel | Wartung_FFB |  | RWA-Wechsel |  | 0.3998 | Wartung_FFB |  |  |  |  |  |  |  |  |  | 0123ErE0000000540 | kg | T105 | true | HA_UZV_IPE_STA_0,100_xxx | AllplanAttributes - Querschnittsfläche: 0.001 m2; Charakteristischer Wert der Eigenlast: 0.081
RWA-Wechsel | Wartung_FFB |  | RWA-Wechsel |  | 0.3998 | Wartung_FFB |  |  |  |  |  |  |  |  |  | 0123ErE0000000541 | kg | T105 | true | HA_UZV_IPE_STA_0,100_xxx | AllplanAttributes - Querschnittsfläche: 0.001 m2; Charakteristischer Wert der Eigenlast: 0.081
RWA-Wechsel | Wartung_FFB |  | RWA-Wechsel |  | 0.3998 | Wartung_FFB |  |  |  |  |  |  |  |  |  | 0123ErE0000000512 | kg | T105 | true | HA_UZV_IPE_STA_0,100_xxx | AllplanAttributes - Querschnittsfläche: 0.001 m2; Charakteristischer Wert der Eigenlast: 0.081
RWA-Wechsel | Wartung_FFB |  | RWA-Wechsel |  | 0.3998 | Wartung_FFB |  |  |  |  |  |  |  |  |  | 0123ErE0000000513 | kg | T105 | true | HA_UZV_IPE_STA_0,100_xxx | AllplanAttributes - Querschnittsfläche: 0.001 m2; Charakteristischer Wert der Eigenlast: 0.081
RWA-Wechsel | Wartung_FFB |  | RWA-Wechsel |  | 0.3998 | Wartung_FFB |  |  |  |  |  |  |  |  |  | 0123ErE0000000514 | kg | T105 | true | HA_UZV_IPE_STA_0,100_xxx | AllplanAttributes - Querschnittsfläche: 0.001 m2; Charakteristischer Wert der Eigenlast: 0.081
RWA-Wechsel | Wartung_FFB |  | RWA-Wechsel |  | 0.3998 | Wartung_FFB |  |  |  |  |  |  |  |  |  | 0123ErE0000000518 | kg | T105 | true | HA_UZV_IPE_STA_0,100_xxx | AllplanAttributes - Querschnittsfläche: 0.001 m2; Charakteristischer Wert der Eigenlast: 0.081
RWA-Wechsel | Wartung_FFB |  | RWA-Wechsel |  | 0.3998 | Wartung_FFB |  |  |  |  |  |  |  |  |  | 0123ErE0000000519 | kg | T105 | true | HA_UZV_IPE_STA_0,100_xxx | AllplanAttributes - Querschnittsfläche: 0.001 m2; Charakteristischer Wert der Eigenlast: 0.081
RWA-Wechsel | Wartung_FFB |  | RWA-Wechsel |  | 0.3998 | Wartung_FFB |  |  |  |  |  |  |  |  |  | 0123ErE0000000520 | kg | T105 | true | HA_UZV_IPE_STA_0,100_xxx | AllplanAttributes - Querschnittsfläche: 0.001 m2; Charakteristischer Wert der Eigenlast: 0.081
RWA-Wechsel | Wartung_FFB |  | RWA-Wechsel |  | 0.3998 | Wartung_FFB |  |  |  |  |  |  |  |  |  | 0123ErE0000000524 | kg | T105 | true | HA_UZV_IPE_STA_0,100_xxx | AllplanAttributes - Querschnittsfläche: 0.001 m2; Charakteristischer Wert der Eigenlast: 0.081
RWA-Wechsel | Wartung_FFB |  | RWA-Wechsel |  | 0.3998 | Wartung_FFB |  |  |  |  |  |  |  |  |  | 0123ErE0000000525 | kg | T105 | true | HA_UZV_IPE_STA_0,100_xxx | AllplanAttributes - Querschnittsfläche: 0.001 m2; Charakteristischer Wert der Eigenlast: 0.081
RWA-Wechsel | Wartung_FFB |  | RWA-Wechsel |  | 0.3998 | Wartung_FFB |  |  |  |  |  |  |  |  |  | 0123ErE0000000526 | kg | T105 | true | HA_UZV_IPE_STA_0,100_xxx | AllplanAttributes - Querschnittsfläche: 0.001 m2; Charakteristischer Wert der Eigenlast: 0.081
RWA-Wechsel | Wartung_FFB |  | RWA-Wechsel |  | 0.3998 | Wartung_FFB |  |  |  |  |  |  |  |  |  | 0123ErE0000000530 | kg | T105 | true | HA_UZV_IPE_STA_0,100_xxx | AllplanAttributes - Querschnittsfläche: 0.001 m2; Charakteristischer Wert der Eigenlast: 0.081
RWA-Wechsel | Wartung_FFB |  | RWA-Wechsel |  | 0.3998 | Wartung_FFB |  |  |  |  |  |  |  |  |  | 0123ErE0000000531 | kg | T105 | true | HA_UZV_IPE_STA_0,100_xxx | AllplanAttributes - Querschnittsfläche: 0.001 m2; Charakteristischer Wert der Eigenlast: 0.081
RWA-Wechsel | Wartung_FFB |  | RWA-Wechsel |  | 0.3998 | Wartung_FFB |  |  |  |  |  |  |  |  |  | 0123ErE0000000532 | kg | T105 | true | HA_UZV_IPE_STA_0,100_xxx | AllplanAttributes - Querschnittsfläche: 0.001 m2; Charakteristischer Wert der Eigenlast: 0.081
RWA-Wechsel | Wartung_FFB |  | RWA-Wechsel |  | 0.3998 | Wartung_FFB |  |  |  |  |  |  |  |  |  | 0123ErE0000000536 | kg | T105 | true | HA_UZV_IPE_STA_0,100_xxx | AllplanAttributes - Querschnittsfläche: 0.001 m2; Charakteristischer Wert der Eigenlast: 0.081
RWA-Wechsel | Wartung_FFB |  | RWA-Wechsel |  | 0.3998 | Wartung_FFB |  |  |  |  |  |  |  |  |  | 0123ErE0000000537 | kg | T105 | true | HA_UZV_IPE_STA_0,100_xxx | AllplanAttributes - Querschnittsfläche: 0.001 m2; Charakteristischer Wert der Eigenlast: 0.081
RWA-Wechsel | Wartung_FFB |  | RWA-Wechsel |  | 0.3998 | Wartung_FFB |  |  |  |  |  |  |  |  |  | 0123ErE0000000538 | kg | T105 | true | HA_UZV_IPE_STA_0,100_xxx | AllplanAttributes - Querschnittsfläche: 0.001 m2; Charakteristischer Wert der Eigenlast: 0.081
RWA-Wechsel | Wartung_FFB |  | RWA-Wechsel |  | 0.3998 | Wartung_FFB |  |  |  |  |  |  |  |  |  | 0123ErE0000000542 | kg | T105 | true | HA_UZV_IPE_STA_0,100_xxx | AllplanAttributes - Querschnittsfläche: 0.001 m2; Charakteristischer Wert der Eigenlast: 0.081
RWA-Wechsel | Wartung_FFB |  | RWA-Wechsel |  | 0.3998 | Wartung_FFB |  |  |  |  |  |  |  |  |  | 0123ErE0000000543 | kg | T105 | true | HA_UZV_IPE_STA_0,100_xxx | AllplanAttributes - Querschnittsfläche: 0.001 m2; Charakteristischer Wert der Eigenlast: 0.081
RWA-Wechsel | Wartung_FFB |  | RWA-Wechsel |  | 0.3998 | Wartung_FFB |  |  |  |  |  |  |  |  |  | 0123ErE0000000544 | kg | T105 | true | HA_UZV_IPE_STA_0,100_xxx | AllplanAttributes - Querschnittsfläche: 0.001 m2; Charakteristischer Wert der Eigenlast: 0.081
RWA-Wechsel | Wartung_FFB |  | RWA-Wechsel |  | 0.3998 | Wartung_FFB |  |  |  |  |  |  |  |  |  | 0123ErE0000000354 | kg | T105 | true | HA_UZV_IPE_STA_0,100_xxx | AllplanAttributes - Querschnittsfläche: 0.001 m2; Charakteristischer Wert der Eigenlast: 0.081
RWA-Wechsel | Wartung_FFB |  | RWA-Wechsel |  | 0.3998 | Wartung_FFB |  |  |  |  |  |  |  |  |  | 0123ErE0000000355 | kg | T105 | true | HA_UZV_IPE_STA_0,100_xxx | AllplanAttributes - Querschnittsfläche: 0.001 m2; Charakteristischer Wert der Eigenlast: 0.081
RWA-Wechsel | Wartung_FFB |  | RWA-Wechsel |  | 0.3998 | Wartung_FFB |  |  |  |  |  |  |  |  |  | 0123ErE0000000356 | kg | T105 | true | HA_UZV_IPE_STA_0,100_xxx | AllplanAttributes - Querschnittsfläche: 0.001 m2; Charakteristischer Wert der Eigenlast: 0.081
RWA-Wechsel | Wartung_FFB |  | RWA-Wechsel |  | 0.3998 | Wartung_FFB |  |  |  |  |  |  |  |  |  | 0123ErE0000000364 | kg | T105 | true | HA_UZV_IPE_STA_0,100_xxx | AllplanAttributes - Querschnittsfläche: 0.001 m2; Charakteristischer Wert der Eigenlast: 0.081
RWA-Wechsel | Wartung_FFB |  | RWA-Wechsel |  | 0.3998 | Wartung_FFB |  |  |  |  |  |  |  |  |  | 0123ErE0000000365 | kg | T105 | true | HA_UZV_IPE_STA_0,100_xxx | AllplanAttributes - Querschnittsfläche: 0.001 m2; Charakteristischer Wert der Eigenlast: 0.081
RWA-Wechsel | Wartung_FFB |  | RWA-Wechsel |  | 0.3998 | Wartung_FFB |  |  |  |  |  |  |  |  |  | 0123ErE0000000366 | kg | T105 | true | HA_UZV_IPE_STA_0,100_xxx | AllplanAttributes - Querschnittsfläche: 0.001 m2; Charakteristischer Wert der Eigenlast: 0.081
RWA-Wechsel | Wartung_FFB |  | RWA-Wechsel |  | 0.3998 | Wartung_FFB |  |  |  |  |  |  |  |  |  | 0123ErE0000000374 | kg | T105 | true | HA_UZV_IPE_STA_0,100_xxx | AllplanAttributes - Querschnittsfläche: 0.001 m2; Charakteristischer Wert der Eigenlast: 0.081
RWA-Wechsel | Wartung_FFB |  | RWA-Wechsel |  | 0.3998 | Wartung_FFB |  |  |  |  |  |  |  |  |  | 0123ErE0000000375 | kg | T105 | true | HA_UZV_IPE_STA_0,100_xxx | AllplanAttributes - Querschnittsfläche: 0.001 m2; Charakteristischer Wert der Eigenlast: 0.081
RWA-Wechsel | Wartung_FFB |  | RWA-Wechsel |  | 0.3998 | Wartung_FFB |  |  |  |  |  |  |  |  |  | 0123ErE0000000376 | kg | T105 | true | HA_UZV_IPE_STA_0,100_xxx | AllplanAttributes - Querschnittsfläche: 0.001 m2; Charakteristischer Wert der Eigenlast: 0.081
RWA-Wechsel | Wartung_FFB |  | RWA-Wechsel |  | 0.3998 | Wartung_FFB |  |  |  |  |  |  |  |  |  | 0123ErE0000000384 | kg | T105 | true | HA_UZV_IPE_STA_0,100_xxx | AllplanAttributes - Querschnittsfläche: 0.001 m2; Charakteristischer Wert der Eigenlast: 0.081
RWA-Wechsel | Wartung_FFB |  | RWA-Wechsel |  | 0.3998 | Wartung_FFB |  |  |  |  |  |  |  |  |  | 0123ErE0000000385 | kg | T105 | true | HA_UZV_IPE_STA_0,100_xxx | AllplanAttributes - Querschnittsfläche: 0.001 m2; Charakteristischer Wert der Eigenlast: 0.081
RWA-Wechsel | Wartung_FFB |  | RWA-Wechsel |  | 0.3998 | Wartung_FFB |  |  |  |  |  |  |  |  |  | 0123ErE0000000386 | kg | T105 | true | HA_UZV_IPE_STA_0,100_xxx | AllplanAttributes - Querschnittsfläche: 0.001 m2; Charakteristischer Wert der Eigenlast: 0.081
RWA-Wechsel | Wartung_FFB |  | RWA-Wechsel |  | 0.3998 | Wartung_FFB |  |  |  |  |  |  |  |  |  | 0123ErE0000000394 | kg | T105 | true | HA_UZV_IPE_STA_0,100_xxx | AllplanAttributes - Querschnittsfläche: 0.001 m2; Charakteristischer Wert der Eigenlast: 0.081
RWA-Wechsel | Wartung_FFB |  | RWA-Wechsel |  | 0.3998 | Wartung_FFB |  |  |  |  |  |  |  |  |  | 0123ErE0000000395 | kg | T105 | true | HA_UZV_IPE_STA_0,100_xxx | AllplanAttributes - Querschnittsfläche: 0.001 m2; Charakteristischer Wert der Eigenlast: 0.081
RWA-Wechsel | Wartung_FFB |  | RWA-Wechsel |  | 0.3998 | Wartung_FFB |  |  |  |  |  |  |  |  |  | 0123ErE0000000396 | kg | T105 | true | HA_UZV_IPE_STA_0,100_xxx | AllplanAttributes - Querschnittsfläche: 0.001 m2; Charakteristischer Wert der Eigenlast: 0.081
RWA-Wechsel | Wartung_FFB |  | RWA-Wechsel |  | 0.3998 | Wartung_FFB |  |  |  |  |  |  |  |  |  | 0123ErE0000000404 | kg | T105 | true | HA_UZV_IPE_STA_0,100_xxx | AllplanAttributes - Querschnittsfläche: 0.001 m2; Charakteristischer Wert der Eigenlast: 0.081
RWA-Wechsel | Wartung_FFB |  | RWA-Wechsel |  | 0.3998 | Wartung_FFB |  |  |  |  |  |  |  |  |  | 0123ErE0000000405 | kg | T105 | true | HA_UZV_IPE_STA_0,100_xxx | AllplanAttributes - Querschnittsfläche: 0.001 m2; Charakteristischer Wert der Eigenlast: 0.081
RWA-Wechsel | Wartung_FFB |  | RWA-Wechsel |  | 0.3998 | Wartung_FFB |  |  |  |  |  |  |  |  |  | 0123ErE0000000406 | kg | T105 | true | HA_UZV_IPE_STA_0,100_xxx | AllplanAttributes - Querschnittsfläche: 0.001 m2; Charakteristischer Wert der Eigenlast: 0.081
RWA-Wechsel | Wartung_FFB |  | RWA-Wechsel |  | 0.3998 | Wartung_FFB |  |  |  |  |  |  |  |  |  | 0123ErE0000000357 | kg | T105 | true | HA_UZV_IPE_STA_0,100_xxx | AllplanAttributes - Querschnittsfläche: 0.001 m2; Charakteristischer Wert der Eigenlast: 0.081
RWA-Wechsel | Wartung_FFB |  | RWA-Wechsel |  | 0.3998 | Wartung_FFB |  |  |  |  |  |  |  |  |  | 0123ErE0000000358 | kg | T105 | true | HA_UZV_IPE_STA_0,100_xxx | AllplanAttributes - Querschnittsfläche: 0.001 m2; Charakteristischer Wert der Eigenlast: 0.081
RWA-Wechsel | Wartung_FFB |  | RWA-Wechsel |  | 0.3998 | Wartung_FFB |  |  |  |  |  |  |  |  |  | 0123ErE0000000359 | kg | T105 | true | HA_UZV_IPE_STA_0,100_xxx | AllplanAttributes - Querschnittsfläche: 0.001 m2; Charakteristischer Wert der Eigenlast: 0.081
RWA-Wechsel | Wartung_FFB |  | RWA-Wechsel |  | 0.3998 | Wartung_FFB |  |  |  |  |  |  |  |  |  | 0123ErE0000000367 | kg | T105 | true | HA_UZV_IPE_STA_0,100_xxx | AllplanAttributes - Querschnittsfläche: 0.001 m2; Charakteristischer Wert der Eigenlast: 0.081
RWA-Wechsel | Wartung_FFB |  | RWA-Wechsel |  | 0.3998 | Wartung_FFB |  |  |  |  |  |  |  |  |  | 0123ErE0000000368 | kg | T105 | true | HA_UZV_IPE_STA_0,100_xxx | AllplanAttributes - Querschnittsfläche: 0.001 m2; Charakteristischer Wert der Eigenlast: 0.081
RWA-Wechsel | Wartung_FFB |  | RWA-Wechsel |  | 0.3998 | Wartung_FFB |  |  |  |  |  |  |  |  |  | 0123ErE0000000369 | kg | T105 | true | HA_UZV_IPE_STA_0,100_xxx | AllplanAttributes - Querschnittsfläche: 0.001 m2; Charakteristischer Wert der Eigenlast: 0.081
RWA-Wechsel | Wartung_FFB |  | RWA-Wechsel |  | 0.3998 | Wartung_FFB |  |  |  |  |  |  |  |  |  | 0123ErE0000000377 | kg | T105 | true | HA_UZV_IPE_STA_0,100_xxx | AllplanAttributes - Querschnittsfläche: 0.001 m2; Charakteristischer Wert der Eigenlast: 0.081
RWA-Wechsel | Wartung_FFB |  | RWA-Wechsel |  | 0.3998 | Wartung_FFB |  |  |  |  |  |  |  |  |  | 0123ErE0000000378 | kg | T105 | true | HA_UZV_IPE_STA_0,100_xxx | AllplanAttributes - Querschnittsfläche: 0.001 m2; Charakteristischer Wert der Eigenlast: 0.081
RWA-Wechsel | Wartung_FFB |  | RWA-Wechsel |  | 0.3998 | Wartung_FFB |  |  |  |  |  |  |  |  |  | 0123ErE0000000379 | kg | T105 | true | HA_UZV_IPE_STA_0,100_xxx | AllplanAttributes - Querschnittsfläche: 0.001 m2; Charakteristischer Wert der Eigenlast: 0.081
RWA-Wechsel | Wartung_FFB |  | RWA-Wechsel |  | 0.3998 | Wartung_FFB |  |  |  |  |  |  |  |  |  | 0123ErE0000000387 | kg | T105 | true | HA_UZV_IPE_STA_0,100_xxx | AllplanAttributes - Querschnittsfläche: 0.001 m2; Charakteristischer Wert der Eigenlast: 0.081
RWA-Wechsel | Wartung_FFB |  | RWA-Wechsel |  | 0.3998 | Wartung_FFB |  |  |  |  |  |  |  |  |  | 0123ErE0000000388 | kg | T105 | true | HA_UZV_IPE_STA_0,100_xxx | AllplanAttributes - Querschnittsfläche: 0.001 m2; Charakteristischer Wert der Eigenlast: 0.081
RWA-Wechsel | Wartung_FFB |  | RWA-Wechsel |  | 0.3998 | Wartung_FFB |  |  |  |  |  |  |  |  |  | 0123ErE0000000389 | kg | T105 | true | HA_UZV_IPE_STA_0,100_xxx | AllplanAttributes - Querschnittsfläche: 0.001 m2; Charakteristischer Wert der Eigenlast: 0.081
RWA-Wechsel | Wartung_FFB |  | RWA-Wechsel |  | 0.3998 | Wartung_FFB |  |  |  |  |  |  |  |  |  | 0123ErE0000000397 | kg | T105 | true | HA_UZV_IPE_STA_0,100_xxx | AllplanAttributes - Querschnittsfläche: 0.001 m2; Charakteristischer Wert der Eigenlast: 0.081
RWA-Wechsel | Wartung_FFB |  | RWA-Wechsel |  | 0.3998 | Wartung_FFB |  |  |  |  |  |  |  |  |  | 0123ErE0000000398 | kg | T105 | true | HA_UZV_IPE_STA_0,100_xxx | AllplanAttributes - Querschnittsfläche: 0.001 m2; Charakteristischer Wert der Eigenlast: 0.081
RWA-Wechsel | Wartung_FFB |  | RWA-Wechsel |  | 0.3998 | Wartung_FFB |  |  |  |  |  |  |  |  |  | 0123ErE0000000399 | kg | T105 | true | HA_UZV_IPE_STA_0,100_xxx | AllplanAttributes - Querschnittsfläche: 0.001 m2; Charakteristischer Wert der Eigenlast: 0.081
RWA-Wechsel | Wartung_FFB |  | RWA-Wechsel |  | 0.3998 | Wartung_FFB |  |  |  |  |  |  |  |  |  | 0123ErE0000000407 | kg | T105 | true | HA_UZV_IPE_STA_0,100_xxx | AllplanAttributes - Querschnittsfläche: 0.001 m2; Charakteristischer Wert der Eigenlast: 0.081
RWA-Wechsel | Wartung_FFB |  | RWA-Wechsel |  | 0.3998 | Wartung_FFB |  |  |  |  |  |  |  |  |  | 0123ErE0000000408 | kg | T105 | true | HA_UZV_IPE_STA_0,100_xxx | AllplanAttributes - Querschnittsfläche: 0.001 m2; Charakteristischer Wert der Eigenlast: 0.081
RWA-Wechsel | Wartung_FFB |  | RWA-Wechsel |  | 0.3998 | Wartung_FFB |  |  |  |  |  |  |  |  |  | 0123ErE0000000409 | kg | T105 | true | HA_UZV_IPE_STA_0,100_xxx | AllplanAttributes - Querschnittsfläche: 0.001 m2; Charakteristischer Wert der Eigenlast: 0.081

# IfcBeam: BEAM (9)
In: EG_Produktion_FFB
Material: S235
AllplanAttributes - 2D Interaktion: yes; Gewerk: Stahlbauarbeiten; Stahlgüte der Querschnittsreihe: S235; Material: S235; Profilname: HEA 200; Mantelfläche/lfm: 1.525; Ebene: EG_Produktion_FFB; Attributset-Objekt: Beam; Abrechnungsart: m³
BeamCommon - Drehwinkel: 0
IFC_Pset_TWP - Material: Stahl; Kommentar: -; Phase erstellt: Neubau; statisch tragend: true; Außenbauteil: true
Pset_BeamCommon - Slope: 0 deg; Reference: HA_UZT_HEA_STA_0,200_xxx
Pset_FM-Vivantes - FM_Klasse: -; FM_Bezeichnung: -; FM_AKS: -; FM_Anzahl: -; FM_Standort: -; FM_Hersteller: -; FM_Hersteller-Typ: -; FM_Seriennummer: -; FM_Baujahr: -; FM_Inbetriebnahme Datum: -; FM_Gewährleistungsende: -; FM_Gewährleistungsgeber: -; FM_Betriebsstatus: -; FM_Prüfpflicht: -; FM_Prüfintervall: -; FM_letzter Prüfungstermin: -; FM_Sammelobjekt: -; FM_rechn. Lebensdauer: -; FM_rechn. Lebensende: -; FM_technischer Zustand: -; FM_voraus. Lebensende: -; FM_Eigentümer: -; FM_Bemerkung: -; FM_Versorgungsbereich-Wirkbereich: -; FM_Zugänglichkeit: -
Name | Bezeichnung = Name | Statische Position - Benutzereingabe = Positionsnummer | Allright_Bauteil_ID
Nebenträger | Nebenträger | AT03 | 0112Unz0000001473
Nebenträger | Nebenträger | AT03 | 0112Unz0000001469 | AllplanAttributes - Codetext: n.a.
Nebenträger | Nebenträger | AT03 | 0112Unz0000001497
Nebenträger | Nebenträger | AT03 | 0112Unz0000001481
Nebenträger | Nebenträger | AT03 | 0112Unz0000001485
Nebenträger | Nebenträger | AT03 | 0112Unz0000001493
Nebenträger | Nebenträger | AT03 | 0112Unz0000001477
Rahmenriegel | Rahmenriegel | AR03 | 0112Unz0000001489
Rahmenriegel | Rahmenriegel | AR04 | 0112Unz0000001465

# IfcBuildingElementProxy
In: TWP_Speiseverteilzentrum SBW VZ II
AllplanAttributes - GFZ - max: 0; Objekttyp_SVZ: IfcSite; Attributset-Objekt: Liegenschaft; Allright_Bauteil_ID: 0003ErE0000000009; Abrechnungsart: m³
IFC_Pset_TWP - Phase erstellt: Neubau; Name: Koordinationskörper; Außenbauteil: false
Pset_BuildingElementProxyCommon - Reference: Koordinationskörper

# IfcColumn (470)
AllplanAttributes - Gewerk: Stahlbauarbeiten
IFC_Pset_TWP - Material: Stahl; Kommentar: -; Phase erstellt: Neubau; statisch tragend: true
Pset_FM-Vivantes - FM_Klasse: -; FM_Bezeichnung: -; FM_AKS: -; FM_Anzahl: -; FM_Standort: -; FM_Hersteller: -; FM_Hersteller-Typ: -; FM_Seriennummer: -; FM_Baujahr: -; FM_Inbetriebnahme Datum: -; FM_Gewährleistungsende: -; FM_Gewährleistungsgeber: -; FM_Betriebsstatus: -; FM_Prüfpflicht: -; FM_Prüfintervall: -; FM_letzter Prüfungstermin: -; FM_Sammelobjekt: -; FM_rechn. Lebensdauer: -; FM_rechn. Lebensende: -; FM_technischer Zustand: -; FM_voraus. Lebensende: -; FM_Eigentümer: -; FM_Bemerkung: -; FM_Versorgungsbereich-Wirkbereich: -; FM_Zugänglichkeit: -
Name | In | Material = AllplanAttributes, Material | Codetext | Kurztext | Faktor | Bezeichnung = Name | Profilname | Mantelfläche/lfm | Ebene | Achsenstartpunkt (X) (m) = Achsenendpunkt (X) (m) | Achsenstartpunkt (Y) (m) = Achsenendpunkt (Y) (m) | Achsenstartpunkt (Z) (m) | Achsenendpunkt (Z) (m) | Objektdrehwinkel | Attributset-Objekt | Schwerpunkt X (m) | Schwerpunkt Y (m) | Allright_Bauteil_ID | Abrechnungsart | Positionsnummer | Außenbauteil | Reference
Rahmenstiel | EG_Technik_FFB | S235 | SB-STUETZE\ | Stahlprofilstütze HEA 300 | 1 | Rahmenstiel | HEA 300 | 1.763 | EG_Technik_FFB | 110 | 92.25 | 1.361 | 6.726 | 270 | Column | 0.12 | 0.12 | 0103Tra0000001004 | m | AQV01.1 | true | HA_STV_HEA_300_STA_0,300_xxx
Rahmenstiel | EG_Technik_FFB | S235 | SB-STUETZE\ | Stahlprofilstütze HEA 300 | 1 | Rahmenstiel | HEA 300 | 1.763 | EG_Technik_FFB | 110 | 87.475 | 1.361 | 6.726 | 270 | Column | 0.12 | 0.12 | 0103Tra0000000376 | m | AQV01.1 | true | HA_STV_HEA_300_STA_0,300_xxx
Rahmenstiel | EG_Technik_FFB | S235 | SB-STUETZE\ | Stahlprofilstütze HEA 300 | 1 | Rahmenstiel | HEA 300 | 1.763 | EG_Technik_FFB | 103.75 | 92.25 | 1.361 | 6.726 | 270 | Column | 0.12 | 0.12 | 0103Tra0000003999 | m | AQV01.1 | true | HA_STV_HEA_300_STA_0,300_xxx
Rahmenstiel | EG_Technik_FFB | S235 | SB-STUETZE\ | Stahlprofilstütze HEA 300 | 1 | Rahmenstiel | HEA 300 | 1.763 | EG_Technik_FFB | 103.75 | 87.475 | 1.361 | 6.726 | 270 | Column | 0.12 | 0.12 | 0103Tra0000004000 | m | AQV01.1 | true | HA_STV_HEA_300_STA_0,300_xxx
Rahmenstiel | EG_Technik_FFB | S235 | SB-STUETZE\ | Stahlprofilstütze HEA 300 | 1 | Rahmenstiel | HEA 300 | 1.763 | EG_Technik_FFB | 97.497 | 92.25 | 1.361 | 6.726 | 270 | Column | 0.12 | 0.12 | 0103Tra0000004063 | m | AQV01.1 | true | HA_STV_HEA_300_STA_0,300_xxx
Rahmenstiel | EG_Technik_FFB | S235 | SB-STUETZE\ | Stahlprofilstütze HEA 300 | 1 | Rahmenstiel | HEA 300 | 1.763 | EG_Technik_FFB | 97.497 | 87.475 | 1.361 | 6.726 | 270 | Column | 0.12 | 0.12 | 0103Tra0000004065 | m | AQV01.1 | true | HA_STV_HEA_300_STA_0,300_xxx
Rahmenstiel | EG_Technik_FFB | S235 | SB-STUETZE\ | Stahlprofilstütze HEA 300 | 1 | Rahmenstiel | HEA 300 | 1.763 | EG_Technik_FFB | 91.247 | 92.25 | 1.361 | 6.726 | 270 | Column | 0.12 | 0.12 | 0103Tra0000004105 | m | AQV01.1 | true | HA_STV_HEA_300_STA_0,300_xxx
Rahmenstiel | EG_Technik_FFB | S235 | SB-STUETZE\ | Stahlprofilstütze HEA 300 | 1 | Rahmenstiel | HEA 300 | 1.763 | EG_Technik_FFB | 91.247 | 87.475 | 1.361 | 6.726 | 270 | Column | 0.12 | 0.12 | 0103Tra0000004107 | m | AQV01.1 | true | HA_STV_HEA_300_STA_0,300_xxx
Rahmenstiel | EG_Technik_FFB | S235 | SB-STUETZE\ | Stahlprofilstütze HEA 300 | 1 | Rahmenstiel | HEA 300 | 1.763 | EG_Technik_FFB | 85.003 | 92.25 | 1.361 | 6.726 | 270 | Column | 0.12 | 0.12 | 0103Tra0000004147 | m | AQV01.1 | true | HA_STV_HEA_300_STA_0,300_xxx
Rahmenstiel | EG_Technik_FFB | S235 | SB-STUETZE\ | Stahlprofilstütze HEA 300 | 1 | Rahmenstiel | HEA 300 | 1.763 | EG_Technik_FFB | 85.003 | 87.475 | 1.361 | 6.726 | 270 | Column | 0.12 | 0.12 | 0103Tra0000004149 | m | AQV01.1 | true | HA_STV_HEA_300_STA_0,300_xxx
Rahmenstiel | EG_Technik_FFB | S235 | SB-STUETZE\ | Stahlprofilstütze HEA 300 | 1 | Rahmenstiel | HEA 300 | 1.763 | EG_Technik_FFB | 78.75 | 92.25 | 1.361 | 6.726 | 270 | Column | 0.12 | 0.12 | 0103Tra0000004189 | m | AQV01.1 | true | HA_STV_HEA_300_STA_0,300_xxx
Rahmenstiel | EG_Technik_FFB | S235 | SB-STUETZE\ | Stahlprofilstütze HEA 300 | 1 | Rahmenstiel | HEA 300 | 1.763 | EG_Technik_FFB | 78.75 | 87.475 | 1.361 | 6.726 | 270 | Column | 0.12 | 0.12 | 0103Tra0000004191 | m | AQV01.1 | true | HA_STV_HEA_300_STA_0,300_xxx
Rahmenstiel | EG_Technik_FFB | S235 | SB-STUETZE\ | Stahlprofilstütze HEA 300 | 1 | Rahmenstiel | HEA 300 | 1.763 | EG_Technik_FFB | 72.5 | 92.25 | 1.361 | 6.726 | 270 | Column | 0.12 | 0.12 | 0103Tra0000004231 | m | AQV01.1 | true | HA_STV_HEA_300_STA_0,300_xxx
Rahmenstiel | EG_Technik_FFB | S235 | SB-STUETZE\ | Stahlprofilstütze HEA 300 | 1 | Rahmenstiel | HEA 300 | 1.763 | EG_Technik_FFB | 72.5 | 87.475 | 1.361 | 6.726 | 270 | Column | 0.12 | 0.12 | 0103Tra0000004233 | m | AQV01.1 | true | HA_STV_HEA_300_STA_0,300_xxx
Rahmenstiel | EG_Technik_FFB | S235 | SB-STUETZE\ | Stahlprofilstütze HEA 300 | 1 | Rahmenstiel | HEA 300 | 1.763 | EG_Technik_FFB | 69.664 | 92.25 | 1.361 | 6.726 | 270 | Column | 0.12 | 0.12 | 0103Tra0000004273 | m | AQV01.2 | true | HA_STV_HEA_300_STA_0,300_xxx
Rahmenstiel | EG_Technik_FFB | S235 | SB-STUETZE\ | Stahlprofilstütze HEA 300 | 1 | Rahmenstiel | HEA 300 | 1.763 | EG_Technik_FFB | 69.664 | 87.475 | 1.361 | 6.726 | 270 | Column | 0.12 | 0.12 | 0103Tra0000004275 | m | AQV01.2 | true | HA_STV_HEA_300_STA_0,300_xxx
Rahmenstiel | EG_Technik_FFB | S235 | SB-STUETZE\ | Stahlprofilstütze HEA 200 | 1 | Rahmenstiel | HEA 200 | 1.167 | EG_Technik_FFB | 69.644 | 89.435 | 7.046 | 11.161 | 180 | Column | 0.12 | 0.12 | 0103Tra0000002154 | m | AQV01.3 | true | HA_STV_HEA_200_STA_0,200_xxx | AllplanAttributes - Schema: C$; Startnummer: 1
Rahmenstiel | EG_Technik_FFB | S235 | SB-STUETZE\ | Stahlprofilstütze HEA 200 | 1 | Rahmenstiel | HEA 200 | 1.167 | EG_Technik_FFB | 69.644 | 87.475 | 7.046 | 11.161 | 180 | Column | 0.12 | 0.12 | 0103Tra0000002130 | m | AQV01.3 | true | HA_STV_HEA_200_STA_0,200_xxx | AllplanAttributes - Schema: C$; Startnummer: 1
Rahmenstiel | EG_Technik_FFB | S235 | SB-STUETZE\ | Stahlprofilstütze HEA 200 | 1 | Rahmenstiel | HEA 200 | 1.167 | EG_Technik_FFB | 69.419 | 89.435 | 1.36 | 1.432 | 180 | Column | 0.12 | 0.12 | 0103Tra0000002159 | m | ATL01 | true | HA_STV_HEA_200_STA_0,200_xxx | AllplanAttributes - Schema: C$; Startnummer: 1
Rahmenstiel | EG_Technik_FFB | S235 | SB-STUETZE\ | Stahlprofilstütze HEA 300 | 1 | Rahmenstiel | HEA 300 | 1.763 | EG_Technik_FFB | 60 | 87.475 | 1.361 | 4.021 | 270 | Column | 0.12 | 0.12 | 0103Tra0000001628 | m | AQV02.1 | true | HA_STV_HEA_300_STA_0,300_xxx | AllplanAttributes - Schema: C$; Startnummer: 1
Rahmenstiel | EG_Technik_FFB | S235 | SB-STUETZE\ | Stahlprofilstütze HEA 300 | 1 | Rahmenstiel | HEA 300 | 1.763 | EG_Technik_FFB | 60 | 91.2 | 1.361 | 4.021 | 270 | Column | 0.12 | 0.12 | 0103Tra0000001630 | m | AQV02.1 | true | HA_STV_HEA_300_STA_0,300_xxx | AllplanAttributes - Schema: C$; Startnummer: 1
Rahmenstiel | EG_Technik_FFB | S235 | SB-STUETZE\ | Stahlprofilstütze HEA 300 | 1 | Rahmenstiel | HEA 300 | 1.763 | EG_Technik_FFB | 60 | 91.2 | 4.341 | 8.081 | 270 | Column | 0.12 | 0.12 | 0103Tra0000001774 | m | AQV02.2 | true | HA_STV_HEA_300_STA_0,300_xxx | AllplanAttributes - Schema: C$; Startnummer: 1
Rahmenstiel | EG_Technik_FFB | S235 | SB-STUETZE\ | Stahlprofilstütze HEA 300 | 1 | Rahmenstiel | HEA 300 | 1.763 | EG_Technik_FFB | 60 | 87.475 | 4.341 | 8.081 | 270 | Column | 0.12 | 0.12 | 0103Tra0000001863 | m | AQV02.2 | true | HA_STV_HEA_300_STA_0,300_xxx | AllplanAttributes - Schema: C$; Startnummer: 1
Rahmenstiel | EG_Technik_FFB | S235 | SB-STUETZE\ | Stahlprofilstütze HEA 300 | 1 | Rahmenstiel | HEA 300 | 1.763 | EG_Technik_FFB | 53.75 | 87.475 | 1.361 | 4.021 | 270 | Column | 0.12 | 0.12 | 0103Tra0000004367 | m | AQV02.1 | true | HA_STV_HEA_300_STA_0,300_xxx | AllplanAttributes - Schema: C$; Startnummer: 1
Rahmenstiel | EG_Technik_FFB | S235 | SB-STUETZE\ | Stahlprofilstütze HEA 300 | 1 | Rahmenstiel | HEA 300 | 1.763 | EG_Technik_FFB | 53.75 | 91.2 | 1.361 | 4.021 | 270 | Column | 0.12 | 0.12 | 0103Tra0000004368 | m | AQV02.1 | true | HA_STV_HEA_300_STA_0,300_xxx | AllplanAttributes - Schema: C$; Startnummer: 1
Rahmenstiel | EG_Technik_FFB | S235 | SB-STUETZE\ | Stahlprofilstütze HEA 300 | 1 | Rahmenstiel | HEA 300 | 1.763 | EG_Technik_FFB | 53.75 | 91.2 | 4.341 | 8.081 | 270 | Column | 0.12 | 0.12 | 0103Tra0000004382 | m | AQV02.2 | true | HA_STV_HEA_300_STA_0,300_xxx | AllplanAttributes - Schema: C$; Startnummer: 1
Rahmenstiel | EG_Technik_FFB | S235 | SB-STUETZE\ | Stahlprofilstütze HEA 300 | 1 | Rahmenstiel | HEA 300 | 1.763 | EG_Technik_FFB | 53.75 | 87.475 | 4.341 | 8.081 | 270 | Column | 0.12 | 0.12 | 0103Tra0000004383 | m | AQV02.2 | true | HA_STV_HEA_300_STA_0,300_xxx | AllplanAttributes - Schema: C$; Startnummer: 1
Rahmenstiel | EG_Technik_FFB | S235 | SB-STUETZE\ | Stahlprofilstütze HEA 300 | 1 | Rahmenstiel | HEA 300 | 1.763 | EG_Technik_FFB | 47.5 | 87.475 | 1.361 | 4.021 | 270 | Column | 0.12 | 0.12 | 0103Tra0000004453 | m | AQV02.1 | true | HA_STV_HEA_300_STA_0,300_xxx | AllplanAttributes - Schema: C$; Startnummer: 1
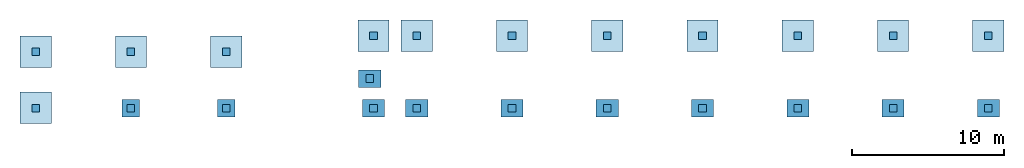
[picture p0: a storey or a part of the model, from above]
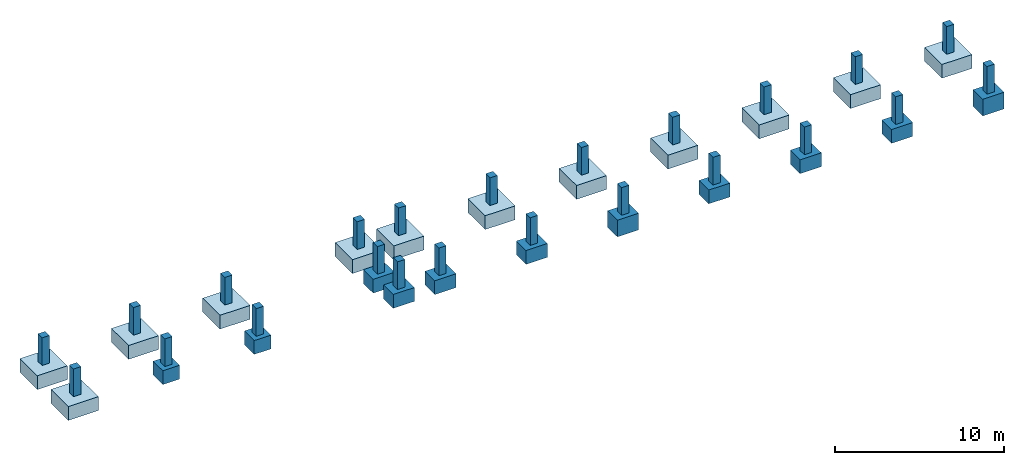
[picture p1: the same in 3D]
Properties of the parts of a building model (IFC2X3), part 10 of 25

# IfcColumn (470)
Name | In | Material = AllplanAttributes, Material | Codetext | Kurztext | Faktor | Bezeichnung = Name | Profilname | Mantelfläche/lfm | Ebene | Achsenstartpunkt (X) (m) = Achsenendpunkt (X) (m) | Achsenstartpunkt (Y) (m) = Achsenendpunkt (Y) (m) | Achsenstartpunkt (Z) (m) | Achsenendpunkt (Z) (m) | Objektdrehwinkel | Attributset-Objekt | Schwerpunkt X (m) | Schwerpunkt Y (m) | Allright_Bauteil_ID | Abrechnungsart | Positionsnummer | Außenbauteil | Reference
Rahmenstiel | EG_Technik_FFB | S235 | SB-STUETZE\ | Stahlprofilstütze HEA 300 | 1 | Rahmenstiel | HEA 300 | 1.763 | EG_Technik_FFB | 47.5 | 91.2 | 1.361 | 4.021 | 270 | Column | 0.12 | 0.12 | 0103Tra0000004455 | m | AQV02.1 | true | HA_STV_HEA_300_STA_0,300_xxx | AllplanAttributes - Schema: C$; Startnummer: 1
Rahmenstiel | EG_Technik_FFB | S235 | SB-STUETZE\ | Stahlprofilstütze HEA 300 | 1 | Rahmenstiel | HEA 300 | 1.763 | EG_Technik_FFB | 47.5 | 91.2 | 4.341 | 8.081 | 270 | Column | 0.12 | 0.12 | 0103Tra0000004457 | m | AQV02.2 | true | HA_STV_HEA_300_STA_0,300_xxx | AllplanAttributes - Schema: C$; Startnummer: 1
Rahmenstiel | EG_Technik_FFB | S235 | SB-STUETZE\ | Stahlprofilstütze HEA 300 | 1 | Rahmenstiel | HEA 300 | 1.763 | EG_Technik_FFB | 47.5 | 87.475 | 4.341 | 8.081 | 270 | Column | 0.12 | 0.12 | 0103Tra0000004459 | m | AQV02.2 | true | HA_STV_HEA_300_STA_0,300_xxx | AllplanAttributes - Schema: C$; Startnummer: 1
Stahlstütze | EG_Technik_FFB | Stahl |  | Stahlprofilstütze |  | Stahlstütze | HEA 140 |  | EG_Technik_FFB |  |  |  |  |  |  |  |  | 0106St 0000000631 | m | - | false | HI_STT_HEA_140_STA_0,140_xxx | AllplanAttributes - 2D Interaktion: yes; Dateiname: C:\ProgramData\Nemetschek\Allplan\2025\Etc\Library\Engineering\Steel sections\2D profiles angular idealiz\HEA\HEA 140.sym; Folgenname: HEA 140; Position: -; IFC_Pset_TWP - Herstellung: -
Stahlstütze | EG_Technik_FFB | Stahl |  | Stahlprofilstütze |  | Stahlstütze | HEA 140 |  | EG_Technik_FFB |  |  |  |  |  |  |  |  | 0106St 0000000646 | m | - | false | HI_STT_HEA_140_STA_0,140_xxx | AllplanAttributes - 2D Interaktion: yes; Dateiname: C:\ProgramData\Nemetschek\Allplan\2025\Etc\Library\Engineering\Steel sections\2D profiles angular idealiz\HEA\HEA 140.sym; Folgenname: HEA 140; Position: -; IFC_Pset_TWP - Herstellung: -
Stahlstütze | EG_Produktion_FFB | S235 |  | Stahlprofilstütze |  | Stahlstütze | HEA 200 |  | EG_Produktion_FFB |  |  |  |  |  |  |  |  | 0112St 0000000066 | m | S000 | false | HI_STT_HEA_STA_0,200_xxx | AllplanAttributes - 2D Interaktion: yes; Position: S000; IFC_Pset_TWP - Herstellung: -
Stahlstütze | EG_Produktion_FFB | S235 |  | Stahlprofilstütze |  | Stahlstütze | HEA 260 |  | EG_Produktion_FFB |  |  |  |  |  |  |  |  | 0112St 0000000036 | m | S005 | false | HI_STT_HEA_STA_0,260_xxx | AllplanAttributes - 2D Interaktion: yes; Position: S005; IFC_Pset_TWP - Herstellung: -
Stahlstütze | EG_Produktion_FFB | S235 |  | Stahlprofilstütze |  | Stahlstütze | HEA 220 |  | EG_Produktion_FFB |  |  |  |  |  |  |  |  | 0112St 0000000037 | m | S001 | false | HI_STT_HEA_STA_0,220_xxx | AllplanAttributes - 2D Interaktion: yes; Position: S001; IFC_Pset_TWP - Herstellung: -
Stahlstütze | EG_Produktion_FFB | S235 |  | Stahlprofilstütze |  | Stahlstütze | HEA 200 |  | EG_Produktion_FFB |  |  |  |  |  |  |  |  | 0112St 0000000095 | m | S000 | false | HI_STT_HEA_STA_0,200_xxx | AllplanAttributes - 2D Interaktion: yes; Position: S000; IFC_Pset_TWP - Herstellung: -
Stahlstütze | EG_Produktion_FFB | S235 |  | Stahlprofilstütze |  | Stahlstütze | HEA 200 |  | EG_Produktion_FFB |  |  |  |  |  |  |  |  | 0112St 0000000096 | m | S000 | false | HI_STT_HEA_STA_0,200_xxx | AllplanAttributes - 2D Interaktion: yes; Position: S000; IFC_Pset_TWP - Herstellung: -
Stahlstütze | EG_Produktion_FFB | S235 |  | Stahlprofilstütze |  | Stahlstütze | HEA 200 |  | EG_Produktion_FFB |  |  |  |  |  |  |  |  | 0112St 0000002067 | m | S000 | false | HI_STT_HEA_STA_0,200_xxx | AllplanAttributes - 2D Interaktion: yes; Position: S000; IFC_Pset_TWP - Herstellung: -
Stahlstütze | EG_Produktion_FFB | S235 |  | Stahlprofilstütze |  | Stahlstütze | HEA 200 |  | EG_Produktion_FFB |  |  |  |  |  |  |  |  | 0112St 0000000159 | m | S000 | false | HI_STT_HEA_STA_0,200_xxx | AllplanAttributes - 2D Interaktion: yes; Position: S000; IFC_Pset_TWP - Herstellung: -
Stahlstütze | EG_Produktion_FFB | S235 |  | Stahlprofilstütze |  | Stahlstütze | HEA 220 |  | EG_Produktion_FFB |  |  |  |  |  |  |  |  | 0112St 0000002126 | m | S001 | false | HI_STT_HEA_STA_0,220_xxx | AllplanAttributes - 2D Interaktion: yes; Position: S001; IFC_Pset_TWP - Herstellung: -
Stahlstütze | EG_Produktion_FFB | S235 |  | Stahlprofilstütze |  | Stahlstütze | HEA 220 |  | EG_Produktion_FFB |  |  |  |  |  |  |  |  | 0112St 0000002129 | m | S001 | false | HI_STT_HEA_STA_0,220_xxx | AllplanAttributes - 2D Interaktion: yes; Position: S001; IFC_Pset_TWP - Herstellung: -
Stahlstütze | EG_Produktion_FFB | S235 |  | Stahlprofilstütze |  | Stahlstütze | HEA 240 |  | EG_Produktion_FFB |  |  |  |  |  |  |  |  | 0112St 0000002132 | m | S003 | false | HI_STT_HEA_STA_0,240_xxx | AllplanAttributes - 2D Interaktion: yes; Position: S003; IFC_Pset_TWP - Herstellung: -
Stahlstütze | EG_Produktion_FFB | S235 |  | Stahlprofilstütze |  | Stahlstütze | HEA 200 |  | EG_Produktion_FFB |  |  |  |  |  |  |  |  | 0112St 0000002143 | m | S000 | false | HI_STT_HEA_STA_0,200_xxx | AllplanAttributes - 2D Interaktion: yes; Position: S000; IFC_Pset_TWP - Herstellung: -
Stahlstütze | EG_Produktion_FFB | S235 |  | Stahlprofilstütze |  | Stahlstütze | HEA 200 |  | EG_Produktion_FFB |  |  |  |  |  |  |  |  | 0112St 0000000169 | m | S000 | false | HI_STT_HEA_STA_0,200_xxx | AllplanAttributes - 2D Interaktion: yes; Position: S000; IFC_Pset_TWP - Herstellung: -
Stahlstütze | EG_Produktion_FFB | S235 |  | Stahlprofilstütze |  | Stahlstütze | HEA 240 |  | EG_Produktion_FFB |  |  |  |  |  |  |  |  | 0112St 0000000168 | m | S003 | false | HI_STT_HEA_STA_0,240_xxx | AllplanAttributes - 2D Interaktion: yes; Position: S003; IFC_Pset_TWP - Herstellung: -
Stahlstütze | EG_Produktion_FFB | S235 |  | Stahlprofilstütze |  | Stahlstütze | HEA 200 |  | EG_Produktion_FFB |  |  |  |  |  |  |  |  | 0112St 0000002147 | m | S000 | false | HI_STT_HEA_STA_0,200_xxx | AllplanAttributes - 2D Interaktion: yes; Position: S000; IFC_Pset_TWP - Herstellung: -
Stahlstütze | EG_Produktion_FFB | S235 |  | Stahlprofilstütze |  | Stahlstütze | HEA 200 |  | EG_Produktion_FFB |  |  |  |  |  |  |  |  | 0112St 0000000160 | m | S000 | false | HI_STT_HEA_STA_0,200_xxx | AllplanAttributes - 2D Interaktion: yes; Position: S000; IFC_Pset_TWP - Herstellung: -
Stahlstütze | EG_Produktion_FFB | S235 |  | Stahlprofilstütze |  | Stahlstütze | HEA 200 |  | EG_Produktion_FFB |  |  |  |  |  |  |  |  | 0112St 0000002064 | m | S000 | false | HI_STT_HEA_STA_0,200_xxx | AllplanAttributes - 2D Interaktion: yes; Position: S000; IFC_Pset_TWP - Herstellung: -
Stahlstütze | EG_Produktion_FFB | S235 |  | Stahlprofilstütze |  | Stahlstütze | HEA 200 |  | EG_Produktion_FFB |  |  |  |  |  |  |  |  | 0112St 0000000193 | m | S000 | false | HI_STT_HEA_STA_0,200_xxx | AllplanAttributes - 2D Interaktion: yes; Position: S000; IFC_Pset_TWP - Herstellung: -
Stahlstütze | EG_Produktion_FFB | S235 |  | Stahlprofilstütze |  | Stahlstütze | HEA 220 |  | EG_Produktion_FFB |  |  |  |  |  |  |  |  | 0112St 0000002164 | m | S001 | false | HI_STT_HEA_STA_0,220_xxx | AllplanAttributes - 2D Interaktion: yes; Position: S001; IFC_Pset_TWP - Herstellung: -
Stahlstütze | EG_Produktion_FFB | S235 |  | Stahlprofilstütze |  | Stahlstütze | HEA 220 |  | EG_Produktion_FFB |  |  |  |  |  |  |  |  | 0112St 0000002163 | m | S001 | false | HI_STT_HEA_STA_0,220_xxx | AllplanAttributes - 2D Interaktion: yes; Position: S001; IFC_Pset_TWP - Herstellung: -
Stahlstütze | EG_Produktion_FFB | S235 |  | Stahlprofilstütze |  | Stahlstütze | HEA 200 |  | EG_Produktion_FFB |  |  |  |  |  |  |  |  | 0112St 0000000192 | m | S000 | false | HI_STT_HEA_STA_0,200_xxx | AllplanAttributes - 2D Interaktion: yes; Position: S000; IFC_Pset_TWP - Herstellung: -
Stahlstütze | EG_Produktion_FFB | S235 |  | Stahlprofilstütze |  | Stahlstütze | HEA 200 |  | EG_Produktion_FFB |  |  |  |  |  |  |  |  | 0112St 0000000191 | m | S000 | false | HI_STT_HEA_STA_0,200_xxx | AllplanAttributes - 2D Interaktion: yes; Position: S000; IFC_Pset_TWP - Herstellung: -
Stahlstütze | EG_Produktion_FFB | S235 |  | Stahlprofilstütze |  | Stahlstütze | HEA 200 |  | EG_Produktion_FFB |  |  |  |  |  |  |  |  | 0112St 0000000161 | m | S000 | false | HI_STT_HEA_STA_0,200_xxx | AllplanAttributes - 2D Interaktion: yes; Position: S000; IFC_Pset_TWP - Herstellung: -
Stahlstütze | EG_Produktion_FFB | S235 |  | Stahlprofilstütze |  | Stahlstütze | HEA 200 |  | EG_Produktion_FFB |  |  |  |  |  |  |  |  | 0112St 0000000162 | m | S000 | false | HI_STT_HEA_STA_0,200_xxx | AllplanAttributes - 2D Interaktion: yes; Position: S000; IFC_Pset_TWP - Herstellung: -
Stahlstütze | EG_Produktion_FFB | S235 |  | Stahlprofilstütze |  | Stahlstütze | HEA 320 |  | EG_Produktion_FFB |  |  |  |  |  |  |  |  | 0112St 0000000144 | m | S002 | false | HI_STT_HEA_STA_0,320_xxx | AllplanAttributes - 2D Interaktion: yes; Position: S002; IFC_Pset_TWP - Herstellung: -
Stahlstütze | EG_Produktion_FFB | S235 |  | Stahlprofilstütze |  | Stahlstütze | HEA 320 |  | EG_Produktion_FFB |  |  |  |  |  |  |  |  | 0112St 0000002172 | m | S002 | false | HI_STT_HEA_STA_0,320_xxx | AllplanAttributes - 2D Interaktion: yes; Position: S002; IFC_Pset_TWP - Herstellung: -
Stahlstütze | EG_Produktion_FFB | S235 |  | Stahlprofilstütze |  | Stahlstütze | HEA 200 |  | EG_Produktion_FFB |  |  |  |  |  |  |  |  | 0112St 0000002146 | m | S000 | false | HI_STT_HEA_STA_0,200_xxx | AllplanAttributes - 2D Interaktion: yes; Position: S000; IFC_Pset_TWP - Herstellung: -
Stahlstütze | EG_Produktion_FFB | S235 |  | Stahlprofilstütze |  | Stahlstütze | HEA 320 |  | EG_Produktion_FFB |  |  |  |  |  |  |  |  | 0112St 0000000065 | m | S002 | false | HI_STT_HEA_STA_0,320_xxx | AllplanAttributes - 2D Interaktion: yes; Position: S002; IFC_Pset_TWP - Herstellung: -
Stahlstütze | EG_Produktion_FFB | S235 |  | Stahlprofilstütze |  | Stahlstütze | HEA 320 |  | EG_Produktion_FFB |  |  |  |  |  |  |  |  | 0112St 0000000052 | m | S002 | false | HI_STT_HEA_STA_0,320_xxx | AllplanAttributes - 2D Interaktion: yes; Position: S002; IFC_Pset_TWP - Herstellung: -
Stahlstütze | EG_Produktion_FFB | S235 |  | Stahlprofilstütze |  | Stahlstütze | HEA 320 |  | EG_Produktion_FFB |  |  |  |  |  |  |  |  | 0112St 0000000180 | m | S002 | false | HI_STT_HEA_STA_0,320_xxx | AllplanAttributes - 2D Interaktion: yes; Position: S002; IFC_Pset_TWP - Herstellung: -
Stahlstütze | EG_Produktion_FFB | S235 |  | Stahlprofilstütze |  | Stahlstütze | HEA 220 |  | EG_Produktion_FFB |  |  |  |  |  |  |  |  | 0112St 0000000227 | m | S001 | false | HI_STT_HEA_STA_0,220_xxx | AllplanAttributes - 2D Interaktion: yes; Position: S001; IFC_Pset_TWP - Herstellung: -
Stahlstütze | EG_Produktion_FFB | S235 |  | Stahlprofilstütze |  | Stahlstütze | HEA 220 |  | EG_Produktion_FFB |  |  |  |  |  |  |  |  | 0112St 0000002152 | m | S001 | false | HI_STT_HEA_STA_0,220_xxx | AllplanAttributes - 2D Interaktion: yes; Position: S001; IFC_Pset_TWP - Herstellung: -
Stahlstütze | EG_Produktion_FFB | S235 |  | Stahlprofilstütze |  | Stahlstütze | HEA 240 |  | EG_Produktion_FFB |  |  |  |  |  |  |  |  | 0112St 0000002155 | m | S003 | false | HI_STT_HEA_STA_0,240_xxx | AllplanAttributes - 2D Interaktion: yes; Position: S003; IFC_Pset_TWP - Herstellung: -
Stahlstütze | EG_Produktion_FFB | S235 |  | Stahlprofilstütze |  | Stahlstütze | HEA 200 |  | EG_Produktion_FFB |  |  |  |  |  |  |  |  | 0112St 0000002158 | m | S000 | false | HI_STT_HEA_STA_0,200_xxx | AllplanAttributes - 2D Interaktion: yes; Position: S000; IFC_Pset_TWP - Herstellung: -
Stahlstütze | EG_Produktion_FFB | S235 |  | Stahlprofilstütze |  | Stahlstütze | HEA 320 |  | EG_Produktion_FFB |  |  |  |  |  |  |  |  | 0112St 0000002093 | m | S002 | false | HI_STT_HEA_STA_0,320_xxx | AllplanAttributes - 2D Interaktion: yes; Position: S002; IFC_Pset_TWP - Herstellung: -
Stahlstütze | EG_Produktion_FFB | S235 |  | Stahlprofilstütze |  | Stahlstütze | HEA 320 |  | EG_Produktion_FFB |  |  |  |  |  |  |  |  | 0112St 0000002173 | m | S002 | false | HI_STT_HEA_STA_0,320_xxx | AllplanAttributes - 2D Interaktion: yes; Position: S002; IFC_Pset_TWP - Herstellung: -
Stahlstütze | EG_Produktion_FFB | S235 |  | Stahlprofilstütze |  | Stahlstütze | HEA 220 |  | EG_Produktion_FFB |  |  |  |  |  |  |  |  | 0112St 0000000157 | m | S001 | false | HI_STT_HEA_STA_0,220_xxx | AllplanAttributes - 2D Interaktion: yes; Position: S001; IFC_Pset_TWP - Herstellung: -
Stahlstütze | EG_Produktion_FFB | S235 |  | Stahlprofilstütze |  | Stahlstütze | HEA 220 |  | EG_Produktion_FFB |  |  |  |  |  |  |  |  | 0112St 0000000158 | m | S001 | false | HI_STT_HEA_STA_0,220_xxx | AllplanAttributes - 2D Interaktion: yes; Position: S001; IFC_Pset_TWP - Herstellung: -
Stahlstütze | EG_Produktion_FFB | S235 |  | Stahlprofilstütze |  | Stahlstütze | HEA 280 |  | EG_Produktion_FFB |  |  |  |  |  |  |  |  | 0112St 0000002010 | m | S007 | false | HI_STT_HEA_STA_0,280_xxx | AllplanAttributes - 2D Interaktion: yes; Dateiname: C:\ProgramData\Nemetschek\Allplan\2025\Etc\Library\Engineering\Steel sections\2D profiles angular idealiz\HEA\HEA 280.sym; Folgenname: HEA 280; Position: S007; IFC_Pset_TWP - Herstellung: -
Stahlstütze | EG_Produktion_FFB | S235 |  | Stahlprofilstütze |  | Stahlstütze | HEA 200 |  | EG_Produktion_FFB |  |  |  |  |  |  |  |  | 0112St 0000000194 | m | S000 | false | HI_STT_HEA_STA_0,200_xxx | AllplanAttributes - 2D Interaktion: yes; Position: S000; IFC_Pset_TWP - Herstellung: -
Stahlstütze | EG_Produktion_FFB | S235 |  | Stahlprofilstütze |  | Stahlstütze | HEA 240 |  | EG_Produktion_FFB |  |  |  |  |  |  |  |  | 0112St 0000000196 | m | S003 | false | HI_STT_HEA_STA_0,240_xxx | AllplanAttributes - 2D Interaktion: yes; Position: S003; IFC_Pset_TWP - Herstellung: -
Stahlstütze | EG_Produktion_FFB | S235 |  | Stahlprofilstütze |  | Stahlstütze | HEA 320 |  | EG_Produktion_FFB |  |  |  |  |  |  |  |  | 0112St 0000000183 | m | S002 | false | HI_STT_HEA_STA_0,320_xxx | AllplanAttributes - 2D Interaktion: yes; Position: S002; IFC_Pset_TWP - Herstellung: -
Stahlstütze | EG_Produktion_FFB | S235 |  | Stahlprofilstütze |  | Stahlstütze | HEA 320 |  | EG_Produktion_FFB |  |  |  |  |  |  |  |  | 0112St 0000000184 | m | S002 | false | HI_STT_HEA_STA_0,320_xxx | AllplanAttributes - 2D Interaktion: yes; Position: S002; IFC_Pset_TWP - Herstellung: -
Stahlstütze | EG_Produktion_FFB | S235 |  | Stahlprofilstütze |  | Stahlstütze | HEA 320 |  | EG_Produktion_FFB |  |  |  |  |  |  |  |  | 0112St 0000000186 | m | S002 | false | HI_STT_HEA_STA_0,320_xxx | AllplanAttributes - 2D Interaktion: yes; Position: S002; IFC_Pset_TWP - Herstellung: -
Stahlstütze | EG_Produktion_FFB | S235 |  | Stahlprofilstütze |  | Stahlstütze | HEA 320 |  | EG_Produktion_FFB |  |  |  |  |  |  |  |  | 0112St 0000000187 | m | S002 | false | HI_STT_HEA_STA_0,320_xxx | AllplanAttributes - 2D Interaktion: yes; Position: S002; IFC_Pset_TWP - Herstellung: -
Stahlstütze | EG_Produktion_FFB | S235 |  | Stahlprofilstütze |  | Stahlstütze | HEA 320 |  | EG_Produktion_FFB |  |  |  |  |  |  |  |  | 0112St 0000000235 | m | S002 | false | HI_STT_HEA_STA_0,320_xxx | AllplanAttributes - 2D Interaktion: yes; Position: S002; IFC_Pset_TWP - Herstellung: -
Stahlstütze | EG_Produktion_FFB | S235 |  | Stahlprofilstütze |  | Stahlstütze | HEA 320 |  | EG_Produktion_FFB |  |  |  |  |  |  |  |  | 0112St 0000000236 | m | S002 | false | HI_STT_HEA_STA_0,320_xxx | AllplanAttributes - 2D Interaktion: yes; Position: S002; IFC_Pset_TWP - Herstellung: -
Stahlstütze | EG_Produktion_FFB | S235 |  | Stahlprofilstütze |  | Stahlstütze | HEA 320 |  | EG_Produktion_FFB |  |  |  |  |  |  |  |  | 0112St 0000000185 | m | S002 | false | HI_STT_HEA_STA_0,320_xxx | AllplanAttributes - 2D Interaktion: yes; Position: S002; IFC_Pset_TWP - Herstellung: -
Stahlstütze | EG_Produktion_FFB | S235 |  | Stahlprofilstütze |  | Stahlstütze | HEA 320 |  | EG_Produktion_FFB |  |  |  |  |  |  |  |  | 0112St 0000002169 | m | S002 | false | HI_STT_HEA_STA_0,320_xxx | AllplanAttributes - 2D Interaktion: yes; Position: S002; IFC_Pset_TWP - Herstellung: -
Stahlstütze | EG_Produktion_FFB | S235 |  | Stahlprofilstütze |  | Stahlstütze | HEA 220 |  | EG_Produktion_FFB |  |  |  |  |  |  |  |  | 0112St 0000000009 | m | S001 | false | HI_STT_HEA_STA_0,220_xxx | AllplanAttributes - 2D Interaktion: yes; Position: S001; IFC_Pset_TWP - Herstellung: -
Stahlstütze | EG_Produktion_FFB | S235 |  | Stahlprofilstütze |  | Stahlstütze | HEA 220 |  | EG_Produktion_FFB |  |  |  |  |  |  |  |  | 0112St 0000000002 | m | S001 | false | HI_STT_HEA_STA_0,220_xxx | AllplanAttributes - 2D Interaktion: yes; Position: S001; IFC_Pset_TWP - Herstellung: -
Stahlstütze | EG_Produktion_FFB | S235 |  | Stahlprofilstütze |  | Stahlstütze | HEA 200 |  | EG_Produktion_FFB |  |  |  |  |  |  |  |  | 0112St 0000001998 | m | S000 | false | HI_STT_HEA_STA_0,200_xxx | AllplanAttributes - 2D Interaktion: yes; Position: S000; IFC_Pset_TWP - Herstellung: -
Stahlstütze | EG_Produktion_FFB | S235 |  | Stahlprofilstütze |  | Stahlstütze | HEA 220 |  | EG_Produktion_FFB |  |  |  |  |  |  |  |  | 0112St 0000002002 | m | S001 | false | HI_STT_HEA_STA_0,220_xxx | AllplanAttributes - 2D Interaktion: yes; Position: S001; IFC_Pset_TWP - Herstellung: -
Stahlstütze | EG_Produktion_FFB | S235 |  | Stahlprofilstütze |  | Stahlstütze | HEA 220 |  | EG_Produktion_FFB |  |  |  |  |  |  |  |  | 0112St 0000000010 | m | S001 | false | HI_STT_HEA_STA_0,220_xxx | AllplanAttributes - 2D Interaktion: yes; Position: S001; IFC_Pset_TWP - Herstellung: -
Stahlstütze | EG_Produktion_FFB | S235 |  | Stahlprofilstütze |  | Stahlstütze | HEA 220 |  | EG_Produktion_FFB |  |  |  |  |  |  |  |  | 0112St 0000000023 | m | S001 | false | HI_STT_HEA_STA_0,220_xxx | AllplanAttributes - 2D Interaktion: yes; Position: S001; IFC_Pset_TWP - Herstellung: -
Stahlstütze | EG_Produktion_FFB | S235 |  | Stahlprofilstütze |  | Stahlstütze | HEA 220 |  | EG_Produktion_FFB |  |  |  |  |  |  |  |  | 0112St 0000000024 | m | S001 | false | HI_STT_HEA_STA_0,220_xxx | AllplanAttributes - 2D Interaktion: yes; Position: S001; IFC_Pset_TWP - Herstellung: -
Stahlstütze | EG_Produktion_FFB | S235 |  | Stahlprofilstütze |  | Stahlstütze | HEA 220 |  | EG_Produktion_FFB |  |  |  |  |  |  |  |  | 0112St 0000000025 | m | S001 | false | HI_STT_HEA_STA_0,220_xxx | AllplanAttributes - 2D Interaktion: yes; Position: S001; IFC_Pset_TWP - Herstellung: -
Stahlstütze | EG_Produktion_FFB | S235 |  | Stahlprofilstütze |  | Stahlstütze | HEA 240 |  | EG_Produktion_FFB |  |  |  |  |  |  |  |  | 0112St 0000000051 | m | S003 | false | HI_STT_HEA_STA_0,240_xxx | AllplanAttributes - 2D Interaktion: yes; Position: S003; IFC_Pset_TWP - Herstellung: -
Stahlstütze | EG_Produktion_FFB | S235 |  | Stahlprofilstütze |  | Stahlstütze | HEA 220 |  | EG_Produktion_FFB |  |  |  |  |  |  |  |  | 0112St 0000000028 | m | S001 | false | HI_STT_HEA_STA_0,220_xxx | AllplanAttributes - 2D Interaktion: yes; Position: S001; IFC_Pset_TWP - Herstellung: -
Stahlstütze | EG_Produktion_FFB | S235 |  | Stahlprofilstütze |  | Stahlstütze | HEA 220 |  | EG_Produktion_FFB |  |  |  |  |  |  |  |  | 0112St 0000000029 | m | S001 | false | HI_STT_HEA_STA_0,220_xxx | AllplanAttributes - 2D Interaktion: yes; Position: S001; IFC_Pset_TWP - Herstellung: -
Stahlstütze | EG_Produktion_FFB | S235 |  | Stahlprofilstütze |  | Stahlstütze | HEA 220 |  | EG_Produktion_FFB |  |  |  |  |  |  |  |  | 0112St 0000002003 | m | S001 | false | HI_STT_HEA_STA_0,220_xxx | AllplanAttributes - 2D Interaktion: yes; Position: S001; IFC_Pset_TWP - Herstellung: -
Stahlstütze | EG_Produktion_FFB | S235 |  | Stahlprofilstütze |  | Stahlstütze | HEA 220 |  | EG_Produktion_FFB |  |  |  |  |  |  |  |  | 0112St 0000000027 | m | S001 | false | HI_STT_HEA_STA_0,220_xxx | AllplanAttributes - 2D Interaktion: yes; Position: S001; IFC_Pset_TWP - Herstellung: -
Stahlstütze | EG_Produktion_FFB | S235 |  | Stahlprofilstütze |  | Stahlstütze | HEA 200 |  | EG_Produktion_FFB |  |  |  |  |  |  |  |  | 0112St 0000002006 | m | S000 | false | HI_STT_HEA_STA_0,200_xxx | AllplanAttributes - 2D Interaktion: yes; Position: S000; IFC_Pset_TWP - Herstellung: -
Stahlstütze | EG_Produktion_FFB | S235 |  | Stahlprofilstütze |  | Stahlstütze | HEA 200 |  | EG_Produktion_FFB |  |  |  |  |  |  |  |  | 0112St 0000002053 | m | S000 | false | HI_STT_HEA_STA_0,200_xxx | AllplanAttributes - 2D Interaktion: yes; Position: S000; IFC_Pset_TWP - Herstellung: -
Stahlstütze | EG_Produktion_FFB | S235 |  | Stahlprofilstütze |  | Stahlstütze | HEA 220 |  | EG_Produktion_FFB |  |  |  |  |  |  |  |  | 0112St 0000002048 | m | S001 | false | HI_STT_HEA_STA_0,220_xxx | AllplanAttributes - 2D Interaktion: yes; Position: S001; IFC_Pset_TWP - Herstellung: -
Stahlstütze | EG_Produktion_FFB | S235 |  | Stahlprofilstütze |  | Stahlstütze | HEA 220 |  | EG_Produktion_FFB |  |  |  |  |  |  |  |  | 0112St 0000002047 | m | S001 | false | HI_STT_HEA_STA_0,220_xxx | AllplanAttributes - 2D Interaktion: yes; Position: S001; IFC_Pset_TWP - Herstellung: -
Stahlstütze | EG_Produktion_FFB | S235 |  | Stahlprofilstütze |  | Stahlstütze | HEA 240 |  | EG_Produktion_FFB |  |  |  |  |  |  |  |  | 0112St 0000002044 | m | S003 | false | HI_STT_HEA_STA_0,240_xxx | AllplanAttributes - 2D Interaktion: yes; Position: S003; IFC_Pset_TWP - Herstellung: -
Stahlstütze | EG_Produktion_FFB | S235 |  | Stahlprofilstütze |  | Stahlstütze | HEA 240 |  | EG_Produktion_FFB |  |  |  |  |  |  |  |  | 0112St 0000002041 | m | S003 | false | HI_STT_HEA_STA_0,240_xxx | AllplanAttributes - 2D Interaktion: yes; Position: S003; IFC_Pset_TWP - Herstellung: -
Stahlstütze | EG_Produktion_FFB | S235 |  | Stahlprofilstütze |  | Stahlstütze | HEA 220 |  | EG_Produktion_FFB |  |  |  |  |  |  |  |  | 0112St 0000002038 | m | S001 | false | HI_STT_HEA_STA_0,220_xxx | AllplanAttributes - 2D Interaktion: yes; Position: S001; IFC_Pset_TWP - Herstellung: -
Stahlstütze | EG_Produktion_FFB | S235 |  | Stahlprofilstütze |  | Stahlstütze | HEA 200 |  | EG_Produktion_FFB |  |  |  |  |  |  |  |  | 0112St 0000002114 | m | S000 | false | HI_STT_HEA_STA_0,200_xxx | AllplanAttributes - 2D Interaktion: yes; Position: S000; IFC_Pset_TWP - Herstellung: -
Stahlstütze | EG_Produktion_FFB | S235 |  | Stahlprofilstütze |  | Stahlstütze | HEA 200 |  | EG_Produktion_FFB |  |  |  |  |  |  |  |  | 0112St 0000002123 | m | S000 | false | HI_STT_HEA_STA_0,200_xxx | AllplanAttributes - 2D Interaktion: yes; Position: S000; IFC_Pset_TWP - Herstellung: -
Stahlstütze | EG_Produktion_FFB | S235 |  | Stahlprofilstütze |  | Stahlstütze | HEA 220 |  | EG_Produktion_FFB |  |  |  |  |  |  |  |  | 0112St 0000002113 | m | S001 | false | HI_STT_HEA_STA_0,220_xxx | AllplanAttributes - 2D Interaktion: yes; Position: S001; IFC_Pset_TWP - Herstellung: -
Stahlstütze | EG_Produktion_FFB | S235 |  | Stahlprofilstütze |  | Stahlstütze | HEA 240 |  | EG_Produktion_FFB |  |  |  |  |  |  |  |  | 0112St 0000002112 | m | S003 | false | HI_STT_HEA_STA_0,240_xxx | AllplanAttributes - 2D Interaktion: yes; Position: S003; IFC_Pset_TWP - Herstellung: -
Stahlstütze | EG_Produktion_FFB | S235 |  | Stahlprofilstütze |  | Stahlstütze | HEA 260 |  | EG_Produktion_FFB |  |  |  |  |  |  |  |  | 0112St 0000002102 | m | S005 | false | HI_STT_HEA_STA_0,260_xxx | AllplanAttributes - 2D Interaktion: yes; Position: S005; IFC_Pset_TWP - Herstellung: -
Stahlstütze | EG_Produktion_FFB | S235 |  | Stahlprofilstütze |  | Stahlstütze | HEA 220 |  | EG_Produktion_FFB |  |  |  |  |  |  |  |  | 0112St 0000002100 | m | S001 | false | HI_STT_HEA_STA_0,220_xxx | AllplanAttributes - 2D Interaktion: yes; Position: S001; IFC_Pset_TWP - Herstellung: -
Stahlstütze | EG_Produktion_FFB | S235 |  | Stahlprofilstütze |  | Stahlstütze | HEA 200 |  | EG_Produktion_FFB |  |  |  |  |  |  |  |  | 0112St 0000002101 | m | S000 | false | HI_STT_HEA_STA_0,200_xxx | AllplanAttributes - 2D Interaktion: yes; Position: S000; IFC_Pset_TWP - Herstellung: -
Stahlstütze | EG_Produktion_FFB | S235 |  | Stahlprofilstütze |  | Stahlstütze | HEA 200 |  | EG_Produktion_FFB |  |  |  |  |  |  |  |  | 0112St 0000000224 | m | S000 | false | HI_STT_HEA_STA_0,200_xxx | AllplanAttributes - 2D Interaktion: yes; Position: S000; IFC_Pset_TWP - Herstellung: -
Stahlstütze | EG_Produktion_FFB | S235 |  | Stahlprofilstütze |  | Stahlstütze | HEA 200 |  | EG_Produktion_FFB |  |  |  |  |  |  |  |  | 0112St 0000000223 | m | S000 | false | HI_STT_HEA_STA_0,200_xxx | AllplanAttributes - 2D Interaktion: yes; Position: S000; IFC_Pset_TWP - Herstellung: -
Stahlstütze | EG_Produktion_FFB | S235 |  | Stahlprofilstütze |  | Stahlstütze | HEA 200 |  | EG_Produktion_FFB |  |  |  |  |  |  |  |  | 0112St 0000000222 | m | S000 | false | HI_STT_HEA_STA_0,200_xxx | AllplanAttributes - 2D Interaktion: yes; Position: S000; IFC_Pset_TWP - Herstellung: -
Stahlstütze | EG_Produktion_FFB | S235 |  | Stahlprofilstütze |  | Stahlstütze | HEA 200 |  | EG_Produktion_FFB |  |  |  |  |  |  |  |  | 0112St 0000000221 | m | S000 | false | HI_STT_HEA_STA_0,200_xxx | AllplanAttributes - 2D Interaktion: yes; Position: S000; IFC_Pset_TWP - Herstellung: -
Stahlstütze | EG_Produktion_FFB | S235 |  | Stahlprofilstütze |  | Stahlstütze | HEA 200 |  | EG_Produktion_FFB |  |  |  |  |  |  |  |  | 0112St 0000000232 | m | S000 | false | HI_STT_HEA_STA_0,200_xxx | AllplanAttributes - 2D Interaktion: yes; Position: S000; IFC_Pset_TWP - Herstellung: -
Stahlstütze | EG_Produktion_FFB | S235 |  | Stahlprofilstütze |  | Stahlstütze | HEA 200 |  | EG_Produktion_FFB |  |  |  |  |  |  |  |  | 0112St 0000000231 | m | S000 | false | HI_STT_HEA_STA_0,200_xxx | AllplanAttributes - 2D Interaktion: yes; Position: S000; IFC_Pset_TWP - Herstellung: -
Stahlstütze | EG_Produktion_FFB | S235 |  | Stahlprofilstütze |  | Stahlstütze | HEA 200 |  | EG_Produktion_FFB |  |  |  |  |  |  |  |  | 0112St 0000000230 | m | S000 | false | HI_STT_HEA_STA_0,200_xxx | AllplanAttributes - 2D Interaktion: yes; Position: S000; IFC_Pset_TWP - Herstellung: -
Stahlstütze | EG_Produktion_FFB | S235 |  | Stahlprofilstütze |  | Stahlstütze | HEA 200 |  | EG_Produktion_FFB |  |  |  |  |  |  |  |  | 0112St 0000000229 | m | S000 | false | HI_STT_HEA_STA_0,200_xxx | AllplanAttributes - 2D Interaktion: yes; Position: S000; IFC_Pset_TWP - Herstellung: -
Stahlstütze | EG_Produktion_FFB | S235 |  | Stahlprofilstütze |  | Stahlstütze | HEA 200 |  | EG_Produktion_FFB |  |  |  |  |  |  |  |  | 0112St 0000000228 | m | S000 | false | HI_STT_HEA_STA_0,200_xxx | AllplanAttributes - 2D Interaktion: yes; Position: S000; IFC_Pset_TWP - Herstellung: -
Stahlstütze | EG_Produktion_FFB | S235 |  | Stahlprofilstütze |  | Stahlstütze | HEA 320 |  | EG_Produktion_FFB |  |  |  |  |  |  |  |  | 0112St 0000000074 | m | S002 | false | HI_STT_HEA_STA_0,320_xxx | AllplanAttributes - 2D Interaktion: yes; Position: S002; IFC_Pset_TWP - Herstellung: -
Stahlstütze | EG_Produktion_FFB | S235 |  | Stahlprofilstütze |  | Stahlstütze | HEA 320 |  | EG_Produktion_FFB |  |  |  |  |  |  |  |  | 0112St 0000000071 | m | S002 | false | HI_STT_HEA_STA_0,320_xxx | AllplanAttributes - 2D Interaktion: yes; Position: S002; IFC_Pset_TWP - Herstellung: -
Stahlstütze | EG_Produktion_FFB | S235 |  | Stahlprofilstütze |  | Stahlstütze | HEA 320 |  | EG_Produktion_FFB |  |  |  |  |  |  |  |  | 0112St 0000000073 | m | S002 | false | HI_STT_HEA_STA_0,320_xxx | AllplanAttributes - 2D Interaktion: yes; Position: S002; IFC_Pset_TWP - Herstellung: -
Stahlstütze | EG_Produktion_FFB | S235 |  | Stahlprofilstütze |  | Stahlstütze | HEA 320 |  | EG_Produktion_FFB |  |  |  |  |  |  |  |  | 0112St 0000000075 | m | S002 | false | HI_STT_HEA_STA_0,320_xxx | AllplanAttributes - 2D Interaktion: yes; Position: S002; IFC_Pset_TWP - Herstellung: -
Stahlstütze | EG_Produktion_FFB | S235 |  | Stahlprofilstütze |  | Stahlstütze | HEA 320 |  | EG_Produktion_FFB |  |  |  |  |  |  |  |  | 0112St 0000000145 | m | S002 | false | HI_STT_HEA_STA_0,320_xxx | AllplanAttributes - 2D Interaktion: yes; Position: S002; IFC_Pset_TWP - Herstellung: -
Stahlstütze | EG_Produktion_FFB | S235 |  | Stahlprofilstütze |  | Stahlstütze | HEA 220 |  | EG_Produktion_FFB |  |  |  |  |  |  |  |  | 0112St 0000003990 | m | S001 | false | HI_STT_HEA_STA_0,220_xxx | AllplanAttributes - 2D Interaktion: yes; Position: S001; IFC_Pset_TWP - Herstellung: -
Stahlstütze | EG_Produktion_FFB | S235 |  | Stahlprofilstütze |  | Stahlstütze | HEA 220 |  | EG_Produktion_FFB |  |  |  |  |  |  |  |  | 0112St 0000003993 | m | S001 | false | HI_STT_HEA_STA_0,220_xxx | AllplanAttributes - 2D Interaktion: yes; Position: S001; IFC_Pset_TWP - Herstellung: -
Stahlstütze | EG_Produktion_FFB | S235 |  | Stahlprofilstütze |  | Stahlstütze | HEA 220 |  | EG_Produktion_FFB |  |  |  |  |  |  |  |  | 0112St 0000003994 | m | S001 | false | HI_STT_HEA_STA_0,220_xxx | AllplanAttributes - 2D Interaktion: yes; Position: S001; IFC_Pset_TWP - Herstellung: -
Stahlstütze | EG_Produktion_FFB | S235 |  | Stahlprofilstütze |  | Stahlstütze | HEA 220 |  | EG_Produktion_FFB |  |  |  |  |  |  |  |  | 0112St 0000004002 | m | S001 | false | HI_STT_HEA_STA_0,220_xxx | AllplanAttributes - 2D Interaktion: yes; Position: S001; IFC_Pset_TWP - Herstellung: -
Stahlstütze | EG_Produktion_FFB | S235 |  | Stahlprofilstütze |  | Stahlstütze | HEA 220 |  | EG_Produktion_FFB |  |  |  |  |  |  |  |  | 0112St 0000004003 | m | S001 | false | HI_STT_HEA_STA_0,220_xxx | AllplanAttributes - 2D Interaktion: yes; Position: S001; IFC_Pset_TWP - Herstellung: -
Stahlstütze | EG_Produktion_FFB | S235 |  | Stahlprofilstütze |  | Stahlstütze | HEA 240 |  | EG_Produktion_FFB |  |  |  |  |  |  |  |  | 0112St 0000004007 | m | S003 | false | HI_STT_HEA_STA_0,240_xxx | AllplanAttributes - 2D Interaktion: yes; Position: S003; IFC_Pset_TWP - Herstellung: -
Stahlkonsole | EG_Produktion_FFB | S235 |  | Stahlkonsole |  | Stahlkonsole | HEA 300 | 1.717 | EG_Produktion_FFB |  |  |  |  |  |  |  |  | 0112Kop0000003940 | St | K101 | false | HI_STT_PRO_STA_0,300_xxx | AllplanAttributes - 2D Interaktion: yes; Position: K101; Querschnittsfläche: 0.011 m2; Charakteristischer Wert der Eigenlast: 0.883; IFC_Pset_TWP - Herstellung: -
Stahlkonsole | EG_Produktion_FFB | S235 |  | Stahlkonsole |  | Stahlkonsole | HEA 300 | 1.717 | EG_Produktion_FFB |  |  |  |  |  |  |  |  | 0112Kop0000003932 | St | K101 | false | HI_STT_PRO_STA_0,300_xxx | AllplanAttributes - 2D Interaktion: yes; Position: K101; Querschnittsfläche: 0.011 m2; Charakteristischer Wert der Eigenlast: 0.883; IFC_Pset_TWP - Herstellung: -
Stahlkonsole | EG_Produktion_FFB | S235 |  | Stahlkonsole |  | Stahlkonsole | HEA 300 | 1.717 | EG_Produktion_FFB |  |  |  |  |  |  |  |  | 0112Kop0000003941 | St | K101 | false | HI_STT_PRO_STA_0,300_xxx | AllplanAttributes - 2D Interaktion: yes; Position: K101; Querschnittsfläche: 0.011 m2; Charakteristischer Wert der Eigenlast: 0.883; IFC_Pset_TWP - Herstellung: -
Stahlkonsole | EG_Produktion_FFB | S235 |  | Stahlkonsole |  | Stahlkonsole | HEA 300 | 1.717 | EG_Produktion_FFB |  |  |  |  |  |  |  |  | 0112Kop0000003942 | St | K101 | false | HI_STT_PRO_STA_0,300_xxx | AllplanAttributes - 2D Interaktion: yes; Position: K101; Querschnittsfläche: 0.011 m2; Charakteristischer Wert der Eigenlast: 0.883; IFC_Pset_TWP - Herstellung: -
Stahlkonsole | EG_Produktion_FFB | S235 |  | Stahlkonsole |  | Stahlkonsole | HEA 300 | 1.717 | EG_Produktion_FFB |  |  |  |  |  |  |  |  | 0112Kop0000003943 | St | K101 | false | HI_STT_PRO_STA_0,300_xxx | AllplanAttributes - 2D Interaktion: yes; Position: K101; Querschnittsfläche: 0.011 m2; Charakteristischer Wert der Eigenlast: 0.883; IFC_Pset_TWP - Herstellung: -
Stahlkonsole | EG_Produktion_FFB | S235 |  | Stahlkonsole |  | Stahlkonsole | HEA 300 | 1.717 | EG_Produktion_FFB |  |  |  |  |  |  |  |  | 0112Kop0000003945 | St | K101 | false | HI_STT_PRO_STA_0,300_xxx | AllplanAttributes - 2D Interaktion: yes; Position: K101; Querschnittsfläche: 0.011 m2; Charakteristischer Wert der Eigenlast: 0.883; IFC_Pset_TWP - Herstellung: -
Stahlkonsole | EG_Produktion_FFB | S235 |  | Stahlkonsole |  | Stahlkonsole | HEA 300 | 1.717 | EG_Produktion_FFB |  |  |  |  |  |  |  |  | 0112Kop0000003944 | St | K101 | false | HI_STT_PRO_STA_0,300_xxx | AllplanAttributes - 2D Interaktion: yes; Position: K101; Querschnittsfläche: 0.011 m2; Charakteristischer Wert der Eigenlast: 0.883; IFC_Pset_TWP - Herstellung: -
Stahlkonsole | EG_Produktion_FFB | S235 |  | Stahlkonsole |  | Stahlkonsole | HEA 300 | 1.717 | EG_Produktion_FFB |  |  |  |  |  |  |  |  | 0112Kop0000003933 | St | K101 | false | HI_STT_PRO_STA_0,300_xxx | AllplanAttributes - 2D Interaktion: yes; Position: K101; Querschnittsfläche: 0.011 m2; Charakteristischer Wert der Eigenlast: 0.883; IFC_Pset_TWP - Herstellung: -
Stahlkonsole | EG_Produktion_FFB | S235 |  | Stahlkonsole |  | Stahlkonsole | HEA 300 | 1.717 | EG_Produktion_FFB |  |  |  |  |  |  |  |  | 0112Kop0000003934 | St | K101 | false | HI_STT_PRO_STA_0,300_xxx | AllplanAttributes - 2D Interaktion: yes; Position: K101; Querschnittsfläche: 0.011 m2; Charakteristischer Wert der Eigenlast: 0.883; IFC_Pset_TWP - Herstellung: -
Stahlkonsole | EG_Produktion_FFB | S235 |  | Stahlkonsole |  | Stahlkonsole | HEA 300 | 1.717 | EG_Produktion_FFB |  |  |  |  |  |  |  |  | 0112Kop0000003935 | St | K101 | false | HI_STT_PRO_STA_0,300_xxx | AllplanAttributes - 2D Interaktion: yes; Position: K101; Querschnittsfläche: 0.011 m2; Charakteristischer Wert der Eigenlast: 0.883; IFC_Pset_TWP - Herstellung: -
Stahlkonsole | EG_Produktion_FFB | S235 |  | Stahlkonsole |  | Stahlkonsole | HEA 300 | 1.717 | EG_Produktion_FFB |  |  |  |  |  |  |  |  | 0112Kop0000003936 | St | K101 | false | HI_STT_PRO_STA_0,300_xxx | AllplanAttributes - 2D Interaktion: yes; Position: K101; Querschnittsfläche: 0.011 m2; Charakteristischer Wert der Eigenlast: 0.883; IFC_Pset_TWP - Herstellung: -
Stahlkonsole | EG_Produktion_FFB | S235 |  | Stahlkonsole |  | Stahlkonsole | HEA 300 | 1.717 | EG_Produktion_FFB |  |  |  |  |  |  |  |  | 0112Kop0000003937 | St | K101 | false | HI_STT_PRO_STA_0,300_xxx | AllplanAttributes - 2D Interaktion: yes; Position: K101; Querschnittsfläche: 0.011 m2; Charakteristischer Wert der Eigenlast: 0.883; IFC_Pset_TWP - Herstellung: -
Stahlkonsole | EG_Produktion_FFB | S235 |  | Stahlkonsole |  | Stahlkonsole | HEA 300 | 1.717 | EG_Produktion_FFB |  |  |  |  |  |  |  |  | 0112Kop0000003939 | St | K101 | false | HI_STT_PRO_STA_0,300_xxx | AllplanAttributes - 2D Interaktion: yes; Position: K101; Querschnittsfläche: 0.011 m2; Charakteristischer Wert der Eigenlast: 0.883; IFC_Pset_TWP - Herstellung: -
Stahlkonsole | EG_Produktion_FFB | S235 |  | Stahlkonsole |  | Stahlkonsole | HEA 300 | 1.717 | EG_Produktion_FFB |  |  |  |  |  |  |  |  | 0112Kop0000003938 | St | K101 | false | HI_STT_PRO_STA_0,300_xxx | AllplanAttributes - 2D Interaktion: yes; Position: K101; Querschnittsfläche: 0.011 m2; Charakteristischer Wert der Eigenlast: 0.883; IFC_Pset_TWP - Herstellung: -
Stahlkonsole | EG_Produktion_FFB | S235 |  | Stahlkonsole |  | Stahlkonsole | HEA 300 | 1.717 | EG_Produktion_FFB |  |  |  |  |  |  |  |  | 0112Kop0000003946 | St | K101 | false | HI_STT_PRO_STA_0,300_xxx | AllplanAttributes - 2D Interaktion: yes; Position: K101; Querschnittsfläche: 0.011 m2; Charakteristischer Wert der Eigenlast: 0.883; IFC_Pset_TWP - Herstellung: -
Stahlkonsole | EG_Produktion_FFB | S235 |  | Stahlkonsole |  | Stahlkonsole | HEA 300 | 1.717 | EG_Produktion_FFB |  |  |  |  |  |  |  |  | 0112Kop0000003948 | St | K101 | false | HI_STT_PRO_STA_0,300_xxx | AllplanAttributes - 2D Interaktion: yes; Position: K101; Querschnittsfläche: 0.011 m2; Charakteristischer Wert der Eigenlast: 0.883; IFC_Pset_TWP - Herstellung: -
Stahlkonsole | EG_Produktion_FFB | S235 |  | Stahlkonsole |  | Stahlkonsole | HEA 300 | 1.717 | EG_Produktion_FFB |  |  |  |  |  |  |  |  | 0112Kop0000003949 | St | K101 | false | HI_STT_PRO_STA_0,300_xxx | AllplanAttributes - 2D Interaktion: yes; Position: K101; Querschnittsfläche: 0.011 m2; Charakteristischer Wert der Eigenlast: 0.883; IFC_Pset_TWP - Herstellung: -
Stahlkonsole | EG_Produktion_FFB | S235 |  | Stahlkonsole |  | Stahlkonsole | HEA 300 | 1.717 | EG_Produktion_FFB |  |  |  |  |  |  |  |  | 0112Kop0000003950 | St | K101 | false | HI_STT_PRO_STA_0,300_xxx | AllplanAttributes - 2D Interaktion: yes; Position: K101; Querschnittsfläche: 0.011 m2; Charakteristischer Wert der Eigenlast: 0.883; IFC_Pset_TWP - Herstellung: -
Stahlkonsole | EG_Produktion_FFB | S235 |  | Stahlkonsole |  | Stahlkonsole | HEA 300 | 1.717 | EG_Produktion_FFB |  |  |  |  |  |  |  |  | 0112Kop0000003947 | St | K101 | false | HI_STT_PRO_STA_0,300_xxx | AllplanAttributes - 2D Interaktion: yes; Position: K101; Querschnittsfläche: 0.011 m2; Charakteristischer Wert der Eigenlast: 0.883; IFC_Pset_TWP - Herstellung: -
Stahlkonsole | EG_Produktion_FFB | S235 |  | Stahlkonsole |  | Stahlkonsole | HEA 300 | 1.717 | EG_Produktion_FFB |  |  |  |  |  |  |  |  | 0112Kop0000003951 | St | K101 | false | HI_STT_PRO_STA_0,300_xxx | AllplanAttributes - 2D Interaktion: yes; Position: K101; Querschnittsfläche: 0.011 m2; Charakteristischer Wert der Eigenlast: 0.883; IFC_Pset_TWP - Herstellung: -
Stahlkonsole | EG_Produktion_FFB | S235 |  | Stahlkonsole |  | Stahlkonsole | HEA 300 | 1.717 | EG_Produktion_FFB |  |  |  |  |  |  |  |  | 0112Kop0000003953 | St | K101 | false | HI_STT_PRO_STA_0,300_xxx | AllplanAttributes - 2D Interaktion: yes; Position: K101; Querschnittsfläche: 0.011 m2; Charakteristischer Wert der Eigenlast: 0.883; IFC_Pset_TWP - Herstellung: -
Stahlkonsole | EG_Produktion_FFB | S235 |  | Stahlkonsole |  | Stahlkonsole | HEA 300 | 1.717 | EG_Produktion_FFB |  |  |  |  |  |  |  |  | 0112Kop0000003954 | St | K101 | false | HI_STT_PRO_STA_0,300_xxx | AllplanAttributes - 2D Interaktion: yes; Position: K101; Querschnittsfläche: 0.011 m2; Charakteristischer Wert der Eigenlast: 0.883; IFC_Pset_TWP - Herstellung: -
Stahlkonsole | EG_Produktion_FFB | S235 |  | Stahlkonsole |  | Stahlkonsole | HEA 300 | 1.717 | EG_Produktion_FFB |  |  |  |  |  |  |  |  | 0112Kop0000003955 | St | K101 | false | HI_STT_PRO_STA_0,300_xxx | AllplanAttributes - 2D Interaktion: yes; Position: K101; Querschnittsfläche: 0.011 m2; Charakteristischer Wert der Eigenlast: 0.883; IFC_Pset_TWP - Herstellung: -
Stahlkonsole | EG_Produktion_FFB | S235 |  | Stahlkonsole |  | Stahlkonsole | HEA 300 | 1.717 | EG_Produktion_FFB |  |  |  |  |  |  |  |  | 0112Kop0000003952 | St | K101 | false | HI_STT_PRO_STA_0,300_xxx | AllplanAttributes - 2D Interaktion: yes; Position: K101; Querschnittsfläche: 0.011 m2; Charakteristischer Wert der Eigenlast: 0.883; IFC_Pset_TWP - Herstellung: -
Stahlkonsole | EG_Produktion_FFB | S235 |  | Stahlkonsole |  | Stahlkonsole | HEA 300 | 1.717 | EG_Produktion_FFB |  |  |  |  |  |  |  |  | 0112Kop0000003972 | St | K101 | false | HI_STT_PRO_STA_0,300_xxx | AllplanAttributes - 2D Interaktion: yes; Position: K101; Querschnittsfläche: 0.011 m2; Charakteristischer Wert der Eigenlast: 0.883; IFC_Pset_TWP - Herstellung: -
Stahlkonsole | EG_Produktion_FFB | S235 |  | Stahlkonsole |  | Stahlkonsole | HEA 300 | 1.717 | EG_Produktion_FFB |  |  |  |  |  |  |  |  | 0112Kop0000003973 | St | K101 | false | HI_STT_PRO_STA_0,300_xxx | AllplanAttributes - 2D Interaktion: yes; Position: K101; Querschnittsfläche: 0.011 m2; Charakteristischer Wert der Eigenlast: 0.883; IFC_Pset_TWP - Herstellung: -
Stahlkonsole | EG_Produktion_FFB | S235 |  | Stahlkonsole |  | Stahlkonsole | HEA 300 | 1.717 | EG_Produktion_FFB |  |  |  |  |  |  |  |  | 0112Kop0000003974 | St | K101 | false | HI_STT_PRO_STA_0,300_xxx | AllplanAttributes - 2D Interaktion: yes; Position: K101; Querschnittsfläche: 0.011 m2; Charakteristischer Wert der Eigenlast: 0.883; IFC_Pset_TWP - Herstellung: -
Stahlkonsole | EG_Produktion_FFB | S235 |  | Stahlkonsole |  | Stahlkonsole | HEA 300 | 1.717 | EG_Produktion_FFB |  |  |  |  |  |  |  |  | 0112Kop0000003981 | St | K101 | false | HI_STT_PRO_STA_0,300_xxx | AllplanAttributes - 2D Interaktion: yes; Position: K101; Querschnittsfläche: 0.011 m2; Charakteristischer Wert der Eigenlast: 0.883; IFC_Pset_TWP - Herstellung: -
Stahlkonsole | EG_Produktion_FFB | S235 |  | Stahlkonsole |  | Stahlkonsole | HEA 300 | 1.717 | EG_Produktion_FFB |  |  |  |  |  |  |  |  | 0112Kop0000003982 | St | K101 | false | HI_STT_PRO_STA_0,300_xxx | AllplanAttributes - 2D Interaktion: yes; Position: K101; Querschnittsfläche: 0.011 m2; Charakteristischer Wert der Eigenlast: 0.883; IFC_Pset_TWP - Herstellung: -
Stahlkonsole | EG_Produktion_FFB | S235 |  | Stahlkonsole |  | Stahlkonsole | HEA 300 | 1.717 | EG_Produktion_FFB |  |  |  |  |  |  |  |  | 0112Kop0000003983 | St | K101 | false | HI_STT_PRO_STA_0,300_xxx | AllplanAttributes - 2D Interaktion: yes; Position: K101; Querschnittsfläche: 0.011 m2; Charakteristischer Wert der Eigenlast: 0.883; IFC_Pset_TWP - Herstellung: -
Stahlkonsole | EG_Produktion_FFB | S235 |  | Stahlkonsole |  | Stahlkonsole | HEA 300 | 1.717 | EG_Produktion_FFB |  |  |  |  |  |  |  |  | 0112Kop0000003971 | St | K101 | false | HI_STT_PRO_STA_0,300_xxx | AllplanAttributes - 2D Interaktion: yes; Position: K101; Querschnittsfläche: 0.011 m2; Charakteristischer Wert der Eigenlast: 0.883; IFC_Pset_TWP - Herstellung: -
Stahlkonsole | EG_Produktion_FFB | S235 |  | Stahlkonsole |  | Stahlkonsole | HEA 300 | 1.717 | EG_Produktion_FFB |  |  |  |  |  |  |  |  | 0112Kop0000003979 | St | K101 | false | HI_STT_PRO_STA_0,300_xxx | AllplanAttributes - 2D Interaktion: yes; Position: K101; Querschnittsfläche: 0.011 m2; Charakteristischer Wert der Eigenlast: 0.883; IFC_Pset_TWP - Herstellung: -
Stahlkonsole | EG_Produktion_FFB | S235 |  | Stahlkonsole |  | Stahlkonsole | HEA 300 | 1.717 | EG_Produktion_FFB |  |  |  |  |  |  |  |  | 0112Kop0000003980 | St | K101 | false | HI_STT_PRO_STA_0,300_xxx | AllplanAttributes - 2D Interaktion: yes; Position: K101; Querschnittsfläche: 0.011 m2; Charakteristischer Wert der Eigenlast: 0.883; IFC_Pset_TWP - Herstellung: -
Stahlkonsole | EG_Produktion_FFB | S235 |  | Stahlkonsole |  | Stahlkonsole | HEA 300 | 1.717 | EG_Produktion_FFB |  |  |  |  |  |  |  |  | 0112Kop0000003970 | St | K101 | false | HI_STT_PRO_STA_0,300_xxx | AllplanAttributes - 2D Interaktion: yes; Position: K101; Querschnittsfläche: 0.011 m2; Charakteristischer Wert der Eigenlast: 0.883; IFC_Pset_TWP - Herstellung: -
Stahlkonsole | EG_Produktion_FFB | S235 |  | Stahlkonsole |  | Stahlkonsole | HEA 300 | 1.717 | EG_Produktion_FFB |  |  |  |  |  |  |  |  | 0112Kop0000003988 | St | K101 | false | HI_STT_PRO_STA_0,300_xxx | AllplanAttributes - 2D Interaktion: yes; Position: K101; Querschnittsfläche: 0.011 m2; Charakteristischer Wert der Eigenlast: 0.883; IFC_Pset_TWP - Herstellung: -
Stahlkonsole | EG_Produktion_FFB | S235 |  | Stahlkonsole |  | Stahlkonsole | HEA 300 | 1.717 | EG_Produktion_FFB |  |  |  |  |  |  |  |  | 0112Kop0000003989 | St | K101 | false | HI_STT_PRO_STA_0,300_xxx | AllplanAttributes - 2D Interaktion: yes; Position: K101; Querschnittsfläche: 0.011 m2; Charakteristischer Wert der Eigenlast: 0.883; IFC_Pset_TWP - Herstellung: -
Stahlkonsole | EG_Produktion_FFB | S235 |  | Stahlkonsole |  | Stahlkonsole | HEA 300 | 1.717 | EG_Produktion_FFB |  |  |  |  |  |  |  |  | 0112Kop0000003984 | St | K101 | false | HI_STT_PRO_STA_0,300_xxx | AllplanAttributes - 2D Interaktion: yes; Position: K101; Querschnittsfläche: 0.011 m2; Charakteristischer Wert der Eigenlast: 0.883; IFC_Pset_TWP - Herstellung: -
Stahlkonsole | EG_Produktion_FFB | S235 |  | Stahlkonsole |  | Stahlkonsole | HEA 300 | 1.717 | EG_Produktion_FFB |  |  |  |  |  |  |  |  | 0112Kop0000003985 | St | K101 | false | HI_STT_PRO_STA_0,300_xxx | AllplanAttributes - 2D Interaktion: yes; Position: K101; Querschnittsfläche: 0.011 m2; Charakteristischer Wert der Eigenlast: 0.883; IFC_Pset_TWP - Herstellung: -
Stahlkonsole | EG_Produktion_FFB | S235 |  | Stahlkonsole |  | Stahlkonsole | HEA 300 | 1.717 | EG_Produktion_FFB |  |  |  |  |  |  |  |  | 0112Kop0000003986 | St | K101 | false | HI_STT_PRO_STA_0,300_xxx | AllplanAttributes - 2D Interaktion: yes; Position: K101; Querschnittsfläche: 0.011 m2; Charakteristischer Wert der Eigenlast: 0.883; IFC_Pset_TWP - Herstellung: -
Stahlkonsole | EG_Produktion_FFB | S235 |  | Stahlkonsole |  | Stahlkonsole | HEA 300 | 1.717 | EG_Produktion_FFB |  |  |  |  |  |  |  |  | 0112Kop0000003987 | St | K101 | false | HI_STT_PRO_STA_0,300_xxx | AllplanAttributes - 2D Interaktion: yes; Position: K101; Querschnittsfläche: 0.011 m2; Charakteristischer Wert der Eigenlast: 0.883; IFC_Pset_TWP - Herstellung: -
Stahlkonsole | EG_Produktion_FFB | S235 |  | Stahlkonsole |  | Stahlkonsole | HEA 300 | 1.717 | EG_Produktion_FFB |  |  |  |  |  |  |  |  | 0112Kop0000003975 | St | K101 | false | HI_STT_PRO_STA_0,300_xxx | AllplanAttributes - 2D Interaktion: yes; Position: K101; Querschnittsfläche: 0.011 m2; Charakteristischer Wert der Eigenlast: 0.883; IFC_Pset_TWP - Herstellung: -
Stahlkonsole | EG_Produktion_FFB | S235 |  | Stahlkonsole |  | Stahlkonsole | HEA 300 | 1.717 | EG_Produktion_FFB |  |  |  |  |  |  |  |  | 0112Kop0000003976 | St | K101 | false | HI_STT_PRO_STA_0,300_xxx | AllplanAttributes - 2D Interaktion: yes; Position: K101; Querschnittsfläche: 0.011 m2; Charakteristischer Wert der Eigenlast: 0.883; IFC_Pset_TWP - Herstellung: -
Stahlkonsole | EG_Produktion_FFB | S235 |  | Stahlkonsole |  | Stahlkonsole | HEA 300 | 1.717 | EG_Produktion_FFB |  |  |  |  |  |  |  |  | 0112Kop0000003977 | St | K101 | false | HI_STT_PRO_STA_0,300_xxx | AllplanAttributes - 2D Interaktion: yes; Position: K101; Querschnittsfläche: 0.011 m2; Charakteristischer Wert der Eigenlast: 0.883; IFC_Pset_TWP - Herstellung: -
Stahlkonsole | EG_Produktion_FFB | S235 |  | Stahlkonsole |  | Stahlkonsole | HEA 300 | 1.717 | EG_Produktion_FFB |  |  |  |  |  |  |  |  | 0112Kop0000003978 | St | K101 | false | HI_STT_PRO_STA_0,300_xxx | AllplanAttributes - 2D Interaktion: yes; Position: K101; Querschnittsfläche: 0.011 m2; Charakteristischer Wert der Eigenlast: 0.883; IFC_Pset_TWP - Herstellung: -
Rahmenstiel | EG_Produktion_FFB | S235 |  | Stahlprofilstütze |  | Rahmenstiel | HEA 200 |  | EG_Produktion_FFB |  |  |  |  |  |  |  |  | 0112St 0000001372 | m | AR04 | true | HA_STT_HEA_STA_0,200_xxx | AllplanAttributes - 2D Interaktion: yes; IFC_Pset_TWP - Herstellung: -
Rahmenstiel | EG_Produktion_FFB | S235 |  | Stahlprofilstütze |  | Rahmenstiel | HEA 200 |  | EG_Produktion_FFB |  |  |  |  |  |  |  |  | 0112St 0000001389 | m | AR04 | true | HA_STT_HEA_STA_0,200_xxx | AllplanAttributes - 2D Interaktion: yes; IFC_Pset_TWP - Herstellung: -
Rahmenstiel | EG_Produktion_FFB | S235 |  | Stahlprofilstütze |  | Rahmenstiel | HEA 200 |  | EG_Produktion_FFB |  |  |  |  |  |  |  |  | 0112St 0000001395 | m | AR03 | true | HA_STT_HEA_STA_0,200_xxx | AllplanAttributes - 2D Interaktion: yes; IFC_Pset_TWP - Herstellung: -
Rahmenstiel | EG_Produktion_FFB | S235 |  | Stahlprofilstütze |  | Rahmenstiel | HEA 200 |  | EG_Produktion_FFB |  |  |  |  |  |  |  |  | 0112St 0000001392 | m | AR03 | true | HA_STT_HEA_STA_0,200_xxx | AllplanAttributes - 2D Interaktion: yes; IFC_Pset_TWP - Herstellung: -
Rahmenstiel | EG_Produktion_FFB | S235 |  | Stahlprofilstütze |  | Rahmenstiel | HEA 200 |  | EG_Produktion_FFB |  |  |  |  |  |  |  |  | 0112St 0000001398 | m | AR03 | true | HA_STT_HEA_STA_0,200_xxx | AllplanAttributes - 2D Interaktion: yes; IFC_Pset_TWP - Herstellung: -
Rahmenstiel | EG_Produktion_FFB | S235 |  | Stahlprofilstütze |  | Rahmenstiel | HEA 200 |  | EG_Produktion_FFB |  |  |  |  |  |  |  |  | 0112St 0000004751 | m | AR03 | true | HA_STT_HEA_STA_0,200_xxx | AllplanAttributes - 2D Interaktion: yes; IFC_Pset_TWP - Herstellung: -
Fachwerkstütze | EG_Produktion_FFB | S235 |  | Stahlprofilstütze |  | Fachwerkstütze | U 100 |  | EG_Produktion_FFB |  |  |  |  |  |  |  |  | 0112St 0000001320 | m | RA004 | false | HI_STT_U_STA_0,100_xxx | AllplanAttributes - 2D Interaktion: yes; Dateiname: C:\ProgramData\Nemetschek\Allplan\2025\Etc\Library\Engineering\Steel sections\2D profiles angular idealiz\U\U 100.sym; Folgenname: U 100
Fachwerkstütze | EG_Produktion_FFB | S235 |  | Stahlprofilstütze |  | Fachwerkstütze | U 100 |  | EG_Produktion_FFB |  |  |  |  |  |  |  |  | 0112St 0000002786 | m | RA004 | false | HI_STT_U_STA_0,100_xxx | AllplanAttributes - 2D Interaktion: yes; Dateiname: C:\ProgramData\Nemetschek\Allplan\2025\Etc\Library\Engineering\Steel sections\2D profiles angular idealiz\U\U 100.sym; Folgenname: U 100
Fachwerkstütze | EG_Produktion_FFB | S235 |  | Stahlprofilstütze |  | Fachwerkstütze | U 100 |  | EG_Produktion_FFB |  |  |  |  |  |  |  |  | 0112St 0000002648 | m | RA004 | false | HI_STT_U_STA_0,100_xxx | AllplanAttributes - 2D Interaktion: yes; Dateiname: C:\ProgramData\Nemetschek\Allplan\2025\Etc\Library\Engineering\Steel sections\2D profiles angular idealiz\U\U 100.sym; Folgenname: U 100
Fachwerkstütze | EG_Produktion_FFB | S235 |  | Stahlprofilstütze |  | Fachwerkstütze | U 100 |  | EG_Produktion_FFB |  |  |  |  |  |  |  |  | 0112St 0000002787 | m | RA004 | false | HI_STT_U_STA_0,100_xxx | AllplanAttributes - 2D Interaktion: yes; Dateiname: C:\ProgramData\Nemetschek\Allplan\2025\Etc\Library\Engineering\Steel sections\2D profiles angular idealiz\U\U 100.sym; Folgenname: U 100
Stahlstütze | EG_Produktion_FFB | S235 |  | Stahlprofilstütze |  | Stahlstütze | HEA 320 |  | EG_Produktion_FFB |  |  |  |  |  |  |  |  | 0112St 0000002016 | m | S002 | false | HI_STT_HEA_STA_0,320_xxx | AllplanAttributes - 2D Interaktion: yes; Position: S002; IFC_Pset_TWP - Herstellung: -
Stahlstütze | EG_Produktion_FFB | S235 |  | Stahlprofilstütze |  | Stahlstütze | HEA 320 |  | EG_Produktion_FFB |  |  |  |  |  |  |  |  | 0112St 0000002027 | m | S002 | false | HI_STT_HEA_STA_0,320_xxx | AllplanAttributes - 2D Interaktion: yes; Position: S002; IFC_Pset_TWP - Herstellung: -
Stahlstütze | EG_Produktion_FFB | S235 |  | Stahlprofilstütze |  | Stahlstütze | HEA 320 |  | EG_Produktion_FFB |  |  |  |  |  |  |  |  | 0112St 0000000072 | m | S002 | false | HI_STT_HEA_STA_0,320_xxx | AllplanAttributes - 2D Interaktion: yes; Position: S002; IFC_Pset_TWP - Herstellung: -
Stahlstütze | EG_Produktion_FFB | S235 |  | Stahlprofilstütze |  | Stahlstütze | HEA 280 |  | EG_Produktion_FFB |  |  |  |  |  |  |  |  | 0112St 0000003999 | m | S007 | false | HI_STT_HEA_STA_0,280_xxx | AllplanAttributes - 2D Interaktion: yes; Dateiname: C:\ProgramData\Nemetschek\Allplan\2025\Etc\Library\Engineering\Steel sections\2D profiles angular idealiz\HEA\HEA 280.sym; Folgenname: HEA 280; Position: S007; IFC_Pset_TWP - Herstellung: -
Stahlstütze | EG_Produktion_FFB | S235 |  | Stahlprofilstütze |  | Stahlstütze | HEA 220 |  | EG_Produktion_FFB |  |  |  |  |  |  |  |  | 0112St 0000004006 | m | S001 | false | HI_STT_HEA_STA_0,220_xxx | AllplanAttributes - 2D Interaktion: yes; Position: S001; IFC_Pset_TWP - Herstellung: -
Stahlstütze | EG_Produktion_FFB | S235 |  | Stahlprofilstütze |  | Stahlstütze | HEA 220 |  | EG_Produktion_FFB |  |  |  |  |  |  |  |  | 0112St 0000004766 | m | S001 | false | HI_STT_HEA_STA_0,220_xxx | AllplanAttributes - 2D Interaktion: yes; Position: S001; IFC_Pset_TWP - Herstellung: -
Stahlstütze | EG_Produktion_FFB | S235 |  | Stahlprofilstütze |  | Stahlstütze | HEA 320 |  | EG_Produktion_FFB |  |  |  |  |  |  |  |  | 0112St 0000000181 | m | S002 | false | HI_STT_HEA_STA_0,320_xxx | AllplanAttributes - 2D Interaktion: yes; Position: S002; IFC_Pset_TWP - Herstellung: -
Stahlstütze | EG_Produktion_FFB | S235 |  | Stahlprofilstütze |  | Stahlstütze | HEA 320 |  | EG_Produktion_FFB |  |  |  |  |  |  |  |  | 0112St 0000000182 | m | S002 | false | HI_STT_HEA_STA_0,320_xxx | AllplanAttributes - 2D Interaktion: yes; Position: S002; IFC_Pset_TWP - Herstellung: -
Verbindungsstück | Wartung_FFB | S235 | SB-STUETZE\ | Stahlprofilstütze | 1 | Verbindungsstück | HEA 100 | 0.582 | Wartung_FFB | 67.05 | 10.69 | 6.956 | 7.225 | 0 | Column | 0.05 | 0.048 | 0121Tra0000009775 | m | S101 | false | HI_STV_HEA_STA_0,100
Verbindungsstück | Wartung_FFB | S235 | SB-STUETZE\ | Stahlprofilstütze | 1 | Verbindungsstück | HEA 100 | 0.582 | Wartung_FFB | 67.05 | 30.1 | 6.956 | 7.225 | 0 | Column | 0.05 | 0.048 | 0121Tra0000009777 | m | S101 | false | HI_STV_HEA_STA_0,100
Verbindungsstück | Wartung_FFB | S235 | SB-STUETZE\ | Stahlprofilstütze | 1 | Verbindungsstück | HEA 100 | 0.582 | Wartung_FFB | 70.05 | 10.69 | 6.956 | 7.225 | 0 | Column | 0.05 | 0.048 | 0121Tra0000009790 | m | S101 | false | HI_STV_HEA_STA_0,100
Verbindungsstück | Wartung_FFB | S235 | SB-STUETZE\ | Stahlprofilstütze | 1 | Verbindungsstück | HEA 100 | 0.582 | Wartung_FFB | 73.05 | 10.69 | 6.956 | 7.225 | 0 | Column | 0.05 | 0.048 | 0121Tra0000009805 | m | S101 | false | HI_STV_HEA_STA_0,100
Verbindungsstück | Wartung_FFB | S235 | SB-STUETZE\ | Stahlprofilstütze | 1 | Verbindungsstück | HEA 100 | 0.582 | Wartung_FFB | 76.05 | 10.69 | 6.956 | 7.225 | 0 | Column | 0.05 | 0.048 | 0121Tra0000009820 | m | S101 | false | HI_STV_HEA_STA_0,100
Verbindungsstück | Wartung_FFB | S235 | SB-STUETZE\ | Stahlprofilstütze | 1 | Verbindungsstück | HEA 100 | 0.582 | Wartung_FFB | 79.05 | 10.69 | 6.956 | 7.225 | 0 | Column | 0.05 | 0.048 | 0121Tra0000009835 | m | S101 | false | HI_STV_HEA_STA_0,100
Verbindungsstück | Wartung_FFB | S235 | SB-STUETZE\ | Stahlprofilstütze | 1 | Verbindungsstück | HEA 100 | 0.582 | Wartung_FFB | 70.05 | 30.1 | 6.956 | 7.225 | 0 | Column | 0.05 | 0.048 | 0121Tra0000009792 | m | S101 | false | HI_STV_HEA_STA_0,100
Verbindungsstück | Wartung_FFB | S235 | SB-STUETZE\ | Stahlprofilstütze | 1 | Verbindungsstück | HEA 100 | 0.582 | Wartung_FFB | 73.05 | 30.1 | 6.956 | 7.225 | 0 | Column | 0.05 | 0.048 | 0121Tra0000009807 | m | S101 | false | HI_STV_HEA_STA_0,100
Verbindungsstück | Wartung_FFB | S235 | SB-STUETZE\ | Stahlprofilstütze | 1 | Verbindungsstück | HEA 100 | 0.582 | Wartung_FFB | 76.05 | 30.1 | 6.956 | 7.225 | 0 | Column | 0.05 | 0.048 | 0121Tra0000009822 | m | S101 | false | HI_STV_HEA_STA_0,100
Verbindungsstück | Wartung_FFB | S235 | SB-STUETZE\ | Stahlprofilstütze | 1 | Verbindungsstück | HEA 100 | 0.582 | Wartung_FFB | 79.05 | 30.1 | 6.956 | 7.225 | 0 | Column | 0.05 | 0.048 | 0121Tra0000009837 | m | S101 | false | HI_STV_HEA_STA_0,100
Verbindungsstück | Wartung_FFB | S235 | SB-STUETZE\ | Stahlprofilstütze | 1 | Verbindungsstück | HEA 100 | 0.582 | Wartung_FFB | 81.55 | 10.69 | 6.956 | 7.225 | 0 | Column | 0.05 | 0.048 | 0121Tra0000009850 | m | S101 | false | HI_STV_HEA_STA_0,100
Verbindungsstück | Wartung_FFB | S235 | SB-STUETZE\ | Stahlprofilstütze | 1 | Verbindungsstück | HEA 100 | 0.582 | Wartung_FFB | 81.55 | 30.1 | 6.956 | 7.225 | 0 | Column | 0.05 | 0.048 | 0121Tra0000009852 | m | S101 | false | HI_STV_HEA_STA_0,100
Verbindungsstück | Wartung_FFB | S235 | SB-STUETZE\ | Stahlprofilstütze | 1 | Verbindungsstück | HEA 100 | 0.582 | Wartung_FFB | 58.05 | 10.69 | 6.956 | 7.225 | 0 | Column | 0.05 | 0.048 | 0121Tra0000009520 | m | S101 | false | HI_STV_HEA_STA_0,100
Verbindungsstück | Wartung_FFB | S235 | SB-STUETZE\ | Stahlprofilstütze | 1 | Verbindungsstück | HEA 100 | 0.582 | Wartung_FFB | 55.05 | 10.69 | 6.956 | 7.225 | 0 | Column | 0.05 | 0.048 | 0121Tra0000009535 | m | S101 | false | HI_STV_HEA_STA_0,100
Verbindungsstück | Wartung_FFB | S235 | SB-STUETZE\ | Stahlprofilstütze | 1 | Verbindungsstück | HEA 100 | 0.582 | Wartung_FFB | 58.05 | 30.1 | 6.956 | 7.225 | 0 | Column | 0.05 | 0.048 | 0121Tra0000009522 | m | S101 | false | HI_STV_HEA_STA_0,100
Verbindungsstück | Wartung_FFB | S235 | SB-STUETZE\ | Stahlprofilstütze | 1 | Verbindungsstück | HEA 100 | 0.582 | Wartung_FFB | 55.05 | 30.1 | 6.956 | 7.225 | 0 | Column | 0.05 | 0.048 | 0121Tra0000009537 | m | S101 | false | HI_STV_HEA_STA_0,100
Verbindungsstück | Wartung_FFB | S235 | SB-STUETZE\ | Stahlprofilstütze | 1 | Verbindungsstück | HEA 100 | 0.582 | Wartung_FFB | 34.05 | 10.69 | 6.956 | 7.225 | 0 | Column | 0.05 | 0.048 | 0121Tra0000009640 | m | S101 | false | HI_STV_HEA_STA_0,100
Verbindungsstück | Wartung_FFB | S235 | SB-STUETZE\ | Stahlprofilstütze | 1 | Verbindungsstück | HEA 100 | 0.582 | Wartung_FFB | 28.05 | 10.69 | 6.956 | 7.225 | 0 | Column | 0.05 | 0.048 | 0121Tra0000009670 | m | S101 | false | HI_STV_HEA_STA_0,100
Verbindungsstück | Wartung_FFB | S235 | SB-STUETZE\ | Stahlprofilstütze | 1 | Verbindungsstück | HEA 100 | 0.582 | Wartung_FFB | 34.05 | 30.1 | 6.956 | 7.225 | 0 | Column | 0.05 | 0.048 | 0121Tra0000009642 | m | S101 | false | HI_STV_HEA_STA_0,100
Verbindungsstück | Wartung_FFB | S235 | SB-STUETZE\ | Stahlprofilstütze | 1 | Verbindungsstück | HEA 100 | 0.582 | Wartung_FFB | 28.05 | 30.1 | 6.956 | 7.225 | 0 | Column | 0.05 | 0.048 | 0121Tra0000009672 | m | S101 | false | HI_STV_HEA_STA_0,100
Verbindungsstück | Wartung_FFB | S235 | SB-STUETZE\ | Stahlprofilstütze | 1 | Verbindungsstück | HEA 100 | 0.582 | Wartung_FFB | 37.05 | 10.69 | 6.956 | 7.225 | 0 | Column | 0.05 | 0.048 | 0121Tra0000009625 | m | S101 | false | HI_STV_HEA_STA_0,100
Verbindungsstück | Wartung_FFB | S235 | SB-STUETZE\ | Stahlprofilstütze | 1 | Verbindungsstück | HEA 100 | 0.582 | Wartung_FFB | 37.05 | 30.1 | 6.956 | 7.225 | 0 | Column | 0.05 | 0.048 | 0121Tra0000009627 | m | S101 | false | HI_STV_HEA_STA_0,100
Verbindungsstück | Wartung_FFB | S235 | SB-STUETZE\ | Stahlprofilstütze | 1 | Verbindungsstück | HEA 100 | 0.582 | Wartung_FFB | 40.05 | 10.69 | 6.956 | 7.225 | 0 | Column | 0.05 | 0.048 | 0121Tra0000009610 | m | S101 | false | HI_STV_HEA_STA_0,100
Verbindungsstück | Wartung_FFB | S235 | SB-STUETZE\ | Stahlprofilstütze | 1 | Verbindungsstück | HEA 100 | 0.582 | Wartung_FFB | 40.05 | 30.1 | 6.956 | 7.225 | 0 | Column | 0.05 | 0.048 | 0121Tra0000009612 | m | S101 | false | HI_STV_HEA_STA_0,100
Verbindungsstück | Wartung_FFB | S235 | SB-STUETZE\ | Stahlprofilstütze | 1 | Verbindungsstück | HEA 100 | 0.582 | Wartung_FFB | 52.05 | 10.69 | 6.956 | 7.225 | 0 | Column | 0.05 | 0.048 | 0121Tra0000009550 | m | S101 | false | HI_STV_HEA_STA_0,100
Verbindungsstück | Wartung_FFB | S235 | SB-STUETZE\ | Stahlprofilstütze | 1 | Verbindungsstück | HEA 100 | 0.582 | Wartung_FFB | 49.05 | 10.69 | 6.956 | 7.225 | 0 | Column | 0.05 | 0.048 | 0121Tra0000009565 | m | S101 | false | HI_STV_HEA_STA_0,100
Verbindungsstück | Wartung_FFB | S235 | SB-STUETZE\ | Stahlprofilstütze | 1 | Verbindungsstück | HEA 100 | 0.582 | Wartung_FFB | 46.05 | 10.69 | 6.956 | 7.225 | 0 | Column | 0.05 | 0.048 | 0121Tra0000009580 | m | S101 | false | HI_STV_HEA_STA_0,100
Verbindungsstück | Wartung_FFB | S235 | SB-STUETZE\ | Stahlprofilstütze | 1 | Verbindungsstück | HEA 100 | 0.582 | Wartung_FFB | 43.05 | 10.69 | 6.956 | 7.225 | 0 | Column | 0.05 | 0.048 | 0121Tra0000009595 | m | S101 | false | HI_STV_HEA_STA_0,100
Verbindungsstück | Wartung_FFB | S235 | SB-STUETZE\ | Stahlprofilstütze | 1 | Verbindungsstück | HEA 100 | 0.582 | Wartung_FFB | 52.05 | 30.1 | 6.956 | 7.225 | 0 | Column | 0.05 | 0.048 | 0121Tra0000009552 | m | S101 | false | HI_STV_HEA_STA_0,100
Verbindungsstück | Wartung_FFB | S235 | SB-STUETZE\ | Stahlprofilstütze | 1 | Verbindungsstück | HEA 100 | 0.582 | Wartung_FFB | 49.05 | 30.1 | 6.956 | 7.225 | 0 | Column | 0.05 | 0.048 | 0121Tra0000009567 | m | S101 | false | HI_STV_HEA_STA_0,100
Verbindungsstück | Wartung_FFB | S235 | SB-STUETZE\ | Stahlprofilstütze | 1 | Verbindungsstück | HEA 100 | 0.582 | Wartung_FFB | 46.05 | 30.1 | 6.956 | 7.225 | 0 | Column | 0.05 | 0.048 | 0121Tra0000009582 | m | S101 | false | HI_STV_HEA_STA_0,100
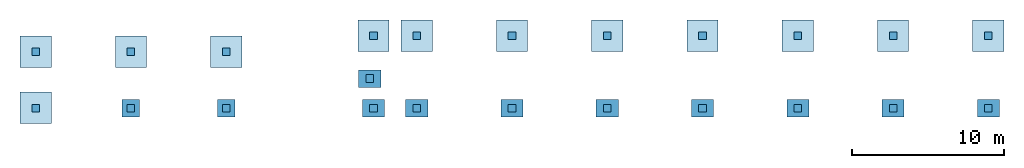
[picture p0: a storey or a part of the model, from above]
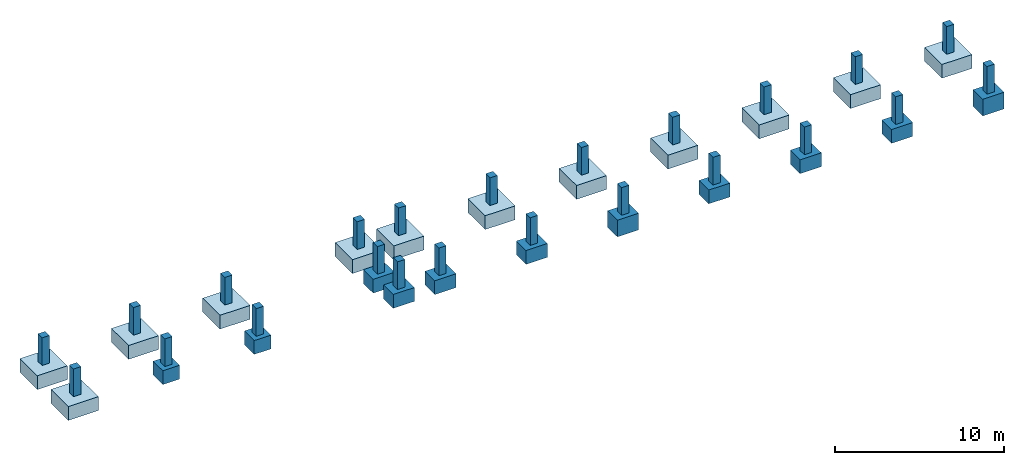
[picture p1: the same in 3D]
Properties of the parts of a building model (IFC2X3), part 11 of 25

# IfcColumn (470)
Name | In | Material = AllplanAttributes, Material | Codetext | Kurztext | Faktor | Bezeichnung = Name | Profilname | Mantelfläche/lfm | Ebene | Achsenstartpunkt (X) (m) = Achsenendpunkt (X) (m) | Achsenstartpunkt (Y) (m) = Achsenendpunkt (Y) (m) | Achsenstartpunkt (Z) (m) | Achsenendpunkt (Z) (m) | Objektdrehwinkel | Attributset-Objekt | Schwerpunkt X (m) | Schwerpunkt Y (m) | Allright_Bauteil_ID | Abrechnungsart | Positionsnummer | Außenbauteil | Reference
Verbindungsstück | Wartung_FFB | S235 | SB-STUETZE\ | Stahlprofilstütze | 1 | Verbindungsstück | HEA 100 | 0.582 | Wartung_FFB | 43.05 | 30.1 | 6.956 | 7.225 | 0 | Column | 0.05 | 0.048 | 0121Tra0000009597 | m | S101 | false | HI_STV_HEA_STA_0,100
Verbindungsstück | Wartung_FFB | S235 | SB-STUETZE\ | Stahlprofilstütze | 1 | Verbindungsstück | HEA 100 | 0.582 | Wartung_FFB | 64.05 | 10.69 | 6.956 | 7.225 | 0 | Column | 0.05 | 0.048 | 0121Tra0000006170 | m | S101 | false | HI_STV_HEA_STA_0,100
Verbindungsstück | Wartung_FFB | S235 | SB-STUETZE\ | Stahlprofilstütze | 1 | Verbindungsstück | HEA 100 | 0.582 | Wartung_FFB | 61.05 | 10.69 | 6.956 | 7.225 | 0 | Column | 0.05 | 0.048 | 0121Tra0000009500 | m | S101 | false | HI_STV_HEA_STA_0,100
Verbindungsstück | Wartung_FFB | S235 | SB-STUETZE\ | Stahlprofilstütze | 1 | Verbindungsstück | HEA 100 | 0.582 | Wartung_FFB | 64.05 | 30.1 | 6.956 | 7.225 | 0 | Column | 0.05 | 0.048 | 0121Tra0000009488 | m | S101 | false | HI_STV_HEA_STA_0,100
Verbindungsstück | Wartung_FFB | S235 | SB-STUETZE\ | Stahlprofilstütze | 1 | Verbindungsstück | HEA 100 | 0.582 | Wartung_FFB | 61.05 | 30.1 | 6.956 | 7.225 | 0 | Column | 0.05 | 0.048 | 0121Tra0000009504 | m | S101 | false | HI_STV_HEA_STA_0,100
Verbindungsstück | Wartung_FFB | S235 | SB-STUETZE\ | Stahlprofilstütze | 1 | Verbindungsstück | HEA 100 | 0.582 | Wartung_FFB | 22.05 | 10.69 | 6.956 | 7.225 | 0 | Column | 0.05 | 0.048 | 0121Tra0000009700 | m | S101 | false | HI_STV_HEA_STA_0,100
Verbindungsstück | Wartung_FFB | S235 | SB-STUETZE\ | Stahlprofilstütze | 1 | Verbindungsstück | HEA 100 | 0.582 | Wartung_FFB | 10.55 | 10.69 | 6.956 | 7.225 | 0 | Column | 0.05 | 0.048 | 0121Tra0000009715 | m | S101 | false | HI_STV_HEA_STA_0,100
Verbindungsstück | Wartung_FFB | S235 | SB-STUETZE\ | Stahlprofilstütze | 1 | Verbindungsstück | HEA 100 | 0.582 | Wartung_FFB | 13.05 | 10.69 | 6.956 | 7.225 | 0 | Column | 0.05 | 0.048 | 0121Tra0000009730 | m | S101 | false | HI_STV_HEA_STA_0,100
Verbindungsstück | Wartung_FFB | S235 | SB-STUETZE\ | Stahlprofilstütze | 1 | Verbindungsstück | HEA 100 | 0.582 | Wartung_FFB | 16.05 | 10.69 | 6.956 | 7.225 | 0 | Column | 0.05 | 0.048 | 0121Tra0000009745 | m | S101 | false | HI_STV_HEA_STA_0,100
Verbindungsstück | Wartung_FFB | S235 | SB-STUETZE\ | Stahlprofilstütze | 1 | Verbindungsstück | HEA 100 | 0.582 | Wartung_FFB | 19.05 | 10.69 | 6.956 | 7.225 | 0 | Column | 0.05 | 0.048 | 0121Tra0000009760 | m | S101 | false | HI_STV_HEA_STA_0,100
Verbindungsstück | Wartung_FFB | S235 | SB-STUETZE\ | Stahlprofilstütze | 1 | Verbindungsstück | HEA 100 | 0.582 | Wartung_FFB | 22.05 | 30.1 | 6.956 | 7.225 | 0 | Column | 0.05 | 0.048 | 0121Tra0000009702 | m | S101 | false | HI_STV_HEA_STA_0,100
Verbindungsstück | Wartung_FFB | S235 | SB-STUETZE\ | Stahlprofilstütze | 1 | Verbindungsstück | HEA 100 | 0.582 | Wartung_FFB | 10.55 | 30.1 | 6.956 | 7.225 | 0 | Column | 0.05 | 0.048 | 0121Tra0000009717 | m | S101 | false | HI_STV_HEA_STA_0,100
Verbindungsstück | Wartung_FFB | S235 | SB-STUETZE\ | Stahlprofilstütze | 1 | Verbindungsstück | HEA 100 | 0.582 | Wartung_FFB | 13.05 | 30.1 | 6.956 | 7.225 | 0 | Column | 0.05 | 0.048 | 0121Tra0000009732 | m | S101 | false | HI_STV_HEA_STA_0,100
Verbindungsstück | Wartung_FFB | S235 | SB-STUETZE\ | Stahlprofilstütze | 1 | Verbindungsstück | HEA 100 | 0.582 | Wartung_FFB | 16.05 | 30.1 | 6.956 | 7.225 | 0 | Column | 0.05 | 0.048 | 0121Tra0000009747 | m | S101 | false | HI_STV_HEA_STA_0,100
Verbindungsstück | Wartung_FFB | S235 | SB-STUETZE\ | Stahlprofilstütze | 1 | Verbindungsstück | HEA 100 | 0.582 | Wartung_FFB | 19.05 | 30.1 | 6.956 | 7.225 | 0 | Column | 0.05 | 0.048 | 0121Tra0000009762 | m | S101 | false | HI_STV_HEA_STA_0,100
Verbindungsstück | Wartung_FFB | S235 | SB-STUETZE\ | Stahlprofilstütze | 1 | Verbindungsstück | HEA 100 | 0.582 | Wartung_FFB | 85.05 | 10.69 | 6.956 | 7.225 | 0 | Column | 0.05 | 0.048 | 0121Tra0000009865 | m | S101 | false | HI_STV_HEA_STA_0,100
Verbindungsstück | Wartung_FFB | S235 | SB-STUETZE\ | Stahlprofilstütze | 1 | Verbindungsstück | HEA 100 | 0.582 | Wartung_FFB | 88.05 | 10.69 | 6.956 | 7.225 | 0 | Column | 0.05 | 0.048 | 0121Tra0000009880 | m | S101 | false | HI_STV_HEA_STA_0,100
Verbindungsstück | Wartung_FFB | S235 | SB-STUETZE\ | Stahlprofilstütze | 1 | Verbindungsstück | HEA 100 | 0.582 | Wartung_FFB | 91.05 | 10.69 | 6.956 | 7.225 | 0 | Column | 0.05 | 0.048 | 0121Tra0000009895 | m | S101 | false | HI_STV_HEA_STA_0,100
Verbindungsstück | Wartung_FFB | S235 | SB-STUETZE\ | Stahlprofilstütze | 1 | Verbindungsstück | HEA 100 | 0.582 | Wartung_FFB | 97.05 | 10.69 | 6.956 | 7.225 | 0 | Column | 0.05 | 0.048 | 0121Tra0000009925 | m | S101 | false | HI_STV_HEA_STA_0,100
Verbindungsstück | Wartung_FFB | S235 | SB-STUETZE\ | Stahlprofilstütze | 1 | Verbindungsstück | HEA 100 | 0.582 | Wartung_FFB | 100.05 | 10.69 | 6.956 | 7.225 | 0 | Column | 0.05 | 0.048 | 0121Tra0000009940 | m | S101 | false | HI_STV_HEA_STA_0,100
Verbindungsstück | Wartung_FFB | S235 | SB-STUETZE\ | Stahlprofilstütze | 1 | Verbindungsstück | HEA 100 | 0.582 | Wartung_FFB | 103.05 | 10.69 | 6.956 | 7.225 | 0 | Column | 0.05 | 0.048 | 0121Tra0000009955 | m | S101 | false | HI_STV_HEA_STA_0,100
Verbindungsstück | Wartung_FFB | S235 | SB-STUETZE\ | Stahlprofilstütze | 1 | Verbindungsstück | HEA 100 | 0.582 | Wartung_FFB | 106.05 | 10.69 | 6.956 | 7.225 | 0 | Column | 0.05 | 0.048 | 0121Tra0000009970 | m | S101 | false | HI_STV_HEA_STA_0,100
Verbindungsstück | Wartung_FFB | S235 | SB-STUETZE\ | Stahlprofilstütze | 1 | Verbindungsstück | HEA 100 | 0.582 | Wartung_FFB | 109.05 | 10.69 | 6.956 | 7.225 | 0 | Column | 0.05 | 0.048 | 0121Tra0000009985 | m | S101 | false | HI_STV_HEA_STA_0,100
Verbindungsstück | Wartung_FFB | S235 | SB-STUETZE\ | Stahlprofilstütze | 1 | Verbindungsstück | HEA 100 | 0.582 | Wartung_FFB | 112.05 | 10.69 | 6.956 | 7.225 | 0 | Column | 0.05 | 0.048 | 0121Tra0000010000 | m | S101 | false | HI_STV_HEA_STA_0,100
Verbindungsstück | Wartung_FFB | S235 | SB-STUETZE\ | Stahlprofilstütze | 1 | Verbindungsstück | HEA 100 | 0.582 | Wartung_FFB | 115.05 | 10.69 | 6.956 | 7.225 | 0 | Column | 0.05 | 0.048 | 0121Tra0000010015 | m | S101 | false | HI_STV_HEA_STA_0,100
Verbindungsstück | Wartung_FFB | S235 | SB-STUETZE\ | Stahlprofilstütze | 1 | Verbindungsstück | HEA 100 | 0.582 | Wartung_FFB | 118.05 | 10.69 | 6.956 | 7.225 | 0 | Column | 0.05 | 0.048 | 0121Tra0000010030 | m | S101 | false | HI_STV_HEA_STA_0,100
Verbindungsstück | Wartung_FFB | S235 | SB-STUETZE\ | Stahlprofilstütze | 1 | Verbindungsstück | HEA 100 | 0.582 | Wartung_FFB | 121.05 | 10.69 | 6.956 | 7.225 | 0 | Column | 0.05 | 0.048 | 0121Tra0000010045 | m | S101 | false | HI_STV_HEA_STA_0,100
Verbindungsstück | Wartung_FFB | S235 | SB-STUETZE\ | Stahlprofilstütze | 1 | Verbindungsstück | HEA 100 | 0.582 | Wartung_FFB | 85.05 | 30.1 | 6.956 | 7.225 | 0 | Column | 0.05 | 0.048 | 0121Tra0000009867 | m | S101 | false | HI_STV_HEA_STA_0,100
Verbindungsstück | Wartung_FFB | S235 | SB-STUETZE\ | Stahlprofilstütze | 1 | Verbindungsstück | HEA 100 | 0.582 | Wartung_FFB | 88.05 | 30.1 | 6.956 | 7.225 | 0 | Column | 0.05 | 0.048 | 0121Tra0000009882 | m | S101 | false | HI_STV_HEA_STA_0,100
Verbindungsstück | Wartung_FFB | S235 | SB-STUETZE\ | Stahlprofilstütze | 1 | Verbindungsstück | HEA 100 | 0.582 | Wartung_FFB | 91.05 | 30.1 | 6.956 | 7.225 | 0 | Column | 0.05 | 0.048 | 0121Tra0000009897 | m | S101 | false | HI_STV_HEA_STA_0,100
Verbindungsstück | Wartung_FFB | S235 | SB-STUETZE\ | Stahlprofilstütze | 1 | Verbindungsstück | HEA 100 | 0.582 | Wartung_FFB | 97.05 | 30.1 | 6.956 | 7.225 | 0 | Column | 0.05 | 0.048 | 0121Tra0000009927 | m | S101 | false | HI_STV_HEA_STA_0,100
Verbindungsstück | Wartung_FFB | S235 | SB-STUETZE\ | Stahlprofilstütze | 1 | Verbindungsstück | HEA 100 | 0.582 | Wartung_FFB | 100.05 | 30.1 | 6.956 | 7.225 | 0 | Column | 0.05 | 0.048 | 0121Tra0000009942 | m | S101 | false | HI_STV_HEA_STA_0,100
Verbindungsstück | Wartung_FFB | S235 | SB-STUETZE\ | Stahlprofilstütze | 1 | Verbindungsstück | HEA 100 | 0.582 | Wartung_FFB | 103.05 | 30.1 | 6.956 | 7.225 | 0 | Column | 0.05 | 0.048 | 0121Tra0000009957 | m | S101 | false | HI_STV_HEA_STA_0,100
Verbindungsstück | Wartung_FFB | S235 | SB-STUETZE\ | Stahlprofilstütze | 1 | Verbindungsstück | HEA 100 | 0.582 | Wartung_FFB | 106.05 | 30.1 | 6.956 | 7.225 | 0 | Column | 0.05 | 0.048 | 0121Tra0000009972 | m | S101 | false | HI_STV_HEA_STA_0,100
Verbindungsstück | Wartung_FFB | S235 | SB-STUETZE\ | Stahlprofilstütze | 1 | Verbindungsstück | HEA 100 | 0.582 | Wartung_FFB | 109.05 | 30.1 | 6.956 | 7.225 | 0 | Column | 0.05 | 0.048 | 0121Tra0000009987 | m | S101 | false | HI_STV_HEA_STA_0,100
Verbindungsstück | Wartung_FFB | S235 | SB-STUETZE\ | Stahlprofilstütze | 1 | Verbindungsstück | HEA 100 | 0.582 | Wartung_FFB | 112.05 | 30.1 | 6.956 | 7.225 | 0 | Column | 0.05 | 0.048 | 0121Tra0000010002 | m | S101 | false | HI_STV_HEA_STA_0,100
Verbindungsstück | Wartung_FFB | S235 | SB-STUETZE\ | Stahlprofilstütze | 1 | Verbindungsstück | HEA 100 | 0.582 | Wartung_FFB | 115.05 | 30.1 | 6.956 | 7.225 | 0 | Column | 0.05 | 0.048 | 0121Tra0000010017 | m | S101 | false | HI_STV_HEA_STA_0,100
Verbindungsstück | Wartung_FFB | S235 | SB-STUETZE\ | Stahlprofilstütze | 1 | Verbindungsstück | HEA 100 | 0.582 | Wartung_FFB | 118.05 | 30.1 | 6.956 | 7.225 | 0 | Column | 0.05 | 0.048 | 0121Tra0000010032 | m | S101 | false | HI_STV_HEA_STA_0,100
Verbindungsstück | Wartung_FFB | S235 | SB-STUETZE\ | Stahlprofilstütze | 1 | Verbindungsstück | HEA 100 | 0.582 | Wartung_FFB | 121.05 | 30.1 | 6.956 | 7.225 | 0 | Column | 0.05 | 0.048 | 0121Tra0000010047 | m | S101 | false | HI_STV_HEA_STA_0,100
Verbindungsstück | Wartung_FFB | S235 | SB-STUETZE\ | Stahlprofilstütze | 1 | Verbindungsstück | HEA 100 | 0.582 | Wartung_FFB | 94.7 | 10.69 | 6.956 | 7.225 | 0 | Column | 0.05 | 0.048 | 0121Tra0000009910 | m | S101 | false | HI_STV_HEA_STA_0,100
Verbindungsstück | Wartung_FFB | S235 | SB-STUETZE\ | Stahlprofilstütze | 1 | Verbindungsstück | HEA 100 | 0.582 | Wartung_FFB | 94.7 | 30.1 | 6.956 | 7.225 | 0 | Column | 0.05 | 0.048 | 0121Tra0000009912 | m | S101 | false | HI_STV_HEA_STA_0,100
Verbindungsstück | Wartung_FFB | S235 | SB-STUETZE\ | Stahlprofilstütze | 1 | Verbindungsstück | HEA 100 | 0.582 | Wartung_FFB | 64.05 | 31.5 | 6.956 | 7.225 | 0 | Column | 0.05 | 0.048 | 0121Tra0000009492 | m | S101 | false | HI_STV_HEA_STA_0,100
Verbindungsstück | Wartung_FFB | S235 | SB-STUETZE\ | Stahlprofilstütze | 1 | Verbindungsstück | HEA 100 | 0.582 | Wartung_FFB | 61.05 | 31.5 | 6.956 | 7.225 | 0 | Column | 0.05 | 0.048 | 0121Tra0000009507 | m | S101 | false | HI_STV_HEA_STA_0,100
Verbindungsstück | Wartung_FFB | S235 | SB-STUETZE\ | Stahlprofilstütze | 1 | Verbindungsstück | HEA 100 | 0.582 | Wartung_FFB | 58.05 | 31.5 | 6.956 | 7.225 | 0 | Column | 0.05 | 0.048 | 0121Tra0000009524 | m | S101 | false | HI_STV_HEA_STA_0,100
Verbindungsstück | Wartung_FFB | S235 | SB-STUETZE\ | Stahlprofilstütze | 1 | Verbindungsstück | HEA 100 | 0.582 | Wartung_FFB | 55.05 | 31.5 | 6.956 | 7.225 | 0 | Column | 0.05 | 0.048 | 0121Tra0000009539 | m | S101 | false | HI_STV_HEA_STA_0,100
Verbindungsstück | Wartung_FFB | S235 | SB-STUETZE\ | Stahlprofilstütze | 1 | Verbindungsstück | HEA 100 | 0.582 | Wartung_FFB | 52.05 | 31.5 | 6.956 | 7.225 | 0 | Column | 0.05 | 0.048 | 0121Tra0000009554 | m | S101 | false | HI_STV_HEA_STA_0,100
Verbindungsstück | Wartung_FFB | S235 | SB-STUETZE\ | Stahlprofilstütze | 1 | Verbindungsstück | HEA 100 | 0.582 | Wartung_FFB | 49.05 | 31.5 | 6.956 | 7.225 | 0 | Column | 0.05 | 0.048 | 0121Tra0000009569 | m | S101 | false | HI_STV_HEA_STA_0,100
Verbindungsstück | Wartung_FFB | S235 | SB-STUETZE\ | Stahlprofilstütze | 1 | Verbindungsstück | HEA 100 | 0.582 | Wartung_FFB | 43.05 | 31.5 | 6.956 | 7.225 | 0 | Column | 0.05 | 0.048 | 0121Tra0000009599 | m | S101 | false | HI_STV_HEA_STA_0,100
Verbindungsstück | Wartung_FFB | S235 | SB-STUETZE\ | Stahlprofilstütze | 1 | Verbindungsstück | HEA 100 | 0.582 | Wartung_FFB | 40.05 | 31.5 | 6.956 | 7.225 | 0 | Column | 0.05 | 0.048 | 0121Tra0000009614 | m | S101 | false | HI_STV_HEA_STA_0,100
Verbindungsstück | Wartung_FFB | S235 | SB-STUETZE\ | Stahlprofilstütze | 1 | Verbindungsstück | HEA 100 | 0.582 | Wartung_FFB | 37.05 | 31.5 | 6.956 | 7.225 | 0 | Column | 0.05 | 0.048 | 0121Tra0000009629 | m | S101 | false | HI_STV_HEA_STA_0,100
Verbindungsstück | Wartung_FFB | S235 | SB-STUETZE\ | Stahlprofilstütze | 1 | Verbindungsstück | HEA 100 | 0.582 | Wartung_FFB | 34.05 | 31.5 | 6.956 | 7.225 | 0 | Column | 0.05 | 0.048 | 0121Tra0000009644 | m | S101 | false | HI_STV_HEA_STA_0,100
Verbindungsstück | Wartung_FFB | S235 | SB-STUETZE\ | Stahlprofilstütze | 1 | Verbindungsstück | HEA 100 | 0.582 | Wartung_FFB | 28.05 | 31.5 | 6.956 | 7.225 | 0 | Column | 0.05 | 0.048 | 0121Tra0000009674 | m | S101 | false | HI_STV_HEA_STA_0,100
Verbindungsstück | Wartung_FFB | S235 | SB-STUETZE\ | Stahlprofilstütze | 1 | Verbindungsstück | HEA 100 | 0.582 | Wartung_FFB | 22.05 | 31.5 | 6.956 | 7.225 | 0 | Column | 0.05 | 0.048 | 0121Tra0000009704 | m | S101 | false | HI_STV_HEA_STA_0,100
Verbindungsstück | Wartung_FFB | S235 | SB-STUETZE\ | Stahlprofilstütze | 1 | Verbindungsstück | HEA 100 | 0.582 | Wartung_FFB | 10.55 | 31.5 | 6.956 | 7.225 | 0 | Column | 0.05 | 0.048 | 0121Tra0000009719 | m | S101 | false | HI_STV_HEA_STA_0,100
Verbindungsstück | Wartung_FFB | S235 | SB-STUETZE\ | Stahlprofilstütze | 1 | Verbindungsstück | HEA 100 | 0.582 | Wartung_FFB | 13.05 | 31.5 | 6.956 | 7.225 | 0 | Column | 0.05 | 0.048 | 0121Tra0000009734 | m | S101 | false | HI_STV_HEA_STA_0,100
Verbindungsstück | Wartung_FFB | S235 | SB-STUETZE\ | Stahlprofilstütze | 1 | Verbindungsstück | HEA 100 | 0.582 | Wartung_FFB | 16.05 | 31.5 | 6.956 | 7.225 | 0 | Column | 0.05 | 0.048 | 0121Tra0000009749 | m | S101 | false | HI_STV_HEA_STA_0,100
Verbindungsstück | Wartung_FFB | S235 | SB-STUETZE\ | Stahlprofilstütze | 1 | Verbindungsstück | HEA 100 | 0.582 | Wartung_FFB | 19.05 | 31.5 | 6.956 | 7.225 | 0 | Column | 0.05 | 0.048 | 0121Tra0000009764 | m | S101 | false | HI_STV_HEA_STA_0,100
Verbindungsstück | Wartung_FFB | S235 | SB-STUETZE\ | Stahlprofilstütze | 1 | Verbindungsstück | HEA 100 | 0.582 | Wartung_FFB | 67.05 | 31.5 | 6.956 | 7.225 | 0 | Column | 0.05 | 0.048 | 0121Tra0000009779 | m | S101 | false | HI_STV_HEA_STA_0,100
Verbindungsstück | Wartung_FFB | S235 | SB-STUETZE\ | Stahlprofilstütze | 1 | Verbindungsstück | HEA 100 | 0.582 | Wartung_FFB | 64.05 | 50.9 | 6.956 | 7.225 | 0 | Column | 0.05 | 0.048 | 0121Tra0000009495 | m | S101 | false | HI_STV_HEA_STA_0,100
Verbindungsstück | Wartung_FFB | S235 | SB-STUETZE\ | Stahlprofilstütze | 1 | Verbindungsstück | HEA 100 | 0.582 | Wartung_FFB | 61.05 | 50.9 | 6.956 | 7.225 | 0 | Column | 0.05 | 0.048 | 0121Tra0000009510 | m | S101 | false | HI_STV_HEA_STA_0,100
Verbindungsstück | Wartung_FFB | S235 | SB-STUETZE\ | Stahlprofilstütze | 1 | Verbindungsstück | HEA 100 | 0.582 | Wartung_FFB | 61.05 | 52.3 | 6.956 | 7.225 | 0 | Column | 0.05 | 0.048 | 0121Tra0000009513 | m | S101 | false | HI_STV_HEA_STA_0,100
Verbindungsstück | Wartung_FFB | S235 | SB-STUETZE\ | Stahlprofilstütze | 1 | Verbindungsstück | HEA 100 | 0.582 | Wartung_FFB | 58.05 | 50.9 | 6.956 | 7.225 | 0 | Column | 0.05 | 0.048 | 0121Tra0000009526 | m | S101 | false | HI_STV_HEA_STA_0,100
Verbindungsstück | Wartung_FFB | S235 | SB-STUETZE\ | Stahlprofilstütze | 1 | Verbindungsstück | HEA 100 | 0.582 | Wartung_FFB | 58.05 | 52.3 | 6.956 | 7.225 | 0 | Column | 0.05 | 0.048 | 0121Tra0000009528 | m | S101 | false | HI_STV_HEA_STA_0,100
Verbindungsstück | Wartung_FFB | S235 | SB-STUETZE\ | Stahlprofilstütze | 1 | Verbindungsstück | HEA 100 | 0.582 | Wartung_FFB | 55.05 | 50.9 | 6.956 | 7.225 | 0 | Column | 0.05 | 0.048 | 0121Tra0000009541 | m | S101 | false | HI_STV_HEA_STA_0,100
Verbindungsstück | Wartung_FFB | S235 | SB-STUETZE\ | Stahlprofilstütze | 1 | Verbindungsstück | HEA 100 | 0.582 | Wartung_FFB | 55.05 | 52.3 | 6.956 | 7.225 | 0 | Column | 0.05 | 0.048 | 0121Tra0000009543 | m | S101 | false | HI_STV_HEA_STA_0,100
Verbindungsstück | Wartung_FFB | S235 | SB-STUETZE\ | Stahlprofilstütze | 1 | Verbindungsstück | HEA 100 | 0.582 | Wartung_FFB | 52.05 | 50.9 | 6.956 | 7.225 | 0 | Column | 0.05 | 0.048 | 0121Tra0000009556 | m | S101 | false | HI_STV_HEA_STA_0,100
Verbindungsstück | Wartung_FFB | S235 | SB-STUETZE\ | Stahlprofilstütze | 1 | Verbindungsstück | HEA 100 | 0.582 | Wartung_FFB | 52.05 | 52.3 | 6.956 | 7.225 | 0 | Column | 0.05 | 0.048 | 0121Tra0000009558 | m | S101 | false | HI_STV_HEA_STA_0,100
Verbindungsstück | Wartung_FFB | S235 | SB-STUETZE\ | Stahlprofilstütze | 1 | Verbindungsstück | HEA 100 | 0.582 | Wartung_FFB | 49.05 | 50.9 | 6.956 | 7.225 | 0 | Column | 0.05 | 0.048 | 0121Tra0000009571 | m | S101 | false | HI_STV_HEA_STA_0,100
Verbindungsstück | Wartung_FFB | S235 | SB-STUETZE\ | Stahlprofilstütze | 1 | Verbindungsstück | HEA 100 | 0.582 | Wartung_FFB | 49.05 | 52.3 | 6.956 | 7.225 | 0 | Column | 0.05 | 0.048 | 0121Tra0000009573 | m | S101 | false | HI_STV_HEA_STA_0,100
Verbindungsstück | Wartung_FFB | S235 | SB-STUETZE\ | Stahlprofilstütze | 1 | Verbindungsstück | HEA 100 | 0.582 | Wartung_FFB | 43.05 | 50.9 | 6.956 | 7.225 | 0 | Column | 0.05 | 0.048 | 0121Tra0000009601 | m | S101 | false | HI_STV_HEA_STA_0,100
Verbindungsstück | Wartung_FFB | S235 | SB-STUETZE\ | Stahlprofilstütze | 1 | Verbindungsstück | HEA 100 | 0.582 | Wartung_FFB | 43.05 | 52.3 | 6.956 | 7.225 | 0 | Column | 0.05 | 0.048 | 0121Tra0000009603 | m | S101 | false | HI_STV_HEA_STA_0,100
Verbindungsstück | Wartung_FFB | S235 | SB-STUETZE\ | Stahlprofilstütze | 1 | Verbindungsstück | HEA 100 | 0.582 | Wartung_FFB | 40.05 | 50.9 | 6.956 | 7.225 | 0 | Column | 0.05 | 0.048 | 0121Tra0000009616 | m | S101 | false | HI_STV_HEA_STA_0,100
Verbindungsstück | Wartung_FFB | S235 | SB-STUETZE\ | Stahlprofilstütze | 1 | Verbindungsstück | HEA 100 | 0.582 | Wartung_FFB | 40.05 | 52.3 | 6.956 | 7.225 | 0 | Column | 0.05 | 0.048 | 0121Tra0000009618 | m | S101 | false | HI_STV_HEA_STA_0,100
Verbindungsstück | Wartung_FFB | S235 | SB-STUETZE\ | Stahlprofilstütze | 1 | Verbindungsstück | HEA 100 | 0.582 | Wartung_FFB | 37.05 | 50.9 | 6.956 | 7.225 | 0 | Column | 0.05 | 0.048 | 0121Tra0000009631 | m | S101 | false | HI_STV_HEA_STA_0,100
Verbindungsstück | Wartung_FFB | S235 | SB-STUETZE\ | Stahlprofilstütze | 1 | Verbindungsstück | HEA 100 | 0.582 | Wartung_FFB | 37.05 | 52.3 | 6.956 | 7.225 | 0 | Column | 0.05 | 0.048 | 0121Tra0000009633 | m | S101 | false | HI_STV_HEA_STA_0,100
Verbindungsstück | Wartung_FFB | S235 | SB-STUETZE\ | Stahlprofilstütze | 1 | Verbindungsstück | HEA 100 | 0.582 | Wartung_FFB | 34.05 | 50.9 | 6.956 | 7.225 | 0 | Column | 0.05 | 0.048 | 0121Tra0000009646 | m | S101 | false | HI_STV_HEA_STA_0,100
Verbindungsstück | Wartung_FFB | S235 | SB-STUETZE\ | Stahlprofilstütze | 1 | Verbindungsstück | HEA 100 | 0.582 | Wartung_FFB | 34.05 | 52.3 | 6.956 | 7.225 | 0 | Column | 0.05 | 0.048 | 0121Tra0000009648 | m | S101 | false | HI_STV_HEA_STA_0,100
Verbindungsstück | Wartung_FFB | S235 | SB-STUETZE\ | Stahlprofilstütze | 1 | Verbindungsstück | HEA 100 | 0.582 | Wartung_FFB | 28.05 | 50.9 | 6.956 | 7.225 | 0 | Column | 0.05 | 0.048 | 0121Tra0000009676 | m | S101 | false | HI_STV_HEA_STA_0,100
Verbindungsstück | Wartung_FFB | S235 | SB-STUETZE\ | Stahlprofilstütze | 1 | Verbindungsstück | HEA 100 | 0.582 | Wartung_FFB | 28.05 | 52.3 | 6.956 | 7.225 | 0 | Column | 0.05 | 0.048 | 0121Tra0000009678 | m | S101 | false | HI_STV_HEA_STA_0,100
Verbindungsstück | Wartung_FFB | S235 | SB-STUETZE\ | Stahlprofilstütze | 1 | Verbindungsstück | HEA 100 | 0.582 | Wartung_FFB | 22.05 | 50.9 | 6.956 | 7.225 | 0 | Column | 0.05 | 0.048 | 0121Tra0000009706 | m | S101 | false | HI_STV_HEA_STA_0,100
Verbindungsstück | Wartung_FFB | S235 | SB-STUETZE\ | Stahlprofilstütze | 1 | Verbindungsstück | HEA 100 | 0.582 | Wartung_FFB | 22.05 | 52.3 | 6.956 | 7.225 | 0 | Column | 0.05 | 0.048 | 0121Tra0000009708 | m | S101 | false | HI_STV_HEA_STA_0,100
Verbindungsstück | Wartung_FFB | S235 | SB-STUETZE\ | Stahlprofilstütze | 1 | Verbindungsstück | HEA 100 | 0.582 | Wartung_FFB | 10.55 | 50.9 | 6.956 | 7.225 | 0 | Column | 0.05 | 0.048 | 0121Tra0000009721 | m | S101 | false | HI_STV_HEA_STA_0,100
Verbindungsstück | Wartung_FFB | S235 | SB-STUETZE\ | Stahlprofilstütze | 1 | Verbindungsstück | HEA 100 | 0.582 | Wartung_FFB | 10.55 | 52.3 | 6.956 | 7.225 | 0 | Column | 0.05 | 0.048 | 0121Tra0000009723 | m | S101 | false | HI_STV_HEA_STA_0,100
Verbindungsstück | Wartung_FFB | S235 | SB-STUETZE\ | Stahlprofilstütze | 1 | Verbindungsstück | HEA 100 | 0.582 | Wartung_FFB | 13.05 | 50.9 | 6.956 | 7.225 | 0 | Column | 0.05 | 0.048 | 0121Tra0000009736 | m | S101 | false | HI_STV_HEA_STA_0,100
Verbindungsstück | Wartung_FFB | S235 | SB-STUETZE\ | Stahlprofilstütze | 1 | Verbindungsstück | HEA 100 | 0.582 | Wartung_FFB | 13.05 | 52.3 | 6.956 | 7.225 | 0 | Column | 0.05 | 0.048 | 0121Tra0000009738 | m | S101 | false | HI_STV_HEA_STA_0,100
Verbindungsstück | Wartung_FFB | S235 | SB-STUETZE\ | Stahlprofilstütze | 1 | Verbindungsstück | HEA 100 | 0.582 | Wartung_FFB | 16.05 | 50.9 | 6.956 | 7.225 | 0 | Column | 0.05 | 0.048 | 0121Tra0000009751 | m | S101 | false | HI_STV_HEA_STA_0,100
Verbindungsstück | Wartung_FFB | S235 | SB-STUETZE\ | Stahlprofilstütze | 1 | Verbindungsstück | HEA 100 | 0.582 | Wartung_FFB | 16.05 | 52.3 | 6.956 | 7.225 | 0 | Column | 0.05 | 0.048 | 0121Tra0000009753 | m | S101 | false | HI_STV_HEA_STA_0,100
Verbindungsstück | Wartung_FFB | S235 | SB-STUETZE\ | Stahlprofilstütze | 1 | Verbindungsstück | HEA 100 | 0.582 | Wartung_FFB | 19.05 | 50.9 | 6.956 | 7.225 | 0 | Column | 0.05 | 0.048 | 0121Tra0000009766 | m | S101 | false | HI_STV_HEA_STA_0,100
Verbindungsstück | Wartung_FFB | S235 | SB-STUETZE\ | Stahlprofilstütze | 1 | Verbindungsstück | HEA 100 | 0.582 | Wartung_FFB | 19.05 | 52.3 | 6.956 | 7.225 | 0 | Column | 0.05 | 0.048 | 0121Tra0000009768 | m | S101 | false | HI_STV_HEA_STA_0,100
Verbindungsstück | Wartung_FFB | S235 | SB-STUETZE\ | Stahlprofilstütze | 1 | Verbindungsstück | HEA 100 | 0.582 | Wartung_FFB | 67.05 | 50.9 | 6.956 | 7.225 | 0 | Column | 0.05 | 0.048 | 0121Tra0000009781 | m | S101 | false | HI_STV_HEA_STA_0,100
Verbindungsstück | Wartung_FFB | S235 | SB-STUETZE\ | Stahlprofilstütze | 1 | Verbindungsstück | HEA 100 | 0.582 | Wartung_FFB | 67.05 | 52.3 | 6.956 | 7.225 | 0 | Column | 0.05 | 0.048 | 0121Tra0000009783 | m | S101 | false | HI_STV_HEA_STA_0,100
Verbindungsstück | Wartung_FFB | S235 | SB-STUETZE\ | Stahlprofilstütze | 1 | Verbindungsstück | HEA 100 | 0.582 | Wartung_FFB | 70.05 | 52.3 | 6.956 | 7.225 | 0 | Column | 0.05 | 0.048 | 0121Tra0000009798 | m | S101 | false | HI_STV_HEA_STA_0,100
Verbindungsstück | Wartung_FFB | S235 | SB-STUETZE\ | Stahlprofilstütze | 1 | Verbindungsstück | HEA 100 | 0.582 | Wartung_FFB | 73.05 | 52.3 | 6.956 | 7.225 | 0 | Column | 0.05 | 0.048 | 0121Tra0000009813 | m | S101 | false | HI_STV_HEA_STA_0,100
Verbindungsstück | Wartung_FFB | S235 | SB-STUETZE\ | Stahlprofilstütze | 1 | Verbindungsstück | HEA 100 | 0.582 | Wartung_FFB | 76.05 | 52.3 | 6.956 | 7.225 | 0 | Column | 0.05 | 0.048 | 0121Tra0000009828 | m | S101 | false | HI_STV_HEA_STA_0,100
Verbindungsstück | Wartung_FFB | S235 | SB-STUETZE\ | Stahlprofilstütze | 1 | Verbindungsstück | HEA 100 | 0.582 | Wartung_FFB | 79.05 | 52.3 | 6.956 | 7.225 | 0 | Column | 0.05 | 0.048 | 0121Tra0000009843 | m | S101 | false | HI_STV_HEA_STA_0,100
Verbindungsstück | Wartung_FFB | S235 | SB-STUETZE\ | Stahlprofilstütze | 1 | Verbindungsstück | HEA 100 | 0.582 | Wartung_FFB | 97.05 | 52.3 | 6.956 | 7.225 | 0 | Column | 0.05 | 0.048 | 0121Tra0000009933 | m | S101 | false | HI_STV_HEA_STA_0,100
Verbindungsstück | Wartung_FFB | S235 | SB-STUETZE\ | Stahlprofilstütze | 1 | Verbindungsstück | HEA 100 | 0.582 | Wartung_FFB | 103.05 | 52.3 | 6.956 | 7.225 | 0 | Column | 0.05 | 0.048 | 0121Tra0000009963 | m | S101 | false | HI_STV_HEA_STA_0,100
Verbindungsstück | Wartung_FFB | S235 | SB-STUETZE\ | Stahlprofilstütze | 1 | Verbindungsstück | HEA 100 | 0.582 | Wartung_FFB | 106.05 | 52.3 | 6.956 | 7.225 | 0 | Column | 0.05 | 0.048 | 0121Tra0000009978 | m | S101 | false | HI_STV_HEA_STA_0,100
Verbindungsstück | Wartung_FFB | S235 | SB-STUETZE\ | Stahlprofilstütze | 1 | Verbindungsstück | HEA 100 | 0.582 | Wartung_FFB | 109.05 | 52.3 | 6.956 | 7.225 | 0 | Column | 0.05 | 0.048 | 0121Tra0000009993 | m | S101 | false | HI_STV_HEA_STA_0,100
Verbindungsstück | Wartung_FFB | S235 | SB-STUETZE\ | Stahlprofilstütze | 1 | Verbindungsstück | HEA 100 | 0.582 | Wartung_FFB | 112.05 | 52.3 | 6.956 | 7.225 | 0 | Column | 0.05 | 0.048 | 0121Tra0000010008 | m | S101 | false | HI_STV_HEA_STA_0,100
Verbindungsstück | Wartung_FFB | S235 | SB-STUETZE\ | Stahlprofilstütze | 1 | Verbindungsstück | HEA 100 | 0.582 | Wartung_FFB | 115.05 | 52.3 | 6.956 | 7.225 | 0 | Column | 0.05 | 0.048 | 0121Tra0000010023 | m | S101 | false | HI_STV_HEA_STA_0,100
Verbindungsstück | Wartung_FFB | S235 | SB-STUETZE\ | Stahlprofilstütze | 1 | Verbindungsstück | HEA 100 | 0.582 | Wartung_FFB | 118.05 | 52.3 | 6.956 | 7.225 | 0 | Column | 0.05 | 0.048 | 0121Tra0000010038 | m | S101 | false | HI_STV_HEA_STA_0,100
Verbindungsstück | Wartung_FFB | S235 | SB-STUETZE\ | Stahlprofilstütze | 1 | Verbindungsstück | HEA 100 | 0.582 | Wartung_FFB | 64.05 | 52.3 | 6.956 | 7.225 | 0 | Column | 0.05 | 0.048 | 0121Tra0000009498 | m | S101 | false | HI_STV_HEA_STA_0,100
Verbindungsstück | Wartung_FFB | S235 | SB-STUETZE\ | Stahlprofilstütze | 1 | Verbindungsstück | HEA 100 | 0.582 | Wartung_FFB | 32.25 | 31.5 | 6.956 | 7.225 | 0 | Column | 0.05 | 0.048 | 0121Tra0000013960 | m | S101 | false | HI_STV_HEA_STA_0,100
Verbindungsstück | Wartung_FFB | S235 | SB-STUETZE\ | Stahlprofilstütze | 1 | Verbindungsstück | HEA 100 | 0.582 | Wartung_FFB | 32.25 | 50.9 | 6.956 | 7.225 | 0 | Column | 0.05 | 0.048 | 0121Tra0000013962 | m | S101 | false | HI_STV_HEA_STA_0,100
Verbindungsstück | Wartung_FFB | S235 | SB-STUETZE\ | Stahlprofilstütze | 1 | Verbindungsstück | HEA 100 | 0.582 | Wartung_FFB | 22.05 | 69.902 | 6.956 | 7.525 | 0 | Column | 0.05 | 0.048 | 0121Tra0000004931 | m | S101 | false | HI_STV_HEA_STA_0,100
Verbindungsstück | Wartung_FFB | S235 | SB-STUETZE\ | Stahlprofilstütze | 1 | Verbindungsstück | HEA 100 | 0.582 | Wartung_FFB | 16.05 | 69.902 | 6.956 | 7.525 | 0 | Column | 0.05 | 0.048 | 0121Tra0000011385 | m | S101 | false | HI_STV_HEA_STA_0,100
Verbindungsstück | Wartung_FFB | S235 | SB-STUETZE\ | Stahlprofilstütze | 1 | Verbindungsstück | HEA 100 | 0.582 | Wartung_FFB | 13.05 | 69.902 | 6.956 | 7.525 | 0 | Column | 0.05 | 0.048 | 0121Tra0000011388 | m | S101 | false | HI_STV_HEA_STA_0,100
Verbindungsstück | Wartung_FFB | S235 | SB-STUETZE\ | Stahlprofilstütze | 1 | Verbindungsstück | HEA 100 | 0.582 | Wartung_FFB | 10.55 | 69.902 | 6.956 | 7.525 | 0 | Column | 0.05 | 0.048 | 0121Tra0000011391 | m | S101 | false | HI_STV_HEA_STA_0,100
Verbindungsstück | Wartung_FFB | S235 | SB-STUETZE\ | Stahlprofilstütze | 1 | Verbindungsstück | HEA 100 | 0.582 | Wartung_FFB | 22.05 | 70.902 | 6.956 | 7.525 | 0 | Column | 0.05 | 0.048 | 0121Tra0000011405 | m | S101 | false | HI_STV_HEA_STA_0,100
Verbindungsstück | Wartung_FFB | S235 | SB-STUETZE\ | Stahlprofilstütze | 1 | Verbindungsstück | HEA 100 | 0.582 | Wartung_FFB | 16.05 | 70.902 | 6.956 | 7.525 | 0 | Column | 0.05 | 0.048 | 0121Tra0000011412 | m | S101 | false | HI_STV_HEA_STA_0,100
Verbindungsstück | Wartung_FFB | S235 | SB-STUETZE\ | Stahlprofilstütze | 1 | Verbindungsstück | HEA 100 | 0.582 | Wartung_FFB | 13.05 | 70.902 | 6.956 | 7.525 | 0 | Column | 0.05 | 0.048 | 0121Tra0000011415 | m | S101 | false | HI_STV_HEA_STA_0,100
Verbindungsstück | Wartung_FFB | S235 | SB-STUETZE\ | Stahlprofilstütze | 1 | Verbindungsstück | HEA 100 | 0.582 | Wartung_FFB | 10.55 | 70.902 | 6.956 | 7.525 | 0 | Column | 0.05 | 0.048 | 0121Tra0000011418 | m | S101 | false | HI_STV_HEA_STA_0,100
Verbindungsstück | Wartung_FFB | S235 | SB-STUETZE\ | Stahlprofilstütze | 1 | Verbindungsstück | HEA 100 | 0.582 | Wartung_FFB | 64.05 | 70.902 | 6.956 | 7.895 | 0 | Column | 0.05 | 0.048 | 0121Tra0000011491 | m | S101 | false | HI_STV_HEA_STA_0,100
Verbindungsstück | Wartung_FFB | S235 | SB-STUETZE\ | Stahlprofilstütze | 1 | Verbindungsstück | HEA 100 | 0.582 | Wartung_FFB | 61.05 | 70.902 | 6.956 | 7.895 | 0 | Column | 0.05 | 0.048 | 0121Tra0000011493 | m | S101 | false | HI_STV_HEA_STA_0,100
Verbindungsstück | Wartung_FFB | S235 | SB-STUETZE\ | Stahlprofilstütze | 1 | Verbindungsstück | HEA 100 | 0.582 | Wartung_FFB | 58.05 | 70.902 | 6.956 | 7.895 | 0 | Column | 0.05 | 0.048 | 0121Tra0000011495 | m | S101 | false | HI_STV_HEA_STA_0,100
Verbindungsstück | Wartung_FFB | S235 | SB-STUETZE\ | Stahlprofilstütze | 1 | Verbindungsstück | HEA 100 | 0.582 | Wartung_FFB | 55.05 | 70.902 | 6.956 | 7.895 | 0 | Column | 0.05 | 0.048 | 0121Tra0000011497 | m | S101 | false | HI_STV_HEA_STA_0,100
Verbindungsstück | Wartung_FFB | S235 | SB-STUETZE\ | Stahlprofilstütze | 1 | Verbindungsstück | HEA 100 | 0.582 | Wartung_FFB | 52.05 | 70.902 | 6.956 | 7.895 | 0 | Column | 0.05 | 0.048 | 0121Tra0000011499 | m | S101 | false | HI_STV_HEA_STA_0,100
Verbindungsstück | Wartung_FFB | S235 | SB-STUETZE\ | Stahlprofilstütze | 1 | Verbindungsstück | HEA 100 | 0.582 | Wartung_FFB | 49.05 | 70.902 | 6.956 | 7.895 | 0 | Column | 0.05 | 0.048 | 0121Tra0000011529 | m | S101 | false | HI_STV_HEA_STA_0,100
Verbindungsstück | Wartung_FFB | S235 | SB-STUETZE\ | Stahlprofilstütze | 1 | Verbindungsstück | HEA 100 | 0.582 | Wartung_FFB | 46.05 | 70.902 | 6.956 | 7.895 | 0 | Column | 0.05 | 0.048 | 0121Tra0000011532 | m | S101 | false | HI_STV_HEA_STA_0,100
Verbindungsstück | Wartung_FFB | S235 | SB-STUETZE\ | Stahlprofilstütze | 1 | Verbindungsstück | HEA 100 | 0.582 | Wartung_FFB | 43.05 | 70.902 | 6.956 | 7.895 | 0 | Column | 0.05 | 0.048 | 0121Tra0000011535 | m | S101 | false | HI_STV_HEA_STA_0,100
Verbindungsstück | Wartung_FFB | S235 | SB-STUETZE\ | Stahlprofilstütze | 1 | Verbindungsstück | HEA 100 | 0.582 | Wartung_FFB | 40.05 | 70.902 | 6.956 | 7.895 | 0 | Column | 0.05 | 0.048 | 0121Tra0000011538 | m | S101 | false | HI_STV_HEA_STA_0,100
Verbindungsstück | Wartung_FFB | S235 | SB-STUETZE\ | Stahlprofilstütze | 1 | Verbindungsstück | HEA 100 | 0.582 | Wartung_FFB | 37.05 | 70.902 | 6.956 | 7.895 | 0 | Column | 0.05 | 0.048 | 0121Tra0000011541 | m | S101 | false | HI_STV_HEA_STA_0,100
Verbindungsstück | Wartung_FFB | S235 | SB-STUETZE\ | Stahlprofilstütze | 1 | Verbindungsstück | HEA 100 | 0.582 | Wartung_FFB | 34.05 | 70.902 | 6.956 | 7.895 | 0 | Column | 0.05 | 0.048 | 0121Tra0000011544 | m | S101 | false | HI_STV_HEA_STA_0,100
Verbindungsstück | Wartung_FFB | S235 | SB-STUETZE\ | Stahlprofilstütze | 1 | Verbindungsstück | HEA 100 | 0.582 | Wartung_FFB | 31.05 | 70.902 | 6.956 | 7.895 | 0 | Column | 0.05 | 0.048 | 0121Tra0000011547 | m | S101 | false | HI_STV_HEA_STA_0,100
Verbindungsstück | Wartung_FFB | S235 | SB-STUETZE\ | Stahlprofilstütze | 1 | Verbindungsstück | HEA 100 | 0.582 | Wartung_FFB | 28.05 | 70.902 | 6.956 | 7.895 | 0 | Column | 0.05 | 0.048 | 0121Tra0000011550 | m | S101 | false | HI_STV_HEA_STA_0,100
Verbindungsstück | Wartung_FFB | S235 | SB-STUETZE\ | Stahlprofilstütze | 1 | Verbindungsstück | HEA 100 | 0.582 | Wartung_FFB | 25.05 | 70.902 | 6.956 | 7.895 | 0 | Column | 0.05 | 0.048 | 0121Tra0000011553 | m | S101 | false | HI_STV_HEA_STA_0,100
Verbindungsstück | Wartung_FFB | S235 | SB-STUETZE\ | Stahlprofilstütze | 1 | Verbindungsstück | HEA 100 | 0.582 | Wartung_FFB | 64.05 | 69.902 | 6.956 | 7.895 | 0 | Column | 0.05 | 0.048 | 0121Tra0000011578 | m | S101 | false | HI_STV_HEA_STA_0,100
Verbindungsstück | Wartung_FFB | S235 | SB-STUETZE\ | Stahlprofilstütze | 1 | Verbindungsstück | HEA 100 | 0.582 | Wartung_FFB | 61.05 | 69.902 | 6.956 | 7.895 | 0 | Column | 0.05 | 0.048 | 0121Tra0000011580 | m | S101 | false | HI_STV_HEA_STA_0,100
Verbindungsstück | Wartung_FFB | S235 | SB-STUETZE\ | Stahlprofilstütze | 1 | Verbindungsstück | HEA 100 | 0.582 | Wartung_FFB | 58.05 | 69.902 | 6.956 | 7.895 | 0 | Column | 0.05 | 0.048 | 0121Tra0000011582 | m | S101 | false | HI_STV_HEA_STA_0,100
Verbindungsstück | Wartung_FFB | S235 | SB-STUETZE\ | Stahlprofilstütze | 1 | Verbindungsstück | HEA 100 | 0.582 | Wartung_FFB | 55.05 | 69.902 | 6.956 | 7.895 | 0 | Column | 0.05 | 0.048 | 0121Tra0000011584 | m | S101 | false | HI_STV_HEA_STA_0,100
Verbindungsstück | Wartung_FFB | S235 | SB-STUETZE\ | Stahlprofilstütze | 1 | Verbindungsstück | HEA 100 | 0.582 | Wartung_FFB | 52.05 | 69.902 | 6.956 | 7.895 | 0 | Column | 0.05 | 0.048 | 0121Tra0000011586 | m | S101 | false | HI_STV_HEA_STA_0,100
Verbindungsstück | Wartung_FFB | S235 | SB-STUETZE\ | Stahlprofilstütze | 1 | Verbindungsstück | HEA 100 | 0.582 | Wartung_FFB | 49.05 | 69.902 | 6.956 | 7.895 | 0 | Column | 0.05 | 0.048 | 0121Tra0000011606 | m | S101 | false | HI_STV_HEA_STA_0,100
Verbindungsstück | Wartung_FFB | S235 | SB-STUETZE\ | Stahlprofilstütze | 1 | Verbindungsstück | HEA 100 | 0.582 | Wartung_FFB | 43.05 | 69.902 | 6.956 | 7.895 | 0 | Column | 0.05 | 0.048 | 0121Tra0000011610 | m | S101 | false | HI_STV_HEA_STA_0,100
Verbindungsstück | Wartung_FFB | S235 | SB-STUETZE\ | Stahlprofilstütze | 1 | Verbindungsstück | HEA 100 | 0.582 | Wartung_FFB | 40.05 | 69.902 | 6.956 | 7.895 | 0 | Column | 0.05 | 0.048 | 0121Tra0000011612 | m | S101 | false | HI_STV_HEA_STA_0,100
Verbindungsstück | Wartung_FFB | S235 | SB-STUETZE\ | Stahlprofilstütze | 1 | Verbindungsstück | HEA 100 | 0.582 | Wartung_FFB | 37.05 | 69.902 | 6.956 | 7.895 | 0 | Column | 0.05 | 0.048 | 0121Tra0000011614 | m | S101 | false | HI_STV_HEA_STA_0,100
Verbindungsstück | Wartung_FFB | S235 | SB-STUETZE\ | Stahlprofilstütze | 1 | Verbindungsstück | HEA 100 | 0.582 | Wartung_FFB | 34.05 | 69.902 | 6.956 | 7.895 | 0 | Column | 0.05 | 0.048 | 0121Tra0000011616 | m | S101 | false | HI_STV_HEA_STA_0,100
Verbindungsstück | Wartung_FFB | S235 | SB-STUETZE\ | Stahlprofilstütze | 1 | Verbindungsstück | HEA 100 | 0.582 | Wartung_FFB | 28.05 | 69.902 | 6.956 | 7.895 | 0 | Column | 0.05 | 0.048 | 0121Tra0000011620 | m | S101 | false | HI_STV_HEA_STA_0,100
Verbindungsstück | Wartung_FFB | S235 | SB-STUETZE\ | Stahlprofilstütze | 1 | Verbindungsstück | HEA 100 | 0.582 | Wartung_FFB | 67.05 | 70.902 | 6.956 | 7.085 | 0 | Column | 0.05 | 0.048 | 0121Tra0000011363 | m | S101 | false | HI_STV_HEA_STA_0,100
Verbindungsstück | Wartung_FFB | S235 | SB-STUETZE\ | Stahlprofilstütze | 1 | Verbindungsstück | HEA 100 | 0.582 | Wartung_FFB | 70.05 | 70.902 | 6.956 | 7.085 | 0 | Column | 0.05 | 0.048 | 0121Tra0000011366 | m | S101 | false | HI_STV_HEA_STA_0,100
Verbindungsstück | Wartung_FFB | S235 | SB-STUETZE\ | Stahlprofilstütze | 1 | Verbindungsstück | HEA 100 | 0.582 | Wartung_FFB | 73.05 | 70.902 | 6.956 | 7.085 | 0 | Column | 0.05 | 0.048 | 0121Tra0000011369 | m | S101 | false | HI_STV_HEA_STA_0,100
Verbindungsstück | Wartung_FFB | S235 | SB-STUETZE\ | Stahlprofilstütze | 1 | Verbindungsstück | HEA 100 | 0.582 | Wartung_FFB | 76.05 | 70.902 | 6.956 | 7.085 | 0 | Column | 0.05 | 0.048 | 0121Tra0000011372 | m | S101 | false | HI_STV_HEA_STA_0,100
Verbindungsstück | Wartung_FFB | S235 | SB-STUETZE\ | Stahlprofilstütze | 1 | Verbindungsstück | HEA 100 | 0.582 | Wartung_FFB | 79.05 | 70.902 | 6.956 | 7.085 | 0 | Column | 0.05 | 0.048 | 0121Tra0000011375 | m | S101 | false | HI_STV_HEA_STA_0,100
Verbindungsstück | Wartung_FFB | S235 | SB-STUETZE\ | Stahlprofilstütze | 1 | Verbindungsstück | HEA 100 | 0.582 | Wartung_FFB | 67.05 | 69.902 | 6.956 | 7.085 | 0 | Column | 0.05 | 0.048 | 0121Tra0000005188 | m | S101 | false | HI_STV_HEA_STA_0,100
Verbindungsstück | Wartung_FFB | S235 | SB-STUETZE\ | Stahlprofilstütze | 1 | Verbindungsstück | HEA 100 | 0.582 | Wartung_FFB | 70.05 | 69.902 | 6.956 | 7.085 | 0 | Column | 0.05 | 0.048 | 0121Tra0000005178 | m | S101 | false | HI_STV_HEA_STA_0,100
Verbindungsstück | Wartung_FFB | S235 | SB-STUETZE\ | Stahlprofilstütze | 1 | Verbindungsstück | HEA 100 | 0.582 | Wartung_FFB | 73.05 | 69.902 | 6.956 | 7.085 | 0 | Column | 0.05 | 0.048 | 0121Tra0000005168 | m | S101 | false | HI_STV_HEA_STA_0,100
Verbindungsstück | Wartung_FFB | S235 | SB-STUETZE\ | Stahlprofilstütze | 1 | Verbindungsstück | HEA 100 | 0.582 | Wartung_FFB | 76.05 | 69.902 | 6.956 | 7.085 | 0 | Column | 0.05 | 0.048 | 0121Tra0000005158 | m | S101 | false | HI_STV_HEA_STA_0,100
Verbindungsstück | Wartung_FFB | S235 | SB-STUETZE\ | Stahlprofilstütze | 1 | Verbindungsstück | HEA 100 | 0.582 | Wartung_FFB | 79.05 | 69.902 | 6.956 | 7.085 | 0 | Column | 0.05 | 0.048 | 0121Tra0000005145 | m | S101 | false | HI_STV_HEA_STA_0,100
Verbindungsstück | Wartung_FFB | S235 | SB-STUETZE\ | Stahlprofilstütze | 1 | Verbindungsstück | HEA 100 | 0.582 | Wartung_FFB | 94.05 | 70.902 | 6.956 | 7.895 | 0 | Column | 0.05 | 0.048 | 0121Tra0000011511 | m | S101 | false | HI_STV_HEA_STA_0,100
Verbindungsstück | Wartung_FFB | S235 | SB-STUETZE\ | Stahlprofilstütze | 1 | Verbindungsstück | HEA 100 | 0.582 | Wartung_FFB | 97.05 | 70.902 | 6.956 | 7.895 | 0 | Column | 0.05 | 0.048 | 0121Tra0000011514 | m | S101 | false | HI_STV_HEA_STA_0,100
Verbindungsstück | Wartung_FFB | S235 | SB-STUETZE\ | Stahlprofilstütze | 1 | Verbindungsstück | HEA 100 | 0.582 | Wartung_FFB | 103.05 | 70.902 | 6.956 | 7.895 | 0 | Column | 0.05 | 0.048 | 0121Tra0000011520 | m | S101 | false | HI_STV_HEA_STA_0,100
Verbindungsstück | Wartung_FFB | S235 | SB-STUETZE\ | Stahlprofilstütze | 1 | Verbindungsstück | HEA 100 | 0.582 | Wartung_FFB | 106.05 | 70.902 | 6.956 | 7.895 | 0 | Column | 0.05 | 0.048 | 0121Tra0000011523 | m | S101 | false | HI_STV_HEA_STA_0,100
Verbindungsstück | Wartung_FFB | S235 | SB-STUETZE\ | Stahlprofilstütze | 1 | Verbindungsstück | HEA 100 | 0.582 | Wartung_FFB | 109.05 | 70.902 | 6.956 | 7.895 | 0 | Column | 0.05 | 0.048 | 0121Tra0000011526 | m | S101 | false | HI_STV_HEA_STA_0,100
Verbindungsstück | Wartung_FFB | S235 | SB-STUETZE\ | Stahlprofilstütze | 1 | Verbindungsstück | HEA 100 | 0.582 | Wartung_FFB | 97.05 | 69.902 | 6.956 | 7.895 | 0 | Column | 0.05 | 0.048 | 0121Tra0000011596 | m | S101 | false | HI_STV_HEA_STA_0,100
Verbindungsstück | Wartung_FFB | S235 | SB-STUETZE\ | Stahlprofilstütze | 1 | Verbindungsstück | HEA 100 | 0.582 | Wartung_FFB | 103.05 | 69.902 | 6.956 | 7.895 | 0 | Column | 0.05 | 0.048 | 0121Tra0000011600 | m | S101 | false | HI_STV_HEA_STA_0,100
Verbindungsstück | Wartung_FFB | S235 | SB-STUETZE\ | Stahlprofilstütze | 1 | Verbindungsstück | HEA 100 | 0.582 | Wartung_FFB | 106.05 | 69.902 | 6.956 | 7.895 | 0 | Column | 0.05 | 0.048 | 0121Tra0000011602 | m | S101 | false | HI_STV_HEA_STA_0,100
Verbindungsstück | Wartung_FFB | S235 | SB-STUETZE\ | Stahlprofilstütze | 1 | Verbindungsstück | HEA 100 | 0.582 | Wartung_FFB | 109.05 | 69.902 | 6.956 | 7.895 | 0 | Column | 0.05 | 0.048 | 0121Tra0000011604 | m | S101 | false | HI_STV_HEA_STA_0,100
Verbindungsstück | Wartung_FFB | S235 | SB-STUETZE\ | Stahlprofilstütze | 1 | Verbindungsstück | HEA 100 | 0.582 | Wartung_FFB | 112.05 | 69.902 | 6.956 | 7.525 | 0 | Column | 0.05 | 0.048 | 0121Tra0000011394 | m | S101 | false | HI_STV_HEA_STA_0,100
Verbindungsstück | Wartung_FFB | S235 | SB-STUETZE\ | Stahlprofilstütze | 1 | Verbindungsstück | HEA 100 | 0.582 | Wartung_FFB | 115.05 | 69.902 | 6.956 | 7.525 | 0 | Column | 0.05 | 0.048 | 0121Tra0000011397 | m | S101 | false | HI_STV_HEA_STA_0,100
Verbindungsstück | Wartung_FFB | S235 | SB-STUETZE\ | Stahlprofilstütze | 1 | Verbindungsstück | HEA 100 | 0.582 | Wartung_FFB | 118.05 | 69.902 | 6.956 | 7.525 | 0 | Column | 0.05 | 0.048 | 0121Tra0000011400 | m | S101 | false | HI_STV_HEA_STA_0,100
Verbindungsstück | Wartung_FFB | S235 | SB-STUETZE\ | Stahlprofilstütze | 1 | Verbindungsstück | HEA 100 | 0.582 | Wartung_FFB | 112.05 | 70.902 | 6.956 | 7.525 | 0 | Column | 0.05 | 0.048 | 0121Tra0000011421 | m | S101 | false | HI_STV_HEA_STA_0,100
Verbindungsstück | Wartung_FFB | S235 | SB-STUETZE\ | Stahlprofilstütze | 1 | Verbindungsstück | HEA 100 | 0.582 | Wartung_FFB | 115.05 | 70.902 | 6.956 | 7.525 | 0 | Column | 0.05 | 0.048 | 0121Tra0000011424 | m | S101 | false | HI_STV_HEA_STA_0,100
Verbindungsstück | Wartung_FFB | S235 | SB-STUETZE\ | Stahlprofilstütze | 1 | Verbindungsstück | HEA 100 | 0.582 | Wartung_FFB | 118.05 | 70.902 | 6.956 | 7.525 | 0 | Column | 0.05 | 0.048 | 0121Tra0000011427 | m | S101 | false | HI_STV_HEA_STA_0,100
Verbindungsstück | Wartung_FFB | S235 | SB-STUETZE\ | Stahlprofilstütze | 1 | Verbindungsstück | HEA 100 | 0.582 | Wartung_FFB | 22.05 | 85.55 | 6.956 | 7.525 | 0 | Column | 0.05 | 0.048 | 0121Tra0000005541 | m | S101 | false | HI_STV_HEA_STA_0,100
Verbindungsstück | Wartung_FFB | S235 | SB-STUETZE\ | Stahlprofilstütze | 1 | Verbindungsstück | HEA 100 | 0.582 | Wartung_FFB | 16.05 | 85.55 | 6.956 | 7.525 | 0 | Column | 0.05 | 0.048 | 0121Tra0000011650 | m | S101 | false | HI_STV_HEA_STA_0,100
Verbindungsstück | Wartung_FFB | S235 | SB-STUETZE\ | Stahlprofilstütze | 1 | Verbindungsstück | HEA 100 | 0.582 | Wartung_FFB | 13.05 | 85.55 | 6.956 | 7.525 | 0 | Column | 0.05 | 0.048 | 0121Tra0000011653 | m | S101 | false | HI_STV_HEA_STA_0,100
Verbindungsstück | Wartung_FFB | S235 | SB-STUETZE\ | Stahlprofilstütze | 1 | Verbindungsstück | HEA 100 | 0.582 | Wartung_FFB | 10.55 | 85.55 | 6.956 | 7.525 | 0 | Column | 0.05 | 0.048 | 0121Tra0000011656 | m | S101 | false | HI_STV_HEA_STA_0,100
Verbindungsstück | Wartung_FFB | S235 | SB-STUETZE\ | Stahlprofilstütze | 1 | Verbindungsstück | HEA 100 | 0.582 | Wartung_FFB | 58.05 | 85.55 | 6.956 | 7.895 | 0 | Column | 0.05 | 0.048 | 0121Tra0000005396 | m | S101 | false | HI_STV_HEA_STA_0,100
Verbindungsstück | Wartung_FFB | S235 | SB-STUETZE\ | Stahlprofilstütze | 1 | Verbindungsstück | HEA 100 | 0.582 | Wartung_FFB | 55.05 | 85.55 | 6.956 | 7.895 | 0 | Column | 0.05 | 0.048 | 0121Tra0000011672 | m | S101 | false | HI_STV_HEA_STA_0,100
Verbindungsstück | Wartung_FFB | S235 | SB-STUETZE\ | Stahlprofilstütze | 1 | Verbindungsstück | HEA 100 | 0.582 | Wartung_FFB | 52.05 | 85.55 | 6.956 | 7.895 | 0 | Column | 0.05 | 0.048 | 0121Tra0000011676 | m | S101 | false | HI_STV_HEA_STA_0,100
Verbindungsstück | Wartung_FFB | S235 | SB-STUETZE\ | Stahlprofilstütze | 1 | Verbindungsstück | HEA 100 | 0.582 | Wartung_FFB | 49.05 | 85.55 | 6.956 | 7.895 | 0 | Column | 0.05 | 0.048 | 0121Tra0000011679 | m | S101 | false | HI_STV_HEA_STA_0,100
Verbindungsstück | Wartung_FFB | S235 | SB-STUETZE\ | Stahlprofilstütze | 1 | Verbindungsstück | HEA 100 | 0.582 | Wartung_FFB | 46.05 | 85.55 | 6.956 | 7.895 | 0 | Column | 0.05 | 0.048 | 0121Tra0000011682 | m | S101 | false | HI_STV_HEA_STA_0,100
Verbindungsstück | Wartung_FFB | S235 | SB-STUETZE\ | Stahlprofilstütze | 1 | Verbindungsstück | HEA 100 | 0.582 | Wartung_FFB | 43.05 | 85.55 | 6.956 | 7.895 | 0 | Column | 0.05 | 0.048 | 0121Tra0000011685 | m | S101 | false | HI_STV_HEA_STA_0,100
Verbindungsstück | Wartung_FFB | S235 | SB-STUETZE\ | Stahlprofilstütze | 1 | Verbindungsstück | HEA 100 | 0.582 | Wartung_FFB | 40.05 | 85.55 | 6.956 | 7.895 | 0 | Column | 0.05 | 0.048 | 0121Tra0000011688 | m | S101 | false | HI_STV_HEA_STA_0,100
Verbindungsstück | Wartung_FFB | S235 | SB-STUETZE\ | Stahlprofilstütze | 1 | Verbindungsstück | HEA 100 | 0.582 | Wartung_FFB | 37.05 | 85.55 | 6.956 | 7.895 | 0 | Column | 0.05 | 0.048 | 0121Tra0000011691 | m | S101 | false | HI_STV_HEA_STA_0,100
Verbindungsstück | Wartung_FFB | S235 | SB-STUETZE\ | Stahlprofilstütze | 1 | Verbindungsstück | HEA 100 | 0.582 | Wartung_FFB | 34.05 | 85.55 | 6.956 | 7.895 | 0 | Column | 0.05 | 0.048 | 0121Tra0000011694 | m | S101 | false | HI_STV_HEA_STA_0,100
Verbindungsstück | Wartung_FFB | S235 | SB-STUETZE\ | Stahlprofilstütze | 1 | Verbindungsstück | HEA 100 | 0.582 | Wartung_FFB | 31.05 | 85.55 | 6.956 | 7.895 | 0 | Column | 0.05 | 0.048 | 0121Tra0000011697 | m | S101 | false | HI_STV_HEA_STA_0,100
Verbindungsstück | Wartung_FFB | S235 | SB-STUETZE\ | Stahlprofilstütze | 1 | Verbindungsstück | HEA 100 | 0.582 | Wartung_FFB | 28.05 | 85.55 | 6.956 | 7.895 | 0 | Column | 0.05 | 0.048 | 0121Tra0000011700 | m | S101 | false | HI_STV_HEA_STA_0,100
Verbindungsstück | Wartung_FFB | S235 | SB-STUETZE\ | Stahlprofilstütze | 1 | Verbindungsstück | HEA 100 | 0.582 | Wartung_FFB | 25.05 | 85.55 | 6.956 | 7.895 | 0 | Column | 0.05 | 0.048 | 0121Tra0000011703 | m | S101 | false | HI_STV_HEA_STA_0,100
Verbindungsstück | Wartung_FFB | S235 | SB-STUETZE\ | Stahlprofilstütze | 1 | Verbindungsstück | HEA 100 | 0.582 | Wartung_FFB | 61.05 | 85.55 | 6.956 | 7.895 | 0 | Column | 0.05 | 0.048 | 0121Tra0000011706 | m | S101 | false | HI_STV_HEA_STA_0,100
Verbindungsstück | Wartung_FFB | S235 | SB-STUETZE\ | Stahlprofilstütze | 1 | Verbindungsstück | HEA 100 | 0.582 | Wartung_FFB | 64.05 | 85.55 | 6.956 | 7.895 | 0 | Column | 0.05 | 0.048 | 0121Tra0000011709 | m | S101 | false | HI_STV_HEA_STA_0,100
Verbindungsstück | Wartung_FFB | S235 | SB-STUETZE\ | Stahlprofilstütze | 1 | Verbindungsstück | HEA 100 | 0.582 | Wartung_FFB | 67.05 | 85.55 | 6.956 | 7.085 | 0 | Column | 0.05 | 0.048 | 0121Tra0000011625 | m | S101 | false | HI_STV_HEA_STA_0,100
Verbindungsstück | Wartung_FFB | S235 | SB-STUETZE\ | Stahlprofilstütze | 1 | Verbindungsstück | HEA 100 | 0.582 | Wartung_FFB | 70.05 | 85.55 | 6.956 | 7.085 | 0 | Column | 0.05 | 0.048 | 0121Tra0000011629 | m | S101 | false | HI_STV_HEA_STA_0,100
Verbindungsstück | Wartung_FFB | S235 | SB-STUETZE\ | Stahlprofilstütze | 1 | Verbindungsstück | HEA 100 | 0.582 | Wartung_FFB | 73.05 | 85.55 | 6.956 | 7.085 | 0 | Column | 0.05 | 0.048 | 0121Tra0000011633 | m | S101 | false | HI_STV_HEA_STA_0,100
Verbindungsstück | Wartung_FFB | S235 | SB-STUETZE\ | Stahlprofilstütze | 1 | Verbindungsstück | HEA 100 | 0.582 | Wartung_FFB | 76.05 | 85.55 | 6.956 | 7.085 | 0 | Column | 0.05 | 0.048 | 0121Tra0000011636 | m | S101 | false | HI_STV_HEA_STA_0,100
Verbindungsstück | Wartung_FFB | S235 | SB-STUETZE\ | Stahlprofilstütze | 1 | Verbindungsstück | HEA 100 | 0.582 | Wartung_FFB | 79.05 | 85.55 | 6.956 | 7.085 | 0 | Column | 0.05 | 0.048 | 0121Tra0000011639 | m | S101 | false | HI_STV_HEA_STA_0,100
Verbindungsstück | Wartung_FFB | S235 | SB-STUETZE\ | Stahlprofilstütze | 1 | Verbindungsstück | HEA 100 | 0.582 | Wartung_FFB | 94.05 | 85.55 | 6.956 | 7.895 | 0 | Column | 0.05 | 0.048 | 0121Tra0000011721 | m | S101 | false | HI_STV_HEA_STA_0,100
Verbindungsstück | Wartung_FFB | S235 | SB-STUETZE\ | Stahlprofilstütze | 1 | Verbindungsstück | HEA 100 | 0.582 | Wartung_FFB | 97.05 | 85.55 | 6.956 | 7.895 | 0 | Column | 0.05 | 0.048 | 0121Tra0000011724 | m | S101 | false | HI_STV_HEA_STA_0,100
Verbindungsstück | Wartung_FFB | S235 | SB-STUETZE\ | Stahlprofilstütze | 1 | Verbindungsstück | HEA 100 | 0.582 | Wartung_FFB | 103.05 | 85.55 | 6.956 | 7.895 | 0 | Column | 0.05 | 0.048 | 0121Tra0000011730 | m | S101 | false | HI_STV_HEA_STA_0,100
Verbindungsstück | Wartung_FFB | S235 | SB-STUETZE\ | Stahlprofilstütze | 1 | Verbindungsstück | HEA 100 | 0.582 | Wartung_FFB | 106.05 | 85.55 | 6.956 | 7.895 | 0 | Column | 0.05 | 0.048 | 0121Tra0000011733 | m | S101 | false | HI_STV_HEA_STA_0,100
Verbindungsstück | Wartung_FFB | S235 | SB-STUETZE\ | Stahlprofilstütze | 1 | Verbindungsstück | HEA 100 | 0.582 | Wartung_FFB | 109.05 | 85.55 | 6.956 | 7.895 | 0 | Column | 0.05 | 0.048 | 0121Tra0000011736 | m | S101 | false | HI_STV_HEA_STA_0,100
Verbindungsstück | Wartung_FFB | S235 | SB-STUETZE\ | Stahlprofilstütze | 1 | Verbindungsstück | HEA 100 | 0.582 | Wartung_FFB | 112.05 | 85.55 | 6.956 | 7.525 | 0 | Column | 0.05 | 0.048 | 0121Tra0000011659 | m | S101 | false | HI_STV_HEA_STA_0,100
Verbindungsstück | Wartung_FFB | S235 | SB-STUETZE\ | Stahlprofilstütze | 1 | Verbindungsstück | HEA 100 | 0.582 | Wartung_FFB | 115.05 | 85.55 | 6.956 | 7.525 | 0 | Column | 0.05 | 0.048 | 0121Tra0000011662 | m | S101 | false | HI_STV_HEA_STA_0,100
Verbindungsstück | Wartung_FFB | S235 | SB-STUETZE\ | Stahlprofilstütze | 1 | Verbindungsstück | HEA 100 | 0.582 | Wartung_FFB | 118.043 | 85.55 | 6.956 | 7.525 | 0 | Column | 0.05 | 0.048 | 0121Tra0000011665 | m | S101 | false | HI_STV_HEA_STA_0,100
Verbindungsstück | Wartung_FFB | S235 | SB-STUETZE\ | Stahlprofilstütze | 1 | Verbindungsstück | HEA 100 | 0.582 | Wartung_FFB | 25.55 | 10.69 | 6.956 | 7.225 | 0 | Column | 0.05 | 0.048 | 0121Tra0000009685 | m | S101 | false | HI_STV_HEA_STA_0,100
Verbindungsstück | Wartung_FFB | S235 | SB-STUETZE\ | Stahlprofilstütze | 1 | Verbindungsstück | HEA 100 | 0.582 | Wartung_FFB | 25.55 | 30.1 | 6.956 | 7.225 | 0 | Column | 0.05 | 0.048 | 0121Tra0000009687 | m | S101 | false | HI_STV_HEA_STA_0,100
Verbindungsstück | Wartung_FFB | S235 | SB-STUETZE\ | Stahlprofilstütze | 1 | Verbindungsstück | HEA 100 | 0.582 | Wartung_FFB | 32.25 | 10.69 | 6.956 | 7.225 | 0 | Column | 0.05 | 0.048 | 0121Tra0000009655 | m | S101 | false | HI_STV_HEA_STA_0,100
Verbindungsstück | Wartung_FFB | S235 | SB-STUETZE\ | Stahlprofilstütze | 1 | Verbindungsstück | HEA 100 | 0.582 | Wartung_FFB | 32.25 | 30.1 | 6.956 | 7.225 | 0 | Column | 0.05 | 0.048 | 0121Tra0000009657 | m | S101 | false | HI_STV_HEA_STA_0,100
Verbindungsstück | Wartung_FFB | S235 | SB-STUETZE\ | Stahlprofilstütze | 1 | Verbindungsstück | HEA 100 | 0.582 | Wartung_FFB | 32.25 | 52.3 | 6.956 | 7.225 | 0 | Column | 0.05 | 0.048 | 0121Tra0000009663 | m | S101 | false | HI_STV_HEA_STA_0,100
Verbindungsstück | Wartung_FFB | S235 | SB-STUETZE\ | Stahlprofilstütze | 1 | Verbindungsstück | HEA 100 | 0.582 | Wartung_FFB | 32.25 | 69.902 | 6.956 | 7.895 | 0 | Column | 0.05 | 0.048 | 0121Tra0000011618 | m | S101 | false | HI_STV_HEA_STA_0,100
Verbindungsstück | Wartung_FFB | S235 | SB-STUETZE\ | Stahlprofilstütze | 1 | Verbindungsstück | HEA 100 | 0.582 | Wartung_FFB | 29.6 | 31.5 | 6.956 | 7.225 | 0 | Column | 0.05 | 0.048 | 0121Tra0000009659 | m | S101 | false | HI_STV_HEA_STA_0,100
Verbindungsstück | Wartung_FFB | S235 | SB-STUETZE\ | Stahlprofilstütze | 1 | Verbindungsstück | HEA 100 | 0.582 | Wartung_FFB | 29.6 | 50.9 | 6.956 | 7.225 | 0 | Column | 0.05 | 0.048 | 0121Tra0000009661 | m | S101 | false | HI_STV_HEA_STA_0,100
Verbindungsstück | Wartung_FFB | S235 | SB-STUETZE\ | Stahlprofilstütze | 1 | Verbindungsstück | HEA 100 | 0.582 | Wartung_FFB | 29.6 | 10.69 | 6.956 | 7.225 | 0 | Column | 0.05 | 0.048 | 0121Tra0000014968 | m | S101 | false | HI_STV_HEA_STA_0,100
Verbindungsstück | Wartung_FFB | S235 | SB-STUETZE\ | Stahlprofilstütze | 1 | Verbindungsstück | HEA 100 | 0.582 | Wartung_FFB | 29.6 | 30.1 | 6.956 | 7.225 | 0 | Column | 0.05 | 0.048 | 0121Tra0000014970 | m | S101 | false | HI_STV_HEA_STA_0,100
Verbindungsstück | Wartung_FFB | S235 | SB-STUETZE\ | Stahlprofilstütze | 1 | Verbindungsstück | HEA 100 | 0.582 | Wartung_FFB | 29.6 | 52.3 | 6.956 | 7.225 | 0 | Column | 0.05 | 0.048 | 0121Tra0000014978 | m | S101 | false | HI_STV_HEA_STA_0,100
Verbindungsstück | Wartung_FFB | S235 | SB-STUETZE\ | Stahlprofilstütze | 1 | Verbindungsstück | HEA 100 | 0.582 | Wartung_FFB | 29.6 | 69.902 | 6.956 | 7.895 | 0 | Column | 0.05 | 0.048 | 0121Tra0000014980 | m | S101 | false | HI_STV_HEA_STA_0,100
Verbindungsstück | Wartung_FFB | S235 | SB-STUETZE\ | Stahlprofilstütze | 1 | Verbindungsstück | HEA 100 | 0.582 | Wartung_FFB | 81.55 | 52.3 | 6.956 | 7.225 | 0 | Column | 0.05 | 0.048 | 0121Tra0000009858 | m | S101 | false | HI_STV_HEA_STA_0,100
Verbindungsstück | Wartung_FFB | S235 | SB-STUETZE\ | Stahlprofilstütze | 1 | Verbindungsstück | HEA 100 | 0.582 | Wartung_FFB | 81.55 | 69.902 | 6.956 | 7.085 | 0 | Column | 0.05 | 0.048 | 0121Tra0000004971 | m | S101 | false | HI_STV_HEA_STA_0,100
Verbindungsstück | Wartung_FFB | S235 | SB-STUETZE\ | Stahlprofilstütze | 1 | Verbindungsstück | HEA 100 | 0.582 | Wartung_FFB | 94.7 | 52.3 | 6.956 | 7.225 | 0 | Column | 0.05 | 0.048 | 0121Tra0000009918 | m | S101 | false | HI_STV_HEA_STA_0,100
Verbindungsstück | Wartung_FFB | S235 | SB-STUETZE\ | Stahlprofilstütze | 1 | Verbindungsstück | HEA 100 | 0.582 | Wartung_FFB | 94.7 | 69.902 | 6.956 | 7.895 | 0 | Column | 0.05 | 0.048 | 0121Tra0000011594 | m | S101 | false | HI_STV_HEA_STA_0,100
Verbindungsstück | Wartung_FFB | S235 | SB-STUETZE\ | Stahlprofilstütze | 1 | Verbindungsstück | HEA 100 | 0.582 | Wartung_FFB | 84.35 | 52.3 | 6.956 | 7.225 | 0 | Column | 0.05 | 0.048 | 0121Tra0000009873 | m | S101 | false | HI_STV_HEA_STA_0,100
Verbindungsstück | Wartung_FFB | S235 | SB-STUETZE\ | Stahlprofilstütze | 1 | Verbindungsstück | HEA 100 | 0.582 | Wartung_FFB | 84.35 | 69.902 | 6.956 | 7.085 | 0 | Column | 0.05 | 0.048 | 0121Tra0000011588 | m | S101 | false | HI_STV_HEA_STA_0,100
Verbindungsstück | Wartung_FFB | S235 | SB-STUETZE\ | Stahlprofilstütze | 1 | Verbindungsstück | HEA 100 | 0.582 | Wartung_FFB | 91.9 | 52.3 | 6.956 | 7.225 | 0 | Column | 0.05 | 0.048 | 0121Tra0000014997 | m | S101 | false | HI_STV_HEA_STA_0,100
Verbindungsstück | Wartung_FFB | S235 | SB-STUETZE\ | Stahlprofilstütze | 1 | Verbindungsstück | HEA 100 | 0.582 | Wartung_FFB | 91.9 | 69.902 | 6.956 | 7.895 | 0 | Column | 0.05 | 0.048 | 0121Tra0000014999 | m | S101 | false | HI_STV_HEA_STA_0,100
Verbindungsstück | Wartung_FFB | S235 | SB-STUETZE\ | Stahlprofilstütze | 1 | Verbindungsstück | HEA 100 | 0.582 | Wartung_FFB | 86.75 | 52.3 | 6.956 | 7.225 | 0 | Column | 0.05 | 0.048 | 0121Tra0000009888 | m | S101 | false | HI_STV_HEA_STA_0,100
Verbindungsstück | Wartung_FFB | S235 | SB-STUETZE\ | Stahlprofilstütze | 1 | Verbindungsstück | HEA 100 | 0.582 | Wartung_FFB | 86.75 | 69.902 | 6.956 | 7.895 | 0 | Column | 0.05 | 0.048 | 0121Tra0000011590 | m | S101 | false | HI_STV_HEA_STA_0,100
Verbindungsstück | Wartung_FFB | S235 | SB-STUETZE\ | Stahlprofilstütze | 1 | Verbindungsstück | HEA 100 | 0.582 | Wartung_FFB | 89.5 | 52.3 | 6.956 | 7.225 | 0 | Column | 0.05 | 0.048 | 0121Tra0000009903 | m | S101 | false | HI_STV_HEA_STA_0,100
Verbindungsstück | Wartung_FFB | S235 | SB-STUETZE\ | Stahlprofilstütze | 1 | Verbindungsstück | HEA 100 | 0.582 | Wartung_FFB | 89.5 | 69.902 | 6.956 | 7.895 | 0 | Column | 0.05 | 0.048 | 0121Tra0000011592 | m | S101 | false | HI_STV_HEA_STA_0,100
Verbindungsstück | Wartung_FFB | S235 | SB-STUETZE\ | Stahlprofilstütze | 1 | Verbindungsstück | HEA 100 | 0.582 | Wartung_FFB | 84.35 | 70.902 | 6.956 | 7.085 | 0 | Column | 0.05 | 0.048 | 0121Tra0000011502 | m | S101 | false | HI_STV_HEA_STA_0,100
Verbindungsstück | Wartung_FFB | S235 | SB-STUETZE\ | Stahlprofilstütze | 1 | Verbindungsstück | HEA 100 | 0.582 | Wartung_FFB | 84.35 | 85.55 | 6.956 | 7.085 | 0 | Column | 0.05 | 0.048 | 0121Tra0000011712 | m | S101 | false | HI_STV_HEA_STA_0,100
Verbindungsstück | Wartung_FFB | S235 | SB-STUETZE\ | Stahlprofilstütze | 1 | Verbindungsstück | HEA 100 | 0.582 | Wartung_FFB | 91.9 | 70.902 | 6.956 | 7.895 | 0 | Column | 0.05 | 0.048 | 0121Tra0000011508 | m | S101 | false | HI_STV_HEA_STA_0,100
Verbindungsstück | Wartung_FFB | S235 | SB-STUETZE\ | Stahlprofilstütze | 1 | Verbindungsstück | HEA 100 | 0.582 | Wartung_FFB | 91.9 | 85.55 | 6.956 | 7.895 | 0 | Column | 0.05 | 0.048 | 0121Tra0000011718 | m | S101 | false | HI_STV_HEA_STA_0,100
Verbindungsstück | Wartung_FFB | S235 | SB-STUETZE\ | Stahlprofilstütze | 1 | Verbindungsstück | HEA 100 | 0.582 | Wartung_FFB | 86.75 | 70.902 | 6.956 | 7.895 | 0 | Column | 0.05 | 0.048 | 0121Tra0000011505 | m | S101 | false | HI_STV_HEA_STA_0,100
Verbindungsstück | Wartung_FFB | S235 | SB-STUETZE\ | Stahlprofilstütze | 1 | Verbindungsstück | HEA 100 | 0.582 | Wartung_FFB | 86.75 | 85.55 | 6.956 | 7.895 | 0 | Column | 0.05 | 0.048 | 0121Tra0000011715 | m | S101 | false | HI_STV_HEA_STA_0,100
Verbindungsstück | Wartung_FFB | S235 | SB-STUETZE\ | Stahlprofilstütze | 1 | Verbindungsstück | HEA 100 | 0.582 | Wartung_FFB | 89.5 | 70.902 | 6.956 | 7.895 | 0 | Column | 0.05 | 0.048 | 0121Tra0000015020 | m | S101 | false | HI_STV_HEA_STA_0,100
Verbindungsstück | Wartung_FFB | S235 | SB-STUETZE\ | Stahlprofilstütze | 1 | Verbindungsstück | HEA 100 | 0.582 | Wartung_FFB | 89.5 | 85.55 | 6.956 | 7.895 | 0 | Column | 0.05 | 0.048 | 0121Tra0000015022 | m | S101 | false | HI_STV_HEA_STA_0,100
Verbindungsstück | Wartung_FFB | S235 | SB-STUETZE\ | Stahlprofilstütze | 1 | Verbindungsstück | HEA 100 | 0.582 | Wartung_FFB | 120.75 | 52.3 | 6.956 | 7.225 | 0 | Column | 0.05 | 0.048 | 0121Tra0000010053 | m | S101 | false | HI_STV_HEA_STA_0,100
Verbindungsstück | Wartung_FFB | S235 | SB-STUETZE\ | Stahlprofilstütze | 1 | Verbindungsstück | HEA 100 | 0.582 | Wartung_FFB | 120.75 | 69.902 | 6.956 | 7.525 | 0 | Column | 0.05 | 0.048 | 0121Tra0000011403 | m | S101 | false | HI_STV_HEA_STA_0,100
Verbindungsstück | Wartung_FFB | S235 | SB-STUETZE\ | Stahlprofilstütze | 1 | Verbindungsstück | HEA 100 | 0.582 | Wartung_FFB | 120.75 | 70.902 | 6.956 | 7.525 | 0 | Column | 0.05 | 0.048 | 0121Tra0000011430 | m | S101 | false | HI_STV_HEA_STA_0,100
Verbindungsstück | Wartung_FFB | S235 | SB-STUETZE\ | Stahlprofilstütze | 1 | Verbindungsstück | HEA 100 | 0.582 | Wartung_FFB | 120.75 | 85.55 | 6.956 | 7.525 | 0 | Column | 0.05 | 0.048 | 0121Tra0000011668 | m | S101 | false | HI_STV_HEA_STA_0,100
Verbindungsstück | Wartung_FFB | S235 | SB-STUETZE\ | Stahlprofilstütze | 1 | Verbindungsstück | HEA 100 | 0.582 | Wartung_FFB | 91.85 | 10.69 | 6.956 | 7.225 | 0 | Column | 0.05 | 0.048 | 0121Tra0000015700 | m | S101 | false | HI_STV_HEA_STA_0,100
Verbindungsstück | Wartung_FFB | S235 | SB-STUETZE\ | Stahlprofilstütze | 1 | Verbindungsstück | HEA 100 | 0.582 | Wartung_FFB | 91.85 | 30.1 | 6.956 | 7.225 | 0 | Column | 0.05 | 0.048 | 0121Tra0000015702 | m | S101 | false | HI_STV_HEA_STA_0,100
Verbindungsstück | Wartung_FFB | S235 | SB-STUETZE\ | Stahlprofilstütze | 1 | Verbindungsstück | HEA 100 | 0.582 | Wartung_FFB | 25.503 | 31.5 | 6.956 | 7.225 | 0 | Column | 0.05 | 0.048 | 0121Tra0000009689 | m | S101 | false | HI_STV_HEA_STA_0,100
Verbindungsstück | Wartung_FFB | S235 | SB-STUETZE\ | Stahlprofilstütze | 1 | Verbindungsstück | HEA 100 | 0.582 | Wartung_FFB | 25.503 | 50.9 | 6.956 | 7.225 | 0 | Column | 0.05 | 0.048 | 0121Tra0000009691 | m | S101 | false | HI_STV_HEA_STA_0,100
Verbindungsstück | Wartung_FFB | S235 | SB-STUETZE\ | Stahlprofilstütze | 1 | Verbindungsstück | HEA 100 | 0.582 | Wartung_FFB | 25.503 | 52.3 | 6.956 | 7.225 | 0 | Column | 0.05 | 0.048 | 0121Tra0000009693 | m | S101 | false | HI_STV_HEA_STA_0,100
Verbindungsstück | Wartung_FFB | S235 | SB-STUETZE\ | Stahlprofilstütze | 1 | Verbindungsstück | HEA 100 | 0.582 | Wartung_FFB | 25.503 | 69.902 | 6.956 | 7.895 | 0 | Column | 0.05 | 0.048 | 0121Tra0000011622 | m | S101 | false | HI_STV_HEA_STA_0,100
Verbindungsstück | Wartung_FFB | S235 | SB-STUETZE\ | Stahlprofilstütze | 1 | Verbindungsstück | HEA 100 | 0.582 | Wartung_FFB | 45.92 | 31.5 | 6.956 | 7.225 | 0 | Column | 0.05 | 0.048 | 0121Tra0000009584 | m | S101 | false | HI_STV_HEA_STA_0,100
Verbindungsstück | Wartung_FFB | S235 | SB-STUETZE\ | Stahlprofilstütze | 1 | Verbindungsstück | HEA 100 | 0.582 | Wartung_FFB | 45.92 | 50.9 | 6.956 | 7.225 | 0 | Column | 0.05 | 0.048 | 0121Tra0000009586 | m | S101 | false | HI_STV_HEA_STA_0,100
Verbindungsstück | Wartung_FFB | S235 | SB-STUETZE\ | Stahlprofilstütze | 1 | Verbindungsstück | HEA 100 | 0.582 | Wartung_FFB | 45.92 | 52.3 | 6.956 | 7.225 | 0 | Column | 0.05 | 0.048 | 0121Tra0000009588 | m | S101 | false | HI_STV_HEA_STA_0,100
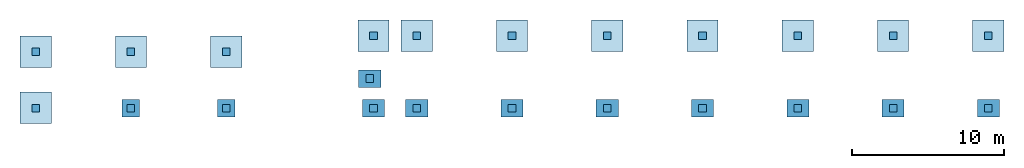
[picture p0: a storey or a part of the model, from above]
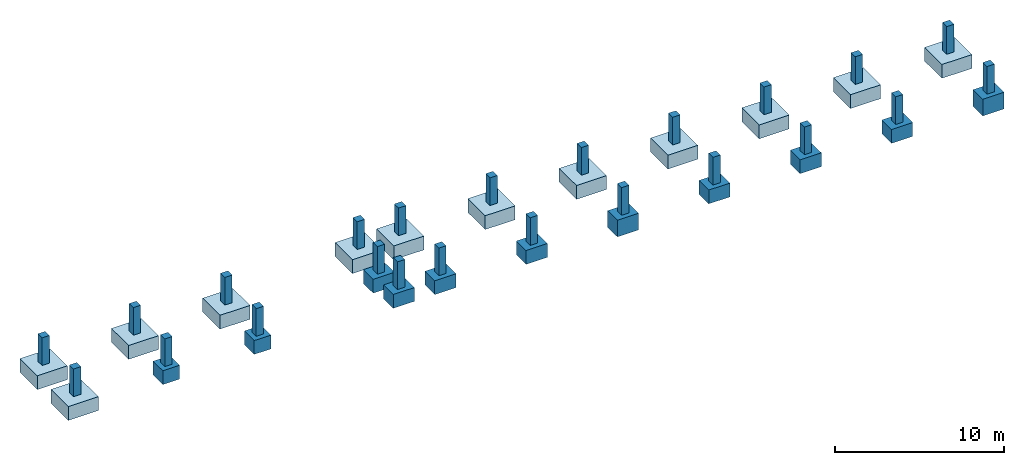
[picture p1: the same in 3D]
Properties of the parts of a building model (IFC2X3), part 12 of 25

# IfcColumn (470)
Name | In | Material = AllplanAttributes, Material | Codetext | Kurztext | Faktor | Bezeichnung = Name | Profilname | Mantelfläche/lfm | Ebene | Achsenstartpunkt (X) (m) = Achsenendpunkt (X) (m) | Achsenstartpunkt (Y) (m) = Achsenendpunkt (Y) (m) | Achsenstartpunkt (Z) (m) | Achsenendpunkt (Z) (m) | Objektdrehwinkel | Attributset-Objekt | Schwerpunkt X (m) | Schwerpunkt Y (m) | Allright_Bauteil_ID | Abrechnungsart | Positionsnummer | Außenbauteil | Reference
Verbindungsstück | Wartung_FFB | S235 | SB-STUETZE\ | Stahlprofilstütze | 1 | Verbindungsstück | HEA 100 | 0.582 | Wartung_FFB | 45.92 | 69.902 | 6.956 | 7.895 | 0 | Column | 0.05 | 0.048 | 0121Tra0000011608 | m | S101 | false | HI_STV_HEA_STA_0,100
Verbindungsstück | Wartung_FFB | S235 | SB-STUETZE\ | Stahlprofilstütze | 1 | Verbindungsstück | HEA 100 | 0.582 | Wartung_FFB | 19.28 | 69.902 | 6.956 | 7.525 | 0 | Column | 0.05 | 0.048 | 0121Tra0000011381 | m | S101 | false | HI_STV_HEA_STA_0,100
Verbindungsstück | Wartung_FFB | S235 | SB-STUETZE\ | Stahlprofilstütze | 1 | Verbindungsstück | HEA 100 | 0.582 | Wartung_FFB | 19.28 | 70.902 | 6.956 | 7.525 | 0 | Column | 0.05 | 0.048 | 0121Tra0000011409 | m | S101 | false | HI_STV_HEA_STA_0,100
Verbindungsstück | Wartung_FFB | S235 | SB-STUETZE\ | Stahlprofilstütze | 1 | Verbindungsstück | HEA 100 | 0.582 | Wartung_FFB | 19.28 | 85.55 | 6.956 | 7.525 | 0 | Column | 0.05 | 0.048 | 0121Tra0000011646 | m | S101 | false | HI_STV_HEA_STA_0,100
Verbindungsstück | Wartung_FFB | S235 | SB-STUETZE\ | Stahlprofilstütze | 1 | Verbindungsstück | HEA 100 | 0.582 | Wartung_FFB | 82.18 | 70.902 | 6.956 | 7.085 | 0 | Column | 0.05 | 0.048 | 0121Tra0000011378 | m | S101 | false | HI_STV_HEA_STA_0,100
Verbindungsstück | Wartung_FFB | S235 | SB-STUETZE\ | Stahlprofilstütze | 1 | Verbindungsstück | HEA 100 | 0.582 | Wartung_FFB | 82.18 | 85.55 | 6.956 | 7.085 | 0 | Column | 0.05 | 0.048 | 0121Tra0000011642 | m | S101 | false | HI_STV_HEA_STA_0,100
Verbindungsstück | Wartung_FFB | S235 | SB-STUETZE\ | Stahlprofilstütze | 1 | Verbindungsstück | HEA 100 | 0.582 | Wartung_FFB | 99.82 | 52.3 | 6.956 | 7.225 | 0 | Column | 0.05 | 0.048 | 0121Tra0000009948 | m | S101 | false | HI_STV_HEA_STA_0,100
Verbindungsstück | Wartung_FFB | S235 | SB-STUETZE\ | Stahlprofilstütze | 1 | Verbindungsstück | HEA 100 | 0.582 | Wartung_FFB | 99.82 | 70.902 | 6.956 | 7.895 | 0 | Column | 0.05 | 0.048 | 0121Tra0000011517 | m | S101 | false | HI_STV_HEA_STA_0,100
Verbindungsstück | Wartung_FFB | S235 | SB-STUETZE\ | Stahlprofilstütze | 1 | Verbindungsstück | HEA 100 | 0.582 | Wartung_FFB | 99.82 | 69.902 | 6.956 | 7.895 | 0 | Column | 0.05 | 0.048 | 0121Tra0000011598 | m | S101 | false | HI_STV_HEA_STA_0,100
Verbindungsstück | Wartung_FFB | S235 | SB-STUETZE\ | Stahlprofilstütze | 1 | Verbindungsstück | HEA 100 | 0.582 | Wartung_FFB | 99.82 | 85.55 | 6.956 | 7.895 | 0 | Column | 0.05 | 0.048 | 0121Tra0000011727 | m | S101 | false | HI_STV_HEA_STA_0,100

# IfcFooting (903)
AllplanAttributes - 2D Interaktion: yes; Gewerk: Betonarbeiten; Attributset-Objekt: Fundament
IFC_Pset_TWP - Phase erstellt: Neubau; statisch tragend: true; Kommentar: -
Pset_ConcreteElementGeneral - WU-Beton: false; Betonüberdeckung: 1
Pset_FM-Vivantes - FM_Klasse: -; FM_Bezeichnung: -; FM_AKS: -; FM_Anzahl: -; FM_Standort: -; FM_Hersteller: -; FM_Hersteller-Typ: -; FM_Seriennummer: -; FM_Baujahr: -; FM_Inbetriebnahme Datum: -; FM_Gewährleistungsende: -; FM_Gewährleistungsgeber: -; FM_Betriebsstatus: -; FM_Prüfpflicht: -; FM_Prüfintervall: -; FM_letzter Prüfungstermin: -; FM_Sammelobjekt: -; FM_rechn. Lebensdauer: -; FM_rechn. Lebensende: -; FM_technischer Zustand: -; FM_voraus. Lebensende: -; FM_Eigentümer: -; FM_Bemerkung: -; FM_Versorgungsbereich-Wirkbereich: -; FM_Zugänglichkeit: -
Name | In | PredefinedType | Material = AllplanAttributes, Material | Codetext | Bezeichnung = Name | Ebene | Allright_Bauteil_ID | Abrechnungsart | IFC_Pset_TWP, Material | Herstellung | Außenbauteil | Positionsnummer | Bewehrungsgrad | Expositionsklasse | Druckfestigkeitsklasse | Reference
Stb.-Einzelfundament | Grundleitungsebene | PAD_FOOTING | Stahlbeton | FU-EINZEL1\ | Stb.-Einzelfundament | Grundleitungsebene | 0081EFu0000011740 | m³ | Stahlbeton | Ortbeton | true | AF01a | 50 | XC2, WF | C25/30 | HA_FUN_STB_2,050x2,050x1,000_xxx
Stb.-Einzelfundament | Grundleitungsebene | PAD_FOOTING | Stahlbeton | FU-EINZEL1\ | Stb.-Einzelfundament | Grundleitungsebene | 0081EFu0000011744 | m³ | Stahlbeton | Ortbeton | true | AF01a | 50 | XC2, WF | C25/30 | HA_FUN_STB_2,050x2,050x1,000_xxx
Stb.-Einzelfundament | Grundleitungsebene | PAD_FOOTING | Stahlbeton | FU-EINZEL1\ | Stb.-Einzelfundament | Grundleitungsebene | 0081EFu0000011748 | m³ | Stahlbeton | Ortbeton | true | AF01a | 50 | XC2, WF | C25/30 | HA_FUN_STB_2,050x2,050x1,000_xxx
Stb.-Einzelfundament | Grundleitungsebene | PAD_FOOTING | Stahlbeton | FU-EINZEL1\ | Stb.-Einzelfundament | Grundleitungsebene | 0081EFu0000011752 | m³ | Stahlbeton | Ortbeton | true | AF01a | 50 | XC2, WF | C25/30 | HA_FUN_STB_2,050x2,050x1,000_xxx
Stb.-Einzelfundament | Grundleitungsebene | PAD_FOOTING | Stahlbeton | FU-EINZEL1\ | Stb.-Einzelfundament | Grundleitungsebene | 0081EFu0000011756 | m³ | Stahlbeton | Ortbeton | true | AF01a | 50 | XC2, WF | C25/30 | HA_FUN_STB_2,050x2,050x1,000_xxx
Stb.-Einzelfundament | Grundleitungsebene | PAD_FOOTING | Stahlbeton | FU-EINZEL1\ | Stb.-Einzelfundament | Grundleitungsebene | 0081EFu0000011760 | m³ | Stahlbeton | Ortbeton | true | AF01a | 50 | XC2, WF | C25/30 | HA_FUN_STB_2,050x2,050x1,000_xxx
Stb.-Einzelfundament | Grundleitungsebene | PAD_FOOTING | Stahlbeton | FU-EINZEL1\ | Stb.-Einzelfundament | Grundleitungsebene | 0081EFu0000011764 | m³ | Stahlbeton | Ortbeton | true | AF01a | 50 | XC2, WF | C25/30 | HA_FUN_STB_2,050x2,050x1,000_xxx
Stb.-Einzelfundament | Grundleitungsebene | PAD_FOOTING | Stahlbeton | FU-EINZEL1\ | Stb.-Einzelfundament | Grundleitungsebene | 0081EFu0000011825 | m³ | Stahlbeton | Ortbeton | true | AF01a | 50 | XC2, WF | C25/30 | HA_FUN_STB_2,050x2,050x1,000_xxx
Stb.-Einzelfundament | Grundleitungsebene | PAD_FOOTING | Stahlbeton | FU-EINZEL1\ | Stb.-Einzelfundament | Grundleitungsebene | 0081EFu0000011831 | m³ | Stahlbeton | Ortbeton | true | AF02a | 50 | XC2, WF | C25/30 | HA_FUN_STB_2,050x2,050x1,000_xxx
Stb.-Einzelfundament | Grundleitungsebene | PAD_FOOTING | Stahlbeton | FU-EINZEL1\ | Stb.-Einzelfundament | Grundleitungsebene | 0081EFu0000011828 | m³ | Stahlbeton | Ortbeton | true | AF02a | 50 | XC2, WF | C25/30 | HA_FUN_STB_2,050x2,050x1,000_xxx
Stb.-Einzelfundament | Grundleitungsebene | PAD_FOOTING | Stahlbeton | FU-EINZEL1\ | Stb.-Einzelfundament | Grundleitungsebene | 0081EFu0000011833 | m³ | Stahlbeton | Ortbeton | true | AF02a | 50 | XC2, WF | C25/30 | HA_FUN_STB_2,050x2,050x1,000_xxx
Stb.-Einzelfundament | Grundleitungsebene | PAD_FOOTING | Stahlbeton | FU-EINZEL1\ | Stb.-Einzelfundament | Grundleitungsebene | 0081EFu0000011821 | m³ | Stahlbeton | Ortbeton | true | AF02a | 50 | XC2, WF | C25/30 | HA_FUN_STB_2,050x2,050x1,000_xxx
Streifenfundament | EG_Technik_FFB | STRIP_FOOTING | Beton | FU-STREIFEN2\ | Streifenfundament | EG_Technik_FFB | 0104SFu0000026508 | m² | Beton | Ortbeton | false | F004 | 10 | X0, WF | C 25/30 | HA_FUN_STB_0,500x0,500_xxx
Streifenfundament | EG_Technik_FFB | STRIP_FOOTING | Beton | FU-STREIFEN2\ | Streifenfundament | EG_Technik_FFB | 0104SFu0000026504 | m² | Beton | Ortbeton | false | F004 | 10 | X0, WF | C 25/30 | HA_FUN_STB_0,500x0,500_xxx
Streifenfundament | EG_Technik_FFB | STRIP_FOOTING | Beton | FU-STREIFEN2\ | Streifenfundament | EG_Technik_FFB | 0104SFu0000028705 | m² | Beton | Ortbeton | false | F004 | 10 | X0, WF | C 25/30 | HA_FUN_STB_0,500x0,500_xxx
Streifenfundament | EG_Technik_FFB | STRIP_FOOTING | Beton | FU-STREIFEN2\ | Streifenfundament | EG_Technik_FFB | 0104SFu0000026478 | m² | Beton | Ortbeton | false | F004 | 10 | X0, WF | C 25/30 | HA_FUN_STB_0,500x0,500_xxx
Streifenfundament | EG_Technik_FFB | STRIP_FOOTING | Beton | FU-STREIFEN2\ | Streifenfundament | EG_Technik_FFB | 0104SFu0000026500 | m² | Beton | Ortbeton | false | F004 | 10 | X0, WF | C 25/30 | HA_FUN_STB_0,500x0,500_xxx
Streifenfundament | EG_Technik_FFB | STRIP_FOOTING | Beton | FU-STREIFEN2\ | Streifenfundament | EG_Technik_FFB | 0104SFu0000027841 | m² | Beton | Ortbeton | false | F004 | 10 | X0, WF | C 25/30 | HA_FUN_STB_0,500x0,500_xxx
Streifenfundament | EG_Technik_FFB | STRIP_FOOTING | Beton | FU-STREIFEN2\ | Streifenfundament | EG_Technik_FFB | 0104SFu0000028579 | m² | Beton | Ortbeton | false | F004 | 10 | X0, WF | C 25/30 | HA_FUN_STB_0,500x0,500_xxx
Streifenfundament | EG_Technik_FFB | STRIP_FOOTING | Beton | FU-STREIFEN2\ | Streifenfundament | EG_Technik_FFB | 0104SFu0000028527 | m² | Beton | Ortbeton | false | F004 | 10 | X0, WF | C 25/30 | HA_FUN_STB_0,500x0,500_xxx
Streifenfundament | EG_Technik_FFB | STRIP_FOOTING | Beton | FU-STREIFEN2\ | Streifenfundament | EG_Technik_FFB | 0104SFu0000026512 | m² | Beton | Ortbeton | false | F004 | 10 | X0, WF | C 25/30 | HA_FUN_STB_0,500x0,500_xxx
Streifenfundament | EG_Technik_FFB | STRIP_FOOTING | Beton | FU-STREIFEN2\ | Streifenfundament | EG_Technik_FFB | 0104SFu0000028895 | m² | Beton | Ortbeton | false | F004 | 10 | X0, WF | C 25/30 | HA_FUN_STB_0,500x0,500_xxx
Streifenfundament | EG_Technik_FFB | STRIP_FOOTING | Beton | FU-STREIFEN2\ | Streifenfundament | EG_Technik_FFB | 0104SFu0000028427 | m² | Beton | Ortbeton | false | F004 | 10 | X0, WF | C 25/30 | HA_FUN_STB_0,500x0,500_xxx
Streifenfundament | EG_Technik_FFB | STRIP_FOOTING | Beton | FU-STREIFEN2\ | Streifenfundament | EG_Technik_FFB | 0104SFu0000028607 | m² | Beton | Ortbeton | false | F004 | 10 | X0, WF | C 25/30 | HA_FUN_STB_0,500x0,500_xxx
Streifenfundament | EG_Technik_FFB | STRIP_FOOTING | Beton | FU-STREIFEN2\ | Streifenfundament | EG_Technik_FFB | 0104SFu0000028397 | m² | Beton | Ortbeton | false | F004 | 10 | X0, WF | C 25/30 | HA_FUN_STB_0,500x0,500_xxx
Streifenfundament | EG_Technik_FFB | STRIP_FOOTING | Beton | FU-STREIFEN2\ | Streifenfundament | EG_Technik_FFB | 0104SFu0000028483 | m² | Beton | Ortbeton | false | F004 | 10 | X0, WF | C 25/30 | HA_FUN_STB_0,500x0,500_xxx
Streifenfundament | EG_Technik_FFB | STRIP_FOOTING | Beton | FU-STREIFEN2\ | Streifenfundament | EG_Technik_FFB | 0104SFu0000028631 | m² | Beton | Ortbeton | false | F004 | 10 | X0, WF | C 25/30 | HA_FUN_STB_0,500x0,500_xxx
Streifenfundament | EG_Technik_FFB | STRIP_FOOTING | Beton | FU-STREIFEN2\ | Streifenfundament | EG_Technik_FFB | 0104SFu0000028377 | m² | Beton | Ortbeton | false | F004 | 10 | X0, WF | C 25/30 | HA_FUN_STB_0,500x0,500_xxx
Streifenfundament | EG_Technik_FFB | STRIP_FOOTING | Beton | FU-STREIFEN2\ | Streifenfundament | EG_Technik_FFB | 0104SFu0000028203 | m² | Beton | Ortbeton | false | F004 | 10 | X0, WF | C 25/30 | HA_FUN_STB_0,500x0,500_xxx
Streifenfundament | EG_Technik_FFB | STRIP_FOOTING | Beton | FU-STREIFEN2\ | Streifenfundament | EG_Technik_FFB | 0104SFu0000028145 | m² | Beton | Ortbeton | false | F004 | 10 | X0, WF | C 25/30 | HA_FUN_STB_0,500x0,500_xxx
Streifenfundament | EG_Technik_FFB | STRIP_FOOTING | Beton | FU-STREIFEN2\ | Streifenfundament | EG_Technik_FFB | 0104SFu0000028665 | m² | Beton | Ortbeton | false | F004 | 10 | X0, WF | C 25/30 | HA_FUN_STB_0,500x0,500_xxx
Streifenfundament | EG_Technik_FFB | STRIP_FOOTING | Beton | FU-STREIFEN2\ | Streifenfundament | EG_Technik_FFB | 0104SFu0000028261 | m² | Beton | Ortbeton | false | F004 | 10 | X0, WF | C 25/30 | HA_FUN_STB_0,500x0,500_xxx
Streifenfundament | EG_Technik_FFB | STRIP_FOOTING | Beton | FU-STREIFEN2\ | Streifenfundament | EG_Technik_FFB | 0104SFu0000027983 | m² | Beton | Ortbeton | false | F004 | 10 | X0, WF | C 25/30 | HA_FUN_STB_0,500x0,500_xxx
Streifenfundament | EG_Technik_FFB | STRIP_FOOTING | Beton | FU-STREIFEN2\ | Streifenfundament | EG_Technik_FFB | 0104SFu0000028035 | m² | Beton | Ortbeton | false | F004 | 10 | X0, WF | C 25/30 | HA_FUN_STB_0,500x0,500_xxx
Streifenfundament | EG_Technik_FFB | STRIP_FOOTING | Beton | FU-STREIFEN2\ | Streifenfundament | EG_Technik_FFB | 0104SFu0000026434 | m² | Beton | Ortbeton | false | F004 | 10 | X0, WF | C 25/30 | HA_FUN_STB_0,500x0,500_xxx
Streifenfundament | EG_Technik_FFB | STRIP_FOOTING | Beton | FU-STREIFEN2\ | Streifenfundament | EG_Technik_FFB | 0104SFu0000026427 | m² | Beton | Ortbeton | false | F004 | 10 | X0, WF | C 25/30 | HA_FUN_STB_0,500x0,500_xxx
Streifenfundament | EG_Technik_FFB | STRIP_FOOTING | Beton | FU-STREIFEN2\ | Streifenfundament | EG_Technik_FFB | 0104SFu0000027961 | m² | Beton | Ortbeton | false | F004 | 10 | X0, WF | C 25/30 | HA_FUN_STB_0,500x0,500_xxx
Streifenfundament | EG_Technik_FFB | STRIP_FOOTING | Beton | FU-STREIFEN2\ | Streifenfundament | EG_Technik_FFB | 0104SFu0000027975 | m² | Beton | Ortbeton | false | F004 | 10 | X0, WF | C 25/30 | HA_FUN_STB_0,500x0,500_xxx
Streifenfundament | EG_Technik_FFB | STRIP_FOOTING | Beton | FU-STREIFEN2\ | Streifenfundament | EG_Technik_FFB | 0104SFu0000027867 | m² | Beton | Ortbeton | false | F004 | 10 | X0, WF | C 25/30 | HA_FUN_STB_0,500x0,500_xxx
Streifenfundament | EG_Technik_FFB | STRIP_FOOTING | Beton | FU-STREIFEN2\ | Streifenfundament | EG_Technik_FFB | 0104SFu0000027606 | m² | Beton | Ortbeton | false | F004 | 10 | X0, WF | C 25/30 | HA_FUN_STB_0,500x0,500_xxx
Streifenfundament | EG_Technik_FFB | STRIP_FOOTING | Beton | FU-STREIFEN2\ | Streifenfundament | EG_Technik_FFB | 0104SFu0000027472 | m² | Beton | Ortbeton | false | F004 | 10 | X0, WF | C 25/30 | HA_FUN_STB_0,500x0,500_xxx
Streifenfundament | EG_Technik_FFB | STRIP_FOOTING | Beton | FU-STREIFEN2\ | Streifenfundament | EG_Technik_FFB | 0104SFu0000027602 | m² | Beton | Ortbeton | false | F004 | 10 | X0, WF | C 25/30 | HA_FUN_STB_0,500x0,500_xxx
Streifenfundament | EG_Technik_FFB | STRIP_FOOTING | Beton | FU-STREIFEN2\ | Streifenfundament | EG_Technik_FFB | 0104SFu0000027855 | m² | Beton | Ortbeton | false | F004 | 10 | X0, WF | C 25/30 | HA_FUN_STB_0,500x0,500_xxx
Streifenfundament | EG_Technik_FFB | STRIP_FOOTING | Beton | FU-STREIFEN2\ | Streifenfundament | EG_Technik_FFB | 0104SFu0000027484 | m² | Beton | Ortbeton | false | F004 | 10 | X0, WF | C 25/30 | HA_FUN_STB_0,500x0,500_xxx
Streifenfundament | EG_Technik_FFB | STRIP_FOOTING | Beton | FU-STREIFEN2\ | Streifenfundament | EG_Technik_FFB | 0104SFu0000027827 | m² | Beton | Ortbeton | false | F004 | 10 | X0, WF | C 25/30 | HA_FUN_STB_0,500x0,500_xxx
Streifenfundament | EG_Technik_FFB | STRIP_FOOTING | Beton | FU-STREIFEN2\ | Streifenfundament | EG_Technik_FFB | 0104SFu0000027556 | m² | Beton | Ortbeton | false | F004 | 10 | X0, WF | C 25/30 | HA_FUN_STB_0,500x0,500_xxx
Streifenfundament | EG_Technik_FFB | STRIP_FOOTING | Beton | FU-STREIFEN2\ | Streifenfundament | EG_Technik_FFB | 0104SFu0000027775 | m² | Beton | Ortbeton | false | F004 | 10 | X0, WF | C 25/30 | HA_FUN_STB_0,500x0,500_xxx
Streifenfundament | EG_Technik_FFB | STRIP_FOOTING | Beton | FU-STREIFEN2\ | Streifenfundament | EG_Technik_FFB | 0104SFu0000027452 | m² | Beton | Ortbeton | false | F004 | 10 | X0, WF | C 25/30 | HA_FUN_STB_0,500x0,500_xxx
Streifenfundament | EG_Technik_FFB | STRIP_FOOTING | Beton | FU-STREIFEN2\ | Streifenfundament | EG_Technik_FFB | 0104SFu0000027699 | m² | Beton | Ortbeton | false | F004 | 10 | X0, WF | C 25/30 | HA_FUN_STB_0,500x0,500_xxx
Streifenfundament | EG_Technik_FFB | STRIP_FOOTING | Beton | FU-STREIFEN2\ | Streifenfundament | EG_Technik_FFB | 0104SFu0000027379 | m² | Beton | Ortbeton | false | F004 | 10 | X0, WF | C 25/30 | HA_FUN_STB_0,500x0,500_xxx
Streifenfundament | EG_Technik_FFB | STRIP_FOOTING | Beton | FU-STREIFEN2\ | Streifenfundament | EG_Technik_FFB | 0104SFu0000028787 | m² | Beton | Ortbeton | false | F004 | 10 | X0, WF | C 25/30 | HA_FUN_STB_0,500x0,500_xxx
Streifenfundament | EG_Technik_FFB | STRIP_FOOTING | Beton | FU-STREIFEN2\ | Streifenfundament | EG_Technik_FFB | 0104SFu0000026442 | m² | Beton | Ortbeton | false | F004 | 10 | X0, WF | C 25/30 | HA_FUN_STB_0,500x0,500_xxx
Streifenfundament | EG_Technik_FFB | STRIP_FOOTING | Beton | FU-STREIFEN2\ | Streifenfundament | EG_Technik_FFB | 0104SFu0000027643 | m² | Beton | Ortbeton | false | F004 | 10 | X0, WF | C 25/30 | HA_FUN_STB_0,500x0,500_xxx
Streifenfundament | EG_Technik_FFB | STRIP_FOOTING | Beton | FU-STREIFEN2\ | Streifenfundament | EG_Technik_FFB | 0104SFu0000027679 | m² | Beton | Ortbeton | false | F004 | 10 | X0, WF | C 25/30 | HA_FUN_STB_0,500x0,500_xxx
Streifenfundament | EG_Technik_FFB | STRIP_FOOTING | Beton | FU-STREIFEN2\ | Streifenfundament | EG_Technik_FFB | 0104SFu0000028283 | m² | Beton | Ortbeton | false | F004 | 10 | X0, WF | C 25/30 | HA_FUN_STB_0,500x0,500_xxx
Streifenfundament | EG_Technik_FFB | STRIP_FOOTING | Beton | FU-STREIFEN2\ | Streifenfundament | EG_Technik_FFB | 0104SFu0000028651 | m² | Beton | Ortbeton | false | F004 | 10 | X0, WF | C 25/30 | HA_FUN_STB_0,500x0,500_xxx
Streifenfundament | EG_Technik_FFB | STRIP_FOOTING | Beton | FU-STREIFEN2\ | Streifenfundament | EG_Technik_FFB | 0104SFu0000026474 | m² | Beton | Ortbeton | false | F004 | 10 | X0, WF | C 25/30 | HA_FUN_STB_0,500x0,500_xxx
Streifenfundament | EG_Technik_FFB | STRIP_FOOTING | Beton | FU-STREIFEN2\ | Streifenfundament | EG_Technik_FFB | 0104SFu0000028719 | m² | Beton | Ortbeton | false | F004 | 10 | X0, WF | C 25/30 | HA_FUN_STB_0,500x0,500_xxx
Streifenfundament | EG_Technik_FFB | STRIP_FOOTING | Beton | FU-STREIFEN2\ | Streifenfundament | EG_Technik_FFB | 0104SFu0000026466 | m² | Beton | Ortbeton | false | F004 | 10 | X0, WF | C 25/30 | HA_FUN_STB_0,500x0,500_xxx
Streifenfundament | EG_Technik_FFB | STRIP_FOOTING | Beton | FU-STREIFEN2\ | Streifenfundament | EG_Technik_FFB | 0104SFu0000026470 | m² | Beton | Ortbeton | false | F004 | 10 | X0, WF | C 25/30 | HA_FUN_STB_0,500x0,500_xxx
Streifenfundament | EG_Technik_FFB | STRIP_FOOTING | Beton | FU-STREIFEN2\ | Streifenfundament | EG_Technik_FFB | 0104SFu0000026454 | m² | Beton | Ortbeton | false | F004 | 10 | X0, WF | C 25/30 | HA_FUN_STB_0,500x0,500_xxx
Streifenfundament | EG_Technik_FFB | STRIP_FOOTING | Beton | FU-STREIFEN2\ | Streifenfundament | EG_Technik_FFB | 0104SFu0000026458 | m² | Beton | Ortbeton | false | F004 | 10 | X0, WF | C 25/30 | HA_FUN_STB_0,500x0,500_xxx
Streifenfundament | EG_Technik_FFB | STRIP_FOOTING | Beton | FU-STREIFEN2\ | Streifenfundament | EG_Technik_FFB | 0104SFu0000029185 | m² | Beton | Ortbeton | false | F004 | 10 | X0, WF | C 25/30 | HA_FUN_STB_0,500x0,500_xxx
Streifenfundament | EG_Technik_FFB | STRIP_FOOTING | Beton | FU-STREIFEN2\ | Streifenfundament | EG_Technik_FFB | 0104SFu0000026423 | m² | Beton | Ortbeton | false | F004 | 10 | X0, WF | C 25/30 | HA_FUN_STB_0,500x0,500_xxx
Streifenfundament | EG_Technik_FFB | STRIP_FOOTING | Beton | FU-STREIFEN2\ | Streifenfundament | EG_Technik_FFB | 0104SFu0000029199 | m² | Beton | Ortbeton | false | F004 | 10 | X0, WF | C 25/30 | HA_FUN_STB_0,500x0,500_xxx
Streifenfundament | EG_Technik_FFB | STRIP_FOOTING | Beton | FU-STREIFEN2\ | Streifenfundament | EG_Technik_FFB | 0104SFu0000026446 | m² | Beton | Ortbeton | false | F004 | 10 | X0, WF | C 25/30 | HA_FUN_STB_0,500x0,500_xxx
Streifenfundament | EG_Technik_FFB | STRIP_FOOTING | Beton | FU-STREIFEN2\ | Streifenfundament | EG_Technik_FFB | 0104SFu0000029249 | m² | Beton | Ortbeton | false | F004 | 10 | X0, WF | C 25/30 | HA_FUN_STB_0,500x0,500_xxx
Streifenfundament | EG_Technik_FFB | STRIP_FOOTING | Beton | FU-STREIFEN2\ | Streifenfundament | EG_Technik_FFB | 0104SFu0000026496 | m² | Beton | Ortbeton | false | F004 | 10 | X0, WF | C 25/30 | HA_FUN_STB_0,500x0,500_xxx
Streifenfundament | EG_Technik_FFB | STRIP_FOOTING | Beton | FU-STREIFEN2\ | Streifenfundament | EG_Technik_FFB | 0104SFu0000026492 | m² | Beton | Ortbeton | false | F004 | 10 | X0, WF | C 25/30 | HA_FUN_STB_0,500x0,500_xxx
Streifenfundament | EG_Technik_FFB | STRIP_FOOTING | Beton | FU-STREIFEN2\ | Streifenfundament | EG_Technik_FFB | 0104SFu0000026438 | m² | Beton | Ortbeton | false | F004 | 10 | X0, WF | C 25/30 | HA_FUN_STB_0,500x0,500_xxx
Streifenfundament | EG_Technik_FFB | STRIP_FOOTING | Beton | FU-STREIFEN2\ | Streifenfundament | EG_Technik_FFB | 0104SFu0000028807 | m² | Beton | Ortbeton | false | F004 | 10 | X0, WF | C 25/30 | HA_FUN_STB_0,500x0,500_xxx
Streifenfundament | EG_Technik_FFB | STRIP_FOOTING | Beton | FU-STREIFEN2\ | Streifenfundament | EG_Technik_FFB | 0104SFu0000026516 | m² | Beton | Ortbeton | false | F004 | 10 | X0, WF | C 25/30 | HA_FUN_STB_0,500x0,500_xxx
Streifenfundament | EG_Technik_FFB | STRIP_FOOTING | Beton | FU-STREIFEN2\ | Streifenfundament | EG_Technik_FFB | 0104SFu0000027301 | m² | Beton | Ortbeton | false | F004 | 10 | X0, WF | C 25/30 | HA_FUN_STB_0,500x0,500_xxx
Streifenfundament | EG_Technik_FFB | STRIP_FOOTING | Beton | FU-STREIFEN2\ | Streifenfundament | EG_Technik_FFB | 0104SFu0000028600 | m² | Beton | Ortbeton | false | F004 | 10 | X0, WF | C 25/30 | HA_FUN_STB_0,500x0,500_xxx
Stb.-Streifenfundament | EG_Produktion_FFB | STRIP_FOOTING | Stahlbeton | FU-STREIFEN2\ | Stb.-Streifenfundament | EG_Produktion_FFB | 0114SFu0000035434 | m² | Stahlbeton | Ortbeton | true | F005 | 50 | XC2, WF | C25/30 | HA_FUN_STB_0,500x1,000_xxx
Stb.-Streifenfundament | EG_Produktion_FFB | STRIP_FOOTING | Stahlbeton | FU-STREIFEN2\ | Stb.-Streifenfundament | EG_Produktion_FFB | 0114SFu0000027380 | m² | Stahlbeton | Ortbeton | true | F005 | 50 | XC2, WF | C25/30 | HA_FUN_STB_0,500x1,000_xxx
Stb.-Streifenfundament | EG_Produktion_FFB | STRIP_FOOTING | Stahlbeton | FU-STREIFEN2\ | Stb.-Streifenfundament | EG_Produktion_FFB | 0114SFu0000035416 | m² | Stahlbeton | Ortbeton | true | F005 | 50 | XC2, WF | C25/30 | HA_FUN_STB_0,500x1,000_xxx
Stb.-Streifenfundament | EG_Produktion_FFB | STRIP_FOOTING | Stahlbeton | FU-STREIFEN2\ | Stb.-Streifenfundament | EG_Produktion_FFB | 0114SFu0000035394 | m² | Stahlbeton | Ortbeton | true | F005 | 50 | XC2, WF | C25/30 | HA_FUN_STB_0,500x1,000_xxx
Stb.-Streifenfundament | EG_Produktion_FFB | STRIP_FOOTING | Stahlbeton | FU-STREIFEN2\ | Stb.-Streifenfundament | EG_Produktion_FFB | 0114SFu0000035466 | m² | Stahlbeton | Ortbeton | true | F005 | 50 | XC2, WF | C25/30 | HA_FUN_STB_0,500x1,000_xxx
Stb.-Streifenfundament | EG_Produktion_FFB | STRIP_FOOTING | Stahlbeton | FU-STREIFEN2\ | Stb.-Streifenfundament | EG_Produktion_FFB | 0114SFu0000035458 | m² | Stahlbeton | Ortbeton | true | F005 | 50 | XC2, WF | C25/30 | HA_FUN_STB_0,500x1,000_xxx
Stb.-Streifenfundament | EG_Produktion_FFB | STRIP_FOOTING | Stahlbeton | FU-STREIFEN2\ | Stb.-Streifenfundament | EG_Produktion_FFB | 0114SFu0000035368 | m² | Stahlbeton | Ortbeton | true | F005 | 50 | XC2, WF | C25/30 | HA_FUN_STB_0,500x1,000_xxx
Stb.-Streifenfundament | EG_Produktion_FFB | STRIP_FOOTING | Stahlbeton | FU-STREIFEN2\ | Stb.-Streifenfundament | EG_Produktion_FFB | 0114SFu0000025080 | m² | Stahlbeton | Ortbeton | true | F005 | 50 | XC2, WF | C25/30 | HA_FUN_STB_0,290x0,717_xxx
Stb.-Streifenfundament | EG_Produktion_FFB | STRIP_FOOTING | Stahlbeton | FU-STREIFEN2\ | Stb.-Streifenfundament | EG_Produktion_FFB | 0114SFu0000024922 | m² | Stahlbeton | Ortbeton | true | F005 | 50 | XC2, WF | C25/30 | HA_FUN_STB_0,290x0,717_xxx
Stb.-Streifenfundament | EG_Produktion_FFB | STRIP_FOOTING | Stahlbeton | FU-STREIFEN2\ | Stb.-Streifenfundament | EG_Produktion_FFB | 0114SFu0000035548 | m² | Stahlbeton | Ortbeton | true | F005 | 50 | XC2, WF | C25/30 | HA_FUN_STB_0,500x0,700_xxx
Stb.-Streifenfundament | EG_Produktion_FFB | STRIP_FOOTING | Stahlbeton | FU-STREIFEN2\ | Stb.-Streifenfundament | EG_Produktion_FFB | 0114SFu0000027440 | m² | Stahlbeton | Ortbeton | true | F005 | 50 | XC2, WF | C25/30 | HA_FUN_STB_0,500x1,000_xxx
Stb.-Streifenfundament | EG_Produktion_FFB | STRIP_FOOTING | Stahlbeton | FU-STREIFEN2\ | Stb.-Streifenfundament | EG_Produktion_FFB | 0114SFu0000027470 | m² | Stahlbeton | Ortbeton | true | F005 | 50 | XC2, WF | C25/30 | HA_FUN_STB_0,500x0,700_xxx
Stb.-Streifenfundament | EG_Produktion_FFB | STRIP_FOOTING | Stahlbeton | FU-STREIFEN2\ | Stb.-Streifenfundament | EG_Produktion_FFB | 0114SFu0000017555 | m² | Stahlbeton | Ortbeton | true | F006 | 50 | XC2, WF | C25/30 | HA_FUN_STB_0,500x1,000_xxx
Stb.-Streifenfundament | EG_Produktion_FFB | STRIP_FOOTING | Stahlbeton | FU-STREIFEN2\ | Stb.-Streifenfundament | EG_Produktion_FFB | 0114SFu0000035963 | m² | Stahlbeton | Ortbeton | true | F006 | 50 | XC2, WF | C25/30 | HA_FUN_STB_0,500x0,717_xxx
Stb.-Streifenfundament | EG_Produktion_FFB | STRIP_FOOTING | Stahlbeton | FU-STREIFEN2\ | Stb.-Streifenfundament | EG_Produktion_FFB | 0114SFu0000026186 | m² | Stahlbeton | Ortbeton | true | F006 | 50 | XC2, WF | C25/30 | HA_FUN_STB_0,500x1,000_xxx
Stahlbetonfertigteilfundament | EG_Produktion_FFB | STRIP_FOOTING | Stahlbetonfertigteil | FU-STREIFEN2\ | Stahlbetonfertigteilfundament | EG_Produktion_FFB | 0114SFu0000001613 | m² | Stahlbeton | Fertigteil | false | F002 | 50 | XC1, WO | C25/30 | HA_FUN_FEB_0,250_xxx
Stahlbetonfertigteilfundament | EG_Produktion_FFB | STRIP_FOOTING | Stahlbetonfertigteil | FU-STREIFEN2\ | Stahlbetonfertigteilfundament | EG_Produktion_FFB | 0114SFu0000001615 | m² | Stahlbeton | Fertigteil | false | F002 | 50 | XC1, WO | C25/30 | HA_FUN_FEB_0,250_xxx
Stahlbetonfertigteilfundament | EG_Produktion_FFB | STRIP_FOOTING | Stahlbetonfertigteil | FU-STREIFEN2\ | Stahlbetonfertigteilfundament | EG_Produktion_FFB | 0114SFu0000001653 | m² | Stahlbeton | Fertigteil | false | F002 | 50 | XC1, WO | C25/30 | HA_FUN_FEB_0,250_xxx
Stahlbetonfertigteilfundament | EG_Produktion_FFB | STRIP_FOOTING | Stahlbetonfertigteil | FU-STREIFEN2\ | Stahlbetonfertigteilfundament | EG_Produktion_FFB | 0114SFu0000001655 | m² | Stahlbeton | Fertigteil | false | F002 | 50 | XC1, WO | C25/30 | HA_FUN_FEB_0,250_xxx
Stahlbetonfertigteilfundament | EG_Produktion_FFB | STRIP_FOOTING | Stahlbetonfertigteil | FU-STREIFEN2\ | Stahlbetonfertigteilfundament | EG_Produktion_FFB | 0114SFu0000001649 | m² | Stahlbeton | Fertigteil | false | F002 | 50 | XC1, WO | C25/30 | HA_FUN_FEB_0,250_xxx
Stahlbetonfertigteilfundament | EG_Produktion_FFB | STRIP_FOOTING | Stahlbetonfertigteil | FU-STREIFEN2\ | Stahlbetonfertigteilfundament | EG_Produktion_FFB | 0114SFu0000001651 | m² | Stahlbeton | Fertigteil | false | F002 | 50 | XC1, WO | C25/30 | HA_FUN_FEB_0,250_xxx
Stahlbetonfertigteilfundament | EG_Produktion_FFB | STRIP_FOOTING | Stahlbetonfertigteil | FU-STREIFEN2\ | Stahlbetonfertigteilfundament | EG_Produktion_FFB | 0114SFu0000001637 | m² | Stahlbeton | Fertigteil | false | F002 | 50 | XC1, WO | C25/30 | HA_FUN_FEB_0,250_xxx
Stahlbetonfertigteilfundament | EG_Produktion_FFB | STRIP_FOOTING | Stahlbetonfertigteil | FU-STREIFEN2\ | Stahlbetonfertigteilfundament | EG_Produktion_FFB | 0114SFu0000001639 | m² | Stahlbeton | Fertigteil | false | F002 | 50 | XC1, WO | C25/30 | HA_FUN_FEB_0,250_xxx
Stahlbetonfertigteilfundament | EG_Produktion_FFB | STRIP_FOOTING | Stahlbetonfertigteil | FU-STREIFEN2\ | Stahlbetonfertigteilfundament | EG_Produktion_FFB | 0114SFu0000001621 | m² | Stahlbeton | Fertigteil | false | F002 | 50 | XC1, WO | C25/30 | HA_FUN_FEB_0,250_xxx
Stahlbetonfertigteilfundament | EG_Produktion_FFB | STRIP_FOOTING | Stahlbetonfertigteil | FU-STREIFEN2\ | Stahlbetonfertigteilfundament | EG_Produktion_FFB | 0114SFu0000001623 | m² | Stahlbeton | Fertigteil | false | F002 | 50 | XC1, WO | C25/30 | HA_FUN_FEB_0,250_xxx
Stahlbetonfertigteilfundament | EG_Produktion_FFB | STRIP_FOOTING | Stahlbetonfertigteil | FU-STREIFEN2\ | Stahlbetonfertigteilfundament | EG_Produktion_FFB | 0114SFu0000003157 | m² | Stahlbeton | Fertigteil | false | F002 | 50 | XC1, WO | C25/30 | HA_FUN_FEB_0,250_xxx
Stahlbetonfertigteilfundament | EG_Produktion_FFB | STRIP_FOOTING | Stahlbetonfertigteil | FU-STREIFEN2\ | Stahlbetonfertigteilfundament | EG_Produktion_FFB | 0114SFu0000003156 | m² | Stahlbeton | Fertigteil | false | F002 | 50 | XC1, WO | C25/30 | HA_FUN_FEB_0,250_xxx
Stahlbetonfertigteilfundament | EG_Produktion_FFB | STRIP_FOOTING | Stahlbetonfertigteil | FU-STREIFEN2\ | Stahlbetonfertigteilfundament | EG_Produktion_FFB | 0114SFu0000001645 | m² | Stahlbeton | Fertigteil | false | F002 | 50 | XC1, WO | C25/30 | HA_FUN_FEB_0,250_xxx
Stahlbetonfertigteilfundament | EG_Produktion_FFB | STRIP_FOOTING | Stahlbetonfertigteil | FU-STREIFEN2\ | Stahlbetonfertigteilfundament | EG_Produktion_FFB | 0114SFu0000001647 | m² | Stahlbeton | Fertigteil | false | F002 | 50 | XC1, WO | C25/30 | HA_FUN_FEB_0,250_xxx
Stahlbetonfertigteilfundament | EG_Produktion_FFB | STRIP_FOOTING | Stahlbetonfertigteil | FU-STREIFEN2\ | Stahlbetonfertigteilfundament | EG_Produktion_FFB | 0114SFu0000001641 | m² | Stahlbeton | Fertigteil | false | F002 | 50 | XC1, WO | C25/30 | HA_FUN_FEB_0,250_xxx
Stahlbetonfertigteilfundament | EG_Produktion_FFB | STRIP_FOOTING | Stahlbetonfertigteil | FU-STREIFEN2\ | Stahlbetonfertigteilfundament | EG_Produktion_FFB | 0114SFu0000001643 | m² | Stahlbeton | Fertigteil | false | F002 | 50 | XC1, WO | C25/30 | HA_FUN_FEB_0,250_xxx
Stahlbetonfertigteilfundament | EG_Produktion_FFB | STRIP_FOOTING | Stahlbetonfertigteil | FU-STREIFEN2\ | Stahlbetonfertigteilfundament | EG_Produktion_FFB | 0114SFu0000001633 | m² | Stahlbeton | Fertigteil | false | F002 | 50 | XC1, WO | C25/30 | HA_FUN_FEB_0,250_xxx
Stahlbetonfertigteilfundament | EG_Produktion_FFB | STRIP_FOOTING | Stahlbetonfertigteil | FU-STREIFEN2\ | Stahlbetonfertigteilfundament | EG_Produktion_FFB | 0114SFu0000001635 | m² | Stahlbeton | Fertigteil | false | F002 | 50 | XC1, WO | C25/30 | HA_FUN_FEB_0,250_xxx
Stahlbetonfertigteilfundament | EG_Produktion_FFB | STRIP_FOOTING | Stahlbetonfertigteil | FU-STREIFEN2\ | Stahlbetonfertigteilfundament | EG_Produktion_FFB | 0114SFu0000031137 | m² | Stahlbeton | Fertigteil | false | F002 | 50 | XC1, WO | C25/30 | HA_FUN_FEB_0,250_xxx
Stahlbetonfertigteilfundament | EG_Produktion_FFB | STRIP_FOOTING | Stahlbetonfertigteil | FU-STREIFEN2\ | Stahlbetonfertigteilfundament | EG_Produktion_FFB | 0114SFu0000031343 | m² | Stahlbeton | Fertigteil | false | F002 | 50 | XC1, WO | C25/30 | HA_FUN_FEB_0,250_xxx
Stahlbetonfertigteilfundament | EG_Produktion_FFB | STRIP_FOOTING | Stahlbetonfertigteil | FU-STREIFEN2\ | Stahlbetonfertigteilfundament | EG_Produktion_FFB | 0114SFu0000031138 | m² | Stahlbeton | Fertigteil | false | F002 | 50 | XC1, WO | C25/30 | HA_FUN_FEB_0,250_xxx
Stahlbetonfertigteilfundament | EG_Produktion_FFB | STRIP_FOOTING | Stahlbetonfertigteil | FU-STREIFEN2\ | Stahlbetonfertigteilfundament | EG_Produktion_FFB | 0114SFu0000031344 | m² | Stahlbeton | Fertigteil | false | F002 | 50 | XC1, WO | C25/30 | HA_FUN_FEB_0,250_xxx
Stahlbetonfertigteilfundament | EG_Produktion_FFB | STRIP_FOOTING | Stahlbetonfertigteil | FU-STREIFEN2\ | Stahlbetonfertigteilfundament | EG_Produktion_FFB | 0114SFu0000031502 | m² | Stahlbeton | Fertigteil | false | F002 | 50 | XC1, WO | C25/30 | HA_FUN_FEB_0,250_xxx
Stahlbetonfertigteilfundament | EG_Produktion_FFB | STRIP_FOOTING | Stahlbetonfertigteil | FU-STREIFEN2\ | Stahlbetonfertigteilfundament | EG_Produktion_FFB | 0114SFu0000031498 | m² | Stahlbeton | Fertigteil | false | F002 | 50 | XC1, WO | C25/30 | HA_FUN_FEB_0,250_xxx
Stahlbetonfertigteilfundament | EG_Produktion_FFB | STRIP_FOOTING | Stahlbetonfertigteil | FU-STREIFEN2\ | Stahlbetonfertigteilfundament | EG_Produktion_FFB | 0114SFu0000031503 | m² | Stahlbeton | Fertigteil | false | F002 | 50 | XC1, WO | C25/30 | HA_FUN_FEB_0,250_xxx
Stahlbetonfertigteilfundament | EG_Produktion_FFB | STRIP_FOOTING | Stahlbetonfertigteil | FU-STREIFEN2\ | Stahlbetonfertigteilfundament | EG_Produktion_FFB | 0114SFu0000031499 | m² | Stahlbeton | Fertigteil | false | F002 | 50 | XC1, WO | C25/30 | HA_FUN_FEB_0,250_xxx
Stahlbetonfertigteilfundament | EG_Produktion_FFB | STRIP_FOOTING | Stahlbetonfertigteil | FU-STREIFEN2\ | Stahlbetonfertigteilfundament | EG_Produktion_FFB | 0114SFu0000031506 | m² | Stahlbeton | Fertigteil | false | F002 | 50 | XC1, WO | C25/30 | HA_FUN_FEB_0,250_xxx
Stahlbetonfertigteilfundament | EG_Produktion_FFB | STRIP_FOOTING | Stahlbetonfertigteil | FU-STREIFEN2\ | Stahlbetonfertigteilfundament | EG_Produktion_FFB | 0114SFu0000031507 | m² | Stahlbeton | Fertigteil | false | F002 | 50 | XC1, WO | C25/30 | HA_FUN_FEB_0,250_xxx
Stahlbetonfertigteilfundament | EG_Produktion_FFB | STRIP_FOOTING | Stahlbetonfertigteil | FU-STREIFEN2\ | Stahlbetonfertigteilfundament | EG_Produktion_FFB | 0114SFu0000031287 | m² | Stahlbeton | Fertigteil | false | F002 | 50 | XC1, WO | C25/30 | HA_FUN_FEB_0,250_xxx
Stahlbetonfertigteilfundament | EG_Produktion_FFB | STRIP_FOOTING | Stahlbetonfertigteil | FU-STREIFEN2\ | Stahlbetonfertigteilfundament | EG_Produktion_FFB | 0114SFu0000031316 | m² | Stahlbeton | Fertigteil | false | F002 | 50 | XC1, WO | C25/30 | HA_FUN_FEB_0,250_xxx
Stahlbetonfertigteilfundament | EG_Produktion_FFB | STRIP_FOOTING | Stahlbetonfertigteil | FU-STREIFEN2\ | Stahlbetonfertigteilfundament | EG_Produktion_FFB | 0114SFu0000031286 | m² | Stahlbeton | Fertigteil | false | F002 | 50 | XC1, WO | C25/30 | HA_FUN_FEB_0,250_xxx
Stahlbetonfertigteilfundament | EG_Produktion_FFB | STRIP_FOOTING | Stahlbetonfertigteil | FU-STREIFEN2\ | Stahlbetonfertigteilfundament | EG_Produktion_FFB | 0114SFu0000001657 | m² | Stahlbeton | Fertigteil | false | F002 | 50 | XC1, WO | C25/30 | HA_FUN_FEB_0,250_xxx
Stahlbetonfertigteilfundament | EG_Produktion_FFB | STRIP_FOOTING | Stahlbetonfertigteil | FU-STREIFEN2\ | Stahlbetonfertigteilfundament | EG_Produktion_FFB | 0114SFu0000001659 | m² | Stahlbeton | Fertigteil | false | F002 | 50 | XC1, WO | C25/30 | HA_FUN_FEB_0,250_xxx
Stahlbetonfertigteilfundament | EG_Produktion_FFB | STRIP_FOOTING | Stahlbetonfertigteil | FU-STREIFEN2\ | Stahlbetonfertigteilfundament | EG_Produktion_FFB | 0114SFu0000001629 | m² | Stahlbeton | Fertigteil | false | F002 | 50 | XC1, WO | C25/30 | HA_FUN_FEB_0,250_xxx
Stahlbetonfertigteilfundament | EG_Produktion_FFB | STRIP_FOOTING | Stahlbetonfertigteil | FU-STREIFEN2\ | Stahlbetonfertigteilfundament | EG_Produktion_FFB | 0114SFu0000001631 | m² | Stahlbeton | Fertigteil | false | F002 | 50 | XC1, WO | C25/30 | HA_FUN_FEB_0,250_xxx
Stahlbetonfertigteilfundament | EG_Produktion_FFB | STRIP_FOOTING | Stahlbetonfertigteil | FU-STREIFEN2\ | Stahlbetonfertigteilfundament | EG_Produktion_FFB | 0114SFu0000001625 | m² | Stahlbeton | Fertigteil | false | F002 | 50 | XC1, WO | C25/30 | HA_FUN_FEB_0,250_xxx
Stahlbetonfertigteilfundament | EG_Produktion_FFB | STRIP_FOOTING | Stahlbetonfertigteil | FU-STREIFEN2\ | Stahlbetonfertigteilfundament | EG_Produktion_FFB | 0114SFu0000001627 | m² | Stahlbeton | Fertigteil | false | F002 | 50 | XC1, WO | C25/30 | HA_FUN_FEB_0,250_xxx
Stahlbetonfertigteilfundament | EG_Produktion_FFB | STRIP_FOOTING | Stahlbetonfertigteil | FU-STREIFEN2\ | Stahlbetonfertigteilfundament | EG_Produktion_FFB | 0114SFu0000001617 | m² | Stahlbeton | Fertigteil | false | F002 | 50 | XC1, WO | C25/30 | HA_FUN_FEB_0,250_xxx
Stahlbetonfertigteilfundament | EG_Produktion_FFB | STRIP_FOOTING | Stahlbetonfertigteil | FU-STREIFEN2\ | Stahlbetonfertigteilfundament | EG_Produktion_FFB | 0114SFu0000001619 | m² | Stahlbeton | Fertigteil | false | F002 | 50 | XC1, WO | C25/30 | HA_FUN_FEB_0,250_xxx
Stahlbetonfertigteilfundament | EG_Produktion_FFB | STRIP_FOOTING | Stahlbetonfertigteil | FU-STREIFEN2\ | Stahlbetonfertigteilfundament | EG_Produktion_FFB | 0114SFu0000031382 | m² | Stahlbeton | Fertigteil | false | F002 | 50 | XC1, WO | C25/30 | HA_FUN_FEB_0,250_xxx
Stahlbetonfertigteilfundament | EG_Produktion_FFB | STRIP_FOOTING | Stahlbetonfertigteil | FU-STREIFEN2\ | Stahlbetonfertigteilfundament | EG_Produktion_FFB | 0114SFu0000031379 | m² | Stahlbeton | Fertigteil | false | F002 | 50 | XC1, WO | C25/30 | HA_FUN_FEB_0,250_xxx
Stahlbetonfertigteilfundament | EG_Produktion_FFB | STRIP_FOOTING | Stahlbetonfertigteil | FU-STREIFEN2\ | Stahlbetonfertigteilfundament | EG_Produktion_FFB | 0114SFu0000031440 | m² | Stahlbeton | Fertigteil | false | F002 | 50 | XC1, WO | C25/30 | HA_FUN_FEB_0,250_xxx
Stahlbetonfertigteilfundament | EG_Produktion_FFB | STRIP_FOOTING | Stahlbetonfertigteil | FU-STREIFEN2\ | Stahlbetonfertigteilfundament | EG_Produktion_FFB | 0114SFu0000031442 | m² | Stahlbeton | Fertigteil | false | F002 | 50 | XC1, WO | C25/30 | HA_FUN_FEB_0,250_xxx
Stahlbetonfertigteilfundament | EG_Produktion_FFB | STRIP_FOOTING | Stahlbetonfertigteil | FU-STREIFEN2\ | Stahlbetonfertigteilfundament | EG_Produktion_FFB | 0114SFu0000031443 | m² | Stahlbeton | Fertigteil | false | F002 | 50 | XC1, WO | C25/30 | HA_FUN_FEB_0,250_xxx
Stahlbetonfertigteilfundament | EG_Produktion_FFB | STRIP_FOOTING | Stahlbetonfertigteil | FU-STREIFEN2\ | Stahlbetonfertigteilfundament | EG_Produktion_FFB | 0114SFu0000001607 | m² | Stahlbeton | Fertigteil | false | F002 | 50 | XC1, WO | C25/30 | HA_FUN_FEB_0,250_xxx
Stahlbetonfertigteilfundament | EG_Produktion_FFB | STRIP_FOOTING | Stahlbetonfertigteil | FU-STREIFEN2\ | Stahlbetonfertigteilfundament | EG_Produktion_FFB | 0114SFu0000001609 | m² | Stahlbeton | Fertigteil | false | F002 | 50 | XC1, WO | C25/30 | HA_FUN_FEB_0,250_xxx
Stahlbetonfertigteilfundament | EG_Produktion_FFB | STRIP_FOOTING | Stahlbetonfertigteil | FU-STREIFEN2\ | Stahlbetonfertigteilfundament | EG_Produktion_FFB | 0114SFu0000031429 | m² | Stahlbeton | Fertigteil | false | F002 | 50 | XC1, WO | C25/30 | HA_FUN_FEB_0,250_xxx
Stahlbetonfertigteilfundament | EG_Produktion_FFB | STRIP_FOOTING | Stahlbetonfertigteil | FU-STREIFEN2\ | Stahlbetonfertigteilfundament | EG_Produktion_FFB | 0114SFu0000034166 | m² | Stahlbeton | Fertigteil | false | F002 | 50 | XC1, WO | C25/30 | HA_FUN_FEB_0,250_xxx
Stahlbetonfertigteilfundament | EG_Produktion_FFB | STRIP_FOOTING | Stahlbetonfertigteil | FU-STREIFEN2\ | Stahlbetonfertigteilfundament | EG_Produktion_FFB | 0114SFu0000001685 | m² | Stahlbeton | Fertigteil | false | F002 | 50 | XC1, WO | C25/30 | HA_FUN_FEB_0,250_xxx
Stahlbetonfertigteilfundament | EG_Produktion_FFB | STRIP_FOOTING | Stahlbetonfertigteil | FU-STREIFEN2\ | Stahlbetonfertigteilfundament | EG_Produktion_FFB | 0114SFu0000001683 | m² | Stahlbeton | Fertigteil | false | F002 | 50 | XC1, WO | C25/30 | HA_FUN_FEB_0,250_xxx
Stahlbetonfertigteilfundament | EG_Produktion_FFB | STRIP_FOOTING | Stahlbetonfertigteil | FU-STREIFEN2\ | Stahlbetonfertigteilfundament | EG_Produktion_FFB | 0114SFu0000001693 | m² | Stahlbeton | Fertigteil | false | F002 | 50 | XC1, WO | C25/30 | HA_FUN_FEB_0,250_xxx
Stahlbetonfertigteilfundament | EG_Produktion_FFB | STRIP_FOOTING | Stahlbetonfertigteil | FU-STREIFEN2\ | Stahlbetonfertigteilfundament | EG_Produktion_FFB | 0114SFu0000001691 | m² | Stahlbeton | Fertigteil | false | F002 | 50 | XC1, WO | C25/30 | HA_FUN_FEB_0,250_xxx
Stahlbetonfertigteilfundament | EG_Produktion_FFB | STRIP_FOOTING | Stahlbetonfertigteil | FU-STREIFEN2\ | Stahlbetonfertigteilfundament | EG_Produktion_FFB | 0114SFu0000001701 | m² | Stahlbeton | Fertigteil | false | F002 | 50 | XC1, WO | C25/30 | HA_FUN_FEB_0,250_xxx
Stahlbetonfertigteilfundament | EG_Produktion_FFB | STRIP_FOOTING | Stahlbetonfertigteil | FU-STREIFEN2\ | Stahlbetonfertigteilfundament | EG_Produktion_FFB | 0114SFu0000001699 | m² | Stahlbeton | Fertigteil | false | F002 | 50 | XC1, WO | C25/30 | HA_FUN_FEB_0,250_xxx
Stahlbetonfertigteilfundament | EG_Produktion_FFB | STRIP_FOOTING | Stahlbetonfertigteil | FU-STREIFEN2\ | Stahlbetonfertigteilfundament | EG_Produktion_FFB | 0114SFu0000001707 | m² | Stahlbeton | Fertigteil | false | F002 | 50 | XC1, WO | C25/30 | HA_FUN_FEB_0,250_xxx
Stahlbetonfertigteilfundament | EG_Produktion_FFB | STRIP_FOOTING | Stahlbetonfertigteil | FU-STREIFEN2\ | Stahlbetonfertigteilfundament | EG_Produktion_FFB | 0114SFu0000001709 | m² | Stahlbeton | Fertigteil | false | F002 | 50 | XC1, WO | C25/30 | HA_FUN_FEB_0,250_xxx
Stahlbetonfertigteilfundament | EG_Produktion_FFB | STRIP_FOOTING | Stahlbetonfertigteil | FU-STREIFEN2\ | Stahlbetonfertigteilfundament | EG_Produktion_FFB | 0114SFu0000001725 | m² | Stahlbeton | Fertigteil | false | F002 | 50 | XC1, WO | C25/30 | HA_FUN_FEB_0,250_xxx
Stahlbetonfertigteilfundament | EG_Produktion_FFB | STRIP_FOOTING | Stahlbetonfertigteil | FU-STREIFEN2\ | Stahlbetonfertigteilfundament | EG_Produktion_FFB | 0114SFu0000001723 | m² | Stahlbeton | Fertigteil | false | F002 | 50 | XC1, WO | C25/30 | HA_FUN_FEB_0,250_xxx
Stahlbetonfertigteilfundament | EG_Produktion_FFB | STRIP_FOOTING | Stahlbetonfertigteil | FU-STREIFEN2\ | Stahlbetonfertigteilfundament | EG_Produktion_FFB | 0114SFu0000001717 | m² | Stahlbeton | Fertigteil | false | F002 | 50 | XC1, WO | C25/30 | HA_FUN_FEB_0,250_xxx
Stahlbetonfertigteilfundament | EG_Produktion_FFB | STRIP_FOOTING | Stahlbetonfertigteil | FU-STREIFEN2\ | Stahlbetonfertigteilfundament | EG_Produktion_FFB | 0114SFu0000001715 | m² | Stahlbeton | Fertigteil | false | F002 | 50 | XC1, WO | C25/30 | HA_FUN_FEB_0,250_xxx
Stahlbetonfertigteilfundament | EG_Produktion_FFB | STRIP_FOOTING | Stahlbetonfertigteil | FU-STREIFEN2\ | Stahlbetonfertigteilfundament | EG_Produktion_FFB | 0114SFu0000001733 | m² | Stahlbeton | Fertigteil | false | F002 | 50 | XC1, WO | C25/30 | HA_FUN_FEB_0,250_xxx
Stahlbetonfertigteilfundament | EG_Produktion_FFB | STRIP_FOOTING | Stahlbetonfertigteil | FU-STREIFEN2\ | Stahlbetonfertigteilfundament | EG_Produktion_FFB | 0114SFu0000001731 | m² | Stahlbeton | Fertigteil | false | F002 | 50 | XC1, WO | C25/30 | HA_FUN_FEB_0,250_xxx
Stahlbetonfertigteilfundament | EG_Produktion_FFB | STRIP_FOOTING | Stahlbetonfertigteil | FU-STREIFEN2\ | Stahlbetonfertigteilfundament | EG_Produktion_FFB | 0114SFu0000001741 | m² | Stahlbeton | Fertigteil | false | F002 | 50 | XC1, WO | C25/30 | HA_FUN_FEB_0,250_xxx
Stahlbetonfertigteilfundament | EG_Produktion_FFB | STRIP_FOOTING | Stahlbetonfertigteil | FU-STREIFEN2\ | Stahlbetonfertigteilfundament | EG_Produktion_FFB | 0114SFu0000001739 | m² | Stahlbeton | Fertigteil | false | F002 | 50 | XC1, WO | C25/30 | HA_FUN_FEB_0,250_xxx
Stahlbetonfertigteilfundament | EG_Produktion_FFB | STRIP_FOOTING | Stahlbetonfertigteil | FU-STREIFEN2\ | Stahlbetonfertigteilfundament | EG_Produktion_FFB | 0114SFu0000001749 | m² | Stahlbeton | Fertigteil | false | F002 | 50 | XC1, WO | C25/30 | HA_FUN_FEB_0,250_xxx
Stahlbetonfertigteilfundament | EG_Produktion_FFB | STRIP_FOOTING | Stahlbetonfertigteil | FU-STREIFEN2\ | Stahlbetonfertigteilfundament | EG_Produktion_FFB | 0114SFu0000001747 | m² | Stahlbeton | Fertigteil | false | F002 | 50 | XC1, WO | C25/30 | HA_FUN_FEB_0,250_xxx
Stahlbetonfertigteilfundament | EG_Produktion_FFB | STRIP_FOOTING | Stahlbetonfertigteil | FU-STREIFEN2\ | Stahlbetonfertigteilfundament | EG_Produktion_FFB | 0114SFu0000001757 | m² | Stahlbeton | Fertigteil | false | F002 | 50 | XC1, WO | C25/30 | HA_FUN_FEB_0,250_xxx
Stahlbetonfertigteilfundament | EG_Produktion_FFB | STRIP_FOOTING | Stahlbetonfertigteil | FU-STREIFEN2\ | Stahlbetonfertigteilfundament | EG_Produktion_FFB | 0114SFu0000001755 | m² | Stahlbeton | Fertigteil | false | F002 | 50 | XC1, WO | C25/30 | HA_FUN_FEB_0,250_xxx
Stahlbetonfertigteilfundament | EG_Produktion_FFB | STRIP_FOOTING | Stahlbetonfertigteil | FU-STREIFEN2\ | Stahlbetonfertigteilfundament | EG_Produktion_FFB | 0114SFu0000001765 | m² | Stahlbeton | Fertigteil | false | F002 | 50 | XC1, WO | C25/30 | HA_FUN_FEB_0,250_xxx
Stahlbetonfertigteilfundament | EG_Produktion_FFB | STRIP_FOOTING | Stahlbetonfertigteil | FU-STREIFEN2\ | Stahlbetonfertigteilfundament | EG_Produktion_FFB | 0114SFu0000001763 | m² | Stahlbeton | Fertigteil | false | F002 | 50 | XC1, WO | C25/30 | HA_FUN_FEB_0,250_xxx
Stahlbetonfertigteilfundament | EG_Produktion_FFB | STRIP_FOOTING | Stahlbetonfertigteil | FU-STREIFEN2\ | Stahlbetonfertigteilfundament | EG_Produktion_FFB | 0114SFu0000001773 | m² | Stahlbeton | Fertigteil | false | F002 | 50 | XC1, WO | C25/30 | HA_FUN_FEB_0,250_xxx
Stahlbetonfertigteilfundament | EG_Produktion_FFB | STRIP_FOOTING | Stahlbetonfertigteil | FU-STREIFEN2\ | Stahlbetonfertigteilfundament | EG_Produktion_FFB | 0114SFu0000001771 | m² | Stahlbeton | Fertigteil | false | F002 | 50 | XC1, WO | C25/30 | HA_FUN_FEB_0,250_xxx
Stahlbetonfertigteilfundament | EG_Produktion_FFB | STRIP_FOOTING | Stahlbetonfertigteil | FU-STREIFEN2\ | Stahlbetonfertigteilfundament | EG_Produktion_FFB | 0114SFu0000001781 | m² | Stahlbeton | Fertigteil | false | F002 | 50 | XC1, WO | C25/30 | HA_FUN_FEB_0,250_xxx
Stahlbetonfertigteilfundament | EG_Produktion_FFB | STRIP_FOOTING | Stahlbetonfertigteil | FU-STREIFEN2\ | Stahlbetonfertigteilfundament | EG_Produktion_FFB | 0114SFu0000001779 | m² | Stahlbeton | Fertigteil | false | F002 | 50 | XC1, WO | C25/30 | HA_FUN_FEB_0,250_xxx
Stahlbetonfertigteilfundament | EG_Produktion_FFB | STRIP_FOOTING | Stahlbetonfertigteil | FU-STREIFEN2\ | Stahlbetonfertigteilfundament | EG_Produktion_FFB | 0114SFu0000001789 | m² | Stahlbeton | Fertigteil | false | F002 | 50 | XC1, WO | C25/30 | HA_FUN_FEB_0,250_xxx
Stahlbetonfertigteilfundament | EG_Produktion_FFB | STRIP_FOOTING | Stahlbetonfertigteil | FU-STREIFEN2\ | Stahlbetonfertigteilfundament | EG_Produktion_FFB | 0114SFu0000001787 | m² | Stahlbeton | Fertigteil | false | F002 | 50 | XC1, WO | C25/30 | HA_FUN_FEB_0,250_xxx
Stahlbetonfertigteilfundament | EG_Produktion_FFB | STRIP_FOOTING | Stahlbetonfertigteil | FU-STREIFEN2\ | Stahlbetonfertigteilfundament | EG_Produktion_FFB | 0114SFu0000001675 | m² | Stahlbeton | Fertigteil | false | F002 | 50 | XC1, WO | C25/30 | HA_FUN_FEB_0,250_xxx
Stahlbetonfertigteilfundament | EG_Produktion_FFB | STRIP_FOOTING | Stahlbetonfertigteil | FU-STREIFEN2\ | Stahlbetonfertigteilfundament | EG_Produktion_FFB | 0114SFu0000001677 | m² | Stahlbeton | Fertigteil | false | F002 | 50 | XC1, WO | C25/30 | HA_FUN_FEB_0,250_xxx
Stahlbetonfertigteilfundament | EG_Produktion_FFB | STRIP_FOOTING | Stahlbetonfertigteil | FU-STREIFEN2\ | Stahlbetonfertigteilfundament | EG_Produktion_FFB | 0114SFu0000031571 | m² | Stahlbeton | Fertigteil | false | F002 | 50 | XC1, WO | C25/30 | HA_FUN_FEB_0,250_xxx
Stahlbetonfertigteilfundament | EG_Produktion_FFB | STRIP_FOOTING | Stahlbetonfertigteil | FU-STREIFEN2\ | Stahlbetonfertigteilfundament | EG_Produktion_FFB | 0114SFu0000031553 | m² | Stahlbeton | Fertigteil | false | F002 | 50 | XC1, WO | C25/30 | HA_FUN_FEB_0,250_xxx
Stahlbetonfertigteilfundament | EG_Produktion_FFB | STRIP_FOOTING | Stahlbetonfertigteil | FU-STREIFEN2\ | Stahlbetonfertigteilfundament | EG_Produktion_FFB | 0114SFu0000001671 | m² | Stahlbeton | Fertigteil | false | F002 | 50 | XC1, WO | C25/30 | HA_FUN_FEB_0,250_xxx
Stahlbetonfertigteilfundament | EG_Produktion_FFB | STRIP_FOOTING | Stahlbetonfertigteil | FU-STREIFEN2\ | Stahlbetonfertigteilfundament | EG_Produktion_FFB | 0114SFu0000001673 | m² | Stahlbeton | Fertigteil | false | F002 | 50 | XC1, WO | C25/30 | HA_FUN_FEB_0,250_xxx
Stahlbetonfertigteilfundament | EG_Produktion_FFB | STRIP_FOOTING | Stahlbetonfertigteil | FU-STREIFEN2\ | Stahlbetonfertigteilfundament | EG_Produktion_FFB | 0114SFu0000031570 | m² | Stahlbeton | Fertigteil | false | F002 | 50 | XC1, WO | C25/30 | HA_FUN_FEB_0,250_xxx
Stahlbetonfertigteilfundament | EG_Produktion_FFB | STRIP_FOOTING | Stahlbetonfertigteil | FU-STREIFEN2\ | Stahlbetonfertigteilfundament | EG_Produktion_FFB | 0114SFu0000031636 | m² | Stahlbeton | Fertigteil | false | F002 | 50 | XC1, WO | C25/30 | HA_FUN_FEB_0,250_xxx
Stahlbetonfertigteilfundament | EG_Produktion_FFB | STRIP_FOOTING | Stahlbetonfertigteil | FU-STREIFEN2\ | Stahlbetonfertigteilfundament | EG_Produktion_FFB | 0114SFu0000031640 | m² | Stahlbeton | Fertigteil | false | F002 | 50 | XC1, WO | C25/30 | HA_FUN_FEB_0,250_xxx
Stahlbetonfertigteilfundament | EG_Produktion_FFB | STRIP_FOOTING | Stahlbetonfertigteil | FU-STREIFEN2\ | Stahlbetonfertigteilfundament | EG_Produktion_FFB | 0114SFu0000031637 | m² | Stahlbeton | Fertigteil | false | F002 | 50 | XC1, WO | C25/30 | HA_FUN_FEB_0,250_xxx
Stahlbetonfertigteilfundament | EG_Produktion_FFB | STRIP_FOOTING | Stahlbetonfertigteil | FU-STREIFEN2\ | Stahlbetonfertigteilfundament | EG_Produktion_FFB | 0114SFu0000031641 | m² | Stahlbeton | Fertigteil | false | F002 | 50 | XC1, WO | C25/30 | HA_FUN_FEB_0,250_xxx
Stahlbetonfertigteilfundament | EG_Produktion_FFB | STRIP_FOOTING | Stahlbetonfertigteil | FU-STREIFEN2\ | Stahlbetonfertigteilfundament | EG_Produktion_FFB | 0114SFu0000031792 | m² | Stahlbeton | Fertigteil | false | F002 | 50 | XC1, WO | C25/30 | HA_FUN_FEB_0,250_xxx
Stahlbetonfertigteilfundament | EG_Produktion_FFB | STRIP_FOOTING | Stahlbetonfertigteil | FU-STREIFEN2\ | Stahlbetonfertigteilfundament | EG_Produktion_FFB | 0114SFu0000031791 | m² | Stahlbeton | Fertigteil | false | F002 | 50 | XC1, WO | C25/30 | HA_FUN_FEB_0,250_xxx
Stahlbetonfertigteilfundament | EG_Produktion_FFB | STRIP_FOOTING | Stahlbetonfertigteil | FU-STREIFEN2\ | Stahlbetonfertigteilfundament | EG_Produktion_FFB | 0114SFu0000031861 | m² | Stahlbeton | Fertigteil | false | F002 | 50 | XC1, WO | C25/30 | HA_FUN_FEB_0,250_xxx
Stahlbetonfertigteilfundament | EG_Produktion_FFB | STRIP_FOOTING | Stahlbetonfertigteil | FU-STREIFEN2\ | Stahlbetonfertigteilfundament | EG_Produktion_FFB | 0114SFu0000031857 | m² | Stahlbeton | Fertigteil | false | F002 | 50 | XC1, WO | C25/30 | HA_FUN_FEB_0,250_xxx
Stahlbetonfertigteilfundament | EG_Produktion_FFB | STRIP_FOOTING | Stahlbetonfertigteil | FU-STREIFEN2\ | Stahlbetonfertigteilfundament | EG_Produktion_FFB | 0114SFu0000031699 | m² | Stahlbeton | Fertigteil | false | F002 | 50 | XC1, WO | C25/30 | HA_FUN_FEB_0,250_xxx
Stahlbetonfertigteilfundament | EG_Produktion_FFB | STRIP_FOOTING | Stahlbetonfertigteil | FU-STREIFEN2\ | Stahlbetonfertigteilfundament | EG_Produktion_FFB | 0114SFu0000031698 | m² | Stahlbeton | Fertigteil | false | F002 | 50 | XC1, WO | C25/30 | HA_FUN_FEB_0,250_xxx
Stahlbetonfertigteilfundament | EG_Produktion_FFB | STRIP_FOOTING | Stahlbetonfertigteil | FU-STREIFEN2\ | Stahlbetonfertigteilfundament | EG_Produktion_FFB | 0114SFu0000031858 | m² | Stahlbeton | Fertigteil | false | F002 | 50 | XC1, WO | C25/30 | HA_FUN_FEB_0,250_xxx
Stahlbetonfertigteilfundament | EG_Produktion_FFB | STRIP_FOOTING | Stahlbetonfertigteil | FU-STREIFEN2\ | Stahlbetonfertigteilfundament | EG_Produktion_FFB | 0114SFu0000031862 | m² | Stahlbeton | Fertigteil | false | F002 | 50 | XC1, WO | C25/30 | HA_FUN_FEB_0,250_xxx
Stahlbetonfertigteilfundament | EG_Produktion_FFB | STRIP_FOOTING | Stahlbetonfertigteil | FU-STREIFEN2\ | Stahlbetonfertigteilfundament | EG_Produktion_FFB | 0114SFu0000031801 | m² | Stahlbeton | Fertigteil | false | F002 | 50 | XC1, WO | C25/30 | HA_FUN_FEB_0,250_xxx
Stahlbetonfertigteilfundament | EG_Produktion_FFB | STRIP_FOOTING | Stahlbetonfertigteil | FU-STREIFEN2\ | Stahlbetonfertigteilfundament | EG_Produktion_FFB | 0114SFu0000031800 | m² | Stahlbeton | Fertigteil | false | F002 | 50 | XC1, WO | C25/30 | HA_FUN_FEB_0,250_xxx
Stahlbetonfertigteilfundament | EG_Produktion_FFB | STRIP_FOOTING | Stahlbetonfertigteil | FU-STREIFEN2\ | Stahlbetonfertigteilfundament | EG_Produktion_FFB | 0114SFu0000031702 | m² | Stahlbeton | Fertigteil | false | F002 | 50 | XC1, WO | C25/30 | HA_FUN_FEB_0,250_xxx
Stahlbetonfertigteilfundament | EG_Produktion_FFB | STRIP_FOOTING | Stahlbetonfertigteil | FU-STREIFEN2\ | Stahlbetonfertigteilfundament | EG_Produktion_FFB | 0114SFu0000031686 | m² | Stahlbeton | Fertigteil | false | F002 | 50 | XC1, WO | C25/30 | HA_FUN_FEB_0,250_xxx
Stahlbetonfertigteilfundament | EG_Produktion_FFB | STRIP_FOOTING | Stahlbetonfertigteil | FU-STREIFEN2\ | Stahlbetonfertigteilfundament | EG_Produktion_FFB | 0114SFu0000031703 | m² | Stahlbeton | Fertigteil | false | F002 | 50 | XC1, WO | C25/30 | HA_FUN_FEB_0,250_xxx
Stahlbetonfertigteilfundament | EG_Produktion_FFB | STRIP_FOOTING | Stahlbetonfertigteil | FU-STREIFEN2\ | Stahlbetonfertigteilfundament | EG_Produktion_FFB | 0114SFu0000031973 | m² | Stahlbeton | Fertigteil | false | F002 | 50 | XC1, WO | C25/30 | HA_FUN_FEB_0,250_xxx
Stahlbetonfertigteilfundament | EG_Produktion_FFB | STRIP_FOOTING | Stahlbetonfertigteil | FU-STREIFEN2\ | Stahlbetonfertigteilfundament | EG_Produktion_FFB | 0114SFu0000031970 | m² | Stahlbeton | Fertigteil | false | F002 | 50 | XC1, WO | C25/30 | HA_FUN_FEB_0,250_xxx
Stahlbetonfertigteilfundament | EG_Produktion_FFB | STRIP_FOOTING | Stahlbetonfertigteil | FU-STREIFEN2\ | Stahlbetonfertigteilfundament | EG_Produktion_FFB | 0114SFu0000031971 | m² | Stahlbeton | Fertigteil | false | F002 | 50 | XC1, WO | C25/30 | HA_FUN_FEB_0,250_xxx
Stahlbetonfertigteilfundament | EG_Produktion_FFB | STRIP_FOOTING | Stahlbetonfertigteil | FU-STREIFEN2\ | Stahlbetonfertigteilfundament | EG_Produktion_FFB | 0114SFu0000031972 | m² | Stahlbeton | Fertigteil | false | F002 | 50 | XC1, WO | C25/30 | HA_FUN_FEB_0,250_xxx
Stahlbetonfertigteilfundament | EG_Produktion_FFB | STRIP_FOOTING | Stahlbetonfertigteil | FU-STREIFEN2\ | Stahlbetonfertigteilfundament | EG_Produktion_FFB | 0114SFu0000031586 | m² | Stahlbeton | Fertigteil | false | F002 | 50 | XC1, WO | C25/30 | HA_FUN_FEB_0,250_xxx
Stahlbetonfertigteilfundament | EG_Produktion_FFB | STRIP_FOOTING | Stahlbetonfertigteil | FU-STREIFEN2\ | Stahlbetonfertigteilfundament | EG_Produktion_FFB | 0114SFu0000031626 | m² | Stahlbeton | Fertigteil | false | F002 | 50 | XC1, WO | C25/30 | HA_FUN_FEB_0,250_xxx
Stahlbetonfertigteilfundament | EG_Produktion_FFB | STRIP_FOOTING | Stahlbetonfertigteil | FU-STREIFEN2\ | Stahlbetonfertigteilfundament | EG_Produktion_FFB | 0114SFu0000031587 | m² | Stahlbeton | Fertigteil | false | F002 | 50 | XC1, WO | C25/30 | HA_FUN_FEB_0,250_xxx
Stahlbetonfertigteilfundament | EG_Produktion_FFB | STRIP_FOOTING | Stahlbetonfertigteil | FU-STREIFEN2\ | Stahlbetonfertigteilfundament | EG_Produktion_FFB | 0114SFu0000031627 | m² | Stahlbeton | Fertigteil | false | F002 | 50 | XC1, WO | C25/30 | HA_FUN_FEB_0,250_xxx
Stahlbetonfertigteilfundament | EG_Produktion_FFB | STRIP_FOOTING | Stahlbetonfertigteil | FU-STREIFEN2\ | Stahlbetonfertigteilfundament | EG_Produktion_FFB | 0114SFu0000031984 | m² | Stahlbeton | Fertigteil | false | F002 | 50 | XC1, WO | C25/30 | HA_FUN_FEB_0,250_xxx
Stahlbetonfertigteilfundament | EG_Produktion_FFB | STRIP_FOOTING | Stahlbetonfertigteil | FU-STREIFEN2\ | Stahlbetonfertigteilfundament | EG_Produktion_FFB | 0114SFu0000031985 | m² | Stahlbeton | Fertigteil | false | F002 | 50 | XC1, WO | C25/30 | HA_FUN_FEB_0,250_xxx
Stahlbetonfertigteilfundament | EG_Produktion_FFB | STRIP_FOOTING | Stahlbetonfertigteil | FU-STREIFEN2\ | Stahlbetonfertigteilfundament | EG_Produktion_FFB | 0114SFu0000031875 | m² | Stahlbeton | Fertigteil | false | F002 | 50 | XC1, WO | C25/30 | HA_FUN_FEB_0,250_xxx
Stahlbetonfertigteilfundament | EG_Produktion_FFB | STRIP_FOOTING | Stahlbetonfertigteil | FU-STREIFEN2\ | Stahlbetonfertigteilfundament | EG_Produktion_FFB | 0114SFu0000031898 | m² | Stahlbeton | Fertigteil | false | F002 | 50 | XC1, WO | C25/30 | HA_FUN_FEB_0,250_xxx
Stahlbetonfertigteilfundament | EG_Produktion_FFB | STRIP_FOOTING | Stahlbetonfertigteil | FU-STREIFEN2\ | Stahlbetonfertigteilfundament | EG_Produktion_FFB | 0114SFu0000031897 | m² | Stahlbeton | Fertigteil | false | F002 | 50 | XC1, WO | C25/30 | HA_FUN_FEB_0,250_xxx
Stahlbetonfertigteilfundament | EG_Produktion_FFB | STRIP_FOOTING | Stahlbetonfertigteil | FU-STREIFEN2\ | Stahlbetonfertigteilfundament | EG_Produktion_FFB | 0114SFu0000031876 | m² | Stahlbeton | Fertigteil | false | F002 | 50 | XC1, WO | C25/30 | HA_FUN_FEB_0,250_xxx
Stahlbetonfertigteilfundament | EG_Produktion_FFB | STRIP_FOOTING | Stahlbetonfertigteil | FU-STREIFEN2\ | Stahlbetonfertigteilfundament | EG_Produktion_FFB | 0114SFu0000001795 | m² | Stahlbeton | Fertigteil | false | F002 | 50 | XC1, WO | C25/30 | HA_FUN_FEB_0,250_xxx
Stahlbetonfertigteilfundament | EG_Produktion_FFB | STRIP_FOOTING | Stahlbetonfertigteil | FU-STREIFEN2\ | Stahlbetonfertigteilfundament | EG_Produktion_FFB | 0114SFu0000001797 | m² | Stahlbeton | Fertigteil | false | F002 | 50 | XC1, WO | C25/30 | HA_FUN_FEB_0,250_xxx
Stahlbetonfertigteilfundament | EG_Produktion_FFB | STRIP_FOOTING | Stahlbetonfertigteil | FU-STREIFEN2\ | Stahlbetonfertigteilfundament | EG_Produktion_FFB | 0114SFu0000026687 | m² | Stahlbeton | Fertigteil | false | F002 | 50 | XC1, WO | C25/30 | HA_FUN_FEB_0,250_xxx
Stahlbetonfertigteilfundament | EG_Produktion_FFB | STRIP_FOOTING | Stahlbetonfertigteil | FU-STREIFEN2\ | Stahlbetonfertigteilfundament | EG_Produktion_FFB | 0114SFu0000026688 | m² | Stahlbeton | Fertigteil | false | F002 | 50 | XC1, WO | C25/30 | HA_FUN_FEB_0,250_xxx
Stahlbetonfertigteilfundament | EG_Produktion_FFB | STRIP_FOOTING | Stahlbetonfertigteil | FU-STREIFEN2\ | Stahlbetonfertigteilfundament | EG_Produktion_FFB | 0114SFu0000026635 | m² | Stahlbeton | Fertigteil | false | F002 | 50 | XC1, WO | C25/30 | HA_FUN_FEB_0,250_xxx
Stahlbetonfertigteilfundament | EG_Produktion_FFB | STRIP_FOOTING | Stahlbetonfertigteil | FU-STREIFEN2\ | Stahlbetonfertigteilfundament | EG_Produktion_FFB | 0114SFu0000026636 | m² | Stahlbeton | Fertigteil | false | F002 | 50 | XC1, WO | C25/30 | HA_FUN_FEB_0,250_xxx
Stahlbetonfertigteilfundament | EG_Produktion_FFB | STRIP_FOOTING | Stahlbetonfertigteil | FU-STREIFEN2\ | Stahlbetonfertigteilfundament | EG_Produktion_FFB | 0114SFu0000001467 | m² | Stahlbeton | Fertigteil | false | F001 | 50 | XC1, WO | C25/30 | HA_FUN_FEB_0,250_xxx
Stahlbetonfertigteilfundament | EG_Produktion_FFB | STRIP_FOOTING | Stahlbetonfertigteil | FU-STREIFEN2\ | Stahlbetonfertigteilfundament | EG_Produktion_FFB | 0114SFu0000001465 | m² | Stahlbeton | Fertigteil | false | F001 | 50 | XC1, WO | C25/30 | HA_FUN_FEB_0,250_xxx
Stahlbetonfertigteilfundament | EG_Produktion_FFB | STRIP_FOOTING | Stahlbetonfertigteil | FU-STREIFEN2\ | Stahlbetonfertigteilfundament | EG_Produktion_FFB | 0114SFu0000001339 | m² | Stahlbeton | Fertigteil | false | F001 | 50 | XC1, WO | C25/30 | HA_FUN_FEB_0,250_xxx
Stahlbetonfertigteilfundament | EG_Produktion_FFB | STRIP_FOOTING | Stahlbetonfertigteil | FU-STREIFEN2\ | Stahlbetonfertigteilfundament | EG_Produktion_FFB | 0114SFu0000001327 | m² | Stahlbeton | Fertigteil | false | F001 | 50 | XC1, WO | C25/30 | HA_FUN_FEB_0,250_xxx
Stahlbetonfertigteilfundament | EG_Produktion_FFB | STRIP_FOOTING | Stahlbetonfertigteil | FU-STREIFEN2\ | Stahlbetonfertigteilfundament | EG_Produktion_FFB | 0114SFu0000001329 | m² | Stahlbeton | Fertigteil | false | F001 | 50 | XC1, WO | C25/30 | HA_FUN_FEB_0,250_xxx
Stahlbetonfertigteilfundament | EG_Produktion_FFB | STRIP_FOOTING | Stahlbetonfertigteil | FU-STREIFEN2\ | Stahlbetonfertigteilfundament | EG_Produktion_FFB | 0114SFu0000001341 | m² | Stahlbeton | Fertigteil | false | F001 | 50 | XC1, WO | C25/30 | HA_FUN_FEB_0,250_xxx
Stahlbetonfertigteilfundament | EG_Produktion_FFB | STRIP_FOOTING | Stahlbetonfertigteil | FU-STREIFEN2\ | Stahlbetonfertigteilfundament | EG_Produktion_FFB | 0114SFu0000001351 | m² | Stahlbeton | Fertigteil | false | F001 | 50 | XC1, WO | C25/30 | HA_FUN_FEB_0,250_xxx
Stahlbetonfertigteilfundament | EG_Produktion_FFB | STRIP_FOOTING | Stahlbetonfertigteil | FU-STREIFEN2\ | Stahlbetonfertigteilfundament | EG_Produktion_FFB | 0114SFu0000001353 | m² | Stahlbeton | Fertigteil | false | F001 | 50 | XC1, WO | C25/30 | HA_FUN_FEB_0,250_xxx
Stahlbetonfertigteilfundament | EG_Produktion_FFB | STRIP_FOOTING | Stahlbetonfertigteil | FU-STREIFEN2\ | Stahlbetonfertigteilfundament | EG_Produktion_FFB | 0114SFu0000001363 | m² | Stahlbeton | Fertigteil | false | F001 | 50 | XC1, WO | C25/30 | HA_FUN_FEB_0,250_xxx
Stahlbetonfertigteilfundament | EG_Produktion_FFB | STRIP_FOOTING | Stahlbetonfertigteil | FU-STREIFEN2\ | Stahlbetonfertigteilfundament | EG_Produktion_FFB | 0114SFu0000001365 | m² | Stahlbeton | Fertigteil | false | F001 | 50 | XC1, WO | C25/30 | HA_FUN_FEB_0,250_xxx
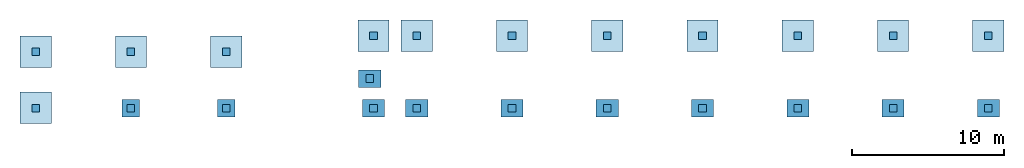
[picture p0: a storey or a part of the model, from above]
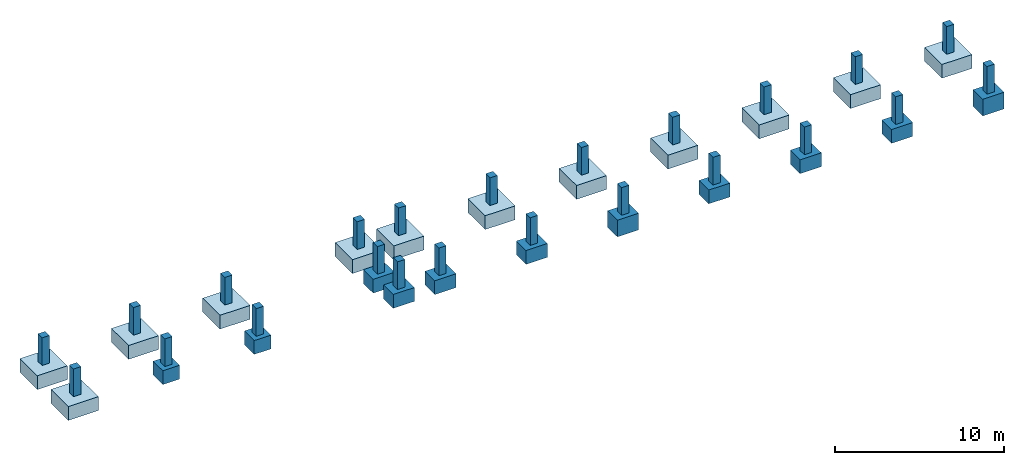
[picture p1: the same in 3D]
Properties of the parts of a building model (IFC2X3), part 13 of 25

# IfcFooting (903)
Name | In | PredefinedType | Material = AllplanAttributes, Material | Codetext | Bezeichnung = Name | Ebene | Allright_Bauteil_ID | Abrechnungsart | IFC_Pset_TWP, Material | Herstellung | Außenbauteil | Positionsnummer | Bewehrungsgrad | Expositionsklasse | Druckfestigkeitsklasse | Reference
Stahlbetonfertigteilfundament | EG_Produktion_FFB | STRIP_FOOTING | Stahlbetonfertigteil | FU-STREIFEN2\ | Stahlbetonfertigteilfundament | EG_Produktion_FFB | 0114SFu0000001375 | m² | Stahlbeton | Fertigteil | false | F001 | 50 | XC1, WO | C25/30 | HA_FUN_FEB_0,250_xxx
Stahlbetonfertigteilfundament | EG_Produktion_FFB | STRIP_FOOTING | Stahlbetonfertigteil | FU-STREIFEN2\ | Stahlbetonfertigteilfundament | EG_Produktion_FFB | 0114SFu0000001377 | m² | Stahlbeton | Fertigteil | false | F001 | 50 | XC1, WO | C25/30 | HA_FUN_FEB_0,250_xxx
Stahlbetonfertigteilfundament | EG_Produktion_FFB | STRIP_FOOTING | Stahlbetonfertigteil | FU-STREIFEN2\ | Stahlbetonfertigteilfundament | EG_Produktion_FFB | 0114SFu0000001387 | m² | Stahlbeton | Fertigteil | false | F001 | 50 | XC1, WO | C25/30 | HA_FUN_FEB_0,250_xxx
Stahlbetonfertigteilfundament | EG_Produktion_FFB | STRIP_FOOTING | Stahlbetonfertigteil | FU-STREIFEN2\ | Stahlbetonfertigteilfundament | EG_Produktion_FFB | 0114SFu0000001389 | m² | Stahlbeton | Fertigteil | false | F001 | 50 | XC1, WO | C25/30 | HA_FUN_FEB_0,250_xxx
Stahlbetonfertigteilfundament | EG_Produktion_FFB | STRIP_FOOTING | Stahlbetonfertigteil | FU-STREIFEN2\ | Stahlbetonfertigteilfundament | EG_Produktion_FFB | 0114SFu0000001399 | m² | Stahlbeton | Fertigteil | false | F001 | 50 | XC1, WO | C25/30 | HA_FUN_FEB_0,250_xxx
Stahlbetonfertigteilfundament | EG_Produktion_FFB | STRIP_FOOTING | Stahlbetonfertigteil | FU-STREIFEN2\ | Stahlbetonfertigteilfundament | EG_Produktion_FFB | 0114SFu0000001401 | m² | Stahlbeton | Fertigteil | false | F001 | 50 | XC1, WO | C25/30 | HA_FUN_FEB_0,250_xxx
Stahlbetonfertigteilfundament | EG_Produktion_FFB | STRIP_FOOTING | Stahlbetonfertigteil | FU-STREIFEN2\ | Stahlbetonfertigteilfundament | EG_Produktion_FFB | 0114SFu0000001411 | m² | Stahlbeton | Fertigteil | false | F001 | 50 | XC1, WO | C25/30 | HA_FUN_FEB_0,250_xxx
Stahlbetonfertigteilfundament | EG_Produktion_FFB | STRIP_FOOTING | Stahlbetonfertigteil | FU-STREIFEN2\ | Stahlbetonfertigteilfundament | EG_Produktion_FFB | 0114SFu0000001413 | m² | Stahlbeton | Fertigteil | false | F001 | 50 | XC1, WO | C25/30 | HA_FUN_FEB_0,250_xxx
Stahlbetonfertigteilfundament | EG_Produktion_FFB | STRIP_FOOTING | Stahlbetonfertigteil | FU-STREIFEN2\ | Stahlbetonfertigteilfundament | EG_Produktion_FFB | 0114SFu0000001423 | m² | Stahlbeton | Fertigteil | false | F001 | 50 | XC1, WO | C25/30 | HA_FUN_FEB_0,250_xxx
Stahlbetonfertigteilfundament | EG_Produktion_FFB | STRIP_FOOTING | Stahlbetonfertigteil | FU-STREIFEN2\ | Stahlbetonfertigteilfundament | EG_Produktion_FFB | 0114SFu0000001425 | m² | Stahlbeton | Fertigteil | false | F001 | 50 | XC1, WO | C25/30 | HA_FUN_FEB_0,250_xxx
Stahlbetonfertigteilfundament | EG_Produktion_FFB | STRIP_FOOTING | Stahlbetonfertigteil | FU-STREIFEN2\ | Stahlbetonfertigteilfundament | EG_Produktion_FFB | 0114SFu0000001435 | m² | Stahlbeton | Fertigteil | false | F001 | 50 | XC1, WO | C25/30 | HA_FUN_FEB_0,250_xxx
Stahlbetonfertigteilfundament | EG_Produktion_FFB | STRIP_FOOTING | Stahlbetonfertigteil | FU-STREIFEN2\ | Stahlbetonfertigteilfundament | EG_Produktion_FFB | 0114SFu0000001437 | m² | Stahlbeton | Fertigteil | false | F001 | 50 | XC1, WO | C25/30 | HA_FUN_FEB_0,250_xxx
Stahlbetonfertigteilfundament | EG_Produktion_FFB | STRIP_FOOTING | Stahlbetonfertigteil | FU-STREIFEN2\ | Stahlbetonfertigteilfundament | EG_Produktion_FFB | 0114SFu0000001447 | m² | Stahlbeton | Fertigteil | false | F001 | 50 | XC1, WO | C25/30 | HA_FUN_FEB_0,250_xxx
Stahlbetonfertigteilfundament | EG_Produktion_FFB | STRIP_FOOTING | Stahlbetonfertigteil | FU-STREIFEN2\ | Stahlbetonfertigteilfundament | EG_Produktion_FFB | 0114SFu0000001449 | m² | Stahlbeton | Fertigteil | false | F001 | 50 | XC1, WO | C25/30 | HA_FUN_FEB_0,250_xxx
Stahlbetonfertigteilfundament | EG_Produktion_FFB | STRIP_FOOTING | Stahlbetonfertigteil | FU-STREIFEN2\ | Stahlbetonfertigteilfundament | EG_Produktion_FFB | 0114SFu0000001459 | m² | Stahlbeton | Fertigteil | false | F001 | 50 | XC1, WO | C25/30 | HA_FUN_FEB_0,250_xxx
Stahlbetonfertigteilfundament | EG_Produktion_FFB | STRIP_FOOTING | Stahlbetonfertigteil | FU-STREIFEN2\ | Stahlbetonfertigteilfundament | EG_Produktion_FFB | 0114SFu0000001461 | m² | Stahlbeton | Fertigteil | false | F001 | 50 | XC1, WO | C25/30 | HA_FUN_FEB_0,250_xxx
Stahlbetonfertigteilfundament | EG_Produktion_FFB | STRIP_FOOTING | Stahlbetonfertigteil | FU-STREIFEN2\ | Stahlbetonfertigteilfundament | EG_Produktion_FFB | 0114SFu0000001489 | m² | Stahlbeton | Fertigteil | false | F001 | 50 | XC1, WO | C25/30 | HA_FUN_FEB_0,250_xxx
Stahlbetonfertigteilfundament | EG_Produktion_FFB | STRIP_FOOTING | Stahlbetonfertigteil | FU-STREIFEN2\ | Stahlbetonfertigteilfundament | EG_Produktion_FFB | 0114SFu0000001491 | m² | Stahlbeton | Fertigteil | false | F001 | 50 | XC1, WO | C25/30 | HA_FUN_FEB_0,250_xxx
Stahlbetonfertigteilfundament | EG_Produktion_FFB | STRIP_FOOTING | Stahlbetonfertigteil | FU-STREIFEN2\ | Stahlbetonfertigteilfundament | EG_Produktion_FFB | 0114SFu0000001487 | m² | Stahlbeton | Fertigteil | false | F001 | 50 | XC1, WO | C25/30 | HA_FUN_FEB_0,250_xxx
Stahlbetonfertigteilfundament | EG_Produktion_FFB | STRIP_FOOTING | Stahlbetonfertigteil | FU-STREIFEN2\ | Stahlbetonfertigteilfundament | EG_Produktion_FFB | 0114SFu0000001493 | m² | Stahlbeton | Fertigteil | false | F001 | 50 | XC1, WO | C25/30 | HA_FUN_FEB_0,250_xxx
Stahlbetonfertigteilfundament | EG_Produktion_FFB | STRIP_FOOTING | Stahlbetonfertigteil | FU-STREIFEN2\ | Stahlbetonfertigteilfundament | EG_Produktion_FFB | 0114SFu0000001495 | m² | Stahlbeton | Fertigteil | false | F001 | 50 | XC1, WO | C25/30 | HA_FUN_FEB_0,250_xxx
Stahlbetonfertigteilfundament | EG_Produktion_FFB | STRIP_FOOTING | Stahlbetonfertigteil | FU-STREIFEN2\ | Stahlbetonfertigteilfundament | EG_Produktion_FFB | 0114SFu0000001497 | m² | Stahlbeton | Fertigteil | false | F001 | 50 | XC1, WO | C25/30 | HA_FUN_FEB_0,250_xxx
Stahlbetonfertigteilfundament | EG_Produktion_FFB | STRIP_FOOTING | Stahlbetonfertigteil | FU-STREIFEN2\ | Stahlbetonfertigteilfundament | EG_Produktion_FFB | 0114SFu0000001499 | m² | Stahlbeton | Fertigteil | false | F001 | 50 | XC1, WO | C25/30 | HA_FUN_FEB_0,250_xxx
Stahlbetonfertigteilfundament | EG_Produktion_FFB | STRIP_FOOTING | Stahlbetonfertigteil | FU-STREIFEN2\ | Stahlbetonfertigteilfundament | EG_Produktion_FFB | 0114SFu0000001501 | m² | Stahlbeton | Fertigteil | false | F001 | 50 | XC1, WO | C25/30 | HA_FUN_FEB_0,250_xxx
Stahlbetonfertigteilfundament | EG_Produktion_FFB | STRIP_FOOTING | Stahlbetonfertigteil | FU-STREIFEN2\ | Stahlbetonfertigteilfundament | EG_Produktion_FFB | 0114SFu0000001503 | m² | Stahlbeton | Fertigteil | false | F001 | 50 | XC1, WO | C25/30 | HA_FUN_FEB_0,250_xxx
Stahlbetonfertigteilfundament | EG_Produktion_FFB | STRIP_FOOTING | Stahlbetonfertigteil | FU-STREIFEN2\ | Stahlbetonfertigteilfundament | EG_Produktion_FFB | 0114SFu0000001505 | m² | Stahlbeton | Fertigteil | false | F001 | 50 | XC1, WO | C25/30 | HA_FUN_FEB_0,250_xxx
Stahlbetonfertigteilfundament | EG_Produktion_FFB | STRIP_FOOTING | Stahlbetonfertigteil | FU-STREIFEN2\ | Stahlbetonfertigteilfundament | EG_Produktion_FFB | 0114SFu0000001507 | m² | Stahlbeton | Fertigteil | false | F001 | 50 | XC1, WO | C25/30 | HA_FUN_FEB_0,250_xxx
Stahlbetonfertigteilfundament | EG_Produktion_FFB | STRIP_FOOTING | Stahlbetonfertigteil | FU-STREIFEN2\ | Stahlbetonfertigteilfundament | EG_Produktion_FFB | 0114SFu0000001509 | m² | Stahlbeton | Fertigteil | false | F001 | 50 | XC1, WO | C25/30 | HA_FUN_FEB_0,250_xxx
Stahlbetonfertigteilfundament | EG_Produktion_FFB | STRIP_FOOTING | Stahlbetonfertigteil | FU-STREIFEN2\ | Stahlbetonfertigteilfundament | EG_Produktion_FFB | 0114SFu0000001511 | m² | Stahlbeton | Fertigteil | false | F001 | 50 | XC1, WO | C25/30 | HA_FUN_FEB_0,250_xxx
Stahlbetonfertigteilfundament | EG_Produktion_FFB | STRIP_FOOTING | Stahlbetonfertigteil | FU-STREIFEN2\ | Stahlbetonfertigteilfundament | EG_Produktion_FFB | 0114SFu0000001513 | m² | Stahlbeton | Fertigteil | false | F001 | 50 | XC1, WO | C25/30 | HA_FUN_FEB_0,250_xxx
Stahlbetonfertigteilfundament | EG_Produktion_FFB | STRIP_FOOTING | Stahlbetonfertigteil | FU-STREIFEN2\ | Stahlbetonfertigteilfundament | EG_Produktion_FFB | 0114SFu0000001515 | m² | Stahlbeton | Fertigteil | false | F001 | 50 | XC1, WO | C25/30 | HA_FUN_FEB_0,250_xxx
Stahlbetonfertigteilfundament | EG_Produktion_FFB | STRIP_FOOTING | Stahlbetonfertigteil | FU-STREIFEN2\ | Stahlbetonfertigteilfundament | EG_Produktion_FFB | 0114SFu0000001517 | m² | Stahlbeton | Fertigteil | false | F001 | 50 | XC1, WO | C25/30 | HA_FUN_FEB_0,250_xxx
Stahlbetonfertigteilfundament | EG_Produktion_FFB | STRIP_FOOTING | Stahlbetonfertigteil | FU-STREIFEN2\ | Stahlbetonfertigteilfundament | EG_Produktion_FFB | 0114SFu0000001519 | m² | Stahlbeton | Fertigteil | false | F001 | 50 | XC1, WO | C25/30 | HA_FUN_FEB_0,250_xxx
Stahlbetonfertigteilfundament | EG_Produktion_FFB | STRIP_FOOTING | Stahlbetonfertigteil | FU-STREIFEN2\ | Stahlbetonfertigteilfundament | EG_Produktion_FFB | 0114SFu0000001521 | m² | Stahlbeton | Fertigteil | false | F001 | 50 | XC1, WO | C25/30 | HA_FUN_FEB_0,250_xxx
Stahlbetonfertigteilfundament | EG_Produktion_FFB | STRIP_FOOTING | Stahlbetonfertigteil | FU-STREIFEN2\ | Stahlbetonfertigteilfundament | EG_Produktion_FFB | 0114SFu0000001523 | m² | Stahlbeton | Fertigteil | false | F001 | 50 | XC1, WO | C25/30 | HA_FUN_FEB_0,250_xxx
Stahlbetonfertigteilfundament | EG_Produktion_FFB | STRIP_FOOTING | Stahlbetonfertigteil | FU-STREIFEN2\ | Stahlbetonfertigteilfundament | EG_Produktion_FFB | 0114SFu0000001525 | m² | Stahlbeton | Fertigteil | false | F001 | 50 | XC1, WO | C25/30 | HA_FUN_FEB_0,250_xxx
Stahlbetonfertigteilfundament | EG_Produktion_FFB | STRIP_FOOTING | Stahlbetonfertigteil | FU-STREIFEN2\ | Stahlbetonfertigteilfundament | EG_Produktion_FFB | 0114SFu0000001527 | m² | Stahlbeton | Fertigteil | false | F001 | 50 | XC1, WO | C25/30 | HA_FUN_FEB_0,250_xxx
Stahlbetonfertigteilfundament | EG_Produktion_FFB | STRIP_FOOTING | Stahlbetonfertigteil | FU-STREIFEN2\ | Stahlbetonfertigteilfundament | EG_Produktion_FFB | 0114SFu0000001529 | m² | Stahlbeton | Fertigteil | false | F001 | 50 | XC1, WO | C25/30 | HA_FUN_FEB_0,250_xxx
Stahlbetonfertigteilfundament | EG_Produktion_FFB | STRIP_FOOTING | Stahlbetonfertigteil | FU-STREIFEN2\ | Stahlbetonfertigteilfundament | EG_Produktion_FFB | 0114SFu0000001531 | m² | Stahlbeton | Fertigteil | false | F001 | 50 | XC1, WO | C25/30 | HA_FUN_FEB_0,250_xxx
Stahlbetonfertigteilfundament | EG_Produktion_FFB | STRIP_FOOTING | Stahlbetonfertigteil | FU-STREIFEN2\ | Stahlbetonfertigteilfundament | EG_Produktion_FFB | 0114SFu0000001533 | m² | Stahlbeton | Fertigteil | false | F001 | 50 | XC1, WO | C25/30 | HA_FUN_FEB_0,250_xxx
Stahlbetonfertigteilfundament | EG_Produktion_FFB | STRIP_FOOTING | Stahlbetonfertigteil | FU-STREIFEN2\ | Stahlbetonfertigteilfundament | EG_Produktion_FFB | 0114SFu0000001535 | m² | Stahlbeton | Fertigteil | false | F001 | 50 | XC1, WO | C25/30 | HA_FUN_FEB_0,250_xxx
Stahlbetonfertigteilfundament | EG_Produktion_FFB | STRIP_FOOTING | Stahlbetonfertigteil | FU-STREIFEN2\ | Stahlbetonfertigteilfundament | EG_Produktion_FFB | 0114SFu0000001537 | m² | Stahlbeton | Fertigteil | false | F001 | 50 | XC1, WO | C25/30 | HA_FUN_FEB_0,250_xxx
Stahlbetonfertigteilfundament | EG_Produktion_FFB | STRIP_FOOTING | Stahlbetonfertigteil | FU-STREIFEN2\ | Stahlbetonfertigteilfundament | EG_Produktion_FFB | 0114SFu0000001605 | m² | Stahlbeton | Fertigteil | false | F001 | 50 | XC1, WO | C25/30 | HA_FUN_FEB_0,250_xxx
Stahlbetonfertigteilfundament | EG_Produktion_FFB | STRIP_FOOTING | Stahlbetonfertigteil | FU-STREIFEN2\ | Stahlbetonfertigteilfundament | EG_Produktion_FFB | 0114SFu0000001603 | m² | Stahlbeton | Fertigteil | false | F001 | 50 | XC1, WO | C25/30 | HA_FUN_FEB_0,250_xxx
Stahlbetonfertigteilfundament | EG_Produktion_FFB | STRIP_FOOTING | Stahlbetonfertigteil | FU-STREIFEN2\ | Stahlbetonfertigteilfundament | EG_Produktion_FFB | 0114SFu0000001551 | m² | Stahlbeton | Fertigteil | false | F001 | 50 | XC1, WO | C25/30 | HA_FUN_FEB_0,250_xxx
Stahlbetonfertigteilfundament | EG_Produktion_FFB | STRIP_FOOTING | Stahlbetonfertigteil | FU-STREIFEN2\ | Stahlbetonfertigteilfundament | EG_Produktion_FFB | 0114SFu0000001553 | m² | Stahlbeton | Fertigteil | false | F001 | 50 | XC1, WO | C25/30 | HA_FUN_FEB_0,250_xxx
Stahlbetonfertigteilfundament | EG_Produktion_FFB | STRIP_FOOTING | Stahlbetonfertigteil | FU-STREIFEN2\ | Stahlbetonfertigteilfundament | EG_Produktion_FFB | 0114SFu0000001555 | m² | Stahlbeton | Fertigteil | false | F001 | 50 | XC1, WO | C25/30 | HA_FUN_FEB_0,250_xxx
Stahlbetonfertigteilfundament | EG_Produktion_FFB | STRIP_FOOTING | Stahlbetonfertigteil | FU-STREIFEN2\ | Stahlbetonfertigteilfundament | EG_Produktion_FFB | 0114SFu0000001557 | m² | Stahlbeton | Fertigteil | false | F001 | 50 | XC1, WO | C25/30 | HA_FUN_FEB_0,250_xxx
Stahlbetonfertigteilfundament | EG_Produktion_FFB | STRIP_FOOTING | Stahlbetonfertigteil | FU-STREIFEN2\ | Stahlbetonfertigteilfundament | EG_Produktion_FFB | 0114SFu0000001567 | m² | Stahlbeton | Fertigteil | false | F001 | 50 | XC1, WO | C25/30 | HA_FUN_FEB_0,250_xxx
Stahlbetonfertigteilfundament | EG_Produktion_FFB | STRIP_FOOTING | Stahlbetonfertigteil | FU-STREIFEN2\ | Stahlbetonfertigteilfundament | EG_Produktion_FFB | 0114SFu0000001569 | m² | Stahlbeton | Fertigteil | false | F001 | 50 | XC1, WO | C25/30 | HA_FUN_FEB_0,250_xxx
Stahlbetonfertigteilfundament | EG_Produktion_FFB | STRIP_FOOTING | Stahlbetonfertigteil | FU-STREIFEN2\ | Stahlbetonfertigteilfundament | EG_Produktion_FFB | 0114SFu0000001571 | m² | Stahlbeton | Fertigteil | false | F001 | 50 | XC1, WO | C25/30 | HA_FUN_FEB_0,250_xxx
Stahlbetonfertigteilfundament | EG_Produktion_FFB | STRIP_FOOTING | Stahlbetonfertigteil | FU-STREIFEN2\ | Stahlbetonfertigteilfundament | EG_Produktion_FFB | 0114SFu0000001573 | m² | Stahlbeton | Fertigteil | false | F001 | 50 | XC1, WO | C25/30 | HA_FUN_FEB_0,250_xxx
Stahlbetonfertigteilfundament | EG_Produktion_FFB | STRIP_FOOTING | Stahlbetonfertigteil | FU-STREIFEN2\ | Stahlbetonfertigteilfundament | EG_Produktion_FFB | 0114SFu0000001575 | m² | Stahlbeton | Fertigteil | false | F001 | 50 | XC1, WO | C25/30 | HA_FUN_FEB_0,250_xxx
Stahlbetonfertigteilfundament | EG_Produktion_FFB | STRIP_FOOTING | Stahlbetonfertigteil | FU-STREIFEN2\ | Stahlbetonfertigteilfundament | EG_Produktion_FFB | 0114SFu0000001577 | m² | Stahlbeton | Fertigteil | false | F001 | 50 | XC1, WO | C25/30 | HA_FUN_FEB_0,250_xxx
Stahlbetonfertigteilfundament | EG_Produktion_FFB | STRIP_FOOTING | Stahlbetonfertigteil | FU-STREIFEN2\ | Stahlbetonfertigteilfundament | EG_Produktion_FFB | 0114SFu0000001579 | m² | Stahlbeton | Fertigteil | false | F001 | 50 | XC1, WO | C25/30 | HA_FUN_FEB_0,250_xxx
Stahlbetonfertigteilfundament | EG_Produktion_FFB | STRIP_FOOTING | Stahlbetonfertigteil | FU-STREIFEN2\ | Stahlbetonfertigteilfundament | EG_Produktion_FFB | 0114SFu0000001581 | m² | Stahlbeton | Fertigteil | false | F001 | 50 | XC1, WO | C25/30 | HA_FUN_FEB_0,250_xxx
Stahlbetonfertigteilfundament | EG_Produktion_FFB | STRIP_FOOTING | Stahlbetonfertigteil | FU-STREIFEN2\ | Stahlbetonfertigteilfundament | EG_Produktion_FFB | 0114SFu0000001583 | m² | Stahlbeton | Fertigteil | false | F001 | 50 | XC1, WO | C25/30 | HA_FUN_FEB_0,250_xxx
Stahlbetonfertigteilfundament | EG_Produktion_FFB | STRIP_FOOTING | Stahlbetonfertigteil | FU-STREIFEN2\ | Stahlbetonfertigteilfundament | EG_Produktion_FFB | 0114SFu0000001585 | m² | Stahlbeton | Fertigteil | false | F001 | 50 | XC1, WO | C25/30 | HA_FUN_FEB_0,250_xxx
Stahlbetonfertigteilfundament | EG_Produktion_FFB | STRIP_FOOTING | Stahlbetonfertigteil | FU-STREIFEN2\ | Stahlbetonfertigteilfundament | EG_Produktion_FFB | 0114SFu0000001587 | m² | Stahlbeton | Fertigteil | false | F001 | 50 | XC1, WO | C25/30 | HA_FUN_FEB_0,250_xxx
Stahlbetonfertigteilfundament | EG_Produktion_FFB | STRIP_FOOTING | Stahlbetonfertigteil | FU-STREIFEN2\ | Stahlbetonfertigteilfundament | EG_Produktion_FFB | 0114SFu0000001589 | m² | Stahlbeton | Fertigteil | false | F001 | 50 | XC1, WO | C25/30 | HA_FUN_FEB_0,250_xxx
Stahlbetonfertigteilfundament | EG_Produktion_FFB | STRIP_FOOTING | Stahlbetonfertigteil | FU-STREIFEN2\ | Stahlbetonfertigteilfundament | EG_Produktion_FFB | 0114SFu0000001591 | m² | Stahlbeton | Fertigteil | false | F001 | 50 | XC1, WO | C25/30 | HA_FUN_FEB_0,250_xxx
Stahlbetonfertigteilfundament | EG_Produktion_FFB | STRIP_FOOTING | Stahlbetonfertigteil | FU-STREIFEN2\ | Stahlbetonfertigteilfundament | EG_Produktion_FFB | 0114SFu0000001593 | m² | Stahlbeton | Fertigteil | false | F001 | 50 | XC1, WO | C25/30 | HA_FUN_FEB_0,250_xxx
Stahlbetonfertigteilfundament | EG_Produktion_FFB | STRIP_FOOTING | Stahlbetonfertigteil | FU-STREIFEN2\ | Stahlbetonfertigteilfundament | EG_Produktion_FFB | 0114SFu0000001595 | m² | Stahlbeton | Fertigteil | false | F001 | 50 | XC1, WO | C25/30 | HA_FUN_FEB_0,250_xxx
Stahlbetonfertigteilfundament | EG_Produktion_FFB | STRIP_FOOTING | Stahlbetonfertigteil | FU-STREIFEN2\ | Stahlbetonfertigteilfundament | EG_Produktion_FFB | 0114SFu0000001597 | m² | Stahlbeton | Fertigteil | false | F001 | 50 | XC1, WO | C25/30 | HA_FUN_FEB_0,250_xxx
Stahlbetonfertigteilfundament | EG_Produktion_FFB | STRIP_FOOTING | Stahlbetonfertigteil | FU-STREIFEN2\ | Stahlbetonfertigteilfundament | EG_Produktion_FFB | 0114SFu0000001599 | m² | Stahlbeton | Fertigteil | false | F001 | 50 | XC1, WO | C25/30 | HA_FUN_FEB_0,250_xxx
Stahlbetonfertigteilfundament | EG_Produktion_FFB | STRIP_FOOTING | Stahlbetonfertigteil | FU-STREIFEN2\ | Stahlbetonfertigteilfundament | EG_Produktion_FFB | 0114SFu0000001601 | m² | Stahlbeton | Fertigteil | false | F001 | 50 | XC1, WO | C25/30 | HA_FUN_FEB_0,250_xxx
Stahlbetonfertigteilfundament | EG_Produktion_FFB | STRIP_FOOTING | Stahlbetonfertigteil | FU-STREIFEN2\ | Stahlbetonfertigteilfundament | EG_Produktion_FFB | 0114SFu0000001469 | m² | Stahlbeton | Fertigteil | false | F001 | 50 | XC1, WO | C25/30 | HA_FUN_FEB_0,250_xxx
Stahlbetonfertigteilfundament | EG_Produktion_FFB | STRIP_FOOTING | Stahlbetonfertigteil | FU-STREIFEN2\ | Stahlbetonfertigteilfundament | EG_Produktion_FFB | 0114SFu0000001463 | m² | Stahlbeton | Fertigteil | false | F001 | 50 | XC1, WO | C25/30 | HA_FUN_FEB_0,250_xxx
Stahlbetonfertigteilfundament | EG_Produktion_FFB | STRIP_FOOTING | Stahlbetonfertigteil | FU-STREIFEN2\ | Stahlbetonfertigteilfundament | EG_Produktion_FFB | 0114SFu0000001431 | m² | Stahlbeton | Fertigteil | false | F001 | 50 | XC1, WO | C25/30 | HA_FUN_FEB_0,250_xxx
Stahlbetonfertigteilfundament | EG_Produktion_FFB | STRIP_FOOTING | Stahlbetonfertigteil | FU-STREIFEN2\ | Stahlbetonfertigteilfundament | EG_Produktion_FFB | 0114SFu0000001419 | m² | Stahlbeton | Fertigteil | false | F001 | 50 | XC1, WO | C25/30 | HA_FUN_FEB_0,250_xxx
Stahlbetonfertigteilfundament | EG_Produktion_FFB | STRIP_FOOTING | Stahlbetonfertigteil | FU-STREIFEN2\ | Stahlbetonfertigteilfundament | EG_Produktion_FFB | 0114SFu0000001417 | m² | Stahlbeton | Fertigteil | false | F001 | 50 | XC1, WO | C25/30 | HA_FUN_FEB_0,250_xxx
Stahlbetonfertigteilfundament | EG_Produktion_FFB | STRIP_FOOTING | Stahlbetonfertigteil | FU-STREIFEN2\ | Stahlbetonfertigteilfundament | EG_Produktion_FFB | 0114SFu0000001429 | m² | Stahlbeton | Fertigteil | false | F001 | 50 | XC1, WO | C25/30 | HA_FUN_FEB_0,250_xxx
Stahlbetonfertigteilfundament | EG_Produktion_FFB | STRIP_FOOTING | Stahlbetonfertigteil | FU-STREIFEN2\ | Stahlbetonfertigteilfundament | EG_Produktion_FFB | 0114SFu0000001407 | m² | Stahlbeton | Fertigteil | false | F001 | 50 | XC1, WO | C25/30 | HA_FUN_FEB_0,250_xxx
Stahlbetonfertigteilfundament | EG_Produktion_FFB | STRIP_FOOTING | Stahlbetonfertigteil | FU-STREIFEN2\ | Stahlbetonfertigteilfundament | EG_Produktion_FFB | 0114SFu0000001403 | m² | Stahlbeton | Fertigteil | false | F001 | 50 | XC1, WO | C25/30 | HA_FUN_FEB_0,250_xxx
Stahlbetonfertigteilfundament | EG_Produktion_FFB | STRIP_FOOTING | Stahlbetonfertigteil | FU-STREIFEN2\ | Stahlbetonfertigteilfundament | EG_Produktion_FFB | 0114SFu0000001409 | m² | Stahlbeton | Fertigteil | false | F001 | 50 | XC1, WO | C25/30 | HA_FUN_FEB_0,250_xxx
Stahlbetonfertigteilfundament | EG_Produktion_FFB | STRIP_FOOTING | Stahlbetonfertigteil | FU-STREIFEN2\ | Stahlbetonfertigteilfundament | EG_Produktion_FFB | 0114SFu0000001415 | m² | Stahlbeton | Fertigteil | false | F001 | 50 | XC1, WO | C25/30 | HA_FUN_FEB_0,250_xxx
Stahlbetonfertigteilfundament | EG_Produktion_FFB | STRIP_FOOTING | Stahlbetonfertigteil | FU-STREIFEN2\ | Stahlbetonfertigteilfundament | EG_Produktion_FFB | 0114SFu0000001421 | m² | Stahlbeton | Fertigteil | false | F001 | 50 | XC1, WO | C25/30 | HA_FUN_FEB_0,250_xxx
Stahlbetonfertigteilfundament | EG_Produktion_FFB | STRIP_FOOTING | Stahlbetonfertigteil | FU-STREIFEN2\ | Stahlbetonfertigteilfundament | EG_Produktion_FFB | 0114SFu0000001433 | m² | Stahlbeton | Fertigteil | false | F001 | 50 | XC1, WO | C25/30 | HA_FUN_FEB_0,250_xxx
Stahlbetonfertigteilfundament | EG_Produktion_FFB | STRIP_FOOTING | Stahlbetonfertigteil | FU-STREIFEN2\ | Stahlbetonfertigteilfundament | EG_Produktion_FFB | 0114SFu0000001427 | m² | Stahlbeton | Fertigteil | false | F001 | 50 | XC1, WO | C25/30 | HA_FUN_FEB_0,250_xxx
Stahlbetonfertigteilfundament | EG_Produktion_FFB | STRIP_FOOTING | Stahlbetonfertigteil | FU-STREIFEN2\ | Stahlbetonfertigteilfundament | EG_Produktion_FFB | 0114SFu0000001439 | m² | Stahlbeton | Fertigteil | false | F001 | 50 | XC1, WO | C25/30 | HA_FUN_FEB_0,250_xxx
Stahlbetonfertigteilfundament | EG_Produktion_FFB | STRIP_FOOTING | Stahlbetonfertigteil | FU-STREIFEN2\ | Stahlbetonfertigteilfundament | EG_Produktion_FFB | 0114SFu0000001445 | m² | Stahlbeton | Fertigteil | false | F001 | 50 | XC1, WO | C25/30 | HA_FUN_FEB_0,250_xxx
Stahlbetonfertigteilfundament | EG_Produktion_FFB | STRIP_FOOTING | Stahlbetonfertigteil | FU-STREIFEN2\ | Stahlbetonfertigteilfundament | EG_Produktion_FFB | 0114SFu0000001441 | m² | Stahlbeton | Fertigteil | false | F001 | 50 | XC1, WO | C25/30 | HA_FUN_FEB_0,250_xxx
Stahlbetonfertigteilfundament | EG_Produktion_FFB | STRIP_FOOTING | Stahlbetonfertigteil | FU-STREIFEN2\ | Stahlbetonfertigteilfundament | EG_Produktion_FFB | 0114SFu0000001443 | m² | Stahlbeton | Fertigteil | false | F001 | 50 | XC1, WO | C25/30 | HA_FUN_FEB_0,250_xxx
Stahlbetonfertigteilfundament | EG_Produktion_FFB | STRIP_FOOTING | Stahlbetonfertigteil | FU-STREIFEN2\ | Stahlbetonfertigteilfundament | EG_Produktion_FFB | 0114SFu0000001391 | m² | Stahlbeton | Fertigteil | false | F001 | 50 | XC1, WO | C25/30 | HA_FUN_FEB_0,250_xxx
Stahlbetonfertigteilfundament | EG_Produktion_FFB | STRIP_FOOTING | Stahlbetonfertigteil | FU-STREIFEN2\ | Stahlbetonfertigteilfundament | EG_Produktion_FFB | 0114SFu0000001397 | m² | Stahlbeton | Fertigteil | false | F001 | 50 | XC1, WO | C25/30 | HA_FUN_FEB_0,250_xxx
Stahlbetonfertigteilfundament | EG_Produktion_FFB | STRIP_FOOTING | Stahlbetonfertigteil | FU-STREIFEN2\ | Stahlbetonfertigteilfundament | EG_Produktion_FFB | 0114SFu0000001393 | m² | Stahlbeton | Fertigteil | false | F001 | 50 | XC1, WO | C25/30 | HA_FUN_FEB_0,250_xxx
Stahlbetonfertigteilfundament | EG_Produktion_FFB | STRIP_FOOTING | Stahlbetonfertigteil | FU-STREIFEN2\ | Stahlbetonfertigteilfundament | EG_Produktion_FFB | 0114SFu0000001395 | m² | Stahlbeton | Fertigteil | false | F001 | 50 | XC1, WO | C25/30 | HA_FUN_FEB_0,250_xxx
Stahlbetonfertigteilfundament | EG_Produktion_FFB | STRIP_FOOTING | Stahlbetonfertigteil | FU-STREIFEN2\ | Stahlbetonfertigteilfundament | EG_Produktion_FFB | 0114SFu0000001361 | m² | Stahlbeton | Fertigteil | false | F001 | 50 | XC1, WO | C25/30 | HA_FUN_FEB_0,250_xxx
Stahlbetonfertigteilfundament | EG_Produktion_FFB | STRIP_FOOTING | Stahlbetonfertigteil | FU-STREIFEN2\ | Stahlbetonfertigteilfundament | EG_Produktion_FFB | 0114SFu0000001349 | m² | Stahlbeton | Fertigteil | false | F001 | 50 | XC1, WO | C25/30 | HA_FUN_FEB_0,250_xxx
Stahlbetonfertigteilfundament | EG_Produktion_FFB | STRIP_FOOTING | Stahlbetonfertigteil | FU-STREIFEN2\ | Stahlbetonfertigteilfundament | EG_Produktion_FFB | 0114SFu0000001345 | m² | Stahlbeton | Fertigteil | false | F001 | 50 | XC1, WO | C25/30 | HA_FUN_FEB_0,250_xxx
Stahlbetonfertigteilfundament | EG_Produktion_FFB | STRIP_FOOTING | Stahlbetonfertigteil | FU-STREIFEN2\ | Stahlbetonfertigteilfundament | EG_Produktion_FFB | 0114SFu0000001347 | m² | Stahlbeton | Fertigteil | false | F001 | 50 | XC1, WO | C25/30 | HA_FUN_FEB_0,250_xxx
Stahlbetonfertigteilfundament | EG_Produktion_FFB | STRIP_FOOTING | Stahlbetonfertigteil | FU-STREIFEN2\ | Stahlbetonfertigteilfundament | EG_Produktion_FFB | 0114SFu0000001359 | m² | Stahlbeton | Fertigteil | false | F001 | 50 | XC1, WO | C25/30 | HA_FUN_FEB_0,250_xxx
Stahlbetonfertigteilfundament | EG_Produktion_FFB | STRIP_FOOTING | Stahlbetonfertigteil | FU-STREIFEN2\ | Stahlbetonfertigteilfundament | EG_Produktion_FFB | 0114SFu0000029348 | m² | Stahlbeton | Fertigteil | false | F001 | 50 | XC1, WO | C25/30 | HA_FUN_FEB_0,250_xxx
Stahlbetonfertigteilfundament | EG_Produktion_FFB | STRIP_FOOTING | Stahlbetonfertigteil | FU-STREIFEN2\ | Stahlbetonfertigteilfundament | EG_Produktion_FFB | 0114SFu0000029349 | m² | Stahlbeton | Fertigteil | false | F001 | 50 | XC1, WO | C25/30 | HA_FUN_FEB_0,250_xxx
Stahlbetonfertigteilfundament | EG_Produktion_FFB | STRIP_FOOTING | Stahlbetonfertigteil | FU-STREIFEN2\ | Stahlbetonfertigteilfundament | EG_Produktion_FFB | 0114SFu0000029350 | m² | Stahlbeton | Fertigteil | false | F001 | 50 | XC1, WO | C25/30 | HA_FUN_FEB_0,250_xxx
Stahlbetonfertigteilfundament | EG_Produktion_FFB | STRIP_FOOTING | Stahlbetonfertigteil | FU-STREIFEN2\ | Stahlbetonfertigteilfundament | EG_Produktion_FFB | 0114SFu0000029351 | m² | Stahlbeton | Fertigteil | false | F001 | 50 | XC1, WO | C25/30 | HA_FUN_FEB_0,250_xxx
Stahlbetonfertigteilfundament | EG_Produktion_FFB | STRIP_FOOTING | Stahlbetonfertigteil | FU-STREIFEN2\ | Stahlbetonfertigteilfundament | EG_Produktion_FFB | 0114SFu0000001337 | m² | Stahlbeton | Fertigteil | false | F001 | 50 | XC1, WO | C25/30 | HA_FUN_FEB_0,250_xxx
Stahlbetonfertigteilfundament | EG_Produktion_FFB | STRIP_FOOTING | Stahlbetonfertigteil | FU-STREIFEN2\ | Stahlbetonfertigteilfundament | EG_Produktion_FFB | 0114SFu0000001335 | m² | Stahlbeton | Fertigteil | false | F001 | 50 | XC1, WO | C25/30 | HA_FUN_FEB_0,250_xxx
Stahlbetonfertigteilfundament | EG_Produktion_FFB | STRIP_FOOTING | Stahlbetonfertigteil | FU-STREIFEN2\ | Stahlbetonfertigteilfundament | EG_Produktion_FFB | 0114SFu0000001307 | m² | Stahlbeton | Fertigteil | false | F001 | 50 | XC1, WO | C25/30 | HA_FUN_FEB_0,250_xxx
Stahlbetonfertigteilfundament | EG_Produktion_FFB | STRIP_FOOTING | Stahlbetonfertigteil | FU-STREIFEN2\ | Stahlbetonfertigteilfundament | EG_Produktion_FFB | 0114SFu0000001325 | m² | Stahlbeton | Fertigteil | false | F001 | 50 | XC1, WO | C25/30 | HA_FUN_FEB_0,250_xxx
Stahlbetonfertigteilfundament | EG_Produktion_FFB | STRIP_FOOTING | Stahlbetonfertigteil | FU-STREIFEN2\ | Stahlbetonfertigteilfundament | EG_Produktion_FFB | 0114SFu0000001455 | m² | Stahlbeton | Fertigteil | false | F001 | 50 | XC1, WO | C25/30 | HA_FUN_FEB_0,250_xxx
Stahlbetonfertigteilfundament | EG_Produktion_FFB | STRIP_FOOTING | Stahlbetonfertigteil | FU-STREIFEN2\ | Stahlbetonfertigteilfundament | EG_Produktion_FFB | 0114SFu0000001453 | m² | Stahlbeton | Fertigteil | false | F001 | 50 | XC1, WO | C25/30 | HA_FUN_FEB_0,250_xxx
Stahlbetonfertigteilfundament | EG_Produktion_FFB | STRIP_FOOTING | Stahlbetonfertigteil | FU-STREIFEN2\ | Stahlbetonfertigteilfundament | EG_Produktion_FFB | 0114SFu0000001457 | m² | Stahlbeton | Fertigteil | false | F001 | 50 | XC1, WO | C25/30 | HA_FUN_FEB_0,250_xxx
Stahlbetonfertigteilfundament | EG_Produktion_FFB | STRIP_FOOTING | Stahlbetonfertigteil | FU-STREIFEN2\ | Stahlbetonfertigteilfundament | EG_Produktion_FFB | 0114SFu0000001451 | m² | Stahlbeton | Fertigteil | false | F001 | 50 | XC1, WO | C25/30 | HA_FUN_FEB_0,250_xxx
Stahlbetonfertigteilfundament | EG_Produktion_FFB | STRIP_FOOTING | Stahlbetonfertigteil | FU-STREIFEN2\ | Stahlbetonfertigteilfundament | EG_Produktion_FFB | 0114SFu0000001371 | m² | Stahlbeton | Fertigteil | false | F001 | 50 | XC1, WO | C25/30 | HA_FUN_FEB_0,250_xxx
Stahlbetonfertigteilfundament | EG_Produktion_FFB | STRIP_FOOTING | Stahlbetonfertigteil | FU-STREIFEN2\ | Stahlbetonfertigteilfundament | EG_Produktion_FFB | 0114SFu0000001369 | m² | Stahlbeton | Fertigteil | false | F001 | 50 | XC1, WO | C25/30 | HA_FUN_FEB_0,250_xxx
Stahlbetonfertigteilfundament | EG_Produktion_FFB | STRIP_FOOTING | Stahlbetonfertigteil | FU-STREIFEN2\ | Stahlbetonfertigteilfundament | EG_Produktion_FFB | 0114SFu0000001373 | m² | Stahlbeton | Fertigteil | false | F001 | 50 | XC1, WO | C25/30 | HA_FUN_FEB_0,250_xxx
Stahlbetonfertigteilfundament | EG_Produktion_FFB | STRIP_FOOTING | Stahlbetonfertigteil | FU-STREIFEN2\ | Stahlbetonfertigteilfundament | EG_Produktion_FFB | 0114SFu0000001367 | m² | Stahlbeton | Fertigteil | false | F001 | 50 | XC1, WO | C25/30 | HA_FUN_FEB_0,250_xxx
Stahlbetonfertigteilfundament | EG_Produktion_FFB | STRIP_FOOTING | Stahlbetonfertigteil | FU-STREIFEN2\ | Stahlbetonfertigteilfundament | EG_Produktion_FFB | 0114SFu0000001305 | m² | Stahlbeton | Fertigteil | false | F001 | 50 | XC1, WO | C25/30 | HA_FUN_FEB_0,250_xxx
Stahlbetonfertigteilfundament | EG_Produktion_FFB | STRIP_FOOTING | Stahlbetonfertigteil | FU-STREIFEN2\ | Stahlbetonfertigteilfundament | EG_Produktion_FFB | 0114SFu0000001303 | m² | Stahlbeton | Fertigteil | false | F001 | 50 | XC1, WO | C25/30 | HA_FUN_FEB_0,250_xxx
Stahlbetonfertigteilfundament | EG_Produktion_FFB | STRIP_FOOTING | Stahlbetonfertigteil | FU-STREIFEN2\ | Stahlbetonfertigteilfundament | EG_Produktion_FFB | 0114SFu0000001321 | m² | Stahlbeton | Fertigteil | false | F001 | 50 | XC1, WO | C25/30 | HA_FUN_FEB_0,250_xxx
Stahlbetonfertigteilfundament | EG_Produktion_FFB | STRIP_FOOTING | Stahlbetonfertigteil | FU-STREIFEN2\ | Stahlbetonfertigteilfundament | EG_Produktion_FFB | 0114SFu0000001323 | m² | Stahlbeton | Fertigteil | false | F001 | 50 | XC1, WO | C25/30 | HA_FUN_FEB_0,250_xxx
Stahlbetonfertigteilfundament | EG_Produktion_FFB | STRIP_FOOTING | Stahlbetonfertigteil | FU-STREIFEN2\ | Stahlbetonfertigteilfundament | EG_Produktion_FFB | 0114SFu0000001549 | m² | Stahlbeton | Fertigteil | false | F001 | 50 | XC1, WO | C25/30 | HA_FUN_FEB_0,250_xxx
Stahlbetonfertigteilfundament | EG_Produktion_FFB | STRIP_FOOTING | Stahlbetonfertigteil | FU-STREIFEN2\ | Stahlbetonfertigteilfundament | EG_Produktion_FFB | 0114SFu0000001547 | m² | Stahlbeton | Fertigteil | false | F001 | 50 | XC1, WO | C25/30 | HA_FUN_FEB_0,250_xxx
Stahlbetonfertigteilfundament | EG_Produktion_FFB | STRIP_FOOTING | Stahlbetonfertigteil | FU-STREIFEN2\ | Stahlbetonfertigteilfundament | EG_Produktion_FFB | 0114SFu0000003134 | m² | Stahlbeton | Fertigteil | false | F001 | 50 | XC1, WO | C25/30 | HA_FUN_FEB_0,250_xxx
Stahlbetonfertigteilfundament | EG_Produktion_FFB | STRIP_FOOTING | Stahlbetonfertigteil | FU-STREIFEN2\ | Stahlbetonfertigteilfundament | EG_Produktion_FFB | 0114SFu0000003135 | m² | Stahlbeton | Fertigteil | false | F001 | 50 | XC1, WO | C25/30 | HA_FUN_FEB_0,250_xxx
Stahlbetonfertigteilfundament | EG_Produktion_FFB | STRIP_FOOTING | Stahlbetonfertigteil | FU-STREIFEN2\ | Stahlbetonfertigteilfundament | EG_Produktion_FFB | 0114SFu0000001293 | m² | Stahlbeton | Fertigteil | false | F001 | 50 | XC1, WO | C25/30 | HA_FUN_FEB_0,250_xxx
Stahlbetonfertigteilfundament | EG_Produktion_FFB | STRIP_FOOTING | Stahlbetonfertigteil | FU-STREIFEN2\ | Stahlbetonfertigteilfundament | EG_Produktion_FFB | 0114SFu0000001291 | m² | Stahlbeton | Fertigteil | false | F001 | 50 | XC1, WO | C25/30 | HA_FUN_FEB_0,250_xxx
Stahlbetonfertigteilfundament | EG_Produktion_FFB | STRIP_FOOTING | Stahlbetonfertigteil | FU-STREIFEN2\ | Stahlbetonfertigteilfundament | EG_Produktion_FFB | 0114SFu0000001297 | m² | Stahlbeton | Fertigteil | false | F001 | 50 | XC1, WO | C25/30 | HA_FUN_FEB_0,250_xxx
Stahlbetonfertigteilfundament | EG_Produktion_FFB | STRIP_FOOTING | Stahlbetonfertigteil | FU-STREIFEN2\ | Stahlbetonfertigteilfundament | EG_Produktion_FFB | 0114SFu0000001295 | m² | Stahlbeton | Fertigteil | false | F001 | 50 | XC1, WO | C25/30 | HA_FUN_FEB_0,250_xxx
Stahlbetonfertigteilfundament | EG_Produktion_FFB | STRIP_FOOTING | Stahlbetonfertigteil | FU-STREIFEN2\ | Stahlbetonfertigteilfundament | EG_Produktion_FFB | 0114SFu0000001343 | m² | Stahlbeton | Fertigteil | false | F001 | 50 | XC1, WO | C25/30 | HA_FUN_FEB_0,250_xxx
Stahlbetonfertigteilfundament | EG_Produktion_FFB | STRIP_FOOTING | Stahlbetonfertigteil | FU-STREIFEN2\ | Stahlbetonfertigteilfundament | EG_Produktion_FFB | 0114SFu0000001405 | m² | Stahlbeton | Fertigteil | false | F001 | 50 | XC1, WO | C25/30 | HA_FUN_FEB_0,250_xxx
Stahlbetonfertigteilfundament | EG_Produktion_FFB | STRIP_FOOTING | Stahlbetonfertigteil | FU-STREIFEN2\ | Stahlbetonfertigteilfundament | EG_Produktion_FFB | 0114SFu0000001225 | m² | Stahlbeton | Fertigteil | false | F001 | 50 | XC1, WO | C25/30 | HA_FUN_FEB_0,250_xxx
Stahlbetonfertigteilfundament | EG_Produktion_FFB | STRIP_FOOTING | Stahlbetonfertigteil | FU-STREIFEN2\ | Stahlbetonfertigteilfundament | EG_Produktion_FFB | 0114SFu0000001223 | m² | Stahlbeton | Fertigteil | false | F001 | 50 | XC1, WO | C25/30 | HA_FUN_FEB_0,250_xxx
Stahlbetonfertigteilfundament | EG_Produktion_FFB | STRIP_FOOTING | Stahlbetonfertigteil | FU-STREIFEN2\ | Stahlbetonfertigteilfundament | EG_Produktion_FFB | 0114SFu0000001221 | m² | Stahlbeton | Fertigteil | false | F001 | 50 | XC1, WO | C25/30 | HA_FUN_FEB_0,250_xxx
Stahlbetonfertigteilfundament | EG_Produktion_FFB | STRIP_FOOTING | Stahlbetonfertigteil | FU-STREIFEN2\ | Stahlbetonfertigteilfundament | EG_Produktion_FFB | 0114SFu0000001219 | m² | Stahlbeton | Fertigteil | false | F001 | 50 | XC1, WO | C25/30 | HA_FUN_FEB_0,250_xxx
Stahlbetonfertigteilfundament | EG_Produktion_FFB | STRIP_FOOTING | Stahlbetonfertigteil | FU-STREIFEN2\ | Stahlbetonfertigteilfundament | EG_Produktion_FFB | 0114SFu0000001217 | m² | Stahlbeton | Fertigteil | false | F001 | 50 | XC1, WO | C25/30 | HA_FUN_FEB_0,250_xxx
Stahlbetonfertigteilfundament | EG_Produktion_FFB | STRIP_FOOTING | Stahlbetonfertigteil | FU-STREIFEN2\ | Stahlbetonfertigteilfundament | EG_Produktion_FFB | 0114SFu0000001215 | m² | Stahlbeton | Fertigteil | false | F001 | 50 | XC1, WO | C25/30 | HA_FUN_FEB_0,250_xxx
Stahlbetonfertigteilfundament | EG_Produktion_FFB | STRIP_FOOTING | Stahlbetonfertigteil | FU-STREIFEN2\ | Stahlbetonfertigteilfundament | EG_Produktion_FFB | 0114SFu0000001213 | m² | Stahlbeton | Fertigteil | false | F001 | 50 | XC1, WO | C25/30 | HA_FUN_FEB_0,250_xxx
Stahlbetonfertigteilfundament | EG_Produktion_FFB | STRIP_FOOTING | Stahlbetonfertigteil | FU-STREIFEN2\ | Stahlbetonfertigteilfundament | EG_Produktion_FFB | 0114SFu0000001211 | m² | Stahlbeton | Fertigteil | false | F001 | 50 | XC1, WO | C25/30 | HA_FUN_FEB_0,250_xxx
Stahlbetonfertigteilfundament | EG_Produktion_FFB | STRIP_FOOTING | Stahlbetonfertigteil | FU-STREIFEN2\ | Stahlbetonfertigteilfundament | EG_Produktion_FFB | 0114SFu0000001209 | m² | Stahlbeton | Fertigteil | false | F001 | 50 | XC1, WO | C25/30 | HA_FUN_FEB_0,250_xxx
Stahlbetonfertigteilfundament | EG_Produktion_FFB | STRIP_FOOTING | Stahlbetonfertigteil | FU-STREIFEN2\ | Stahlbetonfertigteilfundament | EG_Produktion_FFB | 0114SFu0000001207 | m² | Stahlbeton | Fertigteil | false | F001 | 50 | XC1, WO | C25/30 | HA_FUN_FEB_0,250_xxx
Stahlbetonfertigteilfundament | EG_Produktion_FFB | STRIP_FOOTING | Stahlbetonfertigteil | FU-STREIFEN2\ | Stahlbetonfertigteilfundament | EG_Produktion_FFB | 0114SFu0000001205 | m² | Stahlbeton | Fertigteil | false | F001 | 50 | XC1, WO | C25/30 | HA_FUN_FEB_0,250_xxx
Stahlbetonfertigteilfundament | EG_Produktion_FFB | STRIP_FOOTING | Stahlbetonfertigteil | FU-STREIFEN2\ | Stahlbetonfertigteilfundament | EG_Produktion_FFB | 0114SFu0000001203 | m² | Stahlbeton | Fertigteil | false | F001 | 50 | XC1, WO | C25/30 | HA_FUN_FEB_0,250_xxx
Stahlbetonfertigteilfundament | EG_Produktion_FFB | STRIP_FOOTING | Stahlbetonfertigteil | FU-STREIFEN2\ | Stahlbetonfertigteilfundament | EG_Produktion_FFB | 0114SFu0000001177 | m² | Stahlbeton | Fertigteil | false | F001 | 50 | XC1, WO | C25/30 | HA_FUN_FEB_0,250_xxx
Stahlbetonfertigteilfundament | EG_Produktion_FFB | STRIP_FOOTING | Stahlbetonfertigteil | FU-STREIFEN2\ | Stahlbetonfertigteilfundament | EG_Produktion_FFB | 0114SFu0000001175 | m² | Stahlbeton | Fertigteil | false | F001 | 50 | XC1, WO | C25/30 | HA_FUN_FEB_0,250_xxx
Stahlbetonfertigteilfundament | EG_Produktion_FFB | STRIP_FOOTING | Stahlbetonfertigteil | FU-STREIFEN2\ | Stahlbetonfertigteilfundament | EG_Produktion_FFB | 0114SFu0000001189 | m² | Stahlbeton | Fertigteil | false | F001 | 50 | XC1, WO | C25/30 | HA_FUN_FEB_0,250_xxx
Stahlbetonfertigteilfundament | EG_Produktion_FFB | STRIP_FOOTING | Stahlbetonfertigteil | FU-STREIFEN2\ | Stahlbetonfertigteilfundament | EG_Produktion_FFB | 0114SFu0000001183 | m² | Stahlbeton | Fertigteil | false | F001 | 50 | XC1, WO | C25/30 | HA_FUN_FEB_0,250_xxx
Stahlbetonfertigteilfundament | EG_Produktion_FFB | STRIP_FOOTING | Stahlbetonfertigteil | FU-STREIFEN2\ | Stahlbetonfertigteilfundament | EG_Produktion_FFB | 0114SFu0000001193 | m² | Stahlbeton | Fertigteil | false | F001 | 50 | XC1, WO | C25/30 | HA_FUN_FEB_0,250_xxx
Stahlbetonfertigteilfundament | EG_Produktion_FFB | STRIP_FOOTING | Stahlbetonfertigteil | FU-STREIFEN2\ | Stahlbetonfertigteilfundament | EG_Produktion_FFB | 0114SFu0000001187 | m² | Stahlbeton | Fertigteil | false | F001 | 50 | XC1, WO | C25/30 | HA_FUN_FEB_0,250_xxx
Stahlbetonfertigteilfundament | EG_Produktion_FFB | STRIP_FOOTING | Stahlbetonfertigteil | FU-STREIFEN2\ | Stahlbetonfertigteilfundament | EG_Produktion_FFB | 0114SFu0000001185 | m² | Stahlbeton | Fertigteil | false | F001 | 50 | XC1, WO | C25/30 | HA_FUN_FEB_0,250_xxx
Stahlbetonfertigteilfundament | EG_Produktion_FFB | STRIP_FOOTING | Stahlbetonfertigteil | FU-STREIFEN2\ | Stahlbetonfertigteilfundament | EG_Produktion_FFB | 0114SFu0000001179 | m² | Stahlbeton | Fertigteil | false | F001 | 50 | XC1, WO | C25/30 | HA_FUN_FEB_0,250_xxx
Stahlbetonfertigteilfundament | EG_Produktion_FFB | STRIP_FOOTING | Stahlbetonfertigteil | FU-STREIFEN2\ | Stahlbetonfertigteilfundament | EG_Produktion_FFB | 0114SFu0000001181 | m² | Stahlbeton | Fertigteil | false | F001 | 50 | XC1, WO | C25/30 | HA_FUN_FEB_0,250_xxx
Stahlbetonfertigteilfundament | EG_Produktion_FFB | STRIP_FOOTING | Stahlbetonfertigteil | FU-STREIFEN2\ | Stahlbetonfertigteilfundament | EG_Produktion_FFB | 0114SFu0000001191 | m² | Stahlbeton | Fertigteil | false | F001 | 50 | XC1, WO | C25/30 | HA_FUN_FEB_0,250_xxx
Stahlbetonfertigteilfundament | EG_Produktion_FFB | STRIP_FOOTING | Stahlbetonfertigteil | FU-STREIFEN2\ | Stahlbetonfertigteilfundament | EG_Produktion_FFB | 0114SFu0000001161 | m² | Stahlbeton | Fertigteil | false | F001 | 50 | XC1, WO | C25/30 | HA_FUN_FEB_0,250_xxx
Stahlbetonfertigteilfundament | EG_Produktion_FFB | STRIP_FOOTING | Stahlbetonfertigteil | FU-STREIFEN2\ | Stahlbetonfertigteilfundament | EG_Produktion_FFB | 0114SFu0000001159 | m² | Stahlbeton | Fertigteil | false | F001 | 50 | XC1, WO | C25/30 | HA_FUN_FEB_0,250_xxx
Stahlbetonfertigteilfundament | EG_Produktion_FFB | STRIP_FOOTING | Stahlbetonfertigteil | FU-STREIFEN2\ | Stahlbetonfertigteilfundament | EG_Produktion_FFB | 0114SFu0000001157 | m² | Stahlbeton | Fertigteil | false | F001 | 50 | XC1, WO | C25/30 | HA_FUN_FEB_0,250_xxx
Stahlbetonfertigteilfundament | EG_Produktion_FFB | STRIP_FOOTING | Stahlbetonfertigteil | FU-STREIFEN2\ | Stahlbetonfertigteilfundament | EG_Produktion_FFB | 0114SFu0000001155 | m² | Stahlbeton | Fertigteil | false | F001 | 50 | XC1, WO | C25/30 | HA_FUN_FEB_0,250_xxx
Stahlbetonfertigteilfundament | EG_Produktion_FFB | STRIP_FOOTING | Stahlbetonfertigteil | FU-STREIFEN2\ | Stahlbetonfertigteilfundament | EG_Produktion_FFB | 0114SFu0000001153 | m² | Stahlbeton | Fertigteil | false | F001 | 50 | XC1, WO | C25/30 | HA_FUN_FEB_0,250_xxx
Stahlbetonfertigteilfundament | EG_Produktion_FFB | STRIP_FOOTING | Stahlbetonfertigteil | FU-STREIFEN2\ | Stahlbetonfertigteilfundament | EG_Produktion_FFB | 0114SFu0000001151 | m² | Stahlbeton | Fertigteil | false | F001 | 50 | XC1, WO | C25/30 | HA_FUN_FEB_0,250_xxx
Stahlbetonfertigteilfundament | EG_Produktion_FFB | STRIP_FOOTING | Stahlbetonfertigteil | FU-STREIFEN2\ | Stahlbetonfertigteilfundament | EG_Produktion_FFB | 0114SFu0000001149 | m² | Stahlbeton | Fertigteil | false | F001 | 50 | XC1, WO | C25/30 | HA_FUN_FEB_0,250_xxx
Stahlbetonfertigteilfundament | EG_Produktion_FFB | STRIP_FOOTING | Stahlbetonfertigteil | FU-STREIFEN2\ | Stahlbetonfertigteilfundament | EG_Produktion_FFB | 0114SFu0000001147 | m² | Stahlbeton | Fertigteil | false | F001 | 50 | XC1, WO | C25/30 | HA_FUN_FEB_0,250_xxx
Stahlbetonfertigteilfundament | EG_Produktion_FFB | STRIP_FOOTING | Stahlbetonfertigteil | FU-STREIFEN2\ | Stahlbetonfertigteilfundament | EG_Produktion_FFB | 0114SFu0000001145 | m² | Stahlbeton | Fertigteil | false | F001 | 50 | XC1, WO | C25/30 | HA_FUN_FEB_0,250_xxx
Stahlbetonfertigteilfundament | EG_Produktion_FFB | STRIP_FOOTING | Stahlbetonfertigteil | FU-STREIFEN2\ | Stahlbetonfertigteilfundament | EG_Produktion_FFB | 0114SFu0000001143 | m² | Stahlbeton | Fertigteil | false | F001 | 50 | XC1, WO | C25/30 | HA_FUN_FEB_0,250_xxx
Stahlbetonfertigteilfundament | EG_Produktion_FFB | STRIP_FOOTING | Stahlbetonfertigteil | FU-STREIFEN2\ | Stahlbetonfertigteilfundament | EG_Produktion_FFB | 0114SFu0000001101 | m² | Stahlbeton | Fertigteil | false | F001 | 50 | XC1, WO | C25/30 | HA_FUN_FEB_0,250_xxx
Stahlbetonfertigteilfundament | EG_Produktion_FFB | STRIP_FOOTING | Stahlbetonfertigteil | FU-STREIFEN2\ | Stahlbetonfertigteilfundament | EG_Produktion_FFB | 0114SFu0000001097 | m² | Stahlbeton | Fertigteil | false | F001 | 50 | XC1, WO | C25/30 | HA_FUN_FEB_0,250_xxx
Stahlbetonfertigteilfundament | EG_Produktion_FFB | STRIP_FOOTING | Stahlbetonfertigteil | FU-STREIFEN2\ | Stahlbetonfertigteilfundament | EG_Produktion_FFB | 0114SFu0000001095 | m² | Stahlbeton | Fertigteil | false | F001 | 50 | XC1, WO | C25/30 | HA_FUN_FEB_0,250_xxx
Stahlbetonfertigteilfundament | EG_Produktion_FFB | STRIP_FOOTING | Stahlbetonfertigteil | FU-STREIFEN2\ | Stahlbetonfertigteilfundament | EG_Produktion_FFB | 0114SFu0000001085 | m² | Stahlbeton | Fertigteil | false | F001 | 50 | XC1, WO | C25/30 | HA_FUN_FEB_0,250_xxx
Stahlbetonfertigteilfundament | EG_Produktion_FFB | STRIP_FOOTING | Stahlbetonfertigteil | FU-STREIFEN2\ | Stahlbetonfertigteilfundament | EG_Produktion_FFB | 0114SFu0000001083 | m² | Stahlbeton | Fertigteil | false | F001 | 50 | XC1, WO | C25/30 | HA_FUN_FEB_0,250_xxx
Stahlbetonfertigteilfundament | EG_Produktion_FFB | STRIP_FOOTING | Stahlbetonfertigteil | FU-STREIFEN2\ | Stahlbetonfertigteilfundament | EG_Produktion_FFB | 0114SFu0000001029 | m² | Stahlbeton | Fertigteil | false | F001 | 50 | XC1, WO | C25/30 | HA_FUN_FEB_0,250_xxx
Stahlbetonfertigteilfundament | EG_Produktion_FFB | STRIP_FOOTING | Stahlbetonfertigteil | FU-STREIFEN2\ | Stahlbetonfertigteilfundament | EG_Produktion_FFB | 0114SFu0000001021 | m² | Stahlbeton | Fertigteil | false | F001 | 50 | XC1, WO | C25/30 | HA_FUN_FEB_0,250_xxx
Stahlbetonfertigteilfundament | EG_Produktion_FFB | STRIP_FOOTING | Stahlbetonfertigteil | FU-STREIFEN2\ | Stahlbetonfertigteilfundament | EG_Produktion_FFB | 0114SFu0000001019 | m² | Stahlbeton | Fertigteil | false | F001 | 50 | XC1, WO | C25/30 | HA_FUN_FEB_0,250_xxx
Stahlbetonfertigteilfundament | EG_Produktion_FFB | STRIP_FOOTING | Stahlbetonfertigteil | FU-STREIFEN2\ | Stahlbetonfertigteilfundament | EG_Produktion_FFB | 0114SFu0000000997 | m² | Stahlbeton | Fertigteil | false | F001 | 50 | XC1, WO | C25/30 | HA_FUN_FEB_0,250_xxx
Stahlbetonfertigteilfundament | EG_Produktion_FFB | STRIP_FOOTING | Stahlbetonfertigteil | FU-STREIFEN2\ | Stahlbetonfertigteilfundament | EG_Produktion_FFB | 0114SFu0000000995 | m² | Stahlbeton | Fertigteil | false | F001 | 50 | XC1, WO | C25/30 | HA_FUN_FEB_0,250_xxx
Stahlbetonfertigteilfundament | EG_Produktion_FFB | STRIP_FOOTING | Stahlbetonfertigteil | FU-STREIFEN2\ | Stahlbetonfertigteilfundament | EG_Produktion_FFB | 0114SFu0000000981 | m² | Stahlbeton | Fertigteil | false | F001 | 50 | XC1, WO | C25/30 | HA_FUN_FEB_0,250_xxx
Stahlbetonfertigteilfundament | EG_Produktion_FFB | STRIP_FOOTING | Stahlbetonfertigteil | FU-STREIFEN2\ | Stahlbetonfertigteilfundament | EG_Produktion_FFB | 0114SFu0000000979 | m² | Stahlbeton | Fertigteil | false | F001 | 50 | XC1, WO | C25/30 | HA_FUN_FEB_0,250_xxx
Stahlbetonfertigteilfundament | EG_Produktion_FFB | STRIP_FOOTING | Stahlbetonfertigteil | FU-STREIFEN2\ | Stahlbetonfertigteilfundament | EG_Produktion_FFB | 0114SFu0000000973 | m² | Stahlbeton | Fertigteil | false | F001 | 50 | XC1, WO | C25/30 | HA_FUN_FEB_0,250_xxx
Stahlbetonfertigteilfundament | EG_Produktion_FFB | STRIP_FOOTING | Stahlbetonfertigteil | FU-STREIFEN2\ | Stahlbetonfertigteilfundament | EG_Produktion_FFB | 0114SFu0000000971 | m² | Stahlbeton | Fertigteil | false | F001 | 50 | XC1, WO | C25/30 | HA_FUN_FEB_0,250_xxx
Stahlbetonfertigteilfundament | EG_Produktion_FFB | STRIP_FOOTING | Stahlbetonfertigteil | FU-STREIFEN2\ | Stahlbetonfertigteilfundament | EG_Produktion_FFB | 0114SFu0000001017 | m² | Stahlbeton | Fertigteil | false | F001 | 50 | XC1, WO | C25/30 | HA_FUN_FEB_0,250_xxx
Stahlbetonfertigteilfundament | EG_Produktion_FFB | STRIP_FOOTING | Stahlbetonfertigteil | FU-STREIFEN2\ | Stahlbetonfertigteilfundament | EG_Produktion_FFB | 0114SFu0000001025 | m² | Stahlbeton | Fertigteil | false | F001 | 50 | XC1, WO | C25/30 | HA_FUN_FEB_0,250_xxx
Stahlbetonfertigteilfundament | EG_Produktion_FFB | STRIP_FOOTING | Stahlbetonfertigteil | FU-STREIFEN2\ | Stahlbetonfertigteilfundament | EG_Produktion_FFB | 0114SFu0000001015 | m² | Stahlbeton | Fertigteil | false | F001 | 50 | XC1, WO | C25/30 | HA_FUN_FEB_0,250_xxx
Stahlbetonfertigteilfundament | EG_Produktion_FFB | STRIP_FOOTING | Stahlbetonfertigteil | FU-STREIFEN2\ | Stahlbetonfertigteilfundament | EG_Produktion_FFB | 0114SFu0000001023 | m² | Stahlbeton | Fertigteil | false | F001 | 50 | XC1, WO | C25/30 | HA_FUN_FEB_0,250_xxx
Stahlbetonfertigteilfundament | EG_Produktion_FFB | STRIP_FOOTING | Stahlbetonfertigteil | FU-STREIFEN2\ | Stahlbetonfertigteilfundament | EG_Produktion_FFB | 0114SFu0000001001 | m² | Stahlbeton | Fertigteil | false | F001 | 50 | XC1, WO | C25/30 | HA_FUN_FEB_0,250_xxx
Stahlbetonfertigteilfundament | EG_Produktion_FFB | STRIP_FOOTING | Stahlbetonfertigteil | FU-STREIFEN2\ | Stahlbetonfertigteilfundament | EG_Produktion_FFB | 0114SFu0000001009 | m² | Stahlbeton | Fertigteil | false | F001 | 50 | XC1, WO | C25/30 | HA_FUN_FEB_0,250_xxx
Stahlbetonfertigteilfundament | EG_Produktion_FFB | STRIP_FOOTING | Stahlbetonfertigteil | FU-STREIFEN2\ | Stahlbetonfertigteilfundament | EG_Produktion_FFB | 0114SFu0000000999 | m² | Stahlbeton | Fertigteil | false | F001 | 50 | XC1, WO | C25/30 | HA_FUN_FEB_0,250_xxx
Stahlbetonfertigteilfundament | EG_Produktion_FFB | STRIP_FOOTING | Stahlbetonfertigteil | FU-STREIFEN2\ | Stahlbetonfertigteilfundament | EG_Produktion_FFB | 0114SFu0000001007 | m² | Stahlbeton | Fertigteil | false | F001 | 50 | XC1, WO | C25/30 | HA_FUN_FEB_0,250_xxx
Stahlbetonfertigteilfundament | EG_Produktion_FFB | STRIP_FOOTING | Stahlbetonfertigteil | FU-STREIFEN2\ | Stahlbetonfertigteilfundament | EG_Produktion_FFB | 0114SFu0000000993 | m² | Stahlbeton | Fertigteil | false | F001 | 50 | XC1, WO | C25/30 | HA_FUN_FEB_0,250_xxx
Stahlbetonfertigteilfundament | EG_Produktion_FFB | STRIP_FOOTING | Stahlbetonfertigteil | FU-STREIFEN2\ | Stahlbetonfertigteilfundament | EG_Produktion_FFB | 0114SFu0000000985 | m² | Stahlbeton | Fertigteil | false | F001 | 50 | XC1, WO | C25/30 | HA_FUN_FEB_0,250_xxx
Stahlbetonfertigteilfundament | EG_Produktion_FFB | STRIP_FOOTING | Stahlbetonfertigteil | FU-STREIFEN2\ | Stahlbetonfertigteilfundament | EG_Produktion_FFB | 0114SFu0000000983 | m² | Stahlbeton | Fertigteil | false | F001 | 50 | XC1, WO | C25/30 | HA_FUN_FEB_0,250_xxx
Stahlbetonfertigteilfundament | EG_Produktion_FFB | STRIP_FOOTING | Stahlbetonfertigteil | FU-STREIFEN2\ | Stahlbetonfertigteilfundament | EG_Produktion_FFB | 0114SFu0000000991 | m² | Stahlbeton | Fertigteil | false | F001 | 50 | XC1, WO | C25/30 | HA_FUN_FEB_0,250_xxx
Stahlbetonfertigteilfundament | EG_Produktion_FFB | STRIP_FOOTING | Stahlbetonfertigteil | FU-STREIFEN2\ | Stahlbetonfertigteilfundament | EG_Produktion_FFB | 0114SFu0000000897 | m² | Stahlbeton | Fertigteil | false | F001 | 50 | XC1, WO | C25/30 | HA_FUN_FEB_0,250_xxx
Stahlbetonfertigteilfundament | EG_Produktion_FFB | STRIP_FOOTING | Stahlbetonfertigteil | FU-STREIFEN2\ | Stahlbetonfertigteilfundament | EG_Produktion_FFB | 0114SFu0000000885 | m² | Stahlbeton | Fertigteil | false | F001 | 50 | XC1, WO | C25/30 | HA_FUN_FEB_0,250_xxx
Stahlbetonfertigteilfundament | EG_Produktion_FFB | STRIP_FOOTING | Stahlbetonfertigteil | FU-STREIFEN2\ | Stahlbetonfertigteilfundament | EG_Produktion_FFB | 0114SFu0000000883 | m² | Stahlbeton | Fertigteil | false | F001 | 50 | XC1, WO | C25/30 | HA_FUN_FEB_0,250_xxx
Stahlbetonfertigteilfundament | EG_Produktion_FFB | STRIP_FOOTING | Stahlbetonfertigteil | FU-STREIFEN2\ | Stahlbetonfertigteilfundament | EG_Produktion_FFB | 0114SFu0000000895 | m² | Stahlbeton | Fertigteil | false | F001 | 50 | XC1, WO | C25/30 | HA_FUN_FEB_0,250_xxx
Stahlbetonfertigteilfundament | EG_Produktion_FFB | STRIP_FOOTING | Stahlbetonfertigteil | FU-STREIFEN2\ | Stahlbetonfertigteilfundament | EG_Produktion_FFB | 0114SFu0000000873 | m² | Stahlbeton | Fertigteil | false | F001 | 50 | XC1, WO | C25/30 | HA_FUN_FEB_0,250_xxx
Stahlbetonfertigteilfundament | EG_Produktion_FFB | STRIP_FOOTING | Stahlbetonfertigteil | FU-STREIFEN2\ | Stahlbetonfertigteilfundament | EG_Produktion_FFB | 0114SFu0000000861 | m² | Stahlbeton | Fertigteil | false | F001 | 50 | XC1, WO | C25/30 | HA_FUN_FEB_0,250_xxx
Stahlbetonfertigteilfundament | EG_Produktion_FFB | STRIP_FOOTING | Stahlbetonfertigteil | FU-STREIFEN2\ | Stahlbetonfertigteilfundament | EG_Produktion_FFB | 0114SFu0000000859 | m² | Stahlbeton | Fertigteil | false | F001 | 50 | XC1, WO | C25/30 | HA_FUN_FEB_0,250_xxx
Stahlbetonfertigteilfundament | EG_Produktion_FFB | STRIP_FOOTING | Stahlbetonfertigteil | FU-STREIFEN2\ | Stahlbetonfertigteilfundament | EG_Produktion_FFB | 0114SFu0000000871 | m² | Stahlbeton | Fertigteil | false | F001 | 50 | XC1, WO | C25/30 | HA_FUN_FEB_0,250_xxx
Stahlbetonfertigteilfundament | EG_Produktion_FFB | STRIP_FOOTING | Stahlbetonfertigteil | FU-STREIFEN2\ | Stahlbetonfertigteilfundament | EG_Produktion_FFB | 0114SFu0000000849 | m² | Stahlbeton | Fertigteil | false | F001 | 50 | XC1, WO | C25/30 | HA_FUN_FEB_0,250_xxx
Stahlbetonfertigteilfundament | EG_Produktion_FFB | STRIP_FOOTING | Stahlbetonfertigteil | FU-STREIFEN2\ | Stahlbetonfertigteilfundament | EG_Produktion_FFB | 0114SFu0000000837 | m² | Stahlbeton | Fertigteil | false | F001 | 50 | XC1, WO | C25/30 | HA_FUN_FEB_0,250_xxx
Stahlbetonfertigteilfundament | EG_Produktion_FFB | STRIP_FOOTING | Stahlbetonfertigteil | FU-STREIFEN2\ | Stahlbetonfertigteilfundament | EG_Produktion_FFB | 0114SFu0000000835 | m² | Stahlbeton | Fertigteil | false | F001 | 50 | XC1, WO | C25/30 | HA_FUN_FEB_0,250_xxx
Stahlbetonfertigteilfundament | EG_Produktion_FFB | STRIP_FOOTING | Stahlbetonfertigteil | FU-STREIFEN2\ | Stahlbetonfertigteilfundament | EG_Produktion_FFB | 0114SFu0000000847 | m² | Stahlbeton | Fertigteil | false | F001 | 50 | XC1, WO | C25/30 | HA_FUN_FEB_0,250_xxx
Stahlbetonfertigteilfundament | EG_Produktion_FFB | STRIP_FOOTING | Stahlbetonfertigteil | FU-STREIFEN2\ | Stahlbetonfertigteilfundament | EG_Produktion_FFB | 0114SFu0000000825 | m² | Stahlbeton | Fertigteil | false | F001 | 50 | XC1, WO | C25/30 | HA_FUN_FEB_0,250_xxx
Stahlbetonfertigteilfundament | EG_Produktion_FFB | STRIP_FOOTING | Stahlbetonfertigteil | FU-STREIFEN2\ | Stahlbetonfertigteilfundament | EG_Produktion_FFB | 0114SFu0000000813 | m² | Stahlbeton | Fertigteil | false | F001 | 50 | XC1, WO | C25/30 | HA_FUN_FEB_0,250_xxx
Stahlbetonfertigteilfundament | EG_Produktion_FFB | STRIP_FOOTING | Stahlbetonfertigteil | FU-STREIFEN2\ | Stahlbetonfertigteilfundament | EG_Produktion_FFB | 0114SFu0000000811 | m² | Stahlbeton | Fertigteil | false | F001 | 50 | XC1, WO | C25/30 | HA_FUN_FEB_0,250_xxx
Stahlbetonfertigteilfundament | EG_Produktion_FFB | STRIP_FOOTING | Stahlbetonfertigteil | FU-STREIFEN2\ | Stahlbetonfertigteilfundament | EG_Produktion_FFB | 0114SFu0000000823 | m² | Stahlbeton | Fertigteil | false | F001 | 50 | XC1, WO | C25/30 | HA_FUN_FEB_0,250_xxx
Stahlbetonfertigteilfundament | EG_Produktion_FFB | STRIP_FOOTING | Stahlbetonfertigteil | FU-STREIFEN2\ | Stahlbetonfertigteilfundament | EG_Produktion_FFB | 0114SFu0000000833 | m² | Stahlbeton | Fertigteil | false | F001 | 50 | XC1, WO | C25/30 | HA_FUN_FEB_0,250_xxx
Stahlbetonfertigteilfundament | EG_Produktion_FFB | STRIP_FOOTING | Stahlbetonfertigteil | FU-STREIFEN2\ | Stahlbetonfertigteilfundament | EG_Produktion_FFB | 0114SFu0000000831 | m² | Stahlbeton | Fertigteil | false | F001 | 50 | XC1, WO | C25/30 | HA_FUN_FEB_0,250_xxx
Stahlbetonfertigteilfundament | EG_Produktion_FFB | STRIP_FOOTING | Stahlbetonfertigteil | FU-STREIFEN2\ | Stahlbetonfertigteilfundament | EG_Produktion_FFB | 0114SFu0000000869 | m² | Stahlbeton | Fertigteil | false | F001 | 50 | XC1, WO | C25/30 | HA_FUN_FEB_0,250_xxx
Stahlbetonfertigteilfundament | EG_Produktion_FFB | STRIP_FOOTING | Stahlbetonfertigteil | FU-STREIFEN2\ | Stahlbetonfertigteilfundament | EG_Produktion_FFB | 0114SFu0000000857 | m² | Stahlbeton | Fertigteil | false | F001 | 50 | XC1, WO | C25/30 | HA_FUN_FEB_0,250_xxx
Stahlbetonfertigteilfundament | EG_Produktion_FFB | STRIP_FOOTING | Stahlbetonfertigteil | FU-STREIFEN2\ | Stahlbetonfertigteilfundament | EG_Produktion_FFB | 0114SFu0000000845 | m² | Stahlbeton | Fertigteil | false | F001 | 50 | XC1, WO | C25/30 | HA_FUN_FEB_0,250_xxx
Stahlbetonfertigteilfundament | EG_Produktion_FFB | STRIP_FOOTING | Stahlbetonfertigteil | FU-STREIFEN2\ | Stahlbetonfertigteilfundament | EG_Produktion_FFB | 0114SFu0000000843 | m² | Stahlbeton | Fertigteil | false | F001 | 50 | XC1, WO | C25/30 | HA_FUN_FEB_0,250_xxx
Stahlbetonfertigteilfundament | EG_Produktion_FFB | STRIP_FOOTING | Stahlbetonfertigteil | FU-STREIFEN2\ | Stahlbetonfertigteilfundament | EG_Produktion_FFB | 0114SFu0000000855 | m² | Stahlbeton | Fertigteil | false | F001 | 50 | XC1, WO | C25/30 | HA_FUN_FEB_0,250_xxx
Stahlbetonfertigteilfundament | EG_Produktion_FFB | STRIP_FOOTING | Stahlbetonfertigteil | FU-STREIFEN2\ | Stahlbetonfertigteilfundament | EG_Produktion_FFB | 0114SFu0000000867 | m² | Stahlbeton | Fertigteil | false | F001 | 50 | XC1, WO | C25/30 | HA_FUN_FEB_0,250_xxx
Stahlbetonfertigteilfundament | EG_Produktion_FFB | STRIP_FOOTING | Stahlbetonfertigteil | FU-STREIFEN2\ | Stahlbetonfertigteilfundament | EG_Produktion_FFB | 0114SFu0000000893 | m² | Stahlbeton | Fertigteil | false | F001 | 50 | XC1, WO | C25/30 | HA_FUN_FEB_0,250_xxx
Stahlbetonfertigteilfundament | EG_Produktion_FFB | STRIP_FOOTING | Stahlbetonfertigteil | FU-STREIFEN2\ | Stahlbetonfertigteilfundament | EG_Produktion_FFB | 0114SFu0000000881 | m² | Stahlbeton | Fertigteil | false | F001 | 50 | XC1, WO | C25/30 | HA_FUN_FEB_0,250_xxx
Stahlbetonfertigteilfundament | EG_Produktion_FFB | STRIP_FOOTING | Stahlbetonfertigteil | FU-STREIFEN2\ | Stahlbetonfertigteilfundament | EG_Produktion_FFB | 0114SFu0000000891 | m² | Stahlbeton | Fertigteil | false | F001 | 50 | XC1, WO | C25/30 | HA_FUN_FEB_0,250_xxx
Stahlbetonfertigteilfundament | EG_Produktion_FFB | STRIP_FOOTING | Stahlbetonfertigteil | FU-STREIFEN2\ | Stahlbetonfertigteilfundament | EG_Produktion_FFB | 0114SFu0000000879 | m² | Stahlbeton | Fertigteil | false | F001 | 50 | XC1, WO | C25/30 | HA_FUN_FEB_0,250_xxx
Stahlbetonfertigteilfundament | EG_Produktion_FFB | STRIP_FOOTING | Stahlbetonfertigteil | FU-STREIFEN2\ | Stahlbetonfertigteilfundament | EG_Produktion_FFB | 0114SFu0000000739 | m² | Stahlbeton | Fertigteil | false | F001 | 50 | XC1, WO | C25/30 | HA_FUN_FEB_0,250_xxx
Stahlbetonfertigteilfundament | EG_Produktion_FFB | STRIP_FOOTING | Stahlbetonfertigteil | FU-STREIFEN2\ | Stahlbetonfertigteilfundament | EG_Produktion_FFB | 0114SFu0000000737 | m² | Stahlbeton | Fertigteil | false | F001 | 50 | XC1, WO | C25/30 | HA_FUN_FEB_0,250_xxx
Stahlbetonfertigteilfundament | EG_Produktion_FFB | STRIP_FOOTING | Stahlbetonfertigteil | FU-STREIFEN2\ | Stahlbetonfertigteilfundament | EG_Produktion_FFB | 0114SFu0000000735 | m² | Stahlbeton | Fertigteil | false | F001 | 50 | XC1, WO | C25/30 | HA_FUN_FEB_0,250_xxx
Stahlbetonfertigteilfundament | EG_Produktion_FFB | STRIP_FOOTING | Stahlbetonfertigteil | FU-STREIFEN2\ | Stahlbetonfertigteilfundament | EG_Produktion_FFB | 0114SFu0000000733 | m² | Stahlbeton | Fertigteil | false | F001 | 50 | XC1, WO | C25/30 | HA_FUN_FEB_0,250_xxx
Stahlbetonfertigteilfundament | EG_Produktion_FFB | STRIP_FOOTING | Stahlbetonfertigteil | FU-STREIFEN2\ | Stahlbetonfertigteilfundament | EG_Produktion_FFB | 0114SFu0000000623 | m² | Stahlbeton | Fertigteil | false | F001 | 50 | XC1, WO | C25/30 | HA_FUN_FEB_0,250_xxx
Stahlbetonfertigteilfundament | EG_Produktion_FFB | STRIP_FOOTING | Stahlbetonfertigteil | FU-STREIFEN2\ | Stahlbetonfertigteilfundament | EG_Produktion_FFB | 0114SFu0000000621 | m² | Stahlbeton | Fertigteil | false | F001 | 50 | XC1, WO | C25/30 | HA_FUN_FEB_0,250_xxx
Stahlbetonfertigteilfundament | EG_Produktion_FFB | STRIP_FOOTING | Stahlbetonfertigteil | FU-STREIFEN2\ | Stahlbetonfertigteilfundament | EG_Produktion_FFB | 0114SFu0000000627 | m² | Stahlbeton | Fertigteil | false | F001 | 50 | XC1, WO | C25/30 | HA_FUN_FEB_0,250_xxx
Stahlbetonfertigteilfundament | EG_Produktion_FFB | STRIP_FOOTING | Stahlbetonfertigteil | FU-STREIFEN2\ | Stahlbetonfertigteilfundament | EG_Produktion_FFB | 0114SFu0000000631 | m² | Stahlbeton | Fertigteil | false | F001 | 50 | XC1, WO | C25/30 | HA_FUN_FEB_0,250_xxx
Stahlbetonfertigteilfundament | EG_Produktion_FFB | STRIP_FOOTING | Stahlbetonfertigteil | FU-STREIFEN2\ | Stahlbetonfertigteilfundament | EG_Produktion_FFB | 0114SFu0000000625 | m² | Stahlbeton | Fertigteil | false | F001 | 50 | XC1, WO | C25/30 | HA_FUN_FEB_0,250_xxx
Stahlbetonfertigteilfundament | EG_Produktion_FFB | STRIP_FOOTING | Stahlbetonfertigteil | FU-STREIFEN2\ | Stahlbetonfertigteilfundament | EG_Produktion_FFB | 0114SFu0000000629 | m² | Stahlbeton | Fertigteil | false | F001 | 50 | XC1, WO | C25/30 | HA_FUN_FEB_0,250_xxx
Stahlbetonfertigteilfundament | EG_Produktion_FFB | STRIP_FOOTING | Stahlbetonfertigteil | FU-STREIFEN2\ | Stahlbetonfertigteilfundament | EG_Produktion_FFB | 0114SFu0000000635 | m² | Stahlbeton | Fertigteil | false | F001 | 50 | XC1, WO | C25/30 | HA_FUN_FEB_0,250_xxx
Stahlbetonfertigteilfundament | EG_Produktion_FFB | STRIP_FOOTING | Stahlbetonfertigteil | FU-STREIFEN2\ | Stahlbetonfertigteilfundament | EG_Produktion_FFB | 0114SFu0000000633 | m² | Stahlbeton | Fertigteil | false | F001 | 50 | XC1, WO | C25/30 | HA_FUN_FEB_0,250_xxx
Stahlbetonfertigteilfundament | EG_Produktion_FFB | STRIP_FOOTING | Stahlbetonfertigteil | FU-STREIFEN2\ | Stahlbetonfertigteilfundament | EG_Produktion_FFB | 0114SFu0000000639 | m² | Stahlbeton | Fertigteil | false | F001 | 50 | XC1, WO | C25/30 | HA_FUN_FEB_0,250_xxx
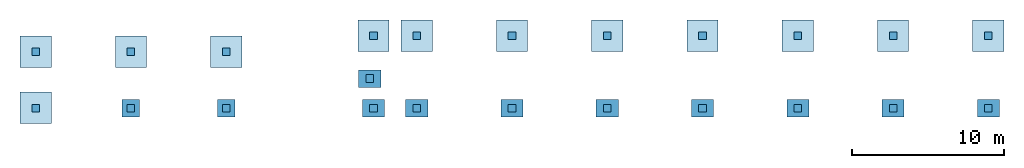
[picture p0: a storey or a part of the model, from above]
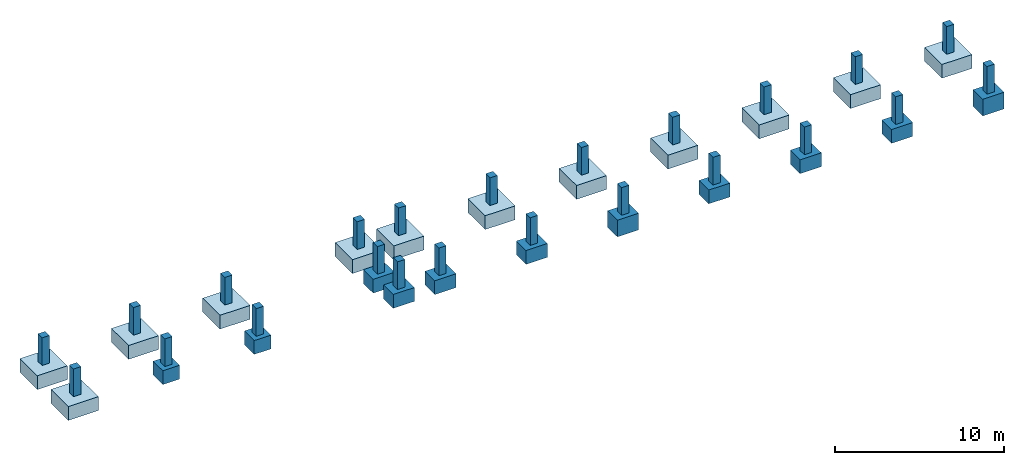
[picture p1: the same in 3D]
Properties of the parts of a building model (IFC2X3), part 14 of 25

# IfcFooting (903)
Name | In | PredefinedType | Material = AllplanAttributes, Material | Codetext | Bezeichnung = Name | Ebene | Allright_Bauteil_ID | Abrechnungsart | IFC_Pset_TWP, Material | Herstellung | Außenbauteil | Positionsnummer | Bewehrungsgrad | Expositionsklasse | Druckfestigkeitsklasse | Reference
Stahlbetonfertigteilfundament | EG_Produktion_FFB | STRIP_FOOTING | Stahlbetonfertigteil | FU-STREIFEN2\ | Stahlbetonfertigteilfundament | EG_Produktion_FFB | 0114SFu0000000637 | m² | Stahlbeton | Fertigteil | false | F001 | 50 | XC1, WO | C25/30 | HA_FUN_FEB_0,250_xxx
Stahlbetonfertigteilfundament | EG_Produktion_FFB | STRIP_FOOTING | Stahlbetonfertigteil | FU-STREIFEN2\ | Stahlbetonfertigteilfundament | EG_Produktion_FFB | 0114SFu0000000643 | m² | Stahlbeton | Fertigteil | false | F001 | 50 | XC1, WO | C25/30 | HA_FUN_FEB_0,250_xxx
Stahlbetonfertigteilfundament | EG_Produktion_FFB | STRIP_FOOTING | Stahlbetonfertigteil | FU-STREIFEN2\ | Stahlbetonfertigteilfundament | EG_Produktion_FFB | 0114SFu0000000641 | m² | Stahlbeton | Fertigteil | false | F001 | 50 | XC1, WO | C25/30 | HA_FUN_FEB_0,250_xxx
Stahlbetonfertigteilfundament | EG_Produktion_FFB | STRIP_FOOTING | Stahlbetonfertigteil | FU-STREIFEN2\ | Stahlbetonfertigteilfundament | EG_Produktion_FFB | 0114SFu0000000645 | m² | Stahlbeton | Fertigteil | false | F001 | 50 | XC1, WO | C25/30 | HA_FUN_FEB_0,250_xxx
Stahlbetonfertigteilfundament | EG_Produktion_FFB | STRIP_FOOTING | Stahlbetonfertigteil | FU-STREIFEN2\ | Stahlbetonfertigteilfundament | EG_Produktion_FFB | 0114SFu0000000647 | m² | Stahlbeton | Fertigteil | false | F001 | 50 | XC1, WO | C25/30 | HA_FUN_FEB_0,250_xxx
Stahlbetonfertigteilfundament | EG_Produktion_FFB | STRIP_FOOTING | Stahlbetonfertigteil | FU-STREIFEN2\ | Stahlbetonfertigteilfundament | EG_Produktion_FFB | 0114SFu0000000655 | m² | Stahlbeton | Fertigteil | false | F001 | 50 | XC1, WO | C25/30 | HA_FUN_FEB_0,250_xxx
Stahlbetonfertigteilfundament | EG_Produktion_FFB | STRIP_FOOTING | Stahlbetonfertigteil | FU-STREIFEN2\ | Stahlbetonfertigteilfundament | EG_Produktion_FFB | 0114SFu0000000659 | m² | Stahlbeton | Fertigteil | false | F001 | 50 | XC1, WO | C25/30 | HA_FUN_FEB_0,250_xxx
Stahlbetonfertigteilfundament | EG_Produktion_FFB | STRIP_FOOTING | Stahlbetonfertigteil | FU-STREIFEN2\ | Stahlbetonfertigteilfundament | EG_Produktion_FFB | 0114SFu0000000651 | m² | Stahlbeton | Fertigteil | false | F001 | 50 | XC1, WO | C25/30 | HA_FUN_FEB_0,250_xxx
Stahlbetonfertigteilfundament | EG_Produktion_FFB | STRIP_FOOTING | Stahlbetonfertigteil | FU-STREIFEN2\ | Stahlbetonfertigteilfundament | EG_Produktion_FFB | 0114SFu0000000663 | m² | Stahlbeton | Fertigteil | false | F001 | 50 | XC1, WO | C25/30 | HA_FUN_FEB_0,250_xxx
Stahlbetonfertigteilfundament | EG_Produktion_FFB | STRIP_FOOTING | Stahlbetonfertigteil | FU-STREIFEN2\ | Stahlbetonfertigteilfundament | EG_Produktion_FFB | 0114SFu0000000649 | m² | Stahlbeton | Fertigteil | false | F001 | 50 | XC1, WO | C25/30 | HA_FUN_FEB_0,250_xxx
Stahlbetonfertigteilfundament | EG_Produktion_FFB | STRIP_FOOTING | Stahlbetonfertigteil | FU-STREIFEN2\ | Stahlbetonfertigteilfundament | EG_Produktion_FFB | 0114SFu0000000653 | m² | Stahlbeton | Fertigteil | false | F001 | 50 | XC1, WO | C25/30 | HA_FUN_FEB_0,250_xxx
Stahlbetonfertigteilfundament | EG_Produktion_FFB | STRIP_FOOTING | Stahlbetonfertigteil | FU-STREIFEN2\ | Stahlbetonfertigteilfundament | EG_Produktion_FFB | 0114SFu0000000657 | m² | Stahlbeton | Fertigteil | false | F001 | 50 | XC1, WO | C25/30 | HA_FUN_FEB_0,250_xxx
Stahlbetonfertigteilfundament | EG_Produktion_FFB | STRIP_FOOTING | Stahlbetonfertigteil | FU-STREIFEN2\ | Stahlbetonfertigteilfundament | EG_Produktion_FFB | 0114SFu0000000661 | m² | Stahlbeton | Fertigteil | false | F001 | 50 | XC1, WO | C25/30 | HA_FUN_FEB_0,250_xxx
Stahlbetonfertigteilfundament | EG_Produktion_FFB | STRIP_FOOTING | Stahlbetonfertigteil | FU-STREIFEN2\ | Stahlbetonfertigteilfundament | EG_Produktion_FFB | 0114SFu0000000671 | m² | Stahlbeton | Fertigteil | false | F001 | 50 | XC1, WO | C25/30 | HA_FUN_FEB_0,250_xxx
Stahlbetonfertigteilfundament | EG_Produktion_FFB | STRIP_FOOTING | Stahlbetonfertigteil | FU-STREIFEN2\ | Stahlbetonfertigteilfundament | EG_Produktion_FFB | 0114SFu0000000667 | m² | Stahlbeton | Fertigteil | false | F001 | 50 | XC1, WO | C25/30 | HA_FUN_FEB_0,250_xxx
Stahlbetonfertigteilfundament | EG_Produktion_FFB | STRIP_FOOTING | Stahlbetonfertigteil | FU-STREIFEN2\ | Stahlbetonfertigteilfundament | EG_Produktion_FFB | 0114SFu0000000665 | m² | Stahlbeton | Fertigteil | false | F001 | 50 | XC1, WO | C25/30 | HA_FUN_FEB_0,250_xxx
Stahlbetonfertigteilfundament | EG_Produktion_FFB | STRIP_FOOTING | Stahlbetonfertigteil | FU-STREIFEN2\ | Stahlbetonfertigteilfundament | EG_Produktion_FFB | 0114SFu0000000669 | m² | Stahlbeton | Fertigteil | false | F001 | 50 | XC1, WO | C25/30 | HA_FUN_FEB_0,250_xxx
Stahlbetonfertigteilfundament | EG_Produktion_FFB | STRIP_FOOTING | Stahlbetonfertigteil | FU-STREIFEN2\ | Stahlbetonfertigteilfundament | EG_Produktion_FFB | 0114SFu0000000615 | m² | Stahlbeton | Fertigteil | false | F001 | 50 | XC1, WO | C25/30 | HA_FUN_FEB_0,250_xxx
Stahlbetonfertigteilfundament | EG_Produktion_FFB | STRIP_FOOTING | Stahlbetonfertigteil | FU-STREIFEN2\ | Stahlbetonfertigteilfundament | EG_Produktion_FFB | 0114SFu0000000613 | m² | Stahlbeton | Fertigteil | false | F001 | 50 | XC1, WO | C25/30 | HA_FUN_FEB_0,250_xxx
Stahlbetonfertigteilfundament | EG_Produktion_FFB | STRIP_FOOTING | Stahlbetonfertigteil | FU-STREIFEN2\ | Stahlbetonfertigteilfundament | EG_Produktion_FFB | 0114SFu0000000611 | m² | Stahlbeton | Fertigteil | false | F001 | 50 | XC1, WO | C25/30 | HA_FUN_FEB_0,250_xxx
Stahlbetonfertigteilfundament | EG_Produktion_FFB | STRIP_FOOTING | Stahlbetonfertigteil | FU-STREIFEN2\ | Stahlbetonfertigteilfundament | EG_Produktion_FFB | 0114SFu0000000609 | m² | Stahlbeton | Fertigteil | false | F001 | 50 | XC1, WO | C25/30 | HA_FUN_FEB_0,250_xxx
Stahlbetonfertigteilfundament | EG_Produktion_FFB | STRIP_FOOTING | Stahlbetonfertigteil | FU-STREIFEN2\ | Stahlbetonfertigteilfundament | EG_Produktion_FFB | 0114SFu0000001729 | m² | Stahlbeton | Fertigteil | false | F001 | 50 | XC1, WO | C25/30 | HA_FUN_FEB_0,250_xxx
Stahlbetonfertigteilfundament | EG_Produktion_FFB | STRIP_FOOTING | Stahlbetonfertigteil | FU-STREIFEN2\ | Stahlbetonfertigteilfundament | EG_Produktion_FFB | 0114SFu0000001721 | m² | Stahlbeton | Fertigteil | false | F001 | 50 | XC1, WO | C25/30 | HA_FUN_FEB_0,250_xxx
Stahlbetonfertigteilfundament | EG_Produktion_FFB | STRIP_FOOTING | Stahlbetonfertigteil | FU-STREIFEN2\ | Stahlbetonfertigteilfundament | EG_Produktion_FFB | 0114SFu0000001719 | m² | Stahlbeton | Fertigteil | false | F001 | 50 | XC1, WO | C25/30 | HA_FUN_FEB_0,250_xxx
Stahlbetonfertigteilfundament | EG_Produktion_FFB | STRIP_FOOTING | Stahlbetonfertigteil | FU-STREIFEN2\ | Stahlbetonfertigteilfundament | EG_Produktion_FFB | 0114SFu0000001791 | m² | Stahlbeton | Fertigteil | false | F001 | 50 | XC1, WO | C25/30 | HA_FUN_FEB_0,250_xxx
Stahlbetonfertigteilfundament | EG_Produktion_FFB | STRIP_FOOTING | Stahlbetonfertigteil | FU-STREIFEN2\ | Stahlbetonfertigteilfundament | EG_Produktion_FFB | 0114SFu0000001727 | m² | Stahlbeton | Fertigteil | false | F001 | 50 | XC1, WO | C25/30 | HA_FUN_FEB_0,250_xxx
Stahlbetonfertigteilfundament | EG_Produktion_FFB | STRIP_FOOTING | Stahlbetonfertigteil | FU-STREIFEN2\ | Stahlbetonfertigteilfundament | EG_Produktion_FFB | 0114SFu0000001783 | m² | Stahlbeton | Fertigteil | false | F001 | 50 | XC1, WO | C25/30 | HA_FUN_FEB_0,250_xxx
Stahlbetonfertigteilfundament | EG_Produktion_FFB | STRIP_FOOTING | Stahlbetonfertigteil | FU-STREIFEN2\ | Stahlbetonfertigteilfundament | EG_Produktion_FFB | 0114SFu0000001689 | m² | Stahlbeton | Fertigteil | false | F001 | 50 | XC1, WO | C25/30 | HA_FUN_FEB_0,250_xxx
Stahlbetonfertigteilfundament | EG_Produktion_FFB | STRIP_FOOTING | Stahlbetonfertigteil | FU-STREIFEN2\ | Stahlbetonfertigteilfundament | EG_Produktion_FFB | 0114SFu0000001681 | m² | Stahlbeton | Fertigteil | false | F001 | 50 | XC1, WO | C25/30 | HA_FUN_FEB_0,250_xxx
Stahlbetonfertigteilfundament | EG_Produktion_FFB | STRIP_FOOTING | Stahlbetonfertigteil | FU-STREIFEN2\ | Stahlbetonfertigteilfundament | EG_Produktion_FFB | 0114SFu0000001687 | m² | Stahlbeton | Fertigteil | false | F001 | 50 | XC1, WO | C25/30 | HA_FUN_FEB_0,250_xxx
Stahlbetonfertigteilfundament | EG_Produktion_FFB | STRIP_FOOTING | Stahlbetonfertigteil | FU-STREIFEN2\ | Stahlbetonfertigteilfundament | EG_Produktion_FFB | 0114SFu0000001679 | m² | Stahlbeton | Fertigteil | false | F001 | 50 | XC1, WO | C25/30 | HA_FUN_FEB_0,250_xxx
Stahlbetonfertigteilfundament | EG_Produktion_FFB | STRIP_FOOTING | Stahlbetonfertigteil | FU-STREIFEN2\ | Stahlbetonfertigteilfundament | EG_Produktion_FFB | 0114SFu0000001713 | m² | Stahlbeton | Fertigteil | false | F001 | 50 | XC1, WO | C25/30 | HA_FUN_FEB_0,250_xxx
Stahlbetonfertigteilfundament | EG_Produktion_FFB | STRIP_FOOTING | Stahlbetonfertigteil | FU-STREIFEN2\ | Stahlbetonfertigteilfundament | EG_Produktion_FFB | 0114SFu0000001705 | m² | Stahlbeton | Fertigteil | false | F001 | 50 | XC1, WO | C25/30 | HA_FUN_FEB_0,250_xxx
Stahlbetonfertigteilfundament | EG_Produktion_FFB | STRIP_FOOTING | Stahlbetonfertigteil | FU-STREIFEN2\ | Stahlbetonfertigteilfundament | EG_Produktion_FFB | 0114SFu0000001697 | m² | Stahlbeton | Fertigteil | false | F001 | 50 | XC1, WO | C25/30 | HA_FUN_FEB_0,250_xxx
Stahlbetonfertigteilfundament | EG_Produktion_FFB | STRIP_FOOTING | Stahlbetonfertigteil | FU-STREIFEN2\ | Stahlbetonfertigteilfundament | EG_Produktion_FFB | 0114SFu0000001695 | m² | Stahlbeton | Fertigteil | false | F001 | 50 | XC1, WO | C25/30 | HA_FUN_FEB_0,250_xxx
Stahlbetonfertigteilfundament | EG_Produktion_FFB | STRIP_FOOTING | Stahlbetonfertigteil | FU-STREIFEN2\ | Stahlbetonfertigteilfundament | EG_Produktion_FFB | 0114SFu0000001703 | m² | Stahlbeton | Fertigteil | false | F001 | 50 | XC1, WO | C25/30 | HA_FUN_FEB_0,250_xxx
Stahlbetonfertigteilfundament | EG_Produktion_FFB | STRIP_FOOTING | Stahlbetonfertigteil | FU-STREIFEN2\ | Stahlbetonfertigteilfundament | EG_Produktion_FFB | 0114SFu0000001711 | m² | Stahlbeton | Fertigteil | false | F001 | 50 | XC1, WO | C25/30 | HA_FUN_FEB_0,250_xxx
Stahlbetonfertigteilfundament | EG_Produktion_FFB | STRIP_FOOTING | Stahlbetonfertigteil | FU-STREIFEN2\ | Stahlbetonfertigteilfundament | EG_Produktion_FFB | 0114SFu0000001737 | m² | Stahlbeton | Fertigteil | false | F001 | 50 | XC1, WO | C25/30 | HA_FUN_FEB_0,250_xxx
Stahlbetonfertigteilfundament | EG_Produktion_FFB | STRIP_FOOTING | Stahlbetonfertigteil | FU-STREIFEN2\ | Stahlbetonfertigteilfundament | EG_Produktion_FFB | 0114SFu0000001735 | m² | Stahlbeton | Fertigteil | false | F001 | 50 | XC1, WO | C25/30 | HA_FUN_FEB_0,250_xxx
Stahlbetonfertigteilfundament | EG_Produktion_FFB | STRIP_FOOTING | Stahlbetonfertigteil | FU-STREIFEN2\ | Stahlbetonfertigteilfundament | EG_Produktion_FFB | 0114SFu0000001753 | m² | Stahlbeton | Fertigteil | false | F001 | 50 | XC1, WO | C25/30 | HA_FUN_FEB_0,250_xxx
Stahlbetonfertigteilfundament | EG_Produktion_FFB | STRIP_FOOTING | Stahlbetonfertigteil | FU-STREIFEN2\ | Stahlbetonfertigteilfundament | EG_Produktion_FFB | 0114SFu0000001745 | m² | Stahlbeton | Fertigteil | false | F001 | 50 | XC1, WO | C25/30 | HA_FUN_FEB_0,250_xxx
Stahlbetonfertigteilfundament | EG_Produktion_FFB | STRIP_FOOTING | Stahlbetonfertigteil | FU-STREIFEN2\ | Stahlbetonfertigteilfundament | EG_Produktion_FFB | 0114SFu0000001743 | m² | Stahlbeton | Fertigteil | false | F001 | 50 | XC1, WO | C25/30 | HA_FUN_FEB_0,250_xxx
Stahlbetonfertigteilfundament | EG_Produktion_FFB | STRIP_FOOTING | Stahlbetonfertigteil | FU-STREIFEN2\ | Stahlbetonfertigteilfundament | EG_Produktion_FFB | 0114SFu0000001751 | m² | Stahlbeton | Fertigteil | false | F001 | 50 | XC1, WO | C25/30 | HA_FUN_FEB_0,250_xxx
Stahlbetonfertigteilfundament | EG_Produktion_FFB | STRIP_FOOTING | Stahlbetonfertigteil | FU-STREIFEN2\ | Stahlbetonfertigteilfundament | EG_Produktion_FFB | 0114SFu0000001761 | m² | Stahlbeton | Fertigteil | false | F001 | 50 | XC1, WO | C25/30 | HA_FUN_FEB_0,250_xxx
Stahlbetonfertigteilfundament | EG_Produktion_FFB | STRIP_FOOTING | Stahlbetonfertigteil | FU-STREIFEN2\ | Stahlbetonfertigteilfundament | EG_Produktion_FFB | 0114SFu0000001759 | m² | Stahlbeton | Fertigteil | false | F001 | 50 | XC1, WO | C25/30 | HA_FUN_FEB_0,250_xxx
Stahlbetonfertigteilfundament | EG_Produktion_FFB | STRIP_FOOTING | Stahlbetonfertigteil | FU-STREIFEN2\ | Stahlbetonfertigteilfundament | EG_Produktion_FFB | 0114SFu0000001777 | m² | Stahlbeton | Fertigteil | false | F001 | 50 | XC1, WO | C25/30 | HA_FUN_FEB_0,250_xxx
Stahlbetonfertigteilfundament | EG_Produktion_FFB | STRIP_FOOTING | Stahlbetonfertigteil | FU-STREIFEN2\ | Stahlbetonfertigteilfundament | EG_Produktion_FFB | 0114SFu0000001769 | m² | Stahlbeton | Fertigteil | false | F001 | 50 | XC1, WO | C25/30 | HA_FUN_FEB_0,250_xxx
Stahlbetonfertigteilfundament | EG_Produktion_FFB | STRIP_FOOTING | Stahlbetonfertigteil | FU-STREIFEN2\ | Stahlbetonfertigteilfundament | EG_Produktion_FFB | 0114SFu0000001775 | m² | Stahlbeton | Fertigteil | false | F001 | 50 | XC1, WO | C25/30 | HA_FUN_FEB_0,250_xxx
Stahlbetonfertigteilfundament | EG_Produktion_FFB | STRIP_FOOTING | Stahlbetonfertigteil | FU-STREIFEN2\ | Stahlbetonfertigteilfundament | EG_Produktion_FFB | 0114SFu0000001767 | m² | Stahlbeton | Fertigteil | false | F001 | 50 | XC1, WO | C25/30 | HA_FUN_FEB_0,250_xxx
Stahlbetonfertigteilfundament | EG_Produktion_FFB | STRIP_FOOTING | Stahlbetonfertigteil | FU-STREIFEN2\ | Stahlbetonfertigteilfundament | EG_Produktion_FFB | 0114SFu0000001785 | m² | Stahlbeton | Fertigteil | false | F001 | 50 | XC1, WO | C25/30 | HA_FUN_FEB_0,250_xxx
Stahlbetonfertigteilfundament | EG_Produktion_FFB | STRIP_FOOTING | Stahlbetonfertigteil | FU-STREIFEN2\ | Stahlbetonfertigteilfundament | EG_Produktion_FFB | 0114SFu0000001793 | m² | Stahlbeton | Fertigteil | false | F001 | 50 | XC1, WO | C25/30 | HA_FUN_FEB_0,250_xxx
Stahlbetonfertigteilfundament | EG_Produktion_FFB | STRIP_FOOTING | Stahlbetonfertigteil | FU-STREIFEN2\ | Stahlbetonfertigteilfundament | EG_Produktion_FFB | 0114SFu0000000917 | m² | Stahlbeton | Fertigteil | false | F001 | 50 | XC1, WO | C25/30 | HA_FUN_FEB_0,250_xxx
Stahlbetonfertigteilfundament | EG_Produktion_FFB | STRIP_FOOTING | Stahlbetonfertigteil | FU-STREIFEN2\ | Stahlbetonfertigteilfundament | EG_Produktion_FFB | 0114SFu0000000915 | m² | Stahlbeton | Fertigteil | false | F001 | 50 | XC1, WO | C25/30 | HA_FUN_FEB_0,250_xxx
Stahlbetonfertigteilfundament | EG_Produktion_FFB | STRIP_FOOTING | Stahlbetonfertigteil | FU-STREIFEN2\ | Stahlbetonfertigteilfundament | EG_Produktion_FFB | 0114SFu0000000829 | m² | Stahlbeton | Fertigteil | false | F001 | 50 | XC1, WO | C25/30 | HA_FUN_FEB_0,250_xxx
Stahlbetonfertigteilfundament | EG_Produktion_FFB | STRIP_FOOTING | Stahlbetonfertigteil | FU-STREIFEN2\ | Stahlbetonfertigteilfundament | EG_Produktion_FFB | 0114SFu0000000841 | m² | Stahlbeton | Fertigteil | false | F001 | 50 | XC1, WO | C25/30 | HA_FUN_FEB_0,250_xxx
Stahlbetonfertigteilfundament | EG_Produktion_FFB | STRIP_FOOTING | Stahlbetonfertigteil | FU-STREIFEN2\ | Stahlbetonfertigteilfundament | EG_Produktion_FFB | 0114SFu0000000827 | m² | Stahlbeton | Fertigteil | false | F001 | 50 | XC1, WO | C25/30 | HA_FUN_FEB_0,250_xxx
Stahlbetonfertigteilfundament | EG_Produktion_FFB | STRIP_FOOTING | Stahlbetonfertigteil | FU-STREIFEN2\ | Stahlbetonfertigteilfundament | EG_Produktion_FFB | 0114SFu0000000839 | m² | Stahlbeton | Fertigteil | false | F001 | 50 | XC1, WO | C25/30 | HA_FUN_FEB_0,250_xxx
Stahlbetonfertigteilfundament | EG_Produktion_FFB | STRIP_FOOTING | Stahlbetonfertigteil | FU-STREIFEN2\ | Stahlbetonfertigteilfundament | EG_Produktion_FFB | 0114SFu0000000853 | m² | Stahlbeton | Fertigteil | false | F001 | 50 | XC1, WO | C25/30 | HA_FUN_FEB_0,250_xxx
Stahlbetonfertigteilfundament | EG_Produktion_FFB | STRIP_FOOTING | Stahlbetonfertigteil | FU-STREIFEN2\ | Stahlbetonfertigteilfundament | EG_Produktion_FFB | 0114SFu0000000877 | m² | Stahlbeton | Fertigteil | false | F001 | 50 | XC1, WO | C25/30 | HA_FUN_FEB_0,250_xxx
Stahlbetonfertigteilfundament | EG_Produktion_FFB | STRIP_FOOTING | Stahlbetonfertigteil | FU-STREIFEN2\ | Stahlbetonfertigteilfundament | EG_Produktion_FFB | 0114SFu0000000865 | m² | Stahlbeton | Fertigteil | false | F001 | 50 | XC1, WO | C25/30 | HA_FUN_FEB_0,250_xxx
Stahlbetonfertigteilfundament | EG_Produktion_FFB | STRIP_FOOTING | Stahlbetonfertigteil | FU-STREIFEN2\ | Stahlbetonfertigteilfundament | EG_Produktion_FFB | 0114SFu0000000851 | m² | Stahlbeton | Fertigteil | false | F001 | 50 | XC1, WO | C25/30 | HA_FUN_FEB_0,250_xxx
Stahlbetonfertigteilfundament | EG_Produktion_FFB | STRIP_FOOTING | Stahlbetonfertigteil | FU-STREIFEN2\ | Stahlbetonfertigteilfundament | EG_Produktion_FFB | 0114SFu0000000863 | m² | Stahlbeton | Fertigteil | false | F001 | 50 | XC1, WO | C25/30 | HA_FUN_FEB_0,250_xxx
Stahlbetonfertigteilfundament | EG_Produktion_FFB | STRIP_FOOTING | Stahlbetonfertigteil | FU-STREIFEN2\ | Stahlbetonfertigteilfundament | EG_Produktion_FFB | 0114SFu0000000875 | m² | Stahlbeton | Fertigteil | false | F001 | 50 | XC1, WO | C25/30 | HA_FUN_FEB_0,250_xxx
Stahlbetonfertigteilfundament | EG_Produktion_FFB | STRIP_FOOTING | Stahlbetonfertigteil | FU-STREIFEN2\ | Stahlbetonfertigteilfundament | EG_Produktion_FFB | 0114SFu0000000889 | m² | Stahlbeton | Fertigteil | false | F001 | 50 | XC1, WO | C25/30 | HA_FUN_FEB_0,250_xxx
Stahlbetonfertigteilfundament | EG_Produktion_FFB | STRIP_FOOTING | Stahlbetonfertigteil | FU-STREIFEN2\ | Stahlbetonfertigteilfundament | EG_Produktion_FFB | 0114SFu0000000887 | m² | Stahlbeton | Fertigteil | false | F001 | 50 | XC1, WO | C25/30 | HA_FUN_FEB_0,250_xxx
Stahlbetonfertigteilfundament | EG_Produktion_FFB | STRIP_FOOTING | Stahlbetonfertigteil | FU-STREIFEN2\ | Stahlbetonfertigteilfundament | EG_Produktion_FFB | 0114SFu0000000925 | m² | Stahlbeton | Fertigteil | false | F001 | 50 | XC1, WO | C25/30 | HA_FUN_FEB_0,250_xxx
Stahlbetonfertigteilfundament | EG_Produktion_FFB | STRIP_FOOTING | Stahlbetonfertigteil | FU-STREIFEN2\ | Stahlbetonfertigteilfundament | EG_Produktion_FFB | 0114SFu0000000913 | m² | Stahlbeton | Fertigteil | false | F001 | 50 | XC1, WO | C25/30 | HA_FUN_FEB_0,250_xxx
Stahlbetonfertigteilfundament | EG_Produktion_FFB | STRIP_FOOTING | Stahlbetonfertigteil | FU-STREIFEN2\ | Stahlbetonfertigteilfundament | EG_Produktion_FFB | 0114SFu0000000911 | m² | Stahlbeton | Fertigteil | false | F001 | 50 | XC1, WO | C25/30 | HA_FUN_FEB_0,250_xxx
Stahlbetonfertigteilfundament | EG_Produktion_FFB | STRIP_FOOTING | Stahlbetonfertigteil | FU-STREIFEN2\ | Stahlbetonfertigteilfundament | EG_Produktion_FFB | 0114SFu0000000923 | m² | Stahlbeton | Fertigteil | false | F001 | 50 | XC1, WO | C25/30 | HA_FUN_FEB_0,250_xxx
Stahlbetonfertigteilfundament | EG_Produktion_FFB | STRIP_FOOTING | Stahlbetonfertigteil | FU-STREIFEN2\ | Stahlbetonfertigteilfundament | EG_Produktion_FFB | 0114SFu0000000903 | m² | Stahlbeton | Fertigteil | false | F001 | 50 | XC1, WO | C25/30 | HA_FUN_FEB_0,250_xxx
Stahlbetonfertigteilfundament | EG_Produktion_FFB | STRIP_FOOTING | Stahlbetonfertigteil | FU-STREIFEN2\ | Stahlbetonfertigteilfundament | EG_Produktion_FFB | 0114SFu0000000905 | m² | Stahlbeton | Fertigteil | false | F001 | 50 | XC1, WO | C25/30 | HA_FUN_FEB_0,250_xxx
Stahlbetonfertigteilfundament | EG_Produktion_FFB | STRIP_FOOTING | Stahlbetonfertigteil | FU-STREIFEN2\ | Stahlbetonfertigteilfundament | EG_Produktion_FFB | 0114SFu0000000907 | m² | Stahlbeton | Fertigteil | false | F001 | 50 | XC1, WO | C25/30 | HA_FUN_FEB_0,250_xxx
Stahlbetonfertigteilfundament | EG_Produktion_FFB | STRIP_FOOTING | Stahlbetonfertigteil | FU-STREIFEN2\ | Stahlbetonfertigteilfundament | EG_Produktion_FFB | 0114SFu0000000909 | m² | Stahlbeton | Fertigteil | false | F001 | 50 | XC1, WO | C25/30 | HA_FUN_FEB_0,250_xxx
Stahlbetonfertigteilfundament | EG_Produktion_FFB | STRIP_FOOTING | Stahlbetonfertigteil | FU-STREIFEN2\ | Stahlbetonfertigteilfundament | EG_Produktion_FFB | 0114SFu0000001031 | m² | Stahlbeton | Fertigteil | false | F001 | 50 | XC1, WO | C25/30 | HA_FUN_FEB_0,250_xxx
Stahlbetonfertigteilfundament | EG_Produktion_FFB | STRIP_FOOTING | Stahlbetonfertigteil | FU-STREIFEN2\ | Stahlbetonfertigteilfundament | EG_Produktion_FFB | 0114SFu0000001033 | m² | Stahlbeton | Fertigteil | false | F001 | 50 | XC1, WO | C25/30 | HA_FUN_FEB_0,250_xxx
Stahlbetonfertigteilfundament | EG_Produktion_FFB | STRIP_FOOTING | Stahlbetonfertigteil | FU-STREIFEN2\ | Stahlbetonfertigteilfundament | EG_Produktion_FFB | 0114SFu0000001163 | m² | Stahlbeton | Fertigteil | false | F001 | 50 | XC1, WO | C25/30 | HA_FUN_FEB_0,250_xxx
Stahlbetonfertigteilfundament | EG_Produktion_FFB | STRIP_FOOTING | Stahlbetonfertigteil | FU-STREIFEN2\ | Stahlbetonfertigteilfundament | EG_Produktion_FFB | 0114SFu0000001165 | m² | Stahlbeton | Fertigteil | false | F001 | 50 | XC1, WO | C25/30 | HA_FUN_FEB_0,250_xxx
Stahlbetonfertigteilfundament | EG_Produktion_FFB | STRIP_FOOTING | Stahlbetonfertigteil | FU-STREIFEN2\ | Stahlbetonfertigteilfundament | EG_Produktion_FFB | 0114SFu0000021950 | m² | Stahlbeton | Fertigteil | false | F001 | 50 | XC1, WO | C25/30 | HA_FUN_FEB_0,250_xxx
Stahlbetonfertigteilfundament | EG_Produktion_FFB | STRIP_FOOTING | Stahlbetonfertigteil | FU-STREIFEN2\ | Stahlbetonfertigteilfundament | EG_Produktion_FFB | 0114SFu0000021949 | m² | Stahlbeton | Fertigteil | false | F001 | 50 | XC1, WO | C25/30 | HA_FUN_FEB_0,250_xxx
Stahlbetonfertigteilfundament | EG_Produktion_FFB | STRIP_FOOTING | Stahlbetonfertigteil | FU-STREIFEN2\ | Stahlbetonfertigteilfundament | EG_Produktion_FFB | 0114SFu0000000693 | m² | Stahlbeton | Fertigteil | false | F001 | 50 | XC1, WO | C25/30 | HA_FUN_FEB_0,250_xxx
Stahlbetonfertigteilfundament | EG_Produktion_FFB | STRIP_FOOTING | Stahlbetonfertigteil | FU-STREIFEN2\ | Stahlbetonfertigteilfundament | EG_Produktion_FFB | 0114SFu0000000695 | m² | Stahlbeton | Fertigteil | false | F001 | 50 | XC1, WO | C25/30 | HA_FUN_FEB_0,250_xxx
Stahlbetonfertigteilfundament | EG_Produktion_FFB | STRIP_FOOTING | Stahlbetonfertigteil | FU-STREIFEN2\ | Stahlbetonfertigteilfundament | EG_Produktion_FFB | 0114SFu0000000689 | m² | Stahlbeton | Fertigteil | false | F001 | 50 | XC1, WO | C25/30 | HA_FUN_FEB_0,250_xxx
Stahlbetonfertigteilfundament | EG_Produktion_FFB | STRIP_FOOTING | Stahlbetonfertigteil | FU-STREIFEN2\ | Stahlbetonfertigteilfundament | EG_Produktion_FFB | 0114SFu0000000691 | m² | Stahlbeton | Fertigteil | false | F001 | 50 | XC1, WO | C25/30 | HA_FUN_FEB_0,250_xxx
Stahlbetonfertigteilfundament | EG_Produktion_FFB | STRIP_FOOTING | Stahlbetonfertigteil | FU-STREIFEN2\ | Stahlbetonfertigteilfundament | EG_Produktion_FFB | 0114SFu0000000685 | m² | Stahlbeton | Fertigteil | false | F001 | 50 | XC1, WO | C25/30 | HA_FUN_FEB_0,250_xxx
Stahlbetonfertigteilfundament | EG_Produktion_FFB | STRIP_FOOTING | Stahlbetonfertigteil | FU-STREIFEN2\ | Stahlbetonfertigteilfundament | EG_Produktion_FFB | 0114SFu0000000687 | m² | Stahlbeton | Fertigteil | false | F001 | 50 | XC1, WO | C25/30 | HA_FUN_FEB_0,250_xxx
Stahlbetonfertigteilfundament | EG_Produktion_FFB | STRIP_FOOTING | Stahlbetonfertigteil | FU-STREIFEN2\ | Stahlbetonfertigteilfundament | EG_Produktion_FFB | 0114SFu0000000681 | m² | Stahlbeton | Fertigteil | false | F001 | 50 | XC1, WO | C25/30 | HA_FUN_FEB_0,250_xxx
Stahlbetonfertigteilfundament | EG_Produktion_FFB | STRIP_FOOTING | Stahlbetonfertigteil | FU-STREIFEN2\ | Stahlbetonfertigteilfundament | EG_Produktion_FFB | 0114SFu0000000683 | m² | Stahlbeton | Fertigteil | false | F001 | 50 | XC1, WO | C25/30 | HA_FUN_FEB_0,250_xxx
Stahlbetonfertigteilfundament | EG_Produktion_FFB | STRIP_FOOTING | Stahlbetonfertigteil | FU-STREIFEN2\ | Stahlbetonfertigteilfundament | EG_Produktion_FFB | 0114SFu0000001037 | m² | Stahlbeton | Fertigteil | false | F001 | 50 | XC1, WO | C25/30 | HA_FUN_FEB_0,250_xxx
Stahlbetonfertigteilfundament | EG_Produktion_FFB | STRIP_FOOTING | Stahlbetonfertigteil | FU-STREIFEN2\ | Stahlbetonfertigteilfundament | EG_Produktion_FFB | 0114SFu0000001105 | m² | Stahlbeton | Fertigteil | false | F001 | 50 | XC1, WO | C25/30 | HA_FUN_FEB_0,250_xxx
Stahlbetonfertigteilfundament | EG_Produktion_FFB | STRIP_FOOTING | Stahlbetonfertigteil | FU-STREIFEN2\ | Stahlbetonfertigteilfundament | EG_Produktion_FFB | 0114SFu0000001133 | m² | Stahlbeton | Fertigteil | false | F001 | 50 | XC1, WO | C25/30 | HA_FUN_FEB_0,250_xxx
Stahlbetonfertigteilfundament | EG_Produktion_FFB | STRIP_FOOTING | Stahlbetonfertigteil | FU-STREIFEN2\ | Stahlbetonfertigteilfundament | EG_Produktion_FFB | 0114SFu0000001137 | m² | Stahlbeton | Fertigteil | false | F001 | 50 | XC1, WO | C25/30 | HA_FUN_FEB_0,250_xxx
Stahlbetonfertigteilfundament | EG_Produktion_FFB | STRIP_FOOTING | Stahlbetonfertigteil | FU-STREIFEN2\ | Stahlbetonfertigteilfundament | EG_Produktion_FFB | 0114SFu0000001123 | m² | Stahlbeton | Fertigteil | false | F001 | 50 | XC1, WO | C25/30 | HA_FUN_FEB_0,250_xxx
Stahlbetonfertigteilfundament | EG_Produktion_FFB | STRIP_FOOTING | Stahlbetonfertigteil | FU-STREIFEN2\ | Stahlbetonfertigteilfundament | EG_Produktion_FFB | 0114SFu0000001125 | m² | Stahlbeton | Fertigteil | false | F001 | 50 | XC1, WO | C25/30 | HA_FUN_FEB_0,250_xxx
Stahlbetonfertigteilfundament | EG_Produktion_FFB | STRIP_FOOTING | Stahlbetonfertigteil | FU-STREIFEN2\ | Stahlbetonfertigteilfundament | EG_Produktion_FFB | 0114SFu0000001127 | m² | Stahlbeton | Fertigteil | false | F001 | 50 | XC1, WO | C25/30 | HA_FUN_FEB_0,250_xxx
Stahlbetonfertigteilfundament | EG_Produktion_FFB | STRIP_FOOTING | Stahlbetonfertigteil | FU-STREIFEN2\ | Stahlbetonfertigteilfundament | EG_Produktion_FFB | 0114SFu0000001141 | m² | Stahlbeton | Fertigteil | false | F001 | 50 | XC1, WO | C25/30 | HA_FUN_FEB_0,250_xxx
Stahlbetonfertigteilfundament | EG_Produktion_FFB | STRIP_FOOTING | Stahlbetonfertigteil | FU-STREIFEN2\ | Stahlbetonfertigteilfundament | EG_Produktion_FFB | 0114SFu0000001117 | m² | Stahlbeton | Fertigteil | false | F001 | 50 | XC1, WO | C25/30 | HA_FUN_FEB_0,250_xxx
Stahlbetonfertigteilfundament | EG_Produktion_FFB | STRIP_FOOTING | Stahlbetonfertigteil | FU-STREIFEN2\ | Stahlbetonfertigteilfundament | EG_Produktion_FFB | 0114SFu0000001115 | m² | Stahlbeton | Fertigteil | false | F001 | 50 | XC1, WO | C25/30 | HA_FUN_FEB_0,250_xxx
Stahlbetonfertigteilfundament | EG_Produktion_FFB | STRIP_FOOTING | Stahlbetonfertigteil | FU-STREIFEN2\ | Stahlbetonfertigteilfundament | EG_Produktion_FFB | 0114SFu0000001139 | m² | Stahlbeton | Fertigteil | false | F001 | 50 | XC1, WO | C25/30 | HA_FUN_FEB_0,250_xxx
Stahlbetonfertigteilfundament | EG_Produktion_FFB | STRIP_FOOTING | Stahlbetonfertigteil | FU-STREIFEN2\ | Stahlbetonfertigteilfundament | EG_Produktion_FFB | 0114SFu0000001119 | m² | Stahlbeton | Fertigteil | false | F001 | 50 | XC1, WO | C25/30 | HA_FUN_FEB_0,250_xxx
Stahlbetonfertigteilfundament | EG_Produktion_FFB | STRIP_FOOTING | Stahlbetonfertigteil | FU-STREIFEN2\ | Stahlbetonfertigteilfundament | EG_Produktion_FFB | 0114SFu0000001121 | m² | Stahlbeton | Fertigteil | false | F001 | 50 | XC1, WO | C25/30 | HA_FUN_FEB_0,250_xxx
Stahlbetonfertigteilfundament | EG_Produktion_FFB | STRIP_FOOTING | Stahlbetonfertigteil | FU-STREIFEN2\ | Stahlbetonfertigteilfundament | EG_Produktion_FFB | 0114SFu0000001129 | m² | Stahlbeton | Fertigteil | false | F001 | 50 | XC1, WO | C25/30 | HA_FUN_FEB_0,250_xxx
Stahlbetonfertigteilfundament | EG_Produktion_FFB | STRIP_FOOTING | Stahlbetonfertigteil | FU-STREIFEN2\ | Stahlbetonfertigteilfundament | EG_Produktion_FFB | 0114SFu0000001135 | m² | Stahlbeton | Fertigteil | false | F001 | 50 | XC1, WO | C25/30 | HA_FUN_FEB_0,250_xxx
Stahlbetonfertigteilfundament | EG_Produktion_FFB | STRIP_FOOTING | Stahlbetonfertigteil | FU-STREIFEN2\ | Stahlbetonfertigteilfundament | EG_Produktion_FFB | 0114SFu0000001131 | m² | Stahlbeton | Fertigteil | false | F001 | 50 | XC1, WO | C25/30 | HA_FUN_FEB_0,250_xxx
Stahlbetonfertigteilfundament | EG_Produktion_FFB | STRIP_FOOTING | Stahlbetonfertigteil | FU-STREIFEN2\ | Stahlbetonfertigteilfundament | EG_Produktion_FFB | 0114SFu0000001081 | m² | Stahlbeton | Fertigteil | false | F001 | 50 | XC1, WO | C25/30 | HA_FUN_FEB_0,250_xxx
Stahlbetonfertigteilfundament | EG_Produktion_FFB | STRIP_FOOTING | Stahlbetonfertigteil | FU-STREIFEN2\ | Stahlbetonfertigteilfundament | EG_Produktion_FFB | 0114SFu0000001071 | m² | Stahlbeton | Fertigteil | false | F001 | 50 | XC1, WO | C25/30 | HA_FUN_FEB_0,250_xxx
Stahlbetonfertigteilfundament | EG_Produktion_FFB | STRIP_FOOTING | Stahlbetonfertigteil | FU-STREIFEN2\ | Stahlbetonfertigteilfundament | EG_Produktion_FFB | 0114SFu0000001069 | m² | Stahlbeton | Fertigteil | false | F001 | 50 | XC1, WO | C25/30 | HA_FUN_FEB_0,250_xxx
Stahlbetonfertigteilfundament | EG_Produktion_FFB | STRIP_FOOTING | Stahlbetonfertigteil | FU-STREIFEN2\ | Stahlbetonfertigteilfundament | EG_Produktion_FFB | 0114SFu0000001075 | m² | Stahlbeton | Fertigteil | false | F001 | 50 | XC1, WO | C25/30 | HA_FUN_FEB_0,250_xxx
Stahlbetonfertigteilfundament | EG_Produktion_FFB | STRIP_FOOTING | Stahlbetonfertigteil | FU-STREIFEN2\ | Stahlbetonfertigteilfundament | EG_Produktion_FFB | 0114SFu0000001077 | m² | Stahlbeton | Fertigteil | false | F001 | 50 | XC1, WO | C25/30 | HA_FUN_FEB_0,250_xxx
Stahlbetonfertigteilfundament | EG_Produktion_FFB | STRIP_FOOTING | Stahlbetonfertigteil | FU-STREIFEN2\ | Stahlbetonfertigteilfundament | EG_Produktion_FFB | 0114SFu0000001057 | m² | Stahlbeton | Fertigteil | false | F001 | 50 | XC1, WO | C25/30 | HA_FUN_FEB_0,250_xxx
Stahlbetonfertigteilfundament | EG_Produktion_FFB | STRIP_FOOTING | Stahlbetonfertigteil | FU-STREIFEN2\ | Stahlbetonfertigteilfundament | EG_Produktion_FFB | 0114SFu0000001063 | m² | Stahlbeton | Fertigteil | false | F001 | 50 | XC1, WO | C25/30 | HA_FUN_FEB_0,250_xxx
Stahlbetonfertigteilfundament | EG_Produktion_FFB | STRIP_FOOTING | Stahlbetonfertigteil | FU-STREIFEN2\ | Stahlbetonfertigteilfundament | EG_Produktion_FFB | 0114SFu0000001065 | m² | Stahlbeton | Fertigteil | false | F001 | 50 | XC1, WO | C25/30 | HA_FUN_FEB_0,250_xxx
Stahlbetonfertigteilfundament | EG_Produktion_FFB | STRIP_FOOTING | Stahlbetonfertigteil | FU-STREIFEN2\ | Stahlbetonfertigteilfundament | EG_Produktion_FFB | 0114SFu0000001059 | m² | Stahlbeton | Fertigteil | false | F001 | 50 | XC1, WO | C25/30 | HA_FUN_FEB_0,250_xxx
Stahlbetonfertigteilfundament | EG_Produktion_FFB | STRIP_FOOTING | Stahlbetonfertigteil | FU-STREIFEN2\ | Stahlbetonfertigteilfundament | EG_Produktion_FFB | 0114SFu0000000989 | m² | Stahlbeton | Fertigteil | false | F001 | 50 | XC1, WO | C25/30 | HA_FUN_FEB_0,250_xxx
Stahlbetonfertigteilfundament | EG_Produktion_FFB | STRIP_FOOTING | Stahlbetonfertigteil | FU-STREIFEN2\ | Stahlbetonfertigteilfundament | EG_Produktion_FFB | 0114SFu0000000953 | m² | Stahlbeton | Fertigteil | false | F001 | 50 | XC1, WO | C25/30 | HA_FUN_FEB_0,250_xxx
Stahlbetonfertigteilfundament | EG_Produktion_FFB | STRIP_FOOTING | Stahlbetonfertigteil | FU-STREIFEN2\ | Stahlbetonfertigteilfundament | EG_Produktion_FFB | 0114SFu0000000949 | m² | Stahlbeton | Fertigteil | false | F001 | 50 | XC1, WO | C25/30 | HA_FUN_FEB_0,250_xxx
Stahlbetonfertigteilfundament | EG_Produktion_FFB | STRIP_FOOTING | Stahlbetonfertigteil | FU-STREIFEN2\ | Stahlbetonfertigteilfundament | EG_Produktion_FFB | 0114SFu0000000939 | m² | Stahlbeton | Fertigteil | false | F001 | 50 | XC1, WO | C25/30 | HA_FUN_FEB_0,250_xxx
Stahlbetonfertigteilfundament | EG_Produktion_FFB | STRIP_FOOTING | Stahlbetonfertigteil | FU-STREIFEN2\ | Stahlbetonfertigteilfundament | EG_Produktion_FFB | 0114SFu0000000943 | m² | Stahlbeton | Fertigteil | false | F001 | 50 | XC1, WO | C25/30 | HA_FUN_FEB_0,250_xxx
Stahlbetonfertigteilfundament | EG_Produktion_FFB | STRIP_FOOTING | Stahlbetonfertigteil | FU-STREIFEN2\ | Stahlbetonfertigteilfundament | EG_Produktion_FFB | 0114SFu0000000957 | m² | Stahlbeton | Fertigteil | false | F001 | 50 | XC1, WO | C25/30 | HA_FUN_FEB_0,250_xxx
Stahlbetonfertigteilfundament | EG_Produktion_FFB | STRIP_FOOTING | Stahlbetonfertigteil | FU-STREIFEN2\ | Stahlbetonfertigteilfundament | EG_Produktion_FFB | 0114SFu0000000955 | m² | Stahlbeton | Fertigteil | false | F001 | 50 | XC1, WO | C25/30 | HA_FUN_FEB_0,250_xxx
Stahlbetonfertigteilfundament | EG_Produktion_FFB | STRIP_FOOTING | Stahlbetonfertigteil | FU-STREIFEN2\ | Stahlbetonfertigteilfundament | EG_Produktion_FFB | 0114SFu0000000951 | m² | Stahlbeton | Fertigteil | false | F001 | 50 | XC1, WO | C25/30 | HA_FUN_FEB_0,250_xxx
Stahlbetonfertigteilfundament | EG_Produktion_FFB | STRIP_FOOTING | Stahlbetonfertigteil | FU-STREIFEN2\ | Stahlbetonfertigteilfundament | EG_Produktion_FFB | 0114SFu0000000941 | m² | Stahlbeton | Fertigteil | false | F001 | 50 | XC1, WO | C25/30 | HA_FUN_FEB_0,250_xxx
Stahlbetonfertigteilfundament | EG_Produktion_FFB | STRIP_FOOTING | Stahlbetonfertigteil | FU-STREIFEN2\ | Stahlbetonfertigteilfundament | EG_Produktion_FFB | 0114SFu0000000947 | m² | Stahlbeton | Fertigteil | false | F001 | 50 | XC1, WO | C25/30 | HA_FUN_FEB_0,250_xxx
Stahlbetonfertigteilfundament | EG_Produktion_FFB | STRIP_FOOTING | Stahlbetonfertigteil | FU-STREIFEN2\ | Stahlbetonfertigteilfundament | EG_Produktion_FFB | 0114SFu0000000937 | m² | Stahlbeton | Fertigteil | false | F001 | 50 | XC1, WO | C25/30 | HA_FUN_FEB_0,250_xxx
Stahlbetonfertigteilfundament | EG_Produktion_FFB | STRIP_FOOTING | Stahlbetonfertigteil | FU-STREIFEN2\ | Stahlbetonfertigteilfundament | EG_Produktion_FFB | 0114SFu0000000755 | m² | Stahlbeton | Fertigteil | false | F001 | 50 | XC1, WO | C25/30 | HA_FUN_FEB_0,250_xxx
Stahlbetonfertigteilfundament | EG_Produktion_FFB | STRIP_FOOTING | Stahlbetonfertigteil | FU-STREIFEN2\ | Stahlbetonfertigteilfundament | EG_Produktion_FFB | 0114SFu0000000771 | m² | Stahlbeton | Fertigteil | false | F001 | 50 | XC1, WO | C25/30 | HA_FUN_FEB_0,250_xxx
Stahlbetonfertigteilfundament | EG_Produktion_FFB | STRIP_FOOTING | Stahlbetonfertigteil | FU-STREIFEN2\ | Stahlbetonfertigteilfundament | EG_Produktion_FFB | 0114SFu0000029658 | m² | Stahlbeton | Fertigteil | false | F001 | 50 | XC1, WO | C25/30 | HA_FUN_FEB_0,250_xxx
Stahlbetonfertigteilfundament | EG_Produktion_FFB | STRIP_FOOTING | Stahlbetonfertigteil | FU-STREIFEN2\ | Stahlbetonfertigteilfundament | EG_Produktion_FFB | 0114SFu0000029659 | m² | Stahlbeton | Fertigteil | false | F001 | 50 | XC1, WO | C25/30 | HA_FUN_FEB_0,250_xxx
Stahlbetonfertigteilfundament | EG_Produktion_FFB | STRIP_FOOTING | Stahlbetonfertigteil | FU-STREIFEN2\ | Stahlbetonfertigteilfundament | EG_Produktion_FFB | 0114SFu0000022696 | m² | Stahlbeton | Fertigteil | false | F001 | 50 | XC1, WO | C25/30 | HA_FUN_FEB_0,250_xxx
Stahlbetonfertigteilfundament | EG_Produktion_FFB | STRIP_FOOTING | Stahlbetonfertigteil | FU-STREIFEN2\ | Stahlbetonfertigteilfundament | EG_Produktion_FFB | 0114SFu0000022695 | m² | Stahlbeton | Fertigteil | false | F001 | 50 | XC1, WO | C25/30 | HA_FUN_FEB_0,250_xxx
Stahlbetonfertigteilfundament | EG_Produktion_FFB | STRIP_FOOTING | Stahlbetonfertigteil | FU-STREIFEN2\ | Stahlbetonfertigteilfundament | EG_Produktion_FFB | 0114SFu0000000767 | m² | Stahlbeton | Fertigteil | false | F001 | 50 | XC1, WO | C25/30 | HA_FUN_FEB_0,250_xxx
Stahlbetonfertigteilfundament | EG_Produktion_FFB | STRIP_FOOTING | Stahlbetonfertigteil | FU-STREIFEN2\ | Stahlbetonfertigteilfundament | EG_Produktion_FFB | 0114SFu0000000751 | m² | Stahlbeton | Fertigteil | false | F001 | 50 | XC1, WO | C25/30 | HA_FUN_FEB_0,250_xxx
Stahlbetonfertigteilfundament | EG_Produktion_FFB | STRIP_FOOTING | Stahlbetonfertigteil | FU-STREIFEN2\ | Stahlbetonfertigteilfundament | EG_Produktion_FFB | 0114SFu0000000769 | m² | Stahlbeton | Fertigteil | false | F001 | 50 | XC1, WO | C25/30 | HA_FUN_FEB_0,250_xxx
Stahlbetonfertigteilfundament | EG_Produktion_FFB | STRIP_FOOTING | Stahlbetonfertigteil | FU-STREIFEN2\ | Stahlbetonfertigteilfundament | EG_Produktion_FFB | 0114SFu0000000753 | m² | Stahlbeton | Fertigteil | false | F001 | 50 | XC1, WO | C25/30 | HA_FUN_FEB_0,250_xxx
Stahlbetonfertigteilfundament | EG_Produktion_FFB | STRIP_FOOTING | Stahlbetonfertigteil | FU-STREIFEN2\ | Stahlbetonfertigteilfundament | EG_Produktion_FFB | 0114SFu0000029684 | m² | Stahlbeton | Fertigteil | false | F001 | 50 | XC1, WO | C25/30 | HA_FUN_FEB_0,250_xxx
Stahlbetonfertigteilfundament | EG_Produktion_FFB | STRIP_FOOTING | Stahlbetonfertigteil | FU-STREIFEN2\ | Stahlbetonfertigteilfundament | EG_Produktion_FFB | 0114SFu0000029685 | m² | Stahlbeton | Fertigteil | false | F001 | 50 | XC1, WO | C25/30 | HA_FUN_FEB_0,250_xxx
Stahlbetonfertigteilfundament | EG_Produktion_FFB | STRIP_FOOTING | Stahlbetonfertigteil | FU-STREIFEN2\ | Stahlbetonfertigteilfundament | EG_Produktion_FFB | 0114SFu0000029686 | m² | Stahlbeton | Fertigteil | false | F001 | 50 | XC1, WO | C25/30 | HA_FUN_FEB_0,250_xxx
Stahlbetonfertigteilfundament | EG_Produktion_FFB | STRIP_FOOTING | Stahlbetonfertigteil | FU-STREIFEN2\ | Stahlbetonfertigteilfundament | EG_Produktion_FFB | 0114SFu0000029687 | m² | Stahlbeton | Fertigteil | false | F001 | 50 | XC1, WO | C25/30 | HA_FUN_FEB_0,250_xxx
Stahlbetonfertigteilfundament | EG_Produktion_FFB | STRIP_FOOTING | Stahlbetonfertigteil | FU-STREIFEN2\ | Stahlbetonfertigteilfundament | EG_Produktion_FFB | 0114SFu0000000821 | m² | Stahlbeton | Fertigteil | false | F001 | 50 | XC1, WO | C25/30 | HA_FUN_FEB_0,250_xxx
Stahlbetonfertigteilfundament | EG_Produktion_FFB | STRIP_FOOTING | Stahlbetonfertigteil | FU-STREIFEN2\ | Stahlbetonfertigteilfundament | EG_Produktion_FFB | 0114SFu0000000819 | m² | Stahlbeton | Fertigteil | false | F001 | 50 | XC1, WO | C25/30 | HA_FUN_FEB_0,250_xxx
Stahlbetonfertigteilfundament | EG_Produktion_FFB | STRIP_FOOTING | Stahlbetonfertigteil | FU-STREIFEN2\ | Stahlbetonfertigteilfundament | EG_Produktion_FFB | 0114SFu0000000817 | m² | Stahlbeton | Fertigteil | false | F001 | 50 | XC1, WO | C25/30 | HA_FUN_FEB_0,250_xxx
Stahlbetonfertigteilfundament | EG_Produktion_FFB | STRIP_FOOTING | Stahlbetonfertigteil | FU-STREIFEN2\ | Stahlbetonfertigteilfundament | EG_Produktion_FFB | 0114SFu0000000815 | m² | Stahlbeton | Fertigteil | false | F001 | 50 | XC1, WO | C25/30 | HA_FUN_FEB_0,250_xxx
Stahlbetonfertigteilfundament | EG_Produktion_FFB | STRIP_FOOTING | Stahlbetonfertigteil | FU-STREIFEN2\ | Stahlbetonfertigteilfundament | EG_Produktion_FFB | 0114SFu0000000791 | m² | Stahlbeton | Fertigteil | false | F001 | 50 | XC1, WO | C25/30 | HA_FUN_FEB_0,250_xxx
Stahlbetonfertigteilfundament | EG_Produktion_FFB | STRIP_FOOTING | Stahlbetonfertigteil | FU-STREIFEN2\ | Stahlbetonfertigteilfundament | EG_Produktion_FFB | 0114SFu0000000789 | m² | Stahlbeton | Fertigteil | false | F001 | 50 | XC1, WO | C25/30 | HA_FUN_FEB_0,250_xxx
Stahlbetonfertigteilfundament | EG_Produktion_FFB | STRIP_FOOTING | Stahlbetonfertigteil | FU-STREIFEN2\ | Stahlbetonfertigteilfundament | EG_Produktion_FFB | 0114SFu0000000793 | m² | Stahlbeton | Fertigteil | false | F001 | 50 | XC1, WO | C25/30 | HA_FUN_FEB_0,250_xxx
Stahlbetonfertigteilfundament | EG_Produktion_FFB | STRIP_FOOTING | Stahlbetonfertigteil | FU-STREIFEN2\ | Stahlbetonfertigteilfundament | EG_Produktion_FFB | 0114SFu0000000803 | m² | Stahlbeton | Fertigteil | false | F001 | 50 | XC1, WO | C25/30 | HA_FUN_FEB_0,250_xxx
Stahlbetonfertigteilfundament | EG_Produktion_FFB | STRIP_FOOTING | Stahlbetonfertigteil | FU-STREIFEN2\ | Stahlbetonfertigteilfundament | EG_Produktion_FFB | 0114SFu0000000805 | m² | Stahlbeton | Fertigteil | false | F001 | 50 | XC1, WO | C25/30 | HA_FUN_FEB_0,250_xxx
Stahlbetonfertigteilfundament | EG_Produktion_FFB | STRIP_FOOTING | Stahlbetonfertigteil | FU-STREIFEN2\ | Stahlbetonfertigteilfundament | EG_Produktion_FFB | 0114SFu0000000795 | m² | Stahlbeton | Fertigteil | false | F001 | 50 | XC1, WO | C25/30 | HA_FUN_FEB_0,250_xxx
Stahlbetonfertigteilfundament | EG_Produktion_FFB | STRIP_FOOTING | Stahlbetonfertigteil | FU-STREIFEN2\ | Stahlbetonfertigteilfundament | EG_Produktion_FFB | 0114SFu0000000785 | m² | Stahlbeton | Fertigteil | false | F001 | 50 | XC1, WO | C25/30 | HA_FUN_FEB_0,250_xxx
Stahlbetonfertigteilfundament | EG_Produktion_FFB | STRIP_FOOTING | Stahlbetonfertigteil | FU-STREIFEN2\ | Stahlbetonfertigteilfundament | EG_Produktion_FFB | 0114SFu0000000787 | m² | Stahlbeton | Fertigteil | false | F001 | 50 | XC1, WO | C25/30 | HA_FUN_FEB_0,250_xxx
Stahlbetonfertigteilfundament | EG_Produktion_FFB | STRIP_FOOTING | Stahlbetonfertigteil | FU-STREIFEN2\ | Stahlbetonfertigteilfundament | EG_Produktion_FFB | 0114SFu0000000807 | m² | Stahlbeton | Fertigteil | false | F001 | 50 | XC1, WO | C25/30 | HA_FUN_FEB_0,250_xxx
Stahlbetonfertigteilfundament | EG_Produktion_FFB | STRIP_FOOTING | Stahlbetonfertigteil | FU-STREIFEN2\ | Stahlbetonfertigteilfundament | EG_Produktion_FFB | 0114SFu0000000809 | m² | Stahlbeton | Fertigteil | false | F001 | 50 | XC1, WO | C25/30 | HA_FUN_FEB_0,250_xxx
Stahlbetonfertigteilfundament | EG_Produktion_FFB | STRIP_FOOTING | Stahlbetonfertigteil | FU-STREIFEN2\ | Stahlbetonfertigteilfundament | EG_Produktion_FFB | 0114SFu0000029758 | m² | Stahlbeton | Fertigteil | false | F001 | 50 | XC1, WO | C25/30 | HA_FUN_FEB_0,250_xxx
Stahlbetonfertigteilfundament | EG_Produktion_FFB | STRIP_FOOTING | Stahlbetonfertigteil | FU-STREIFEN2\ | Stahlbetonfertigteilfundament | EG_Produktion_FFB | 0114SFu0000029759 | m² | Stahlbeton | Fertigteil | false | F001 | 50 | XC1, WO | C25/30 | HA_FUN_FEB_0,250_xxx
Stahlbetonfertigteilfundament | EG_Produktion_FFB | STRIP_FOOTING | Stahlbetonfertigteil | FU-STREIFEN2\ | Stahlbetonfertigteilfundament | EG_Produktion_FFB | 0114SFu0000029756 | m² | Stahlbeton | Fertigteil | false | F001 | 50 | XC1, WO | C25/30 | HA_FUN_FEB_0,250_xxx
Stahlbetonfertigteilfundament | EG_Produktion_FFB | STRIP_FOOTING | Stahlbetonfertigteil | FU-STREIFEN2\ | Stahlbetonfertigteilfundament | EG_Produktion_FFB | 0114SFu0000029757 | m² | Stahlbeton | Fertigteil | false | F001 | 50 | XC1, WO | C25/30 | HA_FUN_FEB_0,250_xxx
Stahlbetonfertigteilfundament | EG_Produktion_FFB | STRIP_FOOTING | Stahlbetonfertigteil | FU-STREIFEN2\ | Stahlbetonfertigteilfundament | EG_Produktion_FFB | 0114SFu0000000603 | m² | Stahlbeton | Fertigteil | false | F001 | 50 | XC1, WO | C25/30 | HA_FUN_FEB_0,250_xxx
Stahlbetonfertigteilfundament | EG_Produktion_FFB | STRIP_FOOTING | Stahlbetonfertigteil | FU-STREIFEN2\ | Stahlbetonfertigteilfundament | EG_Produktion_FFB | 0114SFu0000000797 | m² | Stahlbeton | Fertigteil | false | F001 | 50 | XC1, WO | C25/30 | HA_FUN_FEB_0,250_xxx
Stahlbetonfertigteilfundament | EG_Produktion_FFB | STRIP_FOOTING | Stahlbetonfertigteil | FU-STREIFEN2\ | Stahlbetonfertigteilfundament | EG_Produktion_FFB | 0114SFu0000001103 | m² | Stahlbeton | Fertigteil | false | F001 | 50 | XC1, WO | C25/30 | HA_FUN_FEB_0,250_xxx
Stahlbetonfertigteilfundament | EG_Produktion_FFB | STRIP_FOOTING | Stahlbetonfertigteil | FU-STREIFEN2\ | Stahlbetonfertigteilfundament | EG_Produktion_FFB | 0114SFu0000001035 | m² | Stahlbeton | Fertigteil | false | F001 | 50 | XC1, WO | C25/30 | HA_FUN_FEB_0,250_xxx
Stahlbetonfertigteilfundament | EG_Produktion_FFB | STRIP_FOOTING | Stahlbetonfertigteil | FU-STREIFEN2\ | Stahlbetonfertigteilfundament | EG_Produktion_FFB | 0114SFu0000001027 | m² | Stahlbeton | Fertigteil | false | F001 | 50 | XC1, WO | C25/30 | HA_FUN_FEB_0,250_xxx
Stahlbetonfertigteilfundament | EG_Produktion_FFB | STRIP_FOOTING | Stahlbetonfertigteil | FU-STREIFEN2\ | Stahlbetonfertigteilfundament | EG_Produktion_FFB | 0114SFu0000001099 | m² | Stahlbeton | Fertigteil | false | F001 | 50 | XC1, WO | C25/30 | HA_FUN_FEB_0,250_xxx
Stahlbetonfertigteilfundament | EG_Produktion_FFB | STRIP_FOOTING | Stahlbetonfertigteil | FU-STREIFEN2\ | Stahlbetonfertigteilfundament | EG_Produktion_FFB | 0114SFu0000001089 | m² | Stahlbeton | Fertigteil | false | F001 | 50 | XC1, WO | C25/30 | HA_FUN_FEB_0,250_xxx
Stahlbetonfertigteilfundament | EG_Produktion_FFB | STRIP_FOOTING | Stahlbetonfertigteil | FU-STREIFEN2\ | Stahlbetonfertigteilfundament | EG_Produktion_FFB | 0114SFu0000001087 | m² | Stahlbeton | Fertigteil | false | F001 | 50 | XC1, WO | C25/30 | HA_FUN_FEB_0,250_xxx
Stahlbetonfertigteilfundament | EG_Produktion_FFB | STRIP_FOOTING | Stahlbetonfertigteil | FU-STREIFEN2\ | Stahlbetonfertigteilfundament | EG_Produktion_FFB | 0114SFu0000001005 | m² | Stahlbeton | Fertigteil | false | F001 | 50 | XC1, WO | C25/30 | HA_FUN_FEB_0,250_xxx
Stahlbetonfertigteilfundament | EG_Produktion_FFB | STRIP_FOOTING | Stahlbetonfertigteil | FU-STREIFEN2\ | Stahlbetonfertigteilfundament | EG_Produktion_FFB | 0114SFu0000001003 | m² | Stahlbeton | Fertigteil | false | F001 | 50 | XC1, WO | C25/30 | HA_FUN_FEB_0,250_xxx
Stahlbetonfertigteilfundament | EG_Produktion_FFB | STRIP_FOOTING | Stahlbetonfertigteil | FU-STREIFEN2\ | Stahlbetonfertigteilfundament | EG_Produktion_FFB | 0114SFu0000001011 | m² | Stahlbeton | Fertigteil | false | F001 | 50 | XC1, WO | C25/30 | HA_FUN_FEB_0,250_xxx
Stahlbetonfertigteilfundament | EG_Produktion_FFB | STRIP_FOOTING | Stahlbetonfertigteil | FU-STREIFEN2\ | Stahlbetonfertigteilfundament | EG_Produktion_FFB | 0114SFu0000001013 | m² | Stahlbeton | Fertigteil | false | F001 | 50 | XC1, WO | C25/30 | HA_FUN_FEB_0,250_xxx
Stahlbetonfertigteilfundament | EG_Produktion_FFB | STRIP_FOOTING | Stahlbetonfertigteil | FU-STREIFEN2\ | Stahlbetonfertigteilfundament | EG_Produktion_FFB | 0114SFu0000001091 | m² | Stahlbeton | Fertigteil | false | F001 | 50 | XC1, WO | C25/30 | HA_FUN_FEB_0,250_xxx
Stahlbetonfertigteilfundament | EG_Produktion_FFB | STRIP_FOOTING | Stahlbetonfertigteil | FU-STREIFEN2\ | Stahlbetonfertigteilfundament | EG_Produktion_FFB | 0114SFu0000001093 | m² | Stahlbeton | Fertigteil | false | F001 | 50 | XC1, WO | C25/30 | HA_FUN_FEB_0,250_xxx
Stahlbetonfertigteilfundament | EG_Produktion_FFB | STRIP_FOOTING | Stahlbetonfertigteil | FU-STREIFEN2\ | Stahlbetonfertigteilfundament | EG_Produktion_FFB | 0114SFu0000000987 | m² | Stahlbeton | Fertigteil | false | F001 | 50 | XC1, WO | C25/30 | HA_FUN_FEB_0,250_xxx
Stahlbetonfertigteilfundament | EG_Produktion_FFB | STRIP_FOOTING | Stahlbetonfertigteil | FU-STREIFEN2\ | Stahlbetonfertigteilfundament | EG_Produktion_FFB | 0114SFu0000001079 | m² | Stahlbeton | Fertigteil | false | F001 | 50 | XC1, WO | C25/30 | HA_FUN_FEB_0,250_xxx
Stahlbetonfertigteilfundament | EG_Produktion_FFB | STRIP_FOOTING | Stahlbetonfertigteil | FU-STREIFEN2\ | Stahlbetonfertigteilfundament | EG_Produktion_FFB | 0114SFu0000000969 | m² | Stahlbeton | Fertigteil | false | F001 | 50 | XC1, WO | C25/30 | HA_FUN_FEB_0,250_xxx
Stahlbetonfertigteilfundament | EG_Produktion_FFB | STRIP_FOOTING | Stahlbetonfertigteil | FU-STREIFEN2\ | Stahlbetonfertigteilfundament | EG_Produktion_FFB | 0114SFu0000000967 | m² | Stahlbeton | Fertigteil | false | F001 | 50 | XC1, WO | C25/30 | HA_FUN_FEB_0,250_xxx
Stahlbetonfertigteilfundament | EG_Produktion_FFB | STRIP_FOOTING | Stahlbetonfertigteil | FU-STREIFEN2\ | Stahlbetonfertigteilfundament | EG_Produktion_FFB | 0114SFu0000001669 | m² | Stahlbeton | Fertigteil | false | F001 | 50 | XC1, WO | C25/30 | HA_FUN_FEB_0,250_xxx
Stahlbetonfertigteilfundament | EG_Produktion_FFB | STRIP_FOOTING | Stahlbetonfertigteil | FU-STREIFEN2\ | Stahlbetonfertigteilfundament | EG_Produktion_FFB | 0114SFu0000001667 | m² | Stahlbeton | Fertigteil | false | F001 | 50 | XC1, WO | C25/30 | HA_FUN_FEB_0,250_xxx
Stahlbetonfertigteilfundament | EG_Produktion_FFB | STRIP_FOOTING | Stahlbetonfertigteil | FU-STREIFEN2\ | Stahlbetonfertigteilfundament | EG_Produktion_FFB | 0114SFu0000000677 | m² | Stahlbeton | Fertigteil | false | F001 | 50 | XC1, WO | C25/30 | HA_FUN_FEB_0,250_xxx
Stahlbetonfertigteilfundament | EG_Produktion_FFB | STRIP_FOOTING | Stahlbetonfertigteil | FU-STREIFEN2\ | Stahlbetonfertigteilfundament | EG_Produktion_FFB | 0114SFu0000000679 | m² | Stahlbeton | Fertigteil | false | F001 | 50 | XC1, WO | C25/30 | HA_FUN_FEB_0,250_xxx
Stahlbetonfertigteilfundament | EG_Produktion_FFB | STRIP_FOOTING | Stahlbetonfertigteil | FU-STREIFEN2\ | Stahlbetonfertigteilfundament | EG_Produktion_FFB | 0114SFu0000000619 | m² | Stahlbeton | Fertigteil | false | F001 | 50 | XC1, WO | C25/30 | HA_FUN_FEB_0,250_xxx
Stahlbetonfertigteilfundament | EG_Produktion_FFB | STRIP_FOOTING | Stahlbetonfertigteil | FU-STREIFEN2\ | Stahlbetonfertigteilfundament | EG_Produktion_FFB | 0114SFu0000000617 | m² | Stahlbeton | Fertigteil | false | F001 | 50 | XC1, WO | C25/30 | HA_FUN_FEB_0,250_xxx
Stahlbetonfertigteilfundament | EG_Produktion_FFB | STRIP_FOOTING | Stahlbetonfertigteil | FU-STREIFEN2\ | Stahlbetonfertigteilfundament | EG_Produktion_FFB | 0114SFu0000000777 | m² | Stahlbeton | Fertigteil | false | F001 | 50 | XC1, WO | C25/30 | HA_FUN_FEB_0,250_xxx
Stahlbetonfertigteilfundament | EG_Produktion_FFB | STRIP_FOOTING | Stahlbetonfertigteil | FU-STREIFEN2\ | Stahlbetonfertigteilfundament | EG_Produktion_FFB | 0114SFu0000000779 | m² | Stahlbeton | Fertigteil | false | F001 | 50 | XC1, WO | C25/30 | HA_FUN_FEB_0,250_xxx
Stahlbetonfertigteilfundament | EG_Produktion_FFB | STRIP_FOOTING | Stahlbetonfertigteil | FU-STREIFEN2\ | Stahlbetonfertigteilfundament | EG_Produktion_FFB | 0114SFu0000000781 | m² | Stahlbeton | Fertigteil | false | F001 | 50 | XC1, WO | C25/30 | HA_FUN_FEB_0,250_xxx
Stahlbetonfertigteilfundament | EG_Produktion_FFB | STRIP_FOOTING | Stahlbetonfertigteil | FU-STREIFEN2\ | Stahlbetonfertigteilfundament | EG_Produktion_FFB | 0114SFu0000000783 | m² | Stahlbeton | Fertigteil | false | F001 | 50 | XC1, WO | C25/30 | HA_FUN_FEB_0,250_xxx
Stahlbetonfertigteilfundament | EG_Produktion_FFB | STRIP_FOOTING | Stahlbetonfertigteil | FU-STREIFEN2\ | Stahlbetonfertigteilfundament | EG_Produktion_FFB | 0114SFu0000000799 | m² | Stahlbeton | Fertigteil | false | F001 | 50 | XC1, WO | C25/30 | HA_FUN_FEB_0,250_xxx
Stahlbetonfertigteilfundament | EG_Produktion_FFB | STRIP_FOOTING | Stahlbetonfertigteil | FU-STREIFEN2\ | Stahlbetonfertigteilfundament | EG_Produktion_FFB | 0114SFu0000000801 | m² | Stahlbeton | Fertigteil | false | F001 | 50 | XC1, WO | C25/30 | HA_FUN_FEB_0,250_xxx
Stahlbetonfertigteilfundament | EG_Produktion_FFB | STRIP_FOOTING | Stahlbetonfertigteil | FU-STREIFEN2\ | Stahlbetonfertigteilfundament | EG_Produktion_FFB | 0114SFu0000000963 | m² | Stahlbeton | Fertigteil | false | F001 | 50 | XC1, WO | C25/30 | HA_FUN_FEB_0,250_xxx
Stahlbetonfertigteilfundament | EG_Produktion_FFB | STRIP_FOOTING | Stahlbetonfertigteil | FU-STREIFEN2\ | Stahlbetonfertigteilfundament | EG_Produktion_FFB | 0114SFu0000000965 | m² | Stahlbeton | Fertigteil | false | F001 | 50 | XC1, WO | C25/30 | HA_FUN_FEB_0,250_xxx
Stahlbetonfertigteilfundament | EG_Produktion_FFB | STRIP_FOOTING | Stahlbetonfertigteil | FU-STREIFEN2\ | Stahlbetonfertigteilfundament | EG_Produktion_FFB | 0114SFu0000000961 | m² | Stahlbeton | Fertigteil | false | F001 | 50 | XC1, WO | C25/30 | HA_FUN_FEB_0,250_xxx
Stahlbetonfertigteilfundament | EG_Produktion_FFB | STRIP_FOOTING | Stahlbetonfertigteil | FU-STREIFEN2\ | Stahlbetonfertigteilfundament | EG_Produktion_FFB | 0114SFu0000000959 | m² | Stahlbeton | Fertigteil | false | F001 | 50 | XC1, WO | C25/30 | HA_FUN_FEB_0,250_xxx
Stahlbetonfertigteilfundament | EG_Produktion_FFB | STRIP_FOOTING | Stahlbetonfertigteil | FU-STREIFEN2\ | Stahlbetonfertigteilfundament | EG_Produktion_FFB | 0114SFu0000015892 | m² | Stahlbeton | Fertigteil | false | F001 | 50 | XC1, WO | C25/30 | HA_FUN_FEB_0,250_xxx
Stahlbetonfertigteilfundament | EG_Produktion_FFB | STRIP_FOOTING | Stahlbetonfertigteil | FU-STREIFEN2\ | Stahlbetonfertigteilfundament | EG_Produktion_FFB | 0114SFu0000015893 | m² | Stahlbeton | Fertigteil | false | F001 | 50 | XC1, WO | C25/30 | HA_FUN_FEB_0,250_xxx
Stahlbetonfertigteilfundament | EG_Produktion_FFB | STRIP_FOOTING | Stahlbetonfertigteil | FU-STREIFEN2\ | Stahlbetonfertigteilfundament | EG_Produktion_FFB | 0114SFu0000015908 | m² | Stahlbeton | Fertigteil | false | F001 | 50 | XC1, WO | C25/30 | HA_FUN_FEB_0,250_xxx
Stahlbetonfertigteilfundament | EG_Produktion_FFB | STRIP_FOOTING | Stahlbetonfertigteil | FU-STREIFEN2\ | Stahlbetonfertigteilfundament | EG_Produktion_FFB | 0114SFu0000000975 | m² | Stahlbeton | Fertigteil | false | F001 | 50 | XC1, WO | C25/30 | HA_FUN_FEB_0,250_xxx
Stahlbetonfertigteilfundament | EG_Produktion_FFB | STRIP_FOOTING | Stahlbetonfertigteil | FU-STREIFEN2\ | Stahlbetonfertigteilfundament | EG_Produktion_FFB | 0114SFu0000000977 | m² | Stahlbeton | Fertigteil | false | F001 | 50 | XC1, WO | C25/30 | HA_FUN_FEB_0,250_xxx
Stahlbetonfertigteilfundament | EG_Produktion_FFB | STRIP_FOOTING | Stahlbetonfertigteil | FU-STREIFEN2\ | Stahlbetonfertigteilfundament | EG_Produktion_FFB | 0114SFu0000015909 | m² | Stahlbeton | Fertigteil | false | F001 | 50 | XC1, WO | C25/30 | HA_FUN_FEB_0,250_xxx
Stahlbetonfertigteilfundament | EG_Produktion_FFB | STRIP_FOOTING | Stahlbetonfertigteil | FU-STREIFEN2\ | Stahlbetonfertigteilfundament | EG_Produktion_FFB | 0114SFu0000000729 | m² | Stahlbeton | Fertigteil | false | F001 | 50 | XC1, WO | C25/30 | HA_FUN_FEB_0,250_xxx
Stahlbetonfertigteilfundament | EG_Produktion_FFB | STRIP_FOOTING | Stahlbetonfertigteil | FU-STREIFEN2\ | Stahlbetonfertigteilfundament | EG_Produktion_FFB | 0114SFu0000000731 | m² | Stahlbeton | Fertigteil | false | F001 | 50 | XC1, WO | C25/30 | HA_FUN_FEB_0,250_xxx
Stahlbetonfertigteilfundament | EG_Produktion_FFB | STRIP_FOOTING | Stahlbetonfertigteil | FU-STREIFEN2\ | Stahlbetonfertigteilfundament | EG_Produktion_FFB | 0114SFu0000029784 | m² | Stahlbeton | Fertigteil | false | F001 | 50 | XC1, WO | C25/30 | HA_FUN_FEB_0,250_xxx
Stahlbetonfertigteilfundament | EG_Produktion_FFB | STRIP_FOOTING | Stahlbetonfertigteil | FU-STREIFEN2\ | Stahlbetonfertigteilfundament | EG_Produktion_FFB | 0114SFu0000029785 | m² | Stahlbeton | Fertigteil | false | F001 | 50 | XC1, WO | C25/30 | HA_FUN_FEB_0,250_xxx
Stahlbetonfertigteilfundament | EG_Produktion_FFB | STRIP_FOOTING | Stahlbetonfertigteil | FU-STREIFEN2\ | Stahlbetonfertigteilfundament | EG_Produktion_FFB | 0114SFu0000033546 | m² | Stahlbeton | Fertigteil | false | F001 | 50 | XC1, WO | C25/30 | HA_FUN_FEB_0,250_xxx
Stahlbetonfertigteilfundament | EG_Produktion_FFB | STRIP_FOOTING | Stahlbetonfertigteil | FU-STREIFEN2\ | Stahlbetonfertigteilfundament | EG_Produktion_FFB | 0114SFu0000029847 | m² | Stahlbeton | Fertigteil | false | F001 | 50 | XC1, WO | C25/30 | HA_FUN_FEB_0,250_xxx
Stahlbetonfertigteilfundament | EG_Produktion_FFB | STRIP_FOOTING | Stahlbetonfertigteil | FU-STREIFEN2\ | Stahlbetonfertigteilfundament | EG_Produktion_FFB | 0114SFu0000000721 | m² | Stahlbeton | Fertigteil | false | F001 | 50 | XC1, WO | C25/30 | HA_FUN_FEB_0,250_xxx
Stahlbetonfertigteilfundament | EG_Produktion_FFB | STRIP_FOOTING | Stahlbetonfertigteil | FU-STREIFEN2\ | Stahlbetonfertigteilfundament | EG_Produktion_FFB | 0114SFu0000000697 | m² | Stahlbeton | Fertigteil | false | F001 | 50 | XC1, WO | C25/30 | HA_FUN_FEB_0,250_xxx
Stahlbetonfertigteilfundament | EG_Produktion_FFB | STRIP_FOOTING | Stahlbetonfertigteil | FU-STREIFEN2\ | Stahlbetonfertigteilfundament | EG_Produktion_FFB | 0114SFu0000000701 | m² | Stahlbeton | Fertigteil | false | F001 | 50 | XC1, WO | C25/30 | HA_FUN_FEB_0,250_xxx
Stahlbetonfertigteilfundament | EG_Produktion_FFB | STRIP_FOOTING | Stahlbetonfertigteil | FU-STREIFEN2\ | Stahlbetonfertigteilfundament | EG_Produktion_FFB | 0114SFu0000000705 | m² | Stahlbeton | Fertigteil | false | F001 | 50 | XC1, WO | C25/30 | HA_FUN_FEB_0,250_xxx
Stahlbetonfertigteilfundament | EG_Produktion_FFB | STRIP_FOOTING | Stahlbetonfertigteil | FU-STREIFEN2\ | Stahlbetonfertigteilfundament | EG_Produktion_FFB | 0114SFu0000029862 | m² | Stahlbeton | Fertigteil | false | F001 | 50 | XC1, WO | C25/30 | HA_FUN_FEB_0,250_xxx
Stahlbetonfertigteilfundament | EG_Produktion_FFB | STRIP_FOOTING | Stahlbetonfertigteil | FU-STREIFEN2\ | Stahlbetonfertigteilfundament | EG_Produktion_FFB | 0114SFu0000015853 | m² | Stahlbeton | Fertigteil | false | F001 | 50 | XC1, WO | C25/30 | HA_FUN_FEB_0,250_xxx
Stahlbetonfertigteilfundament | EG_Produktion_FFB | STRIP_FOOTING | Stahlbetonfertigteil | FU-STREIFEN2\ | Stahlbetonfertigteilfundament | EG_Produktion_FFB | 0114SFu0000000713 | m² | Stahlbeton | Fertigteil | false | F001 | 50 | XC1, WO | C25/30 | HA_FUN_FEB_0,250_xxx
Stahlbetonfertigteilfundament | EG_Produktion_FFB | STRIP_FOOTING | Stahlbetonfertigteil | FU-STREIFEN2\ | Stahlbetonfertigteilfundament | EG_Produktion_FFB | 0114SFu0000000707 | m² | Stahlbeton | Fertigteil | false | F001 | 50 | XC1, WO | C25/30 | HA_FUN_FEB_0,250_xxx
Stahlbetonfertigteilfundament | EG_Produktion_FFB | STRIP_FOOTING | Stahlbetonfertigteil | FU-STREIFEN2\ | Stahlbetonfertigteilfundament | EG_Produktion_FFB | 0114SFu0000001073 | m² | Stahlbeton | Fertigteil | false | F001 | 50 | XC1, WO | C25/30 | HA_FUN_FEB_0,250_xxx
Stahlbetonfertigteilfundament | EG_Produktion_FFB | STRIP_FOOTING | Stahlbetonfertigteil | FU-STREIFEN2\ | Stahlbetonfertigteilfundament | EG_Produktion_FFB | 0114SFu0000034134 | m² | Stahlbeton | Fertigteil | false | F001 | 50 | XC1, WO | C25/30 | HA_FUN_FEB_0,250_xxx
Stahlbetonfertigteilfundament | EG_Produktion_FFB | STRIP_FOOTING | Stahlbetonfertigteil | FU-STREIFEN2\ | Stahlbetonfertigteilfundament | EG_Produktion_FFB | 0114SFu0000001061 | m² | Stahlbeton | Fertigteil | false | F001 | 50 | XC1, WO | C25/30 | HA_FUN_FEB_0,250_xxx
Stahlbetonfertigteilfundament | EG_Produktion_FFB | STRIP_FOOTING | Stahlbetonfertigteil | FU-STREIFEN2\ | Stahlbetonfertigteilfundament | EG_Produktion_FFB | 0114SFu0000028150 | m² | Stahlbeton | Fertigteil | false | F001 | 50 | XC1, WO | C25/30 | HA_FUN_FEB_0,250_xxx
Stahlbetonfertigteilfundament | EG_Produktion_FFB | STRIP_FOOTING | Stahlbetonfertigteil | FU-STREIFEN2\ | Stahlbetonfertigteilfundament | EG_Produktion_FFB | 0114SFu0000000921 | m² | Stahlbeton | Fertigteil | false | F001 | 50 | XC1, WO | C25/30 | HA_FUN_FEB_0,250_xxx
Stahlbetonfertigteilfundament | EG_Produktion_FFB | STRIP_FOOTING | Stahlbetonfertigteil | FU-STREIFEN2\ | Stahlbetonfertigteilfundament | EG_Produktion_FFB | 0114SFu0000000919 | m² | Stahlbeton | Fertigteil | false | F001 | 50 | XC1, WO | C25/30 | HA_FUN_FEB_0,250_xxx
Stahlbetonfertigteilfundament | EG_Produktion_FFB | STRIP_FOOTING | Stahlbetonfertigteil | FU-STREIFEN2\ | Stahlbetonfertigteilfundament | EG_Produktion_FFB | 0114SFu0000000927 | m² | Stahlbeton | Fertigteil | false | F001 | 50 | XC1, WO | C25/30 | HA_FUN_FEB_0,250_xxx
Stahlbetonfertigteilfundament | EG_Produktion_FFB | STRIP_FOOTING | Stahlbetonfertigteil | FU-STREIFEN2\ | Stahlbetonfertigteilfundament | EG_Produktion_FFB | 0114SFu0000000929 | m² | Stahlbeton | Fertigteil | false | F001 | 50 | XC1, WO | C25/30 | HA_FUN_FEB_0,250_xxx
Stahlbetonfertigteilfundament | EG_Produktion_FFB | STRIP_FOOTING | Stahlbetonfertigteil | FU-STREIFEN2\ | Stahlbetonfertigteilfundament | EG_Produktion_FFB | 0114SFu0000029846 | m² | Stahlbeton | Fertigteil | false | F001 | 50 | XC1, WO | C25/30 | HA_FUN_FEB_0,250_xxx
Stahlbetonfertigteilfundament | EG_Produktion_FFB | STRIP_FOOTING | Stahlbetonfertigteil | FU-STREIFEN2\ | Stahlbetonfertigteilfundament | EG_Produktion_FFB | 0114SFu0000000723 | m² | Stahlbeton | Fertigteil | false | F001 | 50 | XC1, WO | C25/30 | HA_FUN_FEB_0,250_xxx
Stahlbetonfertigteilfundament | EG_Produktion_FFB | STRIP_FOOTING | Stahlbetonfertigteil | FU-STREIFEN2\ | Stahlbetonfertigteilfundament | EG_Produktion_FFB | 0114SFu0000015852 | m² | Stahlbeton | Fertigteil | false | F001 | 50 | XC1, WO | C25/30 | HA_FUN_FEB_0,250_xxx
Stahlbetonfertigteilfundament | EG_Produktion_FFB | STRIP_FOOTING | Stahlbetonfertigteil | FU-STREIFEN2\ | Stahlbetonfertigteilfundament | EG_Produktion_FFB | 0114SFu0000000715 | m² | Stahlbeton | Fertigteil | false | F001 | 50 | XC1, WO | C25/30 | HA_FUN_FEB_0,250_xxx
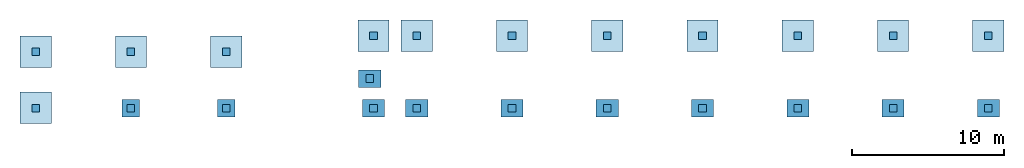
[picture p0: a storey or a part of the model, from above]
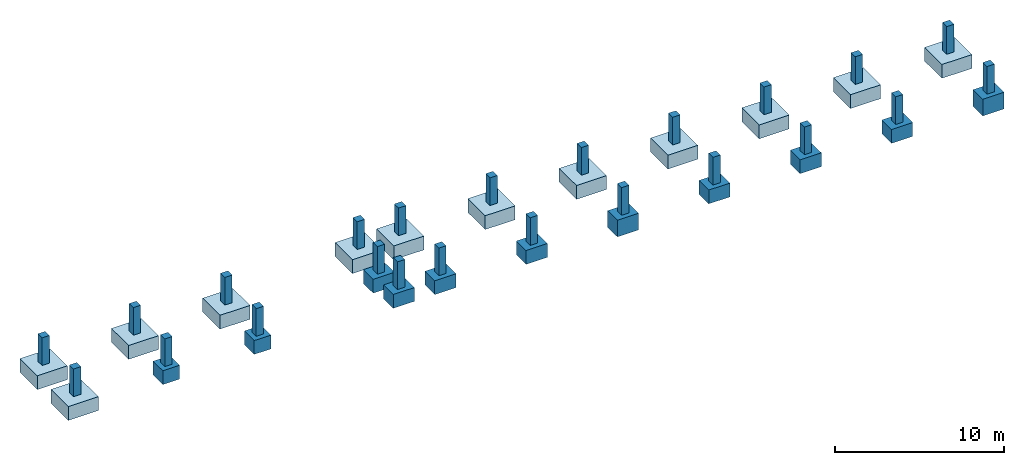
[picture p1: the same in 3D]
Properties of the parts of a building model (IFC2X3), part 15 of 25

# IfcFooting (903)
Name | In | PredefinedType | Material = AllplanAttributes, Material | Codetext | Bezeichnung = Name | Ebene | Allright_Bauteil_ID | Abrechnungsart | IFC_Pset_TWP, Material | Herstellung | Außenbauteil | Positionsnummer | Bewehrungsgrad | Expositionsklasse | Druckfestigkeitsklasse | Reference
Stahlbetonfertigteilfundament | EG_Produktion_FFB | STRIP_FOOTING | Stahlbetonfertigteil | FU-STREIFEN2\ | Stahlbetonfertigteilfundament | EG_Produktion_FFB | 0114SFu0000029863 | m² | Stahlbeton | Fertigteil | false | F001 | 50 | XC1, WO | C25/30 | HA_FUN_FEB_0,250_xxx
Stahlbetonfertigteilfundament | EG_Produktion_FFB | STRIP_FOOTING | Stahlbetonfertigteil | FU-STREIFEN2\ | Stahlbetonfertigteilfundament | EG_Produktion_FFB | 0114SFu0000000699 | m² | Stahlbeton | Fertigteil | false | F001 | 50 | XC1, WO | C25/30 | HA_FUN_FEB_0,250_xxx
Stahlbetonfertigteilfundament | EG_Produktion_FFB | STRIP_FOOTING | Stahlbetonfertigteil | FU-STREIFEN2\ | Stahlbetonfertigteilfundament | EG_Produktion_FFB | 0114SFu0000000703 | m² | Stahlbeton | Fertigteil | false | F001 | 50 | XC1, WO | C25/30 | HA_FUN_FEB_0,250_xxx
Stahlbetonfertigteilfundament | EG_Produktion_FFB | STRIP_FOOTING | Stahlbetonfertigteil | FU-STREIFEN2\ | Stahlbetonfertigteilfundament | EG_Produktion_FFB | 0114SFu0000000673 | m² | Stahlbeton | Fertigteil | false | F001 | 50 | XC1, WO | C25/30 | HA_FUN_FEB_0,250_xxx
Stahlbetonfertigteilfundament | EG_Produktion_FFB | STRIP_FOOTING | Stahlbetonfertigteil | FU-STREIFEN2\ | Stahlbetonfertigteilfundament | EG_Produktion_FFB | 0114SFu0000000675 | m² | Stahlbeton | Fertigteil | false | F001 | 50 | XC1, WO | C25/30 | HA_FUN_FEB_0,250_xxx
Stahlbetonfertigteilfundament | EG_Produktion_FFB | STRIP_FOOTING | Stahlbetonfertigteil | FU-STREIFEN2\ | Stahlbetonfertigteilfundament | EG_Produktion_FFB | 0114SFu0000000607 | m² | Stahlbeton | Fertigteil | false | F001 | 50 | XC1, WO | C25/30 | HA_FUN_FEB_0,250_xxx
Stahlbetonfertigteilfundament | EG_Produktion_FFB | STRIP_FOOTING | Stahlbetonfertigteil | FU-STREIFEN2\ | Stahlbetonfertigteilfundament | EG_Produktion_FFB | 0114SFu0000000605 | m² | Stahlbeton | Fertigteil | false | F001 | 50 | XC1, WO | C25/30 | HA_FUN_FEB_0,250_xxx
Stahlbetonfertigteilfundament | EG_Produktion_FFB | STRIP_FOOTING | Stahlbetonfertigteil | FU-STREIFEN2\ | Stahlbetonfertigteilfundament | EG_Produktion_FFB | 0114SFu0000001801 | m² | Stahlbeton | Fertigteil | false | F001 | 50 | XC1, WO | C25/30 | HA_FUN_FEB_0,250_xxx
Stahlbetonfertigteilfundament | EG_Produktion_FFB | STRIP_FOOTING | Stahlbetonfertigteil | FU-STREIFEN2\ | Stahlbetonfertigteilfundament | EG_Produktion_FFB | 0114SFu0000001799 | m² | Stahlbeton | Fertigteil | false | F001 | 50 | XC1, WO | C25/30 | HA_FUN_FEB_0,250_xxx
Stahlbetonfertigteilfundament | EG_Produktion_FFB | STRIP_FOOTING | Stahlbetonfertigteil | FU-STREIFEN2\ | Stahlbetonfertigteilfundament | EG_Produktion_FFB | 0114SFu0000001475 | m² | Stahlbeton | Fertigteil | false | F001 | 50 | XC1, WO | C25/30 | HA_FUN_FEB_0,250_xxx
Stahlbetonfertigteilfundament | EG_Produktion_FFB | STRIP_FOOTING | Stahlbetonfertigteil | FU-STREIFEN2\ | Stahlbetonfertigteilfundament | EG_Produktion_FFB | 0114SFu0000001481 | m² | Stahlbeton | Fertigteil | false | F001 | 50 | XC1, WO | C25/30 | HA_FUN_FEB_0,250_xxx
Stahlbetonfertigteilfundament | EG_Produktion_FFB | STRIP_FOOTING | Stahlbetonfertigteil | FU-STREIFEN2\ | Stahlbetonfertigteilfundament | EG_Produktion_FFB | 0114SFu0000001477 | m² | Stahlbeton | Fertigteil | false | F001 | 50 | XC1, WO | C25/30 | HA_FUN_FEB_0,250_xxx
Stahlbetonfertigteilfundament | EG_Produktion_FFB | STRIP_FOOTING | Stahlbetonfertigteil | FU-STREIFEN2\ | Stahlbetonfertigteilfundament | EG_Produktion_FFB | 0114SFu0000001479 | m² | Stahlbeton | Fertigteil | false | F001 | 50 | XC1, WO | C25/30 | HA_FUN_FEB_0,250_xxx
Stahlbetonfertigteilfundament | EG_Produktion_FFB | STRIP_FOOTING | Stahlbetonfertigteil | FU-STREIFEN2\ | Stahlbetonfertigteilfundament | EG_Produktion_FFB | 0114SFu0000001299 | m² | Stahlbeton | Fertigteil | false | F001 | 50 | XC1, WO | C25/30 | HA_FUN_FEB_0,250_xxx
Stahlbetonfertigteilfundament | EG_Produktion_FFB | STRIP_FOOTING | Stahlbetonfertigteil | FU-STREIFEN2\ | Stahlbetonfertigteilfundament | EG_Produktion_FFB | 0114SFu0000001301 | m² | Stahlbeton | Fertigteil | false | F001 | 50 | XC1, WO | C25/30 | HA_FUN_FEB_0,250_xxx
Stahlbetonfertigteilfundament | EG_Produktion_FFB | STRIP_FOOTING | Stahlbetonfertigteil | FU-STREIFEN2\ | Stahlbetonfertigteilfundament | EG_Produktion_FFB | 0114SFu0000028149 | m² | Stahlbeton | Fertigteil | false | F001 | 50 | XC1, WO | C25/30 | HA_FUN_FEB_0,250_xxx
Stahlbetonfertigteilfundament | EG_Produktion_FFB | STRIP_FOOTING | Stahlbetonfertigteil | FU-STREIFEN2\ | Stahlbetonfertigteilfundament | EG_Produktion_FFB | 0114SFu0000001355 | m² | Stahlbeton | Fertigteil | false | F001 | 50 | XC1, WO | C25/30 | HA_FUN_FEB_0,250_xxx
Stahlbetonfertigteilfundament | EG_Produktion_FFB | STRIP_FOOTING | Stahlbetonfertigteil | FU-STREIFEN2\ | Stahlbetonfertigteilfundament | EG_Produktion_FFB | 0114SFu0000001357 | m² | Stahlbeton | Fertigteil | false | F001 | 50 | XC1, WO | C25/30 | HA_FUN_FEB_0,250_xxx
Stahlbetonfertigteilfundament | EG_Produktion_FFB | STRIP_FOOTING | Stahlbetonfertigteil | FU-STREIFEN2\ | Stahlbetonfertigteilfundament | EG_Produktion_FFB | 0114SFu0000001331 | m² | Stahlbeton | Fertigteil | false | F001 | 50 | XC1, WO | C25/30 | HA_FUN_FEB_0,250_xxx
Stahlbetonfertigteilfundament | EG_Produktion_FFB | STRIP_FOOTING | Stahlbetonfertigteil | FU-STREIFEN2\ | Stahlbetonfertigteilfundament | EG_Produktion_FFB | 0114SFu0000001333 | m² | Stahlbeton | Fertigteil | false | F001 | 50 | XC1, WO | C25/30 | HA_FUN_FEB_0,250_xxx
Stahlbetonfertigteilfundament | EG_Produktion_FFB | STRIP_FOOTING | Stahlbetonfertigteil | FU-STREIFEN2\ | Stahlbetonfertigteilfundament | EG_Produktion_FFB | 0114SFu0000001309 | m² | Stahlbeton | Fertigteil | false | F001 | 50 | XC1, WO | C25/30 | HA_FUN_FEB_0,250_xxx
Stahlbetonfertigteilfundament | EG_Produktion_FFB | STRIP_FOOTING | Stahlbetonfertigteil | FU-STREIFEN2\ | Stahlbetonfertigteilfundament | EG_Produktion_FFB | 0114SFu0000001319 | m² | Stahlbeton | Fertigteil | false | F001 | 50 | XC1, WO | C25/30 | HA_FUN_FEB_0,250_xxx
Stahlbetonfertigteilfundament | EG_Produktion_FFB | STRIP_FOOTING | Stahlbetonfertigteil | FU-STREIFEN2\ | Stahlbetonfertigteilfundament | EG_Produktion_FFB | 0114SFu0000001285 | m² | Stahlbeton | Fertigteil | false | F001 | 50 | XC1, WO | C25/30 | HA_FUN_FEB_0,250_xxx
Stahlbetonfertigteilfundament | EG_Produktion_FFB | STRIP_FOOTING | Stahlbetonfertigteil | FU-STREIFEN2\ | Stahlbetonfertigteilfundament | EG_Produktion_FFB | 0114SFu0000001283 | m² | Stahlbeton | Fertigteil | false | F001 | 50 | XC1, WO | C25/30 | HA_FUN_FEB_0,250_xxx
Stahlbetonfertigteilfundament | EG_Produktion_FFB | STRIP_FOOTING | Stahlbetonfertigteil | FU-STREIFEN2\ | Stahlbetonfertigteilfundament | EG_Produktion_FFB | 0114SFu0000001279 | m² | Stahlbeton | Fertigteil | false | F001 | 50 | XC1, WO | C25/30 | HA_FUN_FEB_0,250_xxx
Stahlbetonfertigteilfundament | EG_Produktion_FFB | STRIP_FOOTING | Stahlbetonfertigteil | FU-STREIFEN2\ | Stahlbetonfertigteilfundament | EG_Produktion_FFB | 0114SFu0000001281 | m² | Stahlbeton | Fertigteil | false | F001 | 50 | XC1, WO | C25/30 | HA_FUN_FEB_0,250_xxx
Stahlbetonfertigteilfundament | EG_Produktion_FFB | STRIP_FOOTING | Stahlbetonfertigteil | FU-STREIFEN2\ | Stahlbetonfertigteilfundament | EG_Produktion_FFB | 0114SFu0000036335 | m² | Stahlbeton | Fertigteil | false | F001 | 50 | XC1, WO | C25/30 | HA_FUN_FEB_0,250_xxx
Stahlbetonfertigteilfundament | EG_Produktion_FFB | STRIP_FOOTING | Stahlbetonfertigteil | FU-STREIFEN2\ | Stahlbetonfertigteilfundament | EG_Produktion_FFB | 0114SFu0000036336 | m² | Stahlbeton | Fertigteil | false | F001 | 50 | XC1, WO | C25/30 | HA_FUN_FEB_0,250_xxx
Stahlbetonfertigteilfundament | EG_Produktion_FFB | STRIP_FOOTING | Stahlbetonfertigteil | FU-STREIFEN2\ | Stahlbetonfertigteilfundament | EG_Produktion_FFB | 0114SFu0000001275 | m² | Stahlbeton | Fertigteil | false | F002 | 50 | XC1, WO | C25/30 | HA_FUN_FEB_0,250_xxx
Stahlbetonfertigteilfundament | EG_Produktion_FFB | STRIP_FOOTING | Stahlbetonfertigteil | FU-STREIFEN2\ | Stahlbetonfertigteilfundament | EG_Produktion_FFB | 0114SFu0000001277 | m² | Stahlbeton | Fertigteil | false | F002 | 50 | XC1, WO | C25/30 | HA_FUN_FEB_0,250_xxx
Stahlbetonfertigteilfundament | EG_Produktion_FFB | STRIP_FOOTING | Stahlbetonfertigteil | FU-STREIFEN2\ | Stahlbetonfertigteilfundament | EG_Produktion_FFB | 0114SFu0000001273 | m² | Stahlbeton | Fertigteil | false | F002 | 50 | XC1, WO | C25/30 | HA_FUN_FEB_0,250_xxx
Stahlbetonfertigteilfundament | EG_Produktion_FFB | STRIP_FOOTING | Stahlbetonfertigteil | FU-STREIFEN2\ | Stahlbetonfertigteilfundament | EG_Produktion_FFB | 0114SFu0000001271 | m² | Stahlbeton | Fertigteil | false | F002 | 50 | XC1, WO | C25/30 | HA_FUN_FEB_0,250_xxx
Stahlbetonfertigteilfundament | EG_Produktion_FFB | STRIP_FOOTING | Stahlbetonfertigteil | FU-STREIFEN2\ | Stahlbetonfertigteilfundament | EG_Produktion_FFB | 0114SFu0000030383 | m² | Stahlbeton | Fertigteil | false | F001 | 50 | XC1, WO | C25/30 | HA_FUN_FEB_0,250_xxx
Stahlbetonfertigteilfundament | EG_Produktion_FFB | STRIP_FOOTING | Stahlbetonfertigteil | FU-STREIFEN2\ | Stahlbetonfertigteilfundament | EG_Produktion_FFB | 0114SFu0000030384 | m² | Stahlbeton | Fertigteil | false | F001 | 50 | XC1, WO | C25/30 | HA_FUN_FEB_0,250_xxx
Stahlbetonfertigteilfundament | EG_Produktion_FFB | STRIP_FOOTING | Stahlbetonfertigteil | FU-STREIFEN2\ | Stahlbetonfertigteilfundament | EG_Produktion_FFB | 0114SFu0000001269 | m² | Stahlbeton | Fertigteil | false | F001 | 50 | XC1, WO | C25/30 | HA_FUN_FEB_0,250_xxx
Stahlbetonfertigteilfundament | EG_Produktion_FFB | STRIP_FOOTING | Stahlbetonfertigteil | FU-STREIFEN2\ | Stahlbetonfertigteilfundament | EG_Produktion_FFB | 0114SFu0000001267 | m² | Stahlbeton | Fertigteil | false | F001 | 50 | XC1, WO | C25/30 | HA_FUN_FEB_0,250_xxx
Stahlbetonfertigteilfundament | EG_Produktion_FFB | STRIP_FOOTING | Stahlbetonfertigteil | FU-STREIFEN2\ | Stahlbetonfertigteilfundament | EG_Produktion_FFB | 0114SFu0000001265 | m² | Stahlbeton | Fertigteil | false | F001 | 50 | XC1, WO | C25/30 | HA_FUN_FEB_0,250_xxx
Stahlbetonfertigteilfundament | EG_Produktion_FFB | STRIP_FOOTING | Stahlbetonfertigteil | FU-STREIFEN2\ | Stahlbetonfertigteilfundament | EG_Produktion_FFB | 0114SFu0000001263 | m² | Stahlbeton | Fertigteil | false | F001 | 50 | XC1, WO | C25/30 | HA_FUN_FEB_0,250_xxx
Stahlbetonfertigteilfundament | EG_Produktion_FFB | STRIP_FOOTING | Stahlbetonfertigteil | FU-STREIFEN2\ | Stahlbetonfertigteilfundament | EG_Produktion_FFB | 0114SFu0000001261 | m² | Stahlbeton | Fertigteil | false | F001 | 50 | XC1, WO | C25/30 | HA_FUN_FEB_0,250_xxx
Stahlbetonfertigteilfundament | EG_Produktion_FFB | STRIP_FOOTING | Stahlbetonfertigteil | FU-STREIFEN2\ | Stahlbetonfertigteilfundament | EG_Produktion_FFB | 0114SFu0000001259 | m² | Stahlbeton | Fertigteil | false | F001 | 50 | XC1, WO | C25/30 | HA_FUN_FEB_0,250_xxx
Stahlbetonfertigteilfundament | EG_Produktion_FFB | STRIP_FOOTING | Stahlbetonfertigteil | FU-STREIFEN2\ | Stahlbetonfertigteilfundament | EG_Produktion_FFB | 0114SFu0000001257 | m² | Stahlbeton | Fertigteil | false | F001 | 50 | XC1, WO | C25/30 | HA_FUN_FEB_0,250_xxx
Stahlbetonfertigteilfundament | EG_Produktion_FFB | STRIP_FOOTING | Stahlbetonfertigteil | FU-STREIFEN2\ | Stahlbetonfertigteilfundament | EG_Produktion_FFB | 0114SFu0000001253 | m² | Stahlbeton | Fertigteil | false | F001 | 50 | XC1, WO | C25/30 | HA_FUN_FEB_0,250_xxx
Stahlbetonfertigteilfundament | EG_Produktion_FFB | STRIP_FOOTING | Stahlbetonfertigteil | FU-STREIFEN2\ | Stahlbetonfertigteilfundament | EG_Produktion_FFB | 0114SFu0000001249 | m² | Stahlbeton | Fertigteil | false | F001 | 50 | XC1, WO | C25/30 | HA_FUN_FEB_0,250_xxx
Stahlbetonfertigteilfundament | EG_Produktion_FFB | STRIP_FOOTING | Stahlbetonfertigteil | FU-STREIFEN2\ | Stahlbetonfertigteilfundament | EG_Produktion_FFB | 0114SFu0000001247 | m² | Stahlbeton | Fertigteil | false | F001 | 50 | XC1, WO | C25/30 | HA_FUN_FEB_0,250_xxx
Stahlbetonfertigteilfundament | EG_Produktion_FFB | STRIP_FOOTING | Stahlbetonfertigteil | FU-STREIFEN2\ | Stahlbetonfertigteilfundament | EG_Produktion_FFB | 0114SFu0000001251 | m² | Stahlbeton | Fertigteil | false | F001 | 50 | XC1, WO | C25/30 | HA_FUN_FEB_0,250_xxx
Stahlbetonfertigteilfundament | EG_Produktion_FFB | STRIP_FOOTING | Stahlbetonfertigteil | FU-STREIFEN2\ | Stahlbetonfertigteilfundament | EG_Produktion_FFB | 0114SFu0000001255 | m² | Stahlbeton | Fertigteil | false | F001 | 50 | XC1, WO | C25/30 | HA_FUN_FEB_0,250_xxx
Stahlbetonfertigteilfundament | EG_Produktion_FFB | STRIP_FOOTING | Stahlbetonfertigteil | FU-STREIFEN2\ | Stahlbetonfertigteilfundament | EG_Produktion_FFB | 0114SFu0000001289 | m² | Stahlbeton | Fertigteil | false | F002 | 50 | XC1, WO | C25/30 | HA_FUN_FEB_0,250_xxx
Stahlbetonfertigteilfundament | EG_Produktion_FFB | STRIP_FOOTING | Stahlbetonfertigteil | FU-STREIFEN2\ | Stahlbetonfertigteilfundament | EG_Produktion_FFB | 0114SFu0000001287 | m² | Stahlbeton | Fertigteil | false | F002 | 50 | XC1, WO | C25/30 | HA_FUN_FEB_0,250_xxx
Stahlbetonfertigteilfundament | EG_Produktion_FFB | STRIP_FOOTING | Stahlbetonfertigteil | FU-STREIFEN2\ | Stahlbetonfertigteilfundament | EG_Produktion_FFB | 0114SFu0000036351 | m² | Stahlbeton | Fertigteil | false | F001 | 50 | XC1, WO | C25/30 | HA_FUN_FEB_0,250_xxx
Stahlbetonfertigteilfundament | EG_Produktion_FFB | STRIP_FOOTING | Stahlbetonfertigteil | FU-STREIFEN2\ | Stahlbetonfertigteilfundament | EG_Produktion_FFB | 0114SFu0000036352 | m² | Stahlbeton | Fertigteil | false | F001 | 50 | XC1, WO | C25/30 | HA_FUN_FEB_0,250_xxx
Stahlbetonfertigteilfundament | EG_Produktion_FFB | STRIP_FOOTING | Stahlbetonfertigteil | FU-STREIFEN2\ | Stahlbetonfertigteilfundament | EG_Produktion_FFB | 0114SFu0000036447 | m² | Stahlbeton | Fertigteil | false | F002 | 50 | XC1, WO | C25/30 | HA_FUN_FEB_0,250_xxx
Stahlbetonfertigteilfundament | EG_Produktion_FFB | STRIP_FOOTING | Stahlbetonfertigteil | FU-STREIFEN2\ | Stahlbetonfertigteilfundament | EG_Produktion_FFB | 0114SFu0000036446 | m² | Stahlbeton | Fertigteil | false | F002 | 50 | XC1, WO | C25/30 | HA_FUN_FEB_0,250_xxx
Stahlbetonfertigteilfundament | EG_Produktion_FFB | STRIP_FOOTING | Stahlbetonfertigteil | FU-STREIFEN2\ | Stahlbetonfertigteilfundament | EG_Produktion_FFB | 0114SFu0000036448 | m² | Stahlbeton | Fertigteil | false | F002 | 50 | XC1, WO | C25/30 | HA_FUN_FEB_0,250_xxx
Stahlbetonfertigteilfundament | EG_Produktion_FFB | STRIP_FOOTING | Stahlbetonfertigteil | FU-STREIFEN2\ | Stahlbetonfertigteilfundament | EG_Produktion_FFB | 0114SFu0000036449 | m² | Stahlbeton | Fertigteil | false | F002 | 50 | XC1, WO | C25/30 | HA_FUN_FEB_0,250_xxx
Stahlbetonfertigteilfundament | EG_Produktion_FFB | STRIP_FOOTING | Stahlbetonfertigteil | FU-STREIFEN2\ | Stahlbetonfertigteilfundament | EG_Produktion_FFB | 0114SFu0000001045 | m² | Stahlbeton | Fertigteil | false | F001 | 50 | XC1, WO | C25/30 | HA_FUN_FEB_0,250_xxx
Stahlbetonfertigteilfundament | EG_Produktion_FFB | STRIP_FOOTING | Stahlbetonfertigteil | FU-STREIFEN2\ | Stahlbetonfertigteilfundament | EG_Produktion_FFB | 0114SFu0000001107 | m² | Stahlbeton | Fertigteil | false | F001 | 50 | XC1, WO | C25/30 | HA_FUN_FEB_0,250_xxx
Stahlbetonfertigteilfundament | EG_Produktion_FFB | STRIP_FOOTING | Stahlbetonfertigteil | FU-STREIFEN2\ | Stahlbetonfertigteilfundament | EG_Produktion_FFB | 0114SFu0000001109 | m² | Stahlbeton | Fertigteil | false | F001 | 50 | XC1, WO | C25/30 | HA_FUN_FEB_0,250_xxx
Stahlbetonfertigteilfundament | EG_Produktion_FFB | STRIP_FOOTING | Stahlbetonfertigteil | FU-STREIFEN2\ | Stahlbetonfertigteilfundament | EG_Produktion_FFB | 0114SFu0000001473 | m² | Stahlbeton | Fertigteil | false | F001 | 50 | XC1, WO | C25/30 | HA_FUN_FEB_0,250_xxx
Stahlbetonfertigteilfundament | EG_Produktion_FFB | STRIP_FOOTING | Stahlbetonfertigteil | FU-STREIFEN2\ | Stahlbetonfertigteilfundament | EG_Produktion_FFB | 0114SFu0000113350 | m² | Stahlbeton | Fertigteil | false | F001 | 50 | XC1, WO | C25/30 | HA_FUN_FEB_0,250_xxx
Stahlbetonfertigteilfundament | EG_Produktion_FFB | STRIP_FOOTING | Stahlbetonfertigteil | FU-STREIFEN2\ | Stahlbetonfertigteilfundament | EG_Produktion_FFB | 0114SFu0000001471 | m² | Stahlbeton | Fertigteil | false | F001 | 50 | XC1, WO | C25/30 | HA_FUN_FEB_0,250_xxx
Stahlbetonfertigteilfundament | EG_Produktion_FFB | STRIP_FOOTING | Stahlbetonfertigteil | FU-STREIFEN2\ | Stahlbetonfertigteilfundament | EG_Produktion_FFB | 0114SFu0000001559 | m² | Stahlbeton | Fertigteil | false | F001 | 50 | XC1, WO | C25/30 | HA_FUN_FEB_0,250_xxx
Stahlbetonfertigteilfundament | EG_Produktion_FFB | STRIP_FOOTING | Stahlbetonfertigteil | FU-STREIFEN2\ | Stahlbetonfertigteilfundament | EG_Produktion_FFB | 0114SFu0000001039 | m² | Stahlbeton | Fertigteil | false | F001 | 50 | XC1, WO | C25/30 | HA_FUN_FEB_0,250_xxx
Stahlbetonfertigteilfundament | EG_Produktion_FFB | STRIP_FOOTING | Stahlbetonfertigteil | FU-STREIFEN2\ | Stahlbetonfertigteilfundament | EG_Produktion_FFB | 0114SFu0000026985 | m² | Stahlbeton | Fertigteil | false | F001 | 50 | XC1, WO | C25/30 | HA_FUN_FEB_0,250_xxx
Stahlbetonfertigteilfundament | EG_Produktion_FFB | STRIP_FOOTING | Stahlbetonfertigteil | FU-STREIFEN2\ | Stahlbetonfertigteilfundament | EG_Produktion_FFB | 0114SFu0000026986 | m² | Stahlbeton | Fertigteil | false | F001 | 50 | XC1, WO | C25/30 | HA_FUN_FEB_0,250_xxx
Stahlbetonfertigteilfundament | EG_Produktion_FFB | STRIP_FOOTING | Stahlbetonfertigteil | FU-STREIFEN2\ | Stahlbetonfertigteilfundament | EG_Produktion_FFB | 0114SFu0000001539 | m² | Stahlbeton | Fertigteil | false | F001 | 50 | XC1, WO | C25/30 | HA_FUN_FEB_0,250_xxx
Stahlbetonfertigteilfundament | EG_Produktion_FFB | STRIP_FOOTING | Stahlbetonfertigteil | FU-STREIFEN2\ | Stahlbetonfertigteilfundament | EG_Produktion_FFB | 0114SFu0000001541 | m² | Stahlbeton | Fertigteil | false | F001 | 50 | XC1, WO | C25/30 | HA_FUN_FEB_0,250_xxx
Stahlbetonfertigteilfundament | EG_Produktion_FFB | STRIP_FOOTING | Stahlbetonfertigteil | FU-STREIFEN2\ | Stahlbetonfertigteilfundament | EG_Produktion_FFB | 0114SFu0000001661 | m² | Stahlbeton | Fertigteil | false | F002 | 50 | XC1, WO | C25/30 | HA_FUN_FEB_0,250_xxx
Stahlbetonfertigteilfundament | EG_Produktion_FFB | STRIP_FOOTING | Stahlbetonfertigteil | FU-STREIFEN2\ | Stahlbetonfertigteilfundament | EG_Produktion_FFB | 0114SFu0000001663 | m² | Stahlbeton | Fertigteil | false | F002 | 50 | XC1, WO | C25/30 | HA_FUN_FEB_0,250_xxx
Stb.-Streifenfundament | EG_Produktion_FFB | STRIP_FOOTING | Stahlbeton | FU-STREIFEN2\ | Stb.-Streifenfundament | EG_Produktion_FFB | 0114SFu0000026200 | m² | Stahlbeton | Ortbeton | true | F006 | 50 | XC2, WF | C25/30 | HA_FUN_STB_0,500x1,000_xxx
Stb.-Streifenfundament | EG_Produktion_FFB | STRIP_FOOTING | Stahlbeton | FU-STREIFEN2\ | Stb.-Streifenfundament | EG_Produktion_FFB | 0114SFu0000026199 | m² | Stahlbeton | Ortbeton | true | F006 | 50 | XC2, WF | C25/30 | HA_FUN_STB_0,500x1,000_xxx
Stb.-Streifenfundament | EG_Produktion_FFB | STRIP_FOOTING | Stahlbeton | FU-STREIFEN2\ | Stb.-Streifenfundament | EG_Produktion_FFB | 0114SFu0000026173 | m² | Stahlbeton | Ortbeton | true | F006 | 50 | XC2, WF | C25/30 | HA_FUN_STB_0,500x1,000_xxx
Stahlbetonfertigteilfundament | EG_Produktion_FFB | STRIP_FOOTING | Stahlbetonfertigteil | FU-STREIFEN2\ | Stahlbetonfertigteilfundament | EG_Produktion_FFB | 0114SFu0000113394 | m² | Stahlbeton | Fertigteil | false | F001 | 50 | XC1, WO | C25/30 | HA_FUN_FEB_0,250_xxx
Stahlbetonfertigteilfundament | EG_Produktion_FFB | STRIP_FOOTING | Stahlbetonfertigteil | FU-STREIFEN2\ | Stahlbetonfertigteilfundament | EG_Produktion_FFB | 0114SFu0000001041 | m² | Stahlbeton | Fertigteil | false | F001 | 50 | XC1, WO | C25/30 | HA_FUN_FEB_0,250_xxx
Stahlbetonfertigteilfundament | EG_Produktion_FFB | STRIP_FOOTING | Stahlbetonfertigteil | FU-STREIFEN2\ | Stahlbetonfertigteilfundament | EG_Produktion_FFB | 0114SFu0000001043 | m² | Stahlbeton | Fertigteil | false | F001 | 50 | XC1, WO | C25/30 | HA_FUN_FEB_0,250_xxx
Stahlbetonfertigteilfundament | EG_Produktion_FFB | STRIP_FOOTING | Stahlbetonfertigteil | FU-STREIFEN2\ | Stahlbetonfertigteilfundament | EG_Produktion_FFB | 0114SFu0000001231 | m² | Stahlbeton | Fertigteil | false | F001 | 50 | XC1, WO | C25/30 | HA_FUN_FEB_0,250_xxx
Stahlbetonfertigteilfundament | EG_Produktion_FFB | STRIP_FOOTING | Stahlbetonfertigteil | FU-STREIFEN2\ | Stahlbetonfertigteilfundament | EG_Produktion_FFB | 0114SFu0000001233 | m² | Stahlbeton | Fertigteil | false | F001 | 50 | XC1, WO | C25/30 | HA_FUN_FEB_0,250_xxx
Stb.-Streifenfundament | EG_Produktion_FFB | STRIP_FOOTING | Stahlbeton | FU-STREIFEN2\ | Stb.-Streifenfundament | EG_Produktion_FFB | 0114SFu0000025884 | m² | Stahlbeton | Ortbeton | true | F006 | 50 | XC2, WF | C25/30 | HA_FUN_STB_0,500x1,000_xxx
Stb.-Streifenfundament | EG_Produktion_FFB | STRIP_FOOTING | Stahlbeton | FU-STREIFEN2\ | Stb.-Streifenfundament | EG_Produktion_FFB | 0114SFu0000025883 | m² | Stahlbeton | Ortbeton | true | F006 | 50 | XC2, WF | C25/30 | HA_FUN_STB_0,500x1,000_xxx
Stb.-Streifenfundament | EG_Produktion_FFB | STRIP_FOOTING | Stahlbeton | FU-STREIFEN2\ | Stb.-Streifenfundament | EG_Produktion_FFB | 0114SFu0000026159 | m² | Stahlbeton | Ortbeton | true | F006 | 50 | XC2, WF | C25/30 | HA_FUN_STB_0,500x1,000_xxx
Stb.-Streifenfundament | EG_Produktion_FFB | STRIP_FOOTING | Stahlbeton | FU-STREIFEN2\ | Stb.-Streifenfundament | EG_Produktion_FFB | 0114SFu0000026158 | m² | Stahlbeton | Ortbeton | true | F006 | 50 | XC2, WF | C25/30 | HA_FUN_STB_0,500x1,000_xxx
Stb.-Streifenfundament | EG_Produktion_FFB | STRIP_FOOTING | Stahlbeton | FU-STREIFEN2\ | Stb.-Streifenfundament | EG_Produktion_FFB | 0114SFu0000026213 | m² | Stahlbeton | Ortbeton | true | F006 | 50 | XC2, WF | C25/30 | HA_FUN_STB_0,500x1,000_xxx
Stb.-Streifenfundament | EG_Produktion_FFB | STRIP_FOOTING | Stahlbeton | FU-STREIFEN2\ | Stb.-Streifenfundament | EG_Produktion_FFB | 0114SFu0000026214 | m² | Stahlbeton | Ortbeton | true | F006 | 50 | XC2, WF | C25/30 | HA_FUN_STB_0,500x1,000_xxx
Stb.-Streifenfundament | EG_Produktion_FFB | STRIP_FOOTING | Stahlbeton | FU-STREIFEN2\ | Stb.-Streifenfundament | EG_Produktion_FFB | 0114SFu0000026172 | m² | Stahlbeton | Ortbeton | true | F006 | 50 | XC2, WF | C25/30 | HA_FUN_STB_0,500x1,000_xxx
Stb.-Streifenfundament | EG_Produktion_FFB | STRIP_FOOTING | Stahlbeton | FU-STREIFEN2\ | Stb.-Streifenfundament | EG_Produktion_FFB | 0114SFu0000031002 | m² | Stahlbeton | Ortbeton | true | F005 | 50 | XC2, WF | C25/30 | HA_FUN_STB_0,500x0,717_xxx
Stb.-Streifenfundament | EG_Produktion_FFB | STRIP_FOOTING | Stahlbeton | FU-STREIFEN2\ | Stb.-Streifenfundament | EG_Produktion_FFB | 0114SFu0000025094 | m² | Stahlbeton | Ortbeton | true | F005 | 50 | XC2, WF | C25/30 | HA_FUN_STB_0,500x0,717_xxx
Stb.-Streifenfundament | EG_Produktion_FFB | STRIP_FOOTING | Stahlbeton | FU-STREIFEN2\ | Stb.-Streifenfundament | EG_Produktion_FFB | 0114SFu0000025373 | m² | Stahlbeton | Ortbeton | true | F006 | 50 | XC2, WF | C25/30 | HA_FUN_STB_0,500x1,000_xxx
Stb.-Streifenfundament | EG_Produktion_FFB | STRIP_FOOTING | Stahlbeton | FU-STREIFEN2\ | Stb.-Streifenfundament | EG_Produktion_FFB | 0114SFu0000025377 | m² | Stahlbeton | Ortbeton | true | F006 | 50 | XC2, WF | C25/30 | HA_FUN_STB_0,500x1,000_xxx
Stahlbetonfertigteilfundament | EG_Produktion_FFB | STRIP_FOOTING | Stahlbetonfertigteil | FU-STREIFEN2\ | Stahlbetonfertigteilfundament | EG_Produktion_FFB | 0114SFu0000001561 | m² | Stahlbeton | Fertigteil | false | F001 | 50 | XC1, WO | C25/30 | HA_FUN_FEB_0,250_xxx
Stb.-Streifenfundament | EG_Produktion_FFB | STRIP_FOOTING | Stahlbeton | FU-STREIFEN2\ | Stb.-Streifenfundament | EG_Produktion_FFB | 0114SFu0000025488 | m² | Stahlbeton | Ortbeton | true | F006 | 50 | XC2, WF | C25/30 | HA_FUN_STB_0,500x1,000_xxx
Stb.-Streifenfundament | EG_Produktion_FFB | STRIP_FOOTING | Stahlbeton | FU-STREIFEN2\ | Stb.-Streifenfundament | EG_Produktion_FFB | 0114SFu0000025400 | m² | Stahlbeton | Ortbeton | true | F006 | 50 | XC2, WF | C25/30 | HA_FUN_STB_0,500x1,000_xxx
Stb.-Streifenfundament | EG_Produktion_FFB | STRIP_FOOTING | Stahlbeton | FU-STREIFEN2\ | Stb.-Streifenfundament | EG_Produktion_FFB | 0114SFu0000025420 | m² | Stahlbeton | Ortbeton | true | F006 | 50 | XC2, WF | C25/30 | HA_FUN_STB_0,500x1,000_xxx
Stb.-Streifenfundament | EG_Produktion_FFB | STRIP_FOOTING | Stahlbeton | FU-STREIFEN2\ | Stb.-Streifenfundament | EG_Produktion_FFB | 0114SFu0000025401 | m² | Stahlbeton | Ortbeton | true | F006 | 50 | XC2, WF | C25/30 | HA_FUN_STB_0,500x1,000_xxx
Stb.-Streifenfundament | EG_Produktion_FFB | STRIP_FOOTING | Stahlbeton | FU-STREIFEN2\ | Stb.-Streifenfundament | EG_Produktion_FFB | 0114SFu0000025455 | m² | Stahlbeton | Ortbeton | true | F006 | 50 | XC2, WF | C25/30 | HA_FUN_STB_0,500x1,000_xxx
Stb.-Streifenfundament | EG_Produktion_FFB | STRIP_FOOTING | Stahlbeton | FU-STREIFEN2\ | Stb.-Streifenfundament | EG_Produktion_FFB | 0114SFu0000025325 | m² | Stahlbeton | Ortbeton | true | F006 | 50 | XC2, WF | C25/30 | HA_FUN_STB_0,500x1,000_xxx
Stb.-Streifenfundament | EG_Produktion_FFB | STRIP_FOOTING | Stahlbeton | FU-STREIFEN2\ | Stb.-Streifenfundament | EG_Produktion_FFB | 0114SFu0000025542 | m² | Stahlbeton | Ortbeton | true | F006 | 50 | XC2, WF | C25/30 | HA_FUN_STB_0,500x1,000_xxx
Stb.-Streifenfundament | EG_Produktion_FFB | STRIP_FOOTING | Stahlbeton | FU-STREIFEN2\ | Stb.-Streifenfundament | EG_Produktion_FFB | 0114SFu0000025313 | m² | Stahlbeton | Ortbeton | true | F006 | 50 | XC2, WF | C25/30 | HA_FUN_STB_0,500x1,000_xxx
Stb.-Streifenfundament | EG_Produktion_FFB | STRIP_FOOTING | Stahlbeton | FU-STREIFEN2\ | Stb.-Streifenfundament | EG_Produktion_FFB | 0114SFu0000025367 | m² | Stahlbeton | Ortbeton | true | F006 | 50 | XC2, WF | C25/30 | HA_FUN_STB_0,500x1,000_xxx
Stb.-Streifenfundament | EG_Produktion_FFB | STRIP_FOOTING | Stahlbeton | FU-STREIFEN2\ | Stb.-Streifenfundament | EG_Produktion_FFB | 0114SFu0000030982 | m² | Stahlbeton | Ortbeton | true | F005 | 50 | XC2, WF | C25/30 | HA_FUN_STB_0,500x0,717_xxx
Stb.-Streifenfundament | EG_Produktion_FFB | STRIP_FOOTING | Stahlbeton | FU-STREIFEN2\ | Stb.-Streifenfundament | EG_Produktion_FFB | 0114SFu0000025949 | m² | Stahlbeton | Ortbeton | true | F006 | 50 | XC2, WF | C25/30 | HA_FUN_STB_0,500x1,000_xxx
Stb.-Streifenfundament | EG_Produktion_FFB | STRIP_FOOTING | Stahlbeton | FU-STREIFEN2\ | Stb.-Streifenfundament | EG_Produktion_FFB | 0114SFu0000025948 | m² | Stahlbeton | Ortbeton | true | F006 | 50 | XC2, WF | C25/30 | HA_FUN_STB_0,500x1,000_xxx
Stb.-Streifenfundament | EG_Produktion_FFB | STRIP_FOOTING | Stahlbeton | FU-STREIFEN2\ | Stb.-Streifenfundament | EG_Produktion_FFB | 0114SFu0000025976 | m² | Stahlbeton | Ortbeton | true | F006 | 50 | XC2, WF | C25/30 | HA_FUN_STB_0,500x1,000_xxx
Stb.-Streifenfundament | EG_Produktion_FFB | STRIP_FOOTING | Stahlbeton | FU-STREIFEN2\ | Stb.-Streifenfundament | EG_Produktion_FFB | 0114SFu0000025975 | m² | Stahlbeton | Ortbeton | true | F006 | 50 | XC2, WF | C25/30 | HA_FUN_STB_0,500x1,000_xxx
Stahlbetonfertigteilfundament | EG_Produktion_FFB | STRIP_FOOTING | Stahlbetonfertigteil | FU-STREIFEN2\ | Stahlbetonfertigteilfundament | EG_Produktion_FFB | 0114SFu0000001169 | m² | Stahlbeton | Fertigteil | false | F001 | 50 | XC1, WO | C25/30 | HA_FUN_FEB_0,250_xxx
Stahlbetonfertigteilfundament | EG_Produktion_FFB | STRIP_FOOTING | Stahlbetonfertigteil | FU-STREIFEN2\ | Stahlbetonfertigteilfundament | EG_Produktion_FFB | 0114SFu0000001167 | m² | Stahlbeton | Fertigteil | false | F001 | 50 | XC1, WO | C25/30 | HA_FUN_FEB_0,250_xxx
Stb.-Streifenfundament | EG_Produktion_FFB | STRIP_FOOTING | Stahlbeton | FU-STREIFEN2\ | Stb.-Streifenfundament | EG_Produktion_FFB | 0114SFu0000031014 | m² | Stahlbeton | Ortbeton | true | F005 | 50 | XC2, WF | C25/30 | HA_FUN_STB_0,500x1,000_xxx
Stb.-Streifenfundament | EG_Produktion_FFB | STRIP_FOOTING | Stahlbeton | FU-STREIFEN2\ | Stb.-Streifenfundament | EG_Produktion_FFB | 0114SFu0000025036 | m² | Stahlbeton | Ortbeton | true | F005 | 50 | XC2, WF | C25/30 | HA_FUN_STB_0,500x1,000_xxx
Stb.-Streifenfundament | EG_Produktion_FFB | STRIP_FOOTING | Stahlbeton | FU-STREIFEN2\ | Stb.-Streifenfundament | EG_Produktion_FFB | 0114SFu0000026130 | m² | Stahlbeton | Ortbeton | true | F006 | 50 | XC2, WF | C25/30 | HA_FUN_STB_0,500x1,000_xxx
Stb.-Streifenfundament | EG_Produktion_FFB | STRIP_FOOTING | Stahlbeton | FU-STREIFEN2\ | Stb.-Streifenfundament | EG_Produktion_FFB | 0114SFu0000026129 | m² | Stahlbeton | Ortbeton | true | F006 | 50 | XC2, WF | C25/30 | HA_FUN_STB_0,500x1,000_xxx
Stb.-Streifenfundament | EG_Produktion_FFB | STRIP_FOOTING | Stahlbeton | FU-STREIFEN2\ | Stb.-Streifenfundament | EG_Produktion_FFB | 0114SFu0000113521 | m² | Stahlbeton | Ortbeton | true | F006 | 50 | XC2, WF | C25/30 | HA_FUN_STB_0,500x1,000_xxx
Stb.-Streifenfundament | EG_Produktion_FFB | STRIP_FOOTING | Stahlbeton | FU-STREIFEN2\ | Stb.-Streifenfundament | EG_Produktion_FFB | 0114SFu0000025427 | m² | Stahlbeton | Ortbeton | true | F006 | 50 | XC2, WF | C25/30 | HA_FUN_STB_0,500x1,000_xxx
Stb.-Streifenfundament | EG_Produktion_FFB | STRIP_FOOTING | Stahlbeton | FU-STREIFEN2\ | Stb.-Streifenfundament | EG_Produktion_FFB | 0114SFu0000113493 | m² | Stahlbeton | Ortbeton | true | F006 | 50 | XC2, WF | C25/30 | HA_FUN_STB_0,500x1,000_xxx
Stb.-Streifenfundament | EG_Produktion_FFB | STRIP_FOOTING | Stahlbeton | FU-STREIFEN2\ | Stb.-Streifenfundament | EG_Produktion_FFB | 0114SFu0000024876 | m² | Stahlbeton | Ortbeton | true | F005 | 50 | XC2, WF | C25/30 | HA_FUN_STB_0,500x1,000_xxx
Stb.-Streifenfundament | EG_Produktion_FFB | STRIP_FOOTING | Stahlbeton | FU-STREIFEN2\ | Stb.-Streifenfundament | EG_Produktion_FFB | 0114SFu0000113471 | m² | Stahlbeton | Ortbeton | true | F006 | 50 | XC2, WF | C25/30 | HA_FUN_STB_0,500x1,000_xxx
Stahlbetonfertigteilfundament | EG_Produktion_FFB | STRIP_FOOTING | Stahlbetonfertigteil | FU-STREIFEN2\ | Stahlbetonfertigteilfundament | EG_Produktion_FFB | 0114SFu0000031219 | m² | Stahlbeton | Fertigteil | false | F002 | 50 | XC1, WO | C25/30 | HA_FUN_FEB_0,250_xxx
Stahlbetonfertigteilfundament | EG_Produktion_FFB | STRIP_FOOTING | Stahlbetonfertigteil | FU-STREIFEN2\ | Stahlbetonfertigteilfundament | EG_Produktion_FFB | 0114SFu0000031218 | m² | Stahlbeton | Fertigteil | false | F002 | 50 | XC1, WO | C25/30 | HA_FUN_FEB_0,250_xxx
Stahlbetonfertigteilfundament | EG_Produktion_FFB | STRIP_FOOTING | Stahlbetonfertigteil | FU-STREIFEN2\ | Stahlbetonfertigteilfundament | EG_Produktion_FFB | 0114SFu0000001317 | m² | Stahlbeton | Fertigteil | false | F001 | 50 | XC1, WO | C25/30 | HA_FUN_FEB_0,250_xxx
Stahlbetonfertigteilfundament | EG_Produktion_FFB | STRIP_FOOTING | Stahlbetonfertigteil | FU-STREIFEN2\ | Stahlbetonfertigteilfundament | EG_Produktion_FFB | 0114SFu0000001315 | m² | Stahlbeton | Fertigteil | false | F001 | 50 | XC1, WO | C25/30 | HA_FUN_FEB_0,250_xxx
Stahlbetonfertigteilfundament | EG_Produktion_FFB | STRIP_FOOTING | Stahlbetonfertigteil | FU-STREIFEN2\ | Stahlbetonfertigteilfundament | EG_Produktion_FFB | 0114SFu0000001243 | m² | Stahlbeton | Fertigteil | false | F001 | 50 | XC1, WO | C25/30 | HA_FUN_FEB_0,250_xxx
Stahlbetonfertigteilfundament | EG_Produktion_FFB | STRIP_FOOTING | Stahlbetonfertigteil | FU-STREIFEN2\ | Stahlbetonfertigteilfundament | EG_Produktion_FFB | 0114SFu0000001245 | m² | Stahlbeton | Fertigteil | false | F001 | 50 | XC1, WO | C25/30 | HA_FUN_FEB_0,250_xxx
Stahlbetonfertigteilfundament | EG_Produktion_FFB | STRIP_FOOTING | Stahlbetonfertigteil | FU-STREIFEN2\ | Stahlbetonfertigteilfundament | EG_Produktion_FFB | 0114SFu0000001195 | m² | Stahlbeton | Fertigteil | false | F001 | 50 | XC1, WO | C25/30 | HA_FUN_FEB_0,250_xxx
Stahlbetonfertigteilfundament | EG_Produktion_FFB | STRIP_FOOTING | Stahlbetonfertigteil | FU-STREIFEN2\ | Stahlbetonfertigteilfundament | EG_Produktion_FFB | 0114SFu0000001197 | m² | Stahlbeton | Fertigteil | false | F001 | 50 | XC1, WO | C25/30 | HA_FUN_FEB_0,250_xxx
Stahlbetonfertigteilfundament | EG_Produktion_FFB | STRIP_FOOTING | Stahlbetonfertigteil | FU-STREIFEN2\ | Stahlbetonfertigteilfundament | EG_Produktion_FFB | 0114SFu0000031817 | m² | Stahlbeton | Fertigteil | false | F002 | 50 | XC1, WO | C25/30 | HA_FUN_FEB_0,250_xxx
Stahlbetonfertigteilfundament | EG_Produktion_FFB | STRIP_FOOTING | Stahlbetonfertigteil | FU-STREIFEN2\ | Stahlbetonfertigteilfundament | EG_Produktion_FFB | 0114SFu0000031816 | m² | Stahlbeton | Fertigteil | false | F002 | 50 | XC1, WO | C25/30 | HA_FUN_FEB_0,250_xxx
Stahlbetonfertigteilfundament | EG_Produktion_FFB | STRIP_FOOTING | Stahlbetonfertigteil | FU-STREIFEN2\ | Stahlbetonfertigteilfundament | EG_Produktion_FFB | 0114SFu0000031679 | m² | Stahlbeton | Fertigteil | false | F002 | 50 | XC1, WO | C25/30 | HA_FUN_FEB_0,250_xxx
Stahlbetonfertigteilfundament | EG_Produktion_FFB | STRIP_FOOTING | Stahlbetonfertigteil | FU-STREIFEN2\ | Stahlbetonfertigteilfundament | EG_Produktion_FFB | 0114SFu0000031678 | m² | Stahlbeton | Fertigteil | false | F002 | 50 | XC1, WO | C25/30 | HA_FUN_FEB_0,250_xxx
Stb.-Streifenfundament | EG_Produktion_FFB | STRIP_FOOTING | Stahlbeton | FU-STREIFEN2\ | Stb.-Streifenfundament | EG_Produktion_FFB | 0114SFu0000030976 | m² | Stahlbeton | Ortbeton | true | F005 | 50 | XC2, WF | C25/30 | HA_FUN_STB_0,500x0,717_xxx
Stb.-Streifenfundament | EG_Produktion_FFB | STRIP_FOOTING | Stahlbeton | FU-STREIFEN2\ | Stb.-Streifenfundament | EG_Produktion_FFB | 0114SFu0000030960 | m² | Stahlbeton | Ortbeton | true | F005 | 50 | XC2, WF | C25/30 | HA_FUN_STB_0,500x1,000_xxx
Stb.-Fundament | EG_Produktion_FFB | STRIP_FOOTING | Stahlbeton | FU-STREIFEN2\ | Stb.-Fundament | EG_Produktion_FFB | 0114SFu0000113707 | m² | Stahlbeton | Ortbeton | false | F002 | 50 | XC1, WO | C25/30 | HA_FUN_STB_0,250_xxx
Stb.-Fundament | EG_Produktion_FFB | STRIP_FOOTING | Stahlbeton | FU-STREIFEN2\ | Stb.-Fundament | EG_Produktion_FFB | 0114SFu0000113675 | m² | Stahlbeton | Ortbeton | false | F002 | 50 | XC1, WO | C25/30 | HA_FUN_STB_0,250_xxx
Stb.-Fundament | EG_Produktion_FFB | STRIP_FOOTING | Stahlbeton | FU-STREIFEN2\ | Stb.-Fundament | EG_Produktion_FFB | 0114SFu0000017447 | m² | Stahlbeton | Ortbeton | false | F002 | 50 | XC1, WO | C25/30 | HA_FUN_STB_0,250_xxx
Stb.-Fundament | EG_Produktion_FFB | STRIP_FOOTING | Stahlbeton | FU-STREIFEN2\ | Stb.-Fundament | EG_Produktion_FFB | 0114SFu0000017498 | m² | Stahlbeton | Ortbeton | false | F002 | 50 | XC1, WO | C25/30 | HA_FUN_STB_0,250_xxx
Stb.-Fundament | EG_Produktion_FFB | STRIP_FOOTING | Stahlbeton | FU-STREIFEN2\ | Stb.-Fundament | EG_Produktion_FFB | 0114SFu0000017491 | m² | Stahlbeton | Ortbeton | false | F002 | 50 | XC1, WO | C25/30 | HA_FUN_STB_0,250_xxx
Stb.-Fundament | EG_Produktion_FFB | STRIP_FOOTING | Stahlbeton | FU-STREIFEN2\ | Stb.-Fundament | EG_Produktion_FFB | 0114SFu0000017458 | m² | Stahlbeton | Ortbeton | false | F002 | 50 | XC1, WO | C25/30 | HA_FUN_STB_0,250_xxx
Stb.-Fundament | EG_Produktion_FFB | STRIP_FOOTING | Stahlbeton | FU-STREIFEN2\ | Stb.-Fundament | EG_Produktion_FFB | 0114SFu0000017442 | m² | Stahlbeton | Ortbeton | false | F002 | 50 | XC1, WO | C25/30 | HA_FUN_STB_0,250_xxx
Stb.-Fundament | EG_Produktion_FFB | STRIP_FOOTING | Stahlbeton | FU-STREIFEN2\ | Stb.-Fundament | EG_Produktion_FFB | 0114SFu0000017441 | m² | Stahlbeton | Ortbeton | false | F002 | 50 | XC1, WO | C25/30 | HA_FUN_STB_0,250_xxx
Stb.-Fundament | EG_Produktion_FFB | STRIP_FOOTING | Stahlbeton | FU-STREIFEN2\ | Stb.-Fundament | EG_Produktion_FFB | 0114SFu0000113614 | m² | Stahlbeton | Ortbeton | false | F001 | 50 | XC1, WO | C25/30 | HA_FUN_STB_0,250_xxx
Stb.-Fundament | EG_Produktion_FFB | STRIP_FOOTING | Stahlbeton | FU-STREIFEN2\ | Stb.-Fundament | EG_Produktion_FFB | 0114SFu0000113649 | m² | Stahlbeton | Ortbeton | false | F002 | 50 | XC1, WO | C25/30 | HA_FUN_STB_0,250_xxx
Stb.-Fundament | EG_Produktion_FFB | STRIP_FOOTING | Stahlbeton | FU-STREIFEN2\ | Stb.-Fundament | EG_Produktion_FFB | 0114SFu0000113719 | m² | Stahlbeton | Ortbeton | false | F002 | 50 | XC1, WO | C25/30 | HA_FUN_STB_0,250_xxx
Stb.-Fundament | EG_Produktion_FFB | STRIP_FOOTING | Stahlbeton | FU-STREIFEN2\ | Stb.-Fundament | EG_Produktion_FFB | 0114SFu0000026895 | m² | Stahlbeton | Ortbeton | false | F002 | 50 | XC1, WO | C25/30 | HA_FUN_STB_0,250_xxx
Stb.-Fundament | EG_Produktion_FFB | STRIP_FOOTING | Stahlbeton | FU-STREIFEN2\ | Stb.-Fundament | EG_Produktion_FFB | 0114SFu0000014828 | m² | Stahlbeton | Ortbeton | false | F002 | 50 | XC1, WO | C25/30 | HA_FUN_STB_0,250_xxx
Stb.-Fundament | EG_Produktion_FFB | STRIP_FOOTING | Stahlbeton | FU-STREIFEN2\ | Stb.-Fundament | EG_Produktion_FFB | 0114SFu0000014833 | m² | Stahlbeton | Ortbeton | false | F002 | 50 | XC1, WO | C25/30 | HA_FUN_STB_0,250_xxx
Stb.-Fundament | EG_Produktion_FFB | STRIP_FOOTING | Stahlbeton | FU-STREIFEN2\ | Stb.-Fundament | EG_Produktion_FFB | 0114SFu0000014827 | m² | Stahlbeton | Ortbeton | false | F002 | 50 | XC1, WO | C25/30 | HA_FUN_STB_0,250_xxx
Stb.-Fundament | EG_Produktion_FFB | STRIP_FOOTING | Stahlbeton | FU-STREIFEN2\ | Stb.-Fundament | EG_Produktion_FFB | 0114SFu0000026894 | m² | Stahlbeton | Ortbeton | false | F002 | 50 | XC1, WO | C25/30 | HA_FUN_STB_0,250_xxx
Stb.-Fundament | EG_Produktion_FFB | STRIP_FOOTING | Stahlbeton | FU-STREIFEN2\ | Stb.-Fundament | EG_Produktion_FFB | 0114SFu0000014834 | m² | Stahlbeton | Ortbeton | false | F002 | 50 | XC1, WO | C25/30 | HA_FUN_STB_0,250_xxx
Stb.-Fundament | EG_Produktion_FFB | STRIP_FOOTING | Stahlbeton | FU-STREIFEN2\ | Stb.-Fundament | EG_Produktion_FFB | 0114SFu0000014831 | m² | Stahlbeton | Ortbeton | false | F002 | 50 | XC1, WO | C25/30 | HA_FUN_STB_0,250_xxx
Stb.-Fundament | EG_Produktion_FFB | STRIP_FOOTING | Stahlbeton | FU-STREIFEN2\ | Stb.-Fundament | EG_Produktion_FFB | 0114SFu0000014829 | m² | Stahlbeton | Ortbeton | false | F002 | 50 | XC1, WO | C25/30 | HA_FUN_STB_0,250_xxx
Stb.-Fundament | EG_Produktion_FFB | STRIP_FOOTING | Stahlbeton | FU-STREIFEN2\ | Stb.-Fundament | EG_Produktion_FFB | 0114SFu0000014798 | m² | Stahlbeton | Ortbeton | false | F002 | 50 | XC1, WO | C25/30 | HA_FUN_STB_0,250_xxx
Stb.-Fundament | EG_Produktion_FFB | STRIP_FOOTING | Stahlbeton | FU-STREIFEN2\ | Stb.-Fundament | EG_Produktion_FFB | 0114SFu0000014797 | m² | Stahlbeton | Ortbeton | false | F002 | 50 | XC1, WO | C25/30 | HA_FUN_STB_0,250_xxx
Stb.-Fundament | EG_Produktion_FFB | STRIP_FOOTING | Stahlbeton | FU-STREIFEN2\ | Stb.-Fundament | EG_Produktion_FFB | 0114SFu0000014803 | m² | Stahlbeton | Ortbeton | false | F002 | 50 | XC1, WO | C25/30 | HA_FUN_STB_0,250_xxx
Stb.-Fundament | EG_Produktion_FFB | STRIP_FOOTING | Stahlbeton | FU-STREIFEN2\ | Stb.-Fundament | EG_Produktion_FFB | 0114SFu0000014801 | m² | Stahlbeton | Ortbeton | false | F002 | 50 | XC1, WO | C25/30 | HA_FUN_STB_0,250_xxx
Stb.-Fundament | EG_Produktion_FFB | STRIP_FOOTING | Stahlbeton | FU-STREIFEN2\ | Stb.-Fundament | EG_Produktion_FFB | 0114SFu0000014796 | m² | Stahlbeton | Ortbeton | false | F002 | 50 | XC1, WO | C25/30 | HA_FUN_STB_0,250_xxx
Stb.-Fundament | EG_Produktion_FFB | STRIP_FOOTING | Stahlbeton | FU-STREIFEN2\ | Stb.-Fundament | EG_Produktion_FFB | 0114SFu0000014804 | m² | Stahlbeton | Ortbeton | false | F002 | 50 | XC1, WO | C25/30 | HA_FUN_STB_0,250_xxx
Stb.-Fundament | EG_Produktion_FFB | STRIP_FOOTING | Stahlbeton | FU-STREIFEN2\ | Stb.-Fundament | EG_Produktion_FFB | 0114SFu0000014795 | m² | Stahlbeton | Ortbeton | false | F002 | 50 | XC1, WO | C25/30 | HA_FUN_STB_0,250_xxx
Stb.-Fundament | EG_Produktion_FFB | STRIP_FOOTING | Stahlbeton | FU-STREIFEN2\ | Stb.-Fundament | EG_Produktion_FFB | 0114SFu0000014802 | m² | Stahlbeton | Ortbeton | false | F002 | 50 | XC1, WO | C25/30 | HA_FUN_STB_0,250_xxx
Stb.-Fundament | EG_Produktion_FFB | STRIP_FOOTING | Stahlbeton | FU-STREIFEN2\ | Stb.-Fundament | EG_Produktion_FFB | 0114SFu0000026816 | m² | Stahlbeton | Ortbeton | false | F002 | 50 | XC1, WO | C25/30 | HA_FUN_STB_0,250_xxx
Stb.-Fundament | EG_Produktion_FFB | STRIP_FOOTING | Stahlbeton | FU-STREIFEN2\ | Stb.-Fundament | EG_Produktion_FFB | 0114SFu0000014800 | m² | Stahlbeton | Ortbeton | false | F002 | 50 | XC1, WO | C25/30 | HA_FUN_STB_0,250_xxx
Stb.-Fundament | EG_Produktion_FFB | STRIP_FOOTING | Stahlbeton | FU-STREIFEN2\ | Stb.-Fundament | EG_Produktion_FFB | 0114SFu0000014799 | m² | Stahlbeton | Ortbeton | false | F002 | 50 | XC1, WO | C25/30 | HA_FUN_STB_0,250_xxx
Stb.-Fundament | EG_Produktion_FFB | STRIP_FOOTING | Stahlbeton | FU-STREIFEN2\ | Stb.-Fundament | EG_Produktion_FFB | 0114SFu0000014830 | m² | Stahlbeton | Ortbeton | false | F002 | 50 | XC1, WO | C25/30 | HA_FUN_STB_0,250_xxx
Stb.-Fundament | EG_Produktion_FFB | STRIP_FOOTING | Stahlbeton | FU-STREIFEN2\ | Stb.-Fundament | EG_Produktion_FFB | 0114SFu0000014836 | m² | Stahlbeton | Ortbeton | false | F002 | 50 | XC1, WO | C25/30 | HA_FUN_STB_0,250_xxx
Stb.-Fundament | EG_Produktion_FFB | STRIP_FOOTING | Stahlbeton | FU-STREIFEN2\ | Stb.-Fundament | EG_Produktion_FFB | 0114SFu0000026817 | m² | Stahlbeton | Ortbeton | false | F002 | 50 | XC1, WO | C25/30 | HA_FUN_STB_0,250_xxx
Stb.-Fundament | EG_Produktion_FFB | STRIP_FOOTING | Stahlbeton | FU-STREIFEN2\ | Stb.-Fundament | EG_Produktion_FFB | 0114SFu0000014835 | m² | Stahlbeton | Ortbeton | false | F002 | 50 | XC1, WO | C25/30 | HA_FUN_STB_0,250_xxx
Stb.-Fundament | EG_Produktion_FFB | STRIP_FOOTING | Stahlbeton | FU-STREIFEN2\ | Stb.-Fundament | EG_Produktion_FFB | 0114SFu0000014832 | m² | Stahlbeton | Ortbeton | false | F002 | 50 | XC1, WO | C25/30 | HA_FUN_STB_0,250_xxx
Stb.-Fundament | EG_Produktion_FFB | STRIP_FOOTING | Stahlbeton | FU-STREIFEN2\ | Stb.-Fundament | EG_Produktion_FFB | 0114SFu0000014770 | m² | Stahlbeton | Ortbeton | false | F002 | 50 | XC1, WO | C25/30 | HA_FUN_STB_0,250_xxx
Stb.-Fundament | EG_Produktion_FFB | STRIP_FOOTING | Stahlbeton | FU-STREIFEN2\ | Stb.-Fundament | EG_Produktion_FFB | 0114SFu0000014769 | m² | Stahlbeton | Ortbeton | false | F002 | 50 | XC1, WO | C25/30 | HA_FUN_STB_0,250_xxx
Stb.-Fundament | EG_Produktion_FFB | STRIP_FOOTING | Stahlbeton | FU-STREIFEN2\ | Stb.-Fundament | EG_Produktion_FFB | 0114SFu0000026639 | m² | Stahlbeton | Ortbeton | false | F002 | 50 | XC1, WO | C25/30 | HA_FUN_STB_0,250_xxx
Stb.-Fundament | EG_Produktion_FFB | STRIP_FOOTING | Stahlbeton | FU-STREIFEN2\ | Stb.-Fundament | EG_Produktion_FFB | 0114SFu0000014767 | m² | Stahlbeton | Ortbeton | false | F002 | 50 | XC1, WO | C25/30 | HA_FUN_STB_0,250_xxx
Stb.-Fundament | EG_Produktion_FFB | STRIP_FOOTING | Stahlbeton | FU-STREIFEN2\ | Stb.-Fundament | EG_Produktion_FFB | 0114SFu0000014768 | m² | Stahlbeton | Ortbeton | false | F002 | 50 | XC1, WO | C25/30 | HA_FUN_STB_0,250_xxx
Stb.-Fundament | EG_Produktion_FFB | STRIP_FOOTING | Stahlbeton | FU-STREIFEN2\ | Stb.-Fundament | EG_Produktion_FFB | 0114SFu0000014725 | m² | Stahlbeton | Ortbeton | false | F002 | 50 | XC1, WO | C25/30 | HA_FUN_STB_0,250_xxx
Stb.-Fundament | EG_Produktion_FFB | STRIP_FOOTING | Stahlbeton | FU-STREIFEN2\ | Stb.-Fundament | EG_Produktion_FFB | 0114SFu0000014724 | m² | Stahlbeton | Ortbeton | false | F002 | 50 | XC1, WO | C25/30 | HA_FUN_STB_0,250_xxx
Stb.-Fundament | EG_Produktion_FFB | STRIP_FOOTING | Stahlbeton | FU-STREIFEN2\ | Stb.-Fundament | EG_Produktion_FFB | 0114SFu0000014726 | m² | Stahlbeton | Ortbeton | false | F002 | 50 | XC1, WO | C25/30 | HA_FUN_STB_0,250_xxx
Stb.-Fundament | EG_Produktion_FFB | STRIP_FOOTING | Stahlbeton | FU-STREIFEN2\ | Stb.-Fundament | EG_Produktion_FFB | 0114SFu0000014722 | m² | Stahlbeton | Ortbeton | false | F002 | 50 | XC1, WO | C25/30 | HA_FUN_STB_0,250_xxx
Stb.-Fundament | EG_Produktion_FFB | STRIP_FOOTING | Stahlbeton | FU-STREIFEN2\ | Stb.-Fundament | EG_Produktion_FFB | 0114SFu0000014723 | m² | Stahlbeton | Ortbeton | false | F002 | 50 | XC1, WO | C25/30 | HA_FUN_STB_0,250_xxx
Stb.-Fundament | EG_Produktion_FFB | STRIP_FOOTING | Stahlbeton | FU-STREIFEN2\ | Stb.-Fundament | EG_Produktion_FFB | 0114SFu0000014721 | m² | Stahlbeton | Ortbeton | false | F002 | 50 | XC1, WO | C25/30 | HA_FUN_STB_0,250_xxx
Stb.-Fundament | EG_Produktion_FFB | STRIP_FOOTING | Stahlbeton | FU-STREIFEN2\ | Stb.-Fundament | EG_Produktion_FFB | 0114SFu0000014685 | m² | Stahlbeton | Ortbeton | false | F002 | 50 | XC1, WO | C25/30 | HA_FUN_STB_0,250_xxx
Stb.-Fundament | EG_Produktion_FFB | STRIP_FOOTING | Stahlbeton | FU-STREIFEN2\ | Stb.-Fundament | EG_Produktion_FFB | 0114SFu0000014686 | m² | Stahlbeton | Ortbeton | false | F002 | 50 | XC1, WO | C25/30 | HA_FUN_STB_0,250_xxx
Stb.-Fundament | EG_Produktion_FFB | STRIP_FOOTING | Stahlbeton | FU-STREIFEN2\ | Stb.-Fundament | EG_Produktion_FFB | 0114SFu0000014683 | m² | Stahlbeton | Ortbeton | false | F002 | 50 | XC1, WO | C25/30 | HA_FUN_STB_0,250_xxx
Stb.-Fundament | EG_Produktion_FFB | STRIP_FOOTING | Stahlbeton | FU-STREIFEN2\ | Stb.-Fundament | EG_Produktion_FFB | 0114SFu0000014684 | m² | Stahlbeton | Ortbeton | false | F002 | 50 | XC1, WO | C25/30 | HA_FUN_STB_0,250_xxx
Stb.-Fundament | EG_Produktion_FFB | STRIP_FOOTING | Stahlbeton | FU-STREIFEN2\ | Stb.-Fundament | EG_Produktion_FFB | 0114SFu0000014680 | m² | Stahlbeton | Ortbeton | false | F002 | 50 | XC1, WO | C25/30 | HA_FUN_STB_0,250_xxx
Stb.-Fundament | EG_Produktion_FFB | STRIP_FOOTING | Stahlbeton | FU-STREIFEN2\ | Stb.-Fundament | EG_Produktion_FFB | 0114SFu0000014682 | m² | Stahlbeton | Ortbeton | false | F002 | 50 | XC1, WO | C25/30 | HA_FUN_STB_0,250_xxx
Stb.-Fundament | EG_Produktion_FFB | STRIP_FOOTING | Stahlbeton | FU-STREIFEN2\ | Stb.-Fundament | EG_Produktion_FFB | 0114SFu0000114527 | m² | Stahlbeton | Ortbeton | false | F002 | 50 | XC1, WO | C25/30 | HA_FUN_STB_0,250_xxx
Stb.-Fundament | EG_Produktion_FFB | STRIP_FOOTING | Stahlbeton | FU-STREIFEN2\ | Stb.-Fundament | EG_Produktion_FFB | 0114SFu0000014636 | m² | Stahlbeton | Ortbeton | false | F002 | 50 | XC1, WO | C25/30 | HA_FUN_STB_0,250_xxx
Stb.-Fundament | EG_Produktion_FFB | STRIP_FOOTING | Stahlbeton | FU-STREIFEN2\ | Stb.-Fundament | EG_Produktion_FFB | 0114SFu0000014637 | m² | Stahlbeton | Ortbeton | false | F002 | 50 | XC1, WO | C25/30 | HA_FUN_STB_0,250_xxx
Stb.-Fundament | EG_Produktion_FFB | STRIP_FOOTING | Stahlbeton | FU-STREIFEN2\ | Stb.-Fundament | EG_Produktion_FFB | 0114SFu0000014681 | m² | Stahlbeton | Ortbeton | false | F002 | 50 | XC1, WO | C25/30 | HA_FUN_STB_0,250_xxx
Stb.-Fundament | EG_Produktion_FFB | STRIP_FOOTING | Stahlbeton | FU-STREIFEN2\ | Stb.-Fundament | EG_Produktion_FFB | 0114SFu0000014634 | m² | Stahlbeton | Ortbeton | false | F002 | 50 | XC1, WO | C25/30 | HA_FUN_STB_0,250_xxx
Stb.-Fundament | EG_Produktion_FFB | STRIP_FOOTING | Stahlbeton | FU-STREIFEN2\ | Stb.-Fundament | EG_Produktion_FFB | 0114SFu0000114415 | m² | Stahlbeton | Ortbeton | false | F002 | 50 | XC1, WO | C25/30 | HA_FUN_STB_0,250_xxx
Stb.-Fundament | EG_Produktion_FFB | STRIP_FOOTING | Stahlbeton | FU-STREIFEN2\ | Stb.-Fundament | EG_Produktion_FFB | 0114SFu0000014677 | m² | Stahlbeton | Ortbeton | false | F002 | 50 | XC1, WO | C25/30 | HA_FUN_STB_0,250_xxx
Stb.-Fundament | EG_Produktion_FFB | STRIP_FOOTING | Stahlbeton | FU-STREIFEN2\ | Stb.-Fundament | EG_Produktion_FFB | 0114SFu0000014678 | m² | Stahlbeton | Ortbeton | false | F002 | 50 | XC1, WO | C25/30 | HA_FUN_STB_0,250_xxx
Stb.-Fundament | EG_Produktion_FFB | STRIP_FOOTING | Stahlbeton | FU-STREIFEN2\ | Stb.-Fundament | EG_Produktion_FFB | 0114SFu0000014641 | m² | Stahlbeton | Ortbeton | false | F002 | 50 | XC1, WO | C25/30 | HA_FUN_STB_0,250_xxx
Stb.-Fundament | EG_Produktion_FFB | STRIP_FOOTING | Stahlbeton | FU-STREIFEN2\ | Stb.-Fundament | EG_Produktion_FFB | 0114SFu0000014645 | m² | Stahlbeton | Ortbeton | false | F002 | 50 | XC1, WO | C25/30 | HA_FUN_STB_0,250_xxx
Stb.-Fundament | EG_Produktion_FFB | STRIP_FOOTING | Stahlbeton | FU-STREIFEN2\ | Stb.-Fundament | EG_Produktion_FFB | 0114SFu0000014643 | m² | Stahlbeton | Ortbeton | false | F002 | 50 | XC1, WO | C25/30 | HA_FUN_STB_0,250_xxx
Stb.-Fundament | EG_Produktion_FFB | STRIP_FOOTING | Stahlbeton | FU-STREIFEN2\ | Stb.-Fundament | EG_Produktion_FFB | 0114SFu0000014401 | m² | Stahlbeton | Ortbeton | false | F002 | 50 | XC1, WO | C25/30 | HA_FUN_STB_0,250_xxx
Stb.-Fundament | EG_Produktion_FFB | STRIP_FOOTING | Stahlbeton | FU-STREIFEN2\ | Stb.-Fundament | EG_Produktion_FFB | 0114SFu0000014642 | m² | Stahlbeton | Ortbeton | false | F002 | 50 | XC1, WO | C25/30 | HA_FUN_STB_0,250_xxx
Stb.-Fundament | EG_Produktion_FFB | STRIP_FOOTING | Stahlbeton | FU-STREIFEN2\ | Stb.-Fundament | EG_Produktion_FFB | 0114SFu0000017782 | m² | Stahlbeton | Ortbeton | false | F002 | 50 | XC1, WO | C25/30 | HA_FUN_STB_0,250_xxx
Stb.-Fundament | EG_Produktion_FFB | STRIP_FOOTING | Stahlbeton | FU-STREIFEN2\ | Stb.-Fundament | EG_Produktion_FFB | 0114SFu0000014646 | m² | Stahlbeton | Ortbeton | false | F002 | 50 | XC1, WO | C25/30 | HA_FUN_STB_0,250_xxx
Stb.-Fundament | EG_Produktion_FFB | STRIP_FOOTING | Stahlbeton | FU-STREIFEN2\ | Stb.-Fundament | EG_Produktion_FFB | 0114SFu0000014644 | m² | Stahlbeton | Ortbeton | false | F002 | 50 | XC1, WO | C25/30 | HA_FUN_STB_0,250_xxx
Stb.-Fundament | EG_Produktion_FFB | STRIP_FOOTING | Stahlbeton | FU-STREIFEN2\ | Stb.-Fundament | EG_Produktion_FFB | 0114SFu0000017781 | m² | Stahlbeton | Ortbeton | false | F002 | 50 | XC1, WO | C25/30 | HA_FUN_STB_0,250_xxx
Stb.-Fundament | EG_Produktion_FFB | STRIP_FOOTING | Stahlbeton | FU-STREIFEN2\ | Stb.-Fundament | EG_Produktion_FFB | 0114SFu0000014406 | m² | Stahlbeton | Ortbeton | false | F002 | 50 | XC1, WO | C25/30 | HA_FUN_STB_0,250_xxx
Stb.-Fundament | EG_Produktion_FFB | STRIP_FOOTING | Stahlbeton | FU-STREIFEN2\ | Stb.-Fundament | EG_Produktion_FFB | 0114SFu0000014764 | m² | Stahlbeton | Ortbeton | false | F002 | 50 | XC1, WO | C25/30 | HA_FUN_STB_0,250_xxx
Stb.-Fundament | EG_Produktion_FFB | STRIP_FOOTING | Stahlbeton | FU-STREIFEN2\ | Stb.-Fundament | EG_Produktion_FFB | 0114SFu0000014719 | m² | Stahlbeton | Ortbeton | false | F002 | 50 | XC1, WO | C25/30 | HA_FUN_STB_0,250_xxx
Stb.-Fundament | EG_Produktion_FFB | STRIP_FOOTING | Stahlbeton | FU-STREIFEN2\ | Stb.-Fundament | EG_Produktion_FFB | 0114SFu0000014762 | m² | Stahlbeton | Ortbeton | false | F002 | 50 | XC1, WO | C25/30 | HA_FUN_STB_0,250_xxx
Stb.-Fundament | EG_Produktion_FFB | STRIP_FOOTING | Stahlbeton | FU-STREIFEN2\ | Stb.-Fundament | EG_Produktion_FFB | 0114SFu0000014717 | m² | Stahlbeton | Ortbeton | false | F002 | 50 | XC1, WO | C25/30 | HA_FUN_STB_0,250_xxx
Stb.-Fundament | EG_Produktion_FFB | STRIP_FOOTING | Stahlbeton | FU-STREIFEN2\ | Stb.-Fundament | EG_Produktion_FFB | 0114SFu0000014766 | m² | Stahlbeton | Ortbeton | false | F002 | 50 | XC1, WO | C25/30 | HA_FUN_STB_0,250_xxx
Stb.-Fundament | EG_Produktion_FFB | STRIP_FOOTING | Stahlbeton | FU-STREIFEN2\ | Stb.-Fundament | EG_Produktion_FFB | 0114SFu0000014720 | m² | Stahlbeton | Ortbeton | false | F002 | 50 | XC1, WO | C25/30 | HA_FUN_STB_0,250_xxx
Stb.-Fundament | EG_Produktion_FFB | STRIP_FOOTING | Stahlbeton | FU-STREIFEN2\ | Stb.-Fundament | EG_Produktion_FFB | 0114SFu0000114231 | m² | Stahlbeton | Ortbeton | false | F002 | 50 | XC1, WO | C25/30 | HA_FUN_STB_0,250_xxx
Stb.-Fundament | EG_Produktion_FFB | STRIP_FOOTING | Stahlbeton | FU-STREIFEN2\ | Stb.-Fundament | EG_Produktion_FFB | 0114SFu0000114187 | m² | Stahlbeton | Ortbeton | false | F002 | 50 | XC1, WO | C25/30 | HA_FUN_STB_0,250_xxx
Stb.-Fundament | EG_Produktion_FFB | STRIP_FOOTING | Stahlbeton | FU-STREIFEN2\ | Stb.-Fundament | EG_Produktion_FFB | 0114SFu0000116029 | m² | Stahlbeton | Ortbeton | false | F002 | 50 | XC1, WO | C25/30 | HA_FUN_STB_0,250_xxx
Stb.-Fundament | EG_Produktion_FFB | STRIP_FOOTING | Stahlbeton | FU-STREIFEN2\ | Stb.-Fundament | EG_Produktion_FFB | 0114SFu0000115035 | m² | Stahlbeton | Ortbeton | false | F002 | 50 | XC1, WO | C25/30 | HA_FUN_STB_0,250_xxx
Stb.-Fundament | EG_Produktion_FFB | STRIP_FOOTING | Stahlbeton | FU-STREIFEN2\ | Stb.-Fundament | EG_Produktion_FFB | 0114SFu0000014417 | m² | Stahlbeton | Ortbeton | false | F002 | 50 | XC1, WO | C25/30 | HA_FUN_STB_0,250_xxx
Stb.-Fundament | EG_Produktion_FFB | STRIP_FOOTING | Stahlbeton | FU-STREIFEN2\ | Stb.-Fundament | EG_Produktion_FFB | 0114SFu0000017785 | m² | Stahlbeton | Ortbeton | false | F002 | 50 | XC1, WO | C25/30 | HA_FUN_STB_0,250_xxx
Stb.-Fundament | EG_Produktion_FFB | STRIP_FOOTING | Stahlbeton | FU-STREIFEN2\ | Stb.-Fundament | EG_Produktion_FFB | 0114SFu0000115073 | m² | Stahlbeton | Ortbeton | false | F002 | 50 | XC1, WO | C25/30 | HA_FUN_STB_0,250_xxx
Stb.-Fundament | EG_Produktion_FFB | STRIP_FOOTING | Stahlbeton | FU-STREIFEN2\ | Stb.-Fundament | EG_Produktion_FFB | 0114SFu0000017783 | m² | Stahlbeton | Ortbeton | false | F002 | 50 | XC1, WO | C25/30 | HA_FUN_STB_0,250_xxx
Stb.-Fundament | EG_Produktion_FFB | STRIP_FOOTING | Stahlbeton | FU-STREIFEN2\ | Stb.-Fundament | EG_Produktion_FFB | 0114SFu0000014422 | m² | Stahlbeton | Ortbeton | false | F002 | 50 | XC1, WO | C25/30 | HA_FUN_STB_0,250_xxx
Stb.-Fundament | EG_Produktion_FFB | STRIP_FOOTING | Stahlbeton | FU-STREIFEN2\ | Stb.-Fundament | EG_Produktion_FFB | 0114SFu0000116148 | m² | Stahlbeton | Ortbeton | false | F002 | 50 | XC1, WO | C25/30 | HA_FUN_STB_0,250_xxx
Stb.-Fundament | EG_Produktion_FFB | STRIP_FOOTING | Stahlbeton | FU-STREIFEN2\ | Stb.-Fundament | EG_Produktion_FFB | 0114SFu0000026708 | m² | Stahlbeton | Ortbeton | false | F002 | 50 | XC1, WO | C25/30 | HA_FUN_STB_0,250_xxx
Stb.-Fundament | EG_Produktion_FFB | STRIP_FOOTING | Stahlbeton | FU-STREIFEN2\ | Stb.-Fundament | EG_Produktion_FFB | 0114SFu0000026707 | m² | Stahlbeton | Ortbeton | false | F002 | 50 | XC1, WO | C25/30 | HA_FUN_STB_0,250_xxx
Stb.-Fundament | EG_Produktion_FFB | STRIP_FOOTING | Stahlbeton | FU-STREIFEN2\ | Stb.-Fundament | EG_Produktion_FFB | 0114SFu0000116171 | m² | Stahlbeton | Ortbeton | false | F002 | 50 | XC1, WO | C25/30 | HA_FUN_STB_0,250_xxx
Stb.-Fundament | EG_Produktion_FFB | STRIP_FOOTING | Stahlbeton | FU-STREIFEN2\ | Stb.-Fundament | EG_Produktion_FFB | 0114SFu0000026640 | m² | Stahlbeton | Ortbeton | false | F002 | 50 | XC1, WO | C25/30 | HA_FUN_STB_0,250_xxx
Stb.-Fundament | EG_Produktion_FFB | STRIP_FOOTING | Stahlbeton | FU-STREIFEN2\ | Stb.-Fundament | EG_Produktion_FFB | 0114SFu0000116183 | m² | Stahlbeton | Ortbeton | false | F002 | 50 | XC1, WO | C25/30 | HA_FUN_STB_0,250_xxx
Stb.-Fundament | EG_Produktion_FFB | STRIP_FOOTING | Stahlbeton | FU-STREIFEN2\ | Stb.-Fundament | EG_Produktion_FFB | 0114SFu0000026437 | m² | Stahlbeton | Ortbeton | false | F002 | 50 | XC1, WO | C25/30 | HA_FUN_STB_0,250_xxx
Stb.-Fundament | EG_Produktion_FFB | STRIP_FOOTING | Stahlbeton | FU-STREIFEN2\ | Stb.-Fundament | EG_Produktion_FFB | 0114SFu0000026438 | m² | Stahlbeton | Ortbeton | false | F002 | 50 | XC1, WO | C25/30 | HA_FUN_STB_0,250_xxx
Stb.-Fundament | EG_Produktion_FFB | STRIP_FOOTING | Stahlbeton | FU-STREIFEN2\ | Stb.-Fundament | EG_Produktion_FFB | 0114SFu0000116298 | m² | Stahlbeton | Ortbeton | false | F002 | 50 | XC1, WO | C25/30 | HA_FUN_STB_0,250_xxx
Stb.-Fundament | EG_Produktion_FFB | STRIP_FOOTING | Stahlbeton | FU-STREIFEN2\ | Stb.-Fundament | EG_Produktion_FFB | 0114SFu0000113615 | m² | Stahlbeton | Ortbeton | false | F001 | 50 | XC1, WO | C25/30 | HA_FUN_STB_0,250_xxx
Stb.-Fundament | EG_Produktion_FFB | STRIP_FOOTING | Stahlbeton | FU-STREIFEN2\ | Stb.-Fundament | EG_Produktion_FFB | 0114SFu0000027601 | m² | Stahlbeton | Ortbeton | true | F002.1 | 50 | XC2, WF | C25/30 | HA_FUN_STB_0,250_xxx
Stb.-Fundament | EG_Produktion_FFB | STRIP_FOOTING | Stahlbeton | FU-STREIFEN2\ | Stb.-Fundament | EG_Produktion_FFB | 0114SFu0000027561 | m² | Stahlbeton | Ortbeton | true | F002.1 | 50 | XC2, WF | C25/30 | HA_FUN_STB_0,250_xxx
Stb.-Fundament | EG_Produktion_FFB | STRIP_FOOTING | Stahlbeton | FU-STREIFEN2\ | Stb.-Fundament | EG_Produktion_FFB | 0114SFu0000027600 | m² | Stahlbeton | Ortbeton | true | F002.1 | 50 | XC2, WF | C25/30 | HA_FUN_STB_0,250_xxx
Stb.-Fundament | EG_Produktion_FFB | STRIP_FOOTING | Stahlbeton | FU-STREIFEN2\ | Stb.-Fundament | EG_Produktion_FFB | 0114SFu0000027560 | m² | Stahlbeton | Ortbeton | true | F002.1 | 50 | XC2, WF | C25/30 | HA_FUN_STB_0,250_xxx
Stb.-Fundament | EG_Produktion_FFB | STRIP_FOOTING | Stahlbeton | FU-STREIFEN2\ | Stb.-Fundament | EG_Produktion_FFB | 0114SFu0000027636 | m² | Stahlbeton | Ortbeton | true | F002.1 | 50 | XC2, WF | C25/30 | HA_FUN_STB_0,250_xxx
Stb.-Fundament | EG_Produktion_FFB | STRIP_FOOTING | Stahlbeton | FU-STREIFEN2\ | Stb.-Fundament | EG_Produktion_FFB | 0114SFu0000027637 | m² | Stahlbeton | Ortbeton | true | F002.1 | 50 | XC2, WF | C25/30 | HA_FUN_STB_0,250_xxx
Stb.-Fundament | EG_Produktion_FFB | STRIP_FOOTING | Stahlbeton | FU-STREIFEN2\ | Stb.-Fundament | EG_Produktion_FFB | 0114SFu0000025242 | m² | Stahlbeton | Ortbeton | true | F002.1 | 50 | XC2, WF | C25/30 | HA_FUN_STB_0,250_xxx
Stb.-Fundament | EG_Produktion_FFB | STRIP_FOOTING | Stahlbeton | FU-STREIFEN2\ | Stb.-Fundament | EG_Produktion_FFB | 0114SFu0000025125 | m² | Stahlbeton | Ortbeton | true | F002.1 | 50 | XC2, WF | C25/30 | HA_FUN_STB_0,250_xxx
Stb.-Fundament | EG_Produktion_FFB | STRIP_FOOTING | Stahlbeton | FU-STREIFEN2\ | Stb.-Fundament | EG_Produktion_FFB | 0114SFu0000025243 | m² | Stahlbeton | Ortbeton | true | F002.1 | 50 | XC2, WF | C25/30 | HA_FUN_STB_0,250_xxx
Stb.-Fundament | EG_Produktion_FFB | STRIP_FOOTING | Stahlbeton | FU-STREIFEN2\ | Stb.-Fundament | EG_Produktion_FFB | 0114SFu0000025126 | m² | Stahlbeton | Ortbeton | true | F002.1 | 50 | XC2, WF | C25/30 | HA_FUN_STB_0,250_xxx
Stb.-Fundament | EG_Produktion_FFB | STRIP_FOOTING | Stahlbeton | FU-STREIFEN2\ | Stb.-Fundament | EG_Produktion_FFB | 0114SFu0000025201 | m² | Stahlbeton | Ortbeton | true | F002.1 | 50 | XC2, WF | C25/30 | HA_FUN_STB_0,250_xxx
Stb.-Fundament | EG_Produktion_FFB | STRIP_FOOTING | Stahlbeton | FU-STREIFEN2\ | Stb.-Fundament | EG_Produktion_FFB | 0114SFu0000027669 | m² | Stahlbeton | Ortbeton | true | F001.1 | 50 | XC2, WF | C25/30 | HA_FUN_STB_0,250_xxx
Stb.-Fundament | EG_Produktion_FFB | STRIP_FOOTING | Stahlbeton | FU-STREIFEN2\ | Stb.-Fundament | EG_Produktion_FFB | 0114SFu0000025188 | m² | Stahlbeton | Ortbeton | true | F002.1 | 50 | XC2, WF | C25/30 | HA_FUN_STB_0,250_xxx
Stb.-Fundament | EG_Produktion_FFB | STRIP_FOOTING | Stahlbeton | FU-STREIFEN2\ | Stb.-Fundament | EG_Produktion_FFB | 0114SFu0000025187 | m² | Stahlbeton | Ortbeton | true | F002.1 | 50 | XC2, WF | C25/30 | HA_FUN_STB_0,250_xxx
Stb.-Fundament | EG_Produktion_FFB | STRIP_FOOTING | Stahlbeton | FU-STREIFEN2\ | Stb.-Fundament | EG_Produktion_FFB | 0114SFu0000027668 | m² | Stahlbeton | Ortbeton | true | F001.1 | 50 | XC2, WF | C25/30 | HA_FUN_STB_0,250_xxx
Stb.-Fundament | EG_Produktion_FFB | STRIP_FOOTING | Stahlbeton | FU-STREIFEN2\ | Stb.-Fundament | EG_Produktion_FFB | 0114SFu0000025202 | m² | Stahlbeton | Ortbeton | true | F002.1 | 50 | XC2, WF | C25/30 | HA_FUN_STB_0,250_xxx
Stahlbetonfertigteilfundament | EG_Produktion_FFB | STRIP_FOOTING | Stahlbetonfertigteil | FU-STREIFEN2\ | Stahlbetonfertigteilfundament | EG_Produktion_FFB | 0114SFu0000031675 | m² | Stahlbeton | Fertigteil | false | F002 | 50 | XC1, WO | C25/30 | HA_FUN_FEB_0,250_xxx
Stahlbetonfertigteilfundament | EG_Produktion_FFB | STRIP_FOOTING | Stahlbetonfertigteil | FU-STREIFEN2\ | Stahlbetonfertigteilfundament | EG_Produktion_FFB | 0114SFu0000031674 | m² | Stahlbeton | Fertigteil | false | F002 | 50 | XC1, WO | C25/30 | HA_FUN_FEB_0,250_xxx
Stahlbetonfertigteilfundament | EG_Produktion_FFB | STRIP_FOOTING | Stahlbetonfertigteil | FU-STREIFEN2\ | Stahlbetonfertigteilfundament | EG_Produktion_FFB | 0114SFu0000031645 | m² | Stahlbeton | Fertigteil | false | F002 | 50 | XC1, WO | C25/30 | HA_FUN_FEB_0,250_xxx
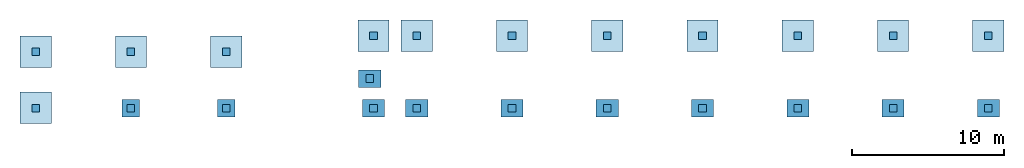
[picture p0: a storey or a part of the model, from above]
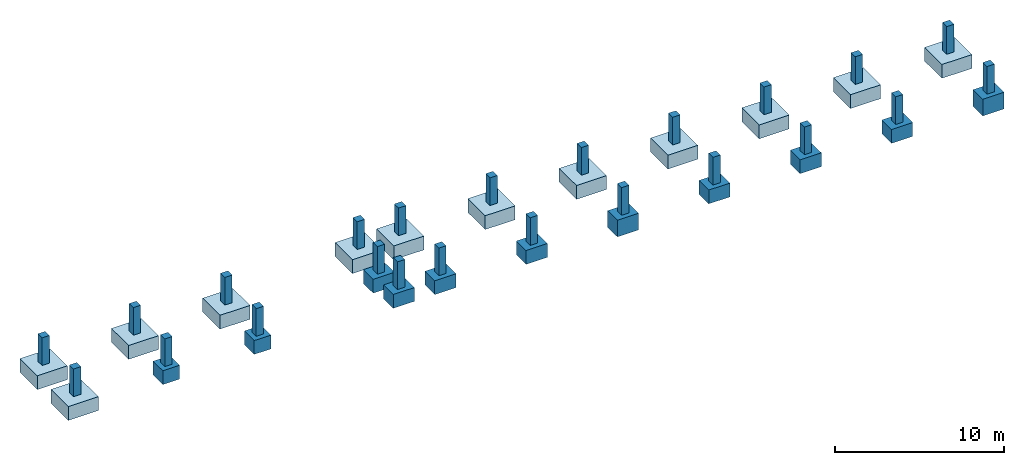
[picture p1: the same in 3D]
Properties of the parts of a building model (IFC2X3), part 16 of 25

# IfcFooting (903)
Name | In | PredefinedType | Material = AllplanAttributes, Material | Codetext | Bezeichnung = Name | Ebene | Allright_Bauteil_ID | Abrechnungsart | IFC_Pset_TWP, Material | Herstellung | Außenbauteil | Positionsnummer | Bewehrungsgrad | Expositionsklasse | Druckfestigkeitsklasse | Reference
Stahlbetonfertigteilfundament | EG_Produktion_FFB | STRIP_FOOTING | Stahlbetonfertigteil | FU-STREIFEN2\ | Stahlbetonfertigteilfundament | EG_Produktion_FFB | 0114SFu0000031644 | m² | Stahlbeton | Fertigteil | false | F002 | 50 | XC1, WO | C25/30 | HA_FUN_FEB_0,250_xxx

# IfcFooting: COLUMN_FOUNDATION (137)
PredefinedType: USERDEFINED; Material: Stahlbeton
AllplanAttributes - 2D Interaktion: yes; Codetext: FU-EINZEL1\; Gewerk: Betonarbeiten; Material: Stahlbeton; Attributset-Objekt: Fundament; Abrechnungsart: m³
IFC_Pset_TWP - Phase erstellt: Neubau; Material: Stahlbeton; statisch tragend: true; Herstellung: Ortbeton; Kommentar: -
Pset_ConcreteElementGeneral - Bewehrungsgrad: 50; Expositionsklasse: XC2, WF; Druckfestigkeitsklasse: C25/30; WU-Beton: false; Betonüberdeckung: 1
Pset_FM-Vivantes - FM_Klasse: -; FM_Bezeichnung: -; FM_AKS: -; FM_Anzahl: -; FM_Standort: -; FM_Hersteller: -; FM_Hersteller-Typ: -; FM_Seriennummer: -; FM_Baujahr: -; FM_Inbetriebnahme Datum: -; FM_Gewährleistungsende: -; FM_Gewährleistungsgeber: -; FM_Betriebsstatus: -; FM_Prüfpflicht: -; FM_Prüfintervall: -; FM_letzter Prüfungstermin: -; FM_Sammelobjekt: -; FM_rechn. Lebensdauer: -; FM_rechn. Lebensende: -; FM_technischer Zustand: -; FM_voraus. Lebensende: -; FM_Eigentümer: -; FM_Bemerkung: -; FM_Versorgungsbereich-Wirkbereich: -; FM_Zugänglichkeit: -
Name | In | Bezeichnung = Name | Ebene | Allright_Bauteil_ID | Außenbauteil | Positionsnummer | Reference | Position
Stb.-Sockel | Grundleitungsebene | Stb.-Sockel | Grundleitungsebene | 0081EFu0000011731 | true | AS01 | HA_FUN_STB_0,500x0,500x2,000_xxx
Stb.-Sockel | Grundleitungsebene | Stb.-Sockel | Grundleitungsebene | 0081EFu0000011755 | true | AS01 | HA_FUN_STB_0,500x0,500x2,000_xxx
Stb.-Einzelfundament | Grundleitungsebene | Stb.-Einzelfundament | Grundleitungsebene | 0081EFu0000011730 | true | AF01 | HA_FUN_STB_1,450x1,150x0,300_xxx
Stb.-Einzelfundament | Grundleitungsebene | Stb.-Einzelfundament | Grundleitungsebene | 0081EFu0000011754 | true | AF01 | HA_FUN_STB_1,450x1,150x0,300_xxx
Stb.-Sockel | Grundleitungsebene | Stb.-Sockel | Grundleitungsebene | 0081EFu0000011759 | true | AS01 | HA_FUN_STB_0,500x0,500x2,000_xxx
Stb.-Sockel | Grundleitungsebene | Stb.-Sockel | Grundleitungsebene | 0081EFu0000011763 | true | AS01 | HA_FUN_STB_0,500x0,500x2,000_xxx
Stb.-Sockel | Grundleitungsebene | Stb.-Sockel | Grundleitungsebene | 0081EFu0000011844 | true | AS01 | HA_FUN_STB_0,500x0,500x2,000_xxx
Stb.-Sockel | Grundleitungsebene | Stb.-Sockel | Grundleitungsebene | 0081EFu0000011767 | true | AS01 | HA_FUN_STB_0,500x0,500x2,000_xxx
Stb.-Einzelfundament | Grundleitungsebene | Stb.-Einzelfundament | Grundleitungsebene | 0081EFu0000011845 | true | AF01 | HA_FUN_STB_1,450x1,150x1,000_xxx
Stb.-Einzelfundament | Grundleitungsebene | Stb.-Einzelfundament | Grundleitungsebene | 0081EFu0000011758 | true | AF01 | HA_FUN_STB_1,450x1,150x1,000_xxx
Stb.-Einzelfundament | Grundleitungsebene | Stb.-Einzelfundament | Grundleitungsebene | 0081EFu0000011762 | true | AF01 | HA_FUN_STB_1,450x1,150x1,000_xxx
Stb.-Einzelfundament | Grundleitungsebene | Stb.-Einzelfundament | Grundleitungsebene | 0081EFu0000011766 | true | AF01 | HA_FUN_STB_1,450x1,150x1,000_xxx
Stb.-Sockel | Grundleitungsebene | Stb.-Sockel | Grundleitungsebene | 0081EFu0000011817 | true | AS02 | HA_FUN_STB_0,500x0,500x2,000_xxx
Stb.-Sockel | Grundleitungsebene | Stb.-Sockel | Grundleitungsebene | 0081EFu0000011806 | true | AS02 | HA_FUN_STB_0,500x0,500x2,000_xxx
Stb.-Sockel | Grundleitungsebene | Stb.-Sockel | Grundleitungsebene | 0081EFu0000011751 | true | AS01 | HA_FUN_STB_0,500x0,500x2,000_xxx
Stb.-Sockel | Grundleitungsebene | Stb.-Sockel | Grundleitungsebene | 0081EFu0000011747 | true | AS01 | HA_FUN_STB_0,500x0,500x2,000_xxx
Stb.-Sockel | Grundleitungsebene | Stb.-Sockel | Grundleitungsebene | 0081EFu0000011743 | true | AS01 | HA_FUN_STB_0,500x0,500x2,000_xxx
Stb.-Einzelfundament | Grundleitungsebene | Stb.-Einzelfundament | Grundleitungsebene | 0081EFu0000011750 | true | AF01 | HA_FUN_STB_1,450x1,150x1,000_xxx
Stb.-Einzelfundament | Grundleitungsebene | Stb.-Einzelfundament | Grundleitungsebene | 0081EFu0000011746 | true | AF01 | HA_FUN_STB_1,450x1,150x1,000_xxx
Stb.-Einzelfundament | Grundleitungsebene | Stb.-Einzelfundament | Grundleitungsebene | 0081EFu0000011742 | true | AF01 | HA_FUN_STB_1,450x1,150x1,000_xxx
Stb.-Einzelfundament | Grundleitungsebene | Stb.-Einzelfundament | Grundleitungsebene | 0081EFu0000011816 | true | AF02 | HA_FUN_STB_1,150x1,150x1,000_xxx
Stb.-Einzelfundament | Grundleitungsebene | Stb.-Einzelfundament | Grundleitungsebene | 0081EFu0000011807 | true | AF02 | HA_FUN_STB_1,150x1,150x1,000_xxx
Stb.-Sockel | Grundleitungsebene | Stb.-Sockel | Grundleitungsebene | 0081EFu0000011741 | true | AS01 | HA_FUN_STB_0,500x0,500x2,000_xxx
Stb.-Sockel | Grundleitungsebene | Stb.-Sockel | Grundleitungsebene | 0081EFu0000011745 | true | AS01 | HA_FUN_STB_0,500x0,500x2,000_xxx
Stb.-Sockel | Grundleitungsebene | Stb.-Sockel | Grundleitungsebene | 0081EFu0000011749 | true | AS01 | HA_FUN_STB_0,500x0,500x2,000_xxx
Stb.-Sockel | Grundleitungsebene | Stb.-Sockel | Grundleitungsebene | 0081EFu0000011753 | true | AS01 | HA_FUN_STB_0,500x0,500x2,000_xxx
Stb.-Sockel | Grundleitungsebene | Stb.-Sockel | Grundleitungsebene | 0081EFu0000011757 | true | AS01 | HA_FUN_STB_0,500x0,500x2,000_xxx
Stb.-Sockel | Grundleitungsebene | Stb.-Sockel | Grundleitungsebene | 0081EFu0000011761 | true | AS01 | HA_FUN_STB_0,500x0,500x2,000_xxx
Stb.-Sockel | Grundleitungsebene | Stb.-Sockel | Grundleitungsebene | 0081EFu0000011765 | true | AS01 | HA_FUN_STB_0,500x0,500x2,000_xxx
Stb.-Sockel | Grundleitungsebene | Stb.-Sockel | Grundleitungsebene | 0081EFu0000011824 | true | AS01 | HA_FUN_STB_0,500x0,500x2,000_xxx
Stb.-Sockel | Grundleitungsebene | Stb.-Sockel | Grundleitungsebene | 0081EFu0000011829 | true | AS02 | HA_FUN_STB_0,500x0,500x2,000_xxx
Stb.-Sockel | Grundleitungsebene | Stb.-Sockel | Grundleitungsebene | 0081EFu0000011830 | true | AS02 | HA_FUN_STB_0,500x0,500x2,000_xxx
Stb.-Sockel | Grundleitungsebene | Stb.-Sockel | Grundleitungsebene | 0081EFu0000011832 | true | AS02 | HA_FUN_STB_0,500x0,500x2,000_xxx
Stb.-Sockel | Grundleitungsebene | Stb.-Sockel | Grundleitungsebene | 0081EFu0000011820 | true | AS02 | HA_FUN_STB_0,500x0,500x2,000_xxx
Stb.-Einzelfundament | EG_Produktion_FFB | Stb.-Einzelfundament | EG_Produktion_FFB | 0114EFu0000018510 | false | F012 | HA_FUN_STB_1,35x1,30x0,30_xxx | F012
Stb.-Einzelfundament | EG_Produktion_FFB | Stb.-Einzelfundament | EG_Produktion_FFB | 0114EFu0000030079 | false | F012 | HA_FUN_STB_1,35x1,30x0,30_xxx | F012
Stb.-Einzelfundament | EG_Produktion_FFB | Stb.-Einzelfundament | EG_Produktion_FFB | 0114EFu0000018263 | false | F014 | HA_FUN_STB_1,55x1,60x0,30_xxx | F014
Stb.-Einzelfundament | EG_Produktion_FFB | Stb.-Einzelfundament | EG_Produktion_FFB | 0114EFu0000018269 | false | F012 | HA_FUN_STB_1,35x1,30x0,30_xxx | F012
Stb.-Einzelfundament | EG_Produktion_FFB | Stb.-Einzelfundament | EG_Produktion_FFB | 0114EFu0000018270 | false | F012 | HA_FUN_STB_1,35x1,30x0,30_xxx | F012
Stb.-Einzelfundament | EG_Produktion_FFB | Stb.-Einzelfundament | EG_Produktion_FFB | 0114EFu0000018271 | false | F012 | HA_FUN_STB_1,35x1,30x0,30_xxx | F012
Stb.-Einzelfundament | EG_Produktion_FFB | Stb.-Einzelfundament | EG_Produktion_FFB | 0114EFu0000029989 | false | F010 | HA_FUN_STB_1,10x1,10x0,30_xxx | F010
Stb.-Einzelfundament | EG_Produktion_FFB | Stb.-Einzelfundament | EG_Produktion_FFB | 0114EFu0000030086 | false | F014 | HA_FUN_STB_1,55x1,60x0,30_xxx | F014
Stb.-Einzelfundament | EG_Produktion_FFB | Stb.-Einzelfundament | EG_Produktion_FFB | 0114EFu0000030089 | false | F014 | HA_FUN_STB_1,55x1,60x0,30_xxx | F014
Stb.-Einzelfundament | EG_Produktion_FFB | Stb.-Einzelfundament | EG_Produktion_FFB | 0114EFu0000030093 | false | F012 | HA_FUN_STB_1,35x1,30x0,30_xxx | F012
Stb.-Einzelfundament | EG_Produktion_FFB | Stb.-Einzelfundament | EG_Produktion_FFB | 0114EFu0000030094 | false | F010 | HA_FUN_STB_1,10x1,10x0,30_xxx | F010
Stb.-Einzelfundament | EG_Produktion_FFB | Stb.-Einzelfundament | EG_Produktion_FFB | 0114EFu0000018268 | false | F012 | HA_FUN_STB_1,35x1,30x1,90_xxx | F012
Stb.-Einzelfundament | EG_Produktion_FFB | Stb.-Einzelfundament | EG_Produktion_FFB | 0114EFu0000019346 | false | F014 | HA_FUN_STB_1,55x1,60x0,30_xxx | F014 | AllplanAttributes - Voute links: 100; Voute rechts: 100; Voute vorne: 100; Voute hinten: 100
Stb.-Einzelfundament | EG_Produktion_FFB | Stb.-Einzelfundament | EG_Produktion_FFB | 0114EFu0000030249 | false | F012 | HA_FUN_STB_1,35x1,30x0,30_xxx | F012
Stb.-Einzelfundament | EG_Produktion_FFB | Stb.-Einzelfundament | EG_Produktion_FFB | 0114EFu0000030250 | false | F012 | HA_FUN_STB_1,35x1,30x0,30_xxx | F012
Stb.-Einzelfundament | EG_Produktion_FFB | Stb.-Einzelfundament | EG_Produktion_FFB | 0114EFu0000019357 | false | F014 | HA_FUN_STB_1,55x1,60x0,30_xxx | F014 | AllplanAttributes - Voute links: 100; Voute rechts: 100; Voute vorne: 100; Voute hinten: 100
Stb.-Einzelfundament | EG_Produktion_FFB | Stb.-Einzelfundament | EG_Produktion_FFB | 0114EFu0000030255 | false | F012 | HA_FUN_STB_1,35x1,30x0,30_xxx | F012
Stb.-Einzelfundament | EG_Produktion_FFB | Stb.-Einzelfundament | EG_Produktion_FFB | 0114EFu0000030262 | false | F014 | HA_FUN_STB_1,55x1,60x0,30_xxx | F014 | AllplanAttributes - Voute links: 100; Voute rechts: 100; Voute vorne: 100; Voute hinten: 100
Stb.-Einzelfundament | EG_Produktion_FFB | Stb.-Einzelfundament | EG_Produktion_FFB | 0114EFu0000030201 | false | F010 | HA_FUN_STB_1,10x1,10x0,30_xxx | F010
Stb.-Einzelfundament | EG_Produktion_FFB | Stb.-Einzelfundament | EG_Produktion_FFB | 0114EFu0000019286 | false | F010 | HA_FUN_STB_1,10x1,10x0,30_xxx | F010
Stb.-Einzelfundament | EG_Produktion_FFB | Stb.-Einzelfundament | EG_Produktion_FFB | 0114EFu0000030180 | false | F010 | HA_FUN_STB_1,10x1,10x0,30_xxx | F010
Stb.-Einzelfundament | EG_Produktion_FFB | Stb.-Einzelfundament | EG_Produktion_FFB | 0114EFu0000018964 | false | F012 | HA_FUN_STB_1,35x1,30x0,30_xxx | F012 | AllplanAttributes - Voute links: 100; Voute rechts: 100; Voute vorne: 100; Voute hinten: 100
Stb.-Einzelfundament | EG_Produktion_FFB | Stb.-Einzelfundament | EG_Produktion_FFB | 0114EFu0000030179 | false | F012 | HA_FUN_STB_1,35x1,30x0,30_xxx | F012
Stb.-Einzelfundament | EG_Produktion_FFB | Stb.-Einzelfundament | EG_Produktion_FFB | 0114EFu0000030183 | false | F016 | HA_FUN_STB_1,70x1,75x0,30_xxx | F016 | AllplanAttributes - Voute links: 100; Voute rechts: 100; Voute vorne: 100; Voute hinten: 100
Stb.-Einzelfundament | EG_Produktion_FFB | Stb.-Einzelfundament | EG_Produktion_FFB | 0114EFu0000030187 | false | F014 | HA_FUN_STB_1,55x1,60x0,30_xxx | F014 | AllplanAttributes - Voute links: 100; Voute rechts: 100; Voute vorne: 100; Voute hinten: 100
Stb.-Einzelfundament | EG_Produktion_FFB | Stb.-Einzelfundament | EG_Produktion_FFB | 0114EFu0000030195 | false | F010 | HA_FUN_STB_1,10x1,10x0,30_xxx | F010
Stb.-Einzelfundament | EG_Produktion_FFB | Stb.-Einzelfundament | EG_Produktion_FFB | 0114EFu0000030196 | false | F010 | HA_FUN_STB_1,10x1,10x0,30_xxx | F010
Stb.-Einzelfundament | EG_Produktion_FFB | Stb.-Einzelfundament | EG_Produktion_FFB | 0114EFu0000019494 | false | F012 | HA_FUN_STB_1,35x1,30x0,30_xxx | F012
Stb.-Einzelfundament | EG_Produktion_FFB | Stb.-Einzelfundament | EG_Produktion_FFB | 0114EFu0000019488 | false | F010 | HA_FUN_STB_1,10x1,10x0,30_xxx | F010
Stb.-Einzelfundament | EG_Produktion_FFB | Stb.-Einzelfundament | EG_Produktion_FFB | 0114EFu0000019477 | false | F010 | HA_FUN_STB_1,10x1,10x0,30_xxx | F010
Stb.-Einzelfundament | EG_Produktion_FFB | Stb.-Einzelfundament | EG_Produktion_FFB | 0114EFu0000019562 | false | F010 | HA_FUN_STB_1,10x1,10x1,65_xxx | F010 | AllplanAttributes - Voute links: 100; Voute rechts: 100; Voute vorne: 100; Voute hinten: 100
Stb.-Einzelfundament | EG_Produktion_FFB | Stb.-Einzelfundament | EG_Produktion_FFB | 0114EFu0000019559 | false | F010 | HA_FUN_STB_1,10x1,10x0,30_xxx | F010 | AllplanAttributes - Voute links: 100; Voute rechts: 100; Voute vorne: 100; Voute hinten: 100
Stb.-Einzelfundament | EG_Produktion_FFB | Stb.-Einzelfundament | EG_Produktion_FFB | 0114EFu0000019556 | false | F010 | HA_FUN_STB_1,10x1,10x0,30_xxx | F010 | AllplanAttributes - Voute links: 100; Voute rechts: 100; Voute vorne: 100; Voute hinten: 100
Stb.-Einzelfundament | EG_Produktion_FFB | Stb.-Einzelfundament | EG_Produktion_FFB | 0114EFu0000019549 | false | F010 | HA_FUN_STB_1,10x1,10x0,30_xxx | F010 | AllplanAttributes - Voute links: 100; Voute rechts: 100; Voute vorne: 100; Voute hinten: 100
Stb.-Einzelfundament | EG_Produktion_FFB | Stb.-Einzelfundament | EG_Produktion_FFB | 0114EFu0000030305 | false | F012 | HA_FUN_STB_1,35x1,30x0,30_xxx | F012 | AllplanAttributes - Voute links: 100; Voute rechts: 100; Voute vorne: 100; Voute hinten: 100
Stb.-Einzelfundament | EG_Produktion_FFB | Stb.-Einzelfundament | EG_Produktion_FFB | 0114EFu0000030310 | false | F012 | HA_FUN_STB_1,35x1,30x0,30_xxx | F012 | AllplanAttributes - Voute links: 100; Voute rechts: 100; Voute vorne: 100; Voute hinten: 100
Stb.-Einzelfundament | EG_Produktion_FFB | Stb.-Einzelfundament | EG_Produktion_FFB | 0114EFu0000019239 | false | F014 | HA_FUN_STB_1,55x1,60x0,30_xxx | F014
Stb.-Einzelfundament | EG_Produktion_FFB | Stb.-Einzelfundament | EG_Produktion_FFB | 0114EFu0000019273 | false | F010 | HA_FUN_STB_1,10x1,10x0,30_xxx | F010
Stb.-Einzelfundament | EG_Produktion_FFB | Stb.-Einzelfundament | EG_Produktion_FFB | 0114EFu0000018955 | false | F012 | HA_FUN_STB_1,35x1,30x0,30_xxx | F012
Stb.-Einzelfundament | EG_Produktion_FFB | Stb.-Einzelfundament | EG_Produktion_FFB | 0114EFu0000018538 | false | F010 | HA_FUN_STB_1,10x1,10x0,30_xxx | F010
Stb.-Einzelfundament | EG_Produktion_FFB | Stb.-Einzelfundament | EG_Produktion_FFB | 0114EFu0000018479 | false | F016 | HA_FUN_STB_1,70x1,75x0,30_xxx | F016
Stb.-Einzelfundament | EG_Produktion_FFB | Stb.-Einzelfundament | EG_Produktion_FFB | 0114EFu0000018466 | false | F010 | HA_FUN_STB_1,10x1,10x0,30_xxx | F010
Stb.-Einzelfundament | EG_Produktion_FFB | Stb.-Einzelfundament | EG_Produktion_FFB | 0114EFu0000018261 | false | F012 | HA_FUN_STB_1,35x1,30x1,90_xxx | F012 | AllplanAttributes - Voute links: 100; Voute rechts: 100; Voute vorne: 100; Voute hinten: 100
Stb.-Einzelfundament | EG_Produktion_FFB | Stb.-Einzelfundament | EG_Produktion_FFB | 0114EFu0000032828 | false | F012a | HA_FUN_STB_1,20x1,45x1,40_xxx | F012a | AllplanAttributes - Voute links: 100; Voute rechts: 100; Voute vorne: 100; Voute hinten: 100
Stb.-Einzelfundament | EG_Produktion_FFB | Stb.-Einzelfundament | EG_Produktion_FFB | 0114EFu0000019235 | false | F010 | HA_FUN_STB_1,10x1,10x0,30_xxx | F010
Stb.-Einzelfundament | EG_Produktion_FFB | Stb.-Einzelfundament | EG_Produktion_FFB | 0114EFu0000019202 | false | F010 | HA_FUN_STB_1,10x1,10x0,30_xxx | F010
Stb.-Einzelfundament | EG_Produktion_FFB | Stb.-Einzelfundament | EG_Produktion_FFB | 0114EFu0000018529 | false | F010 | HA_FUN_STB_1,10x1,10x0,30_xxx | F010
Stb.-Einzelfundament | EG_Produktion_FFB | Stb.-Einzelfundament | EG_Produktion_FFB | 0114EFu0000030177 | false | F016 | HA_FUN_STB_1,70x1,75x0,30_xxx | F016 | AllplanAttributes - Voute links: 100; Voute rechts: 100; Voute vorne: 100; Voute hinten: 100
Stb.-Einzelfundament | EG_Produktion_FFB | Stb.-Einzelfundament | EG_Produktion_FFB | 0114EFu0000030178 | false | F012 | HA_FUN_STB_1,35x1,30x1,90_xxx | F012
Stb.-Einzelfundament | EG_Produktion_FFB | Stb.-Einzelfundament | EG_Produktion_FFB | 0114EFu0000019232 | false | F014 | HA_FUN_STB_1,55x1,60x0,30_xxx | F014
Stb.-Einzelfundament | EG_Produktion_FFB | Stb.-Einzelfundament | EG_Produktion_FFB | 0114EFu0000030170 | false | F016 | HA_FUN_STB_1,70x1,75x0,30_xxx | F016 | AllplanAttributes - Voute links: 100; Voute rechts: 100; Voute vorne: 100; Voute hinten: 100
Stb.-Einzelfundament | EG_Produktion_FFB | Stb.-Einzelfundament | EG_Produktion_FFB | 0114EFu0000018522 | false | F018 | HA_FUN_STB_2,00x2,15x0,40_xxx | F018
Stb.-Einzelfundament | EG_Produktion_FFB | Stb.-Einzelfundament | EG_Produktion_FFB | 0114EFu0000018259 | false | F012a | HA_FUN_STB_1,20x1,45x1,40_xxx | F012a | AllplanAttributes - Voute links: 100; Voute rechts: 100; Voute vorne: 100; Voute hinten: 100
Stb.-Einzelfundament | EG_Produktion_FFB | Stb.-Einzelfundament | EG_Produktion_FFB | 0114EFu0000018242 | false | F012a | HA_FUN_STB_1,20x1,45x1,40_xxx | F012a | AllplanAttributes - Voute links: 100; Voute rechts: 100; Voute vorne: 100; Voute hinten: 100
Stb.-Einzelfundament | EG_Produktion_FFB | Stb.-Einzelfundament | EG_Produktion_FFB | 0114EFu0000029962 | false | F012 | HA_FUN_STB_1,35x1,30x1,60_xxx | F012
Stb.-Einzelfundament | EG_Produktion_FFB | Stb.-Einzelfundament | EG_Produktion_FFB | 0114EFu0000018192 | false | F010 | HA_FUN_STB_1,10x1,10x1,60_xxx | F014a | AllplanAttributes - Voute links: 100; Voute rechts: 100; Voute vorne: 100; Voute hinten: 100
Stb.-Einzelfundament | EG_Produktion_FFB | Stb.-Einzelfundament | EG_Produktion_FFB | 0114EFu0000018012 | false | F012 | HA_FUN_STB_1,35x1,30x0,30_xxx | F012
Stb.-Einzelfundament | EG_Produktion_FFB | Stb.-Einzelfundament | EG_Produktion_FFB | 0114EFu0000018541 | false | F016 | HA_FUN_STB_1,70x1,75x0,30_xxx | F016
Stb.-Einzelfundament | EG_Produktion_FFB | Stb.-Einzelfundament | EG_Produktion_FFB | 0114EFu0000030099 | false | F010 | HA_FUN_STB_1,10x1,10x0,30_xxx | F014a | AllplanAttributes - Voute links: 100; Voute rechts: 100; Voute vorne: 100; Voute hinten: 100
Stb.-Einzelfundament | EG_Produktion_FFB | Stb.-Einzelfundament | EG_Produktion_FFB | 0114EFu0000019010 | false | F016 | HA_FUN_STB_1,70x1,75x0,30_xxx | F016 | AllplanAttributes - Voute links: 100; Voute rechts: 100; Voute vorne: 100; Voute hinten: 100
Stb.-Einzelfundament | EG_Produktion_FFB | Stb.-Einzelfundament | EG_Produktion_FFB | 0114EFu0000030148 | false | F012b | HA_FUN_STB_1,10x1,60x2,30_xxx | F012b | AllplanAttributes - Voute links: 100; Voute rechts: 100; Voute vorne: 100; Voute hinten: 100
Stb.-Einzelfundament | EG_Produktion_FFB | Stb.-Einzelfundament | EG_Produktion_FFB | 0114EFu0000019178 | false | F010 | HA_FUN_STB_1,10x1,10x0,30_xxx | F010
Stb.-Einzelfundament | EG_Produktion_FFB | Stb.-Einzelfundament | EG_Produktion_FFB | 0114EFu0000019218 | false | F012 | HA_FUN_STB_1,35x1,30x0,30_xxx | F012
Stb.-Einzelfundament | EG_Produktion_FFB | Stb.-Einzelfundament | EG_Produktion_FFB | 0114EFu0000019207 | false | F012 | HA_FUN_STB_1,35x1,30x0,30_xxx | F012
Stb.-Einzelfundament | EG_Produktion_FFB | Stb.-Einzelfundament | EG_Produktion_FFB | 0114EFu0000019307 | false | F016 | HA_FUN_STB_1,70x1,75x0,30_xxx | F016 | AllplanAttributes - Voute links: 100; Voute rechts: 100; Voute vorne: 100; Voute hinten: 100
Stb.-Einzelfundament | EG_Produktion_FFB | Stb.-Einzelfundament | EG_Produktion_FFB | 0114EFu0000019371 | false | F010 | HA_FUN_STB_1,10x1,10x1,80_xxx | F010 | AllplanAttributes - Voute links: 100; Voute rechts: 100; Voute vorne: 100; Voute hinten: 100
Stb.-Einzelfundament | EG_Produktion_FFB | Stb.-Einzelfundament | EG_Produktion_FFB | 0114EFu0000019388 | false | F012 | HA_FUN_STB_1,35x1,30x0,30_xxx | F012 | AllplanAttributes - Voute links: 100; Voute rechts: 100; Voute vorne: 100; Voute hinten: 100
Stb.-Einzelfundament | EG_Produktion_FFB | Stb.-Einzelfundament | EG_Produktion_FFB | 0114EFu0000030297 | false | F012 | HA_FUN_STB_1,35x1,30x0,30_xxx | F012 | AllplanAttributes - Voute links: 100; Voute rechts: 100; Voute vorne: 100; Voute hinten: 100
Stb.-Einzelfundament | EG_Produktion_FFB | Stb.-Einzelfundament | EG_Produktion_FFB | 0114EFu0000030298 | false | F012 | HA_FUN_STB_1,35x1,30x0,30_xxx | F012 | AllplanAttributes - Voute links: 100; Voute rechts: 100; Voute vorne: 100; Voute hinten: 100
Stb.-Einzelfundament | EG_Produktion_FFB | Stb.-Einzelfundament | EG_Produktion_FFB | 0114EFu0000019425 | false | F010 | HA_FUN_STB_1,10x1,10x0,30_xxx | F010
Stb.-Einzelfundament | EG_Produktion_FFB | Stb.-Einzelfundament | EG_Produktion_FFB | 0114EFu0000019460 | false | F010 | HA_FUN_STB_1,10x1,10x0,30_xxx | F010
Stb.-Einzelfundament | EG_Produktion_FFB | Stb.-Einzelfundament | EG_Produktion_FFB | 0114EFu0000019534 | false | F010 | HA_FUN_STB_1,10x1,10x0,30_xxx | F010 | AllplanAttributes - Voute links: 100; Voute rechts: 100; Voute vorne: 100; Voute hinten: 100
Stb.-Einzelfundament | EG_Produktion_FFB | Stb.-Einzelfundament | EG_Produktion_FFB | 0114EFu0000019529 | false | F010 | HA_FUN_STB_1,10x1,10x0,30_xxx | F010 | AllplanAttributes - Voute links: 100; Voute rechts: 100; Voute vorne: 100; Voute hinten: 100
Stb.-Einzelfundament | EG_Produktion_FFB | Stb.-Einzelfundament | EG_Produktion_FFB | 0114EFu0000019524 | false | F010 | HA_FUN_STB_1,10x1,10x0,30_xxx | F010 | AllplanAttributes - Voute links: 100; Voute rechts: 100; Voute vorne: 100; Voute hinten: 100
Stb.-Einzelfundament | EG_Produktion_FFB | Stb.-Einzelfundament | EG_Produktion_FFB | 0114EFu0000019519 | false | F010 | HA_FUN_STB_1,10x1,10x0,30_xxx | F010 | AllplanAttributes - Voute links: 100; Voute rechts: 100; Voute vorne: 100; Voute hinten: 100
Stb.-Einzelfundament | EG_Produktion_FFB | Stb.-Einzelfundament | EG_Produktion_FFB | 0114EFu0000019512 | false | F010 | HA_FUN_STB_1,10x1,10x0,30_xxx | F010 | AllplanAttributes - Voute links: 100; Voute rechts: 100; Voute vorne: 100; Voute hinten: 100
Stb.-Einzelfundament | EG_Produktion_FFB | Stb.-Einzelfundament | EG_Produktion_FFB | 0114EFu0000019565 | false | F010 | HA_FUN_STB_1,10x1,10x0,80_xxx | F010 | AllplanAttributes - Voute links: 100; Voute rechts: 100; Voute vorne: 100; Voute hinten: 100
Stb.-Einzelfundament | EG_Produktion_FFB | Stb.-Einzelfundament | EG_Produktion_FFB | 0114EFu0000017951 | false | F012 | HA_FUN_STB_1,35x1,30x0,30_xxx | F012
Stb.-Einzelfundament | EG_Produktion_FFB | Stb.-Einzelfundament | EG_Produktion_FFB | 0114EFu0000030092 | false | F012 | HA_FUN_STB_1,35x1,30x0,30_xxx | F012
Stb.-Einzelfundament | EG_Produktion_FFB | Stb.-Einzelfundament | EG_Produktion_FFB | 0114EFu0000030186 | false | F012 | HA_FUN_STB_1,35x1,30x0,30_xxx | F012
Stb.-Einzelfundament | EG_Produktion_FFB | Stb.-Einzelfundament | EG_Produktion_FFB | 0114EFu0000035577 | false | F012 | HA_FUN_STB_1,35x1,30x0,30_xxx | F012
Stb.-Einzelfundament | EG_Produktion_FFB | Stb.-Einzelfundament | EG_Produktion_FFB | 0114EFu0000018033 | false | F010 | HA_FUN_STB_1,10x1,10x2,30_xxx | F010a | AllplanAttributes - Voute links: 100; Voute rechts: 100; Voute vorne: 100; Voute hinten: 100
Stb.-Einzelfundament | EG_Produktion_FFB | Stb.-Einzelfundament | EG_Produktion_FFB | 0114EFu0000018262 | false | F010 | HA_FUN_STB_1,10x1,10x1,50_xxx | F010a
Stb.-Einzelfundament | EG_Produktion_FFB | Stb.-Einzelfundament | EG_Produktion_FFB | 0114EFu0000018548 | false | F010 | HA_FUN_STB_1,10x1,10x2,30_xxx | F012b | AllplanAttributes - Voute links: 100; Voute rechts: 100; Voute vorne: 100; Voute hinten: 100
Stb.-Einzelfundament | EG_Produktion_FFB | Stb.-Einzelfundament | EG_Produktion_FFB | 0114EFu0000030023 | false | F014 | HA_FUN_STB_1,60x1,55x1,95_xxx | F016 | AllplanAttributes - Voute links: 100; Voute rechts: 100; Voute vorne: 100; Voute hinten: 100
Stb.-Einzelfundament | EG_Produktion_FFB | Stb.-Einzelfundament | EG_Produktion_FFB | 0114EFu0000018726 | false | F014a | HA_FUN_STB_1,20x2,05x1,50_xxx | F016a | AllplanAttributes - Voute links: 100; Voute rechts: 100; Voute vorne: 100; Voute hinten: 100
Stb.-Einzelfundament | EG_Produktion_FFB | Stb.-Einzelfundament | EG_Produktion_FFB | 0114EFu0000018763 | false | F014a | HA_FUN_STB_1,20x2,05x1,65_xxx | F014b | AllplanAttributes - Voute links: 100; Voute rechts: 100; Voute vorne: 100; Voute hinten: 100
Stb.-Einzelfundament | EG_Produktion_FFB | Stb.-Einzelfundament | EG_Produktion_FFB | 0114EFu0000030052 | false | F012a | HA_FUN_STB_1,20x1,45x1,65_xxx | F014b | AllplanAttributes - Voute links: 100; Voute rechts: 100; Voute vorne: 100; Voute hinten: 100
Stb.-Einzelfundament | EG_Produktion_FFB | Stb.-Einzelfundament | EG_Produktion_FFB | 0114EFu0000030055 | false | F014a | HA_FUN_STB_1,20x2,05x2,30_xxx | F012a | AllplanAttributes - Voute links: 100; Voute rechts: 100; Voute vorne: 100; Voute hinten: 100
Stb.-Einzelfundament | EG_Produktion_FFB | Stb.-Einzelfundament | EG_Produktion_FFB | 0114EFu0000030102 | false | F012 | HA_FUN_STB_1,30x1,35x0,30_xxx | F014a | AllplanAttributes - Voute links: 100; Voute rechts: 100; Voute vorne: 100; Voute hinten: 100
Stb.-Einzelfundament | EG_Produktion_FFB | Stb.-Einzelfundament | EG_Produktion_FFB | 0114EFu0000030126 | false | F018 | HA_FUN_STB_2,15x2,00x0,40_xxx | F016 | AllplanAttributes - Voute links: 100; Voute rechts: 100; Voute vorne: 100; Voute hinten: 100
Stb.-Einzelfundament | EG_Produktion_FFB | Stb.-Einzelfundament | EG_Produktion_FFB | 0114EFu0000030103 | false | F012 | HA_FUN_STB_1,30x1,35x0,30_xxx | F014a | AllplanAttributes - Voute links: 100; Voute rechts: 100; Voute vorne: 100; Voute hinten: 100
Stb.-Einzelfundament | EG_Produktion_FFB | Stb.-Einzelfundament | EG_Produktion_FFB | 0114EFu0000036417 | false | F012 | HA_FUN_STB_1,35x1,30x0,30_xxx | F012
Stb.-Einzelfundament | EG_Produktion_FFB | Stb.-Einzelfundament | EG_Produktion_FFB | 0114EFu0000036418 | false | F010 | HA_FUN_STB_1,10x1,10x0,30_xxx | F010
Stb.-Einzelfundament | EG_Produktion_FFB | Stb.-Einzelfundament | EG_Produktion_FFB | 0114EFu0000036420 | false | F012 | HA_FUN_STB_1,35x1,30x0,30_xxx | F012
Stb.-Einzelfundament | EG_Produktion_FFB | Stb.-Einzelfundament | EG_Produktion_FFB | 0114EFu0000019539 | false | F012 | HA_FUN_STB_1,30x1,35x0,30_xxx | F010 | AllplanAttributes - Voute links: 100; Voute rechts: 100; Voute vorne: 100; Voute hinten: 100
Stb.-Einzelfundament | EG_Produktion_FFB | Stb.-Einzelfundament | EG_Produktion_FFB | 0114EFu0000019544 | false | F014 | HA_FUN_STB_1,60x1,55x0,55_xxx | F012 | AllplanAttributes - Voute links: 100; Voute rechts: 100; Voute vorne: 100; Voute hinten: 100
Stb.-Einzelfundament | EG_Produktion_FFB | Stb.-Einzelfundament | EG_Produktion_FFB | 0114EFu0000036431 | false | F012 | HA_FUN_STB_1,35x1,30x0,30_xxx | F012
Stb.-Einzelfundament | EG_Produktion_FFB | Stb.-Einzelfundament | EG_Produktion_FFB | 0114EFu0000032401 | false | F010 | HA_FUN_STB_1,13x1,17x2,00_xxx | F014a | AllplanAttributes - Voute links: 100; Voute rechts: 100; Voute vorne: 100; Voute hinten: 100
Stb.-Einzelfundament | EG_Produktion_FFB | Stb.-Einzelfundament | EG_Produktion_FFB | 0114EFu0000019238 | false | F010 | HA_FUN_STB_1,10x1,10x0,30_xxx | F010
Stb.-Einzelfundament | EG_Produktion_FFB | Stb.-Einzelfundament | EG_Produktion_FFB | 0114EFu0000032372 | false | F010 | HA_FUN_STB_1,40x1,22x2,00_xxx | F014a | AllplanAttributes - Voute links: 100; Voute rechts: 100; Voute vorne: 100; Voute hinten: 100
Stb.-Einzelfundament | EG_Produktion_FFB | Stb.-Einzelfundament | EG_Produktion_FFB | 0114EFu0000030243 | false | F012 | HA_FUN_STB_1,35x1,30x0,30_xxx | F012
Stb.-Einzelfundament | EG_Produktion_FFB | Stb.-Einzelfundament | EG_Produktion_FFB | 0114EFu0000019320 | false | F012 | HA_FUN_STB_1,35x1,30x0,30_xxx | F012

# IfcMember: BRACE (38)
In: EG_Technik_FFB
Material: S235
AllplanAttributes - Gewerk: Stahlbauarbeiten; Bezeichnung: Zugdiagonale; Material: S235; Profilname: ø0.008; Mantelfläche/lfm: 0.0502655; Ebene: EG_Technik_FFB; Objektdrehwinkel: 0; Schema: BR$; Startnummer: 1; Attributset-Objekt: Stab; Schwerpunkt X: 0.008 m; Schwerpunkt Y: 0.008 m; Abrechnungsart: m
IFC_Pset_TWP - Phase erstellt: Neubau; Name: Zugdiagonale; Material: Stahl; statisch tragend: true; Außenbauteil: true; Kommentar: -
Pset_FM-Vivantes - FM_Klasse: -; FM_Bezeichnung: -; FM_AKS: -; FM_Anzahl: -; FM_Standort: -; FM_Hersteller: -; FM_Hersteller-Typ: -; FM_Seriennummer: -; FM_Baujahr: -; FM_Inbetriebnahme Datum: -; FM_Gewährleistungsende: -; FM_Gewährleistungsgeber: -; FM_Betriebsstatus: -; FM_Prüfpflicht: -; FM_Prüfintervall: -; FM_letzter Prüfungstermin: -; FM_Sammelobjekt: -; FM_rechn. Lebensdauer: -; FM_rechn. Lebensende: -; FM_technischer Zustand: -; FM_voraus. Lebensende: -; FM_Eigentümer: -; FM_Bemerkung: -; FM_Versorgungsbereich-Wirkbereich: -; FM_Zugänglichkeit: -
Pset_MemberCommon - Reference: HA_UZV_RND_016_STA_0,016_xxx
Name | Achsenstartpunkt (X) (m) = Achsenendpunkt (X) (m) | Achsenstartpunkt (Y) (m) | Achsenstartpunkt (Z) (m) | Achsenendpunkt (Y) (m) | Achsenendpunkt (Z) (m) | Allright_Bauteil_ID | Positionsnummer
Zugdiagonale | 109.99 | 92.246 | 6.726 | 87.479 | 4.089 | 0103Tra0000001034 | AQV01.1
Zugdiagonale | 109.99 | 92.246 | 3.998 | 87.479 | 1.361 | 0103Tra0000001029 | AQV01.1
Zugdiagonale | 110.01 | 87.479 | 6.726 | 92.246 | 4.089 | 0103Tra0000001035 | AQV01.1
Zugdiagonale | 110.01 | 87.479 | 3.998 | 92.246 | 1.361 | 0103Tra0000001032 | AQV01.1
Zugdiagonale | 103.74 | 92.246 | 6.726 | 87.479 | 4.089 | 0103Tra0000004025 | AQV01.1
Zugdiagonale | 103.74 | 92.246 | 3.998 | 87.479 | 1.361 | 0103Tra0000004026 | AQV01.1
Zugdiagonale | 103.76 | 87.479 | 6.726 | 92.246 | 4.089 | 0103Tra0000004027 | AQV01.1
Zugdiagonale | 103.76 | 87.479 | 3.998 | 92.246 | 1.361 | 0103Tra0000004028 | AQV01.1
Zugdiagonale | 97.487 | 92.246 | 6.726 | 87.479 | 4.089 | 0103Tra0000004055 | AQV01.1
Zugdiagonale | 97.487 | 92.246 | 3.998 | 87.479 | 1.361 | 0103Tra0000004057 | AQV01.1
Zugdiagonale | 97.507 | 87.479 | 6.726 | 92.246 | 4.089 | 0103Tra0000004059 | AQV01.1
Zugdiagonale | 97.507 | 87.479 | 3.998 | 92.246 | 1.361 | 0103Tra0000004061 | AQV01.1
Zugdiagonale | 91.237 | 92.246 | 6.726 | 87.479 | 4.089 | 0103Tra0000004097 | AQV01.1
Zugdiagonale | 91.237 | 92.246 | 3.998 | 87.479 | 1.361 | 0103Tra0000004099 | AQV01.1
Zugdiagonale | 91.257 | 87.479 | 6.726 | 92.246 | 4.089 | 0103Tra0000004101 | AQV01.1
Zugdiagonale | 91.257 | 87.479 | 3.998 | 92.246 | 1.361 | 0103Tra0000004103 | AQV01.1
Zugdiagonale | 84.993 | 92.246 | 6.726 | 87.479 | 4.089 | 0103Tra0000004139 | AQV01.1
Zugdiagonale | 84.993 | 92.246 | 3.998 | 87.479 | 1.361 | 0103Tra0000004141 | AQV01.1
Zugdiagonale | 85.013 | 87.479 | 6.726 | 92.246 | 4.089 | 0103Tra0000004143 | AQV01.1
Zugdiagonale | 85.013 | 87.479 | 3.998 | 92.246 | 1.361 | 0103Tra0000004145 | AQV01.1
Zugdiagonale | 78.74 | 92.246 | 6.726 | 87.479 | 4.089 | 0103Tra0000004181 | AQV01.1
Zugdiagonale | 78.74 | 92.246 | 3.998 | 87.479 | 1.361 | 0103Tra0000004183 | AQV01.1
Zugdiagonale | 78.76 | 87.479 | 6.726 | 92.246 | 4.089 | 0103Tra0000004185 | AQV01.1
Zugdiagonale | 78.76 | 87.479 | 3.998 | 92.246 | 1.361 | 0103Tra0000004187 | AQV01.1
Zugdiagonale | 72.49 | 92.246 | 6.726 | 87.479 | 4.089 | 0103Tra0000004223 | AQV01.1
Zugdiagonale | 72.49 | 92.246 | 3.998 | 87.479 | 1.361 | 0103Tra0000004225 | AQV01.1
Zugdiagonale | 72.51 | 87.479 | 6.726 | 92.246 | 4.089 | 0103Tra0000004227 | AQV01.1
Zugdiagonale | 72.51 | 87.479 | 3.998 | 92.246 | 1.361 | 0103Tra0000004229 | AQV01.1
Zugdiagonale | 69.654 | 92.246 | 6.726 | 87.479 | 4.089 | 0103Tra0000004265 | AQV01.2
Zugdiagonale | 69.654 | 92.246 | 3.998 | 87.479 | 1.361 | 0103Tra0000004267 | AQV01.2
Zugdiagonale | 69.674 | 87.479 | 6.726 | 92.246 | 4.089 | 0103Tra0000004269 | AQV01.2
Zugdiagonale | 69.674 | 87.479 | 3.998 | 92.246 | 1.361 | 0103Tra0000004271 | AQV01.2
Zugdiagonale | 59.99 | 91.196 | 4.021 | 87.479 | 1.361 | 0103Tra0000002558 | AQV02.1
Zugdiagonale | 60.01 | 87.479 | 4.021 | 91.196 | 1.361 | 0103Tra0000002560 | AQV02.1
Zugdiagonale | 53.74 | 91.196 | 4.021 | 87.479 | 1.361 | 0103Tra0000004363 | AQV02.1
Zugdiagonale | 53.76 | 87.479 | 4.021 | 91.196 | 1.361 | 0103Tra0000004365 | AQV02.1
Zugdiagonale | 47.49 | 91.196 | 4.021 | 87.479 | 1.361 | 0103Tra0000004445 | AQV02.1
Zugdiagonale | 47.51 | 87.479 | 4.021 | 91.196 | 1.361 | 0103Tra0000004447 | AQV02.1

# IfcOpeningElement: SOLIDWALL (35)
AllplanAttributes - Object Layer Attributes #1, 2D Interaktion: yes; Object Layer Attributes #1, Abrechnungsart: m³
IFC_Pset_TWP - Kommentar: -; Phase erstellt: Neubau
Pset_ConcreteElementGeneral - WU-Beton: false
Pset_FM-Vivantes - FM_Klasse: -; FM_Bezeichnung: -; FM_AKS: -; FM_Anzahl: -; FM_Standort: -; FM_Hersteller: -; FM_Hersteller-Typ: -; FM_Seriennummer: -; FM_Baujahr: -; FM_Inbetriebnahme Datum: -; FM_Gewährleistungsende: -; FM_Gewährleistungsgeber: -; FM_Betriebsstatus: -; FM_Prüfpflicht: -; FM_Prüfintervall: -; FM_letzter Prüfungstermin: -; FM_Sammelobjekt: -; FM_rechn. Lebensdauer: -; FM_rechn. Lebensende: -; FM_technischer Zustand: -; FM_voraus. Lebensende: -; FM_Eigentümer: -; FM_Bemerkung: -; FM_Versorgungsbereich-Wirkbereich: -; FM_Zugänglichkeit: -
Pset_OpeningElementCommon - FireExit: no
Name | In | Object Layer Attributes #1, Codetext | Object Layer Attributes #1, Gewerk | Object Layer Attributes #1, Türanschlag | Object Layer Attributes #1, Text1 | Object Layer Attributes #1, Text2 | Object Layer Attributes #1, Bezeichnung | Object Layer Attributes #1, Material | Object Layer Attributes #1, Raumhohe Wand | Object Layer Attributes #1, Ebene | Object Layer Attributes #1, Allright_Bauteil_ID | Name | Material | statisch tragend | Herstellung | Außenbauteil | Positionsnummer | Bewehrungsgrad | Expositionsklasse | Druckfestigkeitsklasse | ProtectedOpening | Reference
Mauerwerkswand | EG_Technik_FFB | WI-KALKSAND2\ | Mauerarbeiten | - | Pos | Typ | Mauerwerkswand | KS-XL-16-1.8/DM | yes | EG_Technik_FFB | 0101Tür0000000111 | Mauerwerkswand | Mauerwerk | true | Mauerwerk | false | W001.2 | 0 | - | - | yes | HA_WAN_MWK_0,240_xxx
Mauerwerkswand | EG_Technik_FFB | WI-KALKSAND2\ | Mauerarbeiten | - | Pos | Typ | Mauerwerkswand | KS-XL-16-1.8/DM | yes | EG_Technik_FFB | 0101Tür0000000123 | Mauerwerkswand | Mauerwerk | true | Mauerwerk | false | W001.1 | 0 | - | - | yes | HI_WAN_MWK_0,240_xxx
Mauerwerkswand | EG_Technik_FFB | WI-KALKSAND2\ | Mauerarbeiten | - | Pos | Typ | Mauerwerkswand | KS-XL-16-1.8/DM | yes | EG_Technik_FFB | 0101Tür0000000121 | Mauerwerkswand | Mauerwerk | true | Mauerwerk | false | W001.1 | 0 | - | - | yes | HI_WAN_MWK_0,240_xxx
Mauerwerkswand | EG_Technik_FFB | WI-KALKSAND2\ | Mauerarbeiten | - | Pos | Typ | Mauerwerkswand | KS-XL-16-1.8/DM | yes | EG_Technik_FFB | 0101Tür0000000113 | Mauerwerkswand | Mauerwerk | true | Mauerwerk | false | W001.2 | 0 | - | - | yes | HA_WAN_MWK_0,240_xxx
Mauerwerkswand | EG_Technik_FFB | WI-KALKSAND2\ | Mauerarbeiten | - | Pos | Typ | Mauerwerkswand | KS-XL-16-1.8/DM | yes | EG_Technik_FFB | 0101Tür0000000125 | Mauerwerkswand | Mauerwerk | true | Mauerwerk | false | W001.2 | 0 | - | - | yes | HA_WAN_MWK_0,240_xxx
Mauerwerkswand | EG_Technik_FFB | WI-KALKSAND2\ | Mauerarbeiten | - | Pos | Typ | Mauerwerkswand | KS-XL-16-1.8/DM | yes | EG_Technik_FFB | 0101Tür0000000127 | Mauerwerkswand | Mauerwerk | true | Mauerwerk | false | W001.2 | 0 | - | - | yes | HA_WAN_MWK_0,240_xxx
Mauerwerkswand | EG_Technik_FFB | WI-KALKSAND2\ | Mauerarbeiten | - | Pos | Typ | Mauerwerkswand | KS-XL-16-1.8/DM | yes | EG_Technik_FFB | 0101Tür0000006902 | Mauerwerkswand | Mauerwerk | true | Mauerwerk | false | W001.2 | 0 | - | - | yes | HA_WAN_MWK_0,240_xxx
Mauerwerkswand | EG_Technik_FFB | WI-KALKSAND2\ | Mauerarbeiten | - | Pos | Typ | Mauerwerkswand | KS-XL-16-1.8/DM | yes | EG_Technik_FFB | 0101Tür0000000093 | Mauerwerkswand | Mauerwerk | true | Mauerwerk | false | - | 0 | - | - | yes | HI_WAN_MWK_0,240_xxx
Mauerwerkswand | EG_Technik_FFB | WI-KALKSAND2\ | Mauerarbeiten | - | Pos | Typ | Mauerwerkswand | KS-XL-16-1.8/DM | yes | EG_Technik_FFB | 0101Tür0000000095 | Mauerwerkswand | Mauerwerk | true | Mauerwerk | false | W001.1 | 0 | - | - | yes | HI_WAN_MWK_0,240_xxx
Mauerwerkswand | EG_Technik_FFB | WI-KALKSAND2\ | Mauerarbeiten | - | Pos | Typ | Mauerwerkswand | KS-XL-16-1.8/DM | yes | EG_Technik_FFB | 0101Tür0000000097 | Mauerwerkswand | Mauerwerk | true | Mauerwerk | false | W001.1 | 0 | - | - | yes | HI_WAN_MWK_0,240_xxx
Mauerwerkswand | EG_Technik_FFB | WI-KALKSAND2\ | Mauerarbeiten | - | Pos | Typ | Mauerwerkswand | KS-XL-16-1.8/DM | yes | EG_Technik_FFB | 0101Tür0000000101 | Mauerwerkswand | Mauerwerk | true | Mauerwerk | false | W001.1 | 0 | - | - | yes | HI_WAN_MWK_0,240_xxx
Mauerwerkswand | EG_Technik_FFB | WI-KALKSAND2\ | Mauerarbeiten | - | Pos | Typ | Mauerwerkswand | KS-XL-16-1.8/DM | yes | EG_Technik_FFB | 0101Tür0000000103 | Mauerwerkswand | Mauerwerk | true | Mauerwerk | false | W001.1 | 0 | - | - | yes | HI_WAN_MWK_0,240_xxx
Mauerwerkswand | EG_Technik_FFB | WI-KALKSAND2\ | Mauerarbeiten | - | Pos | Typ | Mauerwerkswand | KS-XL-16-1.8/DM | yes | EG_Technik_FFB | 0101Tür0000005913 | Mauerwerkswand | Mauerwerk | true | Mauerwerk | false | W001.1 | 0 | - | - | yes | HI_WAN_MWK_0,240_xxx
Mauerwerkswand | EG_Technik_FFB | WI-KALKSAND2\ | Mauerarbeiten | - | Pos | Typ | Mauerwerkswand | KS-XL-16-1.8/DM | yes | EG_Technik_FFB | 0101Tür0000000115 | Mauerwerkswand | Mauerwerk | false | Mauerwerk | false | W001.1 | 0 | - | - | yes | HI_WAN_MWK_0,240_xxx
Mauerwerkswand | EG_Technik_FFB | WI-KALKSAND2\ | Mauerarbeiten | - | Pos | Typ | Mauerwerkswand | KS-XL-16-1.8/DM | yes | EG_Technik_FFB | 0101Tür0000000117 | Mauerwerkswand | Mauerwerk | false | Mauerwerk | false | W001.1 | 0 | - | - | yes | HI_WAN_MWK_0,240_xxx
Mauerwerkswand | EG_Technik_FFB | WI-KALKSAND2\ | Mauerarbeiten | - | Pos | Typ |  | KS-XL-16-1.8/DM | yes | EG_Technik_FFB | 0101Tür0000007548 | Mauerwerkswand | Mauerwerk | true | Mauerwerk | false | W001.1 | 0 | - | - | yes | HI_WAN_MWK_0,240_xxx
Mauerwerkswand | EG_Technik_FFB | WI-KALKSAND2\ | Mauerarbeiten | - | Pos | Typ | Mauerwerkswand | KS-XL-16-1.8/DM | yes | EG_Technik_FFB | 0101Tür0000006672 | Mauerwerkswand | Mauerwerk | true | Mauerwerk | false | W001.1 | 0 | - | - | yes | HI_WAN_MWK_0,240_xxx
Mauerwerkswand | EG_Technik_FFB | WI-KALKSAND2\ | Mauerarbeiten | - | Pos | Typ | Mauerwerkswand | KS-XL-16-1.8/DM | yes | EG_Technik_FFB | 0101Tür0000000107 | Mauerwerkswand | Mauerwerk | true | Mauerwerk | false | W001.1 | 0 | - | - | yes | HI_WAN_MWK_0,240_xxx
Mauerwerkswand | EG_Technik_FFB | WI-KALKSAND2\ | Mauerarbeiten | - | Pos | Typ | Mauerwerkswand | KS-XL-16-1.8/DM | yes | EG_Technik_FFB | 0101Tür0000000109 | Mauerwerkswand | Mauerwerk | true | Mauerwerk | false | W001.1 | 0 | - | - | yes | HI_WAN_MWK_0,240_xxx
Mauerwerkswand | EG_Technik_FFB | WI-KALKSAND2\ | Mauerarbeiten | - | Pos | Typ | Mauerwerkswand | KS-XL-16-1.8/DM | yes | EG_Technik_FFB | 0101Tür0000000129 | Mauerwerkswand | Mauerwerk | true | Mauerwerk | false | - | 0 | - | - | yes | HI_WAN_MWK_0,240_xxx
Mauerwerkswand | EG_Technik_FFB | WI-KALKSAND2\ | Mauerarbeiten | - | Pos | Typ | Mauerwerkswand | KS-XL-16-1.8/DM | yes | EG_Technik_FFB | 0101Tür0000007007 | Mauerwerkswand | Mauerwerk | true | Mauerwerk | false | - | 0 | - | - | yes | HA_WAN_MWK_0,240_xxx
HA_TÜR_DRE | EG_Produktion_FFB |  | Betonarbeiten | - |  |  |  | Stahlbeton |  | EG_Produktion_FFB | 0111Tür0000000632 | Stb.-Außenwand | Stahlbeton | true | Ortbeton | true | W003 | 50 | XC4, XD1, XF2, WF | C35/45 | yes | HA_TÜR_DRE | AllplanAttributes - Object Layer Attributes #1, Attributset-Objekt: Wand; Pset_ConcreteElementGeneral - Betonüberdeckung: 1; Pset_OpeningElementCommon - Purpose: Türöffnung
HA_FEN | EG_Produktion_FFB |  | Betonarbeiten |  |  |  |  | Stahlbeton |  | EG_Produktion_FFB | 0111Fen0000000693 | Stb.-Außenwand | Stahlbeton | true | Ortbeton | true | W003 | 50 | XC4, XD1, XF2, WF | C35/45 | yes | HA_FEN | AllplanAttributes - Object Layer Attributes #1, Attributset-Objekt: Wand; Pset_ConcreteElementGeneral - Betonüberdeckung: 1; Pset_OpeningElementCommon - Purpose: Fensteröffnung
Wandnische | EG_Produktion_FFB | n.a. | Betonarbeiten |  |  |  |  | Stahlbeton |  | EG_Produktion_FFB | 0111Wni0000619900 | Stb.-Außenwand | Stahlbeton | true | Ortbeton | true | W003 | 50 | XC4, XD1, XF2, WF | C35/45 |  | Aussparung | AllplanAttributes - Object Layer Attributes #1, Attributset-Objekt: Wand; Object Layer Attributes #1, Versatz_oben: 0; Object Layer Attributes #1, Versatz_unten: 0; Object Layer Attributes #1, Barrierefrei: no; Object Layer Attributes #1, Fluchtweg: no; Object Layer Attributes #1, Brandabschnittsdefinierendes Bauteil: no; Pset_ConcreteElementGeneral - Betonüberdeckung: 1; Pset_OpeningElementCommon - Purpose: Aussparung
HA_TÜR_DRE | EG_Produktion_FFB |  | Betonarbeiten | - |  |  |  | Stahlbeton |  | EG_Produktion_FFB | 0111Tür0000000664 | Stb.-Außenwand | Stahlbeton | true | Ortbeton | true | W003 | 50 | XC4, XD1, XF2, WF | C35/45 | yes | HA_TÜR_DRE | AllplanAttributes - Object Layer Attributes #1, Attributset-Objekt: Wand; Pset_ConcreteElementGeneral - Betonüberdeckung: 1; Pset_OpeningElementCommon - Purpose: Türöffnung
Wandnische | EG_Produktion_FFB | n.a. | Betonarbeiten |  |  |  |  | Stahlbeton |  | EG_Produktion_FFB | 0111Wni0000619888 | Stb.-Außenwand | Stahlbeton | true | Ortbeton | true | W003 | 50 | XC4, XD1, XF2, WF | C35/45 |  | Aussparung | AllplanAttributes - Object Layer Attributes #1, Attributset-Objekt: Wand; Object Layer Attributes #1, Versatz_oben: 0; Object Layer Attributes #1, Versatz_unten: 0; Object Layer Attributes #1, Barrierefrei: no; Object Layer Attributes #1, Fluchtweg: no; Object Layer Attributes #1, Brandabschnittsdefinierendes Bauteil: no; Pset_ConcreteElementGeneral - Betonüberdeckung: 1; Pset_OpeningElementCommon - Purpose: Aussparung
HA_TÜR_DRE | EG_Produktion_FFB |  | Betonarbeiten | - |  |  |  | Stahlbeton |  | EG_Produktion_FFB | 0111Tür0000618686 | Stb.-Außenwand | Stahlbeton | true | Ortbeton | true | W003 | 50 | XC4, XD1, XF2, WF | C35/45 | yes | HA_TÜR_DRE | AllplanAttributes - Object Layer Attributes #1, Attributset-Objekt: Wand; Pset_ConcreteElementGeneral - Betonüberdeckung: 1; Pset_OpeningElementCommon - Purpose: Türöffnung
HA_FEN | EG_Produktion_FFB |  | Betonarbeiten |  |  |  |  | Stahlbeton |  | EG_Produktion_FFB | 0111Fen0000620729 | Stb.-Außenwand | Stahlbeton | true | Ortbeton | true | W003 | 50 | XC4, XD1, XF2, WF | C35/45 | yes | HA_FEN | AllplanAttributes - Object Layer Attributes #1, Attributset-Objekt: Wand; Pset_ConcreteElementGeneral - Betonüberdeckung: 1; Pset_OpeningElementCommon - Purpose: Fensteröffnung
HA_FEN | EG_Produktion_FFB |  | Betonarbeiten |  |  |  |  | Stahlbeton |  | EG_Produktion_FFB | 0111Fen0000620731 | Stb.-Außenwand | Stahlbeton | true | Ortbeton | true | W003 | 50 | XC4, XD1, XF2, WF | C35/45 | yes | HA_FEN | AllplanAttributes - Object Layer Attributes #1, Attributset-Objekt: Wand; Pset_ConcreteElementGeneral - Betonüberdeckung: 1; Pset_OpeningElementCommon - Purpose: Fensteröffnung
Wandnische | EG_Produktion_FFB | n.a. | Betonarbeiten |  |  |  |  | Stahlbeton |  | EG_Produktion_FFB | 0111Wni0000620739 | Stb.-Außenwand | Stahlbeton | true | Ortbeton | true | W003 | 50 | XC4, XD1, XF2, WF | C35/45 |  | Aussparung | AllplanAttributes - Object Layer Attributes #1, Attributset-Objekt: Wand; Object Layer Attributes #1, Versatz_oben: 0; Object Layer Attributes #1, Versatz_unten: 0; Object Layer Attributes #1, Barrierefrei: no; Object Layer Attributes #1, Fluchtweg: no; Object Layer Attributes #1, Brandabschnittsdefinierendes Bauteil: no; Pset_ConcreteElementGeneral - Betonüberdeckung: 1; Pset_OpeningElementCommon - Purpose: Aussparung
Wandnische | EG_Produktion_FFB | n.a. | Betonarbeiten |  |  |  |  | Stahlbeton |  | EG_Produktion_FFB | 0111Wni0000620738 | Stb.-Außenwand | Stahlbeton | true | Ortbeton | true | W003 | 50 | XC4, XD1, XF2, WF | C35/45 |  | Aussparung | AllplanAttributes - Object Layer Attributes #1, Attributset-Objekt: Wand; Object Layer Attributes #1, Versatz_oben: 0; Object Layer Attributes #1, Versatz_unten: 0; Object Layer Attributes #1, Barrierefrei: no; Object Layer Attributes #1, Fluchtweg: no; Object Layer Attributes #1, Brandabschnittsdefinierendes Bauteil: no; Pset_ConcreteElementGeneral - Betonüberdeckung: 1; Pset_OpeningElementCommon - Purpose: Aussparung
Wandnische | EG_Produktion_FFB | n.a. | Betonarbeiten |  |  |  |  | Stahlbeton |  | EG_Produktion_FFB | 0111Wni0000620736 | Stb.-Außenwand | Stahlbeton | true | Ortbeton | true | W003 | 50 | XC4, XD1, XF2, WF | C35/45 |  | Aussparung | AllplanAttributes - Object Layer Attributes #1, Attributset-Objekt: Wand; Object Layer Attributes #1, Versatz_oben: 0; Object Layer Attributes #1, Versatz_unten: 0; Object Layer Attributes #1, Barrierefrei: no; Object Layer Attributes #1, Fluchtweg: no; Object Layer Attributes #1, Brandabschnittsdefinierendes Bauteil: no; Pset_ConcreteElementGeneral - Betonüberdeckung: 1; Pset_OpeningElementCommon - Purpose: Aussparung
Wandnische | EG_Produktion_FFB | n.a. | Betonarbeiten |  |  |  |  | Stahlbeton |  | EG_Produktion_FFB | 0111Wni0000620733 | Stb.-Außenwand | Stahlbeton | true | Ortbeton | true | W003 | 50 | XC4, XD1, XF2, WF | C35/45 |  | Aussparung | AllplanAttributes - Object Layer Attributes #1, Attributset-Objekt: Wand; Object Layer Attributes #1, Versatz_oben: 0; Object Layer Attributes #1, Versatz_unten: 0; Object Layer Attributes #1, Barrierefrei: no; Object Layer Attributes #1, Fluchtweg: no; Object Layer Attributes #1, Brandabschnittsdefinierendes Bauteil: no; Pset_ConcreteElementGeneral - Betonüberdeckung: 1; Pset_OpeningElementCommon - Purpose: Aussparung
HA_TÜR_DRE | EG_Produktion_FFB |  | Betonarbeiten | - |  |  |  | Stahlbeton |  | EG_Produktion_FFB | 0111Tür0000000683 | Stb.-Außenwand | Stahlbeton | true | Ortbeton | true | RA001.1 und RA002.1 | 50 | XC4, XD1, XF2, WF | C35/45 | yes | HA_TÜR_DRE | AllplanAttributes - Object Layer Attributes #1, Attributset-Objekt: Wand; Pset_ConcreteElementGeneral - Betonüberdeckung: 1; Pset_OpeningElementCommon - Purpose: Türöffnung
HA_TÜR_DRE | EG_Produktion_FFB |  | Betonarbeiten | - |  |  |  | Stahlbeton |  | EG_Produktion_FFB | 0111Tür0000618552 | Stb.-Außenwand | Stahlbeton | true | Ortbeton | true | RA001.1 und RA002.1 | 50 | XC4, XD1, XF2, WF | C35/45 | yes | HA_TÜR_DRE | AllplanAttributes - Object Layer Attributes #1, Attributset-Objekt: Wand; Pset_ConcreteElementGeneral - Betonüberdeckung: 1; Pset_OpeningElementCommon - Purpose: Türöffnung

# IfcPlate (1015)
AllplanAttributes - Gewerk: Stahlbauarbeiten; Abrechnungsart: St
IFC_Pset_TWP - Phase erstellt: Neubau; Material: Stahl; statisch tragend: true; Kommentar: -
Pset_FM-Vivantes - FM_Klasse: -; FM_Bezeichnung: -; FM_AKS: -; FM_Anzahl: -; FM_Standort: -; FM_Hersteller: -; FM_Hersteller-Typ: -; FM_Seriennummer: -; FM_Baujahr: -; FM_Inbetriebnahme Datum: -; FM_Gewährleistungsende: -; FM_Gewährleistungsgeber: -; FM_Betriebsstatus: -; FM_Prüfpflicht: -; FM_Prüfintervall: -; FM_letzter Prüfungstermin: -; FM_Sammelobjekt: -; FM_rechn. Lebensdauer: -; FM_rechn. Lebensende: -; FM_technischer Zustand: -; FM_voraus. Lebensende: -; FM_Eigentümer: -; FM_Bemerkung: -; FM_Versorgungsbereich-Wirkbereich: -; FM_Zugänglichkeit: -
Name | In | Material = AllplanAttributes, Material | V6 (m) = V7 (m) = V8 (m) = V9 | Bezeichnung | Plugin_Objektname | Ebene | Attributset-Objekt | Allright_Bauteil_ID | Name | Außenbauteil | Positionsnummer | PlateCommon, Reference | Unterkante (m) = X_Koordinate (m) | Oberkante (m) | Y_Koordinate (m) = Schwerpunkt_Y (m) | Z_Koordinate (m) = Schwerpunkt_Z (m) = Achsenstartpunkt (Z) (m) | Schwerpunkt_X (m) | Dicke (w) (m) | Achsenstartpunkt (X) (m) = Achsenendpunkt (X) (m) | Achsenstartpunkt (Y) (m) = Achsenendpunkt (Y) (m) | Achsenendpunkt (Z) (m) | Objektdrehwinkel
Stirnplatte | EG_Technik_FFB | S235 | 0 | Stirnplatte | PythonPart | EG_Technik_FFB | Platte | 0103Pyt0000001422 | Stirnplatte | true | AQV01.1 | AllplanAttributes - Bauteil-ID: 1422; Länge: 0.2 m; Dicke: 0.015 m; Breite: 0.29 m; Feuerwiderstandsklasse: <undefiniert>; Reference: HA_STV_ECK_xxx_STA_0,290x0,200_xxx; Materialverwendung: ToolboxPlate
Stirnplatte | EG_Technik_FFB | S235 | 0 | Stirnplatte | PythonPart | EG_Technik_FFB | Platte | 0103Pyt0000003978 | Stirnplatte | true | AQV01.1 | AllplanAttributes - Bauteil-ID: 1422; Länge: 0.2 m; Dicke: 0.015 m; Breite: 0.29 m; Feuerwiderstandsklasse: <undefiniert>; Reference: HA_STV_ECK_xxx_STA_0,290x0,200_xxx; Materialverwendung: ToolboxPlate
Stirnplatte | EG_Technik_FFB | S235 | 0 | Stirnplatte | PythonPart | EG_Technik_FFB | Platte | 0103Pyt0000003981 | Stirnplatte | true | AQV01.1 | AllplanAttributes - Bauteil-ID: 1422; Länge: 0.2 m; Dicke: 0.015 m; Breite: 0.29 m; Feuerwiderstandsklasse: <undefiniert>; Reference: HA_STV_ECK_xxx_STA_0,290x0,200_xxx; Materialverwendung: ToolboxPlate
Stirnplatte | EG_Technik_FFB | S235 | 0 | Stirnplatte | PythonPart | EG_Technik_FFB | Platte | 0103Pyt0000003984 | Stirnplatte | true | AQV01.1 | AllplanAttributes - Bauteil-ID: 1422; Länge: 0.2 m; Dicke: 0.015 m; Breite: 0.29 m; Feuerwiderstandsklasse: <undefiniert>; Reference: HA_STV_ECK_xxx_STA_0,290x0,200_xxx; Materialverwendung: ToolboxPlate
Stirnplatte | EG_Technik_FFB | S235 | 0 | Stirnplatte | PythonPart | EG_Technik_FFB | Platte | 0103Pyt0000004013 | Stirnplatte | true | AQV01.1 | AllplanAttributes - Bauteil-ID: 1422; Länge: 0.2 m; Dicke: 0.015 m; Breite: 0.29 m; Feuerwiderstandsklasse: <undefiniert>; Reference: HA_STV_ECK_xxx_STA_0,290x0,200_xxx; Materialverwendung: ToolboxPlate
Stirnplatte | EG_Technik_FFB | S235 | 0 | Stirnplatte | PythonPart | EG_Technik_FFB | Platte | 0103Pyt0000004016 | Stirnplatte | true | AQV01.1 | AllplanAttributes - Bauteil-ID: 1422; Länge: 0.2 m; Dicke: 0.015 m; Breite: 0.29 m; Feuerwiderstandsklasse: <undefiniert>; Reference: HA_STV_ECK_xxx_STA_0,290x0,200_xxx; Materialverwendung: ToolboxPlate
Stirnplatte | EG_Technik_FFB | S235 | 0 | Stirnplatte | PythonPart | EG_Technik_FFB | Platte | 0103Pyt0000004019 | Stirnplatte | true | AQV01.1 | AllplanAttributes - Bauteil-ID: 1422; Länge: 0.2 m; Dicke: 0.015 m; Breite: 0.29 m; Feuerwiderstandsklasse: <undefiniert>; Reference: HA_STV_ECK_xxx_STA_0,290x0,200_xxx; Materialverwendung: ToolboxPlate
Stirnplatte | EG_Technik_FFB | S235 | 0 | Stirnplatte | PythonPart | EG_Technik_FFB | Platte | 0103Pyt0000004022 | Stirnplatte | true | AQV01.1 | AllplanAttributes - Bauteil-ID: 1422; Länge: 0.2 m; Dicke: 0.015 m; Breite: 0.29 m; Feuerwiderstandsklasse: <undefiniert>; Reference: HA_STV_ECK_xxx_STA_0,290x0,200_xxx; Materialverwendung: ToolboxPlate
Stirnplatte | EG_Technik_FFB | S235 | 0 | Stirnplatte | PythonPart | EG_Technik_FFB | Platte | 0103Pyt0000004043 | Stirnplatte | true | AQV01.1 | AllplanAttributes - Bauteil-ID: 1422; Länge: 0.2 m; Dicke: 0.015 m; Breite: 0.29 m; Feuerwiderstandsklasse: <undefiniert>; Reference: HA_STV_ECK_xxx_STA_0,290x0,200_xxx; Materialverwendung: ToolboxPlate
Stirnplatte | EG_Technik_FFB | S235 | 0 | Stirnplatte | PythonPart | EG_Technik_FFB | Platte | 0103Pyt0000004046 | Stirnplatte | true | AQV01.1 | AllplanAttributes - Bauteil-ID: 1422; Länge: 0.2 m; Dicke: 0.015 m; Breite: 0.29 m; Feuerwiderstandsklasse: <undefiniert>; Reference: HA_STV_ECK_xxx_STA_0,290x0,200_xxx; Materialverwendung: ToolboxPlate
Stirnplatte | EG_Technik_FFB | S235 | 0 | Stirnplatte | PythonPart | EG_Technik_FFB | Platte | 0103Pyt0000004049 | Stirnplatte | true | AQV01.1 | AllplanAttributes - Bauteil-ID: 1422; Länge: 0.2 m; Dicke: 0.015 m; Breite: 0.29 m; Feuerwiderstandsklasse: <undefiniert>; Reference: HA_STV_ECK_xxx_STA_0,290x0,200_xxx; Materialverwendung: ToolboxPlate
Stirnplatte | EG_Technik_FFB | S235 | 0 | Stirnplatte | PythonPart | EG_Technik_FFB | Platte | 0103Pyt0000004052 | Stirnplatte | true | AQV01.1 | AllplanAttributes - Bauteil-ID: 1422; Länge: 0.2 m; Dicke: 0.015 m; Breite: 0.29 m; Feuerwiderstandsklasse: <undefiniert>; Reference: HA_STV_ECK_xxx_STA_0,290x0,200_xxx; Materialverwendung: ToolboxPlate
Stirnplatte | EG_Technik_FFB | S235 | 0 | Stirnplatte | PythonPart | EG_Technik_FFB | Platte | 0103Pyt0000004085 | Stirnplatte | true | AQV01.1 | AllplanAttributes - Bauteil-ID: 1422; Länge: 0.2 m; Dicke: 0.015 m; Breite: 0.29 m; Feuerwiderstandsklasse: <undefiniert>; Reference: HA_STV_ECK_xxx_STA_0,290x0,200_xxx; Materialverwendung: ToolboxPlate
Stirnplatte | EG_Technik_FFB | S235 | 0 | Stirnplatte | PythonPart | EG_Technik_FFB | Platte | 0103Pyt0000004088 | Stirnplatte | true | AQV01.1 | AllplanAttributes - Bauteil-ID: 1422; Länge: 0.2 m; Dicke: 0.015 m; Breite: 0.29 m; Feuerwiderstandsklasse: <undefiniert>; Reference: HA_STV_ECK_xxx_STA_0,290x0,200_xxx; Materialverwendung: ToolboxPlate
Stirnplatte | EG_Technik_FFB | S235 | 0 | Stirnplatte | PythonPart | EG_Technik_FFB | Platte | 0103Pyt0000004091 | Stirnplatte | true | AQV01.1 | AllplanAttributes - Bauteil-ID: 1422; Länge: 0.2 m; Dicke: 0.015 m; Breite: 0.29 m; Feuerwiderstandsklasse: <undefiniert>; Reference: HA_STV_ECK_xxx_STA_0,290x0,200_xxx; Materialverwendung: ToolboxPlate
Stirnplatte | EG_Technik_FFB | S235 | 0 | Stirnplatte | PythonPart | EG_Technik_FFB | Platte | 0103Pyt0000004094 | Stirnplatte | true | AQV01.1 | AllplanAttributes - Bauteil-ID: 1422; Länge: 0.2 m; Dicke: 0.015 m; Breite: 0.29 m; Feuerwiderstandsklasse: <undefiniert>; Reference: HA_STV_ECK_xxx_STA_0,290x0,200_xxx; Materialverwendung: ToolboxPlate
Stirnplatte | EG_Technik_FFB | S235 | 0 | Stirnplatte | PythonPart | EG_Technik_FFB | Platte | 0103Pyt0000004127 | Stirnplatte | true | AQV01.1 | AllplanAttributes - Bauteil-ID: 1422; Länge: 0.2 m; Dicke: 0.015 m; Breite: 0.29 m; Feuerwiderstandsklasse: <undefiniert>; Reference: HA_STV_ECK_xxx_STA_0,290x0,200_xxx; Materialverwendung: ToolboxPlate
Stirnplatte | EG_Technik_FFB | S235 | 0 | Stirnplatte | PythonPart | EG_Technik_FFB | Platte | 0103Pyt0000004130 | Stirnplatte | true | AQV01.1 | AllplanAttributes - Bauteil-ID: 1422; Länge: 0.2 m; Dicke: 0.015 m; Breite: 0.29 m; Feuerwiderstandsklasse: <undefiniert>; Reference: HA_STV_ECK_xxx_STA_0,290x0,200_xxx; Materialverwendung: ToolboxPlate
Stirnplatte | EG_Technik_FFB | S235 | 0 | Stirnplatte | PythonPart | EG_Technik_FFB | Platte | 0103Pyt0000004133 | Stirnplatte | true | AQV01.1 | AllplanAttributes - Bauteil-ID: 1422; Länge: 0.2 m; Dicke: 0.015 m; Breite: 0.29 m; Feuerwiderstandsklasse: <undefiniert>; Reference: HA_STV_ECK_xxx_STA_0,290x0,200_xxx; Materialverwendung: ToolboxPlate
Stirnplatte | EG_Technik_FFB | S235 | 0 | Stirnplatte | PythonPart | EG_Technik_FFB | Platte | 0103Pyt0000004136 | Stirnplatte | true | AQV01.1 | AllplanAttributes - Bauteil-ID: 1422; Länge: 0.2 m; Dicke: 0.015 m; Breite: 0.29 m; Feuerwiderstandsklasse: <undefiniert>; Reference: HA_STV_ECK_xxx_STA_0,290x0,200_xxx; Materialverwendung: ToolboxPlate
Stirnplatte | EG_Technik_FFB | S235 | 0 | Stirnplatte | PythonPart | EG_Technik_FFB | Platte | 0103Pyt0000004169 | Stirnplatte | true | AQV01.1 | AllplanAttributes - Bauteil-ID: 1422; Länge: 0.2 m; Dicke: 0.015 m; Breite: 0.29 m; Feuerwiderstandsklasse: <undefiniert>; Reference: HA_STV_ECK_xxx_STA_0,290x0,200_xxx; Materialverwendung: ToolboxPlate
Stirnplatte | EG_Technik_FFB | S235 | 0 | Stirnplatte | PythonPart | EG_Technik_FFB | Platte | 0103Pyt0000004172 | Stirnplatte | true | AQV01.1 | AllplanAttributes - Bauteil-ID: 1422; Länge: 0.2 m; Dicke: 0.015 m; Breite: 0.29 m; Feuerwiderstandsklasse: <undefiniert>; Reference: HA_STV_ECK_xxx_STA_0,290x0,200_xxx; Materialverwendung: ToolboxPlate
Stirnplatte | EG_Technik_FFB | S235 | 0 | Stirnplatte | PythonPart | EG_Technik_FFB | Platte | 0103Pyt0000004175 | Stirnplatte | true | AQV01.1 | AllplanAttributes - Bauteil-ID: 1422; Länge: 0.2 m; Dicke: 0.015 m; Breite: 0.29 m; Feuerwiderstandsklasse: <undefiniert>; Reference: HA_STV_ECK_xxx_STA_0,290x0,200_xxx; Materialverwendung: ToolboxPlate
Stirnplatte | EG_Technik_FFB | S235 | 0 | Stirnplatte | PythonPart | EG_Technik_FFB | Platte | 0103Pyt0000004178 | Stirnplatte | true | AQV01.1 | AllplanAttributes - Bauteil-ID: 1422; Länge: 0.2 m; Dicke: 0.015 m; Breite: 0.29 m; Feuerwiderstandsklasse: <undefiniert>; Reference: HA_STV_ECK_xxx_STA_0,290x0,200_xxx; Materialverwendung: ToolboxPlate
Stirnplatte | EG_Technik_FFB | S235 | 0 | Stirnplatte | PythonPart | EG_Technik_FFB | Platte | 0103Pyt0000004211 | Stirnplatte | true | AQV01.1 | AllplanAttributes - Bauteil-ID: 1422; Länge: 0.2 m; Dicke: 0.015 m; Breite: 0.29 m; Feuerwiderstandsklasse: <undefiniert>; Reference: HA_STV_ECK_xxx_STA_0,290x0,200_xxx; Materialverwendung: ToolboxPlate
Stirnplatte | EG_Technik_FFB | S235 | 0 | Stirnplatte | PythonPart | EG_Technik_FFB | Platte | 0103Pyt0000004214 | Stirnplatte | true | AQV01.1 | AllplanAttributes - Bauteil-ID: 1422; Länge: 0.2 m; Dicke: 0.015 m; Breite: 0.29 m; Feuerwiderstandsklasse: <undefiniert>; Reference: HA_STV_ECK_xxx_STA_0,290x0,200_xxx; Materialverwendung: ToolboxPlate
Stirnplatte | EG_Technik_FFB | S235 | 0 | Stirnplatte | PythonPart | EG_Technik_FFB | Platte | 0103Pyt0000004217 | Stirnplatte | true | AQV01.1 | AllplanAttributes - Bauteil-ID: 1422; Länge: 0.2 m; Dicke: 0.015 m; Breite: 0.29 m; Feuerwiderstandsklasse: <undefiniert>; Reference: HA_STV_ECK_xxx_STA_0,290x0,200_xxx; Materialverwendung: ToolboxPlate
Stirnplatte | EG_Technik_FFB | S235 | 0 | Stirnplatte | PythonPart | EG_Technik_FFB | Platte | 0103Pyt0000004220 | Stirnplatte | true | AQV01.1 | AllplanAttributes - Bauteil-ID: 1422; Länge: 0.2 m; Dicke: 0.015 m; Breite: 0.29 m; Feuerwiderstandsklasse: <undefiniert>; Reference: HA_STV_ECK_xxx_STA_0,290x0,200_xxx; Materialverwendung: ToolboxPlate
Stirnplatte | EG_Technik_FFB | S235 | 0 | Stirnplatte | PythonPart | EG_Technik_FFB | Platte | 0103Pyt0000004253 | Stirnplatte | true | AQV01.2 | AllplanAttributes - Bauteil-ID: 1422; Länge: 0.2 m; Dicke: 0.015 m; Breite: 0.29 m; Feuerwiderstandsklasse: <undefiniert>; Reference: HA_STV_ECK_xxx_STA_0,290x0,200_xxx; Materialverwendung: ToolboxPlate
Stirnplatte | EG_Technik_FFB | S235 | 0 | Stirnplatte | PythonPart | EG_Technik_FFB | Platte | 0103Pyt0000004256 | Stirnplatte | true | AQV01.2 | AllplanAttributes - Bauteil-ID: 1422; Länge: 0.2 m; Dicke: 0.015 m; Breite: 0.29 m; Feuerwiderstandsklasse: <undefiniert>; Reference: HA_STV_ECK_xxx_STA_0,290x0,200_xxx; Materialverwendung: ToolboxPlate
Stirnplatte | EG_Technik_FFB | S235 | 0 | Stirnplatte | PythonPart | EG_Technik_FFB | Platte | 0103Pyt0000004259 | Stirnplatte | true | AQV01.2 | AllplanAttributes - Bauteil-ID: 1422; Länge: 0.2 m; Dicke: 0.015 m; Breite: 0.29 m; Feuerwiderstandsklasse: <undefiniert>; Reference: HA_STV_ECK_xxx_STA_0,290x0,200_xxx; Materialverwendung: ToolboxPlate
Stirnplatte | EG_Technik_FFB | S235 | 0 | Stirnplatte | PythonPart | EG_Technik_FFB | Platte | 0103Pyt0000004262 | Stirnplatte | true | AQV01.2 | AllplanAttributes - Bauteil-ID: 1422; Länge: 0.2 m; Dicke: 0.015 m; Breite: 0.29 m; Feuerwiderstandsklasse: <undefiniert>; Reference: HA_STV_ECK_xxx_STA_0,290x0,200_xxx; Materialverwendung: ToolboxPlate
Plate | EG_Technik_FFB | S235 | 0 | Plate | PythonPart | EG_Technik_FFB | Platte | 0103Pyt0000002173 | Kopfplatte | true | ATL01 | AllplanAttributes - Bauteil-ID: 977; Länge: 0.2 m; Dicke: 0.015 m; Breite: 0.19 m; Feuerwiderstandsklasse: <undefiniert>; Reference: HA_STV_ECK_xxx_STA_0,190x0,200_xxx; Materialverwendung: ToolboxPlate
Stirnplatte | EG_Technik_FFB | S235 | 0 | Stirnplatte | PythonPart | EG_Technik_FFB | Platte | 0103Pyt0000001758 | Stirnplatte | true | AQV02.2 | AllplanAttributes - Bauteil-ID: 1758; Länge: 0.2 m; Dicke: 0.015 m; Breite: 0.29 m; Feuerwiderstandsklasse: <undefiniert>; Reference: HA_STV_ECK_xxx_STA_0,290x0,200_xxx; Materialverwendung: ToolboxPlate
Stirnplatte | EG_Technik_FFB | S235 | 0 | Stirnplatte | PythonPart | EG_Technik_FFB | Platte | 0103Pyt0000004305 | Stirnplatte | true | AQV02.2 | AllplanAttributes - Bauteil-ID: 1758; Länge: 0.2 m; Dicke: 0.015 m; Breite: 0.29 m; Feuerwiderstandsklasse: <undefiniert>; Reference: HA_STV_ECK_xxx_STA_0,290x0,200_xxx; Materialverwendung: ToolboxPlate
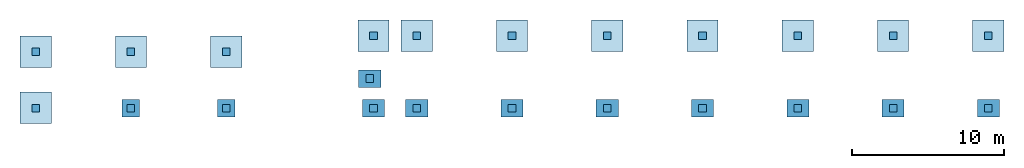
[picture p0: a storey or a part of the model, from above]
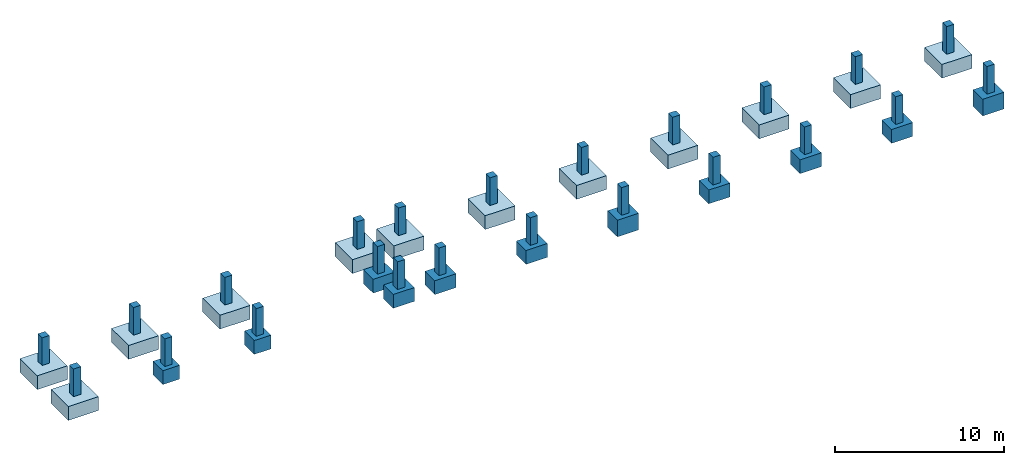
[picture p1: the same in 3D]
Properties of the parts of a building model (IFC2X3), part 17 of 25

# IfcPlate (1015)
Name | In | Material = AllplanAttributes, Material | V6 (m) = V7 (m) = V8 (m) = V9 | Bezeichnung | Plugin_Objektname | Ebene | Attributset-Objekt | Allright_Bauteil_ID | Name | Außenbauteil | Positionsnummer | PlateCommon, Reference | Unterkante (m) = X_Koordinate (m) | Oberkante (m) | Y_Koordinate (m) = Schwerpunkt_Y (m) | Z_Koordinate (m) = Schwerpunkt_Z (m) = Achsenstartpunkt (Z) (m) | Schwerpunkt_X (m) | Dicke (w) (m) | Achsenstartpunkt (X) (m) = Achsenendpunkt (X) (m) | Achsenstartpunkt (Y) (m) = Achsenendpunkt (Y) (m) | Achsenendpunkt (Z) (m) | Objektdrehwinkel
Stirnplatte | EG_Technik_FFB | S235 | 0 | Stirnplatte | PythonPart | EG_Technik_FFB | Platte | 0103Pyt0000004308 | Stirnplatte | true | AQV02.2 | AllplanAttributes - Bauteil-ID: 1758; Länge: 0.2 m; Dicke: 0.015 m; Breite: 0.29 m; Feuerwiderstandsklasse: <undefiniert>; Reference: HA_STV_ECK_xxx_STA_0,290x0,200_xxx; Materialverwendung: ToolboxPlate
Stirnplatte | EG_Technik_FFB | S235 | 0 | Stirnplatte | PythonPart | EG_Technik_FFB | Platte | 0103Pyt0000004311 | Stirnplatte | true | AQV02.2 | AllplanAttributes - Bauteil-ID: 1758; Länge: 0.2 m; Dicke: 0.015 m; Breite: 0.29 m; Feuerwiderstandsklasse: <undefiniert>; Reference: HA_STV_ECK_xxx_STA_0,290x0,200_xxx; Materialverwendung: ToolboxPlate
Stirnplatte | EG_Technik_FFB | S235 | 0 | Stirnplatte | PythonPart | EG_Technik_FFB | Platte | 0103Pyt0000004334 | Stirnplatte | true | AQV02.2 | AllplanAttributes - Bauteil-ID: 1758; Länge: 0.2 m; Dicke: 0.015 m; Breite: 0.29 m; Feuerwiderstandsklasse: <undefiniert>; Reference: HA_STV_ECK_xxx_STA_0,290x0,200_xxx; Materialverwendung: ToolboxPlate
Stirnplatte | EG_Technik_FFB | S235 | 0 | Stirnplatte | PythonPart | EG_Technik_FFB | Platte | 0103Pyt0000004337 | Stirnplatte | true | AQV02.2 | AllplanAttributes - Bauteil-ID: 1758; Länge: 0.2 m; Dicke: 0.015 m; Breite: 0.29 m; Feuerwiderstandsklasse: <undefiniert>; Reference: HA_STV_ECK_xxx_STA_0,290x0,200_xxx; Materialverwendung: ToolboxPlate
Stirnplatte | EG_Technik_FFB | S235 | 0 | Stirnplatte | PythonPart | EG_Technik_FFB | Platte | 0103Pyt0000004340 | Stirnplatte | true | AQV02.2 | AllplanAttributes - Bauteil-ID: 1758; Länge: 0.2 m; Dicke: 0.015 m; Breite: 0.29 m; Feuerwiderstandsklasse: <undefiniert>; Reference: HA_STV_ECK_xxx_STA_0,290x0,200_xxx; Materialverwendung: ToolboxPlate
Stirnplatte | EG_Technik_FFB | S235 | 0 | Stirnplatte | PythonPart | EG_Technik_FFB | Platte | 0103Pyt0000004343 | Stirnplatte | true | AQV02.2 | AllplanAttributes - Bauteil-ID: 1758; Länge: 0.2 m; Dicke: 0.015 m; Breite: 0.29 m; Feuerwiderstandsklasse: <undefiniert>; Reference: HA_STV_ECK_xxx_STA_0,290x0,200_xxx; Materialverwendung: ToolboxPlate
Stirnplatte | EG_Technik_FFB | S235 | 0 | Stirnplatte | PythonPart | EG_Technik_FFB | Platte | 0103Pyt0000004398 | Stirnplatte | true | AQV02.2 | AllplanAttributes - Bauteil-ID: 1758; Länge: 0.2 m; Dicke: 0.015 m; Breite: 0.29 m; Feuerwiderstandsklasse: <undefiniert>; Reference: HA_STV_ECK_xxx_STA_0,290x0,200_xxx; Materialverwendung: ToolboxPlate
Stirnplatte | EG_Technik_FFB | S235 | 0 | Stirnplatte | PythonPart | EG_Technik_FFB | Platte | 0103Pyt0000004401 | Stirnplatte | true | AQV02.2 | AllplanAttributes - Bauteil-ID: 1758; Länge: 0.2 m; Dicke: 0.015 m; Breite: 0.29 m; Feuerwiderstandsklasse: <undefiniert>; Reference: HA_STV_ECK_xxx_STA_0,290x0,200_xxx; Materialverwendung: ToolboxPlate
Stirnplatte | EG_Technik_FFB | S235 | 0 | Stirnplatte | PythonPart | EG_Technik_FFB | Platte | 0103Pyt0000004404 | Stirnplatte | true | AQV02.2 | AllplanAttributes - Bauteil-ID: 1758; Länge: 0.2 m; Dicke: 0.015 m; Breite: 0.29 m; Feuerwiderstandsklasse: <undefiniert>; Reference: HA_STV_ECK_xxx_STA_0,290x0,200_xxx; Materialverwendung: ToolboxPlate
Stirnplatte | EG_Technik_FFB | S235 | 0 | Stirnplatte | PythonPart | EG_Technik_FFB | Platte | 0103Pyt0000004407 | Stirnplatte | true | AQV02.2 | AllplanAttributes - Bauteil-ID: 1758; Länge: 0.2 m; Dicke: 0.015 m; Breite: 0.29 m; Feuerwiderstandsklasse: <undefiniert>; Reference: HA_STV_ECK_xxx_STA_0,290x0,200_xxx; Materialverwendung: ToolboxPlate
Stirnplatte | Wartung_FFB | S355 |  | Stirnplatte |  | Wartung_FFB | Plate | 0121Kop0000019833 | Stirnplatte | false | T101.1 | HI_PRO_STA_0,300x0,530x0,025 | PlateCommon - Feuerwiderstandsklasse: <undefiniert>; Schallschutzklasse: <undefiniert>
Stirnplatte | Wartung_FFB | S355 |  | Stirnplatte |  | Wartung_FFB | Plate | 0121Kop0000019832 | Stirnplatte | false | T101.1 | HI_PRO_STA_0,300x0,530x0,025 | PlateCommon - Feuerwiderstandsklasse: <undefiniert>; Schallschutzklasse: <undefiniert>
Stirnplatte | Wartung_FFB | S355 |  | Stirnplatte |  | Wartung_FFB | Plate | 0121Kop0000019834 | Stirnplatte | false | T101.1 | HI_PRO_STA_0,300x0,530x0,025 | PlateCommon - Feuerwiderstandsklasse: <undefiniert>; Schallschutzklasse: <undefiniert>
Stirnplatte | Wartung_FFB | S355 |  | Stirnplatte |  | Wartung_FFB | Plate | 0121Kop0000019835 | Stirnplatte | false | T101.1 | HI_PRO_STA_0,300x0,530x0,025 | PlateCommon - Feuerwiderstandsklasse: <undefiniert>; Schallschutzklasse: <undefiniert>
Stirnplatte | Wartung_FFB | S355 |  | Stirnplatte |  | Wartung_FFB | Plate | 0121Kop0000019840 | Stirnplatte | false | T101.1 | HI_PRO_STA_0,300x0,680x0,025 | PlateCommon - Feuerwiderstandsklasse: <undefiniert>; Schallschutzklasse: <undefiniert>
Stirnplatte | Wartung_FFB | S355 |  | Stirnplatte |  | Wartung_FFB | Plate | 0121Kop0000019841 | Stirnplatte | false | T101.1 | HI_PRO_STA_0,300x0,680x0,025 | PlateCommon - Feuerwiderstandsklasse: <undefiniert>; Schallschutzklasse: <undefiniert>
Stirnplatte | Wartung_FFB | S355 |  | Stirnplatte |  | Wartung_FFB | Plate | 0121Kop0000019850 | Stirnplatte | false | T101.1 | HI_PRO_STA_0,300x0,680x0,025 | PlateCommon - Feuerwiderstandsklasse: <undefiniert>; Schallschutzklasse: <undefiniert>
Stirnplatte | Wartung_FFB | S355 |  | Stirnplatte |  | Wartung_FFB | Plate | 0121Kop0000019851 | Stirnplatte | false | T101.1 | HI_PRO_STA_0,300x0,680x0,025 | PlateCommon - Feuerwiderstandsklasse: <undefiniert>; Schallschutzklasse: <undefiniert>
Stirnplatte | Wartung_FFB | S355 |  | Stirnplatte |  | Wartung_FFB | Plate | 0121Kop0000019857 | Stirnplatte | false | T101.1 | HI_PRO_STA_0,300x0,580x0,025 | PlateCommon - Feuerwiderstandsklasse: <undefiniert>; Schallschutzklasse: <undefiniert>
Stirnplatte | Wartung_FFB | S355 |  | Stirnplatte |  | Wartung_FFB | Plate | 0121Kop0000019872 | Stirnplatte | false | T101.1 | HI_PRO_STA_0,300x0,580x0,025 | PlateCommon - Feuerwiderstandsklasse: <undefiniert>; Schallschutzklasse: <undefiniert>
Stirnplatte | Wartung_FFB | S355 |  | Stirnplatte |  | Wartung_FFB | Plate | 0121Kop0000019910 | Stirnplatte | false | T101.1 | HI_PRO_STA_0,300x0,580x0,025 | PlateCommon - Feuerwiderstandsklasse: <undefiniert>; Schallschutzklasse: <undefiniert>
Stirnplatte | Wartung_FFB | S355 |  | Stirnplatte |  | Wartung_FFB | Plate | 0121Kop0000019911 | Stirnplatte | false | T101.1 | HI_PRO_STA_0,300x0,580x0,025 | PlateCommon - Feuerwiderstandsklasse: <undefiniert>; Schallschutzklasse: <undefiniert>
Stirnplatte | Wartung_FFB | S355 |  | Stirnplatte |  | Wartung_FFB | Plate | 0121Kop0000019914 | Stirnplatte | false | T101.1 | HI_PRO_STA_0,300x0,580x0,025 | PlateCommon - Feuerwiderstandsklasse: <undefiniert>; Schallschutzklasse: <undefiniert>
Stirnplatte | Wartung_FFB | S355 |  | Stirnplatte |  | Wartung_FFB | Plate | 0121Kop0000019915 | Stirnplatte | false | T101.1 | HI_PRO_STA_0,300x0,580x0,025 | PlateCommon - Feuerwiderstandsklasse: <undefiniert>; Schallschutzklasse: <undefiniert>
Stirnplatte | Wartung_FFB | S355 |  | Stirnplatte |  | Wartung_FFB | Plate | 0121Kop0000019918 | Stirnplatte | false | T101.1 | HI_PRO_STA_0,300x0,580x0,025 | PlateCommon - Feuerwiderstandsklasse: <undefiniert>; Schallschutzklasse: <undefiniert>
Stirnplatte | Wartung_FFB | S355 |  | Stirnplatte |  | Wartung_FFB | Plate | 0121Kop0000019919 | Stirnplatte | false | T101.1 | HI_PRO_STA_0,300x0,580x0,025 | PlateCommon - Feuerwiderstandsklasse: <undefiniert>; Schallschutzklasse: <undefiniert>
Stirnplatte | Wartung_FFB | S355 |  | Stirnplatte |  | Wartung_FFB | Plate | 0121Kop0000019922 | Stirnplatte | false | T101.1 | HI_PRO_STA_0,300x0,580x0,025 | PlateCommon - Feuerwiderstandsklasse: <undefiniert>; Schallschutzklasse: <undefiniert>
Stirnplatte | Wartung_FFB | S355 |  | Stirnplatte |  | Wartung_FFB | Plate | 0121Kop0000019923 | Stirnplatte | false | T101.1 | HI_PRO_STA_0,300x0,580x0,025 | PlateCommon - Feuerwiderstandsklasse: <undefiniert>; Schallschutzklasse: <undefiniert>
Stirnplatte | Wartung_FFB | S355 |  | Stirnplatte |  | Wartung_FFB | Plate | 0121Kop0000019926 | Stirnplatte | false | T101.1 | HI_PRO_STA_0,300x0,580x0,025 | PlateCommon - Feuerwiderstandsklasse: <undefiniert>; Schallschutzklasse: <undefiniert>
Stirnplatte | Wartung_FFB | S355 |  | Stirnplatte |  | Wartung_FFB | Plate | 0121Kop0000019927 | Stirnplatte | false | T101.1 | HI_PRO_STA_0,300x0,580x0,025 | PlateCommon - Feuerwiderstandsklasse: <undefiniert>; Schallschutzklasse: <undefiniert>
Stirnplatte | Wartung_FFB | S355 |  | Stirnplatte |  | Wartung_FFB | Plate | 0121Kop0000019930 | Stirnplatte | false | T101.1 | HI_PRO_STA_0,300x0,580x0,025 | PlateCommon - Feuerwiderstandsklasse: <undefiniert>; Schallschutzklasse: <undefiniert>
Stirnplatte | Wartung_FFB | S355 |  | Stirnplatte |  | Wartung_FFB | Plate | 0121Kop0000019931 | Stirnplatte | false | T101.1 | HI_PRO_STA_0,300x0,580x0,025 | PlateCommon - Feuerwiderstandsklasse: <undefiniert>; Schallschutzklasse: <undefiniert>
Stirnplatte | Wartung_FFB | S355 |  | Stirnplatte |  | Wartung_FFB | Plate | 0121Kop0000019937 | Stirnplatte | false | T101.1 | HI_PRO_STA_0,300x0,580x0,025 | PlateCommon - Feuerwiderstandsklasse: <undefiniert>; Schallschutzklasse: <undefiniert>
Stirnplatte | Wartung_FFB | S355 |  | Stirnplatte |  | Wartung_FFB | Plate | 0121Kop0000019938 | Stirnplatte | false | T101.1 | HI_PRO_STA_0,300x0,580x0,025 | PlateCommon - Feuerwiderstandsklasse: <undefiniert>; Schallschutzklasse: <undefiniert>
Stirnplatte | Wartung_FFB | S355 |  | Stirnplatte |  | Wartung_FFB | Plate | 0121Kop0000019949 | Stirnplatte | false | T101.1 | HI_PRO_STA_0,300x0,680x0,025 | PlateCommon - Feuerwiderstandsklasse: <undefiniert>; Schallschutzklasse: <undefiniert>
Stirnplatte | Wartung_FFB | S355 |  | Stirnplatte |  | Wartung_FFB | Plate | 0121Kop0000019950 | Stirnplatte | false | T101.1 | HI_PRO_STA_0,300x0,680x0,025 | PlateCommon - Feuerwiderstandsklasse: <undefiniert>; Schallschutzklasse: <undefiniert>
Stirnplatte | Wartung_FFB | S355 |  | Stirnplatte |  | Wartung_FFB | Plate | 0121Kop0000019836 | Stirnplatte | false | T101.1 | HI_PRO_STA_0,300x0,530x0,025 | PlateCommon - Feuerwiderstandsklasse: <undefiniert>; Schallschutzklasse: <undefiniert>
Stirnplatte | Wartung_FFB | S355 |  | Stirnplatte |  | Wartung_FFB | Plate | 0121Kop0000019837 | Stirnplatte | false | T101.1 | HI_PRO_STA_0,300x0,530x0,025 | PlateCommon - Feuerwiderstandsklasse: <undefiniert>; Schallschutzklasse: <undefiniert>
Stirnplatte | Wartung_FFB | S355 |  | Stirnplatte |  | Wartung_FFB | Plate | 0121Kop0000019838 | Stirnplatte | false | T101.1 | HI_PRO_STA_0,300x0,530x0,025 | PlateCommon - Feuerwiderstandsklasse: <undefiniert>; Schallschutzklasse: <undefiniert>
Stirnplatte | Wartung_FFB | S355 |  | Stirnplatte |  | Wartung_FFB | Plate | 0121Kop0000019839 | Stirnplatte | false | T101.1 | HI_PRO_STA_0,300x0,530x0,025 | PlateCommon - Feuerwiderstandsklasse: <undefiniert>; Schallschutzklasse: <undefiniert>
Stirnplatte | Wartung_FFB | S355 |  | Stirnplatte |  | Wartung_FFB | Plate | 0121Kop0000019843 | Stirnplatte | false | T101.1 | HI_PRO_STA_0,300x0,680x0,025 | PlateCommon - Feuerwiderstandsklasse: <undefiniert>; Schallschutzklasse: <undefiniert>
Stirnplatte | Wartung_FFB | S355 |  | Stirnplatte |  | Wartung_FFB | Plate | 0121Kop0000019844 | Stirnplatte | false | T101.1 | HI_PRO_STA_0,300x0,680x0,025 | PlateCommon - Feuerwiderstandsklasse: <undefiniert>; Schallschutzklasse: <undefiniert>
Stirnplatte | Wartung_FFB | S355 |  | Stirnplatte |  | Wartung_FFB | Plate | 0121Kop0000019848 | Stirnplatte | false | T101.1 | HI_PRO_STA_0,300x0,680x0,025 | PlateCommon - Feuerwiderstandsklasse: <undefiniert>; Schallschutzklasse: <undefiniert>
Stirnplatte | Wartung_FFB | S355 |  | Stirnplatte |  | Wartung_FFB | Plate | 0121Kop0000019849 | Stirnplatte | false | T101.1 | HI_PRO_STA_0,300x0,680x0,025 | PlateCommon - Feuerwiderstandsklasse: <undefiniert>; Schallschutzklasse: <undefiniert>
Stirnplatte | Wartung_FFB | S355 |  | Stirnplatte |  | Wartung_FFB | Plate | 0121Kop0000019880 | Stirnplatte | false | T101.1 | HI_PRO_STA_0,300x0,680x0,025 | PlateCommon - Feuerwiderstandsklasse: <undefiniert>; Schallschutzklasse: <undefiniert>
Stirnplatte | Wartung_FFB | S355 |  | Stirnplatte |  | Wartung_FFB | Plate | 0121Kop0000019881 | Stirnplatte | false | T101.1 | HI_PRO_STA_0,300x0,680x0,025 | PlateCommon - Feuerwiderstandsklasse: <undefiniert>; Schallschutzklasse: <undefiniert>
Stirnplatte | Wartung_FFB | S355 |  | Stirnplatte |  | Wartung_FFB | Plate | 0121Kop0000019912 | Stirnplatte | false | T101.1 | HI_PRO_STA_0,300x0,680x0,025 | PlateCommon - Feuerwiderstandsklasse: <undefiniert>; Schallschutzklasse: <undefiniert>
Stirnplatte | Wartung_FFB | S355 |  | Stirnplatte |  | Wartung_FFB | Plate | 0121Kop0000019913 | Stirnplatte | false | T101.1 | HI_PRO_STA_0,300x0,680x0,025 | PlateCommon - Feuerwiderstandsklasse: <undefiniert>; Schallschutzklasse: <undefiniert>
Stirnplatte | Wartung_FFB | S355 |  | Stirnplatte |  | Wartung_FFB | Plate | 0121Kop0000019916 | Stirnplatte | false | T101.1 | HI_PRO_STA_0,300x0,680x0,025 | PlateCommon - Feuerwiderstandsklasse: <undefiniert>; Schallschutzklasse: <undefiniert>
Stirnplatte | Wartung_FFB | S355 |  | Stirnplatte |  | Wartung_FFB | Plate | 0121Kop0000019917 | Stirnplatte | false | T101.1 | HI_PRO_STA_0,300x0,680x0,025 | PlateCommon - Feuerwiderstandsklasse: <undefiniert>; Schallschutzklasse: <undefiniert>
Stirnplatte | Wartung_FFB | S355 |  | Stirnplatte |  | Wartung_FFB | Plate | 0121Kop0000019920 | Stirnplatte | false | T101.1 | HI_PRO_STA_0,300x0,680x0,025 | PlateCommon - Feuerwiderstandsklasse: <undefiniert>; Schallschutzklasse: <undefiniert>
Stirnplatte | Wartung_FFB | S355 |  | Stirnplatte |  | Wartung_FFB | Plate | 0121Kop0000019921 | Stirnplatte | false | T101.1 | HI_PRO_STA_0,300x0,680x0,025 | PlateCommon - Feuerwiderstandsklasse: <undefiniert>; Schallschutzklasse: <undefiniert>
Stirnplatte | Wartung_FFB | S355 |  | Stirnplatte |  | Wartung_FFB | Plate | 0121Kop0000019924 | Stirnplatte | false | T101.1 | HI_PRO_STA_0,300x0,680x0,025 | PlateCommon - Feuerwiderstandsklasse: <undefiniert>; Schallschutzklasse: <undefiniert>
Stirnplatte | Wartung_FFB | S355 |  | Stirnplatte |  | Wartung_FFB | Plate | 0121Kop0000019925 | Stirnplatte | false | T101.1 | HI_PRO_STA_0,300x0,680x0,025 | PlateCommon - Feuerwiderstandsklasse: <undefiniert>; Schallschutzklasse: <undefiniert>
Stirnplatte | Wartung_FFB | S355 |  | Stirnplatte |  | Wartung_FFB | Plate | 0121Kop0000019928 | Stirnplatte | false | T101.1 | HI_PRO_STA_0,300x0,680x0,025 | PlateCommon - Feuerwiderstandsklasse: <undefiniert>; Schallschutzklasse: <undefiniert>
Stirnplatte | Wartung_FFB | S355 |  | Stirnplatte |  | Wartung_FFB | Plate | 0121Kop0000019929 | Stirnplatte | false | T101.1 | HI_PRO_STA_0,300x0,680x0,025 | PlateCommon - Feuerwiderstandsklasse: <undefiniert>; Schallschutzklasse: <undefiniert>
Stirnplatte | Wartung_FFB | S355 |  | Stirnplatte |  | Wartung_FFB | Plate | 0121Kop0000019932 | Stirnplatte | false | T101.1 | HI_PRO_STA_0,300x0,680x0,025 | PlateCommon - Feuerwiderstandsklasse: <undefiniert>; Schallschutzklasse: <undefiniert>
Stirnplatte | Wartung_FFB | S355 |  | Stirnplatte |  | Wartung_FFB | Plate | 0121Kop0000019933 | Stirnplatte | false | T101.1 | HI_PRO_STA_0,300x0,680x0,025 | PlateCommon - Feuerwiderstandsklasse: <undefiniert>; Schallschutzklasse: <undefiniert>
Stirnplatte | Wartung_FFB | S355 |  | Stirnplatte |  | Wartung_FFB | Plate | 0121Kop0000019939 | Stirnplatte | false | T101.1 | HI_PRO_STA_0,300x0,680x0,025 | PlateCommon - Feuerwiderstandsklasse: <undefiniert>; Schallschutzklasse: <undefiniert>
Stirnplatte | Wartung_FFB | S355 |  | Stirnplatte |  | Wartung_FFB | Plate | 0121Kop0000019940 | Stirnplatte | false | T101.1 | HI_PRO_STA_0,300x0,680x0,025 | PlateCommon - Feuerwiderstandsklasse: <undefiniert>; Schallschutzklasse: <undefiniert>
Stirnplatte | Wartung_FFB | S355 |  | Stirnplatte |  | Wartung_FFB | Plate | 0121Kop0000019947 | Stirnplatte | false | T101.1 | HI_PRO_STA_0,300x0,680x0,025 | PlateCommon - Feuerwiderstandsklasse: <undefiniert>; Schallschutzklasse: <undefiniert>
Stirnplatte | Wartung_FFB | S355 |  | Stirnplatte |  | Wartung_FFB | Plate | 0121Kop0000019948 | Stirnplatte | false | T101.1 | HI_PRO_STA_0,300x0,680x0,025 | PlateCommon - Feuerwiderstandsklasse: <undefiniert>; Schallschutzklasse: <undefiniert>
Stirnplatte | Wartung_FFB | S355 |  | Stirnplatte |  | Wartung_FFB | Plate | 0121Kop0000019960 | Stirnplatte | false | T101.1 | HI_PRO_STA_0,300x0,680x0,025 | PlateCommon - Feuerwiderstandsklasse: <undefiniert>; Schallschutzklasse: <undefiniert>
Stirnplatte | Wartung_FFB | S355 |  | Stirnplatte |  | Wartung_FFB | Plate | 0121Kop0000019961 | Stirnplatte | false | T101.1 | HI_PRO_STA_0,300x0,680x0,025 | PlateCommon - Feuerwiderstandsklasse: <undefiniert>; Schallschutzklasse: <undefiniert>
Stirnplatte | Wartung_FFB | S355 |  | Stirnplatte |  | Wartung_FFB | Plate | 0121Kop0000019962 | Stirnplatte | false | T101.1 | HI_PRO_STA_0,300x0,680x0,025 | PlateCommon - Feuerwiderstandsklasse: <undefiniert>; Schallschutzklasse: <undefiniert>
Stirnplatte | Wartung_FFB | S355 |  | Stirnplatte |  | Wartung_FFB | Plate | 0121Kop0000019963 | Stirnplatte | false | T101.1 | HI_PRO_STA_0,300x0,680x0,025 | PlateCommon - Feuerwiderstandsklasse: <undefiniert>; Schallschutzklasse: <undefiniert>
Stirnplatte | Wartung_FFB | S355 |  | Stirnplatte |  | Wartung_FFB | Plate | 0121Kop0000019973 | Stirnplatte | false | T101.1 | HI_PRO_STA_0,300x0,680x0,025 | PlateCommon - Feuerwiderstandsklasse: <undefiniert>; Schallschutzklasse: <undefiniert>
Stirnplatte | Wartung_FFB | S355 |  | Stirnplatte |  | Wartung_FFB | Plate | 0121Kop0000019974 | Stirnplatte | false | T101.1 | HI_PRO_STA_0,300x0,680x0,025 | PlateCommon - Feuerwiderstandsklasse: <undefiniert>; Schallschutzklasse: <undefiniert>
Stirnplatte | Wartung_FFB | S355 |  | Stirnplatte |  | Wartung_FFB | Plate | 0121Kop0000019975 | Stirnplatte | false | T101.1 | HI_PRO_STA_0,300x0,680x0,025 | PlateCommon - Feuerwiderstandsklasse: <undefiniert>; Schallschutzklasse: <undefiniert>
Stirnplatte | Wartung_FFB | S355 |  | Stirnplatte |  | Wartung_FFB | Plate | 0121Kop0000019976 | Stirnplatte | false | T101.1 | HI_PRO_STA_0,300x0,680x0,025 | PlateCommon - Feuerwiderstandsklasse: <undefiniert>; Schallschutzklasse: <undefiniert>
Stirnplatte | Wartung_FFB | S355 |  | Stirnplatte |  | Wartung_FFB | Plate | 0121Kop0000019986 | Stirnplatte | false | T101.1 | HI_PRO_STA_0,300x0,680x0,025 | PlateCommon - Feuerwiderstandsklasse: <undefiniert>; Schallschutzklasse: <undefiniert>
Stirnplatte | Wartung_FFB | S355 |  | Stirnplatte |  | Wartung_FFB | Plate | 0121Kop0000019987 | Stirnplatte | false | T101.1 | HI_PRO_STA_0,300x0,680x0,025 | PlateCommon - Feuerwiderstandsklasse: <undefiniert>; Schallschutzklasse: <undefiniert>
Stirnplatte | Wartung_FFB | S355 |  | Stirnplatte |  | Wartung_FFB | Plate | 0121Kop0000019988 | Stirnplatte | false | T101.1 | HI_PRO_STA_0,300x0,680x0,025 | PlateCommon - Feuerwiderstandsklasse: <undefiniert>; Schallschutzklasse: <undefiniert>
Stirnplatte | Wartung_FFB | S355 |  | Stirnplatte |  | Wartung_FFB | Plate | 0121Kop0000019989 | Stirnplatte | false | T101.1 | HI_PRO_STA_0,300x0,680x0,025 | PlateCommon - Feuerwiderstandsklasse: <undefiniert>; Schallschutzklasse: <undefiniert>
Stirnplatte | Wartung_FFB | S355 |  | Stirnplatte |  | Wartung_FFB | Plate | 0121Kop0000020025 | Stirnplatte | false | T101.1 | HI_PRO_STA_0,300x0,680x0,025 | PlateCommon - Feuerwiderstandsklasse: <undefiniert>; Schallschutzklasse: <undefiniert>
Stirnplatte | Wartung_FFB | S355 |  | Stirnplatte |  | Wartung_FFB | Plate | 0121Kop0000020026 | Stirnplatte | false | T101.1 | HI_PRO_STA_0,300x0,680x0,025 | PlateCommon - Feuerwiderstandsklasse: <undefiniert>; Schallschutzklasse: <undefiniert>
Stirnplatte | Wartung_FFB | S355 |  | Stirnplatte |  | Wartung_FFB | Plate | 0121Kop0000020027 | Stirnplatte | false | T101.1 | HI_PRO_STA_0,300x0,680x0,025 | PlateCommon - Feuerwiderstandsklasse: <undefiniert>; Schallschutzklasse: <undefiniert>
Stirnplatte | Wartung_FFB | S355 |  | Stirnplatte |  | Wartung_FFB | Plate | 0121Kop0000020028 | Stirnplatte | false | T101.1 | HI_PRO_STA_0,300x0,680x0,025 | PlateCommon - Feuerwiderstandsklasse: <undefiniert>; Schallschutzklasse: <undefiniert>
Stirnplatte | Wartung_FFB | S355 |  | Stirnplatte |  | Wartung_FFB | Plate | 0121Kop0000020038 | Stirnplatte | false | T101.1 | HI_PRO_STA_0,300x0,680x0,025 | PlateCommon - Feuerwiderstandsklasse: <undefiniert>; Schallschutzklasse: <undefiniert>
Stirnplatte | Wartung_FFB | S355 |  | Stirnplatte |  | Wartung_FFB | Plate | 0121Kop0000020039 | Stirnplatte | false | T101.1 | HI_PRO_STA_0,300x0,680x0,025 | PlateCommon - Feuerwiderstandsklasse: <undefiniert>; Schallschutzklasse: <undefiniert>
Stirnplatte | Wartung_FFB | S355 |  | Stirnplatte |  | Wartung_FFB | Plate | 0121Kop0000020040 | Stirnplatte | false | T101.1 | HI_PRO_STA_0,300x0,680x0,025 | PlateCommon - Feuerwiderstandsklasse: <undefiniert>; Schallschutzklasse: <undefiniert>
Stirnplatte | Wartung_FFB | S355 |  | Stirnplatte |  | Wartung_FFB | Plate | 0121Kop0000020041 | Stirnplatte | false | T101.1 | HI_PRO_STA_0,300x0,680x0,025 | PlateCommon - Feuerwiderstandsklasse: <undefiniert>; Schallschutzklasse: <undefiniert>
Stirnplatte | Wartung_FFB | S355 |  | Stirnplatte |  | Wartung_FFB | Plate | 0121Kop0000020051 | Stirnplatte | false | T101.1 | HI_PRO_STA_0,300x0,580x0,025 | PlateCommon - Feuerwiderstandsklasse: <undefiniert>; Schallschutzklasse: <undefiniert>
Stirnplatte | Wartung_FFB | S355 |  | Stirnplatte |  | Wartung_FFB | Plate | 0121Kop0000020056 | Stirnplatte | false | T101.1 | HI_PRO_STA_0,300x0,580x0,025 | PlateCommon - Feuerwiderstandsklasse: <undefiniert>; Schallschutzklasse: <undefiniert>
Stirnplatte | Wartung_FFB | S355 |  | Stirnplatte |  | Wartung_FFB | Plate | 0121Kop0000020057 | Stirnplatte | false | T101.1 | HI_PRO_STA_0,300x0,580x0,025 | PlateCommon - Feuerwiderstandsklasse: <undefiniert>; Schallschutzklasse: <undefiniert>
Stirnplatte | Wartung_FFB | S355 |  | Stirnplatte |  | Wartung_FFB | Plate | 0121Kop0000020058 | Stirnplatte | false | T101.1 | HI_PRO_STA_0,300x0,580x0,025 | PlateCommon - Feuerwiderstandsklasse: <undefiniert>; Schallschutzklasse: <undefiniert>
Stirnplatte | Wartung_FFB | S355 |  | Stirnplatte |  | Wartung_FFB | Plate | 0121Kop0000020059 | Stirnplatte | false | T101.1 | HI_PRO_STA_0,300x0,580x0,025 | PlateCommon - Feuerwiderstandsklasse: <undefiniert>; Schallschutzklasse: <undefiniert>
Stirnplatte | Wartung_FFB | S355 |  | Stirnplatte |  | Wartung_FFB | Plate | 0121Kop0000020064 | Stirnplatte | false | T101.1 | HI_PRO_STA_0,300x0,580x0,025 | PlateCommon - Feuerwiderstandsklasse: <undefiniert>; Schallschutzklasse: <undefiniert>
Stirnplatte | Wartung_FFB | S355 |  | Stirnplatte |  | Wartung_FFB | Plate | 0121Kop0000020065 | Stirnplatte | false | T101.1 | HI_PRO_STA_0,300x0,580x0,025 | PlateCommon - Feuerwiderstandsklasse: <undefiniert>; Schallschutzklasse: <undefiniert>
Stirnplatte | Wartung_FFB | S355 |  | Stirnplatte |  | Wartung_FFB | Plate | 0121Kop0000020066 | Stirnplatte | false | T101.1 | HI_PRO_STA_0,300x0,580x0,025 | PlateCommon - Feuerwiderstandsklasse: <undefiniert>; Schallschutzklasse: <undefiniert>
Stirnplatte | Wartung_FFB | S355 |  | Stirnplatte |  | Wartung_FFB | Plate | 0121Kop0000020067 | Stirnplatte | false | T101.1 | HI_PRO_STA_0,300x0,530x0,025 | PlateCommon - Feuerwiderstandsklasse: <undefiniert>; Schallschutzklasse: <undefiniert>
Stirnplatte | Wartung_FFB | S355 |  | Stirnplatte |  | Wartung_FFB | Plate | 0121Kop0000020068 | Stirnplatte | false | T101.1 | HI_PRO_STA_0,300x0,530x0,025 | PlateCommon - Feuerwiderstandsklasse: <undefiniert>; Schallschutzklasse: <undefiniert>
Stirnplatte | Wartung_FFB | S355 |  | Stirnplatte |  | Wartung_FFB | Plate | 0121Kop0000020089 | Stirnplatte | false | T101.1 | HI_PRO_STA_0,300x0,530x0,025 | PlateCommon - Feuerwiderstandsklasse: <undefiniert>; Schallschutzklasse: <undefiniert>
Stirnplatte | Wartung_FFB | S355 |  | Stirnplatte |  | Wartung_FFB | Plate | 0121Kop0000020090 | Stirnplatte | false | T101.1 | HI_PRO_STA_0,300x0,530x0,025 | PlateCommon - Feuerwiderstandsklasse: <undefiniert>; Schallschutzklasse: <undefiniert>
Stirnplatte | Wartung_FFB | S355 |  | Stirnplatte |  | Wartung_FFB | Plate | 0121Kop0000020091 | Stirnplatte | false | T101.1 | HI_PRO_STA_0,300x0,530x0,025 | PlateCommon - Feuerwiderstandsklasse: <undefiniert>; Schallschutzklasse: <undefiniert>
Stirnplatte | Wartung_FFB | S355 |  | Stirnplatte |  | Wartung_FFB | Plate | 0121Kop0000020092 | Stirnplatte | false | T101.1 | HI_PRO_STA_0,300x0,530x0,025 | PlateCommon - Feuerwiderstandsklasse: <undefiniert>; Schallschutzklasse: <undefiniert>
Stirnplatte | Wartung_FFB | S355 |  | Stirnplatte |  | Wartung_FFB | Plate | 0121Kop0000020093 | Stirnplatte | false | T101.1 | HI_PRO_STA_0,300x0,530x0,025 | PlateCommon - Feuerwiderstandsklasse: <undefiniert>; Schallschutzklasse: <undefiniert>
Stirnplatte | Wartung_FFB | S355 |  | Stirnplatte |  | Wartung_FFB | Plate | 0121Kop0000020094 | Stirnplatte | false | T101.1 | HI_PRO_STA_0,300x0,530x0,025 | PlateCommon - Feuerwiderstandsklasse: <undefiniert>; Schallschutzklasse: <undefiniert>
Stirnplatte | Wartung_FFB | S355 |  | Stirnplatte |  | Wartung_FFB | Plate | 0121Kop0000020095 | Stirnplatte | false | T101.1 | HI_PRO_STA_0,300x0,530x0,025 | PlateCommon - Feuerwiderstandsklasse: <undefiniert>; Schallschutzklasse: <undefiniert>
Stirnplatte | Wartung_FFB | S355 |  | Stirnplatte |  | Wartung_FFB | Plate | 0121Kop0000020096 | Stirnplatte | false | T101.1 | HI_PRO_STA_0,300x0,530x0,025 | PlateCommon - Feuerwiderstandsklasse: <undefiniert>; Schallschutzklasse: <undefiniert>
Stirnplatte | Wartung_FFB | S355 |  | Stirnplatte |  | Wartung_FFB | Plate | 0121Kop0000020097 | Stirnplatte | false | T101.1 | HI_PRO_STA_0,300x0,530x0,025 | PlateCommon - Feuerwiderstandsklasse: <undefiniert>; Schallschutzklasse: <undefiniert>
Stirnplatte | Wartung_FFB | S355 |  | Stirnplatte |  | Wartung_FFB | Plate | 0121Kop0000020108 | Stirnplatte | false | T101.1 | HI_PRO_STA_0,300x0,530x0,025 | PlateCommon - Feuerwiderstandsklasse: <undefiniert>; Schallschutzklasse: <undefiniert>
Stirnplatte | Wartung_FFB | S355 |  | Stirnplatte |  | Wartung_FFB | Plate | 0121Kop0000020119 | Stirnplatte | false | T101.1 | HI_PRO_STA_0,300x0,530x0,025 | PlateCommon - Feuerwiderstandsklasse: <undefiniert>; Schallschutzklasse: <undefiniert>
Stirnplatte | Wartung_FFB | S355 |  | Stirnplatte |  | Wartung_FFB | Plate | 0121Kop0000020120 | Stirnplatte | false | T101.1 | HI_PRO_STA_0,300x0,530x0,025 | PlateCommon - Feuerwiderstandsklasse: <undefiniert>; Schallschutzklasse: <undefiniert>
Stirnplatte | Wartung_FFB | S355 |  | Stirnplatte |  | Wartung_FFB | Plate | 0121Kop0000020121 | Stirnplatte | false | T101.1 | HI_PRO_STA_0,300x0,530x0,025 | PlateCommon - Feuerwiderstandsklasse: <undefiniert>; Schallschutzklasse: <undefiniert>
Stirnplatte | Wartung_FFB | S355 |  | Stirnplatte |  | Wartung_FFB | Plate | 0121Kop0000020122 | Stirnplatte | false | T101.1 | HI_PRO_STA_0,300x0,530x0,025 | PlateCommon - Feuerwiderstandsklasse: <undefiniert>; Schallschutzklasse: <undefiniert>
Stirnplatte | Wartung_FFB | S355 |  | Stirnplatte |  | Wartung_FFB | Plate | 0121Kop0000020123 | Stirnplatte | false | T101.1 | HI_PRO_STA_0,300x0,530x0,025 | PlateCommon - Feuerwiderstandsklasse: <undefiniert>; Schallschutzklasse: <undefiniert>
Stirnplatte | Wartung_FFB | S355 |  | Stirnplatte |  | Wartung_FFB | Plate | 0121Kop0000020124 | Stirnplatte | false | T101.1 | HI_PRO_STA_0,300x0,530x0,025 | PlateCommon - Feuerwiderstandsklasse: <undefiniert>; Schallschutzklasse: <undefiniert>
Stirnplatte | Wartung_FFB | S355 |  | Stirnplatte |  | Wartung_FFB | Plate | 0121Kop0000020125 | Stirnplatte | false | T101.1 | HI_PRO_STA_0,300x0,530x0,025 | PlateCommon - Feuerwiderstandsklasse: <undefiniert>; Schallschutzklasse: <undefiniert>
Stirnplatte | Wartung_FFB | S355 |  | Stirnplatte |  | Wartung_FFB | Plate | 0121Kop0000020126 | Stirnplatte | false | T101.1 | HI_PRO_STA_0,300x0,530x0,025 | PlateCommon - Feuerwiderstandsklasse: <undefiniert>; Schallschutzklasse: <undefiniert>
Stirnplatte | Wartung_FFB | S355 |  | Stirnplatte |  | Wartung_FFB | Plate | 0121Kop0000020130 | Stirnplatte | false | T101.1 | HI_PRO_STA_0,300x0,530x0,025 | PlateCommon - Feuerwiderstandsklasse: <undefiniert>; Schallschutzklasse: <undefiniert>
Stirnplatte | Wartung_FFB | S355 |  | Stirnplatte |  | Wartung_FFB | Plate | 0121Kop0000020131 | Stirnplatte | false | T101.1 | HI_PRO_STA_0,300x0,530x0,025 | PlateCommon - Feuerwiderstandsklasse: <undefiniert>; Schallschutzklasse: <undefiniert>
Stirnplatte | Wartung_FFB | S355 |  | Stirnplatte |  | Wartung_FFB | Plate | 0121Kop0000020138 | Stirnplatte | false | T101.1 | HI_PRO_STA_0,300x0,530x0,025 | PlateCommon - Feuerwiderstandsklasse: <undefiniert>; Schallschutzklasse: <undefiniert>
Stirnplatte | Wartung_FFB | S355 |  | Stirnplatte |  | Wartung_FFB | Plate | 0121Kop0000020139 | Stirnplatte | false | T101.1 | HI_PRO_STA_0,300x0,530x0,025 | PlateCommon - Feuerwiderstandsklasse: <undefiniert>; Schallschutzklasse: <undefiniert>
Stirnplatte | Wartung_FFB | S355 |  | Stirnplatte |  | Wartung_FFB | Plate | 0121Kop0000020162 | Stirnplatte | false | T101.1 | HI_PRO_STA_0,300x0,680x0,025 | PlateCommon - Feuerwiderstandsklasse: <undefiniert>; Schallschutzklasse: <undefiniert>
Stirnplatte | Wartung_FFB | S355 |  | Stirnplatte |  | Wartung_FFB | Plate | 0121Kop0000020163 | Stirnplatte | false | T101.1 | HI_PRO_STA_0,300x0,680x0,025 | PlateCommon - Feuerwiderstandsklasse: <undefiniert>; Schallschutzklasse: <undefiniert>
Stirnplatte | Wartung_FFB | S355 |  | Stirnplatte |  | Wartung_FFB | Plate | 0121Kop0000020164 | Stirnplatte | false | T101.1 | HI_PRO_STA_0,300x0,680x0,025 | PlateCommon - Feuerwiderstandsklasse: <undefiniert>; Schallschutzklasse: <undefiniert>
Stirnplatte | Wartung_FFB | S355 |  | Stirnplatte |  | Wartung_FFB | Plate | 0121Kop0000020165 | Stirnplatte | false | T101.1 | HI_PRO_STA_0,300x0,680x0,025 | PlateCommon - Feuerwiderstandsklasse: <undefiniert>; Schallschutzklasse: <undefiniert>
Stirnplatte | Wartung_FFB | S355 |  | Stirnplatte |  | Wartung_FFB | Plate | 0121Kop0000020169 | Stirnplatte | false | T101.1 | HI_PRO_STA_0,300x0,680x0,025 | PlateCommon - Feuerwiderstandsklasse: <undefiniert>; Schallschutzklasse: <undefiniert>
Stirnplatte | Wartung_FFB | S355 |  | Stirnplatte |  | Wartung_FFB | Plate | 0121Kop0000020170 | Stirnplatte | false | T101.1 | HI_PRO_STA_0,300x0,680x0,025 | PlateCommon - Feuerwiderstandsklasse: <undefiniert>; Schallschutzklasse: <undefiniert>
Stirnplatte | Wartung_FFB | S355 |  | Stirnplatte |  | Wartung_FFB | Plate | 0121Kop0000020171 | Stirnplatte | false | T101.1 | HI_PRO_STA_0,300x0,680x0,025 | PlateCommon - Feuerwiderstandsklasse: <undefiniert>; Schallschutzklasse: <undefiniert>
Stirnplatte | Wartung_FFB | S355 |  | Stirnplatte |  | Wartung_FFB | Plate | 0121Kop0000020172 | Stirnplatte | false | T101.1 | HI_PRO_STA_0,300x0,680x0,025 | PlateCommon - Feuerwiderstandsklasse: <undefiniert>; Schallschutzklasse: <undefiniert>
Stirnplatte | Wartung_FFB | S355 |  | Stirnplatte |  | Wartung_FFB | Plate | 0121Kop0000020182 | Stirnplatte | false | T101.1 | HI_PRO_STA_0,300x0,680x0,025 | PlateCommon - Feuerwiderstandsklasse: <undefiniert>; Schallschutzklasse: <undefiniert>
Stirnplatte | Wartung_FFB | S355 |  | Stirnplatte |  | Wartung_FFB | Plate | 0121Kop0000020183 | Stirnplatte | false | T101.1 | HI_PRO_STA_0,300x0,680x0,025 | PlateCommon - Feuerwiderstandsklasse: <undefiniert>; Schallschutzklasse: <undefiniert>
Stirnplatte | Wartung_FFB | S355 |  | Stirnplatte |  | Wartung_FFB | Plate | 0121Kop0000020184 | Stirnplatte | false | T101.1 | HI_PRO_STA_0,300x0,680x0,025 | PlateCommon - Feuerwiderstandsklasse: <undefiniert>; Schallschutzklasse: <undefiniert>
Stirnplatte | Wartung_FFB | S355 |  | Stirnplatte |  | Wartung_FFB | Plate | 0121Kop0000020185 | Stirnplatte | false | T101.1 | HI_PRO_STA_0,300x0,680x0,025 | PlateCommon - Feuerwiderstandsklasse: <undefiniert>; Schallschutzklasse: <undefiniert>
Stirnplatte | Wartung_FFB | S355 |  | Stirnplatte |  | Wartung_FFB | Plate | 0121Kop0000020195 | Stirnplatte | false | T101.1 | HI_PRO_STA_0,300x0,680x0,025 | PlateCommon - Feuerwiderstandsklasse: <undefiniert>; Schallschutzklasse: <undefiniert>
Stirnplatte | Wartung_FFB | S355 |  | Stirnplatte |  | Wartung_FFB | Plate | 0121Kop0000020196 | Stirnplatte | false | T101.1 | HI_PRO_STA_0,300x0,680x0,025 | PlateCommon - Feuerwiderstandsklasse: <undefiniert>; Schallschutzklasse: <undefiniert>
Stirnplatte | Wartung_FFB | S355 |  | Stirnplatte |  | Wartung_FFB | Plate | 0121Kop0000020197 | Stirnplatte | false | T101.1 | HI_PRO_STA_0,300x0,680x0,025 | PlateCommon - Feuerwiderstandsklasse: <undefiniert>; Schallschutzklasse: <undefiniert>
Stirnplatte | Wartung_FFB | S355 |  | Stirnplatte |  | Wartung_FFB | Plate | 0121Kop0000020198 | Stirnplatte | false | T101.1 | HI_PRO_STA_0,300x0,680x0,025 | PlateCommon - Feuerwiderstandsklasse: <undefiniert>; Schallschutzklasse: <undefiniert>
Stirnplatte | Wartung_FFB | S355 |  | Stirnplatte |  | Wartung_FFB | Plate | 0121Kop0000020208 | Stirnplatte | false | T101.1 | HI_PRO_STA_0,300x0,680x0,025 | PlateCommon - Feuerwiderstandsklasse: <undefiniert>; Schallschutzklasse: <undefiniert>
Stirnplatte | Wartung_FFB | S355 |  | Stirnplatte |  | Wartung_FFB | Plate | 0121Kop0000020209 | Stirnplatte | false | T101.1 | HI_PRO_STA_0,300x0,680x0,025 | PlateCommon - Feuerwiderstandsklasse: <undefiniert>; Schallschutzklasse: <undefiniert>
Stirnplatte | Wartung_FFB | S355 |  | Stirnplatte |  | Wartung_FFB | Plate | 0121Kop0000020210 | Stirnplatte | false | T101.1 | HI_PRO_STA_0,300x0,680x0,025 | PlateCommon - Feuerwiderstandsklasse: <undefiniert>; Schallschutzklasse: <undefiniert>
Stirnplatte | Wartung_FFB | S355 |  | Stirnplatte |  | Wartung_FFB | Plate | 0121Kop0000020211 | Stirnplatte | false | T101.1 | HI_PRO_STA_0,300x0,680x0,025 | PlateCommon - Feuerwiderstandsklasse: <undefiniert>; Schallschutzklasse: <undefiniert>
Stirnplatte | Wartung_FFB | S355 |  | Stirnplatte |  | Wartung_FFB | Plate | 0121Kop0000020215 | Stirnplatte | false | T101.1 | HI_PRO_STA_0,300x0,680x0,025 | PlateCommon - Feuerwiderstandsklasse: <undefiniert>; Schallschutzklasse: <undefiniert>
Stirnplatte | Wartung_FFB | S355 |  | Stirnplatte |  | Wartung_FFB | Plate | 0121Kop0000020216 | Stirnplatte | false | T101.1 | HI_PRO_STA_0,300x0,680x0,025 | PlateCommon - Feuerwiderstandsklasse: <undefiniert>; Schallschutzklasse: <undefiniert>
Stirnplatte | Wartung_FFB | S355 |  | Stirnplatte |  | Wartung_FFB | Plate | 0121Kop0000020217 | Stirnplatte | false | T101.1 | HI_PRO_STA_0,300x0,680x0,025 | PlateCommon - Feuerwiderstandsklasse: <undefiniert>; Schallschutzklasse: <undefiniert>
Stirnplatte | Wartung_FFB | S355 |  | Stirnplatte |  | Wartung_FFB | Plate | 0121Kop0000020218 | Stirnplatte | false | T101.1 | HI_PRO_STA_0,300x0,680x0,025 | PlateCommon - Feuerwiderstandsklasse: <undefiniert>; Schallschutzklasse: <undefiniert>
Stirnplatte | Wartung_FFB | S355 |  | Stirnplatte |  | Wartung_FFB | Plate | 0121Kop0000020234 | Stirnplatte | false | T101.1 | HI_PRO_STA_0,300x0,680x0,025 | PlateCommon - Feuerwiderstandsklasse: <undefiniert>; Schallschutzklasse: <undefiniert>
Stirnplatte | Wartung_FFB | S355 |  | Stirnplatte |  | Wartung_FFB | Plate | 0121Kop0000020235 | Stirnplatte | false | T101.1 | HI_PRO_STA_0,300x0,680x0,025 | PlateCommon - Feuerwiderstandsklasse: <undefiniert>; Schallschutzklasse: <undefiniert>
Stirnplatte | Wartung_FFB | S355 |  | Stirnplatte |  | Wartung_FFB | Plate | 0121Kop0000020236 | Stirnplatte | false | T101.1 | HI_PRO_STA_0,300x0,680x0,025 | PlateCommon - Feuerwiderstandsklasse: <undefiniert>; Schallschutzklasse: <undefiniert>
Stirnplatte | Wartung_FFB | S355 |  | Stirnplatte |  | Wartung_FFB | Plate | 0121Kop0000020237 | Stirnplatte | false | T101.1 | HI_PRO_STA_0,300x0,680x0,025 | PlateCommon - Feuerwiderstandsklasse: <undefiniert>; Schallschutzklasse: <undefiniert>
Stirnplatte | Wartung_FFB | S355 |  | Stirnplatte |  | Wartung_FFB | Plate | 0121Kop0000020241 | Stirnplatte | false | T101.1 | HI_PRO_STA_0,300x0,680x0,025 | PlateCommon - Feuerwiderstandsklasse: <undefiniert>; Schallschutzklasse: <undefiniert>
Stirnplatte | Wartung_FFB | S355 |  | Stirnplatte |  | Wartung_FFB | Plate | 0121Kop0000020242 | Stirnplatte | false | T101.1 | HI_PRO_STA_0,300x0,680x0,025 | PlateCommon - Feuerwiderstandsklasse: <undefiniert>; Schallschutzklasse: <undefiniert>
Stirnplatte | Wartung_FFB | S355 |  | Stirnplatte |  | Wartung_FFB | Plate | 0121Kop0000020243 | Stirnplatte | false | T101.1 | HI_PRO_STA_0,300x0,680x0,025 | PlateCommon - Feuerwiderstandsklasse: <undefiniert>; Schallschutzklasse: <undefiniert>
Stirnplatte | Wartung_FFB | S355 |  | Stirnplatte |  | Wartung_FFB | Plate | 0121Kop0000020244 | Stirnplatte | false | T101.1 | HI_PRO_STA_0,300x0,680x0,025 | PlateCommon - Feuerwiderstandsklasse: <undefiniert>; Schallschutzklasse: <undefiniert>
Stirnplatte | Wartung_FFB | S355 |  | Stirnplatte |  | Wartung_FFB | Plate | 0121Kop0000020248 | Stirnplatte | false | T101.1 | HI_PRO_STA_0,300x0,680x0,025 | PlateCommon - Feuerwiderstandsklasse: <undefiniert>; Schallschutzklasse: <undefiniert>
Stirnplatte | Wartung_FFB | S355 |  | Stirnplatte |  | Wartung_FFB | Plate | 0121Kop0000020249 | Stirnplatte | false | T101.1 | HI_PRO_STA_0,300x0,680x0,025 | PlateCommon - Feuerwiderstandsklasse: <undefiniert>; Schallschutzklasse: <undefiniert>
Stirnplatte | Wartung_FFB | S355 |  | Stirnplatte |  | Wartung_FFB | Plate | 0121Kop0000020250 | Stirnplatte | false | T101.1 | HI_PRO_STA_0,300x0,680x0,025 | PlateCommon - Feuerwiderstandsklasse: <undefiniert>; Schallschutzklasse: <undefiniert>
Stirnplatte | Wartung_FFB | S355 |  | Stirnplatte |  | Wartung_FFB | Plate | 0121Kop0000020251 | Stirnplatte | false | T101.1 | HI_PRO_STA_0,300x0,680x0,025 | PlateCommon - Feuerwiderstandsklasse: <undefiniert>; Schallschutzklasse: <undefiniert>
Stirnplatte | Wartung_FFB | S355 |  | Stirnplatte |  | Wartung_FFB | Plate | 0121Kop0000020273 | Stirnplatte | false | T101.1 | HI_PRO_STA_0,300x0,680x0,025 | PlateCommon - Feuerwiderstandsklasse: <undefiniert>; Schallschutzklasse: <undefiniert>
Stirnplatte | Wartung_FFB | S355 |  | Stirnplatte |  | Wartung_FFB | Plate | 0121Kop0000020274 | Stirnplatte | false | T101.1 | HI_PRO_STA_0,300x0,680x0,025 | PlateCommon - Feuerwiderstandsklasse: <undefiniert>; Schallschutzklasse: <undefiniert>
Stirnplatte | Wartung_FFB | S355 |  | Stirnplatte |  | Wartung_FFB | Plate | 0121Kop0000020275 | Stirnplatte | false | T101.1 | HI_PRO_STA_0,300x0,680x0,025 | PlateCommon - Feuerwiderstandsklasse: <undefiniert>; Schallschutzklasse: <undefiniert>
Stirnplatte | Wartung_FFB | S355 |  | Stirnplatte |  | Wartung_FFB | Plate | 0121Kop0000020276 | Stirnplatte | false | T101.1 | HI_PRO_STA_0,300x0,680x0,025 | PlateCommon - Feuerwiderstandsklasse: <undefiniert>; Schallschutzklasse: <undefiniert>
Stirnplatte | Wartung_FFB | S355 |  | Stirnplatte |  | Wartung_FFB | Plate | 0121Kop0000020280 | Stirnplatte | false | T101.1 | HI_PRO_STA_0,300x0,680x0,025 | PlateCommon - Feuerwiderstandsklasse: <undefiniert>; Schallschutzklasse: <undefiniert>
Stirnplatte | Wartung_FFB | S355 |  | Stirnplatte |  | Wartung_FFB | Plate | 0121Kop0000020281 | Stirnplatte | false | T101.1 | HI_PRO_STA_0,300x0,680x0,025 | PlateCommon - Feuerwiderstandsklasse: <undefiniert>; Schallschutzklasse: <undefiniert>
Stirnplatte | Wartung_FFB | S355 |  | Stirnplatte |  | Wartung_FFB | Plate | 0121Kop0000020282 | Stirnplatte | false | T101.1 | HI_PRO_STA_0,300x0,680x0,025 | PlateCommon - Feuerwiderstandsklasse: <undefiniert>; Schallschutzklasse: <undefiniert>
Stirnplatte | Wartung_FFB | S355 |  | Stirnplatte |  | Wartung_FFB | Plate | 0121Kop0000020283 | Stirnplatte | false | T101.1 | HI_PRO_STA_0,300x0,680x0,025 | PlateCommon - Feuerwiderstandsklasse: <undefiniert>; Schallschutzklasse: <undefiniert>
Stirnplatte | Wartung_FFB | S355 |  | Stirnplatte |  | Wartung_FFB | Plate | 0121Kop0000020299 | Stirnplatte | false | T101.1 | HI_PRO_STA_0,300x0,680x0,025 | PlateCommon - Feuerwiderstandsklasse: <undefiniert>; Schallschutzklasse: <undefiniert>
Stirnplatte | Wartung_FFB | S355 |  | Stirnplatte |  | Wartung_FFB | Plate | 0121Kop0000020300 | Stirnplatte | false | T101.1 | HI_PRO_STA_0,300x0,680x0,025 | PlateCommon - Feuerwiderstandsklasse: <undefiniert>; Schallschutzklasse: <undefiniert>
Stirnplatte | Wartung_FFB | S355 |  | Stirnplatte |  | Wartung_FFB | Plate | 0121Kop0000020301 | Stirnplatte | false | T101.1 | HI_PRO_STA_0,300x0,680x0,025 | PlateCommon - Feuerwiderstandsklasse: <undefiniert>; Schallschutzklasse: <undefiniert>
Stirnplatte | Wartung_FFB | S355 |  | Stirnplatte |  | Wartung_FFB | Plate | 0121Kop0000020302 | Stirnplatte | false | T101.1 | HI_PRO_STA_0,300x0,680x0,025 | PlateCommon - Feuerwiderstandsklasse: <undefiniert>; Schallschutzklasse: <undefiniert>
Stirnplatte | Wartung_FFB | S355 |  | Stirnplatte |  | Wartung_FFB | Plate | 0121Kop0000020312 | Stirnplatte | false | T101.1 | HI_PRO_STA_0,300x0,680x0,025 | PlateCommon - Feuerwiderstandsklasse: <undefiniert>; Schallschutzklasse: <undefiniert>
Stirnplatte | Wartung_FFB | S355 |  | Stirnplatte |  | Wartung_FFB | Plate | 0121Kop0000020313 | Stirnplatte | false | T101.1 | HI_PRO_STA_0,300x0,680x0,025 | PlateCommon - Feuerwiderstandsklasse: <undefiniert>; Schallschutzklasse: <undefiniert>
Stirnplatte | Wartung_FFB | S355 |  | Stirnplatte |  | Wartung_FFB | Plate | 0121Kop0000020314 | Stirnplatte | false | T101.1 | HI_PRO_STA_0,300x0,680x0,025 | PlateCommon - Feuerwiderstandsklasse: <undefiniert>; Schallschutzklasse: <undefiniert>
Stirnplatte | Wartung_FFB | S355 |  | Stirnplatte |  | Wartung_FFB | Plate | 0121Kop0000020315 | Stirnplatte | false | T101.1 | HI_PRO_STA_0,300x0,680x0,025 | PlateCommon - Feuerwiderstandsklasse: <undefiniert>; Schallschutzklasse: <undefiniert>
Stirnplatte | Wartung_FFB | S355 |  | Stirnplatte |  | Wartung_FFB | Plate | 0121Kop0000020325 | Stirnplatte | false | T101.1 | HI_PRO_STA_0,300x0,680x0,025 | PlateCommon - Feuerwiderstandsklasse: <undefiniert>; Schallschutzklasse: <undefiniert>
Stirnplatte | Wartung_FFB | S355 |  | Stirnplatte |  | Wartung_FFB | Plate | 0121Kop0000020326 | Stirnplatte | false | T101.1 | HI_PRO_STA_0,300x0,680x0,025 | PlateCommon - Feuerwiderstandsklasse: <undefiniert>; Schallschutzklasse: <undefiniert>
Stirnplatte | Wartung_FFB | S355 |  | Stirnplatte |  | Wartung_FFB | Plate | 0121Kop0000020327 | Stirnplatte | false | T101.1 | HI_PRO_STA_0,300x0,680x0,025 | PlateCommon - Feuerwiderstandsklasse: <undefiniert>; Schallschutzklasse: <undefiniert>
Stirnplatte | Wartung_FFB | S355 |  | Stirnplatte |  | Wartung_FFB | Plate | 0121Kop0000020328 | Stirnplatte | false | T101.1 | HI_PRO_STA_0,300x0,680x0,025 | PlateCommon - Feuerwiderstandsklasse: <undefiniert>; Schallschutzklasse: <undefiniert>
Stirnplatte | Wartung_FFB | S355 |  | Stirnplatte |  | Wartung_FFB | Plate | 0121Kop0000020335 | Stirnplatte | false | T101.1 | HI_PRO_STA_0,300x0,440x0,025 | PlateCommon - Feuerwiderstandsklasse: <undefiniert>; Schallschutzklasse: <undefiniert>
Stirnplatte | Wartung_FFB | S355 |  | Stirnplatte |  | Wartung_FFB | Plate | 0121Kop0000020336 | Stirnplatte | false | T101.1 | HI_PRO_STA_0,300x0,440x0,025 | PlateCommon - Feuerwiderstandsklasse: <undefiniert>; Schallschutzklasse: <undefiniert>
Stirnplatte | Wartung_FFB | S355 |  | Stirnplatte |  | Wartung_FFB | Plate | 0121Kop0000020343 | Stirnplatte | false | T101.1 | HI_PRO_STA_0,300x0,330x0,025 | PlateCommon - Feuerwiderstandsklasse: <undefiniert>; Schallschutzklasse: <undefiniert>
Stirnplatte | Wartung_FFB | S355 |  | Stirnplatte |  | Wartung_FFB | Plate | 0121Kop0000020345 | Stirnplatte | false | T101.1 | HI_PRO_STA_0,300x0,330x0,025 | PlateCommon - Feuerwiderstandsklasse: <undefiniert>; Schallschutzklasse: <undefiniert>
Stirnplatte | Wartung_FFB | S355 |  | Stirnplatte |  | Wartung_FFB | Plate | 0121Kop0000020348 | Stirnplatte | false | T101.1 | HI_PRO_STA_0,300x0,440x0,025 | PlateCommon - Feuerwiderstandsklasse: <undefiniert>; Schallschutzklasse: <undefiniert>
Stirnplatte | Wartung_FFB | S355 |  | Stirnplatte |  | Wartung_FFB | Plate | 0121Kop0000020349 | Stirnplatte | false | T101.1 | HI_PRO_STA_0,300x0,440x0,025 | PlateCommon - Feuerwiderstandsklasse: <undefiniert>; Schallschutzklasse: <undefiniert>
Stirnplatte | Wartung_FFB | S355 |  | Stirnplatte |  | Wartung_FFB | Plate | 0121Kop0000020351 | Stirnplatte | false | T101.1 | HI_PRO_STA_0,300x0,330x0,025 | PlateCommon - Feuerwiderstandsklasse: <undefiniert>; Schallschutzklasse: <undefiniert>
Stirnplatte | Wartung_FFB | S355 |  | Stirnplatte |  | Wartung_FFB | Plate | 0121Kop0000020352 | Stirnplatte | false | T101.1 | HI_PRO_STA_0,300x0,330x0,025 | PlateCommon - Feuerwiderstandsklasse: <undefiniert>; Schallschutzklasse: <undefiniert>
Stirnplatte | Wartung_FFB | S355 |  | Stirnplatte |  | Wartung_FFB | Plate | 0121Kop0000020361 | Stirnplatte | false | T101.1 | HI_PRO_STA_0,300x0,440x0,025 | PlateCommon - Feuerwiderstandsklasse: <undefiniert>; Schallschutzklasse: <undefiniert>
Stirnplatte | Wartung_FFB | S355 |  | Stirnplatte |  | Wartung_FFB | Plate | 0121Kop0000020362 | Stirnplatte | false | T101.1 | HI_PRO_STA_0,300x0,440x0,025 | PlateCommon - Feuerwiderstandsklasse: <undefiniert>; Schallschutzklasse: <undefiniert>
Stirnplatte | Wartung_FFB | S355 |  | Stirnplatte |  | Wartung_FFB | Plate | 0121Kop0000020363 | Stirnplatte | false | T101.1 | HI_PRO_STA_0,300x0,440x0,025 | PlateCommon - Feuerwiderstandsklasse: <undefiniert>; Schallschutzklasse: <undefiniert>
Stirnplatte | Wartung_FFB | S355 |  | Stirnplatte |  | Wartung_FFB | Plate | 0121Kop0000020364 | Stirnplatte | false | T101.1 | HI_PRO_STA_0,300x0,440x0,025 | PlateCommon - Feuerwiderstandsklasse: <undefiniert>; Schallschutzklasse: <undefiniert>
Stirnplatte | Wartung_FFB | S355 |  | Stirnplatte |  | Wartung_FFB | Plate | 0121Kop0000020344 | Stirnplatte | false | T101.1 | HI_PRO_STA_0,300x0,390x0,025 | PlateCommon - Feuerwiderstandsklasse: <undefiniert>; Schallschutzklasse: <undefiniert>
Stirnplatte | Wartung_FFB | S355 |  | Stirnplatte |  | Wartung_FFB | Plate | 0121Kop0000020365 | Stirnplatte | false | T101.1 | HI_PRO_STA_0,300x0,390x0,025 | PlateCommon - Feuerwiderstandsklasse: <undefiniert>; Schallschutzklasse: <undefiniert>
Stirnplatte | Wartung_FFB | S355 |  | Stirnplatte |  | Wartung_FFB | Plate | 0121Kop0000020370 | Stirnplatte | false | T101.1 | HI_PRO_STA_0,300x0,390x0,025 | PlateCommon - Feuerwiderstandsklasse: <undefiniert>; Schallschutzklasse: <undefiniert>
Stirnplatte | Wartung_FFB | S355 |  | Stirnplatte |  | Wartung_FFB | Plate | 0121Kop0000020371 | Stirnplatte | false | T101.1 | HI_PRO_STA_0,300x0,390x0,025 | PlateCommon - Feuerwiderstandsklasse: <undefiniert>; Schallschutzklasse: <undefiniert>
Stirnplatte | Wartung_FFB | S355 |  | Stirnplatte |  | Wartung_FFB | Plate | 0121Kop0000020375 | Stirnplatte | false | T101.1 | HI_PRO_STA_0,300x0,680x0,025 | PlateCommon - Feuerwiderstandsklasse: <undefiniert>; Schallschutzklasse: <undefiniert>
Stirnplatte | Wartung_FFB | S355 |  | Stirnplatte |  | Wartung_FFB | Plate | 0121Kop0000020376 | Stirnplatte | false | T101.1 | HI_PRO_STA_0,300x0,680x0,025 | PlateCommon - Feuerwiderstandsklasse: <undefiniert>; Schallschutzklasse: <undefiniert>
Stirnplatte | Wartung_FFB | S355 |  | Stirnplatte |  | Wartung_FFB | Plate | 0121Kop0000020377 | Stirnplatte | false | T101.1 | HI_PRO_STA_0,300x0,680x0,025 | PlateCommon - Feuerwiderstandsklasse: <undefiniert>; Schallschutzklasse: <undefiniert>
Stirnplatte | Wartung_FFB | S355 |  | Stirnplatte |  | Wartung_FFB | Plate | 0121Kop0000020378 | Stirnplatte | false | T101.1 | HI_PRO_STA_0,300x0,680x0,025 | PlateCommon - Feuerwiderstandsklasse: <undefiniert>; Schallschutzklasse: <undefiniert>
Stirnplatte | Wartung_FFB | S355 |  | Stirnplatte |  | Wartung_FFB | Plate | 0121Kop0000020402 | Stirnplatte | false | T101.1 | HI_PRO_STA_0,300x0,680x0,025 | PlateCommon - Feuerwiderstandsklasse: <undefiniert>; Schallschutzklasse: <undefiniert>
Stirnplatte | Wartung_FFB | S355 |  | Stirnplatte |  | Wartung_FFB | Plate | 0121Kop0000020403 | Stirnplatte | false | T101.1 | HI_PRO_STA_0,300x0,680x0,025 | PlateCommon - Feuerwiderstandsklasse: <undefiniert>; Schallschutzklasse: <undefiniert>
Stirnplatte | Wartung_FFB | S355 |  | Stirnplatte |  | Wartung_FFB | Plate | 0121Kop0000020404 | Stirnplatte | false | T101.1 | HI_PRO_STA_0,300x0,680x0,025 | PlateCommon - Feuerwiderstandsklasse: <undefiniert>; Schallschutzklasse: <undefiniert>
Stirnplatte | Wartung_FFB | S355 |  | Stirnplatte |  | Wartung_FFB | Plate | 0121Kop0000020405 | Stirnplatte | false | T101.1 | HI_PRO_STA_0,300x0,680x0,025 | PlateCommon - Feuerwiderstandsklasse: <undefiniert>; Schallschutzklasse: <undefiniert>
Stirnplatte | Wartung_FFB | S355 |  | Stirnplatte |  | Wartung_FFB | Plate | 0121Kop0000020415 | Stirnplatte | false | T101.1 | HI_PRO_STA_0,300x0,680x0,025 | PlateCommon - Feuerwiderstandsklasse: <undefiniert>; Schallschutzklasse: <undefiniert>
Stirnplatte | Wartung_FFB | S355 |  | Stirnplatte |  | Wartung_FFB | Plate | 0121Kop0000020416 | Stirnplatte | false | T101.1 | HI_PRO_STA_0,300x0,680x0,025 | PlateCommon - Feuerwiderstandsklasse: <undefiniert>; Schallschutzklasse: <undefiniert>
Stirnplatte | Wartung_FFB | S355 |  | Stirnplatte |  | Wartung_FFB | Plate | 0121Kop0000020417 | Stirnplatte | false | T101.1 | HI_PRO_STA_0,300x0,680x0,025 | PlateCommon - Feuerwiderstandsklasse: <undefiniert>; Schallschutzklasse: <undefiniert>
Stirnplatte | Wartung_FFB | S355 |  | Stirnplatte |  | Wartung_FFB | Plate | 0121Kop0000020418 | Stirnplatte | false | T101.1 | HI_PRO_STA_0,300x0,680x0,025 | PlateCommon - Feuerwiderstandsklasse: <undefiniert>; Schallschutzklasse: <undefiniert>
Stirnplatte | Wartung_FFB | S355 |  | Stirnplatte |  | Wartung_FFB | Plate | 0121Kop0000020422 | Stirnplatte | false | T101.1 | HI_PRO_STA_0,300x0,680x0,025 | PlateCommon - Feuerwiderstandsklasse: <undefiniert>; Schallschutzklasse: <undefiniert>
Stirnplatte | Wartung_FFB | S355 |  | Stirnplatte |  | Wartung_FFB | Plate | 0121Kop0000020423 | Stirnplatte | false | T101.1 | HI_PRO_STA_0,300x0,680x0,025 | PlateCommon - Feuerwiderstandsklasse: <undefiniert>; Schallschutzklasse: <undefiniert>
Stirnplatte | Wartung_FFB | S355 |  | Stirnplatte |  | Wartung_FFB | Plate | 0121Kop0000020424 | Stirnplatte | false | T101.1 | HI_PRO_STA_0,300x0,680x0,025 | PlateCommon - Feuerwiderstandsklasse: <undefiniert>; Schallschutzklasse: <undefiniert>
Stirnplatte | Wartung_FFB | S355 |  | Stirnplatte |  | Wartung_FFB | Plate | 0121Kop0000020425 | Stirnplatte | false | T101.1 | HI_PRO_STA_0,300x0,680x0,025 | PlateCommon - Feuerwiderstandsklasse: <undefiniert>; Schallschutzklasse: <undefiniert>
Stirnplatte | Wartung_FFB | S355 |  | Stirnplatte |  | Wartung_FFB | Plate | 0121Kop0000020441 | Stirnplatte | false | T101.1 | HI_PRO_STA_0,300x0,680x0,025 | PlateCommon - Feuerwiderstandsklasse: <undefiniert>; Schallschutzklasse: <undefiniert>
Stirnplatte | Wartung_FFB | S355 |  | Stirnplatte |  | Wartung_FFB | Plate | 0121Kop0000020442 | Stirnplatte | false | T101.1 | HI_PRO_STA_0,300x0,680x0,025 | PlateCommon - Feuerwiderstandsklasse: <undefiniert>; Schallschutzklasse: <undefiniert>
Stirnplatte | Wartung_FFB | S355 |  | Stirnplatte |  | Wartung_FFB | Plate | 0121Kop0000020443 | Stirnplatte | false | T101.1 | HI_PRO_STA_0,300x0,680x0,025 | PlateCommon - Feuerwiderstandsklasse: <undefiniert>; Schallschutzklasse: <undefiniert>
Stirnplatte | Wartung_FFB | S355 |  | Stirnplatte |  | Wartung_FFB | Plate | 0121Kop0000020444 | Stirnplatte | false | T101.1 | HI_PRO_STA_0,300x0,680x0,025 | PlateCommon - Feuerwiderstandsklasse: <undefiniert>; Schallschutzklasse: <undefiniert>
Stirnplatte | Wartung_FFB | S355 |  | Stirnplatte |  | Wartung_FFB | Plate | 0121Kop0000020521 | Stirnplatte | false | T101.1 | HI_PRO_STA_0,300x0,530x0,025 | PlateCommon - Feuerwiderstandsklasse: <undefiniert>; Schallschutzklasse: <undefiniert>
Stirnplatte | Wartung_FFB | S355 |  | Stirnplatte |  | Wartung_FFB | Plate | 0121Kop0000020522 | Stirnplatte | false | T101.1 | HI_PRO_STA_0,300x0,530x0,025 | PlateCommon - Feuerwiderstandsklasse: <undefiniert>; Schallschutzklasse: <undefiniert>
Stirnplatte | Wartung_FFB | S355 |  | Stirnplatte |  | Wartung_FFB | Plate | 0121Kop0000020523 | Stirnplatte | false | T101.1 | HI_PRO_STA_0,300x0,530x0,025 | PlateCommon - Feuerwiderstandsklasse: <undefiniert>; Schallschutzklasse: <undefiniert>
Stirnplatte | Wartung_FFB | S355 |  | Stirnplatte |  | Wartung_FFB | Plate | 0121Kop0000020524 | Stirnplatte | false | T101.1 | HI_PRO_STA_0,300x0,530x0,025 | PlateCommon - Feuerwiderstandsklasse: <undefiniert>; Schallschutzklasse: <undefiniert>
Stirnplatte | Wartung_FFB | S355 |  | Stirnplatte |  | Wartung_FFB | Plate | 0121Kop0000020525 | Stirnplatte | false | T101.1 | HI_PRO_STA_0,300x0,530x0,025 | PlateCommon - Feuerwiderstandsklasse: <undefiniert>; Schallschutzklasse: <undefiniert>
Stirnplatte | Wartung_FFB | S355 |  | Stirnplatte |  | Wartung_FFB | Plate | 0121Kop0000020526 | Stirnplatte | false | T101.1 | HI_PRO_STA_0,300x0,530x0,025 | PlateCommon - Feuerwiderstandsklasse: <undefiniert>; Schallschutzklasse: <undefiniert>
Stirnplatte | Wartung_FFB | S355 |  | Stirnplatte |  | Wartung_FFB | Plate | 0121Kop0000020527 | Stirnplatte | false | T101.1 | HI_PRO_STA_0,300x0,530x0,025 | PlateCommon - Feuerwiderstandsklasse: <undefiniert>; Schallschutzklasse: <undefiniert>
Stirnplatte | Wartung_FFB | S355 |  | Stirnplatte |  | Wartung_FFB | Plate | 0121Kop0000020528 | Stirnplatte | false | T101.1 | HI_PRO_STA_0,300x0,530x0,025 | PlateCommon - Feuerwiderstandsklasse: <undefiniert>; Schallschutzklasse: <undefiniert>
Stirnplatte | Wartung_FFB | S355 |  | Stirnplatte |  | Wartung_FFB | Plate | 0121Kop0000020529 | Stirnplatte | false | T101.1 | HI_PRO_STA_0,300x0,530x0,025 | PlateCommon - Feuerwiderstandsklasse: <undefiniert>; Schallschutzklasse: <undefiniert>
Stirnplatte | Wartung_FFB | S355 |  | Stirnplatte |  | Wartung_FFB | Plate | 0121Kop0000020530 | Stirnplatte | false | T101.1 | HI_PRO_STA_0,300x0,530x0,025 | PlateCommon - Feuerwiderstandsklasse: <undefiniert>; Schallschutzklasse: <undefiniert>
Stirnplatte | Wartung_FFB | S355 |  | Stirnplatte |  | Wartung_FFB | Plate | 0121Kop0000020531 | Stirnplatte | false | T101.1 | HI_PRO_STA_0,300x0,530x0,025 | PlateCommon - Feuerwiderstandsklasse: <undefiniert>; Schallschutzklasse: <undefiniert>
Stirnplatte | Wartung_FFB | S355 |  | Stirnplatte |  | Wartung_FFB | Plate | 0121Kop0000020532 | Stirnplatte | false | T101.1 | HI_PRO_STA_0,300x0,530x0,025 | PlateCommon - Feuerwiderstandsklasse: <undefiniert>; Schallschutzklasse: <undefiniert>
Stirnplatte | Wartung_FFB | S355 |  | Stirnplatte |  | Wartung_FFB | Plate | 0121Kop0000020533 | Stirnplatte | false | T101.1 | HI_PRO_STA_0,300x0,530x0,025 | PlateCommon - Feuerwiderstandsklasse: <undefiniert>; Schallschutzklasse: <undefiniert>
Stirnplatte | Wartung_FFB | S355 |  | Stirnplatte |  | Wartung_FFB | Plate | 0121Kop0000020534 | Stirnplatte | false | T101.1 | HI_PRO_STA_0,300x0,530x0,025 | PlateCommon - Feuerwiderstandsklasse: <undefiniert>; Schallschutzklasse: <undefiniert>
Stirnplatte | Wartung_FFB | S355 |  | Stirnplatte |  | Wartung_FFB | Plate | 0121Kop0000020535 | Stirnplatte | false | T101.1 | HI_PRO_STA_0,300x0,530x0,025 | PlateCommon - Feuerwiderstandsklasse: <undefiniert>; Schallschutzklasse: <undefiniert>
Stirnplatte | Wartung_FFB | S355 |  | Stirnplatte |  | Wartung_FFB | Plate | 0121Kop0000020536 | Stirnplatte | false | T101.1 | HI_PRO_STA_0,300x0,530x0,025 | PlateCommon - Feuerwiderstandsklasse: <undefiniert>; Schallschutzklasse: <undefiniert>
Stirnplatte | Wartung_FFB | S355 |  | Stirnplatte |  | Wartung_FFB | Plate | 0121Kop0000020537 | Stirnplatte | false | T101.1 | HI_PRO_STA_0,300x0,530x0,025 | PlateCommon - Feuerwiderstandsklasse: <undefiniert>; Schallschutzklasse: <undefiniert>
Stirnplatte | Wartung_FFB | S355 |  | Stirnplatte |  | Wartung_FFB | Plate | 0121Kop0000020538 | Stirnplatte | false | T101.1 | HI_PRO_STA_0,300x0,530x0,025 | PlateCommon - Feuerwiderstandsklasse: <undefiniert>; Schallschutzklasse: <undefiniert>
Stirnplatte | Wartung_FFB | S355 |  | Stirnplatte |  | Wartung_FFB | Plate | 0121Kop0000020539 | Stirnplatte | false | T101.1 | HI_PRO_STA_0,300x0,530x0,025 | PlateCommon - Feuerwiderstandsklasse: <undefiniert>; Schallschutzklasse: <undefiniert>
Stirnplatte | Wartung_FFB | S355 |  | Stirnplatte |  | Wartung_FFB | Plate | 0121Kop0000020540 | Stirnplatte | false | T101.1 | HI_PRO_STA_0,300x0,530x0,025 | PlateCommon - Feuerwiderstandsklasse: <undefiniert>; Schallschutzklasse: <undefiniert>
Stirnplatte | Wartung_FFB | S355 |  | Stirnplatte |  | Wartung_FFB | Plate | 0121Kop0000020541 | Stirnplatte | false | T101.1 | HI_PRO_STA_0,300x0,530x0,025 | PlateCommon - Feuerwiderstandsklasse: <undefiniert>; Schallschutzklasse: <undefiniert>
Stirnplatte | Wartung_FFB | S355 |  | Stirnplatte |  | Wartung_FFB | Plate | 0121Kop0000020542 | Stirnplatte | false | T101.1 | HI_PRO_STA_0,300x0,530x0,025 | PlateCommon - Feuerwiderstandsklasse: <undefiniert>; Schallschutzklasse: <undefiniert>
Stirnplatte | Wartung_FFB | S355 |  | Stirnplatte |  | Wartung_FFB | Plate | 0121Kop0000020543 | Stirnplatte | false | T101.1 | HI_PRO_STA_0,300x0,530x0,025 | PlateCommon - Feuerwiderstandsklasse: <undefiniert>; Schallschutzklasse: <undefiniert>
Stirnplatte | Wartung_FFB | S355 |  | Stirnplatte |  | Wartung_FFB | Plate | 0121Kop0000020544 | Stirnplatte | false | T101.1 | HI_PRO_STA_0,300x0,530x0,025 | PlateCommon - Feuerwiderstandsklasse: <undefiniert>; Schallschutzklasse: <undefiniert>
Stirnplatte | Wartung_FFB | S355 |  | Stirnplatte |  | Wartung_FFB | Plate | 0121Kop0000020545 | Stirnplatte | false | T101.1 | HI_PRO_STA_0,300x0,530x0,025 | PlateCommon - Feuerwiderstandsklasse: <undefiniert>; Schallschutzklasse: <undefiniert>
Stirnplatte | Wartung_FFB | S355 |  | Stirnplatte |  | Wartung_FFB | Plate | 0121Kop0000020546 | Stirnplatte | false | T101.1 | HI_PRO_STA_0,300x0,530x0,025 | PlateCommon - Feuerwiderstandsklasse: <undefiniert>; Schallschutzklasse: <undefiniert>
Stirnplatte | Wartung_FFB | S355 |  | Stirnplatte |  | Wartung_FFB | Plate | 0121Kop0000020547 | Stirnplatte | false | T101.1 | HI_PRO_STA_0,300x0,530x0,025 | PlateCommon - Feuerwiderstandsklasse: <undefiniert>; Schallschutzklasse: <undefiniert>
Stirnplatte | Wartung_FFB | S355 |  | Stirnplatte |  | Wartung_FFB | Plate | 0121Kop0000020548 | Stirnplatte | false | T101.1 | HI_PRO_STA_0,300x0,530x0,025 | PlateCommon - Feuerwiderstandsklasse: <undefiniert>; Schallschutzklasse: <undefiniert>
Stirnplatte | Wartung_FFB | S355 |  | Stirnplatte |  | Wartung_FFB | Plate | 0121Kop0000020549 | Stirnplatte | false | T101.1 | HI_PRO_STA_0,300x0,630x0,025 | PlateCommon - Feuerwiderstandsklasse: <undefiniert>; Schallschutzklasse: <undefiniert>
Stirnplatte | Wartung_FFB | S355 |  | Stirnplatte |  | Wartung_FFB | Plate | 0121Kop0000020550 | Stirnplatte | false | T101.1 | HI_PRO_STA_0,300x0,630x0,025 | PlateCommon - Feuerwiderstandsklasse: <undefiniert>; Schallschutzklasse: <undefiniert>
Stirnplatte | Wartung_FFB | S355 |  | Stirnplatte |  | Wartung_FFB | Plate | 0121Kop0000020565 | Stirnplatte | false | T101.1 | HI_PRO_STA_0,300x0,630x0,025 | PlateCommon - Feuerwiderstandsklasse: <undefiniert>; Schallschutzklasse: <undefiniert>
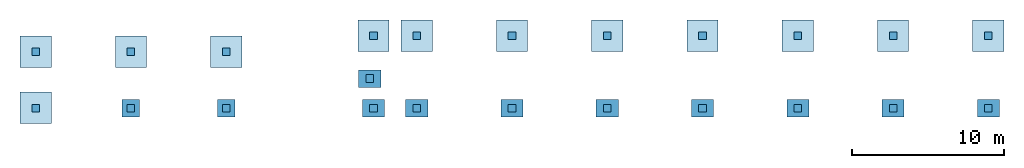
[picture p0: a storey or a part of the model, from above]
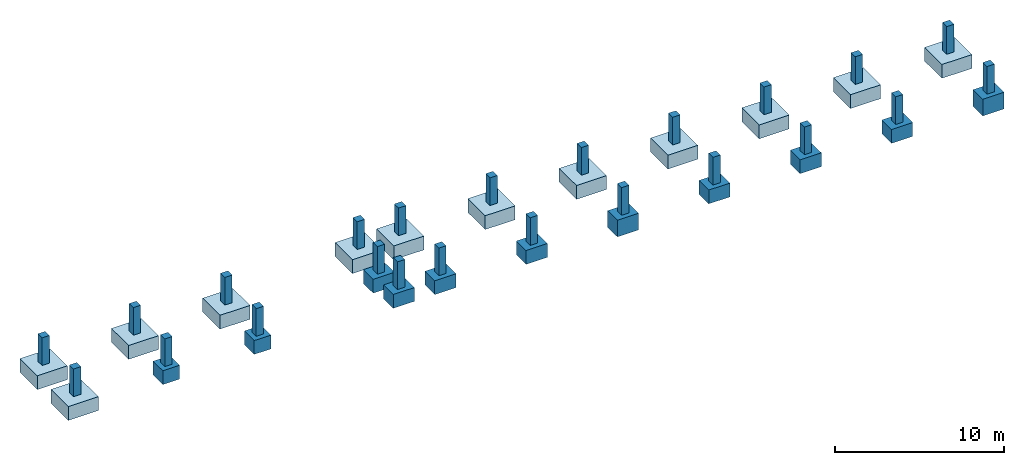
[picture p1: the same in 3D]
Properties of the parts of a building model (IFC2X3), part 18 of 25

# IfcPlate (1015)
Name | In | Material = AllplanAttributes, Material | V6 (m) = V7 (m) = V8 (m) = V9 | Bezeichnung | Plugin_Objektname | Ebene | Attributset-Objekt | Allright_Bauteil_ID | Name | Außenbauteil | Positionsnummer | PlateCommon, Reference | Unterkante (m) = X_Koordinate (m) | Oberkante (m) | Y_Koordinate (m) = Schwerpunkt_Y (m) | Z_Koordinate (m) = Schwerpunkt_Z (m) = Achsenstartpunkt (Z) (m) | Schwerpunkt_X (m) | Dicke (w) (m) | Achsenstartpunkt (X) (m) = Achsenendpunkt (X) (m) | Achsenstartpunkt (Y) (m) = Achsenendpunkt (Y) (m) | Achsenendpunkt (Z) (m) | Objektdrehwinkel
Stirnplatte | Wartung_FFB | S355 |  | Stirnplatte |  | Wartung_FFB | Plate | 0121Kop0000020566 | Stirnplatte | false | T101.1 | HI_PRO_STA_0,300x0,630x0,025 | PlateCommon - Feuerwiderstandsklasse: <undefiniert>; Schallschutzklasse: <undefiniert>
Stirnplatte | Wartung_FFB | S355 |  | Stirnplatte |  | Wartung_FFB | Plate | 0121Kop0000020569 | Stirnplatte | false | T101.1 | HI_PRO_STA_0,300x0,630x0,025 | PlateCommon - Feuerwiderstandsklasse: <undefiniert>; Schallschutzklasse: <undefiniert>
Stirnplatte | Wartung_FFB | S355 |  | Stirnplatte |  | Wartung_FFB | Plate | 0121Kop0000020570 | Stirnplatte | false | T101.1 | HI_PRO_STA_0,300x0,630x0,025 | PlateCommon - Feuerwiderstandsklasse: <undefiniert>; Schallschutzklasse: <undefiniert>
Stirnplatte | Wartung_FFB | S355 |  | Stirnplatte |  | Wartung_FFB | Plate | 0121Kop0000020557 | Stirnplatte | false | T102d.li | HI_PRO_STA_0,300x0,630x0,025 | PlateCommon - Feuerwiderstandsklasse: <undefiniert>; Schallschutzklasse: <undefiniert>
Stirnplatte | Wartung_FFB | S355 |  | Stirnplatte |  | Wartung_FFB | Plate | 0121Kop0000020558 | Stirnplatte | false | T102d.li | HI_PRO_STA_0,300x0,630x0,025 | PlateCommon - Feuerwiderstandsklasse: <undefiniert>; Schallschutzklasse: <undefiniert>
Stirnplatte | Wartung_FFB | S355 |  | Stirnplatte |  | Wartung_FFB | Plate | 0121Kop0000020567 | Stirnplatte | false | T102d.li | HI_PRO_STA_0,300x0,630x0,025 | PlateCommon - Feuerwiderstandsklasse: <undefiniert>; Schallschutzklasse: <undefiniert>
Stirnplatte | Wartung_FFB | S355 |  | Stirnplatte |  | Wartung_FFB | Plate | 0121Kop0000020568 | Stirnplatte | false | T102d.li | HI_PRO_STA_0,300x0,630x0,025 | PlateCommon - Feuerwiderstandsklasse: <undefiniert>; Schallschutzklasse: <undefiniert>
Stirnplatte | Wartung_FFB | S355 |  | Stirnplatte |  | Wartung_FFB | Plate | 0121Kop0000020571 | Stirnplatte | false | T102d.li | HI_PRO_STA_0,300x0,630x0,025 | PlateCommon - Feuerwiderstandsklasse: <undefiniert>; Schallschutzklasse: <undefiniert>
Stirnplatte | Wartung_FFB | S355 |  | Stirnplatte |  | Wartung_FFB | Plate | 0121Kop0000020572 | Stirnplatte | false | T102d.li | HI_PRO_STA_0,300x0,630x0,025 | PlateCommon - Feuerwiderstandsklasse: <undefiniert>; Schallschutzklasse: <undefiniert>
Stirnplatte | Wartung_FFB | S355 |  | Stirnplatte |  | Wartung_FFB | Plate | 0121Kop0000020578 | Stirnplatte | false | T101.1 | HI_PRO_STA_0,300x0,350x0,025 | PlateCommon - Feuerwiderstandsklasse: <undefiniert>; Schallschutzklasse: <undefiniert>
Stirnplatte | Wartung_FFB | S355 |  | Stirnplatte |  | Wartung_FFB | Plate | 0121Kop0000020577 | Stirnplatte | false | T101.1 | HI_PRO_STA_0,300x0,350x0,025 | PlateCommon - Feuerwiderstandsklasse: <undefiniert>; Schallschutzklasse: <undefiniert>
Stirnplatte | Wartung_FFB | S355 |  | Stirnplatte |  | Wartung_FFB | Plate | 0121Kop0000020583 | Stirnplatte | false | T101.1 | HI_PRO_STA_0,300x0,350x0,025 | PlateCommon - Feuerwiderstandsklasse: <undefiniert>; Schallschutzklasse: <undefiniert>
Stirnplatte | Wartung_FFB | S355 |  | Stirnplatte |  | Wartung_FFB | Plate | 0121Kop0000020584 | Stirnplatte | false | T101.1 | HI_PRO_STA_0,300x0,350x0,025 | PlateCommon - Feuerwiderstandsklasse: <undefiniert>; Schallschutzklasse: <undefiniert>
Stirnplatte | Wartung_FFB | S355 |  | Stirnplatte |  | Wartung_FFB | Plate | 0121Kop0000020587 | Stirnplatte | false | T101.1 | HI_PRO_STA_0,300x0,350x0,025 | PlateCommon - Feuerwiderstandsklasse: <undefiniert>; Schallschutzklasse: <undefiniert>
Stirnplatte | Wartung_FFB | S355 |  | Stirnplatte |  | Wartung_FFB | Plate | 0121Kop0000020588 | Stirnplatte | false | T101.1 | HI_PRO_STA_0,300x0,350x0,025 | PlateCommon - Feuerwiderstandsklasse: <undefiniert>; Schallschutzklasse: <undefiniert>
Stirnplatte | Wartung_FFB | S355 |  | Stirnplatte |  | Wartung_FFB | Plate | 0121Kop0000020599 | Stirnplatte | false | T101.1 | HI_PRO_STA_0,240x0,350x0,025 | PlateCommon - Feuerwiderstandsklasse: <undefiniert>; Schallschutzklasse: <undefiniert>
Stirnplatte | Wartung_FFB | S355 |  | Stirnplatte |  | Wartung_FFB | Plate | 0121Kop0000020623 | Stirnplatte | false | T101.1 | HI_PRO_STA_0,300x0,390x0,025 | PlateCommon - Feuerwiderstandsklasse: <undefiniert>; Schallschutzklasse: <undefiniert>
Stirnplatte | Wartung_FFB | S355 |  | Stirnplatte |  | Wartung_FFB | Plate | 0121Kop0000020624 | Stirnplatte | false | T101.1 | HI_PRO_STA_0,300x0,390x0,025 | PlateCommon - Feuerwiderstandsklasse: <undefiniert>; Schallschutzklasse: <undefiniert>
Stirnplatte | Wartung_FFB | S355 |  | Stirnplatte |  | Wartung_FFB | Plate | 0121Kop0000020638 | Stirnplatte | false | T101.1 | HI_PRO_STA_0,300x0,390x0,025 | PlateCommon - Feuerwiderstandsklasse: <undefiniert>; Schallschutzklasse: <undefiniert>
Stirnplatte | Wartung_FFB | S355 |  | Stirnplatte |  | Wartung_FFB | Plate | 0121Kop0000020639 | Stirnplatte | false | T101.1 | HI_PRO_STA_0,300x0,390x0,025 | PlateCommon - Feuerwiderstandsklasse: <undefiniert>; Schallschutzklasse: <undefiniert>
Stirnplatte | Wartung_FFB | S355 |  | Stirnplatte |  | Wartung_FFB | Plate | 0121Kop0000020646 | Stirnplatte | false | T101.1 | HI_PRO_STA_0,300x0,390x0,025 | PlateCommon - Feuerwiderstandsklasse: <undefiniert>; Schallschutzklasse: <undefiniert>
Stirnplatte | Wartung_FFB | S355 |  | Stirnplatte |  | Wartung_FFB | Plate | 0121Kop0000020647 | Stirnplatte | false | T101.1 | HI_PRO_STA_0,300x0,390x0,025 | PlateCommon - Feuerwiderstandsklasse: <undefiniert>; Schallschutzklasse: <undefiniert>
Stirnplatte | Wartung_FFB | S355 |  | Stirnplatte |  | Wartung_FFB | Plate | 0121Kop0000020654 | Stirnplatte | false | T101.1 | HI_PRO_STA_0,300x0,390x0,025 | PlateCommon - Feuerwiderstandsklasse: <undefiniert>; Schallschutzklasse: <undefiniert>
Stirnplatte | Wartung_FFB | S355 |  | Stirnplatte |  | Wartung_FFB | Plate | 0121Kop0000020655 | Stirnplatte | false | T101.1 | HI_PRO_STA_0,300x0,390x0,025 | PlateCommon - Feuerwiderstandsklasse: <undefiniert>; Schallschutzklasse: <undefiniert>
Stirnplatte | Wartung_FFB | S355 |  | Stirnplatte |  | Wartung_FFB | Plate | 0121Kop0000020662 | Stirnplatte | false | T101.1 | HI_PRO_STA_0,300x0,390x0,025 | PlateCommon - Feuerwiderstandsklasse: <undefiniert>; Schallschutzklasse: <undefiniert>
Stirnplatte | Wartung_FFB | S355 |  | Stirnplatte |  | Wartung_FFB | Plate | 0121Kop0000020663 | Stirnplatte | false | T101.1 | HI_PRO_STA_0,300x0,390x0,025 | PlateCommon - Feuerwiderstandsklasse: <undefiniert>; Schallschutzklasse: <undefiniert>
Stirnplatte | Wartung_FFB | S355 |  | Stirnplatte |  | Wartung_FFB | Plate | 0121Kop0000020670 | Stirnplatte | false | T101.1 | HI_PRO_STA_0,300x0,390x0,025 | PlateCommon - Feuerwiderstandsklasse: <undefiniert>; Schallschutzklasse: <undefiniert>
Stirnplatte | Wartung_FFB | S355 |  | Stirnplatte |  | Wartung_FFB | Plate | 0121Kop0000020671 | Stirnplatte | false | T101.1 | HI_PRO_STA_0,300x0,390x0,025 | PlateCommon - Feuerwiderstandsklasse: <undefiniert>; Schallschutzklasse: <undefiniert>
Stirnplatte | Wartung_FFB | S355 |  | Stirnplatte |  | Wartung_FFB | Plate | 0121Kop0000020678 | Stirnplatte | false | T101.1 | HI_PRO_STA_0,300x0,390x0,025 | PlateCommon - Feuerwiderstandsklasse: <undefiniert>; Schallschutzklasse: <undefiniert>
Stirnplatte | Wartung_FFB | S355 |  | Stirnplatte |  | Wartung_FFB | Plate | 0121Kop0000020679 | Stirnplatte | false | T101.1 | HI_PRO_STA_0,300x0,390x0,025 | PlateCommon - Feuerwiderstandsklasse: <undefiniert>; Schallschutzklasse: <undefiniert>
Stirnplatte | Wartung_FFB | S355 |  | Stirnplatte |  | Wartung_FFB | Plate | 0121Kop0000020682 | Stirnplatte | false | T101.1 | HI_PRO_STA_0,300x0,390x0,025 | PlateCommon - Feuerwiderstandsklasse: <undefiniert>; Schallschutzklasse: <undefiniert>
Stirnplatte | Wartung_FFB | S355 |  | Stirnplatte |  | Wartung_FFB | Plate | 0121Kop0000020683 | Stirnplatte | false | T101.1 | HI_PRO_STA_0,300x0,390x0,025 | PlateCommon - Feuerwiderstandsklasse: <undefiniert>; Schallschutzklasse: <undefiniert>
Stirnplatte | Wartung_FFB | S355 |  | Stirnplatte |  | Wartung_FFB | Plate | 0121Kop0000020712 | Stirnplatte | false | T101.1 | HI_PRO_STA_0,300x0,430x0,025 | PlateCommon - Feuerwiderstandsklasse: <undefiniert>; Schallschutzklasse: <undefiniert>
Stirnplatte | Wartung_FFB | S355 |  | Stirnplatte |  | Wartung_FFB | Plate | 0121Kop0000020713 | Stirnplatte | false | T101.1 | HI_PRO_STA_0,300x0,430x0,025 | PlateCommon - Feuerwiderstandsklasse: <undefiniert>; Schallschutzklasse: <undefiniert>
Stirnplatte | Wartung_FFB | S355 |  | Stirnplatte |  | Wartung_FFB | Plate | 0121Kop0000020729 | Stirnplatte | false | T101.1 | HI_PRO_STA_0,300x0,480x0,025 | PlateCommon - Feuerwiderstandsklasse: <undefiniert>; Schallschutzklasse: <undefiniert>
Stirnplatte | Wartung_FFB | S355 |  | Stirnplatte |  | Wartung_FFB | Plate | 0121Kop0000020730 | Stirnplatte | false | T101.1 | HI_PRO_STA_0,300x0,480x0,025 | PlateCommon - Feuerwiderstandsklasse: <undefiniert>; Schallschutzklasse: <undefiniert>
Stirnplatte | Wartung_FFB | S355 |  | Stirnplatte |  | Wartung_FFB | Plate | 0121Kop0000020731 | Stirnplatte | false | T101.1 | HI_PRO_STA_0,300x0,480x0,025 | PlateCommon - Feuerwiderstandsklasse: <undefiniert>; Schallschutzklasse: <undefiniert>
Stirnplatte | Wartung_FFB | S355 |  | Stirnplatte |  | Wartung_FFB | Plate | 0121Kop0000020732 | Stirnplatte | false | T101.1 | HI_PRO_STA_0,300x0,480x0,025 | PlateCommon - Feuerwiderstandsklasse: <undefiniert>; Schallschutzklasse: <undefiniert>
Stirnplatte | Wartung_FFB | S355 |  | Stirnplatte |  | Wartung_FFB | Plate | 0121Kop0000020737 | Stirnplatte | false | T101.1 | HI_PRO_STA_0,300x0,480x0,025 | PlateCommon - Feuerwiderstandsklasse: <undefiniert>; Schallschutzklasse: <undefiniert>
Stirnplatte | Wartung_FFB | S355 |  | Stirnplatte |  | Wartung_FFB | Plate | 0121Kop0000020738 | Stirnplatte | false | T101.1 | HI_PRO_STA_0,300x0,480x0,025 | PlateCommon - Feuerwiderstandsklasse: <undefiniert>; Schallschutzklasse: <undefiniert>
Stirnplatte | Wartung_FFB | S355 |  | Stirnplatte |  | Wartung_FFB | Plate | 0121Kop0000020739 | Stirnplatte | false | T101.1 | HI_PRO_STA_0,300x0,480x0,025 | PlateCommon - Feuerwiderstandsklasse: <undefiniert>; Schallschutzklasse: <undefiniert>
Stirnplatte | Wartung_FFB | S355 |  | Stirnplatte |  | Wartung_FFB | Plate | 0121Kop0000020740 | Stirnplatte | false | T101.1 | HI_PRO_STA_0,300x0,480x0,025 | PlateCommon - Feuerwiderstandsklasse: <undefiniert>; Schallschutzklasse: <undefiniert>
Stirnplatte | Wartung_FFB | S355 |  | Stirnplatte |  | Wartung_FFB | Plate | 0121Kop0000020751 | Stirnplatte | false | T101.1 | HI_PRO_STA_0,300x0,480x0,025 | PlateCommon - Feuerwiderstandsklasse: <undefiniert>; Schallschutzklasse: <undefiniert>
Stirnplatte | Wartung_FFB | S355 |  | Stirnplatte |  | Wartung_FFB | Plate | 0121Kop0000020752 | Stirnplatte | false | T101.1 | HI_PRO_STA_0,300x0,480x0,025 | PlateCommon - Feuerwiderstandsklasse: <undefiniert>; Schallschutzklasse: <undefiniert>
Stirnplatte | Wartung_FFB | S355 |  | Stirnplatte |  | Wartung_FFB | Plate | 0121Kop0000020762 | Stirnplatte | false | T101.1 | HI_PRO_STA_0,280x0,480x0,025 | PlateCommon - Feuerwiderstandsklasse: <undefiniert>; Schallschutzklasse: <undefiniert>
Stirnplatte | Wartung_FFB | S355 |  | Stirnplatte |  | Wartung_FFB | Plate | 0121Kop0000020763 | Stirnplatte | false | T101.1 | HI_PRO_STA_0,280x0,480x0,025 | PlateCommon - Feuerwiderstandsklasse: <undefiniert>; Schallschutzklasse: <undefiniert>
Stirnplatte | Wartung_FFB | S355 |  | Stirnplatte |  | Wartung_FFB | Plate | 0121Kop0000020765 | Stirnplatte | false | T101.1 | HI_PRO_STA_0,280x0,480x0,025 | PlateCommon - Feuerwiderstandsklasse: <undefiniert>; Schallschutzklasse: <undefiniert>
Stirnplatte | Wartung_FFB | S355 |  | Stirnplatte |  | Wartung_FFB | Plate | 0121Kop0000020766 | Stirnplatte | false | T101.1 | HI_PRO_STA_0,280x0,480x0,025 | PlateCommon - Feuerwiderstandsklasse: <undefiniert>; Schallschutzklasse: <undefiniert>
Stirnplatte | Wartung_FFB | S355 |  | Stirnplatte |  | Wartung_FFB | Plate | 0121Kop0000020775 | Stirnplatte | false | T101.1 | HI_PRO_STA_0,280x0,480x0,025 | PlateCommon - Feuerwiderstandsklasse: <undefiniert>; Schallschutzklasse: <undefiniert>
Stirnplatte | Wartung_FFB | S355 |  | Stirnplatte |  | Wartung_FFB | Plate | 0121Kop0000020776 | Stirnplatte | false | T101.1 | HI_PRO_STA_0,280x0,480x0,025 | PlateCommon - Feuerwiderstandsklasse: <undefiniert>; Schallschutzklasse: <undefiniert>
Stirnplatte | Wartung_FFB | S355 |  | Stirnplatte |  | Wartung_FFB | Plate | 0121Kop0000020777 | Stirnplatte | false | T101.1 | HI_PRO_STA_0,280x0,480x0,025 | PlateCommon - Feuerwiderstandsklasse: <undefiniert>; Schallschutzklasse: <undefiniert>
Stirnplatte | Wartung_FFB | S355 |  | Stirnplatte |  | Wartung_FFB | Plate | 0121Kop0000020778 | Stirnplatte | false | T101.1 | HI_PRO_STA_0,280x0,480x0,025 | PlateCommon - Feuerwiderstandsklasse: <undefiniert>; Schallschutzklasse: <undefiniert>
Stirnplatte | Wartung_FFB | S355 |  | Stirnplatte |  | Wartung_FFB | Plate | 0121Kop0000020788 | Stirnplatte | false | T101.1 | HI_PRO_STA_0,280x0,480x0,025 | PlateCommon - Feuerwiderstandsklasse: <undefiniert>; Schallschutzklasse: <undefiniert>
Stirnplatte | Wartung_FFB | S355 |  | Stirnplatte |  | Wartung_FFB | Plate | 0121Kop0000020789 | Stirnplatte | false | T101.1 | HI_PRO_STA_0,280x0,480x0,025 | PlateCommon - Feuerwiderstandsklasse: <undefiniert>; Schallschutzklasse: <undefiniert>
Stirnplatte | Wartung_FFB | S355 |  | Stirnplatte |  | Wartung_FFB | Plate | 0121Kop0000020790 | Stirnplatte | false | T101.1 | HI_PRO_STA_0,280x0,480x0,025 | PlateCommon - Feuerwiderstandsklasse: <undefiniert>; Schallschutzklasse: <undefiniert>
Stirnplatte | Wartung_FFB | S355 |  | Stirnplatte |  | Wartung_FFB | Plate | 0121Kop0000020791 | Stirnplatte | false | T101.1 | HI_PRO_STA_0,280x0,480x0,025 | PlateCommon - Feuerwiderstandsklasse: <undefiniert>; Schallschutzklasse: <undefiniert>
Stirnplatte | Wartung_FFB | S355 |  | Stirnplatte |  | Wartung_FFB | Plate | 0121Kop0000020801 | Stirnplatte | false | T101.1 | HI_PRO_STA_0,300x0,680x0,025 | PlateCommon - Feuerwiderstandsklasse: <undefiniert>; Schallschutzklasse: <undefiniert>
Stirnplatte | Wartung_FFB | S355 |  | Stirnplatte |  | Wartung_FFB | Plate | 0121Kop0000020802 | Stirnplatte | false | T101.1 | HI_PRO_STA_0,300x0,680x0,025 | PlateCommon - Feuerwiderstandsklasse: <undefiniert>; Schallschutzklasse: <undefiniert>
Stirnplatte | Wartung_FFB | S355 |  | Stirnplatte |  | Wartung_FFB | Plate | 0121Kop0000020863 | Stirnplatte | false | T101.1 | HI_PRO_STA_0,300x0,680x0,025 | PlateCommon - Feuerwiderstandsklasse: <undefiniert>; Schallschutzklasse: <undefiniert>
Stirnplatte | Wartung_FFB | S355 |  | Stirnplatte |  | Wartung_FFB | Plate | 0121Kop0000020864 | Stirnplatte | false | T101.1 | HI_PRO_STA_0,300x0,680x0,025 | PlateCommon - Feuerwiderstandsklasse: <undefiniert>; Schallschutzklasse: <undefiniert>
Stirnplatte | Wartung_FFB | S355 |  | Stirnplatte |  | Wartung_FFB | Plate | 0121Kop0000020865 | Stirnplatte | false | T101.1 | HI_PRO_STA_0,300x0,680x0,025 | PlateCommon - Feuerwiderstandsklasse: <undefiniert>; Schallschutzklasse: <undefiniert>
Stirnplatte | Wartung_FFB | S355 |  | Stirnplatte |  | Wartung_FFB | Plate | 0121Kop0000020866 | Stirnplatte | false | T101.1 | HI_PRO_STA_0,300x0,680x0,025 | PlateCommon - Feuerwiderstandsklasse: <undefiniert>; Schallschutzklasse: <undefiniert>
Stirnplatte | Wartung_FFB | S355 |  | Stirnplatte |  | Wartung_FFB | Plate | 0121Kop0000020867 | Stirnplatte | false | T101.1 | HI_PRO_STA_0,300x0,680x0,025 | PlateCommon - Feuerwiderstandsklasse: <undefiniert>; Schallschutzklasse: <undefiniert>
Stirnplatte | Wartung_FFB | S355 |  | Stirnplatte |  | Wartung_FFB | Plate | 0121Kop0000020868 | Stirnplatte | false | T101.1 | HI_PRO_STA_0,300x0,680x0,025 | PlateCommon - Feuerwiderstandsklasse: <undefiniert>; Schallschutzklasse: <undefiniert>
Stirnplatte | Wartung_FFB | S355 |  | Stirnplatte |  | Wartung_FFB | Plate | 0121Kop0000020869 | Stirnplatte | false | T101.1 | HI_PRO_STA_0,300x0,680x0,025 | PlateCommon - Feuerwiderstandsklasse: <undefiniert>; Schallschutzklasse: <undefiniert>
Stirnplatte | Wartung_FFB | S355 |  | Stirnplatte |  | Wartung_FFB | Plate | 0121Kop0000020870 | Stirnplatte | false | T101.1 | HI_PRO_STA_0,300x0,680x0,025 | PlateCommon - Feuerwiderstandsklasse: <undefiniert>; Schallschutzklasse: <undefiniert>
Stirnplatte | Wartung_FFB | S355 |  | Stirnplatte |  | Wartung_FFB | Plate | 0121Kop0000020871 | Stirnplatte | false | T101.1 | HI_PRO_STA_0,300x0,580x0,025 | PlateCommon - Feuerwiderstandsklasse: <undefiniert>; Schallschutzklasse: <undefiniert>
Stirnplatte | Wartung_FFB | S355 |  | Stirnplatte |  | Wartung_FFB | Plate | 0121Kop0000020872 | Stirnplatte | false | T101.1 | HI_PRO_STA_0,300x0,580x0,025 | PlateCommon - Feuerwiderstandsklasse: <undefiniert>; Schallschutzklasse: <undefiniert>
Stirnplatte | Wartung_FFB | S355 |  | Stirnplatte |  | Wartung_FFB | Plate | 0121Kop0000020873 | Stirnplatte | false | T101.1 | HI_PRO_STA_0,300x0,580x0,025 | PlateCommon - Feuerwiderstandsklasse: <undefiniert>; Schallschutzklasse: <undefiniert>
Stirnplatte | Wartung_FFB | S355 |  | Stirnplatte |  | Wartung_FFB | Plate | 0121Kop0000020874 | Stirnplatte | false | T101.1 | HI_PRO_STA_0,300x0,580x0,025 | PlateCommon - Feuerwiderstandsklasse: <undefiniert>; Schallschutzklasse: <undefiniert>
Stirnplatte | Wartung_FFB | S355 |  | Stirnplatte |  | Wartung_FFB | Plate | 0121Kop0000020875 | Stirnplatte | false | T101.1 | HI_PRO_STA_0,300x0,580x0,025 | PlateCommon - Feuerwiderstandsklasse: <undefiniert>; Schallschutzklasse: <undefiniert>
Stirnplatte | Wartung_FFB | S355 |  | Stirnplatte |  | Wartung_FFB | Plate | 0121Kop0000020876 | Stirnplatte | false | T101.1 | HI_PRO_STA_0,300x0,580x0,025 | PlateCommon - Feuerwiderstandsklasse: <undefiniert>; Schallschutzklasse: <undefiniert>
Stirnplatte | Wartung_FFB | S355 |  | Stirnplatte |  | Wartung_FFB | Plate | 0121Kop0000020877 | Stirnplatte | false | T101.1 | HI_PRO_STA_0,300x0,580x0,025 | PlateCommon - Feuerwiderstandsklasse: <undefiniert>; Schallschutzklasse: <undefiniert>
Stirnplatte | Wartung_FFB | S355 |  | Stirnplatte |  | Wartung_FFB | Plate | 0121Kop0000020878 | Stirnplatte | false | T101.1 | HI_PRO_STA_0,300x0,580x0,025 | PlateCommon - Feuerwiderstandsklasse: <undefiniert>; Schallschutzklasse: <undefiniert>
Stirnplatte | Wartung_FFB | S355 |  | Stirnplatte |  | Wartung_FFB | Plate | 0121Kop0000020879 | Stirnplatte | false | T101.1 | HI_PRO_STA_0,300x0,580x0,025 | PlateCommon - Feuerwiderstandsklasse: <undefiniert>; Schallschutzklasse: <undefiniert>
Stirnplatte | Wartung_FFB | S355 |  | Stirnplatte |  | Wartung_FFB | Plate | 0121Kop0000020880 | Stirnplatte | false | T101.1 | HI_PRO_STA_0,300x0,580x0,025 | PlateCommon - Feuerwiderstandsklasse: <undefiniert>; Schallschutzklasse: <undefiniert>
Stirnplatte | Wartung_FFB | S355 |  | Stirnplatte |  | Wartung_FFB | Plate | 0121Kop0000020881 | Stirnplatte | false | T101.1 | HI_PRO_STA_0,300x0,580x0,025 | PlateCommon - Feuerwiderstandsklasse: <undefiniert>; Schallschutzklasse: <undefiniert>
Stirnplatte | Wartung_FFB | S355 |  | Stirnplatte |  | Wartung_FFB | Plate | 0121Kop0000020882 | Stirnplatte | false | T101.1 | HI_PRO_STA_0,300x0,580x0,025 | PlateCommon - Feuerwiderstandsklasse: <undefiniert>; Schallschutzklasse: <undefiniert>
Stirnplatte | Wartung_FFB | S355 |  | Stirnplatte |  | Wartung_FFB | Plate | 0121Kop0000020883 | Stirnplatte | false | T101.1 | HI_PRO_STA_0,300x0,580x0,025 | PlateCommon - Feuerwiderstandsklasse: <undefiniert>; Schallschutzklasse: <undefiniert>
Stirnplatte | Wartung_FFB | S355 |  | Stirnplatte |  | Wartung_FFB | Plate | 0121Kop0000020884 | Stirnplatte | false | T101.1 | HI_PRO_STA_0,300x0,580x0,025 | PlateCommon - Feuerwiderstandsklasse: <undefiniert>; Schallschutzklasse: <undefiniert>
Stirnplatte | Wartung_FFB | S355 |  | Stirnplatte |  | Wartung_FFB | Plate | 0121Kop0000020887 | Stirnplatte | false | T101.1 | HI_PRO_STA_0,300x0,630x0,025 | PlateCommon - Feuerwiderstandsklasse: <undefiniert>; Schallschutzklasse: <undefiniert>
Stirnplatte | Wartung_FFB | S355 |  | Stirnplatte |  | Wartung_FFB | Plate | 0121Kop0000020888 | Stirnplatte | false | T101.1 | HI_PRO_STA_0,300x0,630x0,025 | PlateCommon - Feuerwiderstandsklasse: <undefiniert>; Schallschutzklasse: <undefiniert>
Stirnplatte | Wartung_FFB | S355 |  | Stirnplatte |  | Wartung_FFB | Plate | 0121Kop0000020889 | Stirnplatte | false | T101.1 | HI_PRO_STA_0,300x0,580x0,025 | PlateCommon - Feuerwiderstandsklasse: <undefiniert>; Schallschutzklasse: <undefiniert>
Stirnplatte | Wartung_FFB | S355 |  | Stirnplatte |  | Wartung_FFB | Plate | 0121Kop0000020890 | Stirnplatte | false | T101.1 | HI_PRO_STA_0,300x0,580x0,025 | PlateCommon - Feuerwiderstandsklasse: <undefiniert>; Schallschutzklasse: <undefiniert>
Stirnplatte | Wartung_FFB | S355 |  | Stirnplatte |  | Wartung_FFB | Plate | 0121Kop0000020895 | Stirnplatte | false | T101.1 | HI_PRO_STA_0,300x0,580x0,025 | PlateCommon - Feuerwiderstandsklasse: <undefiniert>; Schallschutzklasse: <undefiniert>
Stirnplatte | Wartung_FFB | S355 |  | Stirnplatte |  | Wartung_FFB | Plate | 0121Kop0000020896 | Stirnplatte | false | T101.1 | HI_PRO_STA_0,300x0,580x0,025 | PlateCommon - Feuerwiderstandsklasse: <undefiniert>; Schallschutzklasse: <undefiniert>
Stirnplatte | Wartung_FFB | S355 |  | Stirnplatte |  | Wartung_FFB | Plate | 0121Kop0000020897 | Stirnplatte | false | T101.1 | HI_PRO_STA_0,300x0,580x0,025 | PlateCommon - Feuerwiderstandsklasse: <undefiniert>; Schallschutzklasse: <undefiniert>
Stirnplatte | Wartung_FFB | S355 |  | Stirnplatte |  | Wartung_FFB | Plate | 0121Kop0000020898 | Stirnplatte | false | T101.1 | HI_PRO_STA_0,300x0,580x0,025 | PlateCommon - Feuerwiderstandsklasse: <undefiniert>; Schallschutzklasse: <undefiniert>
Stirnplatte | Wartung_FFB | S355 |  | Stirnplatte |  | Wartung_FFB | Plate | 0121Kop0000020907 | Stirnplatte | false | T101.1 | HI_PRO_STA_0,300x0,440x0,025 | PlateCommon - Feuerwiderstandsklasse: <undefiniert>; Schallschutzklasse: <undefiniert>
Stirnplatte | Wartung_FFB | S355 |  | Stirnplatte |  | Wartung_FFB | Plate | 0121Kop0000020908 | Stirnplatte | false | T101.1 | HI_PRO_STA_0,300x0,440x0,025 | PlateCommon - Feuerwiderstandsklasse: <undefiniert>; Schallschutzklasse: <undefiniert>
Stirnplatte | Wartung_FFB | S355 |  | Stirnplatte |  | Wartung_FFB | Plate | 0121Kop0000020921 | Stirnplatte | false | T101.1 | HI_PRO_STA_0,300x0,440x0,025 | PlateCommon - Feuerwiderstandsklasse: <undefiniert>; Schallschutzklasse: <undefiniert>
Stirnplatte | Wartung_FFB | S355 |  | Stirnplatte |  | Wartung_FFB | Plate | 0121Kop0000020922 | Stirnplatte | false | T101.1 | HI_PRO_STA_0,300x0,440x0,025 | PlateCommon - Feuerwiderstandsklasse: <undefiniert>; Schallschutzklasse: <undefiniert>
Stirnplatte | Wartung_FFB | S355 |  | Stirnplatte |  | Wartung_FFB | Plate | 0121Kop0000020923 | Stirnplatte | false | T101.1 | HI_PRO_STA_0,300x0,440x0,025 | PlateCommon - Feuerwiderstandsklasse: <undefiniert>; Schallschutzklasse: <undefiniert>
Stirnplatte | Wartung_FFB | S355 |  | Stirnplatte |  | Wartung_FFB | Plate | 0121Kop0000020924 | Stirnplatte | false | T101.1 | HI_PRO_STA_0,300x0,440x0,025 | PlateCommon - Feuerwiderstandsklasse: <undefiniert>; Schallschutzklasse: <undefiniert>
Stirnplatte | Wartung_FFB | S355 |  | Stirnplatte |  | Wartung_FFB | Plate | 0121Kop0000020935 | Stirnplatte | false | T101.1 | HI_PRO_STA_0,300x0,440x0,025 | PlateCommon - Feuerwiderstandsklasse: <undefiniert>; Schallschutzklasse: <undefiniert>
Stirnplatte | Wartung_FFB | S355 |  | Stirnplatte |  | Wartung_FFB | Plate | 0121Kop0000020936 | Stirnplatte | false | T101.1 | HI_PRO_STA_0,300x0,440x0,025 | PlateCommon - Feuerwiderstandsklasse: <undefiniert>; Schallschutzklasse: <undefiniert>
Stirnplatte | Wartung_FFB | S355 |  | Stirnplatte |  | Wartung_FFB | Plate | 0121Kop0000020977 | Stirnplatte | false | T101.1 | HI_PRO_STA_0,300x0,480x0,025 | PlateCommon - Feuerwiderstandsklasse: <undefiniert>; Schallschutzklasse: <undefiniert>
Stirnplatte | Wartung_FFB | S355 |  | Stirnplatte |  | Wartung_FFB | Plate | 0121Kop0000020978 | Stirnplatte | false | T101.1 | HI_PRO_STA_0,300x0,480x0,025 | PlateCommon - Feuerwiderstandsklasse: <undefiniert>; Schallschutzklasse: <undefiniert>
Stirnplatte | Wartung_FFB | S355 |  | Stirnplatte |  | Wartung_FFB | Plate | 0121Kop0000020979 | Stirnplatte | false | T101.1 | HI_PRO_STA_0,300x0,480x0,025 | PlateCommon - Feuerwiderstandsklasse: <undefiniert>; Schallschutzklasse: <undefiniert>
Stirnplatte | Wartung_FFB | S355 |  | Stirnplatte |  | Wartung_FFB | Plate | 0121Kop0000020980 | Stirnplatte | false | T101.1 | HI_PRO_STA_0,300x0,480x0,025 | PlateCommon - Feuerwiderstandsklasse: <undefiniert>; Schallschutzklasse: <undefiniert>
Stirnplatte | Wartung_FFB | S355 |  | Stirnplatte |  | Wartung_FFB | Plate | 0121Kop0000020981 | Stirnplatte | false | T101.1 | HI_PRO_STA_0,300x0,480x0,025 | PlateCommon - Feuerwiderstandsklasse: <undefiniert>; Schallschutzklasse: <undefiniert>
Stirnplatte | Wartung_FFB | S355 |  | Stirnplatte |  | Wartung_FFB | Plate | 0121Kop0000020982 | Stirnplatte | false | T101.1 | HI_PRO_STA_0,300x0,480x0,025 | PlateCommon - Feuerwiderstandsklasse: <undefiniert>; Schallschutzklasse: <undefiniert>
Stirnplatte | Wartung_FFB | S355 |  | Stirnplatte |  | Wartung_FFB | Plate | 0121Kop0000020983 | Stirnplatte | false | T101.1 | HI_PRO_STA_0,300x0,480x0,025 | PlateCommon - Feuerwiderstandsklasse: <undefiniert>; Schallschutzklasse: <undefiniert>
Stirnplatte | Wartung_FFB | S355 |  | Stirnplatte |  | Wartung_FFB | Plate | 0121Kop0000020984 | Stirnplatte | false | T101.1 | HI_PRO_STA_0,300x0,480x0,025 | PlateCommon - Feuerwiderstandsklasse: <undefiniert>; Schallschutzklasse: <undefiniert>
Stirnplatte | Wartung_FFB | S355 |  | Stirnplatte |  | Wartung_FFB | Plate | 0121Kop0000020985 | Stirnplatte | false | T101.1 | HI_PRO_STA_0,300x0,480x0,025 | PlateCommon - Feuerwiderstandsklasse: <undefiniert>; Schallschutzklasse: <undefiniert>
Stirnplatte | Wartung_FFB | S355 |  | Stirnplatte |  | Wartung_FFB | Plate | 0121Kop0000020986 | Stirnplatte | false | T101.1 | HI_PRO_STA_0,300x0,480x0,025 | PlateCommon - Feuerwiderstandsklasse: <undefiniert>; Schallschutzklasse: <undefiniert>
Stirnplatte | Wartung_FFB | S355 |  | Stirnplatte |  | Wartung_FFB | Plate | 0121Kop0000020987 | Stirnplatte | false | T101.1 | HI_PRO_STA_0,300x0,480x0,025 | PlateCommon - Feuerwiderstandsklasse: <undefiniert>; Schallschutzklasse: <undefiniert>
Stirnplatte | Wartung_FFB | S355 |  | Stirnplatte |  | Wartung_FFB | Plate | 0121Kop0000020988 | Stirnplatte | false | T101.1 | HI_PRO_STA_0,300x0,480x0,025 | PlateCommon - Feuerwiderstandsklasse: <undefiniert>; Schallschutzklasse: <undefiniert>
Stirnplatte | Wartung_FFB | S355 |  | Stirnplatte |  | Wartung_FFB | Plate | 0121Kop0000020989 | Stirnplatte | false | T101.1 | HI_PRO_STA_0,300x0,480x0,025 | PlateCommon - Feuerwiderstandsklasse: <undefiniert>; Schallschutzklasse: <undefiniert>
Stirnplatte | Wartung_FFB | S355 |  | Stirnplatte |  | Wartung_FFB | Plate | 0121Kop0000020990 | Stirnplatte | false | T101.1 | HI_PRO_STA_0,300x0,480x0,025 | PlateCommon - Feuerwiderstandsklasse: <undefiniert>; Schallschutzklasse: <undefiniert>
Stirnplatte | Wartung_FFB | S355 |  | Stirnplatte |  | Wartung_FFB | Plate | 0121Kop0000020991 | Stirnplatte | false | T101.1 | HI_PRO_STA_0,300x0,480x0,025 | PlateCommon - Feuerwiderstandsklasse: <undefiniert>; Schallschutzklasse: <undefiniert>
Stirnplatte | Wartung_FFB | S355 |  | Stirnplatte |  | Wartung_FFB | Plate | 0121Kop0000020992 | Stirnplatte | false | T101.1 | HI_PRO_STA_0,300x0,480x0,025 | PlateCommon - Feuerwiderstandsklasse: <undefiniert>; Schallschutzklasse: <undefiniert>
Stirnplatte | Wartung_FFB | S355 |  | Stirnplatte |  | Wartung_FFB | Plate | 0121Kop0000020993 | Stirnplatte | false | T101.1 | HI_PRO_STA_0,300x0,480x0,025 | PlateCommon - Feuerwiderstandsklasse: <undefiniert>; Schallschutzklasse: <undefiniert>
Stirnplatte | Wartung_FFB | S355 |  | Stirnplatte |  | Wartung_FFB | Plate | 0121Kop0000020994 | Stirnplatte | false | T101.1 | HI_PRO_STA_0,300x0,480x0,025 | PlateCommon - Feuerwiderstandsklasse: <undefiniert>; Schallschutzklasse: <undefiniert>
Stirnplatte | Wartung_FFB | S355 |  | Stirnplatte |  | Wartung_FFB | Plate | 0121Kop0000021004 | Stirnplatte | false | T101.1 | HI_PRO_STA_0,280x0,340x0,025 | PlateCommon - Feuerwiderstandsklasse: <undefiniert>; Schallschutzklasse: <undefiniert>
Stirnplatte | Wartung_FFB | S355 |  | Stirnplatte |  | Wartung_FFB | Plate | 0121Kop0000021005 | Stirnplatte | false | T101.1 | HI_PRO_STA_0,280x0,340x0,025 | PlateCommon - Feuerwiderstandsklasse: <undefiniert>; Schallschutzklasse: <undefiniert>
Stirnplatte | Wartung_FFB | S355 |  | Stirnplatte |  | Wartung_FFB | Plate | 0121Kop0000021008 | Stirnplatte | false | T101.1 | HI_PRO_STA_0,280x0,340x0,025 | PlateCommon - Feuerwiderstandsklasse: <undefiniert>; Schallschutzklasse: <undefiniert>
Stirnplatte | Wartung_FFB | S355 |  | Stirnplatte |  | Wartung_FFB | Plate | 0121Kop0000021009 | Stirnplatte | false | T101.1 | HI_PRO_STA_0,280x0,340x0,025 | PlateCommon - Feuerwiderstandsklasse: <undefiniert>; Schallschutzklasse: <undefiniert>
Stirnplatte | Wartung_FFB | S355 |  | Stirnplatte |  | Wartung_FFB | Plate | 0121Kop0000021016 | Stirnplatte | false | T101.1 | HI_PRO_STA_0,280x0,340x0,025 | PlateCommon - Feuerwiderstandsklasse: <undefiniert>; Schallschutzklasse: <undefiniert>
Stirnplatte | Wartung_FFB | S355 |  | Stirnplatte |  | Wartung_FFB | Plate | 0121Kop0000021017 | Stirnplatte | false | T101.1 | HI_PRO_STA_0,280x0,340x0,025 | PlateCommon - Feuerwiderstandsklasse: <undefiniert>; Schallschutzklasse: <undefiniert>
Stirnplatte | Wartung_FFB | S355 |  | Stirnplatte |  | Wartung_FFB | Plate | 0121Kop0000021024 | Stirnplatte | false | T101.1 | HI_PRO_STA_0,280x0,340x0,025 | PlateCommon - Feuerwiderstandsklasse: <undefiniert>; Schallschutzklasse: <undefiniert>
Stirnplatte | Wartung_FFB | S355 |  | Stirnplatte |  | Wartung_FFB | Plate | 0121Kop0000021025 | Stirnplatte | false | T101.1 | HI_PRO_STA_0,280x0,340x0,025 | PlateCommon - Feuerwiderstandsklasse: <undefiniert>; Schallschutzklasse: <undefiniert>
Stirnplatte | Wartung_FFB | S355 |  | Stirnplatte |  | Wartung_FFB | Plate | 0121Kop0000021032 | Stirnplatte | false | T101.1 | HI_PRO_STA_0,280x0,340x0,025 | PlateCommon - Feuerwiderstandsklasse: <undefiniert>; Schallschutzklasse: <undefiniert>
Stirnplatte | Wartung_FFB | S355 |  | Stirnplatte |  | Wartung_FFB | Plate | 0121Kop0000021033 | Stirnplatte | false | T101.1 | HI_PRO_STA_0,280x0,340x0,025 | PlateCommon - Feuerwiderstandsklasse: <undefiniert>; Schallschutzklasse: <undefiniert>
Stirnplatte | Wartung_FFB | S355 |  | Stirnplatte |  | Wartung_FFB | Plate | 0121Kop0000021048 | Stirnplatte | false | T101.1 | HI_PRO_STA_0,280x0,340x0,025 | PlateCommon - Feuerwiderstandsklasse: <undefiniert>; Schallschutzklasse: <undefiniert>
Stirnplatte | Wartung_FFB | S355 |  | Stirnplatte |  | Wartung_FFB | Plate | 0121Kop0000021049 | Stirnplatte | false | T101.1 | HI_PRO_STA_0,280x0,340x0,025 | PlateCommon - Feuerwiderstandsklasse: <undefiniert>; Schallschutzklasse: <undefiniert>
Stirnplatte | Wartung_FFB | S355 |  | Stirnplatte |  | Wartung_FFB | Plate | 0121Kop0000021052 | Stirnplatte | false | T101.1 | HI_PRO_STA_0,280x0,340x0,025 | PlateCommon - Feuerwiderstandsklasse: <undefiniert>; Schallschutzklasse: <undefiniert>
Stirnplatte | Wartung_FFB | S355 |  | Stirnplatte |  | Wartung_FFB | Plate | 0121Kop0000021053 | Stirnplatte | false | T101.1 | HI_PRO_STA_0,280x0,340x0,025 | PlateCommon - Feuerwiderstandsklasse: <undefiniert>; Schallschutzklasse: <undefiniert>
Stirnplatte | Wartung_FFB | S355 |  | Stirnplatte |  | Wartung_FFB | Plate | 0121Kop0000021056 | Stirnplatte | false | T101.1 | HI_PRO_STA_0,280x0,340x0,025 | PlateCommon - Feuerwiderstandsklasse: <undefiniert>; Schallschutzklasse: <undefiniert>
Stirnplatte | Wartung_FFB | S355 |  | Stirnplatte |  | Wartung_FFB | Plate | 0121Kop0000021057 | Stirnplatte | false | T101.1 | HI_PRO_STA_0,280x0,340x0,025 | PlateCommon - Feuerwiderstandsklasse: <undefiniert>; Schallschutzklasse: <undefiniert>
Stirnplatte | Wartung_FFB | S355 |  | Stirnplatte |  | Wartung_FFB | Plate | 0121Kop0000021070 | Stirnplatte | false | T101.1 | HI_PRO_STA_0,300x0,530x0,025 | PlateCommon - Feuerwiderstandsklasse: <undefiniert>; Schallschutzklasse: <undefiniert>
Stirnplatte | Wartung_FFB | S355 |  | Stirnplatte |  | Wartung_FFB | Plate | 0121Kop0000021071 | Stirnplatte | false | T101.1 | HI_PRO_STA_0,300x0,530x0,025 | PlateCommon - Feuerwiderstandsklasse: <undefiniert>; Schallschutzklasse: <undefiniert>
Stirnplatte | Wartung_FFB | S355 |  | Stirnplatte |  | Wartung_FFB | Plate | 0121Kop0000021072 | Stirnplatte | false | T101.1 | HI_PRO_STA_0,300x0,530x0,025 | PlateCommon - Feuerwiderstandsklasse: <undefiniert>; Schallschutzklasse: <undefiniert>
Stirnplatte | Wartung_FFB | S355 |  | Stirnplatte |  | Wartung_FFB | Plate | 0121Kop0000021073 | Stirnplatte | false | T101.1 | HI_PRO_STA_0,300x0,530x0,025 | PlateCommon - Feuerwiderstandsklasse: <undefiniert>; Schallschutzklasse: <undefiniert>
Stirnplatte | Wartung_FFB | S355 |  | Stirnplatte |  | Wartung_FFB | Plate | 0121Kop0000021079 | Stirnplatte | false | T101.1 | HI_PRO_STA_0,300x0,390x0,025 | PlateCommon - Feuerwiderstandsklasse: <undefiniert>; Schallschutzklasse: <undefiniert>
Stirnplatte | Wartung_FFB | S355 |  | Stirnplatte |  | Wartung_FFB | Plate | 0121Kop0000021080 | Stirnplatte | false | T101.1 | HI_PRO_STA_0,300x0,390x0,025 | PlateCommon - Feuerwiderstandsklasse: <undefiniert>; Schallschutzklasse: <undefiniert>
Stirnplatte | Wartung_FFB | S355 |  | Stirnplatte |  | Wartung_FFB | Plate | 0121Kop0000021096 | Stirnplatte | false | T101.1 | HI_PRO_STA_0,300x0,390x0,025 | PlateCommon - Feuerwiderstandsklasse: <undefiniert>; Schallschutzklasse: <undefiniert>
Stirnplatte | Wartung_FFB | S355 |  | Stirnplatte |  | Wartung_FFB | Plate | 0121Kop0000021097 | Stirnplatte | false | T101.1 | HI_PRO_STA_0,300x0,390x0,025 | PlateCommon - Feuerwiderstandsklasse: <undefiniert>; Schallschutzklasse: <undefiniert>
Stirnplatte | Wartung_FFB | S355 |  | Stirnplatte |  | Wartung_FFB | Plate | 0121Kop0000021104 | Stirnplatte | false | T101.1 | HI_PRO_STA_0,300x0,390x0,025 | PlateCommon - Feuerwiderstandsklasse: <undefiniert>; Schallschutzklasse: <undefiniert>
Stirnplatte | Wartung_FFB | S355 |  | Stirnplatte |  | Wartung_FFB | Plate | 0121Kop0000021105 | Stirnplatte | false | T101.1 | HI_PRO_STA_0,300x0,390x0,025 | PlateCommon - Feuerwiderstandsklasse: <undefiniert>; Schallschutzklasse: <undefiniert>
Stirnplatte | Wartung_FFB | S355 |  | Stirnplatte |  | Wartung_FFB | Plate | 0121Kop0000021112 | Stirnplatte | false | T101.1 | HI_PRO_STA_0,300x0,390x0,025 | PlateCommon - Feuerwiderstandsklasse: <undefiniert>; Schallschutzklasse: <undefiniert>
Stirnplatte | Wartung_FFB | S355 |  | Stirnplatte |  | Wartung_FFB | Plate | 0121Kop0000021113 | Stirnplatte | false | T101.1 | HI_PRO_STA_0,300x0,390x0,025 | PlateCommon - Feuerwiderstandsklasse: <undefiniert>; Schallschutzklasse: <undefiniert>
Stirnplatte | Wartung_FFB | S355 |  | Stirnplatte |  | Wartung_FFB | Plate | 0121Kop0000021136 | Stirnplatte | false | T101.1 | HI_PRO_STA_0,300x0,350x0,025 | PlateCommon - Feuerwiderstandsklasse: <undefiniert>; Schallschutzklasse: <undefiniert>
Stirnplatte | Wartung_FFB | S355 |  | Stirnplatte |  | Wartung_FFB | Plate | 0121Kop0000021137 | Stirnplatte | false | T101.1 | HI_PRO_STA_0,300x0,350x0,025 | PlateCommon - Feuerwiderstandsklasse: <undefiniert>; Schallschutzklasse: <undefiniert>
Stirnplatte | Wartung_FFB | S355 |  | Stirnplatte |  | Wartung_FFB | Plate | 0121Kop0000021138 | Stirnplatte | false | T101.1 | HI_PRO_STA_0,300x0,350x0,025 | PlateCommon - Feuerwiderstandsklasse: <undefiniert>; Schallschutzklasse: <undefiniert>
Stirnplatte | Wartung_FFB | S355 |  | Stirnplatte |  | Wartung_FFB | Plate | 0121Kop0000021139 | Stirnplatte | false | T101.1 | HI_PRO_STA_0,300x0,350x0,025 | PlateCommon - Feuerwiderstandsklasse: <undefiniert>; Schallschutzklasse: <undefiniert>
Stirnplatte | Wartung_FFB | S355 |  | Stirnplatte |  | Wartung_FFB | Plate | 0121Kop0000021149 | Stirnplatte | false | T101.1 | HI_PRO_STA_0,300x0,480x0,025 | PlateCommon - Feuerwiderstandsklasse: <undefiniert>; Schallschutzklasse: <undefiniert>
Stirnplatte | Wartung_FFB | S355 |  | Stirnplatte |  | Wartung_FFB | Plate | 0121Kop0000021154 | Stirnplatte | false | T101.1 | HI_PRO_STA_0,300x0,480x0,025 | PlateCommon - Feuerwiderstandsklasse: <undefiniert>; Schallschutzklasse: <undefiniert>
Stirnplatte | Wartung_FFB | S355 |  | Stirnplatte |  | Wartung_FFB | Plate | 0121Kop0000021159 | Stirnplatte | false | T101.1 | HI_PRO_STA_0,300x0,480x0,025 | PlateCommon - Feuerwiderstandsklasse: <undefiniert>; Schallschutzklasse: <undefiniert>
Stirnplatte | Wartung_FFB | S355 |  | Stirnplatte |  | Wartung_FFB | Plate | 0121Kop0000021161 | Stirnplatte | false | T101.1 | HI_PRO_STA_0,300x0,480x0,025 | PlateCommon - Feuerwiderstandsklasse: <undefiniert>; Schallschutzklasse: <undefiniert>
Stirnplatte | Wartung_FFB | S355 |  | Stirnplatte |  | Wartung_FFB | Plate | 0121Kop0000021167 | Stirnplatte | false | T101.1 | HI_PRO_STA_0,300x0,480x0,025 | PlateCommon - Feuerwiderstandsklasse: <undefiniert>; Schallschutzklasse: <undefiniert>
Stirnplatte | Wartung_FFB | S355 |  | Stirnplatte |  | Wartung_FFB | Plate | 0121Kop0000021169 | Stirnplatte | false | T101.1 | HI_PRO_STA_0,300x0,480x0,025 | PlateCommon - Feuerwiderstandsklasse: <undefiniert>; Schallschutzklasse: <undefiniert>
Stirnplatte | Wartung_FFB | S355 |  | Stirnplatte |  | Wartung_FFB | Plate | 0121Kop0000021175 | Stirnplatte | false | T101.1 | HI_PRO_STA_0,300x0,480x0,025 | PlateCommon - Feuerwiderstandsklasse: <undefiniert>; Schallschutzklasse: <undefiniert>
Stirnplatte | Wartung_FFB | S355 |  | Stirnplatte |  | Wartung_FFB | Plate | 0121Kop0000021177 | Stirnplatte | false | T101.1 | HI_PRO_STA_0,300x0,480x0,025 | PlateCommon - Feuerwiderstandsklasse: <undefiniert>; Schallschutzklasse: <undefiniert>
Stirnplatte | Wartung_FFB | S355 |  | Stirnplatte |  | Wartung_FFB | Plate | 0121Kop0000021183 | Stirnplatte | false | T101.1 | HI_PRO_STA_0,300x0,480x0,025 | PlateCommon - Feuerwiderstandsklasse: <undefiniert>; Schallschutzklasse: <undefiniert>
Stirnplatte | Wartung_FFB | S355 |  | Stirnplatte |  | Wartung_FFB | Plate | 0121Kop0000021185 | Stirnplatte | false | T101.1 | HI_PRO_STA_0,300x0,480x0,025 | PlateCommon - Feuerwiderstandsklasse: <undefiniert>; Schallschutzklasse: <undefiniert>
Stirnplatte | Wartung_FFB | S355 |  | Stirnplatte |  | Wartung_FFB | Plate | 0121Kop0000021191 | Stirnplatte | false | T101.1 | HI_PRO_STA_0,300x0,480x0,025 | PlateCommon - Feuerwiderstandsklasse: <undefiniert>; Schallschutzklasse: <undefiniert>
Stirnplatte | Wartung_FFB | S355 |  | Stirnplatte |  | Wartung_FFB | Plate | 0121Kop0000021193 | Stirnplatte | false | T101.1 | HI_PRO_STA_0,300x0,480x0,025 | PlateCommon - Feuerwiderstandsklasse: <undefiniert>; Schallschutzklasse: <undefiniert>
Stirnplatte | Wartung_FFB | S355 |  | Stirnplatte |  | Wartung_FFB | Plate | 0121Kop0000021199 | Stirnplatte | false | T101.1 | HI_PRO_STA_0,300x0,480x0,025 | PlateCommon - Feuerwiderstandsklasse: <undefiniert>; Schallschutzklasse: <undefiniert>
Stirnplatte | Wartung_FFB | S355 |  | Stirnplatte |  | Wartung_FFB | Plate | 0121Kop0000021201 | Stirnplatte | false | T101.1 | HI_PRO_STA_0,300x0,480x0,025 | PlateCommon - Feuerwiderstandsklasse: <undefiniert>; Schallschutzklasse: <undefiniert>
Verbindungsstück | Wartung_FFB | S235 | 0 | Verbindungsstück | PythonPart | Wartung_FFB | Plate | 0121Pyt0000006187 | Verbindungsstück | false | S101 | HI_PRO_STA_0,300x0,300 | 10.7 | 10.54 | 10.84 | 6.941 | 10.4 | 0.015 | 10.55 | 10.69 | 6.926 | 0
Verbindungsstück | Wartung_FFB | S235 | 0 | Verbindungsstück | PythonPart | Wartung_FFB | Plate | 0121Pyt0000006186 | Verbindungsstück | false | S101 | HI_PRO_STA_0,300x0,300 | 10.7 | 10.54 | 10.84 | 6.941 | 10.4 | 0.015 | 10.55 | 10.69 | 6.926 | 0
Verbindungsstück | Wartung_FFB | S235 | 0 | Verbindungsstück | PythonPart | Wartung_FFB | Plate | 0121Pyt0000006185 | Verbindungsstück | false | S101 | HI_PRO_STA_0,250x0,500 | 10.675 | 10.44 | 10.94 | 6.926 | 10.425 | 0.025 | 10.55 | 10.69 | 6.901 | 0
Verbindungsstück | Wartung_FFB | S235 | 0 | Verbindungsstück | PythonPart | Wartung_FFB | Plate | 0121Pyt0000006188 | Verbindungsstück | false | S101 | HI_PRO_STA_0,250x0,500 | 10.675 | 29.85 | 30.35 | 6.926 | 10.425 | 0.025 | 10.55 | 30.1 | 6.901 | 0
Verbindungsstück | Wartung_FFB | S235 | 0 | Verbindungsstück | PythonPart | Wartung_FFB | Plate | 0121Pyt0000006210 | Verbindungsstück | false | S101 | HI_PRO_STA_0,300x0,300 | 10.7 | 10.54 | 10.84 | 6.941 | 10.4 | 0.015 | 10.55 | 10.69 | 6.926 | 0
Verbindungsstück | Wartung_FFB | S235 | 0 | Verbindungsstück | PythonPart | Wartung_FFB | Plate | 0121Pyt0000006233 | Verbindungsstück | false | S101 | HI_PRO_STA_0,300x0,300 | 10.7 | 10.54 | 10.84 | 6.941 | 10.4 | 0.015 | 10.55 | 10.69 | 6.926 | 0
Verbindungsstück | Wartung_FFB | S235 | 0 | Verbindungsstück | PythonPart | Wartung_FFB | Plate | 0121Pyt0000006256 | Verbindungsstück | false | S101 | HI_PRO_STA_0,300x0,300 | 10.7 | 10.54 | 10.84 | 6.941 | 10.4 | 0.015 | 10.55 | 10.69 | 6.926 | 0
Verbindungsstück | Wartung_FFB | S235 | 0 | Verbindungsstück | PythonPart | Wartung_FFB | Plate | 0121Pyt0000006279 | Verbindungsstück | false | S101 | HI_PRO_STA_0,300x0,300 | 10.7 | 10.54 | 10.84 | 6.941 | 10.4 | 0.015 | 10.55 | 10.69 | 6.926 | 0
Verbindungsstück | Wartung_FFB | S235 | 0 | Verbindungsstück | PythonPart | Wartung_FFB | Plate | 0121Pyt0000006209 | Verbindungsstück | false | S101 | HI_PRO_STA_0,300x0,300 | 10.7 | 10.54 | 10.84 | 6.941 | 10.4 | 0.015 | 10.55 | 10.69 | 6.926 | 0
Verbindungsstück | Wartung_FFB | S235 | 0 | Verbindungsstück | PythonPart | Wartung_FFB | Plate | 0121Pyt0000006232 | Verbindungsstück | false | S101 | HI_PRO_STA_0,300x0,300 | 10.7 | 10.54 | 10.84 | 6.941 | 10.4 | 0.015 | 10.55 | 10.69 | 6.926 | 0
Verbindungsstück | Wartung_FFB | S235 | 0 | Verbindungsstück | PythonPart | Wartung_FFB | Plate | 0121Pyt0000006255 | Verbindungsstück | false | S101 | HI_PRO_STA_0,300x0,300 | 10.7 | 10.54 | 10.84 | 6.941 | 10.4 | 0.015 | 10.55 | 10.69 | 6.926 | 0
Verbindungsstück | Wartung_FFB | S235 | 0 | Verbindungsstück | PythonPart | Wartung_FFB | Plate | 0121Pyt0000006278 | Verbindungsstück | false | S101 | HI_PRO_STA_0,300x0,300 | 10.7 | 10.54 | 10.84 | 6.941 | 10.4 | 0.015 | 10.55 | 10.69 | 6.926 | 0
Verbindungsstück | Wartung_FFB | S235 | 0 | Verbindungsstück | PythonPart | Wartung_FFB | Plate | 0121Pyt0000006208 | Verbindungsstück | false | S101 | HI_PRO_STA_0,250x0,500 | 10.675 | 10.44 | 10.94 | 6.926 | 10.425 | 0.025 | 10.55 | 10.69 | 6.901 | 0
Verbindungsstück | Wartung_FFB | S235 | 0 | Verbindungsstück | PythonPart | Wartung_FFB | Plate | 0121Pyt0000006231 | Verbindungsstück | false | S101 | HI_PRO_STA_0,250x0,500 | 10.675 | 10.44 | 10.94 | 6.926 | 10.425 | 0.025 | 10.55 | 10.69 | 6.901 | 0
Verbindungsstück | Wartung_FFB | S235 | 0 | Verbindungsstück | PythonPart | Wartung_FFB | Plate | 0121Pyt0000006254 | Verbindungsstück | false | S101 | HI_PRO_STA_0,250x0,500 | 10.675 | 10.44 | 10.94 | 6.926 | 10.425 | 0.025 | 10.55 | 10.69 | 6.901 | 0
Verbindungsstück | Wartung_FFB | S235 | 0 | Verbindungsstück | PythonPart | Wartung_FFB | Plate | 0121Pyt0000006277 | Verbindungsstück | false | S101 | HI_PRO_STA_0,250x0,500 | 10.675 | 10.44 | 10.94 | 6.926 | 10.425 | 0.025 | 10.55 | 10.69 | 6.901 | 0
Verbindungsstück | Wartung_FFB | S235 | 0 | Verbindungsstück | PythonPart | Wartung_FFB | Plate | 0121Pyt0000006211 | Verbindungsstück | false | S101 | HI_PRO_STA_0,250x0,500 | 10.675 | 29.85 | 30.35 | 6.926 | 10.425 | 0.025 | 10.55 | 30.1 | 6.901 | 0
Verbindungsstück | Wartung_FFB | S235 | 0 | Verbindungsstück | PythonPart | Wartung_FFB | Plate | 0121Pyt0000006234 | Verbindungsstück | false | S101 | HI_PRO_STA_0,250x0,500 | 10.675 | 29.85 | 30.35 | 6.926 | 10.425 | 0.025 | 10.55 | 30.1 | 6.901 | 0
Verbindungsstück | Wartung_FFB | S235 | 0 | Verbindungsstück | PythonPart | Wartung_FFB | Plate | 0121Pyt0000006257 | Verbindungsstück | false | S101 | HI_PRO_STA_0,250x0,500 | 10.675 | 29.85 | 30.35 | 6.926 | 10.425 | 0.025 | 10.55 | 30.1 | 6.901 | 0
Verbindungsstück | Wartung_FFB | S235 | 0 | Verbindungsstück | PythonPart | Wartung_FFB | Plate | 0121Pyt0000006280 | Verbindungsstück | false | S101 | HI_PRO_STA_0,250x0,500 | 10.675 | 29.85 | 30.35 | 6.926 | 10.425 | 0.025 | 10.55 | 30.1 | 6.901 | 0
Verbindungsstück | Wartung_FFB | S235 | 0 | Verbindungsstück | PythonPart | Wartung_FFB | Plate | 0121Pyt0000006302 | Verbindungsstück | false | S101 | HI_PRO_STA_0,300x0,300 | 10.7 | 10.54 | 10.84 | 6.941 | 10.4 | 0.015 | 10.55 | 10.69 | 6.926 | 0
Verbindungsstück | Wartung_FFB | S235 | 0 | Verbindungsstück | PythonPart | Wartung_FFB | Plate | 0121Pyt0000006301 | Verbindungsstück | false | S101 | HI_PRO_STA_0,300x0,300 | 10.7 | 10.54 | 10.84 | 6.941 | 10.4 | 0.015 | 10.55 | 10.69 | 6.926 | 0
Verbindungsstück | Wartung_FFB | S235 | 0 | Verbindungsstück | PythonPart | Wartung_FFB | Plate | 0121Pyt0000006300 | Verbindungsstück | false | S101 | HI_PRO_STA_0,250x0,500 | 10.675 | 10.44 | 10.94 | 6.926 | 10.425 | 0.025 | 10.55 | 10.69 | 6.901 | 0
Verbindungsstück | Wartung_FFB | S235 | 0 | Verbindungsstück | PythonPart | Wartung_FFB | Plate | 0121Pyt0000006303 | Verbindungsstück | false | S101 | HI_PRO_STA_0,250x0,500 | 10.675 | 29.85 | 30.35 | 6.926 | 10.425 | 0.025 | 10.55 | 30.1 | 6.901 | 0
Verbindungsstück | Wartung_FFB | S235 | 0 | Verbindungsstück | PythonPart | Wartung_FFB | Plate | 0121Pyt0000006071 | Verbindungsstück | false | S101 | HI_PRO_STA_0,300x0,300 | 10.7 | 10.54 | 10.84 | 6.941 | 10.4 | 0.015 | 10.55 | 10.69 | 6.926 | 0
Verbindungsstück | Wartung_FFB | S235 | 0 | Verbindungsstück | PythonPart | Wartung_FFB | Plate | 0121Pyt0000006094 | Verbindungsstück | false | S101 | HI_PRO_STA_0,300x0,300 | 10.7 | 10.54 | 10.84 | 6.941 | 10.4 | 0.015 | 10.55 | 10.69 | 6.926 | 0
Verbindungsstück | Wartung_FFB | S235 | 0 | Verbindungsstück | PythonPart | Wartung_FFB | Plate | 0121Pyt0000006070 | Verbindungsstück | false | S101 | HI_PRO_STA_0,250x0,500 | 10.675 | 10.44 | 10.94 | 6.926 | 10.425 | 0.025 | 10.55 | 10.69 | 6.901 | 0
Verbindungsstück | Wartung_FFB | S235 | 0 | Verbindungsstück | PythonPart | Wartung_FFB | Plate | 0121Pyt0000006093 | Verbindungsstück | false | S101 | HI_PRO_STA_0,250x0,500 | 10.675 | 10.44 | 10.94 | 6.926 | 10.425 | 0.025 | 10.55 | 10.69 | 6.901 | 0
Verbindungsstück | Wartung_FFB | S235 | 0 | Verbindungsstück | PythonPart | Wartung_FFB | Plate | 0121Pyt0000006072 | Verbindungsstück | false | S101 | HI_PRO_STA_0,300x0,300 | 10.7 | 10.54 | 10.84 | 6.941 | 10.4 | 0.015 | 10.55 | 10.69 | 6.926 | 0
Verbindungsstück | Wartung_FFB | S235 | 0 | Verbindungsstück | PythonPart | Wartung_FFB | Plate | 0121Pyt0000006095 | Verbindungsstück | false | S101 | HI_PRO_STA_0,300x0,300 | 10.7 | 10.54 | 10.84 | 6.941 | 10.4 | 0.015 | 10.55 | 10.69 | 6.926 | 0
Verbindungsstück | Wartung_FFB | S235 | 0 | Verbindungsstück | PythonPart | Wartung_FFB | Plate | 0121Pyt0000006073 | Verbindungsstück | false | S101 | HI_PRO_STA_0,250x0,500 | 10.675 | 29.85 | 30.35 | 6.926 | 10.425 | 0.025 | 10.55 | 30.1 | 6.901 | 0
Verbindungsstück | Wartung_FFB | S235 | 0 | Verbindungsstück | PythonPart | Wartung_FFB | Plate | 0121Pyt0000006096 | Verbindungsstück | false | S101 | HI_PRO_STA_0,250x0,500 | 10.675 | 29.85 | 30.35 | 6.926 | 10.425 | 0.025 | 10.55 | 30.1 | 6.901 | 0
Verbindungsstück | Wartung_FFB | S235 | 0 | Verbindungsstück | PythonPart | Wartung_FFB | Plate | 0121Pyt0000005865 | Verbindungsstück | false | S101 | HI_PRO_STA_0,300x0,300 | 10.7 | 10.54 | 10.84 | 6.941 | 10.4 | 0.015 | 10.55 | 10.69 | 6.926 | 0
Verbindungsstück | Wartung_FFB | S235 | 0 | Verbindungsstück | PythonPart | Wartung_FFB | Plate | 0121Pyt0000005911 | Verbindungsstück | false | S101 | HI_PRO_STA_0,300x0,300 | 10.7 | 10.54 | 10.84 | 6.941 | 10.4 | 0.015 | 10.55 | 10.69 | 6.926 | 0
Verbindungsstück | Wartung_FFB | S235 | 0 | Verbindungsstück | PythonPart | Wartung_FFB | Plate | 0121Pyt0000005864 | Verbindungsstück | false | S101 | HI_PRO_STA_0,300x0,300 | 10.7 | 10.54 | 10.84 | 6.941 | 10.4 | 0.015 | 10.55 | 10.69 | 6.926 | 0
Verbindungsstück | Wartung_FFB | S235 | 0 | Verbindungsstück | PythonPart | Wartung_FFB | Plate | 0121Pyt0000005910 | Verbindungsstück | false | S101 | HI_PRO_STA_0,300x0,300 | 10.7 | 10.54 | 10.84 | 6.941 | 10.4 | 0.015 | 10.55 | 10.69 | 6.926 | 0
Verbindungsstück | Wartung_FFB | S235 | 0 | Verbindungsstück | PythonPart | Wartung_FFB | Plate | 0121Pyt0000005863 | Verbindungsstück | false | S101 | HI_PRO_STA_0,250x0,500 | 10.675 | 10.44 | 10.94 | 6.926 | 10.425 | 0.025 | 10.55 | 10.69 | 6.901 | 0
Verbindungsstück | Wartung_FFB | S235 | 0 | Verbindungsstück | PythonPart | Wartung_FFB | Plate | 0121Pyt0000005909 | Verbindungsstück | false | S101 | HI_PRO_STA_0,250x0,500 | 10.675 | 10.44 | 10.94 | 6.926 | 10.425 | 0.025 | 10.55 | 10.69 | 6.901 | 0
Verbindungsstück | Wartung_FFB | S235 | 0 | Verbindungsstück | PythonPart | Wartung_FFB | Plate | 0121Pyt0000005866 | Verbindungsstück | false | S101 | HI_PRO_STA_0,250x0,500 | 10.675 | 29.85 | 30.35 | 6.926 | 10.425 | 0.025 | 10.55 | 30.1 | 6.901 | 0
Verbindungsstück | Wartung_FFB | S235 | 0 | Verbindungsstück | PythonPart | Wartung_FFB | Plate | 0121Pyt0000005912 | Verbindungsstück | false | S101 | HI_PRO_STA_0,250x0,500 | 10.675 | 29.85 | 30.35 | 6.926 | 10.425 | 0.025 | 10.55 | 30.1 | 6.901 | 0
Verbindungsstück | Wartung_FFB | S235 | 0 | Verbindungsstück | PythonPart | Wartung_FFB | Plate | 0121Pyt0000005934 | Verbindungsstück | false | S101 | HI_PRO_STA_0,300x0,300 | 10.7 | 10.54 | 10.84 | 6.941 | 10.4 | 0.015 | 10.55 | 10.69 | 6.926 | 0
Verbindungsstück | Wartung_FFB | S235 | 0 | Verbindungsstück | PythonPart | Wartung_FFB | Plate | 0121Pyt0000005933 | Verbindungsstück | false | S101 | HI_PRO_STA_0,300x0,300 | 10.7 | 10.54 | 10.84 | 6.941 | 10.4 | 0.015 | 10.55 | 10.69 | 6.926 | 0
Verbindungsstück | Wartung_FFB | S235 | 0 | Verbindungsstück | PythonPart | Wartung_FFB | Plate | 0121Pyt0000005932 | Verbindungsstück | false | S101 | HI_PRO_STA_0,250x0,500 | 10.675 | 10.44 | 10.94 | 6.926 | 10.425 | 0.025 | 10.55 | 10.69 | 6.901 | 0
Verbindungsstück | Wartung_FFB | S235 | 0 | Verbindungsstück | PythonPart | Wartung_FFB | Plate | 0121Pyt0000005935 | Verbindungsstück | false | S101 | HI_PRO_STA_0,250x0,500 | 10.675 | 29.85 | 30.35 | 6.926 | 10.425 | 0.025 | 10.55 | 30.1 | 6.901 | 0
Verbindungsstück | Wartung_FFB | S235 | 0 | Verbindungsstück | PythonPart | Wartung_FFB | Plate | 0121Pyt0000005957 | Verbindungsstück | false | S101 | HI_PRO_STA_0,300x0,300 | 10.7 | 10.54 | 10.84 | 6.941 | 10.4 | 0.015 | 10.55 | 10.69 | 6.926 | 0
Verbindungsstück | Wartung_FFB | S235 | 0 | Verbindungsstück | PythonPart | Wartung_FFB | Plate | 0121Pyt0000005956 | Verbindungsstück | false | S101 | HI_PRO_STA_0,300x0,300 | 10.7 | 10.54 | 10.84 | 6.941 | 10.4 | 0.015 | 10.55 | 10.69 | 6.926 | 0
Verbindungsstück | Wartung_FFB | S235 | 0 | Verbindungsstück | PythonPart | Wartung_FFB | Plate | 0121Pyt0000005955 | Verbindungsstück | false | S101 | HI_PRO_STA_0,250x0,500 | 10.675 | 10.44 | 10.94 | 6.926 | 10.425 | 0.025 | 10.55 | 10.69 | 6.901 | 0
Verbindungsstück | Wartung_FFB | S235 | 0 | Verbindungsstück | PythonPart | Wartung_FFB | Plate | 0121Pyt0000005958 | Verbindungsstück | false | S101 | HI_PRO_STA_0,250x0,500 | 10.675 | 29.85 | 30.35 | 6.926 | 10.425 | 0.025 | 10.55 | 30.1 | 6.901 | 0
Verbindungsstück | Wartung_FFB | S235 | 0 | Verbindungsstück | PythonPart | Wartung_FFB | Plate | 0121Pyt0000005980 | Verbindungsstück | false | S101 | HI_PRO_STA_0,300x0,300 | 10.7 | 10.54 | 10.84 | 6.941 | 10.4 | 0.015 | 10.55 | 10.69 | 6.926 | 0
Verbindungsstück | Wartung_FFB | S235 | 0 | Verbindungsstück | PythonPart | Wartung_FFB | Plate | 0121Pyt0000006003 | Verbindungsstück | false | S101 | HI_PRO_STA_0,300x0,300 | 10.7 | 10.54 | 10.84 | 6.941 | 10.4 | 0.015 | 10.55 | 10.69 | 6.926 | 0
Verbindungsstück | Wartung_FFB | S235 | 0 | Verbindungsstück | PythonPart | Wartung_FFB | Plate | 0121Pyt0000006026 | Verbindungsstück | false | S101 | HI_PRO_STA_0,300x0,300 | 10.7 | 10.54 | 10.84 | 6.941 | 10.4 | 0.015 | 10.55 | 10.69 | 6.926 | 0
Verbindungsstück | Wartung_FFB | S235 | 0 | Verbindungsstück | PythonPart | Wartung_FFB | Plate | 0121Pyt0000006049 | Verbindungsstück | false | S101 | HI_PRO_STA_0,300x0,300 | 10.7 | 10.54 | 10.84 | 6.941 | 10.4 | 0.015 | 10.55 | 10.69 | 6.926 | 0
Verbindungsstück | Wartung_FFB | S235 | 0 | Verbindungsstück | PythonPart | Wartung_FFB | Plate | 0121Pyt0000005979 | Verbindungsstück | false | S101 | HI_PRO_STA_0,300x0,300 | 10.7 | 10.54 | 10.84 | 6.941 | 10.4 | 0.015 | 10.55 | 10.69 | 6.926 | 0
Verbindungsstück | Wartung_FFB | S235 | 0 | Verbindungsstück | PythonPart | Wartung_FFB | Plate | 0121Pyt0000006002 | Verbindungsstück | false | S101 | HI_PRO_STA_0,300x0,300 | 10.7 | 10.54 | 10.84 | 6.941 | 10.4 | 0.015 | 10.55 | 10.69 | 6.926 | 0
Verbindungsstück | Wartung_FFB | S235 | 0 | Verbindungsstück | PythonPart | Wartung_FFB | Plate | 0121Pyt0000006025 | Verbindungsstück | false | S101 | HI_PRO_STA_0,300x0,300 | 10.7 | 10.54 | 10.84 | 6.941 | 10.4 | 0.015 | 10.55 | 10.69 | 6.926 | 0
Verbindungsstück | Wartung_FFB | S235 | 0 | Verbindungsstück | PythonPart | Wartung_FFB | Plate | 0121Pyt0000006048 | Verbindungsstück | false | S101 | HI_PRO_STA_0,300x0,300 | 10.7 | 10.54 | 10.84 | 6.941 | 10.4 | 0.015 | 10.55 | 10.69 | 6.926 | 0
Verbindungsstück | Wartung_FFB | S235 | 0 | Verbindungsstück | PythonPart | Wartung_FFB | Plate | 0121Pyt0000005978 | Verbindungsstück | false | S101 | HI_PRO_STA_0,250x0,500 | 10.675 | 10.44 | 10.94 | 6.926 | 10.425 | 0.025 | 10.55 | 10.69 | 6.901 | 0
Verbindungsstück | Wartung_FFB | S235 | 0 | Verbindungsstück | PythonPart | Wartung_FFB | Plate | 0121Pyt0000006001 | Verbindungsstück | false | S101 | HI_PRO_STA_0,250x0,500 | 10.675 | 10.44 | 10.94 | 6.926 | 10.425 | 0.025 | 10.55 | 10.69 | 6.901 | 0
Verbindungsstück | Wartung_FFB | S235 | 0 | Verbindungsstück | PythonPart | Wartung_FFB | Plate | 0121Pyt0000006024 | Verbindungsstück | false | S101 | HI_PRO_STA_0,250x0,500 | 10.675 | 10.44 | 10.94 | 6.926 | 10.425 | 0.025 | 10.55 | 10.69 | 6.901 | 0
Verbindungsstück | Wartung_FFB | S235 | 0 | Verbindungsstück | PythonPart | Wartung_FFB | Plate | 0121Pyt0000006047 | Verbindungsstück | false | S101 | HI_PRO_STA_0,250x0,500 | 10.675 | 10.44 | 10.94 | 6.926 | 10.425 | 0.025 | 10.55 | 10.69 | 6.901 | 0
Verbindungsstück | Wartung_FFB | S235 | 0 | Verbindungsstück | PythonPart | Wartung_FFB | Plate | 0121Pyt0000005981 | Verbindungsstück | false | S101 | HI_PRO_STA_0,250x0,500 | 10.675 | 29.85 | 30.35 | 6.926 | 10.425 | 0.025 | 10.55 | 30.1 | 6.901 | 0
Verbindungsstück | Wartung_FFB | S235 | 0 | Verbindungsstück | PythonPart | Wartung_FFB | Plate | 0121Pyt0000006004 | Verbindungsstück | false | S101 | HI_PRO_STA_0,250x0,500 | 10.675 | 29.85 | 30.35 | 6.926 | 10.425 | 0.025 | 10.55 | 30.1 | 6.901 | 0
Verbindungsstück | Wartung_FFB | S235 | 0 | Verbindungsstück | PythonPart | Wartung_FFB | Plate | 0121Pyt0000006027 | Verbindungsstück | false | S101 | HI_PRO_STA_0,250x0,500 | 10.675 | 29.85 | 30.35 | 6.926 | 10.425 | 0.025 | 10.55 | 30.1 | 6.901 | 0
Verbindungsstück | Wartung_FFB | S235 | 0 | Verbindungsstück | PythonPart | Wartung_FFB | Plate | 0121Pyt0000006050 | Verbindungsstück | false | S101 | HI_PRO_STA_0,250x0,500 | 10.675 | 29.85 | 30.35 | 6.926 | 10.425 | 0.025 | 10.55 | 30.1 | 6.901 | 0
Verbindungsstück | Wartung_FFB | S235 | 0 | Verbindungsstück | PythonPart | Wartung_FFB | Plate | 0121Pyt0000006118 | Verbindungsstück | false | S101 | HI_PRO_STA_0,300x0,300 | 10.7 | 10.54 | 10.84 | 6.941 | 10.4 | 0.015 | 10.55 | 10.69 | 6.926 | 0
Verbindungsstück | Wartung_FFB | S235 | 0 | Verbindungsstück | PythonPart | Wartung_FFB | Plate | 0121Pyt0000006164 | Verbindungsstück | false | S101 | HI_PRO_STA_0,300x0,300 | 10.7 | 10.54 | 10.84 | 6.941 | 10.4 | 0.015 | 10.55 | 10.69 | 6.926 | 0
Verbindungsstück | Wartung_FFB | S235 | 0 | Verbindungsstück | PythonPart | Wartung_FFB | Plate | 0121Pyt0000006117 | Verbindungsstück | false | S101 | HI_PRO_STA_0,300x0,300 | 10.7 | 10.54 | 10.84 | 6.941 | 10.4 | 0.015 | 10.55 | 10.69 | 6.926 | 0
Verbindungsstück | Wartung_FFB | S235 | 0 | Verbindungsstück | PythonPart | Wartung_FFB | Plate | 0121Pyt0000006163 | Verbindungsstück | false | S101 | HI_PRO_STA_0,300x0,300 | 10.7 | 10.54 | 10.84 | 6.941 | 10.4 | 0.015 | 10.55 | 10.69 | 6.926 | 0
Verbindungsstück | Wartung_FFB | S235 | 0 | Verbindungsstück | PythonPart | Wartung_FFB | Plate | 0121Pyt0000006116 | Verbindungsstück | false | S101 | HI_PRO_STA_0,250x0,500 | 10.675 | 10.44 | 10.94 | 6.926 | 10.425 | 0.025 | 10.55 | 10.69 | 6.901 | 0
Verbindungsstück | Wartung_FFB | S235 | 0 | Verbindungsstück | PythonPart | Wartung_FFB | Plate | 0121Pyt0000006162 | Verbindungsstück | false | S101 | HI_PRO_STA_0,250x0,500 | 10.675 | 10.44 | 10.94 | 6.926 | 10.425 | 0.025 | 10.55 | 10.69 | 6.901 | 0
Verbindungsstück | Wartung_FFB | S235 | 0 | Verbindungsstück | PythonPart | Wartung_FFB | Plate | 0121Pyt0000006119 | Verbindungsstück | false | S101 | HI_PRO_STA_0,250x0,500 | 10.675 | 29.85 | 30.35 | 6.926 | 10.425 | 0.025 | 10.55 | 30.1 | 6.901 | 0
Verbindungsstück | Wartung_FFB | S235 | 0 | Verbindungsstück | PythonPart | Wartung_FFB | Plate | 0121Pyt0000006165 | Verbindungsstück | false | S101 | HI_PRO_STA_0,250x0,500 | 10.675 | 29.85 | 30.35 | 6.926 | 10.425 | 0.025 | 10.55 | 30.1 | 6.901 | 0
Verbindungsstück | Wartung_FFB | S235 | 0 | Verbindungsstück | PythonPart | Wartung_FFB | Plate | 0121Pyt0000005736 | Verbindungsstück | false | S101 | HI_PRO_STA_0,300x0,300 | 10.7 | 10.54 | 10.84 | 6.941 | 10.4 | 0.015 | 10.55 | 10.69 | 6.926 | 0
Verbindungsstück | Wartung_FFB | S235 | 0 | Verbindungsstück | PythonPart | Wartung_FFB | Plate | 0121Pyt0000005760 | Verbindungsstück | false | S101 | HI_PRO_STA_0,300x0,300 | 10.7 | 10.54 | 10.84 | 6.941 | 10.4 | 0.015 | 10.55 | 10.69 | 6.926 | 0
Verbindungsstück | Wartung_FFB | S235 | 0 | Verbindungsstück | PythonPart | Wartung_FFB | Plate | 0121Pyt0000005773 | Verbindungsstück | false | S101 | HI_PRO_STA_0,300x0,300 | 10.7 | 10.54 | 10.84 | 6.941 | 10.4 | 0.015 | 10.55 | 10.69 | 6.926 | 0
Verbindungsstück | Wartung_FFB | S235 | 0 | Verbindungsstück | PythonPart | Wartung_FFB | Plate | 0121Pyt0000005796 | Verbindungsstück | false | S101 | HI_PRO_STA_0,300x0,300 | 10.7 | 10.54 | 10.84 | 6.941 | 10.4 | 0.015 | 10.55 | 10.69 | 6.926 | 0
Verbindungsstück | Wartung_FFB | S235 | 0 | Verbindungsstück | PythonPart | Wartung_FFB | Plate | 0121Pyt0000005819 | Verbindungsstück | false | S101 | HI_PRO_STA_0,300x0,300 | 10.7 | 10.54 | 10.84 | 6.941 | 10.4 | 0.015 | 10.55 | 10.69 | 6.926 | 0
Verbindungsstück | Wartung_FFB | S235 | 0 | Verbindungsstück | PythonPart | Wartung_FFB | Plate | 0121Pyt0000003844 | Verbindungsstück | false | S101 | HI_PRO_STA_0,300x0,300 | 10.7 | 10.54 | 10.84 | 6.941 | 10.4 | 0.015 | 10.55 | 10.69 | 6.926 | 0
Verbindungsstück | Wartung_FFB | S235 | 0 | Verbindungsstück | PythonPart | Wartung_FFB | Plate | 0121Pyt0000005759 | Verbindungsstück | false | S101 | HI_PRO_STA_0,300x0,300 | 10.7 | 10.54 | 10.84 | 6.941 | 10.4 | 0.015 | 10.55 | 10.69 | 6.926 | 0
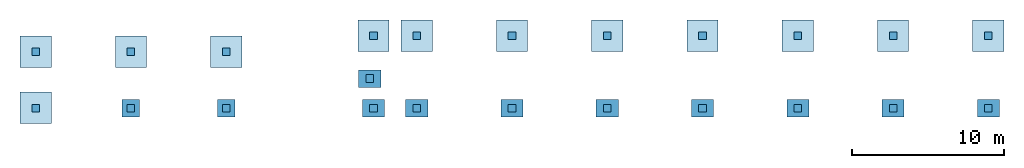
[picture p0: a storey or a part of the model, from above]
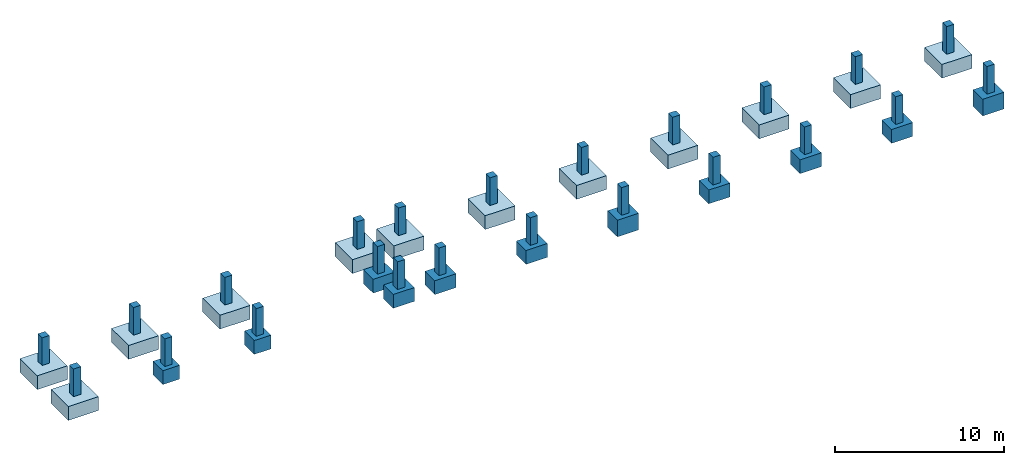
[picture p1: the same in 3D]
Properties of the parts of a building model (IFC2X3), part 19 of 25

# IfcPlate (1015)
Name | In | Material = AllplanAttributes, Material | V6 (m) = V7 (m) = V8 (m) = V9 | Bezeichnung | Plugin_Objektname | Ebene | Attributset-Objekt | Allright_Bauteil_ID | Name | Außenbauteil | Positionsnummer | PlateCommon, Reference | Unterkante (m) = X_Koordinate (m) | Oberkante (m) | Y_Koordinate (m) = Schwerpunkt_Y (m) | Z_Koordinate (m) = Schwerpunkt_Z (m) = Achsenstartpunkt (Z) (m) | Schwerpunkt_X (m) | Dicke (w) (m) | Achsenstartpunkt (X) (m) = Achsenendpunkt (X) (m) | Achsenstartpunkt (Y) (m) = Achsenendpunkt (Y) (m) | Achsenendpunkt (Z) (m) | Objektdrehwinkel
Verbindungsstück | Wartung_FFB | S235 | 0 | Verbindungsstück | PythonPart | Wartung_FFB | Plate | 0121Pyt0000005772 | Verbindungsstück | false | S101 | HI_PRO_STA_0,300x0,300 | 10.7 | 10.54 | 10.84 | 6.941 | 10.4 | 0.015 | 10.55 | 10.69 | 6.926 | 0
Verbindungsstück | Wartung_FFB | S235 | 0 | Verbindungsstück | PythonPart | Wartung_FFB | Plate | 0121Pyt0000005795 | Verbindungsstück | false | S101 | HI_PRO_STA_0,300x0,300 | 10.7 | 10.54 | 10.84 | 6.941 | 10.4 | 0.015 | 10.55 | 10.69 | 6.926 | 0
Verbindungsstück | Wartung_FFB | S235 | 0 | Verbindungsstück | PythonPart | Wartung_FFB | Plate | 0121Pyt0000005818 | Verbindungsstück | false | S101 | HI_PRO_STA_0,300x0,300 | 10.7 | 10.54 | 10.84 | 6.941 | 10.4 | 0.015 | 10.55 | 10.69 | 6.926 | 0
Verbindungsstück | Wartung_FFB | S235 | 0 | Verbindungsstück | PythonPart | Wartung_FFB | Plate | 0121Pyt0000003850 | Verbindungsstück | false | S101 | HI_PRO_STA_0,250x0,500 | 10.675 | 10.44 | 10.94 | 6.926 | 10.425 | 0.025 | 10.55 | 10.69 | 6.901 | 0
Verbindungsstück | Wartung_FFB | S235 | 0 | Verbindungsstück | PythonPart | Wartung_FFB | Plate | 0121Pyt0000005758 | Verbindungsstück | false | S101 | HI_PRO_STA_0,250x0,500 | 10.675 | 10.44 | 10.94 | 6.926 | 10.425 | 0.025 | 10.55 | 10.69 | 6.901 | 0
Verbindungsstück | Wartung_FFB | S235 | 0 | Verbindungsstück | PythonPart | Wartung_FFB | Plate | 0121Pyt0000005771 | Verbindungsstück | false | S101 | HI_PRO_STA_0,250x0,500 | 10.675 | 10.44 | 10.94 | 6.926 | 10.425 | 0.025 | 10.55 | 10.69 | 6.901 | 0
Verbindungsstück | Wartung_FFB | S235 | 0 | Verbindungsstück | PythonPart | Wartung_FFB | Plate | 0121Pyt0000005794 | Verbindungsstück | false | S101 | HI_PRO_STA_0,250x0,500 | 10.675 | 10.44 | 10.94 | 6.926 | 10.425 | 0.025 | 10.55 | 10.69 | 6.901 | 0
Verbindungsstück | Wartung_FFB | S235 | 0 | Verbindungsstück | PythonPart | Wartung_FFB | Plate | 0121Pyt0000005817 | Verbindungsstück | false | S101 | HI_PRO_STA_0,250x0,500 | 10.675 | 10.44 | 10.94 | 6.926 | 10.425 | 0.025 | 10.55 | 10.69 | 6.901 | 0
Verbindungsstück | Wartung_FFB | S235 | 0 | Verbindungsstück | PythonPart | Wartung_FFB | Plate | 0121Pyt0000005735 | Verbindungsstück | false | S101 | HI_PRO_STA_0,250x0,500 | 10.675 | 29.85 | 30.35 | 6.926 | 10.425 | 0.025 | 10.55 | 30.1 | 6.901 | 0
Verbindungsstück | Wartung_FFB | S235 | 0 | Verbindungsstück | PythonPart | Wartung_FFB | Plate | 0121Pyt0000005761 | Verbindungsstück | false | S101 | HI_PRO_STA_0,250x0,500 | 10.675 | 29.85 | 30.35 | 6.926 | 10.425 | 0.025 | 10.55 | 30.1 | 6.901 | 0
Verbindungsstück | Wartung_FFB | S235 | 0 | Verbindungsstück | PythonPart | Wartung_FFB | Plate | 0121Pyt0000005774 | Verbindungsstück | false | S101 | HI_PRO_STA_0,250x0,500 | 10.675 | 29.85 | 30.35 | 6.926 | 10.425 | 0.025 | 10.55 | 30.1 | 6.901 | 0
Verbindungsstück | Wartung_FFB | S235 | 0 | Verbindungsstück | PythonPart | Wartung_FFB | Plate | 0121Pyt0000005797 | Verbindungsstück | false | S101 | HI_PRO_STA_0,250x0,500 | 10.675 | 29.85 | 30.35 | 6.926 | 10.425 | 0.025 | 10.55 | 30.1 | 6.901 | 0
Verbindungsstück | Wartung_FFB | S235 | 0 | Verbindungsstück | PythonPart | Wartung_FFB | Plate | 0121Pyt0000005820 | Verbindungsstück | false | S101 | HI_PRO_STA_0,250x0,500 | 10.675 | 29.85 | 30.35 | 6.926 | 10.425 | 0.025 | 10.55 | 30.1 | 6.901 | 0
Verbindungsstück | Wartung_FFB | S235 | 0 | Verbindungsstück | PythonPart | Wartung_FFB | Plate | 0121Pyt0000006325 | Verbindungsstück | false | S101 | HI_PRO_STA_0,300x0,300 | 10.7 | 10.54 | 10.84 | 6.941 | 10.4 | 0.015 | 10.55 | 10.69 | 6.926 | 0
Verbindungsstück | Wartung_FFB | S235 | 0 | Verbindungsstück | PythonPart | Wartung_FFB | Plate | 0121Pyt0000006348 | Verbindungsstück | false | S101 | HI_PRO_STA_0,300x0,300 | 10.7 | 10.54 | 10.84 | 6.941 | 10.4 | 0.015 | 10.55 | 10.69 | 6.926 | 0
Verbindungsstück | Wartung_FFB | S235 | 0 | Verbindungsstück | PythonPart | Wartung_FFB | Plate | 0121Pyt0000006371 | Verbindungsstück | false | S101 | HI_PRO_STA_0,300x0,300 | 10.7 | 10.54 | 10.84 | 6.941 | 10.4 | 0.015 | 10.55 | 10.69 | 6.926 | 0
Verbindungsstück | Wartung_FFB | S235 | 0 | Verbindungsstück | PythonPart | Wartung_FFB | Plate | 0121Pyt0000006417 | Verbindungsstück | false | S101 | HI_PRO_STA_0,300x0,300 | 10.7 | 10.54 | 10.84 | 6.941 | 10.4 | 0.015 | 10.55 | 10.69 | 6.926 | 0
Verbindungsstück | Wartung_FFB | S235 | 0 | Verbindungsstück | PythonPart | Wartung_FFB | Plate | 0121Pyt0000006440 | Verbindungsstück | false | S101 | HI_PRO_STA_0,300x0,300 | 10.7 | 10.54 | 10.84 | 6.941 | 10.4 | 0.015 | 10.55 | 10.69 | 6.926 | 0
Verbindungsstück | Wartung_FFB | S235 | 0 | Verbindungsstück | PythonPart | Wartung_FFB | Plate | 0121Pyt0000006463 | Verbindungsstück | false | S101 | HI_PRO_STA_0,300x0,300 | 10.7 | 10.54 | 10.84 | 6.941 | 10.4 | 0.015 | 10.55 | 10.69 | 6.926 | 0
Verbindungsstück | Wartung_FFB | S235 | 0 | Verbindungsstück | PythonPart | Wartung_FFB | Plate | 0121Pyt0000006486 | Verbindungsstück | false | S101 | HI_PRO_STA_0,300x0,300 | 10.7 | 10.54 | 10.84 | 6.941 | 10.4 | 0.015 | 10.55 | 10.69 | 6.926 | 0
Verbindungsstück | Wartung_FFB | S235 | 0 | Verbindungsstück | PythonPart | Wartung_FFB | Plate | 0121Pyt0000006509 | Verbindungsstück | false | S101 | HI_PRO_STA_0,300x0,300 | 10.7 | 10.54 | 10.84 | 6.941 | 10.4 | 0.015 | 10.55 | 10.69 | 6.926 | 0
Verbindungsstück | Wartung_FFB | S235 | 0 | Verbindungsstück | PythonPart | Wartung_FFB | Plate | 0121Pyt0000006532 | Verbindungsstück | false | S101 | HI_PRO_STA_0,300x0,300 | 10.7 | 10.54 | 10.84 | 6.941 | 10.4 | 0.015 | 10.55 | 10.69 | 6.926 | 0
Verbindungsstück | Wartung_FFB | S235 | 0 | Verbindungsstück | PythonPart | Wartung_FFB | Plate | 0121Pyt0000006555 | Verbindungsstück | false | S101 | HI_PRO_STA_0,300x0,300 | 10.7 | 10.54 | 10.84 | 6.941 | 10.4 | 0.015 | 10.55 | 10.69 | 6.926 | 0
Verbindungsstück | Wartung_FFB | S235 | 0 | Verbindungsstück | PythonPart | Wartung_FFB | Plate | 0121Pyt0000006578 | Verbindungsstück | false | S101 | HI_PRO_STA_0,300x0,300 | 10.7 | 10.54 | 10.84 | 6.941 | 10.4 | 0.015 | 10.55 | 10.69 | 6.926 | 0
Verbindungsstück | Wartung_FFB | S235 | 0 | Verbindungsstück | PythonPart | Wartung_FFB | Plate | 0121Pyt0000006601 | Verbindungsstück | false | S101 | HI_PRO_STA_0,300x0,300 | 10.7 | 10.54 | 10.84 | 6.941 | 10.4 | 0.015 | 10.55 | 10.69 | 6.926 | 0
Verbindungsstück | Wartung_FFB | S235 | 0 | Verbindungsstück | PythonPart | Wartung_FFB | Plate | 0121Pyt0000006324 | Verbindungsstück | false | S101 | HI_PRO_STA_0,300x0,300 | 10.7 | 10.54 | 10.84 | 6.941 | 10.4 | 0.015 | 10.55 | 10.69 | 6.926 | 0
Verbindungsstück | Wartung_FFB | S235 | 0 | Verbindungsstück | PythonPart | Wartung_FFB | Plate | 0121Pyt0000006347 | Verbindungsstück | false | S101 | HI_PRO_STA_0,300x0,300 | 10.7 | 10.54 | 10.84 | 6.941 | 10.4 | 0.015 | 10.55 | 10.69 | 6.926 | 0
Verbindungsstück | Wartung_FFB | S235 | 0 | Verbindungsstück | PythonPart | Wartung_FFB | Plate | 0121Pyt0000006370 | Verbindungsstück | false | S101 | HI_PRO_STA_0,300x0,300 | 10.7 | 10.54 | 10.84 | 6.941 | 10.4 | 0.015 | 10.55 | 10.69 | 6.926 | 0
Verbindungsstück | Wartung_FFB | S235 | 0 | Verbindungsstück | PythonPart | Wartung_FFB | Plate | 0121Pyt0000006416 | Verbindungsstück | false | S101 | HI_PRO_STA_0,300x0,300 | 10.7 | 10.54 | 10.84 | 6.941 | 10.4 | 0.015 | 10.55 | 10.69 | 6.926 | 0
Verbindungsstück | Wartung_FFB | S235 | 0 | Verbindungsstück | PythonPart | Wartung_FFB | Plate | 0121Pyt0000006439 | Verbindungsstück | false | S101 | HI_PRO_STA_0,300x0,300 | 10.7 | 10.54 | 10.84 | 6.941 | 10.4 | 0.015 | 10.55 | 10.69 | 6.926 | 0
Verbindungsstück | Wartung_FFB | S235 | 0 | Verbindungsstück | PythonPart | Wartung_FFB | Plate | 0121Pyt0000006462 | Verbindungsstück | false | S101 | HI_PRO_STA_0,300x0,300 | 10.7 | 10.54 | 10.84 | 6.941 | 10.4 | 0.015 | 10.55 | 10.69 | 6.926 | 0
Verbindungsstück | Wartung_FFB | S235 | 0 | Verbindungsstück | PythonPart | Wartung_FFB | Plate | 0121Pyt0000006485 | Verbindungsstück | false | S101 | HI_PRO_STA_0,300x0,300 | 10.7 | 10.54 | 10.84 | 6.941 | 10.4 | 0.015 | 10.55 | 10.69 | 6.926 | 0
Verbindungsstück | Wartung_FFB | S235 | 0 | Verbindungsstück | PythonPart | Wartung_FFB | Plate | 0121Pyt0000006508 | Verbindungsstück | false | S101 | HI_PRO_STA_0,300x0,300 | 10.7 | 10.54 | 10.84 | 6.941 | 10.4 | 0.015 | 10.55 | 10.69 | 6.926 | 0
Verbindungsstück | Wartung_FFB | S235 | 0 | Verbindungsstück | PythonPart | Wartung_FFB | Plate | 0121Pyt0000006531 | Verbindungsstück | false | S101 | HI_PRO_STA_0,300x0,300 | 10.7 | 10.54 | 10.84 | 6.941 | 10.4 | 0.015 | 10.55 | 10.69 | 6.926 | 0
Verbindungsstück | Wartung_FFB | S235 | 0 | Verbindungsstück | PythonPart | Wartung_FFB | Plate | 0121Pyt0000006554 | Verbindungsstück | false | S101 | HI_PRO_STA_0,300x0,300 | 10.7 | 10.54 | 10.84 | 6.941 | 10.4 | 0.015 | 10.55 | 10.69 | 6.926 | 0
Verbindungsstück | Wartung_FFB | S235 | 0 | Verbindungsstück | PythonPart | Wartung_FFB | Plate | 0121Pyt0000006577 | Verbindungsstück | false | S101 | HI_PRO_STA_0,300x0,300 | 10.7 | 10.54 | 10.84 | 6.941 | 10.4 | 0.015 | 10.55 | 10.69 | 6.926 | 0
Verbindungsstück | Wartung_FFB | S235 | 0 | Verbindungsstück | PythonPart | Wartung_FFB | Plate | 0121Pyt0000006600 | Verbindungsstück | false | S101 | HI_PRO_STA_0,300x0,300 | 10.7 | 10.54 | 10.84 | 6.941 | 10.4 | 0.015 | 10.55 | 10.69 | 6.926 | 0
Verbindungsstück | Wartung_FFB | S235 | 0 | Verbindungsstück | PythonPart | Wartung_FFB | Plate | 0121Pyt0000006323 | Verbindungsstück | false | S101 | HI_PRO_STA_0,250x0,500 | 10.675 | 10.44 | 10.94 | 6.926 | 10.425 | 0.025 | 10.55 | 10.69 | 6.901 | 0
Verbindungsstück | Wartung_FFB | S235 | 0 | Verbindungsstück | PythonPart | Wartung_FFB | Plate | 0121Pyt0000006346 | Verbindungsstück | false | S101 | HI_PRO_STA_0,250x0,500 | 10.675 | 10.44 | 10.94 | 6.926 | 10.425 | 0.025 | 10.55 | 10.69 | 6.901 | 0
Verbindungsstück | Wartung_FFB | S235 | 0 | Verbindungsstück | PythonPart | Wartung_FFB | Plate | 0121Pyt0000006369 | Verbindungsstück | false | S101 | HI_PRO_STA_0,250x0,500 | 10.675 | 10.44 | 10.94 | 6.926 | 10.425 | 0.025 | 10.55 | 10.69 | 6.901 | 0
Verbindungsstück | Wartung_FFB | S235 | 0 | Verbindungsstück | PythonPart | Wartung_FFB | Plate | 0121Pyt0000006438 | Verbindungsstück | false | S101 | HI_PRO_STA_0,250x0,500 | 10.675 | 10.44 | 10.94 | 6.926 | 10.425 | 0.025 | 10.55 | 10.69 | 6.901 | 0
Verbindungsstück | Wartung_FFB | S235 | 0 | Verbindungsstück | PythonPart | Wartung_FFB | Plate | 0121Pyt0000006461 | Verbindungsstück | false | S101 | HI_PRO_STA_0,250x0,500 | 10.675 | 10.44 | 10.94 | 6.926 | 10.425 | 0.025 | 10.55 | 10.69 | 6.901 | 0
Verbindungsstück | Wartung_FFB | S235 | 0 | Verbindungsstück | PythonPart | Wartung_FFB | Plate | 0121Pyt0000006484 | Verbindungsstück | false | S101 | HI_PRO_STA_0,250x0,500 | 10.675 | 10.44 | 10.94 | 6.926 | 10.425 | 0.025 | 10.55 | 10.69 | 6.901 | 0
Verbindungsstück | Wartung_FFB | S235 | 0 | Verbindungsstück | PythonPart | Wartung_FFB | Plate | 0121Pyt0000006507 | Verbindungsstück | false | S101 | HI_PRO_STA_0,250x0,500 | 10.675 | 10.44 | 10.94 | 6.926 | 10.425 | 0.025 | 10.55 | 10.69 | 6.901 | 0
Verbindungsstück | Wartung_FFB | S235 | 0 | Verbindungsstück | PythonPart | Wartung_FFB | Plate | 0121Pyt0000006530 | Verbindungsstück | false | S101 | HI_PRO_STA_0,250x0,500 | 10.675 | 10.44 | 10.94 | 6.926 | 10.425 | 0.025 | 10.55 | 10.69 | 6.901 | 0
Verbindungsstück | Wartung_FFB | S235 | 0 | Verbindungsstück | PythonPart | Wartung_FFB | Plate | 0121Pyt0000006553 | Verbindungsstück | false | S101 | HI_PRO_STA_0,250x0,500 | 10.675 | 10.44 | 10.94 | 6.926 | 10.425 | 0.025 | 10.55 | 10.69 | 6.901 | 0
Verbindungsstück | Wartung_FFB | S235 | 0 | Verbindungsstück | PythonPart | Wartung_FFB | Plate | 0121Pyt0000006576 | Verbindungsstück | false | S101 | HI_PRO_STA_0,250x0,500 | 10.675 | 10.44 | 10.94 | 6.926 | 10.425 | 0.025 | 10.55 | 10.69 | 6.901 | 0
Verbindungsstück | Wartung_FFB | S235 | 0 | Verbindungsstück | PythonPart | Wartung_FFB | Plate | 0121Pyt0000006599 | Verbindungsstück | false | S101 | HI_PRO_STA_0,250x0,500 | 10.675 | 10.44 | 10.94 | 6.926 | 10.425 | 0.025 | 10.55 | 10.69 | 6.901 | 0
Verbindungsstück | Wartung_FFB | S235 | 0 | Verbindungsstück | PythonPart | Wartung_FFB | Plate | 0121Pyt0000006415 | Verbindungsstück | false | S101 | HI_PRO_STA_0,250x0,500 | 10.675 | 10.44 | 10.94 | 6.926 | 10.425 | 0.025 | 10.55 | 10.69 | 6.901 | 0
Verbindungsstück | Wartung_FFB | S235 | 0 | Verbindungsstück | PythonPart | Wartung_FFB | Plate | 0121Pyt0000006326 | Verbindungsstück | false | S101 | HI_PRO_STA_0,250x0,500 | 10.675 | 29.85 | 30.35 | 6.926 | 10.425 | 0.025 | 10.55 | 30.1 | 6.901 | 0
Verbindungsstück | Wartung_FFB | S235 | 0 | Verbindungsstück | PythonPart | Wartung_FFB | Plate | 0121Pyt0000006349 | Verbindungsstück | false | S101 | HI_PRO_STA_0,250x0,500 | 10.675 | 29.85 | 30.35 | 6.926 | 10.425 | 0.025 | 10.55 | 30.1 | 6.901 | 0
Verbindungsstück | Wartung_FFB | S235 | 0 | Verbindungsstück | PythonPart | Wartung_FFB | Plate | 0121Pyt0000006372 | Verbindungsstück | false | S101 | HI_PRO_STA_0,250x0,500 | 10.675 | 29.85 | 30.35 | 6.926 | 10.425 | 0.025 | 10.55 | 30.1 | 6.901 | 0
Verbindungsstück | Wartung_FFB | S235 | 0 | Verbindungsstück | PythonPart | Wartung_FFB | Plate | 0121Pyt0000006418 | Verbindungsstück | false | S101 | HI_PRO_STA_0,250x0,500 | 10.675 | 29.85 | 30.35 | 6.926 | 10.425 | 0.025 | 10.55 | 30.1 | 6.901 | 0
Verbindungsstück | Wartung_FFB | S235 | 0 | Verbindungsstück | PythonPart | Wartung_FFB | Plate | 0121Pyt0000006441 | Verbindungsstück | false | S101 | HI_PRO_STA_0,250x0,500 | 10.675 | 29.85 | 30.35 | 6.926 | 10.425 | 0.025 | 10.55 | 30.1 | 6.901 | 0
Verbindungsstück | Wartung_FFB | S235 | 0 | Verbindungsstück | PythonPart | Wartung_FFB | Plate | 0121Pyt0000006464 | Verbindungsstück | false | S101 | HI_PRO_STA_0,250x0,500 | 10.675 | 29.85 | 30.35 | 6.926 | 10.425 | 0.025 | 10.55 | 30.1 | 6.901 | 0
Verbindungsstück | Wartung_FFB | S235 | 0 | Verbindungsstück | PythonPart | Wartung_FFB | Plate | 0121Pyt0000006487 | Verbindungsstück | false | S101 | HI_PRO_STA_0,250x0,500 | 10.675 | 29.85 | 30.35 | 6.926 | 10.425 | 0.025 | 10.55 | 30.1 | 6.901 | 0
Verbindungsstück | Wartung_FFB | S235 | 0 | Verbindungsstück | PythonPart | Wartung_FFB | Plate | 0121Pyt0000006510 | Verbindungsstück | false | S101 | HI_PRO_STA_0,250x0,500 | 10.675 | 29.85 | 30.35 | 6.926 | 10.425 | 0.025 | 10.55 | 30.1 | 6.901 | 0
Verbindungsstück | Wartung_FFB | S235 | 0 | Verbindungsstück | PythonPart | Wartung_FFB | Plate | 0121Pyt0000006533 | Verbindungsstück | false | S101 | HI_PRO_STA_0,250x0,500 | 10.675 | 29.85 | 30.35 | 6.926 | 10.425 | 0.025 | 10.55 | 30.1 | 6.901 | 0
Verbindungsstück | Wartung_FFB | S235 | 0 | Verbindungsstück | PythonPart | Wartung_FFB | Plate | 0121Pyt0000006556 | Verbindungsstück | false | S101 | HI_PRO_STA_0,250x0,500 | 10.675 | 29.85 | 30.35 | 6.926 | 10.425 | 0.025 | 10.55 | 30.1 | 6.901 | 0
Verbindungsstück | Wartung_FFB | S235 | 0 | Verbindungsstück | PythonPart | Wartung_FFB | Plate | 0121Pyt0000006579 | Verbindungsstück | false | S101 | HI_PRO_STA_0,250x0,500 | 10.675 | 29.85 | 30.35 | 6.926 | 10.425 | 0.025 | 10.55 | 30.1 | 6.901 | 0
Verbindungsstück | Wartung_FFB | S235 | 0 | Verbindungsstück | PythonPart | Wartung_FFB | Plate | 0121Pyt0000006602 | Verbindungsstück | false | S101 | HI_PRO_STA_0,250x0,500 | 10.675 | 29.85 | 30.35 | 6.926 | 10.425 | 0.025 | 10.55 | 30.1 | 6.901 | 0
Verbindungsstück | Wartung_FFB | S235 | 0 | Verbindungsstück | PythonPart | Wartung_FFB | Plate | 0121Pyt0000006394 | Verbindungsstück | false | S101 | HI_PRO_STA_0,300x0,300 | 10.7 | 10.54 | 10.84 | 6.941 | 10.4 | 0.015 | 10.55 | 10.69 | 6.926 | 0
Verbindungsstück | Wartung_FFB | S235 | 0 | Verbindungsstück | PythonPart | Wartung_FFB | Plate | 0121Pyt0000006393 | Verbindungsstück | false | S101 | HI_PRO_STA_0,300x0,300 | 10.7 | 10.54 | 10.84 | 6.941 | 10.4 | 0.015 | 10.55 | 10.69 | 6.926 | 0
Verbindungsstück | Wartung_FFB | S235 | 0 | Verbindungsstück | PythonPart | Wartung_FFB | Plate | 0121Pyt0000006392 | Verbindungsstück | false | S101 | HI_PRO_STA_0,250x0,500 | 10.675 | 10.44 | 10.94 | 6.926 | 10.425 | 0.025 | 10.55 | 10.69 | 6.901 | 0
Verbindungsstück | Wartung_FFB | S235 | 0 | Verbindungsstück | PythonPart | Wartung_FFB | Plate | 0121Pyt0000006395 | Verbindungsstück | false | S101 | HI_PRO_STA_0,250x0,500 | 10.675 | 29.85 | 30.35 | 6.926 | 10.425 | 0.025 | 10.55 | 30.1 | 6.901 | 0
Verbindungsstück | Wartung_FFB | S235 | 0 | Verbindungsstück | PythonPart | Wartung_FFB | Plate | 0121Pyt0000007267 | Verbindungsstück | false | S101 | HI_PRO_STA_0,300x0,300 | 10.7 | 10.54 | 10.84 | 6.941 | 10.4 | 0.015 | 10.55 | 10.69 | 6.926 | 0
Verbindungsstück | Wartung_FFB | S235 | 0 | Verbindungsstück | PythonPart | Wartung_FFB | Plate | 0121Pyt0000007270 | Verbindungsstück | false | S101 | HI_PRO_STA_0,300x0,300 | 10.7 | 10.54 | 10.84 | 6.941 | 10.4 | 0.015 | 10.55 | 10.69 | 6.926 | 0
Verbindungsstück | Wartung_FFB | S235 | 0 | Verbindungsstück | PythonPart | Wartung_FFB | Plate | 0121Pyt0000007275 | Verbindungsstück | false | S101 | HI_PRO_STA_0,300x0,300 | 10.7 | 10.54 | 10.84 | 6.941 | 10.4 | 0.015 | 10.55 | 10.69 | 6.926 | 0
Verbindungsstück | Wartung_FFB | S235 | 0 | Verbindungsstück | PythonPart | Wartung_FFB | Plate | 0121Pyt0000007280 | Verbindungsstück | false | S101 | HI_PRO_STA_0,300x0,300 | 10.7 | 10.54 | 10.84 | 6.941 | 10.4 | 0.015 | 10.55 | 10.69 | 6.926 | 0
Verbindungsstück | Wartung_FFB | S235 | 0 | Verbindungsstück | PythonPart | Wartung_FFB | Plate | 0121Pyt0000007285 | Verbindungsstück | false | S101 | HI_PRO_STA_0,300x0,300 | 10.7 | 10.54 | 10.84 | 6.941 | 10.4 | 0.015 | 10.55 | 10.69 | 6.926 | 0
Verbindungsstück | Wartung_FFB | S235 | 0 | Verbindungsstück | PythonPart | Wartung_FFB | Plate | 0121Pyt0000007295 | Verbindungsstück | false | S101 | HI_PRO_STA_0,300x0,300 | 10.7 | 10.54 | 10.84 | 6.941 | 10.4 | 0.015 | 10.55 | 10.69 | 6.926 | 0
Verbindungsstück | Wartung_FFB | S235 | 0 | Verbindungsstück | PythonPart | Wartung_FFB | Plate | 0121Pyt0000007305 | Verbindungsstück | false | S101 | HI_PRO_STA_0,300x0,300 | 10.7 | 10.54 | 10.84 | 6.941 | 10.4 | 0.015 | 10.55 | 10.69 | 6.926 | 0
Verbindungsstück | Wartung_FFB | S235 | 0 | Verbindungsstück | PythonPart | Wartung_FFB | Plate | 0121Pyt0000007310 | Verbindungsstück | false | S101 | HI_PRO_STA_0,300x0,300 | 10.7 | 10.54 | 10.84 | 6.941 | 10.4 | 0.015 | 10.55 | 10.69 | 6.926 | 0
Verbindungsstück | Wartung_FFB | S235 | 0 | Verbindungsstück | PythonPart | Wartung_FFB | Plate | 0121Pyt0000007315 | Verbindungsstück | false | S101 | HI_PRO_STA_0,300x0,300 | 10.7 | 10.54 | 10.84 | 6.941 | 10.4 | 0.015 | 10.55 | 10.69 | 6.926 | 0
Verbindungsstück | Wartung_FFB | S235 | 0 | Verbindungsstück | PythonPart | Wartung_FFB | Plate | 0121Pyt0000007320 | Verbindungsstück | false | S101 | HI_PRO_STA_0,300x0,300 | 10.7 | 10.54 | 10.84 | 6.941 | 10.4 | 0.015 | 10.55 | 10.69 | 6.926 | 0
Verbindungsstück | Wartung_FFB | S235 | 0 | Verbindungsstück | PythonPart | Wartung_FFB | Plate | 0121Pyt0000007330 | Verbindungsstück | false | S101 | HI_PRO_STA_0,300x0,300 | 10.7 | 10.54 | 10.84 | 6.941 | 10.4 | 0.015 | 10.55 | 10.69 | 6.926 | 0
Verbindungsstück | Wartung_FFB | S235 | 0 | Verbindungsstück | PythonPart | Wartung_FFB | Plate | 0121Pyt0000007335 | Verbindungsstück | false | S101 | HI_PRO_STA_0,300x0,300 | 10.7 | 10.54 | 10.84 | 6.941 | 10.4 | 0.015 | 10.55 | 10.69 | 6.926 | 0
Verbindungsstück | Wartung_FFB | S235 | 0 | Verbindungsstück | PythonPart | Wartung_FFB | Plate | 0121Pyt0000007340 | Verbindungsstück | false | S101 | HI_PRO_STA_0,300x0,300 | 10.7 | 10.54 | 10.84 | 6.941 | 10.4 | 0.015 | 10.55 | 10.69 | 6.926 | 0
Verbindungsstück | Wartung_FFB | S235 | 0 | Verbindungsstück | PythonPart | Wartung_FFB | Plate | 0121Pyt0000007345 | Verbindungsstück | false | S101 | HI_PRO_STA_0,300x0,300 | 10.7 | 10.54 | 10.84 | 6.941 | 10.4 | 0.015 | 10.55 | 10.69 | 6.926 | 0
Verbindungsstück | Wartung_FFB | S235 | 0 | Verbindungsstück | PythonPart | Wartung_FFB | Plate | 0121Pyt0000007350 | Verbindungsstück | false | S101 | HI_PRO_STA_0,300x0,300 | 10.7 | 10.54 | 10.84 | 6.941 | 10.4 | 0.015 | 10.55 | 10.69 | 6.926 | 0
Verbindungsstück | Wartung_FFB | S235 | 0 | Verbindungsstück | PythonPart | Wartung_FFB | Plate | 0121Pyt0000007355 | Verbindungsstück | false | S101 | HI_PRO_STA_0,300x0,300 | 10.7 | 10.54 | 10.84 | 6.941 | 10.4 | 0.015 | 10.55 | 10.69 | 6.926 | 0
Verbindungsstück | Wartung_FFB | S235 | 0 | Verbindungsstück | PythonPart | Wartung_FFB | Plate | 0121Pyt0000007360 | Verbindungsstück | false | S101 | HI_PRO_STA_0,300x0,300 | 10.7 | 10.54 | 10.84 | 6.941 | 10.4 | 0.015 | 10.55 | 10.69 | 6.926 | 0
Verbindungsstück | Wartung_FFB | S235 | 0 | Verbindungsstück | PythonPart | Wartung_FFB | Plate | 0121Pyt0000007268 | Verbindungsstück | false | S101 | HI_PRO_STA_0,250x0,500 | 10.675 | 29.85 | 30.35 | 6.926 | 10.425 | 0.025 | 10.55 | 30.1 | 6.901 | 0
Verbindungsstück | Wartung_FFB | S235 | 0 | Verbindungsstück | PythonPart | Wartung_FFB | Plate | 0121Pyt0000007271 | Verbindungsstück | false | S101 | HI_PRO_STA_0,250x0,500 | 10.675 | 29.85 | 30.35 | 6.926 | 10.425 | 0.025 | 10.55 | 30.1 | 6.901 | 0
Verbindungsstück | Wartung_FFB | S235 | 0 | Verbindungsstück | PythonPart | Wartung_FFB | Plate | 0121Pyt0000007276 | Verbindungsstück | false | S101 | HI_PRO_STA_0,250x0,500 | 10.675 | 29.85 | 30.35 | 6.926 | 10.425 | 0.025 | 10.55 | 30.1 | 6.901 | 0
Verbindungsstück | Wartung_FFB | S235 | 0 | Verbindungsstück | PythonPart | Wartung_FFB | Plate | 0121Pyt0000007281 | Verbindungsstück | false | S101 | HI_PRO_STA_0,250x0,500 | 10.675 | 29.85 | 30.35 | 6.926 | 10.425 | 0.025 | 10.55 | 30.1 | 6.901 | 0
Verbindungsstück | Wartung_FFB | S235 | 0 | Verbindungsstück | PythonPart | Wartung_FFB | Plate | 0121Pyt0000007286 | Verbindungsstück | false | S101 | HI_PRO_STA_0,250x0,500 | 10.675 | 29.85 | 30.35 | 6.926 | 10.425 | 0.025 | 10.55 | 30.1 | 6.901 | 0
Verbindungsstück | Wartung_FFB | S235 | 0 | Verbindungsstück | PythonPart | Wartung_FFB | Plate | 0121Pyt0000007296 | Verbindungsstück | false | S101 | HI_PRO_STA_0,250x0,500 | 10.675 | 29.85 | 30.35 | 6.926 | 10.425 | 0.025 | 10.55 | 30.1 | 6.901 | 0
Verbindungsstück | Wartung_FFB | S235 | 0 | Verbindungsstück | PythonPart | Wartung_FFB | Plate | 0121Pyt0000007306 | Verbindungsstück | false | S101 | HI_PRO_STA_0,250x0,500 | 10.675 | 29.85 | 30.35 | 6.926 | 10.425 | 0.025 | 10.55 | 30.1 | 6.901 | 0
Verbindungsstück | Wartung_FFB | S235 | 0 | Verbindungsstück | PythonPart | Wartung_FFB | Plate | 0121Pyt0000007311 | Verbindungsstück | false | S101 | HI_PRO_STA_0,250x0,500 | 10.675 | 29.85 | 30.35 | 6.926 | 10.425 | 0.025 | 10.55 | 30.1 | 6.901 | 0
Verbindungsstück | Wartung_FFB | S235 | 0 | Verbindungsstück | PythonPart | Wartung_FFB | Plate | 0121Pyt0000007316 | Verbindungsstück | false | S101 | HI_PRO_STA_0,250x0,500 | 10.675 | 29.85 | 30.35 | 6.926 | 10.425 | 0.025 | 10.55 | 30.1 | 6.901 | 0
Verbindungsstück | Wartung_FFB | S235 | 0 | Verbindungsstück | PythonPart | Wartung_FFB | Plate | 0121Pyt0000007321 | Verbindungsstück | false | S101 | HI_PRO_STA_0,250x0,500 | 10.675 | 29.85 | 30.35 | 6.926 | 10.425 | 0.025 | 10.55 | 30.1 | 6.901 | 0
Verbindungsstück | Wartung_FFB | S235 | 0 | Verbindungsstück | PythonPart | Wartung_FFB | Plate | 0121Pyt0000007331 | Verbindungsstück | false | S101 | HI_PRO_STA_0,250x0,500 | 10.675 | 29.85 | 30.35 | 6.926 | 10.425 | 0.025 | 10.55 | 30.1 | 6.901 | 0
Verbindungsstück | Wartung_FFB | S235 | 0 | Verbindungsstück | PythonPart | Wartung_FFB | Plate | 0121Pyt0000007336 | Verbindungsstück | false | S101 | HI_PRO_STA_0,250x0,500 | 10.675 | 29.85 | 30.35 | 6.926 | 10.425 | 0.025 | 10.55 | 30.1 | 6.901 | 0
Verbindungsstück | Wartung_FFB | S235 | 0 | Verbindungsstück | PythonPart | Wartung_FFB | Plate | 0121Pyt0000007341 | Verbindungsstück | false | S101 | HI_PRO_STA_0,250x0,500 | 10.675 | 29.85 | 30.35 | 6.926 | 10.425 | 0.025 | 10.55 | 30.1 | 6.901 | 0
Verbindungsstück | Wartung_FFB | S235 | 0 | Verbindungsstück | PythonPart | Wartung_FFB | Plate | 0121Pyt0000007346 | Verbindungsstück | false | S101 | HI_PRO_STA_0,250x0,500 | 10.675 | 29.85 | 30.35 | 6.926 | 10.425 | 0.025 | 10.55 | 30.1 | 6.901 | 0
Verbindungsstück | Wartung_FFB | S235 | 0 | Verbindungsstück | PythonPart | Wartung_FFB | Plate | 0121Pyt0000007351 | Verbindungsstück | false | S101 | HI_PRO_STA_0,250x0,500 | 10.675 | 29.85 | 30.35 | 6.926 | 10.425 | 0.025 | 10.55 | 30.1 | 6.901 | 0
Verbindungsstück | Wartung_FFB | S235 | 0 | Verbindungsstück | PythonPart | Wartung_FFB | Plate | 0121Pyt0000007356 | Verbindungsstück | false | S101 | HI_PRO_STA_0,250x0,500 | 10.675 | 29.85 | 30.35 | 6.926 | 10.425 | 0.025 | 10.55 | 30.1 | 6.901 | 0
Verbindungsstück | Wartung_FFB | S235 | 0 | Verbindungsstück | PythonPart | Wartung_FFB | Plate | 0121Pyt0000007361 | Verbindungsstück | false | S101 | HI_PRO_STA_0,250x0,500 | 10.675 | 29.85 | 30.35 | 6.926 | 10.425 | 0.025 | 10.55 | 30.1 | 6.901 | 0
Verbindungsstück | Wartung_FFB | S235 | 0 | Verbindungsstück | PythonPart | Wartung_FFB | Plate | 0121Pyt0000008116 | Verbindungsstück | false | S101 | HI_PRO_STA_0,300x0,300 | 10.7 | 10.54 | 10.84 | 6.941 | 10.4 | 0.015 | 10.55 | 10.69 | 6.926 | 0
Verbindungsstück | Wartung_FFB | S235 | 0 | Verbindungsstück | PythonPart | Wartung_FFB | Plate | 0121Pyt0000008117 | Verbindungsstück | false | S101 | HI_PRO_STA_0,300x0,300 | 10.7 | 10.54 | 10.84 | 6.941 | 10.4 | 0.015 | 10.55 | 10.69 | 6.926 | 0
Verbindungsstück | Wartung_FFB | S235 | 0 | Verbindungsstück | PythonPart | Wartung_FFB | Plate | 0121Pyt0000008118 | Verbindungsstück | false | S101 | HI_PRO_STA_0,300x0,300 | 10.7 | 10.54 | 10.84 | 6.941 | 10.4 | 0.015 | 10.55 | 10.69 | 6.926 | 0
Verbindungsstück | Wartung_FFB | S235 | 0 | Verbindungsstück | PythonPart | Wartung_FFB | Plate | 0121Pyt0000008119 | Verbindungsstück | false | S101 | HI_PRO_STA_0,300x0,300 | 10.7 | 10.54 | 10.84 | 6.941 | 10.4 | 0.015 | 10.55 | 10.69 | 6.926 | 0
Verbindungsstück | Wartung_FFB | S235 | 0 | Verbindungsstück | PythonPart | Wartung_FFB | Plate | 0121Pyt0000008120 | Verbindungsstück | false | S101 | HI_PRO_STA_0,300x0,300 | 10.7 | 10.54 | 10.84 | 6.941 | 10.4 | 0.015 | 10.55 | 10.69 | 6.926 | 0
Verbindungsstück | Wartung_FFB | S235 | 0 | Verbindungsstück | PythonPart | Wartung_FFB | Plate | 0121Pyt0000008122 | Verbindungsstück | false | S101 | HI_PRO_STA_0,300x0,300 | 10.7 | 10.54 | 10.84 | 6.941 | 10.4 | 0.015 | 10.55 | 10.69 | 6.926 | 0
Verbindungsstück | Wartung_FFB | S235 | 0 | Verbindungsstück | PythonPart | Wartung_FFB | Plate | 0121Pyt0000008124 | Verbindungsstück | false | S101 | HI_PRO_STA_0,300x0,300 | 10.7 | 10.54 | 10.84 | 6.941 | 10.4 | 0.015 | 10.55 | 10.69 | 6.926 | 0
Verbindungsstück | Wartung_FFB | S235 | 0 | Verbindungsstück | PythonPart | Wartung_FFB | Plate | 0121Pyt0000008125 | Verbindungsstück | false | S101 | HI_PRO_STA_0,300x0,300 | 10.7 | 10.54 | 10.84 | 6.941 | 10.4 | 0.015 | 10.55 | 10.69 | 6.926 | 0
Verbindungsstück | Wartung_FFB | S235 | 0 | Verbindungsstück | PythonPart | Wartung_FFB | Plate | 0121Pyt0000008126 | Verbindungsstück | false | S101 | HI_PRO_STA_0,300x0,300 | 10.7 | 10.54 | 10.84 | 6.941 | 10.4 | 0.015 | 10.55 | 10.69 | 6.926 | 0
Verbindungsstück | Wartung_FFB | S235 | 0 | Verbindungsstück | PythonPart | Wartung_FFB | Plate | 0121Pyt0000008127 | Verbindungsstück | false | S101 | HI_PRO_STA_0,300x0,300 | 10.7 | 10.54 | 10.84 | 6.941 | 10.4 | 0.015 | 10.55 | 10.69 | 6.926 | 0
Verbindungsstück | Wartung_FFB | S235 | 0 | Verbindungsstück | PythonPart | Wartung_FFB | Plate | 0121Pyt0000008129 | Verbindungsstück | false | S101 | HI_PRO_STA_0,300x0,300 | 10.7 | 10.54 | 10.84 | 6.941 | 10.4 | 0.015 | 10.55 | 10.69 | 6.926 | 0
Verbindungsstück | Wartung_FFB | S235 | 0 | Verbindungsstück | PythonPart | Wartung_FFB | Plate | 0121Pyt0000008130 | Verbindungsstück | false | S101 | HI_PRO_STA_0,300x0,300 | 10.7 | 10.54 | 10.84 | 6.941 | 10.4 | 0.015 | 10.55 | 10.69 | 6.926 | 0
Verbindungsstück | Wartung_FFB | S235 | 0 | Verbindungsstück | PythonPart | Wartung_FFB | Plate | 0121Pyt0000008131 | Verbindungsstück | false | S101 | HI_PRO_STA_0,300x0,300 | 10.7 | 10.54 | 10.84 | 6.941 | 10.4 | 0.015 | 10.55 | 10.69 | 6.926 | 0
Verbindungsstück | Wartung_FFB | S235 | 0 | Verbindungsstück | PythonPart | Wartung_FFB | Plate | 0121Pyt0000008132 | Verbindungsstück | false | S101 | HI_PRO_STA_0,300x0,300 | 10.7 | 10.54 | 10.84 | 6.941 | 10.4 | 0.015 | 10.55 | 10.69 | 6.926 | 0
Verbindungsstück | Wartung_FFB | S235 | 0 | Verbindungsstück | PythonPart | Wartung_FFB | Plate | 0121Pyt0000008133 | Verbindungsstück | false | S101 | HI_PRO_STA_0,300x0,300 | 10.7 | 10.54 | 10.84 | 6.941 | 10.4 | 0.015 | 10.55 | 10.69 | 6.926 | 0
Verbindungsstück | Wartung_FFB | S235 | 0 | Verbindungsstück | PythonPart | Wartung_FFB | Plate | 0121Pyt0000008134 | Verbindungsstück | false | S101 | HI_PRO_STA_0,300x0,300 | 10.7 | 10.54 | 10.84 | 6.941 | 10.4 | 0.015 | 10.55 | 10.69 | 6.926 | 0
Verbindungsstück | Wartung_FFB | S235 | 0 | Verbindungsstück | PythonPart | Wartung_FFB | Plate | 0121Pyt0000008135 | Verbindungsstück | false | S101 | HI_PRO_STA_0,300x0,300 | 10.7 | 10.54 | 10.84 | 6.941 | 10.4 | 0.015 | 10.55 | 10.69 | 6.926 | 0
Verbindungsstück | Wartung_FFB | S235 | 0 | Verbindungsstück | PythonPart | Wartung_FFB | Plate | 0121Pyt0000008136 | Verbindungsstück | false | S101 | HI_PRO_STA_0,300x0,300 | 10.7 | 10.54 | 10.84 | 6.941 | 10.4 | 0.015 | 10.55 | 10.69 | 6.926 | 0
Verbindungsstück | Wartung_FFB | S235 | 0 | Verbindungsstück | PythonPart | Wartung_FFB | Plate | 0121Pyt0000008137 | Verbindungsstück | false | S101 | HI_PRO_STA_0,300x0,300 | 10.7 | 10.54 | 10.84 | 6.941 | 10.4 | 0.015 | 10.55 | 10.69 | 6.926 | 0
Verbindungsstück | Wartung_FFB | S235 | 0 | Verbindungsstück | PythonPart | Wartung_FFB | Plate | 0121Pyt0000008138 | Verbindungsstück | false | S101 | HI_PRO_STA_0,300x0,300 | 10.7 | 10.54 | 10.84 | 6.941 | 10.4 | 0.015 | 10.55 | 10.69 | 6.926 | 0
Verbindungsstück | Wartung_FFB | S235 | 0 | Verbindungsstück | PythonPart | Wartung_FFB | Plate | 0121Pyt0000008139 | Verbindungsstück | false | S101 | HI_PRO_STA_0,300x0,300 | 10.7 | 10.54 | 10.84 | 6.941 | 10.4 | 0.015 | 10.55 | 10.69 | 6.926 | 0
Verbindungsstück | Wartung_FFB | S235 | 0 | Verbindungsstück | PythonPart | Wartung_FFB | Plate | 0121Pyt0000008145 | Verbindungsstück | false | S101 | HI_PRO_STA_0,300x0,300 | 10.7 | 10.54 | 10.84 | 6.941 | 10.4 | 0.015 | 10.55 | 10.69 | 6.926 | 0
Verbindungsstück | Wartung_FFB | S235 | 0 | Verbindungsstück | PythonPart | Wartung_FFB | Plate | 0121Pyt0000008147 | Verbindungsstück | false | S101 | HI_PRO_STA_0,300x0,300 | 10.7 | 10.54 | 10.84 | 6.941 | 10.4 | 0.015 | 10.55 | 10.69 | 6.926 | 0
Verbindungsstück | Wartung_FFB | S235 | 0 | Verbindungsstück | PythonPart | Wartung_FFB | Plate | 0121Pyt0000008148 | Verbindungsstück | false | S101 | HI_PRO_STA_0,300x0,300 | 10.7 | 10.54 | 10.84 | 6.941 | 10.4 | 0.015 | 10.55 | 10.69 | 6.926 | 0
Verbindungsstück | Wartung_FFB | S235 | 0 | Verbindungsstück | PythonPart | Wartung_FFB | Plate | 0121Pyt0000008149 | Verbindungsstück | false | S101 | HI_PRO_STA_0,300x0,300 | 10.7 | 10.54 | 10.84 | 6.941 | 10.4 | 0.015 | 10.55 | 10.69 | 6.926 | 0
Verbindungsstück | Wartung_FFB | S235 | 0 | Verbindungsstück | PythonPart | Wartung_FFB | Plate | 0121Pyt0000008150 | Verbindungsstück | false | S101 | HI_PRO_STA_0,300x0,300 | 10.7 | 10.54 | 10.84 | 6.941 | 10.4 | 0.015 | 10.55 | 10.69 | 6.926 | 0
Verbindungsstück | Wartung_FFB | S235 | 0 | Verbindungsstück | PythonPart | Wartung_FFB | Plate | 0121Pyt0000008151 | Verbindungsstück | false | S101 | HI_PRO_STA_0,300x0,300 | 10.7 | 10.54 | 10.84 | 6.941 | 10.4 | 0.015 | 10.55 | 10.69 | 6.926 | 0
Verbindungsstück | Wartung_FFB | S235 | 0 | Verbindungsstück | PythonPart | Wartung_FFB | Plate | 0121Pyt0000008152 | Verbindungsstück | false | S101 | HI_PRO_STA_0,300x0,300 | 10.7 | 10.54 | 10.84 | 6.941 | 10.4 | 0.015 | 10.55 | 10.69 | 6.926 | 0
Verbindungsstück | Wartung_FFB | S235 | 0 | Verbindungsstück | PythonPart | Wartung_FFB | Plate | 0121Pyt0000007455 | Verbindungsstück | false | S101 | HI_PRO_STA_0,300x0,300 | 10.7 | 10.54 | 10.84 | 6.941 | 10.4 | 0.015 | 10.55 | 10.69 | 6.926 | 0
Verbindungsstück | Wartung_FFB | S235 | 0 | Verbindungsstück | PythonPart | Wartung_FFB | Plate | 0121Pyt0000007458 | Verbindungsstück | false | S101 | HI_PRO_STA_0,300x0,300 | 10.7 | 10.54 | 10.84 | 6.941 | 10.4 | 0.015 | 10.55 | 10.69 | 6.926 | 0
Verbindungsstück | Wartung_FFB | S235 | 0 | Verbindungsstück | PythonPart | Wartung_FFB | Plate | 0121Pyt0000007461 | Verbindungsstück | false | S101 | HI_PRO_STA_0,300x0,300 | 10.7 | 10.54 | 10.84 | 6.941 | 10.4 | 0.015 | 10.55 | 10.69 | 6.926 | 0
Verbindungsstück | Wartung_FFB | S235 | 0 | Verbindungsstück | PythonPart | Wartung_FFB | Plate | 0121Pyt0000007464 | Verbindungsstück | false | S101 | HI_PRO_STA_0,300x0,300 | 10.7 | 10.54 | 10.84 | 6.941 | 10.4 | 0.015 | 10.55 | 10.69 | 6.926 | 0
Verbindungsstück | Wartung_FFB | S235 | 0 | Verbindungsstück | PythonPart | Wartung_FFB | Plate | 0121Pyt0000007467 | Verbindungsstück | false | S101 | HI_PRO_STA_0,300x0,300 | 10.7 | 10.54 | 10.84 | 6.941 | 10.4 | 0.015 | 10.55 | 10.69 | 6.926 | 0
Verbindungsstück | Wartung_FFB | S235 | 0 | Verbindungsstück | PythonPart | Wartung_FFB | Plate | 0121Pyt0000007473 | Verbindungsstück | false | S101 | HI_PRO_STA_0,300x0,300 | 10.7 | 10.54 | 10.84 | 6.941 | 10.4 | 0.015 | 10.55 | 10.69 | 6.926 | 0
Verbindungsstück | Wartung_FFB | S235 | 0 | Verbindungsstück | PythonPart | Wartung_FFB | Plate | 0121Pyt0000007479 | Verbindungsstück | false | S101 | HI_PRO_STA_0,300x0,300 | 10.7 | 10.54 | 10.84 | 6.941 | 10.4 | 0.015 | 10.55 | 10.69 | 6.926 | 0
Verbindungsstück | Wartung_FFB | S235 | 0 | Verbindungsstück | PythonPart | Wartung_FFB | Plate | 0121Pyt0000007482 | Verbindungsstück | false | S101 | HI_PRO_STA_0,300x0,300 | 10.7 | 10.54 | 10.84 | 6.941 | 10.4 | 0.015 | 10.55 | 10.69 | 6.926 | 0
Verbindungsstück | Wartung_FFB | S235 | 0 | Verbindungsstück | PythonPart | Wartung_FFB | Plate | 0121Pyt0000007485 | Verbindungsstück | false | S101 | HI_PRO_STA_0,300x0,300 | 10.7 | 10.54 | 10.84 | 6.941 | 10.4 | 0.015 | 10.55 | 10.69 | 6.926 | 0
Verbindungsstück | Wartung_FFB | S235 | 0 | Verbindungsstück | PythonPart | Wartung_FFB | Plate | 0121Pyt0000007488 | Verbindungsstück | false | S101 | HI_PRO_STA_0,300x0,300 | 10.7 | 10.54 | 10.84 | 6.941 | 10.4 | 0.015 | 10.55 | 10.69 | 6.926 | 0
Verbindungsstück | Wartung_FFB | S235 | 0 | Verbindungsstück | PythonPart | Wartung_FFB | Plate | 0121Pyt0000007494 | Verbindungsstück | false | S101 | HI_PRO_STA_0,300x0,300 | 10.7 | 10.54 | 10.84 | 6.941 | 10.4 | 0.015 | 10.55 | 10.69 | 6.926 | 0
Verbindungsstück | Wartung_FFB | S235 | 0 | Verbindungsstück | PythonPart | Wartung_FFB | Plate | 0121Pyt0000007497 | Verbindungsstück | false | S101 | HI_PRO_STA_0,300x0,300 | 10.7 | 10.54 | 10.84 | 6.941 | 10.4 | 0.015 | 10.55 | 10.69 | 6.926 | 0
Verbindungsstück | Wartung_FFB | S235 | 0 | Verbindungsstück | PythonPart | Wartung_FFB | Plate | 0121Pyt0000007500 | Verbindungsstück | false | S101 | HI_PRO_STA_0,300x0,300 | 10.7 | 10.54 | 10.84 | 6.941 | 10.4 | 0.015 | 10.55 | 10.69 | 6.926 | 0
Verbindungsstück | Wartung_FFB | S235 | 0 | Verbindungsstück | PythonPart | Wartung_FFB | Plate | 0121Pyt0000007503 | Verbindungsstück | false | S101 | HI_PRO_STA_0,300x0,300 | 10.7 | 10.54 | 10.84 | 6.941 | 10.4 | 0.015 | 10.55 | 10.69 | 6.926 | 0
Verbindungsstück | Wartung_FFB | S235 | 0 | Verbindungsstück | PythonPart | Wartung_FFB | Plate | 0121Pyt0000007506 | Verbindungsstück | false | S101 | HI_PRO_STA_0,300x0,300 | 10.7 | 10.54 | 10.84 | 6.941 | 10.4 | 0.015 | 10.55 | 10.69 | 6.926 | 0
Verbindungsstück | Wartung_FFB | S235 | 0 | Verbindungsstück | PythonPart | Wartung_FFB | Plate | 0121Pyt0000007509 | Verbindungsstück | false | S101 | HI_PRO_STA_0,300x0,300 | 10.7 | 10.54 | 10.84 | 6.941 | 10.4 | 0.015 | 10.55 | 10.69 | 6.926 | 0
Verbindungsstück | Wartung_FFB | S235 | 0 | Verbindungsstück | PythonPart | Wartung_FFB | Plate | 0121Pyt0000007512 | Verbindungsstück | false | S101 | HI_PRO_STA_0,300x0,300 | 10.7 | 10.54 | 10.84 | 6.941 | 10.4 | 0.015 | 10.55 | 10.69 | 6.926 | 0
Verbindungsstück | Wartung_FFB | S235 | 0 | Verbindungsstück | PythonPart | Wartung_FFB | Plate | 0121Pyt0000007456 | Verbindungsstück | false | S101 | HI_PRO_STA_0,250x0,500 | 10.675 | 29.85 | 30.35 | 6.926 | 10.425 | 0.025 | 10.55 | 30.1 | 6.901 | 0
Verbindungsstück | Wartung_FFB | S235 | 0 | Verbindungsstück | PythonPart | Wartung_FFB | Plate | 0121Pyt0000007459 | Verbindungsstück | false | S101 | HI_PRO_STA_0,250x0,500 | 10.675 | 29.85 | 30.35 | 6.926 | 10.425 | 0.025 | 10.55 | 30.1 | 6.901 | 0
Verbindungsstück | Wartung_FFB | S235 | 0 | Verbindungsstück | PythonPart | Wartung_FFB | Plate | 0121Pyt0000007462 | Verbindungsstück | false | S101 | HI_PRO_STA_0,250x0,500 | 10.675 | 29.85 | 30.35 | 6.926 | 10.425 | 0.025 | 10.55 | 30.1 | 6.901 | 0
Verbindungsstück | Wartung_FFB | S235 | 0 | Verbindungsstück | PythonPart | Wartung_FFB | Plate | 0121Pyt0000007465 | Verbindungsstück | false | S101 | HI_PRO_STA_0,250x0,500 | 10.675 | 29.85 | 30.35 | 6.926 | 10.425 | 0.025 | 10.55 | 30.1 | 6.901 | 0
Verbindungsstück | Wartung_FFB | S235 | 0 | Verbindungsstück | PythonPart | Wartung_FFB | Plate | 0121Pyt0000007468 | Verbindungsstück | false | S101 | HI_PRO_STA_0,250x0,500 | 10.675 | 29.85 | 30.35 | 6.926 | 10.425 | 0.025 | 10.55 | 30.1 | 6.901 | 0
Verbindungsstück | Wartung_FFB | S235 | 0 | Verbindungsstück | PythonPart | Wartung_FFB | Plate | 0121Pyt0000007474 | Verbindungsstück | false | S101 | HI_PRO_STA_0,250x0,500 | 10.675 | 29.85 | 30.35 | 6.926 | 10.425 | 0.025 | 10.55 | 30.1 | 6.901 | 0
Verbindungsstück | Wartung_FFB | S235 | 0 | Verbindungsstück | PythonPart | Wartung_FFB | Plate | 0121Pyt0000007480 | Verbindungsstück | false | S101 | HI_PRO_STA_0,250x0,500 | 10.675 | 29.85 | 30.35 | 6.926 | 10.425 | 0.025 | 10.55 | 30.1 | 6.901 | 0
Verbindungsstück | Wartung_FFB | S235 | 0 | Verbindungsstück | PythonPart | Wartung_FFB | Plate | 0121Pyt0000007483 | Verbindungsstück | false | S101 | HI_PRO_STA_0,250x0,500 | 10.675 | 29.85 | 30.35 | 6.926 | 10.425 | 0.025 | 10.55 | 30.1 | 6.901 | 0
Verbindungsstück | Wartung_FFB | S235 | 0 | Verbindungsstück | PythonPart | Wartung_FFB | Plate | 0121Pyt0000007486 | Verbindungsstück | false | S101 | HI_PRO_STA_0,250x0,500 | 10.675 | 29.85 | 30.35 | 6.926 | 10.425 | 0.025 | 10.55 | 30.1 | 6.901 | 0
Verbindungsstück | Wartung_FFB | S235 | 0 | Verbindungsstück | PythonPart | Wartung_FFB | Plate | 0121Pyt0000007489 | Verbindungsstück | false | S101 | HI_PRO_STA_0,250x0,500 | 10.675 | 29.85 | 30.35 | 6.926 | 10.425 | 0.025 | 10.55 | 30.1 | 6.901 | 0
Verbindungsstück | Wartung_FFB | S235 | 0 | Verbindungsstück | PythonPart | Wartung_FFB | Plate | 0121Pyt0000007495 | Verbindungsstück | false | S101 | HI_PRO_STA_0,250x0,500 | 10.675 | 29.85 | 30.35 | 6.926 | 10.425 | 0.025 | 10.55 | 30.1 | 6.901 | 0
Verbindungsstück | Wartung_FFB | S235 | 0 | Verbindungsstück | PythonPart | Wartung_FFB | Plate | 0121Pyt0000007498 | Verbindungsstück | false | S101 | HI_PRO_STA_0,250x0,500 | 10.675 | 29.85 | 30.35 | 6.926 | 10.425 | 0.025 | 10.55 | 30.1 | 6.901 | 0
Verbindungsstück | Wartung_FFB | S235 | 0 | Verbindungsstück | PythonPart | Wartung_FFB | Plate | 0121Pyt0000007501 | Verbindungsstück | false | S101 | HI_PRO_STA_0,250x0,500 | 10.675 | 29.85 | 30.35 | 6.926 | 10.425 | 0.025 | 10.55 | 30.1 | 6.901 | 0
Verbindungsstück | Wartung_FFB | S235 | 0 | Verbindungsstück | PythonPart | Wartung_FFB | Plate | 0121Pyt0000007504 | Verbindungsstück | false | S101 | HI_PRO_STA_0,250x0,500 | 10.675 | 29.85 | 30.35 | 6.926 | 10.425 | 0.025 | 10.55 | 30.1 | 6.901 | 0
Verbindungsstück | Wartung_FFB | S235 | 0 | Verbindungsstück | PythonPart | Wartung_FFB | Plate | 0121Pyt0000007507 | Verbindungsstück | false | S101 | HI_PRO_STA_0,250x0,500 | 10.675 | 29.85 | 30.35 | 6.926 | 10.425 | 0.025 | 10.55 | 30.1 | 6.901 | 0
Verbindungsstück | Wartung_FFB | S235 | 0 | Verbindungsstück | PythonPart | Wartung_FFB | Plate | 0121Pyt0000007510 | Verbindungsstück | false | S101 | HI_PRO_STA_0,250x0,500 | 10.675 | 29.85 | 30.35 | 6.926 | 10.425 | 0.025 | 10.55 | 30.1 | 6.901 | 0
Verbindungsstück | Wartung_FFB | S235 | 0 | Verbindungsstück | PythonPart | Wartung_FFB | Plate | 0121Pyt0000007513 | Verbindungsstück | false | S101 | HI_PRO_STA_0,250x0,500 | 10.675 | 29.85 | 30.35 | 6.926 | 10.425 | 0.025 | 10.55 | 30.1 | 6.901 | 0
Verbindungsstück | Wartung_FFB | S235 | 0 | Verbindungsstück | PythonPart | Wartung_FFB | Plate | 0121Pyt0000007960 | Verbindungsstück | false | S101 | HI_PRO_STA_0,250x0,500 | 10.675 | 29.85 | 30.35 | 6.926 | 10.425 | 0.025 | 10.55 | 30.1 | 6.901 | 0
Verbindungsstück | Wartung_FFB | S235 | 0 | Verbindungsstück | PythonPart | Wartung_FFB | Plate | 0121Pyt0000007961 | Verbindungsstück | false | S101 | HI_PRO_STA_0,250x0,500 | 10.675 | 29.85 | 30.35 | 6.926 | 10.425 | 0.025 | 10.55 | 30.1 | 6.901 | 0
Verbindungsstück | Wartung_FFB | S235 | 0 | Verbindungsstück | PythonPart | Wartung_FFB | Plate | 0121Pyt0000007962 | Verbindungsstück | false | S101 | HI_PRO_STA_0,250x0,500 | 10.675 | 29.85 | 30.35 | 6.926 | 10.425 | 0.025 | 10.55 | 30.1 | 6.901 | 0
Verbindungsstück | Wartung_FFB | S235 | 0 | Verbindungsstück | PythonPart | Wartung_FFB | Plate | 0121Pyt0000007963 | Verbindungsstück | false | S101 | HI_PRO_STA_0,250x0,500 | 10.675 | 29.85 | 30.35 | 6.926 | 10.425 | 0.025 | 10.55 | 30.1 | 6.901 | 0
Verbindungsstück | Wartung_FFB | S235 | 0 | Verbindungsstück | PythonPart | Wartung_FFB | Plate | 0121Pyt0000007964 | Verbindungsstück | false | S101 | HI_PRO_STA_0,250x0,500 | 10.675 | 29.85 | 30.35 | 6.926 | 10.425 | 0.025 | 10.55 | 30.1 | 6.901 | 0
Verbindungsstück | Wartung_FFB | S235 | 0 | Verbindungsstück | PythonPart | Wartung_FFB | Plate | 0121Pyt0000007966 | Verbindungsstück | false | S101 | HI_PRO_STA_0,250x0,500 | 10.675 | 29.85 | 30.35 | 6.926 | 10.425 | 0.025 | 10.55 | 30.1 | 6.901 | 0
Verbindungsstück | Wartung_FFB | S235 | 0 | Verbindungsstück | PythonPart | Wartung_FFB | Plate | 0121Pyt0000007968 | Verbindungsstück | false | S101 | HI_PRO_STA_0,250x0,500 | 10.675 | 29.85 | 30.35 | 6.926 | 10.425 | 0.025 | 10.55 | 30.1 | 6.901 | 0
Verbindungsstück | Wartung_FFB | S235 | 0 | Verbindungsstück | PythonPart | Wartung_FFB | Plate | 0121Pyt0000007969 | Verbindungsstück | false | S101 | HI_PRO_STA_0,250x0,500 | 10.675 | 29.85 | 30.35 | 6.926 | 10.425 | 0.025 | 10.55 | 30.1 | 6.901 | 0
Verbindungsstück | Wartung_FFB | S235 | 0 | Verbindungsstück | PythonPart | Wartung_FFB | Plate | 0121Pyt0000007970 | Verbindungsstück | false | S101 | HI_PRO_STA_0,250x0,500 | 10.675 | 29.85 | 30.35 | 6.926 | 10.425 | 0.025 | 10.55 | 30.1 | 6.901 | 0
Verbindungsstück | Wartung_FFB | S235 | 0 | Verbindungsstück | PythonPart | Wartung_FFB | Plate | 0121Pyt0000007971 | Verbindungsstück | false | S101 | HI_PRO_STA_0,250x0,500 | 10.675 | 29.85 | 30.35 | 6.926 | 10.425 | 0.025 | 10.55 | 30.1 | 6.901 | 0
Verbindungsstück | Wartung_FFB | S235 | 0 | Verbindungsstück | PythonPart | Wartung_FFB | Plate | 0121Pyt0000007973 | Verbindungsstück | false | S101 | HI_PRO_STA_0,250x0,500 | 10.675 | 29.85 | 30.35 | 6.926 | 10.425 | 0.025 | 10.55 | 30.1 | 6.901 | 0
Verbindungsstück | Wartung_FFB | S235 | 0 | Verbindungsstück | PythonPart | Wartung_FFB | Plate | 0121Pyt0000007974 | Verbindungsstück | false | S101 | HI_PRO_STA_0,250x0,500 | 10.675 | 29.85 | 30.35 | 6.926 | 10.425 | 0.025 | 10.55 | 30.1 | 6.901 | 0
Verbindungsstück | Wartung_FFB | S235 | 0 | Verbindungsstück | PythonPart | Wartung_FFB | Plate | 0121Pyt0000007975 | Verbindungsstück | false | S101 | HI_PRO_STA_0,250x0,500 | 10.675 | 29.85 | 30.35 | 6.926 | 10.425 | 0.025 | 10.55 | 30.1 | 6.901 | 0
Verbindungsstück | Wartung_FFB | S235 | 0 | Verbindungsstück | PythonPart | Wartung_FFB | Plate | 0121Pyt0000007976 | Verbindungsstück | false | S101 | HI_PRO_STA_0,250x0,500 | 10.675 | 29.85 | 30.35 | 6.926 | 10.425 | 0.025 | 10.55 | 30.1 | 6.901 | 0
Verbindungsstück | Wartung_FFB | S235 | 0 | Verbindungsstück | PythonPart | Wartung_FFB | Plate | 0121Pyt0000007977 | Verbindungsstück | false | S101 | HI_PRO_STA_0,250x0,500 | 10.675 | 29.85 | 30.35 | 6.926 | 10.425 | 0.025 | 10.55 | 30.1 | 6.901 | 0
Verbindungsstück | Wartung_FFB | S235 | 0 | Verbindungsstück | PythonPart | Wartung_FFB | Plate | 0121Pyt0000007978 | Verbindungsstück | false | S101 | HI_PRO_STA_0,250x0,500 | 10.675 | 29.85 | 30.35 | 6.926 | 10.425 | 0.025 | 10.55 | 30.1 | 6.901 | 0
Verbindungsstück | Wartung_FFB | S235 | 0 | Verbindungsstück | PythonPart | Wartung_FFB | Plate | 0121Pyt0000007979 | Verbindungsstück | false | S101 | HI_PRO_STA_0,250x0,500 | 10.675 | 29.85 | 30.35 | 6.926 | 10.425 | 0.025 | 10.55 | 30.1 | 6.901 | 0
Verbindungsstück | Wartung_FFB | S235 | 0 | Verbindungsstück | PythonPart | Wartung_FFB | Plate | 0121Pyt0000007980 | Verbindungsstück | false | S101 | HI_PRO_STA_0,250x0,500 | 10.675 | 29.85 | 30.35 | 6.926 | 10.425 | 0.025 | 10.55 | 30.1 | 6.901 | 0
Verbindungsstück | Wartung_FFB | S235 | 0 | Verbindungsstück | PythonPart | Wartung_FFB | Plate | 0121Pyt0000007981 | Verbindungsstück | false | S101 | HI_PRO_STA_0,250x0,500 | 10.675 | 29.85 | 30.35 | 6.926 | 10.425 | 0.025 | 10.55 | 30.1 | 6.901 | 0
Verbindungsstück | Wartung_FFB | S235 | 0 | Verbindungsstück | PythonPart | Wartung_FFB | Plate | 0121Pyt0000007982 | Verbindungsstück | false | S101 | HI_PRO_STA_0,250x0,500 | 10.675 | 29.85 | 30.35 | 6.926 | 10.425 | 0.025 | 10.55 | 30.1 | 6.901 | 0
Verbindungsstück | Wartung_FFB | S235 | 0 | Verbindungsstück | PythonPart | Wartung_FFB | Plate | 0121Pyt0000007983 | Verbindungsstück | false | S101 | HI_PRO_STA_0,250x0,500 | 10.675 | 29.85 | 30.35 | 6.926 | 10.425 | 0.025 | 10.55 | 30.1 | 6.901 | 0
Verbindungsstück | Wartung_FFB | S235 | 0 | Verbindungsstück | PythonPart | Wartung_FFB | Plate | 0121Pyt0000007990 | Verbindungsstück | false | S101 | HI_PRO_STA_0,250x0,500 | 10.675 | 29.85 | 30.35 | 6.926 | 10.425 | 0.025 | 10.55 | 30.1 | 6.901 | 0
Verbindungsstück | Wartung_FFB | S235 | 0 | Verbindungsstück | PythonPart | Wartung_FFB | Plate | 0121Pyt0000007992 | Verbindungsstück | false | S101 | HI_PRO_STA_0,250x0,500 | 10.675 | 29.85 | 30.35 | 6.926 | 10.425 | 0.025 | 10.55 | 30.1 | 6.901 | 0
Verbindungsstück | Wartung_FFB | S235 | 0 | Verbindungsstück | PythonPart | Wartung_FFB | Plate | 0121Pyt0000007993 | Verbindungsstück | false | S101 | HI_PRO_STA_0,250x0,500 | 10.675 | 29.85 | 30.35 | 6.926 | 10.425 | 0.025 | 10.55 | 30.1 | 6.901 | 0
Verbindungsstück | Wartung_FFB | S235 | 0 | Verbindungsstück | PythonPart | Wartung_FFB | Plate | 0121Pyt0000007994 | Verbindungsstück | false | S101 | HI_PRO_STA_0,250x0,500 | 10.675 | 29.85 | 30.35 | 6.926 | 10.425 | 0.025 | 10.55 | 30.1 | 6.901 | 0
Verbindungsstück | Wartung_FFB | S235 | 0 | Verbindungsstück | PythonPart | Wartung_FFB | Plate | 0121Pyt0000007995 | Verbindungsstück | false | S101 | HI_PRO_STA_0,250x0,500 | 10.675 | 29.85 | 30.35 | 6.926 | 10.425 | 0.025 | 10.55 | 30.1 | 6.901 | 0
Verbindungsstück | Wartung_FFB | S235 | 0 | Verbindungsstück | PythonPart | Wartung_FFB | Plate | 0121Pyt0000007996 | Verbindungsstück | false | S101 | HI_PRO_STA_0,250x0,500 | 10.675 | 29.85 | 30.35 | 6.926 | 10.425 | 0.025 | 10.55 | 30.1 | 6.901 | 0
Verbindungsstück | Wartung_FFB | S235 | 0 | Verbindungsstück | PythonPart | Wartung_FFB | Plate | 0121Pyt0000007997 | Verbindungsstück | false | S101 | HI_PRO_STA_0,250x0,500 | 10.675 | 29.85 | 30.35 | 6.926 | 10.425 | 0.025 | 10.55 | 30.1 | 6.901 | 0
Verbindungsstück | Wartung_FFB | S235 | 0 | Verbindungsstück | PythonPart | Wartung_FFB | Plate | 0121Pyt0000013939 | Verbindungsstück | false | S101 | HI_PRO_STA_0,300x0,300 | 10.7 | 10.54 | 10.84 | 6.941 | 10.4 | 0.015 | 10.55 | 10.69 | 6.926 | 0
Verbindungsstück | Wartung_FFB | S235 | 0 | Verbindungsstück | PythonPart | Wartung_FFB | Plate | 0121Pyt0000013941 | Verbindungsstück | false | S101 | HI_PRO_STA_0,250x0,500 | 10.675 | 29.85 | 30.35 | 6.926 | 10.425 | 0.025 | 10.55 | 30.1 | 6.901 | 0
Verbindungsstück | Wartung_FFB | S235 | 0 | Verbindungsstück | PythonPart | Wartung_FFB | Plate | 0121Pyt0000013942 | Verbindungsstück | false | S101 | HI_PRO_STA_0,300x0,300 | 10.7 | 10.54 | 10.84 | 6.941 | 10.4 | 0.015 | 10.55 | 10.69 | 6.926 | 0
Verbindungsstück | Wartung_FFB | S235 | 0 | Verbindungsstück | PythonPart | Wartung_FFB | Plate | 0121Pyt0000013943 | Verbindungsstück | false | S101 | HI_PRO_STA_0,250x0,500 | 10.675 | 29.85 | 30.35 | 6.926 | 10.425 | 0.025 | 10.55 | 30.1 | 6.901 | 0
Verbindungsstück | Wartung_FFB | S235 | 0 | Verbindungsstück | PythonPart | Wartung_FFB | Plate | 0121Pyt0000008154 | Verbindungsstück | false | S101 | HI_PRO_STA_0,300x0,300 | 10.7 | 10.54 | 10.84 | 6.941 | 10.4 | 0.015 | 10.55 | 10.69 | 6.926 | 0
Verbindungsstück | Wartung_FFB | S235 | 0 | Verbindungsstück | PythonPart | Wartung_FFB | Plate | 0121Pyt0000008155 | Verbindungsstück | false | S101 | HI_PRO_STA_0,300x0,300 | 10.7 | 10.54 | 10.84 | 6.941 | 10.4 | 0.015 | 10.55 | 10.69 | 6.926 | 0
Verbindungsstück | Wartung_FFB | S235 | 0 | Verbindungsstück | PythonPart | Wartung_FFB | Plate | 0121Pyt0000008156 | Verbindungsstück | false | S101 | HI_PRO_STA_0,300x0,300 | 10.7 | 10.54 | 10.84 | 6.941 | 10.4 | 0.015 | 10.55 | 10.69 | 6.926 | 0
Verbindungsstück | Wartung_FFB | S235 | 0 | Verbindungsstück | PythonPart | Wartung_FFB | Plate | 0121Pyt0000008158 | Verbindungsstück | false | S101 | HI_PRO_STA_0,300x0,300 | 10.7 | 10.54 | 10.84 | 6.941 | 10.4 | 0.015 | 10.55 | 10.69 | 6.926 | 0
Verbindungsstück | Wartung_FFB | S235 | 0 | Verbindungsstück | PythonPart | Wartung_FFB | Plate | 0121Pyt0000008160 | Verbindungsstück | false | S101 | HI_PRO_STA_0,300x0,300 | 10.7 | 10.54 | 10.84 | 6.941 | 10.4 | 0.015 | 10.55 | 10.69 | 6.926 | 0
Verbindungsstück | Wartung_FFB | S235 | 0 | Verbindungsstück | PythonPart | Wartung_FFB | Plate | 0121Pyt0000008162 | Verbindungsstück | false | S101 | HI_PRO_STA_0,300x0,300 | 10.7 | 10.54 | 10.84 | 6.941 | 10.4 | 0.015 | 10.55 | 10.69 | 6.926 | 0
Verbindungsstück | Wartung_FFB | S235 | 0 | Verbindungsstück | PythonPart | Wartung_FFB | Plate | 0121Pyt0000008163 | Verbindungsstück | false | S101 | HI_PRO_STA_0,300x0,300 | 10.7 | 10.54 | 10.84 | 6.941 | 10.4 | 0.015 | 10.55 | 10.69 | 6.926 | 0
Verbindungsstück | Wartung_FFB | S235 | 0 | Verbindungsstück | PythonPart | Wartung_FFB | Plate | 0121Pyt0000008164 | Verbindungsstück | false | S101 | HI_PRO_STA_0,300x0,300 | 10.7 | 10.54 | 10.84 | 6.941 | 10.4 | 0.015 | 10.55 | 10.69 | 6.926 | 0
Verbindungsstück | Wartung_FFB | S235 | 0 | Verbindungsstück | PythonPart | Wartung_FFB | Plate | 0121Pyt0000008165 | Verbindungsstück | false | S101 | HI_PRO_STA_0,300x0,300 | 10.7 | 10.54 | 10.84 | 6.941 | 10.4 | 0.015 | 10.55 | 10.69 | 6.926 | 0
Verbindungsstück | Wartung_FFB | S235 | 0 | Verbindungsstück | PythonPart | Wartung_FFB | Plate | 0121Pyt0000008167 | Verbindungsstück | false | S101 | HI_PRO_STA_0,300x0,300 | 10.7 | 10.54 | 10.84 | 6.941 | 10.4 | 0.015 | 10.55 | 10.69 | 6.926 | 0
Verbindungsstück | Wartung_FFB | S235 | 0 | Verbindungsstück | PythonPart | Wartung_FFB | Plate | 0121Pyt0000008168 | Verbindungsstück | false | S101 | HI_PRO_STA_0,300x0,300 | 10.7 | 10.54 | 10.84 | 6.941 | 10.4 | 0.015 | 10.55 | 10.69 | 6.926 | 0
Verbindungsstück | Wartung_FFB | S235 | 0 | Verbindungsstück | PythonPart | Wartung_FFB | Plate | 0121Pyt0000008169 | Verbindungsstück | false | S101 | HI_PRO_STA_0,300x0,300 | 10.7 | 10.54 | 10.84 | 6.941 | 10.4 | 0.015 | 10.55 | 10.69 | 6.926 | 0
Verbindungsstück | Wartung_FFB | S235 | 0 | Verbindungsstück | PythonPart | Wartung_FFB | Plate | 0121Pyt0000008170 | Verbindungsstück | false | S101 | HI_PRO_STA_0,300x0,300 | 10.7 | 10.54 | 10.84 | 6.941 | 10.4 | 0.015 | 10.55 | 10.69 | 6.926 | 0
Verbindungsstück | Wartung_FFB | S235 | 0 | Verbindungsstück | PythonPart | Wartung_FFB | Plate | 0121Pyt0000008171 | Verbindungsstück | false | S101 | HI_PRO_STA_0,300x0,300 | 10.7 | 10.54 | 10.84 | 6.941 | 10.4 | 0.015 | 10.55 | 10.69 | 6.926 | 0
Verbindungsstück | Wartung_FFB | S235 | 0 | Verbindungsstück | PythonPart | Wartung_FFB | Plate | 0121Pyt0000008172 | Verbindungsstück | false | S101 | HI_PRO_STA_0,300x0,300 | 10.7 | 10.54 | 10.84 | 6.941 | 10.4 | 0.015 | 10.55 | 10.69 | 6.926 | 0
Verbindungsstück | Wartung_FFB | S235 | 0 | Verbindungsstück | PythonPart | Wartung_FFB | Plate | 0121Pyt0000008173 | Verbindungsstück | false | S101 | HI_PRO_STA_0,300x0,300 | 10.7 | 10.54 | 10.84 | 6.941 | 10.4 | 0.015 | 10.55 | 10.69 | 6.926 | 0
Verbindungsstück | Wartung_FFB | S235 | 0 | Verbindungsstück | PythonPart | Wartung_FFB | Plate | 0121Pyt0000008174 | Verbindungsstück | false | S101 | HI_PRO_STA_0,300x0,300 | 10.7 | 10.54 | 10.84 | 6.941 | 10.4 | 0.015 | 10.55 | 10.69 | 6.926 | 0
Verbindungsstück | Wartung_FFB | S235 | 0 | Verbindungsstück | PythonPart | Wartung_FFB | Plate | 0121Pyt0000008175 | Verbindungsstück | false | S101 | HI_PRO_STA_0,300x0,300 | 10.7 | 10.54 | 10.84 | 6.941 | 10.4 | 0.015 | 10.55 | 10.69 | 6.926 | 0
Verbindungsstück | Wartung_FFB | S235 | 0 | Verbindungsstück | PythonPart | Wartung_FFB | Plate | 0121Pyt0000008176 | Verbindungsstück | false | S101 | HI_PRO_STA_0,300x0,300 | 10.7 | 10.54 | 10.84 | 6.941 | 10.4 | 0.015 | 10.55 | 10.69 | 6.926 | 0
Verbindungsstück | Wartung_FFB | S235 | 0 | Verbindungsstück | PythonPart | Wartung_FFB | Plate | 0121Pyt0000008177 | Verbindungsstück | false | S101 | HI_PRO_STA_0,300x0,300 | 10.7 | 10.54 | 10.84 | 6.941 | 10.4 | 0.015 | 10.55 | 10.69 | 6.926 | 0
Verbindungsstück | Wartung_FFB | S235 | 0 | Verbindungsstück | PythonPart | Wartung_FFB | Plate | 0121Pyt0000008183 | Verbindungsstück | false | S101 | HI_PRO_STA_0,300x0,300 | 10.7 | 10.54 | 10.84 | 6.941 | 10.4 | 0.015 | 10.55 | 10.69 | 6.926 | 0
Verbindungsstück | Wartung_FFB | S235 | 0 | Verbindungsstück | PythonPart | Wartung_FFB | Plate | 0121Pyt0000008185 | Verbindungsstück | false | S101 | HI_PRO_STA_0,300x0,300 | 10.7 | 10.54 | 10.84 | 6.941 | 10.4 | 0.015 | 10.55 | 10.69 | 6.926 | 0
Verbindungsstück | Wartung_FFB | S235 | 0 | Verbindungsstück | PythonPart | Wartung_FFB | Plate | 0121Pyt0000008186 | Verbindungsstück | false | S101 | HI_PRO_STA_0,300x0,300 | 10.7 | 10.54 | 10.84 | 6.941 | 10.4 | 0.015 | 10.55 | 10.69 | 6.926 | 0
Verbindungsstück | Wartung_FFB | S235 | 0 | Verbindungsstück | PythonPart | Wartung_FFB | Plate | 0121Pyt0000008187 | Verbindungsstück | false | S101 | HI_PRO_STA_0,300x0,300 | 10.7 | 10.54 | 10.84 | 6.941 | 10.4 | 0.015 | 10.55 | 10.69 | 6.926 | 0
Verbindungsstück | Wartung_FFB | S235 | 0 | Verbindungsstück | PythonPart | Wartung_FFB | Plate | 0121Pyt0000008188 | Verbindungsstück | false | S101 | HI_PRO_STA_0,300x0,300 | 10.7 | 10.54 | 10.84 | 6.941 | 10.4 | 0.015 | 10.55 | 10.69 | 6.926 | 0
Verbindungsstück | Wartung_FFB | S235 | 0 | Verbindungsstück | PythonPart | Wartung_FFB | Plate | 0121Pyt0000008189 | Verbindungsstück | false | S101 | HI_PRO_STA_0,300x0,300 | 10.7 | 10.54 | 10.84 | 6.941 | 10.4 | 0.015 | 10.55 | 10.69 | 6.926 | 0
Verbindungsstück | Wartung_FFB | S235 | 0 | Verbindungsstück | PythonPart | Wartung_FFB | Plate | 0121Pyt0000008190 | Verbindungsstück | false | S101 | HI_PRO_STA_0,300x0,300 | 10.7 | 10.54 | 10.84 | 6.941 | 10.4 | 0.015 | 10.55 | 10.69 | 6.926 | 0
Verbindungsstück | Wartung_FFB | S235 | 0 | Verbindungsstück | PythonPart | Wartung_FFB | Plate | 0121Pyt0000008192 | Verbindungsstück | false | S101 | HI_PRO_STA_0,300x0,300 | 10.7 | 10.54 | 10.84 | 6.941 | 10.4 | 0.015 | 10.55 | 10.69 | 6.926 | 0
Verbindungsstück | Wartung_FFB | S235 | 0 | Verbindungsstück | PythonPart | Wartung_FFB | Plate | 0121Pyt0000008193 | Verbindungsstück | false | S101 | HI_PRO_STA_0,300x0,300 | 10.7 | 10.54 | 10.84 | 6.941 | 10.4 | 0.015 | 10.55 | 10.69 | 6.926 | 0
Verbindungsstück | Wartung_FFB | S235 | 0 | Verbindungsstück | PythonPart | Wartung_FFB | Plate | 0121Pyt0000008194 | Verbindungsstück | false | S101 | HI_PRO_STA_0,300x0,300 | 10.7 | 10.54 | 10.84 | 6.941 | 10.4 | 0.015 | 10.55 | 10.69 | 6.926 | 0
Verbindungsstück | Wartung_FFB | S235 | 0 | Verbindungsstück | PythonPart | Wartung_FFB | Plate | 0121Pyt0000008196 | Verbindungsstück | false | S101 | HI_PRO_STA_0,300x0,300 | 10.7 | 10.54 | 10.84 | 6.941 | 10.4 | 0.015 | 10.55 | 10.69 | 6.926 | 0
Verbindungsstück | Wartung_FFB | S235 | 0 | Verbindungsstück | PythonPart | Wartung_FFB | Plate | 0121Pyt0000008197 | Verbindungsstück | false | S101 | HI_PRO_STA_0,300x0,300 | 10.7 | 10.54 | 10.84 | 6.941 | 10.4 | 0.015 | 10.55 | 10.69 | 6.926 | 0
Verbindungsstück | Wartung_FFB | S235 | 0 | Verbindungsstück | PythonPart | Wartung_FFB | Plate | 0121Pyt0000008198 | Verbindungsstück | false | S101 | HI_PRO_STA_0,300x0,300 | 10.7 | 10.54 | 10.84 | 6.941 | 10.4 | 0.015 | 10.55 | 10.69 | 6.926 | 0
Verbindungsstück | Wartung_FFB | S235 | 0 | Verbindungsstück | PythonPart | Wartung_FFB | Plate | 0121Pyt0000008199 | Verbindungsstück | false | S101 | HI_PRO_STA_0,300x0,300 | 10.7 | 10.54 | 10.84 | 6.941 | 10.4 | 0.015 | 10.55 | 10.69 | 6.926 | 0
Verbindungsstück | Wartung_FFB | S235 | 0 | Verbindungsstück | PythonPart | Wartung_FFB | Plate | 0121Pyt0000008200 | Verbindungsstück | false | S101 | HI_PRO_STA_0,300x0,300 | 10.7 | 10.54 | 10.84 | 6.941 | 10.4 | 0.015 | 10.55 | 10.69 | 6.926 | 0
Verbindungsstück | Wartung_FFB | S235 | 0 | Verbindungsstück | PythonPart | Wartung_FFB | Plate | 0121Pyt0000008201 | Verbindungsstück | false | S101 | HI_PRO_STA_0,300x0,300 | 10.7 | 10.54 | 10.84 | 6.941 | 10.4 | 0.015 | 10.55 | 10.69 | 6.926 | 0
Verbindungsstück | Wartung_FFB | S235 | 0 | Verbindungsstück | PythonPart | Wartung_FFB | Plate | 0121Pyt0000008202 | Verbindungsstück | false | S101 | HI_PRO_STA_0,300x0,300 | 10.7 | 10.54 | 10.84 | 6.941 | 10.4 | 0.015 | 10.55 | 10.69 | 6.926 | 0
Verbindungsstück | Wartung_FFB | S235 | 0 | Verbindungsstück | PythonPart | Wartung_FFB | Plate | 0121Pyt0000008203 | Verbindungsstück | false | S101 | HI_PRO_STA_0,300x0,300 | 10.7 | 10.54 | 10.84 | 6.941 | 10.4 | 0.015 | 10.55 | 10.69 | 6.926 | 0
Verbindungsstück | Wartung_FFB | S235 | 0 | Verbindungsstück | PythonPart | Wartung_FFB | Plate | 0121Pyt0000008204 | Verbindungsstück | false | S101 | HI_PRO_STA_0,300x0,300 | 10.7 | 10.54 | 10.84 | 6.941 | 10.4 | 0.015 | 10.55 | 10.69 | 6.926 | 0
Verbindungsstück | Wartung_FFB | S235 | 0 | Verbindungsstück | PythonPart | Wartung_FFB | Plate | 0121Pyt0000008205 | Verbindungsstück | false | S101 | HI_PRO_STA_0,300x0,300 | 10.7 | 10.54 | 10.84 | 6.941 | 10.4 | 0.015 | 10.55 | 10.69 | 6.926 | 0
Verbindungsstück | Wartung_FFB | S235 | 0 | Verbindungsstück | PythonPart | Wartung_FFB | Plate | 0121Pyt0000008206 | Verbindungsstück | false | S101 | HI_PRO_STA_0,300x0,300 | 10.7 | 10.54 | 10.84 | 6.941 | 10.4 | 0.015 | 10.55 | 10.69 | 6.926 | 0
Verbindungsstück | Wartung_FFB | S235 | 0 | Verbindungsstück | PythonPart | Wartung_FFB | Plate | 0121Pyt0000008207 | Verbindungsstück | false | S101 | HI_PRO_STA_0,300x0,300 | 10.7 | 10.54 | 10.84 | 6.941 | 10.4 | 0.015 | 10.55 | 10.69 | 6.926 | 0
Verbindungsstück | Wartung_FFB | S235 | 0 | Verbindungsstück | PythonPart | Wartung_FFB | Plate | 0121Pyt0000008208 | Verbindungsstück | false | S101 | HI_PRO_STA_0,300x0,300 | 10.7 | 10.54 | 10.84 | 6.941 | 10.4 | 0.015 | 10.55 | 10.69 | 6.926 | 0
Verbindungsstück | Wartung_FFB | S235 | 0 | Verbindungsstück | PythonPart | Wartung_FFB | Plate | 0121Pyt0000008209 | Verbindungsstück | false | S101 | HI_PRO_STA_0,300x0,300 | 10.7 | 10.54 | 10.84 | 6.941 | 10.4 | 0.015 | 10.55 | 10.69 | 6.926 | 0
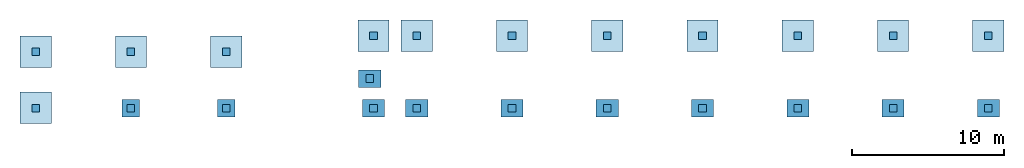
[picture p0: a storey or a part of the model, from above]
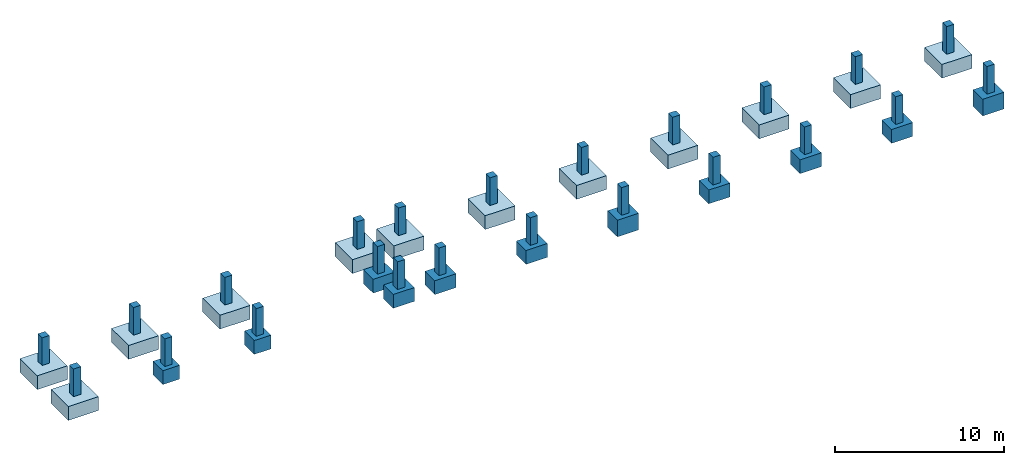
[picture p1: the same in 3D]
Properties of the parts of a building model (IFC2X3), part 20 of 25

# IfcPlate (1015)
Name | In | Material = AllplanAttributes, Material | V6 (m) = V7 (m) = V8 (m) = V9 | Bezeichnung | Plugin_Objektname | Ebene | Attributset-Objekt | Allright_Bauteil_ID | Name | Außenbauteil | Positionsnummer | PlateCommon, Reference | Unterkante (m) = X_Koordinate (m) | Oberkante (m) | Y_Koordinate (m) = Schwerpunkt_Y (m) | Z_Koordinate (m) = Schwerpunkt_Z (m) = Achsenstartpunkt (Z) (m) | Schwerpunkt_X (m) | Dicke (w) (m) | Achsenstartpunkt (X) (m) = Achsenendpunkt (X) (m) | Achsenstartpunkt (Y) (m) = Achsenendpunkt (Y) (m) | Achsenendpunkt (Z) (m) | Objektdrehwinkel
Verbindungsstück | Wartung_FFB | S235 | 0 | Verbindungsstück | PythonPart | Wartung_FFB | Plate | 0121Pyt0000008210 | Verbindungsstück | false | S101 | HI_PRO_STA_0,300x0,300 | 10.7 | 10.54 | 10.84 | 6.941 | 10.4 | 0.015 | 10.55 | 10.69 | 6.926 | 0
Verbindungsstück | Wartung_FFB | S235 | 0 | Verbindungsstück | PythonPart | Wartung_FFB | Plate | 0121Pyt0000008211 | Verbindungsstück | false | S101 | HI_PRO_STA_0,300x0,300 | 10.7 | 10.54 | 10.84 | 6.941 | 10.4 | 0.015 | 10.55 | 10.69 | 6.926 | 0
Verbindungsstück | Wartung_FFB | S235 | 0 | Verbindungsstück | PythonPart | Wartung_FFB | Plate | 0121Pyt0000008212 | Verbindungsstück | false | S101 | HI_PRO_STA_0,300x0,300 | 10.7 | 10.54 | 10.84 | 6.941 | 10.4 | 0.015 | 10.55 | 10.69 | 6.926 | 0
Verbindungsstück | Wartung_FFB | S235 | 0 | Verbindungsstück | PythonPart | Wartung_FFB | Plate | 0121Pyt0000008213 | Verbindungsstück | false | S101 | HI_PRO_STA_0,300x0,300 | 10.7 | 10.54 | 10.84 | 6.941 | 10.4 | 0.015 | 10.55 | 10.69 | 6.926 | 0
Verbindungsstück | Wartung_FFB | S235 | 0 | Verbindungsstück | PythonPart | Wartung_FFB | Plate | 0121Pyt0000008214 | Verbindungsstück | false | S101 | HI_PRO_STA_0,300x0,300 | 10.7 | 10.54 | 10.84 | 6.941 | 10.4 | 0.015 | 10.55 | 10.69 | 6.926 | 0
Verbindungsstück | Wartung_FFB | S235 | 0 | Verbindungsstück | PythonPart | Wartung_FFB | Plate | 0121Pyt0000008215 | Verbindungsstück | false | S101 | HI_PRO_STA_0,300x0,300 | 10.7 | 10.54 | 10.84 | 6.941 | 10.4 | 0.015 | 10.55 | 10.69 | 6.926 | 0
Verbindungsstück | Wartung_FFB | S235 | 0 | Verbindungsstück | PythonPart | Wartung_FFB | Plate | 0121Pyt0000008220 | Verbindungsstück | false | S101 | HI_PRO_STA_0,300x0,300 | 10.7 | 10.54 | 10.84 | 6.941 | 10.4 | 0.015 | 10.55 | 10.69 | 6.926 | 0
Verbindungsstück | Wartung_FFB | S235 | 0 | Verbindungsstück | PythonPart | Wartung_FFB | Plate | 0121Pyt0000008221 | Verbindungsstück | false | S101 | HI_PRO_STA_0,300x0,300 | 10.7 | 10.54 | 10.84 | 6.941 | 10.4 | 0.015 | 10.55 | 10.69 | 6.926 | 0
Verbindungsstück | Wartung_FFB | S235 | 0 | Verbindungsstück | PythonPart | Wartung_FFB | Plate | 0121Pyt0000008223 | Verbindungsstück | false | S101 | HI_PRO_STA_0,300x0,300 | 10.7 | 10.54 | 10.84 | 6.941 | 10.4 | 0.015 | 10.55 | 10.69 | 6.926 | 0
Verbindungsstück | Wartung_FFB | S235 | 0 | Verbindungsstück | PythonPart | Wartung_FFB | Plate | 0121Pyt0000008224 | Verbindungsstück | false | S101 | HI_PRO_STA_0,300x0,300 | 10.7 | 10.54 | 10.84 | 6.941 | 10.4 | 0.015 | 10.55 | 10.69 | 6.926 | 0
Verbindungsstück | Wartung_FFB | S235 | 0 | Verbindungsstück | PythonPart | Wartung_FFB | Plate | 0121Pyt0000008225 | Verbindungsstück | false | S101 | HI_PRO_STA_0,300x0,300 | 10.7 | 10.54 | 10.84 | 6.941 | 10.4 | 0.015 | 10.55 | 10.69 | 6.926 | 0
Verbindungsstück | Wartung_FFB | S235 | 0 | Verbindungsstück | PythonPart | Wartung_FFB | Plate | 0121Pyt0000008226 | Verbindungsstück | false | S101 | HI_PRO_STA_0,300x0,300 | 10.7 | 10.54 | 10.84 | 6.941 | 10.4 | 0.015 | 10.55 | 10.69 | 6.926 | 0
Verbindungsstück | Wartung_FFB | S235 | 0 | Verbindungsstück | PythonPart | Wartung_FFB | Plate | 0121Pyt0000008227 | Verbindungsstück | false | S101 | HI_PRO_STA_0,300x0,300 | 10.7 | 10.54 | 10.84 | 6.941 | 10.4 | 0.015 | 10.55 | 10.69 | 6.926 | 0
Verbindungsstück | Wartung_FFB | S235 | 0 | Verbindungsstück | PythonPart | Wartung_FFB | Plate | 0121Pyt0000008228 | Verbindungsstück | false | S101 | HI_PRO_STA_0,300x0,300 | 10.7 | 10.54 | 10.84 | 6.941 | 10.4 | 0.015 | 10.55 | 10.69 | 6.926 | 0
Verbindungsstück | Wartung_FFB | S235 | 0 | Verbindungsstück | PythonPart | Wartung_FFB | Plate | 0121Pyt0000008231 | Verbindungsstück | false | S101 | HI_PRO_STA_0,300x0,300 | 10.7 | 10.54 | 10.84 | 6.941 | 10.4 | 0.015 | 10.55 | 10.69 | 6.926 | 0
Verbindungsstück | Wartung_FFB | S235 | 0 | Verbindungsstück | PythonPart | Wartung_FFB | Plate | 0121Pyt0000008232 | Verbindungsstück | false | S101 | HI_PRO_STA_0,300x0,300 | 10.7 | 10.54 | 10.84 | 6.941 | 10.4 | 0.015 | 10.55 | 10.69 | 6.926 | 0
Verbindungsstück | Wartung_FFB | S235 | 0 | Verbindungsstück | PythonPart | Wartung_FFB | Plate | 0121Pyt0000008234 | Verbindungsstück | false | S101 | HI_PRO_STA_0,300x0,300 | 10.7 | 10.54 | 10.84 | 6.941 | 10.4 | 0.015 | 10.55 | 10.69 | 6.926 | 0
Verbindungsstück | Wartung_FFB | S235 | 0 | Verbindungsstück | PythonPart | Wartung_FFB | Plate | 0121Pyt0000008235 | Verbindungsstück | false | S101 | HI_PRO_STA_0,300x0,300 | 10.7 | 10.54 | 10.84 | 6.941 | 10.4 | 0.015 | 10.55 | 10.69 | 6.926 | 0
Verbindungsstück | Wartung_FFB | S235 | 0 | Verbindungsstück | PythonPart | Wartung_FFB | Plate | 0121Pyt0000008236 | Verbindungsstück | false | S101 | HI_PRO_STA_0,300x0,300 | 10.7 | 10.54 | 10.84 | 6.941 | 10.4 | 0.015 | 10.55 | 10.69 | 6.926 | 0
Verbindungsstück | Wartung_FFB | S235 | 0 | Verbindungsstück | PythonPart | Wartung_FFB | Plate | 0121Pyt0000008237 | Verbindungsstück | false | S101 | HI_PRO_STA_0,300x0,300 | 10.7 | 10.54 | 10.84 | 6.941 | 10.4 | 0.015 | 10.55 | 10.69 | 6.926 | 0
Verbindungsstück | Wartung_FFB | S235 | 0 | Verbindungsstück | PythonPart | Wartung_FFB | Plate | 0121Pyt0000008238 | Verbindungsstück | false | S101 | HI_PRO_STA_0,300x0,300 | 10.7 | 10.54 | 10.84 | 6.941 | 10.4 | 0.015 | 10.55 | 10.69 | 6.926 | 0
Verbindungsstück | Wartung_FFB | S235 | 0 | Verbindungsstück | PythonPart | Wartung_FFB | Plate | 0121Pyt0000008239 | Verbindungsstück | false | S101 | HI_PRO_STA_0,300x0,300 | 10.7 | 10.54 | 10.84 | 6.941 | 10.4 | 0.015 | 10.55 | 10.69 | 6.926 | 0
Verbindungsstück | Wartung_FFB | S235 | 0 | Verbindungsstück | PythonPart | Wartung_FFB | Plate | 0121Pyt0000008240 | Verbindungsstück | false | S101 | HI_PRO_STA_0,300x0,300 | 10.7 | 10.54 | 10.84 | 6.941 | 10.4 | 0.015 | 10.55 | 10.69 | 6.926 | 0
Verbindungsstück | Wartung_FFB | S235 | 0 | Verbindungsstück | PythonPart | Wartung_FFB | Plate | 0121Pyt0000008241 | Verbindungsstück | false | S101 | HI_PRO_STA_0,300x0,300 | 10.7 | 10.54 | 10.84 | 6.941 | 10.4 | 0.015 | 10.55 | 10.69 | 6.926 | 0
Verbindungsstück | Wartung_FFB | S235 | 0 | Verbindungsstück | PythonPart | Wartung_FFB | Plate | 0121Pyt0000008242 | Verbindungsstück | false | S101 | HI_PRO_STA_0,300x0,300 | 10.7 | 10.54 | 10.84 | 6.941 | 10.4 | 0.015 | 10.55 | 10.69 | 6.926 | 0
Verbindungsstück | Wartung_FFB | S235 | 0 | Verbindungsstück | PythonPart | Wartung_FFB | Plate | 0121Pyt0000008243 | Verbindungsstück | false | S101 | HI_PRO_STA_0,300x0,300 | 10.7 | 10.54 | 10.84 | 6.941 | 10.4 | 0.015 | 10.55 | 10.69 | 6.926 | 0
Verbindungsstück | Wartung_FFB | S235 | 0 | Verbindungsstück | PythonPart | Wartung_FFB | Plate | 0121Pyt0000008244 | Verbindungsstück | false | S101 | HI_PRO_STA_0,300x0,300 | 10.7 | 10.54 | 10.84 | 6.941 | 10.4 | 0.015 | 10.55 | 10.69 | 6.926 | 0
Verbindungsstück | Wartung_FFB | S235 | 0 | Verbindungsstück | PythonPart | Wartung_FFB | Plate | 0121Pyt0000008245 | Verbindungsstück | false | S101 | HI_PRO_STA_0,300x0,300 | 10.7 | 10.54 | 10.84 | 6.941 | 10.4 | 0.015 | 10.55 | 10.69 | 6.926 | 0
Verbindungsstück | Wartung_FFB | S235 | 0 | Verbindungsstück | PythonPart | Wartung_FFB | Plate | 0121Pyt0000008246 | Verbindungsstück | false | S101 | HI_PRO_STA_0,300x0,300 | 10.7 | 10.54 | 10.84 | 6.941 | 10.4 | 0.015 | 10.55 | 10.69 | 6.926 | 0
Verbindungsstück | Wartung_FFB | S235 | 0 | Verbindungsstück | PythonPart | Wartung_FFB | Plate | 0121Pyt0000008247 | Verbindungsstück | false | S101 | HI_PRO_STA_0,300x0,300 | 10.7 | 10.54 | 10.84 | 6.941 | 10.4 | 0.015 | 10.55 | 10.69 | 6.926 | 0
Verbindungsstück | Wartung_FFB | S235 | 0 | Verbindungsstück | PythonPart | Wartung_FFB | Plate | 0121Pyt0000008248 | Verbindungsstück | false | S101 | HI_PRO_STA_0,300x0,300 | 10.7 | 10.54 | 10.84 | 6.941 | 10.4 | 0.015 | 10.55 | 10.69 | 6.926 | 0
Verbindungsstück | Wartung_FFB | S235 | 0 | Verbindungsstück | PythonPart | Wartung_FFB | Plate | 0121Pyt0000008249 | Verbindungsstück | false | S101 | HI_PRO_STA_0,300x0,300 | 10.7 | 10.54 | 10.84 | 6.941 | 10.4 | 0.015 | 10.55 | 10.69 | 6.926 | 0
Verbindungsstück | Wartung_FFB | S235 | 0 | Verbindungsstück | PythonPart | Wartung_FFB | Plate | 0121Pyt0000008250 | Verbindungsstück | false | S101 | HI_PRO_STA_0,300x0,300 | 10.7 | 10.54 | 10.84 | 6.941 | 10.4 | 0.015 | 10.55 | 10.69 | 6.926 | 0
Verbindungsstück | Wartung_FFB | S235 | 0 | Verbindungsstück | PythonPart | Wartung_FFB | Plate | 0121Pyt0000008251 | Verbindungsstück | false | S101 | HI_PRO_STA_0,300x0,300 | 10.7 | 10.54 | 10.84 | 6.941 | 10.4 | 0.015 | 10.55 | 10.69 | 6.926 | 0
Verbindungsstück | Wartung_FFB | S235 | 0 | Verbindungsstück | PythonPart | Wartung_FFB | Plate | 0121Pyt0000008252 | Verbindungsstück | false | S101 | HI_PRO_STA_0,300x0,300 | 10.7 | 10.54 | 10.84 | 6.941 | 10.4 | 0.015 | 10.55 | 10.69 | 6.926 | 0
Verbindungsstück | Wartung_FFB | S235 | 0 | Verbindungsstück | PythonPart | Wartung_FFB | Plate | 0121Pyt0000008253 | Verbindungsstück | false | S101 | HI_PRO_STA_0,300x0,300 | 10.7 | 10.54 | 10.84 | 6.941 | 10.4 | 0.015 | 10.55 | 10.69 | 6.926 | 0
Verbindungsstück | Wartung_FFB | S235 | 0 | Verbindungsstück | PythonPart | Wartung_FFB | Plate | 0121Pyt0000008258 | Verbindungsstück | false | S101 | HI_PRO_STA_0,300x0,300 | 10.7 | 10.54 | 10.84 | 6.941 | 10.4 | 0.015 | 10.55 | 10.69 | 6.926 | 0
Verbindungsstück | Wartung_FFB | S235 | 0 | Verbindungsstück | PythonPart | Wartung_FFB | Plate | 0121Pyt0000008259 | Verbindungsstück | false | S101 | HI_PRO_STA_0,300x0,300 | 10.7 | 10.54 | 10.84 | 6.941 | 10.4 | 0.015 | 10.55 | 10.69 | 6.926 | 0
Verbindungsstück | Wartung_FFB | S235 | 0 | Verbindungsstück | PythonPart | Wartung_FFB | Plate | 0121Pyt0000008261 | Verbindungsstück | false | S101 | HI_PRO_STA_0,300x0,300 | 10.7 | 10.54 | 10.84 | 6.941 | 10.4 | 0.015 | 10.55 | 10.69 | 6.926 | 0
Verbindungsstück | Wartung_FFB | S235 | 0 | Verbindungsstück | PythonPart | Wartung_FFB | Plate | 0121Pyt0000008262 | Verbindungsstück | false | S101 | HI_PRO_STA_0,300x0,300 | 10.7 | 10.54 | 10.84 | 6.941 | 10.4 | 0.015 | 10.55 | 10.69 | 6.926 | 0
Verbindungsstück | Wartung_FFB | S235 | 0 | Verbindungsstück | PythonPart | Wartung_FFB | Plate | 0121Pyt0000008263 | Verbindungsstück | false | S101 | HI_PRO_STA_0,300x0,300 | 10.7 | 10.54 | 10.84 | 6.941 | 10.4 | 0.015 | 10.55 | 10.69 | 6.926 | 0
Verbindungsstück | Wartung_FFB | S235 | 0 | Verbindungsstück | PythonPart | Wartung_FFB | Plate | 0121Pyt0000008264 | Verbindungsstück | false | S101 | HI_PRO_STA_0,300x0,300 | 10.7 | 10.54 | 10.84 | 6.941 | 10.4 | 0.015 | 10.55 | 10.69 | 6.926 | 0
Verbindungsstück | Wartung_FFB | S235 | 0 | Verbindungsstück | PythonPart | Wartung_FFB | Plate | 0121Pyt0000008265 | Verbindungsstück | false | S101 | HI_PRO_STA_0,300x0,300 | 10.7 | 10.54 | 10.84 | 6.941 | 10.4 | 0.015 | 10.55 | 10.69 | 6.926 | 0
Verbindungsstück | Wartung_FFB | S235 | 0 | Verbindungsstück | PythonPart | Wartung_FFB | Plate | 0121Pyt0000008266 | Verbindungsstück | false | S101 | HI_PRO_STA_0,300x0,300 | 10.7 | 10.54 | 10.84 | 6.941 | 10.4 | 0.015 | 10.55 | 10.69 | 6.926 | 0
Verbindungsstück | Wartung_FFB | S235 | 0 | Verbindungsstück | PythonPart | Wartung_FFB | Plate | 0121Pyt0000008230 | Verbindungsstück | false | S101 | HI_PRO_STA_0,300x0,300 | 10.7 | 10.54 | 10.84 | 6.941 | 10.4 | 0.015 | 10.55 | 10.69 | 6.926 | 0
Verbindungsstück | Wartung_FFB | S235 | 0 | Verbindungsstück | PythonPart | Wartung_FFB | Plate | 0121Pyt0000008066 | Verbindungsstück | false | S101 | HI_PRO_STA_0,250x0,500 | 10.675 | 29.85 | 30.35 | 6.926 | 10.425 | 0.025 | 10.55 | 30.1 | 6.901 | 0
Verbindungsstück | Wartung_FFB | S235 | 0 | Verbindungsstück | PythonPart | Wartung_FFB | Plate | 0121Pyt0000008070 | Verbindungsstück | false | S101 | HI_PRO_STA_0,250x0,500 | 10.675 | 29.85 | 30.35 | 6.926 | 10.425 | 0.025 | 10.55 | 30.1 | 6.901 | 0
Verbindungsstück | Wartung_FFB | S235 | 0 | Verbindungsstück | PythonPart | Wartung_FFB | Plate | 0121Pyt0000008072 | Verbindungsstück | false | S101 | HI_PRO_STA_0,250x0,500 | 10.675 | 29.85 | 30.35 | 6.926 | 10.425 | 0.025 | 10.55 | 30.1 | 6.901 | 0
Verbindungsstück | Wartung_FFB | S235 | 0 | Verbindungsstück | PythonPart | Wartung_FFB | Plate | 0121Pyt0000008074 | Verbindungsstück | false | S101 | HI_PRO_STA_0,250x0,500 | 10.675 | 29.85 | 30.35 | 6.926 | 10.425 | 0.025 | 10.55 | 30.1 | 6.901 | 0
Verbindungsstück | Wartung_FFB | S235 | 0 | Verbindungsstück | PythonPart | Wartung_FFB | Plate | 0121Pyt0000008067 | Verbindungsstück | false | S101 | HI_PRO_STA_0,250x0,500 | 10.675 | 29.85 | 30.35 | 6.926 | 10.425 | 0.025 | 10.55 | 30.1 | 6.901 | 0
Verbindungsstück | Wartung_FFB | S235 | 0 | Verbindungsstück | PythonPart | Wartung_FFB | Plate | 0121Pyt0000008071 | Verbindungsstück | false | S101 | HI_PRO_STA_0,250x0,500 | 10.675 | 29.85 | 30.35 | 6.926 | 10.425 | 0.025 | 10.55 | 30.1 | 6.901 | 0
Verbindungsstück | Wartung_FFB | S235 | 0 | Verbindungsstück | PythonPart | Wartung_FFB | Plate | 0121Pyt0000008073 | Verbindungsstück | false | S101 | HI_PRO_STA_0,250x0,500 | 10.675 | 29.85 | 30.35 | 6.926 | 10.425 | 0.025 | 10.55 | 30.1 | 6.901 | 0
Verbindungsstück | Wartung_FFB | S235 | 0 | Verbindungsstück | PythonPart | Wartung_FFB | Plate | 0121Pyt0000008075 | Verbindungsstück | false | S101 | HI_PRO_STA_0,250x0,500 | 10.675 | 29.85 | 30.35 | 6.926 | 10.425 | 0.025 | 10.55 | 30.1 | 6.901 | 0
Verbindungsstück | Wartung_FFB | S235 | 0 | Verbindungsstück | PythonPart | Wartung_FFB | Plate | 0121Pyt0000008038 | Verbindungsstück | false | S101 | HI_PRO_STA_0,250x0,500 | 10.675 | 29.85 | 30.35 | 6.926 | 10.425 | 0.025 | 10.55 | 30.1 | 6.901 | 0
Verbindungsstück | Wartung_FFB | S235 | 0 | Verbindungsstück | PythonPart | Wartung_FFB | Plate | 0121Pyt0000008039 | Verbindungsstück | false | S101 | HI_PRO_STA_0,250x0,500 | 10.675 | 29.85 | 30.35 | 6.926 | 10.425 | 0.025 | 10.55 | 30.1 | 6.901 | 0
Verbindungsstück | Wartung_FFB | S235 | 0 | Verbindungsstück | PythonPart | Wartung_FFB | Plate | 0121Pyt0000008040 | Verbindungsstück | false | S101 | HI_PRO_STA_0,250x0,500 | 10.675 | 29.85 | 30.35 | 6.926 | 10.425 | 0.025 | 10.55 | 30.1 | 6.901 | 0
Verbindungsstück | Wartung_FFB | S235 | 0 | Verbindungsstück | PythonPart | Wartung_FFB | Plate | 0121Pyt0000008041 | Verbindungsstück | false | S101 | HI_PRO_STA_0,250x0,500 | 10.675 | 29.85 | 30.35 | 6.926 | 10.425 | 0.025 | 10.55 | 30.1 | 6.901 | 0
Verbindungsstück | Wartung_FFB | S235 | 0 | Verbindungsstück | PythonPart | Wartung_FFB | Plate | 0121Pyt0000008042 | Verbindungsstück | false | S101 | HI_PRO_STA_0,250x0,500 | 10.675 | 29.85 | 30.35 | 6.926 | 10.425 | 0.025 | 10.55 | 30.1 | 6.901 | 0
Verbindungsstück | Wartung_FFB | S235 | 0 | Verbindungsstück | PythonPart | Wartung_FFB | Plate | 0121Pyt0000008043 | Verbindungsstück | false | S101 | HI_PRO_STA_0,250x0,500 | 10.675 | 29.85 | 30.35 | 6.926 | 10.425 | 0.025 | 10.55 | 30.1 | 6.901 | 0
Verbindungsstück | Wartung_FFB | S235 | 0 | Verbindungsstück | PythonPart | Wartung_FFB | Plate | 0121Pyt0000008044 | Verbindungsstück | false | S101 | HI_PRO_STA_0,250x0,500 | 10.675 | 29.85 | 30.35 | 6.926 | 10.425 | 0.025 | 10.55 | 30.1 | 6.901 | 0
Verbindungsstück | Wartung_FFB | S235 | 0 | Verbindungsstück | PythonPart | Wartung_FFB | Plate | 0121Pyt0000008045 | Verbindungsstück | false | S101 | HI_PRO_STA_0,250x0,500 | 10.675 | 29.85 | 30.35 | 6.926 | 10.425 | 0.025 | 10.55 | 30.1 | 6.901 | 0
Verbindungsstück | Wartung_FFB | S235 | 0 | Verbindungsstück | PythonPart | Wartung_FFB | Plate | 0121Pyt0000008046 | Verbindungsstück | false | S101 | HI_PRO_STA_0,250x0,500 | 10.675 | 29.85 | 30.35 | 6.926 | 10.425 | 0.025 | 10.55 | 30.1 | 6.901 | 0
Verbindungsstück | Wartung_FFB | S235 | 0 | Verbindungsstück | PythonPart | Wartung_FFB | Plate | 0121Pyt0000008047 | Verbindungsstück | false | S101 | HI_PRO_STA_0,250x0,500 | 10.675 | 29.85 | 30.35 | 6.926 | 10.425 | 0.025 | 10.55 | 30.1 | 6.901 | 0
Verbindungsstück | Wartung_FFB | S235 | 0 | Verbindungsstück | PythonPart | Wartung_FFB | Plate | 0121Pyt0000008048 | Verbindungsstück | false | S101 | HI_PRO_STA_0,250x0,500 | 10.675 | 29.85 | 30.35 | 6.926 | 10.425 | 0.025 | 10.55 | 30.1 | 6.901 | 0
Verbindungsstück | Wartung_FFB | S235 | 0 | Verbindungsstück | PythonPart | Wartung_FFB | Plate | 0121Pyt0000008049 | Verbindungsstück | false | S101 | HI_PRO_STA_0,250x0,500 | 10.675 | 29.85 | 30.35 | 6.926 | 10.425 | 0.025 | 10.55 | 30.1 | 6.901 | 0
Verbindungsstück | Wartung_FFB | S235 | 0 | Verbindungsstück | PythonPart | Wartung_FFB | Plate | 0121Pyt0000008050 | Verbindungsstück | false | S101 | HI_PRO_STA_0,250x0,500 | 10.675 | 29.85 | 30.35 | 6.926 | 10.425 | 0.025 | 10.55 | 30.1 | 6.901 | 0
Verbindungsstück | Wartung_FFB | S235 | 0 | Verbindungsstück | PythonPart | Wartung_FFB | Plate | 0121Pyt0000008052 | Verbindungsstück | false | S101 | HI_PRO_STA_0,250x0,500 | 10.675 | 29.85 | 30.35 | 6.926 | 10.425 | 0.025 | 10.55 | 30.1 | 6.901 | 0
Verbindungsstück | Wartung_FFB | S235 | 0 | Verbindungsstück | PythonPart | Wartung_FFB | Plate | 0121Pyt0000008053 | Verbindungsstück | false | S101 | HI_PRO_STA_0,250x0,500 | 10.675 | 29.85 | 30.35 | 6.926 | 10.425 | 0.025 | 10.55 | 30.1 | 6.901 | 0
Verbindungsstück | Wartung_FFB | S235 | 0 | Verbindungsstück | PythonPart | Wartung_FFB | Plate | 0121Pyt0000008054 | Verbindungsstück | false | S101 | HI_PRO_STA_0,250x0,500 | 10.675 | 29.85 | 30.35 | 6.926 | 10.425 | 0.025 | 10.55 | 30.1 | 6.901 | 0
Verbindungsstück | Wartung_FFB | S235 | 0 | Verbindungsstück | PythonPart | Wartung_FFB | Plate | 0121Pyt0000008055 | Verbindungsstück | false | S101 | HI_PRO_STA_0,250x0,500 | 10.675 | 29.85 | 30.35 | 6.926 | 10.425 | 0.025 | 10.55 | 30.1 | 6.901 | 0
Verbindungsstück | Wartung_FFB | S235 | 0 | Verbindungsstück | PythonPart | Wartung_FFB | Plate | 0121Pyt0000008056 | Verbindungsstück | false | S101 | HI_PRO_STA_0,250x0,500 | 10.675 | 29.85 | 30.35 | 6.926 | 10.425 | 0.025 | 10.55 | 30.1 | 6.901 | 0
Verbindungsstück | Wartung_FFB | S235 | 0 | Verbindungsstück | PythonPart | Wartung_FFB | Plate | 0121Pyt0000008057 | Verbindungsstück | false | S101 | HI_PRO_STA_0,250x0,500 | 10.675 | 29.85 | 30.35 | 6.926 | 10.425 | 0.025 | 10.55 | 30.1 | 6.901 | 0
Verbindungsstück | Wartung_FFB | S235 | 0 | Verbindungsstück | PythonPart | Wartung_FFB | Plate | 0121Pyt0000008058 | Verbindungsstück | false | S101 | HI_PRO_STA_0,250x0,500 | 10.675 | 29.85 | 30.35 | 6.926 | 10.425 | 0.025 | 10.55 | 30.1 | 6.901 | 0
Verbindungsstück | Wartung_FFB | S235 | 0 | Verbindungsstück | PythonPart | Wartung_FFB | Plate | 0121Pyt0000008059 | Verbindungsstück | false | S101 | HI_PRO_STA_0,250x0,500 | 10.675 | 29.85 | 30.35 | 6.926 | 10.425 | 0.025 | 10.55 | 30.1 | 6.901 | 0
Verbindungsstück | Wartung_FFB | S235 | 0 | Verbindungsstück | PythonPart | Wartung_FFB | Plate | 0121Pyt0000008060 | Verbindungsstück | false | S101 | HI_PRO_STA_0,250x0,500 | 10.675 | 29.85 | 30.35 | 6.926 | 10.425 | 0.025 | 10.55 | 30.1 | 6.901 | 0
Verbindungsstück | Wartung_FFB | S235 | 0 | Verbindungsstück | PythonPart | Wartung_FFB | Plate | 0121Pyt0000008062 | Verbindungsstück | false | S101 | HI_PRO_STA_0,250x0,500 | 10.675 | 29.85 | 30.35 | 6.926 | 10.425 | 0.025 | 10.55 | 30.1 | 6.901 | 0
Verbindungsstück | Wartung_FFB | S235 | 0 | Verbindungsstück | PythonPart | Wartung_FFB | Plate | 0121Pyt0000008063 | Verbindungsstück | false | S101 | HI_PRO_STA_0,250x0,500 | 10.675 | 29.85 | 30.35 | 6.926 | 10.425 | 0.025 | 10.55 | 30.1 | 6.901 | 0
Verbindungsstück | Wartung_FFB | S235 | 0 | Verbindungsstück | PythonPart | Wartung_FFB | Plate | 0121Pyt0000008064 | Verbindungsstück | false | S101 | HI_PRO_STA_0,250x0,500 | 10.675 | 29.85 | 30.35 | 6.926 | 10.425 | 0.025 | 10.55 | 30.1 | 6.901 | 0
Verbindungsstück | Wartung_FFB | S235 | 0 | Verbindungsstück | PythonPart | Wartung_FFB | Plate | 0121Pyt0000008029 | Verbindungsstück | false | S101 | HI_PRO_STA_0,250x0,500 | 10.675 | 29.85 | 30.35 | 6.926 | 10.425 | 0.025 | 10.55 | 30.1 | 6.901 | 0
Verbindungsstück | Wartung_FFB | S235 | 0 | Verbindungsstück | PythonPart | Wartung_FFB | Plate | 0121Pyt0000008031 | Verbindungsstück | false | S101 | HI_PRO_STA_0,250x0,500 | 10.675 | 29.85 | 30.35 | 6.926 | 10.425 | 0.025 | 10.55 | 30.1 | 6.901 | 0
Verbindungsstück | Wartung_FFB | S235 | 0 | Verbindungsstück | PythonPart | Wartung_FFB | Plate | 0121Pyt0000008033 | Verbindungsstück | false | S101 | HI_PRO_STA_0,250x0,500 | 10.675 | 29.85 | 30.35 | 6.926 | 10.425 | 0.025 | 10.55 | 30.1 | 6.901 | 0
Verbindungsstück | Wartung_FFB | S235 | 0 | Verbindungsstück | PythonPart | Wartung_FFB | Plate | 0121Pyt0000008035 | Verbindungsstück | false | S101 | HI_PRO_STA_0,250x0,500 | 10.675 | 29.85 | 30.35 | 6.926 | 10.425 | 0.025 | 10.55 | 30.1 | 6.901 | 0
Verbindungsstück | Wartung_FFB | S235 | 0 | Verbindungsstück | PythonPart | Wartung_FFB | Plate | 0121Pyt0000008037 | Verbindungsstück | false | S101 | HI_PRO_STA_0,250x0,500 | 10.675 | 29.85 | 30.35 | 6.926 | 10.425 | 0.025 | 10.55 | 30.1 | 6.901 | 0
Verbindungsstück | Wartung_FFB | S235 | 0 | Verbindungsstück | PythonPart | Wartung_FFB | Plate | 0121Pyt0000008028 | Verbindungsstück | false | S101 | HI_PRO_STA_0,250x0,500 | 10.675 | 29.85 | 30.35 | 6.926 | 10.425 | 0.025 | 10.55 | 30.1 | 6.901 | 0
Verbindungsstück | Wartung_FFB | S235 | 0 | Verbindungsstück | PythonPart | Wartung_FFB | Plate | 0121Pyt0000008030 | Verbindungsstück | false | S101 | HI_PRO_STA_0,250x0,500 | 10.675 | 29.85 | 30.35 | 6.926 | 10.425 | 0.025 | 10.55 | 30.1 | 6.901 | 0
Verbindungsstück | Wartung_FFB | S235 | 0 | Verbindungsstück | PythonPart | Wartung_FFB | Plate | 0121Pyt0000008032 | Verbindungsstück | false | S101 | HI_PRO_STA_0,250x0,500 | 10.675 | 29.85 | 30.35 | 6.926 | 10.425 | 0.025 | 10.55 | 30.1 | 6.901 | 0
Verbindungsstück | Wartung_FFB | S235 | 0 | Verbindungsstück | PythonPart | Wartung_FFB | Plate | 0121Pyt0000008034 | Verbindungsstück | false | S101 | HI_PRO_STA_0,250x0,500 | 10.675 | 29.85 | 30.35 | 6.926 | 10.425 | 0.025 | 10.55 | 30.1 | 6.901 | 0
Verbindungsstück | Wartung_FFB | S235 | 0 | Verbindungsstück | PythonPart | Wartung_FFB | Plate | 0121Pyt0000008036 | Verbindungsstück | false | S101 | HI_PRO_STA_0,250x0,500 | 10.675 | 29.85 | 30.35 | 6.926 | 10.425 | 0.025 | 10.55 | 30.1 | 6.901 | 0
Verbindungsstück | Wartung_FFB | S235 | 0 | Verbindungsstück | PythonPart | Wartung_FFB | Plate | 0121Pyt0000008007 | Verbindungsstück | false | S101 | HI_PRO_STA_0,250x0,500 | 10.675 | 29.85 | 30.35 | 6.926 | 10.425 | 0.025 | 10.55 | 30.1 | 6.901 | 0
Verbindungsstück | Wartung_FFB | S235 | 0 | Verbindungsstück | PythonPart | Wartung_FFB | Plate | 0121Pyt0000008009 | Verbindungsstück | false | S101 | HI_PRO_STA_0,250x0,500 | 10.675 | 29.85 | 30.35 | 6.926 | 10.425 | 0.025 | 10.55 | 30.1 | 6.901 | 0
Verbindungsstück | Wartung_FFB | S235 | 0 | Verbindungsstück | PythonPart | Wartung_FFB | Plate | 0121Pyt0000008010 | Verbindungsstück | false | S101 | HI_PRO_STA_0,250x0,500 | 10.675 | 29.85 | 30.35 | 6.926 | 10.425 | 0.025 | 10.55 | 30.1 | 6.901 | 0
Verbindungsstück | Wartung_FFB | S235 | 0 | Verbindungsstück | PythonPart | Wartung_FFB | Plate | 0121Pyt0000008011 | Verbindungsstück | false | S101 | HI_PRO_STA_0,250x0,500 | 10.675 | 29.85 | 30.35 | 6.926 | 10.425 | 0.025 | 10.55 | 30.1 | 6.901 | 0
Verbindungsstück | Wartung_FFB | S235 | 0 | Verbindungsstück | PythonPart | Wartung_FFB | Plate | 0121Pyt0000008012 | Verbindungsstück | false | S101 | HI_PRO_STA_0,250x0,500 | 10.675 | 29.85 | 30.35 | 6.926 | 10.425 | 0.025 | 10.55 | 30.1 | 6.901 | 0
Verbindungsstück | Wartung_FFB | S235 | 0 | Verbindungsstück | PythonPart | Wartung_FFB | Plate | 0121Pyt0000008013 | Verbindungsstück | false | S101 | HI_PRO_STA_0,250x0,500 | 10.675 | 29.85 | 30.35 | 6.926 | 10.425 | 0.025 | 10.55 | 30.1 | 6.901 | 0
Verbindungsstück | Wartung_FFB | S235 | 0 | Verbindungsstück | PythonPart | Wartung_FFB | Plate | 0121Pyt0000008016 | Verbindungsstück | false | S101 | HI_PRO_STA_0,250x0,500 | 10.675 | 29.85 | 30.35 | 6.926 | 10.425 | 0.025 | 10.55 | 30.1 | 6.901 | 0
Verbindungsstück | Wartung_FFB | S235 | 0 | Verbindungsstück | PythonPart | Wartung_FFB | Plate | 0121Pyt0000008017 | Verbindungsstück | false | S101 | HI_PRO_STA_0,250x0,500 | 10.675 | 29.85 | 30.35 | 6.926 | 10.425 | 0.025 | 10.55 | 30.1 | 6.901 | 0
Verbindungsstück | Wartung_FFB | S235 | 0 | Verbindungsstück | PythonPart | Wartung_FFB | Plate | 0121Pyt0000008018 | Verbindungsstück | false | S101 | HI_PRO_STA_0,250x0,500 | 10.675 | 29.85 | 30.35 | 6.926 | 10.425 | 0.025 | 10.55 | 30.1 | 6.901 | 0
Verbindungsstück | Wartung_FFB | S235 | 0 | Verbindungsstück | PythonPart | Wartung_FFB | Plate | 0121Pyt0000008001 | Verbindungsstück | false | S101 | HI_PRO_STA_0,250x0,500 | 10.675 | 29.85 | 30.35 | 6.926 | 10.425 | 0.025 | 10.55 | 30.1 | 6.901 | 0
Verbindungsstück | Wartung_FFB | S235 | 0 | Verbindungsstück | PythonPart | Wartung_FFB | Plate | 0121Pyt0000008004 | Verbindungsstück | false | S101 | HI_PRO_STA_0,250x0,500 | 10.675 | 29.85 | 30.35 | 6.926 | 10.425 | 0.025 | 10.55 | 30.1 | 6.901 | 0
Verbindungsstück | Wartung_FFB | S235 | 0 | Verbindungsstück | PythonPart | Wartung_FFB | Plate | 0121Pyt0000008006 | Verbindungsstück | false | S101 | HI_PRO_STA_0,250x0,500 | 10.675 | 29.85 | 30.35 | 6.926 | 10.425 | 0.025 | 10.55 | 30.1 | 6.901 | 0
Verbindungsstück | Wartung_FFB | S235 | 0 | Verbindungsstück | PythonPart | Wartung_FFB | Plate | 0121Pyt0000008005 | Verbindungsstück | false | S101 | HI_PRO_STA_0,250x0,500 | 10.675 | 29.85 | 30.35 | 6.926 | 10.425 | 0.025 | 10.55 | 30.1 | 6.901 | 0
Verbindungsstück | Wartung_FFB | S235 | 0 | Verbindungsstück | PythonPart | Wartung_FFB | Plate | 0121Pyt0000008002 | Verbindungsstück | false | S101 | HI_PRO_STA_0,250x0,500 | 10.675 | 29.85 | 30.35 | 6.926 | 10.425 | 0.025 | 10.55 | 30.1 | 6.901 | 0
Verbindungsstück | Wartung_FFB | S235 | 0 | Verbindungsstück | PythonPart | Wartung_FFB | Plate | 0121Pyt0000008003 | Verbindungsstück | false | S101 | HI_PRO_STA_0,250x0,500 | 10.675 | 29.85 | 30.35 | 6.926 | 10.425 | 0.025 | 10.55 | 30.1 | 6.901 | 0
Verbindungsstück | Wartung_FFB | S235 | 0 | Verbindungsstück | PythonPart | Wartung_FFB | Plate | 0121Pyt0000008076 | Verbindungsstück | false | S101 | HI_PRO_STA_0,250x0,500 | 10.675 | 29.85 | 30.35 | 6.926 | 10.425 | 0.025 | 10.55 | 30.1 | 6.901 | 0
Verbindungsstück | Wartung_FFB | S235 | 0 | Verbindungsstück | PythonPart | Wartung_FFB | Plate | 0121Pyt0000008077 | Verbindungsstück | false | S101 | HI_PRO_STA_0,250x0,500 | 10.675 | 29.85 | 30.35 | 6.926 | 10.425 | 0.025 | 10.55 | 30.1 | 6.901 | 0
Verbindungsstück | Wartung_FFB | S235 | 0 | Verbindungsstück | PythonPart | Wartung_FFB | Plate | 0121Pyt0000008078 | Verbindungsstück | false | S101 | HI_PRO_STA_0,250x0,500 | 10.675 | 29.85 | 30.35 | 6.926 | 10.425 | 0.025 | 10.55 | 30.1 | 6.901 | 0
Verbindungsstück | Wartung_FFB | S235 | 0 | Verbindungsstück | PythonPart | Wartung_FFB | Plate | 0121Pyt0000008080 | Verbindungsstück | false | S101 | HI_PRO_STA_0,250x0,500 | 10.675 | 29.85 | 30.35 | 6.926 | 10.425 | 0.025 | 10.55 | 30.1 | 6.901 | 0
Verbindungsstück | Wartung_FFB | S235 | 0 | Verbindungsstück | PythonPart | Wartung_FFB | Plate | 0121Pyt0000008082 | Verbindungsstück | false | S101 | HI_PRO_STA_0,250x0,500 | 10.675 | 29.85 | 30.35 | 6.926 | 10.425 | 0.025 | 10.55 | 30.1 | 6.901 | 0
Verbindungsstück | Wartung_FFB | S235 | 0 | Verbindungsstück | PythonPart | Wartung_FFB | Plate | 0121Pyt0000008083 | Verbindungsstück | false | S101 | HI_PRO_STA_0,250x0,500 | 10.675 | 29.85 | 30.35 | 6.926 | 10.425 | 0.025 | 10.55 | 30.1 | 6.901 | 0
Verbindungsstück | Wartung_FFB | S235 | 0 | Verbindungsstück | PythonPart | Wartung_FFB | Plate | 0121Pyt0000008084 | Verbindungsstück | false | S101 | HI_PRO_STA_0,250x0,500 | 10.675 | 29.85 | 30.35 | 6.926 | 10.425 | 0.025 | 10.55 | 30.1 | 6.901 | 0
Verbindungsstück | Wartung_FFB | S235 | 0 | Verbindungsstück | PythonPart | Wartung_FFB | Plate | 0121Pyt0000008085 | Verbindungsstück | false | S101 | HI_PRO_STA_0,250x0,500 | 10.675 | 29.85 | 30.35 | 6.926 | 10.425 | 0.025 | 10.55 | 30.1 | 6.901 | 0
Verbindungsstück | Wartung_FFB | S235 | 0 | Verbindungsstück | PythonPart | Wartung_FFB | Plate | 0121Pyt0000008086 | Verbindungsstück | false | S101 | HI_PRO_STA_0,250x0,500 | 10.675 | 29.85 | 30.35 | 6.926 | 10.425 | 0.025 | 10.55 | 30.1 | 6.901 | 0
Verbindungsstück | Wartung_FFB | S235 | 0 | Verbindungsstück | PythonPart | Wartung_FFB | Plate | 0121Pyt0000008087 | Verbindungsstück | false | S101 | HI_PRO_STA_0,250x0,500 | 10.675 | 29.85 | 30.35 | 6.926 | 10.425 | 0.025 | 10.55 | 30.1 | 6.901 | 0
Verbindungsstück | Wartung_FFB | S235 | 0 | Verbindungsstück | PythonPart | Wartung_FFB | Plate | 0121Pyt0000008088 | Verbindungsstück | false | S101 | HI_PRO_STA_0,250x0,500 | 10.675 | 29.85 | 30.35 | 6.926 | 10.425 | 0.025 | 10.55 | 30.1 | 6.901 | 0
Verbindungsstück | Wartung_FFB | S235 | 0 | Verbindungsstück | PythonPart | Wartung_FFB | Plate | 0121Pyt0000008089 | Verbindungsstück | false | S101 | HI_PRO_STA_0,250x0,500 | 10.675 | 29.85 | 30.35 | 6.926 | 10.425 | 0.025 | 10.55 | 30.1 | 6.901 | 0
Verbindungsstück | Wartung_FFB | S235 | 0 | Verbindungsstück | PythonPart | Wartung_FFB | Plate | 0121Pyt0000008090 | Verbindungsstück | false | S101 | HI_PRO_STA_0,250x0,500 | 10.675 | 29.85 | 30.35 | 6.926 | 10.425 | 0.025 | 10.55 | 30.1 | 6.901 | 0
Verbindungsstück | Wartung_FFB | S235 | 0 | Verbindungsstück | PythonPart | Wartung_FFB | Plate | 0121Pyt0000008091 | Verbindungsstück | false | S101 | HI_PRO_STA_0,250x0,500 | 10.675 | 29.85 | 30.35 | 6.926 | 10.425 | 0.025 | 10.55 | 30.1 | 6.901 | 0
Verbindungsstück | Wartung_FFB | S235 | 0 | Verbindungsstück | PythonPart | Wartung_FFB | Plate | 0121Pyt0000008092 | Verbindungsstück | false | S101 | HI_PRO_STA_0,250x0,500 | 10.675 | 29.85 | 30.35 | 6.926 | 10.425 | 0.025 | 10.55 | 30.1 | 6.901 | 0
Verbindungsstück | Wartung_FFB | S235 | 0 | Verbindungsstück | PythonPart | Wartung_FFB | Plate | 0121Pyt0000008093 | Verbindungsstück | false | S101 | HI_PRO_STA_0,250x0,500 | 10.675 | 29.85 | 30.35 | 6.926 | 10.425 | 0.025 | 10.55 | 30.1 | 6.901 | 0
Verbindungsstück | Wartung_FFB | S235 | 0 | Verbindungsstück | PythonPart | Wartung_FFB | Plate | 0121Pyt0000008094 | Verbindungsstück | false | S101 | HI_PRO_STA_0,250x0,500 | 10.675 | 29.85 | 30.35 | 6.926 | 10.425 | 0.025 | 10.55 | 30.1 | 6.901 | 0
Verbindungsstück | Wartung_FFB | S235 | 0 | Verbindungsstück | PythonPart | Wartung_FFB | Plate | 0121Pyt0000008095 | Verbindungsstück | false | S101 | HI_PRO_STA_0,250x0,500 | 10.675 | 29.85 | 30.35 | 6.926 | 10.425 | 0.025 | 10.55 | 30.1 | 6.901 | 0
Verbindungsstück | Wartung_FFB | S235 | 0 | Verbindungsstück | PythonPart | Wartung_FFB | Plate | 0121Pyt0000008100 | Verbindungsstück | false | S101 | HI_PRO_STA_0,250x0,500 | 10.675 | 29.85 | 30.35 | 6.926 | 10.425 | 0.025 | 10.55 | 30.1 | 6.901 | 0
Verbindungsstück | Wartung_FFB | S235 | 0 | Verbindungsstück | PythonPart | Wartung_FFB | Plate | 0121Pyt0000008099 | Verbindungsstück | false | S101 | HI_PRO_STA_0,250x0,500 | 10.675 | 29.85 | 30.35 | 6.926 | 10.425 | 0.025 | 10.55 | 30.1 | 6.901 | 0
Verbindungsstück | Wartung_FFB | S235 | 0 | Verbindungsstück | PythonPart | Wartung_FFB | Plate | 0121Pyt0000008098 | Verbindungsstück | false | S101 | HI_PRO_STA_0,250x0,500 | 10.675 | 29.85 | 30.35 | 6.926 | 10.425 | 0.025 | 10.55 | 30.1 | 6.901 | 0
Verbindungsstück | Wartung_FFB | S235 | 0 | Verbindungsstück | PythonPart | Wartung_FFB | Plate | 0121Pyt0000008097 | Verbindungsstück | false | S101 | HI_PRO_STA_0,250x0,500 | 10.675 | 29.85 | 30.35 | 6.926 | 10.425 | 0.025 | 10.55 | 30.1 | 6.901 | 0
Verbindungsstück | Wartung_FFB | S235 | 0 | Verbindungsstück | PythonPart | Wartung_FFB | Plate | 0121Pyt0000008096 | Verbindungsstück | false | S101 | HI_PRO_STA_0,250x0,500 | 10.675 | 29.85 | 30.35 | 6.926 | 10.425 | 0.025 | 10.55 | 30.1 | 6.901 | 0
Verbindungsstück | Wartung_FFB | S235 | 0 | Verbindungsstück | PythonPart | Wartung_FFB | Plate | 0121Pyt0000008105 | Verbindungsstück | false | S101 | HI_PRO_STA_0,250x0,500 | 10.675 | 29.85 | 30.35 | 6.926 | 10.425 | 0.025 | 10.55 | 30.1 | 6.901 | 0
Verbindungsstück | Wartung_FFB | S235 | 0 | Verbindungsstück | PythonPart | Wartung_FFB | Plate | 0121Pyt0000008106 | Verbindungsstück | false | S101 | HI_PRO_STA_0,250x0,500 | 10.675 | 29.85 | 30.35 | 6.926 | 10.425 | 0.025 | 10.55 | 30.1 | 6.901 | 0
Verbindungsstück | Wartung_FFB | S235 | 0 | Verbindungsstück | PythonPart | Wartung_FFB | Plate | 0121Pyt0000008108 | Verbindungsstück | false | S101 | HI_PRO_STA_0,250x0,500 | 10.675 | 29.85 | 30.35 | 6.926 | 10.425 | 0.025 | 10.55 | 30.1 | 6.901 | 0
Verbindungsstück | Wartung_FFB | S235 | 0 | Verbindungsstück | PythonPart | Wartung_FFB | Plate | 0121Pyt0000008109 | Verbindungsstück | false | S101 | HI_PRO_STA_0,250x0,500 | 10.675 | 29.85 | 30.35 | 6.926 | 10.425 | 0.025 | 10.55 | 30.1 | 6.901 | 0
Verbindungsstück | Wartung_FFB | S235 | 0 | Verbindungsstück | PythonPart | Wartung_FFB | Plate | 0121Pyt0000008110 | Verbindungsstück | false | S101 | HI_PRO_STA_0,250x0,500 | 10.675 | 29.85 | 30.35 | 6.926 | 10.425 | 0.025 | 10.55 | 30.1 | 6.901 | 0
Verbindungsstück | Wartung_FFB | S235 | 0 | Verbindungsstück | PythonPart | Wartung_FFB | Plate | 0121Pyt0000008111 | Verbindungsstück | false | S101 | HI_PRO_STA_0,250x0,500 | 10.675 | 29.85 | 30.35 | 6.926 | 10.425 | 0.025 | 10.55 | 30.1 | 6.901 | 0
Verbindungsstück | Wartung_FFB | S235 | 0 | Verbindungsstück | PythonPart | Wartung_FFB | Plate | 0121Pyt0000008113 | Verbindungsstück | false | S101 | HI_PRO_STA_0,250x0,500 | 10.675 | 29.85 | 30.35 | 6.926 | 10.425 | 0.025 | 10.55 | 30.1 | 6.901 | 0
Verbindungsstück | Wartung_FFB | S235 | 0 | Verbindungsstück | PythonPart | Wartung_FFB | Plate | 0121Pyt0000008114 | Verbindungsstück | false | S101 | HI_PRO_STA_0,250x0,500 | 10.675 | 29.85 | 30.35 | 6.926 | 10.425 | 0.025 | 10.55 | 30.1 | 6.901 | 0
Verbindungsstück | Wartung_FFB | S235 | 0 | Verbindungsstück | PythonPart | Wartung_FFB | Plate | 0121Pyt0000005842 | Verbindungsstück | false | S101 | HI_PRO_STA_0,300x0,300 | 10.7 | 10.54 | 10.84 | 6.941 | 10.4 | 0.015 | 10.55 | 10.69 | 6.926 | 0
Verbindungsstück | Wartung_FFB | S235 | 0 | Verbindungsstück | PythonPart | Wartung_FFB | Plate | 0121Pyt0000005841 | Verbindungsstück | false | S101 | HI_PRO_STA_0,300x0,300 | 10.7 | 10.54 | 10.84 | 6.941 | 10.4 | 0.015 | 10.55 | 10.69 | 6.926 | 0
Verbindungsstück | Wartung_FFB | S235 | 0 | Verbindungsstück | PythonPart | Wartung_FFB | Plate | 0121Pyt0000005840 | Verbindungsstück | false | S101 | HI_PRO_STA_0,250x0,500 | 10.675 | 10.44 | 10.94 | 6.926 | 10.425 | 0.025 | 10.55 | 10.69 | 6.901 | 0
Verbindungsstück | Wartung_FFB | S235 | 0 | Verbindungsstück | PythonPart | Wartung_FFB | Plate | 0121Pyt0000005843 | Verbindungsstück | false | S101 | HI_PRO_STA_0,250x0,500 | 10.675 | 29.85 | 30.35 | 6.926 | 10.425 | 0.025 | 10.55 | 30.1 | 6.901 | 0
Verbindungsstück | Wartung_FFB | S235 | 0 | Verbindungsstück | PythonPart | Wartung_FFB | Plate | 0121Pyt0000005888 | Verbindungsstück | false | S101 | HI_PRO_STA_0,300x0,300 | 10.7 | 10.54 | 10.84 | 6.941 | 10.4 | 0.015 | 10.55 | 10.69 | 6.926 | 0
Verbindungsstück | Wartung_FFB | S235 | 0 | Verbindungsstück | PythonPart | Wartung_FFB | Plate | 0121Pyt0000005887 | Verbindungsstück | false | S101 | HI_PRO_STA_0,300x0,300 | 10.7 | 10.54 | 10.84 | 6.941 | 10.4 | 0.015 | 10.55 | 10.69 | 6.926 | 0
Verbindungsstück | Wartung_FFB | S235 | 0 | Verbindungsstück | PythonPart | Wartung_FFB | Plate | 0121Pyt0000005886 | Verbindungsstück | false | S101 | HI_PRO_STA_0,250x0,500 | 10.675 | 10.44 | 10.94 | 6.926 | 10.425 | 0.025 | 10.55 | 10.69 | 6.901 | 0
Verbindungsstück | Wartung_FFB | S235 | 0 | Verbindungsstück | PythonPart | Wartung_FFB | Plate | 0121Pyt0000005889 | Verbindungsstück | false | S101 | HI_PRO_STA_0,250x0,500 | 10.675 | 29.85 | 30.35 | 6.926 | 10.425 | 0.025 | 10.55 | 30.1 | 6.901 | 0
Verbindungsstück | Wartung_FFB | S235 | 0 | Verbindungsstück | PythonPart | Wartung_FFB | Plate | 0121Pyt0000008123 | Verbindungsstück | false | S101 | HI_PRO_STA_0,300x0,300 | 10.7 | 10.54 | 10.84 | 6.941 | 10.4 | 0.015 | 10.55 | 10.69 | 6.926 | 0
Verbindungsstück | Wartung_FFB | S235 | 0 | Verbindungsstück | PythonPart | Wartung_FFB | Plate | 0121Pyt0000007967 | Verbindungsstück | false | S101 | HI_PRO_STA_0,250x0,500 | 10.675 | 29.85 | 30.35 | 6.926 | 10.425 | 0.025 | 10.55 | 30.1 | 6.901 | 0
Verbindungsstück | Wartung_FFB | S235 | 0 | Verbindungsstück | PythonPart | Wartung_FFB | Plate | 0121Pyt0000008161 | Verbindungsstück | false | S101 | HI_PRO_STA_0,300x0,300 | 10.7 | 10.54 | 10.84 | 6.941 | 10.4 | 0.015 | 10.55 | 10.69 | 6.926 | 0
Verbindungsstück | Wartung_FFB | S235 | 0 | Verbindungsstück | PythonPart | Wartung_FFB | Plate | 0121Pyt0000008061 | Verbindungsstück | false | S101 | HI_PRO_STA_0,250x0,500 | 10.675 | 29.85 | 30.35 | 6.926 | 10.425 | 0.025 | 10.55 | 30.1 | 6.901 | 0
Verbindungsstück | Wartung_FFB | S235 | 0 | Verbindungsstück | PythonPart | Wartung_FFB | Plate | 0121Pyt0000007300 | Verbindungsstück | false | S101 | HI_PRO_STA_0,300x0,300 | 10.7 | 10.54 | 10.84 | 6.941 | 10.4 | 0.015 | 10.55 | 10.69 | 6.926 | 0
Verbindungsstück | Wartung_FFB | S235 | 0 | Verbindungsstück | PythonPart | Wartung_FFB | Plate | 0121Pyt0000007301 | Verbindungsstück | false | S101 | HI_PRO_STA_0,250x0,500 | 10.675 | 29.85 | 30.35 | 6.926 | 10.425 | 0.025 | 10.55 | 30.1 | 6.901 | 0
Verbindungsstück | Wartung_FFB | S235 | 0 | Verbindungsstück | PythonPart | Wartung_FFB | Plate | 0121Pyt0000007476 | Verbindungsstück | false | S101 | HI_PRO_STA_0,300x0,300 | 10.7 | 10.54 | 10.84 | 6.941 | 10.4 | 0.015 | 10.55 | 10.69 | 6.926 | 0
Verbindungsstück | Wartung_FFB | S235 | 0 | Verbindungsstück | PythonPart | Wartung_FFB | Plate | 0121Pyt0000007477 | Verbindungsstück | false | S101 | HI_PRO_STA_0,250x0,500 | 10.675 | 29.85 | 30.35 | 6.926 | 10.425 | 0.025 | 10.55 | 30.1 | 6.901 | 0
Verbindungsstück | Wartung_FFB | S235 | 0 | Verbindungsstück | PythonPart | Wartung_FFB | Plate | 0121Pyt0000014937 | Verbindungsstück | false | S101 | HI_PRO_STA_0,300x0,300 | 10.7 | 10.54 | 10.84 | 6.941 | 10.4 | 0.015 | 10.55 | 10.69 | 6.926 | 0
Verbindungsstück | Wartung_FFB | S235 | 0 | Verbindungsstück | PythonPart | Wartung_FFB | Plate | 0121Pyt0000014938 | Verbindungsstück | false | S101 | HI_PRO_STA_0,300x0,300 | 10.7 | 10.54 | 10.84 | 6.941 | 10.4 | 0.015 | 10.55 | 10.69 | 6.926 | 0
Verbindungsstück | Wartung_FFB | S235 | 0 | Verbindungsstück | PythonPart | Wartung_FFB | Plate | 0121Pyt0000014940 | Verbindungsstück | false | S101 | HI_PRO_STA_0,250x0,500 | 10.675 | 10.44 | 10.94 | 6.926 | 10.425 | 0.025 | 10.55 | 10.69 | 6.901 | 0
Verbindungsstück | Wartung_FFB | S235 | 0 | Verbindungsstück | PythonPart | Wartung_FFB | Plate | 0121Pyt0000014941 | Verbindungsstück | false | S101 | HI_PRO_STA_0,250x0,500 | 10.675 | 29.85 | 30.35 | 6.926 | 10.425 | 0.025 | 10.55 | 30.1 | 6.901 | 0
Verbindungsstück | Wartung_FFB | S235 | 0 | Verbindungsstück | PythonPart | Wartung_FFB | Plate | 0121Pyt0000014954 | Verbindungsstück | false | S101 | HI_PRO_STA_0,300x0,300 | 10.7 | 10.54 | 10.84 | 6.941 | 10.4 | 0.015 | 10.55 | 10.69 | 6.926 | 0
Verbindungsstück | Wartung_FFB | S235 | 0 | Verbindungsstück | PythonPart | Wartung_FFB | Plate | 0121Pyt0000014955 | Verbindungsstück | false | S101 | HI_PRO_STA_0,250x0,500 | 10.675 | 29.85 | 30.35 | 6.926 | 10.425 | 0.025 | 10.55 | 30.1 | 6.901 | 0
Verbindungsstück | Wartung_FFB | S235 | 0 | Verbindungsstück | PythonPart | Wartung_FFB | Plate | 0121Pyt0000014957 | Verbindungsstück | false | S101 | HI_PRO_STA_0,300x0,300 | 10.7 | 10.54 | 10.84 | 6.941 | 10.4 | 0.015 | 10.55 | 10.69 | 6.926 | 0
Verbindungsstück | Wartung_FFB | S235 | 0 | Verbindungsstück | PythonPart | Wartung_FFB | Plate | 0121Pyt0000014959 | Verbindungsstück | false | S101 | HI_PRO_STA_0,250x0,500 | 10.675 | 29.85 | 30.35 | 6.926 | 10.425 | 0.025 | 10.55 | 30.1 | 6.901 | 0
Verbindungsstück | Wartung_FFB | S235 | 0 | Verbindungsstück | PythonPart | Wartung_FFB | Plate | 0121Pyt0000008140 | Verbindungsstück | false | S101 | HI_PRO_STA_0,300x0,300 | 10.7 | 10.54 | 10.84 | 6.941 | 10.4 | 0.015 | 10.55 | 10.69 | 6.926 | 0
Verbindungsstück | Wartung_FFB | S235 | 0 | Verbindungsstück | PythonPart | Wartung_FFB | Plate | 0121Pyt0000007984 | Verbindungsstück | false | S101 | HI_PRO_STA_0,250x0,500 | 10.675 | 29.85 | 30.35 | 6.926 | 10.425 | 0.025 | 10.55 | 30.1 | 6.901 | 0
Verbindungsstück | Wartung_FFB | S235 | 0 | Verbindungsstück | PythonPart | Wartung_FFB | Plate | 0121Pyt0000008178 | Verbindungsstück | false | S101 | HI_PRO_STA_0,300x0,300 | 10.7 | 10.54 | 10.84 | 6.941 | 10.4 | 0.015 | 10.55 | 10.69 | 6.926 | 0
Verbindungsstück | Wartung_FFB | S235 | 0 | Verbindungsstück | PythonPart | Wartung_FFB | Plate | 0121Pyt0000008027 | Verbindungsstück | false | S101 | HI_PRO_STA_0,250x0,500 | 10.675 | 29.85 | 30.35 | 6.926 | 10.425 | 0.025 | 10.55 | 30.1 | 6.901 | 0
Verbindungsstück | Wartung_FFB | S235 | 0 | Verbindungsstück | PythonPart | Wartung_FFB | Plate | 0121Pyt0000008144 | Verbindungsstück | false | S101 | HI_PRO_STA_0,300x0,300 | 10.7 | 10.54 | 10.84 | 6.941 | 10.4 | 0.015 | 10.55 | 10.69 | 6.926 | 0
Verbindungsstück | Wartung_FFB | S235 | 0 | Verbindungsstück | PythonPart | Wartung_FFB | Plate | 0121Pyt0000007989 | Verbindungsstück | false | S101 | HI_PRO_STA_0,250x0,500 | 10.675 | 29.85 | 30.35 | 6.926 | 10.425 | 0.025 | 10.55 | 30.1 | 6.901 | 0
Verbindungsstück | Wartung_FFB | S235 | 0 | Verbindungsstück | PythonPart | Wartung_FFB | Plate | 0121Pyt0000008182 | Verbindungsstück | false | S101 | HI_PRO_STA_0,300x0,300 | 10.7 | 10.54 | 10.84 | 6.941 | 10.4 | 0.015 | 10.55 | 10.69 | 6.926 | 0
Verbindungsstück | Wartung_FFB | S235 | 0 | Verbindungsstück | PythonPart | Wartung_FFB | Plate | 0121Pyt0000008019 | Verbindungsstück | false | S101 | HI_PRO_STA_0,250x0,500 | 10.675 | 29.85 | 30.35 | 6.926 | 10.425 | 0.025 | 10.55 | 30.1 | 6.901 | 0
Verbindungsstück | Wartung_FFB | S235 | 0 | Verbindungsstück | PythonPart | Wartung_FFB | Plate | 0121Pyt0000008141 | Verbindungsstück | false | S101 | HI_PRO_STA_0,300x0,300 | 10.7 | 10.54 | 10.84 | 6.941 | 10.4 | 0.015 | 10.55 | 10.69 | 6.926 | 0
Verbindungsstück | Wartung_FFB | S235 | 0 | Verbindungsstück | PythonPart | Wartung_FFB | Plate | 0121Pyt0000007985 | Verbindungsstück | false | S101 | HI_PRO_STA_0,250x0,500 | 10.675 | 29.85 | 30.35 | 6.926 | 10.425 | 0.025 | 10.55 | 30.1 | 6.901 | 0
Verbindungsstück | Wartung_FFB | S235 | 0 | Verbindungsstück | PythonPart | Wartung_FFB | Plate | 0121Pyt0000008179 | Verbindungsstück | false | S101 | HI_PRO_STA_0,300x0,300 | 10.7 | 10.54 | 10.84 | 6.941 | 10.4 | 0.015 | 10.55 | 10.69 | 6.926 | 0
Verbindungsstück | Wartung_FFB | S235 | 0 | Verbindungsstück | PythonPart | Wartung_FFB | Plate | 0121Pyt0000008025 | Verbindungsstück | false | S101 | HI_PRO_STA_0,250x0,500 | 10.675 | 29.85 | 30.35 | 6.926 | 10.425 | 0.025 | 10.55 | 30.1 | 6.901 | 0
Verbindungsstück | Wartung_FFB | S235 | 0 | Verbindungsstück | PythonPart | Wartung_FFB | Plate | 0121Pyt0000014990 | Verbindungsstück | false | S101 | HI_PRO_STA_0,300x0,300 | 10.7 | 10.54 | 10.84 | 6.941 | 10.4 | 0.015 | 10.55 | 10.69 | 6.926 | 0
Verbindungsstück | Wartung_FFB | S235 | 0 | Verbindungsstück | PythonPart | Wartung_FFB | Plate | 0121Pyt0000014991 | Verbindungsstück | false | S101 | HI_PRO_STA_0,250x0,500 | 10.675 | 29.85 | 30.35 | 6.926 | 10.425 | 0.025 | 10.55 | 30.1 | 6.901 | 0
Verbindungsstück | Wartung_FFB | S235 | 0 | Verbindungsstück | PythonPart | Wartung_FFB | Plate | 0121Pyt0000014993 | Verbindungsstück | false | S101 | HI_PRO_STA_0,300x0,300 | 10.7 | 10.54 | 10.84 | 6.941 | 10.4 | 0.015 | 10.55 | 10.69 | 6.926 | 0
Verbindungsstück | Wartung_FFB | S235 | 0 | Verbindungsstück | PythonPart | Wartung_FFB | Plate | 0121Pyt0000014995 | Verbindungsstück | false | S101 | HI_PRO_STA_0,250x0,500 | 10.675 | 29.85 | 30.35 | 6.926 | 10.425 | 0.025 | 10.55 | 30.1 | 6.901 | 0
Verbindungsstück | Wartung_FFB | S235 | 0 | Verbindungsstück | PythonPart | Wartung_FFB | Plate | 0121Pyt0000008142 | Verbindungsstück | false | S101 | HI_PRO_STA_0,300x0,300 | 10.7 | 10.54 | 10.84 | 6.941 | 10.4 | 0.015 | 10.55 | 10.69 | 6.926 | 0
Verbindungsstück | Wartung_FFB | S235 | 0 | Verbindungsstück | PythonPart | Wartung_FFB | Plate | 0121Pyt0000007986 | Verbindungsstück | false | S101 | HI_PRO_STA_0,250x0,500 | 10.675 | 29.85 | 30.35 | 6.926 | 10.425 | 0.025 | 10.55 | 30.1 | 6.901 | 0
Verbindungsstück | Wartung_FFB | S235 | 0 | Verbindungsstück | PythonPart | Wartung_FFB | Plate | 0121Pyt0000008180 | Verbindungsstück | false | S101 | HI_PRO_STA_0,300x0,300 | 10.7 | 10.54 | 10.84 | 6.941 | 10.4 | 0.015 | 10.55 | 10.69 | 6.926 | 0
Verbindungsstück | Wartung_FFB | S235 | 0 | Verbindungsstück | PythonPart | Wartung_FFB | Plate | 0121Pyt0000008023 | Verbindungsstück | false | S101 | HI_PRO_STA_0,250x0,500 | 10.675 | 29.85 | 30.35 | 6.926 | 10.425 | 0.025 | 10.55 | 30.1 | 6.901 | 0
Verbindungsstück | Wartung_FFB | S235 | 0 | Verbindungsstück | PythonPart | Wartung_FFB | Plate | 0121Pyt0000008143 | Verbindungsstück | false | S101 | HI_PRO_STA_0,300x0,300 | 10.7 | 10.54 | 10.84 | 6.941 | 10.4 | 0.015 | 10.55 | 10.69 | 6.926 | 0
Verbindungsstück | Wartung_FFB | S235 | 0 | Verbindungsstück | PythonPart | Wartung_FFB | Plate | 0121Pyt0000007988 | Verbindungsstück | false | S101 | HI_PRO_STA_0,250x0,500 | 10.675 | 29.85 | 30.35 | 6.926 | 10.425 | 0.025 | 10.55 | 30.1 | 6.901 | 0
Verbindungsstück | Wartung_FFB | S235 | 0 | Verbindungsstück | PythonPart | Wartung_FFB | Plate | 0121Pyt0000008181 | Verbindungsstück | false | S101 | HI_PRO_STA_0,300x0,300 | 10.7 | 10.54 | 10.84 | 6.941 | 10.4 | 0.015 | 10.55 | 10.69 | 6.926 | 0
Verbindungsstück | Wartung_FFB | S235 | 0 | Verbindungsstück | PythonPart | Wartung_FFB | Plate | 0121Pyt0000008021 | Verbindungsstück | false | S101 | HI_PRO_STA_0,250x0,500 | 10.675 | 29.85 | 30.35 | 6.926 | 10.425 | 0.025 | 10.55 | 30.1 | 6.901 | 0
Verbindungsstück | Wartung_FFB | S235 | 0 | Verbindungsstück | PythonPart | Wartung_FFB | Plate | 0121Pyt0000008217 | Verbindungsstück | false | S101 | HI_PRO_STA_0,300x0,300 | 10.7 | 10.54 | 10.84 | 6.941 | 10.4 | 0.015 | 10.55 | 10.69 | 6.926 | 0
Verbindungsstück | Wartung_FFB | S235 | 0 | Verbindungsstück | PythonPart | Wartung_FFB | Plate | 0121Pyt0000008255 | Verbindungsstück | false | S101 | HI_PRO_STA_0,300x0,300 | 10.7 | 10.54 | 10.84 | 6.941 | 10.4 | 0.015 | 10.55 | 10.69 | 6.926 | 0
Verbindungsstück | Wartung_FFB | S235 | 0 | Verbindungsstück | PythonPart | Wartung_FFB | Plate | 0121Pyt0000008024 | Verbindungsstück | false | S101 | HI_PRO_STA_0,250x0,500 | 10.675 | 29.85 | 30.35 | 6.926 | 10.425 | 0.025 | 10.55 | 30.1 | 6.901 | 0
Verbindungsstück | Wartung_FFB | S235 | 0 | Verbindungsstück | PythonPart | Wartung_FFB | Plate | 0121Pyt0000008102 | Verbindungsstück | false | S101 | HI_PRO_STA_0,250x0,500 | 10.675 | 29.85 | 30.35 | 6.926 | 10.425 | 0.025 | 10.55 | 30.1 | 6.901 | 0
Verbindungsstück | Wartung_FFB | S235 | 0 | Verbindungsstück | PythonPart | Wartung_FFB | Plate | 0121Pyt0000008219 | Verbindungsstück | false | S101 | HI_PRO_STA_0,300x0,300 | 10.7 | 10.54 | 10.84 | 6.941 | 10.4 | 0.015 | 10.55 | 10.69 | 6.926 | 0
Verbindungsstück | Wartung_FFB | S235 | 0 | Verbindungsstück | PythonPart | Wartung_FFB | Plate | 0121Pyt0000008257 | Verbindungsstück | false | S101 | HI_PRO_STA_0,300x0,300 | 10.7 | 10.54 | 10.84 | 6.941 | 10.4 | 0.015 | 10.55 | 10.69 | 6.926 | 0
Verbindungsstück | Wartung_FFB | S235 | 0 | Verbindungsstück | PythonPart | Wartung_FFB | Plate | 0121Pyt0000008020 | Verbindungsstück | false | S101 | HI_PRO_STA_0,250x0,500 | 10.675 | 29.85 | 30.35 | 6.926 | 10.425 | 0.025 | 10.55 | 30.1 | 6.901 | 0
Verbindungsstück | Wartung_FFB | S235 | 0 | Verbindungsstück | PythonPart | Wartung_FFB | Plate | 0121Pyt0000008104 | Verbindungsstück | false | S101 | HI_PRO_STA_0,250x0,500 | 10.675 | 29.85 | 30.35 | 6.926 | 10.425 | 0.025 | 10.55 | 30.1 | 6.901 | 0
Verbindungsstück | Wartung_FFB | S235 | 0 | Verbindungsstück | PythonPart | Wartung_FFB | Plate | 0121Pyt0000008218 | Verbindungsstück | false | S101 | HI_PRO_STA_0,300x0,300 | 10.7 | 10.54 | 10.84 | 6.941 | 10.4 | 0.015 | 10.55 | 10.69 | 6.926 | 0
Verbindungsstück | Wartung_FFB | S235 | 0 | Verbindungsstück | PythonPart | Wartung_FFB | Plate | 0121Pyt0000008256 | Verbindungsstück | false | S101 | HI_PRO_STA_0,300x0,300 | 10.7 | 10.54 | 10.84 | 6.941 | 10.4 | 0.015 | 10.55 | 10.69 | 6.926 | 0
Verbindungsstück | Wartung_FFB | S235 | 0 | Verbindungsstück | PythonPart | Wartung_FFB | Plate | 0121Pyt0000008022 | Verbindungsstück | false | S101 | HI_PRO_STA_0,250x0,500 | 10.675 | 29.85 | 30.35 | 6.926 | 10.425 | 0.025 | 10.55 | 30.1 | 6.901 | 0
Verbindungsstück | Wartung_FFB | S235 | 0 | Verbindungsstück | PythonPart | Wartung_FFB | Plate | 0121Pyt0000008103 | Verbindungsstück | false | S101 | HI_PRO_STA_0,250x0,500 | 10.675 | 29.85 | 30.35 | 6.926 | 10.425 | 0.025 | 10.55 | 30.1 | 6.901 | 0
Verbindungsstück | Wartung_FFB | S235 | 0 | Verbindungsstück | PythonPart | Wartung_FFB | Plate | 0121Pyt0000015006 | Verbindungsstück | false | S101 | HI_PRO_STA_0,300x0,300 | 10.7 | 10.54 | 10.84 | 6.941 | 10.4 | 0.015 | 10.55 | 10.69 | 6.926 | 0
Verbindungsstück | Wartung_FFB | S235 | 0 | Verbindungsstück | PythonPart | Wartung_FFB | Plate | 0121Pyt0000015007 | Verbindungsstück | false | S101 | HI_PRO_STA_0,300x0,300 | 10.7 | 10.54 | 10.84 | 6.941 | 10.4 | 0.015 | 10.55 | 10.69 | 6.926 | 0
Verbindungsstück | Wartung_FFB | S235 | 0 | Verbindungsstück | PythonPart | Wartung_FFB | Plate | 0121Pyt0000015009 | Verbindungsstück | false | S101 | HI_PRO_STA_0,250x0,500 | 10.675 | 29.85 | 30.35 | 6.926 | 10.425 | 0.025 | 10.55 | 30.1 | 6.901 | 0
Verbindungsstück | Wartung_FFB | S235 | 0 | Verbindungsstück | PythonPart | Wartung_FFB | Plate | 0121Pyt0000015011 | Verbindungsstück | false | S101 | HI_PRO_STA_0,250x0,500 | 10.675 | 29.85 | 30.35 | 6.926 | 10.425 | 0.025 | 10.55 | 30.1 | 6.901 | 0
Verbindungsstück | Wartung_FFB | S235 | 0 | Verbindungsstück | PythonPart | Wartung_FFB | Plate | 0121Pyt0000008153 | Verbindungsstück | false | S101 | HI_PRO_STA_0,300x0,300 | 10.7 | 10.54 | 10.84 | 6.941 | 10.4 | 0.015 | 10.55 | 10.69 | 6.926 | 0
Verbindungsstück | Wartung_FFB | S235 | 0 | Verbindungsstück | PythonPart | Wartung_FFB | Plate | 0121Pyt0000007998 | Verbindungsstück | false | S101 | HI_PRO_STA_0,250x0,500 | 10.675 | 29.85 | 30.35 | 6.926 | 10.425 | 0.025 | 10.55 | 30.1 | 6.901 | 0
Verbindungsstück | Wartung_FFB | S235 | 0 | Verbindungsstück | PythonPart | Wartung_FFB | Plate | 0121Pyt0000008191 | Verbindungsstück | false | S101 | HI_PRO_STA_0,300x0,300 | 10.7 | 10.54 | 10.84 | 6.941 | 10.4 | 0.015 | 10.55 | 10.69 | 6.926 | 0
Verbindungsstück | Wartung_FFB | S235 | 0 | Verbindungsstück | PythonPart | Wartung_FFB | Plate | 0121Pyt0000008229 | Verbindungsstück | false | S101 | HI_PRO_STA_0,300x0,300 | 10.7 | 10.54 | 10.84 | 6.941 | 10.4 | 0.015 | 10.55 | 10.69 | 6.926 | 0
Verbindungsstück | Wartung_FFB | S235 | 0 | Verbindungsstück | PythonPart | Wartung_FFB | Plate | 0121Pyt0000008267 | Verbindungsstück | false | S101 | HI_PRO_STA_0,300x0,300 | 10.7 | 10.54 | 10.84 | 6.941 | 10.4 | 0.015 | 10.55 | 10.69 | 6.926 | 0
Verbindungsstück | Wartung_FFB | S235 | 0 | Verbindungsstück | PythonPart | Wartung_FFB | Plate | 0121Pyt0000008000 | Verbindungsstück | false | S101 | HI_PRO_STA_0,250x0,500 | 10.675 | 29.85 | 30.35 | 6.926 | 10.425 | 0.025 | 10.55 | 30.1 | 6.901 | 0
Verbindungsstück | Wartung_FFB | S235 | 0 | Verbindungsstück | PythonPart | Wartung_FFB | Plate | 0121Pyt0000007999 | Verbindungsstück | false | S101 | HI_PRO_STA_0,250x0,500 | 10.675 | 29.85 | 30.35 | 6.926 | 10.425 | 0.025 | 10.55 | 30.1 | 6.901 | 0
Verbindungsstück | Wartung_FFB | S235 | 0 | Verbindungsstück | PythonPart | Wartung_FFB | Plate | 0121Pyt0000008115 | Verbindungsstück | false | S101 | HI_PRO_STA_0,250x0,500 | 10.675 | 29.85 | 30.35 | 6.926 | 10.425 | 0.025 | 10.55 | 30.1 | 6.901 | 0
Verbindungsstück | Wartung_FFB | S235 | 0 | Verbindungsstück | PythonPart | Wartung_FFB | Plate | 0121Pyt0000015694 | Verbindungsstück | false | S101 | HI_PRO_STA_0,300x0,300 | 10.7 | 10.54 | 10.84 | 6.941 | 10.4 | 0.015 | 10.55 | 10.69 | 6.926 | 0
Verbindungsstück | Wartung_FFB | S235 | 0 | Verbindungsstück | PythonPart | Wartung_FFB | Plate | 0121Pyt0000015695 | Verbindungsstück | false | S101 | HI_PRO_STA_0,300x0,300 | 10.7 | 10.54 | 10.84 | 6.941 | 10.4 | 0.015 | 10.55 | 10.69 | 6.926 | 0
Verbindungsstück | Wartung_FFB | S235 | 0 | Verbindungsstück | PythonPart | Wartung_FFB | Plate | 0121Pyt0000015697 | Verbindungsstück | false | S101 | HI_PRO_STA_0,250x0,500 | 10.675 | 10.44 | 10.94 | 6.926 | 10.425 | 0.025 | 10.55 | 10.69 | 6.901 | 0
Verbindungsstück | Wartung_FFB | S235 | 0 | Verbindungsstück | PythonPart | Wartung_FFB | Plate | 0121Pyt0000015698 | Verbindungsstück | false | S101 | HI_PRO_STA_0,250x0,500 | 10.675 | 29.85 | 30.35 | 6.926 | 10.425 | 0.025 | 10.55 | 30.1 | 6.901 | 0
Stirnplatte | Wartung_FFB | S355 |  | Stirnplatte |  | Wartung_FFB | Plate | 0121Kop0000020453 | Stirnplatte | false | T101.1 | HI_PRO_STA_0,300x0,530x0,025 | PlateCommon - Feuerwiderstandsklasse: <undefiniert>; Schallschutzklasse: <undefiniert>
Stirnplatte | Wartung_FFB | S355 |  | Stirnplatte |  | Wartung_FFB | Plate | 0121Kop0000020518 | Stirnplatte | false | T101.1 | HI_PRO_STA_0,300x0,530x0,025 | PlateCommon - Feuerwiderstandsklasse: <undefiniert>; Schallschutzklasse: <undefiniert>
Stirnplatte | Wartung_FFB | S355 |  | Stirnplatte |  | Wartung_FFB | Plate | 0121Kop0000020519 | Stirnplatte | false | T101.1 | HI_PRO_STA_0,300x0,530x0,025 | PlateCommon - Feuerwiderstandsklasse: <undefiniert>; Schallschutzklasse: <undefiniert>
Stirnplatte | Wartung_FFB | S355 |  | Stirnplatte |  | Wartung_FFB | Plate | 0121Kop0000020520 | Stirnplatte | false | T101.1 | HI_PRO_STA_0,300x0,530x0,025 | PlateCommon - Feuerwiderstandsklasse: <undefiniert>; Schallschutzklasse: <undefiniert>
Verbindungsstück | Wartung_FFB | S235 | 0 | Verbindungsstück | PythonPart | Wartung_FFB | Plate | 0121Pyt0000007290 | Verbindungsstück | false | S101 | HI_PRO_STA_0,300x0,300 | 10.7 | 10.54 | 10.84 | 6.941 | 10.4 | 0.015 | 10.55 | 10.69 | 6.926 | 0
Verbindungsstück | Wartung_FFB | S235 | 0 | Verbindungsstück | PythonPart | Wartung_FFB | Plate | 0121Pyt0000007291 | Verbindungsstück | false | S101 | HI_PRO_STA_0,250x0,500 | 10.675 | 29.85 | 30.35 | 6.926 | 10.425 | 0.025 | 10.55 | 30.1 | 6.901 | 0
Verbindungsstück | Wartung_FFB | S235 | 0 | Verbindungsstück | PythonPart | Wartung_FFB | Plate | 0121Pyt0000007470 | Verbindungsstück | false | S101 | HI_PRO_STA_0,300x0,300 | 10.7 | 10.54 | 10.84 | 6.941 | 10.4 | 0.015 | 10.55 | 10.69 | 6.926 | 0
Verbindungsstück | Wartung_FFB | S235 | 0 | Verbindungsstück | PythonPart | Wartung_FFB | Plate | 0121Pyt0000007471 | Verbindungsstück | false | S101 | HI_PRO_STA_0,250x0,500 | 10.675 | 29.85 | 30.35 | 6.926 | 10.425 | 0.025 | 10.55 | 30.1 | 6.901 | 0
Stirnplatte | Wartung_FFB | S355 |  | Stirnplatte |  | Wartung_FFB | Plate | 0121Kop0000020630 | Stirnplatte | false | T101.1 | HI_PRO_STA_0,300x0,390x0,025 | PlateCommon - Feuerwiderstandsklasse: <undefiniert>; Schallschutzklasse: <undefiniert>
Stirnplatte | Wartung_FFB | S355 |  | Stirnplatte |  | Wartung_FFB | Plate | 0121Kop0000020631 | Stirnplatte | false | T101.1 | HI_PRO_STA_0,300x0,390x0,025 | PlateCommon - Feuerwiderstandsklasse: <undefiniert>; Schallschutzklasse: <undefiniert>
Verbindungsstück | Wartung_FFB | S235 | 0 | Verbindungsstück | PythonPart | Wartung_FFB | Plate | 0121Pyt0000008121 | Verbindungsstück | false | S101 | HI_PRO_STA_0,300x0,300 | 10.7 | 10.54 | 10.84 | 6.941 | 10.4 | 0.015 | 10.55 | 10.69 | 6.926 | 0
Verbindungsstück | Wartung_FFB | S235 | 0 | Verbindungsstück | PythonPart | Wartung_FFB | Plate | 0121Pyt0000007965 | Verbindungsstück | false | S101 | HI_PRO_STA_0,250x0,500 | 10.675 | 29.85 | 30.35 | 6.926 | 10.425 | 0.025 | 10.55 | 30.1 | 6.901 | 0
Verbindungsstück | Wartung_FFB | S235 | 0 | Verbindungsstück | PythonPart | Wartung_FFB | Plate | 0121Pyt0000008159 | Verbindungsstück | false | S101 | HI_PRO_STA_0,300x0,300 | 10.7 | 10.54 | 10.84 | 6.941 | 10.4 | 0.015 | 10.55 | 10.69 | 6.926 | 0
Verbindungsstück | Wartung_FFB | S235 | 0 | Verbindungsstück | PythonPart | Wartung_FFB | Plate | 0121Pyt0000008065 | Verbindungsstück | false | S101 | HI_PRO_STA_0,250x0,500 | 10.675 | 29.85 | 30.35 | 6.926 | 10.425 | 0.025 | 10.55 | 30.1 | 6.901 | 0
Stirnplatte | Wartung_FFB | S355 |  | Stirnplatte |  | Wartung_FFB | Plate | 0121Kop0000020389 | Stirnplatte | false | T101.1 | HI_PRO_STA_0,300x0,680x0,025 | PlateCommon - Feuerwiderstandsklasse: <undefiniert>; Schallschutzklasse: <undefiniert>
Stirnplatte | Wartung_FFB | S355 |  | Stirnplatte |  | Wartung_FFB | Plate | 0121Kop0000020390 | Stirnplatte | false | T101.1 | HI_PRO_STA_0,300x0,680x0,025 | PlateCommon - Feuerwiderstandsklasse: <undefiniert>; Schallschutzklasse: <undefiniert>
Stirnplatte | Wartung_FFB | S355 |  | Stirnplatte |  | Wartung_FFB | Plate | 0121Kop0000020391 | Stirnplatte | false | T101.1 | HI_PRO_STA_0,300x0,680x0,025 | PlateCommon - Feuerwiderstandsklasse: <undefiniert>; Schallschutzklasse: <undefiniert>
Stirnplatte | Wartung_FFB | S355 |  | Stirnplatte |  | Wartung_FFB | Plate | 0121Kop0000020392 | Stirnplatte | false | T101.1 | HI_PRO_STA_0,300x0,680x0,025 | PlateCommon - Feuerwiderstandsklasse: <undefiniert>; Schallschutzklasse: <undefiniert>
Stirnplatte | Wartung_FFB | S355 |  | Stirnplatte |  | Wartung_FFB | Plate | 0121Kop0000020710 | Stirnplatte | false | T101.1 | HI_PRO_STA_0,300x0,430x0,025 | PlateCommon - Feuerwiderstandsklasse: <undefiniert>; Schallschutzklasse: <undefiniert>
Stirnplatte | Wartung_FFB | S355 |  | Stirnplatte |  | Wartung_FFB | Plate | 0121Kop0000020711 | Stirnplatte | false | T101.1 | HI_PRO_STA_0,300x0,430x0,025 | PlateCommon - Feuerwiderstandsklasse: <undefiniert>; Schallschutzklasse: <undefiniert>
Verbindungsstück | Wartung_FFB | S235 | 0 | Verbindungsstück | PythonPart | Wartung_FFB | Plate | 0121Pyt0000007325 | Verbindungsstück | false | S101 | HI_PRO_STA_0,300x0,300 | 10.7 | 10.54 | 10.84 | 6.941 | 10.4 | 0.015 | 10.55 | 10.69 | 6.926 | 0
Verbindungsstück | Wartung_FFB | S235 | 0 | Verbindungsstück | PythonPart | Wartung_FFB | Plate | 0121Pyt0000007326 | Verbindungsstück | false | S101 | HI_PRO_STA_0,250x0,500 | 10.675 | 29.85 | 30.35 | 6.926 | 10.425 | 0.025 | 10.55 | 30.1 | 6.901 | 0
Verbindungsstück | Wartung_FFB | S235 | 0 | Verbindungsstück | PythonPart | Wartung_FFB | Plate | 0121Pyt0000008128 | Verbindungsstück | false | S101 | HI_PRO_STA_0,300x0,300 | 10.7 | 10.54 | 10.84 | 6.941 | 10.4 | 0.015 | 10.55 | 10.69 | 6.926 | 0
Verbindungsstück | Wartung_FFB | S235 | 0 | Verbindungsstück | PythonPart | Wartung_FFB | Plate | 0121Pyt0000007491 | Verbindungsstück | false | S101 | HI_PRO_STA_0,300x0,300 | 10.7 | 10.54 | 10.84 | 6.941 | 10.4 | 0.015 | 10.55 | 10.69 | 6.926 | 0
Verbindungsstück | Wartung_FFB | S235 | 0 | Verbindungsstück | PythonPart | Wartung_FFB | Plate | 0121Pyt0000007492 | Verbindungsstück | false | S101 | HI_PRO_STA_0,250x0,500 | 10.675 | 29.85 | 30.35 | 6.926 | 10.425 | 0.025 | 10.55 | 30.1 | 6.901 | 0
Verbindungsstück | Wartung_FFB | S235 | 0 | Verbindungsstück | PythonPart | Wartung_FFB | Plate | 0121Pyt0000007972 | Verbindungsstück | false | S101 | HI_PRO_STA_0,250x0,500 | 10.675 | 29.85 | 30.35 | 6.926 | 10.425 | 0.025 | 10.55 | 30.1 | 6.901 | 0
Verbindungsstück | Wartung_FFB | S235 | 0 | Verbindungsstück | PythonPart | Wartung_FFB | Plate | 0121Pyt0000008166 | Verbindungsstück | false | S101 | HI_PRO_STA_0,300x0,300 | 10.7 | 10.54 | 10.84 | 6.941 | 10.4 | 0.015 | 10.55 | 10.69 | 6.926 | 0
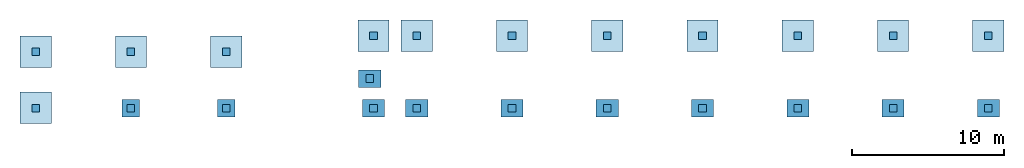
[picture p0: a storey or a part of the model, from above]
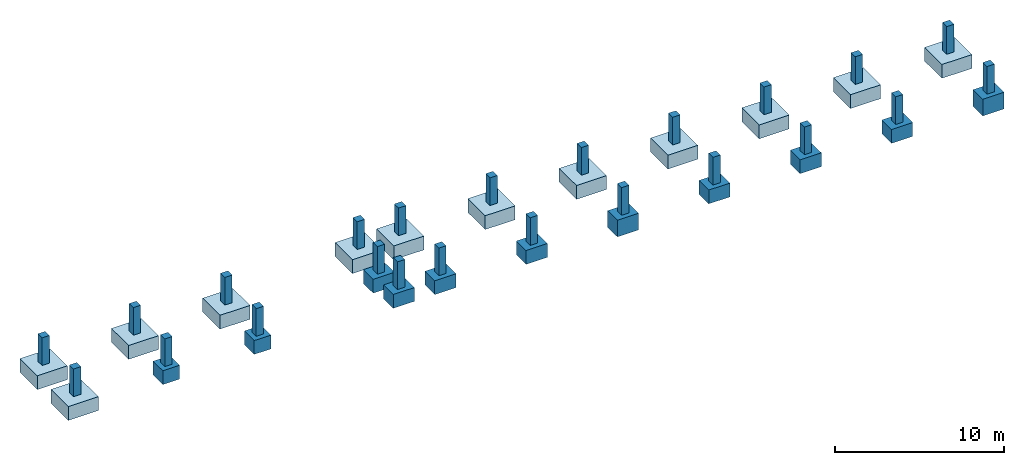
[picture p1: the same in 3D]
Properties of the parts of a building model (IFC2X3), part 21 of 25

# IfcPlate (1015)
Name | In | Material = AllplanAttributes, Material | V6 (m) = V7 (m) = V8 (m) = V9 | Bezeichnung | Plugin_Objektname | Ebene | Attributset-Objekt | Allright_Bauteil_ID | Name | Außenbauteil | Positionsnummer | PlateCommon, Reference | Unterkante (m) = X_Koordinate (m) | Oberkante (m) | Y_Koordinate (m) = Schwerpunkt_Y (m) | Z_Koordinate (m) = Schwerpunkt_Z (m) = Achsenstartpunkt (Z) (m) | Schwerpunkt_X (m) | Dicke (w) (m) | Achsenstartpunkt (X) (m) = Achsenendpunkt (X) (m) | Achsenstartpunkt (Y) (m) = Achsenendpunkt (Y) (m) | Achsenendpunkt (Z) (m) | Objektdrehwinkel
Verbindungsstück | Wartung_FFB | S235 | 0 | Verbindungsstück | PythonPart | Wartung_FFB | Plate | 0121Pyt0000008051 | Verbindungsstück | false | S101 | HI_PRO_STA_0,250x0,500 | 10.675 | 29.85 | 30.35 | 6.926 | 10.425 | 0.025 | 10.55 | 30.1 | 6.901 | 0
Stirnplatte | Wartung_FFB | S355 |  | Stirnplatte |  | Wartung_FFB | Plate | 0121Kop0000020601 | Stirnplatte | false | T101.1 | HI_PRO_STA_0,240x0,350x0,025 | PlateCommon - Feuerwiderstandsklasse: <undefiniert>; Schallschutzklasse: <undefiniert>
Stirnplatte | Wartung_FFB | S355 |  | Stirnplatte |  | Wartung_FFB | Plate | 0121Kop0000020606 | Stirnplatte | false | T101.1 | HI_PRO_STA_0,240x0,370x0,025 | PlateCommon - Feuerwiderstandsklasse: <undefiniert>; Schallschutzklasse: <undefiniert>
Stirnplatte | Wartung_FFB | S355 |  | Stirnplatte |  | Wartung_FFB | Plate | 0121Kop0000020609 | Stirnplatte | false | T101.1 | HI_PRO_STA_0,240x0,370x0,025 | PlateCommon - Feuerwiderstandsklasse: <undefiniert>; Schallschutzklasse: <undefiniert>
Verbindungsstück | Wartung_FFB | S235 | 0 | Verbindungsstück | PythonPart | Wartung_FFB | Plate | 0121Pyt0000008157 | Verbindungsstück | false | S101 | HI_PRO_STA_0,300x0,300 | 10.7 | 10.54 | 10.84 | 6.941 | 10.4 | 0.015 | 10.55 | 10.69 | 6.926 | 0
Verbindungsstück | Wartung_FFB | S235 | 0 | Verbindungsstück | PythonPart | Wartung_FFB | Plate | 0121Pyt0000008069 | Verbindungsstück | false | S101 | HI_PRO_STA_0,250x0,500 | 10.675 | 29.85 | 30.35 | 6.926 | 10.425 | 0.025 | 10.55 | 30.1 | 6.901 | 0
Stirnplatte | Wartung_FFB | S355 |  | Stirnplatte |  | Wartung_FFB | Plate | 0121Kop0000020927 | Stirnplatte | false | T101.1 | HI_PRO_STA_0,300x0,440x0,025 | PlateCommon - Feuerwiderstandsklasse: <undefiniert>; Schallschutzklasse: <undefiniert>
Stirnplatte | Wartung_FFB | S355 |  | Stirnplatte |  | Wartung_FFB | Plate | 0121Kop0000020928 | Stirnplatte | false | T101.1 | HI_PRO_STA_0,300x0,440x0,025 | PlateCommon - Feuerwiderstandsklasse: <undefiniert>; Schallschutzklasse: <undefiniert>
Verbindungsstück | Wartung_FFB | S235 | 0 | Verbindungsstück | PythonPart | Wartung_FFB | Plate | 0121Pyt0000008195 | Verbindungsstück | false | S101 | HI_PRO_STA_0,300x0,300 | 10.7 | 10.54 | 10.84 | 6.941 | 10.4 | 0.015 | 10.55 | 10.69 | 6.926 | 0
Verbindungsstück | Wartung_FFB | S235 | 0 | Verbindungsstück | PythonPart | Wartung_FFB | Plate | 0121Pyt0000008233 | Verbindungsstück | false | S101 | HI_PRO_STA_0,300x0,300 | 10.7 | 10.54 | 10.84 | 6.941 | 10.4 | 0.015 | 10.55 | 10.69 | 6.926 | 0
Verbindungsstück | Wartung_FFB | S235 | 0 | Verbindungsstück | PythonPart | Wartung_FFB | Plate | 0121Pyt0000008068 | Verbindungsstück | false | S101 | HI_PRO_STA_0,250x0,500 | 10.675 | 29.85 | 30.35 | 6.926 | 10.425 | 0.025 | 10.55 | 30.1 | 6.901 | 0
Verbindungsstück | Wartung_FFB | S235 | 0 | Verbindungsstück | PythonPart | Wartung_FFB | Plate | 0121Pyt0000008079 | Verbindungsstück | false | S101 | HI_PRO_STA_0,250x0,500 | 10.675 | 29.85 | 30.35 | 6.926 | 10.425 | 0.025 | 10.55 | 30.1 | 6.901 | 0
Stirnplatte | Wartung_FFB | S355 |  | Stirnplatte |  | Wartung_FFB | Plate | 0121Kop0000021088 | Stirnplatte | false | T101.1 | HI_PRO_STA_0,300x0,390x0,025 | PlateCommon - Feuerwiderstandsklasse: <undefiniert>; Schallschutzklasse: <undefiniert>
Stirnplatte | Wartung_FFB | S355 |  | Stirnplatte |  | Wartung_FFB | Plate | 0121Kop0000021089 | Stirnplatte | false | T101.1 | HI_PRO_STA_0,300x0,390x0,025 | PlateCommon - Feuerwiderstandsklasse: <undefiniert>; Schallschutzklasse: <undefiniert>
Verbindungsstück | Wartung_FFB | S235 | 0 | Verbindungsstück | PythonPart | Wartung_FFB | Plate | 0121Pyt0000008216 | Verbindungsstück | false | S101 | HI_PRO_STA_0,300x0,300 | 10.7 | 10.54 | 10.84 | 6.941 | 10.4 | 0.015 | 10.55 | 10.69 | 6.926 | 0
Verbindungsstück | Wartung_FFB | S235 | 0 | Verbindungsstück | PythonPart | Wartung_FFB | Plate | 0121Pyt0000008254 | Verbindungsstück | false | S101 | HI_PRO_STA_0,300x0,300 | 10.7 | 10.54 | 10.84 | 6.941 | 10.4 | 0.015 | 10.55 | 10.69 | 6.926 | 0
Verbindungsstück | Wartung_FFB | S235 | 0 | Verbindungsstück | PythonPart | Wartung_FFB | Plate | 0121Pyt0000008026 | Verbindungsstück | false | S101 | HI_PRO_STA_0,250x0,500 | 10.675 | 29.85 | 30.35 | 6.926 | 10.425 | 0.025 | 10.55 | 30.1 | 6.901 | 0
Verbindungsstück | Wartung_FFB | S235 | 0 | Verbindungsstück | PythonPart | Wartung_FFB | Plate | 0121Pyt0000008101 | Verbindungsstück | false | S101 | HI_PRO_STA_0,250x0,500 | 10.675 | 29.85 | 30.35 | 6.926 | 10.425 | 0.025 | 10.55 | 30.1 | 6.901 | 0
Stirnplatte | Wartung_FFB | S355 |  | Stirnplatte |  | Wartung_FFB | Plate | 0121Kop0000020885 | Stirnplatte | false | T101.1 | HI_PRO_STA_0,300x0,630x0,025 | PlateCommon - Feuerwiderstandsklasse: <undefiniert>; Schallschutzklasse: <undefiniert>
Stirnplatte | Wartung_FFB | S355 |  | Stirnplatte |  | Wartung_FFB | Plate | 0121Kop0000020886 | Stirnplatte | false | T101.1 | HI_PRO_STA_0,300x0,630x0,025 | PlateCommon - Feuerwiderstandsklasse: <undefiniert>; Schallschutzklasse: <undefiniert>
Stirnplatte | Wartung_FFB | S355 |  | Stirnplatte |  | Wartung_FFB | Plate | 0121Kop0000021140 | Stirnplatte | false | T101.1 | HI_PRO_STA_0,300x0,530x0,025 | PlateCommon - Feuerwiderstandsklasse: <undefiniert>; Schallschutzklasse: <undefiniert>
Stirnplatte | Wartung_FFB | S355 |  | Stirnplatte |  | Wartung_FFB | Plate | 0121Kop0000021141 | Stirnplatte | false | T101.1 | HI_PRO_STA_0,300x0,530x0,025 | PlateCommon - Feuerwiderstandsklasse: <undefiniert>; Schallschutzklasse: <undefiniert>
Verbindungsstück | Wartung_FFB | S235 | 0 | Verbindungsstück | PythonPart | Wartung_FFB | Plate | 0121Pyt0000008146 | Verbindungsstück | false | S101 | HI_PRO_STA_0,300x0,300 | 10.7 | 10.54 | 10.84 | 6.941 | 10.4 | 0.015 | 10.55 | 10.69 | 6.926 | 0
Verbindungsstück | Wartung_FFB | S235 | 0 | Verbindungsstück | PythonPart | Wartung_FFB | Plate | 0121Pyt0000007991 | Verbindungsstück | false | S101 | HI_PRO_STA_0,250x0,500 | 10.675 | 29.85 | 30.35 | 6.926 | 10.425 | 0.025 | 10.55 | 30.1 | 6.901 | 0
Verbindungsstück | Wartung_FFB | S235 | 0 | Verbindungsstück | PythonPart | Wartung_FFB | Plate | 0121Pyt0000008184 | Verbindungsstück | false | S101 | HI_PRO_STA_0,300x0,300 | 10.7 | 10.54 | 10.84 | 6.941 | 10.4 | 0.015 | 10.55 | 10.69 | 6.926 | 0
Verbindungsstück | Wartung_FFB | S235 | 0 | Verbindungsstück | PythonPart | Wartung_FFB | Plate | 0121Pyt0000008222 | Verbindungsstück | false | S101 | HI_PRO_STA_0,300x0,300 | 10.7 | 10.54 | 10.84 | 6.941 | 10.4 | 0.015 | 10.55 | 10.69 | 6.926 | 0
Verbindungsstück | Wartung_FFB | S235 | 0 | Verbindungsstück | PythonPart | Wartung_FFB | Plate | 0121Pyt0000008260 | Verbindungsstück | false | S101 | HI_PRO_STA_0,300x0,300 | 10.7 | 10.54 | 10.84 | 6.941 | 10.4 | 0.015 | 10.55 | 10.69 | 6.926 | 0
Verbindungsstück | Wartung_FFB | S235 | 0 | Verbindungsstück | PythonPart | Wartung_FFB | Plate | 0121Pyt0000008014 | Verbindungsstück | false | S101 | HI_PRO_STA_0,250x0,500 | 10.675 | 29.85 | 30.35 | 6.926 | 10.425 | 0.025 | 10.55 | 30.1 | 6.901 | 0
Verbindungsstück | Wartung_FFB | S235 | 0 | Verbindungsstück | PythonPart | Wartung_FFB | Plate | 0121Pyt0000008015 | Verbindungsstück | false | S101 | HI_PRO_STA_0,250x0,500 | 10.675 | 29.85 | 30.35 | 6.926 | 10.425 | 0.025 | 10.55 | 30.1 | 6.901 | 0
Verbindungsstück | Wartung_FFB | S235 | 0 | Verbindungsstück | PythonPart | Wartung_FFB | Plate | 0121Pyt0000008107 | Verbindungsstück | false | S101 | HI_PRO_STA_0,250x0,500 | 10.675 | 29.85 | 30.35 | 6.926 | 10.425 | 0.025 | 10.55 | 30.1 | 6.901 | 0

# IfcPlate: PLATE (279)
Material: S235
AllplanAttributes - Gewerk: Stahlbauarbeiten; Material: S235
IFC_Pset_TWP - Phase erstellt: Neubau; Material: Stahl; statisch tragend: true; Außenbauteil: true; Kommentar: -
Pset_FM-Vivantes - FM_Klasse: -; FM_Bezeichnung: -; FM_AKS: -; FM_Anzahl: -; FM_Standort: -; FM_Hersteller: -; FM_Hersteller-Typ: -; FM_Seriennummer: -; FM_Baujahr: -; FM_Inbetriebnahme Datum: -; FM_Gewährleistungsende: -; FM_Gewährleistungsgeber: -; FM_Betriebsstatus: -; FM_Prüfpflicht: -; FM_Prüfintervall: -; FM_letzter Prüfungstermin: -; FM_Sammelobjekt: -; FM_rechn. Lebensdauer: -; FM_rechn. Lebensende: -; FM_technischer Zustand: -; FM_voraus. Lebensende: -; FM_Eigentümer: -; FM_Bemerkung: -; FM_Versorgungsbereich-Wirkbereich: -; FM_Zugänglichkeit: -
Name | In | Bauteil-ID | V6 (m) = V7 (m) = V8 (m) = V9 | Länge (m) | Dicke (m) | Bezeichnung = Name | Plugin_Objektname | Breite (m) | Ebene | AllplanAttributes, Reference | Attributset-Objekt | Materialverwendung | Allright_Bauteil_ID | Abrechnungsart | Positionsnummer | Feuerwiderstandsklasse
Fußplatte | EG_Technik_FFB | 974 | 0 | 0.4 | 0.015 | Fußplatte | PythonPart | 0.4 | EG_Technik_FFB | HA_STV_ECK_xxx_STA_0,400x0,400_xxx | Platte | ToolboxPlate | 0103Pyt0000000998 | St | AQV01.1
Fußplatte | EG_Technik_FFB | 974 | 0 | 0.4 | 0.015 | Fußplatte | PythonPart | 0.4 | EG_Technik_FFB | HA_STV_ECK_xxx_STA_0,400x0,400_xxx | Platte | ToolboxPlate | 0103Pyt0000000974 | St | AQV01.1
Kopfplatte | EG_Technik_FFB | 977 | 0 | 0.29 | 0.015 | Kopfplatte | PythonPart | 0.3 | EG_Technik_FFB | HA_STV_ECK_xxx_STA_0,290x0,300_xxx | Platte | ToolboxPlate | 0103Pyt0000001000 | St | AQV01.1
Kopfplatte | EG_Technik_FFB | 977 | 0 | 0.29 | 0.015 | Kopfplatte | PythonPart | 0.3 | EG_Technik_FFB | HA_STV_ECK_xxx_STA_0,290x0,300_xxx | Platte | ToolboxPlate | 0103Pyt0000000977 | St | AQV01.1
Fußplatte | EG_Technik_FFB | 974 | 0 | 0.4 | 0.015 | Fußplatte | PythonPart | 0.4 | EG_Technik_FFB | HA_STV_ECK_xxx_STA_0,400x0,400_xxx | Platte | ToolboxPlate | 0103Pyt0000004003 | St | AQV01.1
Fußplatte | EG_Technik_FFB | 974 | 0 | 0.4 | 0.015 | Fußplatte | PythonPart | 0.4 | EG_Technik_FFB | HA_STV_ECK_xxx_STA_0,400x0,400_xxx | Platte | ToolboxPlate | 0103Pyt0000004004 | St | AQV01.1
Kopfplatte | EG_Technik_FFB | 977 | 0 | 0.29 | 0.015 | Kopfplatte | PythonPart | 0.3 | EG_Technik_FFB | HA_STV_ECK_xxx_STA_0,290x0,300_xxx | Platte | ToolboxPlate | 0103Pyt0000004009 | St | AQV01.1
Kopfplatte | EG_Technik_FFB | 977 | 0 | 0.29 | 0.015 | Kopfplatte | PythonPart | 0.3 | EG_Technik_FFB | HA_STV_ECK_xxx_STA_0,290x0,300_xxx | Platte | ToolboxPlate | 0103Pyt0000004010 | St | AQV01.1
Fußplatte | EG_Technik_FFB | 974 | 0 | 0.4 | 0.015 | Fußplatte | PythonPart | 0.4 | EG_Technik_FFB | HA_STV_ECK_xxx_STA_0,400x0,400_xxx | Platte | ToolboxPlate | 0103Pyt0000004035 | St | AQV01.1
Fußplatte | EG_Technik_FFB | 974 | 0 | 0.4 | 0.015 | Fußplatte | PythonPart | 0.4 | EG_Technik_FFB | HA_STV_ECK_xxx_STA_0,400x0,400_xxx | Platte | ToolboxPlate | 0103Pyt0000004036 | St | AQV01.1
Kopfplatte | EG_Technik_FFB | 977 | 0 | 0.29 | 0.015 | Kopfplatte | PythonPart | 0.3 | EG_Technik_FFB | HA_STV_ECK_xxx_STA_0,290x0,300_xxx | Platte | ToolboxPlate | 0103Pyt0000004041 | St | AQV01.1
Kopfplatte | EG_Technik_FFB | 977 | 0 | 0.29 | 0.015 | Kopfplatte | PythonPart | 0.3 | EG_Technik_FFB | HA_STV_ECK_xxx_STA_0,290x0,300_xxx | Platte | ToolboxPlate | 0103Pyt0000004042 | St | AQV01.1
Fußplatte | EG_Technik_FFB | 974 | 0 | 0.4 | 0.015 | Fußplatte | PythonPart | 0.4 | EG_Technik_FFB | HA_STV_ECK_xxx_STA_0,400x0,400_xxx | Platte | ToolboxPlate | 0103Pyt0000004077 | St | AQV01.1
Fußplatte | EG_Technik_FFB | 974 | 0 | 0.4 | 0.015 | Fußplatte | PythonPart | 0.4 | EG_Technik_FFB | HA_STV_ECK_xxx_STA_0,400x0,400_xxx | Platte | ToolboxPlate | 0103Pyt0000004078 | St | AQV01.1
Kopfplatte | EG_Technik_FFB | 977 | 0 | 0.29 | 0.015 | Kopfplatte | PythonPart | 0.3 | EG_Technik_FFB | HA_STV_ECK_xxx_STA_0,290x0,300_xxx | Platte | ToolboxPlate | 0103Pyt0000004083 | St | AQV01.1
Kopfplatte | EG_Technik_FFB | 977 | 0 | 0.29 | 0.015 | Kopfplatte | PythonPart | 0.3 | EG_Technik_FFB | HA_STV_ECK_xxx_STA_0,290x0,300_xxx | Platte | ToolboxPlate | 0103Pyt0000004084 | St | AQV01.1
Fußplatte | EG_Technik_FFB | 974 | 0 | 0.4 | 0.015 | Fußplatte | PythonPart | 0.4 | EG_Technik_FFB | HA_STV_ECK_xxx_STA_0,400x0,400_xxx | Platte | ToolboxPlate | 0103Pyt0000004119 | St | AQV01.1
Fußplatte | EG_Technik_FFB | 974 | 0 | 0.4 | 0.015 | Fußplatte | PythonPart | 0.4 | EG_Technik_FFB | HA_STV_ECK_xxx_STA_0,400x0,400_xxx | Platte | ToolboxPlate | 0103Pyt0000004120 | St | AQV01.1
Kopfplatte | EG_Technik_FFB | 977 | 0 | 0.29 | 0.015 | Kopfplatte | PythonPart | 0.3 | EG_Technik_FFB | HA_STV_ECK_xxx_STA_0,290x0,300_xxx | Platte | ToolboxPlate | 0103Pyt0000004125 | St | AQV01.1
Kopfplatte | EG_Technik_FFB | 977 | 0 | 0.29 | 0.015 | Kopfplatte | PythonPart | 0.3 | EG_Technik_FFB | HA_STV_ECK_xxx_STA_0,290x0,300_xxx | Platte | ToolboxPlate | 0103Pyt0000004126 | St | AQV01.1
Fußplatte | EG_Technik_FFB | 974 | 0 | 0.4 | 0.015 | Fußplatte | PythonPart | 0.4 | EG_Technik_FFB | HA_STV_ECK_xxx_STA_0,400x0,400_xxx | Platte | ToolboxPlate | 0103Pyt0000004161 | St | AQV01.1
Fußplatte | EG_Technik_FFB | 974 | 0 | 0.4 | 0.015 | Fußplatte | PythonPart | 0.4 | EG_Technik_FFB | HA_STV_ECK_xxx_STA_0,400x0,400_xxx | Platte | ToolboxPlate | 0103Pyt0000004162 | St | AQV01.1
Kopfplatte | EG_Technik_FFB | 977 | 0 | 0.29 | 0.015 | Kopfplatte | PythonPart | 0.3 | EG_Technik_FFB | HA_STV_ECK_xxx_STA_0,290x0,300_xxx | Platte | ToolboxPlate | 0103Pyt0000004167 | St | AQV01.1
Kopfplatte | EG_Technik_FFB | 977 | 0 | 0.29 | 0.015 | Kopfplatte | PythonPart | 0.3 | EG_Technik_FFB | HA_STV_ECK_xxx_STA_0,290x0,300_xxx | Platte | ToolboxPlate | 0103Pyt0000004168 | St | AQV01.1
Fußplatte | EG_Technik_FFB | 974 | 0 | 0.4 | 0.015 | Fußplatte | PythonPart | 0.4 | EG_Technik_FFB | HA_STV_ECK_xxx_STA_0,400x0,400_xxx | Platte | ToolboxPlate | 0103Pyt0000004203 | St | AQV01.1
Fußplatte | EG_Technik_FFB | 974 | 0 | 0.4 | 0.015 | Fußplatte | PythonPart | 0.4 | EG_Technik_FFB | HA_STV_ECK_xxx_STA_0,400x0,400_xxx | Platte | ToolboxPlate | 0103Pyt0000004204 | St | AQV01.1
Kopfplatte | EG_Technik_FFB | 977 | 0 | 0.29 | 0.015 | Kopfplatte | PythonPart | 0.3 | EG_Technik_FFB | HA_STV_ECK_xxx_STA_0,290x0,300_xxx | Platte | ToolboxPlate | 0103Pyt0000004209 | St | AQV01.1
Kopfplatte | EG_Technik_FFB | 977 | 0 | 0.29 | 0.015 | Kopfplatte | PythonPart | 0.3 | EG_Technik_FFB | HA_STV_ECK_xxx_STA_0,290x0,300_xxx | Platte | ToolboxPlate | 0103Pyt0000004210 | St | AQV01.1
Fußplatte | EG_Technik_FFB | 974 | 0 | 0.4 | 0.015 | Fußplatte | PythonPart | 0.4 | EG_Technik_FFB | HA_STV_ECK_xxx_STA_0,400x0,400_xxx | Platte | ToolboxPlate | 0103Pyt0000004245 | St | AQV01.2
Fußplatte | EG_Technik_FFB | 974 | 0 | 0.4 | 0.015 | Fußplatte | PythonPart | 0.4 | EG_Technik_FFB | HA_STV_ECK_xxx_STA_0,400x0,400_xxx | Platte | ToolboxPlate | 0103Pyt0000004246 | St | AQV01.2
Kopfplatte | EG_Technik_FFB | 977 | 0 | 0.29 | 0.015 | Kopfplatte | PythonPart | 0.3 | EG_Technik_FFB | HA_STV_ECK_xxx_STA_0,290x0,300_xxx | Platte | ToolboxPlate | 0103Pyt0000004251 | St | AQV01.2
Kopfplatte | EG_Technik_FFB | 977 | 0 | 0.29 | 0.015 | Kopfplatte | PythonPart | 0.3 | EG_Technik_FFB | HA_STV_ECK_xxx_STA_0,290x0,300_xxx | Platte | ToolboxPlate | 0103Pyt0000004252 | St | AQV01.2
Fußplatte | EG_Technik_FFB | 977 | 0 | 0.2 | 0.015 | Fußplatte | PythonPart | 0.19 | EG_Technik_FFB | HA_STV_ECK_xxx_STA_0,190x0,200_xxx | Platte | ToolboxPlate | 0103Pyt0000002134 | St | AQV01.3 | <undefiniert>
Fußplatte | EG_Technik_FFB | 977 | 0 | 0.2 | 0.015 | Fußplatte | PythonPart | 0.19 | EG_Technik_FFB | HA_STV_ECK_xxx_STA_0,190x0,200_xxx | Platte | ToolboxPlate | 0103Pyt0000002151 | St | AQV01.3 | <undefiniert>
Kragarm | EG_Technik_FFB | 1282 | 0 | 0.2 | 0.015 | Kragarm | PythonPart | 0.29 | EG_Technik_FFB | HA_STV_ECK_xxx_STA_0,200x0,300_xxx | Platte | ToolboxPlate | 0103Pyt0000002191 | St | AT01.2 | <undefiniert>
Kragarm | EG_Technik_FFB | 1282 | 0 | 0.2 | 0.015 | Kragarm | PythonPart | 0.29 | EG_Technik_FFB | HA_STV_ECK_xxx_STA_0,200x0,300_xxx | Platte | ToolboxPlate | 0103Pyt0000002192 | St | AT01.2 | <undefiniert>
Kragarm | EG_Technik_FFB | 1282 | 0 | 0.2 | 0.015 | Kragarm | PythonPart | 0.29 | EG_Technik_FFB | HA_STV_ECK_xxx_STA_0,200x0,300_xxx | Platte | ToolboxPlate | 0103Pyt0000002194 | St | AT01.2 | <undefiniert>
Kragarm | EG_Technik_FFB | 1282 | 0 | 0.2 | 0.015 | Kragarm | PythonPart | 0.29 | EG_Technik_FFB | HA_STV_ECK_xxx_STA_0,200x0,300_xxx | Platte | ToolboxPlate | 0103Pyt0000002195 | St | AT01.2 | <undefiniert>
Kragarm | EG_Technik_FFB | 1282 | 0 | 0.2 | 0.015 | Kragarm | PythonPart | 0.29 | EG_Technik_FFB | HA_STV_ECK_xxx_STA_0,200x0,300_xxx | Platte | ToolboxPlate | 0103Pyt0000002199 | St | AT01.2 | <undefiniert>
Kragarm | EG_Technik_FFB | 1282 | 0 | 0.2 | 0.015 | Kragarm | PythonPart | 0.29 | EG_Technik_FFB | HA_STV_ECK_xxx_STA_0,200x0,300_xxx | Platte | ToolboxPlate | 0103Pyt0000002200 | St | AT01.2 | <undefiniert>
Kragarm | EG_Technik_FFB | 1282 | 0 | 0.2 | 0.015 | Kragarm | PythonPart | 0.29 | EG_Technik_FFB | HA_STV_ECK_xxx_STA_0,200x0,300_xxx | Platte | ToolboxPlate | 0103Pyt0000002204 | St | AT01.2 | <undefiniert>
Kragarm | EG_Technik_FFB | 1282 | 0 | 0.2 | 0.015 | Kragarm | PythonPart | 0.29 | EG_Technik_FFB | HA_STV_ECK_xxx_STA_0,200x0,300_xxx | Platte | ToolboxPlate | 0103Pyt0000002205 | St | AT01.2 | <undefiniert>
Kragarm | EG_Technik_FFB | 1282 | 0 | 0.2 | 0.015 | Kragarm | PythonPart | 0.29 | EG_Technik_FFB | HA_STV_ECK_xxx_STA_0,200x0,300_xxx | Platte | ToolboxPlate | 0103Pyt0000002209 | St | AT01.2 | <undefiniert>
Kragarm | EG_Technik_FFB | 1282 | 0 | 0.2 | 0.015 | Kragarm | PythonPart | 0.29 | EG_Technik_FFB | HA_STV_ECK_xxx_STA_0,200x0,300_xxx | Platte | ToolboxPlate | 0103Pyt0000002210 | St | AT01.2 | <undefiniert>
Kragarm | EG_Technik_FFB | 1282 | 0 | 0.2 | 0.015 | Kragarm | PythonPart | 0.29 | EG_Technik_FFB | HA_STV_ECK_xxx_STA_0,200x0,300_xxx | Platte | ToolboxPlate | 0103Pyt0000002214 | St | AT01.2 | <undefiniert>
Kragarm | EG_Technik_FFB | 1282 | 0 | 0.2 | 0.015 | Kragarm | PythonPart | 0.29 | EG_Technik_FFB | HA_STV_ECK_xxx_STA_0,200x0,300_xxx | Platte | ToolboxPlate | 0103Pyt0000002215 | St | AT01.2 | <undefiniert>
Kragarm | EG_Technik_FFB | 1282 | 0 | 0.2 | 0.015 | Kragarm | PythonPart | 0.29 | EG_Technik_FFB | HA_STV_ECK_xxx_STA_0,200x0,300_xxx | Platte | ToolboxPlate | 0103Pyt0000002219 | St | AT01.2 | <undefiniert>
Kragarm | EG_Technik_FFB | 1282 | 0 | 0.2 | 0.015 | Kragarm | PythonPart | 0.29 | EG_Technik_FFB | HA_STV_ECK_xxx_STA_0,200x0,300_xxx | Platte | ToolboxPlate | 0103Pyt0000002220 | St | AT01.2 | <undefiniert>
Kragarm | EG_Technik_FFB | 1282 | 0 | 0.2 | 0.015 | Kragarm | PythonPart | 0.29 | EG_Technik_FFB | HA_STV_ECK_xxx_STA_0,200x0,300_xxx | Platte | ToolboxPlate | 0103Pyt0000002224 | St | AT01.2 | <undefiniert>
Kragarm | EG_Technik_FFB | 1282 | 0 | 0.2 | 0.015 | Kragarm | PythonPart | 0.29 | EG_Technik_FFB | HA_STV_ECK_xxx_STA_0,200x0,300_xxx | Platte | ToolboxPlate | 0103Pyt0000002225 | St | AT01.2 | <undefiniert>
Stirnplatte | EG_Technik_FFB | 1282 | 0 | 0.07 | 0.015 | Stirnplatte | PythonPart | 0.19 | EG_Technik_FFB | HA_STV_ECK_xxx_STA_0,070x0,190_xxx | Platte | ToolboxPlate | 0103Pyt0000002390 | St | AT01.1 | <undefiniert>
Stirnplatte | EG_Technik_FFB | 1282 | 0 | 0.07 | 0.015 | Stirnplatte | PythonPart | 0.19 | EG_Technik_FFB | HA_STV_ECK_xxx_STA_0,070x0,190_xxx | Platte | ToolboxPlate | 0103Pyt0000002393 | St | AT01.1 | <undefiniert>
Stirnplatte | EG_Technik_FFB | 1282 | 0 | 0.07 | 0.015 | Stirnplatte | PythonPart | 0.19 | EG_Technik_FFB | HA_STV_ECK_xxx_STA_0,070x0,190_xxx | Platte | ToolboxPlate | 0103Pyt0000002396 | St | AT01.1 | <undefiniert>
Stirnplatte | EG_Technik_FFB | 1282 | 0 | 0.07 | 0.015 | Stirnplatte | PythonPart | 0.19 | EG_Technik_FFB | HA_STV_ECK_xxx_STA_0,070x0,190_xxx | Platte | ToolboxPlate | 0103Pyt0000002399 | St | AT01.1 | <undefiniert>
Stirnplatte | EG_Technik_FFB | 1282 | 0 | 0.07 | 0.015 | Stirnplatte | PythonPart | 0.19 | EG_Technik_FFB | HA_STV_ECK_xxx_STA_0,070x0,190_xxx | Platte | ToolboxPlate | 0103Pyt0000002402 | St | AT01.1 | <undefiniert>
Stirnplatte | EG_Technik_FFB | 1282 | 0 | 0.07 | 0.015 | Stirnplatte | PythonPart | 0.19 | EG_Technik_FFB | HA_STV_ECK_xxx_STA_0,070x0,190_xxx | Platte | ToolboxPlate | 0103Pyt0000002405 | St | AT01.1 | <undefiniert>
Stirnplatte | EG_Technik_FFB | 1282 | 0 | 0.07 | 0.015 | Stirnplatte | PythonPart | 0.19 | EG_Technik_FFB | HA_STV_ECK_xxx_STA_0,070x0,190_xxx | Platte | ToolboxPlate | 0103Pyt0000002408 | St | AT01.1 | <undefiniert>
Stirnplatte | EG_Technik_FFB | 1282 | 0 | 0.07 | 0.015 | Stirnplatte | PythonPart | 0.19 | EG_Technik_FFB | HA_STV_ECK_xxx_STA_0,070x0,190_xxx | Platte | ToolboxPlate | 0103Pyt0000002411 | St | AT01.1 | <undefiniert>
Stirnplatte | EG_Technik_FFB | 1282 | 0 | 0.07 | 0.015 | Stirnplatte | PythonPart | 0.19 | EG_Technik_FFB | HA_STV_ECK_xxx_STA_0,070x0,190_xxx | Platte | ToolboxPlate | 0103Pyt0000002414 | St | AT01.1 | <undefiniert>
Stirnplatte | EG_Technik_FFB | 1282 | 0 | 0.07 | 0.015 | Stirnplatte | PythonPart | 0.19 | EG_Technik_FFB | HA_STV_ECK_xxx_STA_0,070x0,190_xxx | Platte | ToolboxPlate | 0103Pyt0000002417 | St | AT01.1 | <undefiniert>
Stirnplatte | EG_Technik_FFB | 1282 | 0 | 0.07 | 0.015 | Stirnplatte | PythonPart | 0.19 | EG_Technik_FFB | HA_STV_ECK_xxx_STA_0,070x0,190_xxx | Platte | ToolboxPlate | 0103Pyt0000002420 | St | AT01.1 | <undefiniert>
Stirnplatte | EG_Technik_FFB | 1282 | 0 | 0.07 | 0.015 | Stirnplatte | PythonPart | 0.19 | EG_Technik_FFB | HA_STV_ECK_xxx_STA_0,070x0,190_xxx | Platte | ToolboxPlate | 0103Pyt0000002423 | St | AT01.1 | <undefiniert>
Stirnplatte | EG_Technik_FFB | 1282 | 0 | 0.07 | 0.015 | Stirnplatte | PythonPart | 0.19 | EG_Technik_FFB | HA_STV_ECK_xxx_STA_0,070x0,190_xxx | Platte | ToolboxPlate | 0103Pyt0000002426 | St | AT01.1 | <undefiniert>
Stirnplatte | EG_Technik_FFB | 1282 | 0 | 0.07 | 0.015 | Stirnplatte | PythonPart | 0.19 | EG_Technik_FFB | HA_STV_ECK_xxx_STA_0,070x0,190_xxx | Platte | ToolboxPlate | 0103Pyt0000002429 | St | AT01.1 | <undefiniert>
Stirnplatte | EG_Technik_FFB | 1282 | 0 | 0.07 | 0.015 | Stirnplatte | PythonPart | 0.19 | EG_Technik_FFB | HA_STV_ECK_xxx_STA_0,070x0,190_xxx | Platte | ToolboxPlate | 0103Pyt0000002432 | St | AT01.1 | <undefiniert>
Stirnplatte | EG_Technik_FFB | 1282 | 0 | 0.07 | 0.015 | Stirnplatte | PythonPart | 0.19 | EG_Technik_FFB | HA_STV_ECK_xxx_STA_0,070x0,190_xxx | Platte | ToolboxPlate | 0103Pyt0000002435 | St | AT01.1 | <undefiniert>
Stirnplatte | EG_Technik_FFB | 1282 | 0 | 0.07 | 0.015 | Stirnplatte | PythonPart | 0.19 | EG_Technik_FFB | HA_STV_ECK_xxx_STA_0,070x0,190_xxx | Platte | ToolboxPlate | 0103Pyt0000002438 | St | AT01.1 | <undefiniert>
Stirnplatte | EG_Technik_FFB | 1282 | 0 | 0.07 | 0.015 | Stirnplatte | PythonPart | 0.19 | EG_Technik_FFB | HA_STV_ECK_xxx_STA_0,070x0,190_xxx | Platte | ToolboxPlate | 0103Pyt0000002441 | St | AT01.1 | <undefiniert>
Stirnplatte | EG_Technik_FFB | 1282 | 0 | 0.07 | 0.015 | Stirnplatte | PythonPart | 0.19 | EG_Technik_FFB | HA_STV_ECK_xxx_STA_0,070x0,190_xxx | Platte | ToolboxPlate | 0103Pyt0000002444 | St | AT01.1 | <undefiniert>
Stirnplatte | EG_Technik_FFB | 1282 | 0 | 0.07 | 0.015 | Stirnplatte | PythonPart | 0.19 | EG_Technik_FFB | HA_STV_ECK_xxx_STA_0,070x0,190_xxx | Platte | ToolboxPlate | 0103Pyt0000002447 | St | AT01.1 | <undefiniert>
Stirnplatte | EG_Technik_FFB | 1282 | 0 | 0.07 | 0.015 | Stirnplatte | PythonPart | 0.19 | EG_Technik_FFB | HA_STV_ECK_xxx_STA_0,070x0,190_xxx | Platte | ToolboxPlate | 0103Pyt0000002450 | St | AT01.1 | <undefiniert>
Stirnplatte | EG_Technik_FFB | 1282 | 0 | 0.07 | 0.015 | Stirnplatte | PythonPart | 0.19 | EG_Technik_FFB | HA_STV_ECK_xxx_STA_0,070x0,190_xxx | Platte | ToolboxPlate | 0103Pyt0000002453 | St | AT01.1 | <undefiniert>
Stirnplatte | EG_Technik_FFB | 1282 | 0 | 0.07 | 0.015 | Stirnplatte | PythonPart | 0.19 | EG_Technik_FFB | HA_STV_ECK_xxx_STA_0,070x0,190_xxx | Platte | ToolboxPlate | 0103Pyt0000002456 | St | AT01.1 | <undefiniert>
Stirnplatte | EG_Technik_FFB | 1282 | 0 | 0.07 | 0.015 | Stirnplatte | PythonPart | 0.19 | EG_Technik_FFB | HA_STV_ECK_xxx_STA_0,070x0,190_xxx | Platte | ToolboxPlate | 0103Pyt0000002459 | St | AT01.1 | <undefiniert>
Stirnplatte | EG_Technik_FFB | 1282 | 0 | 0.07 | 0.015 | Stirnplatte | PythonPart | 0.19 | EG_Technik_FFB | HA_STV_ECK_xxx_STA_0,070x0,190_xxx | Platte | ToolboxPlate | 0103Pyt0000002462 | St | AT01.1 | <undefiniert>
Stirnplatte | EG_Technik_FFB | 1282 | 0 | 0.07 | 0.015 | Stirnplatte | PythonPart | 0.19 | EG_Technik_FFB | HA_STV_ECK_xxx_STA_0,070x0,190_xxx | Platte | ToolboxPlate | 0103Pyt0000002465 | St | AT01.1 | <undefiniert>
Stirnplatte | EG_Technik_FFB | 1282 | 0 | 0.07 | 0.015 | Stirnplatte | PythonPart | 0.19 | EG_Technik_FFB | HA_STV_ECK_xxx_STA_0,070x0,190_xxx | Platte | ToolboxPlate | 0103Pyt0000002468 | St | AT01.1 | <undefiniert>
Stirnplatte | EG_Technik_FFB | 1282 | 0 | 0.07 | 0.015 | Stirnplatte | PythonPart | 0.19 | EG_Technik_FFB | HA_STV_ECK_xxx_STA_0,070x0,190_xxx | Platte | ToolboxPlate | 0103Pyt0000002471 | St | AT01.1 | <undefiniert>
Stirnplatte | EG_Technik_FFB | 1282 | 0 | 0.2 | 0.015 | Stirnplatte | PythonPart | 0.29 | EG_Technik_FFB | HA_STV_ECK_xxx_STA_0,200x0,300_xxx | Platte | ToolboxPlate | 0103Pyt0000001301 | St | AT01 | <undefiniert>
Stirnplatte | EG_Technik_FFB | 1282 | 0 | 0.2 | 0.015 | Stirnplatte | PythonPart | 0.29 | EG_Technik_FFB | HA_STV_ECK_xxx_STA_0,200x0,300_xxx | Platte | ToolboxPlate | 0103Pyt0000001302 | St | AT01 | <undefiniert>
Stirnplatte | EG_Technik_FFB | 1282 | 0 | 0.2 | 0.015 | Stirnplatte | PythonPart | 0.29 | EG_Technik_FFB | HA_STV_ECK_xxx_STA_0,200x0,300_xxx | Platte | ToolboxPlate | 0103Pyt0000001299 | St | AT01 | <undefiniert>
Stirnplatte | EG_Technik_FFB | 1282 | 0 | 0.2 | 0.015 | Stirnplatte | PythonPart | 0.29 | EG_Technik_FFB | HA_STV_ECK_xxx_STA_0,200x0,300_xxx | Platte | ToolboxPlate | 0103Pyt0000001300 | St | AT01 | <undefiniert>
Stirnplatte | EG_Technik_FFB | 1282 | 0 | 0.2 | 0.015 | Stirnplatte | PythonPart | 0.29 | EG_Technik_FFB | HA_STV_ECK_xxx_STA_0,200x0,300_xxx | Platte | ToolboxPlate | 0103Pyt0000001289 | St | AT01 | <undefiniert>
Stirnplatte | EG_Technik_FFB | 1282 | 0 | 0.2 | 0.015 | Stirnplatte | PythonPart | 0.29 | EG_Technik_FFB | HA_STV_ECK_xxx_STA_0,200x0,300_xxx | Platte | ToolboxPlate | 0103Pyt0000001290 | St | AT01 | <undefiniert>
Stirnplatte | EG_Technik_FFB | 1282 | 0 | 0.2 | 0.015 | Stirnplatte | PythonPart | 0.29 | EG_Technik_FFB | HA_STV_ECK_xxx_STA_0,200x0,300_xxx | Platte | ToolboxPlate | 0103Pyt0000001282 | St | AT01 | <undefiniert>
Stirnplatte | EG_Technik_FFB | 1282 | 0 | 0.2 | 0.015 | Stirnplatte | PythonPart | 0.29 | EG_Technik_FFB | HA_STV_ECK_xxx_STA_0,200x0,300_xxx | Platte | ToolboxPlate | 0103Pyt0000001288 | St | AT01 | <undefiniert>
Stirnplatte | EG_Technik_FFB | 1282 | 0 | 0.2 | 0.015 | Stirnplatte | PythonPart | 0.29 | EG_Technik_FFB | HA_STV_ECK_xxx_STA_0,200x0,300_xxx | Platte | ToolboxPlate | 0103Pyt0000002576 | St | AT01 | <undefiniert>
Stirnplatte | EG_Technik_FFB | 1282 | 0 | 0.2 | 0.015 | Stirnplatte | PythonPart | 0.29 | EG_Technik_FFB | HA_STV_ECK_xxx_STA_0,200x0,300_xxx | Platte | ToolboxPlate | 0103Pyt0000002577 | St | AT01 | <undefiniert>
Stirnplatte | EG_Technik_FFB | 1282 | 0 | 0.2 | 0.015 | Stirnplatte | PythonPart | 0.29 | EG_Technik_FFB | HA_STV_ECK_xxx_STA_0,200x0,300_xxx | Platte | ToolboxPlate | 0103Pyt0000002578 | St | AT01 | <undefiniert>
Stirnplatte | EG_Technik_FFB | 1282 | 0 | 0.2 | 0.015 | Stirnplatte | PythonPart | 0.29 | EG_Technik_FFB | HA_STV_ECK_xxx_STA_0,200x0,300_xxx | Platte | ToolboxPlate | 0103Pyt0000002579 | St | AT01 | <undefiniert>
Stirnplatte | EG_Technik_FFB | 1282 | 0 | 0.2 | 0.015 | Stirnplatte | PythonPart | 0.29 | EG_Technik_FFB | HA_STV_ECK_xxx_STA_0,200x0,300_xxx | Platte | ToolboxPlate | 0103Pyt0000002583 | St | AT01 | <undefiniert>
Stirnplatte | EG_Technik_FFB | 1282 | 0 | 0.2 | 0.015 | Stirnplatte | PythonPart | 0.29 | EG_Technik_FFB | HA_STV_ECK_xxx_STA_0,200x0,300_xxx | Platte | ToolboxPlate | 0103Pyt0000002584 | St | AT01 | <undefiniert>
Stirnplatte | EG_Technik_FFB | 1282 | 0 | 0.2 | 0.015 | Stirnplatte | PythonPart | 0.29 | EG_Technik_FFB | HA_STV_ECK_xxx_STA_0,200x0,300_xxx | Platte | ToolboxPlate | 0103Pyt0000002585 | St | AT01 | <undefiniert>
Stirnplatte | EG_Technik_FFB | 1282 | 0 | 0.2 | 0.015 | Stirnplatte | PythonPart | 0.29 | EG_Technik_FFB | HA_STV_ECK_xxx_STA_0,200x0,300_xxx | Platte | ToolboxPlate | 0103Pyt0000002586 | St | AT01 | <undefiniert>
Stirnplatte | EG_Technik_FFB | 1282 | 0 | 0.2 | 0.015 | Stirnplatte | PythonPart | 0.29 | EG_Technik_FFB | HA_STV_ECK_xxx_STA_0,200x0,300_xxx | Platte | ToolboxPlate | 0103Pyt0000002590 | St | AT01 | <undefiniert>
Stirnplatte | EG_Technik_FFB | 1282 | 0 | 0.2 | 0.015 | Stirnplatte | PythonPart | 0.29 | EG_Technik_FFB | HA_STV_ECK_xxx_STA_0,200x0,300_xxx | Platte | ToolboxPlate | 0103Pyt0000002591 | St | AT01 | <undefiniert>
Stirnplatte | EG_Technik_FFB | 1282 | 0 | 0.2 | 0.015 | Stirnplatte | PythonPart | 0.29 | EG_Technik_FFB | HA_STV_ECK_xxx_STA_0,200x0,300_xxx | Platte | ToolboxPlate | 0103Pyt0000002592 | St | AT01 | <undefiniert>
Stirnplatte | EG_Technik_FFB | 1282 | 0 | 0.2 | 0.015 | Stirnplatte | PythonPart | 0.29 | EG_Technik_FFB | HA_STV_ECK_xxx_STA_0,200x0,300_xxx | Platte | ToolboxPlate | 0103Pyt0000002593 | St | AT01 | <undefiniert>
Stirnplatte | EG_Technik_FFB | 1282 | 0 | 0.2 | 0.015 | Stirnplatte | PythonPart | 0.29 | EG_Technik_FFB | HA_STV_ECK_xxx_STA_0,200x0,300_xxx | Platte | ToolboxPlate | 0103Pyt0000002595 | St | AT01 | <undefiniert>
Stirnplatte | EG_Technik_FFB | 1282 | 0 | 0.2 | 0.015 | Stirnplatte | PythonPart | 0.29 | EG_Technik_FFB | HA_STV_ECK_xxx_STA_0,200x0,300_xxx | Platte | ToolboxPlate | 0103Pyt0000002596 | St | AT01 | <undefiniert>
Stirnplatte | EG_Technik_FFB | 1282 | 0 | 0.2 | 0.015 | Stirnplatte | PythonPart | 0.29 | EG_Technik_FFB | HA_STV_ECK_xxx_STA_0,200x0,300_xxx | Platte | ToolboxPlate | 0103Pyt0000002597 | St | AT01 | <undefiniert>
Stirnplatte | EG_Technik_FFB | 1282 | 0 | 0.2 | 0.015 | Stirnplatte | PythonPart | 0.29 | EG_Technik_FFB | HA_STV_ECK_xxx_STA_0,200x0,300_xxx | Platte | ToolboxPlate | 0103Pyt0000002598 | St | AT01 | <undefiniert>
Stirnplatte | EG_Technik_FFB | 1282 | 0 | 0.2 | 0.015 | Stirnplatte | PythonPart | 0.29 | EG_Technik_FFB | HA_STV_ECK_xxx_STA_0,200x0,300_xxx | Platte | ToolboxPlate | 0103Pyt0000002604 | St | AT01 | <undefiniert>
Stirnplatte | EG_Technik_FFB | 1282 | 0 | 0.2 | 0.015 | Stirnplatte | PythonPart | 0.29 | EG_Technik_FFB | HA_STV_ECK_xxx_STA_0,200x0,300_xxx | Platte | ToolboxPlate | 0103Pyt0000002605 | St | AT01 | <undefiniert>
Stirnplatte | EG_Technik_FFB | 1282 | 0 | 0.2 | 0.015 | Stirnplatte | PythonPart | 0.29 | EG_Technik_FFB | HA_STV_ECK_xxx_STA_0,200x0,300_xxx | Platte | ToolboxPlate | 0103Pyt0000002606 | St | AT01 | <undefiniert>
Stirnplatte | EG_Technik_FFB | 1282 | 0 | 0.2 | 0.015 | Stirnplatte | PythonPart | 0.29 | EG_Technik_FFB | HA_STV_ECK_xxx_STA_0,200x0,300_xxx | Platte | ToolboxPlate | 0103Pyt0000002607 | St | AT01 | <undefiniert>
Stirnplatte | EG_Technik_FFB | 1282 | 0 | 0.2 | 0.015 | Stirnplatte | PythonPart | 0.29 | EG_Technik_FFB | HA_STV_ECK_xxx_STA_0,200x0,300_xxx | Platte | ToolboxPlate | 0103Pyt0000002609 | St | AT01 | <undefiniert>
Stirnplatte | EG_Technik_FFB | 1282 | 0 | 0.2 | 0.015 | Stirnplatte | PythonPart | 0.29 | EG_Technik_FFB | HA_STV_ECK_xxx_STA_0,200x0,300_xxx | Platte | ToolboxPlate | 0103Pyt0000002610 | St | AT01 | <undefiniert>
Stirnplatte | EG_Technik_FFB | 1282 | 0 | 0.2 | 0.015 | Stirnplatte | PythonPart | 0.29 | EG_Technik_FFB | HA_STV_ECK_xxx_STA_0,200x0,300_xxx | Platte | ToolboxPlate | 0103Pyt0000002611 | St | AT01 | <undefiniert>
Stirnplatte | EG_Technik_FFB | 1282 | 0 | 0.2 | 0.015 | Stirnplatte | PythonPart | 0.29 | EG_Technik_FFB | HA_STV_ECK_xxx_STA_0,200x0,300_xxx | Platte | ToolboxPlate | 0103Pyt0000002612 | St | AT01 | <undefiniert>
Stirnplatte | EG_Technik_FFB | 1282 | 0 | 0.2 | 0.015 | Stirnplatte | PythonPart | 0.29 | EG_Technik_FFB | HA_STV_ECK_xxx_STA_0,200x0,300_xxx | Platte | ToolboxPlate | 0103Pyt0000002618 | St | AT01 | <undefiniert>
Stirnplatte | EG_Technik_FFB | 1282 | 0 | 0.2 | 0.015 | Stirnplatte | PythonPart | 0.29 | EG_Technik_FFB | HA_STV_ECK_xxx_STA_0,200x0,300_xxx | Platte | ToolboxPlate | 0103Pyt0000002619 | St | AT01 | <undefiniert>
Stirnplatte | EG_Technik_FFB | 1282 | 0 | 0.2 | 0.015 | Stirnplatte | PythonPart | 0.29 | EG_Technik_FFB | HA_STV_ECK_xxx_STA_0,200x0,300_xxx | Platte | ToolboxPlate | 0103Pyt0000002620 | St | AT01 | <undefiniert>
Stirnplatte | EG_Technik_FFB | 1282 | 0 | 0.2 | 0.015 | Stirnplatte | PythonPart | 0.29 | EG_Technik_FFB | HA_STV_ECK_xxx_STA_0,200x0,300_xxx | Platte | ToolboxPlate | 0103Pyt0000002621 | St | AT01 | <undefiniert>
Stirnplatte | EG_Technik_FFB | 1282 | 0 | 0.2 | 0.015 | Stirnplatte | PythonPart | 0.29 | EG_Technik_FFB | HA_STV_ECK_xxx_STA_0,200x0,300_xxx | Platte | ToolboxPlate | 0103Pyt0000002623 | St | AT01 | <undefiniert>
Stirnplatte | EG_Technik_FFB | 1282 | 0 | 0.2 | 0.015 | Stirnplatte | PythonPart | 0.29 | EG_Technik_FFB | HA_STV_ECK_xxx_STA_0,200x0,300_xxx | Platte | ToolboxPlate | 0103Pyt0000002624 | St | AT01 | <undefiniert>
Stirnplatte | EG_Technik_FFB | 1282 | 0 | 0.2 | 0.015 | Stirnplatte | PythonPart | 0.29 | EG_Technik_FFB | HA_STV_ECK_xxx_STA_0,200x0,300_xxx | Platte | ToolboxPlate | 0103Pyt0000002625 | St | AT01 | <undefiniert>
Stirnplatte | EG_Technik_FFB | 1282 | 0 | 0.2 | 0.015 | Stirnplatte | PythonPart | 0.29 | EG_Technik_FFB | HA_STV_ECK_xxx_STA_0,200x0,300_xxx | Platte | ToolboxPlate | 0103Pyt0000002626 | St | AT01 | <undefiniert>
Stirnplatte | EG_Technik_FFB | 1282 | 0 | 0.2 | 0.015 | Stirnplatte | PythonPart | 0.29 | EG_Technik_FFB | HA_STV_ECK_xxx_STA_0,200x0,300_xxx | Platte | ToolboxPlate | 0103Pyt0000002632 | St | AT01 | <undefiniert>
Stirnplatte | EG_Technik_FFB | 1282 | 0 | 0.2 | 0.015 | Stirnplatte | PythonPart | 0.29 | EG_Technik_FFB | HA_STV_ECK_xxx_STA_0,200x0,300_xxx | Platte | ToolboxPlate | 0103Pyt0000002633 | St | AT01 | <undefiniert>
Stirnplatte | EG_Technik_FFB | 1282 | 0 | 0.2 | 0.015 | Stirnplatte | PythonPart | 0.29 | EG_Technik_FFB | HA_STV_ECK_xxx_STA_0,200x0,300_xxx | Platte | ToolboxPlate | 0103Pyt0000002634 | St | AT01 | <undefiniert>
Stirnplatte | EG_Technik_FFB | 1282 | 0 | 0.2 | 0.015 | Stirnplatte | PythonPart | 0.29 | EG_Technik_FFB | HA_STV_ECK_xxx_STA_0,200x0,300_xxx | Platte | ToolboxPlate | 0103Pyt0000002635 | St | AT01 | <undefiniert>
Stirnplatte | EG_Technik_FFB | 1282 | 0 | 0.2 | 0.015 | Stirnplatte | PythonPart | 0.29 | EG_Technik_FFB | HA_STV_ECK_xxx_STA_0,200x0,300_xxx | Platte | ToolboxPlate | 0103Pyt0000002637 | St | AT01 | <undefiniert>
Stirnplatte | EG_Technik_FFB | 1282 | 0 | 0.2 | 0.015 | Stirnplatte | PythonPart | 0.29 | EG_Technik_FFB | HA_STV_ECK_xxx_STA_0,200x0,300_xxx | Platte | ToolboxPlate | 0103Pyt0000002638 | St | AT01 | <undefiniert>
Stirnplatte | EG_Technik_FFB | 1282 | 0 | 0.2 | 0.015 | Stirnplatte | PythonPart | 0.29 | EG_Technik_FFB | HA_STV_ECK_xxx_STA_0,200x0,300_xxx | Platte | ToolboxPlate | 0103Pyt0000002639 | St | AT01 | <undefiniert>
Stirnplatte | EG_Technik_FFB | 1282 | 0 | 0.2 | 0.015 | Stirnplatte | PythonPart | 0.29 | EG_Technik_FFB | HA_STV_ECK_xxx_STA_0,200x0,300_xxx | Platte | ToolboxPlate | 0103Pyt0000002640 | St | AT01 | <undefiniert>
Stirnplatte | EG_Technik_FFB | 1282 | 0 | 0.2 | 0.015 | Stirnplatte | PythonPart | 0.29 | EG_Technik_FFB | HA_STV_ECK_xxx_STA_0,200x0,300_xxx | Platte | ToolboxPlate | 0103Pyt0000002646 | St | AT01 | <undefiniert>
Stirnplatte | EG_Technik_FFB | 1282 | 0 | 0.2 | 0.015 | Stirnplatte | PythonPart | 0.29 | EG_Technik_FFB | HA_STV_ECK_xxx_STA_0,200x0,300_xxx | Platte | ToolboxPlate | 0103Pyt0000002647 | St | AT01 | <undefiniert>
Stirnplatte | EG_Technik_FFB | 1282 | 0 | 0.2 | 0.015 | Stirnplatte | PythonPart | 0.29 | EG_Technik_FFB | HA_STV_ECK_xxx_STA_0,200x0,300_xxx | Platte | ToolboxPlate | 0103Pyt0000002648 | St | AT01 | <undefiniert>
Stirnplatte | EG_Technik_FFB | 1282 | 0 | 0.2 | 0.015 | Stirnplatte | PythonPart | 0.29 | EG_Technik_FFB | HA_STV_ECK_xxx_STA_0,200x0,300_xxx | Platte | ToolboxPlate | 0103Pyt0000002649 | St | AT01 | <undefiniert>
Fußplatte | EG_Technik_FFB | 977 | 0 | 0.3 | 0.015 | Fußplatte | PythonPart | 0.3 | EG_Technik_FFB | HA_STV_ECK_xxx_STA_0,300x0,300_xxx | Platte | ToolboxPlate | 0103Pyt0000002161 | St | ATL01 | <undefiniert>
Stirnplatte | EG_Technik_FFB | 1282 | 0 | 0.2 | 0.015 | Stirnplatte | PythonPart | 0.29 | EG_Technik_FFB | HA_STV_ECK_xxx_STA_0,200x0,300_xxx | Platte | ToolboxPlate | 0103Pyt0000001650 | St | AT02 | <undefiniert>
Stirnplatte | EG_Technik_FFB | 1282 | 0 | 0.2 | 0.015 | Stirnplatte | PythonPart | 0.29 | EG_Technik_FFB | HA_STV_ECK_xxx_STA_0,200x0,300_xxx | Platte | ToolboxPlate | 0103Pyt0000001651 | St | AT02 | <undefiniert>
Stirnplatte | EG_Technik_FFB | 1282 | 0 | 0.2 | 0.015 | Stirnplatte | PythonPart | 0.29 | EG_Technik_FFB | HA_STV_ECK_xxx_STA_0,200x0,300_xxx | Platte | ToolboxPlate | 0103Pyt0000001791 | St | AT02 | <undefiniert>
Stirnplatte | EG_Technik_FFB | 1282 | 0 | 0.2 | 0.015 | Stirnplatte | PythonPart | 0.29 | EG_Technik_FFB | HA_STV_ECK_xxx_STA_0,200x0,300_xxx | Platte | ToolboxPlate | 0103Pyt0000001792 | St | AT02 | <undefiniert>
Stirnplatte | EG_Technik_FFB | 1282 | 0 | 0.2 | 0.015 | Stirnplatte | PythonPart | 0.29 | EG_Technik_FFB | HA_STV_ECK_xxx_STA_0,200x0,300_xxx | Platte | ToolboxPlate | 0103Pyt0000001652 | St | AT02 | <undefiniert>
Stirnplatte | EG_Technik_FFB | 1282 | 0 | 0.2 | 0.015 | Stirnplatte | PythonPart | 0.29 | EG_Technik_FFB | HA_STV_ECK_xxx_STA_0,200x0,300_xxx | Platte | ToolboxPlate | 0103Pyt0000001653 | St | AT02 | <undefiniert>
Stirnplatte | EG_Technik_FFB | 1282 | 0 | 0.2 | 0.015 | Stirnplatte | PythonPart | 0.29 | EG_Technik_FFB | HA_STV_ECK_xxx_STA_0,200x0,300_xxx | Platte | ToolboxPlate | 0103Pyt0000001793 | St | AT02 | <undefiniert>
Stirnplatte | EG_Technik_FFB | 1282 | 0 | 0.2 | 0.015 | Stirnplatte | PythonPart | 0.29 | EG_Technik_FFB | HA_STV_ECK_xxx_STA_0,200x0,300_xxx | Platte | ToolboxPlate | 0103Pyt0000001794 | St | AT02 | <undefiniert>
Stirnplatte | EG_Technik_FFB | 1282 | 0 | 0.2 | 0.015 | Stirnplatte | PythonPart | 0.29 | EG_Technik_FFB | HA_STV_ECK_xxx_STA_0,200x0,300_xxx | Platte | ToolboxPlate | 0103Pyt0000002015 | St | AT02 | <undefiniert>
Stirnplatte | EG_Technik_FFB | 1282 | 0 | 0.2 | 0.015 | Stirnplatte | PythonPart | 0.29 | EG_Technik_FFB | HA_STV_ECK_xxx_STA_0,200x0,300_xxx | Platte | ToolboxPlate | 0103Pyt0000002016 | St | AT02 | <undefiniert>
Stirnplatte | EG_Technik_FFB | 1282 | 0 | 0.2 | 0.015 | Stirnplatte | PythonPart | 0.29 | EG_Technik_FFB | HA_STV_ECK_xxx_STA_0,200x0,300_xxx | Platte | ToolboxPlate | 0103Pyt0000002017 | St | AT02 | <undefiniert>
Stirnplatte | EG_Technik_FFB | 1282 | 0 | 0.2 | 0.015 | Stirnplatte | PythonPart | 0.29 | EG_Technik_FFB | HA_STV_ECK_xxx_STA_0,200x0,300_xxx | Platte | ToolboxPlate | 0103Pyt0000002018 | St | AT02 | <undefiniert>
Stirnplatte | EG_Technik_FFB | 1282 | 0 | 0.2 | 0.015 | Stirnplatte | PythonPart | 0.29 | EG_Technik_FFB | HA_STV_ECK_xxx_STA_0,200x0,300_xxx | Platte | ToolboxPlate | 0103Pyt0000002019 | St | AT02 | <undefiniert>
Stirnplatte | EG_Technik_FFB | 1282 | 0 | 0.2 | 0.015 | Stirnplatte | PythonPart | 0.29 | EG_Technik_FFB | HA_STV_ECK_xxx_STA_0,200x0,300_xxx | Platte | ToolboxPlate | 0103Pyt0000002020 | St | AT02 | <undefiniert>
Stirnplatte | EG_Technik_FFB | 1282 | 0 | 0.2 | 0.015 | Stirnplatte | PythonPart | 0.29 | EG_Technik_FFB | HA_STV_ECK_xxx_STA_0,200x0,300_xxx | Platte | ToolboxPlate | 0103Pyt0000002021 | St | AT02 | <undefiniert>
Stirnplatte | EG_Technik_FFB | 1282 | 0 | 0.2 | 0.015 | Stirnplatte | PythonPart | 0.29 | EG_Technik_FFB | HA_STV_ECK_xxx_STA_0,200x0,300_xxx | Platte | ToolboxPlate | 0103Pyt0000002022 | St | AT02 | <undefiniert>
Stirnplatte | EG_Technik_FFB | 1282 | 0 | 0.2 | 0.015 | Stirnplatte | PythonPart | 0.29 | EG_Technik_FFB | HA_STV_ECK_xxx_STA_0,200x0,300_xxx | Platte | ToolboxPlate | 0103Pyt0000002085 | St | AT02 | <undefiniert>
Stirnplatte | EG_Technik_FFB | 1282 | 0 | 0.2 | 0.015 | Stirnplatte | PythonPart | 0.29 | EG_Technik_FFB | HA_STV_ECK_xxx_STA_0,200x0,300_xxx | Platte | ToolboxPlate | 0103Pyt0000002086 | St | AT02 | <undefiniert>
Stirnplatte | EG_Technik_FFB | 1282 | 0 | 0.2 | 0.015 | Stirnplatte | PythonPart | 0.29 | EG_Technik_FFB | HA_STV_ECK_xxx_STA_0,200x0,300_xxx | Platte | ToolboxPlate | 0103Pyt0000002087 | St | AT02 | <undefiniert>
Stirnplatte | EG_Technik_FFB | 1282 | 0 | 0.2 | 0.015 | Stirnplatte | PythonPart | 0.29 | EG_Technik_FFB | HA_STV_ECK_xxx_STA_0,200x0,300_xxx | Platte | ToolboxPlate | 0103Pyt0000002088 | St | AT02 | <undefiniert>
Stirnplatte | EG_Technik_FFB | 1282 | 0 | 0.2 | 0.015 | Stirnplatte | PythonPart | 0.29 | EG_Technik_FFB | HA_STV_ECK_xxx_STA_0,200x0,300_xxx | Platte | ToolboxPlate | 0103Pyt0000002089 | St | AT02 | <undefiniert>
Stirnplatte | EG_Technik_FFB | 1282 | 0 | 0.2 | 0.015 | Stirnplatte | PythonPart | 0.29 | EG_Technik_FFB | HA_STV_ECK_xxx_STA_0,200x0,300_xxx | Platte | ToolboxPlate | 0103Pyt0000002090 | St | AT02 | <undefiniert>
Stirnplatte | EG_Technik_FFB | 1282 | 0 | 0.2 | 0.015 | Stirnplatte | PythonPart | 0.29 | EG_Technik_FFB | HA_STV_ECK_xxx_STA_0,200x0,300_xxx | Platte | ToolboxPlate | 0103Pyt0000002091 | St | AT02 | <undefiniert>
Stirnplatte | EG_Technik_FFB | 1282 | 0 | 0.2 | 0.015 | Stirnplatte | PythonPart | 0.29 | EG_Technik_FFB | HA_STV_ECK_xxx_STA_0,200x0,300_xxx | Platte | ToolboxPlate | 0103Pyt0000002092 | St | AT02 | <undefiniert>
Stirnplatte | EG_Technik_FFB | 1282 | 0 | 0.2 | 0.015 | Stirnplatte | PythonPart | 0.29 | EG_Technik_FFB | HA_STV_ECK_xxx_STA_0,200x0,300_xxx | Platte | ToolboxPlate | 0103Pyt0000002099 | St | AT02 | <undefiniert>
Stirnplatte | EG_Technik_FFB | 1282 | 0 | 0.2 | 0.015 | Stirnplatte | PythonPart | 0.29 | EG_Technik_FFB | HA_STV_ECK_xxx_STA_0,200x0,300_xxx | Platte | ToolboxPlate | 0103Pyt0000002100 | St | AT02 | <undefiniert>
Stirnplatte | EG_Technik_FFB | 1282 | 0 | 0.2 | 0.015 | Stirnplatte | PythonPart | 0.29 | EG_Technik_FFB | HA_STV_ECK_xxx_STA_0,200x0,300_xxx | Platte | ToolboxPlate | 0103Pyt0000002101 | St | AT02 | <undefiniert>
Stirnplatte | EG_Technik_FFB | 1282 | 0 | 0.2 | 0.015 | Stirnplatte | PythonPart | 0.29 | EG_Technik_FFB | HA_STV_ECK_xxx_STA_0,200x0,300_xxx | Platte | ToolboxPlate | 0103Pyt0000002102 | St | AT02 | <undefiniert>
Stirnplatte | EG_Technik_FFB | 1282 | 0 | 0.2 | 0.015 | Stirnplatte | PythonPart | 0.29 | EG_Technik_FFB | HA_STV_ECK_xxx_STA_0,200x0,300_xxx | Platte | ToolboxPlate | 0103Pyt0000002103 | St | AT02 | <undefiniert>
Stirnplatte | EG_Technik_FFB | 1282 | 0 | 0.2 | 0.015 | Stirnplatte | PythonPart | 0.29 | EG_Technik_FFB | HA_STV_ECK_xxx_STA_0,200x0,300_xxx | Platte | ToolboxPlate | 0103Pyt0000002104 | St | AT02 | <undefiniert>
Stirnplatte | EG_Technik_FFB | 1282 | 0 | 0.2 | 0.015 | Stirnplatte | PythonPart | 0.29 | EG_Technik_FFB | HA_STV_ECK_xxx_STA_0,200x0,300_xxx | Platte | ToolboxPlate | 0103Pyt0000002105 | St | AT02 | <undefiniert>
Stirnplatte | EG_Technik_FFB | 1282 | 0 | 0.2 | 0.015 | Stirnplatte | PythonPart | 0.29 | EG_Technik_FFB | HA_STV_ECK_xxx_STA_0,200x0,300_xxx | Platte | ToolboxPlate | 0103Pyt0000002106 | St | AT02 | <undefiniert>
Kragarm | EG_Technik_FFB | 1282 | 0 | 0.2 | 0.015 | Kragarm | PythonPart | 0.29 | EG_Technik_FFB | HA_STV_ECK_xxx_STA_0,200x0,300_xxx | Platte | ToolboxPlate | 0103Pyt0000002234 | St | AT01.2 | <undefiniert>
Kragarm | EG_Technik_FFB | 1282 | 0 | 0.2 | 0.015 | Kragarm | PythonPart | 0.29 | EG_Technik_FFB | HA_STV_ECK_xxx_STA_0,200x0,300_xxx | Platte | ToolboxPlate | 0103Pyt0000002235 | St | AT01.2 | <undefiniert>
Kragarm | EG_Technik_FFB | 1282 | 0 | 0.2 | 0.015 | Kragarm | PythonPart | 0.29 | EG_Technik_FFB | HA_STV_ECK_xxx_STA_0,200x0,300_xxx | Platte | ToolboxPlate | 0103Pyt0000002236 | St | AT01.2 | <undefiniert>
Kragarm | EG_Technik_FFB | 1282 | 0 | 0.2 | 0.015 | Kragarm | PythonPart | 0.29 | EG_Technik_FFB | HA_STV_ECK_xxx_STA_0,200x0,300_xxx | Platte | ToolboxPlate | 0103Pyt0000002237 | St | AT01.2 | <undefiniert>
Kragarm | EG_Technik_FFB | 1282 | 0 | 0.2 | 0.015 | Kragarm | PythonPart | 0.29 | EG_Technik_FFB | HA_STV_ECK_xxx_STA_0,200x0,300_xxx | Platte | ToolboxPlate | 0103Pyt0000002246 | St | AT01.2 | <undefiniert>
Kragarm | EG_Technik_FFB | 1282 | 0 | 0.2 | 0.015 | Kragarm | PythonPart | 0.29 | EG_Technik_FFB | HA_STV_ECK_xxx_STA_0,200x0,300_xxx | Platte | ToolboxPlate | 0103Pyt0000002247 | St | AT01.2 | <undefiniert>
Kragarm | EG_Technik_FFB | 1282 | 0 | 0.2 | 0.015 | Kragarm | PythonPart | 0.29 | EG_Technik_FFB | HA_STV_ECK_xxx_STA_0,200x0,300_xxx | Platte | ToolboxPlate | 0103Pyt0000002248 | St | AT01.2 | <undefiniert>
Kragarm | EG_Technik_FFB | 1282 | 0 | 0.2 | 0.015 | Kragarm | PythonPart | 0.29 | EG_Technik_FFB | HA_STV_ECK_xxx_STA_0,200x0,300_xxx | Platte | ToolboxPlate | 0103Pyt0000002249 | St | AT01.2 | <undefiniert>
Kragarm | EG_Technik_FFB | 1282 | 0 | 0.2 | 0.015 | Kragarm | PythonPart | 0.29 | EG_Technik_FFB | HA_STV_ECK_xxx_STA_0,200x0,300_xxx | Platte | ToolboxPlate | 0103Pyt0000002256 | St | AT01.2 | <undefiniert>
Kragarm | EG_Technik_FFB | 1282 | 0 | 0.2 | 0.015 | Kragarm | PythonPart | 0.29 | EG_Technik_FFB | HA_STV_ECK_xxx_STA_0,200x0,300_xxx | Platte | ToolboxPlate | 0103Pyt0000002257 | St | AT01.2 | <undefiniert>
Kragarm | EG_Technik_FFB | 1282 | 0 | 0.2 | 0.015 | Kragarm | PythonPart | 0.29 | EG_Technik_FFB | HA_STV_ECK_xxx_STA_0,200x0,300_xxx | Platte | ToolboxPlate | 0103Pyt0000002258 | St | AT01.2 | <undefiniert>
Kragarm | EG_Technik_FFB | 1282 | 0 | 0.2 | 0.015 | Kragarm | PythonPart | 0.29 | EG_Technik_FFB | HA_STV_ECK_xxx_STA_0,200x0,300_xxx | Platte | ToolboxPlate | 0103Pyt0000002259 | St | AT01.2 | <undefiniert>
Stirnplatte | EG_Technik_FFB | 1282 | 0 | 0.07 | 0.015 | Stirnplatte | PythonPart | 0.19 | EG_Technik_FFB | HA_STV_ECK_xxx_STA_0,070x0,190_xxx | Platte | ToolboxPlate | 0103Pyt0000002474 | St | AT01.1 | <undefiniert>
Stirnplatte | EG_Technik_FFB | 1282 | 0 | 0.07 | 0.015 | Stirnplatte | PythonPart | 0.19 | EG_Technik_FFB | HA_STV_ECK_xxx_STA_0,070x0,190_xxx | Platte | ToolboxPlate | 0103Pyt0000002477 | St | AT01.1 | <undefiniert>
Stirnplatte | EG_Technik_FFB | 1282 | 0 | 0.07 | 0.015 | Stirnplatte | PythonPart | 0.19 | EG_Technik_FFB | HA_STV_ECK_xxx_STA_0,070x0,190_xxx | Platte | ToolboxPlate | 0103Pyt0000002480 | St | AT01.1 | <undefiniert>
Stirnplatte | EG_Technik_FFB | 1282 | 0 | 0.07 | 0.015 | Stirnplatte | PythonPart | 0.19 | EG_Technik_FFB | HA_STV_ECK_xxx_STA_0,070x0,190_xxx | Platte | ToolboxPlate | 0103Pyt0000002483 | St | AT01.1 | <undefiniert>
Stirnplatte | EG_Technik_FFB | 1282 | 0 | 0.07 | 0.015 | Stirnplatte | PythonPart | 0.19 | EG_Technik_FFB | HA_STV_ECK_xxx_STA_0,070x0,190_xxx | Platte | ToolboxPlate | 0103Pyt0000002486 | St | AT01.1 | <undefiniert>
Stirnplatte | EG_Technik_FFB | 1282 | 0 | 0.07 | 0.015 | Stirnplatte | PythonPart | 0.19 | EG_Technik_FFB | HA_STV_ECK_xxx_STA_0,070x0,190_xxx | Platte | ToolboxPlate | 0103Pyt0000002489 | St | AT01.1 | <undefiniert>
Stirnplatte | EG_Technik_FFB | 1282 | 0 | 0.07 | 0.015 | Stirnplatte | PythonPart | 0.19 | EG_Technik_FFB | HA_STV_ECK_xxx_STA_0,070x0,190_xxx | Platte | ToolboxPlate | 0103Pyt0000002492 | St | AT01.1 | <undefiniert>
Stirnplatte | EG_Technik_FFB | 1282 | 0 | 0.07 | 0.015 | Stirnplatte | PythonPart | 0.19 | EG_Technik_FFB | HA_STV_ECK_xxx_STA_0,070x0,190_xxx | Platte | ToolboxPlate | 0103Pyt0000002495 | St | AT01.1 | <undefiniert>
Stirnplatte | EG_Technik_FFB | 1282 | 0 | 0.07 | 0.015 | Stirnplatte | PythonPart | 0.19 | EG_Technik_FFB | HA_STV_ECK_xxx_STA_0,070x0,190_xxx | Platte | ToolboxPlate | 0103Pyt0000002498 | St | AT01.1 | <undefiniert>
Stirnplatte | EG_Technik_FFB | 1282 | 0 | 0.07 | 0.015 | Stirnplatte | PythonPart | 0.19 | EG_Technik_FFB | HA_STV_ECK_xxx_STA_0,070x0,190_xxx | Platte | ToolboxPlate | 0103Pyt0000002501 | St | AT01.1 | <undefiniert>
Stirnplatte | EG_Technik_FFB | 1282 | 0 | 0.07 | 0.015 | Stirnplatte | PythonPart | 0.19 | EG_Technik_FFB | HA_STV_ECK_xxx_STA_0,070x0,190_xxx | Platte | ToolboxPlate | 0103Pyt0000002504 | St | AT01.1 | <undefiniert>
Stirnplatte | EG_Technik_FFB | 1282 | 0 | 0.07 | 0.015 | Stirnplatte | PythonPart | 0.19 | EG_Technik_FFB | HA_STV_ECK_xxx_STA_0,070x0,190_xxx | Platte | ToolboxPlate | 0103Pyt0000002507 | St | AT01.1 | <undefiniert>
Stirnplatte | EG_Technik_FFB | 1282 | 0 | 0.07 | 0.015 | Stirnplatte | PythonPart | 0.19 | EG_Technik_FFB | HA_STV_ECK_xxx_STA_0,070x0,190_xxx | Platte | ToolboxPlate | 0103Pyt0000002510 | St | AT01.1 | <undefiniert>
Stirnplatte | EG_Technik_FFB | 1282 | 0 | 0.07 | 0.015 | Stirnplatte | PythonPart | 0.19 | EG_Technik_FFB | HA_STV_ECK_xxx_STA_0,070x0,190_xxx | Platte | ToolboxPlate | 0103Pyt0000002513 | St | AT01.1 | <undefiniert>
Stirnplatte | EG_Technik_FFB | 1282 | 0 | 0.07 | 0.015 | Stirnplatte | PythonPart | 0.19 | EG_Technik_FFB | HA_STV_ECK_xxx_STA_0,070x0,190_xxx | Platte | ToolboxPlate | 0103Pyt0000002516 | St | AT01.1 | <undefiniert>
Stirnplatte | EG_Technik_FFB | 1282 | 0 | 0.07 | 0.015 | Stirnplatte | PythonPart | 0.19 | EG_Technik_FFB | HA_STV_ECK_xxx_STA_0,070x0,190_xxx | Platte | ToolboxPlate | 0103Pyt0000002519 | St | AT01.1 | <undefiniert>
Stirnplatte | EG_Technik_FFB | 1282 | 0 | 0.07 | 0.015 | Stirnplatte | PythonPart | 0.19 | EG_Technik_FFB | HA_STV_ECK_xxx_STA_0,070x0,190_xxx | Platte | ToolboxPlate | 0103Pyt0000002522 | St | AT01.1 | <undefiniert>
Stirnplatte | EG_Technik_FFB | 1282 | 0 | 0.07 | 0.015 | Stirnplatte | PythonPart | 0.19 | EG_Technik_FFB | HA_STV_ECK_xxx_STA_0,070x0,190_xxx | Platte | ToolboxPlate | 0103Pyt0000002525 | St | AT01.1 | <undefiniert>
Stirnplatte | EG_Technik_FFB | 1282 | 0 | 0.07 | 0.015 | Stirnplatte | PythonPart | 0.19 | EG_Technik_FFB | HA_STV_ECK_xxx_STA_0,070x0,190_xxx | Platte | ToolboxPlate | 0103Pyt0000002528 | St | AT01.1 | <undefiniert>
Stirnplatte | EG_Technik_FFB | 1282 | 0 | 0.07 | 0.015 | Stirnplatte | PythonPart | 0.19 | EG_Technik_FFB | HA_STV_ECK_xxx_STA_0,070x0,190_xxx | Platte | ToolboxPlate | 0103Pyt0000002531 | St | AT01.1 | <undefiniert>
Stirnplatte | EG_Technik_FFB | 1282 | 0 | 0.07 | 0.015 | Stirnplatte | PythonPart | 0.19 | EG_Technik_FFB | HA_STV_ECK_xxx_STA_0,070x0,190_xxx | Platte | ToolboxPlate | 0103Pyt0000002534 | St | AT01.1 | <undefiniert>
Stirnplatte | EG_Technik_FFB | 1282 | 0 | 0.07 | 0.015 | Stirnplatte | PythonPart | 0.19 | EG_Technik_FFB | HA_STV_ECK_xxx_STA_0,070x0,190_xxx | Platte | ToolboxPlate | 0103Pyt0000002537 | St | AT01.1 | <undefiniert>
Stirnplatte | EG_Technik_FFB | 1282 | 0 | 0.07 | 0.015 | Stirnplatte | PythonPart | 0.19 | EG_Technik_FFB | HA_STV_ECK_xxx_STA_0,070x0,190_xxx | Platte | ToolboxPlate | 0103Pyt0000002540 | St | AT01.1 | <undefiniert>
Stirnplatte | EG_Technik_FFB | 1282 | 0 | 0.07 | 0.015 | Stirnplatte | PythonPart | 0.19 | EG_Technik_FFB | HA_STV_ECK_xxx_STA_0,070x0,190_xxx | Platte | ToolboxPlate | 0103Pyt0000002543 | St | AT01.1 | <undefiniert>
Stirnplatte | EG_Technik_FFB | 1617 | 0 | 0.2 | 0.015 | Stirnplatte | PythonPart | 0.29 | EG_Technik_FFB | HA_STV_ECK_xxx_STA_0,290x0,200_xxx | Platte | ToolboxPlate | 0103Pyt0000001617 | St | AQV02.1 | <undefiniert>
Stirnplatte | EG_Technik_FFB | 1617 | 0 | 0.2 | 0.015 | Stirnplatte | PythonPart | 0.29 | EG_Technik_FFB | HA_STV_ECK_xxx_STA_0,290x0,200_xxx | Platte | ToolboxPlate | 0103Pyt0000004316 | St | AQV02.1 | <undefiniert>
Stirnplatte | EG_Technik_FFB | 1617 | 0 | 0.2 | 0.015 | Stirnplatte | PythonPart | 0.29 | EG_Technik_FFB | HA_STV_ECK_xxx_STA_0,290x0,200_xxx | Platte | ToolboxPlate | 0103Pyt0000004319 | St | AQV02.1 | <undefiniert>
Stirnplatte | EG_Technik_FFB | 1617 | 0 | 0.2 | 0.015 | Stirnplatte | PythonPart | 0.29 | EG_Technik_FFB | HA_STV_ECK_xxx_STA_0,290x0,200_xxx | Platte | ToolboxPlate | 0103Pyt0000004322 | St | AQV02.1 | <undefiniert>
Stirnplatte | EG_Technik_FFB | 1617 | 0 | 0.2 | 0.015 | Stirnplatte | PythonPart | 0.29 | EG_Technik_FFB | HA_STV_ECK_xxx_STA_0,290x0,200_xxx | Platte | ToolboxPlate | 0103Pyt0000004349 | St | AQV02.1 | <undefiniert>
Stirnplatte | EG_Technik_FFB | 1617 | 0 | 0.2 | 0.015 | Stirnplatte | PythonPart | 0.29 | EG_Technik_FFB | HA_STV_ECK_xxx_STA_0,290x0,200_xxx | Platte | ToolboxPlate | 0103Pyt0000004352 | St | AQV02.1 | <undefiniert>
Stirnplatte | EG_Technik_FFB | 1617 | 0 | 0.2 | 0.015 | Stirnplatte | PythonPart | 0.29 | EG_Technik_FFB | HA_STV_ECK_xxx_STA_0,290x0,200_xxx | Platte | ToolboxPlate | 0103Pyt0000004355 | St | AQV02.1 | <undefiniert>
Stirnplatte | EG_Technik_FFB | 1617 | 0 | 0.2 | 0.015 | Stirnplatte | PythonPart | 0.29 | EG_Technik_FFB | HA_STV_ECK_xxx_STA_0,290x0,200_xxx | Platte | ToolboxPlate | 0103Pyt0000004358 | St | AQV02.1 | <undefiniert>
Stirnplatte | EG_Technik_FFB | 1617 | 0 | 0.2 | 0.015 | Stirnplatte | PythonPart | 0.29 | EG_Technik_FFB | HA_STV_ECK_xxx_STA_0,290x0,200_xxx | Platte | ToolboxPlate | 0103Pyt0000004411 | St | AQV02.1 | <undefiniert>
Stirnplatte | EG_Technik_FFB | 1617 | 0 | 0.2 | 0.015 | Stirnplatte | PythonPart | 0.29 | EG_Technik_FFB | HA_STV_ECK_xxx_STA_0,290x0,200_xxx | Platte | ToolboxPlate | 0103Pyt0000004414 | St | AQV02.1 | <undefiniert>
Stirnplatte | EG_Technik_FFB | 1617 | 0 | 0.2 | 0.015 | Stirnplatte | PythonPart | 0.29 | EG_Technik_FFB | HA_STV_ECK_xxx_STA_0,290x0,200_xxx | Platte | ToolboxPlate | 0103Pyt0000004417 | St | AQV02.1 | <undefiniert>
Stirnplatte | EG_Technik_FFB | 1617 | 0 | 0.2 | 0.015 | Stirnplatte | PythonPart | 0.29 | EG_Technik_FFB | HA_STV_ECK_xxx_STA_0,290x0,200_xxx | Platte | ToolboxPlate | 0103Pyt0000004420 | St | AQV02.1 | <undefiniert>
Fußplatte | EG_Technik_FFB | 974 | 0 | 0.4 | 0.015 | Fußplatte | PythonPart | 0.4 | EG_Technik_FFB | HA_STV_ECK_xxx_STA_0,400x0,400_xxx | Platte | ToolboxPlate | 0103Pyt0000001604 | St | AQV02.1
Fußplatte | EG_Technik_FFB | 974 | 0 | 0.4 | 0.015 | Fußplatte | PythonPart | 0.4 | EG_Technik_FFB | HA_STV_ECK_xxx_STA_0,400x0,400_xxx | Platte | ToolboxPlate | 0103Pyt0000001606 | St | AQV02.1
Kopfplatte | EG_Technik_FFB | 977 | 0 | 0.29 | 0.015 | Kopfplatte | PythonPart | 0.3 | EG_Technik_FFB | HA_STV_ECK_xxx_STA_0,290x0,300_xxx | Platte | ToolboxPlate | 0103Pyt0000001611 | St | AQV02.1
Kopfplatte | EG_Technik_FFB | 977 | 0 | 0.29 | 0.015 | Kopfplatte | PythonPart | 0.3 | EG_Technik_FFB | HA_STV_ECK_xxx_STA_0,290x0,300_xxx | Platte | ToolboxPlate | 0103Pyt0000001626 | St | AQV02.1
Fußplatte | EG_Technik_FFB | 977 | 0 | 0.29 | 0.015 | Fußplatte | PythonPart | 0.3 | EG_Technik_FFB | HA_STV_ECK_xxx_STA_0,290x0,300_xxx | Platte | ToolboxPlate | 0103Pyt0000001837 | St | AQV02.2
Fußplatte | EG_Technik_FFB | 977 | 0 | 0.29 | 0.015 | Fußplatte | PythonPart | 0.3 | EG_Technik_FFB | HA_STV_ECK_xxx_STA_0,290x0,300_xxx | Platte | ToolboxPlate | 0103Pyt0000001828 | St | AQV02.2
Kopfplatte | EG_Technik_FFB | 977 | 0 | 0.29 | 0.015 | Kopfplatte | PythonPart | 0.3 | EG_Technik_FFB | HA_STV_ECK_xxx_STA_0,290x0,300_xxx | Platte | ToolboxPlate | 0103Pyt0000001755 | St | AQV02.2
Kopfplatte | EG_Technik_FFB | 977 | 0 | 0.29 | 0.015 | Kopfplatte | PythonPart | 0.3 | EG_Technik_FFB | HA_STV_ECK_xxx_STA_0,290x0,300_xxx | Platte | ToolboxPlate | 0103Pyt0000001770 | St | AQV02.2
Fußplatte | EG_Technik_FFB | 974 | 0 | 0.4 | 0.015 | Fußplatte | PythonPart | 0.4 | EG_Technik_FFB | HA_STV_ECK_xxx_STA_0,400x0,400_xxx | Platte | ToolboxPlate | 0103Pyt0000004370 | St | AQV02.1
Fußplatte | EG_Technik_FFB | 974 | 0 | 0.4 | 0.015 | Fußplatte | PythonPart | 0.4 | EG_Technik_FFB | HA_STV_ECK_xxx_STA_0,400x0,400_xxx | Platte | ToolboxPlate | 0103Pyt0000004372 | St | AQV02.1
Kopfplatte | EG_Technik_FFB | 977 | 0 | 0.29 | 0.015 | Kopfplatte | PythonPart | 0.3 | EG_Technik_FFB | HA_STV_ECK_xxx_STA_0,290x0,300_xxx | Platte | ToolboxPlate | 0103Pyt0000004375 | St | AQV02.1
Kopfplatte | EG_Technik_FFB | 977 | 0 | 0.29 | 0.015 | Kopfplatte | PythonPart | 0.3 | EG_Technik_FFB | HA_STV_ECK_xxx_STA_0,290x0,300_xxx | Platte | ToolboxPlate | 0103Pyt0000004378 | St | AQV02.1
Fußplatte | EG_Technik_FFB | 977 | 0 | 0.29 | 0.015 | Fußplatte | PythonPart | 0.3 | EG_Technik_FFB | HA_STV_ECK_xxx_STA_0,290x0,300_xxx | Platte | ToolboxPlate | 0103Pyt0000004381 | St | AQV02.2
Fußplatte | EG_Technik_FFB | 977 | 0 | 0.29 | 0.015 | Fußplatte | PythonPart | 0.3 | EG_Technik_FFB | HA_STV_ECK_xxx_STA_0,290x0,300_xxx | Platte | ToolboxPlate | 0103Pyt0000004386 | St | AQV02.2
Kopfplatte | EG_Technik_FFB | 977 | 0 | 0.29 | 0.015 | Kopfplatte | PythonPart | 0.3 | EG_Technik_FFB | HA_STV_ECK_xxx_STA_0,290x0,300_xxx | Platte | ToolboxPlate | 0103Pyt0000004389 | St | AQV02.2
Kopfplatte | EG_Technik_FFB | 977 | 0 | 0.29 | 0.015 | Kopfplatte | PythonPart | 0.3 | EG_Technik_FFB | HA_STV_ECK_xxx_STA_0,290x0,300_xxx | Platte | ToolboxPlate | 0103Pyt0000004392 | St | AQV02.2
Fußplatte | EG_Technik_FFB | 974 | 0 | 0.4 | 0.015 | Fußplatte | PythonPart | 0.4 | EG_Technik_FFB | HA_STV_ECK_xxx_STA_0,400x0,400_xxx | Platte | ToolboxPlate | 0103Pyt0000004424 | St | AQV02.1
Fußplatte | EG_Technik_FFB | 974 | 0 | 0.4 | 0.015 | Fußplatte | PythonPart | 0.4 | EG_Technik_FFB | HA_STV_ECK_xxx_STA_0,400x0,400_xxx | Platte | ToolboxPlate | 0103Pyt0000004426 | St | AQV02.1
Kopfplatte | EG_Technik_FFB | 977 | 0 | 0.29 | 0.015 | Kopfplatte | PythonPart | 0.3 | EG_Technik_FFB | HA_STV_ECK_xxx_STA_0,290x0,300_xxx | Platte | ToolboxPlate | 0103Pyt0000004429 | St | AQV02.1
Kopfplatte | EG_Technik_FFB | 977 | 0 | 0.29 | 0.015 | Kopfplatte | PythonPart | 0.3 | EG_Technik_FFB | HA_STV_ECK_xxx_STA_0,290x0,300_xxx | Platte | ToolboxPlate | 0103Pyt0000004432 | St | AQV02.1
Fußplatte | EG_Technik_FFB | 977 | 0 | 0.29 | 0.015 | Fußplatte | PythonPart | 0.3 | EG_Technik_FFB | HA_STV_ECK_xxx_STA_0,290x0,300_xxx | Platte | ToolboxPlate | 0103Pyt0000004435 | St | AQV02.2
Fußplatte | EG_Technik_FFB | 977 | 0 | 0.29 | 0.015 | Fußplatte | PythonPart | 0.3 | EG_Technik_FFB | HA_STV_ECK_xxx_STA_0,290x0,300_xxx | Platte | ToolboxPlate | 0103Pyt0000004438 | St | AQV02.2
Kopfplatte | EG_Technik_FFB | 977 | 0 | 0.29 | 0.015 | Kopfplatte | PythonPart | 0.3 | EG_Technik_FFB | HA_STV_ECK_xxx_STA_0,290x0,300_xxx | Platte | ToolboxPlate | 0103Pyt0000004441 | St | AQV02.2
Kopfplatte | EG_Technik_FFB | 977 | 0 | 0.29 | 0.015 | Kopfplatte | PythonPart | 0.3 | EG_Technik_FFB | HA_STV_ECK_xxx_STA_0,290x0,300_xxx | Platte | ToolboxPlate | 0103Pyt0000004444 | St | AQV02.2
Stirnplatte | EG_Technik_FFB | 1282 | 0 | 0.2 | 0.015 | Stirnplatte | PythonPart | 0.29 | EG_Technik_FFB | HA_STV_ECK_xxx_STA_0,200x0,300_xxx | Platte | ToolboxPlate | 0103Pyt0000004477 | St | AT02 | <undefiniert>
Stirnplatte | EG_Technik_FFB | 1282 | 0 | 0.2 | 0.015 | Stirnplatte | PythonPart | 0.29 | EG_Technik_FFB | HA_STV_ECK_xxx_STA_0,200x0,300_xxx | Platte | ToolboxPlate | 0103Pyt0000004478 | St | AT02 | <undefiniert>
Stirnplatte | EG_Technik_FFB | 1282 | 0 | 0.2 | 0.015 | Stirnplatte | PythonPart | 0.29 | EG_Technik_FFB | HA_STV_ECK_xxx_STA_0,200x0,300_xxx | Platte | ToolboxPlate | 0103Pyt0000004479 | St | AT02 | <undefiniert>
Stirnplatte | EG_Technik_FFB | 1282 | 0 | 0.2 | 0.015 | Stirnplatte | PythonPart | 0.29 | EG_Technik_FFB | HA_STV_ECK_xxx_STA_0,200x0,300_xxx | Platte | ToolboxPlate | 0103Pyt0000004480 | St | AT02 | <undefiniert>
Stirnplatte | EG_Technik_FFB | 1282 | 0 | 0.2 | 0.015 | Stirnplatte | PythonPart | 0.29 | EG_Technik_FFB | HA_STV_ECK_xxx_STA_0,200x0,300_xxx | Platte | ToolboxPlate | 0103Pyt0000004481 | St | AT02 | <undefiniert>
Stirnplatte | EG_Technik_FFB | 1282 | 0 | 0.2 | 0.015 | Stirnplatte | PythonPart | 0.29 | EG_Technik_FFB | HA_STV_ECK_xxx_STA_0,200x0,300_xxx | Platte | ToolboxPlate | 0103Pyt0000004482 | St | AT02 | <undefiniert>
Stirnplatte | EG_Technik_FFB | 1282 | 0 | 0.2 | 0.015 | Stirnplatte | PythonPart | 0.29 | EG_Technik_FFB | HA_STV_ECK_xxx_STA_0,200x0,300_xxx | Platte | ToolboxPlate | 0103Pyt0000004483 | St | AT02 | <undefiniert>
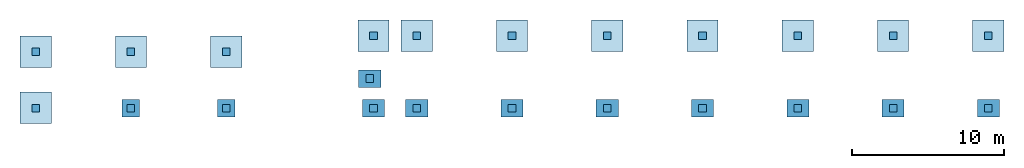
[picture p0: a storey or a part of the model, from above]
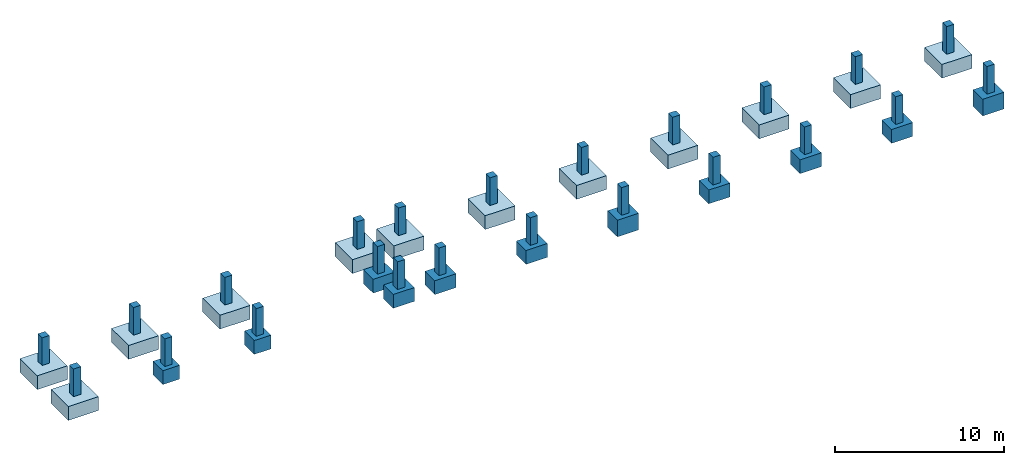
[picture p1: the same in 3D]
Properties of the parts of a building model (IFC2X3), part 22 of 25

# IfcPlate: PLATE (279)
Name | In | Bauteil-ID | V6 (m) = V7 (m) = V8 (m) = V9 | Länge (m) | Dicke (m) | Bezeichnung = Name | Plugin_Objektname | Breite (m) | Ebene | AllplanAttributes, Reference | Attributset-Objekt | Materialverwendung | Allright_Bauteil_ID | Abrechnungsart | Positionsnummer | Feuerwiderstandsklasse
Stirnplatte | EG_Technik_FFB | 1282 | 0 | 0.2 | 0.015 | Stirnplatte | PythonPart | 0.29 | EG_Technik_FFB | HA_STV_ECK_xxx_STA_0,200x0,300_xxx | Platte | ToolboxPlate | 0103Pyt0000004484 | St | AT02 | <undefiniert>
Kragarm | EG_Technik_FFB | 1282 | 0 | 0.2 | 0.015 | Kragarm | PythonPart | 0.29 | EG_Technik_FFB | HA_STV_ECK_xxx_STA_0,200x0,300_xxx | Platte | ToolboxPlate | 0103Pyt0000002276 | St | AT01.2 | <undefiniert>
Kragarm | EG_Technik_FFB | 1282 | 0 | 0.2 | 0.015 | Kragarm | PythonPart | 0.29 | EG_Technik_FFB | HA_STV_ECK_xxx_STA_0,200x0,300_xxx | Platte | ToolboxPlate | 0103Pyt0000002277 | St | AT01.2 | <undefiniert>
Kragarm | EG_Technik_FFB | 1282 | 0 | 0.2 | 0.015 | Kragarm | PythonPart | 0.29 | EG_Technik_FFB | HA_STV_ECK_xxx_STA_0,200x0,300_xxx | Platte | ToolboxPlate | 0103Pyt0000002278 | St | AT01.2 | <undefiniert>
Kragarm | EG_Technik_FFB | 1282 | 0 | 0.2 | 0.015 | Kragarm | PythonPart | 0.29 | EG_Technik_FFB | HA_STV_ECK_xxx_STA_0,200x0,300_xxx | Platte | ToolboxPlate | 0103Pyt0000002279 | St | AT01.2 | <undefiniert>
Stirnplatte | EG_Technik_FFB | 1282 | 0 | 0.07 | 0.015 | Stirnplatte | PythonPart | 0.19 | EG_Technik_FFB | HA_STV_ECK_xxx_STA_0,070x0,190_xxx | Platte | ToolboxPlate | 0103Pyt0000002546 | St | AT01.1 | <undefiniert>
Stirnplatte | EG_Technik_FFB | 1282 | 0 | 0.07 | 0.015 | Stirnplatte | PythonPart | 0.19 | EG_Technik_FFB | HA_STV_ECK_xxx_STA_0,070x0,190_xxx | Platte | ToolboxPlate | 0103Pyt0000002549 | St | AT01.1 | <undefiniert>
Stirnplatte | EG_Technik_FFB | 1282 | 0 | 0.07 | 0.015 | Stirnplatte | PythonPart | 0.19 | EG_Technik_FFB | HA_STV_ECK_xxx_STA_0,070x0,190_xxx | Platte | ToolboxPlate | 0103Pyt0000002552 | St | AT01.1 | <undefiniert>
Stirnplatte | EG_Technik_FFB | 1282 | 0 | 0.07 | 0.015 | Stirnplatte | PythonPart | 0.19 | EG_Technik_FFB | HA_STV_ECK_xxx_STA_0,070x0,190_xxx | Platte | ToolboxPlate | 0103Pyt0000002555 | St | AT01.1 | <undefiniert>
Stirnplatte | EG_Technik_FFB | 1282 | 0 | 0.2 | 0.015 | Stirnplatte | PythonPart | 0.29 | EG_Technik_FFB | HA_STV_ECK_xxx_STA_0,200x0,300_xxx | Platte | ToolboxPlate | 0103Pyt0000004467 | St | AT02 | <undefiniert>
Stirnplatte | EG_Technik_FFB | 1282 | 0 | 0.2 | 0.015 | Stirnplatte | PythonPart | 0.29 | EG_Technik_FFB | HA_STV_ECK_xxx_STA_0,200x0,300_xxx | Platte | ToolboxPlate | 0103Pyt0000004468 | St | AT02 | <undefiniert>
Stirnplatte | EG_Technik_FFB | 1282 | 0 | 0.2 | 0.015 | Stirnplatte | PythonPart | 0.29 | EG_Technik_FFB | HA_STV_ECK_xxx_STA_0,200x0,300_xxx | Platte | ToolboxPlate | 0103Pyt0000004469 | St | AT02 | <undefiniert>
Stirnplatte | EG_Technik_FFB | 1282 | 0 | 0.2 | 0.015 | Stirnplatte | PythonPart | 0.29 | EG_Technik_FFB | HA_STV_ECK_xxx_STA_0,200x0,300_xxx | Platte | ToolboxPlate | 0103Pyt0000004470 | St | AT02 | <undefiniert>
Stirnplatte | EG_Technik_FFB | 1282 | 0 | 0.2 | 0.015 | Stirnplatte | PythonPart | 0.29 | EG_Technik_FFB | HA_STV_ECK_xxx_STA_0,200x0,300_xxx | Platte | ToolboxPlate | 0103Pyt0000004471 | St | AT02 | <undefiniert>
Stirnplatte | EG_Technik_FFB | 1282 | 0 | 0.2 | 0.015 | Stirnplatte | PythonPart | 0.29 | EG_Technik_FFB | HA_STV_ECK_xxx_STA_0,200x0,300_xxx | Platte | ToolboxPlate | 0103Pyt0000004472 | St | AT02 | <undefiniert>
Stirnplatte | EG_Technik_FFB | 1282 | 0 | 0.2 | 0.015 | Stirnplatte | PythonPart | 0.29 | EG_Technik_FFB | HA_STV_ECK_xxx_STA_0,200x0,300_xxx | Platte | ToolboxPlate | 0103Pyt0000004473 | St | AT02 | <undefiniert>
Stirnplatte | EG_Technik_FFB | 1282 | 0 | 0.2 | 0.015 | Stirnplatte | PythonPart | 0.29 | EG_Technik_FFB | HA_STV_ECK_xxx_STA_0,200x0,300_xxx | Platte | ToolboxPlate | 0103Pyt0000004474 | St | AT02 | <undefiniert>
Kragarm | EG_Technik_FFB | 1282 | 0 | 0.2 | 0.015 | Kragarm | PythonPart | 0.29 | EG_Technik_FFB | HA_STV_ECK_xxx_STA_0,200x0,300_xxx | Platte | ToolboxPlate | 0103Pyt0000002266 | St | AT01.2 | <undefiniert>
Kragarm | EG_Technik_FFB | 1282 | 0 | 0.2 | 0.015 | Kragarm | PythonPart | 0.29 | EG_Technik_FFB | HA_STV_ECK_xxx_STA_0,200x0,300_xxx | Platte | ToolboxPlate | 0103Pyt0000002267 | St | AT01.2 | <undefiniert>
Kragarm | EG_Technik_FFB | 1282 | 0 | 0.2 | 0.015 | Kragarm | PythonPart | 0.29 | EG_Technik_FFB | HA_STV_ECK_xxx_STA_0,200x0,300_xxx | Platte | ToolboxPlate | 0103Pyt0000002268 | St | AT01.2 | <undefiniert>
Kragarm | EG_Technik_FFB | 1282 | 0 | 0.2 | 0.015 | Kragarm | PythonPart | 0.29 | EG_Technik_FFB | HA_STV_ECK_xxx_STA_0,200x0,300_xxx | Platte | ToolboxPlate | 0103Pyt0000002269 | St | AT01.2 | <undefiniert>
Stirnplatte | EG_Technik_FFB | 1282 | 0 | 0.07 | 0.015 | Stirnplatte | PythonPart | 0.19 | EG_Technik_FFB | HA_STV_ECK_xxx_STA_0,070x0,190_xxx | Platte | ToolboxPlate | 0103Pyt0000002370 | St | AT01.1 | <undefiniert>
Stirnplatte | EG_Technik_FFB | 1282 | 0 | 0.07 | 0.015 | Stirnplatte | PythonPart | 0.19 | EG_Technik_FFB | HA_STV_ECK_xxx_STA_0,070x0,190_xxx | Platte | ToolboxPlate | 0103Pyt0000002381 | St | AT01.1 | <undefiniert>
Stirnplatte | EG_Technik_FFB | 1282 | 0 | 0.07 | 0.015 | Stirnplatte | PythonPart | 0.19 | EG_Technik_FFB | HA_STV_ECK_xxx_STA_0,070x0,190_xxx | Platte | ToolboxPlate | 0103Pyt0000002384 | St | AT01.1 | <undefiniert>
Stirnplatte | EG_Technik_FFB | 1282 | 0 | 0.07 | 0.015 | Stirnplatte | PythonPart | 0.19 | EG_Technik_FFB | HA_STV_ECK_xxx_STA_0,070x0,190_xxx | Platte | ToolboxPlate | 0103Pyt0000002387 | St | AT01.1 | <undefiniert>
Fußplatte | EG_Produktion_FFB |  |  |  |  | Fußplatte |  |  | EG_Produktion_FFB |  | Plate |  | 0112ErE0000001396 | m³ | AR03 | AllplanAttributes - 2D Interaktion: yes; Kurztext: Fußplatte; Profilname: 250x250x15; PlateCommon - Reference: HA_STT_ECK_STA_0,250x0,250x0,015_xxx
Fußplatte | EG_Produktion_FFB |  |  |  |  | Fußplatte |  |  | EG_Produktion_FFB |  | Plate |  | 0112ErE0000001390 | m³ | AR03 | AllplanAttributes - 2D Interaktion: yes; Kurztext: Fußplatte; Profilname: 250x250x15; PlateCommon - Reference: HA_STT_ECK_STA_0,250x0,250x0,015_xxx
Fußplatte | EG_Produktion_FFB |  |  |  |  | Fußplatte |  |  | EG_Produktion_FFB |  | Plate |  | 0112ErE0000001393 | m³ | AR03 | AllplanAttributes - 2D Interaktion: yes; Kurztext: Fußplatte; Profilname: 250x250x15; PlateCommon - Reference: HA_STT_ECK_STA_0,250x0,250x0,015_xxx
Fußplatte | EG_Produktion_FFB |  |  |  |  | Fußplatte |  |  | EG_Produktion_FFB |  | Plate |  | 0112ErE0000001381 | m³ | AR04 | AllplanAttributes - 2D Interaktion: yes; Kurztext: Fußplatte; Profilname: 250x250x15; PlateCommon - Reference: HA_STT_ECK_STA_0,250x0,250x0,015_xxx
Fußplatte | EG_Produktion_FFB |  |  |  |  | Fußplatte |  |  | EG_Produktion_FFB |  | Plate |  | 0112ErE0000001387 | m³ | AR04 | AllplanAttributes - 2D Interaktion: yes; Kurztext: Fußplatte; Profilname: 250x250x15; PlateCommon - Reference: HA_STT_ECK_STA_0,250x0,250x0,015_xxx
Kopfplatte | EG_Produktion_FFB |  |  |  |  | Kopfplatte |  |  | EG_Produktion_FFB |  | Plate |  | 0112ErE0000001397 | m³ | AR03 | AllplanAttributes - 2D Interaktion: yes; Kurztext: Kopfplatte; Profilname: 250x250x15; PlateCommon - Reference: HA_STT_ECK_STA_0,250x0,250x0,015_xxx
Kopfplatte | EG_Produktion_FFB |  |  |  |  | Kopfplatte |  |  | EG_Produktion_FFB |  | Plate |  | 0112ErE0000001391 | m³ | AR03 | AllplanAttributes - 2D Interaktion: yes; Kurztext: Kopfplatte; Profilname: 250x250x15; PlateCommon - Reference: HA_STT_ECK_STA_0,250x0,250x0,015_xxx
Kopfplatte | EG_Produktion_FFB |  |  |  |  | Kopfplatte |  |  | EG_Produktion_FFB |  | Plate |  | 0112ErE0000001386 | m³ | AR04 | AllplanAttributes - 2D Interaktion: yes; Kurztext: Kopfplatte; Profilname: 250x250x15; PlateCommon - Reference: HA_STT_ECK_STA_0,250x0,250x0,015_xxx
Kopfplatte | EG_Produktion_FFB |  |  |  |  | Kopfplatte |  |  | EG_Produktion_FFB |  | Plate |  | 0112ErE0000001394 | m³ | AR03 | AllplanAttributes - 2D Interaktion: yes; Kurztext: Kopfplatte; Profilname: 250x250x15; PlateCommon - Reference: HA_STT_ECK_STA_0,250x0,250x0,015_xxx
Kopfplatte | EG_Produktion_FFB |  |  |  |  | Kopfplatte |  |  | EG_Produktion_FFB |  | Plate |  | 0112ErE0000001388 | m³ | AR04 | AllplanAttributes - 2D Interaktion: yes; Kurztext: Kopfplatte; Profilname: 250x250x15; PlateCommon - Reference: HA_STT_ECK_STA_0,250x0,250x0,015_xxx
Fußplatte | EG_Produktion_FFB |  |  |  |  | Fußplatte |  |  | EG_Produktion_FFB |  | Plate |  | 0112ErE0000004749 | m³ | AR03 | AllplanAttributes - 2D Interaktion: yes; Kurztext: Fußplatte; Profilname: 250x250x15; PlateCommon - Reference: HA_STT_ECK_STA_0,250x0,250x0,015_xxx
Kopfplatte | EG_Produktion_FFB |  |  |  |  | Kopfplatte |  |  | EG_Produktion_FFB |  | Plate |  | 0112ErE0000004750 | m³ | AR03 | AllplanAttributes - 2D Interaktion: yes; Kurztext: Kopfplatte; Profilname: 250x250x15; PlateCommon - Reference: HA_STT_ECK_STA_0,250x0,250x0,015_xxx

# IfcRoof: ROOF, Dachhautschicht
In: EG_Produktion_FFB
Material: Trapezblech
AllplanAttributes - Object Layer Attributes #1, Gewerk: Dachdeckungsarbeiten; Object Layer Attributes #1, Bezeichnung: Dachhautschicht; Object Layer Attributes #1, Material: Trapezblech; Object Layer Attributes #1, Projektionsfläche: 0; Object Layer Attributes #1, Ebene: EG_Produktion_FFB; Object Layer Attributes #1, Attributset-Objekt: Roof; Object Layer Attributes #1, Allright_Bauteil_ID: 0112Dah0000001361; Object Layer Attributes #1, Abrechnungsart: m²
IFC_Pset_TWP - Phase erstellt: Neubau; Material: Stahl; Außenbauteil: true; Kommentar: -; Positionsnummer: AD02; Name: Dachhautschicht
Pset_FM-Vivantes - FM_Klasse: -; FM_Bezeichnung: -; FM_AKS: -; FM_Anzahl: -; FM_Standort: -; FM_Hersteller: -; FM_Hersteller-Typ: -; FM_Seriennummer: -; FM_Baujahr: -; FM_Inbetriebnahme Datum: -; FM_Gewährleistungsende: -; FM_Gewährleistungsgeber: -; FM_Betriebsstatus: -; FM_Prüfpflicht: -; FM_Prüfintervall: -; FM_letzter Prüfungstermin: -; FM_Sammelobjekt: -; FM_rechn. Lebensdauer: -; FM_rechn. Lebensende: -; FM_technischer Zustand: -; FM_voraus. Lebensende: -; FM_Eigentümer: -; FM_Bemerkung: -; FM_Versorgungsbereich-Wirkbereich: -; FM_Zugänglichkeit: -
Pset_RoofCommon - ThermalTransmittance: 0 W/K/m2; Reference: Trapezblech

# IfcSlab (564)
AllplanAttributes - 2D Interaktion: yes; Gewerk: Betonarbeiten
IFC_Pset_TWP - Material: Stahlbeton; Kommentar: -; Phase erstellt: Neubau; statisch tragend: true
Pset_ConcreteElementGeneral - WU-Beton: false; Betonüberdeckung: 1
Pset_FM-Vivantes - FM_Klasse: -; FM_Bezeichnung: -; FM_AKS: -; FM_Anzahl: -; FM_Standort: -; FM_Hersteller: -; FM_Hersteller-Typ: -; FM_Seriennummer: -; FM_Baujahr: -; FM_Inbetriebnahme Datum: -; FM_Gewährleistungsende: -; FM_Gewährleistungsgeber: -; FM_Betriebsstatus: -; FM_Prüfpflicht: -; FM_Prüfintervall: -; FM_letzter Prüfungstermin: -; FM_Sammelobjekt: -; FM_rechn. Lebensdauer: -; FM_rechn. Lebensende: -; FM_technischer Zustand: -; FM_voraus. Lebensende: -; FM_Eigentümer: -; FM_Bemerkung: -; FM_Versorgungsbereich-Wirkbereich: -; FM_Zugänglichkeit: -
Name | In | PredefinedType | Material = AllplanAttributes, Material | Codetext | Bezeichnung = Name | Ebene | Allright_Bauteil_ID | Abrechnungsart | Herstellung | Positionsnummer | Außenbauteil | Bewehrungsgrad | Expositionsklasse | Druckfestigkeitsklasse | Reference | Attributset-Objekt | FireRating | Combustible = Compartmentation | PitchAngle (deg)
Spannbetonhohldecke | EG_Technik_FFB | FLOOR | Stahlbetonfertigteil | Spannbetonhohldecke | Spannbetonhohldecke | EG_Technik_FFB | 0102De 0000004049 | m³ | Fertigteil | D102 | false | 50 | - | - | HI_GES_FEB_0,260_xxx | SlabCommon - Volumen: 0.931846
Spannbetonhohldecke | EG_Technik_FFB | FLOOR | Stahlbetonfertigteil | Spannbetonhohldecke | Spannbetonhohldecke | EG_Technik_FFB | 0102De 0000004055 | m³ | Fertigteil | D102 | false | 50 | - | - | HI_GES_FEB_0,260_xxx | SlabCommon - Volumen: 0.931846
Spannbetonhohldecke | EG_Technik_FFB | FLOOR | Stahlbetonfertigteil | Spannbetonhohldecke | Spannbetonhohldecke | EG_Technik_FFB | 0102De 0000004057 | m³ | Fertigteil | D102 | false | 50 | - | - | HI_GES_FEB_0,260_xxx | SlabCommon - Volumen: 0.931846
Spannbetonhohldecke | EG_Technik_FFB | FLOOR | Stahlbetonfertigteil | Spannbetonhohldecke | Spannbetonhohldecke | EG_Technik_FFB | 0102De 0000004059 | m³ | Fertigteil | D102 | false | 50 | - | - | HI_GES_FEB_0,260_xxx | SlabCommon - Volumen: 0.985346
Spannbetonhohldecke | EG_Technik_FFB | FLOOR | Stahlbetonfertigteil | Spannbetonhohldecke | Spannbetonhohldecke | EG_Technik_FFB | 0102De 0000003516 | m³ | Fertigteil | D102 | false | 50 | - | - | HI_GES_FEB_0,260_xxx | SlabCommon - Volumen: 0.931846
Spannbetonhohldecke | EG_Technik_FFB | FLOOR | Stahlbetonfertigteil | Spannbetonhohldecke | Spannbetonhohldecke | EG_Technik_FFB | 0102De 0000004053 | m³ | Fertigteil | D102 | false | 50 | - | - | HI_GES_FEB_0,260_xxx | SlabCommon - Volumen: 0.931846
Spannbetonhohldecke | EG_Technik_FFB | FLOOR | Stahlbetonfertigteil | Spannbetonhohldecke | Spannbetonhohldecke | EG_Technik_FFB | 0102De 0000004051 | m³ | Fertigteil | D102 | false | 50 | - | - | HI_GES_FEB_0,260_xxx | SlabCommon - Volumen: 0.931846
Spannbetonhohldecke | EG_Technik_FFB | FLOOR | Stahlbetonfertigteil | Spannbetonhohldecke | Spannbetonhohldecke | EG_Technik_FFB | 0102De 0000003932 | m³ | Fertigteil | D102 | false | 50 | - | - | HI_GES_FEB_0,260_xxx | SlabCommon - Volumen: 2.57008
Spannbetonhohldecke | EG_Technik_FFB | FLOOR | Stahlbetonfertigteil | Spannbetonhohldecke | Spannbetonhohldecke | EG_Technik_FFB | 0102De 0000003646 | m³ | Fertigteil | D102 | false | 50 | - | - | HI_GES_FEB_0,260_xxx | SlabCommon - Volumen: 2.63606
Spannbetonhohldecke | EG_Technik_FFB | FLOOR | Stahlbetonfertigteil | Spannbetonhohldecke | Spannbetonhohldecke | EG_Technik_FFB | 0102De 0000003542 | m³ | Fertigteil | D102 | false | 50 | - | - | HI_GES_FEB_0,260_xxx | SlabCommon - Volumen: 2.59541
Spannbetonhohldecke | EG_Technik_FFB | FLOOR | Stahlbetonfertigteil | Spannbetonhohldecke | Spannbetonhohldecke | EG_Technik_FFB | 0102De 0000004753 | m³ | Fertigteil | D102 | false | 50 | - | - | HI_GES_FEB_0,260_xxx | SlabCommon - Volumen: 0.734845
Spannbetonhohldecke | EG_Technik_FFB | FLOOR | Stahlbetonfertigteil | Spannbetonhohldecke | Spannbetonhohldecke | EG_Technik_FFB | 0102De 0000003860 | m³ | Fertigteil | D102 | false | 50 | - | - | HI_GES_FEB_0,260_xxx | SlabCommon - Volumen: 0.734845
Spannbetonhohldecke | EG_Technik_FFB | FLOOR | Stahlbetonfertigteil | Spannbetonhohldecke | Spannbetonhohldecke | EG_Technik_FFB | 0102De 0000003960 | m³ | Fertigteil | D102 | false | 50 | - | - | HI_GES_FEB_0,260_xxx | SlabCommon - Volumen: 2.59541
Spannbetonhohldecke | EG_Technik_FFB | FLOOR | Stahlbetonfertigteil | Spannbetonhohldecke | Spannbetonhohldecke | EG_Technik_FFB | 0102De 0000003638 | m³ | Fertigteil | D102 | false | 50 | - | - | HI_GES_FEB_0,260_xxx | SlabCommon - Volumen: 2.23395
Spannbetonhohldecke | EG_Technik_FFB | FLOOR | Stahlbetonfertigteil | Spannbetonhohldecke | Spannbetonhohldecke | EG_Technik_FFB | 0102De 0000003858 | m³ | Fertigteil | D102 | false | 50 | - | - | HI_GES_FEB_0,260_xxx | SlabCommon - Volumen: 0.734845
Spannbetonhohldecke | EG_Technik_FFB | FLOOR | Stahlbetonfertigteil | Spannbetonhohldecke | Spannbetonhohldecke | EG_Technik_FFB | 0102De 0000003826 | m³ | Fertigteil | D102 | false | 50 | - | - | HI_GES_FEB_0,260_xxx | SlabCommon - Volumen: 0.734845
Spannbetonhohldecke | EG_Technik_FFB | FLOOR | Stahlbetonfertigteil | Spannbetonhohldecke | Spannbetonhohldecke | EG_Technik_FFB | 0102De 0000003974 | m³ | Fertigteil | D102 | false | 50 | - | - | HI_GES_FEB_0,260_xxx | SlabCommon - Volumen: 2.59541
Spannbetonhohldecke | EG_Technik_FFB | FLOOR | Stahlbetonfertigteil | Spannbetonhohldecke | Spannbetonhohldecke | EG_Technik_FFB | 0102De 0000004010 | m³ | Fertigteil | D102 | false | 50 | - | - | HI_GES_FEB_0,260_xxx | SlabCommon - Volumen: 2.80805
Spannbetonhohldecke | EG_Technik_FFB | FLOOR | Stahlbetonfertigteil | Spannbetonhohldecke | Spannbetonhohldecke | EG_Technik_FFB | 0102De 0000003668 | m³ | Fertigteil | D102 | false | 50 | - | - | HI_GES_FEB_0,260_xxx | SlabCommon - Volumen: 2.80805
Spannbetonhohldecke | EG_Technik_FFB | FLOOR | Stahlbetonfertigteil | Spannbetonhohldecke | Spannbetonhohldecke | EG_Technik_FFB | 0102De 0000004014 | m³ | Fertigteil | D102 | false | 50 | - | - | HI_GES_FEB_0,260_xxx | SlabCommon - Volumen: 2.80805
Spannbetonhohldecke | EG_Technik_FFB | FLOOR | Stahlbetonfertigteil | Spannbetonhohldecke | Spannbetonhohldecke | EG_Technik_FFB | 0102De 0000004647 | m³ | Fertigteil | D102 | false | 50 | - | - | HI_GES_FEB_0,260_xxx | SlabCommon - Volumen: 2.80805
Spannbetonhohldecke | EG_Technik_FFB | FLOOR | Stahlbetonfertigteil | Spannbetonhohldecke | Spannbetonhohldecke | EG_Technik_FFB | 0102De 0000004649 | m³ | Fertigteil | D102 | false | 50 | - | - | HI_GES_FEB_0,260_xxx | SlabCommon - Volumen: 1.78478
Spannbetonhohldecke | EG_Technik_FFB | FLOOR | Stahlbetonfertigteil | Spannbetonhohldecke | Spannbetonhohldecke | EG_Technik_FFB | 0102De 0000003930 | m³ | Fertigteil | D102 | false | 50 | - | - | HI_GES_FEB_0,260_xxx | SlabCommon - Volumen: 2.55565
Spannbetonhohldecke | EG_Technik_FFB | FLOOR | Stahlbetonfertigteil | Spannbetonhohldecke | Spannbetonhohldecke | EG_Technik_FFB | 0102De 0000003832 | m³ | Fertigteil | D102 | false | 50 | - | - | HI_GES_FEB_0,260_xxx | SlabCommon - Volumen: 0.694194
Spannbetonhohldecke | EG_Technik_FFB | FLOOR | Stahlbetonfertigteil | Spannbetonhohldecke | Spannbetonhohldecke | EG_Technik_FFB | 0102De 0000003850 | m³ | Fertigteil | D102 | false | 50 | - | - | HI_GES_FEB_0,260_xxx | SlabCommon - Volumen: 0.734845
Spannbetonhohldecke | EG_Technik_FFB | FLOOR | Stahlbetonfertigteil | Spannbetonhohldecke | Spannbetonhohldecke | EG_Technik_FFB | 0102De 0000003566 | m³ | Fertigteil | D102 | false | 50 | - | - | HI_GES_FEB_0,260_xxx | SlabCommon - Volumen: 2.59541
Spannbetonhohldecke | EG_Technik_FFB | FLOOR | Stahlbetonfertigteil | Spannbetonhohldecke | Spannbetonhohldecke | EG_Technik_FFB | 0102De 0000003830 | m³ | Fertigteil | D102 | false | 50 | - | - | HI_GES_FEB_0,260_xxx | SlabCommon - Volumen: 0.694194
Spannbetonhohldecke | EG_Technik_FFB | FLOOR | Stahlbetonfertigteil | Spannbetonhohldecke | Spannbetonhohldecke | EG_Technik_FFB | 0102De 0000003834 | m³ | Fertigteil | D102 | false | 50 | - | - | HI_GES_FEB_0,260_xxx | SlabCommon - Volumen: 0.694194
Spannbetonhohldecke | EG_Technik_FFB | FLOOR | Stahlbetonfertigteil | Spannbetonhohldecke | Spannbetonhohldecke | EG_Technik_FFB | 0102De 0000003952 | m³ | Fertigteil | D102 | false | 50 | - | - | HI_GES_FEB_0,260_xxx | SlabCommon - Volumen: 2.59541
Spannbetonhohldecke | EG_Technik_FFB | FLOOR | Stahlbetonfertigteil | Spannbetonhohldecke | Spannbetonhohldecke | EG_Technik_FFB | 0102De 0000003544 | m³ | Fertigteil | D102 | false | 50 | - | - | HI_GES_FEB_0,260_xxx | SlabCommon - Volumen: 0.734845
Spannbetonhohldecke | EG_Technik_FFB | FLOOR | Stahlbetonfertigteil | Spannbetonhohldecke | Spannbetonhohldecke | EG_Technik_FFB | 0102De 0000004617 | m³ | Fertigteil | D102 | false | 50 | - | - | HI_GES_FEB_0,260_xxx | SlabCommon - Volumen: 0.92379
Spannbetonhohldecke | EG_Technik_FFB | FLOOR | Stahlbetonfertigteil | Spannbetonhohldecke | Spannbetonhohldecke | EG_Technik_FFB | 0102De 0000003972 | m³ | Fertigteil | D102 | false | 50 | - | - | HI_GES_FEB_0,260_xxx | SlabCommon - Volumen: 2.59541
Spannbetonhohldecke | EG_Technik_FFB | FLOOR | Stahlbetonfertigteil | Spannbetonhohldecke | Spannbetonhohldecke | EG_Technik_FFB | 0102De 0000003586 | m³ | Fertigteil | D102 | false | 50 | - | - | HI_GES_FEB_0,260_xxx | SlabCommon - Volumen: 2.59541
Spannbetonhohldecke | EG_Technik_FFB | FLOOR | Stahlbetonfertigteil | Spannbetonhohldecke | Spannbetonhohldecke | EG_Technik_FFB | 0102De 0000003709 | m³ | Fertigteil | D102 | false | 50 | - | - | HI_GES_FEB_0,260_xxx | SlabCommon - Volumen: 2.80805
Spannbetonhohldecke | EG_Technik_FFB | FLOOR | Stahlbetonfertigteil | Spannbetonhohldecke | Spannbetonhohldecke | EG_Technik_FFB | 0102De 0000003718 | m³ | Fertigteil | D102 | false | 50 | - | - | HI_GES_FEB_0,260_xxx | SlabCommon - Volumen: 2.80805
Spannbetonhohldecke | EG_Technik_FFB | FLOOR | Stahlbetonfertigteil | Spannbetonhohldecke | Spannbetonhohldecke | EG_Technik_FFB | 0102De 0000003614 | m³ | Fertigteil | D102 | false | 50 | - | - | HI_GES_FEB_0,260_xxx | SlabCommon - Volumen: 2.59541
Spannbetonhohldecke | EG_Technik_FFB | FLOOR | Stahlbetonfertigteil | Spannbetonhohldecke | Spannbetonhohldecke | EG_Technik_FFB | 0102De 0000003806 | m³ | Fertigteil | D102 | false | 50 | - | - | HI_GES_FEB_0,260_xxx | SlabCommon - Volumen: 0.734845
Spannbetonhohldecke | EG_Technik_FFB | FLOOR | Stahlbetonfertigteil | Spannbetonhohldecke | Spannbetonhohldecke | EG_Technik_FFB | 0102De 0000003856 | m³ | Fertigteil | D102 | false | 50 | - | - | HI_GES_FEB_0,260_xxx | SlabCommon - Volumen: 0.734845
Spannbetonhohldecke | EG_Technik_FFB | FLOOR | Stahlbetonfertigteil | Spannbetonhohldecke | Spannbetonhohldecke | EG_Technik_FFB | 0102De 0000003936 | m³ | Fertigteil | D102 | false | 50 | - | - | HI_GES_FEB_0,260_xxx | SlabCommon - Volumen: 2.59541
Spannbetonhohldecke | EG_Technik_FFB | FLOOR | Stahlbetonfertigteil | Spannbetonhohldecke | Spannbetonhohldecke | EG_Technik_FFB | 0102De 0000003610 | m³ | Fertigteil | D102 | false | 50 | - | - | HI_GES_FEB_0,260_xxx | SlabCommon - Volumen: 2.59541
Spannbetonhohldecke | EG_Technik_FFB | FLOOR | Stahlbetonfertigteil | Spannbetonhohldecke | Spannbetonhohldecke | EG_Technik_FFB | 0102De 0000003942 | m³ | Fertigteil | D102 | false | 50 | - | - | HI_GES_FEB_0,260_xxx | SlabCommon - Volumen: 2.59541
Spannbetonhohldecke | EG_Technik_FFB | FLOOR | Stahlbetonfertigteil | Spannbetonhohldecke | Spannbetonhohldecke | EG_Technik_FFB | 0102De 0000003822 | m³ | Fertigteil | D102 | false | 50 | - | - | HI_GES_FEB_0,260_xxx | SlabCommon - Volumen: 0.734845
Spannbetonhohldecke | EG_Technik_FFB | FLOOR | Stahlbetonfertigteil | Spannbetonhohldecke | Spannbetonhohldecke | EG_Technik_FFB | 0102De 0000004016 | m³ | Fertigteil | D102 | false | 50 | - | - | HI_GES_FEB_0,260_xxx | SlabCommon - Volumen: 2.80805
Spannbetonhohldecke | EG_Technik_FFB | FLOOR | Stahlbetonfertigteil | Spannbetonhohldecke | Spannbetonhohldecke | EG_Technik_FFB | 0102De 0000003954 | m³ | Fertigteil | D102 | false | 50 | - | - | HI_GES_FEB_0,260_xxx | SlabCommon - Volumen: 2.59541
Spannbetonhohldecke | EG_Technik_FFB | FLOOR | Stahlbetonfertigteil | Spannbetonhohldecke | Spannbetonhohldecke | EG_Technik_FFB | 0102De 0000003956 | m³ | Fertigteil | D102 | false | 50 | - | - | HI_GES_FEB_0,260_xxx | SlabCommon - Volumen: 2.59541
Spannbetonhohldecke | EG_Technik_FFB | FLOOR | Stahlbetonfertigteil | Spannbetonhohldecke | Spannbetonhohldecke | EG_Technik_FFB | 0102De 0000003664 | m³ | Fertigteil | D102 | false | 50 | - | - | HI_GES_FEB_0,260_xxx | SlabCommon - Volumen: 2.7568
Spannbetonhohldecke | EG_Technik_FFB | FLOOR | Stahlbetonfertigteil | Spannbetonhohldecke | Spannbetonhohldecke | EG_Technik_FFB | 0102De 0000003840 | m³ | Fertigteil | D102 | false | 50 | - | - | HI_GES_FEB_0,260_xxx | SlabCommon - Volumen: 0.694194
Spannbetonhohldecke | EG_Technik_FFB | FLOOR | Stahlbetonfertigteil | Spannbetonhohldecke | Spannbetonhohldecke | EG_Technik_FFB | 0102De 0000003852 | m³ | Fertigteil | D102 | false | 50 | - | - | HI_GES_FEB_0,260_xxx | SlabCommon - Volumen: 0.734845
Spannbetonhohldecke | EG_Technik_FFB | FLOOR | Stahlbetonfertigteil | Spannbetonhohldecke | Spannbetonhohldecke | EG_Technik_FFB | 0102De 0000003966 | m³ | Fertigteil | D102 | false | 50 | - | - | HI_GES_FEB_0,260_xxx | SlabCommon - Volumen: 2.59541
Spannbetonhohldecke | EG_Technik_FFB | FLOOR | Stahlbetonfertigteil | Spannbetonhohldecke | Spannbetonhohldecke | EG_Technik_FFB | 0102De 0000004008 | m³ | Fertigteil | D102 | false | 50 | - | - | HI_GES_FEB_0,260_xxx | SlabCommon - Volumen: 2.80805
Spannbetonhohldecke | EG_Technik_FFB | FLOOR | Stahlbetonfertigteil | Spannbetonhohldecke | Spannbetonhohldecke | EG_Technik_FFB | 0102De 0000003866 | m³ | Fertigteil | D102 | false | 50 | - | - | HI_GES_FEB_0,260_xxx | SlabCommon - Volumen: 0.734845
Spannbetonhohldecke | EG_Technik_FFB | FLOOR | Stahlbetonfertigteil | Spannbetonhohldecke | Spannbetonhohldecke | EG_Technik_FFB | 0102De 0000004004 | m³ | Fertigteil | D102 | false | 50 | - | - | HI_GES_FEB_0,260_xxx | SlabCommon - Volumen: 2.79168
Spannbetonhohldecke | EG_Technik_FFB | FLOOR | Stahlbetonfertigteil | Spannbetonhohldecke | Spannbetonhohldecke | EG_Technik_FFB | 0102De 0000003594 | m³ | Fertigteil | D102 | false | 50 | - | - | HI_GES_FEB_0,260_xxx | SlabCommon - Volumen: 2.59541
Spannbetonhohldecke | EG_Technik_FFB | FLOOR | Stahlbetonfertigteil | Spannbetonhohldecke | Spannbetonhohldecke | EG_Technik_FFB | 0102De 0000003940 | m³ | Fertigteil | D102 | false | 50 | - | - | HI_GES_FEB_0,260_xxx | SlabCommon - Volumen: 2.59541
Spannbetonhohldecke | EG_Technik_FFB | FLOOR | Stahlbetonfertigteil | Spannbetonhohldecke | Spannbetonhohldecke | EG_Technik_FFB | 0102De 0000003928 | m³ | Fertigteil | D102 | false | 50 | - | - | HI_GES_FEB_0,260_xxx | SlabCommon - Volumen: 2.57291
Spannbetonhohldecke | EG_Technik_FFB | FLOOR | Stahlbetonfertigteil | Spannbetonhohldecke | Spannbetonhohldecke | EG_Technik_FFB | 0102De 0000003630 | m³ | Fertigteil | D102 | false | 50 | - | - | HI_GES_FEB_0,260_xxx | SlabCommon - Volumen: 2.59541
Spannbetonhohldecke | EG_Technik_FFB | FLOOR | Stahlbetonfertigteil | Spannbetonhohldecke | Spannbetonhohldecke | EG_Technik_FFB | 0102De 0000003950 | m³ | Fertigteil | D102 | false | 50 | - | - | HI_GES_FEB_0,260_xxx | SlabCommon - Volumen: 2.59541
Spannbetonhohldecke | EG_Technik_FFB | FLOOR | Stahlbetonfertigteil | Spannbetonhohldecke | Spannbetonhohldecke | EG_Technik_FFB | 0102De 0000003606 | m³ | Fertigteil | D102 | false | 50 | - | - | HI_GES_FEB_0,260_xxx | SlabCommon - Volumen: 2.59541
Spannbetonhohldecke | EG_Technik_FFB | FLOOR | Stahlbetonfertigteil | Spannbetonhohldecke | Spannbetonhohldecke | EG_Technik_FFB | 0102De 0000003854 | m³ | Fertigteil | D102 | false | 50 | - | - | HI_GES_FEB_0,260_xxx | SlabCommon - Volumen: 0.734845
Spannbetonhohldecke | EG_Technik_FFB | FLOOR | Stahlbetonfertigteil | Spannbetonhohldecke | Spannbetonhohldecke | EG_Technik_FFB | 0102De 0000003848 | m³ | Fertigteil | D102 | false | 50 | - | - | HI_GES_FEB_0,260_xxx | SlabCommon - Volumen: 0.734845
Spannbetonhohldecke | EG_Technik_FFB | FLOOR | Stahlbetonfertigteil | Spannbetonhohldecke | Spannbetonhohldecke | EG_Technik_FFB | 0102De 0000003828 | m³ | Fertigteil | D102 | false | 50 | - | - | HI_GES_FEB_0,260_xxx | SlabCommon - Volumen: 0.725888
Spannbetonhohldecke | EG_Technik_FFB | FLOOR | Stahlbetonfertigteil | Spannbetonhohldecke | Spannbetonhohldecke | EG_Technik_FFB | 0102De 0000003924 | m³ | Fertigteil | D102 | false | 50 | - | - | HI_GES_FEB_0,260_xxx | SlabCommon - Volumen: 2.59541
Spannbetonhohldecke | EG_Technik_FFB | FLOOR | Stahlbetonfertigteil | Spannbetonhohldecke | Spannbetonhohldecke | EG_Technik_FFB | 0102De 0000003970 | m³ | Fertigteil | D102 | false | 50 | - | - | HI_GES_FEB_0,260_xxx | SlabCommon - Volumen: 2.59541
Spannbetonhohldecke | EG_Technik_FFB | FLOOR | Stahlbetonfertigteil | Spannbetonhohldecke | Spannbetonhohldecke | EG_Technik_FFB | 0102De 0000003864 | m³ | Fertigteil | D102 | false | 50 | - | - | HI_GES_FEB_0,260_xxx | SlabCommon - Volumen: 0.734845
Spannbetonhohldecke | EG_Technik_FFB | FLOOR | Stahlbetonfertigteil | Spannbetonhohldecke | Spannbetonhohldecke | EG_Technik_FFB | 0102De 0000000175 | m³ | Fertigteil | D102 | false | 50 | - | - | HI_GES_FEB_0,260_xxx | SlabCommon - Volumen: 2.59541
Spannbetonhohldecke | EG_Technik_FFB | FLOOR | Stahlbetonfertigteil | Spannbetonhohldecke | Spannbetonhohldecke | EG_Technik_FFB | 0102De 0000003846 | m³ | Fertigteil | D102 | false | 50 | - | - | HI_GES_FEB_0,260_xxx | SlabCommon - Volumen: 0.719687
Spannbetonhohldecke | EG_Technik_FFB | FLOOR | Stahlbetonfertigteil | Spannbetonhohldecke | Spannbetonhohldecke | EG_Technik_FFB | 0102De 0000003717 | m³ | Fertigteil | D102 | false | 50 | - | - | HI_GES_FEB_0,260_xxx | SlabCommon - Volumen: 2.80805
Spannbetonhohldecke | EG_Technik_FFB | FLOOR | Stahlbetonfertigteil | Spannbetonhohldecke | Spannbetonhohldecke | EG_Technik_FFB | 0102De 0000003674 | m³ | Fertigteil | D102 | false | 50 | - | - | HI_GES_FEB_0,260_xxx | SlabCommon - Volumen: 2.80805
Spannbetonhohldecke | EG_Technik_FFB | FLOOR | Stahlbetonfertigteil | Spannbetonhohldecke | Spannbetonhohldecke | EG_Technik_FFB | 0102De 0000003976 | m³ | Fertigteil | D102 | false | 50 | - | - | HI_GES_FEB_0,260_xxx | SlabCommon - Volumen: 2.59541
Spannbetonhohldecke | EG_Technik_FFB | FLOOR | Stahlbetonfertigteil | Spannbetonhohldecke | Spannbetonhohldecke | EG_Technik_FFB | 0102De 0000003824 | m³ | Fertigteil | D102 | false | 50 | - | - | HI_GES_FEB_0,260_xxx | SlabCommon - Volumen: 0.734845
Spannbetonhohldecke | EG_Technik_FFB | FLOOR | Stahlbetonfertigteil | Spannbetonhohldecke | Spannbetonhohldecke | EG_Technik_FFB | 0102De 0000003582 | m³ | Fertigteil | D102 | false | 50 | - | - | HI_GES_FEB_0,260_xxx | SlabCommon - Volumen: 2.59541
Spannbetonhohldecke | EG_Technik_FFB | FLOOR | Stahlbetonfertigteil | Spannbetonhohldecke | Spannbetonhohldecke | EG_Technik_FFB | 0102De 0000003532 | m³ | Fertigteil | D102 | false | 50 | - | - | HI_GES_FEB_0,260_xxx | SlabCommon - Volumen: 0.668595
Spannbetonhohldecke | EG_Technik_FFB | FLOOR | Stahlbetonfertigteil | Spannbetonhohldecke | Spannbetonhohldecke | EG_Technik_FFB | 0102De 0000003818 | m³ | Fertigteil | D102 | false | 50 | - | - | HI_GES_FEB_0,260_xxx | SlabCommon - Volumen: 0.734845
Spannbetonhohldecke | EG_Technik_FFB | FLOOR | Stahlbetonfertigteil | Spannbetonhohldecke | Spannbetonhohldecke | EG_Technik_FFB | 0102De 0000003666 | m³ | Fertigteil | D102 | false | 50 | - | - | HI_GES_FEB_0,260_xxx | SlabCommon - Volumen: 2.80805
Spannbetonhohldecke | EG_Technik_FFB | FLOOR | Stahlbetonfertigteil | Spannbetonhohldecke | Spannbetonhohldecke | EG_Technik_FFB | 0102De 0000003868 | m³ | Fertigteil | D102 | false | 50 | - | - | HI_GES_FEB_0,260_xxx | SlabCommon - Volumen: 0.734845
Spannbetonhohldecke | EG_Technik_FFB | FLOOR | Stahlbetonfertigteil | Spannbetonhohldecke | Spannbetonhohldecke | EG_Technik_FFB | 0102De 0000003716 | m³ | Fertigteil | D102 | false | 50 | - | - | HI_GES_FEB_0,260_xxx | SlabCommon - Volumen: 2.80805
Spannbetonhohldecke | EG_Technik_FFB | FLOOR | Stahlbetonfertigteil | Spannbetonhohldecke | Spannbetonhohldecke | EG_Technik_FFB | 0102De 0000003618 | m³ | Fertigteil | D102 | false | 50 | - | - | HI_GES_FEB_0,260_xxx | SlabCommon - Volumen: 2.59541
Spannbetonhohldecke | EG_Technik_FFB | FLOOR | Stahlbetonfertigteil | Spannbetonhohldecke | Spannbetonhohldecke | EG_Technik_FFB | 0102De 0000003781 | m³ | Fertigteil | D102 | false | 50 | - | - | HI_GES_FEB_0,260_xxx | SlabCommon - Volumen: 2.16232
Spannbetonhohldecke | EG_Technik_FFB | FLOOR | Stahlbetonfertigteil | Spannbetonhohldecke | Spannbetonhohldecke | EG_Technik_FFB | 0102De 0000003962 | m³ | Fertigteil | D102 | false | 50 | - | - | HI_GES_FEB_0,260_xxx | SlabCommon - Volumen: 2.59541
Spannbetonhohldecke | EG_Technik_FFB | FLOOR | Stahlbetonfertigteil | Spannbetonhohldecke | Spannbetonhohldecke | EG_Technik_FFB | 0102De 0000003626 | m³ | Fertigteil | D102 | false | 50 | - | - | HI_GES_FEB_0,260_xxx | SlabCommon - Volumen: 2.59541
Spannbetonhohldecke | EG_Technik_FFB | FLOOR | Stahlbetonfertigteil | Spannbetonhohldecke | Spannbetonhohldecke | EG_Technik_FFB | 0102De 0000003590 | m³ | Fertigteil | D102 | false | 50 | - | - | HI_GES_FEB_0,260_xxx | SlabCommon - Volumen: 2.59541
Spannbetonhohldecke | EG_Technik_FFB | FLOOR | Stahlbetonfertigteil | Spannbetonhohldecke | Spannbetonhohldecke | EG_Technik_FFB | 0102De 0000004648 | m³ | Fertigteil | D102 | false | 50 | - | - | HI_GES_FEB_0,260_xxx | SlabCommon - Volumen: 2.80805
Spannbetonhohldecke | EG_Technik_FFB | FLOOR | Stahlbetonfertigteil | Spannbetonhohldecke | Spannbetonhohldecke | EG_Technik_FFB | 0102De 0000003836 | m³ | Fertigteil | D102 | false | 50 | - | - | HI_GES_FEB_0,260_xxx | SlabCommon - Volumen: 0.694194
Spannbetonhohldecke | EG_Technik_FFB | FLOOR | Stahlbetonfertigteil | Spannbetonhohldecke | Spannbetonhohldecke | EG_Technik_FFB | 0102De 0000003602 | m³ | Fertigteil | D102 | false | 50 | - | - | HI_GES_FEB_0,260_xxx | SlabCommon - Volumen: 2.59541
Spannbetonhohldecke | EG_Technik_FFB | FLOOR | Stahlbetonfertigteil | Spannbetonhohldecke | Spannbetonhohldecke | EG_Technik_FFB | 0102De 0000003548 | m³ | Fertigteil | D102 | false | 50 | - | - | HI_GES_FEB_0,260_xxx | SlabCommon - Volumen: 2.59541
Spannbetonhohldecke | EG_Technik_FFB | FLOOR | Stahlbetonfertigteil | Spannbetonhohldecke | Spannbetonhohldecke | EG_Technik_FFB | 0102De 0000003838 | m³ | Fertigteil | D102 | false | 50 | - | - | HI_GES_FEB_0,260_xxx | SlabCommon - Volumen: 0.694194
Spannbetonhohldecke | EG_Technik_FFB | FLOOR | Stahlbetonfertigteil | Spannbetonhohldecke | Spannbetonhohldecke | EG_Technik_FFB | 0102De 0000003622 | m³ | Fertigteil | D102 | false | 50 | - | - | HI_GES_FEB_0,260_xxx | SlabCommon - Volumen: 2.59541
Spannbetonhohldecke | EG_Technik_FFB | FLOOR | Stahlbetonfertigteil | Spannbetonhohldecke | Spannbetonhohldecke | EG_Technik_FFB | 0102De 0000004747 | m³ | Fertigteil | D102 | false | 50 | - | - | HI_GES_FEB_0,260_xxx | SlabCommon - Volumen: 2.59541
Spannbetonhohldecke | EG_Technik_FFB | FLOOR | Stahlbetonfertigteil | Spannbetonhohldecke | Spannbetonhohldecke | EG_Technik_FFB | 0102De 0000003707 | m³ | Fertigteil | D102 | false | 50 | - | - | HI_GES_FEB_0,260_xxx | SlabCommon - Volumen: 2.80805
Spannbetonhohldecke | EG_Technik_FFB | FLOOR | Stahlbetonfertigteil | Spannbetonhohldecke | Spannbetonhohldecke | EG_Technik_FFB | 0102De 0000003634 | m³ | Fertigteil | D102 | false | 50 | - | - | HI_GES_FEB_0,260_xxx | SlabCommon - Volumen: 2.59541
Spannbetonhohldecke | EG_Technik_FFB | FLOOR | Stahlbetonfertigteil | Spannbetonhohldecke | Spannbetonhohldecke | EG_Technik_FFB | 0102De 0000003946 | m³ | Fertigteil | D102 | false | 50 | - | - | HI_GES_FEB_0,260_xxx | SlabCommon - Volumen: 2.56503
Spannbetonhohldecke | EG_Technik_FFB | FLOOR | Stahlbetonfertigteil | Spannbetonhohldecke | Spannbetonhohldecke | EG_Technik_FFB | 0102De 0000003944 | m³ | Fertigteil | D102 | false | 50 | - | - | HI_GES_FEB_0,260_xxx | SlabCommon - Volumen: 2.58604
Spannbetonhohldecke | EG_Technik_FFB | FLOOR | Stahlbetonfertigteil | Spannbetonhohldecke | Spannbetonhohldecke | EG_Technik_FFB | 0102De 0000003642 | m³ | Fertigteil | D102 | false | 50 | - | - | HI_GES_FEB_0,260_xxx | SlabCommon - Volumen: 2.63606
Spannbetonhohldecke | EG_Technik_FFB | FLOOR | Stahlbetonfertigteil | Spannbetonhohldecke | Spannbetonhohldecke | EG_Technik_FFB | 0102De 0000003676 | m³ | Fertigteil | D102 | false | 50 | - | - | HI_GES_FEB_0,260_xxx | SlabCommon - Volumen: 2.80805
Spannbetonhohldecke | EG_Technik_FFB | FLOOR | Stahlbetonfertigteil | Spannbetonhohldecke | Spannbetonhohldecke | EG_Technik_FFB | 0102De 0000003820 | m³ | Fertigteil | D102 | false | 50 | - | - | HI_GES_FEB_0,260_xxx | SlabCommon - Volumen: 0.734845
Spannbetonhohldecke | EG_Technik_FFB | FLOOR | Stahlbetonfertigteil | Spannbetonhohldecke | Spannbetonhohldecke | EG_Technik_FFB | 0102De 0000003844 | m³ | Fertigteil | D102 | false | 50 | - | - | HI_GES_FEB_0,260_xxx | SlabCommon - Volumen: 0.694194
Spannbetonhohldecke | EG_Technik_FFB | FLOOR | Stahlbetonfertigteil | Spannbetonhohldecke | Spannbetonhohldecke | EG_Technik_FFB | 0102De 0000003908 | m³ | Fertigteil | D102 | false | 50 | - | - | HI_GES_FEB_0,260_xxx | SlabCommon - Volumen: 1.58364
Spannbetonhohldecke | EG_Technik_FFB | FLOOR | Stahlbetonfertigteil | Spannbetonhohldecke | Spannbetonhohldecke | EG_Technik_FFB | 0102De 0000003934 | m³ | Fertigteil | D102 | false | 50 | - | - | HI_GES_FEB_0,260_xxx | SlabCommon - Volumen: 2.59541
Spannbetonhohldecke | EG_Technik_FFB | FLOOR | Stahlbetonfertigteil | Spannbetonhohldecke | Spannbetonhohldecke | EG_Technik_FFB | 0102De 0000003680 | m³ | Fertigteil | D102 | false | 50 | - | - | HI_GES_FEB_0,260_xxx | SlabCommon - Volumen: 2.73881
Spannbetonhohldecke | EG_Technik_FFB | FLOOR | Stahlbetonfertigteil | Spannbetonhohldecke | Spannbetonhohldecke | EG_Technik_FFB | 0102De 0000003938 | m³ | Fertigteil | D102 | false | 50 | - | - | HI_GES_FEB_0,260_xxx | SlabCommon - Volumen: 2.59541
Spannbetonhohldecke | EG_Technik_FFB | FLOOR | Stahlbetonfertigteil | Spannbetonhohldecke | Spannbetonhohldecke | EG_Technik_FFB | 0102De 0000003678 | m³ | Fertigteil | D102 | false | 50 | - | - | HI_GES_FEB_0,260_xxx | SlabCommon - Volumen: 2.80805
Spannbetonhohldecke | EG_Technik_FFB | FLOOR | Stahlbetonfertigteil | Spannbetonhohldecke | Spannbetonhohldecke | EG_Technik_FFB | 0102De 0000003862 | m³ | Fertigteil | D102 | false | 50 | - | - | HI_GES_FEB_0,260_xxx | SlabCommon - Volumen: 0.734845
Spannbetonhohldecke | EG_Technik_FFB | FLOOR | Stahlbetonfertigteil | Spannbetonhohldecke | Spannbetonhohldecke | EG_Technik_FFB | 0102De 0000003958 | m³ | Fertigteil | D102 | false | 50 | - | - | HI_GES_FEB_0,260_xxx | SlabCommon - Volumen: 2.59541
Spannbetonhohldecke | EG_Technik_FFB | FLOOR | Stahlbetonfertigteil | Spannbetonhohldecke | Spannbetonhohldecke | EG_Technik_FFB | 0102De 0000003672 | m³ | Fertigteil | D102 | false | 50 | - | - | HI_GES_FEB_0,260_xxx | SlabCommon - Volumen: 2.80805
Spannbetonhohldecke | EG_Technik_FFB | FLOOR | Stahlbetonfertigteil | Spannbetonhohldecke | Spannbetonhohldecke | EG_Technik_FFB | 0102De 0000003968 | m³ | Fertigteil | D102 | false | 50 | - | - | HI_GES_FEB_0,260_xxx | SlabCommon - Volumen: 2.59541
Spannbetonhohldecke | EG_Technik_FFB | FLOOR | Stahlbetonfertigteil | Spannbetonhohldecke | Spannbetonhohldecke | EG_Technik_FFB | 0102De 0000003964 | m³ | Fertigteil | D102 | false | 50 | - | - | HI_GES_FEB_0,260_xxx | SlabCommon - Volumen: 2.59541
Spannbetonhohldecke | EG_Technik_FFB | FLOOR | Stahlbetonfertigteil | Spannbetonhohldecke | Spannbetonhohldecke | EG_Technik_FFB | 0102De 0000003906 | m³ | Fertigteil | D102 | false | 50 | - | - | HI_GES_FEB_0,260_xxx | SlabCommon - Volumen: 2.59541
Spannbetonhohldecke | EG_Technik_FFB | FLOOR | Stahlbetonfertigteil | Spannbetonhohldecke | Spannbetonhohldecke | EG_Technik_FFB | 0102De 0000003670 | m³ | Fertigteil | D102 | false | 50 | - | - | HI_GES_FEB_0,260_xxx | SlabCommon - Volumen: 2.80805
Spannbetonhohldecke | EG_Technik_FFB | FLOOR | Stahlbetonfertigteil | Spannbetonhohldecke | Spannbetonhohldecke | EG_Technik_FFB | 0102De 0000003842 | m³ | Fertigteil | D102 | false | 50 | - | - | HI_GES_FEB_0,260_xxx | SlabCommon - Volumen: 0.694194
Spannbetonhohldecke | EG_Technik_FFB | FLOOR | Stahlbetonfertigteil | Spannbetonhohldecke | Spannbetonhohldecke | EG_Technik_FFB | 0102De 0000003978 | m³ | Fertigteil | D102 | false | 50 | - | - | HI_GES_FEB_0,260_xxx | SlabCommon - Volumen: 2.59541
Spannbetonhohldecke | EG_Technik_FFB | FLOOR | Stahlbetonfertigteil | Spannbetonhohldecke | Spannbetonhohldecke | EG_Technik_FFB | 0102De 0000003708 | m³ | Fertigteil | D102 | false | 50 | - | - | HI_GES_FEB_0,260_xxx | SlabCommon - Volumen: 2.80805
Spannbetonhohldecke | EG_Technik_FFB | FLOOR | Stahlbetonfertigteil | Spannbetonhohldecke | Spannbetonhohldecke | EG_Technik_FFB | 0102De 0000003926 | m³ | Fertigteil | D102 | false | 50 | - | - | HI_GES_FEB_0,260_xxx | SlabCommon - Volumen: 2.57023
Spannbetonhohldecke | EG_Technik_FFB | FLOOR | Stahlbetonfertigteil | Spannbetonhohldecke | Spannbetonhohldecke | EG_Technik_FFB | 0102De 0000003598 | m³ | Fertigteil | D102 | false | 50 | - | - | HI_GES_FEB_0,260_xxx | SlabCommon - Volumen: 2.59541
Spannbetonhohldecke | EG_Technik_FFB | FLOOR | Stahlbetonfertigteil | Spannbetonhohldecke | Spannbetonhohldecke | EG_Technik_FFB | 0102De 0000003948 | m³ | Fertigteil | D102 | false | 50 | - | - | HI_GES_FEB_0,260_xxx | SlabCommon - Volumen: 2.59541
Spannbetonhohldecke | EG_Technik_FFB | FLOOR | Stahlbetonfertigteil | Spannbetonhohldecke | Spannbetonhohldecke | EG_Technik_FFB | 0102De 0000004012 | m³ | Fertigteil | D102 | false | 50 | - | - | HI_GES_FEB_0,260_xxx | SlabCommon - Volumen: 2.80805
Spannbetonhohldecke | EG_Technik_FFB | FLOOR | Stahlbetonfertigteil | Spannbetonhohldecke | Spannbetonhohldecke | EG_Technik_FFB | 0102De 0000003725 | m³ | Fertigteil | D102 | false | 50 | - | - | HI_GES_FEB_0,260_xxx | SlabCommon - Volumen: 2.14112
Spannbetonhohldecke | EG_Technik_FFB | FLOOR | Stahlbetonfertigteil | Spannbetonhohldecke | Spannbetonhohldecke | EG_Technik_FFB | 0102De 0000003904 | m³ | Fertigteil | D102 | false | 50 | - | - | HI_GES_FEB_0,260_xxx | SlabCommon - Volumen: 2.57696
Spannbetonhohldecke | EG_Technik_FFB | FLOOR | Stahlbetonfertigteil | Spannbetonhohldecke | Spannbetonhohldecke | EG_Technik_FFB | 0102De 0000003922 | m³ | Fertigteil | D102 | false | 50 | - | - | HI_GES_FEB_0,260_xxx | SlabCommon - Volumen: 2.57231
Spannbetonhohldecke | EG_Technik_FFB | FLOOR | Stahlbetonfertigteil | Spannbetonhohldecke | Spannbetonhohldecke | EG_Technik_FFB | 0102De 0000003870 | m³ | Fertigteil | D102 | false | 50 | - | - | HI_GES_FEB_0,260_xxx | SlabCommon - Volumen: 0.54802
Spannbetonhohldecke | EG_Technik_FFB | FLOOR | Stahlbetonfertigteil | Spannbetonhohldecke | Spannbetonhohldecke | EG_Technik_FFB | 0102De 0000003682 | m³ | Fertigteil | D102 | false | 50 | - | - | HI_GES_FEB_0,260_xxx | SlabCommon - Volumen: 2.80149
Spannbetonhohldecke | EG_Technik_FFB | FLOOR | Stahlbetonfertigteil | Spannbetonhohldecke | Spannbetonhohldecke | EG_Technik_FFB | 0102De 0000005173 | m³ | Fertigteil | D102 | false | 50 | - | - | HI_GES_FEB_0,260_xxx | SlabCommon - Volumen: 0.151368
Spannbetonhohldecke | EG_Technik_FFB | FLOOR | Stahlbetonfertigteil | Spannbetonhohldecke | Spannbetonhohldecke | EG_Technik_FFB | 0102De 0000005167 | m³ | Fertigteil | D102 | false | 50 | - | - | HI_GES_FEB_0,260_xxx | SlabCommon - Volumen: 0.242952
Spannbetonhohldecke | EG_Technik_FFB | FLOOR | Stahlbetonfertigteil | Spannbetonhohldecke | Spannbetonhohldecke | EG_Technik_FFB | 0102De 0000003898 | m³ | Fertigteil | D102 | false | 50 | - | - | HI_GES_FEB_0,260_xxx | SlabCommon - Volumen: 0.776801
Spannbetonhohldecke | EG_Technik_FFB | FLOOR | Stahlbetonfertigteil | Spannbetonhohldecke | Spannbetonhohldecke | EG_Technik_FFB | 0102De 0000003723 | m³ | Fertigteil | D102 | false | 50 | - | - | HI_GES_FEB_0,260_xxx | SlabCommon - Volumen: 2.16232
Spannbetonhohldecke | EG_Technik_FFB | FLOOR | Stahlbetonfertigteil | Spannbetonhohldecke | Spannbetonhohldecke | EG_Technik_FFB | 0102De 0000004592 | m³ | Fertigteil | D102 | false | 50 | - | - | HI_GES_FEB_0,260_xxx | SlabCommon - Volumen: 2.75774
Spannbetonhohldecke | EG_Technik_FFB | FLOOR | Stahlbetonfertigteil | Spannbetonhohldecke | Spannbetonhohldecke | EG_Technik_FFB | 0102De 0000003896 | m³ | Fertigteil | D102 | false | 50 | - | - | HI_GES_FEB_0,260_xxx | SlabCommon - Volumen: 0.611494
Spannbetonhohldecke | EG_Technik_FFB | FLOOR | Stahlbetonfertigteil | Spannbetonhohldecke | Spannbetonhohldecke | EG_Technik_FFB | 0102De 0000005199 | m³ | Fertigteil | D102 | false | 50 | - | - | HI_GES_FEB_0,260_xxx | SlabCommon - Volumen: 0.113873
Spannbetonhohldecke | EG_Technik_FFB | FLOOR | Stahlbetonfertigteil | Spannbetonhohldecke | Spannbetonhohldecke | EG_Technik_FFB | 0102De 0000003710 | m³ | Fertigteil | D102 | false | 50 | - | - | HI_GES_FEB_0,260_xxx | SlabCommon - Volumen: 2.80805
Spannbetonhohldecke | EG_Technik_FFB | FLOOR | Stahlbetonfertigteil | Spannbetonhohldecke | Spannbetonhohldecke | EG_Technik_FFB | 0102De 0000003886 | m³ | Fertigteil | D102 | false | 50 | - | - | HI_GES_FEB_0,260_xxx | SlabCommon - Volumen: 0.734845
Spannbetonhohldecke | EG_Technik_FFB | FLOOR | Stahlbetonfertigteil | Spannbetonhohldecke | Spannbetonhohldecke | EG_Technik_FFB | 0102De 0000003876 | m³ | Fertigteil | D102 | false | 50 | - | - | HI_GES_FEB_0,260_xxx | SlabCommon - Volumen: 0.734845
Spannbetonhohldecke | EG_Technik_FFB | FLOOR | Stahlbetonfertigteil | Spannbetonhohldecke | Spannbetonhohldecke | EG_Technik_FFB | 0102De 0000003874 | m³ | Fertigteil | D102 | false | 50 | - | - | HI_GES_FEB_0,260_xxx | SlabCommon - Volumen: 0.734845
Spannbetonhohldecke | EG_Technik_FFB | FLOOR | Stahlbetonfertigteil | Spannbetonhohldecke | Spannbetonhohldecke | EG_Technik_FFB | 0102De 0000003882 | m³ | Fertigteil | D102 | false | 50 | - | - | HI_GES_FEB_0,260_xxx | SlabCommon - Volumen: 0.734845
Spannbetonhohldecke | EG_Technik_FFB | FLOOR | Stahlbetonfertigteil | Spannbetonhohldecke | Spannbetonhohldecke | EG_Technik_FFB | 0102De 0000003884 | m³ | Fertigteil | D102 | false | 50 | - | - | HI_GES_FEB_0,260_xxx | SlabCommon - Volumen: 0.734845
Spannbetonhohldecke | EG_Technik_FFB | FLOOR | Stahlbetonfertigteil | Spannbetonhohldecke | Spannbetonhohldecke | EG_Technik_FFB | 0102De 0000003878 | m³ | Fertigteil | D102 | false | 50 | - | - | HI_GES_FEB_0,260_xxx | SlabCommon - Volumen: 0.734845
Spannbetonhohldecke | EG_Technik_FFB | FLOOR | Stahlbetonfertigteil | Spannbetonhohldecke | Spannbetonhohldecke | EG_Technik_FFB | 0102De 0000003880 | m³ | Fertigteil | D102 | false | 50 | - | - | HI_GES_FEB_0,260_xxx | SlabCommon - Volumen: 0.734845
Spannbetonhohldecke | EG_Technik_FFB | FLOOR | Stahlbetonfertigteil | Spannbetonhohldecke | Spannbetonhohldecke | EG_Technik_FFB | 0102De 0000003888 | m³ | Fertigteil | D102 | false | 50 | - | - | HI_GES_FEB_0,260_xxx | SlabCommon - Volumen: 0.67257
Spannbetonhohldecke | EG_Technik_FFB | FLOOR | Stahlbetonfertigteil | Spannbetonhohldecke | Spannbetonhohldecke | EG_Technik_FFB | 0102De 0000003892 | m³ | Fertigteil | D102 | false | 50 | - | - | HI_GES_FEB_0,260_xxx | SlabCommon - Volumen: 1.61584
Spannbetonhohldecke | EG_Technik_FFB | FLOOR | Stahlbetonfertigteil | Spannbetonhohldecke | Spannbetonhohldecke | EG_Technik_FFB | 0102De 0000003715 | m³ | Fertigteil | D102 | false | 50 | - | - | HI_GES_FEB_0,260_xxx | SlabCommon - Volumen: 2.80805
Spannbetonhohldecke | EG_Technik_FFB | FLOOR | Stahlbetonfertigteil | Spannbetonhohldecke | Spannbetonhohldecke | EG_Technik_FFB | 0102De 0000003726 | m³ | Fertigteil | D102 | false | 50 | - | - | HI_GES_FEB_0,260_xxx | SlabCommon - Volumen: 1.64199
Stb.-Bodenplatte | EG_Technik_FFB | BASESLAB | Stahlbeton | BP-STB1\ | Stb.-Bodenplatte | EG_Technik_FFB | 0104PFu0000028830 | m² | Ortbeton | F007 | false | 100 | XC2, WF | C20/25 | HI_GFB_STB_0,200_xxx | Platte | F90 | no | 0
Stb.-Rahmen | EG_Produktion_FFB | ROOF | Stahlbeton | D-DECKE\ | Stb.-Rahmen | EG_Produktion_FFB | 0111De 0000620126 | m² | Ortbeton | RA001 und RA002 | true | 50 | XC4, XD1, XF2, WF | C35/45 | HA_GES_STB_0,300_xxx | Decke |  |  | 0 | AllplanAttributes - Ausführung: Ortbeton; Pset_SlabCommon - SurfaceSpreadOfFlame: -
Stb.-Rahmen | EG_Produktion_FFB | ROOF | Stahlbeton | D-DECKE\ | Stb.-Rahmen | EG_Produktion_FFB | 0111De 0000620112 | m² | Ortbeton | RA001 und RA002 | true | 50 | XC4, XD1, XF2, WF | C35/45 | HA_GES_STB_0,300_xxx | Decke |  |  | 0 | AllplanAttributes - Ausführung: Ortbeton; Pset_SlabCommon - SurfaceSpreadOfFlame: -
Stb.-Rahmen | EG_Produktion_FFB | ROOF | Stahlbeton | D-DECKE\ | Stb.-Rahmen | EG_Produktion_FFB | 0111De 0000620100 | m² | Ortbeton | RA001 und RA002 | true | 50 | XC4, XD1, XF2, WF | C35/45 | HA_GES_STB_0,300_xxx | Decke |  |  | 0 | AllplanAttributes - Ausführung: Ortbeton; Pset_SlabCommon - SurfaceSpreadOfFlame: -
Stb.-Rahmen | EG_Produktion_FFB | ROOF | Stahlbeton | D-DECKE\ | Stb.-Rahmen | EG_Produktion_FFB | 0111De 0000620022 | m² | Ortbeton | RA001 und RA002 | true | 50 | XC4, XD1, XF2, WF | C35/45 | HA_GES_STB_0,300_xxx | Decke |  |  | 0 | AllplanAttributes - Ausführung: Ortbeton; Pset_SlabCommon - SurfaceSpreadOfFlame: -
Stb.-Rahmen | EG_Produktion_FFB | ROOF | Stahlbeton | D-DECKE\ | Stb.-Rahmen | EG_Produktion_FFB | 0111De 0000619972 | m² | Ortbeton | RA001 und RA002 | true | 50 | XC4, XD1, XF2, WF | C35/45 | HA_GES_STB_0,300_xxx | Decke |  |  | 0 | AllplanAttributes - Ausführung: Ortbeton; Pset_SlabCommon - SurfaceSpreadOfFlame: -
Stb.-Rahmen | EG_Produktion_FFB | ROOF | Stahlbeton | D-DECKE\ | Stb.-Rahmen | EG_Produktion_FFB | 0111De 0000617642 | m² | Ortbeton | RA001 und RA002 | true | 50 | XC4, XD1, XF2, WF | C35/45 | HA_GES_STB_0,300_xxx | Decke |  |  | 0 | AllplanAttributes - Ausführung: Ortbeton; Pset_SlabCommon - SurfaceSpreadOfFlame: -
Stahlbetonfertigteilplatte | EG_Produktion_FFB | BASESLAB | Stahlbetonfertigteil | BP-STB1\ | Stahlbetonfertigteilplatte | EG_Produktion_FFB | 0113PFu0000000221 | m² | Fertigteil | D001 | false | 100 | XC1, WO | C35/45 | HI_GES_FEB-0,220_xxx | Platte | - | no | 0
Stahlbetonfertigteilplatte | EG_Produktion_FFB | BASESLAB | Stahlbetonfertigteil | BP-STB1\ | Stahlbetonfertigteilplatte | EG_Produktion_FFB | 0113PFu0000000211 | m² | Fertigteil | D001 | false | 100 | XC1, WO | C35/45 | HI_GES_FEB-0,220_xxx | Platte | - | no | 0
Stahlbetonfertigteilplatte | EG_Produktion_FFB | BASESLAB | Stahlbetonfertigteil | BP-STB1\ | Stahlbetonfertigteilplatte | EG_Produktion_FFB | 0113PFu0000000213 | m² | Fertigteil | D001 | false | 100 | XC1, WO | C35/45 | HI_GES_FEB-0,220_xxx | Platte | - | no | 0
Stahlbetonfertigteilplatte | EG_Produktion_FFB | BASESLAB | Stahlbetonfertigteil | BP-STB1\ | Stahlbetonfertigteilplatte | EG_Produktion_FFB | 0113PFu0000000209 | m² | Fertigteil | D001 | false | 100 | XC1, WO | C35/45 | HI_GES_FEB-0,220_xxx | Platte | - | no | 0
Stahlbetonfertigteilplatte | EG_Produktion_FFB | BASESLAB | Stahlbetonfertigteil | BP-STB1\ | Stahlbetonfertigteilplatte | EG_Produktion_FFB | 0113PFu0000000537 | m² | Fertigteil | D001 | false | 100 | XC1, WO | C35/45 | HI_GES_FEB-0,220_xxx | Platte | - | no | 0
Stahlbetonfertigteilplatte | EG_Produktion_FFB | BASESLAB | Stahlbetonfertigteil | BP-STB1\ | Stahlbetonfertigteilplatte | EG_Produktion_FFB | 0113PFu0000006099 | m² | Fertigteil | D001 | false | 100 | XC1, WO | C35/45 | HI_GES_FEB-0,220_xxx | Platte | - | no | 0
Stahlbetonfertigteilplatte | EG_Produktion_FFB | BASESLAB | Stahlbetonfertigteil | BP-STB1\ | Stahlbetonfertigteilplatte | EG_Produktion_FFB | 0113PFu0000000667 | m² | Fertigteil | D001 | false | 100 | XC1, WO | C35/45 | HI_GES_FEB-0,220_xxx | Platte | - | no | 0
Stahlbetonfertigteilplatte | EG_Produktion_FFB | BASESLAB | Stahlbetonfertigteil | BP-STB1\ | Stahlbetonfertigteilplatte | EG_Produktion_FFB | 0113PFu0000000701 | m² | Fertigteil | D001 | false | 100 | XC1, WO | C35/45 | HI_GES_FEB-0,220_xxx | Platte | - | no | 0
Stahlbetonfertigteilplatte | EG_Produktion_FFB | BASESLAB | Stahlbetonfertigteil | BP-STB1\ | Stahlbetonfertigteilplatte | EG_Produktion_FFB | 0113PFu0000000733 | m² | Fertigteil | D001 | false | 100 | XC1, WO | C35/45 | HI_GES_FEB-0,220_xxx | Platte | - | no | 0
Stahlbetonfertigteilplatte | EG_Produktion_FFB | BASESLAB | Stahlbetonfertigteil | BP-STB1\ | Stahlbetonfertigteilplatte | EG_Produktion_FFB | 0113PFu0000006063 | m² | Fertigteil | D001 | false | 100 | XC1, WO | C35/45 | HI_GES_FEB-0,220_xxx | Platte | - | no | 0
Stahlbetonfertigteilplatte | EG_Produktion_FFB | BASESLAB | Stahlbetonfertigteil | BP-STB1\ | Stahlbetonfertigteilplatte | EG_Produktion_FFB | 0113PFu0000000735 | m² | Fertigteil | D001 | false | 100 | XC1, WO | C35/45 | HI_GES_FEB-0,220_xxx | Platte | - | no | 0
Stahlbetonfertigteilplatte | EG_Produktion_FFB | BASESLAB | Stahlbetonfertigteil | BP-STB1\ | Stahlbetonfertigteilplatte | EG_Produktion_FFB | 0113PFu0000000551 | m² | Fertigteil | D001 | false | 100 | XC1, WO | C35/45 | HI_GES_FEB-0,220_xxx | Platte | - | no | 0
Stahlbetonfertigteilplatte | EG_Produktion_FFB | BASESLAB | Stahlbetonfertigteil | BP-STB1\ | Stahlbetonfertigteilplatte | EG_Produktion_FFB | 0113PFu0000005879 | m² | Fertigteil | D001 | false | 100 | XC1, WO | C35/45 | HI_GES_FEB-0,220_xxx | Platte | - | no | 0
Stahlbetonfertigteilplatte | EG_Produktion_FFB | BASESLAB | Stahlbetonfertigteil | BP-STB1\ | Stahlbetonfertigteilplatte | EG_Produktion_FFB | 0113PFu0000000507 | m² | Fertigteil | D001 | false | 100 | XC1, WO | C35/45 | HI_GES_FEB-0,220_xxx | Platte | - | no | 0
Stahlbetonfertigteilplatte | EG_Produktion_FFB | BASESLAB | Stahlbetonfertigteil | BP-STB1\ | Stahlbetonfertigteilplatte | EG_Produktion_FFB | 0113PFu0000005862 | m² | Fertigteil | D001 | false | 100 | XC1, WO | C35/45 | HI_GES_FEB-0,220_xxx | Platte | - | no | 0
Stahlbetonfertigteilplatte | EG_Produktion_FFB | BASESLAB | Stahlbetonfertigteil | BP-STB1\ | Stahlbetonfertigteilplatte | EG_Produktion_FFB | 0113PFu0000005843 | m² | Fertigteil | D001 | false | 100 | XC1, WO | C35/45 | HI_GES_FEB-0,220_xxx | Platte | - | no | 0
Stahlbetonfertigteilplatte | EG_Produktion_FFB | BASESLAB | Stahlbetonfertigteil | BP-STB1\ | Stahlbetonfertigteilplatte | EG_Produktion_FFB | 0113PFu0000000435 | m² | Fertigteil | D001 | false | 100 | XC1, WO | C35/45 | HI_GES_FEB-0,220_xxx | Platte | - | no | 0
Stahlbetonfertigteilplatte | EG_Produktion_FFB | BASESLAB | Stahlbetonfertigteil | BP-STB1\ | Stahlbetonfertigteilplatte | EG_Produktion_FFB | 0113PFu0000000399 | m² | Fertigteil | D001 | false | 100 | XC1, WO | C35/45 | HI_GES_FEB-0,220_xxx | Platte | - | no | 0
Stahlbetonfertigteilplatte | EG_Produktion_FFB | BASESLAB | Stahlbetonfertigteil | BP-STB1\ | Stahlbetonfertigteilplatte | EG_Produktion_FFB | 0113PFu0000000369 | m² | Fertigteil | D001 | false | 100 | XC1, WO | C35/45 | HI_GES_FEB-0,220_xxx | Platte | - | no | 0
Stahlbetonfertigteilplatte | EG_Produktion_FFB | BASESLAB | Stahlbetonfertigteil | BP-STB1\ | Stahlbetonfertigteilplatte | EG_Produktion_FFB | 0113PFu0000005797 | m² | Fertigteil | D001 | false | 100 | XC1, WO | C35/45 | HI_GES_FEB-0,220_xxx | Platte | - | no | 0
Stahlbetonfertigteilplatte | EG_Produktion_FFB | BASESLAB | Stahlbetonfertigteil | BP-STB1\ | Stahlbetonfertigteilplatte | EG_Produktion_FFB | 0113PFu0000000333 | m² | Fertigteil | D001 | false | 100 | XC1, WO | C35/45 | HI_GES_FEB-0,220_xxx | Platte | - | no | 0
Stahlbetonfertigteilplatte | EG_Produktion_FFB | BASESLAB | Stahlbetonfertigteil | BP-STB1\ | Stahlbetonfertigteilplatte | EG_Produktion_FFB | 0113PFu0000000745 | m² | Fertigteil | D001 | false | 100 | XC1, WO | C35/45 | HI_GES_FEB-0,220_xxx | Platte | - | no | 0
Stahlbetonfertigteilplatte | EG_Produktion_FFB | BASESLAB | Stahlbetonfertigteil | BP-STB1\ | Stahlbetonfertigteilplatte | EG_Produktion_FFB | 0113PFu0000000237 | m² | Fertigteil | D001 | false | 100 | XC1, WO | C35/45 | HI_GES_FEB-0,220_xxx | Platte | - | no | 0
Stahlbetonfertigteilplatte | EG_Produktion_FFB | BASESLAB | Stahlbetonfertigteil | BP-STB1\ | Stahlbetonfertigteilplatte | EG_Produktion_FFB | 0113PFu0000000279 | m² | Fertigteil | D001 | false | 100 | XC1, WO | C35/45 | HI_GES_FEB-0,220_xxx | Platte | - | no | 0
Stahlbetonfertigteilplatte | EG_Produktion_FFB | BASESLAB | Stahlbetonfertigteil | BP-STB1\ | Stahlbetonfertigteilplatte | EG_Produktion_FFB | 0113PFu0000000207 | m² | Fertigteil | D001 | false | 100 | XC1, WO | C35/45 | HI_GES_FEB-0,220_xxx | Platte | - | no | 0
Stahlbetonfertigteilplatte | EG_Produktion_FFB | BASESLAB | Stahlbetonfertigteil | BP-STB1\ | Stahlbetonfertigteilplatte | EG_Produktion_FFB | 0113PFu0000000281 | m² | Fertigteil | D001 | false | 100 | XC1, WO | C35/45 | HI_GES_FEB-0,220_xxx | Platte | - | no | 0
Stahlbetonfertigteilplatte | EG_Produktion_FFB | BASESLAB | Stahlbetonfertigteil | BP-STB1\ | Stahlbetonfertigteilplatte | EG_Produktion_FFB | 0113PFu0000000293 | m² | Fertigteil | D001 | false | 100 | XC1, WO | C35/45 | HI_GES_FEB-0,220_xxx | Platte | - | no | 0
Stahlbetonfertigteilplatte | EG_Produktion_FFB | BASESLAB | Stahlbetonfertigteil | BP-STB1\ | Stahlbetonfertigteilplatte | EG_Produktion_FFB | 0113PFu0000000323 | m² | Fertigteil | D001 | false | 100 | XC1, WO | C35/45 | HI_GES_FEB-0,220_xxx | Platte | - | no | 0
Stahlbetonfertigteilplatte | EG_Produktion_FFB | BASESLAB | Stahlbetonfertigteil | BP-STB1\ | Stahlbetonfertigteilplatte | EG_Produktion_FFB | 0113PFu0000000325 | m² | Fertigteil | D001 | false | 100 | XC1, WO | C35/45 | HI_GES_FEB-0,220_xxx | Platte | - | no | 0
Stahlbetonfertigteilplatte | EG_Produktion_FFB | BASESLAB | Stahlbetonfertigteil | BP-STB1\ | Stahlbetonfertigteilplatte | EG_Produktion_FFB | 0113PFu0000000331 | m² | Fertigteil | D001 | false | 100 | XC1, WO | C35/45 | HI_GES_FEB-0,220_xxx | Platte | - | no | 0
Stahlbetonfertigteilplatte | EG_Produktion_FFB | BASESLAB | Stahlbetonfertigteil | BP-STB1\ | Stahlbetonfertigteilplatte | EG_Produktion_FFB | 0113PFu0000000335 | m² | Fertigteil | D001 | false | 100 | XC1, WO | C35/45 | HI_GES_FEB-0,220_xxx | Platte | - | no | 0
Stahlbetonfertigteilplatte | EG_Produktion_FFB | BASESLAB | Stahlbetonfertigteil | BP-STB1\ | Stahlbetonfertigteilplatte | EG_Produktion_FFB | 0113PFu0000000337 | m² | Fertigteil | D001 | false | 100 | XC1, WO | C35/45 | HI_GES_FEB-0,220_xxx | Platte | - | no | 0
Stahlbetonfertigteilplatte | EG_Produktion_FFB | BASESLAB | Stahlbetonfertigteil | BP-STB1\ | Stahlbetonfertigteilplatte | EG_Produktion_FFB | 0113PFu0000000359 | m² | Fertigteil | D001 | false | 100 | XC1, WO | C35/45 | HI_GES_FEB-0,220_xxx | Platte | - | no | 0
Stahlbetonfertigteilplatte | EG_Produktion_FFB | BASESLAB | Stahlbetonfertigteil | BP-STB1\ | Stahlbetonfertigteilplatte | EG_Produktion_FFB | 0113PFu0000000361 | m² | Fertigteil | D001 | false | 100 | XC1, WO | C35/45 | HI_GES_FEB-0,220_xxx | Platte | - | no | 0
Stahlbetonfertigteilplatte | EG_Produktion_FFB | BASESLAB | Stahlbetonfertigteil | BP-STB1\ | Stahlbetonfertigteilplatte | EG_Produktion_FFB | 0113PFu0000000367 | m² | Fertigteil | D001 | false | 100 | XC1, WO | C35/45 | HI_GES_FEB-0,220_xxx | Platte | - | no | 0
Stahlbetonfertigteilplatte | EG_Produktion_FFB | BASESLAB | Stahlbetonfertigteil | BP-STB1\ | Stahlbetonfertigteilplatte | EG_Produktion_FFB | 0113PFu0000000371 | m² | Fertigteil | D001 | false | 100 | XC1, WO | C35/45 | HI_GES_FEB-0,220_xxx | Platte | - | no | 0
Stahlbetonfertigteilplatte | EG_Produktion_FFB | BASESLAB | Stahlbetonfertigteil | BP-STB1\ | Stahlbetonfertigteilplatte | EG_Produktion_FFB | 0113PFu0000000373 | m² | Fertigteil | D001 | false | 100 | XC1, WO | C35/45 | HI_GES_FEB-0,220_xxx | Platte | - | no | 0
Stahlbetonfertigteilplatte | EG_Produktion_FFB | BASESLAB | Stahlbetonfertigteil | BP-STB1\ | Stahlbetonfertigteilplatte | EG_Produktion_FFB | 0113PFu0000000391 | m² | Fertigteil | D001 | false | 100 | XC1, WO | C35/45 | HI_GES_FEB-0,220_xxx | Platte | - | no | 0
Stahlbetonfertigteilplatte | EG_Produktion_FFB | BASESLAB | Stahlbetonfertigteil | BP-STB1\ | Stahlbetonfertigteilplatte | EG_Produktion_FFB | 0113PFu0000000393 | m² | Fertigteil | D001 | false | 100 | XC1, WO | C35/45 | HI_GES_FEB-0,220_xxx | Platte | - | no | 0
Stahlbetonfertigteilplatte | EG_Produktion_FFB | BASESLAB | Stahlbetonfertigteil | BP-STB1\ | Stahlbetonfertigteilplatte | EG_Produktion_FFB | 0113PFu0000000401 | m² | Fertigteil | D001 | false | 100 | XC1, WO | C35/45 | HI_GES_FEB-0,220_xxx | Platte | - | no | 0
Stahlbetonfertigteilplatte | EG_Produktion_FFB | BASESLAB | Stahlbetonfertigteil | BP-STB1\ | Stahlbetonfertigteilplatte | EG_Produktion_FFB | 0113PFu0000000403 | m² | Fertigteil | D001 | false | 100 | XC1, WO | C35/45 | HI_GES_FEB-0,220_xxx | Platte | - | no | 0
Stahlbetonfertigteilplatte | EG_Produktion_FFB | BASESLAB | Stahlbetonfertigteil | BP-STB1\ | Stahlbetonfertigteilplatte | EG_Produktion_FFB | 0113PFu0000000405 | m² | Fertigteil | D001 | false | 100 | XC1, WO | C35/45 | HI_GES_FEB-0,220_xxx | Platte | - | no | 0
Stahlbetonfertigteilplatte | EG_Produktion_FFB | BASESLAB | Stahlbetonfertigteil | BP-STB1\ | Stahlbetonfertigteilplatte | EG_Produktion_FFB | 0113PFu0000000427 | m² | Fertigteil | D001 | false | 100 | XC1, WO | C35/45 | HI_GES_FEB-0,220_xxx | Platte | - | no | 0
Stahlbetonfertigteilplatte | EG_Produktion_FFB | BASESLAB | Stahlbetonfertigteil | BP-STB1\ | Stahlbetonfertigteilplatte | EG_Produktion_FFB | 0113PFu0000000429 | m² | Fertigteil | D001 | false | 100 | XC1, WO | C35/45 | HI_GES_FEB-0,220_xxx | Platte | - | no | 0
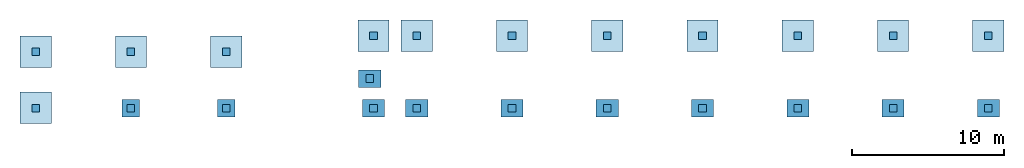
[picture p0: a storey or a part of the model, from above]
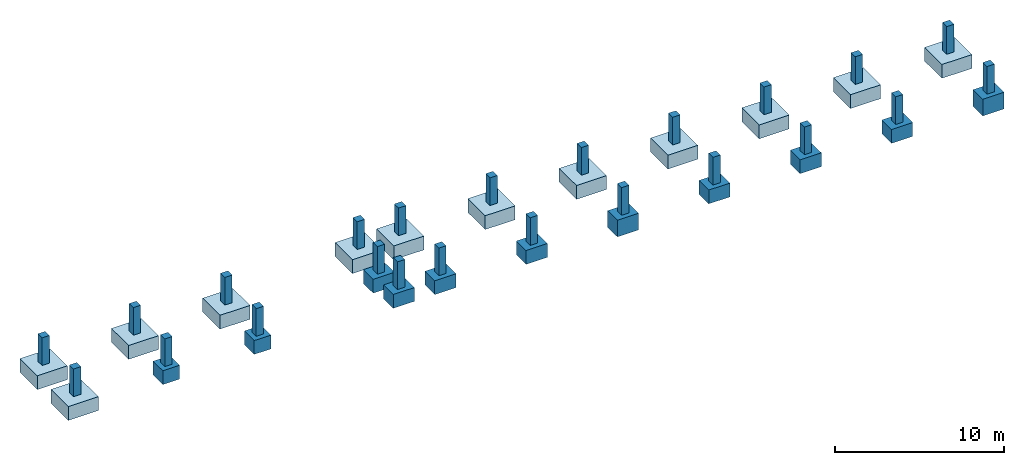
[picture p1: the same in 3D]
Properties of the parts of a building model (IFC2X3), part 23 of 25

# IfcSlab (564)
Name | In | PredefinedType | Material = AllplanAttributes, Material | Codetext | Bezeichnung = Name | Ebene | Allright_Bauteil_ID | Abrechnungsart | Herstellung | Positionsnummer | Außenbauteil | Bewehrungsgrad | Expositionsklasse | Druckfestigkeitsklasse | Reference | Attributset-Objekt | FireRating | Combustible = Compartmentation | PitchAngle (deg)
Stahlbetonfertigteilplatte | EG_Produktion_FFB | BASESLAB | Stahlbetonfertigteil | BP-STB1\ | Stahlbetonfertigteilplatte | EG_Produktion_FFB | 0113PFu0000000437 | m² | Fertigteil | D001 | false | 100 | XC1, WO | C35/45 | HI_GES_FEB-0,220_xxx | Platte | - | no | 0
Stahlbetonfertigteilplatte | EG_Produktion_FFB | BASESLAB | Stahlbetonfertigteil | BP-STB1\ | Stahlbetonfertigteilplatte | EG_Produktion_FFB | 0113PFu0000000439 | m² | Fertigteil | D001 | false | 100 | XC1, WO | C35/45 | HI_GES_FEB-0,220_xxx | Platte | - | no | 0
Stahlbetonfertigteilplatte | EG_Produktion_FFB | BASESLAB | Stahlbetonfertigteil | BP-STB1\ | Stahlbetonfertigteilplatte | EG_Produktion_FFB | 0113PFu0000000441 | m² | Fertigteil | D001 | false | 100 | XC1, WO | C35/45 | HI_GES_FEB-0,220_xxx | Platte | - | no | 0
Stahlbetonfertigteilplatte | EG_Produktion_FFB | BASESLAB | Stahlbetonfertigteil | BP-STB1\ | Stahlbetonfertigteilplatte | EG_Produktion_FFB | 0113PFu0000000467 | m² | Fertigteil | D001 | false | 100 | XC1, WO | C35/45 | HI_GES_FEB-0,220_xxx | Platte | - | no | 0
Stahlbetonfertigteilplatte | EG_Produktion_FFB | BASESLAB | Stahlbetonfertigteil | BP-STB1\ | Stahlbetonfertigteilplatte | EG_Produktion_FFB | 0113PFu0000000469 | m² | Fertigteil | D001 | false | 100 | XC1, WO | C35/45 | HI_GES_FEB-0,220_xxx | Platte | - | no | 0
Stahlbetonfertigteilplatte | EG_Produktion_FFB | BASESLAB | Stahlbetonfertigteil | BP-STB1\ | Stahlbetonfertigteilplatte | EG_Produktion_FFB | 0113PFu0000000471 | m² | Fertigteil | D001 | false | 100 | XC1, WO | C35/45 | HI_GES_FEB-0,220_xxx | Platte | - | no | 0
Stahlbetonfertigteilplatte | EG_Produktion_FFB | BASESLAB | Stahlbetonfertigteil | BP-STB1\ | Stahlbetonfertigteilplatte | EG_Produktion_FFB | 0113PFu0000000473 | m² | Fertigteil | D001 | false | 100 | XC1, WO | C35/45 | HI_GES_FEB-0,220_xxx | Platte | - | no | 0
Stahlbetonfertigteilplatte | EG_Produktion_FFB | BASESLAB | Stahlbetonfertigteil | BP-STB1\ | Stahlbetonfertigteilplatte | EG_Produktion_FFB | 0113PFu0000000475 | m² | Fertigteil | D001 | false | 100 | XC1, WO | C35/45 | HI_GES_FEB-0,220_xxx | Platte | - | no | 0
Stahlbetonfertigteilplatte | EG_Produktion_FFB | BASESLAB | Stahlbetonfertigteil | BP-STB1\ | Stahlbetonfertigteilplatte | EG_Produktion_FFB | 0113PFu0000000477 | m² | Fertigteil | D001 | false | 100 | XC1, WO | C35/45 | HI_GES_FEB-0,220_xxx | Platte | - | no | 0
Stahlbetonfertigteilplatte | EG_Produktion_FFB | BASESLAB | Stahlbetonfertigteil | BP-STB1\ | Stahlbetonfertigteilplatte | EG_Produktion_FFB | 0113PFu0000000499 | m² | Fertigteil | D001 | false | 100 | XC1, WO | C35/45 | HI_GES_FEB-0,220_xxx | Platte | - | no | 0
Stahlbetonfertigteilplatte | EG_Produktion_FFB | BASESLAB | Stahlbetonfertigteil | BP-STB1\ | Stahlbetonfertigteilplatte | EG_Produktion_FFB | 0113PFu0000000501 | m² | Fertigteil | D001 | false | 100 | XC1, WO | C35/45 | HI_GES_FEB-0,220_xxx | Platte | - | no | 0
Stahlbetonfertigteilplatte | EG_Produktion_FFB | BASESLAB | Stahlbetonfertigteil | BP-STB1\ | Stahlbetonfertigteilplatte | EG_Produktion_FFB | 0113PFu0000000509 | m² | Fertigteil | D001 | false | 100 | XC1, WO | C35/45 | HI_GES_FEB-0,220_xxx | Platte | - | no | 0
Stahlbetonfertigteilplatte | EG_Produktion_FFB | BASESLAB | Stahlbetonfertigteil | BP-STB1\ | Stahlbetonfertigteilplatte | EG_Produktion_FFB | 0113PFu0000000511 | m² | Fertigteil | D001 | false | 100 | XC1, WO | C35/45 | HI_GES_FEB-0,220_xxx | Platte | - | no | 0
Stahlbetonfertigteilplatte | EG_Produktion_FFB | BASESLAB | Stahlbetonfertigteil | BP-STB1\ | Stahlbetonfertigteilplatte | EG_Produktion_FFB | 0113PFu0000000513 | m² | Fertigteil | D001 | false | 100 | XC1, WO | C35/45 | HI_GES_FEB-0,220_xxx | Platte | - | no | 0
Stahlbetonfertigteilplatte | EG_Produktion_FFB | BASESLAB | Stahlbetonfertigteil | BP-STB1\ | Stahlbetonfertigteilplatte | EG_Produktion_FFB | 0113PFu0000000535 | m² | Fertigteil | D001 | false | 100 | XC1, WO | C35/45 | HI_GES_FEB-0,220_xxx | Platte | - | no | 0
Stahlbetonfertigteilplatte | EG_Produktion_FFB | BASESLAB | Stahlbetonfertigteil | BP-STB1\ | Stahlbetonfertigteilplatte | EG_Produktion_FFB | 0113PFu0000000539 | m² | Fertigteil | D001 | false | 100 | XC1, WO | C35/45 | HI_GES_FEB-0,220_xxx | Platte | - | no | 0
Stahlbetonfertigteilplatte | EG_Produktion_FFB | BASESLAB | Stahlbetonfertigteil | BP-STB1\ | Stahlbetonfertigteilplatte | EG_Produktion_FFB | 0113PFu0000000549 | m² | Fertigteil | D001 | false | 100 | XC1, WO | C35/45 | HI_GES_FEB-0,220_xxx | Platte | - | no | 0
Stahlbetonfertigteilplatte | EG_Produktion_FFB | BASESLAB | Stahlbetonfertigteil | BP-STB1\ | Stahlbetonfertigteilplatte | EG_Produktion_FFB | 0113PFu0000000553 | m² | Fertigteil | D001 | false | 100 | XC1, WO | C35/45 | HI_GES_FEB-0,220_xxx | Platte | - | no | 0
Stahlbetonfertigteilplatte | EG_Produktion_FFB | BASESLAB | Stahlbetonfertigteil | BP-STB1\ | Stahlbetonfertigteilplatte | EG_Produktion_FFB | 0113PFu0000000555 | m² | Fertigteil | D001 | false | 100 | XC1, WO | C35/45 | HI_GES_FEB-0,220_xxx | Platte | - | no | 0
Stahlbetonfertigteilplatte | EG_Produktion_FFB | BASESLAB | Stahlbetonfertigteil | BP-STB1\ | Stahlbetonfertigteilplatte | EG_Produktion_FFB | 0113PFu0000000557 | m² | Fertigteil | D001 | false | 100 | XC1, WO | C35/45 | HI_GES_FEB-0,220_xxx | Platte | - | no | 0
Stahlbetonfertigteilplatte | EG_Produktion_FFB | BASESLAB | Stahlbetonfertigteil | BP-STB1\ | Stahlbetonfertigteilplatte | EG_Produktion_FFB | 0113PFu0000000559 | m² | Fertigteil | D001 | false | 100 | XC1, WO | C35/45 | HI_GES_FEB-0,220_xxx | Platte | - | no | 0
Stahlbetonfertigteilplatte | EG_Produktion_FFB | BASESLAB | Stahlbetonfertigteil | BP-STB1\ | Stahlbetonfertigteilplatte | EG_Produktion_FFB | 0113PFu0000000665 | m² | Fertigteil | D001 | false | 100 | XC1, WO | C35/45 | HI_GES_FEB-0,220_xxx | Platte | - | no | 0
Stahlbetonfertigteilplatte | EG_Produktion_FFB | BASESLAB | Stahlbetonfertigteil | BP-STB1\ | Stahlbetonfertigteilplatte | EG_Produktion_FFB | 0113PFu0000000673 | m² | Fertigteil | D001 | false | 100 | XC1, WO | C35/45 | HI_GES_FEB-0,220_xxx | Platte | - | no | 0
Stahlbetonfertigteilplatte | EG_Produktion_FFB | BASESLAB | Stahlbetonfertigteil | BP-STB1\ | Stahlbetonfertigteilplatte | EG_Produktion_FFB | 0113PFu0000000675 | m² | Fertigteil | D001 | false | 100 | XC1, WO | C35/45 | HI_GES_FEB-0,220_xxx | Platte | - | no | 0
Stahlbetonfertigteilplatte | EG_Produktion_FFB | BASESLAB | Stahlbetonfertigteil | BP-STB1\ | Stahlbetonfertigteilplatte | EG_Produktion_FFB | 0113PFu0000000679 | m² | Fertigteil | D001 | false | 100 | XC1, WO | C35/45 | HI_GES_FEB-0,220_xxx | Platte | - | no | 0
Stahlbetonfertigteilplatte | EG_Produktion_FFB | BASESLAB | Stahlbetonfertigteil | BP-STB1\ | Stahlbetonfertigteilplatte | EG_Produktion_FFB | 0113PFu0000000703 | m² | Fertigteil | D001 | false | 100 | XC1, WO | C35/45 | HI_GES_FEB-0,220_xxx | Platte | - | no | 0
Stahlbetonfertigteilplatte | EG_Produktion_FFB | BASESLAB | Stahlbetonfertigteil | BP-STB1\ | Stahlbetonfertigteilplatte | EG_Produktion_FFB | 0113PFu0000000711 | m² | Fertigteil | D001 | false | 100 | XC1, WO | C35/45 | HI_GES_FEB-0,220_xxx | Platte | - | no | 0
Stahlbetonfertigteilplatte | EG_Produktion_FFB | BASESLAB | Stahlbetonfertigteil | BP-STB1\ | Stahlbetonfertigteilplatte | EG_Produktion_FFB | 0113PFu0000000713 | m² | Fertigteil | D001 | false | 100 | XC1, WO | C35/45 | HI_GES_FEB-0,220_xxx | Platte | - | no | 0
Stahlbetonfertigteilplatte | EG_Produktion_FFB | BASESLAB | Stahlbetonfertigteil | BP-STB1\ | Stahlbetonfertigteilplatte | EG_Produktion_FFB | 0113PFu0000000715 | m² | Fertigteil | D001 | false | 100 | XC1, WO | C35/45 | HI_GES_FEB-0,220_xxx | Platte | - | no | 0
Stahlbetonfertigteilplatte | EG_Produktion_FFB | BASESLAB | Stahlbetonfertigteil | BP-STB1\ | Stahlbetonfertigteilplatte | EG_Produktion_FFB | 0113PFu0000000741 | m² | Fertigteil | D001 | false | 100 | XC1, WO | C35/45 | HI_GES_FEB-0,220_xxx | Platte | - | no | 0
Stahlbetonfertigteilplatte | EG_Produktion_FFB | BASESLAB | Stahlbetonfertigteil | BP-STB1\ | Stahlbetonfertigteilplatte | EG_Produktion_FFB | 0113PFu0000000751 | m² | Fertigteil | D001 | false | 100 | XC1, WO | C35/45 | HI_GES_FEB-0,220_xxx | Platte | - | no | 0
Stahlbetonfertigteilplatte | EG_Produktion_FFB | BASESLAB | Stahlbetonfertigteil | BP-STB1\ | Stahlbetonfertigteilplatte | EG_Produktion_FFB | 0113PFu0000000753 | m² | Fertigteil | D001 | false | 100 | XC1, WO | C35/45 | HI_GES_FEB-0,220_xxx | Platte | - | no | 0
Stahlbetonfertigteilplatte | EG_Produktion_FFB | BASESLAB | Stahlbetonfertigteil | BP-STB1\ | Stahlbetonfertigteilplatte | EG_Produktion_FFB | 0113PFu0000000677 | m² | Fertigteil | D001 | false | 100 | XC1, WO | C35/45 | HI_GES_FEB-0,220_xxx | Platte | - | no | 0
Stahlbetonfertigteilplatte | EG_Produktion_FFB | BASESLAB | Stahlbetonfertigteil | BP-STB1\ | Stahlbetonfertigteilplatte | EG_Produktion_FFB | 0113PFu0000000297 | m² | Fertigteil | D001 | false | 100 | XC1, WO | C35/45 | HI_GES_FEB-0,220_xxx | Platte | - | no | 0
Stahlbetonfertigteilplatte | EG_Produktion_FFB | BASESLAB | Stahlbetonfertigteil | BP-STB1\ | Stahlbetonfertigteilplatte | EG_Produktion_FFB | 0113PFu0000000709 | m² | Fertigteil | D001 | false | 100 | XC1, WO | C35/45 | HI_GES_FEB-0,220_xxx | Platte | - | no | 0
Stahlbetonfertigteilplatte | EG_Produktion_FFB | BASESLAB | Stahlbetonfertigteil | BP-STB1\ | Stahlbetonfertigteilplatte | EG_Produktion_FFB | 0113PFu0000005902 | m² | Fertigteil | D001 | false | 100 | XC1, WO | C35/45 | HI_GES_FEB-0,220_xxx | Platte | - | no | 0
Stahlbetonfertigteilplatte | EG_Produktion_FFB | BASESLAB | Stahlbetonfertigteil | BP-STB1\ | Stahlbetonfertigteilplatte | EG_Produktion_FFB | 0113PFu0000000743 | m² | Fertigteil | D001 | false | 100 | XC1, WO | C35/45 | HI_GES_FEB-0,220_xxx | Platte | - | no | 0
Stahlbetonfertigteilplatte | EG_Produktion_FFB | BASESLAB | Stahlbetonfertigteil | BP-STB1\ | Stahlbetonfertigteilplatte | EG_Produktion_FFB | 0113PFu0000001834 | m² | Fertigteil | D001 | false | 100 | XC1, WO | C35/45 | HI_GES_FEB-0,220_xxx | Platte | - | no | 0
Stahlbetonfertigteilplatte | EG_Produktion_FFB | BASESLAB | Stahlbetonfertigteil | BP-STB1\ | Stahlbetonfertigteilplatte | EG_Produktion_FFB | 0113PFu0000001831 | m² | Fertigteil | D001 | false | 100 | XC1, WO | C35/45 | HI_GES_FEB-0,220_xxx | Platte | - | no | 0
Stahlbetonfertigteilplatte | EG_Produktion_FFB | BASESLAB | Stahlbetonfertigteil | BP-STB1\ | Stahlbetonfertigteilplatte | EG_Produktion_FFB | 0113PFu0000000013 | m² | Fertigteil | D001 | false | 100 | XC1, WO | C35/45 | HI_GES_FEB-0,220_xxx | Platte | - | no | 0
Stahlbetonfertigteilplatte | EG_Produktion_FFB | BASESLAB | Stahlbetonfertigteil | BP-STB1\ | Stahlbetonfertigteilplatte | EG_Produktion_FFB | 0113PFu0000000015 | m² | Fertigteil | D001 | false | 100 | XC1, WO | C35/45 | HI_GES_FEB-0,220_xxx | Platte | - | no | 0
Stahlbetonfertigteilplatte | EG_Produktion_FFB | BASESLAB | Stahlbetonfertigteil | BP-STB1\ | Stahlbetonfertigteilplatte | EG_Produktion_FFB | 0113PFu0000000265 | m² | Fertigteil | D001 | false | 100 | XC1, WO | C35/45 | HI_GES_FEB-0,220_xxx | Platte | - | no | 0
Stahlbetonfertigteilplatte | EG_Produktion_FFB | BASESLAB | Stahlbetonfertigteil | BP-STB1\ | Stahlbetonfertigteilplatte | EG_Produktion_FFB | 0113PFu0000000269 | m² | Fertigteil | D001 | false | 100 | XC1, WO | C35/45 | HI_GES_FEB-0,220_xxx | Platte | - | no | 0
Stahlbetonfertigteilplatte | EG_Produktion_FFB | BASESLAB | Stahlbetonfertigteil | BP-STB1\ | Stahlbetonfertigteilplatte | EG_Produktion_FFB | 0113PFu0000000315 | m² | Fertigteil | D001 | false | 100 | XC1, WO | C35/45 | HI_GES_FEB-0,220_xxx | Platte | - | no | 0
Stahlbetonfertigteilplatte | EG_Produktion_FFB | BASESLAB | Stahlbetonfertigteil | BP-STB1\ | Stahlbetonfertigteilplatte | EG_Produktion_FFB | 0113PFu0000000317 | m² | Fertigteil | D001 | false | 100 | XC1, WO | C35/45 | HI_GES_FEB-0,220_xxx | Platte | - | no | 0
Stahlbetonfertigteilplatte | EG_Produktion_FFB | BASESLAB | Stahlbetonfertigteil | BP-STB1\ | Stahlbetonfertigteilplatte | EG_Produktion_FFB | 0113PFu0000000319 | m² | Fertigteil | D001 | false | 100 | XC1, WO | C35/45 | HI_GES_FEB-0,220_xxx | Platte | - | no | 0
Stahlbetonfertigteilplatte | EG_Produktion_FFB | BASESLAB | Stahlbetonfertigteil | BP-STB1\ | Stahlbetonfertigteilplatte | EG_Produktion_FFB | 0113PFu0000000321 | m² | Fertigteil | D001 | false | 100 | XC1, WO | C35/45 | HI_GES_FEB-0,220_xxx | Platte | - | no | 0
Stahlbetonfertigteilplatte | EG_Produktion_FFB | BASESLAB | Stahlbetonfertigteil | BP-STB1\ | Stahlbetonfertigteilplatte | EG_Produktion_FFB | 0113PFu0000000347 | m² | Fertigteil | D001 | false | 100 | XC1, WO | C35/45 | HI_GES_FEB-0,220_xxx | Platte | - | no | 0
Stahlbetonfertigteilplatte | EG_Produktion_FFB | BASESLAB | Stahlbetonfertigteil | BP-STB1\ | Stahlbetonfertigteilplatte | EG_Produktion_FFB | 0113PFu0000000349 | m² | Fertigteil | D001 | false | 100 | XC1, WO | C35/45 | HI_GES_FEB-0,220_xxx | Platte | - | no | 0
Stahlbetonfertigteilplatte | EG_Produktion_FFB | BASESLAB | Stahlbetonfertigteil | BP-STB1\ | Stahlbetonfertigteilplatte | EG_Produktion_FFB | 0113PFu0000000351 | m² | Fertigteil | D001 | false | 100 | XC1, WO | C35/45 | HI_GES_FEB-0,220_xxx | Platte | - | no | 0
Stahlbetonfertigteilplatte | EG_Produktion_FFB | BASESLAB | Stahlbetonfertigteil | BP-STB1\ | Stahlbetonfertigteilplatte | EG_Produktion_FFB | 0113PFu0000000353 | m² | Fertigteil | D001 | false | 100 | XC1, WO | C35/45 | HI_GES_FEB-0,220_xxx | Platte | - | no | 0
Stahlbetonfertigteilplatte | EG_Produktion_FFB | BASESLAB | Stahlbetonfertigteil | BP-STB1\ | Stahlbetonfertigteilplatte | EG_Produktion_FFB | 0113PFu0000000383 | m² | Fertigteil | D001 | false | 100 | XC1, WO | C35/45 | HI_GES_FEB-0,220_xxx | Platte | - | no | 0
Stahlbetonfertigteilplatte | EG_Produktion_FFB | BASESLAB | Stahlbetonfertigteil | BP-STB1\ | Stahlbetonfertigteilplatte | EG_Produktion_FFB | 0113PFu0000000385 | m² | Fertigteil | D001 | false | 100 | XC1, WO | C35/45 | HI_GES_FEB-0,220_xxx | Platte | - | no | 0
Stahlbetonfertigteilplatte | EG_Produktion_FFB | BASESLAB | Stahlbetonfertigteil | BP-STB1\ | Stahlbetonfertigteilplatte | EG_Produktion_FFB | 0113PFu0000000387 | m² | Fertigteil | D001 | false | 100 | XC1, WO | C35/45 | HI_GES_FEB-0,220_xxx | Platte | - | no | 0
Stahlbetonfertigteilplatte | EG_Produktion_FFB | BASESLAB | Stahlbetonfertigteil | BP-STB1\ | Stahlbetonfertigteilplatte | EG_Produktion_FFB | 0113PFu0000000389 | m² | Fertigteil | D001 | false | 100 | XC1, WO | C35/45 | HI_GES_FEB-0,220_xxx | Platte | - | no | 0
Stahlbetonfertigteilplatte | EG_Produktion_FFB | BASESLAB | Stahlbetonfertigteil | BP-STB1\ | Stahlbetonfertigteilplatte | EG_Produktion_FFB | 0113PFu0000000415 | m² | Fertigteil | D001 | false | 100 | XC1, WO | C35/45 | HI_GES_FEB-0,220_xxx | Platte | - | no | 0
Stahlbetonfertigteilplatte | EG_Produktion_FFB | BASESLAB | Stahlbetonfertigteil | BP-STB1\ | Stahlbetonfertigteilplatte | EG_Produktion_FFB | 0113PFu0000000417 | m² | Fertigteil | D001 | false | 100 | XC1, WO | C35/45 | HI_GES_FEB-0,220_xxx | Platte | - | no | 0
Stahlbetonfertigteilplatte | EG_Produktion_FFB | BASESLAB | Stahlbetonfertigteil | BP-STB1\ | Stahlbetonfertigteilplatte | EG_Produktion_FFB | 0113PFu0000000419 | m² | Fertigteil | D001 | false | 100 | XC1, WO | C35/45 | HI_GES_FEB-0,220_xxx | Platte | - | no | 0
Stahlbetonfertigteilplatte | EG_Produktion_FFB | BASESLAB | Stahlbetonfertigteil | BP-STB1\ | Stahlbetonfertigteilplatte | EG_Produktion_FFB | 0113PFu0000000421 | m² | Fertigteil | D001 | false | 100 | XC1, WO | C35/45 | HI_GES_FEB-0,220_xxx | Platte | - | no | 0
Stahlbetonfertigteilplatte | EG_Produktion_FFB | BASESLAB | Stahlbetonfertigteil | BP-STB1\ | Stahlbetonfertigteilplatte | EG_Produktion_FFB | 0113PFu0000000455 | m² | Fertigteil | D001 | false | 100 | XC1, WO | C35/45 | HI_GES_FEB-0,220_xxx | Platte | - | no | 0
Stahlbetonfertigteilplatte | EG_Produktion_FFB | BASESLAB | Stahlbetonfertigteil | BP-STB1\ | Stahlbetonfertigteilplatte | EG_Produktion_FFB | 0113PFu0000000457 | m² | Fertigteil | D001 | false | 100 | XC1, WO | C35/45 | HI_GES_FEB-0,220_xxx | Platte | - | no | 0
Stahlbetonfertigteilplatte | EG_Produktion_FFB | BASESLAB | Stahlbetonfertigteil | BP-STB1\ | Stahlbetonfertigteilplatte | EG_Produktion_FFB | 0113PFu0000000459 | m² | Fertigteil | D001 | false | 100 | XC1, WO | C35/45 | HI_GES_FEB-0,220_xxx | Platte | - | no | 0
Stahlbetonfertigteilplatte | EG_Produktion_FFB | BASESLAB | Stahlbetonfertigteil | BP-STB1\ | Stahlbetonfertigteilplatte | EG_Produktion_FFB | 0113PFu0000000461 | m² | Fertigteil | D001 | false | 100 | XC1, WO | C35/45 | HI_GES_FEB-0,220_xxx | Platte | - | no | 0
Stahlbetonfertigteilplatte | EG_Produktion_FFB | BASESLAB | Stahlbetonfertigteil | BP-STB1\ | Stahlbetonfertigteilplatte | EG_Produktion_FFB | 0113PFu0000000491 | m² | Fertigteil | D001 | false | 100 | XC1, WO | C35/45 | HI_GES_FEB-0,220_xxx | Platte | - | no | 0
Stahlbetonfertigteilplatte | EG_Produktion_FFB | BASESLAB | Stahlbetonfertigteil | BP-STB1\ | Stahlbetonfertigteilplatte | EG_Produktion_FFB | 0113PFu0000000493 | m² | Fertigteil | D001 | false | 100 | XC1, WO | C35/45 | HI_GES_FEB-0,220_xxx | Platte | - | no | 0
Stahlbetonfertigteilplatte | EG_Produktion_FFB | BASESLAB | Stahlbetonfertigteil | BP-STB1\ | Stahlbetonfertigteilplatte | EG_Produktion_FFB | 0113PFu0000000495 | m² | Fertigteil | D001 | false | 100 | XC1, WO | C35/45 | HI_GES_FEB-0,220_xxx | Platte | - | no | 0
Stahlbetonfertigteilplatte | EG_Produktion_FFB | BASESLAB | Stahlbetonfertigteil | BP-STB1\ | Stahlbetonfertigteilplatte | EG_Produktion_FFB | 0113PFu0000000497 | m² | Fertigteil | D001 | false | 100 | XC1, WO | C35/45 | HI_GES_FEB-0,220_xxx | Platte | - | no | 0
Stahlbetonfertigteilplatte | EG_Produktion_FFB | BASESLAB | Stahlbetonfertigteil | BP-STB1\ | Stahlbetonfertigteilplatte | EG_Produktion_FFB | 0113PFu0000000523 | m² | Fertigteil | D001 | false | 100 | XC1, WO | C35/45 | HI_GES_FEB-0,220_xxx | Platte | - | no | 0
Stahlbetonfertigteilplatte | EG_Produktion_FFB | BASESLAB | Stahlbetonfertigteil | BP-STB1\ | Stahlbetonfertigteilplatte | EG_Produktion_FFB | 0113PFu0000000525 | m² | Fertigteil | D001 | false | 100 | XC1, WO | C35/45 | HI_GES_FEB-0,220_xxx | Platte | - | no | 0
Stahlbetonfertigteilplatte | EG_Produktion_FFB | BASESLAB | Stahlbetonfertigteil | BP-STB1\ | Stahlbetonfertigteilplatte | EG_Produktion_FFB | 0113PFu0000000527 | m² | Fertigteil | D001 | false | 100 | XC1, WO | C35/45 | HI_GES_FEB-0,220_xxx | Platte | - | no | 0
Stahlbetonfertigteilplatte | EG_Produktion_FFB | BASESLAB | Stahlbetonfertigteil | BP-STB1\ | Stahlbetonfertigteilplatte | EG_Produktion_FFB | 0113PFu0000000529 | m² | Fertigteil | D001 | false | 100 | XC1, WO | C35/45 | HI_GES_FEB-0,220_xxx | Platte | - | no | 0
Stahlbetonfertigteilplatte | EG_Produktion_FFB | BASESLAB | Stahlbetonfertigteil | BP-STB1\ | Stahlbetonfertigteilplatte | EG_Produktion_FFB | 0113PFu0000000531 | m² | Fertigteil | D001 | false | 100 | XC1, WO | C35/45 | HI_GES_FEB-0,220_xxx | Platte | - | no | 0
Stahlbetonfertigteilplatte | EG_Produktion_FFB | BASESLAB | Stahlbetonfertigteil | BP-STB1\ | Stahlbetonfertigteilplatte | EG_Produktion_FFB | 0113PFu0000000533 | m² | Fertigteil | D001 | false | 100 | XC1, WO | C35/45 | HI_GES_FEB-0,220_xxx | Platte | - | no | 0
Stahlbetonfertigteilplatte | EG_Produktion_FFB | BASESLAB | Stahlbetonfertigteil | BP-STB1\ | Stahlbetonfertigteilplatte | EG_Produktion_FFB | 0113PFu0000000657 | m² | Fertigteil | D001 | false | 100 | XC1, WO | C35/45 | HI_GES_FEB-0,220_xxx | Platte | - | no | 0
Stahlbetonfertigteilplatte | EG_Produktion_FFB | BASESLAB | Stahlbetonfertigteil | BP-STB1\ | Stahlbetonfertigteilplatte | EG_Produktion_FFB | 0113PFu0000000659 | m² | Fertigteil | D001 | false | 100 | XC1, WO | C35/45 | HI_GES_FEB-0,220_xxx | Platte | - | no | 0
Stahlbetonfertigteilplatte | EG_Produktion_FFB | BASESLAB | Stahlbetonfertigteil | BP-STB1\ | Stahlbetonfertigteilplatte | EG_Produktion_FFB | 0113PFu0000000661 | m² | Fertigteil | D001 | false | 100 | XC1, WO | C35/45 | HI_GES_FEB-0,220_xxx | Platte | - | no | 0
Stahlbetonfertigteilplatte | EG_Produktion_FFB | BASESLAB | Stahlbetonfertigteil | BP-STB1\ | Stahlbetonfertigteilplatte | EG_Produktion_FFB | 0113PFu0000000663 | m² | Fertigteil | D001 | false | 100 | XC1, WO | C35/45 | HI_GES_FEB-0,220_xxx | Platte | - | no | 0
Stahlbetonfertigteilplatte | EG_Produktion_FFB | BASESLAB | Stahlbetonfertigteil | BP-STB1\ | Stahlbetonfertigteilplatte | EG_Produktion_FFB | 0113PFu0000000689 | m² | Fertigteil | D001 | false | 100 | XC1, WO | C35/45 | HI_GES_FEB-0,220_xxx | Platte | - | no | 0
Stahlbetonfertigteilplatte | EG_Produktion_FFB | BASESLAB | Stahlbetonfertigteil | BP-STB1\ | Stahlbetonfertigteilplatte | EG_Produktion_FFB | 0113PFu0000000691 | m² | Fertigteil | D001 | false | 100 | XC1, WO | C35/45 | HI_GES_FEB-0,220_xxx | Platte | - | no | 0
Stahlbetonfertigteilplatte | EG_Produktion_FFB | BASESLAB | Stahlbetonfertigteil | BP-STB1\ | Stahlbetonfertigteilplatte | EG_Produktion_FFB | 0113PFu0000000693 | m² | Fertigteil | D001 | false | 100 | XC1, WO | C35/45 | HI_GES_FEB-0,220_xxx | Platte | - | no | 0
Stahlbetonfertigteilplatte | EG_Produktion_FFB | BASESLAB | Stahlbetonfertigteil | BP-STB1\ | Stahlbetonfertigteilplatte | EG_Produktion_FFB | 0113PFu0000000695 | m² | Fertigteil | D001 | false | 100 | XC1, WO | C35/45 | HI_GES_FEB-0,220_xxx | Platte | - | no | 0
Stahlbetonfertigteilplatte | EG_Produktion_FFB | BASESLAB | Stahlbetonfertigteil | BP-STB1\ | Stahlbetonfertigteilplatte | EG_Produktion_FFB | 0113PFu0000000729 | m² | Fertigteil | D001 | false | 100 | XC1, WO | C35/45 | HI_GES_FEB-0,220_xxx | Platte | - | no | 0
Stahlbetonfertigteilplatte | EG_Produktion_FFB | BASESLAB | Stahlbetonfertigteil | BP-STB1\ | Stahlbetonfertigteilplatte | EG_Produktion_FFB | 0113PFu0000000731 | m² | Fertigteil | D001 | false | 100 | XC1, WO | C35/45 | HI_GES_FEB-0,220_xxx | Platte | - | no | 0
Stahlbetonfertigteilplatte | EG_Produktion_FFB | BASESLAB | Stahlbetonfertigteil | BP-STB1\ | Stahlbetonfertigteilplatte | EG_Produktion_FFB | 0113PFu0000000311 | m² | Fertigteil | D001 | false | 100 | XC1, WO | C35/45 | HI_GES_FEB-0,220_xxx | Platte | - | no | 0
Stahlbetonfertigteilplatte | EG_Produktion_FFB | BASESLAB | Stahlbetonfertigteil | BP-STB1\ | Stahlbetonfertigteilplatte | EG_Produktion_FFB | 0113PFu0000000375 | m² | Fertigteil | D001 | false | 100 | XC1, WO | C35/45 | HI_GES_FEB-0,220_xxx | Platte | - | no | 0
Stahlbetonfertigteilplatte | EG_Produktion_FFB | BASESLAB | Stahlbetonfertigteil | BP-STB1\ | Stahlbetonfertigteilplatte | EG_Produktion_FFB | 0113PFu0000000309 | m² | Fertigteil | D001 | false | 100 | XC1, WO | C35/45 | HI_GES_FEB-0,220_xxx | Platte | - | no | 0
Stahlbetonfertigteilplatte | EG_Produktion_FFB | BASESLAB | Stahlbetonfertigteil | BP-STB1\ | Stahlbetonfertigteilplatte | EG_Produktion_FFB | 0113PFu0000000313 | m² | Fertigteil | D001 | false | 100 | XC1, WO | C35/45 | HI_GES_FEB-0,220_xxx | Platte | - | no | 0
Stahlbetonfertigteilplatte | EG_Produktion_FFB | BASESLAB | Stahlbetonfertigteil | BP-STB1\ | Stahlbetonfertigteilplatte | EG_Produktion_FFB | 0113PFu0000000339 | m² | Fertigteil | D001 | false | 100 | XC1, WO | C35/45 | HI_GES_FEB-0,220_xxx | Platte | - | no | 0
Stahlbetonfertigteilplatte | EG_Produktion_FFB | BASESLAB | Stahlbetonfertigteil | BP-STB1\ | Stahlbetonfertigteilplatte | EG_Produktion_FFB | 0113PFu0000000341 | m² | Fertigteil | D001 | false | 100 | XC1, WO | C35/45 | HI_GES_FEB-0,220_xxx | Platte | - | no | 0
Stahlbetonfertigteilplatte | EG_Produktion_FFB | BASESLAB | Stahlbetonfertigteil | BP-STB1\ | Stahlbetonfertigteilplatte | EG_Produktion_FFB | 0113PFu0000000377 | m² | Fertigteil | D001 | false | 100 | XC1, WO | C35/45 | HI_GES_FEB-0,220_xxx | Platte | - | no | 0
Stahlbetonfertigteilplatte | EG_Produktion_FFB | BASESLAB | Stahlbetonfertigteil | BP-STB1\ | Stahlbetonfertigteilplatte | EG_Produktion_FFB | 0113PFu0000000407 | m² | Fertigteil | D001 | false | 100 | XC1, WO | C35/45 | HI_GES_FEB-0,220_xxx | Platte | - | no | 0
Stahlbetonfertigteilplatte | EG_Produktion_FFB | BASESLAB | Stahlbetonfertigteil | BP-STB1\ | Stahlbetonfertigteilplatte | EG_Produktion_FFB | 0113PFu0000000409 | m² | Fertigteil | D001 | false | 100 | XC1, WO | C35/45 | HI_GES_FEB-0,220_xxx | Platte | - | no | 0
Stahlbetonfertigteilplatte | EG_Produktion_FFB | BASESLAB | Stahlbetonfertigteil | BP-STB1\ | Stahlbetonfertigteilplatte | EG_Produktion_FFB | 0113PFu0000000447 | m² | Fertigteil | D001 | false | 100 | XC1, WO | C35/45 | HI_GES_FEB-0,220_xxx | Platte | - | no | 0
Stahlbetonfertigteilplatte | EG_Produktion_FFB | BASESLAB | Stahlbetonfertigteil | BP-STB1\ | Stahlbetonfertigteilplatte | EG_Produktion_FFB | 0113PFu0000000449 | m² | Fertigteil | D001 | false | 100 | XC1, WO | C35/45 | HI_GES_FEB-0,220_xxx | Platte | - | no | 0
Stahlbetonfertigteilplatte | EG_Produktion_FFB | BASESLAB | Stahlbetonfertigteil | BP-STB1\ | Stahlbetonfertigteilplatte | EG_Produktion_FFB | 0113PFu0000000483 | m² | Fertigteil | D001 | false | 100 | XC1, WO | C35/45 | HI_GES_FEB-0,220_xxx | Platte | - | no | 0
Stahlbetonfertigteilplatte | EG_Produktion_FFB | BASESLAB | Stahlbetonfertigteil | BP-STB1\ | Stahlbetonfertigteilplatte | EG_Produktion_FFB | 0113PFu0000000485 | m² | Fertigteil | D001 | false | 100 | XC1, WO | C35/45 | HI_GES_FEB-0,220_xxx | Platte | - | no | 0
Stahlbetonfertigteilplatte | EG_Produktion_FFB | BASESLAB | Stahlbetonfertigteil | BP-STB1\ | Stahlbetonfertigteilplatte | EG_Produktion_FFB | 0113PFu0000000515 | m² | Fertigteil | D001 | false | 100 | XC1, WO | C35/45 | HI_GES_FEB-0,220_xxx | Platte | - | no | 0
Stahlbetonfertigteilplatte | EG_Produktion_FFB | BASESLAB | Stahlbetonfertigteil | BP-STB1\ | Stahlbetonfertigteilplatte | EG_Produktion_FFB | 0113PFu0000000517 | m² | Fertigteil | D001 | false | 100 | XC1, WO | C35/45 | HI_GES_FEB-0,220_xxx | Platte | - | no | 0
Stahlbetonfertigteilplatte | EG_Produktion_FFB | BASESLAB | Stahlbetonfertigteil | BP-STB1\ | Stahlbetonfertigteilplatte | EG_Produktion_FFB | 0113PFu0000000519 | m² | Fertigteil | D001 | false | 100 | XC1, WO | C35/45 | HI_GES_FEB-0,220_xxx | Platte | - | no | 0
Stahlbetonfertigteilplatte | EG_Produktion_FFB | BASESLAB | Stahlbetonfertigteil | BP-STB1\ | Stahlbetonfertigteilplatte | EG_Produktion_FFB | 0113PFu0000000569 | m² | Fertigteil | D001 | false | 100 | XC1, WO | C35/45 | HI_GES_FEB-0,220_xxx | Platte | - | no | 0
Stahlbetonfertigteilplatte | EG_Produktion_FFB | BASESLAB | Stahlbetonfertigteil | BP-STB1\ | Stahlbetonfertigteilplatte | EG_Produktion_FFB | 0113PFu0000000571 | m² | Fertigteil | D001 | false | 100 | XC1, WO | C35/45 | HI_GES_FEB-0,220_xxx | Platte | - | no | 0
Stahlbetonfertigteilplatte | EG_Produktion_FFB | BASESLAB | Stahlbetonfertigteil | BP-STB1\ | Stahlbetonfertigteilplatte | EG_Produktion_FFB | 0113PFu0000000573 | m² | Fertigteil | D001 | false | 100 | XC1, WO | C35/45 | HI_GES_FEB-0,220_xxx | Platte | - | no | 0
Stahlbetonfertigteilplatte | EG_Produktion_FFB | BASESLAB | Stahlbetonfertigteil | BP-STB1\ | Stahlbetonfertigteilplatte | EG_Produktion_FFB | 0113PFu0000000575 | m² | Fertigteil | D001 | false | 100 | XC1, WO | C35/45 | HI_GES_FEB-0,220_xxx | Platte | - | no | 0
Stahlbetonfertigteilplatte | EG_Produktion_FFB | BASESLAB | Stahlbetonfertigteil | BP-STB1\ | Stahlbetonfertigteilplatte | EG_Produktion_FFB | 0113PFu0000000577 | m² | Fertigteil | D001 | false | 100 | XC1, WO | C35/45 | HI_GES_FEB-0,220_xxx | Platte | - | no | 0
Stahlbetonfertigteilplatte | EG_Produktion_FFB | BASESLAB | Stahlbetonfertigteil | BP-STB1\ | Stahlbetonfertigteilplatte | EG_Produktion_FFB | 0113PFu0000000579 | m² | Fertigteil | D001 | false | 100 | XC1, WO | C35/45 | HI_GES_FEB-0,220_xxx | Platte | - | no | 0
Stahlbetonfertigteilplatte | EG_Produktion_FFB | BASESLAB | Stahlbetonfertigteil | BP-STB1\ | Stahlbetonfertigteilplatte | EG_Produktion_FFB | 0113PFu0000000681 | m² | Fertigteil | D001 | false | 100 | XC1, WO | C35/45 | HI_GES_FEB-0,220_xxx | Platte | - | no | 0
Stahlbetonfertigteilplatte | EG_Produktion_FFB | BASESLAB | Stahlbetonfertigteil | BP-STB1\ | Stahlbetonfertigteilplatte | EG_Produktion_FFB | 0113PFu0000000683 | m² | Fertigteil | D001 | false | 100 | XC1, WO | C35/45 | HI_GES_FEB-0,220_xxx | Platte | - | no | 0
Stahlbetonfertigteilplatte | EG_Produktion_FFB | BASESLAB | Stahlbetonfertigteil | BP-STB1\ | Stahlbetonfertigteilplatte | EG_Produktion_FFB | 0113PFu0000000685 | m² | Fertigteil | D001 | false | 100 | XC1, WO | C35/45 | HI_GES_FEB-0,220_xxx | Platte | - | no | 0
Stahlbetonfertigteilplatte | EG_Produktion_FFB | BASESLAB | Stahlbetonfertigteil | BP-STB1\ | Stahlbetonfertigteilplatte | EG_Produktion_FFB | 0113PFu0000000687 | m² | Fertigteil | D001 | false | 100 | XC1, WO | C35/45 | HI_GES_FEB-0,220_xxx | Platte | - | no | 0
Stahlbetonfertigteilplatte | EG_Produktion_FFB | BASESLAB | Stahlbetonfertigteil | BP-STB1\ | Stahlbetonfertigteilplatte | EG_Produktion_FFB | 0113PFu0000000721 | m² | Fertigteil | D001 | false | 100 | XC1, WO | C35/45 | HI_GES_FEB-0,220_xxx | Platte | - | no | 0
Stahlbetonfertigteilplatte | EG_Produktion_FFB | BASESLAB | Stahlbetonfertigteil | BP-STB1\ | Stahlbetonfertigteilplatte | EG_Produktion_FFB | 0113PFu0000000723 | m² | Fertigteil | D001 | false | 100 | XC1, WO | C35/45 | HI_GES_FEB-0,220_xxx | Platte | - | no | 0
Stahlbetonfertigteilplatte | EG_Produktion_FFB | BASESLAB | Stahlbetonfertigteil | BP-STB1\ | Stahlbetonfertigteilplatte | EG_Produktion_FFB | 0113PFu0000000725 | m² | Fertigteil | D001 | false | 100 | XC1, WO | C35/45 | HI_GES_FEB-0,220_xxx | Platte | - | no | 0
Stahlbetonfertigteilplatte | EG_Produktion_FFB | BASESLAB | Stahlbetonfertigteil | BP-STB1\ | Stahlbetonfertigteilplatte | EG_Produktion_FFB | 0113PFu0000000727 | m² | Fertigteil | D001 | false | 100 | XC1, WO | C35/45 | HI_GES_FEB-0,220_xxx | Platte | - | no | 0
Stahlbetonfertigteilplatte | EG_Produktion_FFB | BASESLAB | Stahlbetonfertigteil | BP-STB1\ | Stahlbetonfertigteilplatte | EG_Produktion_FFB | 0113PFu0000000747 | m² | Fertigteil | D001 | false | 100 | XC1, WO | C35/45 | HI_GES_FEB-0,220_xxx | Platte | - | no | 0
Stahlbetonfertigteilplatte | EG_Produktion_FFB | BASESLAB | Stahlbetonfertigteil | BP-STB1\ | Stahlbetonfertigteilplatte | EG_Produktion_FFB | 0113PFu0000000749 | m² | Fertigteil | D001 | false | 100 | XC1, WO | C35/45 | HI_GES_FEB-0,220_xxx | Platte | - | no | 0
Stahlbetonfertigteilplatte | EG_Produktion_FFB | BASESLAB | Stahlbetonfertigteil | BP-STB1\ | Stahlbetonfertigteilplatte | EG_Produktion_FFB | 0113PFu0000000521 | m² | Fertigteil | D001 | false | 100 | XC1, WO | C35/45 | HI_GES_FEB-0,220_xxx | Platte | - | no | 0
Stahlbetonfertigteilplatte | EG_Produktion_FFB | BASESLAB | Stahlbetonfertigteil | BP-STB1\ | Stahlbetonfertigteilplatte | EG_Produktion_FFB | 0113PFu0000000261 | m² | Fertigteil | D001 | false | 100 | XC1, WO | C35/45 | HI_GES_FEB-0,220_xxx | Platte | - | no | 0
Stahlbetonfertigteilplatte | EG_Produktion_FFB | BASESLAB | Stahlbetonfertigteil | BP-STB1\ | Stahlbetonfertigteilplatte | EG_Produktion_FFB | 0113PFu0000000235 | m² | Fertigteil | D001 | false | 100 | XC1, WO | C35/45 | HI_GES_FEB-0,220_xxx | Platte | - | no | 0
Stahlbetonfertigteilplatte | EG_Produktion_FFB | BASESLAB | Stahlbetonfertigteil | BP-STB1\ | Stahlbetonfertigteilplatte | EG_Produktion_FFB | 0113PFu0000000215 | m² | Fertigteil | D002 | false | 100 | XC1, WO | C35/45 | HI_GES_FEB-0,220_xxx | Platte | - | no | 0
Stahlbetonfertigteilplatte | EG_Produktion_FFB | BASESLAB | Stahlbetonfertigteil | BP-STB1\ | Stahlbetonfertigteilplatte | EG_Produktion_FFB | 0113PFu0000006044 | m² | Fertigteil | D002 | false | 100 | XC1, WO | C35/45 | HI_GES_FEB-0,220_xxx | Platte | - | no | 0
Stahlbetonfertigteilplatte | EG_Produktion_FFB | BASESLAB | Stahlbetonfertigteil | BP-STB1\ | Stahlbetonfertigteilplatte | EG_Produktion_FFB | 0113PFu0000000047 | m² | Fertigteil | D002 | false | 100 | XC1, WO | C35/45 | HI_GES_FEB-0,220_xxx | Platte | - | no | 0
Stahlbetonfertigteilplatte | EG_Produktion_FFB | BASESLAB | Stahlbetonfertigteil | BP-STB1\ | Stahlbetonfertigteilplatte | EG_Produktion_FFB | 0113PFu0000000057 | m² | Fertigteil | D002 | false | 100 | XC1, WO | C35/45 | HI_GES_FEB-0,220_xxx | Platte | - | no | 0
Stahlbetonfertigteilplatte | EG_Produktion_FFB | BASESLAB | Stahlbetonfertigteil | BP-STB1\ | Stahlbetonfertigteilplatte | EG_Produktion_FFB | 0113PFu0000000285 | m² | Fertigteil | D002 | false | 100 | XC1, WO | C35/45 | HI_GES_FEB-0,220_xxx | Platte | - | no | 0
Stahlbetonfertigteilplatte | EG_Produktion_FFB | BASESLAB | Stahlbetonfertigteil | BP-STB1\ | Stahlbetonfertigteilplatte | EG_Produktion_FFB | 0113PFu0000000287 | m² | Fertigteil | D002 | false | 100 | XC1, WO | C35/45 | HI_GES_FEB-0,220_xxx | Platte | - | no | 0
Stahlbetonfertigteilplatte | EG_Produktion_FFB | BASESLAB | Stahlbetonfertigteil | BP-STB1\ | Stahlbetonfertigteilplatte | EG_Produktion_FFB | 0113PFu0000000239 | m² | Fertigteil | D002 | false | 100 | XC1, WO | C35/45 | HI_GES_FEB-0,220_xxx | Platte | - | no | 0
Stahlbetonfertigteilplatte | EG_Produktion_FFB | BASESLAB | Stahlbetonfertigteil | BP-STB1\ | Stahlbetonfertigteilplatte | EG_Produktion_FFB | 0113PFu0000000283 | m² | Fertigteil | D002 | false | 100 | XC1, WO | C35/45 | HI_GES_FEB-0,220_xxx | Platte | - | no | 0
Stahlbetonfertigteilplatte | EG_Produktion_FFB | BASESLAB | Stahlbetonfertigteil | BP-STB1\ | Stahlbetonfertigteilplatte | EG_Produktion_FFB | 0113PFu0000000289 | m² | Fertigteil | D002 | false | 100 | XC1, WO | C35/45 | HI_GES_FEB-0,220_xxx | Platte | - | no | 0
Stahlbetonfertigteilplatte | EG_Produktion_FFB | BASESLAB | Stahlbetonfertigteil | BP-STB1\ | Stahlbetonfertigteilplatte | EG_Produktion_FFB | 0113PFu0000000649 | m² | Fertigteil | D002 | false | 100 | XC1, WO | C35/45 | HI_GES_FEB-0,220_xxx | Platte | - | no | 0
Stahlbetonfertigteilplatte | EG_Produktion_FFB | BASESLAB | Stahlbetonfertigteil | BP-STB1\ | Stahlbetonfertigteilplatte | EG_Produktion_FFB | 0113PFu0000000655 | m² | Fertigteil | D002 | false | 100 | XC1, WO | C35/45 | HI_GES_FEB-0,220_xxx | Platte | - | no | 0
Stahlbetonfertigteilplatte | EG_Produktion_FFB | BASESLAB | Stahlbetonfertigteil | BP-STB1\ | Stahlbetonfertigteilplatte | EG_Produktion_FFB | 0113PFu0000000021 | m² | Fertigteil | D002 | false | 100 | XC1, WO | C35/45 | HI_GES_FEB-0,220_xxx | Platte | - | no | 0
Stahlbetonfertigteilplatte | EG_Produktion_FFB | BASESLAB | Stahlbetonfertigteil | BP-STB1\ | Stahlbetonfertigteilplatte | EG_Produktion_FFB | 0113PFu0000000023 | m² | Fertigteil | D002 | false | 100 | XC1, WO | C35/45 | HI_GES_FEB-0,220_xxx | Platte | - | no | 0
Stahlbetonfertigteilplatte | EG_Produktion_FFB | BASESLAB | Stahlbetonfertigteil | BP-STB1\ | Stahlbetonfertigteilplatte | EG_Produktion_FFB | 0113PFu0000000025 | m² | Fertigteil | D002 | false | 100 | XC1, WO | C35/45 | HI_GES_FEB-0,220_xxx | Platte | - | no | 0
Stahlbetonfertigteilplatte | EG_Produktion_FFB | BASESLAB | Stahlbetonfertigteil | BP-STB1\ | Stahlbetonfertigteilplatte | EG_Produktion_FFB | 0113PFu0000000027 | m² | Fertigteil | D002 | false | 100 | XC1, WO | C35/45 | HI_GES_FEB-0,220_xxx | Platte | - | no | 0
Stahlbetonfertigteilplatte | EG_Produktion_FFB | BASESLAB | Stahlbetonfertigteil | BP-STB1\ | Stahlbetonfertigteilplatte | EG_Produktion_FFB | 0113PFu0000000029 | m² | Fertigteil | D002 | false | 100 | XC1, WO | C35/45 | HI_GES_FEB-0,220_xxx | Platte | - | no | 0
Stahlbetonfertigteilplatte | EG_Produktion_FFB | BASESLAB | Stahlbetonfertigteil | BP-STB1\ | Stahlbetonfertigteilplatte | EG_Produktion_FFB | 0113PFu0000000031 | m² | Fertigteil | D002 | false | 100 | XC1, WO | C35/45 | HI_GES_FEB-0,220_xxx | Platte | - | no | 0
Stahlbetonfertigteilplatte | EG_Produktion_FFB | BASESLAB | Stahlbetonfertigteil | BP-STB1\ | Stahlbetonfertigteilplatte | EG_Produktion_FFB | 0113PFu0000000033 | m² | Fertigteil | D002 | false | 100 | XC1, WO | C35/45 | HI_GES_FEB-0,220_xxx | Platte | - | no | 0
Stahlbetonfertigteilplatte | EG_Produktion_FFB | BASESLAB | Stahlbetonfertigteil | BP-STB1\ | Stahlbetonfertigteilplatte | EG_Produktion_FFB | 0113PFu0000000035 | m² | Fertigteil | D002 | false | 100 | XC1, WO | C35/45 | HI_GES_FEB-0,220_xxx | Platte | - | no | 0
Stahlbetonfertigteilplatte | EG_Produktion_FFB | BASESLAB | Stahlbetonfertigteil | BP-STB1\ | Stahlbetonfertigteilplatte | EG_Produktion_FFB | 0113PFu0000000037 | m² | Fertigteil | D002 | false | 100 | XC1, WO | C35/45 | HI_GES_FEB-0,220_xxx | Platte | - | no | 0
Stahlbetonfertigteilplatte | EG_Produktion_FFB | BASESLAB | Stahlbetonfertigteil | BP-STB1\ | Stahlbetonfertigteilplatte | EG_Produktion_FFB | 0113PFu0000000039 | m² | Fertigteil | D002 | false | 100 | XC1, WO | C35/45 | HI_GES_FEB-0,220_xxx | Platte | - | no | 0
Stahlbetonfertigteilplatte | EG_Produktion_FFB | BASESLAB | Stahlbetonfertigteil | BP-STB1\ | Stahlbetonfertigteilplatte | EG_Produktion_FFB | 0113PFu0000000041 | m² | Fertigteil | D002 | false | 100 | XC1, WO | C35/45 | HI_GES_FEB-0,220_xxx | Platte | - | no | 0
Stahlbetonfertigteilplatte | EG_Produktion_FFB | BASESLAB | Stahlbetonfertigteil | BP-STB1\ | Stahlbetonfertigteilplatte | EG_Produktion_FFB | 0113PFu0000000043 | m² | Fertigteil | D002 | false | 100 | XC1, WO | C35/45 | HI_GES_FEB-0,220_xxx | Platte | - | no | 0
Stahlbetonfertigteilplatte | EG_Produktion_FFB | BASESLAB | Stahlbetonfertigteil | BP-STB1\ | Stahlbetonfertigteilplatte | EG_Produktion_FFB | 0113PFu0000000045 | m² | Fertigteil | D002 | false | 100 | XC1, WO | C35/45 | HI_GES_FEB-0,220_xxx | Platte | - | no | 0
Stahlbetonfertigteilplatte | EG_Produktion_FFB | BASESLAB | Stahlbetonfertigteil | BP-STB1\ | Stahlbetonfertigteilplatte | EG_Produktion_FFB | 0113PFu0000000053 | m² | Fertigteil | D002 | false | 100 | XC1, WO | C35/45 | HI_GES_FEB-0,220_xxx | Platte | - | no | 0
Stahlbetonfertigteilplatte | EG_Produktion_FFB | BASESLAB | Stahlbetonfertigteil | BP-STB1\ | Stahlbetonfertigteilplatte | EG_Produktion_FFB | 0113PFu0000000055 | m² | Fertigteil | D002 | false | 100 | XC1, WO | C35/45 | HI_GES_FEB-0,220_xxx | Platte | - | no | 0
Stahlbetonfertigteilplatte | EG_Produktion_FFB | BASESLAB | Stahlbetonfertigteil | BP-STB1\ | Stahlbetonfertigteilplatte | EG_Produktion_FFB | 0113PFu0000000059 | m² | Fertigteil | D002 | false | 100 | XC1, WO | C35/45 | HI_GES_FEB-0,220_xxx | Platte | - | no | 0
Stahlbetonfertigteilplatte | EG_Produktion_FFB | BASESLAB | Stahlbetonfertigteil | BP-STB1\ | Stahlbetonfertigteilplatte | EG_Produktion_FFB | 0113PFu0000000069 | m² | Fertigteil | D002 | false | 100 | XC1, WO | C35/45 | HI_GES_FEB-0,220_xxx | Platte | - | no | 0
Stahlbetonfertigteilplatte | EG_Produktion_FFB | BASESLAB | Stahlbetonfertigteil | BP-STB1\ | Stahlbetonfertigteilplatte | EG_Produktion_FFB | 0113PFu0000000071 | m² | Fertigteil | D002 | false | 100 | XC1, WO | C35/45 | HI_GES_FEB-0,220_xxx | Platte | - | no | 0
Stahlbetonfertigteilplatte | EG_Produktion_FFB | BASESLAB | Stahlbetonfertigteil | BP-STB1\ | Stahlbetonfertigteilplatte | EG_Produktion_FFB | 0113PFu0000000077 | m² | Fertigteil | D002 | false | 100 | XC1, WO | C35/45 | HI_GES_FEB-0,220_xxx | Platte | - | no | 0
Stahlbetonfertigteilplatte | EG_Produktion_FFB | BASESLAB | Stahlbetonfertigteil | BP-STB1\ | Stahlbetonfertigteilplatte | EG_Produktion_FFB | 0113PFu0000000085 | m² | Fertigteil | D002 | false | 100 | XC1, WO | C35/45 | HI_GES_FEB-0,220_xxx | Platte | - | no | 0
Stahlbetonfertigteilplatte | EG_Produktion_FFB | BASESLAB | Stahlbetonfertigteil | BP-STB1\ | Stahlbetonfertigteilplatte | EG_Produktion_FFB | 0113PFu0000000175 | m² | Fertigteil | D002 | false | 100 | XC1, WO | C35/45 | HI_GES_FEB-0,220_xxx | Platte | - | no | 0
Stahlbetonfertigteilplatte | EG_Produktion_FFB | BASESLAB | Stahlbetonfertigteil | BP-STB1\ | Stahlbetonfertigteilplatte | EG_Produktion_FFB | 0113PFu0000000177 | m² | Fertigteil | D002 | false | 100 | XC1, WO | C35/45 | HI_GES_FEB-0,220_xxx | Platte | - | no | 0
Stahlbetonfertigteilplatte | EG_Produktion_FFB | BASESLAB | Stahlbetonfertigteil | BP-STB1\ | Stahlbetonfertigteilplatte | EG_Produktion_FFB | 0113PFu0000000183 | m² | Fertigteil | D002 | false | 100 | XC1, WO | C35/45 | HI_GES_FEB-0,220_xxx | Platte | - | no | 0
Stahlbetonfertigteilplatte | EG_Produktion_FFB | BASESLAB | Stahlbetonfertigteil | BP-STB1\ | Stahlbetonfertigteilplatte | EG_Produktion_FFB | 0113PFu0000000185 | m² | Fertigteil | D002 | false | 100 | XC1, WO | C35/45 | HI_GES_FEB-0,220_xxx | Platte | - | no | 0
Stahlbetonfertigteilplatte | EG_Produktion_FFB | BASESLAB | Stahlbetonfertigteil | BP-STB1\ | Stahlbetonfertigteilplatte | EG_Produktion_FFB | 0113PFu0000000187 | m² | Fertigteil | D002 | false | 100 | XC1, WO | C35/45 | HI_GES_FEB-0,220_xxx | Platte | - | no | 0
Stahlbetonfertigteilplatte | EG_Produktion_FFB | BASESLAB | Stahlbetonfertigteil | BP-STB1\ | Stahlbetonfertigteilplatte | EG_Produktion_FFB | 0113PFu0000000195 | m² | Fertigteil | D002 | false | 100 | XC1, WO | C35/45 | HI_GES_FEB-0,220_xxx | Platte | - | no | 0
Stahlbetonfertigteilplatte | EG_Produktion_FFB | BASESLAB | Stahlbetonfertigteil | BP-STB1\ | Stahlbetonfertigteilplatte | EG_Produktion_FFB | 0113PFu0000000197 | m² | Fertigteil | D002 | false | 100 | XC1, WO | C35/45 | HI_GES_FEB-0,220_xxx | Platte | - | no | 0
Stahlbetonfertigteilplatte | EG_Produktion_FFB | BASESLAB | Stahlbetonfertigteil | BP-STB1\ | Stahlbetonfertigteilplatte | EG_Produktion_FFB | 0113PFu0000000203 | m² | Fertigteil | D002 | false | 100 | XC1, WO | C35/45 | HI_GES_FEB-0,220_xxx | Platte | - | no | 0
Stahlbetonfertigteilplatte | EG_Produktion_FFB | BASESLAB | Stahlbetonfertigteil | BP-STB1\ | Stahlbetonfertigteilplatte | EG_Produktion_FFB | 0113PFu0000000299 | m² | Fertigteil | D002 | false | 100 | XC1, WO | C35/45 | HI_GES_FEB-0,220_xxx | Platte | - | no | 0
Stahlbetonfertigteilplatte | EG_Produktion_FFB | BASESLAB | Stahlbetonfertigteil | BP-STB1\ | Stahlbetonfertigteilplatte | EG_Produktion_FFB | 0113PFu0000000327 | m² | Fertigteil | D002 | false | 100 | XC1, WO | C35/45 | HI_GES_FEB-0,220_xxx | Platte | - | no | 0
Stahlbetonfertigteilplatte | EG_Produktion_FFB | BASESLAB | Stahlbetonfertigteil | BP-STB1\ | Stahlbetonfertigteilplatte | EG_Produktion_FFB | 0113PFu0000000329 | m² | Fertigteil | D002 | false | 100 | XC1, WO | C35/45 | HI_GES_FEB-0,220_xxx | Platte | - | no | 0
Stahlbetonfertigteilplatte | EG_Produktion_FFB | BASESLAB | Stahlbetonfertigteil | BP-STB1\ | Stahlbetonfertigteilplatte | EG_Produktion_FFB | 0113PFu0000000363 | m² | Fertigteil | D002 | false | 100 | XC1, WO | C35/45 | HI_GES_FEB-0,220_xxx | Platte | - | no | 0
Stahlbetonfertigteilplatte | EG_Produktion_FFB | BASESLAB | Stahlbetonfertigteil | BP-STB1\ | Stahlbetonfertigteilplatte | EG_Produktion_FFB | 0113PFu0000000365 | m² | Fertigteil | D002 | false | 100 | XC1, WO | C35/45 | HI_GES_FEB-0,220_xxx | Platte | - | no | 0
Stahlbetonfertigteilplatte | EG_Produktion_FFB | BASESLAB | Stahlbetonfertigteil | BP-STB1\ | Stahlbetonfertigteilplatte | EG_Produktion_FFB | 0113PFu0000000395 | m² | Fertigteil | D002 | false | 100 | XC1, WO | C35/45 | HI_GES_FEB-0,220_xxx | Platte | - | no | 0
Stahlbetonfertigteilplatte | EG_Produktion_FFB | BASESLAB | Stahlbetonfertigteil | BP-STB1\ | Stahlbetonfertigteilplatte | EG_Produktion_FFB | 0113PFu0000000397 | m² | Fertigteil | D002 | false | 100 | XC1, WO | C35/45 | HI_GES_FEB-0,220_xxx | Platte | - | no | 0
Stahlbetonfertigteilplatte | EG_Produktion_FFB | BASESLAB | Stahlbetonfertigteil | BP-STB1\ | Stahlbetonfertigteilplatte | EG_Produktion_FFB | 0113PFu0000000431 | m² | Fertigteil | D002 | false | 100 | XC1, WO | C35/45 | HI_GES_FEB-0,220_xxx | Platte | - | no | 0
Stahlbetonfertigteilplatte | EG_Produktion_FFB | BASESLAB | Stahlbetonfertigteil | BP-STB1\ | Stahlbetonfertigteilplatte | EG_Produktion_FFB | 0113PFu0000000433 | m² | Fertigteil | D002 | false | 100 | XC1, WO | C35/45 | HI_GES_FEB-0,220_xxx | Platte | - | no | 0
Stahlbetonfertigteilplatte | EG_Produktion_FFB | BASESLAB | Stahlbetonfertigteil | BP-STB1\ | Stahlbetonfertigteilplatte | EG_Produktion_FFB | 0113PFu0000000479 | m² | Fertigteil | D002 | false | 100 | XC1, WO | C35/45 | HI_GES_FEB-0,220_xxx | Platte | - | no | 0
Stahlbetonfertigteilplatte | EG_Produktion_FFB | BASESLAB | Stahlbetonfertigteil | BP-STB1\ | Stahlbetonfertigteilplatte | EG_Produktion_FFB | 0113PFu0000000505 | m² | Fertigteil | D002 | false | 100 | XC1, WO | C35/45 | HI_GES_FEB-0,220_xxx | Platte | - | no | 0
Stahlbetonfertigteilplatte | EG_Produktion_FFB | BASESLAB | Stahlbetonfertigteil | BP-STB1\ | Stahlbetonfertigteilplatte | EG_Produktion_FFB | 0113PFu0000000541 | m² | Fertigteil | D002 | false | 100 | XC1, WO | C35/45 | HI_GES_FEB-0,220_xxx | Platte | - | no | 0
Stahlbetonfertigteilplatte | EG_Produktion_FFB | BASESLAB | Stahlbetonfertigteil | BP-STB1\ | Stahlbetonfertigteilplatte | EG_Produktion_FFB | 0113PFu0000000545 | m² | Fertigteil | D002 | false | 100 | XC1, WO | C35/45 | HI_GES_FEB-0,220_xxx | Platte | - | no | 0
Stahlbetonfertigteilplatte | EG_Produktion_FFB | BASESLAB | Stahlbetonfertigteil | BP-STB1\ | Stahlbetonfertigteilplatte | EG_Produktion_FFB | 0113PFu0000000547 | m² | Fertigteil | D002 | false | 100 | XC1, WO | C35/45 | HI_GES_FEB-0,220_xxx | Platte | - | no | 0
Stahlbetonfertigteilplatte | EG_Produktion_FFB | BASESLAB | Stahlbetonfertigteil | BP-STB1\ | Stahlbetonfertigteilplatte | EG_Produktion_FFB | 0113PFu0000000563 | m² | Fertigteil | D002 | false | 100 | XC1, WO | C35/45 | HI_GES_FEB-0,220_xxx | Platte | - | no | 0
Stahlbetonfertigteilplatte | EG_Produktion_FFB | BASESLAB | Stahlbetonfertigteil | BP-STB1\ | Stahlbetonfertigteilplatte | EG_Produktion_FFB | 0113PFu0000000619 | m² | Fertigteil | D002 | false | 100 | XC1, WO | C35/45 | HI_GES_FEB-0,220_xxx | Platte | - | no | 0
Stahlbetonfertigteilplatte | EG_Produktion_FFB | BASESLAB | Stahlbetonfertigteil | BP-STB1\ | Stahlbetonfertigteilplatte | EG_Produktion_FFB | 0113PFu0000000621 | m² | Fertigteil | D002 | false | 100 | XC1, WO | C35/45 | HI_GES_FEB-0,220_xxx | Platte | - | no | 0
Stahlbetonfertigteilplatte | EG_Produktion_FFB | BASESLAB | Stahlbetonfertigteil | BP-STB1\ | Stahlbetonfertigteilplatte | EG_Produktion_FFB | 0113PFu0000000623 | m² | Fertigteil | D002 | false | 100 | XC1, WO | C35/45 | HI_GES_FEB-0,220_xxx | Platte | - | no | 0
Stahlbetonfertigteilplatte | EG_Produktion_FFB | BASESLAB | Stahlbetonfertigteil | BP-STB1\ | Stahlbetonfertigteilplatte | EG_Produktion_FFB | 0113PFu0000000625 | m² | Fertigteil | D002 | false | 100 | XC1, WO | C35/45 | HI_GES_FEB-0,220_xxx | Platte | - | no | 0
Stahlbetonfertigteilplatte | EG_Produktion_FFB | BASESLAB | Stahlbetonfertigteil | BP-STB1\ | Stahlbetonfertigteilplatte | EG_Produktion_FFB | 0113PFu0000000627 | m² | Fertigteil | D002 | false | 100 | XC1, WO | C35/45 | HI_GES_FEB-0,220_xxx | Platte | - | no | 0
Stahlbetonfertigteilplatte | EG_Produktion_FFB | BASESLAB | Stahlbetonfertigteil | BP-STB1\ | Stahlbetonfertigteilplatte | EG_Produktion_FFB | 0113PFu0000000631 | m² | Fertigteil | D002 | false | 100 | XC1, WO | C35/45 | HI_GES_FEB-0,220_xxx | Platte | - | no | 0
Stahlbetonfertigteilplatte | EG_Produktion_FFB | BASESLAB | Stahlbetonfertigteil | BP-STB1\ | Stahlbetonfertigteilplatte | EG_Produktion_FFB | 0113PFu0000000633 | m² | Fertigteil | D002 | false | 100 | XC1, WO | C35/45 | HI_GES_FEB-0,220_xxx | Platte | - | no | 0
Stahlbetonfertigteilplatte | EG_Produktion_FFB | BASESLAB | Stahlbetonfertigteil | BP-STB1\ | Stahlbetonfertigteilplatte | EG_Produktion_FFB | 0113PFu0000000635 | m² | Fertigteil | D002 | false | 100 | XC1, WO | C35/45 | HI_GES_FEB-0,220_xxx | Platte | - | no | 0
Stahlbetonfertigteilplatte | EG_Produktion_FFB | BASESLAB | Stahlbetonfertigteil | BP-STB1\ | Stahlbetonfertigteilplatte | EG_Produktion_FFB | 0113PFu0000000637 | m² | Fertigteil | D002 | false | 100 | XC1, WO | C35/45 | HI_GES_FEB-0,220_xxx | Platte | - | no | 0
Stahlbetonfertigteilplatte | EG_Produktion_FFB | BASESLAB | Stahlbetonfertigteil | BP-STB1\ | Stahlbetonfertigteilplatte | EG_Produktion_FFB | 0113PFu0000000639 | m² | Fertigteil | D002 | false | 100 | XC1, WO | C35/45 | HI_GES_FEB-0,220_xxx | Platte | - | no | 0
Stahlbetonfertigteilplatte | EG_Produktion_FFB | BASESLAB | Stahlbetonfertigteil | BP-STB1\ | Stahlbetonfertigteilplatte | EG_Produktion_FFB | 0113PFu0000000641 | m² | Fertigteil | D002 | false | 100 | XC1, WO | C35/45 | HI_GES_FEB-0,220_xxx | Platte | - | no | 0
Stahlbetonfertigteilplatte | EG_Produktion_FFB | BASESLAB | Stahlbetonfertigteil | BP-STB1\ | Stahlbetonfertigteilplatte | EG_Produktion_FFB | 0113PFu0000000643 | m² | Fertigteil | D002 | false | 100 | XC1, WO | C35/45 | HI_GES_FEB-0,220_xxx | Platte | - | no | 0
Stahlbetonfertigteilplatte | EG_Produktion_FFB | BASESLAB | Stahlbetonfertigteil | BP-STB1\ | Stahlbetonfertigteilplatte | EG_Produktion_FFB | 0113PFu0000000645 | m² | Fertigteil | D002 | false | 100 | XC1, WO | C35/45 | HI_GES_FEB-0,220_xxx | Platte | - | no | 0
Stahlbetonfertigteilplatte | EG_Produktion_FFB | BASESLAB | Stahlbetonfertigteil | BP-STB1\ | Stahlbetonfertigteilplatte | EG_Produktion_FFB | 0113PFu0000000647 | m² | Fertigteil | D002 | false | 100 | XC1, WO | C35/45 | HI_GES_FEB-0,220_xxx | Platte | - | no | 0
Stahlbetonfertigteilplatte | EG_Produktion_FFB | BASESLAB | Stahlbetonfertigteil | BP-STB1\ | Stahlbetonfertigteilplatte | EG_Produktion_FFB | 0113PFu0000000669 | m² | Fertigteil | D002 | false | 100 | XC1, WO | C35/45 | HI_GES_FEB-0,220_xxx | Platte | - | no | 0
Stahlbetonfertigteilplatte | EG_Produktion_FFB | BASESLAB | Stahlbetonfertigteil | BP-STB1\ | Stahlbetonfertigteilplatte | EG_Produktion_FFB | 0113PFu0000000671 | m² | Fertigteil | D002 | false | 100 | XC1, WO | C35/45 | HI_GES_FEB-0,220_xxx | Platte | - | no | 0
Stahlbetonfertigteilplatte | EG_Produktion_FFB | BASESLAB | Stahlbetonfertigteil | BP-STB1\ | Stahlbetonfertigteilplatte | EG_Produktion_FFB | 0113PFu0000000705 | m² | Fertigteil | D002 | false | 100 | XC1, WO | C35/45 | HI_GES_FEB-0,220_xxx | Platte | - | no | 0
Stahlbetonfertigteilplatte | EG_Produktion_FFB | BASESLAB | Stahlbetonfertigteil | BP-STB1\ | Stahlbetonfertigteilplatte | EG_Produktion_FFB | 0113PFu0000000707 | m² | Fertigteil | D002 | false | 100 | XC1, WO | C35/45 | HI_GES_FEB-0,220_xxx | Platte | - | no | 0
Stahlbetonfertigteilplatte | EG_Produktion_FFB | BASESLAB | Stahlbetonfertigteil | BP-STB1\ | Stahlbetonfertigteilplatte | EG_Produktion_FFB | 0113PFu0000000717 | m² | Fertigteil | D002 | false | 100 | XC1, WO | C35/45 | HI_GES_FEB-0,220_xxx | Platte | - | no | 0
Stahlbetonfertigteilplatte | EG_Produktion_FFB | BASESLAB | Stahlbetonfertigteil | BP-STB1\ | Stahlbetonfertigteilplatte | EG_Produktion_FFB | 0113PFu0000000737 | m² | Fertigteil | D002 | false | 100 | XC1, WO | C35/45 | HI_GES_FEB-0,220_xxx | Platte | - | no | 0
Stahlbetonfertigteilplatte | EG_Produktion_FFB | BASESLAB | Stahlbetonfertigteil | BP-STB1\ | Stahlbetonfertigteilplatte | EG_Produktion_FFB | 0113PFu0000000739 | m² | Fertigteil | D002 | false | 100 | XC1, WO | C35/45 | HI_GES_FEB-0,220_xxx | Platte | - | no | 0
Stahlbetonfertigteilplatte | EG_Produktion_FFB | BASESLAB | Stahlbetonfertigteil | BP-STB1\ | Stahlbetonfertigteilplatte | EG_Produktion_FFB | 0113PFu0000000755 | m² | Fertigteil | D002 | false | 100 | XC1, WO | C35/45 | HI_GES_FEB-0,220_xxx | Platte | - | no | 0
Stahlbetonfertigteilplatte | EG_Produktion_FFB | BASESLAB | Stahlbetonfertigteil | BP-STB1\ | Stahlbetonfertigteilplatte | EG_Produktion_FFB | 0113PFu0000000757 | m² | Fertigteil | D002 | false | 100 | XC1, WO | C35/45 | HI_GES_FEB-0,220_xxx | Platte | - | no | 0
Stahlbetonfertigteilplatte | EG_Produktion_FFB | BASESLAB | Stahlbetonfertigteil | BP-STB1\ | Stahlbetonfertigteilplatte | EG_Produktion_FFB | 0113PFu0000000759 | m² | Fertigteil | D002 | false | 100 | XC1, WO | C35/45 | HI_GES_FEB-0,220_xxx | Platte | - | no | 0
Stahlbetonfertigteilplatte | EG_Produktion_FFB | BASESLAB | Stahlbetonfertigteil | BP-STB1\ | Stahlbetonfertigteilplatte | EG_Produktion_FFB | 0113PFu0000000761 | m² | Fertigteil | D002 | false | 100 | XC1, WO | C35/45 | HI_GES_FEB-0,220_xxx | Platte | - | no | 0
Stahlbetonfertigteilplatte | EG_Produktion_FFB | BASESLAB | Stahlbetonfertigteil | BP-STB1\ | Stahlbetonfertigteilplatte | EG_Produktion_FFB | 0113PFu0000000773 | m² | Fertigteil | D002 | false | 100 | XC1, WO | C35/45 | HI_GES_FEB-0,220_xxx | Platte | - | no | 0
Stahlbetonfertigteilplatte | EG_Produktion_FFB | BASESLAB | Stahlbetonfertigteil | BP-STB1\ | Stahlbetonfertigteilplatte | EG_Produktion_FFB | 0113PFu0000000775 | m² | Fertigteil | D002 | false | 100 | XC1, WO | C35/45 | HI_GES_FEB-0,220_xxx | Platte | - | no | 0
Stahlbetonfertigteilplatte | EG_Produktion_FFB | BASESLAB | Stahlbetonfertigteil | BP-STB1\ | Stahlbetonfertigteilplatte | EG_Produktion_FFB | 0113PFu0000000777 | m² | Fertigteil | D002 | false | 100 | XC1, WO | C35/45 | HI_GES_FEB-0,220_xxx | Platte | - | no | 0
Stahlbetonfertigteilplatte | EG_Produktion_FFB | BASESLAB | Stahlbetonfertigteil | BP-STB1\ | Stahlbetonfertigteilplatte | EG_Produktion_FFB | 0113PFu0000000779 | m² | Fertigteil | D002 | false | 100 | XC1, WO | C35/45 | HI_GES_FEB-0,220_xxx | Platte | - | no | 0
Stahlbetonfertigteilplatte | EG_Produktion_FFB | BASESLAB | Stahlbetonfertigteil | BP-STB1\ | Stahlbetonfertigteilplatte | EG_Produktion_FFB | 0113PFu0000000781 | m² | Fertigteil | D002 | false | 100 | XC1, WO | C35/45 | HI_GES_FEB-0,220_xxx | Platte | - | no | 0
Stahlbetonfertigteilplatte | EG_Produktion_FFB | BASESLAB | Stahlbetonfertigteil | BP-STB1\ | Stahlbetonfertigteilplatte | EG_Produktion_FFB | 0113PFu0000000783 | m² | Fertigteil | D002 | false | 100 | XC1, WO | C35/45 | HI_GES_FEB-0,220_xxx | Platte | - | no | 0
Stahlbetonfertigteilplatte | EG_Produktion_FFB | BASESLAB | Stahlbetonfertigteil | BP-STB1\ | Stahlbetonfertigteilplatte | EG_Produktion_FFB | 0113PFu0000000785 | m² | Fertigteil | D002 | false | 100 | XC1, WO | C35/45 | HI_GES_FEB-0,220_xxx | Platte | - | no | 0
Stahlbetonfertigteilplatte | EG_Produktion_FFB | BASESLAB | Stahlbetonfertigteil | BP-STB1\ | Stahlbetonfertigteilplatte | EG_Produktion_FFB | 0113PFu0000000787 | m² | Fertigteil | D002 | false | 100 | XC1, WO | C35/45 | HI_GES_FEB-0,220_xxx | Platte | - | no | 0
Stahlbetonfertigteilplatte | EG_Produktion_FFB | BASESLAB | Stahlbetonfertigteil | BP-STB1\ | Stahlbetonfertigteilplatte | EG_Produktion_FFB | 0113PFu0000000651 | m² | Fertigteil | D002 | false | 100 | XC1, WO | C35/45 | HI_GES_FEB-0,220_xxx | Platte | - | no | 0
Stahlbetonfertigteilplatte | EG_Produktion_FFB | BASESLAB | Stahlbetonfertigteil | BP-STB1\ | Stahlbetonfertigteilplatte | EG_Produktion_FFB | 0113PFu0000000065 | m² | Fertigteil | D002 | false | 100 | XC1, WO | C35/45 | HI_GES_FEB-0,220_xxx | Platte | - | no | 0
Stahlbetonfertigteilplatte | EG_Produktion_FFB | BASESLAB | Stahlbetonfertigteil | BP-STB1\ | Stahlbetonfertigteilplatte | EG_Produktion_FFB | 0113PFu0000000019 | m² | Fertigteil | D002 | false | 100 | XC1, WO | C35/45 | HI_GES_FEB-0,220_xxx | Platte | - | no | 0
Stahlbetonfertigteilplatte | EG_Produktion_FFB | BASESLAB | Stahlbetonfertigteil | BP-STB1\ | Stahlbetonfertigteilplatte | EG_Produktion_FFB | 0113PFu0000000017 | m² | Fertigteil | D002 | false | 100 | XC1, WO | C35/45 | HI_GES_FEB-0,220_xxx | Platte | - | no | 0
Stahlbetonfertigteilplatte | EG_Produktion_FFB | BASESLAB | Stahlbetonfertigteil | BP-STB1\ | Stahlbetonfertigteilplatte | EG_Produktion_FFB | 0113PFu0000000561 | m² | Fertigteil | D002 | false | 100 | XC1, WO | C35/45 | HI_GES_FEB-0,220_xxx | Platte | - | no | 0
Stahlbetonfertigteilplatte | EG_Produktion_FFB | BASESLAB | Stahlbetonfertigteil | BP-STB1\ | Stahlbetonfertigteilplatte | EG_Produktion_FFB | 0113PFu0000000091 | m² | Fertigteil | D002 | false | 100 | XC1, WO | C35/45 | HI_GES_FEB-0,220_xxx | Platte | - | no | 0
Stahlbetonfertigteilplatte | EG_Produktion_FFB | BASESLAB | Stahlbetonfertigteil | BP-STB1\ | Stahlbetonfertigteilplatte | EG_Produktion_FFB | 0113PFu0000000443 | m² | Fertigteil | D002 | false | 100 | XC1, WO | C35/45 | HI_GES_FEB-0,220_xxx | Platte | - | no | 0
Stahlbetonfertigteilplatte | EG_Produktion_FFB | BASESLAB | Stahlbetonfertigteil | BP-STB1\ | Stahlbetonfertigteilplatte | EG_Produktion_FFB | 0113PFu0000000081 | m² | Fertigteil | D002 | false | 100 | XC1, WO | C35/45 | HI_GES_FEB-0,220_xxx | Platte | - | no | 0
Stahlbetonfertigteilplatte | EG_Produktion_FFB | BASESLAB | Stahlbetonfertigteil | BP-STB1\ | Stahlbetonfertigteilplatte | EG_Produktion_FFB | 0113PFu0000000171 | m² | Fertigteil | D002 | false | 100 | XC1, WO | C35/45 | HI_GES_FEB-0,220_xxx | Platte | - | no | 0
Stahlbetonfertigteilplatte | EG_Produktion_FFB | BASESLAB | Stahlbetonfertigteil | BP-STB1\ | Stahlbetonfertigteilplatte | EG_Produktion_FFB | 0113PFu0000000219 | m² | Fertigteil | D002 | false | 100 | XC1, WO | C35/45 | HI_GES_FEB-0,220_xxx | Platte | - | no | 0
Stahlbetonfertigteilplatte | EG_Produktion_FFB | BASESLAB | Stahlbetonfertigteil | BP-STB1\ | Stahlbetonfertigteilplatte | EG_Produktion_FFB | 0113PFu0000000217 | m² | Fertigteil | D002 | false | 100 | XC1, WO | C35/45 | HI_GES_FEB-0,220_xxx | Platte | - | no | 0
Stahlbetonfertigteilplatte | EG_Produktion_FFB | BASESLAB | Stahlbetonfertigteil | BP-STB1\ | Stahlbetonfertigteilplatte | EG_Produktion_FFB | 0113PFu0000006001 | m² | Fertigteil | D002 | false | 100 | XC1, WO | C35/45 | HI_GES_FEB-0,220_xxx | Platte | - | no | 0
Stahlbetonfertigteilplatte | EG_Produktion_FFB | BASESLAB | Stahlbetonfertigteil | BP-STB1\ | Stahlbetonfertigteilplatte | EG_Produktion_FFB | 0113PFu0000000543 | m² | Fertigteil | D002 | false | 100 | XC1, WO | C35/45 | HI_GES_FEB-0,220_xxx | Platte | - | no | 0
Stahlbetonfertigteilplatte | EG_Produktion_FFB | BASESLAB | Stahlbetonfertigteil | BP-STB1\ | Stahlbetonfertigteilplatte | EG_Produktion_FFB | 0113PFu0000000503 | m² | Fertigteil | D002 | false | 100 | XC1, WO | C35/45 | HI_GES_FEB-0,220_xxx | Platte | - | no | 0
Stahlbetonfertigteilplatte | EG_Produktion_FFB | BASESLAB | Stahlbetonfertigteil | BP-STB1\ | Stahlbetonfertigteilplatte | EG_Produktion_FFB | 0113PFu0000006031 | m² | Fertigteil | D002 | false | 100 | XC1, WO | C35/45 | HI_GES_FEB-0,220_xxx | Platte | - | no | 0
Stahlbetonfertigteilplatte | EG_Produktion_FFB | BASESLAB | Stahlbetonfertigteil | BP-STB1\ | Stahlbetonfertigteilplatte | EG_Produktion_FFB | 0113PFu0000000049 | m² | Fertigteil | D002 | false | 100 | XC1, WO | C35/45 | HI_GES_FEB-0,220_xxx | Platte | - | no | 0
Stahlbetonfertigteilplatte | EG_Produktion_FFB | BASESLAB | Stahlbetonfertigteil | BP-STB1\ | Stahlbetonfertigteilplatte | EG_Produktion_FFB | 0113PFu0000000051 | m² | Fertigteil | D002 | false | 100 | XC1, WO | C35/45 | HI_GES_FEB-0,220_xxx | Platte | - | no | 0
Stahlbetonfertigteilplatte | EG_Produktion_FFB | BASESLAB | Stahlbetonfertigteil | BP-STB1\ | Stahlbetonfertigteilplatte | EG_Produktion_FFB | 0113PFu0000005951 | m² | Fertigteil | D002 | false | 100 | XC1, WO | C35/45 | HI_GES_FEB-0,220_xxx | Platte | - | no | 0
Stahlbetonfertigteilplatte | EG_Produktion_FFB | BASESLAB | Stahlbetonfertigteil | BP-STB1\ | Stahlbetonfertigteilplatte | EG_Produktion_FFB | 0113PFu0000000629 | m² | Fertigteil | D002 | false | 100 | XC1, WO | C35/45 | HI_GES_FEB-0,220_xxx | Platte | - | no | 0
Stahlbetonfertigteilplatte | EG_Produktion_FFB | BASESLAB | Stahlbetonfertigteil | BP-STB1\ | Stahlbetonfertigteilplatte | EG_Produktion_FFB | 0113PFu0000005449 | m² | Fertigteil | D002 | false | 100 | XC1, WO | C35/45 | HI_GES_FEB-0,220_xxx | Platte | - | no | 0
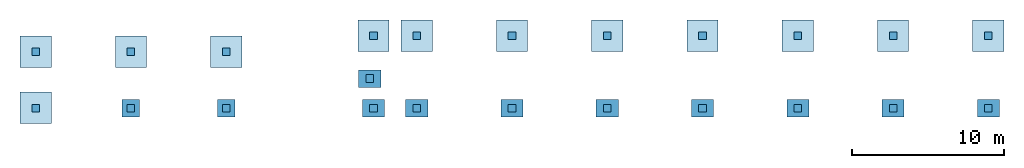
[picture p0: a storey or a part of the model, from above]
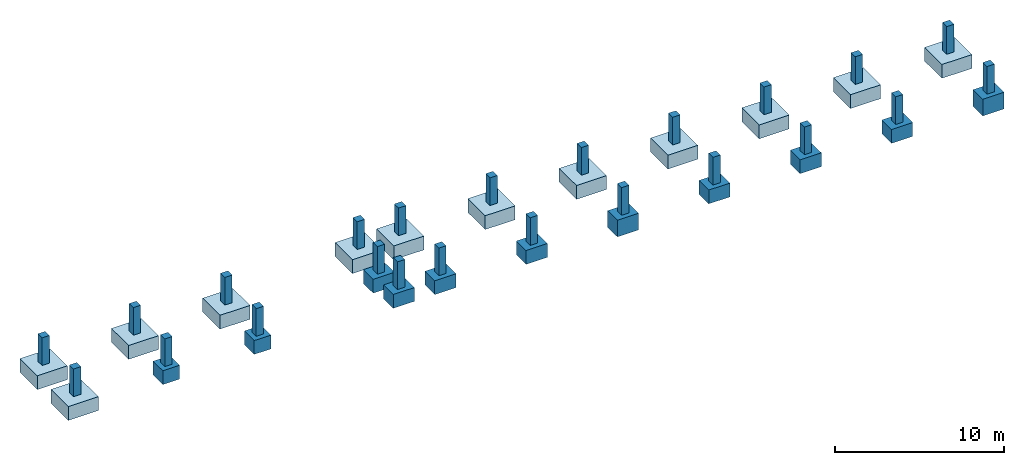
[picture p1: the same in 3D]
Properties of the parts of a building model (IFC2X3), part 24 of 25

# IfcSlab (564)
Name | In | PredefinedType | Material = AllplanAttributes, Material | Codetext | Bezeichnung = Name | Ebene | Allright_Bauteil_ID | Abrechnungsart | Herstellung | Positionsnummer | Außenbauteil | Bewehrungsgrad | Expositionsklasse | Druckfestigkeitsklasse | Reference | Attributset-Objekt | FireRating | Combustible = Compartmentation | PitchAngle (deg)
Stahlbetonfertigteilplatte | EG_Produktion_FFB | BASESLAB | Stahlbetonfertigteil | BP-STB1\ | Stahlbetonfertigteilplatte | EG_Produktion_FFB | 0113PFu0000000271 | m² | Fertigteil | D002 | false | 100 | XC1, WO | C35/45 | HI_GES_FEB-0,220_xxx | Platte | - | no | 0
Stahlbetonfertigteilplatte | EG_Produktion_FFB | BASESLAB | Stahlbetonfertigteil | BP-STB1\ | Stahlbetonfertigteilplatte | EG_Produktion_FFB | 0113PFu0000000275 | m² | Fertigteil | D002 | false | 100 | XC1, WO | C35/45 | HI_GES_FEB-0,220_xxx | Platte | - | no | 0
Stahlbetonfertigteilplatte | EG_Produktion_FFB | BASESLAB | Stahlbetonfertigteil | BP-STB1\ | Stahlbetonfertigteilplatte | EG_Produktion_FFB | 0113PFu0000000277 | m² | Fertigteil | D002 | false | 100 | XC1, WO | C35/45 | HI_GES_FEB-0,220_xxx | Platte | - | no | 0
Stahlbetonfertigteilplatte | EG_Produktion_FFB | BASESLAB | Stahlbetonfertigteil | BP-STB1\ | Stahlbetonfertigteilplatte | EG_Produktion_FFB | 0113PFu0000000699 | m² | Fertigteil | D002 | false | 100 | XC1, WO | C35/45 | HI_GES_FEB-0,220_xxx | Platte | - | no | 0
Stahlbetonfertigteilplatte | EG_Produktion_FFB | BASESLAB | Stahlbetonfertigteil | BP-STB1\ | Stahlbetonfertigteilplatte | EG_Produktion_FFB | 0113PFu0000000697 | m² | Fertigteil | D002 | false | 100 | XC1, WO | C35/45 | HI_GES_FEB-0,220_xxx | Platte | - | no | 0
Stahlbetonfertigteilplatte | EG_Produktion_FFB | BASESLAB | Stahlbetonfertigteil | BP-STB1\ | Stahlbetonfertigteilplatte | EG_Produktion_FFB | 0113PFu0000000233 | m² | Fertigteil | D002 | false | 100 | XC1, WO | C35/45 | HI_GES_FEB-0,220_xxx | Platte | - | no | 0
Stahlbetonfertigteilplatte | EG_Produktion_FFB | BASESLAB | Stahlbetonfertigteil | BP-STB1\ | Stahlbetonfertigteilplatte | EG_Produktion_FFB | 0113PFu0000000011 | m² | Fertigteil | D002 | false | 100 | XC1, WO | C35/45 | HI_GES_FEB-0,220_xxx | Platte | - | no | 0
Stahlbetonfertigteilplatte | EG_Produktion_FFB | BASESLAB | Stahlbetonfertigteil | BP-STB1\ | Stahlbetonfertigteilplatte | EG_Produktion_FFB | 0113PFu0000000097 | m² | Fertigteil | D002 | false | 100 | XC1, WO | C35/45 | HI_GES_FEB-0,220_xxx | Platte | - | no | 0
Stahlbetonfertigteilplatte | EG_Produktion_FFB | BASESLAB | Stahlbetonfertigteil | BP-STB1\ | Stahlbetonfertigteilplatte | EG_Produktion_FFB | 0113PFu0000000099 | m² | Fertigteil | D002 | false | 100 | XC1, WO | C35/45 | HI_GES_FEB-0,220_xxx | Platte | - | no | 0
Stahlbetonfertigteilplatte | EG_Produktion_FFB | BASESLAB | Stahlbetonfertigteil | BP-STB1\ | Stahlbetonfertigteilplatte | EG_Produktion_FFB | 0113PFu0000000105 | m² | Fertigteil | D002 | false | 100 | XC1, WO | C35/45 | HI_GES_FEB-0,220_xxx | Platte | - | no | 0
Stahlbetonfertigteilplatte | EG_Produktion_FFB | BASESLAB | Stahlbetonfertigteil | BP-STB1\ | Stahlbetonfertigteilplatte | EG_Produktion_FFB | 0113PFu0000000113 | m² | Fertigteil | D002 | false | 100 | XC1, WO | C35/45 | HI_GES_FEB-0,220_xxx | Platte | - | no | 0
Stahlbetonfertigteilplatte | EG_Produktion_FFB | BASESLAB | Stahlbetonfertigteil | BP-STB1\ | Stahlbetonfertigteilplatte | EG_Produktion_FFB | 0113PFu0000000115 | m² | Fertigteil | D002 | false | 100 | XC1, WO | C35/45 | HI_GES_FEB-0,220_xxx | Platte | - | no | 0
Stahlbetonfertigteilplatte | EG_Produktion_FFB | BASESLAB | Stahlbetonfertigteil | BP-STB1\ | Stahlbetonfertigteilplatte | EG_Produktion_FFB | 0113PFu0000000117 | m² | Fertigteil | D002 | false | 100 | XC1, WO | C35/45 | HI_GES_FEB-0,220_xxx | Platte | - | no | 0
Stahlbetonfertigteilplatte | EG_Produktion_FFB | BASESLAB | Stahlbetonfertigteil | BP-STB1\ | Stahlbetonfertigteilplatte | EG_Produktion_FFB | 0113PFu0000000121 | m² | Fertigteil | D002 | false | 100 | XC1, WO | C35/45 | HI_GES_FEB-0,220_xxx | Platte | - | no | 0
Stahlbetonfertigteilplatte | EG_Produktion_FFB | BASESLAB | Stahlbetonfertigteil | BP-STB1\ | Stahlbetonfertigteilplatte | EG_Produktion_FFB | 0113PFu0000000123 | m² | Fertigteil | D002 | false | 100 | XC1, WO | C35/45 | HI_GES_FEB-0,220_xxx | Platte | - | no | 0
Stahlbetonfertigteilplatte | EG_Produktion_FFB | BASESLAB | Stahlbetonfertigteil | BP-STB1\ | Stahlbetonfertigteilplatte | EG_Produktion_FFB | 0113PFu0000000125 | m² | Fertigteil | D002 | false | 100 | XC1, WO | C35/45 | HI_GES_FEB-0,220_xxx | Platte | - | no | 0
Stahlbetonfertigteilplatte | EG_Produktion_FFB | BASESLAB | Stahlbetonfertigteil | BP-STB1\ | Stahlbetonfertigteilplatte | EG_Produktion_FFB | 0113PFu0000000127 | m² | Fertigteil | D002 | false | 100 | XC1, WO | C35/45 | HI_GES_FEB-0,220_xxx | Platte | - | no | 0
Stahlbetonfertigteilplatte | EG_Produktion_FFB | BASESLAB | Stahlbetonfertigteil | BP-STB1\ | Stahlbetonfertigteilplatte | EG_Produktion_FFB | 0113PFu0000000129 | m² | Fertigteil | D002 | false | 100 | XC1, WO | C35/45 | HI_GES_FEB-0,220_xxx | Platte | - | no | 0
Stahlbetonfertigteilplatte | EG_Produktion_FFB | BASESLAB | Stahlbetonfertigteil | BP-STB1\ | Stahlbetonfertigteilplatte | EG_Produktion_FFB | 0113PFu0000000131 | m² | Fertigteil | D002 | false | 100 | XC1, WO | C35/45 | HI_GES_FEB-0,220_xxx | Platte | - | no | 0
Stahlbetonfertigteilplatte | EG_Produktion_FFB | BASESLAB | Stahlbetonfertigteil | BP-STB1\ | Stahlbetonfertigteilplatte | EG_Produktion_FFB | 0113PFu0000000135 | m² | Fertigteil | D002 | false | 100 | XC1, WO | C35/45 | HI_GES_FEB-0,220_xxx | Platte | - | no | 0
Stahlbetonfertigteilplatte | EG_Produktion_FFB | BASESLAB | Stahlbetonfertigteil | BP-STB1\ | Stahlbetonfertigteilplatte | EG_Produktion_FFB | 0113PFu0000000139 | m² | Fertigteil | D002 | false | 100 | XC1, WO | C35/45 | HI_GES_FEB-0,220_xxx | Platte | - | no | 0
Stahlbetonfertigteilplatte | EG_Produktion_FFB | BASESLAB | Stahlbetonfertigteil | BP-STB1\ | Stahlbetonfertigteilplatte | EG_Produktion_FFB | 0113PFu0000000145 | m² | Fertigteil | D002 | false | 100 | XC1, WO | C35/45 | HI_GES_FEB-0,220_xxx | Platte | - | no | 0
Stahlbetonfertigteilplatte | EG_Produktion_FFB | BASESLAB | Stahlbetonfertigteil | BP-STB1\ | Stahlbetonfertigteilplatte | EG_Produktion_FFB | 0113PFu0000000161 | m² | Fertigteil | D002 | false | 100 | XC1, WO | C35/45 | HI_GES_FEB-0,220_xxx | Platte | - | no | 0
Stahlbetonfertigteilplatte | EG_Produktion_FFB | BASESLAB | Stahlbetonfertigteil | BP-STB1\ | Stahlbetonfertigteilplatte | EG_Produktion_FFB | 0113PFu0000000163 | m² | Fertigteil | D002 | false | 100 | XC1, WO | C35/45 | HI_GES_FEB-0,220_xxx | Platte | - | no | 0
Stahlbetonfertigteilplatte | EG_Produktion_FFB | BASESLAB | Stahlbetonfertigteil | BP-STB1\ | Stahlbetonfertigteilplatte | EG_Produktion_FFB | 0113PFu0000000355 | m² | Fertigteil | D002 | false | 100 | XC1, WO | C35/45 | HI_GES_FEB-0,220_xxx | Platte | - | no | 0
Stahlbetonfertigteilplatte | EG_Produktion_FFB | BASESLAB | Stahlbetonfertigteil | BP-STB1\ | Stahlbetonfertigteilplatte | EG_Produktion_FFB | 0113PFu0000000463 | m² | Fertigteil | D002 | false | 100 | XC1, WO | C35/45 | HI_GES_FEB-0,220_xxx | Platte | - | no | 0
Stahlbetonfertigteilplatte | EG_Produktion_FFB | BASESLAB | Stahlbetonfertigteil | BP-STB1\ | Stahlbetonfertigteilplatte | EG_Produktion_FFB | 0113PFu0000000581 | m² | Fertigteil | D002 | false | 100 | XC1, WO | C35/45 | HI_GES_FEB-0,220_xxx | Platte | - | no | 0
Stahlbetonfertigteilplatte | EG_Produktion_FFB | BASESLAB | Stahlbetonfertigteil | BP-STB1\ | Stahlbetonfertigteilplatte | EG_Produktion_FFB | 0113PFu0000000583 | m² | Fertigteil | D002 | false | 100 | XC1, WO | C35/45 | HI_GES_FEB-0,220_xxx | Platte | - | no | 0
Stahlbetonfertigteilplatte | EG_Produktion_FFB | BASESLAB | Stahlbetonfertigteil | BP-STB1\ | Stahlbetonfertigteilplatte | EG_Produktion_FFB | 0113PFu0000000585 | m² | Fertigteil | D002 | false | 100 | XC1, WO | C35/45 | HI_GES_FEB-0,220_xxx | Platte | - | no | 0
Stahlbetonfertigteilplatte | EG_Produktion_FFB | BASESLAB | Stahlbetonfertigteil | BP-STB1\ | Stahlbetonfertigteilplatte | EG_Produktion_FFB | 0113PFu0000000587 | m² | Fertigteil | D002 | false | 100 | XC1, WO | C35/45 | HI_GES_FEB-0,220_xxx | Platte | - | no | 0
Stahlbetonfertigteilplatte | EG_Produktion_FFB | BASESLAB | Stahlbetonfertigteil | BP-STB1\ | Stahlbetonfertigteilplatte | EG_Produktion_FFB | 0113PFu0000000589 | m² | Fertigteil | D002 | false | 100 | XC1, WO | C35/45 | HI_GES_FEB-0,220_xxx | Platte | - | no | 0
Stahlbetonfertigteilplatte | EG_Produktion_FFB | BASESLAB | Stahlbetonfertigteil | BP-STB1\ | Stahlbetonfertigteilplatte | EG_Produktion_FFB | 0113PFu0000000591 | m² | Fertigteil | D002 | false | 100 | XC1, WO | C35/45 | HI_GES_FEB-0,220_xxx | Platte | - | no | 0
Stahlbetonfertigteilplatte | EG_Produktion_FFB | BASESLAB | Stahlbetonfertigteil | BP-STB1\ | Stahlbetonfertigteilplatte | EG_Produktion_FFB | 0113PFu0000000593 | m² | Fertigteil | D002 | false | 100 | XC1, WO | C35/45 | HI_GES_FEB-0,220_xxx | Platte | - | no | 0
Stahlbetonfertigteilplatte | EG_Produktion_FFB | BASESLAB | Stahlbetonfertigteil | BP-STB1\ | Stahlbetonfertigteilplatte | EG_Produktion_FFB | 0113PFu0000000595 | m² | Fertigteil | D002 | false | 100 | XC1, WO | C35/45 | HI_GES_FEB-0,220_xxx | Platte | - | no | 0
Stahlbetonfertigteilplatte | EG_Produktion_FFB | BASESLAB | Stahlbetonfertigteil | BP-STB1\ | Stahlbetonfertigteilplatte | EG_Produktion_FFB | 0113PFu0000000597 | m² | Fertigteil | D002 | false | 100 | XC1, WO | C35/45 | HI_GES_FEB-0,220_xxx | Platte | - | no | 0
Stahlbetonfertigteilplatte | EG_Produktion_FFB | BASESLAB | Stahlbetonfertigteil | BP-STB1\ | Stahlbetonfertigteilplatte | EG_Produktion_FFB | 0113PFu0000000599 | m² | Fertigteil | D002 | false | 100 | XC1, WO | C35/45 | HI_GES_FEB-0,220_xxx | Platte | - | no | 0
Stahlbetonfertigteilplatte | EG_Produktion_FFB | BASESLAB | Stahlbetonfertigteil | BP-STB1\ | Stahlbetonfertigteilplatte | EG_Produktion_FFB | 0113PFu0000000601 | m² | Fertigteil | D002 | false | 100 | XC1, WO | C35/45 | HI_GES_FEB-0,220_xxx | Platte | - | no | 0
Stahlbetonfertigteilplatte | EG_Produktion_FFB | BASESLAB | Stahlbetonfertigteil | BP-STB1\ | Stahlbetonfertigteilplatte | EG_Produktion_FFB | 0113PFu0000000603 | m² | Fertigteil | D002 | false | 100 | XC1, WO | C35/45 | HI_GES_FEB-0,220_xxx | Platte | - | no | 0
Stahlbetonfertigteilplatte | EG_Produktion_FFB | BASESLAB | Stahlbetonfertigteil | BP-STB1\ | Stahlbetonfertigteilplatte | EG_Produktion_FFB | 0113PFu0000000605 | m² | Fertigteil | D002 | false | 100 | XC1, WO | C35/45 | HI_GES_FEB-0,220_xxx | Platte | - | no | 0
Stahlbetonfertigteilplatte | EG_Produktion_FFB | BASESLAB | Stahlbetonfertigteil | BP-STB1\ | Stahlbetonfertigteilplatte | EG_Produktion_FFB | 0113PFu0000000607 | m² | Fertigteil | D002 | false | 100 | XC1, WO | C35/45 | HI_GES_FEB-0,220_xxx | Platte | - | no | 0
Stahlbetonfertigteilplatte | EG_Produktion_FFB | BASESLAB | Stahlbetonfertigteil | BP-STB1\ | Stahlbetonfertigteilplatte | EG_Produktion_FFB | 0113PFu0000000611 | m² | Fertigteil | D002 | false | 100 | XC1, WO | C35/45 | HI_GES_FEB-0,220_xxx | Platte | - | no | 0
Stahlbetonfertigteilplatte | EG_Produktion_FFB | BASESLAB | Stahlbetonfertigteil | BP-STB1\ | Stahlbetonfertigteilplatte | EG_Produktion_FFB | 0113PFu0000000765 | m² | Fertigteil | D002 | false | 100 | XC1, WO | C35/45 | HI_GES_FEB-0,220_xxx | Platte | - | no | 0
Stahlbetonfertigteilplatte | EG_Produktion_FFB | BASESLAB | Stahlbetonfertigteil | BP-STB1\ | Stahlbetonfertigteilplatte | EG_Produktion_FFB | 0113PFu0000000767 | m² | Fertigteil | D002 | false | 100 | XC1, WO | C35/45 | HI_GES_FEB-0,220_xxx | Platte | - | no | 0
Stahlbetonfertigteilplatte | EG_Produktion_FFB | BASESLAB | Stahlbetonfertigteil | BP-STB1\ | Stahlbetonfertigteilplatte | EG_Produktion_FFB | 0113PFu0000000769 | m² | Fertigteil | D002 | false | 100 | XC1, WO | C35/45 | HI_GES_FEB-0,220_xxx | Platte | - | no | 0
Stahlbetonfertigteilplatte | EG_Produktion_FFB | BASESLAB | Stahlbetonfertigteil | BP-STB1\ | Stahlbetonfertigteilplatte | EG_Produktion_FFB | 0113PFu0000000771 | m² | Fertigteil | D002 | false | 100 | XC1, WO | C35/45 | HI_GES_FEB-0,220_xxx | Platte | - | no | 0
Stahlbetonfertigteilplatte | EG_Produktion_FFB | BASESLAB | Stahlbetonfertigteil | BP-STB1\ | Stahlbetonfertigteilplatte | EG_Produktion_FFB | 0113PFu0000000609 | m² | Fertigteil | D002 | false | 100 | XC1, WO | C35/45 | HI_GES_FEB-0,220_xxx | Platte | - | no | 0
Stahlbetonfertigteilplatte | EG_Produktion_FFB | BASESLAB | Stahlbetonfertigteil | BP-STB1\ | Stahlbetonfertigteilplatte | EG_Produktion_FFB | 0113PFu0000000103 | m² | Fertigteil | D002 | false | 100 | XC1, WO | C35/45 | HI_GES_FEB-0,220_xxx | Platte | - | no | 0
Stahlbetonfertigteilplatte | EG_Produktion_FFB | BASESLAB | Stahlbetonfertigteil | BP-STB1\ | Stahlbetonfertigteilplatte | EG_Produktion_FFB | 0113PFu0000000101 | m² | Fertigteil | D002 | false | 100 | XC1, WO | C35/45 | HI_GES_FEB-0,220_xxx | Platte | - | no | 0
Stahlbetonfertigteilplatte | EG_Produktion_FFB | BASESLAB | Stahlbetonfertigteil | BP-STB1\ | Stahlbetonfertigteilplatte | EG_Produktion_FFB | 0113PFu0000000763 | m² | Fertigteil | D002 | false | 100 | XC1, WO | C35/45 | HI_GES_FEB-0,220_xxx | Platte | - | no | 0
Stahlbetonfertigteilplatte | EG_Produktion_FFB | BASESLAB | Stahlbetonfertigteil | BP-STB1\ | Stahlbetonfertigteilplatte | EG_Produktion_FFB | 0113PFu0000000109 | m² | Fertigteil | D002 | false | 100 | XC1, WO | C35/45 | HI_GES_FEB-0,220_xxx | Platte | - | no | 0
Stahlbetonfertigteilplatte | EG_Produktion_FFB | BASESLAB | Stahlbetonfertigteil | BP-STB1\ | Stahlbetonfertigteilplatte | EG_Produktion_FFB | 0113PFu0000000143 | m² | Fertigteil | D002 | false | 100 | XC1, WO | C35/45 | HI_GES_FEB-0,220_xxx | Platte | - | no | 0
Stahlbetonfertigteilplatte | EG_Produktion_FFB | BASESLAB | Stahlbetonfertigteil | BP-STB1\ | Stahlbetonfertigteilplatte | EG_Produktion_FFB | 0113PFu0000000119 | m² | Fertigteil | D002 | false | 100 | XC1, WO | C35/45 | HI_GES_FEB-0,220_xxx | Platte | - | no | 0
Stahlbetonfertigteilplatte | EG_Produktion_FFB | BASESLAB | Stahlbetonfertigteil | BP-STB1\ | Stahlbetonfertigteilplatte | EG_Produktion_FFB | 0113PFu0000005505 | m² | Fertigteil | D002 | false | 100 | XC1, WO | C35/45 | HI_GES_FEB-0,220_xxx | Platte | - | no | 0
Stahlbetonfertigteilplatte | EG_Produktion_FFB | BASESLAB | Stahlbetonfertigteil | BP-STB1\ | Stahlbetonfertigteilplatte | EG_Produktion_FFB | 0113PFu0000000133 | m² | Fertigteil | D002 | false | 100 | XC1, WO | C35/45 | HI_GES_FEB-0,220_xxx | Platte | - | no | 0
Stahlbetonfertigteilplatte | EG_Produktion_FFB | BASESLAB | Stahlbetonfertigteil | BP-STB1\ | Stahlbetonfertigteilplatte | EG_Produktion_FFB | 0113PFu0000000157 | m² | Fertigteil | D002 | false | 100 | XC1, WO | C35/45 | HI_GES_FEB-0,220_xxx | Platte | - | no | 0
Stahlbetonfertigteilplatte | EG_Produktion_FFB | BASESLAB | Stahlbetonfertigteil | BP-STB1\ | Stahlbetonfertigteilplatte | EG_Produktion_FFB | 0113PFu0000005594 | m² | Fertigteil | D002 | false | 100 | XC1, WO | C35/45 | HI_GES_FEB-0,220_xxx | Platte | - | no | 0
Stahlbetonfertigteilplatte | EG_Produktion_FFB | BASESLAB | Stahlbetonfertigteil | BP-STB1\ | Stahlbetonfertigteilplatte | EG_Produktion_FFB | 0113PFu0000007698 | m² | Fertigteil | D002 | false | 100 | XC1, WO | C35/45 | HI_GES_FEB-0,220_xxx | Platte | - | no | 0
Stahlbetonfertigteilplatte | EG_Produktion_FFB | BASESLAB | Stahlbetonfertigteil | BP-STB1\ | Stahlbetonfertigteilplatte | EG_Produktion_FFB | 0113PFu0000000159 | m² | Fertigteil | D002 | false | 100 | XC1, WO | C35/45 | HI_GES_FEB-0,220_xxx | Platte | - | no | 0
Stahlbetonfertigteilplatte | EG_Produktion_FFB | BASESLAB | Stahlbetonfertigteil | BP-STB1\ | Stahlbetonfertigteilplatte | EG_Produktion_FFB | 0113PFu0000005475 | m² | Fertigteil | D002 | false | 100 | XC1, WO | C35/45 | HI_GES_FEB-0,220_xxx | Platte | - | no | 0
Stahlbetonfertigteilplatte | EG_Produktion_FFB | BASESLAB | Stahlbetonfertigteil | BP-STB1\ | Stahlbetonfertigteilplatte | EG_Produktion_FFB | 0113PFu0000000149 | m² | Fertigteil | D002 | false | 100 | XC1, WO | C35/45 | HI_GES_FEB-0,220_xxx | Platte | - | no | 0
Stahlbetonfertigteilplatte | EG_Produktion_FFB | BASESLAB | Stahlbetonfertigteil | BP-STB1\ | Stahlbetonfertigteilplatte | EG_Produktion_FFB | 0113PFu0000000273 | m² | Fertigteil | D002 | false | 100 | XC1, WO | C35/45 | HI_GES_FEB-0,220_xxx | Platte | - | no | 0
Stahlbetonfertigteilplatte | EG_Produktion_FFB | BASESLAB | Stahlbetonfertigteil | BP-STB1\ | Stahlbetonfertigteilplatte | EG_Produktion_FFB | 0113PFu0000000067 | m² | Fertigteil | D002 | false | 100 | XC1, WO | C35/45 | HI_GES_FEB-0,220_xxx | Platte | - | no | 0
Stahlbetonfertigteilplatte | EG_Produktion_FFB | BASESLAB | Stahlbetonfertigteil | BP-STB1\ | Stahlbetonfertigteilplatte | EG_Produktion_FFB | 0113PFu0000000169 | m² | Fertigteil | D002 | false | 100 | XC1, WO | C35/45 | HI_GES_FEB-0,220_xxx | Platte | - | no | 0
Stahlbetonfertigteilplatte | EG_Produktion_FFB | BASESLAB | Stahlbetonfertigteil | BP-STB1\ | Stahlbetonfertigteilplatte | EG_Produktion_FFB | 0113PFu0000005676 | m² | Fertigteil | D002 | false | 100 | XC1, WO | C35/45 | HI_GES_FEB-0,220_xxx | Platte | - | no | 0
Stahlbetonfertigteilplatte | EG_Produktion_FFB | BASESLAB | Stahlbetonfertigteil | BP-STB1\ | Stahlbetonfertigteilplatte | EG_Produktion_FFB | 0113PFu0000000073 | m² | Fertigteil | D002 | false | 100 | XC1, WO | C35/45 | HI_GES_FEB-0,220_xxx | Platte | - | no | 0
Stahlbetonfertigteilplatte | EG_Produktion_FFB | BASESLAB | Stahlbetonfertigteil | BP-STB1\ | Stahlbetonfertigteilplatte | EG_Produktion_FFB | 0113PFu0000000075 | m² | Fertigteil | D002 | false | 100 | XC1, WO | C35/45 | HI_GES_FEB-0,220_xxx | Platte | - | no | 0
Stahlbetonfertigteilplatte | EG_Produktion_FFB | BASESLAB | Stahlbetonfertigteil | BP-STB1\ | Stahlbetonfertigteilplatte | EG_Produktion_FFB | 0113PFu0000000079 | m² | Fertigteil | D002 | false | 100 | XC1, WO | C35/45 | HI_GES_FEB-0,220_xxx | Platte | - | no | 0
Stahlbetonfertigteilplatte | EG_Produktion_FFB | BASESLAB | Stahlbetonfertigteil | BP-STB1\ | Stahlbetonfertigteilplatte | EG_Produktion_FFB | 0113PFu0000000087 | m² | Fertigteil | D002 | false | 100 | XC1, WO | C35/45 | HI_GES_FEB-0,220_xxx | Platte | - | no | 0
Stahlbetonfertigteilplatte | EG_Produktion_FFB | BASESLAB | Stahlbetonfertigteil | BP-STB1\ | Stahlbetonfertigteilplatte | EG_Produktion_FFB | 0113PFu0000000173 | m² | Fertigteil | D002 | false | 100 | XC1, WO | C35/45 | HI_GES_FEB-0,220_xxx | Platte | - | no | 0
Stahlbetonfertigteilplatte | EG_Produktion_FFB | BASESLAB | Stahlbetonfertigteil | BP-STB1\ | Stahlbetonfertigteilplatte | EG_Produktion_FFB | 0113PFu0000000179 | m² | Fertigteil | D002 | false | 100 | XC1, WO | C35/45 | HI_GES_FEB-0,220_xxx | Platte | - | no | 0
Stahlbetonfertigteilplatte | EG_Produktion_FFB | BASESLAB | Stahlbetonfertigteil | BP-STB1\ | Stahlbetonfertigteilplatte | EG_Produktion_FFB | 0113PFu0000000181 | m² | Fertigteil | D002 | false | 100 | XC1, WO | C35/45 | HI_GES_FEB-0,220_xxx | Platte | - | no | 0
Stahlbetonfertigteilplatte | EG_Produktion_FFB | BASESLAB | Stahlbetonfertigteil | BP-STB1\ | Stahlbetonfertigteilplatte | EG_Produktion_FFB | 0113PFu0000000189 | m² | Fertigteil | D002 | false | 100 | XC1, WO | C35/45 | HI_GES_FEB-0,220_xxx | Platte | - | no | 0
Stahlbetonfertigteilplatte | EG_Produktion_FFB | BASESLAB | Stahlbetonfertigteil | BP-STB1\ | Stahlbetonfertigteilplatte | EG_Produktion_FFB | 0113PFu0000000191 | m² | Fertigteil | D002 | false | 100 | XC1, WO | C35/45 | HI_GES_FEB-0,220_xxx | Platte | - | no | 0
Stahlbetonfertigteilplatte | EG_Produktion_FFB | BASESLAB | Stahlbetonfertigteil | BP-STB1\ | Stahlbetonfertigteilplatte | EG_Produktion_FFB | 0113PFu0000000193 | m² | Fertigteil | D002 | false | 100 | XC1, WO | C35/45 | HI_GES_FEB-0,220_xxx | Platte | - | no | 0
Stahlbetonfertigteilplatte | EG_Produktion_FFB | BASESLAB | Stahlbetonfertigteil | BP-STB1\ | Stahlbetonfertigteilplatte | EG_Produktion_FFB | 0113PFu0000000199 | m² | Fertigteil | D002 | false | 100 | XC1, WO | C35/45 | HI_GES_FEB-0,220_xxx | Platte | - | no | 0
Stahlbetonfertigteilplatte | EG_Produktion_FFB | BASESLAB | Stahlbetonfertigteil | BP-STB1\ | Stahlbetonfertigteilplatte | EG_Produktion_FFB | 0113PFu0000000303 | m² | Fertigteil | D002 | false | 100 | XC1, WO | C35/45 | HI_GES_FEB-0,220_xxx | Platte | - | no | 0
Stahlbetonfertigteilplatte | EG_Produktion_FFB | BASESLAB | Stahlbetonfertigteil | BP-STB1\ | Stahlbetonfertigteilplatte | EG_Produktion_FFB | 0113PFu0000000481 | m² | Fertigteil | D002 | false | 100 | XC1, WO | C35/45 | HI_GES_FEB-0,220_xxx | Platte | - | no | 0
Stahlbetonfertigteilplatte | EG_Produktion_FFB | BASESLAB | Stahlbetonfertigteil | BP-STB1\ | Stahlbetonfertigteilplatte | EG_Produktion_FFB | 0113PFu0000000567 | m² | Fertigteil | D002 | false | 100 | XC1, WO | C35/45 | HI_GES_FEB-0,220_xxx | Platte | - | no | 0
Stahlbetonfertigteilplatte | EG_Produktion_FFB | BASESLAB | Stahlbetonfertigteil | BP-STB1\ | Stahlbetonfertigteilplatte | EG_Produktion_FFB | 0113PFu0000000719 | m² | Fertigteil | D002 | false | 100 | XC1, WO | C35/45 | HI_GES_FEB-0,220_xxx | Platte | - | no | 0
Stahlbetonfertigteilplatte | EG_Produktion_FFB | BASESLAB | Stahlbetonfertigteil | BP-STB1\ | Stahlbetonfertigteilplatte | EG_Produktion_FFB | 0113PFu0000005702 | m² | Fertigteil | D002 | false | 100 | XC1, WO | C35/45 | HI_GES_FEB-0,220_xxx | Platte | - | no | 0
Stahlbetonfertigteilplatte | EG_Produktion_FFB | BASESLAB | Stahlbetonfertigteil | BP-STB1\ | Stahlbetonfertigteilplatte | EG_Produktion_FFB | 0113PFu0000000565 | m² | Fertigteil | D002 | false | 100 | XC1, WO | C35/45 | HI_GES_FEB-0,220_xxx | Platte | - | no | 0
Stahlbetonfertigteilplatte | EG_Produktion_FFB | BASESLAB | Stahlbetonfertigteil | BP-STB1\ | Stahlbetonfertigteilplatte | EG_Produktion_FFB | 0113PFu0000000089 | m² | Fertigteil | D002 | false | 100 | XC1, WO | C35/45 | HI_GES_FEB-0,220_xxx | Platte | - | no | 0
Stahlbetonfertigteilplatte | EG_Produktion_FFB | BASESLAB | Stahlbetonfertigteil | BP-STB1\ | Stahlbetonfertigteilplatte | EG_Produktion_FFB | 0113PFu0000000445 | m² | Fertigteil | D002 | false | 100 | XC1, WO | C35/45 | HI_GES_FEB-0,220_xxx | Platte | - | no | 0
Stahlbetonfertigteilplatte | EG_Produktion_FFB | BASESLAB | Stahlbetonfertigteil | BP-STB1\ | Stahlbetonfertigteilplatte | EG_Produktion_FFB | 0113PFu0000000083 | m² | Fertigteil | D002 | false | 100 | XC1, WO | C35/45 | HI_GES_FEB-0,220_xxx | Platte | - | no | 0
Stahlbetonfertigteilplatte | EG_Produktion_FFB | BASESLAB | Stahlbetonfertigteil | BP-STB1\ | Stahlbetonfertigteilplatte | EG_Produktion_FFB | 0113PFu0000000093 | m² | Fertigteil | D002 | false | 100 | XC1, WO | C35/45 | HI_GES_FEB-0,220_xxx | Platte | - | no | 0
Stahlbetonfertigteilplatte | EG_Produktion_FFB | BASESLAB | Stahlbetonfertigteil | BP-STB1\ | Stahlbetonfertigteilplatte | EG_Produktion_FFB | 0113PFu0000000095 | m² | Fertigteil | D002 | false | 100 | XC1, WO | C35/45 | HI_GES_FEB-0,220_xxx | Platte | - | no | 0
Stahlbetonfertigteilplatte | EG_Produktion_FFB | BASESLAB | Stahlbetonfertigteil | BP-STB1\ | Stahlbetonfertigteilplatte | EG_Produktion_FFB | 0113PFu0000000063 | m² | Fertigteil | D002 | false | 100 | XC1, WO | C35/45 | HI_GES_FEB-0,220_xxx | Platte | - | no | 0
Stahlbetonfertigteilplatte | EG_Produktion_FFB | BASESLAB | Stahlbetonfertigteil | BP-STB1\ | Stahlbetonfertigteilplatte | EG_Produktion_FFB | 0113PFu0000000653 | m² | Fertigteil | D002 | false | 100 | XC1, WO | C35/45 | HI_GES_FEB-0,220_xxx | Platte | - | no | 0
Stahlbetonfertigteilplatte | EG_Produktion_FFB | BASESLAB | Stahlbetonfertigteil | BP-STB1\ | Stahlbetonfertigteilplatte | EG_Produktion_FFB | 0113PFu0000000165 | m² | Fertigteil | D002 | false | 100 | XC1, WO | C35/45 | HI_GES_FEB-0,220_xxx | Platte | - | no | 0
Stahlbetonfertigteilplatte | EG_Produktion_FFB | BASESLAB | Stahlbetonfertigteil | BP-STB1\ | Stahlbetonfertigteilplatte | EG_Produktion_FFB | 0113PFu0000000167 | m² | Fertigteil | D002 | false | 100 | XC1, WO | C35/45 | HI_GES_FEB-0,220_xxx | Platte | - | no | 0
Stahlbetonfertigteilplatte | EG_Produktion_FFB | BASESLAB | Stahlbetonfertigteil | BP-STB1\ | Stahlbetonfertigteilplatte | EG_Produktion_FFB | 0113PFu0000007645 | m² | Fertigteil | D002 | false | 100 | XC1, WO | C35/45 | HI_GES_FEB-0,220_xxx | Platte | - | no | 0
Stahlbetonfertigteilplatte | EG_Produktion_FFB | BASESLAB | Stahlbetonfertigteil | BP-STB1\ | Stahlbetonfertigteilplatte | EG_Produktion_FFB | 0113PFu0000000379 | m² | Fertigteil | D001 | false | 100 | XC1, WO | C35/45 | HI_GES_FEB-0,220_xxx | Platte | - | no | 0
Stahlbetonfertigteilplatte | EG_Produktion_FFB | BASESLAB | Stahlbetonfertigteil | BP-STB1\ | Stahlbetonfertigteilplatte | EG_Produktion_FFB | 0113PFu0000000357 | m² | Fertigteil | D002 | false | 100 | XC1, WO | C35/45 | HI_GES_FEB-0,220_xxx | Platte | - | no | 0
Stahlbetonfertigteilplatte | EG_Produktion_FFB | BASESLAB | Stahlbetonfertigteil | BP-STB1\ | Stahlbetonfertigteilplatte | EG_Produktion_FFB | 0113PFu0000000155 | m² | Fertigteil | D002 | false | 100 | XC1, WO | C35/45 | HI_GES_FEB-0,220_xxx | Platte | - | no | 0
Stahlbetonfertigteilplatte | EG_Produktion_FFB | BASESLAB | Stahlbetonfertigteil | BP-STB1\ | Stahlbetonfertigteilplatte | EG_Produktion_FFB | 0113PFu0000000153 | m² | Fertigteil | D002 | false | 100 | XC1, WO | C35/45 | HI_GES_FEB-0,220_xxx | Platte | - | no | 0
Stahlbetonfertigteilplatte | EG_Produktion_FFB | BASESLAB | Stahlbetonfertigteil | BP-STB1\ | Stahlbetonfertigteilplatte | EG_Produktion_FFB | 0113PFu0000000345 | m² | Fertigteil | D001 | false | 100 | XC1, WO | C35/45 | HI_GES_FEB-0,220_xxx | Platte | - | no | 0
Stahlbetonfertigteilplatte | EG_Produktion_FFB | BASESLAB | Stahlbetonfertigteil | BP-STB1\ | Stahlbetonfertigteilplatte | EG_Produktion_FFB | 0113PFu0000000343 | m² | Fertigteil | D001 | false | 100 | XC1, WO | C35/45 | HI_GES_FEB-0,220_xxx | Platte | - | no | 0
Stahlbetonfertigteilplatte | EG_Produktion_FFB | BASESLAB | Stahlbetonfertigteil | BP-STB1\ | Stahlbetonfertigteilplatte | EG_Produktion_FFB | 0113PFu0000005642 | m² | Fertigteil | D002 | false | 100 | XC1, WO | C35/45 | HI_GES_FEB-0,220_xxx | Platte | - | no | 0
Stahlbetonfertigteilplatte | EG_Produktion_FFB | BASESLAB | Stahlbetonfertigteil | BP-STB1\ | Stahlbetonfertigteilplatte | EG_Produktion_FFB | 0113PFu0000000147 | m² | Fertigteil | D002 | false | 100 | XC1, WO | C35/45 | HI_GES_FEB-0,220_xxx | Platte | - | no | 0
Stahlbetonfertigteilplatte | EG_Produktion_FFB | BASESLAB | Stahlbetonfertigteil | BP-STB1\ | Stahlbetonfertigteilplatte | EG_Produktion_FFB | 0113PFu0000007620 | m² | Fertigteil | D001 | false | 100 | XC1, WO | C35/45 | HI_GES_FEB-0,220_xxx | Platte | - | no | 0
Stahlbetonfertigteilplatte | EG_Produktion_FFB | BASESLAB | Stahlbetonfertigteil | BP-STB1\ | Stahlbetonfertigteilplatte | EG_Produktion_FFB | 0113PFu0000000381 | m² | Fertigteil | D001 | false | 100 | XC1, WO | C35/45 | HI_GES_FEB-0,220_xxx | Platte | - | no | 0
Stahlbetonfertigteilplatte | EG_Produktion_FFB | BASESLAB | Stahlbetonfertigteil | BP-STB1\ | Stahlbetonfertigteilplatte | EG_Produktion_FFB | 0113PFu0000000411 | m² | Fertigteil | D001 | false | 100 | XC1, WO | C35/45 | HI_GES_FEB-0,220_xxx | Platte | - | no | 0
Stahlbetonfertigteilplatte | EG_Produktion_FFB | BASESLAB | Stahlbetonfertigteil | BP-STB1\ | Stahlbetonfertigteilplatte | EG_Produktion_FFB | 0113PFu0000000413 | m² | Fertigteil | D001 | false | 100 | XC1, WO | C35/45 | HI_GES_FEB-0,220_xxx | Platte | - | no | 0
Stahlbetonfertigteilplatte | EG_Produktion_FFB | BASESLAB | Stahlbetonfertigteil | BP-STB1\ | Stahlbetonfertigteilplatte | EG_Produktion_FFB | 0113PFu0000000451 | m² | Fertigteil | D001 | false | 100 | XC1, WO | C35/45 | HI_GES_FEB-0,220_xxx | Platte | - | no | 0
Stahlbetonfertigteilplatte | EG_Produktion_FFB | BASESLAB | Stahlbetonfertigteil | BP-STB1\ | Stahlbetonfertigteilplatte | EG_Produktion_FFB | 0113PFu0000000141 | m² | Fertigteil | D002 | false | 100 | XC1, WO | C35/45 | HI_GES_FEB-0,220_xxx | Platte | - | no | 0
Stahlbetonfertigteilplatte | EG_Produktion_FFB | BASESLAB | Stahlbetonfertigteil | BP-STB1\ | Stahlbetonfertigteilplatte | EG_Produktion_FFB | 0113PFu0000000423 | m² | Fertigteil | D002 | false | 100 | XC1, WO | C35/45 | HI_GES_FEB-0,220_xxx | Platte | - | no | 0
Stahlbetonfertigteilplatte | EG_Produktion_FFB | BASESLAB | Stahlbetonfertigteil | BP-STB1\ | Stahlbetonfertigteilplatte | EG_Produktion_FFB | 0113PFu0000000425 | m² | Fertigteil | D002 | false | 100 | XC1, WO | C35/45 | HI_GES_FEB-0,220_xxx | Platte | - | no | 0
Stahlbetonfertigteilplatte | EG_Produktion_FFB | BASESLAB | Stahlbetonfertigteil | BP-STB1\ | Stahlbetonfertigteilplatte | EG_Produktion_FFB | 0113PFu0000000453 | m² | Fertigteil | D001 | false | 100 | XC1, WO | C35/45 | HI_GES_FEB-0,220_xxx | Platte | - | no | 0
Stahlbetonfertigteilplatte | EG_Produktion_FFB | BASESLAB | Stahlbetonfertigteil | BP-STB1\ | Stahlbetonfertigteilplatte | EG_Produktion_FFB | 0113PFu0000000487 | m² | Fertigteil | D001 | false | 100 | XC1, WO | C35/45 | HI_GES_FEB-0,220_xxx | Platte | - | no | 0
Stahlbetonfertigteilplatte | EG_Produktion_FFB | BASESLAB | Stahlbetonfertigteil | BP-STB1\ | Stahlbetonfertigteilplatte | EG_Produktion_FFB | 0113PFu0000007576 | m² | Fertigteil | D002 | false | 100 | XC1, WO | C35/45 | HI_GES_FEB-0,220_xxx | Platte | - | no | 0
Stahlbetonfertigteilplatte | EG_Produktion_FFB | BASESLAB | Stahlbetonfertigteil | BP-STB1\ | Stahlbetonfertigteilplatte | EG_Produktion_FFB | 0113PFu0000007589 | m² | Fertigteil | D001 | false | 100 | XC1, WO | C35/45 | HI_GES_FEB-0,220_xxx | Platte | - | no | 0
Stahlbetonfertigteilplatte | EG_Produktion_FFB | BASESLAB | Stahlbetonfertigteil | BP-STB1\ | Stahlbetonfertigteilplatte | EG_Produktion_FFB | 0113PFu0000000137 | m² | Fertigteil | D002 | false | 100 | XC1, WO | C35/45 | HI_GES_FEB-0,220_xxx | Platte | - | no | 0
Stahlbetonfertigteilplatte | EG_Produktion_FFB | BASESLAB | Stahlbetonfertigteil | BP-STB1\ | Stahlbetonfertigteilplatte | EG_Produktion_FFB | 0113PFu0000000489 | m² | Fertigteil | D001 | false | 100 | XC1, WO | C35/45 | HI_GES_FEB-0,220_xxx | Platte | - | no | 0
Stahlbetonfertigteilplatte | EG_Produktion_FFB | BASESLAB | Stahlbetonfertigteil | BP-STB1\ | Stahlbetonfertigteilplatte | EG_Produktion_FFB | 0113PFu0000000465 | m² | Fertigteil | D002 | false | 100 | XC1, WO | C35/45 | HI_GES_FEB-0,220_xxx | Platte | - | no | 0
Stahlbetonfertigteilplatte | EG_Produktion_FFB | BASESLAB | Stahlbetonfertigteil | BP-STB1\ | Stahlbetonfertigteilplatte | EG_Produktion_FFB | 0113PFu0000000111 | m² | Fertigteil | D002 | false | 100 | XC1, WO | C35/45 | HI_GES_FEB-0,220_xxx | Platte | - | no | 0
Stahlbetonfertigteilplatte | EG_Produktion_FFB | BASESLAB | Stahlbetonfertigteil | BP-STB1\ | Stahlbetonfertigteilplatte | EG_Produktion_FFB | 0113PFu0000000107 | m² | Fertigteil | D002 | false | 100 | XC1, WO | C35/45 | HI_GES_FEB-0,220_xxx | Platte | - | no | 0
Stahlbetonfertigteilplatte | EG_Produktion_FFB | BASESLAB | Stahlbetonfertigteil | BP-STB1\ | Stahlbetonfertigteilplatte | EG_Produktion_FFB | 0113PFu0000000009 | m² | Fertigteil | D001 | false | 100 | XC1, WO | C35/45 | HI_GES_FEB-0,220_xxx | Platte | - | no | 0
Stahlbetonfertigteilplatte | EG_Produktion_FFB | BASESLAB | Stahlbetonfertigteil | BP-STB1\ | Stahlbetonfertigteilplatte | EG_Produktion_FFB | 0113PFu0000000005 | m² | Fertigteil | D002 | false | 100 | XC1, WO | C35/45 | HI_GES_FEB-0,220_xxx | Platte | - | no | 0
Stahlbetonfertigteilplatte | EG_Produktion_FFB | BASESLAB | Stahlbetonfertigteil | BP-STB1\ | Stahlbetonfertigteilplatte | EG_Produktion_FFB | 0113PFu0000000201 | m² | Fertigteil | D001 | false | 100 | XC1, WO | C35/45 | HI_GES_FEB-0,220_xxx | Platte | - | no | 0
Stahlbetonfertigteilplatte | EG_Produktion_FFB | BASESLAB | Stahlbetonfertigteil | BP-STB1\ | Stahlbetonfertigteilplatte | EG_Produktion_FFB | 0113PFu0000000003 | m² | Fertigteil | D001 | false | 100 | XC1, WO | C35/45 | HI_GES_FEB-0,220_xxx | Platte | - | no | 0
Stahlbetonfertigteilplatte | EG_Produktion_FFB | BASESLAB | Stahlbetonfertigteil | BP-STB1\ | Stahlbetonfertigteilplatte | EG_Produktion_FFB | 0113PFu0000000007 | m² | Fertigteil | D002 | false | 100 | XC1, WO | C35/45 | HI_GES_FEB-0,220_xxx | Platte | - | no | 0
Stahlbetonfertigteilplatte | EG_Produktion_FFB | BASESLAB | Stahlbetonfertigteil | BP-STB1\ | Stahlbetonfertigteilplatte | EG_Produktion_FFB | 0113PFu0000008850 | m² | Fertigteil | D002 | false | 100 | XC1, WO | C35/45 | HI_GES_FEB-0,220_xxx | Platte | - | no | 0
Stahlbetonfertigteilplatte | EG_Produktion_FFB | BASESLAB | Stahlbetonfertigteil | BP-STB1\ | Stahlbetonfertigteilplatte | EG_Produktion_FFB | 0113PFu0000008888 | m² | Fertigteil | D002 | false | 100 | XC1, WO | C35/45 | HI_GES_FEB-0,220_xxx | Platte | - | no | 0
Stahlbetonfertigteilplatte | EG_Produktion_FFB | BASESLAB | Stahlbetonfertigteil | BP-STB1\ | Stahlbetonfertigteilplatte | EG_Produktion_FFB | 0113PFu0000008889 | m² | Fertigteil | D002 | false | 100 | XC1, WO | C35/45 | HI_GES_FEB-0,220_xxx | Platte | - | no | 0
Stahlbetonfertigteilplatte | EG_Produktion_FFB | BASESLAB | Stahlbetonfertigteil | BP-STB1\ | Stahlbetonfertigteilplatte | EG_Produktion_FFB | 0113PFu0000000205 | m² | Fertigteil | D002 | false | 100 | XC1, WO | C35/45 | HI_GES_FEB-0,220_xxx | Platte | - | no | 0
Stahlbetonfertigteilplatte | EG_Produktion_FFB | BASESLAB | Stahlbetonfertigteil | BP-STB1\ | Stahlbetonfertigteilplatte | EG_Produktion_FFB | 0113PFu0000000291 | m² | Fertigteil | D001 | false | 100 | XC1, WO | C35/45 | HI_GES_FEB-0,220_xxx | Platte | - | no | 0
Stahlbetonfertigteilplatte | EG_Produktion_FFB | BASESLAB | Stahlbetonfertigteil | BP-STB1\ | Stahlbetonfertigteilplatte | EG_Produktion_FFB | 0113PFu0000000295 | m² | Fertigteil | D001 | false | 100 | XC1, WO | C35/45 | HI_GES_FEB-0,220_xxx | Platte | - | no | 0
Stahlbetonfertigteilplatte | EG_Produktion_FFB | BASESLAB | Stahlbetonfertigteil | BP-STB1\ | Stahlbetonfertigteilplatte | EG_Produktion_FFB | 0113PFu0000000251 | m² | Fertigteil | D002 | false | 100 | XC1, WO | C35/45 | HI_GES_FEB-0,220_xxx | Platte | - | no | 0
Stahlbetonfertigteilplatte | EG_Produktion_FFB | BASESLAB | Stahlbetonfertigteil | BP-STB1\ | Stahlbetonfertigteilplatte | EG_Produktion_FFB | 0113PFu0000000249 | m² | Fertigteil | D001 | false | 100 | XC1, WO | C35/45 | HI_GES_FEB-0,220_xxx | Platte | - | no | 0
Stahlbetonfertigteilplatte | EG_Produktion_FFB | BASESLAB | Stahlbetonfertigteil | BP-STB1\ | Stahlbetonfertigteilplatte | EG_Produktion_FFB | 0113PFu0000000301 | m² | Fertigteil | D002 | false | 100 | XC1, WO | C35/45 | HI_GES_FEB-0,220_xxx | Platte | - | no | 0
Stahlbetonfertigteilplatte | EG_Produktion_FFB | BASESLAB | Stahlbetonfertigteil | BP-STB1\ | Stahlbetonfertigteilplatte | EG_Produktion_FFB | 0113PFu0000000253 | m² | Fertigteil | D002 | false | 100 | XC1, WO | C35/45 | HI_GES_FEB-0,220_xxx | Platte | - | no | 0
Stahlbetonfertigteilplatte | EG_Produktion_FFB | BASESLAB | Stahlbetonfertigteil | BP-STB1\ | Stahlbetonfertigteilplatte | EG_Produktion_FFB | 0113PFu0000000305 | m² | Fertigteil | D002 | false | 100 | XC1, WO | C35/45 | HI_GES_FEB-0,220_xxx | Platte | - | no | 0
Stahlbetonfertigteilplatte | EG_Produktion_FFB | BASESLAB | Stahlbetonfertigteil | BP-STB1\ | Stahlbetonfertigteilplatte | EG_Produktion_FFB | 0113PFu0000000255 | m² | Fertigteil | D001 | false | 100 | XC1, WO | C35/45 | HI_GES_FEB-0,220_xxx | Platte | - | no | 0
Stahlbetonfertigteilplatte | EG_Produktion_FFB | BASESLAB | Stahlbetonfertigteil | BP-STB1\ | Stahlbetonfertigteilplatte | EG_Produktion_FFB | 0113PFu0000000307 | m² | Fertigteil | D001 | false | 100 | XC1, WO | C35/45 | HI_GES_FEB-0,220_xxx | Platte | - | no | 0
Stahlbetonfertigteilplatte | EG_Produktion_FFB | BASESLAB | Stahlbetonfertigteil | BP-STB1\ | Stahlbetonfertigteilplatte | EG_Produktion_FFB | 0113PFu0000000247 | m² | Fertigteil | D001 | false | 100 | XC1, WO | C35/45 | HI_GES_FEB-0,220_xxx | Platte | - | no | 0
Stahlbetonfertigteilplatte | EG_Produktion_FFB | BASESLAB | Stahlbetonfertigteil | BP-STB1\ | Stahlbetonfertigteilplatte | EG_Produktion_FFB | 0113PFu0000000259 | m² | Fertigteil | D001 | false | 100 | XC1, WO | C35/45 | HI_GES_FEB-0,220_xxx | Platte | - | no | 0
Stahlbetonfertigteilplatte | EG_Produktion_FFB | BASESLAB | Stahlbetonfertigteil | BP-STB1\ | Stahlbetonfertigteilplatte | EG_Produktion_FFB | 0113PFu0000000231 | m² | Fertigteil | D002 | false | 100 | XC1, WO | C35/45 | HI_GES_FEB-0,220_xxx | Platte | - | no | 0
Stahlbetonfertigteilplatte | EG_Produktion_FFB | BASESLAB | Stahlbetonfertigteil | BP-STB1\ | Stahlbetonfertigteilplatte | EG_Produktion_FFB | 0113PFu0000000267 | m² | Fertigteil | D001 | false | 100 | XC1, WO | C35/45 | HI_GES_FEB-0,220_xxx | Platte | - | no | 0
Stahlbetonfertigteilplatte | EG_Produktion_FFB | BASESLAB | Stahlbetonfertigteil | BP-STB1\ | Stahlbetonfertigteilplatte | EG_Produktion_FFB | 0113PFu0000000225 | m² | Fertigteil | D001 | false | 100 | XC1, WO | C35/45 | HI_GES_FEB-0,220_xxx | Platte | - | no | 0
Stahlbetonfertigteilplatte | EG_Produktion_FFB | BASESLAB | Stahlbetonfertigteil | BP-STB1\ | Stahlbetonfertigteilplatte | EG_Produktion_FFB | 0113PFu0000000223 | m² | Fertigteil | D001 | false | 100 | XC1, WO | C35/45 | HI_GES_FEB-0,220_xxx | Platte | - | no | 0
Stahlbetonfertigteilplatte | EG_Produktion_FFB | BASESLAB | Stahlbetonfertigteil | BP-STB1\ | Stahlbetonfertigteilplatte | EG_Produktion_FFB | 0113PFu0000000263 | m² | Fertigteil | D001 | false | 100 | XC1, WO | C35/45 | HI_GES_FEB-0,220_xxx | Platte | - | no | 0
Stahlbetonfertigteilplatte | EG_Produktion_FFB | BASESLAB | Stahlbetonfertigteil | BP-STB1\ | Stahlbetonfertigteilplatte | EG_Produktion_FFB | 0113PFu0000000613 | m² | Fertigteil | D002 | false | 100 | XC1, WO | C35/45 | HI_GES_FEB-0,220_xxx | Platte | - | no | 0
Stahlbetonfertigteilplatte | EG_Produktion_FFB | BASESLAB | Stahlbetonfertigteil | BP-STB1\ | Stahlbetonfertigteilplatte | EG_Produktion_FFB | 0113PFu0000000617 | m² | Fertigteil | D002 | false | 100 | XC1, WO | C35/45 | HI_GES_FEB-0,220_xxx | Platte | - | no | 0
Stb.-Bodenplatte | EG_Produktion_FFB | BASESLAB | Stahlbeton | BP-STB1\ | Stb.-Bodenplatte | EG_Produktion_FFB | 0113PFu0000007321 | m² | Ortbeton | D001.1 | true | 100 | XC2, WF | C35/45 | HA_GFB_STB_0,670_xxx | Platte | F90 | no | 0
Stb.-Bodenplatte | EG_Produktion_FFB | BASESLAB | Stahlbeton | BP-STB1\ | Stb.-Bodenplatte | EG_Produktion_FFB | 0113PFu0000007189 | m² | Ortbeton | D001.1 | true | 100 | XC2, WF | C35/45 | HA_GFB_STB-0,220_xxx | Platte | - | no | 0
Stahlbetonfertigteilplatte | EG_Produktion_FFB | BASESLAB | Stahlbetonfertigteil | BP-STB1\ | Stahlbetonfertigteilplatte | EG_Produktion_FFB | 0113PFu0000000243 | m² | Fertigteil | D001 | false | 100 | XC1, WO | C35/45 | HI_GES_FEB-0,220_xxx | Platte | - | no | 0
Stahlbetonfertigteilplatte | EG_Produktion_FFB | BASESLAB | Stahlbetonfertigteil | BP-STB1\ | Stahlbetonfertigteilplatte | EG_Produktion_FFB | 0113PFu0000000245 | m² | Fertigteil | D001 | false | 100 | XC1, WO | C35/45 | HI_GES_FEB-0,220_xxx | Platte | - | no | 0
Stahlbetonfertigteilplatte | EG_Produktion_FFB | BASESLAB | Stahlbetonfertigteil | BP-STB1\ | Stahlbetonfertigteilplatte | EG_Produktion_FFB | 0113PFu0000000061 | m² | Fertigteil | D002 | false | 100 | XC1, WO | C35/45 | HI_GES_FEB-0,220_xxx | Platte | - | no | 0
Stahlbetonfertigteilplatte | EG_Produktion_FFB | BASESLAB | Stahlbetonfertigteil | BP-STB1\ | Stahlbetonfertigteilplatte | EG_Produktion_FFB | 0113PFu0000000241 | m² | Fertigteil | D002 | false | 100 | XC1, WO | C35/45 | HI_GES_FEB-0,220_xxx | Platte | - | no | 0

# IfcStair (58)
In: EG_Technik_FFB
Material: Stahl
AllplanAttributes - Gewerk: Stahlbauarbeiten; Bezeichnung: Stahltreppe; Material: Stahl; Profilname: U 260; Ebene: EG_Technik_FFB; Attributset-Objekt: Treppe; Abrechnungsart: St
IFC_Pset_TWP - Phase erstellt: Neubau; Name: Stahltreppe; statisch tragend: true; Außenbauteil: true; Kommentar: -; Positionsnummer: ATL01
Pset_FM-Vivantes - FM_Klasse: -; FM_Bezeichnung: -; FM_AKS: -; FM_Anzahl: -; FM_Standort: -; FM_Hersteller: -; FM_Hersteller-Typ: -; FM_Seriennummer: -; FM_Baujahr: -; FM_Inbetriebnahme Datum: -; FM_Gewährleistungsende: -; FM_Gewährleistungsgeber: -; FM_Betriebsstatus: -; FM_Prüfpflicht: -; FM_Prüfintervall: -; FM_letzter Prüfungstermin: -; FM_Sammelobjekt: -; FM_rechn. Lebensdauer: -; FM_rechn. Lebensende: -; FM_technischer Zustand: -; FM_voraus. Lebensende: -; FM_Eigentümer: -; FM_Bemerkung: -; FM_Versorgungsbereich-Wirkbereich: -; FM_Zugänglichkeit: -
Pset_StairCommon - Reference: HA_TRE_U_260_STA_0,260_xxx
Name | Allright_Bauteil_ID
Stahltreppe | 0106ErE0000000303
Stahltreppe | 0106ErE0000000305
Stahltreppe | 0106ErE0000000307
Stahltreppe | 0106ErE0000000302
Stahltreppe | 0106ErE0000000370
Stahltreppe | 0106ErE0000000371
Stahltreppe | 0106ErE0000000224
Stahltreppe | 0106ErE0000000226
Stahltreppe | 0106ErE0000000334
Stahltreppe | 0106ErE0000000220
Stahltreppe | 0106ErE0000000335
Stahltreppe | 0106ErE0000000218
Stahltreppe | 0106ErE0000000340
Stahltreppe | 0106ErE0000000221
Stahltreppe | 0106ErE0000000219
Stahltreppe | 0106ErE0000000299
Stahltreppe | 0106ErE0000000301
Stahltreppe | 0106ErE0000000356
Stahltreppe | 0106ErE0000000357
Stahltreppe | 0106ErE0000000318
Stahltreppe | 0106ErE0000000320
Stahltreppe | 0106ErE0000000323
Stahltreppe | 0106ErE0000000312
Stahltreppe | 0106ErE0000000229
Stahltreppe | 0106ErE0000000231
Stahltreppe | 0106ErE0000000230
Stahltreppe | 0106ErE0000000317
Stahltreppe | 0106ErE0000000314
Stahltreppe | 0106ErE0000000235
Stahltreppe | 0106ErE0000000378
Stahltreppe | 0106ErE0000000261
Stahltreppe | 0106ErE0000000464
Stahltreppe | 0106ErE0000000465
Stahltreppe | 0106ErE0000000294
Stahltreppe | 0106ErE0000000296
Stahltreppe | 0106ErE0000000351
Stahltreppe | 0106ErE0000000350
Stahltreppe | 0106ErE0000000308
Stahltreppe | 0106ErE0000000309
Stahltreppe | 0106ErE0000000215
Stahltreppe | 0106ErE0000000214
Stahltreppe | 0106ErE0000000216
Stahltreppe | 0106ErE0000000217
Stahltreppe | 0106ErE0000000239
Stahltreppe | 0106ErE0000000234
Stahltreppe | 0106ErE0000000238
Stahltreppe | 0106ErE0000000377
Stahltreppe | 0106ErE0000000372
Stahltreppe | 0106ErE0000000453
Stahltreppe | 0106ErE0000000059
Stahltreppe | 0106ErE0000000074
Stahltreppe | 0106ErE0000000454
Stahltreppe | 0106ErE0000000096
Stahltreppe | 0106ErE0000000456
Stahltreppe | 0106ErE0000000112
Stahltreppe | 0106ErE0000000089
Stahltreppe | 0106ErE0000000455
Stahltreppe | 0106ErE0000000457

# IfcWallStandardCase (119)
AllplanAttributes - Abrechnungsart: m³; Object Layer Attributes #1, 2D Interaktion: yes; Object Layer Attributes #1, Abrechnungsart: m³
IFC_Pset_TWP - Kommentar: -; Phase erstellt: Neubau
Pset_ConcreteElementGeneral - WU-Beton: false
Pset_FM-Vivantes - FM_Klasse: -; FM_Bezeichnung: -; FM_AKS: -; FM_Anzahl: -; FM_Standort: -; FM_Hersteller: -; FM_Hersteller-Typ: -; FM_Seriennummer: -; FM_Baujahr: -; FM_Inbetriebnahme Datum: -; FM_Gewährleistungsende: -; FM_Gewährleistungsgeber: -; FM_Betriebsstatus: -; FM_Prüfpflicht: -; FM_Prüfintervall: -; FM_letzter Prüfungstermin: -; FM_Sammelobjekt: -; FM_rechn. Lebensdauer: -; FM_rechn. Lebensende: -; FM_technischer Zustand: -; FM_voraus. Lebensende: -; FM_Eigentümer: -; FM_Bemerkung: -; FM_Versorgungsbereich-Wirkbereich: -; FM_Zugänglichkeit: -
Name | In | Material | Bezeichnung | MEP Wandtyp | Allright_Bauteil_ID | Object Layer Attributes #1, Codetext | Object Layer Attributes #1, Gewerk | Object Layer Attributes #1, Bezeichnung | Object Layer Attributes #1, Material | Object Layer Attributes #1, Ebene | Object Layer Attributes #1, Allright_Bauteil_ID | Object Layer Attributes #1, WallCommon, Raumhohe Wand | Object Layer Attributes #1, WallCommon, Reference | Name | IFC_Pset_TWP, Material | Herstellung | Positionsnummer | statisch tragend | Außenbauteil | Bewehrungsgrad | Expositionsklasse | Druckfestigkeitsklasse | ExtendToStructure | Reference
HI_WAN_MWK_0,240_xxx | EG_Technik_FFB | KS-XL-16-1.8/DM 0.24 m | HI_WAN_MWK_0,240_xxx | WI-ZIEGEL2\ | 0101HWa0000000066 | WI-KALKSAND2\ | Mauerarbeiten | Mauerwerkswand | KS-XL-16-1.8/DM | EG_Technik_FFB | 0101Wa 0000000131 | yes | HI_WAN_MWK_0,240_xxx | Mauerwerkswand | Mauerwerk | Mauerwerk | W001.1 | true | false | 0 | - | - | yes | HI_WAN_MWK_0,240_xxx
HI_WAN_MWK_0,240_xxx | EG_Technik_FFB | KS-XL-16-1.8/DM 0.24 m | HI_WAN_MWK_0,240_xxx | WI-ZIEGEL2\ | 0101HWa0000000089 | WI-KALKSAND2\ | Mauerarbeiten | Mauerwerkswand | KS-XL-16-1.8/DM | EG_Technik_FFB | 0101Wa 0000000145 | yes | HI_WAN_MWK_0,240_xxx | Mauerwerkswand | Mauerwerk | Mauerwerk | W001.1 | true | false | 0 | - | - | yes | HI_WAN_MWK_0,240_xxx
HI_WAN_MWK_0,240_xxx | EG_Technik_FFB | KS-XL-16-1.8/DM 0.24 m | HI_WAN_MWK_0,240_xxx | WI-ZIEGEL2\ | 0101HWa0000000088 | WI-KALKSAND2\ | Mauerarbeiten | Mauerwerkswand | KS-XL-16-1.8/DM | EG_Technik_FFB | 0101Wa 0000000143 | yes | HA_WAN_MWK_0,240_xxx | Mauerwerkswand | Mauerwerk | Mauerwerk | W001.2 | true | false | 0 | - | - | yes | HI_WAN_MWK_0,240_xxx
HI_WAN_MWK_0,240_xxx | EG_Technik_FFB | KS-XL-16-1.8/DM 0.24 m | HI_WAN_MWK_0,240_xxx | WI-ZIEGEL2\ | 0101HWa0000000055 | WI-KALKSAND2\ | Mauerarbeiten | Mauerwerkswand | KS-XL-16-1.8/DM | EG_Technik_FFB | 0101Wa 0000000141 | yes | HA_WAN_MWK_0,240_xxx | Mauerwerkswand | Mauerwerk | Mauerwerk | W001.2 | true | false | 0 | - | - | yes | HI_WAN_MWK_0,240_xxx
HI_WAN_MWK_0,240_xxx | EG_Technik_FFB | KS-XL-16-1.8/DM 0.24 m | HI_WAN_MWK_0,240_xxx | WI-ZIEGEL2\ | 0101HWa0000000736 | WI-KALKSAND2\ | Mauerarbeiten | Mauerwerkswand | KS-XL-16-1.8/DM | EG_Technik_FFB | 0101Wa 0000000737 | yes | HI_WAN_MWK_0,240_xxx | Mauerwerkswand | Mauerwerk | Mauerwerk | W001.1 | true | false | 0 | - | - | yes | HI_WAN_MWK_0,240_xxx
HI_WAN_MWK_0,240_xxx | EG_Technik_FFB | KS-XL-16-1.8/DM 0.24 m | HI_WAN_MWK_0,240_xxx | WI-ZIEGEL2\ | 0101HWa0000000681 | WI-KALKSAND2\ | Mauerarbeiten | Mauerwerkswand | KS-XL-16-1.8/DM | EG_Technik_FFB | 0101Wa 0000000683 | yes | HI_WAN_MWK_0,240_xxx | Mauerwerkswand | Mauerwerk | Mauerwerk | W001.1 | true | false | 0 | - | - | yes | HI_WAN_MWK_0,240_xxx
HI_WAN_MWK_0,240_xxx | EG_Technik_FFB | KS-XL-16-1.8/DM 0.24 m | HI_WAN_MWK_0,240_xxx | WI-ZIEGEL2\ | 0101HWa0000000018 | WI-KALKSAND2\ | Mauerarbeiten | Mauerwerkswand | KS-XL-16-1.8/DM | EG_Technik_FFB | 0101Wa 0000000173 | yes | HI_WAN_MWK_0,240_xxx | Mauerwerkswand | Mauerwerk | Mauerwerk | W001.1 | true | false | 0 | - | - | yes | HI_WAN_MWK_0,240_xxx
HI_WAN_MWK_0,240_xxx | EG_Technik_FFB | KS-XL-16-1.8/DM 0.24 m | HI_WAN_MWK_0,240_xxx | WI-ZIEGEL2\ | 0101HWa0000002454 | WI-KALKSAND2\ | Mauerarbeiten | Mauerwerkswand | KS-XL-16-1.8/DM | EG_Technik_FFB | 0101Wa 0000002456 | yes | HA_WAN_MWK_0,240_xxx | Mauerwerkswand | Mauerwerk | Mauerwerk | W001.2 | true | false | 0 | - | - | yes | HI_WAN_MWK_0,240_xxx
HI_WAN_MWK_0,240_xxx | EG_Technik_FFB | KS-XL-16-1.8/DM 0.24 m | HI_WAN_MWK_0,240_xxx | WI-ZIEGEL2\ | 0101HWa0000000016 | WI-KALKSAND2\ | Mauerarbeiten | Mauerwerkswand | KS-XL-16-1.8/DM | EG_Technik_FFB | 0101Wa 0000000195 | yes | HI_WAN_MWK_0,240_xxx | Mauerwerkswand | Mauerwerk | Mauerwerk | W001.1 | true | false | 0 | - | - | yes | HI_WAN_MWK_0,240_xxx
HI_WAN_MWK_0,240_xxx | EG_Technik_FFB | KS-XL-16-1.8/DM 0.24 m | HI_WAN_MWK_0,240_xxx | WI-ZIEGEL2\ | 0101HWa0000000026 | WI-KALKSAND2\ | Mauerarbeiten | Mauerwerkswand | KS-XL-16-1.8/DM | EG_Technik_FFB | 0101Wa 0000000183 | yes | HI_WAN_MWK_0,240_xxx | Mauerwerkswand | Mauerwerk | Mauerwerk | W001.1 | true | false | 0 | - | - | yes | HI_WAN_MWK_0,240_xxx
HI_WAN_MWK_0,240_xxx | EG_Technik_FFB | KS-XL-16-1.8/DM 0.24 m | HI_WAN_MWK_0,240_xxx | WI-ZIEGEL2\ | 0101HWa0000000012 | WI-KALKSAND2\ | Mauerarbeiten | Mauerwerkswand | KS-XL-16-1.8/DM | EG_Technik_FFB | 0101Wa 0000000193 | yes | HA_WAN_MWK_0,240_xxx | Mauerwerkswand | Mauerwerk | Mauerwerk | W001.2 | true | false | 0 | - | - | yes | HI_WAN_MWK_0,240_xxx
HI_WAN_MWK_0,240_xxx | EG_Technik_FFB | KS-XL-16-1.8/DM 0.24 m | HI_WAN_MWK_0,240_xxx | WI-ZIEGEL2\ | 0101HWa0000006392 | WI-KALKSAND2\ | Mauerarbeiten | Mauerwerkswand | KS-XL-16-1.8/DM | EG_Technik_FFB | 0101Wa 0000006393 | yes | HI_WAN_MWK_0,240_xxx | Mauerwerkswand | Mauerwerk | Mauerwerk | W001.1 | true | false | 0 | - | - | yes | HI_WAN_MWK_0,240_xxx
HI_WAN_MWK_0,240_xxx | EG_Technik_FFB | KS-XL-16-1.8/DM 0.24 m | HI_WAN_MWK_0,240_xxx | WI-ZIEGEL2\ | 0101HWa0000006415 | WI-KALKSAND2\ | Mauerarbeiten | Mauerwerkswand | KS-XL-16-1.8/DM | EG_Technik_FFB | 0101Wa 0000006416 | yes | HI_WAN_MWK_0,240_xxx | Mauerwerkswand | Mauerwerk | Mauerwerk | W001.1 | true | false | 0 | - | - | yes | HI_WAN_MWK_0,240_xxx
HI_WAN_MWK_0,240_xxx | EG_Technik_FFB | KS-XL-16-1.8/DM 0.24 m | HI_WAN_MWK_0,240_xxx | WI-ZIEGEL2\ | 0101HWa0000006437 | WI-KALKSAND2\ | Mauerarbeiten | Mauerwerkswand | KS-XL-16-1.8/DM | EG_Technik_FFB | 0101Wa 0000006438 | yes | HA_WAN_MWK_0,240_xxx | Mauerwerkswand | Mauerwerk | Mauerwerk | W001.2 | true | false | 0 | - | - | yes | HI_WAN_MWK_0,240_xxx
HI_WAN_MWK_0,240_xxx | EG_Technik_FFB | KS-XL-16-1.8/DM 0.24 m | HI_WAN_MWK_0,240_xxx | WI-ZIEGEL2\ | 0101HWa0000006657 | WI-KALKSAND2\ | Mauerarbeiten | Mauerwerkswand | KS-XL-16-1.8/DM | EG_Technik_FFB | 0101Wa 0000006658 | yes | HI_WAN_MWK_0,240_xxx | Mauerwerkswand | Mauerwerk | Mauerwerk | W001.1 | true | false | 0 | - | - | yes | HI_WAN_MWK_0,240_xxx
HI_WAN_MWK_0,240_xxx | EG_Technik_FFB | KS-XL-16-1.8/DM 0.24 m | HI_WAN_MWK_0,240_xxx | WI-ZIEGEL2\ | 0101HWa0000006717 | WI-KALKSAND2\ | Mauerarbeiten | Mauerwerkswand | KS-XL-16-1.8/DM | EG_Technik_FFB | 0101Wa 0000006719 | yes | HA_WAN_MWK_0,240_xxx | Mauerwerkswand | Mauerwerk | Mauerwerk | W001.2 | true | false | 0 | - | - | yes | HI_WAN_MWK_0,240_xxx
HI_WAN_MWK_0,240_xxx | EG_Technik_FFB | KS-XL-16-1.8/DM 0.24 m | HI_WAN_MWK_0,240_xxx | WI-ZIEGEL2\ | 0101HWa0000006747 | WI-KALKSAND2\ | Mauerarbeiten | Mauerwerkswand | KS-XL-16-1.8/DM | EG_Technik_FFB | 0101Wa 0000006749 | yes | HA_WAN_MWK_0,240_xxx | Mauerwerkswand | Mauerwerk | Mauerwerk | W001.2 | true | false | 0 | - | - | yes | HI_WAN_MWK_0,240_xxx
HI_WAN_MWK_0,240_xxx | EG_Technik_FFB | KS-XL-16-1.8/DM 0.24 m | HI_WAN_MWK_0,240_xxx | WI-ZIEGEL2\ | 0101HWa0000006732 | WI-KALKSAND2\ | Mauerarbeiten | Mauerwerkswand | KS-XL-16-1.8/DM | EG_Technik_FFB | 0101Wa 0000006734 | yes | HA_WAN_MWK_0,240_xxx | Mauerwerkswand | Mauerwerk | Mauerwerk | W001.2 | true | false | 0 | - | - | yes | HI_WAN_MWK_0,240_xxx
HI_WAN_MWK_0,240_xxx | EG_Technik_FFB | KS-XL-16-1.8/DM 0.24 m | HI_WAN_MWK_0,240_xxx | WI-ZIEGEL2\ | 0101HWa0000006762 | WI-KALKSAND2\ | Mauerarbeiten | Mauerwerkswand | KS-XL-16-1.8/DM | EG_Technik_FFB | 0101Wa 0000006763 | yes | HA_WAN_MWK_0,240_xxx | Mauerwerkswand | Mauerwerk | Mauerwerk | W001.2 | true | false | 0 | - | - | yes | HI_WAN_MWK_0,240_xxx
HI_WAN_MWK_0,240_xxx | EG_Technik_FFB | KS-XL-16-1.8/DM 0.24 m | HI_WAN_MWK_0,240_xxx | WI-ZIEGEL2\ | 0101HWa0000006772 | WI-KALKSAND2\ | Mauerarbeiten | Mauerwerkswand | KS-XL-16-1.8/DM | EG_Technik_FFB | 0101Wa 0000006774 | yes | HA_WAN_MWK_0,240_xxx | Mauerwerkswand | Mauerwerk | Mauerwerk | W001.2 | true | false | 0 | - | - | yes | HI_WAN_MWK_0,240_xxx
HI_WAN_MWK_0,240_xxx | EG_Technik_FFB | KS-XL-16-1.8/DM 0.24 m | HI_WAN_MWK_0,240_xxx | WI-ZIEGEL2\ | 0101HWa0000006779 | WI-KALKSAND2\ | Mauerarbeiten | Mauerwerkswand | KS-XL-16-1.8/DM | EG_Technik_FFB | 0101Wa 0000006781 | yes | HA_WAN_MWK_0,240_xxx | Mauerwerkswand | Mauerwerk | Mauerwerk | W001.2 | true | false | 0 | - | - | yes | HI_WAN_MWK_0,240_xxx
HI_WAN_MWK_0,240_xxx | EG_Technik_FFB | KS-XL-16-1.8/DM 0.24 m | HI_WAN_MWK_0,240_xxx | WI-ZIEGEL2\ | 0101HWa0000001881 | WI-KALKSAND2\ | Mauerarbeiten | Mauerwerkswand | KS-XL-16-1.8/DM | EG_Technik_FFB | 0101Wa 0000001886 | yes | HA_WAN_MWK_0,240_xxx | Mauerwerkswand | Mauerwerk | Mauerwerk | W001.2 | true | false | 0 | - | - | yes | HI_WAN_MWK_0,240_xxx
HI_WAN_MWK_0,240_xxx | EG_Technik_FFB | KS-XL-16-1.8/DM 0.24 m | HI_WAN_MWK_0,240_xxx | WI-ZIEGEL2\ | 0101HWa0000001727 | WI-KALKSAND2\ | Mauerarbeiten | Mauerwerkswand | KS-XL-16-1.8/DM | EG_Technik_FFB | 0101Wa 0000001729 | yes | HA_WAN_MWK_0,240_xxx | Mauerwerkswand | Mauerwerk | Mauerwerk | W001.2 | true | false | 0 | - | - | yes | HI_WAN_MWK_0,240_xxx
HI_WAN_MWK_0,240_xxx | EG_Technik_FFB | KS-XL-16-1.8/DM 0.24 m | HI_WAN_MWK_0,240_xxx | WI-ZIEGEL2\ | 0101HWa0000006881 | WI-KALKSAND2\ | Mauerarbeiten | Mauerwerkswand | KS-XL-16-1.8/DM | EG_Technik_FFB | 0101Wa 0000006882 | yes | HI_WAN_MWK_0,240_xxx | Mauerwerkswand | Mauerwerk | Mauerwerk | W001.1 | true | false | 0 | - | - | yes | HI_WAN_MWK_0,240_xxx
HI_WAN_MWK_0,240_xxx | EG_Technik_FFB | KS-XL-16-1.8/DM 0.24 m | HI_WAN_MWK_0,240_xxx | WI-ZIEGEL2\ | 0101HWa0000004494 | WI-KALKSAND2\ | Mauerarbeiten | Mauerwerkswand | KS-XL-16-1.8/DM | EG_Technik_FFB | 0101Wa 0000004495 | yes | HI_WAN_MWK_0,240_xxx | Mauerwerkswand | Mauerwerk | Mauerwerk | - | true | false | 0 | - | - | yes | HI_WAN_MWK_0,240_xxx
HI_WAN_MWK_0,240_xxx | EG_Technik_FFB | KS-XL-16-1.8/DM 0.24 m | HI_WAN_MWK_0,240_xxx | WI-ZIEGEL2\ | 0101HWa0000000060 | WI-KALKSAND2\ | Mauerarbeiten | Mauerwerkswand | KS-XL-16-1.8/DM | EG_Technik_FFB | 0101Wa 0000000154 | yes | HI_WAN_MWK_0,240_xxx | Mauerwerkswand | Mauerwerk | Mauerwerk | W001.1 | true | false | 0 | - | - | yes | HI_WAN_MWK_0,240_xxx
HI_WAN_MWK_0,240_xxx | EG_Technik_FFB | KS-XL-16-1.8/DM 0.24 m | HI_WAN_MWK_0,240_xxx | WI-ZIEGEL2\ | 0101HWa0000000068 | WI-KALKSAND2\ | Mauerarbeiten | Mauerwerkswand | KS-XL-16-1.8/DM | EG_Technik_FFB | 0101Wa 0000000169 | yes | HI_WAN_MWK_0,240_xxx | Mauerwerkswand | Mauerwerk | Mauerwerk | W001.1 | true | false | 0 | - | - | yes | HI_WAN_MWK_0,240_xxx
HI_WAN_MWK_0,240_xxx | EG_Technik_FFB | KS-XL-16-1.8/DM 0.24 m | HI_WAN_MWK_0,240_xxx | WI-ZIEGEL2\ | 0101HWa0000000641 | WI-KALKSAND2\ | Mauerarbeiten | Mauerwerkswand | KS-XL-16-1.8/DM | EG_Technik_FFB | 0101Wa 0000000643 | yes | HI_WAN_MWK_0,240_xxx | Mauerwerkswand | Mauerwerk | Mauerwerk | W001.1 | false | false | 0 | - | - | yes | HI_WAN_MWK_0,240_xxx
HI_WAN_MWK_0,240_xxx | EG_Technik_FFB | KS-XL-16-1.8/DM 0.24 m | HI_WAN_MWK_0,240_xxx | WI-ZIEGEL2\ | 0101HWa0000000034 | WI-KALKSAND2\ | Mauerarbeiten | Mauerwerkswand | KS-XL-16-1.8/DM | EG_Technik_FFB | 0101Wa 0000000212 | yes | HI_WAN_MWK_0,240_xxx | Mauerwerkswand | Mauerwerk | Mauerwerk | W001.1 | false | false | 0 | - | - | yes | HI_WAN_MWK_0,240_xxx
HI_WAN_MWK_0,240_xxx | EG_Technik_FFB | KS-XL-16-1.8/DM 0.24 m | HI_WAN_MWK_0,240_xxx | WI-ZIEGEL2\ | 0101HWa0000000028 | WI-KALKSAND2\ | Mauerarbeiten | Mauerwerkswand | KS-XL-16-1.8/DM | EG_Technik_FFB | 0101Wa 0000000188 | yes | HI_WAN_MWK_0,240_xxx | Mauerwerkswand | Mauerwerk | Mauerwerk | W001.1 | false | false | 0 | - | - | yes | HI_WAN_MWK_0,240_xxx
HI_WAN_MWK_0,240_xxx | EG_Technik_FFB | KS-XL-16-1.8/DM 0.24 m | HI_WAN_MWK_0,240_xxx | WI-ZIEGEL2\ | 0101HWa0000000036 | WI-KALKSAND2\ | Mauerarbeiten | Mauerwerkswand | KS-XL-16-1.8/DM | EG_Technik_FFB | 0101Wa 0000000210 | yes | HI_WAN_MWK_0,240_xxx | Mauerwerkswand | Mauerwerk | Mauerwerk | W001.1 | false | false | 0 | - | - | yes | HI_WAN_MWK_0,240_xxx
HI_WAN_MWK_0,240_xxx | EG_Technik_FFB | KS-XL-16-1.8/DM 0.24 m | HI_WAN_MWK_0,240_xxx | WI-ZIEGEL2\ | 0101HWa0000000038 | WI-KALKSAND2\ | Mauerarbeiten | Mauerwerkswand | KS-XL-16-1.8/DM | EG_Technik_FFB | 0101Wa 0000000208 | yes | HI_WAN_MWK_0,240_xxx | Mauerwerkswand | Mauerwerk | Mauerwerk | W001.1 | false | false | 0 | - | - | yes | HI_WAN_MWK_0,240_xxx
HI_WAN_MWK_0,240_xxx | EG_Technik_FFB | KS-XL-16-1.8/DM 0.24 m | HI_WAN_MWK_0,240_xxx | WI-ZIEGEL2\ | 0101HWa0000006693 | WI-KALKSAND2\ | Mauerarbeiten | Mauerwerkswand | KS-XL-16-1.8/DM | EG_Technik_FFB | 0101Wa 0000006694 | yes | HA_WAN_MWK_0,240_xxx | Mauerwerkswand | Mauerwerk | Mauerwerk | W001.2 | true | false | 0 | - | - | yes | HI_WAN_MWK_0,240_xxx
HI_WAN_MWK_0,240_xxx | EG_Technik_FFB | KS-XL-16-1.8/DM 0.24 m | HI_WAN_MWK_0,240_xxx | WI-ZIEGEL2\ | 0101HWa0000007193 | WI-KALKSAND2\ | Mauerarbeiten | Mauerwerkswand | KS-XL-16-1.8/DM | EG_Technik_FFB | 0101Wa 0000007195 | yes | HA_WAN_MWK_0,240_xxx | Mauerwerkswand | Mauerwerk | Mauerwerk | W001.2 | true | false | 0 | - | - | yes | HI_WAN_MWK_0,240_xxx
HI_WAN_MWK_0,240_xxx | EG_Technik_FFB | KS-XL-16-1.8/DM 0.24 m | HI_WAN_MWK_0,240_xxx | WI-ZIEGEL2\ | 0101HWa0000000032 | WI-KALKSAND2\ | Mauerarbeiten | Mauerwerkswand | KS-XL-16-1.8/DM | EG_Technik_FFB | 0101Wa 0000000199 | yes | HI_WAN_MWK_0,240_xxx | Mauerwerkswand | Mauerwerk | Mauerwerk | W001.1 | true | false | 0 | - | - | yes | HI_WAN_MWK_0,240_xxx
HI_WAN_MWK_0,240_xxx | EG_Technik_FFB | KS-XL-16-1.8/DM 0.24 m | HI_WAN_MWK_0,240_xxx | WI-ZIEGEL2\ | 0101HWa0000007415 | WI-KALKSAND2\ | Mauerarbeiten | Mauerwerkswand | KS-XL-16-1.8/DM | EG_Technik_FFB | 0101Wa 0000007416 | yes | HA_WAN_MWK_0,240_xxx | Mauerwerkswand | Mauerwerk | Mauerwerk | W001.2 | true | false | 0 | - | - | yes | HI_WAN_MWK_0,240_xxx
HI_WAN_MWK_0,240_xxx | EG_Technik_FFB | KS-XL-16-1.8/DM 0.24 m | HI_WAN_MWK_0,240_xxx | WI-ZIEGEL2\ | 0101HWa0000007350 | WI-KALKSAND2\ | Mauerarbeiten | Mauerwerkswand | KS-XL-16-1.8/DM | EG_Technik_FFB | 0101Wa 0000007351 | yes | HI_WAN_MWK_0,240_xxx | Mauerwerkswand | Mauerwerk | Mauerwerk | W001.1 | true | false | 0 | - | - | yes | HI_WAN_MWK_0,240_xxx
HI_WAN_MWK_0,240_xxx | EG_Technik_FFB | KS-XL-16-1.8/DM 0.24 m | HI_WAN_MWK_0,240_xxx | WI-ZIEGEL2\ | 0101HWa0000007539 | WI-KALKSAND2\ | Mauerarbeiten | Mauerwerkswand | KS-XL-16-1.8/DM | EG_Technik_FFB | 0101Wa 0000007549 | yes | HI_WAN_MWK_0,240_xxx | Mauerwerkswand | Mauerwerk | Mauerwerk | W001.1 | true | false | 0 | - | - | yes | HI_WAN_MWK_0,240_xxx
HI_WAN_MWK_0,240_xxx | EG_Technik_FFB | KS-XL-16-1.8/DM 0.24 m | HI_WAN_MWK_0,240_xxx | WI-ZIEGEL2\ | 0101HWa0000007219 | WI-KALKSAND2\ | Mauerarbeiten | Mauerwerkswand | KS-XL-16-1.8/DM | EG_Technik_FFB | 0101Wa 0000007230 | yes | HI_WAN_MWK_0,240_xxx | Mauerwerkswand | Mauerwerk | Mauerwerk | W001.1 | true | false | 0 | - | - | yes | HI_WAN_MWK_0,240_xxx
HI_WAN_MWK_0,240_xxx | EG_Technik_FFB | KS-XL-16-1.8/DM 0.24 m | HI_WAN_MWK_0,240_xxx | WI-ZIEGEL2\ | 0101HWa0000000009 | WI-KALKSAND2\ | Mauerarbeiten | Mauerwerkswand | KS-XL-16-1.8/DM | EG_Technik_FFB | 0101Wa 0000000214 | yes | HA_WAN_MWK_0,240_xxx | Mauerwerkswand | Mauerwerk | Mauerwerk | W001.2 | true | false | 0 | - | - | yes | HI_WAN_MWK_0,240_xxx
HI_WAN_MWK_0,240_xxx | EG_Technik_FFB | KS-XL-16-1.8/DM 0.24 m | HI_WAN_MWK_0,240_xxx | WI-ZIEGEL2\ | 0101HWa0000000014 | WI-KALKSAND2\ | Mauerarbeiten | Mauerwerkswand | KS-XL-16-1.8/DM | EG_Technik_FFB | 0101Wa 0000000206 | yes | HI_WAN_MWK_0,240_xxx | Mauerwerkswand | Mauerwerk | Mauerwerk | - | true | false | 0 | - | - | yes | HI_WAN_MWK_0,240_xxx
HI_WAN_MWK_0,240_xxx | EG_Technik_FFB | KS-XL-16-1.8/DM 0.24 m | HI_WAN_MWK_0,240_xxx | WI-ZIEGEL2\ | 0101HWa0000007736 | WI-KALKSAND2\ | Mauerarbeiten | Mauerwerkswand | KS-XL-16-1.8/DM | EG_Technik_FFB | 0101Wa 0000007740 | yes | HA_WAN_MWK_0,240_xxx | Mauerwerkswand | Mauerwerk | Mauerwerk | W001.2 | true | false | 0 | - | - | yes | HI_WAN_MWK_0,240_xxx
HI_WAN_MWK_0,240_xxx | EG_Technik_FFB | KS-XL-16-1.8/DM 0.24 m | HI_WAN_MWK_0,240_xxx | WI-ZIEGEL2\ | 0101HWa0000007619 | WI-KALKSAND2\ | Mauerarbeiten | Mauerwerkswand | KS-XL-16-1.8/DM | EG_Technik_FFB | 0101Wa 0000007621 | yes | HA_WAN_MWK_0,240_xxx | Mauerwerkswand | Mauerwerk | Mauerwerk | W001.2 | true | false | 0 | - | - | yes | HI_WAN_MWK_0,240_xxx
HI_WAN_MWK_0,240_xxx | EG_Technik_FFB | KS-XL-16-1.8/DM 0.24 m | HI_WAN_MWK_0,240_xxx | WI-ZIEGEL2\ | 0101HWa0000006631 | WI-KALKSAND2\ | Mauerarbeiten | Mauerwerkswand | KS-XL-16-1.8/DM | EG_Technik_FFB | 0101Wa 0000006632 | yes | HA_WAN_MWK_0,240_xxx | Mauerwerkswand | Mauerwerk | Mauerwerk | W001.2 | true | false | 0 | - | - | yes | HI_WAN_MWK_0,240_xxx
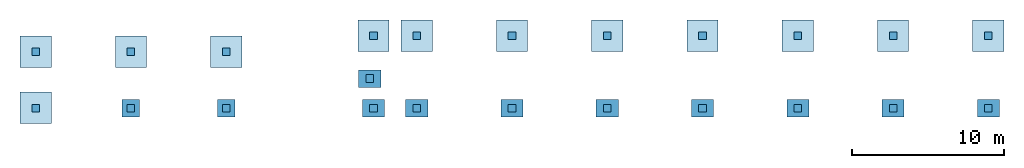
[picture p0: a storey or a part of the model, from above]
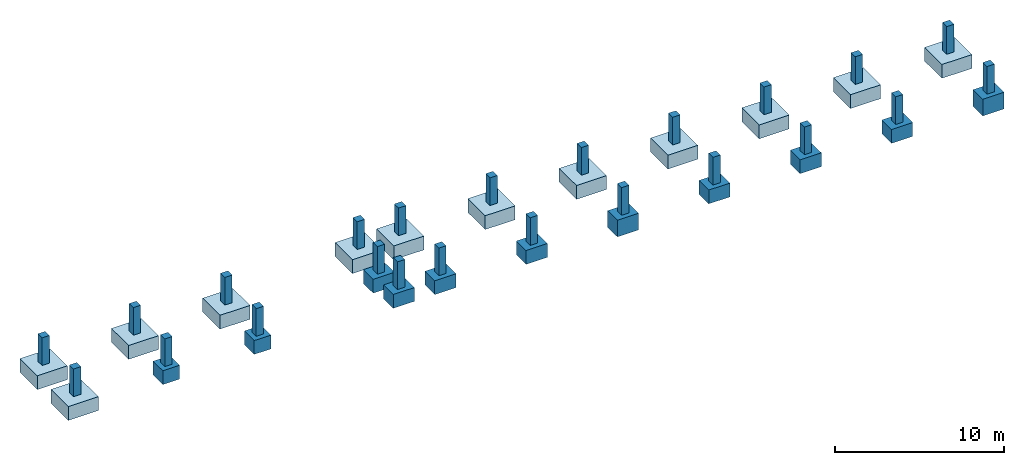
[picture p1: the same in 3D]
Properties of the parts of a building model (IFC2X3), part 25 of 25

# IfcWallStandardCase (119)
Name | In | Material | Bezeichnung | MEP Wandtyp | Allright_Bauteil_ID | Object Layer Attributes #1, Codetext | Object Layer Attributes #1, Gewerk | Object Layer Attributes #1, Bezeichnung | Object Layer Attributes #1, Material | Object Layer Attributes #1, Ebene | Object Layer Attributes #1, Allright_Bauteil_ID | Object Layer Attributes #1, WallCommon, Raumhohe Wand | Object Layer Attributes #1, WallCommon, Reference | Name | IFC_Pset_TWP, Material | Herstellung | Positionsnummer | statisch tragend | Außenbauteil | Bewehrungsgrad | Expositionsklasse | Druckfestigkeitsklasse | ExtendToStructure | Reference
HI_WAN_MWK_0,240_xxx | EG_Technik_FFB | KS-XL-16-1.8/DM 0.24 m | HI_WAN_MWK_0,240_xxx | WI-ZIEGEL2\ | 0101HWa0000007360 | WI-KALKSAND2\ | Mauerarbeiten | Mauerwerkswand | KS-XL-16-1.8/DM | EG_Technik_FFB | 0101Wa 0000007361 | yes | HI_WAN_MWK_0,240_xxx | Mauerwerkswand | Mauerwerk | Mauerwerk | W001.1 | true | false | 0 | - | - | yes | HI_WAN_MWK_0,240_xxx
HI_WAN_MWK_0,240_xxx | EG_Technik_FFB | KS-XL-16-1.8/DM 0.24 m | HI_WAN_MWK_0,240_xxx | WI-ZIEGEL2\ | 0101HWa0000007368 | WI-KALKSAND2\ | Mauerarbeiten | Mauerwerkswand | KS-XL-16-1.8/DM | EG_Technik_FFB | 0101Wa 0000007369 | yes | HI_WAN_MWK_0,240_xxx | Mauerwerkswand | Mauerwerk | Mauerwerk | W001.1 | true | false | 0 | - | - | yes | HI_WAN_MWK_0,240_xxx
HI_WAN_MWK_0,240_xxx | EG_Technik_FFB | KS-XL-16-1.8/DM 0.24 m | HI_WAN_MWK_0,240_xxx | WI-ZIEGEL2\ | 0101HWa0000000030 | WI-KALKSAND2\ | Mauerarbeiten | Mauerwerkswand | KS-XL-16-1.8/DM | EG_Technik_FFB | 0101Wa 0000000197 | yes | HI_WAN_MWK_0,240_xxx | Mauerwerkswand | Mauerwerk | Mauerwerk | W001.1 | true | false | 0 | - | - | yes | HI_WAN_MWK_0,240_xxx
HI_WAN_MWK_0,240_xxx | EG_Technik_FFB | KS-XL-16-1.8/DM 0.24 m | HI_WAN_MWK_0,240_xxx | WI-ZIEGEL2\ | 0101HWa0000002678 | WI-KALKSAND2\ | Mauerarbeiten | Mauerwerkswand | KS-XL-16-1.8/DM | EG_Technik_FFB | 0101Wa 0000002679 | yes | HA_WAN_MWK_0,240_xxx | Mauerwerkswand | Mauerwerk | Mauerwerk | W001.2 | true | false | 0 | - | - | yes | HI_WAN_MWK_0,240_xxx
HI_WAN_MWK_0,240_xxx | EG_Technik_FFB | KS-XL-16-1.8/DM 0.24 m | HI_WAN_MWK_0,240_xxx | WI-ZIEGEL2\ | 0101HWa0000002694 | WI-KALKSAND2\ | Mauerarbeiten | Mauerwerkswand | KS-XL-16-1.8/DM | EG_Technik_FFB | 0101Wa 0000002695 | yes | HA_WAN_MWK_0,240_xxx | Mauerwerkswand | Mauerwerk | Mauerwerk | W001.2 | true | false | 0 | - | - | yes | HI_WAN_MWK_0,240_xxx
HI_WAN_MWK_0,240_xxx | EG_Technik_FFB | KS-XL-16-1.8/DM 0.24 m | HI_WAN_MWK_0,240_xxx | WI-ZIEGEL2\ | 0101HWa0000006511 | WI-KALKSAND2\ | Mauerarbeiten | Mauerwerkswand | KS-XL-16-1.8/DM | EG_Technik_FFB | 0101Wa 0000006512 | yes | HA_WAN_MWK_0,240_xxx | Mauerwerkswand | Mauerwerk | Mauerwerk | W001.2 | true | false | 0 | - | - | yes | HI_WAN_MWK_0,240_xxx
HI_WAN_MWK_0,240_xxx | EG_Technik_FFB | KS-XL-16-1.8/DM 0.24 m | HI_WAN_MWK_0,240_xxx | WI-ZIEGEL2\ | 0101HWa0000000011 | WI-KALKSAND2\ | Mauerarbeiten | Mauerwerkswand | KS-XL-16-1.8/DM | EG_Technik_FFB | 0101Wa 0000000201 | yes | HA_WAN_MWK_0,240_xxx | Mauerwerkswand | Mauerwerk | Mauerwerk | W001.2 | true | false | 0 | - | - | yes | HI_WAN_MWK_0,240_xxx
HI_WAN_MWK_0,240_xxx | EG_Technik_FFB | KS-XL-16-1.8/DM 0.24 m | HI_WAN_MWK_0,240_xxx | WI-ZIEGEL2\ | 0101HWa0000007916 | WI-KALKSAND2\ | Mauerarbeiten | Mauerwerkswand | KS-XL-16-1.8/DM | EG_Technik_FFB | 0101Wa 0000007917 | yes | HA_WAN_MWK_0,240_xxx | Mauerwerkswand | Mauerwerk | Mauerwerk | W001.2 | true | false | 0 | - | - | yes | HI_WAN_MWK_0,240_xxx
HI_WAN_MWK_0,240_xxx | EG_Technik_FFB | KS-XL-16-1.8/DM 0.24 m | HI_WAN_MWK_0,240_xxx | WI-ZIEGEL2\ | 0101HWa0000007926 | WI-KALKSAND2\ | Mauerarbeiten | Mauerwerkswand | KS-XL-16-1.8/DM | EG_Technik_FFB | 0101Wa 0000007927 | yes | HA_WAN_MWK_0,240_xxx | Mauerwerkswand | Mauerwerk | Mauerwerk | W001.2 | true | false | 0 | - | - | yes | HI_WAN_MWK_0,240_xxx
HI_WAN_MWK_0,240_xxx | EG_Technik_FFB | KS-XL-16-1.8/DM 0.24 m | HI_WAN_MWK_0,240_xxx | WI-ZIEGEL2\ | 0101HWa0000007945 | WI-KALKSAND2\ | Mauerarbeiten | Mauerwerkswand | KS-XL-16-1.8/DM | EG_Technik_FFB | 0101Wa 0000007946 | yes | HA_WAN_MWK_0,240_xxx | Mauerwerkswand | Mauerwerk | Mauerwerk | W001.2 | true | false | 0 | - | - | yes | HI_WAN_MWK_0,240_xxx
HI_WAN_MWK_0,240_xxx | EG_Technik_FFB | KS-XL-16-1.8/DM 0.24 m | HI_WAN_MWK_0,240_xxx | WI-ZIEGEL2\ | 0101HWa0000007984 | WI-KALKSAND2\ | Mauerarbeiten | Mauerwerkswand | KS-XL-16-1.8/DM | EG_Technik_FFB | 0101Wa 0000007985 | yes | HA_WAN_MWK_0,240_xxx | Mauerwerkswand | Mauerwerk | Mauerwerk | W001.2 | true | false | 0 | - | - | yes | HI_WAN_MWK_0,240_xxx
HI_WAN_MWK_0,240_xxx | EG_Technik_FFB | KS-XL-16-1.8/DM 0.24 m | HI_WAN_MWK_0,240_xxx | WI-ZIEGEL2\ | 0101HWa0000007999 | WI-KALKSAND2\ | Mauerarbeiten | Mauerwerkswand | KS-XL-16-1.8/DM | EG_Technik_FFB | 0101Wa 0000008002 | yes | HA_WAN_MWK_0,240_xxx | Mauerwerkswand | Mauerwerk | Mauerwerk | W001.2 | true | false | 0 | - | - | yes | HI_WAN_MWK_0,240_xxx
HI_WAN_MWK_0,240_xxx | EG_Technik_FFB | KS-XL-16-1.8/DM 0.24 m | HI_WAN_MWK_0,240_xxx | WI-ZIEGEL2\ | 0101HWa0000008038 | WI-KALKSAND2\ | Mauerarbeiten | Mauerwerkswand | KS-XL-16-1.8/DM | EG_Technik_FFB | 0101Wa 0000008039 | yes | HA_WAN_MWK_0,240_xxx | Mauerwerkswand | Mauerwerk | Mauerwerk | W001.2 | true | false | 0 | - | - | yes | HI_WAN_MWK_0,240_xxx
HI_WAN_MWK_0,240_xxx | EG_Technik_FFB | KS-XL-16-1.8/DM 0.24 m | HI_WAN_MWK_0,240_xxx | WI-ZIEGEL2\ | 0101HWa0000008077 | WI-KALKSAND2\ | Mauerarbeiten | Mauerwerkswand | KS-XL-16-1.8/DM | EG_Technik_FFB | 0101Wa 0000008078 | yes | HA_WAN_MWK_0,240_xxx | Mauerwerkswand | Mauerwerk | Mauerwerk | W001.2 | true | false | 0 | - | - | yes | HI_WAN_MWK_0,240_xxx
HI_WAN_MWK_0,240_xxx | EG_Technik_FFB | KS-XL-16-1.8/DM 0.24 m | HI_WAN_MWK_0,240_xxx | WI-ZIEGEL2\ | 0101HWa0000008103 | WI-KALKSAND2\ | Mauerarbeiten | Mauerwerkswand | KS-XL-16-1.8/DM | EG_Technik_FFB | 0101Wa 0000008104 | yes | HA_WAN_MWK_0,240_xxx | Mauerwerkswand | Mauerwerk | Mauerwerk | W001.2 | true | false | 0 | - | - | yes | HI_WAN_MWK_0,240_xxx
HI_WAN_MWK_0,240_xxx | EG_Technik_FFB | KS-XL-16-1.8/DM 0.24 m | HI_WAN_MWK_0,240_xxx | WI-ZIEGEL2\ | 0101HWa0000008108 | WI-KALKSAND2\ | Mauerarbeiten | Mauerwerkswand | KS-XL-16-1.8/DM | EG_Technik_FFB | 0101Wa 0000008110 | yes | HA_WAN_MWK_0,240_xxx | Mauerwerkswand | Mauerwerk | Mauerwerk | W001.2 | true | false | 0 | - | - | yes | HI_WAN_MWK_0,240_xxx
Stb.-Rahmen | EG_Produktion_FFB | Stahlbeton 0.3 m | Stb.-Rahmen | WA-STB1\ | 0111HWa0000617900 | WA-STB1\ | Betonarbeiten | Stb.-Rahmen | Stahlbeton | EG_Produktion_FFB | 0111Wa 0000617909 |  |  | Stb.-Rahmen | Stahlbeton | Ortbeton | RA001 und RA002 | true | true | 50 | XC4, XD1, XF2, WF | C35/45 |  | HA_WAN_STB_0,300_xxx | AllplanAttributes - Object Layer Attributes #1, Ausführung: Ortbeton; Object Layer Attributes #1, Reference: HA_WAN_STB_0,300_xxx; Object Layer Attributes #1, Attributset-Objekt: Wand; Pset_ConcreteElementGeneral - Betonüberdeckung: 1
Stb.-Rahmen | EG_Produktion_FFB | Stahlbeton 0.3 m | Stb.-Rahmen | WA-STB1\ | 0111HWa0000617899 | WA-STB1\ | Betonarbeiten | Stb.-Rahmen | Stahlbeton | EG_Produktion_FFB | 0111Wa 0000617908 |  |  | Stb.-Rahmen | Stahlbeton | Ortbeton | RA001 und RA002 | true | true | 50 | XC4, XD1, XF2, WF | C35/45 |  | HA_WAN_STB_0,300_xxx | AllplanAttributes - Object Layer Attributes #1, Ausführung: Ortbeton; Object Layer Attributes #1, Reference: HA_WAN_STB_0,300_xxx; Object Layer Attributes #1, Attributset-Objekt: Wand; Pset_ConcreteElementGeneral - Betonüberdeckung: 1
Stb.-Rahmen | EG_Produktion_FFB | Stahlbeton 0.3 m | Stb.-Rahmen | WA-STB1\ | 0111HWa0000618130 | WA-STB1\ | Betonarbeiten | Stb.-Rahmen | Stahlbeton | EG_Produktion_FFB | 0111Wa 0000618131 |  |  | Stb.-Rahmen | Stahlbeton | Ortbeton | RA001 und RA002 | true | true | 50 | XC4, XD1, XF2, WF | C35/45 |  | HA_WAN_STB_0,300_xxx | AllplanAttributes - Object Layer Attributes #1, Ausführung: Ortbeton; Object Layer Attributes #1, Reference: HA_WAN_STB_0,300_xxx; Object Layer Attributes #1, Attributset-Objekt: Wand; Pset_ConcreteElementGeneral - Betonüberdeckung: 1
Stb.-Rahmen | EG_Produktion_FFB | Stahlbeton 0.3 m | Stb.-Rahmen | WA-STB1\ | 0111HWa0000617898 | WA-STB1\ | Betonarbeiten | Stb.-Rahmen | Stahlbeton | EG_Produktion_FFB | 0111Wa 0000617907 |  |  | Stb.-Rahmen | Stahlbeton | Ortbeton | RA001 und RA002 | true | true | 50 | XC4, XD1, XF2, WF | C35/45 |  | HA_WAN_STB_0,300_xxx | AllplanAttributes - Object Layer Attributes #1, Ausführung: Ortbeton; Object Layer Attributes #1, Reference: HA_WAN_STB_0,300_xxx; Object Layer Attributes #1, Attributset-Objekt: Wand; Pset_ConcreteElementGeneral - Betonüberdeckung: 1
Stb.-Rahmen | EG_Produktion_FFB | Stahlbeton 0.3 m | Stb.-Rahmen | WA-STB1\ | 0111HWa0000617897 | WA-STB1\ | Betonarbeiten | Stb.-Rahmen | Stahlbeton | EG_Produktion_FFB | 0111Wa 0000617906 |  |  | Stb.-Rahmen | Stahlbeton | Ortbeton | RA001 und RA002 | true | true | 50 | XC4, XD1, XF2, WF | C35/45 |  | HA_WAN_STB_0,300_xxx | AllplanAttributes - Object Layer Attributes #1, Ausführung: Ortbeton; Object Layer Attributes #1, Reference: HA_WAN_STB_0,300_xxx; Object Layer Attributes #1, Attributset-Objekt: Wand; Pset_ConcreteElementGeneral - Betonüberdeckung: 1
Stb.-Rahmen | EG_Produktion_FFB | Stahlbeton 0.3 m | Stb.-Rahmen | WA-STB1\ | 0111HWa0000617880 | WA-STB1\ | Betonarbeiten | Stb.-Rahmen | Stahlbeton | EG_Produktion_FFB | 0111Wa 0000617889 |  |  | Stb.-Rahmen | Stahlbeton | Ortbeton | RA001 und RA002 | true | true | 50 | XC4, XD1, XF2, WF | C35/45 |  | HA_WAN_STB_0,300_xxx | AllplanAttributes - Object Layer Attributes #1, Ausführung: Ortbeton; Object Layer Attributes #1, Reference: HA_WAN_STB_0,300_xxx; Object Layer Attributes #1, Attributset-Objekt: Wand; Pset_ConcreteElementGeneral - Betonüberdeckung: 1
Stb.-Rahmen | EG_Produktion_FFB | Stahlbeton 0.3 m | Stb.-Rahmen | WA-STB1\ | 0111HWa0000617879 | WA-STB1\ | Betonarbeiten | Stb.-Rahmen | Stahlbeton | EG_Produktion_FFB | 0111Wa 0000617888 |  |  | Stb.-Rahmen | Stahlbeton | Ortbeton | RA001 und RA002 | true | true | 50 | XC4, XD1, XF2, WF | C35/45 |  | HA_WAN_STB_0,300_xxx | AllplanAttributes - Object Layer Attributes #1, Ausführung: Ortbeton; Object Layer Attributes #1, Reference: HA_WAN_STB_0,300_xxx; Object Layer Attributes #1, Attributset-Objekt: Wand; Pset_ConcreteElementGeneral - Betonüberdeckung: 1
Stb.-Rahmen | EG_Produktion_FFB | Stahlbeton 0.3 m | Stb.-Rahmen | WA-STB1\ | 0111HWa0000618235 | WA-STB1\ | Betonarbeiten | Stb.-Rahmen | Stahlbeton | EG_Produktion_FFB | 0111Wa 0000618237 |  |  | Stb.-Rahmen | Stahlbeton | Ortbeton | RA001 und RA002 | true | true | 50 | XC4, XD1, XF2, WF | C35/45 |  | HA_WAN_STB_0,300_xxx | AllplanAttributes - Object Layer Attributes #1, Ausführung: Ortbeton; Object Layer Attributes #1, Reference: HA_WAN_STB_0,300_xxx; Object Layer Attributes #1, Attributset-Objekt: Wand; Pset_ConcreteElementGeneral - Betonüberdeckung: 1
Stb.-Rahmen | EG_Produktion_FFB | Stahlbeton 0.3 m | Stb.-Rahmen | WA-STB1\ | 0111HWa0000617878 | WA-STB1\ | Betonarbeiten | Stb.-Rahmen | Stahlbeton | EG_Produktion_FFB | 0111Wa 0000617887 |  |  | Stb.-Rahmen | Stahlbeton | Ortbeton | RA001 und RA002 | true | true | 50 | XC4, XD1, XF2, WF | C35/45 |  | HA_WAN_STB_0,300_xxx | AllplanAttributes - Object Layer Attributes #1, Ausführung: Ortbeton; Object Layer Attributes #1, Reference: HA_WAN_STB_0,300_xxx; Object Layer Attributes #1, Attributset-Objekt: Wand; Pset_ConcreteElementGeneral - Betonüberdeckung: 1
Stb.-Rahmen | EG_Produktion_FFB | Stahlbeton 0.3 m | Stb.-Rahmen | WA-STB1\ | 0111HWa0000617877 | WA-STB1\ | Betonarbeiten | Stb.-Rahmen | Stahlbeton | EG_Produktion_FFB | 0111Wa 0000617886 |  |  | Stb.-Rahmen | Stahlbeton | Ortbeton | RA001 und RA002 | true | true | 50 | XC4, XD1, XF2, WF | C35/45 |  | HA_WAN_STB_0,300_xxx | AllplanAttributes - Object Layer Attributes #1, Ausführung: Ortbeton; Object Layer Attributes #1, Reference: HA_WAN_STB_0,300_xxx; Object Layer Attributes #1, Attributset-Objekt: Wand; Pset_ConcreteElementGeneral - Betonüberdeckung: 1
Stb.-Rahmen | EG_Produktion_FFB | Stahlbeton 0.3 m | Stb.-Rahmen | WA-STB1\ | 0111HWa0000617840 | WA-STB1\ | Betonarbeiten | Stb.-Rahmen | Stahlbeton | EG_Produktion_FFB | 0111Wa 0000617843 |  |  | Stb.-Rahmen | Stahlbeton | Ortbeton | RA001 und RA002 | true | true | 50 | XC4, XD1, XF2, WF | C35/45 |  | HA_WAN_STB_0,300_xxx | AllplanAttributes - Object Layer Attributes #1, Ausführung: Ortbeton; Object Layer Attributes #1, Reference: HA_WAN_STB_0,300_xxx; Object Layer Attributes #1, Attributset-Objekt: Wand; Pset_ConcreteElementGeneral - Betonüberdeckung: 1
Stb.-Rahmen | EG_Produktion_FFB | Stahlbeton 0.3 m | Stb.-Rahmen | WA-STB1\ | 0111HWa0000617839 | WA-STB1\ | Betonarbeiten | Stb.-Rahmen | Stahlbeton | EG_Produktion_FFB | 0111Wa 0000617844 |  |  | Stb.-Rahmen | Stahlbeton | Ortbeton | RA001 und RA002 | true | true | 50 | XC4, XD1, XF2, WF | C35/45 |  | HA_WAN_STB_0,300_xxx | AllplanAttributes - Object Layer Attributes #1, Ausführung: Ortbeton; Object Layer Attributes #1, Reference: HA_WAN_STB_0,300_xxx; Object Layer Attributes #1, Attributset-Objekt: Wand; Pset_ConcreteElementGeneral - Betonüberdeckung: 1
HA_WAN_STB_0,300_xxx | EG_Produktion_FFB | Stahlbeton 0.3 m | HA_WAN_STB_0,300_xxx | WA-STB1\ | 0111HWa0000618248 | WA-STB1\ | Betonarbeiten | Stb.-Rahmen | Stahlbeton | EG_Produktion_FFB | 0111Wa 0000618250 |  |  | Stb.-Rahmen | Stahlbeton | Ortbeton | RA001 und RA002 | true | true | 50 | XC4, XD1, XF2, WF | C35/45 |  | HA_WAN_STB_0,300_xxx | AllplanAttributes - Object Layer Attributes #1, Ausführung: Ortbeton; Object Layer Attributes #1, Reference: HA_WAN_STB_0,300_xxx; Object Layer Attributes #1, Attributset-Objekt: Wand; Pset_ConcreteElementGeneral - Betonüberdeckung: 1
Stb.-Rahmen | EG_Produktion_FFB | Stahlbeton 0.3 m | Stb.-Rahmen | WA-STB1\ | 0111HWa0000617838 | WA-STB1\ | Betonarbeiten | Stb.-Rahmen | Stahlbeton | EG_Produktion_FFB | 0111Wa 0000617845 |  |  | Stb.-Rahmen | Stahlbeton | Ortbeton | RA001 und RA002 | true | true | 50 | XC4, XD1, XF2, WF | C35/45 |  | HA_WAN_STB_0,300_xxx | AllplanAttributes - Object Layer Attributes #1, Ausführung: Ortbeton; Object Layer Attributes #1, Reference: HA_WAN_STB_0,300_xxx; Object Layer Attributes #1, Attributset-Objekt: Wand; Pset_ConcreteElementGeneral - Betonüberdeckung: 1
Stb.-Rahmen | EG_Produktion_FFB | Stahlbeton 0.3 m | Stb.-Rahmen | WA-STB1\ | 0111HWa0000617837 | WA-STB1\ | Betonarbeiten | Stb.-Rahmen | Stahlbeton | EG_Produktion_FFB | 0111Wa 0000617846 |  |  | Stb.-Rahmen | Stahlbeton | Ortbeton | RA001 und RA002 | true | true | 50 | XC4, XD1, XF2, WF | C35/45 |  | HA_WAN_STB_0,300_xxx | AllplanAttributes - Object Layer Attributes #1, Ausführung: Ortbeton; Object Layer Attributes #1, Reference: HA_WAN_STB_0,300_xxx; Object Layer Attributes #1, Attributset-Objekt: Wand; Pset_ConcreteElementGeneral - Betonüberdeckung: 1
Stb.-Rahmen | EG_Produktion_FFB | Stahlbeton 0.3 m | Stb.-Rahmen | WA-STB1\ | 0111HWa0000617744 | WA-STB1\ | Betonarbeiten | Stb.-Rahmen | Stahlbeton | EG_Produktion_FFB | 0111Wa 0000617749 |  |  | Stb.-Rahmen | Stahlbeton | Ortbeton | RA001 und RA002 | true | true | 50 | XC4, XD1, XF2, WF | C35/45 |  | HA_WAN_STB_0,300_xxx | AllplanAttributes - Object Layer Attributes #1, Ausführung: Ortbeton; Object Layer Attributes #1, Reference: HA_WAN_STB_0,300_xxx; Object Layer Attributes #1, Attributset-Objekt: Wand; Pset_ConcreteElementGeneral - Betonüberdeckung: 1
Stb.-Rahmen | EG_Produktion_FFB | Stahlbeton 0.3 m | Stb.-Rahmen | WA-STB1\ | 0111HWa0000617743 | WA-STB1\ | Betonarbeiten | Stb.-Rahmen | Stahlbeton | EG_Produktion_FFB | 0111Wa 0000617750 |  |  | Stb.-Rahmen | Stahlbeton | Ortbeton | RA001 und RA002 | true | true | 50 | XC4, XD1, XF2, WF | C35/45 |  | HA_WAN_STB_0,300_xxx | AllplanAttributes - Object Layer Attributes #1, Ausführung: Ortbeton; Object Layer Attributes #1, Reference: HA_WAN_STB_0,300_xxx; Object Layer Attributes #1, Attributset-Objekt: Wand; Pset_ConcreteElementGeneral - Betonüberdeckung: 1
Stb.-Rahmen | EG_Produktion_FFB | Stahlbeton 0.3 m | Stb.-Rahmen | WA-STB1\ | 0111HWa0000618261 | WA-STB1\ | Betonarbeiten | Stb.-Rahmen | Stahlbeton | EG_Produktion_FFB | 0111Wa 0000618263 |  |  | Stb.-Rahmen | Stahlbeton | Ortbeton | RA001 und RA002 | true | true | 50 | XC4, XD1, XF2, WF | C35/45 |  | HA_WAN_STB_0,300_xxx | AllplanAttributes - Object Layer Attributes #1, Ausführung: Ortbeton; Object Layer Attributes #1, Reference: HA_WAN_STB_0,300_xxx; Object Layer Attributes #1, Attributset-Objekt: Wand; Pset_ConcreteElementGeneral - Betonüberdeckung: 1
Stb.-Rahmen | EG_Produktion_FFB | Stahlbeton 0.3 m | Stb.-Rahmen | WA-STB1\ | 0111HWa0000617742 | WA-STB1\ | Betonarbeiten | Stb.-Rahmen | Stahlbeton | EG_Produktion_FFB | 0111Wa 0000617751 |  |  | Stb.-Rahmen | Stahlbeton | Ortbeton | RA001 und RA002 | true | true | 50 | XC4, XD1, XF2, WF | C35/45 |  | HA_WAN_STB_0,300_xxx | AllplanAttributes - Object Layer Attributes #1, Ausführung: Ortbeton; Object Layer Attributes #1, Reference: HA_WAN_STB_0,300_xxx; Object Layer Attributes #1, Attributset-Objekt: Wand; Pset_ConcreteElementGeneral - Betonüberdeckung: 1
Stb.-Rahmen | EG_Produktion_FFB | Stahlbeton 0.3 m | Stb.-Rahmen | WA-STB1\ | 0111HWa0000617741 | WA-STB1\ | Betonarbeiten | Stb.-Rahmen | Stahlbeton | EG_Produktion_FFB | 0111Wa 0000617752 |  |  | Stb.-Rahmen | Stahlbeton | Ortbeton | RA001 und RA002 | true | true | 50 | XC4, XD1, XF2, WF | C35/45 |  | HA_WAN_STB_0,300_xxx | AllplanAttributes - Object Layer Attributes #1, Ausführung: Ortbeton; Object Layer Attributes #1, Reference: HA_WAN_STB_0,300_xxx; Object Layer Attributes #1, Attributset-Objekt: Wand; Pset_ConcreteElementGeneral - Betonüberdeckung: 1
Stb.-Rahmen | EG_Produktion_FFB | Stahlbeton 0.3 m | Stb.-Rahmen | WA-STB1\ | 0111HWa0000617692 | WA-STB1\ | Betonarbeiten | Stb.-Rahmen | Stahlbeton | EG_Produktion_FFB | 0111Wa 0000617693 |  |  | Stb.-Rahmen | Stahlbeton | Ortbeton | RA001 und RA002 | true | true | 50 | XC4, XD1, XF2, WF | C35/45 |  | HA_WAN_STB_0,300_xxx | AllplanAttributes - Object Layer Attributes #1, Ausführung: Ortbeton; Object Layer Attributes #1, Reference: HA_WAN_STB_0,300_xxx; Object Layer Attributes #1, Attributset-Objekt: Wand; Pset_ConcreteElementGeneral - Betonüberdeckung: 1
Stb.-Rahmen | EG_Produktion_FFB | Stahlbeton 0.3 m | Stb.-Rahmen | WA-STB1\ | 0111HWa0000617690 | WA-STB1\ | Betonarbeiten | Stb.-Rahmen | Stahlbeton | EG_Produktion_FFB | 0111Wa 0000617691 |  |  | Stb.-Rahmen | Stahlbeton | Ortbeton | RA001 und RA002 | true | true | 50 | XC4, XD1, XF2, WF | C35/45 |  | HA_WAN_STB_0,300_xxx | AllplanAttributes - Object Layer Attributes #1, Ausführung: Ortbeton; Object Layer Attributes #1, Reference: HA_WAN_STB_0,300_xxx; Object Layer Attributes #1, Attributset-Objekt: Wand; Pset_ConcreteElementGeneral - Betonüberdeckung: 1
Stb.-Rahmen | EG_Produktion_FFB | Stahlbeton 0.3 m | Stb.-Rahmen | WA-STB1\ | 0111HWa0000618274 | WA-STB1\ | Betonarbeiten | Stb.-Rahmen | Stahlbeton | EG_Produktion_FFB | 0111Wa 0000618276 |  |  | Stb.-Rahmen | Stahlbeton | Ortbeton | RA001 und RA002 | true | true | 50 | XC4, XD1, XF2, WF | C35/45 |  | HA_WAN_STB_0,300_xxx | AllplanAttributes - Object Layer Attributes #1, Ausführung: Ortbeton; Object Layer Attributes #1, Reference: HA_WAN_STB_0,300_xxx; Object Layer Attributes #1, Attributset-Objekt: Wand; Pset_ConcreteElementGeneral - Betonüberdeckung: 1
Stb.-Rahmen | EG_Produktion_FFB | Stahlbeton 0.3 m | Stb.-Rahmen | WA-STB1\ | 0111HWa0000617688 | WA-STB1\ | Betonarbeiten | Stb.-Rahmen | Stahlbeton | EG_Produktion_FFB | 0111Wa 0000617689 |  |  | Stb.-Rahmen | Stahlbeton | Ortbeton | RA001 und RA002 | true | true | 50 | XC4, XD1, XF2, WF | C35/45 |  | HA_WAN_STB_0,300_xxx | AllplanAttributes - Object Layer Attributes #1, Ausführung: Ortbeton; Object Layer Attributes #1, Reference: HA_WAN_STB_0,300_xxx; Object Layer Attributes #1, Attributset-Objekt: Wand; Pset_ConcreteElementGeneral - Betonüberdeckung: 1
Stb.-Rahmen | EG_Produktion_FFB | Stahlbeton 0.3 m | Stb.-Rahmen | WA-STB1\ | 0111HWa0000617686 | WA-STB1\ | Betonarbeiten | Stb.-Rahmen | Stahlbeton | EG_Produktion_FFB | 0111Wa 0000617687 |  |  | Stb.-Rahmen | Stahlbeton | Ortbeton | RA001 und RA002 | true | true | 50 | XC4, XD1, XF2, WF | C35/45 |  | HA_WAN_STB_0,300_xxx | AllplanAttributes - Object Layer Attributes #1, Ausführung: Ortbeton; Object Layer Attributes #1, Reference: HA_WAN_STB_0,300_xxx; Object Layer Attributes #1, Attributset-Objekt: Wand; Pset_ConcreteElementGeneral - Betonüberdeckung: 1
Stb.-Rahmen | EG_Produktion_FFB | Stahlbeton 0.3 m | Stb.-Rahmen | WA-STB1\ | 0111HWa0000617146 | WA-STB1\ | Betonarbeiten | Stb.-Rahmen | Stahlbeton | EG_Produktion_FFB | 0111Wa 0000617157 |  |  | Stb.-Rahmen | Stahlbeton | Ortbeton | RA001 und RA002 | true | true | 50 | XC4, XD1, XF2, WF | C35/45 |  | HA_WAN_STB_0,300_xxx | AllplanAttributes - Object Layer Attributes #1, Ausführung: Ortbeton; Object Layer Attributes #1, Reference: HA_WAN_STB_0,300_xxx; Object Layer Attributes #1, Attributset-Objekt: Wand; Pset_ConcreteElementGeneral - Betonüberdeckung: 1
Stb.-Rahmen | EG_Produktion_FFB | Stahlbeton 0.3 m | Stb.-Rahmen | WA-STB1\ | 0111HWa0000617153 | WA-STB1\ | Betonarbeiten | Stb.-Rahmen | Stahlbeton | EG_Produktion_FFB | 0111Wa 0000617155 |  |  | Stb.-Rahmen | Stahlbeton | Ortbeton | RA001 und RA002 | true | true | 50 | XC4, XD1, XF2, WF | C35/45 |  | HA_WAN_STB_0,300_xxx | AllplanAttributes - Object Layer Attributes #1, Ausführung: Ortbeton; Object Layer Attributes #1, Reference: HA_WAN_STB_0,300_xxx; Object Layer Attributes #1, Attributset-Objekt: Wand; Pset_ConcreteElementGeneral - Betonüberdeckung: 1
Stb.-Rahmen | EG_Produktion_FFB | Stahlbeton 0.3 m | Stb.-Rahmen | WA-STB1\ | 0111HWa0000618287 | WA-STB1\ | Betonarbeiten | Stb.-Rahmen | Stahlbeton | EG_Produktion_FFB | 0111Wa 0000618289 |  |  | Stb.-Rahmen | Stahlbeton | Ortbeton | RA001 und RA002 | true | true | 50 | XC4, XD1, XF2, WF | C35/45 |  | HA_WAN_STB_0,300_xxx | AllplanAttributes - Object Layer Attributes #1, Ausführung: Ortbeton; Object Layer Attributes #1, Reference: HA_WAN_STB_0,300_xxx; Object Layer Attributes #1, Attributset-Objekt: Wand; Pset_ConcreteElementGeneral - Betonüberdeckung: 1
Stb.-Rahmen | EG_Produktion_FFB | Stahlbeton 0.3 m | Stb.-Rahmen | WA-STB1\ | 0111HWa0000617158 | WA-STB1\ | Betonarbeiten | Stb.-Rahmen | Stahlbeton | EG_Produktion_FFB | 0111Wa 0000617160 |  |  | Stb.-Rahmen | Stahlbeton | Ortbeton | RA001 und RA002 | true | true | 50 | XC4, XD1, XF2, WF | C35/45 |  | HA_WAN_STB_0,300_xxx | AllplanAttributes - Object Layer Attributes #1, Ausführung: Ortbeton; Object Layer Attributes #1, Reference: HA_WAN_STB_0,300_xxx; Object Layer Attributes #1, Attributset-Objekt: Wand; Pset_ConcreteElementGeneral - Betonüberdeckung: 1
Stb.-Rahmen | EG_Produktion_FFB | Stahlbeton 0.3 m | Stb.-Rahmen | WA-STB1\ | 0111HWa0000617145 | WA-STB1\ | Betonarbeiten | Stb.-Rahmen | Stahlbeton | EG_Produktion_FFB | 0111Wa 0000617161 |  |  | Stb.-Rahmen | Stahlbeton | Ortbeton | RA001 und RA002 | true | true | 50 | XC4, XD1, XF2, WF | C35/45 |  | HA_WAN_STB_0,300_xxx | AllplanAttributes - Object Layer Attributes #1, Ausführung: Ortbeton; Object Layer Attributes #1, Reference: HA_WAN_STB_0,300_xxx; Object Layer Attributes #1, Attributset-Objekt: Wand; Pset_ConcreteElementGeneral - Betonüberdeckung: 1
Stb.-Rahmen | EG_Produktion_FFB | Stahlbeton 0.3 m | Stb.-Rahmen | WA-STB1\ | 0111HWa0000617170 | WA-STB1\ | Betonarbeiten | Stb.-Rahmen | Stahlbeton | EG_Produktion_FFB | 0111Wa 0000617181 |  |  | Stb.-Rahmen | Stahlbeton | Ortbeton | RA001 und RA002 | true | true | 50 | XC4, XD1, XF2, WF | C35/45 | no | HA_WAN_STB_0,300_xxx | AllplanAttributes - Object Layer Attributes #1, Ausführung: Ortbeton; Object Layer Attributes #1, Reference: HA_WAN_STB_0,300_xxx; Object Layer Attributes #1, Attributset-Objekt: Wand; Pset_ConcreteElementGeneral - Betonüberdeckung: 1
Stb.-Rahmen | EG_Produktion_FFB | Stahlbeton 0.3 m | Stb.-Rahmen | WA-STB1\ | 0111HWa0000617177 | WA-STB1\ | Betonarbeiten | Stb.-Rahmen | Stahlbeton | EG_Produktion_FFB | 0111Wa 0000617179 |  |  | Stb.-Rahmen | Stahlbeton | Ortbeton | RA001 und RA002 | true | true | 50 | XC4, XD1, XF2, WF | C35/45 | no | HA_WAN_STB_0,300_xxx | AllplanAttributes - Object Layer Attributes #1, Ausführung: Ortbeton; Object Layer Attributes #1, Reference: HA_WAN_STB_0,300_xxx; Object Layer Attributes #1, Attributset-Objekt: Wand; Pset_ConcreteElementGeneral - Betonüberdeckung: 1
Stb.-Rahmen | EG_Produktion_FFB | Stahlbeton 0.3 m | Stb.-Rahmen | WA-STB1\ | 0111HWa0000618300 | WA-STB1\ | Betonarbeiten | Stb.-Rahmen | Stahlbeton | EG_Produktion_FFB | 0111Wa 0000618302 |  |  | Stb.-Rahmen | Stahlbeton | Ortbeton | RA001 und RA002 | true | true | 50 | XC4, XD1, XF2, WF | C35/45 | no | HA_WAN_STB_0,300_xxx | AllplanAttributes - Object Layer Attributes #1, Ausführung: Ortbeton; Object Layer Attributes #1, Reference: HA_WAN_STB_0,300_xxx; Object Layer Attributes #1, Attributset-Objekt: Wand; Pset_ConcreteElementGeneral - Betonüberdeckung: 1
Stb.-Rahmen | EG_Produktion_FFB | Stahlbeton 0.3 m | Stb.-Rahmen | WA-STB1\ | 0111HWa0000617182 | WA-STB1\ | Betonarbeiten | Stb.-Rahmen | Stahlbeton | EG_Produktion_FFB | 0111Wa 0000617184 |  |  | Stb.-Rahmen | Stahlbeton | Ortbeton | RA001 und RA002 | true | true | 50 | XC4, XD1, XF2, WF | C35/45 | no | HA_WAN_STB_0,300_xxx | AllplanAttributes - Object Layer Attributes #1, Ausführung: Ortbeton; Object Layer Attributes #1, Reference: HA_WAN_STB_0,300_xxx; Object Layer Attributes #1, Attributset-Objekt: Wand; Pset_ConcreteElementGeneral - Betonüberdeckung: 1
Stb.-Rahmen | EG_Produktion_FFB | Stahlbeton 0.3 m | Stb.-Rahmen | WA-STB1\ | 0111HWa0000617169 | WA-STB1\ | Betonarbeiten | Stb.-Rahmen | Stahlbeton | EG_Produktion_FFB | 0111Wa 0000617185 |  |  | Stb.-Rahmen | Stahlbeton | Ortbeton | RA001 und RA002 | true | true | 50 | XC4, XD1, XF2, WF | C35/45 | no | HA_WAN_STB_0,300_xxx | AllplanAttributes - Object Layer Attributes #1, Ausführung: Ortbeton; Object Layer Attributes #1, Reference: HA_WAN_STB_0,300_xxx; Object Layer Attributes #1, Attributset-Objekt: Wand; Pset_ConcreteElementGeneral - Betonüberdeckung: 1
Stb.-Rahmen | EG_Produktion_FFB | Stahlbeton 0.3 m | Stb.-Rahmen | WA-STB1\ | 0111HWa0000617901 | WA-STB1\ | Betonarbeiten | Stb.-Rahmen | Stahlbeton | EG_Produktion_FFB | 0111Wa 0000617904 |  |  | Stb.-Rahmen | Stahlbeton | Ortbeton | RA001 und RA002 | true | true | 50 | XC4, XD1, XF2, WF | C35/45 |  | HA_WAN_STB_0,300_xxx | AllplanAttributes - Object Layer Attributes #1, Ausführung: Ortbeton; Object Layer Attributes #1, Reference: HA_WAN_STB_0,300_xxx; Object Layer Attributes #1, Attributset-Objekt: Wand; Pset_ConcreteElementGeneral - Betonüberdeckung: 1
Stb.-Rahmen | EG_Produktion_FFB | Stahlbeton 0.3 m | Stb.-Rahmen | WA-STB1\ | 0111HWa0000617896 | WA-STB1\ | Betonarbeiten | Stb.-Rahmen | Stahlbeton | EG_Produktion_FFB | 0111Wa 0000617905 |  |  | Stb.-Rahmen | Stahlbeton | Ortbeton | RA001 und RA002 | true | true | 50 | XC4, XD1, XF2, WF | C35/45 |  | HA_WAN_STB_0,300_xxx | AllplanAttributes - Object Layer Attributes #1, Ausführung: Ortbeton; Object Layer Attributes #1, Reference: HA_WAN_STB_0,300_xxx; Object Layer Attributes #1, Attributset-Objekt: Wand; Pset_ConcreteElementGeneral - Betonüberdeckung: 1
Stb.-Rahmen | EG_Produktion_FFB | Stahlbeton 0.3 m | Stb.-Rahmen | WA-STB1\ | 0111HWa0000617944 | WA-STB1\ | Betonarbeiten | Stb.-Rahmen | Stahlbeton | EG_Produktion_FFB | 0111Wa 0000617945 |  |  | Stb.-Rahmen | Stahlbeton | Ortbeton | RA001 und RA002 | true | true | 50 | XC4, XD1, XF2, WF | C35/45 |  | HA_WAN_STB_0,300_xxx | AllplanAttributes - Object Layer Attributes #1, Ausführung: Ortbeton; Object Layer Attributes #1, Reference: HA_WAN_STB_0,300_xxx; Object Layer Attributes #1, Attributset-Objekt: Wand; Pset_ConcreteElementGeneral - Betonüberdeckung: 1
Stb.-Rahmen | EG_Produktion_FFB | Stahlbeton 0.3 m | Stb.-Rahmen | WA-STB1\ | 0111HWa0000617881 | WA-STB1\ | Betonarbeiten | Stb.-Rahmen | Stahlbeton | EG_Produktion_FFB | 0111Wa 0000617884 |  |  | Stb.-Rahmen | Stahlbeton | Ortbeton | RA001 und RA002 | true | true | 50 | XC4, XD1, XF2, WF | C35/45 |  | HA_WAN_STB_0,300_xxx | AllplanAttributes - Object Layer Attributes #1, Ausführung: Ortbeton; Object Layer Attributes #1, Reference: HA_WAN_STB_0,300_xxx; Object Layer Attributes #1, Attributset-Objekt: Wand; Pset_ConcreteElementGeneral - Betonüberdeckung: 1
Stb.-Rahmen | EG_Produktion_FFB | Stahlbeton 0.3 m | Stb.-Rahmen | WA-STB1\ | 0111HWa0000617876 | WA-STB1\ | Betonarbeiten | Stb.-Rahmen | Stahlbeton | EG_Produktion_FFB | 0111Wa 0000617885 |  |  | Stb.-Rahmen | Stahlbeton | Ortbeton | RA001 und RA002 | true | true | 50 | XC4, XD1, XF2, WF | C35/45 |  | HA_WAN_STB_0,300_xxx | AllplanAttributes - Object Layer Attributes #1, Ausführung: Ortbeton; Object Layer Attributes #1, Reference: HA_WAN_STB_0,300_xxx; Object Layer Attributes #1, Attributset-Objekt: Wand; Pset_ConcreteElementGeneral - Betonüberdeckung: 1
Stb.-Rahmen | EG_Produktion_FFB | Stahlbeton 0.3 m | Stb.-Rahmen | WA-STB1\ | 0111HWa0000617981 | WA-STB1\ | Betonarbeiten | Stb.-Rahmen | Stahlbeton | EG_Produktion_FFB | 0111Wa 0000617982 |  |  | Stb.-Rahmen | Stahlbeton | Ortbeton | RA001 und RA002 | true | true | 50 | XC4, XD1, XF2, WF | C35/45 |  | HA_WAN_STB_0,300_xxx | AllplanAttributes - Object Layer Attributes #1, Ausführung: Ortbeton; Object Layer Attributes #1, Reference: HA_WAN_STB_0,300_xxx; Object Layer Attributes #1, Attributset-Objekt: Wand; Pset_ConcreteElementGeneral - Betonüberdeckung: 1
Stb.-Rahmen | EG_Produktion_FFB | Stahlbeton 0.3 m | Stb.-Rahmen | WA-STB1\ | 0111HWa0000617841 | WA-STB1\ | Betonarbeiten | Stb.-Rahmen | Stahlbeton | EG_Produktion_FFB | 0111Wa 0000617848 |  |  | Stb.-Rahmen | Stahlbeton | Ortbeton | RA001 und RA002 | true | true | 50 | XC4, XD1, XF2, WF | C35/45 |  | HA_WAN_STB_0,300_xxx | AllplanAttributes - Object Layer Attributes #1, Ausführung: Ortbeton; Object Layer Attributes #1, Reference: HA_WAN_STB_0,300_xxx; Object Layer Attributes #1, Attributset-Objekt: Wand; Pset_ConcreteElementGeneral - Betonüberdeckung: 1
Stb.-Rahmen | EG_Produktion_FFB | Stahlbeton 0.3 m | Stb.-Rahmen | WA-STB1\ | 0111HWa0000617836 | WA-STB1\ | Betonarbeiten | Stb.-Rahmen | Stahlbeton | EG_Produktion_FFB | 0111Wa 0000617847 |  |  | Stb.-Rahmen | Stahlbeton | Ortbeton | RA001 und RA002 | true | true | 50 | XC4, XD1, XF2, WF | C35/45 |  | HA_WAN_STB_0,300_xxx | AllplanAttributes - Object Layer Attributes #1, Ausführung: Ortbeton; Object Layer Attributes #1, Reference: HA_WAN_STB_0,300_xxx; Object Layer Attributes #1, Attributset-Objekt: Wand; Pset_ConcreteElementGeneral - Betonüberdeckung: 1
Stb.-Außenwand | EG_Produktion_FFB | Stahlbeton 0.3 m | Stb.-Außenwand | WA-STB1\ | 0111HWa0000000512 | WA-STB1\ | Betonarbeiten | Stb.-Außenwand | Stahlbeton | EG_Produktion_FFB | 0111Wa 0000000514 |  |  | Stb.-Außenwand | Stahlbeton | Ortbeton | W003 | true | true | 50 | XC4, XD1, XF2, WF | C35/45 |  | HA_WAN_STB_0,300_xxx | AllplanAttributes - Object Layer Attributes #1, Ausführung: Ortbeton; Object Layer Attributes #1, Reference: HA_WAN_STB_0,300_xxx; Object Layer Attributes #1, Attributset-Objekt: Wand; Pset_ConcreteElementGeneral - Betonüberdeckung: 1
Stb.-Rahmen | EG_Produktion_FFB | Stahlbeton 0.3 m | Stb.-Rahmen | WA-STB1\ | 0111HWa0000617745 | WA-STB1\ | Betonarbeiten | Stb.-Rahmen | Stahlbeton | EG_Produktion_FFB | 0111Wa 0000617748 |  |  | Stb.-Rahmen | Stahlbeton | Ortbeton | RA001 und RA002 | true | true | 50 | XC4, XD1, XF2, WF | C35/45 |  | HA_WAN_STB_0,300_xxx | AllplanAttributes - Object Layer Attributes #1, Ausführung: Ortbeton; Object Layer Attributes #1, Reference: HA_WAN_STB_0,300_xxx; Object Layer Attributes #1, Attributset-Objekt: Wand; Pset_ConcreteElementGeneral - Betonüberdeckung: 1
Stb.-Rahmen | EG_Produktion_FFB | Stahlbeton 0.3 m | Stb.-Rahmen | WA-STB1\ | 0111HWa0000617740 | WA-STB1\ | Betonarbeiten | Stb.-Rahmen | Stahlbeton | EG_Produktion_FFB | 0111Wa 0000617753 |  |  | Stb.-Rahmen | Stahlbeton | Ortbeton | RA001 und RA002 | true | true | 50 | XC4, XD1, XF2, WF | C35/45 |  | HA_WAN_STB_0,300_xxx | AllplanAttributes - Object Layer Attributes #1, Ausführung: Ortbeton; Object Layer Attributes #1, Reference: HA_WAN_STB_0,300_xxx; Object Layer Attributes #1, Attributset-Objekt: Wand; Pset_ConcreteElementGeneral - Betonüberdeckung: 1
Stb.-Rahmen | EG_Produktion_FFB | Stahlbeton 0.348467 m | Stb.-Rahmen | WA-STB1\ | 0111HWa0000617694 | WA-STB1\ | Betonarbeiten | Stb.-Rahmen | Stahlbeton | EG_Produktion_FFB | 0111Wa 0000617695 |  |  | Stb.-Rahmen | Stahlbeton | Ortbeton | RA001 und RA002 | true | true | 50 | XC4, XD1, XF2, WF | C35/45 |  | HA_WAN_STB_0,300_xxx | AllplanAttributes - Object Layer Attributes #1, Ausführung: Ortbeton; Object Layer Attributes #1, Reference: HA_WAN_STB_0,300_xxx; Object Layer Attributes #1, Attributset-Objekt: Wand; Pset_ConcreteElementGeneral - Betonüberdeckung: 1
Stb.-Rahmen | EG_Produktion_FFB | Stahlbeton 0.3 m | Stb.-Rahmen | WA-STB1\ | 0111HWa0000617684 | WA-STB1\ | Betonarbeiten | Stb.-Rahmen | Stahlbeton | EG_Produktion_FFB | 0111Wa 0000617685 |  |  | Stb.-Rahmen | Stahlbeton | Ortbeton | RA001 und RA002 | true | true | 50 | XC4, XD1, XF2, WF | C35/45 |  | HA_WAN_STB_0,300_xxx | AllplanAttributes - Object Layer Attributes #1, Ausführung: Ortbeton; Object Layer Attributes #1, Reference: HA_WAN_STB_0,300_xxx; Object Layer Attributes #1, Attributset-Objekt: Wand; Pset_ConcreteElementGeneral - Betonüberdeckung: 1
Stb.-Rahmen | EG_Produktion_FFB | Stahlbeton 0.3 m | Stb.-Rahmen | WA-STB1\ | 0111HWa0000617140 | WA-STB1\ | Betonarbeiten | Stb.-Rahmen | Stahlbeton | EG_Produktion_FFB | 0111Wa 0000617149 |  |  | Stb.-Rahmen | Stahlbeton | Ortbeton | RA001 und RA002 | true | true | 50 | XC4, XD1, XF2, WF | C35/45 |  | HA_WAN_STB_0,300_xxx | AllplanAttributes - Object Layer Attributes #1, Ausführung: Ortbeton; Object Layer Attributes #1, Reference: HA_WAN_STB_0,300_xxx; Object Layer Attributes #1, Attributset-Objekt: Wand; Pset_ConcreteElementGeneral - Betonüberdeckung: 1
Stb.-Rahmen | EG_Produktion_FFB | Stahlbeton 0.3 m | Stb.-Rahmen | WA-STB1\ | 0111HWa0000617141 | WA-STB1\ | Betonarbeiten | Stb.-Rahmen | Stahlbeton | EG_Produktion_FFB | 0111Wa 0000617152 |  |  | Stb.-Rahmen | Stahlbeton | Ortbeton | RA001 und RA002 | true | true | 50 | XC4, XD1, XF2, WF | C35/45 |  | HA_WAN_STB_0,300_xxx | AllplanAttributes - Object Layer Attributes #1, Ausführung: Ortbeton; Object Layer Attributes #1, Reference: HA_WAN_STB_0,300_xxx; Object Layer Attributes #1, Attributset-Objekt: Wand; Pset_ConcreteElementGeneral - Betonüberdeckung: 1
Stb.-Rahmen | EG_Produktion_FFB | Stahlbeton 0.3 m | Stb.-Rahmen | WA-STB1\ | 0111HWa0000000494 | WA-STB1\ | Betonarbeiten | Stb.-Rahmen | Stahlbeton | EG_Produktion_FFB | 0111Wa 0000000496 |  |  | Stb.-Außenwand | Stahlbeton | Ortbeton | RA001 und RA002 | true | true | 50 | XC4, XD1, XF2, WF | C35/45 |  | HA_WAN_STB_0,300_xxx | AllplanAttributes - Object Layer Attributes #1, Ausführung: Ortbeton; Object Layer Attributes #1, Reference: HA_WAN_STB_0,300_xxx; Object Layer Attributes #1, Attributset-Objekt: Wand; Pset_ConcreteElementGeneral - Betonüberdeckung: 1
Stb.-Rahmen | EG_Produktion_FFB | Stahlbeton 0.3 m | Stb.-Rahmen | WA-STB1\ | 0111HWa0000617164 | WA-STB1\ | Betonarbeiten | Stb.-Rahmen | Stahlbeton | EG_Produktion_FFB | 0111Wa 0000617173 |  |  | Stb.-Rahmen | Stahlbeton | Ortbeton | RA001 und RA002 | true | true | 50 | XC4, XD1, XF2, WF | C35/45 | no | HA_WAN_STB_0,300_xxx | AllplanAttributes - Object Layer Attributes #1, Ausführung: Ortbeton; Object Layer Attributes #1, Reference: HA_WAN_STB_0,300_xxx; Object Layer Attributes #1, Attributset-Objekt: Wand; Pset_ConcreteElementGeneral - Betonüberdeckung: 1
Stb.-Rahmen | EG_Produktion_FFB | Stahlbeton 0.3 m | Stb.-Rahmen | WA-STB1\ | 0111HWa0000617165 | WA-STB1\ | Betonarbeiten | Stb.-Rahmen | Stahlbeton | EG_Produktion_FFB | 0111Wa 0000617176 |  |  | Stb.-Rahmen | Stahlbeton | Ortbeton | RA001 und RA002 | true | true | 50 | XC4, XD1, XF2, WF | C35/45 | no | HA_WAN_STB_0,300_xxx | AllplanAttributes - Object Layer Attributes #1, Ausführung: Ortbeton; Object Layer Attributes #1, Reference: HA_WAN_STB_0,300_xxx; Object Layer Attributes #1, Attributset-Objekt: Wand; Pset_ConcreteElementGeneral - Betonüberdeckung: 1
Stb.-Außenwand | EG_Produktion_FFB | Stahlbeton 0.3 m | Stb.-Außenwand | WA-STB1\ | 0111HWa0000000474 | WA-STB1\ | Betonarbeiten | Stb.-Außenwand | Stahlbeton | EG_Produktion_FFB | 0111Wa 0000000476 |  |  | Stb.-Außenwand | Stahlbeton | Ortbeton | W003 | true | true | 50 | XC4, XD1, XF2, WF | C35/45 |  | HA_WAN_STB_0,300_xxx | AllplanAttributes - Object Layer Attributes #1, Ausführung: Ortbeton; Object Layer Attributes #1, Reference: HA_WAN_STB_0,300_xxx; Object Layer Attributes #1, Attributset-Objekt: Wand; Pset_ConcreteElementGeneral - Betonüberdeckung: 1
Stb.-Außenwand | EG_Produktion_FFB | Stahlbeton 0.3 m | Stb.-Außenwand | WA-STB1\ | 0111HWa0000000485 | WA-STB1\ | Betonarbeiten | Stb.-Außenwand | Stahlbeton | EG_Produktion_FFB | 0111Wa 0000000487 |  |  | Stb.-Außenwand | Stahlbeton | Ortbeton | W003 | true | true | 50 | XC4, XD1, XF2, WF | C35/45 |  | HA_WAN_STB_0,300_xxx | AllplanAttributes - Object Layer Attributes #1, Ausführung: Ortbeton; Object Layer Attributes #1, Reference: HA_WAN_STB_0,300_xxx; Object Layer Attributes #1, Attributset-Objekt: Wand; Pset_ConcreteElementGeneral - Betonüberdeckung: 1
Stb.-Außenwand | EG_Produktion_FFB | Stahlbeton 0.3 m | Stb.-Außenwand | WA-STB1\ | 0111HWa0000620716 | WA-STB1\ | Betonarbeiten | Stb.-Außenwand | Stahlbeton | EG_Produktion_FFB | 0111Wa 0000620741 |  |  | Stb.-Außenwand | Stahlbeton | Ortbeton | W003 | true | true | 50 | XC4, XD1, XF2, WF | C35/45 |  | HA_WAN_STB_0,300_xxx | AllplanAttributes - Object Layer Attributes #1, Ausführung: Ortbeton; Object Layer Attributes #1, Reference: HA_WAN_STB_0,300_xxx; Object Layer Attributes #1, Attributset-Objekt: Wand; Pset_ConcreteElementGeneral - Betonüberdeckung: 1
Stb.-Rahmen | EG_Produktion_FFB | Stahlbeton 0.3 m | Stb.-Rahmen | WA-STB1\ | 0111HWa0000000503 | WA-STB1\ | Betonarbeiten | Stb.-Rahmen | Stahlbeton | EG_Produktion_FFB | 0111Wa 0000000505 |  |  | Stb.-Rahmen | Stahlbeton | Ortbeton | RA001.1 und RA002.1 | true | true | 50 | XC4, XD1, XF2, WF | C35/45 |  | HA_WAN_STB_0,300_xxx | AllplanAttributes - Object Layer Attributes #1, Ausführung: Ortbeton; Object Layer Attributes #1, Reference: HA_WAN_STB_0,300_xxx; Object Layer Attributes #1, Attributset-Objekt: Wand; Pset_ConcreteElementGeneral - Betonüberdeckung: 1
Mauerwerkswand | EG_Produktion_FFB | KS-XL-16-1.8/DM 0.24 m | Mauerwerkswand | WI-ZIEGEL2\ | 0111HWa0000619322 | WI-KALKSAND2\ | Mauerarbeiten | Mauerwerkswand | KS-XL-16-1.8/DM | EG_Produktion_FFB | 0111Wa 0000619323 | no | HA_WAN_MWK_0,240_xxx | Mauerwerkswand | Mauerwerk | Mauerwerk | W002 | false | true | 0 | - | - | no | HA_WAN_MWK_0,240_xxx | Pset_ConcreteElementGeneral - Betonüberdeckung: 1
Mauerwerkswand | EG_Produktion_FFB | KS-XL-16-1.8/DM 0.24 m | Mauerwerkswand | WI-ZIEGEL2\ | 0111HWa0000619303 | WI-KALKSAND2\ | Mauerarbeiten | Mauerwerkswand | KS-XL-16-1.8/DM | EG_Produktion_FFB | 0111Wa 0000619304 | no | HA_WAN_MWK_0,240_xxx | Mauerwerkswand | Mauerwerk | Mauerwerk | W002 | false | true | 0 | - | - | no | HA_WAN_MWK_0,240_xxx | Pset_ConcreteElementGeneral - Betonüberdeckung: 1
